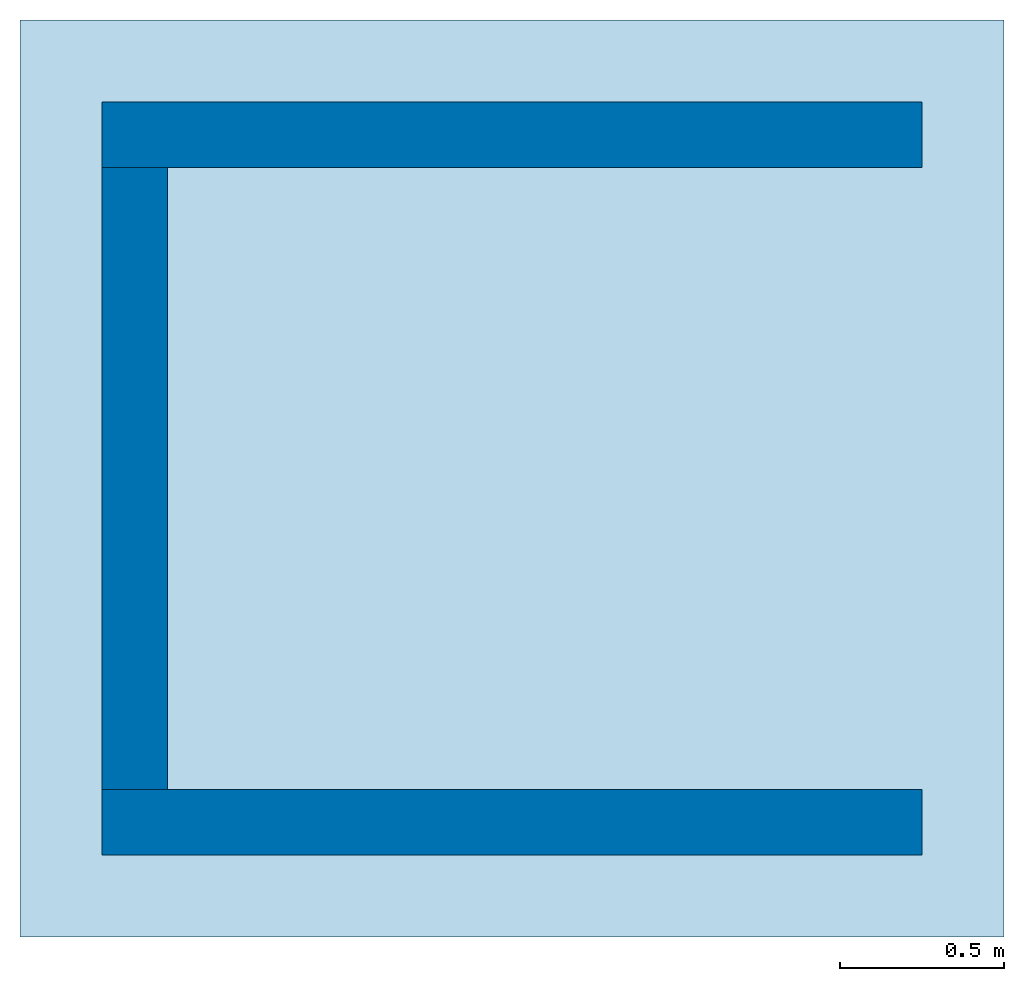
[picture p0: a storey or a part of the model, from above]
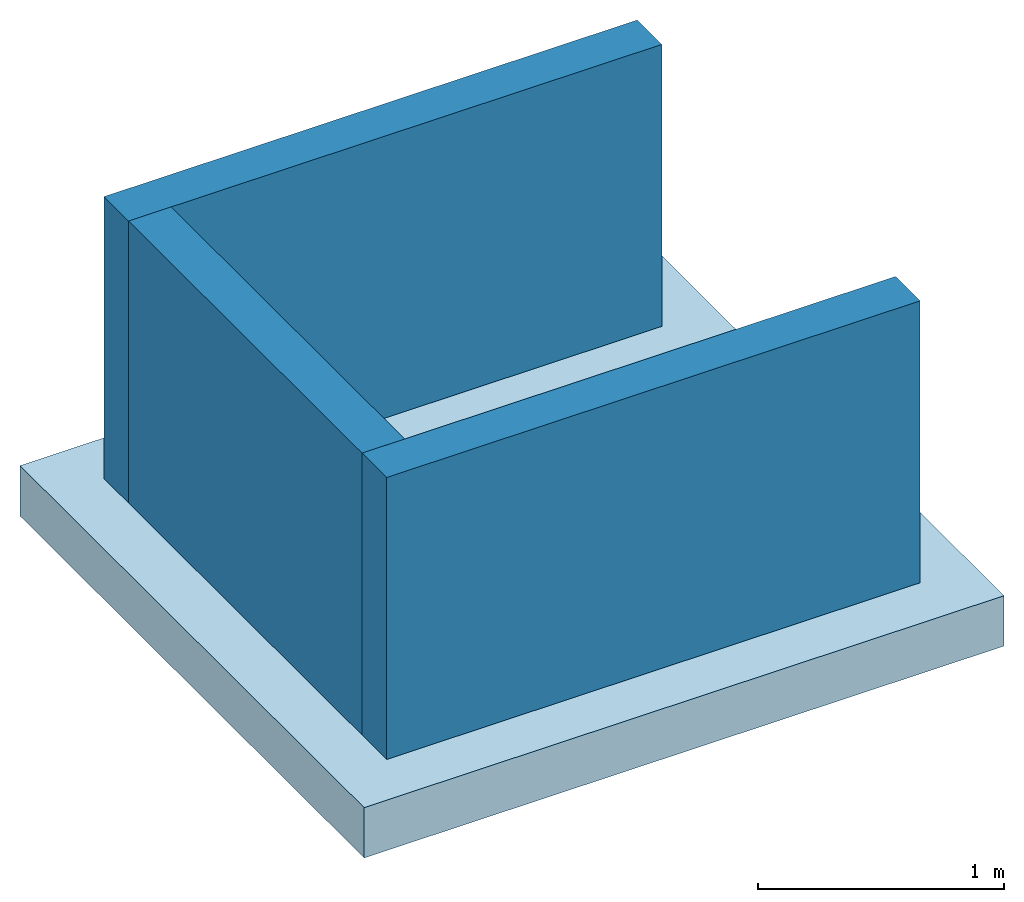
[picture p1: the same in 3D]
Properties of the parts of a building model (IFC4X3_ADD2), part 1 of 28

# File
Description: ViewDefinition [CoordinationView_V2.0], ExchangeRequirement [Architecture], Option [IfcExportBaseQuantities: Off], Option [IfcExportElementOnOffAndFrozenLayers: On], Option [IfcExplodeExternalReferences: Off], Option [IfcTesselateBSplineCurvesAndSurfaces: Off], Option [IfcExportSweptSolidAsBRep: Off], Option [IfcExportProfileCenterOfGravity: Off], Option [IfcExportMultiPlyElementsAsAggregated: Off], Option [IfcExportTesselation: 0.000000], Option [IfcCreateUniqueGuidForBlocks: On], Option [IfcCreateUniqueGuidForXrefs: On], Option [IfcExportSubtractOpenings: Off], Option [IfcExportAllVisibilityStates: Off]
File name: C:\\Users\\info\\Documents\\00 Elearning geodata BIMform\\1.2 Coördinatensystemen en projecties\\1.2.2 Georeferentie in IFC modellen\\AB_AR_BIM_Architectuur_georeferenced-IFC4X3_subset.ifc
Time: 2026-02-23T21:04:36
Author: Undefined
Organization: Undefined
Written by: BricsCAD BIM 26.1.08
Made in: BricsCAD BIM 26.1.08
Authorization: Undefined

# IfcSite, Site
RefLatitude: 42, 24, 53, 508910; RefLongitude: -71, -15, -29, -58837; RefElevation: 0 mm

# IfcBuilding, IFC Building Story
ElevationOfRefHeight: 0 mm; ElevationOfTerrain: 0 mm

# IfcBuildingStorey (10)
In: IFC Building Story
Name | LongName | Elevation (mm)
TAW50 | TAW50 | -10260
K20 | K20 | -5940
K10 | K10 | -3240
000 | 000 | 0
010 | 010 | 3600
020 | 020 | 7200
030 | 030 | 10800
040 | 040 | 14400
050 | 050 | 17050
060 | 060 | 21600

# IfcAirTerminal: BB_07.14.11#01_Buitenrooster_GMO:1000 x 2200 mm, BB_07.14.11#01_Buitenrooster_GMO:1000 x 2200 mm:28366141
In: K10
PredefinedType: GRILLE
Cpset_AirTerminal - LevelOfAccuracy: in te vullen door Buildwise
IfcBuildingStorey - Level: K10; Elevation from Level: 50
IfcClassificationReference - Keynote: 07.14.11#01; GVH_artnr 01: 07.14.11#01; GVH_artnr 02: geen waarde gevonden; GVH_artnr 03: geen waarde gevonden; GVH_artnr 04: geen waarde gevonden; GVH_artnr 05: geen waarde gevonden; GVH_artnr 06: geen waarde gevonden; TDS_link: .\05 As Builtdossier\2. Bouwkunde\2.1 Architectuur\2.1.7 Gevelsluiting\2.1.7.3 Gevelbekleding (MSB)\2.1.7.3.2 technische fiche's\TF A 07.14.11 01 gevelrooster 50 (B).pdf
IfcElement - Tag: R K.-1.P2 / 01; BB_Element_Lokaalnummer01: K.-1.P2 / 01; BB_Element_Code01: R K.-1.P2 / 01
IfcRoot - Name: 1000 x 2200 mm
Pset_AirTerminalTypeCommon - Reference: 1000 x 2200 mm; sets with these values: 2
Pset_Condition - AssessmentDate: Empty; AssessmentCondition: Empty

# IfcAirTerminal: BB_07.14.11#01_Buitenrooster_GMO:1030 x 840 mm, BB_07.14.11#01_Buitenrooster_GMO:1030 x 840 mm:25776233
In: 040
PredefinedType: GRILLE
Cpset_AirTerminal - LevelOfAccuracy: in te vullen door Buildwise
IfcBuildingStorey - Level: 040; Elevation from Level: 1560
IfcClassificationReference - Keynote: 07.14.11#01; GVH_artnr 01: 07.14.11#01; GVH_artnr 02: geen waarde gevonden; GVH_artnr 03: geen waarde gevonden; GVH_artnr 04: geen waarde gevonden; GVH_artnr 05: geen waarde gevonden; GVH_artnr 06: geen waarde gevonden; TDS_link: .\05 As Builtdossier\2. Bouwkunde\2.1 Architectuur\2.1.7 Gevelsluiting\2.1.7.3 Gevelbekleding (MSB)\2.1.7.3.2 technische fiche's\TF A 07.14.11 01 gevelrooster 50 (B).pdf
IfcElement - Tag: R K.40.G11 / 02; BB_Element_Lokaalnummer01: K.40.G11; BB_Element_Code01: R K.40.G11 / 02
IfcRoot - Name: 1030 x 840 mm
Pset_AirTerminalTypeCommon - Reference: 1030 x 840 mm; sets with these values: 2
Pset_Condition - AssessmentDate: Empty; AssessmentCondition: Empty

# IfcAirTerminal: BB_07.14.11#01_Buitenrooster_GMO:1200 x 600 mm, BB_07.14.11#01_Buitenrooster_GMO:1200 x 600 mm:25777901
In: K10
PredefinedType: GRILLE
Cpset_AirTerminal - LevelOfAccuracy: in te vullen door Buildwise
IfcBuildingStorey - Level: K10; Elevation from Level: 1650
IfcClassificationReference - Keynote: 07.14.11#01; GVH_artnr 01: 07.14.11#01; GVH_artnr 02: geen waarde gevonden; GVH_artnr 03: geen waarde gevonden; GVH_artnr 04: geen waarde gevonden; GVH_artnr 05: geen waarde gevonden; GVH_artnr 06: geen waarde gevonden; TDS_link: .\05 As Builtdossier\2. Bouwkunde\2.1 Architectuur\2.1.7 Gevelsluiting\2.1.7.3 Gevelbekleding (MSB)\2.1.7.3.2 technische fiche's\TF A 07.14.11 01 gevelrooster 50 (B).pdf
IfcElement - Tag: R K.-1.310 / 01; BB_Element_Lokaalnummer01: K.-1.310; BB_Element_Code01: R K.-1.310 / 01
IfcRoot - Name: 1200 x 600 mm
Pset_AirTerminalTypeCommon - Reference: 1200 x 600 mm; sets with these values: 2
Pset_Condition - AssessmentDate: Empty; AssessmentCondition: Empty

# IfcAirTerminal: BB_07.14.11#01_Buitenrooster_GMO:1930 x 1000 mm, BB_07.14.11#01_Buitenrooster_GMO:1930 x 1000 mm:25762259
In: 040
PredefinedType: GRILLE
Cpset_AirTerminal - LevelOfAccuracy: in te vullen door Buildwise
IfcBuildingStorey - Level: 040; Elevation from Level: 360
IfcClassificationReference - Keynote: 07.14.11#01; GVH_artnr 01: 07.14.11#01; GVH_artnr 02: geen waarde gevonden; GVH_artnr 03: geen waarde gevonden; GVH_artnr 04: geen waarde gevonden; GVH_artnr 05: geen waarde gevonden; GVH_artnr 06: geen waarde gevonden; TDS_link: .\05 As Builtdossier\2. Bouwkunde\2.1 Architectuur\2.1.7 Gevelsluiting\2.1.7.3 Gevelbekleding (MSB)\2.1.7.3.2 technische fiche's\TF A 07.14.11 01 gevelrooster 50 (B).pdf
IfcElement - Tag: R K.40.G11 / 01; BB_Element_Lokaalnummer01: K.40.G11; BB_Element_Code01: R K.40.G11 / 01
IfcRoot - Name: 1930 x 1000 mm
Pset_AirTerminalTypeCommon - Reference: 1930 x 1000 mm; sets with these values: 2
Pset_Condition - AssessmentDate: Empty; AssessmentCondition: Empty

# IfcAirTerminal: BB_07.14.11#01_Buitenrooster_GMO:2000 x 800 mm, BB_07.14.11#01_Buitenrooster_GMO:2000 x 800 mm:25777132
In: K20
PredefinedType: GRILLE
Cpset_AirTerminal - LevelOfAccuracy: in te vullen door Buildwise
IfcBuildingStorey - Level: K20; Elevation from Level: 1400
IfcClassificationReference - Keynote: 07.14.11#01; GVH_artnr 01: 07.14.11#01; GVH_artnr 02: geen waarde gevonden; GVH_artnr 03: geen waarde gevonden; GVH_artnr 04: geen waarde gevonden; GVH_artnr 05: geen waarde gevonden; GVH_artnr 06: geen waarde gevonden; TDS_link: .\05 As Builtdossier\2. Bouwkunde\2.1 Architectuur\2.1.7 Gevelsluiting\2.1.7.3 Gevelbekleding (MSB)\2.1.7.3.2 technische fiche's\TF A 07.14.11 01 gevelrooster 50 (B).pdf
IfcElement - Tag: R K.-2.305 / 01; BB_Element_Lokaalnummer01: K.-2.305; BB_Element_Code01: R K.-2.305 / 01
IfcRoot - Name: 2000 x 800 mm
Pset_AirTerminalTypeCommon - Reference: 2000 x 800 mm; sets with these values: 2
Pset_Condition - AssessmentDate: Empty; AssessmentCondition: Empty

# IfcAirTerminal: BB_07.14.11#01_Buitenrooster_GMO:2400 x 1800 mm, BB_07.14.11#01_Buitenrooster_GMO:2400 x 1800 mm:25777399
In: K20
PredefinedType: GRILLE
Cpset_AirTerminal - LevelOfAccuracy: in te vullen door Buildwise
IfcBuildingStorey - Level: K20; Elevation from Level: 300
IfcClassificationReference - Keynote: 07.14.11#02; GVH_artnr 01: 07.14.11#02; GVH_artnr 02: geen waarde gevonden; GVH_artnr 03: geen waarde gevonden; GVH_artnr 04: geen waarde gevonden; GVH_artnr 05: geen waarde gevonden; GVH_artnr 06: geen waarde gevonden; TDS_link: .\05 As Builtdossier\2. Bouwkunde\2.1 Architectuur\2.1.7 Gevelsluiting\2.1.7.3 Gevelbekleding (MSB)\2.1.7.3.2 technische fiche's\TF A 07.14.11 01 gevelrooster 50 (B).pdf
IfcElement - Tag: R K.-2.P2 / 01; BB_Element_Lokaalnummer01: K.-2.P2; BB_Element_Code01: R K.-2.P2 / 01
IfcRoot - Name: 2400 x 1800 mm
Pset_AirTerminalTypeCommon - Reference: 2400 x 1800 mm; sets with these values: 2
Pset_Condition - AssessmentDate: Empty; AssessmentCondition: Empty

# IfcAirTerminal: BB_07.14.11#01_Buitenrooster_GMO:2470 x 1800 mm, BB_07.14.11#01_Buitenrooster_GMO:2470 x 1800 mm:25478532
In: 040
PredefinedType: GRILLE
Cpset_AirTerminal - LevelOfAccuracy: in te vullen door Buildwise
IfcBuildingStorey - Level: 040; Elevation from Level: 360
IfcClassificationReference - Keynote: 07.14.11#01; GVH_artnr 01: 07.14.11#01; GVH_artnr 02: geen waarde gevonden; GVH_artnr 03: geen waarde gevonden; GVH_artnr 04: geen waarde gevonden; GVH_artnr 05: geen waarde gevonden; GVH_artnr 06: geen waarde gevonden; TDS_link: .\05 As Builtdossier\2. Bouwkunde\2.1 Architectuur\2.1.7 Gevelsluiting\2.1.7.3 Gevelbekleding (MSB)\2.1.7.3.2 technische fiche's\TF A 07.14.11 01 gevelrooster 50 (B).pdf
IfcElement - Tag: R K.40.K16 / 01; BB_Element_Lokaalnummer01: K.40.K16; BB_Element_Code01: R K.40.K16 / 01
IfcRoot - Name: 2470 x 1800 mm
Pset_AirTerminalTypeCommon - Reference: 2470 x 1800 mm; sets with these values: 2
Pset_Condition - AssessmentDate: Empty; AssessmentCondition: Empty

# IfcAirTerminal: BB_07.14.11#01_Buitenrooster_GMO:490 x 450 mm, BB_07.14.11#01_Buitenrooster_GMO:490 x 450 mm:25776728
In: 040
PredefinedType: GRILLE
Cpset_AirTerminal - LevelOfAccuracy: in te vullen door Buildwise
IfcBuildingStorey - Level: 040; Elevation from Level: 1950
IfcClassificationReference - Keynote: 07.14.11#01; GVH_artnr 01: 07.14.11#01; GVH_artnr 02: geen waarde gevonden; GVH_artnr 03: geen waarde gevonden; GVH_artnr 04: geen waarde gevonden; GVH_artnr 05: geen waarde gevonden; GVH_artnr 06: geen waarde gevonden; TDS_link: .\05 As Builtdossier\2. Bouwkunde\2.1 Architectuur\2.1.7 Gevelsluiting\2.1.7.3 Gevelbekleding (MSB)\2.1.7.3.2 technische fiche's\TF A 07.14.11 01 gevelrooster 50 (B).pdf
IfcElement - Tag: R K.40.K12 / 01; BB_Element_Lokaalnummer01: K.40.K12; BB_Element_Code01: R K.40.K12 / 01
IfcRoot - Name: 490 x 450 mm
Pset_AirTerminalTypeCommon - Reference: 490 x 450 mm; sets with these values: 2
Pset_Condition - AssessmentDate: Empty; AssessmentCondition: Empty

# IfcAirTerminal: BB_07.14.11#01_Buitenrooster_GMO:670 x 250 mm, BB_07.14.11#01_Buitenrooster_GMO:670 x 250 mm:25778106
In: K10
PredefinedType: GRILLE
Cpset_AirTerminal - LevelOfAccuracy: in te vullen door Buildwise
IfcBuildingStorey - Level: K10; Elevation from Level: 2070
IfcClassificationReference - Keynote: 07.14.11#01; GVH_artnr 01: 07.14.11#01; GVH_artnr 02: geen waarde gevonden; GVH_artnr 03: geen waarde gevonden; GVH_artnr 04: geen waarde gevonden; GVH_artnr 05: geen waarde gevonden; GVH_artnr 06: geen waarde gevonden; TDS_link: .\05 As Builtdossier\2. Bouwkunde\2.1 Architectuur\2.1.7 Gevelsluiting\2.1.7.3 Gevelbekleding (MSB)\2.1.7.3.2 technische fiche's\TF A 07.14.11 01 gevelrooster 50 (B).pdf
IfcElement - Tag: R K.-1.306 / 01; BB_Element_Lokaalnummer01: K.-1.306; BB_Element_Code01: R K.-1.306 / 01
IfcRoot - Name: 670 x 250 mm
Pset_AirTerminalTypeCommon - Reference: 670 x 250 mm; sets with these values: 2
Pset_Condition - AssessmentDate: Empty; AssessmentCondition: Empty

# IfcBeam: 28_SF_hout_rechthoekig_40 x 120, 28_SF_hout_rechthoekig:40 x 120:33609457
In: 010
PredefinedType: BEAM; Material: GVH_i2_naaldhout_generiek
Cpset_Beam - LevelOfAccuracy: in te vullen door Buildwise
IfcClassificationReference - TDS_link: .\05 As Builtdossier\2. Bouwkunde\2.2. Stabiliteit\2.2.0 technische fiche's\TF S 4.9.1.1.1 A - houten roostering sheddak.pdf
IfcElement - Tag: G4; Mark: G4
IfcRoot - Name: 40 x 120
Qto_BeamBaseQuantities - Length: 680; CrossSectionArea: 0.0048; OuterSurfaceArea: 0.308721; GrossSurfaceArea: 0.318321; NetSurfaceArea: 0.318321; GrossVolume: 0.00463081; NetVolume: 0.00463081
Pset_BeamCommon - Reference: 40 x 120; Span: 680 mm; Slope: 0.607081 rad; Roll: 0 rad; IsExternal: no; LoadBearing: yes
Pset_ConcreteElementGeneral - ConstructionMethod: prefabricated
Pset_Condition - AssessmentCondition: Empty
Pset_EnvironmentalImpactIndicators - Reference: 40 x 120; sets with these values: 2

# IfcBeam: 28_SF_hout_rechthoekig_40 x 120_1, 28_SF_hout_rechthoekig:40 x 120:33612034
In: 010
PredefinedType: BEAM; Material: GVH_i2_naaldhout_generiek
Cpset_Beam - LevelOfAccuracy: in te vullen door Buildwise
IfcClassificationReference - TDS_link: .\05 As Builtdossier\2. Bouwkunde\2.2. Stabiliteit\2.2.0 technische fiche's\TF S 4.9.1.1.1 A - houten roostering sheddak.pdf
IfcElement - Tag: G4; Mark: G4
IfcRoot - Name: 40 x 120
Qto_BeamBaseQuantities - Length: 680; CrossSectionArea: 0.0048; OuterSurfaceArea: 0.301717; GrossSurfaceArea: 0.311317; NetSurfaceArea: 0.311317; GrossVolume: 0.00452576; NetVolume: 0.00452576
Pset_BeamCommon - Reference: 40 x 120; Span: 680 mm; Slope: 0.607081 rad; Roll: 0 rad; IsExternal: no; LoadBearing: yes
Pset_ConcreteElementGeneral - ConstructionMethod: prefabricated
Pset_Condition - AssessmentCondition: Empty
Pset_EnvironmentalImpactIndicators - Reference: 40 x 120; sets with these values: 2

# IfcBeam: 28_SF_hout_rechthoekig_40 x 120_3, 28_SF_hout_rechthoekig:40 x 120:33641268
In: 010
PredefinedType: BEAM; Material: GVH_i2_naaldhout_generiek
Cpset_Beam - LevelOfAccuracy: in te vullen door Buildwise
IfcClassificationReference - TDS_link: .\05 As Builtdossier\2. Bouwkunde\2.2. Stabiliteit\2.2.0 technische fiche's\TF S 4.9.1.1.1 A - houten roostering sheddak.pdf
IfcElement - Tag: G8; Mark: G8
IfcRoot - Name: 40 x 120
Qto_BeamBaseQuantities - Length: 674.972; CrossSectionArea: 0.0048; OuterSurfaceArea: 0.273942; GrossSurfaceArea: 0.283542; NetSurfaceArea: 0.283542; GrossVolume: 0.00410913; NetVolume: 0.00410913
Pset_BeamCommon - Reference: 40 x 120; Span: 674.972 mm; Slope: 0.607119 rad; Roll: 0 rad; IsExternal: no; LoadBearing: yes
Pset_ConcreteElementGeneral - ConstructionMethod: prefabricated
Pset_Condition - AssessmentCondition: Empty
Pset_EnvironmentalImpactIndicators - Reference: 40 x 120; sets with these values: 2

# IfcBeam: 28_SF_hout_rechthoekig_40 x 120_5, 28_SF_hout_rechthoekig:40 x 120:33641404
In: 010
PredefinedType: BEAM; Material: GVH_i2_naaldhout_generiek
Cpset_Beam - LevelOfAccuracy: in te vullen door Buildwise
IfcClassificationReference - TDS_link: .\05 As Builtdossier\2. Bouwkunde\2.2. Stabiliteit\2.2.0 technische fiche's\TF S 4.9.1.1.1 A - houten roostering sheddak.pdf
IfcElement - Tag: G8; Mark: G8
IfcRoot - Name: 40 x 120
Qto_BeamBaseQuantities - Length: 680; CrossSectionArea: 0.0048; OuterSurfaceArea: 0.271354; GrossSurfaceArea: 0.280954; NetSurfaceArea: 0.280954; GrossVolume: 0.00407031; NetVolume: 0.00407031
Pset_BeamCommon - Reference: 40 x 120; Span: 680 mm; Slope: 0.607119 rad; Roll: 0 rad; IsExternal: no; LoadBearing: yes
Pset_ConcreteElementGeneral - ConstructionMethod: prefabricated
Pset_Condition - AssessmentCondition: Empty
Pset_EnvironmentalImpactIndicators - Reference: 40 x 120; sets with these values: 2

# IfcBeam: 28_SF_hout_rechthoekig_40 x 120_7, 28_SF_hout_rechthoekig:40 x 120:33649928
In: 010
PredefinedType: BEAM; Material: GVH_i2_naaldhout_generiek
Cpset_Beam - LevelOfAccuracy: in te vullen door Buildwise
IfcClassificationReference - TDS_link: .\05 As Builtdossier\2. Bouwkunde\2.2. Stabiliteit\2.2.0 technische fiche's\TF S 4.9.1.1.1 A - houten roostering sheddak.pdf
IfcElement - Tag: G7; Mark: G7
IfcRoot - Name: 40 x 120
Qto_BeamBaseQuantities - Length: 720; CrossSectionArea: 0.0048; OuterSurfaceArea: 0.260097; GrossSurfaceArea: 0.269697; NetSurfaceArea: 0.269697; GrossVolume: 0.00390145; NetVolume: 0.00390145
Pset_BeamCommon - Reference: 40 x 120; Span: 720 mm; Slope: 0.456876 rad; Roll: 0 rad; IsExternal: no; LoadBearing: yes
Pset_ConcreteElementGeneral - ConstructionMethod: prefabricated
Pset_Condition - AssessmentCondition: Empty
Pset_EnvironmentalImpactIndicators - Reference: 40 x 120; sets with these values: 2

# IfcBeam: 28_SF_hout_rechthoekig_40 x 120_9, 28_SF_hout_rechthoekig:40 x 120:33650153
In: 010
PredefinedType: BEAM; Material: GVH_i2_naaldhout_generiek
Cpset_Beam - LevelOfAccuracy: in te vullen door Buildwise
IfcClassificationReference - TDS_link: .\05 As Builtdossier\2. Bouwkunde\2.2. Stabiliteit\2.2.0 technische fiche's\TF S 4.9.1.1.1 A - houten roostering sheddak.pdf
IfcElement - Tag: G7; Mark: G7
IfcRoot - Name: 40 x 120
Qto_BeamBaseQuantities - Length: 720; CrossSectionArea: 0.0048; OuterSurfaceArea: 0.259196; GrossSurfaceArea: 0.268796; NetSurfaceArea: 0.268796; GrossVolume: 0.00388795; NetVolume: 0.00388795
Pset_BeamCommon - Reference: 40 x 120; Span: 720 mm; Slope: 0.456876 rad; Roll: 0 rad; IsExternal: no; LoadBearing: yes
Pset_ConcreteElementGeneral - ConstructionMethod: prefabricated
Pset_Condition - AssessmentCondition: Empty
Pset_EnvironmentalImpactIndicators - Reference: 40 x 120; sets with these values: 2

# IfcBeam: 28_SF_hout_rechthoekig_40 x 150, 28_SF_hout_rechthoekig:40 x 150:33608699
In: 010
PredefinedType: BEAM; Material: GVH_i2_naaldhout_generiek
Cpset_Beam - LevelOfAccuracy: in te vullen door Buildwise
IfcClassificationReference - TDS_link: .\05 As Builtdossier\2. Bouwkunde\2.2. Stabiliteit\2.2.0 technische fiche's\TF S 4.9.1.1.1 A - houten roostering sheddak.pdf
IfcElement - Tag: G1; Mark: G1
IfcRoot - Name: 40 x 150
Qto_BeamBaseQuantities - Length: 3480; CrossSectionArea: 0.006; OuterSurfaceArea: 0.47082; GrossSurfaceArea: 0.48282; NetSurfaceArea: 0.48282; GrossVolume: 0.007434; NetVolume: 0.007434
Pset_BeamCommon - Reference: 40 x 150; Span: 3480 mm; Slope: 0.459349 rad; Roll: 0 rad; IsExternal: no; LoadBearing: yes
Pset_ConcreteElementGeneral - ConstructionMethod: prefabricated
Pset_Condition - AssessmentCondition: Empty
Pset_EnvironmentalImpactIndicators - Reference: 40 x 150; sets with these values: 2

# IfcBeam: 28_SF_hout_rechthoekig_40 x 150_1, 28_SF_hout_rechthoekig:40 x 150:33611057
In: 010
PredefinedType: BEAM; Material: GVH_i2_naaldhout_generiek
Cpset_Beam - LevelOfAccuracy: in te vullen door Buildwise
IfcClassificationReference - TDS_link: .\05 As Builtdossier\2. Bouwkunde\2.2. Stabiliteit\2.2.0 technische fiche's\TF S 4.9.1.1.1 A - houten roostering sheddak.pdf
IfcElement - Tag: G5; Mark: G5
IfcRoot - Name: 40 x 150
Qto_BeamBaseQuantities - Length: 3480; CrossSectionArea: 0.006; OuterSurfaceArea: 0.434937; GrossSurfaceArea: 0.446937; NetSurfaceArea: 0.446937; GrossVolume: 0.00686743; NetVolume: 0.00686743
Pset_BeamCommon - Reference: 40 x 150; Span: 3480 mm; Slope: 0.459349 rad; Roll: 0 rad; IsExternal: no; LoadBearing: yes
Pset_ConcreteElementGeneral - ConstructionMethod: prefabricated
Pset_Condition - AssessmentCondition: Empty
Pset_EnvironmentalImpactIndicators - Reference: 40 x 150; sets with these values: 2

# IfcBeam: 28_SF_hout_rechthoekig_40 x 150_3, 28_SF_hout_rechthoekig:40 x 150:33611471
In: 010
PredefinedType: BEAM; Material: GVH_i2_naaldhout_generiek
Cpset_Beam - LevelOfAccuracy: in te vullen door Buildwise
IfcClassificationReference - TDS_link: .\05 As Builtdossier\2. Bouwkunde\2.2. Stabiliteit\2.2.0 technische fiche's\TF S 4.9.1.1.1 A - houten roostering sheddak.pdf
IfcElement - Tag: G1; Mark: G1
IfcRoot - Name: 40 x 150
Qto_BeamBaseQuantities - Length: 3480; CrossSectionArea: 0.006; OuterSurfaceArea: 0.442043; GrossSurfaceArea: 0.454043; NetSurfaceArea: 0.454043; GrossVolume: 0.00697963; NetVolume: 0.00697963
Pset_BeamCommon - Reference: 40 x 150; Span: 3480 mm; Slope: 0.459349 rad; Roll: 0 rad; IsExternal: no; LoadBearing: yes
Pset_ConcreteElementGeneral - ConstructionMethod: prefabricated
Pset_Condition - AssessmentCondition: Empty
Pset_EnvironmentalImpactIndicators - Reference: 40 x 150; sets with these values: 2

# IfcBeam: 28_SF_hout_rechthoekig_40 x 150_5, 28_SF_hout_rechthoekig:40 x 150:33611473
In: 010
PredefinedType: BEAM; Material: GVH_i2_naaldhout_generiek
Cpset_Beam - LevelOfAccuracy: in te vullen door Buildwise
IfcClassificationReference - TDS_link: .\05 As Builtdossier\2. Bouwkunde\2.2. Stabiliteit\2.2.0 technische fiche's\TF S 4.9.1.1.1 A - houten roostering sheddak.pdf
IfcElement - Tag: G2; Mark: G2
IfcRoot - Name: 40 x 150
Qto_BeamBaseQuantities - Length: 3480; CrossSectionArea: 0.006; OuterSurfaceArea: 0.398603; GrossSurfaceArea: 0.410603; NetSurfaceArea: 0.410603; GrossVolume: 0.00629374; NetVolume: 0.00629374
Pset_BeamCommon - Reference: 40 x 150; Span: 3480 mm; Slope: 0.459349 rad; Roll: 0 rad; IsExternal: no; LoadBearing: yes
Pset_ConcreteElementGeneral - ConstructionMethod: prefabricated
Pset_Condition - AssessmentCondition: Empty
Pset_EnvironmentalImpactIndicators - Reference: 40 x 150; sets with these values: 2

# IfcBeam: 28_SF_hout_rechthoekig_40 x 150_7, 28_SF_hout_rechthoekig:40 x 150:33611784
In: 010
PredefinedType: BEAM; Material: GVH_i2_naaldhout_generiek
Cpset_Beam - LevelOfAccuracy: in te vullen door Buildwise
IfcClassificationReference - TDS_link: .\05 As Builtdossier\2. Bouwkunde\2.2. Stabiliteit\2.2.0 technische fiche's\TF S 4.9.1.1.1 A - houten roostering sheddak.pdf
IfcElement - Tag: G6; Mark: G6
IfcRoot - Name: 40 x 150
Qto_BeamBaseQuantities - Length: 3340; CrossSectionArea: 0.006; OuterSurfaceArea: 0.465686; GrossSurfaceArea: 0.477686; NetSurfaceArea: 0.477686; GrossVolume: 0.00735294; NetVolume: 0.00735294
Pset_BeamCommon - Reference: 40 x 150; Span: 3340 mm; Slope: 0.496206 rad; Roll: 0 rad; IsExternal: no; LoadBearing: yes
Pset_ConcreteElementGeneral - ConstructionMethod: prefabricated
Pset_Condition - AssessmentCondition: Empty
Pset_EnvironmentalImpactIndicators - Reference: 40 x 150; sets with these values: 2

# IfcBeam: 28_SF_hout_rechthoekig_40 x 150_9, 28_SF_hout_rechthoekig:40 x 150:33612094
In: 010
PredefinedType: BEAM; Material: GVH_i2_naaldhout_generiek
Cpset_Beam - LevelOfAccuracy: in te vullen door Buildwise
IfcClassificationReference - TDS_link: .\05 As Builtdossier\2. Bouwkunde\2.2. Stabiliteit\2.2.0 technische fiche's\TF S 4.9.1.1.1 A - houten roostering sheddak.pdf
IfcElement - Tag: G3; Mark: G3
IfcRoot - Name: 40 x 150
Qto_BeamBaseQuantities - Length: 2128.69; CrossSectionArea: 0.006; OuterSurfaceArea: 0.460107; GrossSurfaceArea: 0.472107; NetSurfaceArea: 0.472107; GrossVolume: 0.00726485; NetVolume: 0.00726485
Pset_BeamCommon - Reference: 40 x 150; Span: 2128.69 mm; Slope: 0.497647 rad; Roll: 0 rad; IsExternal: no; LoadBearing: yes
Pset_ConcreteElementGeneral - ConstructionMethod: prefabricated
Pset_Condition - AssessmentCondition: Empty
Pset_EnvironmentalImpactIndicators - Reference: 40 x 150; sets with these values: 2

# IfcBeam: 28_SF_hout_rechthoekig_40 x 230, 28_SF_hout_rechthoekig:40 x 230:33579203
In: 010
PredefinedType: BEAM; Material: GVH_i2_naaldhout_generiek
Cpset_Beam - LevelOfAccuracy: in te vullen door Buildwise
IfcClassificationReference - TDS_link: .\05 As Builtdossier\2. Bouwkunde\2.2. Stabiliteit\2.2.0 technische fiche's\TF S 4.9.1.1.1 A - houten roostering sheddak.pdf
IfcElement - Tag: B1; Mark: B1
IfcRoot - Name: 40 x 230
Qto_BeamBaseQuantities - Length: 3240; CrossSectionArea: 0.0092; OuterSurfaceArea: 1.79133; GrossSurfaceArea: 1.80973; NetSurfaceArea: 1.80973; GrossVolume: 0.030519; NetVolume: 0.030519
Pset_BeamCommon - Reference: 40 x 230; Span: 3240 mm; Slope: 0 rad; Roll: 0 rad; IsExternal: no; LoadBearing: yes
Pset_ConcreteElementGeneral - ConstructionMethod: prefabricated
Pset_Condition - AssessmentCondition: Empty
Pset_EnvironmentalImpactIndicators - Reference: 40 x 230; sets with these values: 2

# IfcBeam: 28_SF_hout_rechthoekig_40 x 230_1, 28_SF_hout_rechthoekig:40 x 230:33579206
In: 010
PredefinedType: BEAM; Material: GVH_i2_naaldhout_generiek
Cpset_Beam - LevelOfAccuracy: in te vullen door Buildwise
IfcClassificationReference - TDS_link: .\05 As Builtdossier\2. Bouwkunde\2.2. Stabiliteit\2.2.0 technische fiche's\TF S 4.9.1.1.1 A - houten roostering sheddak.pdf
IfcElement - Tag: B1; Mark: B1
IfcRoot - Name: 40 x 230
Qto_BeamBaseQuantities - Length: 3440; CrossSectionArea: 0.0092; OuterSurfaceArea: 1.79133; GrossSurfaceArea: 1.80973; NetSurfaceArea: 1.80973; GrossVolume: 0.030519; NetVolume: 0.030519
Pset_BeamCommon - Reference: 40 x 230; Span: 3440 mm; Slope: 0 rad; Roll: 0 rad; IsExternal: no; LoadBearing: yes
Pset_ConcreteElementGeneral - ConstructionMethod: prefabricated
Pset_Condition - AssessmentCondition: Empty
Pset_EnvironmentalImpactIndicators - Reference: 40 x 230; sets with these values: 2

# IfcBeam: 28_SF_hout_rechthoekig_40 x 230_101, 28_SF_hout_rechthoekig:40 x 230:33579978
In: 010
PredefinedType: BEAM; Material: GVH_i2_naaldhout_generiek
Cpset_Beam - LevelOfAccuracy: in te vullen door Buildwise
IfcClassificationReference - TDS_link: .\05 As Builtdossier\2. Bouwkunde\2.2. Stabiliteit\2.2.0 technische fiche's\TF S 4.9.1.1.1 A - houten roostering sheddak.pdf
IfcElement - Tag: B1; Mark: B1
IfcRoot - Name: 40 x 230
Qto_BeamBaseQuantities - Length: 3340; CrossSectionArea: 0.0092; OuterSurfaceArea: 1.79133; GrossSurfaceArea: 1.80973; NetSurfaceArea: 1.80973; GrossVolume: 0.030519; NetVolume: 0.030519
Pset_BeamCommon - Reference: 40 x 230; Span: 3340 mm; Slope: 0 rad; Roll: 0 rad; IsExternal: no; LoadBearing: yes
Pset_ConcreteElementGeneral - ConstructionMethod: prefabricated
Pset_Condition - AssessmentCondition: Empty
Pset_EnvironmentalImpactIndicators - Reference: 40 x 230; sets with these values: 2

# IfcBeam: 28_SF_hout_rechthoekig_40 x 230_103, 28_SF_hout_rechthoekig:40 x 230:33579980
In: 010
PredefinedType: BEAM; Material: GVH_i2_naaldhout_generiek
Cpset_Beam - LevelOfAccuracy: in te vullen door Buildwise
IfcClassificationReference - TDS_link: .\05 As Builtdossier\2. Bouwkunde\2.2. Stabiliteit\2.2.0 technische fiche's\TF S 4.9.1.1.1 A - houten roostering sheddak.pdf
IfcElement - Tag: B1; Mark: B1
IfcRoot - Name: 40 x 230
Qto_BeamBaseQuantities - Length: 3340; CrossSectionArea: 0.0092; OuterSurfaceArea: 1.79133; GrossSurfaceArea: 1.80973; NetSurfaceArea: 1.80973; GrossVolume: 0.030519; NetVolume: 0.030519
Pset_BeamCommon - Reference: 40 x 230; Span: 3340 mm; Slope: 0 rad; Roll: 0 rad; IsExternal: no; LoadBearing: yes
Pset_ConcreteElementGeneral - ConstructionMethod: prefabricated
Pset_Condition - AssessmentCondition: Empty
Pset_EnvironmentalImpactIndicators - Reference: 40 x 230; sets with these values: 2

# IfcBeam: 28_SF_hout_rechthoekig_40 x 230_105, 28_SF_hout_rechthoekig:40 x 230:33579982
In: 010
PredefinedType: BEAM; Material: GVH_i2_naaldhout_generiek
Cpset_Beam - LevelOfAccuracy: in te vullen door Buildwise
IfcClassificationReference - TDS_link: .\05 As Builtdossier\2. Bouwkunde\2.2. Stabiliteit\2.2.0 technische fiche's\TF S 4.9.1.1.1 A - houten roostering sheddak.pdf
IfcElement - Tag: B1; Mark: B1
IfcRoot - Name: 40 x 230
Qto_BeamBaseQuantities - Length: 3340; CrossSectionArea: 0.0092; OuterSurfaceArea: 1.79133; GrossSurfaceArea: 1.80973; NetSurfaceArea: 1.80973; GrossVolume: 0.030519; NetVolume: 0.030519
Pset_BeamCommon - Reference: 40 x 230; Span: 3340 mm; Slope: 0 rad; Roll: 0 rad; IsExternal: no; LoadBearing: yes
Pset_ConcreteElementGeneral - ConstructionMethod: prefabricated
Pset_Condition - AssessmentCondition: Empty
Pset_EnvironmentalImpactIndicators - Reference: 40 x 230; sets with these values: 2

# IfcBeam: 28_SF_hout_rechthoekig_40 x 230_107, 28_SF_hout_rechthoekig:40 x 230:33579984
In: 010
PredefinedType: BEAM; Material: GVH_i2_naaldhout_generiek
Cpset_Beam - LevelOfAccuracy: in te vullen door Buildwise
IfcClassificationReference - TDS_link: .\05 As Builtdossier\2. Bouwkunde\2.2. Stabiliteit\2.2.0 technische fiche's\TF S 4.9.1.1.1 A - houten roostering sheddak.pdf
IfcElement - Tag: B1; Mark: B1
IfcRoot - Name: 40 x 230
Qto_BeamBaseQuantities - Length: 3340; CrossSectionArea: 0.0092; OuterSurfaceArea: 1.79133; GrossSurfaceArea: 1.80973; NetSurfaceArea: 1.80973; GrossVolume: 0.030519; NetVolume: 0.030519
Pset_BeamCommon - Reference: 40 x 230; Span: 3340 mm; Slope: 0 rad; Roll: 0 rad; IsExternal: no; LoadBearing: yes
Pset_ConcreteElementGeneral - ConstructionMethod: prefabricated
Pset_Condition - AssessmentCondition: Empty
Pset_EnvironmentalImpactIndicators - Reference: 40 x 230; sets with these values: 2

# IfcBeam: 28_SF_hout_rechthoekig_40 x 230_109, 28_SF_hout_rechthoekig:40 x 230:33579986
In: 010
PredefinedType: BEAM; Material: GVH_i2_naaldhout_generiek
Cpset_Beam - LevelOfAccuracy: in te vullen door Buildwise
IfcClassificationReference - TDS_link: .\05 As Builtdossier\2. Bouwkunde\2.2. Stabiliteit\2.2.0 technische fiche's\TF S 4.9.1.1.1 A - houten roostering sheddak.pdf
IfcElement - Tag: B1; Mark: B1
IfcRoot - Name: 40 x 230
Qto_BeamBaseQuantities - Length: 3340; CrossSectionArea: 0.0092; OuterSurfaceArea: 1.79133; GrossSurfaceArea: 1.80973; NetSurfaceArea: 1.80973; GrossVolume: 0.030519; NetVolume: 0.030519
Pset_BeamCommon - Reference: 40 x 230; Span: 3340 mm; Slope: 0 rad; Roll: 0 rad; IsExternal: no; LoadBearing: yes
Pset_ConcreteElementGeneral - ConstructionMethod: prefabricated
Pset_Condition - AssessmentCondition: Empty
Pset_EnvironmentalImpactIndicators - Reference: 40 x 230; sets with these values: 2

# IfcBeam: 28_SF_hout_rechthoekig_40 x 230_11, 28_SF_hout_rechthoekig:40 x 230:33579225
In: 010
PredefinedType: BEAM; Material: GVH_i2_naaldhout_generiek
Cpset_Beam - LevelOfAccuracy: in te vullen door Buildwise
IfcClassificationReference - TDS_link: .\05 As Builtdossier\2. Bouwkunde\2.2. Stabiliteit\2.2.0 technische fiche's\TF S 4.9.1.1.1 A - houten roostering sheddak.pdf
IfcElement - Tag: B1; Mark: B1
IfcRoot - Name: 40 x 230
Qto_BeamBaseQuantities - Length: 3440; CrossSectionArea: 0.0092; OuterSurfaceArea: 1.79133; GrossSurfaceArea: 1.80973; NetSurfaceArea: 1.80973; GrossVolume: 0.030519; NetVolume: 0.030519
Pset_BeamCommon - Reference: 40 x 230; Span: 3440 mm; Slope: 0 rad; Roll: 0 rad; IsExternal: no; LoadBearing: yes
Pset_ConcreteElementGeneral - ConstructionMethod: prefabricated
Pset_Condition - AssessmentCondition: Empty
Pset_EnvironmentalImpactIndicators - Reference: 40 x 230; sets with these values: 2

# IfcBeam: 28_SF_hout_rechthoekig_40 x 230_111, 28_SF_hout_rechthoekig:40 x 230:33579988
In: 010
PredefinedType: BEAM; Material: GVH_i2_naaldhout_generiek
Cpset_Beam - LevelOfAccuracy: in te vullen door Buildwise
IfcClassificationReference - TDS_link: .\05 As Builtdossier\2. Bouwkunde\2.2. Stabiliteit\2.2.0 technische fiche's\TF S 4.9.1.1.1 A - houten roostering sheddak.pdf
IfcElement - Tag: B1; Mark: B1
IfcRoot - Name: 40 x 230
Qto_BeamBaseQuantities - Length: 3340; CrossSectionArea: 0.0092; OuterSurfaceArea: 1.79133; GrossSurfaceArea: 1.80973; NetSurfaceArea: 1.80973; GrossVolume: 0.030519; NetVolume: 0.030519
Pset_BeamCommon - Reference: 40 x 230; Span: 3340 mm; Slope: 0 rad; Roll: 0 rad; IsExternal: no; LoadBearing: yes
Pset_ConcreteElementGeneral - ConstructionMethod: prefabricated
Pset_Condition - AssessmentCondition: Empty
Pset_EnvironmentalImpactIndicators - Reference: 40 x 230; sets with these values: 2

# IfcBeam: 28_SF_hout_rechthoekig_40 x 230_113, 28_SF_hout_rechthoekig:40 x 230:33579990
In: 010
PredefinedType: BEAM; Material: GVH_i2_naaldhout_generiek
Cpset_Beam - LevelOfAccuracy: in te vullen door Buildwise
IfcClassificationReference - TDS_link: .\05 As Builtdossier\2. Bouwkunde\2.2. Stabiliteit\2.2.0 technische fiche's\TF S 4.9.1.1.1 A - houten roostering sheddak.pdf
IfcElement - Tag: B1; Mark: B1
IfcRoot - Name: 40 x 230
Qto_BeamBaseQuantities - Length: 3340; CrossSectionArea: 0.0092; OuterSurfaceArea: 1.79133; GrossSurfaceArea: 1.80973; NetSurfaceArea: 1.80973; GrossVolume: 0.030519; NetVolume: 0.030519
Pset_BeamCommon - Reference: 40 x 230; Span: 3340 mm; Slope: 0 rad; Roll: 0 rad; IsExternal: no; LoadBearing: yes
Pset_ConcreteElementGeneral - ConstructionMethod: prefabricated
Pset_Condition - AssessmentCondition: Empty
Pset_EnvironmentalImpactIndicators - Reference: 40 x 230; sets with these values: 2

# IfcBeam: 28_SF_hout_rechthoekig_40 x 230_115, 28_SF_hout_rechthoekig:40 x 230:33579992
In: 010
PredefinedType: BEAM; Material: GVH_i2_naaldhout_generiek
Cpset_Beam - LevelOfAccuracy: in te vullen door Buildwise
IfcClassificationReference - TDS_link: .\05 As Builtdossier\2. Bouwkunde\2.2. Stabiliteit\2.2.0 technische fiche's\TF S 4.9.1.1.1 A - houten roostering sheddak.pdf
IfcElement - Tag: B1; Mark: B1
IfcRoot - Name: 40 x 230
Qto_BeamBaseQuantities - Length: 3340; CrossSectionArea: 0.0092; OuterSurfaceArea: 1.79133; GrossSurfaceArea: 1.80973; NetSurfaceArea: 1.80973; GrossVolume: 0.030519; NetVolume: 0.030519
Pset_BeamCommon - Reference: 40 x 230; Span: 3340 mm; Slope: 0 rad; Roll: 0 rad; IsExternal: no; LoadBearing: yes
Pset_ConcreteElementGeneral - ConstructionMethod: prefabricated
Pset_Condition - AssessmentCondition: Empty
Pset_EnvironmentalImpactIndicators - Reference: 40 x 230; sets with these values: 2

# IfcBeam: 28_SF_hout_rechthoekig_40 x 230_117, 28_SF_hout_rechthoekig:40 x 230:33579994
In: 010
PredefinedType: BEAM; Material: GVH_i2_naaldhout_generiek
Cpset_Beam - LevelOfAccuracy: in te vullen door Buildwise
IfcClassificationReference - TDS_link: .\05 As Builtdossier\2. Bouwkunde\2.2. Stabiliteit\2.2.0 technische fiche's\TF S 4.9.1.1.1 A - houten roostering sheddak.pdf
IfcElement - Tag: B1; Mark: B1
IfcRoot - Name: 40 x 230
Qto_BeamBaseQuantities - Length: 3340; CrossSectionArea: 0.0092; OuterSurfaceArea: 1.79133; GrossSurfaceArea: 1.80973; NetSurfaceArea: 1.80973; GrossVolume: 0.030519; NetVolume: 0.030519
Pset_BeamCommon - Reference: 40 x 230; Span: 3340 mm; Slope: 0 rad; Roll: 0 rad; IsExternal: no; LoadBearing: yes
Pset_ConcreteElementGeneral - ConstructionMethod: prefabricated
Pset_Condition - AssessmentCondition: Empty
Pset_EnvironmentalImpactIndicators - Reference: 40 x 230; sets with these values: 2

# IfcBeam: 28_SF_hout_rechthoekig_40 x 230_119, 28_SF_hout_rechthoekig:40 x 230:33579996
In: 010
PredefinedType: BEAM; Material: GVH_i2_naaldhout_generiek
Cpset_Beam - LevelOfAccuracy: in te vullen door Buildwise
IfcClassificationReference - TDS_link: .\05 As Builtdossier\2. Bouwkunde\2.2. Stabiliteit\2.2.0 technische fiche's\TF S 4.9.1.1.1 A - houten roostering sheddak.pdf
IfcElement - Tag: B1; Mark: B1
IfcRoot - Name: 40 x 230
Qto_BeamBaseQuantities - Length: 3340; CrossSectionArea: 0.0092; OuterSurfaceArea: 1.79133; GrossSurfaceArea: 1.80973; NetSurfaceArea: 1.80973; GrossVolume: 0.030519; NetVolume: 0.030519
Pset_BeamCommon - Reference: 40 x 230; Span: 3340 mm; Slope: 0 rad; Roll: 0 rad; IsExternal: no; LoadBearing: yes
Pset_ConcreteElementGeneral - ConstructionMethod: prefabricated
Pset_Condition - AssessmentCondition: Empty
Pset_EnvironmentalImpactIndicators - Reference: 40 x 230; sets with these values: 2

# IfcBeam: 28_SF_hout_rechthoekig_40 x 230_121, 28_SF_hout_rechthoekig:40 x 230:33579998
In: 010
PredefinedType: BEAM; Material: GVH_i2_naaldhout_generiek
Cpset_Beam - LevelOfAccuracy: in te vullen door Buildwise
IfcClassificationReference - TDS_link: .\05 As Builtdossier\2. Bouwkunde\2.2. Stabiliteit\2.2.0 technische fiche's\TF S 4.9.1.1.1 A - houten roostering sheddak.pdf
IfcElement - Tag: B1; Mark: B1
IfcRoot - Name: 40 x 230
Qto_BeamBaseQuantities - Length: 3340; CrossSectionArea: 0.0092; OuterSurfaceArea: 1.79133; GrossSurfaceArea: 1.80973; NetSurfaceArea: 1.80973; GrossVolume: 0.030519; NetVolume: 0.030519
Pset_BeamCommon - Reference: 40 x 230; Span: 3340 mm; Slope: 0 rad; Roll: 0 rad; IsExternal: no; LoadBearing: yes
Pset_ConcreteElementGeneral - ConstructionMethod: prefabricated
Pset_Condition - AssessmentCondition: Empty
Pset_EnvironmentalImpactIndicators - Reference: 40 x 230; sets with these values: 2

# IfcBeam: 28_SF_hout_rechthoekig_40 x 230_123, 28_SF_hout_rechthoekig:40 x 230:33580000
In: 010
PredefinedType: BEAM; Material: GVH_i2_naaldhout_generiek
Cpset_Beam - LevelOfAccuracy: in te vullen door Buildwise
IfcClassificationReference - TDS_link: .\05 As Builtdossier\2. Bouwkunde\2.2. Stabiliteit\2.2.0 technische fiche's\TF S 4.9.1.1.1 A - houten roostering sheddak.pdf
IfcElement - Tag: B1; Mark: B1
IfcRoot - Name: 40 x 230
Qto_BeamBaseQuantities - Length: 3340; CrossSectionArea: 0.0092; OuterSurfaceArea: 1.79133; GrossSurfaceArea: 1.80973; NetSurfaceArea: 1.80973; GrossVolume: 0.030519; NetVolume: 0.030519
Pset_BeamCommon - Reference: 40 x 230; Span: 3340 mm; Slope: 0 rad; Roll: 0 rad; IsExternal: no; LoadBearing: yes
Pset_ConcreteElementGeneral - ConstructionMethod: prefabricated
Pset_Condition - AssessmentCondition: Empty
Pset_EnvironmentalImpactIndicators - Reference: 40 x 230; sets with these values: 2

# IfcBeam: 28_SF_hout_rechthoekig_40 x 230_125, 28_SF_hout_rechthoekig:40 x 230:33580002
In: 010
PredefinedType: BEAM; Material: GVH_i2_naaldhout_generiek
Cpset_Beam - LevelOfAccuracy: in te vullen door Buildwise
IfcClassificationReference - TDS_link: .\05 As Builtdossier\2. Bouwkunde\2.2. Stabiliteit\2.2.0 technische fiche's\TF S 4.9.1.1.1 A - houten roostering sheddak.pdf
IfcElement - Tag: B1; Mark: B1
IfcRoot - Name: 40 x 230
Qto_BeamBaseQuantities - Length: 3340; CrossSectionArea: 0.0092; OuterSurfaceArea: 1.79133; GrossSurfaceArea: 1.80973; NetSurfaceArea: 1.80973; GrossVolume: 0.030519; NetVolume: 0.030519
Pset_BeamCommon - Reference: 40 x 230; Span: 3340 mm; Slope: 0 rad; Roll: 0 rad; IsExternal: no; LoadBearing: yes
Pset_ConcreteElementGeneral - ConstructionMethod: prefabricated
Pset_Condition - AssessmentCondition: Empty
Pset_EnvironmentalImpactIndicators - Reference: 40 x 230; sets with these values: 2

# IfcBeam: 28_SF_hout_rechthoekig_40 x 230_127, 28_SF_hout_rechthoekig:40 x 230:33580004
In: 010
PredefinedType: BEAM; Material: GVH_i2_naaldhout_generiek
Cpset_Beam - LevelOfAccuracy: in te vullen door Buildwise
IfcClassificationReference - TDS_link: .\05 As Builtdossier\2. Bouwkunde\2.2. Stabiliteit\2.2.0 technische fiche's\TF S 4.9.1.1.1 A - houten roostering sheddak.pdf
IfcElement - Tag: B1; Mark: B1
IfcRoot - Name: 40 x 230
Qto_BeamBaseQuantities - Length: 3340; CrossSectionArea: 0.0092; OuterSurfaceArea: 1.79133; GrossSurfaceArea: 1.80973; NetSurfaceArea: 1.80973; GrossVolume: 0.030519; NetVolume: 0.030519
Pset_BeamCommon - Reference: 40 x 230; Span: 3340 mm; Slope: 0 rad; Roll: 0 rad; IsExternal: no; LoadBearing: yes
Pset_ConcreteElementGeneral - ConstructionMethod: prefabricated
Pset_Condition - AssessmentCondition: Empty
Pset_EnvironmentalImpactIndicators - Reference: 40 x 230; sets with these values: 2

# IfcBeam: 28_SF_hout_rechthoekig_40 x 230_129, 28_SF_hout_rechthoekig:40 x 230:33580006
In: 010
PredefinedType: BEAM; Material: GVH_i2_naaldhout_generiek
Cpset_Beam - LevelOfAccuracy: in te vullen door Buildwise
IfcClassificationReference - TDS_link: .\05 As Builtdossier\2. Bouwkunde\2.2. Stabiliteit\2.2.0 technische fiche's\TF S 4.9.1.1.1 A - houten roostering sheddak.pdf
IfcElement - Tag: B1; Mark: B1
IfcRoot - Name: 40 x 230
Qto_BeamBaseQuantities - Length: 3340; CrossSectionArea: 0.897604; NetSurfaceArea: 1.79521; NetVolume: 0.0302285
Pset_BeamCommon - Reference: 40 x 230; Span: 3340 mm; Slope: 0 rad; Roll: 0 rad; IsExternal: no; LoadBearing: yes
Pset_ConcreteElementGeneral - ConstructionMethod: prefabricated
Pset_Condition - AssessmentCondition: Empty
Pset_EnvironmentalImpactIndicators - Reference: 40 x 230; sets with these values: 2

# IfcBeam: 28_SF_hout_rechthoekig_40 x 230_13, 28_SF_hout_rechthoekig:40 x 230:33579228
In: 010
PredefinedType: BEAM; Material: GVH_i2_naaldhout_generiek
Cpset_Beam - LevelOfAccuracy: in te vullen door Buildwise
IfcClassificationReference - TDS_link: .\05 As Builtdossier\2. Bouwkunde\2.2. Stabiliteit\2.2.0 technische fiche's\TF S 4.9.1.1.1 A - houten roostering sheddak.pdf
IfcElement - Tag: B1; Mark: B1
IfcRoot - Name: 40 x 230
Qto_BeamBaseQuantities - Length: 3410; CrossSectionArea: 0.0092; OuterSurfaceArea: 1.79133; GrossSurfaceArea: 1.80973; NetSurfaceArea: 1.80973; GrossVolume: 0.030519; NetVolume: 0.030519
Pset_BeamCommon - Reference: 40 x 230; Span: 3410 mm; Slope: 0 rad; Roll: 0 rad; IsExternal: no; LoadBearing: yes
Pset_ConcreteElementGeneral - ConstructionMethod: prefabricated
Pset_Condition - AssessmentCondition: Empty
Pset_EnvironmentalImpactIndicators - Reference: 40 x 230; sets with these values: 2

# IfcBeam: 28_SF_hout_rechthoekig_40 x 230_131, 28_SF_hout_rechthoekig:40 x 230:33580008
In: 010
PredefinedType: BEAM; Material: GVH_i2_naaldhout_generiek
Cpset_Beam - LevelOfAccuracy: in te vullen door Buildwise
IfcClassificationReference - TDS_link: .\05 As Builtdossier\2. Bouwkunde\2.2. Stabiliteit\2.2.0 technische fiche's\TF S 4.9.1.1.1 A - houten roostering sheddak.pdf
IfcElement - Tag: B1; Mark: B1
IfcRoot - Name: 40 x 230
Qto_BeamBaseQuantities - Length: 3340; CrossSectionArea: 0.0092; OuterSurfaceArea: 1.79133; GrossSurfaceArea: 1.80973; NetSurfaceArea: 1.80973; GrossVolume: 0.030519; NetVolume: 0.030519
Pset_BeamCommon - Reference: 40 x 230; Span: 3340 mm; Slope: 0 rad; Roll: 0 rad; IsExternal: no; LoadBearing: yes
Pset_ConcreteElementGeneral - ConstructionMethod: prefabricated
Pset_Condition - AssessmentCondition: Empty
Pset_EnvironmentalImpactIndicators - Reference: 40 x 230; sets with these values: 2

# IfcBeam: 28_SF_hout_rechthoekig_40 x 230_133, 28_SF_hout_rechthoekig:40 x 230:33580011
In: 010
PredefinedType: BEAM; Material: GVH_i2_naaldhout_generiek
Cpset_Beam - LevelOfAccuracy: in te vullen door Buildwise
IfcClassificationReference - TDS_link: .\05 As Builtdossier\2. Bouwkunde\2.2. Stabiliteit\2.2.0 technische fiche's\TF S 4.9.1.1.1 A - houten roostering sheddak.pdf
IfcElement - Tag: B1; Mark: B1
IfcRoot - Name: 40 x 230
Qto_BeamBaseQuantities - Length: 3340; CrossSectionArea: 0.0092; OuterSurfaceArea: 1.79133; GrossSurfaceArea: 1.80973; NetSurfaceArea: 1.80973; GrossVolume: 0.0305189; NetVolume: 0.0305189
Pset_BeamCommon - Reference: 40 x 230; Span: 3340 mm; Slope: 0 rad; Roll: 0 rad; IsExternal: no; LoadBearing: yes
Pset_ConcreteElementGeneral - ConstructionMethod: prefabricated
Pset_Condition - AssessmentCondition: Empty
Pset_EnvironmentalImpactIndicators - Reference: 40 x 230; sets with these values: 2

# IfcBeam: 28_SF_hout_rechthoekig_40 x 230_135, 28_SF_hout_rechthoekig:40 x 230:33580013
In: 010
PredefinedType: BEAM; Material: GVH_i2_naaldhout_generiek
Cpset_Beam - LevelOfAccuracy: in te vullen door Buildwise
IfcClassificationReference - TDS_link: .\05 As Builtdossier\2. Bouwkunde\2.2. Stabiliteit\2.2.0 technische fiche's\TF S 4.9.1.1.1 A - houten roostering sheddak.pdf
IfcElement - Tag: B1; Mark: B1
IfcRoot - Name: 40 x 230
Qto_BeamBaseQuantities - Length: 3340; CrossSectionArea: 0.0092; OuterSurfaceArea: 1.79133; GrossSurfaceArea: 1.80973; NetSurfaceArea: 1.80973; GrossVolume: 0.0305189; NetVolume: 0.0305189
Pset_BeamCommon - Reference: 40 x 230; Span: 3340 mm; Slope: 0 rad; Roll: 0 rad; IsExternal: no; LoadBearing: yes
Pset_ConcreteElementGeneral - ConstructionMethod: prefabricated
Pset_Condition - AssessmentCondition: Empty
Pset_EnvironmentalImpactIndicators - Reference: 40 x 230; sets with these values: 2

# IfcBeam: 28_SF_hout_rechthoekig_40 x 230_137, 28_SF_hout_rechthoekig:40 x 230:33580015
In: 010
PredefinedType: BEAM; Material: GVH_i2_naaldhout_generiek
Cpset_Beam - LevelOfAccuracy: in te vullen door Buildwise
IfcClassificationReference - TDS_link: .\05 As Builtdossier\2. Bouwkunde\2.2. Stabiliteit\2.2.0 technische fiche's\TF S 4.9.1.1.1 A - houten roostering sheddak.pdf
IfcElement - Tag: B1; Mark: B1
IfcRoot - Name: 40 x 230
Qto_BeamBaseQuantities - Length: 3340; CrossSectionArea: 0.0092; OuterSurfaceArea: 1.79133; GrossSurfaceArea: 1.80973; NetSurfaceArea: 1.80973; GrossVolume: 0.0305189; NetVolume: 0.0305189
Pset_BeamCommon - Reference: 40 x 230; Span: 3340 mm; Slope: 0 rad; Roll: 0 rad; IsExternal: no; LoadBearing: yes
Pset_ConcreteElementGeneral - ConstructionMethod: prefabricated
Pset_Condition - AssessmentCondition: Empty
Pset_EnvironmentalImpactIndicators - Reference: 40 x 230; sets with these values: 2

# IfcBeam: 28_SF_hout_rechthoekig_40 x 230_139, 28_SF_hout_rechthoekig:40 x 230:33580017
In: 010
PredefinedType: BEAM; Material: GVH_i2_naaldhout_generiek
Cpset_Beam - LevelOfAccuracy: in te vullen door Buildwise
IfcClassificationReference - TDS_link: .\05 As Builtdossier\2. Bouwkunde\2.2. Stabiliteit\2.2.0 technische fiche's\TF S 4.9.1.1.1 A - houten roostering sheddak.pdf
IfcElement - Tag: B1; Mark: B1
IfcRoot - Name: 40 x 230
Qto_BeamBaseQuantities - Length: 3340; CrossSectionArea: 0.0092; OuterSurfaceArea: 1.79133; GrossSurfaceArea: 1.80973; NetSurfaceArea: 1.80973; GrossVolume: 0.0305189; NetVolume: 0.0305189
Pset_BeamCommon - Reference: 40 x 230; Span: 3340 mm; Slope: 0 rad; Roll: 0 rad; IsExternal: no; LoadBearing: yes
Pset_ConcreteElementGeneral - ConstructionMethod: prefabricated
Pset_Condition - AssessmentCondition: Empty
Pset_EnvironmentalImpactIndicators - Reference: 40 x 230; sets with these values: 2

# IfcBeam: 28_SF_hout_rechthoekig_40 x 230_141, 28_SF_hout_rechthoekig:40 x 230:33580019
In: 010
PredefinedType: BEAM; Material: GVH_i2_naaldhout_generiek
Cpset_Beam - LevelOfAccuracy: in te vullen door Buildwise
IfcClassificationReference - TDS_link: .\05 As Builtdossier\2. Bouwkunde\2.2. Stabiliteit\2.2.0 technische fiche's\TF S 4.9.1.1.1 A - houten roostering sheddak.pdf
IfcElement - Tag: B1; Mark: B1
IfcRoot - Name: 40 x 230
Qto_BeamBaseQuantities - Length: 3340; CrossSectionArea: 0.0092; OuterSurfaceArea: 1.79133; GrossSurfaceArea: 1.80973; NetSurfaceArea: 1.80973; GrossVolume: 0.0305189; NetVolume: 0.0305189
Pset_BeamCommon - Reference: 40 x 230; Span: 3340 mm; Slope: 0 rad; Roll: 0 rad; IsExternal: no; LoadBearing: yes
Pset_ConcreteElementGeneral - ConstructionMethod: prefabricated
Pset_Condition - AssessmentCondition: Empty
Pset_EnvironmentalImpactIndicators - Reference: 40 x 230; sets with these values: 2

# IfcBeam: 28_SF_hout_rechthoekig_40 x 230_143, 28_SF_hout_rechthoekig:40 x 230:33580021
In: 010
PredefinedType: BEAM; Material: GVH_i2_naaldhout_generiek
Cpset_Beam - LevelOfAccuracy: in te vullen door Buildwise
IfcClassificationReference - TDS_link: .\05 As Builtdossier\2. Bouwkunde\2.2. Stabiliteit\2.2.0 technische fiche's\TF S 4.9.1.1.1 A - houten roostering sheddak.pdf
IfcElement - Tag: B1; Mark: B1
IfcRoot - Name: 40 x 230
Qto_BeamBaseQuantities - Length: 3340; CrossSectionArea: 0.0092; OuterSurfaceArea: 1.79133; GrossSurfaceArea: 1.80973; NetSurfaceArea: 1.80973; GrossVolume: 0.0305189; NetVolume: 0.0305189
Pset_BeamCommon - Reference: 40 x 230; Span: 3340 mm; Slope: 0 rad; Roll: 0 rad; IsExternal: no; LoadBearing: yes
Pset_ConcreteElementGeneral - ConstructionMethod: prefabricated
Pset_Condition - AssessmentCondition: Empty
Pset_EnvironmentalImpactIndicators - Reference: 40 x 230; sets with these values: 2

# IfcBeam: 28_SF_hout_rechthoekig_40 x 230_145, 28_SF_hout_rechthoekig:40 x 230:33580023
In: 010
PredefinedType: BEAM; Material: GVH_i2_naaldhout_generiek
Cpset_Beam - LevelOfAccuracy: in te vullen door Buildwise
IfcClassificationReference - TDS_link: .\05 As Builtdossier\2. Bouwkunde\2.2. Stabiliteit\2.2.0 technische fiche's\TF S 4.9.1.1.1 A - houten roostering sheddak.pdf
IfcElement - Tag: B1; Mark: B1
IfcRoot - Name: 40 x 230
Qto_BeamBaseQuantities - Length: 3340; CrossSectionArea: 0.0092; OuterSurfaceArea: 1.79133; GrossSurfaceArea: 1.80973; NetSurfaceArea: 1.80973; GrossVolume: 0.0305189; NetVolume: 0.0305189
Pset_BeamCommon - Reference: 40 x 230; Span: 3340 mm; Slope: 0 rad; Roll: 0 rad; IsExternal: no; LoadBearing: yes
Pset_ConcreteElementGeneral - ConstructionMethod: prefabricated
Pset_Condition - AssessmentCondition: Empty
Pset_EnvironmentalImpactIndicators - Reference: 40 x 230; sets with these values: 2

# IfcBeam: 28_SF_hout_rechthoekig_40 x 230_147, 28_SF_hout_rechthoekig:40 x 230:33580025
In: 010
PredefinedType: BEAM; Material: GVH_i2_naaldhout_generiek
Cpset_Beam - LevelOfAccuracy: in te vullen door Buildwise
IfcClassificationReference - TDS_link: .\05 As Builtdossier\2. Bouwkunde\2.2. Stabiliteit\2.2.0 technische fiche's\TF S 4.9.1.1.1 A - houten roostering sheddak.pdf
IfcElement - Tag: B1; Mark: B1
IfcRoot - Name: 40 x 230
Qto_BeamBaseQuantities - Length: 3340; CrossSectionArea: 0.0092; OuterSurfaceArea: 1.79133; GrossSurfaceArea: 1.80973; NetSurfaceArea: 1.80973; GrossVolume: 0.0305189; NetVolume: 0.0305189
Pset_BeamCommon - Reference: 40 x 230; Span: 3340 mm; Slope: 0 rad; Roll: 0 rad; IsExternal: no; LoadBearing: yes
Pset_ConcreteElementGeneral - ConstructionMethod: prefabricated
Pset_Condition - AssessmentCondition: Empty
Pset_EnvironmentalImpactIndicators - Reference: 40 x 230; sets with these values: 2

# IfcBeam: 28_SF_hout_rechthoekig_40 x 230_149, 28_SF_hout_rechthoekig:40 x 230:33580027
In: 010
PredefinedType: BEAM; Material: GVH_i2_naaldhout_generiek
Cpset_Beam - LevelOfAccuracy: in te vullen door Buildwise
IfcClassificationReference - TDS_link: .\05 As Builtdossier\2. Bouwkunde\2.2. Stabiliteit\2.2.0 technische fiche's\TF S 4.9.1.1.1 A - houten roostering sheddak.pdf
IfcElement - Tag: B1; Mark: B1
IfcRoot - Name: 40 x 230
Qto_BeamBaseQuantities - Length: 3340; CrossSectionArea: 0.0092; OuterSurfaceArea: 1.79133; GrossSurfaceArea: 1.80973; NetSurfaceArea: 1.80973; GrossVolume: 0.0305189; NetVolume: 0.0305189
Pset_BeamCommon - Reference: 40 x 230; Span: 3340 mm; Slope: 0 rad; Roll: 0 rad; IsExternal: no; LoadBearing: yes
Pset_ConcreteElementGeneral - ConstructionMethod: prefabricated
Pset_Condition - AssessmentCondition: Empty
Pset_EnvironmentalImpactIndicators - Reference: 40 x 230; sets with these values: 2

# IfcBeam: 28_SF_hout_rechthoekig_40 x 230_15, 28_SF_hout_rechthoekig:40 x 230:33579231
In: 010
PredefinedType: BEAM; Material: GVH_i2_naaldhout_generiek
Cpset_Beam - LevelOfAccuracy: in te vullen door Buildwise
IfcClassificationReference - TDS_link: .\05 As Builtdossier\2. Bouwkunde\2.2. Stabiliteit\2.2.0 technische fiche's\TF S 4.9.1.1.1 A - houten roostering sheddak.pdf
IfcElement - Tag: A17; Mark: A17
IfcRoot - Name: 40 x 230
Qto_BeamBaseQuantities - Length: 3280; CrossSectionArea: 0.859754; NetSurfaceArea: 1.71951; NetVolume: 0.0289321
Pset_BeamCommon - Reference: 40 x 230; Span: 3280 mm; Slope: 0 rad; Roll: 0 rad; IsExternal: no; LoadBearing: yes
Pset_ConcreteElementGeneral - ConstructionMethod: prefabricated
Pset_Condition - AssessmentCondition: Empty
Pset_EnvironmentalImpactIndicators - Reference: 40 x 230; sets with these values: 2

# IfcBeam: 28_SF_hout_rechthoekig_40 x 230_151, 28_SF_hout_rechthoekig:40 x 230:33580029
In: 010
PredefinedType: BEAM; Material: GVH_i2_naaldhout_generiek
Cpset_Beam - LevelOfAccuracy: in te vullen door Buildwise
IfcClassificationReference - TDS_link: .\05 As Builtdossier\2. Bouwkunde\2.2. Stabiliteit\2.2.0 technische fiche's\TF S 4.9.1.1.1 A - houten roostering sheddak.pdf
IfcElement - Tag: B1; Mark: B1
IfcRoot - Name: 40 x 230
Qto_BeamBaseQuantities - Length: 3340; CrossSectionArea: 0.0092; OuterSurfaceArea: 1.79133; GrossSurfaceArea: 1.80973; NetSurfaceArea: 1.80973; GrossVolume: 0.0305189; NetVolume: 0.0305189
Pset_BeamCommon - Reference: 40 x 230; Span: 3340 mm; Slope: 0 rad; Roll: 0 rad; IsExternal: no; LoadBearing: yes
Pset_ConcreteElementGeneral - ConstructionMethod: prefabricated
Pset_Condition - AssessmentCondition: Empty
Pset_EnvironmentalImpactIndicators - Reference: 40 x 230; sets with these values: 2

# IfcBeam: 28_SF_hout_rechthoekig_40 x 230_153, 28_SF_hout_rechthoekig:40 x 230:33580031
In: 010
PredefinedType: BEAM; Material: GVH_i2_naaldhout_generiek
Cpset_Beam - LevelOfAccuracy: in te vullen door Buildwise
IfcClassificationReference - TDS_link: .\05 As Builtdossier\2. Bouwkunde\2.2. Stabiliteit\2.2.0 technische fiche's\TF S 4.9.1.1.1 A - houten roostering sheddak.pdf
IfcElement - Tag: B1; Mark: B1
IfcRoot - Name: 40 x 230
Qto_BeamBaseQuantities - Length: 3340; CrossSectionArea: 0.0092; OuterSurfaceArea: 1.79133; GrossSurfaceArea: 1.80973; NetSurfaceArea: 1.80973; GrossVolume: 0.0305189; NetVolume: 0.0305189
Pset_BeamCommon - Reference: 40 x 230; Span: 3340 mm; Slope: 0 rad; Roll: 0 rad; IsExternal: no; LoadBearing: yes
Pset_ConcreteElementGeneral - ConstructionMethod: prefabricated
Pset_Condition - AssessmentCondition: Empty
Pset_EnvironmentalImpactIndicators - Reference: 40 x 230; sets with these values: 2

# IfcBeam: 28_SF_hout_rechthoekig_40 x 230_155, 28_SF_hout_rechthoekig:40 x 230:33580033
In: 010
PredefinedType: BEAM; Material: GVH_i2_naaldhout_generiek
Cpset_Beam - LevelOfAccuracy: in te vullen door Buildwise
IfcClassificationReference - TDS_link: .\05 As Builtdossier\2. Bouwkunde\2.2. Stabiliteit\2.2.0 technische fiche's\TF S 4.9.1.1.1 A - houten roostering sheddak.pdf
IfcElement - Tag: B1; Mark: B1
IfcRoot - Name: 40 x 230
Qto_BeamBaseQuantities - Length: 3340; CrossSectionArea: 0.0092; OuterSurfaceArea: 1.79133; GrossSurfaceArea: 1.80973; NetSurfaceArea: 1.80973; GrossVolume: 0.0305189; NetVolume: 0.0305189
Pset_BeamCommon - Reference: 40 x 230; Span: 3340 mm; Slope: 0 rad; Roll: 0 rad; IsExternal: no; LoadBearing: yes
Pset_ConcreteElementGeneral - ConstructionMethod: prefabricated
Pset_Condition - AssessmentCondition: Empty
Pset_EnvironmentalImpactIndicators - Reference: 40 x 230; sets with these values: 2

# IfcBeam: 28_SF_hout_rechthoekig_40 x 230_157, 28_SF_hout_rechthoekig:40 x 230:33580035
In: 010
PredefinedType: BEAM; Material: GVH_i2_naaldhout_generiek
Cpset_Beam - LevelOfAccuracy: in te vullen door Buildwise
IfcClassificationReference - TDS_link: .\05 As Builtdossier\2. Bouwkunde\2.2. Stabiliteit\2.2.0 technische fiche's\TF S 4.9.1.1.1 A - houten roostering sheddak.pdf
IfcElement - Tag: B1; Mark: B1
IfcRoot - Name: 40 x 230
Qto_BeamBaseQuantities - Length: 3340; CrossSectionArea: 0.0092; OuterSurfaceArea: 1.79133; GrossSurfaceArea: 1.80973; NetSurfaceArea: 1.80973; GrossVolume: 0.0305189; NetVolume: 0.0305189
Pset_BeamCommon - Reference: 40 x 230; Span: 3340 mm; Slope: 0 rad; Roll: 0 rad; IsExternal: no; LoadBearing: yes
Pset_ConcreteElementGeneral - ConstructionMethod: prefabricated
Pset_Condition - AssessmentCondition: Empty
Pset_EnvironmentalImpactIndicators - Reference: 40 x 230; sets with these values: 2

# IfcBeam: 28_SF_hout_rechthoekig_40 x 230_159, 28_SF_hout_rechthoekig:40 x 230:33580037
In: 010
PredefinedType: BEAM; Material: GVH_i2_naaldhout_generiek
Cpset_Beam - LevelOfAccuracy: in te vullen door Buildwise
IfcClassificationReference - TDS_link: .\05 As Builtdossier\2. Bouwkunde\2.2. Stabiliteit\2.2.0 technische fiche's\TF S 4.9.1.1.1 A - houten roostering sheddak.pdf
IfcElement - Tag: B1; Mark: B1
IfcRoot - Name: 40 x 230
Qto_BeamBaseQuantities - Length: 3340; CrossSectionArea: 0.0092; OuterSurfaceArea: 1.79133; GrossSurfaceArea: 1.80973; NetSurfaceArea: 1.80973; GrossVolume: 0.0305189; NetVolume: 0.0305189
Pset_BeamCommon - Reference: 40 x 230; Span: 3340 mm; Slope: 0 rad; Roll: 0 rad; IsExternal: no; LoadBearing: yes
Pset_ConcreteElementGeneral - ConstructionMethod: prefabricated
Pset_Condition - AssessmentCondition: Empty
Pset_EnvironmentalImpactIndicators - Reference: 40 x 230; sets with these values: 2

# IfcBeam: 28_SF_hout_rechthoekig_40 x 230_161, 28_SF_hout_rechthoekig:40 x 230:33580039
In: 010
PredefinedType: BEAM; Material: GVH_i2_naaldhout_generiek
Cpset_Beam - LevelOfAccuracy: in te vullen door Buildwise
IfcClassificationReference - TDS_link: .\05 As Builtdossier\2. Bouwkunde\2.2. Stabiliteit\2.2.0 technische fiche's\TF S 4.9.1.1.1 A - houten roostering sheddak.pdf
IfcElement - Tag: B1; Mark: B1
IfcRoot - Name: 40 x 230
Qto_BeamBaseQuantities - Length: 3340; CrossSectionArea: 0.0092; OuterSurfaceArea: 1.79133; GrossSurfaceArea: 1.80973; NetSurfaceArea: 1.80973; GrossVolume: 0.0305189; NetVolume: 0.0305189
Pset_BeamCommon - Reference: 40 x 230; Span: 3340 mm; Slope: 0 rad; Roll: 0 rad; IsExternal: no; LoadBearing: yes
Pset_ConcreteElementGeneral - ConstructionMethod: prefabricated
Pset_Condition - AssessmentCondition: Empty
Pset_EnvironmentalImpactIndicators - Reference: 40 x 230; sets with these values: 2

# IfcBeam: 28_SF_hout_rechthoekig_40 x 230_163, 28_SF_hout_rechthoekig:40 x 230:33580041
In: 010
PredefinedType: BEAM; Material: GVH_i2_naaldhout_generiek
Cpset_Beam - LevelOfAccuracy: in te vullen door Buildwise
IfcClassificationReference - TDS_link: .\05 As Builtdossier\2. Bouwkunde\2.2. Stabiliteit\2.2.0 technische fiche's\TF S 4.9.1.1.1 A - houten roostering sheddak.pdf
IfcElement - Tag: B1; Mark: B1
IfcRoot - Name: 40 x 230
Qto_BeamBaseQuantities - Length: 3340; CrossSectionArea: 0.897603; NetSurfaceArea: 1.79521; NetVolume: 0.0302285
Pset_BeamCommon - Reference: 40 x 230; Span: 3340 mm; Slope: 0 rad; Roll: 0 rad; IsExternal: no; LoadBearing: yes
Pset_ConcreteElementGeneral - ConstructionMethod: prefabricated
Pset_Condition - AssessmentCondition: Empty
Pset_EnvironmentalImpactIndicators - Reference: 40 x 230; sets with these values: 2

# IfcBeam: 28_SF_hout_rechthoekig_40 x 230_165, 28_SF_hout_rechthoekig:40 x 230:33580043
In: 010
PredefinedType: BEAM; Material: GVH_i2_naaldhout_generiek
Cpset_Beam - LevelOfAccuracy: in te vullen door Buildwise
IfcClassificationReference - TDS_link: .\05 As Builtdossier\2. Bouwkunde\2.2. Stabiliteit\2.2.0 technische fiche's\TF S 4.9.1.1.1 A - houten roostering sheddak.pdf
IfcElement - Tag: B1; Mark: B1
IfcRoot - Name: 40 x 230
Qto_BeamBaseQuantities - Length: 3340; CrossSectionArea: 0.0092; OuterSurfaceArea: 1.79133; GrossSurfaceArea: 1.80973; NetSurfaceArea: 1.80973; GrossVolume: 0.0305189; NetVolume: 0.0305189
Pset_BeamCommon - Reference: 40 x 230; Span: 3340 mm; Slope: 0 rad; Roll: 0 rad; IsExternal: no; LoadBearing: yes
Pset_ConcreteElementGeneral - ConstructionMethod: prefabricated
Pset_Condition - AssessmentCondition: Empty
Pset_EnvironmentalImpactIndicators - Reference: 40 x 230; sets with these values: 2

# IfcBeam: 28_SF_hout_rechthoekig_40 x 230_167, 28_SF_hout_rechthoekig:40 x 230:33580046
In: 010
PredefinedType: BEAM; Material: GVH_i2_naaldhout_generiek
Cpset_Beam - LevelOfAccuracy: in te vullen door Buildwise
IfcClassificationReference - TDS_link: .\05 As Builtdossier\2. Bouwkunde\2.2. Stabiliteit\2.2.0 technische fiche's\TF S 4.9.1.1.1 A - houten roostering sheddak.pdf
IfcElement - Tag: B1; Mark: B1
IfcRoot - Name: 40 x 230
Qto_BeamBaseQuantities - Length: 3340; CrossSectionArea: 0.0092; OuterSurfaceArea: 1.79133; GrossSurfaceArea: 1.80973; NetSurfaceArea: 1.80973; GrossVolume: 0.030519; NetVolume: 0.030519
Pset_BeamCommon - Reference: 40 x 230; Span: 3340 mm; Slope: 0 rad; Roll: 0 rad; IsExternal: no; LoadBearing: yes
Pset_ConcreteElementGeneral - ConstructionMethod: prefabricated
Pset_Condition - AssessmentCondition: Empty
Pset_EnvironmentalImpactIndicators - Reference: 40 x 230; sets with these values: 2

# IfcBeam: 28_SF_hout_rechthoekig_40 x 230_169, 28_SF_hout_rechthoekig:40 x 230:33580048
In: 010
PredefinedType: BEAM; Material: GVH_i2_naaldhout_generiek
Cpset_Beam - LevelOfAccuracy: in te vullen door Buildwise
IfcClassificationReference - TDS_link: .\05 As Builtdossier\2. Bouwkunde\2.2. Stabiliteit\2.2.0 technische fiche's\TF S 4.9.1.1.1 A - houten roostering sheddak.pdf
IfcElement - Tag: B1; Mark: B1
IfcRoot - Name: 40 x 230
Qto_BeamBaseQuantities - Length: 3340; CrossSectionArea: 0.0092; OuterSurfaceArea: 1.79133; GrossSurfaceArea: 1.80973; NetSurfaceArea: 1.80973; GrossVolume: 0.030519; NetVolume: 0.030519
Pset_BeamCommon - Reference: 40 x 230; Span: 3340 mm; Slope: 0 rad; Roll: 0 rad; IsExternal: no; LoadBearing: yes
Pset_ConcreteElementGeneral - ConstructionMethod: prefabricated
Pset_Condition - AssessmentCondition: Empty
Pset_EnvironmentalImpactIndicators - Reference: 40 x 230; sets with these values: 2

# IfcBeam: 28_SF_hout_rechthoekig_40 x 230_17, 28_SF_hout_rechthoekig:40 x 230:33579234
In: 010
PredefinedType: BEAM; Material: GVH_i2_naaldhout_generiek
Cpset_Beam - LevelOfAccuracy: in te vullen door Buildwise
IfcClassificationReference - TDS_link: .\05 As Builtdossier\2. Bouwkunde\2.2. Stabiliteit\2.2.0 technische fiche's\TF S 4.9.1.1.1 A - houten roostering sheddak.pdf
IfcElement - Tag: A18; Mark: A18
IfcRoot - Name: 40 x 230
Qto_BeamBaseQuantities - Length: 2955; CrossSectionArea: 0.0092; OuterSurfaceArea: 1.52544; GrossSurfaceArea: 1.54384; NetSurfaceArea: 1.54384; GrossVolume: 0.025989; NetVolume: 0.025989
Pset_BeamCommon - Reference: 40 x 230; Span: 2955 mm; Slope: 0 rad; Roll: 0 rad; IsExternal: no; LoadBearing: yes
Pset_ConcreteElementGeneral - ConstructionMethod: prefabricated
Pset_Condition - AssessmentCondition: Empty
Pset_EnvironmentalImpactIndicators - Reference: 40 x 230; sets with these values: 2

# IfcBeam: 28_SF_hout_rechthoekig_40 x 230_171, 28_SF_hout_rechthoekig:40 x 230:33580050
In: 010
PredefinedType: BEAM; Material: GVH_i2_naaldhout_generiek
Cpset_Beam - LevelOfAccuracy: in te vullen door Buildwise
IfcClassificationReference - TDS_link: .\05 As Builtdossier\2. Bouwkunde\2.2. Stabiliteit\2.2.0 technische fiche's\TF S 4.9.1.1.1 A - houten roostering sheddak.pdf
IfcElement - Tag: B1; Mark: B1
IfcRoot - Name: 40 x 230
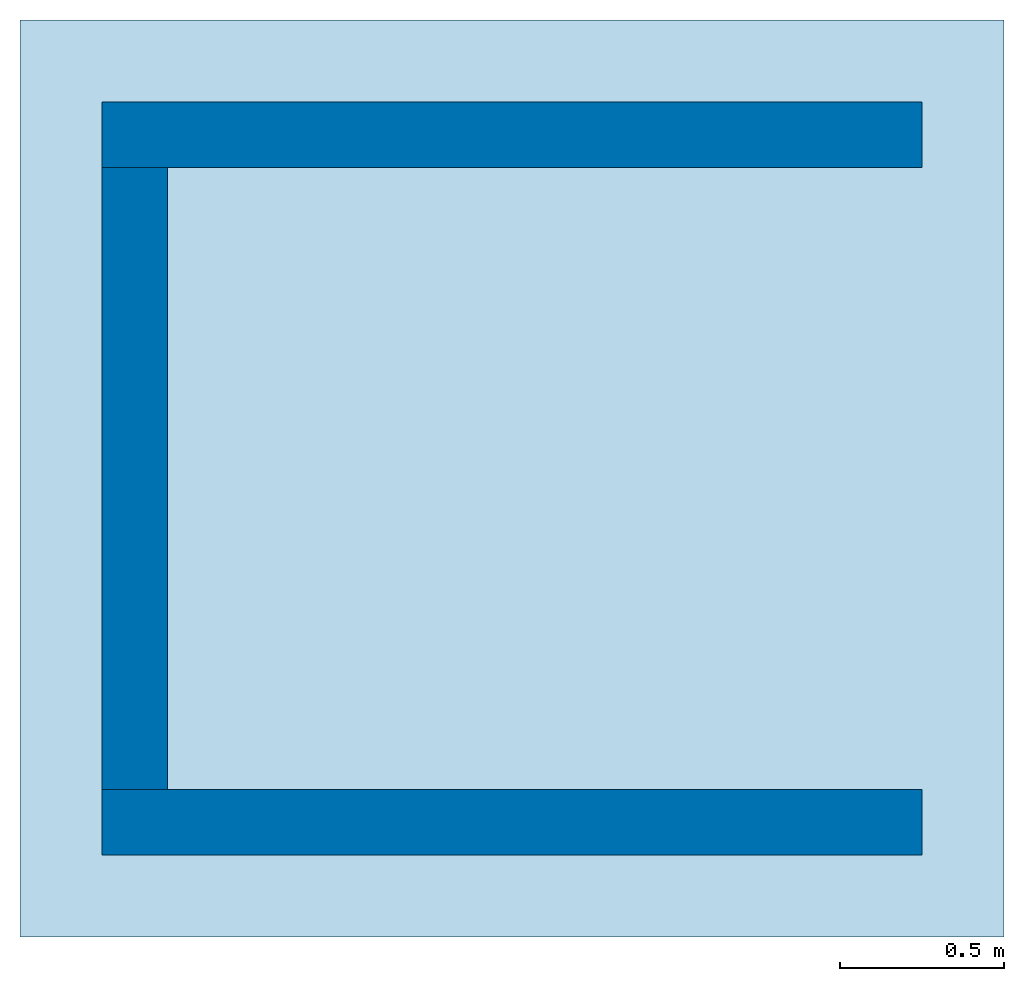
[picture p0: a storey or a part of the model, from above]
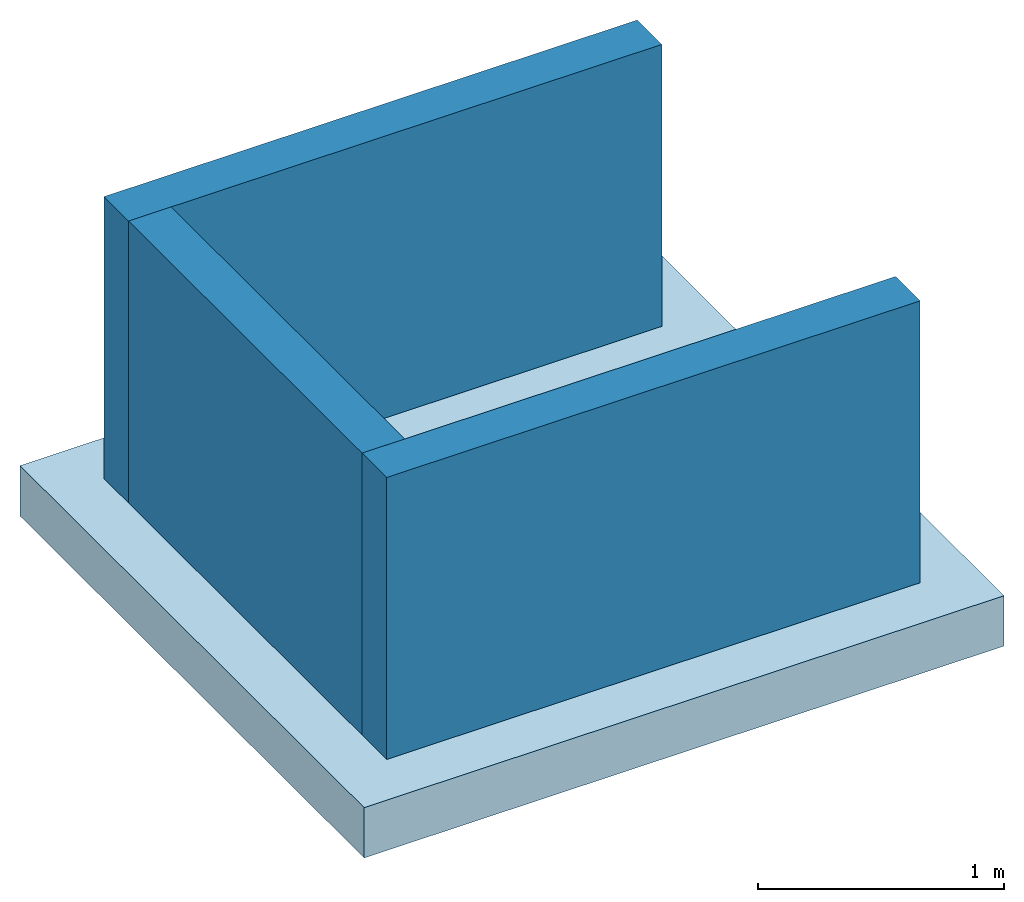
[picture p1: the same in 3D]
Properties of the parts of a building model (IFC4X3_ADD2), part 2 of 28

# IfcBeam: 28_SF_hout_rechthoekig_40 x 230_171, 28_SF_hout_rechthoekig:40 x 230:33580050
Qto_BeamBaseQuantities - Length: 3340; CrossSectionArea: 0.0092; OuterSurfaceArea: 1.79133; GrossSurfaceArea: 1.80973; NetSurfaceArea: 1.80973; GrossVolume: 0.030519; NetVolume: 0.030519
Pset_BeamCommon - Reference: 40 x 230; Span: 3340 mm; Slope: 0 rad; Roll: 0 rad; IsExternal: no; LoadBearing: yes
Pset_ConcreteElementGeneral - ConstructionMethod: prefabricated
Pset_Condition - AssessmentCondition: Empty
Pset_EnvironmentalImpactIndicators - Reference: 40 x 230; sets with these values: 2

# IfcBeam: 28_SF_hout_rechthoekig_40 x 230_173, 28_SF_hout_rechthoekig:40 x 230:33580052
In: 010
PredefinedType: BEAM; Material: GVH_i2_naaldhout_generiek
Cpset_Beam - LevelOfAccuracy: in te vullen door Buildwise
IfcClassificationReference - TDS_link: .\05 As Builtdossier\2. Bouwkunde\2.2. Stabiliteit\2.2.0 technische fiche's\TF S 4.9.1.1.1 A - houten roostering sheddak.pdf
IfcElement - Tag: B1; Mark: B1
IfcRoot - Name: 40 x 230
Qto_BeamBaseQuantities - Length: 3340; CrossSectionArea: 0.0092; OuterSurfaceArea: 1.79133; GrossSurfaceArea: 1.80973; NetSurfaceArea: 1.80973; GrossVolume: 0.030519; NetVolume: 0.030519
Pset_BeamCommon - Reference: 40 x 230; Span: 3340 mm; Slope: 0 rad; Roll: 0 rad; IsExternal: no; LoadBearing: yes
Pset_ConcreteElementGeneral - ConstructionMethod: prefabricated
Pset_Condition - AssessmentCondition: Empty
Pset_EnvironmentalImpactIndicators - Reference: 40 x 230; sets with these values: 2

# IfcBeam: 28_SF_hout_rechthoekig_40 x 230_175, 28_SF_hout_rechthoekig:40 x 230:33580054
In: 010
PredefinedType: BEAM; Material: GVH_i2_naaldhout_generiek
Cpset_Beam - LevelOfAccuracy: in te vullen door Buildwise
IfcClassificationReference - TDS_link: .\05 As Builtdossier\2. Bouwkunde\2.2. Stabiliteit\2.2.0 technische fiche's\TF S 4.9.1.1.1 A - houten roostering sheddak.pdf
IfcElement - Tag: B1; Mark: B1
IfcRoot - Name: 40 x 230
Qto_BeamBaseQuantities - Length: 3340; CrossSectionArea: 0.0092; OuterSurfaceArea: 1.79133; GrossSurfaceArea: 1.80973; NetSurfaceArea: 1.80973; GrossVolume: 0.030519; NetVolume: 0.030519
Pset_BeamCommon - Reference: 40 x 230; Span: 3340 mm; Slope: 0 rad; Roll: 0 rad; IsExternal: no; LoadBearing: yes
Pset_ConcreteElementGeneral - ConstructionMethod: prefabricated
Pset_Condition - AssessmentCondition: Empty
Pset_EnvironmentalImpactIndicators - Reference: 40 x 230; sets with these values: 2

# IfcBeam: 28_SF_hout_rechthoekig_40 x 230_177, 28_SF_hout_rechthoekig:40 x 230:33580056
In: 010
PredefinedType: BEAM; Material: GVH_i2_naaldhout_generiek
Cpset_Beam - LevelOfAccuracy: in te vullen door Buildwise
IfcClassificationReference - TDS_link: .\05 As Builtdossier\2. Bouwkunde\2.2. Stabiliteit\2.2.0 technische fiche's\TF S 4.9.1.1.1 A - houten roostering sheddak.pdf
IfcElement - Tag: B1; Mark: B1
IfcRoot - Name: 40 x 230
Qto_BeamBaseQuantities - Length: 3340; CrossSectionArea: 0.0092; OuterSurfaceArea: 1.79133; GrossSurfaceArea: 1.80973; NetSurfaceArea: 1.80973; GrossVolume: 0.030519; NetVolume: 0.030519
Pset_BeamCommon - Reference: 40 x 230; Span: 3340 mm; Slope: 0 rad; Roll: 0 rad; IsExternal: no; LoadBearing: yes
Pset_ConcreteElementGeneral - ConstructionMethod: prefabricated
Pset_Condition - AssessmentCondition: Empty
Pset_EnvironmentalImpactIndicators - Reference: 40 x 230; sets with these values: 2

# IfcBeam: 28_SF_hout_rechthoekig_40 x 230_179, 28_SF_hout_rechthoekig:40 x 230:33580058
In: 010
PredefinedType: BEAM; Material: GVH_i2_naaldhout_generiek
Cpset_Beam - LevelOfAccuracy: in te vullen door Buildwise
IfcClassificationReference - TDS_link: .\05 As Builtdossier\2. Bouwkunde\2.2. Stabiliteit\2.2.0 technische fiche's\TF S 4.9.1.1.1 A - houten roostering sheddak.pdf
IfcElement - Tag: B1; Mark: B1
IfcRoot - Name: 40 x 230
Qto_BeamBaseQuantities - Length: 3340; CrossSectionArea: 0.0092; OuterSurfaceArea: 1.79133; GrossSurfaceArea: 1.80973; NetSurfaceArea: 1.80973; GrossVolume: 0.030519; NetVolume: 0.030519
Pset_BeamCommon - Reference: 40 x 230; Span: 3340 mm; Slope: 0 rad; Roll: 0 rad; IsExternal: no; LoadBearing: yes
Pset_ConcreteElementGeneral - ConstructionMethod: prefabricated
Pset_Condition - AssessmentCondition: Empty
Pset_EnvironmentalImpactIndicators - Reference: 40 x 230; sets with these values: 2

# IfcBeam: 28_SF_hout_rechthoekig_40 x 230_181, 28_SF_hout_rechthoekig:40 x 230:33580060
In: 010
PredefinedType: BEAM; Material: GVH_i2_naaldhout_generiek
Cpset_Beam - LevelOfAccuracy: in te vullen door Buildwise
IfcClassificationReference - TDS_link: .\05 As Builtdossier\2. Bouwkunde\2.2. Stabiliteit\2.2.0 technische fiche's\TF S 4.9.1.1.1 A - houten roostering sheddak.pdf
IfcElement - Tag: B1; Mark: B1
IfcRoot - Name: 40 x 230
Qto_BeamBaseQuantities - Length: 3340; CrossSectionArea: 0.0092; OuterSurfaceArea: 1.79133; GrossSurfaceArea: 1.80973; NetSurfaceArea: 1.80973; GrossVolume: 0.030519; NetVolume: 0.030519
Pset_BeamCommon - Reference: 40 x 230; Span: 3340 mm; Slope: 0 rad; Roll: 0 rad; IsExternal: no; LoadBearing: yes
Pset_ConcreteElementGeneral - ConstructionMethod: prefabricated
Pset_Condition - AssessmentCondition: Empty
Pset_EnvironmentalImpactIndicators - Reference: 40 x 230; sets with these values: 2

# IfcBeam: 28_SF_hout_rechthoekig_40 x 230_183, 28_SF_hout_rechthoekig:40 x 230:33580062
In: 010
PredefinedType: BEAM; Material: GVH_i2_naaldhout_generiek
Cpset_Beam - LevelOfAccuracy: in te vullen door Buildwise
IfcClassificationReference - TDS_link: .\05 As Builtdossier\2. Bouwkunde\2.2. Stabiliteit\2.2.0 technische fiche's\TF S 4.9.1.1.1 A - houten roostering sheddak.pdf
IfcElement - Tag: B1; Mark: B1
IfcRoot - Name: 40 x 230
Qto_BeamBaseQuantities - Length: 3340; CrossSectionArea: 0.0092; OuterSurfaceArea: 1.79133; GrossSurfaceArea: 1.80973; NetSurfaceArea: 1.80973; GrossVolume: 0.030519; NetVolume: 0.030519
Pset_BeamCommon - Reference: 40 x 230; Span: 3340 mm; Slope: 0 rad; Roll: 0 rad; IsExternal: no; LoadBearing: yes
Pset_ConcreteElementGeneral - ConstructionMethod: prefabricated
Pset_Condition - AssessmentCondition: Empty
Pset_EnvironmentalImpactIndicators - Reference: 40 x 230; sets with these values: 2

# IfcBeam: 28_SF_hout_rechthoekig_40 x 230_185, 28_SF_hout_rechthoekig:40 x 230:33580064
In: 010
PredefinedType: BEAM; Material: GVH_i2_naaldhout_generiek
Cpset_Beam - LevelOfAccuracy: in te vullen door Buildwise
IfcClassificationReference - TDS_link: .\05 As Builtdossier\2. Bouwkunde\2.2. Stabiliteit\2.2.0 technische fiche's\TF S 4.9.1.1.1 A - houten roostering sheddak.pdf
IfcElement - Tag: B1; Mark: B1
IfcRoot - Name: 40 x 230
Qto_BeamBaseQuantities - Length: 3340; CrossSectionArea: 0.0092; OuterSurfaceArea: 1.79133; GrossSurfaceArea: 1.80973; NetSurfaceArea: 1.80973; GrossVolume: 0.030519; NetVolume: 0.030519
Pset_BeamCommon - Reference: 40 x 230; Span: 3340 mm; Slope: 0 rad; Roll: 0 rad; IsExternal: no; LoadBearing: yes
Pset_ConcreteElementGeneral - ConstructionMethod: prefabricated
Pset_Condition - AssessmentCondition: Empty
Pset_EnvironmentalImpactIndicators - Reference: 40 x 230; sets with these values: 2

# IfcBeam: 28_SF_hout_rechthoekig_40 x 230_187, 28_SF_hout_rechthoekig:40 x 230:33580066
In: 010
PredefinedType: BEAM; Material: GVH_i2_naaldhout_generiek
Cpset_Beam - LevelOfAccuracy: in te vullen door Buildwise
IfcClassificationReference - TDS_link: .\05 As Builtdossier\2. Bouwkunde\2.2. Stabiliteit\2.2.0 technische fiche's\TF S 4.9.1.1.1 A - houten roostering sheddak.pdf
IfcElement - Tag: B1; Mark: B1
IfcRoot - Name: 40 x 230
Qto_BeamBaseQuantities - Length: 3340; CrossSectionArea: 0.0092; OuterSurfaceArea: 1.79133; GrossSurfaceArea: 1.80973; NetSurfaceArea: 1.80973; GrossVolume: 0.030519; NetVolume: 0.030519
Pset_BeamCommon - Reference: 40 x 230; Span: 3340 mm; Slope: 0 rad; Roll: 0 rad; IsExternal: no; LoadBearing: yes
Pset_ConcreteElementGeneral - ConstructionMethod: prefabricated
Pset_Condition - AssessmentCondition: Empty
Pset_EnvironmentalImpactIndicators - Reference: 40 x 230; sets with these values: 2

# IfcBeam: 28_SF_hout_rechthoekig_40 x 230_189, 28_SF_hout_rechthoekig:40 x 230:33580068
In: 010
PredefinedType: BEAM; Material: GVH_i2_naaldhout_generiek
Cpset_Beam - LevelOfAccuracy: in te vullen door Buildwise
IfcClassificationReference - TDS_link: .\05 As Builtdossier\2. Bouwkunde\2.2. Stabiliteit\2.2.0 technische fiche's\TF S 4.9.1.1.1 A - houten roostering sheddak.pdf
IfcElement - Tag: B1; Mark: B1
IfcRoot - Name: 40 x 230
Qto_BeamBaseQuantities - Length: 3340; CrossSectionArea: 0.0092; OuterSurfaceArea: 1.79133; GrossSurfaceArea: 1.80973; NetSurfaceArea: 1.80973; GrossVolume: 0.030519; NetVolume: 0.030519
Pset_BeamCommon - Reference: 40 x 230; Span: 3340 mm; Slope: 0 rad; Roll: 0 rad; IsExternal: no; LoadBearing: yes
Pset_ConcreteElementGeneral - ConstructionMethod: prefabricated
Pset_Condition - AssessmentCondition: Empty
Pset_EnvironmentalImpactIndicators - Reference: 40 x 230; sets with these values: 2

# IfcBeam: 28_SF_hout_rechthoekig_40 x 230_19, 28_SF_hout_rechthoekig:40 x 230:33579237
In: 010
PredefinedType: BEAM; Material: GVH_i2_naaldhout_generiek
Cpset_Beam - LevelOfAccuracy: in te vullen door Buildwise
IfcClassificationReference - TDS_link: .\05 As Builtdossier\2. Bouwkunde\2.2. Stabiliteit\2.2.0 technische fiche's\TF S 4.9.1.1.1 A - houten roostering sheddak.pdf
IfcElement - Tag: A19; Mark: A19
IfcRoot - Name: 40 x 230
Qto_BeamBaseQuantities - Length: 2580; CrossSectionArea: 0.0092; OuterSurfaceArea: 1.33297; GrossSurfaceArea: 1.35137; NetSurfaceArea: 1.35137; GrossVolume: 0.0227099; NetVolume: 0.0227099
Pset_BeamCommon - Reference: 40 x 230; Span: 2580 mm; Slope: 0 rad; Roll: 0 rad; IsExternal: no; LoadBearing: yes
Pset_ConcreteElementGeneral - ConstructionMethod: prefabricated
Pset_Condition - AssessmentCondition: Empty
Pset_EnvironmentalImpactIndicators - Reference: 40 x 230; sets with these values: 2

# IfcBeam: 28_SF_hout_rechthoekig_40 x 230_191, 28_SF_hout_rechthoekig:40 x 230:33580070
In: 010
PredefinedType: BEAM; Material: GVH_i2_naaldhout_generiek
Cpset_Beam - LevelOfAccuracy: in te vullen door Buildwise
IfcClassificationReference - TDS_link: .\05 As Builtdossier\2. Bouwkunde\2.2. Stabiliteit\2.2.0 technische fiche's\TF S 4.9.1.1.1 A - houten roostering sheddak.pdf
IfcElement - Tag: B1; Mark: B1
IfcRoot - Name: 40 x 230
Qto_BeamBaseQuantities - Length: 3340; CrossSectionArea: 0.0092; OuterSurfaceArea: 1.79133; GrossSurfaceArea: 1.80973; NetSurfaceArea: 1.80973; GrossVolume: 0.030519; NetVolume: 0.030519
Pset_BeamCommon - Reference: 40 x 230; Span: 3340 mm; Slope: 0 rad; Roll: 0 rad; IsExternal: no; LoadBearing: yes
Pset_ConcreteElementGeneral - ConstructionMethod: prefabricated
Pset_Condition - AssessmentCondition: Empty
Pset_EnvironmentalImpactIndicators - Reference: 40 x 230; sets with these values: 2

# IfcBeam: 28_SF_hout_rechthoekig_40 x 230_193, 28_SF_hout_rechthoekig:40 x 230:33580072
In: 010
PredefinedType: BEAM; Material: GVH_i2_naaldhout_generiek
Cpset_Beam - LevelOfAccuracy: in te vullen door Buildwise
IfcClassificationReference - TDS_link: .\05 As Builtdossier\2. Bouwkunde\2.2. Stabiliteit\2.2.0 technische fiche's\TF S 4.9.1.1.1 A - houten roostering sheddak.pdf
IfcElement - Tag: B1; Mark: B1
IfcRoot - Name: 40 x 230
Qto_BeamBaseQuantities - Length: 3340; CrossSectionArea: 0.0092; OuterSurfaceArea: 1.79133; GrossSurfaceArea: 1.80973; NetSurfaceArea: 1.80973; GrossVolume: 0.030519; NetVolume: 0.030519
Pset_BeamCommon - Reference: 40 x 230; Span: 3340 mm; Slope: 0 rad; Roll: 0 rad; IsExternal: no; LoadBearing: yes
Pset_ConcreteElementGeneral - ConstructionMethod: prefabricated
Pset_Condition - AssessmentCondition: Empty
Pset_EnvironmentalImpactIndicators - Reference: 40 x 230; sets with these values: 2

# IfcBeam: 28_SF_hout_rechthoekig_40 x 230_195, 28_SF_hout_rechthoekig:40 x 230:33580074
In: 010
PredefinedType: BEAM; Material: GVH_i2_naaldhout_generiek
Cpset_Beam - LevelOfAccuracy: in te vullen door Buildwise
IfcClassificationReference - TDS_link: .\05 As Builtdossier\2. Bouwkunde\2.2. Stabiliteit\2.2.0 technische fiche's\TF S 4.9.1.1.1 A - houten roostering sheddak.pdf
IfcElement - Tag: B1; Mark: B1
IfcRoot - Name: 40 x 230
Qto_BeamBaseQuantities - Length: 3340; CrossSectionArea: 0.0092; OuterSurfaceArea: 1.79133; GrossSurfaceArea: 1.80973; NetSurfaceArea: 1.80973; GrossVolume: 0.030519; NetVolume: 0.030519
Pset_BeamCommon - Reference: 40 x 230; Span: 3340 mm; Slope: 0 rad; Roll: 0 rad; IsExternal: no; LoadBearing: yes
Pset_ConcreteElementGeneral - ConstructionMethod: prefabricated
Pset_Condition - AssessmentCondition: Empty
Pset_EnvironmentalImpactIndicators - Reference: 40 x 230; sets with these values: 2

# IfcBeam: 28_SF_hout_rechthoekig_40 x 230_197, 28_SF_hout_rechthoekig:40 x 230:33580076
In: 010
PredefinedType: BEAM; Material: GVH_i2_naaldhout_generiek
Cpset_Beam - LevelOfAccuracy: in te vullen door Buildwise
IfcClassificationReference - TDS_link: .\05 As Builtdossier\2. Bouwkunde\2.2. Stabiliteit\2.2.0 technische fiche's\TF S 4.9.1.1.1 A - houten roostering sheddak.pdf
IfcElement - Tag: B1; Mark: B1
IfcRoot - Name: 40 x 230
Qto_BeamBaseQuantities - Length: 3340; CrossSectionArea: 0.0092; OuterSurfaceArea: 1.79133; GrossSurfaceArea: 1.80973; NetSurfaceArea: 1.80973; GrossVolume: 0.030519; NetVolume: 0.030519
Pset_BeamCommon - Reference: 40 x 230; Span: 3340 mm; Slope: 0 rad; Roll: 0 rad; IsExternal: no; LoadBearing: yes
Pset_ConcreteElementGeneral - ConstructionMethod: prefabricated
Pset_Condition - AssessmentCondition: Empty
Pset_EnvironmentalImpactIndicators - Reference: 40 x 230; sets with these values: 2

# IfcBeam: 28_SF_hout_rechthoekig_40 x 230_199, 28_SF_hout_rechthoekig:40 x 230:33580081
In: 010
PredefinedType: BEAM; Material: GVH_i2_naaldhout_generiek
Cpset_Beam - LevelOfAccuracy: in te vullen door Buildwise
IfcClassificationReference - TDS_link: .\05 As Builtdossier\2. Bouwkunde\2.2. Stabiliteit\2.2.0 technische fiche's\TF S 4.9.1.1.1 A - houten roostering sheddak.pdf
IfcElement - Tag: C1; Mark: C1
IfcRoot - Name: 40 x 230
Qto_BeamBaseQuantities - Length: 3445; CrossSectionArea: 0.0092; OuterSurfaceArea: 1.84533; GrossSurfaceArea: 1.86373; NetSurfaceArea: 1.86373; GrossVolume: 0.0314389; NetVolume: 0.0314389
Pset_BeamCommon - Reference: 40 x 230; Span: 3445 mm; Slope: 0 rad; Roll: 0 rad; IsExternal: no; LoadBearing: yes
Pset_ConcreteElementGeneral - ConstructionMethod: prefabricated
Pset_Condition - AssessmentCondition: Empty
Pset_EnvironmentalImpactIndicators - Reference: 40 x 230; sets with these values: 2

# IfcBeam: 28_SF_hout_rechthoekig_40 x 230_201, 28_SF_hout_rechthoekig:40 x 230:33580083
In: 010
PredefinedType: BEAM; Material: GVH_i2_naaldhout_generiek
Cpset_Beam - LevelOfAccuracy: in te vullen door Buildwise
IfcClassificationReference - TDS_link: .\05 As Builtdossier\2. Bouwkunde\2.2. Stabiliteit\2.2.0 technische fiche's\TF S 4.9.1.1.1 A - houten roostering sheddak.pdf
IfcElement - Tag: C1; Mark: C1
IfcRoot - Name: 40 x 230
Qto_BeamBaseQuantities - Length: 3340; CrossSectionArea: 0.0092; OuterSurfaceArea: 1.84533; GrossSurfaceArea: 1.86373; NetSurfaceArea: 1.86373; GrossVolume: 0.0314389; NetVolume: 0.0314389
Pset_BeamCommon - Reference: 40 x 230; Span: 3340 mm; Slope: 0 rad; Roll: 0 rad; IsExternal: no; LoadBearing: yes
Pset_ConcreteElementGeneral - ConstructionMethod: prefabricated
Pset_Condition - AssessmentCondition: Empty
Pset_EnvironmentalImpactIndicators - Reference: 40 x 230; sets with these values: 2

# IfcBeam: 28_SF_hout_rechthoekig_40 x 230_203, 28_SF_hout_rechthoekig:40 x 230:33580085
In: 010
PredefinedType: BEAM; Material: GVH_i2_naaldhout_generiek
Cpset_Beam - LevelOfAccuracy: in te vullen door Buildwise
IfcClassificationReference - TDS_link: .\05 As Builtdossier\2. Bouwkunde\2.2. Stabiliteit\2.2.0 technische fiche's\TF S 4.9.1.1.1 A - houten roostering sheddak.pdf
IfcElement - Tag: C1; Mark: C1
IfcRoot - Name: 40 x 230
Qto_BeamBaseQuantities - Length: 3440; CrossSectionArea: 0.0092; OuterSurfaceArea: 1.84533; GrossSurfaceArea: 1.86373; NetSurfaceArea: 1.86373; GrossVolume: 0.0314389; NetVolume: 0.0314389
Pset_BeamCommon - Reference: 40 x 230; Span: 3440 mm; Slope: 0 rad; Roll: 0 rad; IsExternal: no; LoadBearing: yes
Pset_ConcreteElementGeneral - ConstructionMethod: prefabricated
Pset_Condition - AssessmentCondition: Empty
Pset_EnvironmentalImpactIndicators - Reference: 40 x 230; sets with these values: 2

# IfcBeam: 28_SF_hout_rechthoekig_40 x 230_205, 28_SF_hout_rechthoekig:40 x 230:33580087
In: 010
PredefinedType: BEAM; Material: GVH_i2_naaldhout_generiek
Cpset_Beam - LevelOfAccuracy: in te vullen door Buildwise
IfcClassificationReference - TDS_link: .\05 As Builtdossier\2. Bouwkunde\2.2. Stabiliteit\2.2.0 technische fiche's\TF S 4.9.1.1.1 A - houten roostering sheddak.pdf
IfcElement - Tag: C1; Mark: C1
IfcRoot - Name: 40 x 230
Qto_BeamBaseQuantities - Length: 3440; CrossSectionArea: 0.0092; OuterSurfaceArea: 1.84533; GrossSurfaceArea: 1.86373; NetSurfaceArea: 1.86373; GrossVolume: 0.0314389; NetVolume: 0.0314389
Pset_BeamCommon - Reference: 40 x 230; Span: 3440 mm; Slope: 0 rad; Roll: 0 rad; IsExternal: no; LoadBearing: yes
Pset_ConcreteElementGeneral - ConstructionMethod: prefabricated
Pset_Condition - AssessmentCondition: Empty
Pset_EnvironmentalImpactIndicators - Reference: 40 x 230; sets with these values: 2

# IfcBeam: 28_SF_hout_rechthoekig_40 x 230_207, 28_SF_hout_rechthoekig:40 x 230:33580089
In: 010
PredefinedType: BEAM; Material: GVH_i2_naaldhout_generiek
Cpset_Beam - LevelOfAccuracy: in te vullen door Buildwise
IfcClassificationReference - TDS_link: .\05 As Builtdossier\2. Bouwkunde\2.2. Stabiliteit\2.2.0 technische fiche's\TF S 4.9.1.1.1 A - houten roostering sheddak.pdf
IfcElement - Tag: C1; Mark: C1
IfcRoot - Name: 40 x 230
Qto_BeamBaseQuantities - Length: 3440; CrossSectionArea: 0.0092; OuterSurfaceArea: 1.84533; GrossSurfaceArea: 1.86373; NetSurfaceArea: 1.86373; GrossVolume: 0.0314389; NetVolume: 0.0314389
Pset_BeamCommon - Reference: 40 x 230; Span: 3440 mm; Slope: 0 rad; Roll: 0 rad; IsExternal: no; LoadBearing: yes
Pset_ConcreteElementGeneral - ConstructionMethod: prefabricated
Pset_Condition - AssessmentCondition: Empty
Pset_EnvironmentalImpactIndicators - Reference: 40 x 230; sets with these values: 2

# IfcBeam: 28_SF_hout_rechthoekig_40 x 230_209, 28_SF_hout_rechthoekig:40 x 230:33580091
In: 010
PredefinedType: BEAM; Material: GVH_i2_naaldhout_generiek
Cpset_Beam - LevelOfAccuracy: in te vullen door Buildwise
IfcClassificationReference - TDS_link: .\05 As Builtdossier\2. Bouwkunde\2.2. Stabiliteit\2.2.0 technische fiche's\TF S 4.9.1.1.1 A - houten roostering sheddak.pdf
IfcElement - Tag: C1; Mark: C1
IfcRoot - Name: 40 x 230
Qto_BeamBaseQuantities - Length: 3417.28; CrossSectionArea: 0.0092; OuterSurfaceArea: 1.84533; GrossSurfaceArea: 1.86373; NetSurfaceArea: 1.86373; GrossVolume: 0.0314389; NetVolume: 0.0314389
Pset_BeamCommon - Reference: 40 x 230; Span: 3417.28 mm; Slope: 0 rad; Roll: 0 rad; IsExternal: no; LoadBearing: yes
Pset_ConcreteElementGeneral - ConstructionMethod: prefabricated
Pset_Condition - AssessmentCondition: Empty
Pset_EnvironmentalImpactIndicators - Reference: 40 x 230; sets with these values: 2

# IfcBeam: 28_SF_hout_rechthoekig_40 x 230_21, 28_SF_hout_rechthoekig:40 x 230:33579240
In: 010
PredefinedType: BEAM; Material: GVH_i2_naaldhout_generiek
Cpset_Beam - LevelOfAccuracy: in te vullen door Buildwise
IfcClassificationReference - TDS_link: .\05 As Builtdossier\2. Bouwkunde\2.2. Stabiliteit\2.2.0 technische fiche's\TF S 4.9.1.1.1 A - houten roostering sheddak.pdf
IfcElement - Tag: A20; Mark: A20
IfcRoot - Name: 40 x 230
Qto_BeamBaseQuantities - Length: 2240; CrossSectionArea: 0.0092; OuterSurfaceArea: 1.1405; GrossSurfaceArea: 1.1589; NetSurfaceArea: 1.1589; GrossVolume: 0.0194308; NetVolume: 0.0194308
Pset_BeamCommon - Reference: 40 x 230; Span: 2240 mm; Slope: 0 rad; Roll: 0 rad; IsExternal: no; LoadBearing: yes
Pset_ConcreteElementGeneral - ConstructionMethod: prefabricated
Pset_Condition - AssessmentCondition: Empty
Pset_EnvironmentalImpactIndicators - Reference: 40 x 230; sets with these values: 2

# IfcBeam: 28_SF_hout_rechthoekig_40 x 230_211, 28_SF_hout_rechthoekig:40 x 230:33580093
In: 010
PredefinedType: BEAM; Material: GVH_i2_naaldhout_generiek
Cpset_Beam - LevelOfAccuracy: in te vullen door Buildwise
IfcClassificationReference - TDS_link: .\05 As Builtdossier\2. Bouwkunde\2.2. Stabiliteit\2.2.0 technische fiche's\TF S 4.9.1.1.1 A - houten roostering sheddak.pdf
IfcElement - Tag: C1; Mark: C1
IfcRoot - Name: 40 x 230
Qto_BeamBaseQuantities - Length: 3440; CrossSectionArea: 0.0092; OuterSurfaceArea: 1.84533; GrossSurfaceArea: 1.86373; NetSurfaceArea: 1.86373; GrossVolume: 0.0314389; NetVolume: 0.0314389
Pset_BeamCommon - Reference: 40 x 230; Span: 3440 mm; Slope: 0 rad; Roll: 0 rad; IsExternal: no; LoadBearing: yes
Pset_ConcreteElementGeneral - ConstructionMethod: prefabricated
Pset_Condition - AssessmentCondition: Empty
Pset_EnvironmentalImpactIndicators - Reference: 40 x 230; sets with these values: 2

# IfcBeam: 28_SF_hout_rechthoekig_40 x 230_213, 28_SF_hout_rechthoekig:40 x 230:33580095
In: 010
PredefinedType: BEAM; Material: GVH_i2_naaldhout_generiek
Cpset_Beam - LevelOfAccuracy: in te vullen door Buildwise
IfcClassificationReference - TDS_link: .\05 As Builtdossier\2. Bouwkunde\2.2. Stabiliteit\2.2.0 technische fiche's\TF S 4.9.1.1.1 A - houten roostering sheddak.pdf
IfcElement - Tag: C1; Mark: C1
IfcRoot - Name: 40 x 230
Qto_BeamBaseQuantities - Length: 3440; CrossSectionArea: 0.0092; OuterSurfaceArea: 1.84533; GrossSurfaceArea: 1.86373; NetSurfaceArea: 1.86373; GrossVolume: 0.0314389; NetVolume: 0.0314389
Pset_BeamCommon - Reference: 40 x 230; Span: 3440 mm; Slope: 0 rad; Roll: 0 rad; IsExternal: no; LoadBearing: yes
Pset_ConcreteElementGeneral - ConstructionMethod: prefabricated
Pset_Condition - AssessmentCondition: Empty
Pset_EnvironmentalImpactIndicators - Reference: 40 x 230; sets with these values: 2

# IfcBeam: 28_SF_hout_rechthoekig_40 x 230_215, 28_SF_hout_rechthoekig:40 x 230:33580097
In: 010
PredefinedType: BEAM; Material: GVH_i2_naaldhout_generiek
Cpset_Beam - LevelOfAccuracy: in te vullen door Buildwise
IfcClassificationReference - TDS_link: .\05 As Builtdossier\2. Bouwkunde\2.2. Stabiliteit\2.2.0 technische fiche's\TF S 4.9.1.1.1 A - houten roostering sheddak.pdf
IfcElement - Tag: C1; Mark: C1
IfcRoot - Name: 40 x 230
Qto_BeamBaseQuantities - Length: 3415; CrossSectionArea: 0.0092; OuterSurfaceArea: 1.84533; GrossSurfaceArea: 1.86373; NetSurfaceArea: 1.86373; GrossVolume: 0.0314389; NetVolume: 0.0314389
Pset_BeamCommon - Reference: 40 x 230; Span: 3415 mm; Slope: 0 rad; Roll: 0 rad; IsExternal: no; LoadBearing: yes
Pset_ConcreteElementGeneral - ConstructionMethod: prefabricated
Pset_Condition - AssessmentCondition: Empty
Pset_EnvironmentalImpactIndicators - Reference: 40 x 230; sets with these values: 2

# IfcBeam: 28_SF_hout_rechthoekig_40 x 230_217, 28_SF_hout_rechthoekig:40 x 230:33580099
In: 010
PredefinedType: BEAM; Material: GVH_i2_naaldhout_generiek
Cpset_Beam - LevelOfAccuracy: in te vullen door Buildwise
IfcClassificationReference - TDS_link: .\05 As Builtdossier\2. Bouwkunde\2.2. Stabiliteit\2.2.0 technische fiche's\TF S 4.9.1.1.1 A - houten roostering sheddak.pdf
IfcElement - Tag: C1; Mark: C1
IfcRoot - Name: 40 x 230
Qto_BeamBaseQuantities - Length: 3417.28; CrossSectionArea: 0.0092; OuterSurfaceArea: 1.84533; GrossSurfaceArea: 1.86373; NetSurfaceArea: 1.86373; GrossVolume: 0.0314389; NetVolume: 0.0314389
Pset_BeamCommon - Reference: 40 x 230; Span: 3417.28 mm; Slope: 0 rad; Roll: 0 rad; IsExternal: no; LoadBearing: yes
Pset_ConcreteElementGeneral - ConstructionMethod: prefabricated
Pset_Condition - AssessmentCondition: Empty
Pset_EnvironmentalImpactIndicators - Reference: 40 x 230; sets with these values: 2

# IfcBeam: 28_SF_hout_rechthoekig_40 x 230_219, 28_SF_hout_rechthoekig:40 x 230:33580101
In: 010
PredefinedType: BEAM; Material: GVH_i2_naaldhout_generiek
Cpset_Beam - LevelOfAccuracy: in te vullen door Buildwise
IfcClassificationReference - TDS_link: .\05 As Builtdossier\2. Bouwkunde\2.2. Stabiliteit\2.2.0 technische fiche's\TF S 4.9.1.1.1 A - houten roostering sheddak.pdf
IfcElement - Tag: C1; Mark: C1
IfcRoot - Name: 40 x 230
Qto_BeamBaseQuantities - Length: 3440; CrossSectionArea: 0.0092; OuterSurfaceArea: 1.84533; GrossSurfaceArea: 1.86373; NetSurfaceArea: 1.86373; GrossVolume: 0.0314389; NetVolume: 0.0314389
Pset_BeamCommon - Reference: 40 x 230; Span: 3440 mm; Slope: 0 rad; Roll: 0 rad; IsExternal: no; LoadBearing: yes
Pset_ConcreteElementGeneral - ConstructionMethod: prefabricated
Pset_Condition - AssessmentCondition: Empty
Pset_EnvironmentalImpactIndicators - Reference: 40 x 230; sets with these values: 2

# IfcBeam: 28_SF_hout_rechthoekig_40 x 230_221, 28_SF_hout_rechthoekig:40 x 230:33580103
In: 010
PredefinedType: BEAM; Material: GVH_i2_naaldhout_generiek
Cpset_Beam - LevelOfAccuracy: in te vullen door Buildwise
IfcClassificationReference - TDS_link: .\05 As Builtdossier\2. Bouwkunde\2.2. Stabiliteit\2.2.0 technische fiche's\TF S 4.9.1.1.1 A - houten roostering sheddak.pdf
IfcElement - Tag: C1; Mark: C1
IfcRoot - Name: 40 x 230
Qto_BeamBaseQuantities - Length: 3440; CrossSectionArea: 0.0092; OuterSurfaceArea: 1.84533; GrossSurfaceArea: 1.86373; NetSurfaceArea: 1.86373; GrossVolume: 0.0314389; NetVolume: 0.0314389
Pset_BeamCommon - Reference: 40 x 230; Span: 3440 mm; Slope: 0 rad; Roll: 0 rad; IsExternal: no; LoadBearing: yes
Pset_ConcreteElementGeneral - ConstructionMethod: prefabricated
Pset_Condition - AssessmentCondition: Empty
Pset_EnvironmentalImpactIndicators - Reference: 40 x 230; sets with these values: 2

# IfcBeam: 28_SF_hout_rechthoekig_40 x 230_223, 28_SF_hout_rechthoekig:40 x 230:33580105
In: 010
PredefinedType: BEAM; Material: GVH_i2_naaldhout_generiek
Cpset_Beam - LevelOfAccuracy: in te vullen door Buildwise
IfcClassificationReference - TDS_link: .\05 As Builtdossier\2. Bouwkunde\2.2. Stabiliteit\2.2.0 technische fiche's\TF S 4.9.1.1.1 A - houten roostering sheddak.pdf
IfcElement - Tag: C1; Mark: C1
IfcRoot - Name: 40 x 230
Qto_BeamBaseQuantities - Length: 3417.28; CrossSectionArea: 0.0092; OuterSurfaceArea: 1.84533; GrossSurfaceArea: 1.86373; NetSurfaceArea: 1.86373; GrossVolume: 0.0314389; NetVolume: 0.0314389
Pset_BeamCommon - Reference: 40 x 230; Span: 3417.28 mm; Slope: 0 rad; Roll: 0 rad; IsExternal: no; LoadBearing: yes
Pset_ConcreteElementGeneral - ConstructionMethod: prefabricated
Pset_Condition - AssessmentCondition: Empty
Pset_EnvironmentalImpactIndicators - Reference: 40 x 230; sets with these values: 2

# IfcBeam: 28_SF_hout_rechthoekig_40 x 230_225, 28_SF_hout_rechthoekig:40 x 230:33580107
In: 010
PredefinedType: BEAM; Material: GVH_i2_naaldhout_generiek
Cpset_Beam - LevelOfAccuracy: in te vullen door Buildwise
IfcClassificationReference - TDS_link: .\05 As Builtdossier\2. Bouwkunde\2.2. Stabiliteit\2.2.0 technische fiche's\TF S 4.9.1.1.1 A - houten roostering sheddak.pdf
IfcElement - Tag: C1; Mark: C1
IfcRoot - Name: 40 x 230
Qto_BeamBaseQuantities - Length: 3417.28; CrossSectionArea: 0.0092; OuterSurfaceArea: 1.84533; GrossSurfaceArea: 1.86373; NetSurfaceArea: 1.86373; GrossVolume: 0.0314389; NetVolume: 0.0314389
Pset_BeamCommon - Reference: 40 x 230; Span: 3417.28 mm; Slope: 0 rad; Roll: 0 rad; IsExternal: no; LoadBearing: yes
Pset_ConcreteElementGeneral - ConstructionMethod: prefabricated
Pset_Condition - AssessmentCondition: Empty
Pset_EnvironmentalImpactIndicators - Reference: 40 x 230; sets with these values: 2

# IfcBeam: 28_SF_hout_rechthoekig_40 x 230_227, 28_SF_hout_rechthoekig:40 x 230:33580109
In: 010
PredefinedType: BEAM; Material: GVH_i2_naaldhout_generiek
Cpset_Beam - LevelOfAccuracy: in te vullen door Buildwise
IfcClassificationReference - TDS_link: .\05 As Builtdossier\2. Bouwkunde\2.2. Stabiliteit\2.2.0 technische fiche's\TF S 4.9.1.1.1 A - houten roostering sheddak.pdf
IfcElement - Tag: C1; Mark: C1
IfcRoot - Name: 40 x 230
Qto_BeamBaseQuantities - Length: 3440; CrossSectionArea: 0.0092; OuterSurfaceArea: 1.84533; GrossSurfaceArea: 1.86373; NetSurfaceArea: 1.86373; GrossVolume: 0.0314389; NetVolume: 0.0314389
Pset_BeamCommon - Reference: 40 x 230; Span: 3440 mm; Slope: 0 rad; Roll: 0 rad; IsExternal: no; LoadBearing: yes
Pset_ConcreteElementGeneral - ConstructionMethod: prefabricated
Pset_Condition - AssessmentCondition: Empty
Pset_EnvironmentalImpactIndicators - Reference: 40 x 230; sets with these values: 2

# IfcBeam: 28_SF_hout_rechthoekig_40 x 230_229, 28_SF_hout_rechthoekig:40 x 230:33580111
In: 010
PredefinedType: BEAM; Material: GVH_i2_naaldhout_generiek
Cpset_Beam - LevelOfAccuracy: in te vullen door Buildwise
IfcClassificationReference - TDS_link: .\05 As Builtdossier\2. Bouwkunde\2.2. Stabiliteit\2.2.0 technische fiche's\TF S 4.9.1.1.1 A - houten roostering sheddak.pdf
IfcElement - Tag: C1; Mark: C1
IfcRoot - Name: 40 x 230
Qto_BeamBaseQuantities - Length: 3439.79; CrossSectionArea: 0.0092; OuterSurfaceArea: 1.84533; GrossSurfaceArea: 1.86373; NetSurfaceArea: 1.86373; GrossVolume: 0.0314389; NetVolume: 0.0314389
Pset_BeamCommon - Reference: 40 x 230; Span: 3439.79 mm; Slope: 0 rad; Roll: 0 rad; IsExternal: no; LoadBearing: yes
Pset_ConcreteElementGeneral - ConstructionMethod: prefabricated
Pset_Condition - AssessmentCondition: Empty
Pset_EnvironmentalImpactIndicators - Reference: 40 x 230; sets with these values: 2

# IfcBeam: 28_SF_hout_rechthoekig_40 x 230_23, 28_SF_hout_rechthoekig:40 x 230:33579243
In: 010
PredefinedType: BEAM; Material: GVH_i2_naaldhout_generiek
Cpset_Beam - LevelOfAccuracy: in te vullen door Buildwise
IfcClassificationReference - TDS_link: .\05 As Builtdossier\2. Bouwkunde\2.2. Stabiliteit\2.2.0 technische fiche's\TF S 4.9.1.1.1 A - houten roostering sheddak.pdf
IfcElement - Tag: A21; Mark: A21
IfcRoot - Name: 40 x 230
Qto_BeamBaseQuantities - Length: 1860; CrossSectionArea: 0.0092; OuterSurfaceArea: 0.948036; GrossSurfaceArea: 0.966436; NetSurfaceArea: 0.966436; GrossVolume: 0.0161517; NetVolume: 0.0161517
Pset_BeamCommon - Reference: 40 x 230; Span: 1860 mm; Slope: 0 rad; Roll: 0 rad; IsExternal: no; LoadBearing: yes
Pset_ConcreteElementGeneral - ConstructionMethod: prefabricated
Pset_Condition - AssessmentCondition: Empty
Pset_EnvironmentalImpactIndicators - Reference: 40 x 230; sets with these values: 2

# IfcBeam: 28_SF_hout_rechthoekig_40 x 230_231, 28_SF_hout_rechthoekig:40 x 230:33580113
In: 010
PredefinedType: BEAM; Material: GVH_i2_naaldhout_generiek
Cpset_Beam - LevelOfAccuracy: in te vullen door Buildwise
IfcClassificationReference - TDS_link: .\05 As Builtdossier\2. Bouwkunde\2.2. Stabiliteit\2.2.0 technische fiche's\TF S 4.9.1.1.1 A - houten roostering sheddak.pdf
IfcElement - Tag: C1; Mark: C1
IfcRoot - Name: 40 x 230
Qto_BeamBaseQuantities - Length: 3340; CrossSectionArea: 0.0092; OuterSurfaceArea: 1.84533; GrossSurfaceArea: 1.86373; NetSurfaceArea: 1.86373; GrossVolume: 0.0314389; NetVolume: 0.0314389
Pset_BeamCommon - Reference: 40 x 230; Span: 3340 mm; Slope: 0 rad; Roll: 0 rad; IsExternal: no; LoadBearing: yes
Pset_ConcreteElementGeneral - ConstructionMethod: prefabricated
Pset_Condition - AssessmentCondition: Empty
Pset_EnvironmentalImpactIndicators - Reference: 40 x 230; sets with these values: 2

# IfcBeam: 28_SF_hout_rechthoekig_40 x 230_233, 28_SF_hout_rechthoekig:40 x 230:33582092
In: 010
PredefinedType: BEAM; Material: GVH_i2_naaldhout_generiek
Cpset_Beam - LevelOfAccuracy: in te vullen door Buildwise
IfcClassificationReference - TDS_link: .\05 As Builtdossier\2. Bouwkunde\2.2. Stabiliteit\2.2.0 technische fiche's\TF S 4.9.1.1.1 A - houten roostering sheddak.pdf
IfcElement - Tag: B1; Mark: B1
IfcRoot - Name: 40 x 230
Qto_BeamBaseQuantities - Length: 3340; CrossSectionArea: 0.0092; OuterSurfaceArea: 1.79133; GrossSurfaceArea: 1.80973; NetSurfaceArea: 1.80973; GrossVolume: 0.030519; NetVolume: 0.030519
Pset_BeamCommon - Reference: 40 x 230; Span: 3340 mm; Slope: 0 rad; Roll: 0 rad; IsExternal: no; LoadBearing: yes
Pset_ConcreteElementGeneral - ConstructionMethod: prefabricated
Pset_Condition - AssessmentCondition: Empty
Pset_EnvironmentalImpactIndicators - Reference: 40 x 230; sets with these values: 2

# IfcBeam: 28_SF_hout_rechthoekig_40 x 230_235, 28_SF_hout_rechthoekig:40 x 230:33582124
In: 010
PredefinedType: BEAM; Material: GVH_i2_naaldhout_generiek
Cpset_Beam - LevelOfAccuracy: in te vullen door Buildwise
IfcClassificationReference - TDS_link: .\05 As Builtdossier\2. Bouwkunde\2.2. Stabiliteit\2.2.0 technische fiche's\TF S 4.9.1.1.1 A - houten roostering sheddak.pdf
IfcElement - Tag: B1; Mark: B1
IfcRoot - Name: 40 x 230
Qto_BeamBaseQuantities - Length: 3340; CrossSectionArea: 0.0092; OuterSurfaceArea: 1.79133; GrossSurfaceArea: 1.80973; NetSurfaceArea: 1.80973; GrossVolume: 0.030519; NetVolume: 0.030519
Pset_BeamCommon - Reference: 40 x 230; Span: 3340 mm; Slope: 0 rad; Roll: 0 rad; IsExternal: no; LoadBearing: yes
Pset_ConcreteElementGeneral - ConstructionMethod: prefabricated
Pset_Condition - AssessmentCondition: Empty
Pset_EnvironmentalImpactIndicators - Reference: 40 x 230; sets with these values: 2

# IfcBeam: 28_SF_hout_rechthoekig_40 x 230_237, 28_SF_hout_rechthoekig:40 x 230:33582127
In: 010
PredefinedType: BEAM; Material: GVH_i2_naaldhout_generiek
Cpset_Beam - LevelOfAccuracy: in te vullen door Buildwise
IfcClassificationReference - TDS_link: .\05 As Builtdossier\2. Bouwkunde\2.2. Stabiliteit\2.2.0 technische fiche's\TF S 4.9.1.1.1 A - houten roostering sheddak.pdf
IfcElement - Tag: B1; Mark: B1
IfcRoot - Name: 40 x 230
Qto_BeamBaseQuantities - Length: 3340; CrossSectionArea: 0.0092; OuterSurfaceArea: 1.79133; GrossSurfaceArea: 1.80973; NetSurfaceArea: 1.80973; GrossVolume: 0.0305189; NetVolume: 0.0305189
Pset_BeamCommon - Reference: 40 x 230; Span: 3340 mm; Slope: 0 rad; Roll: 0 rad; IsExternal: no; LoadBearing: yes
Pset_ConcreteElementGeneral - ConstructionMethod: prefabricated
Pset_Condition - AssessmentCondition: Empty
Pset_EnvironmentalImpactIndicators - Reference: 40 x 230; sets with these values: 2

# IfcBeam: 28_SF_hout_rechthoekig_40 x 230_239, 28_SF_hout_rechthoekig:40 x 230:33582130
In: 010
PredefinedType: BEAM; Material: GVH_i2_naaldhout_generiek
Cpset_Beam - LevelOfAccuracy: in te vullen door Buildwise
IfcClassificationReference - TDS_link: .\05 As Builtdossier\2. Bouwkunde\2.2. Stabiliteit\2.2.0 technische fiche's\TF S 4.9.1.1.1 A - houten roostering sheddak.pdf
IfcElement - Tag: B1; Mark: B1
IfcRoot - Name: 40 x 230
Qto_BeamBaseQuantities - Length: 3340; CrossSectionArea: 0.0092; OuterSurfaceArea: 1.79133; GrossSurfaceArea: 1.80973; NetSurfaceArea: 1.80973; GrossVolume: 0.0305189; NetVolume: 0.0305189
Pset_BeamCommon - Reference: 40 x 230; Span: 3340 mm; Slope: 0 rad; Roll: 0 rad; IsExternal: no; LoadBearing: yes
Pset_ConcreteElementGeneral - ConstructionMethod: prefabricated
Pset_Condition - AssessmentCondition: Empty
Pset_EnvironmentalImpactIndicators - Reference: 40 x 230; sets with these values: 2

# IfcBeam: 28_SF_hout_rechthoekig_40 x 230_241, 28_SF_hout_rechthoekig:40 x 230:33582133
In: 010
PredefinedType: BEAM; Material: GVH_i2_naaldhout_generiek
Cpset_Beam - LevelOfAccuracy: in te vullen door Buildwise
IfcClassificationReference - TDS_link: .\05 As Builtdossier\2. Bouwkunde\2.2. Stabiliteit\2.2.0 technische fiche's\TF S 4.9.1.1.1 A - houten roostering sheddak.pdf
IfcElement - Tag: B1; Mark: B1
IfcRoot - Name: 40 x 230
Qto_BeamBaseQuantities - Length: 3340; CrossSectionArea: 0.0092; OuterSurfaceArea: 1.79133; GrossSurfaceArea: 1.80973; NetSurfaceArea: 1.80973; GrossVolume: 0.030519; NetVolume: 0.030519
Pset_BeamCommon - Reference: 40 x 230; Span: 3340 mm; Slope: 0 rad; Roll: 0 rad; IsExternal: no; LoadBearing: yes
Pset_ConcreteElementGeneral - ConstructionMethod: prefabricated
Pset_Condition - AssessmentCondition: Empty
Pset_EnvironmentalImpactIndicators - Reference: 40 x 230; sets with these values: 2

# IfcBeam: 28_SF_hout_rechthoekig_40 x 230_243, 28_SF_hout_rechthoekig:40 x 230:33582840
In: 010
PredefinedType: BEAM; Material: GVH_i2_naaldhout_generiek
Cpset_Beam - LevelOfAccuracy: in te vullen door Buildwise
IfcClassificationReference - TDS_link: .\05 As Builtdossier\2. Bouwkunde\2.2. Stabiliteit\2.2.0 technische fiche's\TF S 4.9.1.1.1 A - houten roostering sheddak.pdf
IfcElement - Tag: C1; Mark: C1
IfcRoot - Name: 40 x 230
Qto_BeamBaseQuantities - Length: 3400; CrossSectionArea: 0.0092; OuterSurfaceArea: 1.84533; GrossSurfaceArea: 1.86373; NetSurfaceArea: 1.86373; GrossVolume: 0.0314389; NetVolume: 0.0314389
Pset_BeamCommon - Reference: 40 x 230; Span: 3400 mm; Slope: 0 rad; Roll: 0 rad; IsExternal: no; LoadBearing: yes
Pset_ConcreteElementGeneral - ConstructionMethod: prefabricated
Pset_Condition - AssessmentCondition: Empty
Pset_EnvironmentalImpactIndicators - Reference: 40 x 230; sets with these values: 2

# IfcBeam: 28_SF_hout_rechthoekig_40 x 230_245, 28_SF_hout_rechthoekig:40 x 230:33582981
In: 010
PredefinedType: BEAM; Material: GVH_i2_naaldhout_generiek
Cpset_Beam - LevelOfAccuracy: in te vullen door Buildwise
IfcClassificationReference - TDS_link: .\05 As Builtdossier\2. Bouwkunde\2.2. Stabiliteit\2.2.0 technische fiche's\TF S 4.9.1.1.1 A - houten roostering sheddak.pdf
IfcElement - Tag: A10; Mark: A10
IfcRoot - Name: 40 x 230
Qto_BeamBaseQuantities - Length: 2660; CrossSectionArea: 0.0092; OuterSurfaceArea: 1.41232; GrossSurfaceArea: 1.43072; NetSurfaceArea: 1.43072; GrossVolume: 0.0240618; NetVolume: 0.0240618
Pset_BeamCommon - Reference: 40 x 230; Span: 2660 mm; Slope: 0 rad; Roll: 0 rad; IsExternal: no; LoadBearing: yes
Pset_ConcreteElementGeneral - ConstructionMethod: prefabricated
Pset_Condition - AssessmentCondition: Empty
Pset_EnvironmentalImpactIndicators - Reference: 40 x 230; sets with these values: 2

# IfcBeam: 28_SF_hout_rechthoekig_40 x 230_247, 28_SF_hout_rechthoekig:40 x 230:33582983
In: 010
PredefinedType: BEAM; Material: GVH_i2_naaldhout_generiek
Cpset_Beam - LevelOfAccuracy: in te vullen door Buildwise
IfcClassificationReference - TDS_link: .\05 As Builtdossier\2. Bouwkunde\2.2. Stabiliteit\2.2.0 technische fiche's\TF S 4.9.1.1.1 A - houten roostering sheddak.pdf
IfcElement - Tag: A11; Mark: A11
IfcRoot - Name: 40 x 230
Qto_BeamBaseQuantities - Length: 2360; CrossSectionArea: 0.0092; OuterSurfaceArea: 1.21986; GrossSurfaceArea: 1.23826; NetSurfaceArea: 1.23826; GrossVolume: 0.0207827; NetVolume: 0.0207827
Pset_BeamCommon - Reference: 40 x 230; Span: 2360 mm; Slope: 0 rad; Roll: 0 rad; IsExternal: no; LoadBearing: yes
Pset_ConcreteElementGeneral - ConstructionMethod: prefabricated
Pset_Condition - AssessmentCondition: Empty
Pset_EnvironmentalImpactIndicators - Reference: 40 x 230; sets with these values: 2

# IfcBeam: 28_SF_hout_rechthoekig_40 x 230_249, 28_SF_hout_rechthoekig:40 x 230:33582985
In: 010
PredefinedType: BEAM; Material: GVH_i2_naaldhout_generiek
Cpset_Beam - LevelOfAccuracy: in te vullen door Buildwise
IfcClassificationReference - TDS_link: .\05 As Builtdossier\2. Bouwkunde\2.2. Stabiliteit\2.2.0 technische fiche's\TF S 4.9.1.1.1 A - houten roostering sheddak.pdf
IfcElement - Tag: A12; Mark: A12
IfcRoot - Name: 40 x 230
Qto_BeamBaseQuantities - Length: 2020; CrossSectionArea: 0.0092; OuterSurfaceArea: 1.02739; GrossSurfaceArea: 1.04579; NetSurfaceArea: 1.04579; GrossVolume: 0.0175036; NetVolume: 0.0175036
Pset_BeamCommon - Reference: 40 x 230; Span: 2020 mm; Slope: 0 rad; Roll: 0 rad; IsExternal: no; LoadBearing: yes
Pset_ConcreteElementGeneral - ConstructionMethod: prefabricated
Pset_Condition - AssessmentCondition: Empty
Pset_EnvironmentalImpactIndicators - Reference: 40 x 230; sets with these values: 2

# IfcBeam: 28_SF_hout_rechthoekig_40 x 230_25, 28_SF_hout_rechthoekig:40 x 230:33579246
In: 010
PredefinedType: BEAM; Material: GVH_i2_naaldhout_generiek
Cpset_Beam - LevelOfAccuracy: in te vullen door Buildwise
IfcClassificationReference - TDS_link: .\05 As Builtdossier\2. Bouwkunde\2.2. Stabiliteit\2.2.0 technische fiche's\TF S 4.9.1.1.1 A - houten roostering sheddak.pdf
IfcElement - Tag: A22; Mark: A22
IfcRoot - Name: 40 x 230
Qto_BeamBaseQuantities - Length: 1540; CrossSectionArea: 0.0092; OuterSurfaceArea: 0.755568; GrossSurfaceArea: 0.773968; NetSurfaceArea: 0.773968; GrossVolume: 0.0128726; NetVolume: 0.0128726
Pset_BeamCommon - Reference: 40 x 230; Span: 1540 mm; Slope: 0 rad; Roll: 0 rad; IsExternal: no; LoadBearing: yes
Pset_ConcreteElementGeneral - ConstructionMethod: prefabricated
Pset_Condition - AssessmentCondition: Empty
Pset_EnvironmentalImpactIndicators - Reference: 40 x 230; sets with these values: 2

# IfcBeam: 28_SF_hout_rechthoekig_40 x 230_251, 28_SF_hout_rechthoekig:40 x 230:33582987
In: 010
PredefinedType: BEAM; Material: GVH_i2_naaldhout_generiek
Cpset_Beam - LevelOfAccuracy: in te vullen door Buildwise
IfcClassificationReference - TDS_link: .\05 As Builtdossier\2. Bouwkunde\2.2. Stabiliteit\2.2.0 technische fiche's\TF S 4.9.1.1.1 A - houten roostering sheddak.pdf
IfcElement - Tag: A13; Mark: A13
IfcRoot - Name: 40 x 230
Qto_BeamBaseQuantities - Length: 1700; CrossSectionArea: 0.0092; OuterSurfaceArea: 0.834919; GrossSurfaceArea: 0.853319; NetSurfaceArea: 0.853319; GrossVolume: 0.0142245; NetVolume: 0.0142245
Pset_BeamCommon - Reference: 40 x 230; Span: 1700 mm; Slope: 0 rad; Roll: 0 rad; IsExternal: no; LoadBearing: yes
Pset_ConcreteElementGeneral - ConstructionMethod: prefabricated
Pset_Condition - AssessmentCondition: Empty
Pset_EnvironmentalImpactIndicators - Reference: 40 x 230; sets with these values: 2

# IfcBeam: 28_SF_hout_rechthoekig_40 x 230_253, 28_SF_hout_rechthoekig:40 x 230:33582989
In: 010
PredefinedType: BEAM; Material: GVH_i2_naaldhout_generiek
Cpset_Beam - LevelOfAccuracy: in te vullen door Buildwise
IfcClassificationReference - TDS_link: .\05 As Builtdossier\2. Bouwkunde\2.2. Stabiliteit\2.2.0 technische fiche's\TF S 4.9.1.1.1 A - houten roostering sheddak.pdf
IfcElement - Tag: A14; Mark: A14
IfcRoot - Name: 40 x 230
Qto_BeamBaseQuantities - Length: 1320; CrossSectionArea: 0.0092; OuterSurfaceArea: 0.642451; GrossSurfaceArea: 0.660851; NetSurfaceArea: 0.660851; GrossVolume: 0.0109455; NetVolume: 0.0109455
Pset_BeamCommon - Reference: 40 x 230; Span: 1320 mm; Slope: 0 rad; Roll: 0 rad; IsExternal: no; LoadBearing: yes
Pset_ConcreteElementGeneral - ConstructionMethod: prefabricated
Pset_Condition - AssessmentCondition: Empty
Pset_EnvironmentalImpactIndicators - Reference: 40 x 230; sets with these values: 2

# IfcBeam: 28_SF_hout_rechthoekig_40 x 230_255, 28_SF_hout_rechthoekig:40 x 230:33582991
In: 010
PredefinedType: BEAM; Material: GVH_i2_naaldhout_generiek
Cpset_Beam - LevelOfAccuracy: in te vullen door Buildwise
IfcClassificationReference - TDS_link: .\05 As Builtdossier\2. Bouwkunde\2.2. Stabiliteit\2.2.0 technische fiche's\TF S 4.9.1.1.1 A - houten roostering sheddak.pdf
IfcElement - Tag: A15; Mark: A15
IfcRoot - Name: 40 x 230
Qto_BeamBaseQuantities - Length: 980; CrossSectionArea: 0.0092; OuterSurfaceArea: 0.449982; GrossSurfaceArea: 0.468382; NetSurfaceArea: 0.468382; GrossVolume: 0.00766637; NetVolume: 0.00766637
Pset_BeamCommon - Reference: 40 x 230; Span: 980 mm; Slope: 0 rad; Roll: 0 rad; IsExternal: no; LoadBearing: yes
Pset_ConcreteElementGeneral - ConstructionMethod: prefabricated
Pset_Condition - AssessmentCondition: Empty
Pset_EnvironmentalImpactIndicators - Reference: 40 x 230; sets with these values: 2

# IfcBeam: 28_SF_hout_rechthoekig_40 x 230_257, 28_SF_hout_rechthoekig:40 x 230:33582993
In: 010
PredefinedType: BEAM; Material: GVH_i2_naaldhout_generiek
Cpset_Beam - LevelOfAccuracy: in te vullen door Buildwise
IfcClassificationReference - TDS_link: .\05 As Builtdossier\2. Bouwkunde\2.2. Stabiliteit\2.2.0 technische fiche's\TF S 4.9.1.1.1 A - houten roostering sheddak.pdf
IfcElement - Tag: A16; Mark: A16
IfcRoot - Name: 40 x 230
Qto_BeamBaseQuantities - Length: 620; CrossSectionArea: 0.0092; OuterSurfaceArea: 0.257514; GrossSurfaceArea: 0.275914; NetSurfaceArea: 0.275914; GrossVolume: 0.00438728; NetVolume: 0.00438728
Pset_BeamCommon - Reference: 40 x 230; Span: 620 mm; Slope: 0 rad; Roll: 0 rad; IsExternal: no; LoadBearing: yes
Pset_ConcreteElementGeneral - ConstructionMethod: prefabricated
Pset_Condition - AssessmentCondition: Empty
Pset_EnvironmentalImpactIndicators - Reference: 40 x 230; sets with these values: 2

# IfcBeam: 28_SF_hout_rechthoekig_40 x 230_259, 28_SF_hout_rechthoekig:40 x 230:33583429
In: 010
PredefinedType: BEAM; Material: GVH_i2_naaldhout_generiek
Cpset_Beam - LevelOfAccuracy: in te vullen door Buildwise
IfcClassificationReference - TDS_link: .\05 As Builtdossier\2. Bouwkunde\2.2. Stabiliteit\2.2.0 technische fiche's\TF S 4.9.1.1.1 A - houten roostering sheddak.pdf
IfcElement - Tag: B1; Mark: B1
IfcRoot - Name: 40 x 230
Qto_BeamBaseQuantities - Length: 3340; CrossSectionArea: 0.0092; OuterSurfaceArea: 1.79133; GrossSurfaceArea: 1.80973; NetSurfaceArea: 1.80973; GrossVolume: 0.0305189; NetVolume: 0.0305189
Pset_BeamCommon - Reference: 40 x 230; Span: 3340 mm; Slope: 0 rad; Roll: 0 rad; IsExternal: no; LoadBearing: yes
Pset_ConcreteElementGeneral - ConstructionMethod: prefabricated
Pset_Condition - AssessmentCondition: Empty
Pset_EnvironmentalImpactIndicators - Reference: 40 x 230; sets with these values: 2

# IfcBeam: 28_SF_hout_rechthoekig_40 x 230_261, 28_SF_hout_rechthoekig:40 x 230:33583431
In: 010
PredefinedType: BEAM; Material: GVH_i2_naaldhout_generiek
Cpset_Beam - LevelOfAccuracy: in te vullen door Buildwise
IfcClassificationReference - TDS_link: .\05 As Builtdossier\2. Bouwkunde\2.2. Stabiliteit\2.2.0 technische fiche's\TF S 4.9.1.1.1 A - houten roostering sheddak.pdf
IfcElement - Tag: B1; Mark: B1
IfcRoot - Name: 40 x 230
Qto_BeamBaseQuantities - Length: 3340; CrossSectionArea: 0.0092; OuterSurfaceArea: 1.79133; GrossSurfaceArea: 1.80973; NetSurfaceArea: 1.80973; GrossVolume: 0.0305189; NetVolume: 0.0305189
Pset_BeamCommon - Reference: 40 x 230; Span: 3340 mm; Slope: 0 rad; Roll: 0 rad; IsExternal: no; LoadBearing: yes
Pset_ConcreteElementGeneral - ConstructionMethod: prefabricated
Pset_Condition - AssessmentCondition: Empty
Pset_EnvironmentalImpactIndicators - Reference: 40 x 230; sets with these values: 2

# IfcBeam: 28_SF_hout_rechthoekig_40 x 230_263, 28_SF_hout_rechthoekig:40 x 230:33583433
In: 010
PredefinedType: BEAM; Material: GVH_i2_naaldhout_generiek
Cpset_Beam - LevelOfAccuracy: in te vullen door Buildwise
IfcClassificationReference - TDS_link: .\05 As Builtdossier\2. Bouwkunde\2.2. Stabiliteit\2.2.0 technische fiche's\TF S 4.9.1.1.1 A - houten roostering sheddak.pdf
IfcElement - Tag: B1; Mark: B1
IfcRoot - Name: 40 x 230
Qto_BeamBaseQuantities - Length: 3340; CrossSectionArea: 0.0092; OuterSurfaceArea: 1.79133; GrossSurfaceArea: 1.80973; NetSurfaceArea: 1.80973; GrossVolume: 0.0305189; NetVolume: 0.0305189
Pset_BeamCommon - Reference: 40 x 230; Span: 3340 mm; Slope: 0 rad; Roll: 0 rad; IsExternal: no; LoadBearing: yes
Pset_ConcreteElementGeneral - ConstructionMethod: prefabricated
Pset_Condition - AssessmentCondition: Empty
Pset_EnvironmentalImpactIndicators - Reference: 40 x 230; sets with these values: 2

# IfcBeam: 28_SF_hout_rechthoekig_40 x 230_265, 28_SF_hout_rechthoekig:40 x 230:33583435
In: 010
PredefinedType: BEAM; Material: GVH_i2_naaldhout_generiek
Cpset_Beam - LevelOfAccuracy: in te vullen door Buildwise
IfcClassificationReference - TDS_link: .\05 As Builtdossier\2. Bouwkunde\2.2. Stabiliteit\2.2.0 technische fiche's\TF S 4.9.1.1.1 A - houten roostering sheddak.pdf
IfcElement - Tag: B1; Mark: B1
IfcRoot - Name: 40 x 230
Qto_BeamBaseQuantities - Length: 3340; CrossSectionArea: 0.0092; OuterSurfaceArea: 1.79133; GrossSurfaceArea: 1.80973; NetSurfaceArea: 1.80973; GrossVolume: 0.0305189; NetVolume: 0.0305189
Pset_BeamCommon - Reference: 40 x 230; Span: 3340 mm; Slope: 0 rad; Roll: 0 rad; IsExternal: no; LoadBearing: yes
Pset_ConcreteElementGeneral - ConstructionMethod: prefabricated
Pset_Condition - AssessmentCondition: Empty
Pset_EnvironmentalImpactIndicators - Reference: 40 x 230; sets with these values: 2

# IfcBeam: 28_SF_hout_rechthoekig_40 x 230_267, 28_SF_hout_rechthoekig:40 x 230:33583437
In: 010
PredefinedType: BEAM; Material: GVH_i2_naaldhout_generiek
Cpset_Beam - LevelOfAccuracy: in te vullen door Buildwise
IfcClassificationReference - TDS_link: .\05 As Builtdossier\2. Bouwkunde\2.2. Stabiliteit\2.2.0 technische fiche's\TF S 4.9.1.1.1 A - houten roostering sheddak.pdf
IfcElement - Tag: B1; Mark: B1
IfcRoot - Name: 40 x 230
Qto_BeamBaseQuantities - Length: 3340; CrossSectionArea: 0.0092; OuterSurfaceArea: 1.79133; GrossSurfaceArea: 1.80973; NetSurfaceArea: 1.80973; GrossVolume: 0.0305189; NetVolume: 0.0305189
Pset_BeamCommon - Reference: 40 x 230; Span: 3340 mm; Slope: 0 rad; Roll: 0 rad; IsExternal: no; LoadBearing: yes
Pset_ConcreteElementGeneral - ConstructionMethod: prefabricated
Pset_Condition - AssessmentCondition: Empty
Pset_EnvironmentalImpactIndicators - Reference: 40 x 230; sets with these values: 2

# IfcBeam: 28_SF_hout_rechthoekig_40 x 230_269, 28_SF_hout_rechthoekig:40 x 230:33583439
In: 010
PredefinedType: BEAM; Material: GVH_i2_naaldhout_generiek
Cpset_Beam - LevelOfAccuracy: in te vullen door Buildwise
IfcClassificationReference - TDS_link: .\05 As Builtdossier\2. Bouwkunde\2.2. Stabiliteit\2.2.0 technische fiche's\TF S 4.9.1.1.1 A - houten roostering sheddak.pdf
IfcElement - Tag: B1; Mark: B1
IfcRoot - Name: 40 x 230
Qto_BeamBaseQuantities - Length: 3340; CrossSectionArea: 0.0092; OuterSurfaceArea: 1.79133; GrossSurfaceArea: 1.80973; NetSurfaceArea: 1.80973; GrossVolume: 0.0305189; NetVolume: 0.0305189
Pset_BeamCommon - Reference: 40 x 230; Span: 3340 mm; Slope: 0 rad; Roll: 0 rad; IsExternal: no; LoadBearing: yes
Pset_ConcreteElementGeneral - ConstructionMethod: prefabricated
Pset_Condition - AssessmentCondition: Empty
Pset_EnvironmentalImpactIndicators - Reference: 40 x 230; sets with these values: 2

# IfcBeam: 28_SF_hout_rechthoekig_40 x 230_27, 28_SF_hout_rechthoekig:40 x 230:33579249
In: 010
PredefinedType: BEAM; Material: GVH_i2_naaldhout_generiek
Cpset_Beam - LevelOfAccuracy: in te vullen door Buildwise
IfcClassificationReference - TDS_link: .\05 As Builtdossier\2. Bouwkunde\2.2. Stabiliteit\2.2.0 technische fiche's\TF S 4.9.1.1.1 A - houten roostering sheddak.pdf
IfcElement - Tag: A23; Mark: A23
IfcRoot - Name: 40 x 230
Qto_BeamBaseQuantities - Length: 1180; CrossSectionArea: 0.0092; OuterSurfaceArea: 0.5631; GrossSurfaceArea: 0.5815; NetSurfaceArea: 0.5815; GrossVolume: 0.00959356; NetVolume: 0.00959356
Pset_BeamCommon - Reference: 40 x 230; Span: 1180 mm; Slope: 0 rad; Roll: 0 rad; IsExternal: no; LoadBearing: yes
Pset_ConcreteElementGeneral - ConstructionMethod: prefabricated
Pset_Condition - AssessmentCondition: Empty
Pset_EnvironmentalImpactIndicators - Reference: 40 x 230; sets with these values: 2

# IfcBeam: 28_SF_hout_rechthoekig_40 x 230_271, 28_SF_hout_rechthoekig:40 x 230:33583441
In: 010
PredefinedType: BEAM; Material: GVH_i2_naaldhout_generiek
Cpset_Beam - LevelOfAccuracy: in te vullen door Buildwise
IfcClassificationReference - TDS_link: .\05 As Builtdossier\2. Bouwkunde\2.2. Stabiliteit\2.2.0 technische fiche's\TF S 4.9.1.1.1 A - houten roostering sheddak.pdf
IfcElement - Tag: B1; Mark: B1
IfcRoot - Name: 40 x 230
Qto_BeamBaseQuantities - Length: 3340; CrossSectionArea: 0.0092; OuterSurfaceArea: 1.79133; GrossSurfaceArea: 1.80973; NetSurfaceArea: 1.80973; GrossVolume: 0.0305189; NetVolume: 0.0305189
Pset_BeamCommon - Reference: 40 x 230; Span: 3340 mm; Slope: 0 rad; Roll: 0 rad; IsExternal: no; LoadBearing: yes
Pset_ConcreteElementGeneral - ConstructionMethod: prefabricated
Pset_Condition - AssessmentCondition: Empty
Pset_EnvironmentalImpactIndicators - Reference: 40 x 230; sets with these values: 2

# IfcBeam: 28_SF_hout_rechthoekig_40 x 230_273, 28_SF_hout_rechthoekig:40 x 230:33583443
In: 010
PredefinedType: BEAM; Material: GVH_i2_naaldhout_generiek
Cpset_Beam - LevelOfAccuracy: in te vullen door Buildwise
IfcClassificationReference - TDS_link: .\05 As Builtdossier\2. Bouwkunde\2.2. Stabiliteit\2.2.0 technische fiche's\TF S 4.9.1.1.1 A - houten roostering sheddak.pdf
IfcElement - Tag: B1; Mark: B1
IfcRoot - Name: 40 x 230
Qto_BeamBaseQuantities - Length: 3340; CrossSectionArea: 0.0092; OuterSurfaceArea: 1.79133; GrossSurfaceArea: 1.80973; NetSurfaceArea: 1.80973; GrossVolume: 0.0305189; NetVolume: 0.0305189
Pset_BeamCommon - Reference: 40 x 230; Span: 3340 mm; Slope: 0 rad; Roll: 0 rad; IsExternal: no; LoadBearing: yes
Pset_ConcreteElementGeneral - ConstructionMethod: prefabricated
Pset_Condition - AssessmentCondition: Empty
Pset_EnvironmentalImpactIndicators - Reference: 40 x 230; sets with these values: 2

# IfcBeam: 28_SF_hout_rechthoekig_40 x 230_275, 28_SF_hout_rechthoekig:40 x 230:33583445
In: 010
PredefinedType: BEAM; Material: GVH_i2_naaldhout_generiek
Cpset_Beam - LevelOfAccuracy: in te vullen door Buildwise
IfcClassificationReference - TDS_link: .\05 As Builtdossier\2. Bouwkunde\2.2. Stabiliteit\2.2.0 technische fiche's\TF S 4.9.1.1.1 A - houten roostering sheddak.pdf
IfcElement - Tag: A17; Mark: A17
IfcRoot - Name: 40 x 230
Qto_BeamBaseQuantities - Length: 3240; CrossSectionArea: 0.0092; OuterSurfaceArea: 1.71813; GrossSurfaceArea: 1.73653; NetSurfaceArea: 1.73653; GrossVolume: 0.0292719; NetVolume: 0.0292719
Pset_BeamCommon - Reference: 40 x 230; Span: 3240 mm; Slope: 0 rad; Roll: 0 rad; IsExternal: no; LoadBearing: yes
Pset_ConcreteElementGeneral - ConstructionMethod: prefabricated
Pset_Condition - AssessmentCondition: Empty
Pset_EnvironmentalImpactIndicators - Reference: 40 x 230; sets with these values: 2

# IfcBeam: 28_SF_hout_rechthoekig_40 x 230_277, 28_SF_hout_rechthoekig:40 x 230:33583447
In: 010
PredefinedType: BEAM; Material: GVH_i2_naaldhout_generiek
Cpset_Beam - LevelOfAccuracy: in te vullen door Buildwise
IfcClassificationReference - TDS_link: .\05 As Builtdossier\2. Bouwkunde\2.2. Stabiliteit\2.2.0 technische fiche's\TF S 4.9.1.1.1 A - houten roostering sheddak.pdf
IfcElement - Tag: A18; Mark: A18
IfcRoot - Name: 40 x 230
Qto_BeamBaseQuantities - Length: 2820; CrossSectionArea: 0.0092; OuterSurfaceArea: 1.52544; GrossSurfaceArea: 1.54384; NetSurfaceArea: 1.54384; GrossVolume: 0.025989; NetVolume: 0.025989
Pset_BeamCommon - Reference: 40 x 230; Span: 2820 mm; Slope: 0 rad; Roll: 0 rad; IsExternal: no; LoadBearing: yes
Pset_ConcreteElementGeneral - ConstructionMethod: prefabricated
Pset_Condition - AssessmentCondition: Empty
Pset_EnvironmentalImpactIndicators - Reference: 40 x 230; sets with these values: 2

# IfcBeam: 28_SF_hout_rechthoekig_40 x 230_279, 28_SF_hout_rechthoekig:40 x 230:33583449
In: 010
PredefinedType: BEAM; Material: GVH_i2_naaldhout_generiek
Cpset_Beam - LevelOfAccuracy: in te vullen door Buildwise
IfcClassificationReference - TDS_link: .\05 As Builtdossier\2. Bouwkunde\2.2. Stabiliteit\2.2.0 technische fiche's\TF S 4.9.1.1.1 A - houten roostering sheddak.pdf
IfcElement - Tag: A19; Mark: A19
IfcRoot - Name: 40 x 230
Qto_BeamBaseQuantities - Length: 2460; CrossSectionArea: 0.0092; OuterSurfaceArea: 1.33297; GrossSurfaceArea: 1.35137; NetSurfaceArea: 1.35137; GrossVolume: 0.0227099; NetVolume: 0.0227099
Pset_BeamCommon - Reference: 40 x 230; Span: 2460 mm; Slope: 0 rad; Roll: 0 rad; IsExternal: no; LoadBearing: yes
Pset_ConcreteElementGeneral - ConstructionMethod: prefabricated
Pset_Condition - AssessmentCondition: Empty
Pset_EnvironmentalImpactIndicators - Reference: 40 x 230; sets with these values: 2

# IfcBeam: 28_SF_hout_rechthoekig_40 x 230_281, 28_SF_hout_rechthoekig:40 x 230:33583451
In: 010
PredefinedType: BEAM; Material: GVH_i2_naaldhout_generiek
Cpset_Beam - LevelOfAccuracy: in te vullen door Buildwise
IfcClassificationReference - TDS_link: .\05 As Builtdossier\2. Bouwkunde\2.2. Stabiliteit\2.2.0 technische fiche's\TF S 4.9.1.1.1 A - houten roostering sheddak.pdf
IfcElement - Tag: A20; Mark: A20
IfcRoot - Name: 40 x 230
Qto_BeamBaseQuantities - Length: 2100; CrossSectionArea: 0.0092; OuterSurfaceArea: 1.1405; GrossSurfaceArea: 1.1589; NetSurfaceArea: 1.1589; GrossVolume: 0.0194308; NetVolume: 0.0194308
Pset_BeamCommon - Reference: 40 x 230; Span: 2100 mm; Slope: 0 rad; Roll: 0 rad; IsExternal: no; LoadBearing: yes
Pset_ConcreteElementGeneral - ConstructionMethod: prefabricated
Pset_Condition - AssessmentCondition: Empty
Pset_EnvironmentalImpactIndicators - Reference: 40 x 230; sets with these values: 2

# IfcBeam: 28_SF_hout_rechthoekig_40 x 230_283, 28_SF_hout_rechthoekig:40 x 230:33583453
In: 010
PredefinedType: BEAM; Material: GVH_i2_naaldhout_generiek
Cpset_Beam - LevelOfAccuracy: in te vullen door Buildwise
IfcClassificationReference - TDS_link: .\05 As Builtdossier\2. Bouwkunde\2.2. Stabiliteit\2.2.0 technische fiche's\TF S 4.9.1.1.1 A - houten roostering sheddak.pdf
IfcElement - Tag: A21; Mark: A21
IfcRoot - Name: 40 x 230
Qto_BeamBaseQuantities - Length: 1760; CrossSectionArea: 0.0092; OuterSurfaceArea: 0.948035; GrossSurfaceArea: 0.966435; NetSurfaceArea: 0.966435; GrossVolume: 0.0161517; NetVolume: 0.0161517
Pset_BeamCommon - Reference: 40 x 230; Span: 1760 mm; Slope: 0 rad; Roll: 0 rad; IsExternal: no; LoadBearing: yes
Pset_ConcreteElementGeneral - ConstructionMethod: prefabricated
Pset_Condition - AssessmentCondition: Empty
Pset_EnvironmentalImpactIndicators - Reference: 40 x 230; sets with these values: 2

# IfcBeam: 28_SF_hout_rechthoekig_40 x 230_285, 28_SF_hout_rechthoekig:40 x 230:33583455
In: 010
PredefinedType: BEAM; Material: GVH_i2_naaldhout_generiek
Cpset_Beam - LevelOfAccuracy: in te vullen door Buildwise
IfcClassificationReference - TDS_link: .\05 As Builtdossier\2. Bouwkunde\2.2. Stabiliteit\2.2.0 technische fiche's\TF S 4.9.1.1.1 A - houten roostering sheddak.pdf
IfcElement - Tag: A22; Mark: A22
IfcRoot - Name: 40 x 230
Qto_BeamBaseQuantities - Length: 1420; CrossSectionArea: 0.0092; OuterSurfaceArea: 0.755567; GrossSurfaceArea: 0.773967; NetSurfaceArea: 0.773967; GrossVolume: 0.0128726; NetVolume: 0.0128726
Pset_BeamCommon - Reference: 40 x 230; Span: 1420 mm; Slope: 0 rad; Roll: 0 rad; IsExternal: no; LoadBearing: yes
Pset_ConcreteElementGeneral - ConstructionMethod: prefabricated
Pset_Condition - AssessmentCondition: Empty
Pset_EnvironmentalImpactIndicators - Reference: 40 x 230; sets with these values: 2

# IfcBeam: 28_SF_hout_rechthoekig_40 x 230_287, 28_SF_hout_rechthoekig:40 x 230:33583457
In: 010
PredefinedType: BEAM; Material: GVH_i2_naaldhout_generiek
Cpset_Beam - LevelOfAccuracy: in te vullen door Buildwise
IfcClassificationReference - TDS_link: .\05 As Builtdossier\2. Bouwkunde\2.2. Stabiliteit\2.2.0 technische fiche's\TF S 4.9.1.1.1 A - houten roostering sheddak.pdf
IfcElement - Tag: A23; Mark: A23
IfcRoot - Name: 40 x 230
Qto_BeamBaseQuantities - Length: 1060; CrossSectionArea: 0.0092; OuterSurfaceArea: 0.563098; GrossSurfaceArea: 0.581498; NetSurfaceArea: 0.581498; GrossVolume: 0.00959353; NetVolume: 0.00959353
Pset_BeamCommon - Reference: 40 x 230; Span: 1060 mm; Slope: 0 rad; Roll: 0 rad; IsExternal: no; LoadBearing: yes
Pset_ConcreteElementGeneral - ConstructionMethod: prefabricated
Pset_Condition - AssessmentCondition: Empty
Pset_EnvironmentalImpactIndicators - Reference: 40 x 230; sets with these values: 2

# IfcBeam: 28_SF_hout_rechthoekig_40 x 230_289, 28_SF_hout_rechthoekig:40 x 230:33583459
In: 010
PredefinedType: BEAM; Material: GVH_i2_naaldhout_generiek
Cpset_Beam - LevelOfAccuracy: in te vullen door Buildwise
IfcClassificationReference - TDS_link: .\05 As Builtdossier\2. Bouwkunde\2.2. Stabiliteit\2.2.0 technische fiche's\TF S 4.9.1.1.1 A - houten roostering sheddak.pdf
IfcElement - Tag: A24; Mark: A24
IfcRoot - Name: 40 x 230
Qto_BeamBaseQuantities - Length: 720; CrossSectionArea: 0.0092; OuterSurfaceArea: 0.370372; GrossSurfaceArea: 0.388772; NetSurfaceArea: 0.388772; GrossVolume: 0.00631004; NetVolume: 0.00631004
Pset_BeamCommon - Reference: 40 x 230; Span: 720 mm; Slope: 0 rad; Roll: 0 rad; IsExternal: no; LoadBearing: yes
Pset_ConcreteElementGeneral - ConstructionMethod: prefabricated
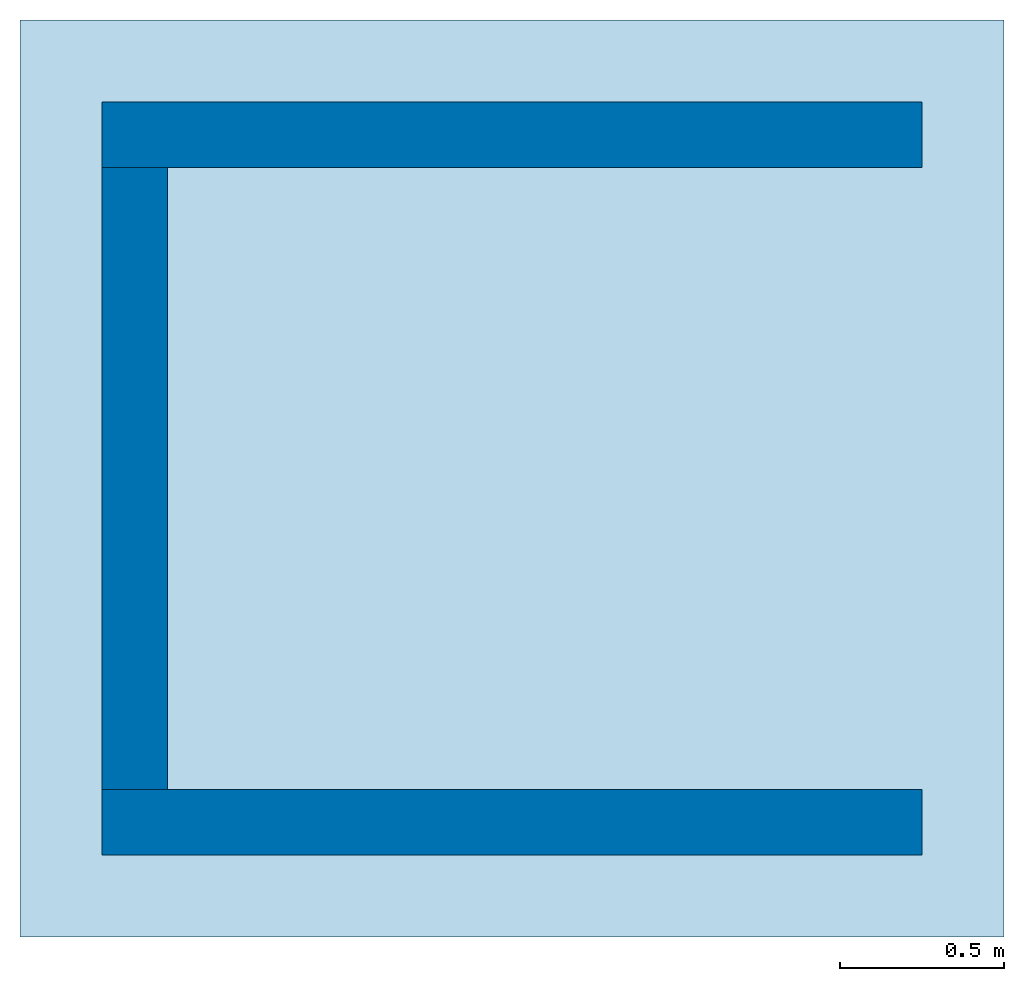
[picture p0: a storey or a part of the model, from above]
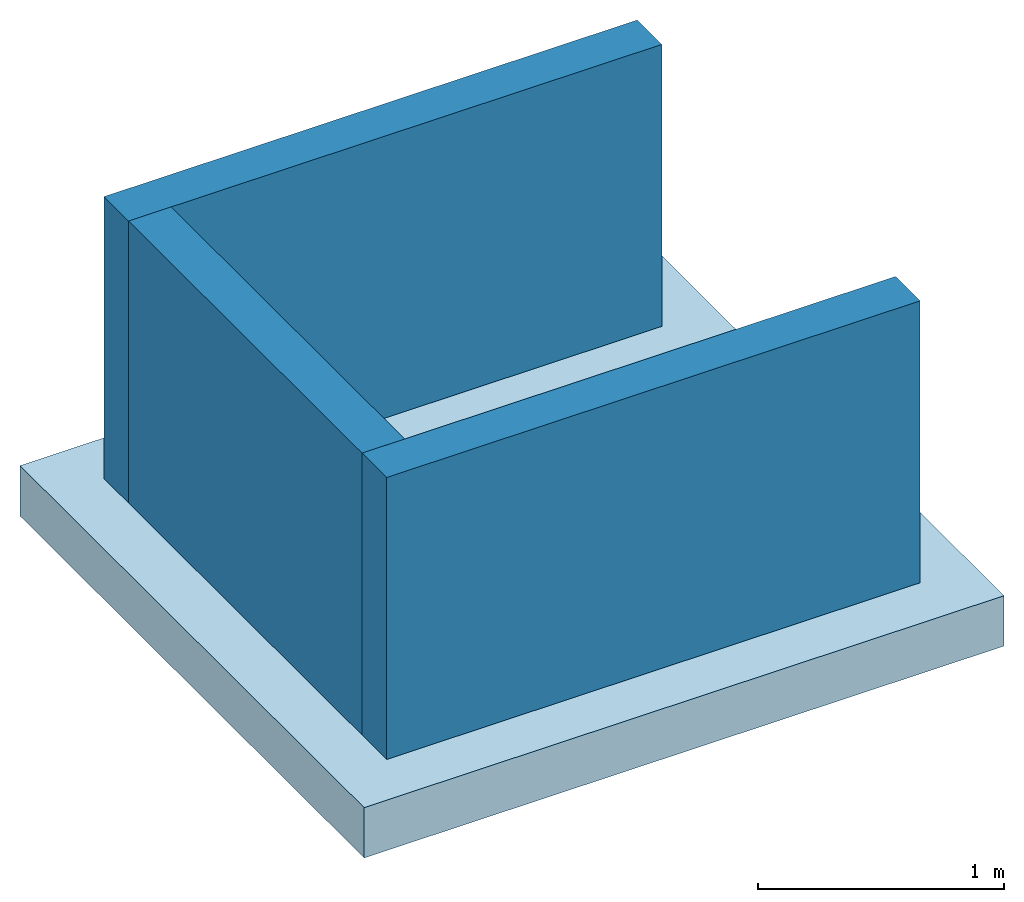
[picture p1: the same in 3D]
Properties of the parts of a building model (IFC4X3_ADD2), part 3 of 28

# IfcBeam: 28_SF_hout_rechthoekig_40 x 230_289, 28_SF_hout_rechthoekig:40 x 230:33583459
Pset_Condition - AssessmentCondition: Empty
Pset_EnvironmentalImpactIndicators - Reference: 40 x 230; sets with these values: 2

# IfcBeam: 28_SF_hout_rechthoekig_40 x 230_29, 28_SF_hout_rechthoekig:40 x 230:33579252
In: 010
PredefinedType: BEAM; Material: GVH_i2_naaldhout_generiek
Cpset_Beam - LevelOfAccuracy: in te vullen door Buildwise
IfcClassificationReference - TDS_link: .\05 As Builtdossier\2. Bouwkunde\2.2. Stabiliteit\2.2.0 technische fiche's\TF S 4.9.1.1.1 A - houten roostering sheddak.pdf
IfcElement - Tag: A24; Mark: A24
IfcRoot - Name: 40 x 230
Qto_BeamBaseQuantities - Length: 837.49; CrossSectionArea: 0.0092; OuterSurfaceArea: 0.370632; GrossSurfaceArea: 0.389032; NetSurfaceArea: 0.389032; GrossVolume: 0.00631447; NetVolume: 0.00631447
Pset_BeamCommon - Reference: 40 x 230; Span: 837.49 mm; Slope: 0 rad; Roll: 0 rad; IsExternal: no; LoadBearing: yes
Pset_ConcreteElementGeneral - ConstructionMethod: prefabricated
Pset_Condition - AssessmentCondition: Empty
Pset_EnvironmentalImpactIndicators - Reference: 40 x 230; sets with these values: 2

# IfcBeam: 28_SF_hout_rechthoekig_40 x 230_291, 28_SF_hout_rechthoekig:40 x 230:33584055
In: 010
PredefinedType: BEAM; Material: GVH_i2_naaldhout_generiek
Cpset_Beam - LevelOfAccuracy: in te vullen door Buildwise
IfcClassificationReference - TDS_link: .\05 As Builtdossier\2. Bouwkunde\2.2. Stabiliteit\2.2.0 technische fiche's\TF S 4.9.1.1.1 A - houten roostering sheddak.pdf
IfcElement - Tag: A10; Mark: A10
IfcRoot - Name: 40 x 230
Qto_BeamBaseQuantities - Length: 2640; CrossSectionArea: 0.0092; OuterSurfaceArea: 1.41233; GrossSurfaceArea: 1.43073; NetSurfaceArea: 1.43073; GrossVolume: 0.024062; NetVolume: 0.024062
Pset_BeamCommon - Reference: 40 x 230; Span: 2640 mm; Slope: 0 rad; Roll: 0 rad; IsExternal: no; LoadBearing: yes
Pset_ConcreteElementGeneral - ConstructionMethod: prefabricated
Pset_Condition - AssessmentCondition: Empty
Pset_EnvironmentalImpactIndicators - Reference: 40 x 230; sets with these values: 2

# IfcBeam: 28_SF_hout_rechthoekig_40 x 230_293, 28_SF_hout_rechthoekig:40 x 230:33584057
In: 010
PredefinedType: BEAM; Material: GVH_i2_naaldhout_generiek
Cpset_Beam - LevelOfAccuracy: in te vullen door Buildwise
IfcClassificationReference - TDS_link: .\05 As Builtdossier\2. Bouwkunde\2.2. Stabiliteit\2.2.0 technische fiche's\TF S 4.9.1.1.1 A - houten roostering sheddak.pdf
IfcElement - Tag: A11; Mark: A11
IfcRoot - Name: 40 x 230
Qto_BeamBaseQuantities - Length: 2260; CrossSectionArea: 0.0092; OuterSurfaceArea: 1.21986; GrossSurfaceArea: 1.23826; NetSurfaceArea: 1.23826; GrossVolume: 0.0207828; NetVolume: 0.0207828
Pset_BeamCommon - Reference: 40 x 230; Span: 2260 mm; Slope: 0 rad; Roll: 0 rad; IsExternal: no; LoadBearing: yes
Pset_ConcreteElementGeneral - ConstructionMethod: prefabricated
Pset_Condition - AssessmentCondition: Empty
Pset_EnvironmentalImpactIndicators - Reference: 40 x 230; sets with these values: 2

# IfcBeam: 28_SF_hout_rechthoekig_40 x 230_295, 28_SF_hout_rechthoekig:40 x 230:33584059
In: 010
PredefinedType: BEAM; Material: GVH_i2_naaldhout_generiek
Cpset_Beam - LevelOfAccuracy: in te vullen door Buildwise
IfcClassificationReference - TDS_link: .\05 As Builtdossier\2. Bouwkunde\2.2. Stabiliteit\2.2.0 technische fiche's\TF S 4.9.1.1.1 A - houten roostering sheddak.pdf
IfcElement - Tag: A12; Mark: A12
IfcRoot - Name: 40 x 230
Qto_BeamBaseQuantities - Length: 1920; CrossSectionArea: 0.0092; OuterSurfaceArea: 1.02739; GrossSurfaceArea: 1.04579; NetSurfaceArea: 1.04579; GrossVolume: 0.0175037; NetVolume: 0.0175037
Pset_BeamCommon - Reference: 40 x 230; Span: 1920 mm; Slope: 0 rad; Roll: 0 rad; IsExternal: no; LoadBearing: yes
Pset_ConcreteElementGeneral - ConstructionMethod: prefabricated
Pset_Condition - AssessmentCondition: Empty
Pset_EnvironmentalImpactIndicators - Reference: 40 x 230; sets with these values: 2

# IfcBeam: 28_SF_hout_rechthoekig_40 x 230_297, 28_SF_hout_rechthoekig:40 x 230:33584061
In: 010
PredefinedType: BEAM; Material: GVH_i2_naaldhout_generiek
Cpset_Beam - LevelOfAccuracy: in te vullen door Buildwise
IfcClassificationReference - TDS_link: .\05 As Builtdossier\2. Bouwkunde\2.2. Stabiliteit\2.2.0 technische fiche's\TF S 4.9.1.1.1 A - houten roostering sheddak.pdf
IfcElement - Tag: A13; Mark: A13
IfcRoot - Name: 40 x 230
Qto_BeamBaseQuantities - Length: 1560; CrossSectionArea: 0.0092; OuterSurfaceArea: 0.834924; GrossSurfaceArea: 0.853324; NetSurfaceArea: 0.853324; GrossVolume: 0.0142246; NetVolume: 0.0142246
Pset_BeamCommon - Reference: 40 x 230; Span: 1560 mm; Slope: 0 rad; Roll: 0 rad; IsExternal: no; LoadBearing: yes
Pset_ConcreteElementGeneral - ConstructionMethod: prefabricated
Pset_Condition - AssessmentCondition: Empty
Pset_EnvironmentalImpactIndicators - Reference: 40 x 230; sets with these values: 2

# IfcBeam: 28_SF_hout_rechthoekig_40 x 230_299, 28_SF_hout_rechthoekig:40 x 230:33584063
In: 010
PredefinedType: BEAM; Material: GVH_i2_naaldhout_generiek
Cpset_Beam - LevelOfAccuracy: in te vullen door Buildwise
IfcClassificationReference - TDS_link: .\05 As Builtdossier\2. Bouwkunde\2.2. Stabiliteit\2.2.0 technische fiche's\TF S 4.9.1.1.1 A - houten roostering sheddak.pdf
IfcElement - Tag: A14; Mark: A14
IfcRoot - Name: 40 x 230
Qto_BeamBaseQuantities - Length: 1220; CrossSectionArea: 0.0092; OuterSurfaceArea: 0.642455; GrossSurfaceArea: 0.660855; NetSurfaceArea: 0.660855; GrossVolume: 0.0109455; NetVolume: 0.0109455
Pset_BeamCommon - Reference: 40 x 230; Span: 1220 mm; Slope: 0 rad; Roll: 0 rad; IsExternal: no; LoadBearing: yes
Pset_ConcreteElementGeneral - ConstructionMethod: prefabricated
Pset_Condition - AssessmentCondition: Empty
Pset_EnvironmentalImpactIndicators - Reference: 40 x 230; sets with these values: 2

# IfcBeam: 28_SF_hout_rechthoekig_40 x 230_3, 28_SF_hout_rechthoekig:40 x 230:33579213
In: 010
PredefinedType: BEAM; Material: GVH_i2_naaldhout_generiek
Cpset_Beam - LevelOfAccuracy: in te vullen door Buildwise
IfcClassificationReference - TDS_link: .\05 As Builtdossier\2. Bouwkunde\2.2. Stabiliteit\2.2.0 technische fiche's\TF S 4.9.1.1.1 A - houten roostering sheddak.pdf
IfcElement - Tag: B1; Mark: B1
IfcRoot - Name: 40 x 230
Qto_BeamBaseQuantities - Length: 3440; CrossSectionArea: 0.0092; OuterSurfaceArea: 1.79133; GrossSurfaceArea: 1.80973; NetSurfaceArea: 1.80973; GrossVolume: 0.030519; NetVolume: 0.030519
Pset_BeamCommon - Reference: 40 x 230; Span: 3440 mm; Slope: 0 rad; Roll: 0 rad; IsExternal: no; LoadBearing: yes
Pset_ConcreteElementGeneral - ConstructionMethod: prefabricated
Pset_Condition - AssessmentCondition: Empty
Pset_EnvironmentalImpactIndicators - Reference: 40 x 230; sets with these values: 2

# IfcBeam: 28_SF_hout_rechthoekig_40 x 230_301, 28_SF_hout_rechthoekig:40 x 230:33584065
In: 010
PredefinedType: BEAM; Material: GVH_i2_naaldhout_generiek
Cpset_Beam - LevelOfAccuracy: in te vullen door Buildwise
IfcClassificationReference - TDS_link: .\05 As Builtdossier\2. Bouwkunde\2.2. Stabiliteit\2.2.0 technische fiche's\TF S 4.9.1.1.1 A - houten roostering sheddak.pdf
IfcElement - Tag: A15; Mark: A15
IfcRoot - Name: 40 x 230
Qto_BeamBaseQuantities - Length: 900; CrossSectionArea: 0.0092; OuterSurfaceArea: 0.449987; GrossSurfaceArea: 0.468387; NetSurfaceArea: 0.468387; GrossVolume: 0.00766645; NetVolume: 0.00766645
Pset_BeamCommon - Reference: 40 x 230; Span: 900 mm; Slope: 0 rad; Roll: 0 rad; IsExternal: no; LoadBearing: yes
Pset_ConcreteElementGeneral - ConstructionMethod: prefabricated
Pset_Condition - AssessmentCondition: Empty
Pset_EnvironmentalImpactIndicators - Reference: 40 x 230; sets with these values: 2

# IfcBeam: 28_SF_hout_rechthoekig_40 x 230_303, 28_SF_hout_rechthoekig:40 x 230:33584067
In: 010
PredefinedType: BEAM; Material: GVH_i2_naaldhout_generiek
Cpset_Beam - LevelOfAccuracy: in te vullen door Buildwise
IfcClassificationReference - TDS_link: .\05 As Builtdossier\2. Bouwkunde\2.2. Stabiliteit\2.2.0 technische fiche's\TF S 4.9.1.1.1 A - houten roostering sheddak.pdf
IfcElement - Tag: A16; Mark: A16
IfcRoot - Name: 40 x 230
Qto_BeamBaseQuantities - Length: 520; CrossSectionArea: 0.0092; OuterSurfaceArea: 0.257519; GrossSurfaceArea: 0.275919; NetSurfaceArea: 0.275919; GrossVolume: 0.00438736; NetVolume: 0.00438736
Pset_BeamCommon - Reference: 40 x 230; Span: 520 mm; Slope: 0 rad; Roll: 0 rad; IsExternal: no; LoadBearing: yes
Pset_ConcreteElementGeneral - ConstructionMethod: prefabricated
Pset_Condition - AssessmentCondition: Empty
Pset_EnvironmentalImpactIndicators - Reference: 40 x 230; sets with these values: 2

# IfcBeam: 28_SF_hout_rechthoekig_40 x 230_305, 28_SF_hout_rechthoekig:40 x 230:33585523
In: 010
PredefinedType: BEAM; Material: GVH_i2_naaldhout_generiek
Cpset_Beam - LevelOfAccuracy: in te vullen door Buildwise
IfcClassificationReference - TDS_link: .\05 As Builtdossier\2. Bouwkunde\2.2. Stabiliteit\2.2.0 technische fiche's\TF S 4.9.1.1.1 A - houten roostering sheddak.pdf
IfcElement - Tag: B1; Mark: B1
IfcRoot - Name: 40 x 230
Qto_BeamBaseQuantities - Length: 3340; CrossSectionArea: 0.0092; OuterSurfaceArea: 1.79034; GrossSurfaceArea: 1.80874; NetSurfaceArea: 1.80874; GrossVolume: 0.030502; NetVolume: 0.030502
Pset_BeamCommon - Reference: 40 x 230; Span: 3340 mm; Slope: 0 rad; Roll: 0 rad; IsExternal: no; LoadBearing: yes
Pset_ConcreteElementGeneral - ConstructionMethod: prefabricated
Pset_Condition - AssessmentCondition: Empty
Pset_EnvironmentalImpactIndicators - Reference: 40 x 230; sets with these values: 2

# IfcBeam: 28_SF_hout_rechthoekig_40 x 230_307, 28_SF_hout_rechthoekig:40 x 230:33587465
In: 010
PredefinedType: BEAM; Material: GVH_i2_naaldhout_generiek
Cpset_Beam - LevelOfAccuracy: in te vullen door Buildwise
IfcClassificationReference - TDS_link: .\05 As Builtdossier\2. Bouwkunde\2.2. Stabiliteit\2.2.0 technische fiche's\TF S 4.9.1.1.1 A - houten roostering sheddak.pdf
IfcElement - Tag: B1; Mark: B1
IfcRoot - Name: 40 x 230
Qto_BeamBaseQuantities - Length: 3340; CrossSectionArea: 0.0092; OuterSurfaceArea: 1.79034; GrossSurfaceArea: 1.80874; NetSurfaceArea: 1.80874; GrossVolume: 0.030502; NetVolume: 0.030502
Pset_BeamCommon - Reference: 40 x 230; Span: 3340 mm; Slope: 0 rad; Roll: 0 rad; IsExternal: no; LoadBearing: yes
Pset_ConcreteElementGeneral - ConstructionMethod: prefabricated
Pset_Condition - AssessmentCondition: Empty
Pset_EnvironmentalImpactIndicators - Reference: 40 x 230; sets with these values: 2

# IfcBeam: 28_SF_hout_rechthoekig_40 x 230_309, 28_SF_hout_rechthoekig:40 x 230:33587485
In: 010
PredefinedType: BEAM; Material: GVH_i2_naaldhout_generiek
Cpset_Beam - LevelOfAccuracy: in te vullen door Buildwise
IfcClassificationReference - TDS_link: .\05 As Builtdossier\2. Bouwkunde\2.2. Stabiliteit\2.2.0 technische fiche's\TF S 4.9.1.1.1 A - houten roostering sheddak.pdf
IfcElement - Tag: B1; Mark: B1
IfcRoot - Name: 40 x 230
Qto_BeamBaseQuantities - Length: 3340; CrossSectionArea: 0.0092; OuterSurfaceArea: 1.79034; GrossSurfaceArea: 1.80874; NetSurfaceArea: 1.80874; GrossVolume: 0.030502; NetVolume: 0.030502
Pset_BeamCommon - Reference: 40 x 230; Span: 3340 mm; Slope: 0 rad; Roll: 0 rad; IsExternal: no; LoadBearing: yes
Pset_ConcreteElementGeneral - ConstructionMethod: prefabricated
Pset_Condition - AssessmentCondition: Empty
Pset_EnvironmentalImpactIndicators - Reference: 40 x 230; sets with these values: 2

# IfcBeam: 28_SF_hout_rechthoekig_40 x 230_31, 28_SF_hout_rechthoekig:40 x 230:33579906
In: 010
PredefinedType: BEAM; Material: GVH_i2_naaldhout_generiek
Cpset_Beam - LevelOfAccuracy: in te vullen door Buildwise
IfcClassificationReference - TDS_link: .\05 As Builtdossier\2. Bouwkunde\2.2. Stabiliteit\2.2.0 technische fiche's\TF S 4.9.1.1.1 A - houten roostering sheddak.pdf
IfcElement - Tag: B1; Mark: B1
IfcRoot - Name: 40 x 230
Qto_BeamBaseQuantities - Length: 3340; CrossSectionArea: 0.0092; OuterSurfaceArea: 1.79133; GrossSurfaceArea: 1.80973; NetSurfaceArea: 1.80973; GrossVolume: 0.030519; NetVolume: 0.030519
Pset_BeamCommon - Reference: 40 x 230; Span: 3340 mm; Slope: 0 rad; Roll: 0 rad; IsExternal: no; LoadBearing: yes
Pset_ConcreteElementGeneral - ConstructionMethod: prefabricated
Pset_Condition - AssessmentCondition: Empty
Pset_EnvironmentalImpactIndicators - Reference: 40 x 230; sets with these values: 2

# IfcBeam: 28_SF_hout_rechthoekig_40 x 230_311, 28_SF_hout_rechthoekig:40 x 230:33587488
In: 010
PredefinedType: BEAM; Material: GVH_i2_naaldhout_generiek
Cpset_Beam - LevelOfAccuracy: in te vullen door Buildwise
IfcClassificationReference - TDS_link: .\05 As Builtdossier\2. Bouwkunde\2.2. Stabiliteit\2.2.0 technische fiche's\TF S 4.9.1.1.1 A - houten roostering sheddak.pdf
IfcElement - Tag: B1; Mark: B1
IfcRoot - Name: 40 x 230
Qto_BeamBaseQuantities - Length: 3340; CrossSectionArea: 0.0092; OuterSurfaceArea: 1.79034; GrossSurfaceArea: 1.80874; NetSurfaceArea: 1.80874; GrossVolume: 0.030502; NetVolume: 0.030502
Pset_BeamCommon - Reference: 40 x 230; Span: 3340 mm; Slope: 0 rad; Roll: 0 rad; IsExternal: no; LoadBearing: yes
Pset_ConcreteElementGeneral - ConstructionMethod: prefabricated
Pset_Condition - AssessmentCondition: Empty
Pset_EnvironmentalImpactIndicators - Reference: 40 x 230; sets with these values: 2

# IfcBeam: 28_SF_hout_rechthoekig_40 x 230_313, 28_SF_hout_rechthoekig:40 x 230:33587491
In: 010
PredefinedType: BEAM; Material: GVH_i2_naaldhout_generiek
Cpset_Beam - LevelOfAccuracy: in te vullen door Buildwise
IfcClassificationReference - TDS_link: .\05 As Builtdossier\2. Bouwkunde\2.2. Stabiliteit\2.2.0 technische fiche's\TF S 4.9.1.1.1 A - houten roostering sheddak.pdf
IfcElement - Tag: B1; Mark: B1
IfcRoot - Name: 40 x 230
Qto_BeamBaseQuantities - Length: 3340; CrossSectionArea: 0.0092; OuterSurfaceArea: 1.79034; GrossSurfaceArea: 1.80874; NetSurfaceArea: 1.80874; GrossVolume: 0.030502; NetVolume: 0.030502
Pset_BeamCommon - Reference: 40 x 230; Span: 3340 mm; Slope: 0 rad; Roll: 0 rad; IsExternal: no; LoadBearing: yes
Pset_ConcreteElementGeneral - ConstructionMethod: prefabricated
Pset_Condition - AssessmentCondition: Empty
Pset_EnvironmentalImpactIndicators - Reference: 40 x 230; sets with these values: 2

# IfcBeam: 28_SF_hout_rechthoekig_40 x 230_315, 28_SF_hout_rechthoekig:40 x 230:33587494
In: 010
PredefinedType: BEAM; Material: GVH_i2_naaldhout_generiek
Cpset_Beam - LevelOfAccuracy: in te vullen door Buildwise
IfcClassificationReference - TDS_link: .\05 As Builtdossier\2. Bouwkunde\2.2. Stabiliteit\2.2.0 technische fiche's\TF S 4.9.1.1.1 A - houten roostering sheddak.pdf
IfcElement - Tag: B1; Mark: B1
IfcRoot - Name: 40 x 230
Qto_BeamBaseQuantities - Length: 3340; CrossSectionArea: 0.0092; OuterSurfaceArea: 1.79034; GrossSurfaceArea: 1.80874; NetSurfaceArea: 1.80874; GrossVolume: 0.030502; NetVolume: 0.030502
Pset_BeamCommon - Reference: 40 x 230; Span: 3340 mm; Slope: 0 rad; Roll: 0 rad; IsExternal: no; LoadBearing: yes
Pset_ConcreteElementGeneral - ConstructionMethod: prefabricated
Pset_Condition - AssessmentCondition: Empty
Pset_EnvironmentalImpactIndicators - Reference: 40 x 230; sets with these values: 2

# IfcBeam: 28_SF_hout_rechthoekig_40 x 230_317, 28_SF_hout_rechthoekig:40 x 230:33587497
In: 010
PredefinedType: BEAM; Material: GVH_i2_naaldhout_generiek
Cpset_Beam - LevelOfAccuracy: in te vullen door Buildwise
IfcClassificationReference - TDS_link: .\05 As Builtdossier\2. Bouwkunde\2.2. Stabiliteit\2.2.0 technische fiche's\TF S 4.9.1.1.1 A - houten roostering sheddak.pdf
IfcElement - Tag: B1; Mark: B1
IfcRoot - Name: 40 x 230
Qto_BeamBaseQuantities - Length: 3340; CrossSectionArea: 0.0092; OuterSurfaceArea: 1.79034; GrossSurfaceArea: 1.80874; NetSurfaceArea: 1.80874; GrossVolume: 0.030502; NetVolume: 0.030502
Pset_BeamCommon - Reference: 40 x 230; Span: 3340 mm; Slope: 0 rad; Roll: 0 rad; IsExternal: no; LoadBearing: yes
Pset_ConcreteElementGeneral - ConstructionMethod: prefabricated
Pset_Condition - AssessmentCondition: Empty
Pset_EnvironmentalImpactIndicators - Reference: 40 x 230; sets with these values: 2

# IfcBeam: 28_SF_hout_rechthoekig_40 x 230_319, 28_SF_hout_rechthoekig:40 x 230:33587500
In: 010
PredefinedType: BEAM; Material: GVH_i2_naaldhout_generiek
Cpset_Beam - LevelOfAccuracy: in te vullen door Buildwise
IfcClassificationReference - TDS_link: .\05 As Builtdossier\2. Bouwkunde\2.2. Stabiliteit\2.2.0 technische fiche's\TF S 4.9.1.1.1 A - houten roostering sheddak.pdf
IfcElement - Tag: B1; Mark: B1
IfcRoot - Name: 40 x 230
Qto_BeamBaseQuantities - Length: 3340; CrossSectionArea: 0.0092; OuterSurfaceArea: 1.79034; GrossSurfaceArea: 1.80874; NetSurfaceArea: 1.80874; GrossVolume: 0.030502; NetVolume: 0.030502
Pset_BeamCommon - Reference: 40 x 230; Span: 3340 mm; Slope: 0 rad; Roll: 0 rad; IsExternal: no; LoadBearing: yes
Pset_ConcreteElementGeneral - ConstructionMethod: prefabricated
Pset_Condition - AssessmentCondition: Empty
Pset_EnvironmentalImpactIndicators - Reference: 40 x 230; sets with these values: 2

# IfcBeam: 28_SF_hout_rechthoekig_40 x 230_321, 28_SF_hout_rechthoekig:40 x 230:33587503
In: 010
PredefinedType: BEAM; Material: GVH_i2_naaldhout_generiek
Cpset_Beam - LevelOfAccuracy: in te vullen door Buildwise
IfcClassificationReference - TDS_link: .\05 As Builtdossier\2. Bouwkunde\2.2. Stabiliteit\2.2.0 technische fiche's\TF S 4.9.1.1.1 A - houten roostering sheddak.pdf
IfcElement - Tag: B1; Mark: B1
IfcRoot - Name: 40 x 230
Qto_BeamBaseQuantities - Length: 3340; CrossSectionArea: 0.0092; OuterSurfaceArea: 1.79034; GrossSurfaceArea: 1.80874; NetSurfaceArea: 1.80874; GrossVolume: 0.030502; NetVolume: 0.030502
Pset_BeamCommon - Reference: 40 x 230; Span: 3340 mm; Slope: 0 rad; Roll: 0 rad; IsExternal: no; LoadBearing: yes
Pset_ConcreteElementGeneral - ConstructionMethod: prefabricated
Pset_Condition - AssessmentCondition: Empty
Pset_EnvironmentalImpactIndicators - Reference: 40 x 230; sets with these values: 2

# IfcBeam: 28_SF_hout_rechthoekig_40 x 230_323, 28_SF_hout_rechthoekig:40 x 230:33587506
In: 010
PredefinedType: BEAM; Material: GVH_i2_naaldhout_generiek
Cpset_Beam - LevelOfAccuracy: in te vullen door Buildwise
IfcClassificationReference - TDS_link: .\05 As Builtdossier\2. Bouwkunde\2.2. Stabiliteit\2.2.0 technische fiche's\TF S 4.9.1.1.1 A - houten roostering sheddak.pdf
IfcElement - Tag: B1; Mark: B1
IfcRoot - Name: 40 x 230
Qto_BeamBaseQuantities - Length: 3340; CrossSectionArea: 0.0092; OuterSurfaceArea: 1.79034; GrossSurfaceArea: 1.80874; NetSurfaceArea: 1.80874; GrossVolume: 0.030502; NetVolume: 0.030502
Pset_BeamCommon - Reference: 40 x 230; Span: 3340 mm; Slope: 0 rad; Roll: 0 rad; IsExternal: no; LoadBearing: yes
Pset_ConcreteElementGeneral - ConstructionMethod: prefabricated
Pset_Condition - AssessmentCondition: Empty
Pset_EnvironmentalImpactIndicators - Reference: 40 x 230; sets with these values: 2

# IfcBeam: 28_SF_hout_rechthoekig_40 x 230_325, 28_SF_hout_rechthoekig:40 x 230:33587509
In: 010
PredefinedType: BEAM; Material: GVH_i2_naaldhout_generiek
Cpset_Beam - LevelOfAccuracy: in te vullen door Buildwise
IfcClassificationReference - TDS_link: .\05 As Builtdossier\2. Bouwkunde\2.2. Stabiliteit\2.2.0 technische fiche's\TF S 4.9.1.1.1 A - houten roostering sheddak.pdf
IfcElement - Tag: B1; Mark: B1
IfcRoot - Name: 40 x 230
Qto_BeamBaseQuantities - Length: 3340; CrossSectionArea: 0.0092; OuterSurfaceArea: 1.79034; GrossSurfaceArea: 1.80874; NetSurfaceArea: 1.80874; GrossVolume: 0.030502; NetVolume: 0.030502
Pset_BeamCommon - Reference: 40 x 230; Span: 3340 mm; Slope: 0 rad; Roll: 0 rad; IsExternal: no; LoadBearing: yes
Pset_ConcreteElementGeneral - ConstructionMethod: prefabricated
Pset_Condition - AssessmentCondition: Empty
Pset_EnvironmentalImpactIndicators - Reference: 40 x 230; sets with these values: 2

# IfcBeam: 28_SF_hout_rechthoekig_40 x 230_327, 28_SF_hout_rechthoekig:40 x 230:33587512
In: 010
PredefinedType: BEAM; Material: GVH_i2_naaldhout_generiek
Cpset_Beam - LevelOfAccuracy: in te vullen door Buildwise
IfcClassificationReference - TDS_link: .\05 As Builtdossier\2. Bouwkunde\2.2. Stabiliteit\2.2.0 technische fiche's\TF S 4.9.1.1.1 A - houten roostering sheddak.pdf
IfcElement - Tag: B1; Mark: B1
IfcRoot - Name: 40 x 230
Qto_BeamBaseQuantities - Length: 3340; CrossSectionArea: 0.0092; OuterSurfaceArea: 1.79034; GrossSurfaceArea: 1.80874; NetSurfaceArea: 1.80874; GrossVolume: 0.030502; NetVolume: 0.030502
Pset_BeamCommon - Reference: 40 x 230; Span: 3340 mm; Slope: 0 rad; Roll: 0 rad; IsExternal: no; LoadBearing: yes
Pset_ConcreteElementGeneral - ConstructionMethod: prefabricated
Pset_Condition - AssessmentCondition: Empty
Pset_EnvironmentalImpactIndicators - Reference: 40 x 230; sets with these values: 2

# IfcBeam: 28_SF_hout_rechthoekig_40 x 230_329, 28_SF_hout_rechthoekig:40 x 230:33587515
In: 010
PredefinedType: BEAM; Material: GVH_i2_naaldhout_generiek
Cpset_Beam - LevelOfAccuracy: in te vullen door Buildwise
IfcClassificationReference - TDS_link: .\05 As Builtdossier\2. Bouwkunde\2.2. Stabiliteit\2.2.0 technische fiche's\TF S 4.9.1.1.1 A - houten roostering sheddak.pdf
IfcElement - Tag: B1; Mark: B1
IfcRoot - Name: 40 x 230
Qto_BeamBaseQuantities - Length: 3340; CrossSectionArea: 0.0092; OuterSurfaceArea: 1.79034; GrossSurfaceArea: 1.80874; NetSurfaceArea: 1.80874; GrossVolume: 0.030502; NetVolume: 0.030502
Pset_BeamCommon - Reference: 40 x 230; Span: 3340 mm; Slope: 0 rad; Roll: 0 rad; IsExternal: no; LoadBearing: yes
Pset_ConcreteElementGeneral - ConstructionMethod: prefabricated
Pset_Condition - AssessmentCondition: Empty
Pset_EnvironmentalImpactIndicators - Reference: 40 x 230; sets with these values: 2

# IfcBeam: 28_SF_hout_rechthoekig_40 x 230_33, 28_SF_hout_rechthoekig:40 x 230:33579908
In: 010
PredefinedType: BEAM; Material: GVH_i2_naaldhout_generiek
Cpset_Beam - LevelOfAccuracy: in te vullen door Buildwise
IfcClassificationReference - TDS_link: .\05 As Builtdossier\2. Bouwkunde\2.2. Stabiliteit\2.2.0 technische fiche's\TF S 4.9.1.1.1 A - houten roostering sheddak.pdf
IfcElement - Tag: B1; Mark: B1
IfcRoot - Name: 40 x 230
Qto_BeamBaseQuantities - Length: 3340; CrossSectionArea: 0.0092; OuterSurfaceArea: 1.79133; GrossSurfaceArea: 1.80973; NetSurfaceArea: 1.80973; GrossVolume: 0.030519; NetVolume: 0.030519
Pset_BeamCommon - Reference: 40 x 230; Span: 3340 mm; Slope: 0 rad; Roll: 0 rad; IsExternal: no; LoadBearing: yes
Pset_ConcreteElementGeneral - ConstructionMethod: prefabricated
Pset_Condition - AssessmentCondition: Empty
Pset_EnvironmentalImpactIndicators - Reference: 40 x 230; sets with these values: 2

# IfcBeam: 28_SF_hout_rechthoekig_40 x 230_331, 28_SF_hout_rechthoekig:40 x 230:33587518
In: 010
PredefinedType: BEAM; Material: GVH_i2_naaldhout_generiek
Cpset_Beam - LevelOfAccuracy: in te vullen door Buildwise
IfcClassificationReference - TDS_link: .\05 As Builtdossier\2. Bouwkunde\2.2. Stabiliteit\2.2.0 technische fiche's\TF S 4.9.1.1.1 A - houten roostering sheddak.pdf
IfcElement - Tag: B1; Mark: B1
IfcRoot - Name: 40 x 230
Qto_BeamBaseQuantities - Length: 3340; CrossSectionArea: 0.0092; OuterSurfaceArea: 1.79034; GrossSurfaceArea: 1.80874; NetSurfaceArea: 1.80874; GrossVolume: 0.030502; NetVolume: 0.030502
Pset_BeamCommon - Reference: 40 x 230; Span: 3340 mm; Slope: 0 rad; Roll: 0 rad; IsExternal: no; LoadBearing: yes
Pset_ConcreteElementGeneral - ConstructionMethod: prefabricated
Pset_Condition - AssessmentCondition: Empty
Pset_EnvironmentalImpactIndicators - Reference: 40 x 230; sets with these values: 2

# IfcBeam: 28_SF_hout_rechthoekig_40 x 230_333, 28_SF_hout_rechthoekig:40 x 230:33587521
In: 010
PredefinedType: BEAM; Material: GVH_i2_naaldhout_generiek
Cpset_Beam - LevelOfAccuracy: in te vullen door Buildwise
IfcClassificationReference - TDS_link: .\05 As Builtdossier\2. Bouwkunde\2.2. Stabiliteit\2.2.0 technische fiche's\TF S 4.9.1.1.1 A - houten roostering sheddak.pdf
IfcElement - Tag: B1; Mark: B1
IfcRoot - Name: 40 x 230
Qto_BeamBaseQuantities - Length: 3340; CrossSectionArea: 0.0092; OuterSurfaceArea: 1.79034; GrossSurfaceArea: 1.80874; NetSurfaceArea: 1.80874; GrossVolume: 0.030502; NetVolume: 0.030502
Pset_BeamCommon - Reference: 40 x 230; Span: 3340 mm; Slope: 0 rad; Roll: 0 rad; IsExternal: no; LoadBearing: yes
Pset_ConcreteElementGeneral - ConstructionMethod: prefabricated
Pset_Condition - AssessmentCondition: Empty
Pset_EnvironmentalImpactIndicators - Reference: 40 x 230; sets with these values: 2

# IfcBeam: 28_SF_hout_rechthoekig_40 x 230_335, 28_SF_hout_rechthoekig:40 x 230:33587524
In: 010
PredefinedType: BEAM; Material: GVH_i2_naaldhout_generiek
Cpset_Beam - LevelOfAccuracy: in te vullen door Buildwise
IfcClassificationReference - TDS_link: .\05 As Builtdossier\2. Bouwkunde\2.2. Stabiliteit\2.2.0 technische fiche's\TF S 4.9.1.1.1 A - houten roostering sheddak.pdf
IfcElement - Tag: B1; Mark: B1
IfcRoot - Name: 40 x 230
Qto_BeamBaseQuantities - Length: 3340; CrossSectionArea: 0.0092; OuterSurfaceArea: 1.79034; GrossSurfaceArea: 1.80874; NetSurfaceArea: 1.80874; GrossVolume: 0.030502; NetVolume: 0.030502
Pset_BeamCommon - Reference: 40 x 230; Span: 3340 mm; Slope: 0 rad; Roll: 0 rad; IsExternal: no; LoadBearing: yes
Pset_ConcreteElementGeneral - ConstructionMethod: prefabricated
Pset_Condition - AssessmentCondition: Empty
Pset_EnvironmentalImpactIndicators - Reference: 40 x 230; sets with these values: 2

# IfcBeam: 28_SF_hout_rechthoekig_40 x 230_337, 28_SF_hout_rechthoekig:40 x 230:33589603
In: 010
PredefinedType: BEAM; Material: GVH_i2_naaldhout_generiek
Cpset_Beam - LevelOfAccuracy: in te vullen door Buildwise
IfcClassificationReference - TDS_link: .\05 As Builtdossier\2. Bouwkunde\2.2. Stabiliteit\2.2.0 technische fiche's\TF S 4.9.1.1.1 A - houten roostering sheddak.pdf
IfcElement - Tag: B1; Mark: B1
IfcRoot - Name: 40 x 230
Qto_BeamBaseQuantities - Length: 3340; CrossSectionArea: 0.0092; OuterSurfaceArea: 1.79133; GrossSurfaceArea: 1.80973; NetSurfaceArea: 1.80973; GrossVolume: 0.030519; NetVolume: 0.030519
Pset_BeamCommon - Reference: 40 x 230; Span: 3340 mm; Slope: 0 rad; Roll: 0 rad; IsExternal: no; LoadBearing: yes
Pset_ConcreteElementGeneral - ConstructionMethod: prefabricated
Pset_Condition - AssessmentCondition: Empty
Pset_EnvironmentalImpactIndicators - Reference: 40 x 230; sets with these values: 2

# IfcBeam: 28_SF_hout_rechthoekig_40 x 230_339, 28_SF_hout_rechthoekig:40 x 230:33589606
In: 010
PredefinedType: BEAM; Material: GVH_i2_naaldhout_generiek
Cpset_Beam - LevelOfAccuracy: in te vullen door Buildwise
IfcClassificationReference - TDS_link: .\05 As Builtdossier\2. Bouwkunde\2.2. Stabiliteit\2.2.0 technische fiche's\TF S 4.9.1.1.1 A - houten roostering sheddak.pdf
IfcElement - Tag: B1; Mark: B1
IfcRoot - Name: 40 x 230
Qto_BeamBaseQuantities - Length: 3340; CrossSectionArea: 0.0092; OuterSurfaceArea: 1.79133; GrossSurfaceArea: 1.80973; NetSurfaceArea: 1.80973; GrossVolume: 0.030519; NetVolume: 0.030519
Pset_BeamCommon - Reference: 40 x 230; Span: 3340 mm; Slope: 0 rad; Roll: 0 rad; IsExternal: no; LoadBearing: yes
Pset_ConcreteElementGeneral - ConstructionMethod: prefabricated
Pset_Condition - AssessmentCondition: Empty
Pset_EnvironmentalImpactIndicators - Reference: 40 x 230; sets with these values: 2

# IfcBeam: 28_SF_hout_rechthoekig_40 x 230_341, 28_SF_hout_rechthoekig:40 x 230:33589613
In: 010
PredefinedType: BEAM; Material: GVH_i2_naaldhout_generiek
Cpset_Beam - LevelOfAccuracy: in te vullen door Buildwise
IfcClassificationReference - TDS_link: .\05 As Builtdossier\2. Bouwkunde\2.2. Stabiliteit\2.2.0 technische fiche's\TF S 4.9.1.1.1 A - houten roostering sheddak.pdf
IfcElement - Tag: B1; Mark: B1
IfcRoot - Name: 40 x 230
Qto_BeamBaseQuantities - Length: 3340; CrossSectionArea: 0.0092; OuterSurfaceArea: 1.79133; GrossSurfaceArea: 1.80973; NetSurfaceArea: 1.80973; GrossVolume: 0.030519; NetVolume: 0.030519
Pset_BeamCommon - Reference: 40 x 230; Span: 3340 mm; Slope: 0 rad; Roll: 0 rad; IsExternal: no; LoadBearing: yes
Pset_ConcreteElementGeneral - ConstructionMethod: prefabricated
Pset_Condition - AssessmentCondition: Empty
Pset_EnvironmentalImpactIndicators - Reference: 40 x 230; sets with these values: 2

# IfcBeam: 28_SF_hout_rechthoekig_40 x 230_343, 28_SF_hout_rechthoekig:40 x 230:33589616
In: 010
PredefinedType: BEAM; Material: GVH_i2_naaldhout_generiek
Cpset_Beam - LevelOfAccuracy: in te vullen door Buildwise
IfcClassificationReference - TDS_link: .\05 As Builtdossier\2. Bouwkunde\2.2. Stabiliteit\2.2.0 technische fiche's\TF S 4.9.1.1.1 A - houten roostering sheddak.pdf
IfcElement - Tag: B1; Mark: B1
IfcRoot - Name: 40 x 230
Qto_BeamBaseQuantities - Length: 3340; CrossSectionArea: 0.0092; OuterSurfaceArea: 1.79133; GrossSurfaceArea: 1.80973; NetSurfaceArea: 1.80973; GrossVolume: 0.030519; NetVolume: 0.030519
Pset_BeamCommon - Reference: 40 x 230; Span: 3340 mm; Slope: 0 rad; Roll: 0 rad; IsExternal: no; LoadBearing: yes
Pset_ConcreteElementGeneral - ConstructionMethod: prefabricated
Pset_Condition - AssessmentCondition: Empty
Pset_EnvironmentalImpactIndicators - Reference: 40 x 230; sets with these values: 2

# IfcBeam: 28_SF_hout_rechthoekig_40 x 230_345, 28_SF_hout_rechthoekig:40 x 230:33589619
In: 010
PredefinedType: BEAM; Material: GVH_i2_naaldhout_generiek
Cpset_Beam - LevelOfAccuracy: in te vullen door Buildwise
IfcClassificationReference - TDS_link: .\05 As Builtdossier\2. Bouwkunde\2.2. Stabiliteit\2.2.0 technische fiche's\TF S 4.9.1.1.1 A - houten roostering sheddak.pdf
IfcElement - Tag: B1; Mark: B1
IfcRoot - Name: 40 x 230
Qto_BeamBaseQuantities - Length: 3340; CrossSectionArea: 0.0092; OuterSurfaceArea: 1.79133; GrossSurfaceArea: 1.80973; NetSurfaceArea: 1.80973; GrossVolume: 0.030519; NetVolume: 0.030519
Pset_BeamCommon - Reference: 40 x 230; Span: 3340 mm; Slope: 0 rad; Roll: 0 rad; IsExternal: no; LoadBearing: yes
Pset_ConcreteElementGeneral - ConstructionMethod: prefabricated
Pset_Condition - AssessmentCondition: Empty
Pset_EnvironmentalImpactIndicators - Reference: 40 x 230; sets with these values: 2

# IfcBeam: 28_SF_hout_rechthoekig_40 x 230_347, 28_SF_hout_rechthoekig:40 x 230:33589622
In: 010
PredefinedType: BEAM; Material: GVH_i2_naaldhout_generiek
Cpset_Beam - LevelOfAccuracy: in te vullen door Buildwise
IfcClassificationReference - TDS_link: .\05 As Builtdossier\2. Bouwkunde\2.2. Stabiliteit\2.2.0 technische fiche's\TF S 4.9.1.1.1 A - houten roostering sheddak.pdf
IfcElement - Tag: B1; Mark: B1
IfcRoot - Name: 40 x 230
Qto_BeamBaseQuantities - Length: 3340; CrossSectionArea: 0.0092; OuterSurfaceArea: 1.79133; GrossSurfaceArea: 1.80973; NetSurfaceArea: 1.80973; GrossVolume: 0.030519; NetVolume: 0.030519
Pset_BeamCommon - Reference: 40 x 230; Span: 3340 mm; Slope: 0 rad; Roll: 0 rad; IsExternal: no; LoadBearing: yes
Pset_ConcreteElementGeneral - ConstructionMethod: prefabricated
Pset_Condition - AssessmentCondition: Empty
Pset_EnvironmentalImpactIndicators - Reference: 40 x 230; sets with these values: 2

# IfcBeam: 28_SF_hout_rechthoekig_40 x 230_349, 28_SF_hout_rechthoekig:40 x 230:33589625
In: 010
PredefinedType: BEAM; Material: GVH_i2_naaldhout_generiek
Cpset_Beam - LevelOfAccuracy: in te vullen door Buildwise
IfcClassificationReference - TDS_link: .\05 As Builtdossier\2. Bouwkunde\2.2. Stabiliteit\2.2.0 technische fiche's\TF S 4.9.1.1.1 A - houten roostering sheddak.pdf
IfcElement - Tag: B1; Mark: B1
IfcRoot - Name: 40 x 230
Qto_BeamBaseQuantities - Length: 3340; CrossSectionArea: 0.0092; OuterSurfaceArea: 1.79133; GrossSurfaceArea: 1.80973; NetSurfaceArea: 1.80973; GrossVolume: 0.030519; NetVolume: 0.030519
Pset_BeamCommon - Reference: 40 x 230; Span: 3340 mm; Slope: 0 rad; Roll: 0 rad; IsExternal: no; LoadBearing: yes
Pset_ConcreteElementGeneral - ConstructionMethod: prefabricated
Pset_Condition - AssessmentCondition: Empty
Pset_EnvironmentalImpactIndicators - Reference: 40 x 230; sets with these values: 2

# IfcBeam: 28_SF_hout_rechthoekig_40 x 230_35, 28_SF_hout_rechthoekig:40 x 230:33579910
In: 010
PredefinedType: BEAM; Material: GVH_i2_naaldhout_generiek
Cpset_Beam - LevelOfAccuracy: in te vullen door Buildwise
IfcClassificationReference - TDS_link: .\05 As Builtdossier\2. Bouwkunde\2.2. Stabiliteit\2.2.0 technische fiche's\TF S 4.9.1.1.1 A - houten roostering sheddak.pdf
IfcElement - Tag: B1; Mark: B1
IfcRoot - Name: 40 x 230
Qto_BeamBaseQuantities - Length: 3340; CrossSectionArea: 0.0092; OuterSurfaceArea: 1.79133; GrossSurfaceArea: 1.80973; NetSurfaceArea: 1.80973; GrossVolume: 0.030519; NetVolume: 0.030519
Pset_BeamCommon - Reference: 40 x 230; Span: 3340 mm; Slope: 0 rad; Roll: 0 rad; IsExternal: no; LoadBearing: yes
Pset_ConcreteElementGeneral - ConstructionMethod: prefabricated
Pset_Condition - AssessmentCondition: Empty
Pset_EnvironmentalImpactIndicators - Reference: 40 x 230; sets with these values: 2

# IfcBeam: 28_SF_hout_rechthoekig_40 x 230_351, 28_SF_hout_rechthoekig:40 x 230:33589628
In: 010
PredefinedType: BEAM; Material: GVH_i2_naaldhout_generiek
Cpset_Beam - LevelOfAccuracy: in te vullen door Buildwise
IfcClassificationReference - TDS_link: .\05 As Builtdossier\2. Bouwkunde\2.2. Stabiliteit\2.2.0 technische fiche's\TF S 4.9.1.1.1 A - houten roostering sheddak.pdf
IfcElement - Tag: B1; Mark: B1
IfcRoot - Name: 40 x 230
Qto_BeamBaseQuantities - Length: 3340; CrossSectionArea: 0.0092; OuterSurfaceArea: 1.79133; GrossSurfaceArea: 1.80973; NetSurfaceArea: 1.80973; GrossVolume: 0.030519; NetVolume: 0.030519
Pset_BeamCommon - Reference: 40 x 230; Span: 3340 mm; Slope: 0 rad; Roll: 0 rad; IsExternal: no; LoadBearing: yes
Pset_ConcreteElementGeneral - ConstructionMethod: prefabricated
Pset_Condition - AssessmentCondition: Empty
Pset_EnvironmentalImpactIndicators - Reference: 40 x 230; sets with these values: 2

# IfcBeam: 28_SF_hout_rechthoekig_40 x 230_353, 28_SF_hout_rechthoekig:40 x 230:33589631
In: 010
PredefinedType: BEAM; Material: GVH_i2_naaldhout_generiek
Cpset_Beam - LevelOfAccuracy: in te vullen door Buildwise
IfcClassificationReference - TDS_link: .\05 As Builtdossier\2. Bouwkunde\2.2. Stabiliteit\2.2.0 technische fiche's\TF S 4.9.1.1.1 A - houten roostering sheddak.pdf
IfcElement - Tag: B1; Mark: B1
IfcRoot - Name: 40 x 230
Qto_BeamBaseQuantities - Length: 3340; CrossSectionArea: 0.0092; OuterSurfaceArea: 1.79133; GrossSurfaceArea: 1.80973; NetSurfaceArea: 1.80973; GrossVolume: 0.030519; NetVolume: 0.030519
Pset_BeamCommon - Reference: 40 x 230; Span: 3340 mm; Slope: 0 rad; Roll: 0 rad; IsExternal: no; LoadBearing: yes
Pset_ConcreteElementGeneral - ConstructionMethod: prefabricated
Pset_Condition - AssessmentCondition: Empty
Pset_EnvironmentalImpactIndicators - Reference: 40 x 230; sets with these values: 2

# IfcBeam: 28_SF_hout_rechthoekig_40 x 230_355, 28_SF_hout_rechthoekig:40 x 230:33589634
In: 010
PredefinedType: BEAM; Material: GVH_i2_naaldhout_generiek
Cpset_Beam - LevelOfAccuracy: in te vullen door Buildwise
IfcClassificationReference - TDS_link: .\05 As Builtdossier\2. Bouwkunde\2.2. Stabiliteit\2.2.0 technische fiche's\TF S 4.9.1.1.1 A - houten roostering sheddak.pdf
IfcElement - Tag: B1; Mark: B1
IfcRoot - Name: 40 x 230
Qto_BeamBaseQuantities - Length: 3340; CrossSectionArea: 0.0092; OuterSurfaceArea: 1.79133; GrossSurfaceArea: 1.80973; NetSurfaceArea: 1.80973; GrossVolume: 0.030519; NetVolume: 0.030519
Pset_BeamCommon - Reference: 40 x 230; Span: 3340 mm; Slope: 0 rad; Roll: 0 rad; IsExternal: no; LoadBearing: yes
Pset_ConcreteElementGeneral - ConstructionMethod: prefabricated
Pset_Condition - AssessmentCondition: Empty
Pset_EnvironmentalImpactIndicators - Reference: 40 x 230; sets with these values: 2

# IfcBeam: 28_SF_hout_rechthoekig_40 x 230_357, 28_SF_hout_rechthoekig:40 x 230:33589637
In: 010
PredefinedType: BEAM; Material: GVH_i2_naaldhout_generiek
Cpset_Beam - LevelOfAccuracy: in te vullen door Buildwise
IfcClassificationReference - TDS_link: .\05 As Builtdossier\2. Bouwkunde\2.2. Stabiliteit\2.2.0 technische fiche's\TF S 4.9.1.1.1 A - houten roostering sheddak.pdf
IfcElement - Tag: B1; Mark: B1
IfcRoot - Name: 40 x 230
Qto_BeamBaseQuantities - Length: 3340; CrossSectionArea: 0.0092; OuterSurfaceArea: 1.79133; GrossSurfaceArea: 1.80973; NetSurfaceArea: 1.80973; GrossVolume: 0.030519; NetVolume: 0.030519
Pset_BeamCommon - Reference: 40 x 230; Span: 3340 mm; Slope: 0 rad; Roll: 0 rad; IsExternal: no; LoadBearing: yes
Pset_ConcreteElementGeneral - ConstructionMethod: prefabricated
Pset_Condition - AssessmentCondition: Empty
Pset_EnvironmentalImpactIndicators - Reference: 40 x 230; sets with these values: 2

# IfcBeam: 28_SF_hout_rechthoekig_40 x 230_359, 28_SF_hout_rechthoekig:40 x 230:33589640
In: 010
PredefinedType: BEAM; Material: GVH_i2_naaldhout_generiek
Cpset_Beam - LevelOfAccuracy: in te vullen door Buildwise
IfcClassificationReference - TDS_link: .\05 As Builtdossier\2. Bouwkunde\2.2. Stabiliteit\2.2.0 technische fiche's\TF S 4.9.1.1.1 A - houten roostering sheddak.pdf
IfcElement - Tag: B1; Mark: B1
IfcRoot - Name: 40 x 230
Qto_BeamBaseQuantities - Length: 3340; CrossSectionArea: 0.0092; OuterSurfaceArea: 1.79133; GrossSurfaceArea: 1.80973; NetSurfaceArea: 1.80973; GrossVolume: 0.030519; NetVolume: 0.030519
Pset_BeamCommon - Reference: 40 x 230; Span: 3340 mm; Slope: 0 rad; Roll: 0 rad; IsExternal: no; LoadBearing: yes
Pset_ConcreteElementGeneral - ConstructionMethod: prefabricated
Pset_Condition - AssessmentCondition: Empty
Pset_EnvironmentalImpactIndicators - Reference: 40 x 230; sets with these values: 2

# IfcBeam: 28_SF_hout_rechthoekig_40 x 230_361, 28_SF_hout_rechthoekig:40 x 230:33589643
In: 010
PredefinedType: BEAM; Material: GVH_i2_naaldhout_generiek
Cpset_Beam - LevelOfAccuracy: in te vullen door Buildwise
IfcClassificationReference - TDS_link: .\05 As Builtdossier\2. Bouwkunde\2.2. Stabiliteit\2.2.0 technische fiche's\TF S 4.9.1.1.1 A - houten roostering sheddak.pdf
IfcElement - Tag: B1; Mark: B1
IfcRoot - Name: 40 x 230
Qto_BeamBaseQuantities - Length: 3340; CrossSectionArea: 0.0092; OuterSurfaceArea: 1.79133; GrossSurfaceArea: 1.80973; NetSurfaceArea: 1.80973; GrossVolume: 0.030519; NetVolume: 0.030519
Pset_BeamCommon - Reference: 40 x 230; Span: 3340 mm; Slope: 0 rad; Roll: 0 rad; IsExternal: no; LoadBearing: yes
Pset_ConcreteElementGeneral - ConstructionMethod: prefabricated
Pset_Condition - AssessmentCondition: Empty
Pset_EnvironmentalImpactIndicators - Reference: 40 x 230; sets with these values: 2

# IfcBeam: 28_SF_hout_rechthoekig_40 x 230_363, 28_SF_hout_rechthoekig:40 x 230:33589646
In: 010
PredefinedType: BEAM; Material: GVH_i2_naaldhout_generiek
Cpset_Beam - LevelOfAccuracy: in te vullen door Buildwise
IfcClassificationReference - TDS_link: .\05 As Builtdossier\2. Bouwkunde\2.2. Stabiliteit\2.2.0 technische fiche's\TF S 4.9.1.1.1 A - houten roostering sheddak.pdf
IfcElement - Tag: B1; Mark: B1
IfcRoot - Name: 40 x 230
Qto_BeamBaseQuantities - Length: 3340; CrossSectionArea: 0.0092; OuterSurfaceArea: 1.79133; GrossSurfaceArea: 1.80973; NetSurfaceArea: 1.80973; GrossVolume: 0.030519; NetVolume: 0.030519
Pset_BeamCommon - Reference: 40 x 230; Span: 3340 mm; Slope: 0 rad; Roll: 0 rad; IsExternal: no; LoadBearing: yes
Pset_ConcreteElementGeneral - ConstructionMethod: prefabricated
Pset_Condition - AssessmentCondition: Empty
Pset_EnvironmentalImpactIndicators - Reference: 40 x 230; sets with these values: 2

# IfcBeam: 28_SF_hout_rechthoekig_40 x 230_365, 28_SF_hout_rechthoekig:40 x 230:33589649
In: 010
PredefinedType: BEAM; Material: GVH_i2_naaldhout_generiek
Cpset_Beam - LevelOfAccuracy: in te vullen door Buildwise
IfcClassificationReference - TDS_link: .\05 As Builtdossier\2. Bouwkunde\2.2. Stabiliteit\2.2.0 technische fiche's\TF S 4.9.1.1.1 A - houten roostering sheddak.pdf
IfcElement - Tag: B1; Mark: B1
IfcRoot - Name: 40 x 230
Qto_BeamBaseQuantities - Length: 3340; CrossSectionArea: 0.0092; OuterSurfaceArea: 1.79133; GrossSurfaceArea: 1.80973; NetSurfaceArea: 1.80973; GrossVolume: 0.030519; NetVolume: 0.030519
Pset_BeamCommon - Reference: 40 x 230; Span: 3340 mm; Slope: 0 rad; Roll: 0 rad; IsExternal: no; LoadBearing: yes
Pset_ConcreteElementGeneral - ConstructionMethod: prefabricated
Pset_Condition - AssessmentCondition: Empty
Pset_EnvironmentalImpactIndicators - Reference: 40 x 230; sets with these values: 2

# IfcBeam: 28_SF_hout_rechthoekig_40 x 230_367, 28_SF_hout_rechthoekig:40 x 230:33589652
In: 010
PredefinedType: BEAM; Material: GVH_i2_naaldhout_generiek
Cpset_Beam - LevelOfAccuracy: in te vullen door Buildwise
IfcClassificationReference - TDS_link: .\05 As Builtdossier\2. Bouwkunde\2.2. Stabiliteit\2.2.0 technische fiche's\TF S 4.9.1.1.1 A - houten roostering sheddak.pdf
IfcElement - Tag: B1; Mark: B1
IfcRoot - Name: 40 x 230
Qto_BeamBaseQuantities - Length: 3340; CrossSectionArea: 0.0092; OuterSurfaceArea: 1.79133; GrossSurfaceArea: 1.80973; NetSurfaceArea: 1.80973; GrossVolume: 0.030519; NetVolume: 0.030519
Pset_BeamCommon - Reference: 40 x 230; Span: 3340 mm; Slope: 0 rad; Roll: 0 rad; IsExternal: no; LoadBearing: yes
Pset_ConcreteElementGeneral - ConstructionMethod: prefabricated
Pset_Condition - AssessmentCondition: Empty
Pset_EnvironmentalImpactIndicators - Reference: 40 x 230; sets with these values: 2

# IfcBeam: 28_SF_hout_rechthoekig_40 x 230_369, 28_SF_hout_rechthoekig:40 x 230:33589678
In: 010
PredefinedType: BEAM; Material: GVH_i2_naaldhout_generiek
Cpset_Beam - LevelOfAccuracy: in te vullen door Buildwise
IfcClassificationReference - TDS_link: .\05 As Builtdossier\2. Bouwkunde\2.2. Stabiliteit\2.2.0 technische fiche's\TF S 4.9.1.1.1 A - houten roostering sheddak.pdf
IfcElement - Tag: B1; Mark: B1
IfcRoot - Name: 40 x 230
Qto_BeamBaseQuantities - Length: 3340; CrossSectionArea: 0.0092; OuterSurfaceArea: 1.79133; GrossSurfaceArea: 1.80973; NetSurfaceArea: 1.80973; GrossVolume: 0.030519; NetVolume: 0.030519
Pset_BeamCommon - Reference: 40 x 230; Span: 3340 mm; Slope: 0 rad; Roll: 0 rad; IsExternal: no; LoadBearing: yes
Pset_ConcreteElementGeneral - ConstructionMethod: prefabricated
Pset_Condition - AssessmentCondition: Empty
Pset_EnvironmentalImpactIndicators - Reference: 40 x 230; sets with these values: 2

# IfcBeam: 28_SF_hout_rechthoekig_40 x 230_37, 28_SF_hout_rechthoekig:40 x 230:33579912
In: 010
PredefinedType: BEAM; Material: GVH_i2_naaldhout_generiek
Cpset_Beam - LevelOfAccuracy: in te vullen door Buildwise
IfcClassificationReference - TDS_link: .\05 As Builtdossier\2. Bouwkunde\2.2. Stabiliteit\2.2.0 technische fiche's\TF S 4.9.1.1.1 A - houten roostering sheddak.pdf
IfcElement - Tag: B1; Mark: B1
IfcRoot - Name: 40 x 230
Qto_BeamBaseQuantities - Length: 3340; CrossSectionArea: 0.0092; OuterSurfaceArea: 1.79133; GrossSurfaceArea: 1.80973; NetSurfaceArea: 1.80973; GrossVolume: 0.030519; NetVolume: 0.030519
Pset_BeamCommon - Reference: 40 x 230; Span: 3340 mm; Slope: 0 rad; Roll: 0 rad; IsExternal: no; LoadBearing: yes
Pset_ConcreteElementGeneral - ConstructionMethod: prefabricated
Pset_Condition - AssessmentCondition: Empty
Pset_EnvironmentalImpactIndicators - Reference: 40 x 230; sets with these values: 2

# IfcBeam: 28_SF_hout_rechthoekig_40 x 230_371, 28_SF_hout_rechthoekig:40 x 230:33589681
In: 010
PredefinedType: BEAM; Material: GVH_i2_naaldhout_generiek
Cpset_Beam - LevelOfAccuracy: in te vullen door Buildwise
IfcClassificationReference - TDS_link: .\05 As Builtdossier\2. Bouwkunde\2.2. Stabiliteit\2.2.0 technische fiche's\TF S 4.9.1.1.1 A - houten roostering sheddak.pdf
IfcElement - Tag: B1; Mark: B1
IfcRoot - Name: 40 x 230
Qto_BeamBaseQuantities - Length: 3340; CrossSectionArea: 0.0092; OuterSurfaceArea: 1.79133; GrossSurfaceArea: 1.80973; NetSurfaceArea: 1.80973; GrossVolume: 0.030519; NetVolume: 0.030519
Pset_BeamCommon - Reference: 40 x 230; Span: 3340 mm; Slope: 0 rad; Roll: 0 rad; IsExternal: no; LoadBearing: yes
Pset_ConcreteElementGeneral - ConstructionMethod: prefabricated
Pset_Condition - AssessmentCondition: Empty
Pset_EnvironmentalImpactIndicators - Reference: 40 x 230; sets with these values: 2

# IfcBeam: 28_SF_hout_rechthoekig_40 x 230_373, 28_SF_hout_rechthoekig:40 x 230:33589688
In: 010
PredefinedType: BEAM; Material: GVH_i2_naaldhout_generiek
Cpset_Beam - LevelOfAccuracy: in te vullen door Buildwise
IfcClassificationReference - TDS_link: .\05 As Builtdossier\2. Bouwkunde\2.2. Stabiliteit\2.2.0 technische fiche's\TF S 4.9.1.1.1 A - houten roostering sheddak.pdf
IfcElement - Tag: B1; Mark: B1
IfcRoot - Name: 40 x 230
Qto_BeamBaseQuantities - Length: 3340; CrossSectionArea: 0.0092; OuterSurfaceArea: 1.79133; GrossSurfaceArea: 1.80973; NetSurfaceArea: 1.80973; GrossVolume: 0.030519; NetVolume: 0.030519
Pset_BeamCommon - Reference: 40 x 230; Span: 3340 mm; Slope: 0 rad; Roll: 0 rad; IsExternal: no; LoadBearing: yes
Pset_ConcreteElementGeneral - ConstructionMethod: prefabricated
Pset_Condition - AssessmentCondition: Empty
Pset_EnvironmentalImpactIndicators - Reference: 40 x 230; sets with these values: 2

# IfcBeam: 28_SF_hout_rechthoekig_40 x 230_375, 28_SF_hout_rechthoekig:40 x 230:33589691
In: 010
PredefinedType: BEAM; Material: GVH_i2_naaldhout_generiek
Cpset_Beam - LevelOfAccuracy: in te vullen door Buildwise
IfcClassificationReference - TDS_link: .\05 As Builtdossier\2. Bouwkunde\2.2. Stabiliteit\2.2.0 technische fiche's\TF S 4.9.1.1.1 A - houten roostering sheddak.pdf
IfcElement - Tag: B1; Mark: B1
IfcRoot - Name: 40 x 230
Qto_BeamBaseQuantities - Length: 3340; CrossSectionArea: 0.0092; OuterSurfaceArea: 1.79133; GrossSurfaceArea: 1.80973; NetSurfaceArea: 1.80973; GrossVolume: 0.030519; NetVolume: 0.030519
Pset_BeamCommon - Reference: 40 x 230; Span: 3340 mm; Slope: 0 rad; Roll: 0 rad; IsExternal: no; LoadBearing: yes
Pset_ConcreteElementGeneral - ConstructionMethod: prefabricated
Pset_Condition - AssessmentCondition: Empty
Pset_EnvironmentalImpactIndicators - Reference: 40 x 230; sets with these values: 2

# IfcBeam: 28_SF_hout_rechthoekig_40 x 230_377, 28_SF_hout_rechthoekig:40 x 230:33589694
In: 010
PredefinedType: BEAM; Material: GVH_i2_naaldhout_generiek
Cpset_Beam - LevelOfAccuracy: in te vullen door Buildwise
IfcClassificationReference - TDS_link: .\05 As Builtdossier\2. Bouwkunde\2.2. Stabiliteit\2.2.0 technische fiche's\TF S 4.9.1.1.1 A - houten roostering sheddak.pdf
IfcElement - Tag: B1; Mark: B1
IfcRoot - Name: 40 x 230
Qto_BeamBaseQuantities - Length: 3340; CrossSectionArea: 0.0092; OuterSurfaceArea: 1.79133; GrossSurfaceArea: 1.80973; NetSurfaceArea: 1.80973; GrossVolume: 0.030519; NetVolume: 0.030519
Pset_BeamCommon - Reference: 40 x 230; Span: 3340 mm; Slope: 0 rad; Roll: 0 rad; IsExternal: no; LoadBearing: yes
Pset_ConcreteElementGeneral - ConstructionMethod: prefabricated
Pset_Condition - AssessmentCondition: Empty
Pset_EnvironmentalImpactIndicators - Reference: 40 x 230; sets with these values: 2

# IfcBeam: 28_SF_hout_rechthoekig_40 x 230_379, 28_SF_hout_rechthoekig:40 x 230:33589697
In: 010
PredefinedType: BEAM; Material: GVH_i2_naaldhout_generiek
Cpset_Beam - LevelOfAccuracy: in te vullen door Buildwise
IfcClassificationReference - TDS_link: .\05 As Builtdossier\2. Bouwkunde\2.2. Stabiliteit\2.2.0 technische fiche's\TF S 4.9.1.1.1 A - houten roostering sheddak.pdf
IfcElement - Tag: B1; Mark: B1
IfcRoot - Name: 40 x 230
Qto_BeamBaseQuantities - Length: 3340; CrossSectionArea: 0.0092; OuterSurfaceArea: 1.79133; GrossSurfaceArea: 1.80973; NetSurfaceArea: 1.80973; GrossVolume: 0.030519; NetVolume: 0.030519
Pset_BeamCommon - Reference: 40 x 230; Span: 3340 mm; Slope: 0 rad; Roll: 0 rad; IsExternal: no; LoadBearing: yes
Pset_ConcreteElementGeneral - ConstructionMethod: prefabricated
Pset_Condition - AssessmentCondition: Empty
Pset_EnvironmentalImpactIndicators - Reference: 40 x 230; sets with these values: 2

# IfcBeam: 28_SF_hout_rechthoekig_40 x 230_381, 28_SF_hout_rechthoekig:40 x 230:33589700
In: 010
PredefinedType: BEAM; Material: GVH_i2_naaldhout_generiek
Cpset_Beam - LevelOfAccuracy: in te vullen door Buildwise
IfcClassificationReference - TDS_link: .\05 As Builtdossier\2. Bouwkunde\2.2. Stabiliteit\2.2.0 technische fiche's\TF S 4.9.1.1.1 A - houten roostering sheddak.pdf
IfcElement - Tag: B1; Mark: B1
IfcRoot - Name: 40 x 230
Qto_BeamBaseQuantities - Length: 3340; CrossSectionArea: 0.0092; OuterSurfaceArea: 1.79133; GrossSurfaceArea: 1.80973; NetSurfaceArea: 1.80973; GrossVolume: 0.030519; NetVolume: 0.030519
Pset_BeamCommon - Reference: 40 x 230; Span: 3340 mm; Slope: 0 rad; Roll: 0 rad; IsExternal: no; LoadBearing: yes
Pset_ConcreteElementGeneral - ConstructionMethod: prefabricated
Pset_Condition - AssessmentCondition: Empty
Pset_EnvironmentalImpactIndicators - Reference: 40 x 230; sets with these values: 2

# IfcBeam: 28_SF_hout_rechthoekig_40 x 230_383, 28_SF_hout_rechthoekig:40 x 230:33589703
In: 010
PredefinedType: BEAM; Material: GVH_i2_naaldhout_generiek
Cpset_Beam - LevelOfAccuracy: in te vullen door Buildwise
IfcClassificationReference - TDS_link: .\05 As Builtdossier\2. Bouwkunde\2.2. Stabiliteit\2.2.0 technische fiche's\TF S 4.9.1.1.1 A - houten roostering sheddak.pdf
IfcElement - Tag: B1; Mark: B1
IfcRoot - Name: 40 x 230
Qto_BeamBaseQuantities - Length: 3340; CrossSectionArea: 0.0092; OuterSurfaceArea: 1.79133; GrossSurfaceArea: 1.80973; NetSurfaceArea: 1.80973; GrossVolume: 0.030519; NetVolume: 0.030519
Pset_BeamCommon - Reference: 40 x 230; Span: 3340 mm; Slope: 0 rad; Roll: 0 rad; IsExternal: no; LoadBearing: yes
Pset_ConcreteElementGeneral - ConstructionMethod: prefabricated
Pset_Condition - AssessmentCondition: Empty
Pset_EnvironmentalImpactIndicators - Reference: 40 x 230; sets with these values: 2

# IfcBeam: 28_SF_hout_rechthoekig_40 x 230_385, 28_SF_hout_rechthoekig:40 x 230:33589706
In: 010
PredefinedType: BEAM; Material: GVH_i2_naaldhout_generiek
Cpset_Beam - LevelOfAccuracy: in te vullen door Buildwise
IfcClassificationReference - TDS_link: .\05 As Builtdossier\2. Bouwkunde\2.2. Stabiliteit\2.2.0 technische fiche's\TF S 4.9.1.1.1 A - houten roostering sheddak.pdf
IfcElement - Tag: B1; Mark: B1
IfcRoot - Name: 40 x 230
Qto_BeamBaseQuantities - Length: 3340; CrossSectionArea: 0.0092; OuterSurfaceArea: 1.79133; GrossSurfaceArea: 1.80973; NetSurfaceArea: 1.80973; GrossVolume: 0.030519; NetVolume: 0.030519
Pset_BeamCommon - Reference: 40 x 230; Span: 3340 mm; Slope: 0 rad; Roll: 0 rad; IsExternal: no; LoadBearing: yes
Pset_ConcreteElementGeneral - ConstructionMethod: prefabricated
Pset_Condition - AssessmentCondition: Empty
Pset_EnvironmentalImpactIndicators - Reference: 40 x 230; sets with these values: 2

# IfcBeam: 28_SF_hout_rechthoekig_40 x 230_387, 28_SF_hout_rechthoekig:40 x 230:33589709
In: 010
PredefinedType: BEAM; Material: GVH_i2_naaldhout_generiek
Cpset_Beam - LevelOfAccuracy: in te vullen door Buildwise
IfcClassificationReference - TDS_link: .\05 As Builtdossier\2. Bouwkunde\2.2. Stabiliteit\2.2.0 technische fiche's\TF S 4.9.1.1.1 A - houten roostering sheddak.pdf
IfcElement - Tag: B1; Mark: B1
IfcRoot - Name: 40 x 230
Qto_BeamBaseQuantities - Length: 3340; CrossSectionArea: 0.0092; OuterSurfaceArea: 1.79133; GrossSurfaceArea: 1.80973; NetSurfaceArea: 1.80973; GrossVolume: 0.030519; NetVolume: 0.030519
Pset_BeamCommon - Reference: 40 x 230; Span: 3340 mm; Slope: 0 rad; Roll: 0 rad; IsExternal: no; LoadBearing: yes
Pset_ConcreteElementGeneral - ConstructionMethod: prefabricated
Pset_Condition - AssessmentCondition: Empty
Pset_EnvironmentalImpactIndicators - Reference: 40 x 230; sets with these values: 2

# IfcBeam: 28_SF_hout_rechthoekig_40 x 230_389, 28_SF_hout_rechthoekig:40 x 230:33589712
In: 010
PredefinedType: BEAM; Material: GVH_i2_naaldhout_generiek
Cpset_Beam - LevelOfAccuracy: in te vullen door Buildwise
IfcClassificationReference - TDS_link: .\05 As Builtdossier\2. Bouwkunde\2.2. Stabiliteit\2.2.0 technische fiche's\TF S 4.9.1.1.1 A - houten roostering sheddak.pdf
IfcElement - Tag: B1; Mark: B1
IfcRoot - Name: 40 x 230
Qto_BeamBaseQuantities - Length: 3340; CrossSectionArea: 0.0092; OuterSurfaceArea: 1.79133; GrossSurfaceArea: 1.80973; NetSurfaceArea: 1.80973; GrossVolume: 0.030519; NetVolume: 0.030519
Pset_BeamCommon - Reference: 40 x 230; Span: 3340 mm; Slope: 0 rad; Roll: 0 rad; IsExternal: no; LoadBearing: yes
Pset_ConcreteElementGeneral - ConstructionMethod: prefabricated
Pset_Condition - AssessmentCondition: Empty
Pset_EnvironmentalImpactIndicators - Reference: 40 x 230; sets with these values: 2

# IfcBeam: 28_SF_hout_rechthoekig_40 x 230_39, 28_SF_hout_rechthoekig:40 x 230:33579914
In: 010
PredefinedType: BEAM; Material: GVH_i2_naaldhout_generiek
Cpset_Beam - LevelOfAccuracy: in te vullen door Buildwise
IfcClassificationReference - TDS_link: .\05 As Builtdossier\2. Bouwkunde\2.2. Stabiliteit\2.2.0 technische fiche's\TF S 4.9.1.1.1 A - houten roostering sheddak.pdf
IfcElement - Tag: B1; Mark: B1
IfcRoot - Name: 40 x 230
Qto_BeamBaseQuantities - Length: 3340; CrossSectionArea: 0.0092; OuterSurfaceArea: 1.79133; GrossSurfaceArea: 1.80973; NetSurfaceArea: 1.80973; GrossVolume: 0.030519; NetVolume: 0.030519
Pset_BeamCommon - Reference: 40 x 230; Span: 3340 mm; Slope: 0 rad; Roll: 0 rad; IsExternal: no; LoadBearing: yes
Pset_ConcreteElementGeneral - ConstructionMethod: prefabricated
Pset_Condition - AssessmentCondition: Empty
Pset_EnvironmentalImpactIndicators - Reference: 40 x 230; sets with these values: 2

# IfcBeam: 28_SF_hout_rechthoekig_40 x 230_391, 28_SF_hout_rechthoekig:40 x 230:33589715
In: 010
PredefinedType: BEAM; Material: GVH_i2_naaldhout_generiek
Cpset_Beam - LevelOfAccuracy: in te vullen door Buildwise
IfcClassificationReference - TDS_link: .\05 As Builtdossier\2. Bouwkunde\2.2. Stabiliteit\2.2.0 technische fiche's\TF S 4.9.1.1.1 A - houten roostering sheddak.pdf
IfcElement - Tag: B1; Mark: B1
IfcRoot - Name: 40 x 230
Qto_BeamBaseQuantities - Length: 3340; CrossSectionArea: 0.0092; OuterSurfaceArea: 1.79133; GrossSurfaceArea: 1.80973; NetSurfaceArea: 1.80973; GrossVolume: 0.030519; NetVolume: 0.030519
Pset_BeamCommon - Reference: 40 x 230; Span: 3340 mm; Slope: 0 rad; Roll: 0 rad; IsExternal: no; LoadBearing: yes
Pset_ConcreteElementGeneral - ConstructionMethod: prefabricated
Pset_Condition - AssessmentCondition: Empty
Pset_EnvironmentalImpactIndicators - Reference: 40 x 230; sets with these values: 2

# IfcBeam: 28_SF_hout_rechthoekig_40 x 230_393, 28_SF_hout_rechthoekig:40 x 230:33589718
In: 010
PredefinedType: BEAM; Material: GVH_i2_naaldhout_generiek
Cpset_Beam - LevelOfAccuracy: in te vullen door Buildwise
IfcClassificationReference - TDS_link: .\05 As Builtdossier\2. Bouwkunde\2.2. Stabiliteit\2.2.0 technische fiche's\TF S 4.9.1.1.1 A - houten roostering sheddak.pdf
IfcElement - Tag: B1; Mark: B1
IfcRoot - Name: 40 x 230
Qto_BeamBaseQuantities - Length: 3340; CrossSectionArea: 0.0092; OuterSurfaceArea: 1.79133; GrossSurfaceArea: 1.80973; NetSurfaceArea: 1.80973; GrossVolume: 0.030519; NetVolume: 0.030519
Pset_BeamCommon - Reference: 40 x 230; Span: 3340 mm; Slope: 0 rad; Roll: 0 rad; IsExternal: no; LoadBearing: yes
Pset_ConcreteElementGeneral - ConstructionMethod: prefabricated
Pset_Condition - AssessmentCondition: Empty
Pset_EnvironmentalImpactIndicators - Reference: 40 x 230; sets with these values: 2

# IfcBeam: 28_SF_hout_rechthoekig_40 x 230_395, 28_SF_hout_rechthoekig:40 x 230:33589721
In: 010
PredefinedType: BEAM; Material: GVH_i2_naaldhout_generiek
Cpset_Beam - LevelOfAccuracy: in te vullen door Buildwise
IfcClassificationReference - TDS_link: .\05 As Builtdossier\2. Bouwkunde\2.2. Stabiliteit\2.2.0 technische fiche's\TF S 4.9.1.1.1 A - houten roostering sheddak.pdf
IfcElement - Tag: B1; Mark: B1
IfcRoot - Name: 40 x 230
Qto_BeamBaseQuantities - Length: 3340; CrossSectionArea: 0.0092; OuterSurfaceArea: 1.79133; GrossSurfaceArea: 1.80973; NetSurfaceArea: 1.80973; GrossVolume: 0.030519; NetVolume: 0.030519
Pset_BeamCommon - Reference: 40 x 230; Span: 3340 mm; Slope: 0 rad; Roll: 0 rad; IsExternal: no; LoadBearing: yes
Pset_ConcreteElementGeneral - ConstructionMethod: prefabricated
Pset_Condition - AssessmentCondition: Empty
Pset_EnvironmentalImpactIndicators - Reference: 40 x 230; sets with these values: 2

# IfcBeam: 28_SF_hout_rechthoekig_40 x 230_397, 28_SF_hout_rechthoekig:40 x 230:33589724
In: 010
PredefinedType: BEAM; Material: GVH_i2_naaldhout_generiek
Cpset_Beam - LevelOfAccuracy: in te vullen door Buildwise
IfcClassificationReference - TDS_link: .\05 As Builtdossier\2. Bouwkunde\2.2. Stabiliteit\2.2.0 technische fiche's\TF S 4.9.1.1.1 A - houten roostering sheddak.pdf
IfcElement - Tag: B1; Mark: B1
IfcRoot - Name: 40 x 230
Qto_BeamBaseQuantities - Length: 3340; CrossSectionArea: 0.0092; OuterSurfaceArea: 1.79133; GrossSurfaceArea: 1.80973; NetSurfaceArea: 1.80973; GrossVolume: 0.030519; NetVolume: 0.030519
Pset_BeamCommon - Reference: 40 x 230; Span: 3340 mm; Slope: 0 rad; Roll: 0 rad; IsExternal: no; LoadBearing: yes
Pset_ConcreteElementGeneral - ConstructionMethod: prefabricated
Pset_Condition - AssessmentCondition: Empty
Pset_EnvironmentalImpactIndicators - Reference: 40 x 230; sets with these values: 2

# IfcBeam: 28_SF_hout_rechthoekig_40 x 230_399, 28_SF_hout_rechthoekig:40 x 230:33589727
In: 010
PredefinedType: BEAM; Material: GVH_i2_naaldhout_generiek
Cpset_Beam - LevelOfAccuracy: in te vullen door Buildwise
IfcClassificationReference - TDS_link: .\05 As Builtdossier\2. Bouwkunde\2.2. Stabiliteit\2.2.0 technische fiche's\TF S 4.9.1.1.1 A - houten roostering sheddak.pdf
IfcElement - Tag: B1; Mark: B1
IfcRoot - Name: 40 x 230
Qto_BeamBaseQuantities - Length: 3340; CrossSectionArea: 0.0092; OuterSurfaceArea: 1.79133; GrossSurfaceArea: 1.80973; NetSurfaceArea: 1.80973; GrossVolume: 0.030519; NetVolume: 0.030519
Pset_BeamCommon - Reference: 40 x 230; Span: 3340 mm; Slope: 0 rad; Roll: 0 rad; IsExternal: no; LoadBearing: yes
Pset_ConcreteElementGeneral - ConstructionMethod: prefabricated
Pset_Condition - AssessmentCondition: Empty
Pset_EnvironmentalImpactIndicators - Reference: 40 x 230; sets with these values: 2

# IfcBeam: 28_SF_hout_rechthoekig_40 x 230_401, 28_SF_hout_rechthoekig:40 x 230:33589731
In: 010
PredefinedType: BEAM; Material: GVH_i2_naaldhout_generiek
Cpset_Beam - LevelOfAccuracy: in te vullen door Buildwise
IfcClassificationReference - TDS_link: .\05 As Builtdossier\2. Bouwkunde\2.2. Stabiliteit\2.2.0 technische fiche's\TF S 4.9.1.1.1 A - houten roostering sheddak.pdf
IfcElement - Tag: B1; Mark: B1
IfcRoot - Name: 40 x 230
Qto_BeamBaseQuantities - Length: 3340; CrossSectionArea: 0.0092; OuterSurfaceArea: 1.79133; GrossSurfaceArea: 1.80973; NetSurfaceArea: 1.80973; GrossVolume: 0.0305189; NetVolume: 0.0305189
Pset_BeamCommon - Reference: 40 x 230; Span: 3340 mm; Slope: 0 rad; Roll: 0 rad; IsExternal: no; LoadBearing: yes
Pset_ConcreteElementGeneral - ConstructionMethod: prefabricated
Pset_Condition - AssessmentCondition: Empty
Pset_EnvironmentalImpactIndicators - Reference: 40 x 230; sets with these values: 2

# IfcBeam: 28_SF_hout_rechthoekig_40 x 230_403, 28_SF_hout_rechthoekig:40 x 230:33589734
In: 010
PredefinedType: BEAM; Material: GVH_i2_naaldhout_generiek
Cpset_Beam - LevelOfAccuracy: in te vullen door Buildwise
IfcClassificationReference - TDS_link: .\05 As Builtdossier\2. Bouwkunde\2.2. Stabiliteit\2.2.0 technische fiche's\TF S 4.9.1.1.1 A - houten roostering sheddak.pdf
IfcElement - Tag: B1; Mark: B1
IfcRoot - Name: 40 x 230
Qto_BeamBaseQuantities - Length: 3340; CrossSectionArea: 0.0092; OuterSurfaceArea: 1.79133; GrossSurfaceArea: 1.80973; NetSurfaceArea: 1.80973; GrossVolume: 0.0305189; NetVolume: 0.0305189
Pset_BeamCommon - Reference: 40 x 230; Span: 3340 mm; Slope: 0 rad; Roll: 0 rad; IsExternal: no; LoadBearing: yes
Pset_ConcreteElementGeneral - ConstructionMethod: prefabricated
Pset_Condition - AssessmentCondition: Empty
Pset_EnvironmentalImpactIndicators - Reference: 40 x 230; sets with these values: 2

# IfcBeam: 28_SF_hout_rechthoekig_40 x 230_405, 28_SF_hout_rechthoekig:40 x 230:33589741
In: 010
PredefinedType: BEAM; Material: GVH_i2_naaldhout_generiek
Cpset_Beam - LevelOfAccuracy: in te vullen door Buildwise
IfcClassificationReference - TDS_link: .\05 As Builtdossier\2. Bouwkunde\2.2. Stabiliteit\2.2.0 technische fiche's\TF S 4.9.1.1.1 A - houten roostering sheddak.pdf
IfcElement - Tag: B1; Mark: B1
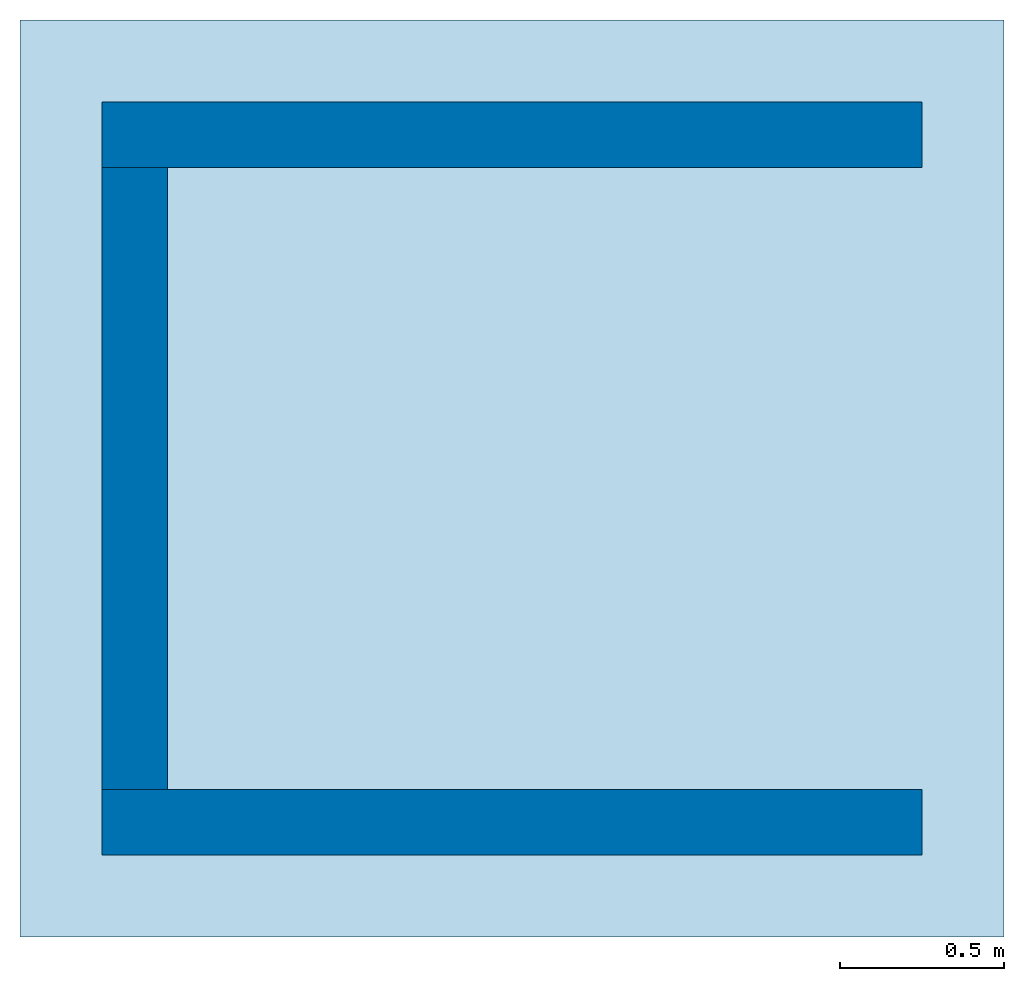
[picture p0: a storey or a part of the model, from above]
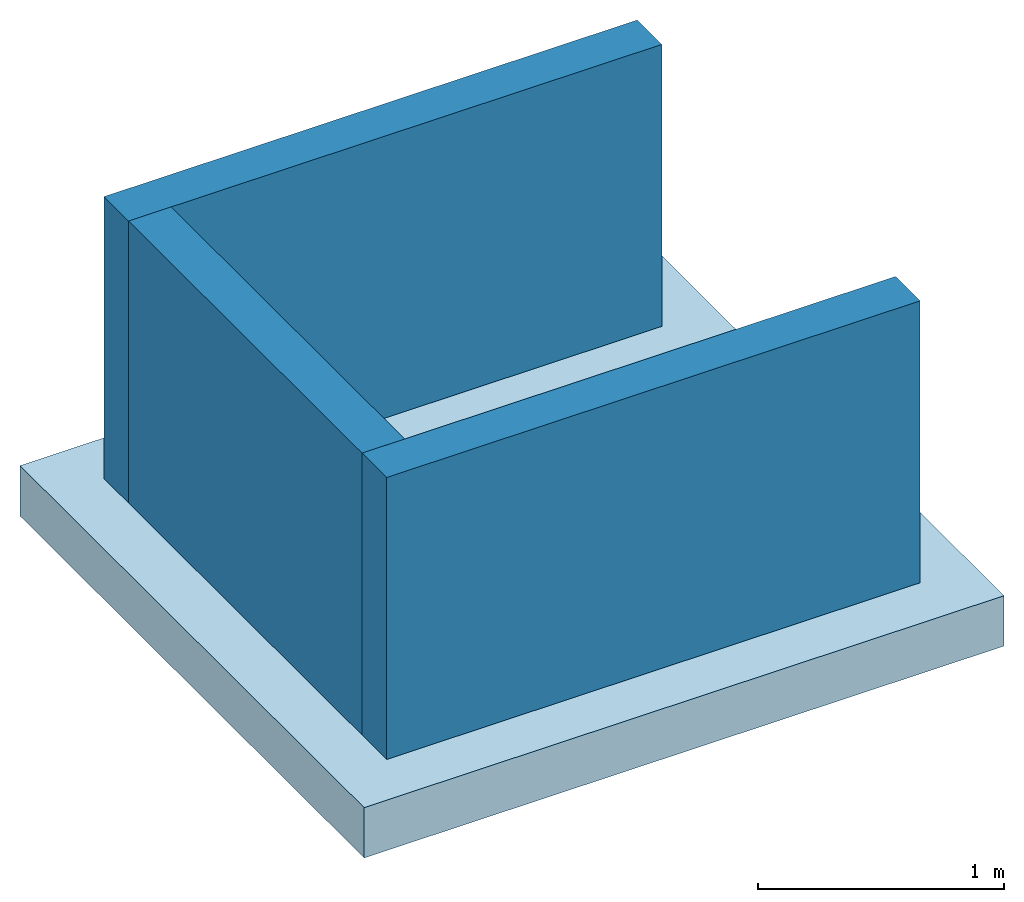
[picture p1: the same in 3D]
Properties of the parts of a building model (IFC4X3_ADD2), part 4 of 28

# IfcBeam: 28_SF_hout_rechthoekig_40 x 230_405, 28_SF_hout_rechthoekig:40 x 230:33589741
IfcRoot - Name: 40 x 230
Qto_BeamBaseQuantities - Length: 3340; CrossSectionArea: 0.0092; OuterSurfaceArea: 1.79133; GrossSurfaceArea: 1.80973; NetSurfaceArea: 1.80973; GrossVolume: 0.0305189; NetVolume: 0.0305189
Pset_BeamCommon - Reference: 40 x 230; Span: 3340 mm; Slope: 0 rad; Roll: 0 rad; IsExternal: no; LoadBearing: yes
Pset_ConcreteElementGeneral - ConstructionMethod: prefabricated
Pset_Condition - AssessmentCondition: Empty
Pset_EnvironmentalImpactIndicators - Reference: 40 x 230; sets with these values: 2

# IfcBeam: 28_SF_hout_rechthoekig_40 x 230_407, 28_SF_hout_rechthoekig:40 x 230:33589744
In: 010
PredefinedType: BEAM; Material: GVH_i2_naaldhout_generiek
Cpset_Beam - LevelOfAccuracy: in te vullen door Buildwise
IfcClassificationReference - TDS_link: .\05 As Builtdossier\2. Bouwkunde\2.2. Stabiliteit\2.2.0 technische fiche's\TF S 4.9.1.1.1 A - houten roostering sheddak.pdf
IfcElement - Tag: B1; Mark: B1
IfcRoot - Name: 40 x 230
Qto_BeamBaseQuantities - Length: 3340; CrossSectionArea: 0.0092; OuterSurfaceArea: 1.79133; GrossSurfaceArea: 1.80973; NetSurfaceArea: 1.80973; GrossVolume: 0.0305189; NetVolume: 0.0305189
Pset_BeamCommon - Reference: 40 x 230; Span: 3340 mm; Slope: 0 rad; Roll: 0 rad; IsExternal: no; LoadBearing: yes
Pset_ConcreteElementGeneral - ConstructionMethod: prefabricated
Pset_Condition - AssessmentCondition: Empty
Pset_EnvironmentalImpactIndicators - Reference: 40 x 230; sets with these values: 2

# IfcBeam: 28_SF_hout_rechthoekig_40 x 230_409, 28_SF_hout_rechthoekig:40 x 230:33589747
In: 010
PredefinedType: BEAM; Material: GVH_i2_naaldhout_generiek
Cpset_Beam - LevelOfAccuracy: in te vullen door Buildwise
IfcClassificationReference - TDS_link: .\05 As Builtdossier\2. Bouwkunde\2.2. Stabiliteit\2.2.0 technische fiche's\TF S 4.9.1.1.1 A - houten roostering sheddak.pdf
IfcElement - Tag: B1; Mark: B1
IfcRoot - Name: 40 x 230
Qto_BeamBaseQuantities - Length: 3340; CrossSectionArea: 0.0092; OuterSurfaceArea: 1.79133; GrossSurfaceArea: 1.80973; NetSurfaceArea: 1.80973; GrossVolume: 0.0305189; NetVolume: 0.0305189
Pset_BeamCommon - Reference: 40 x 230; Span: 3340 mm; Slope: 0 rad; Roll: 0 rad; IsExternal: no; LoadBearing: yes
Pset_ConcreteElementGeneral - ConstructionMethod: prefabricated
Pset_Condition - AssessmentCondition: Empty
Pset_EnvironmentalImpactIndicators - Reference: 40 x 230; sets with these values: 2

# IfcBeam: 28_SF_hout_rechthoekig_40 x 230_41, 28_SF_hout_rechthoekig:40 x 230:33579916
In: 010
PredefinedType: BEAM; Material: GVH_i2_naaldhout_generiek
Cpset_Beam - LevelOfAccuracy: in te vullen door Buildwise
IfcClassificationReference - TDS_link: .\05 As Builtdossier\2. Bouwkunde\2.2. Stabiliteit\2.2.0 technische fiche's\TF S 4.9.1.1.1 A - houten roostering sheddak.pdf
IfcElement - Tag: B1; Mark: B1
IfcRoot - Name: 40 x 230
Qto_BeamBaseQuantities - Length: 3340; CrossSectionArea: 0.0092; OuterSurfaceArea: 1.79133; GrossSurfaceArea: 1.80973; NetSurfaceArea: 1.80973; GrossVolume: 0.030519; NetVolume: 0.030519
Pset_BeamCommon - Reference: 40 x 230; Span: 3340 mm; Slope: 0 rad; Roll: 0 rad; IsExternal: no; LoadBearing: yes
Pset_ConcreteElementGeneral - ConstructionMethod: prefabricated
Pset_Condition - AssessmentCondition: Empty
Pset_EnvironmentalImpactIndicators - Reference: 40 x 230; sets with these values: 2

# IfcBeam: 28_SF_hout_rechthoekig_40 x 230_411, 28_SF_hout_rechthoekig:40 x 230:33589750
In: 010
PredefinedType: BEAM; Material: GVH_i2_naaldhout_generiek
Cpset_Beam - LevelOfAccuracy: in te vullen door Buildwise
IfcClassificationReference - TDS_link: .\05 As Builtdossier\2. Bouwkunde\2.2. Stabiliteit\2.2.0 technische fiche's\TF S 4.9.1.1.1 A - houten roostering sheddak.pdf
IfcElement - Tag: B1; Mark: B1
IfcRoot - Name: 40 x 230
Qto_BeamBaseQuantities - Length: 3340; CrossSectionArea: 0.0092; OuterSurfaceArea: 1.79133; GrossSurfaceArea: 1.80973; NetSurfaceArea: 1.80973; GrossVolume: 0.0305189; NetVolume: 0.0305189
Pset_BeamCommon - Reference: 40 x 230; Span: 3340 mm; Slope: 0 rad; Roll: 0 rad; IsExternal: no; LoadBearing: yes
Pset_ConcreteElementGeneral - ConstructionMethod: prefabricated
Pset_Condition - AssessmentCondition: Empty
Pset_EnvironmentalImpactIndicators - Reference: 40 x 230; sets with these values: 2

# IfcBeam: 28_SF_hout_rechthoekig_40 x 230_413, 28_SF_hout_rechthoekig:40 x 230:33589753
In: 010
PredefinedType: BEAM; Material: GVH_i2_naaldhout_generiek
Cpset_Beam - LevelOfAccuracy: in te vullen door Buildwise
IfcClassificationReference - TDS_link: .\05 As Builtdossier\2. Bouwkunde\2.2. Stabiliteit\2.2.0 technische fiche's\TF S 4.9.1.1.1 A - houten roostering sheddak.pdf
IfcElement - Tag: B1; Mark: B1
IfcRoot - Name: 40 x 230
Qto_BeamBaseQuantities - Length: 3340; CrossSectionArea: 0.0092; OuterSurfaceArea: 1.79133; GrossSurfaceArea: 1.80973; NetSurfaceArea: 1.80973; GrossVolume: 0.0305189; NetVolume: 0.0305189
Pset_BeamCommon - Reference: 40 x 230; Span: 3340 mm; Slope: 0 rad; Roll: 0 rad; IsExternal: no; LoadBearing: yes
Pset_ConcreteElementGeneral - ConstructionMethod: prefabricated
Pset_Condition - AssessmentCondition: Empty
Pset_EnvironmentalImpactIndicators - Reference: 40 x 230; sets with these values: 2

# IfcBeam: 28_SF_hout_rechthoekig_40 x 230_415, 28_SF_hout_rechthoekig:40 x 230:33589756
In: 010
PredefinedType: BEAM; Material: GVH_i2_naaldhout_generiek
Cpset_Beam - LevelOfAccuracy: in te vullen door Buildwise
IfcClassificationReference - TDS_link: .\05 As Builtdossier\2. Bouwkunde\2.2. Stabiliteit\2.2.0 technische fiche's\TF S 4.9.1.1.1 A - houten roostering sheddak.pdf
IfcElement - Tag: B1; Mark: B1
IfcRoot - Name: 40 x 230
Qto_BeamBaseQuantities - Length: 3340; CrossSectionArea: 0.0092; OuterSurfaceArea: 1.79133; GrossSurfaceArea: 1.80973; NetSurfaceArea: 1.80973; GrossVolume: 0.0305189; NetVolume: 0.0305189
Pset_BeamCommon - Reference: 40 x 230; Span: 3340 mm; Slope: 0 rad; Roll: 0 rad; IsExternal: no; LoadBearing: yes
Pset_ConcreteElementGeneral - ConstructionMethod: prefabricated
Pset_Condition - AssessmentCondition: Empty
Pset_EnvironmentalImpactIndicators - Reference: 40 x 230; sets with these values: 2

# IfcBeam: 28_SF_hout_rechthoekig_40 x 230_417, 28_SF_hout_rechthoekig:40 x 230:33589759
In: 010
PredefinedType: BEAM; Material: GVH_i2_naaldhout_generiek
Cpset_Beam - LevelOfAccuracy: in te vullen door Buildwise
IfcClassificationReference - TDS_link: .\05 As Builtdossier\2. Bouwkunde\2.2. Stabiliteit\2.2.0 technische fiche's\TF S 4.9.1.1.1 A - houten roostering sheddak.pdf
IfcElement - Tag: B1; Mark: B1
IfcRoot - Name: 40 x 230
Qto_BeamBaseQuantities - Length: 3340; CrossSectionArea: 0.0092; OuterSurfaceArea: 1.79133; GrossSurfaceArea: 1.80973; NetSurfaceArea: 1.80973; GrossVolume: 0.0305189; NetVolume: 0.0305189
Pset_BeamCommon - Reference: 40 x 230; Span: 3340 mm; Slope: 0 rad; Roll: 0 rad; IsExternal: no; LoadBearing: yes
Pset_ConcreteElementGeneral - ConstructionMethod: prefabricated
Pset_Condition - AssessmentCondition: Empty
Pset_EnvironmentalImpactIndicators - Reference: 40 x 230; sets with these values: 2

# IfcBeam: 28_SF_hout_rechthoekig_40 x 230_419, 28_SF_hout_rechthoekig:40 x 230:33589762
In: 010
PredefinedType: BEAM; Material: GVH_i2_naaldhout_generiek
Cpset_Beam - LevelOfAccuracy: in te vullen door Buildwise
IfcClassificationReference - TDS_link: .\05 As Builtdossier\2. Bouwkunde\2.2. Stabiliteit\2.2.0 technische fiche's\TF S 4.9.1.1.1 A - houten roostering sheddak.pdf
IfcElement - Tag: B1; Mark: B1
IfcRoot - Name: 40 x 230
Qto_BeamBaseQuantities - Length: 3340; CrossSectionArea: 0.0092; OuterSurfaceArea: 1.79133; GrossSurfaceArea: 1.80973; NetSurfaceArea: 1.80973; GrossVolume: 0.0305189; NetVolume: 0.0305189
Pset_BeamCommon - Reference: 40 x 230; Span: 3340 mm; Slope: 0 rad; Roll: 0 rad; IsExternal: no; LoadBearing: yes
Pset_ConcreteElementGeneral - ConstructionMethod: prefabricated
Pset_Condition - AssessmentCondition: Empty
Pset_EnvironmentalImpactIndicators - Reference: 40 x 230; sets with these values: 2

# IfcBeam: 28_SF_hout_rechthoekig_40 x 230_421, 28_SF_hout_rechthoekig:40 x 230:33589765
In: 010
PredefinedType: BEAM; Material: GVH_i2_naaldhout_generiek
Cpset_Beam - LevelOfAccuracy: in te vullen door Buildwise
IfcClassificationReference - TDS_link: .\05 As Builtdossier\2. Bouwkunde\2.2. Stabiliteit\2.2.0 technische fiche's\TF S 4.9.1.1.1 A - houten roostering sheddak.pdf
IfcElement - Tag: B1; Mark: B1
IfcRoot - Name: 40 x 230
Qto_BeamBaseQuantities - Length: 3340; CrossSectionArea: 0.0092; OuterSurfaceArea: 1.79133; GrossSurfaceArea: 1.80973; NetSurfaceArea: 1.80973; GrossVolume: 0.0305189; NetVolume: 0.0305189
Pset_BeamCommon - Reference: 40 x 230; Span: 3340 mm; Slope: 0 rad; Roll: 0 rad; IsExternal: no; LoadBearing: yes
Pset_ConcreteElementGeneral - ConstructionMethod: prefabricated
Pset_Condition - AssessmentCondition: Empty
Pset_EnvironmentalImpactIndicators - Reference: 40 x 230; sets with these values: 2

# IfcBeam: 28_SF_hout_rechthoekig_40 x 230_423, 28_SF_hout_rechthoekig:40 x 230:33589768
In: 010
PredefinedType: BEAM; Material: GVH_i2_naaldhout_generiek
Cpset_Beam - LevelOfAccuracy: in te vullen door Buildwise
IfcClassificationReference - TDS_link: .\05 As Builtdossier\2. Bouwkunde\2.2. Stabiliteit\2.2.0 technische fiche's\TF S 4.9.1.1.1 A - houten roostering sheddak.pdf
IfcElement - Tag: B1; Mark: B1
IfcRoot - Name: 40 x 230
Qto_BeamBaseQuantities - Length: 3340; CrossSectionArea: 0.0092; OuterSurfaceArea: 1.79133; GrossSurfaceArea: 1.80973; NetSurfaceArea: 1.80973; GrossVolume: 0.0305189; NetVolume: 0.0305189
Pset_BeamCommon - Reference: 40 x 230; Span: 3340 mm; Slope: 0 rad; Roll: 0 rad; IsExternal: no; LoadBearing: yes
Pset_ConcreteElementGeneral - ConstructionMethod: prefabricated
Pset_Condition - AssessmentCondition: Empty
Pset_EnvironmentalImpactIndicators - Reference: 40 x 230; sets with these values: 2

# IfcBeam: 28_SF_hout_rechthoekig_40 x 230_425, 28_SF_hout_rechthoekig:40 x 230:33589771
In: 010
PredefinedType: BEAM; Material: GVH_i2_naaldhout_generiek
Cpset_Beam - LevelOfAccuracy: in te vullen door Buildwise
IfcClassificationReference - TDS_link: .\05 As Builtdossier\2. Bouwkunde\2.2. Stabiliteit\2.2.0 technische fiche's\TF S 4.9.1.1.1 A - houten roostering sheddak.pdf
IfcElement - Tag: B1; Mark: B1
IfcRoot - Name: 40 x 230
Qto_BeamBaseQuantities - Length: 3340; CrossSectionArea: 0.0092; OuterSurfaceArea: 1.79133; GrossSurfaceArea: 1.80973; NetSurfaceArea: 1.80973; GrossVolume: 0.0305189; NetVolume: 0.0305189
Pset_BeamCommon - Reference: 40 x 230; Span: 3340 mm; Slope: 0 rad; Roll: 0 rad; IsExternal: no; LoadBearing: yes
Pset_ConcreteElementGeneral - ConstructionMethod: prefabricated
Pset_Condition - AssessmentCondition: Empty
Pset_EnvironmentalImpactIndicators - Reference: 40 x 230; sets with these values: 2

# IfcBeam: 28_SF_hout_rechthoekig_40 x 230_427, 28_SF_hout_rechthoekig:40 x 230:33589774
In: 010
PredefinedType: BEAM; Material: GVH_i2_naaldhout_generiek
Cpset_Beam - LevelOfAccuracy: in te vullen door Buildwise
IfcClassificationReference - TDS_link: .\05 As Builtdossier\2. Bouwkunde\2.2. Stabiliteit\2.2.0 technische fiche's\TF S 4.9.1.1.1 A - houten roostering sheddak.pdf
IfcElement - Tag: B1; Mark: B1
IfcRoot - Name: 40 x 230
Qto_BeamBaseQuantities - Length: 3340; CrossSectionArea: 0.0092; OuterSurfaceArea: 1.79133; GrossSurfaceArea: 1.80973; NetSurfaceArea: 1.80973; GrossVolume: 0.0305189; NetVolume: 0.0305189
Pset_BeamCommon - Reference: 40 x 230; Span: 3340 mm; Slope: 0 rad; Roll: 0 rad; IsExternal: no; LoadBearing: yes
Pset_ConcreteElementGeneral - ConstructionMethod: prefabricated
Pset_Condition - AssessmentCondition: Empty
Pset_EnvironmentalImpactIndicators - Reference: 40 x 230; sets with these values: 2

# IfcBeam: 28_SF_hout_rechthoekig_40 x 230_429, 28_SF_hout_rechthoekig:40 x 230:33589777
In: 010
PredefinedType: BEAM; Material: GVH_i2_naaldhout_generiek
Cpset_Beam - LevelOfAccuracy: in te vullen door Buildwise
IfcClassificationReference - TDS_link: .\05 As Builtdossier\2. Bouwkunde\2.2. Stabiliteit\2.2.0 technische fiche's\TF S 4.9.1.1.1 A - houten roostering sheddak.pdf
IfcElement - Tag: B1; Mark: B1
IfcRoot - Name: 40 x 230
Qto_BeamBaseQuantities - Length: 3340; CrossSectionArea: 0.0092; OuterSurfaceArea: 1.79133; GrossSurfaceArea: 1.80973; NetSurfaceArea: 1.80973; GrossVolume: 0.0305189; NetVolume: 0.0305189
Pset_BeamCommon - Reference: 40 x 230; Span: 3340 mm; Slope: 0 rad; Roll: 0 rad; IsExternal: no; LoadBearing: yes
Pset_ConcreteElementGeneral - ConstructionMethod: prefabricated
Pset_Condition - AssessmentCondition: Empty
Pset_EnvironmentalImpactIndicators - Reference: 40 x 230; sets with these values: 2

# IfcBeam: 28_SF_hout_rechthoekig_40 x 230_43, 28_SF_hout_rechthoekig:40 x 230:33579918
In: 010
PredefinedType: BEAM; Material: GVH_i2_naaldhout_generiek
Cpset_Beam - LevelOfAccuracy: in te vullen door Buildwise
IfcClassificationReference - TDS_link: .\05 As Builtdossier\2. Bouwkunde\2.2. Stabiliteit\2.2.0 technische fiche's\TF S 4.9.1.1.1 A - houten roostering sheddak.pdf
IfcElement - Tag: B1; Mark: B1
IfcRoot - Name: 40 x 230
Qto_BeamBaseQuantities - Length: 3340; CrossSectionArea: 0.0092; OuterSurfaceArea: 1.79133; GrossSurfaceArea: 1.80973; NetSurfaceArea: 1.80973; GrossVolume: 0.030519; NetVolume: 0.030519
Pset_BeamCommon - Reference: 40 x 230; Span: 3340 mm; Slope: 0 rad; Roll: 0 rad; IsExternal: no; LoadBearing: yes
Pset_ConcreteElementGeneral - ConstructionMethod: prefabricated
Pset_Condition - AssessmentCondition: Empty
Pset_EnvironmentalImpactIndicators - Reference: 40 x 230; sets with these values: 2

# IfcBeam: 28_SF_hout_rechthoekig_40 x 230_431, 28_SF_hout_rechthoekig:40 x 230:33589780
In: 010
PredefinedType: BEAM; Material: GVH_i2_naaldhout_generiek
Cpset_Beam - LevelOfAccuracy: in te vullen door Buildwise
IfcClassificationReference - TDS_link: .\05 As Builtdossier\2. Bouwkunde\2.2. Stabiliteit\2.2.0 technische fiche's\TF S 4.9.1.1.1 A - houten roostering sheddak.pdf
IfcElement - Tag: B1; Mark: B1
IfcRoot - Name: 40 x 230
Qto_BeamBaseQuantities - Length: 3340; CrossSectionArea: 0.0092; OuterSurfaceArea: 1.79133; GrossSurfaceArea: 1.80973; NetSurfaceArea: 1.80973; GrossVolume: 0.0305189; NetVolume: 0.0305189
Pset_BeamCommon - Reference: 40 x 230; Span: 3340 mm; Slope: 0 rad; Roll: 0 rad; IsExternal: no; LoadBearing: yes
Pset_ConcreteElementGeneral - ConstructionMethod: prefabricated
Pset_Condition - AssessmentCondition: Empty
Pset_EnvironmentalImpactIndicators - Reference: 40 x 230; sets with these values: 2

# IfcBeam: 28_SF_hout_rechthoekig_40 x 230_433, 28_SF_hout_rechthoekig:40 x 230:33589787
In: 010
PredefinedType: BEAM; Material: GVH_i2_naaldhout_generiek
Cpset_Beam - LevelOfAccuracy: in te vullen door Buildwise
IfcClassificationReference - TDS_link: .\05 As Builtdossier\2. Bouwkunde\2.2. Stabiliteit\2.2.0 technische fiche's\TF S 4.9.1.1.1 A - houten roostering sheddak.pdf
IfcElement - Tag: B1; Mark: B1
IfcRoot - Name: 40 x 230
Qto_BeamBaseQuantities - Length: 3340; CrossSectionArea: 0.0092; OuterSurfaceArea: 1.79133; GrossSurfaceArea: 1.80973; NetSurfaceArea: 1.80973; GrossVolume: 0.030519; NetVolume: 0.030519
Pset_BeamCommon - Reference: 40 x 230; Span: 3340 mm; Slope: 0 rad; Roll: 0 rad; IsExternal: no; LoadBearing: yes
Pset_ConcreteElementGeneral - ConstructionMethod: prefabricated
Pset_Condition - AssessmentCondition: Empty
Pset_EnvironmentalImpactIndicators - Reference: 40 x 230; sets with these values: 2

# IfcBeam: 28_SF_hout_rechthoekig_40 x 230_435, 28_SF_hout_rechthoekig:40 x 230:33589794
In: 010
PredefinedType: BEAM; Material: GVH_i2_naaldhout_generiek
Cpset_Beam - LevelOfAccuracy: in te vullen door Buildwise
IfcClassificationReference - TDS_link: .\05 As Builtdossier\2. Bouwkunde\2.2. Stabiliteit\2.2.0 technische fiche's\TF S 4.9.1.1.1 A - houten roostering sheddak.pdf
IfcElement - Tag: B1; Mark: B1
IfcRoot - Name: 40 x 230
Qto_BeamBaseQuantities - Length: 3340; CrossSectionArea: 0.0092; OuterSurfaceArea: 1.79133; GrossSurfaceArea: 1.80973; NetSurfaceArea: 1.80973; GrossVolume: 0.030519; NetVolume: 0.030519
Pset_BeamCommon - Reference: 40 x 230; Span: 3340 mm; Slope: 0 rad; Roll: 0 rad; IsExternal: no; LoadBearing: yes
Pset_ConcreteElementGeneral - ConstructionMethod: prefabricated
Pset_Condition - AssessmentCondition: Empty
Pset_EnvironmentalImpactIndicators - Reference: 40 x 230; sets with these values: 2

# IfcBeam: 28_SF_hout_rechthoekig_40 x 230_437, 28_SF_hout_rechthoekig:40 x 230:33589797
In: 010
PredefinedType: BEAM; Material: GVH_i2_naaldhout_generiek
Cpset_Beam - LevelOfAccuracy: in te vullen door Buildwise
IfcClassificationReference - TDS_link: .\05 As Builtdossier\2. Bouwkunde\2.2. Stabiliteit\2.2.0 technische fiche's\TF S 4.9.1.1.1 A - houten roostering sheddak.pdf
IfcElement - Tag: B1; Mark: B1
IfcRoot - Name: 40 x 230
Qto_BeamBaseQuantities - Length: 3340; CrossSectionArea: 0.0092; OuterSurfaceArea: 1.79133; GrossSurfaceArea: 1.80973; NetSurfaceArea: 1.80973; GrossVolume: 0.030519; NetVolume: 0.030519
Pset_BeamCommon - Reference: 40 x 230; Span: 3340 mm; Slope: 0 rad; Roll: 0 rad; IsExternal: no; LoadBearing: yes
Pset_ConcreteElementGeneral - ConstructionMethod: prefabricated
Pset_Condition - AssessmentCondition: Empty
Pset_EnvironmentalImpactIndicators - Reference: 40 x 230; sets with these values: 2

# IfcBeam: 28_SF_hout_rechthoekig_40 x 230_439, 28_SF_hout_rechthoekig:40 x 230:33589800
In: 010
PredefinedType: BEAM; Material: GVH_i2_naaldhout_generiek
Cpset_Beam - LevelOfAccuracy: in te vullen door Buildwise
IfcClassificationReference - TDS_link: .\05 As Builtdossier\2. Bouwkunde\2.2. Stabiliteit\2.2.0 technische fiche's\TF S 4.9.1.1.1 A - houten roostering sheddak.pdf
IfcElement - Tag: B1; Mark: B1
IfcRoot - Name: 40 x 230
Qto_BeamBaseQuantities - Length: 3340; CrossSectionArea: 0.0092; OuterSurfaceArea: 1.79133; GrossSurfaceArea: 1.80973; NetSurfaceArea: 1.80973; GrossVolume: 0.030519; NetVolume: 0.030519
Pset_BeamCommon - Reference: 40 x 230; Span: 3340 mm; Slope: 0 rad; Roll: 0 rad; IsExternal: no; LoadBearing: yes
Pset_ConcreteElementGeneral - ConstructionMethod: prefabricated
Pset_Condition - AssessmentCondition: Empty
Pset_EnvironmentalImpactIndicators - Reference: 40 x 230; sets with these values: 2

# IfcBeam: 28_SF_hout_rechthoekig_40 x 230_441, 28_SF_hout_rechthoekig:40 x 230:33589803
In: 010
PredefinedType: BEAM; Material: GVH_i2_naaldhout_generiek
Cpset_Beam - LevelOfAccuracy: in te vullen door Buildwise
IfcClassificationReference - TDS_link: .\05 As Builtdossier\2. Bouwkunde\2.2. Stabiliteit\2.2.0 technische fiche's\TF S 4.9.1.1.1 A - houten roostering sheddak.pdf
IfcElement - Tag: B1; Mark: B1
IfcRoot - Name: 40 x 230
Qto_BeamBaseQuantities - Length: 3340; CrossSectionArea: 0.0092; OuterSurfaceArea: 1.79133; GrossSurfaceArea: 1.80973; NetSurfaceArea: 1.80973; GrossVolume: 0.030519; NetVolume: 0.030519
Pset_BeamCommon - Reference: 40 x 230; Span: 3340 mm; Slope: 0 rad; Roll: 0 rad; IsExternal: no; LoadBearing: yes
Pset_ConcreteElementGeneral - ConstructionMethod: prefabricated
Pset_Condition - AssessmentCondition: Empty
Pset_EnvironmentalImpactIndicators - Reference: 40 x 230; sets with these values: 2

# IfcBeam: 28_SF_hout_rechthoekig_40 x 230_443, 28_SF_hout_rechthoekig:40 x 230:33589806
In: 010
PredefinedType: BEAM; Material: GVH_i2_naaldhout_generiek
Cpset_Beam - LevelOfAccuracy: in te vullen door Buildwise
IfcClassificationReference - TDS_link: .\05 As Builtdossier\2. Bouwkunde\2.2. Stabiliteit\2.2.0 technische fiche's\TF S 4.9.1.1.1 A - houten roostering sheddak.pdf
IfcElement - Tag: B1; Mark: B1
IfcRoot - Name: 40 x 230
Qto_BeamBaseQuantities - Length: 3340; CrossSectionArea: 0.0092; OuterSurfaceArea: 1.79133; GrossSurfaceArea: 1.80973; NetSurfaceArea: 1.80973; GrossVolume: 0.030519; NetVolume: 0.030519
Pset_BeamCommon - Reference: 40 x 230; Span: 3340 mm; Slope: 0 rad; Roll: 0 rad; IsExternal: no; LoadBearing: yes
Pset_ConcreteElementGeneral - ConstructionMethod: prefabricated
Pset_Condition - AssessmentCondition: Empty
Pset_EnvironmentalImpactIndicators - Reference: 40 x 230; sets with these values: 2

# IfcBeam: 28_SF_hout_rechthoekig_40 x 230_445, 28_SF_hout_rechthoekig:40 x 230:33589809
In: 010
PredefinedType: BEAM; Material: GVH_i2_naaldhout_generiek
Cpset_Beam - LevelOfAccuracy: in te vullen door Buildwise
IfcClassificationReference - TDS_link: .\05 As Builtdossier\2. Bouwkunde\2.2. Stabiliteit\2.2.0 technische fiche's\TF S 4.9.1.1.1 A - houten roostering sheddak.pdf
IfcElement - Tag: B1; Mark: B1
IfcRoot - Name: 40 x 230
Qto_BeamBaseQuantities - Length: 3340; CrossSectionArea: 0.0092; OuterSurfaceArea: 1.79133; GrossSurfaceArea: 1.80973; NetSurfaceArea: 1.80973; GrossVolume: 0.030519; NetVolume: 0.030519
Pset_BeamCommon - Reference: 40 x 230; Span: 3340 mm; Slope: 0 rad; Roll: 0 rad; IsExternal: no; LoadBearing: yes
Pset_ConcreteElementGeneral - ConstructionMethod: prefabricated
Pset_Condition - AssessmentCondition: Empty
Pset_EnvironmentalImpactIndicators - Reference: 40 x 230; sets with these values: 2

# IfcBeam: 28_SF_hout_rechthoekig_40 x 230_447, 28_SF_hout_rechthoekig:40 x 230:33589812
In: 010
PredefinedType: BEAM; Material: GVH_i2_naaldhout_generiek
Cpset_Beam - LevelOfAccuracy: in te vullen door Buildwise
IfcClassificationReference - TDS_link: .\05 As Builtdossier\2. Bouwkunde\2.2. Stabiliteit\2.2.0 technische fiche's\TF S 4.9.1.1.1 A - houten roostering sheddak.pdf
IfcElement - Tag: B1; Mark: B1
IfcRoot - Name: 40 x 230
Qto_BeamBaseQuantities - Length: 3340; CrossSectionArea: 0.0092; OuterSurfaceArea: 1.79133; GrossSurfaceArea: 1.80973; NetSurfaceArea: 1.80973; GrossVolume: 0.030519; NetVolume: 0.030519
Pset_BeamCommon - Reference: 40 x 230; Span: 3340 mm; Slope: 0 rad; Roll: 0 rad; IsExternal: no; LoadBearing: yes
Pset_ConcreteElementGeneral - ConstructionMethod: prefabricated
Pset_Condition - AssessmentCondition: Empty
Pset_EnvironmentalImpactIndicators - Reference: 40 x 230; sets with these values: 2

# IfcBeam: 28_SF_hout_rechthoekig_40 x 230_449, 28_SF_hout_rechthoekig:40 x 230:33589815
In: 010
PredefinedType: BEAM; Material: GVH_i2_naaldhout_generiek
Cpset_Beam - LevelOfAccuracy: in te vullen door Buildwise
IfcClassificationReference - TDS_link: .\05 As Builtdossier\2. Bouwkunde\2.2. Stabiliteit\2.2.0 technische fiche's\TF S 4.9.1.1.1 A - houten roostering sheddak.pdf
IfcElement - Tag: B1; Mark: B1
IfcRoot - Name: 40 x 230
Qto_BeamBaseQuantities - Length: 3340; CrossSectionArea: 0.0092; OuterSurfaceArea: 1.79133; GrossSurfaceArea: 1.80973; NetSurfaceArea: 1.80973; GrossVolume: 0.030519; NetVolume: 0.030519
Pset_BeamCommon - Reference: 40 x 230; Span: 3340 mm; Slope: 0 rad; Roll: 0 rad; IsExternal: no; LoadBearing: yes
Pset_ConcreteElementGeneral - ConstructionMethod: prefabricated
Pset_Condition - AssessmentCondition: Empty
Pset_EnvironmentalImpactIndicators - Reference: 40 x 230; sets with these values: 2

# IfcBeam: 28_SF_hout_rechthoekig_40 x 230_45, 28_SF_hout_rechthoekig:40 x 230:33579920
In: 010
PredefinedType: BEAM; Material: GVH_i2_naaldhout_generiek
Cpset_Beam - LevelOfAccuracy: in te vullen door Buildwise
IfcClassificationReference - TDS_link: .\05 As Builtdossier\2. Bouwkunde\2.2. Stabiliteit\2.2.0 technische fiche's\TF S 4.9.1.1.1 A - houten roostering sheddak.pdf
IfcElement - Tag: B1; Mark: B1
IfcRoot - Name: 40 x 230
Qto_BeamBaseQuantities - Length: 3340; CrossSectionArea: 0.0092; OuterSurfaceArea: 1.79133; GrossSurfaceArea: 1.80973; NetSurfaceArea: 1.80973; GrossVolume: 0.030519; NetVolume: 0.030519
Pset_BeamCommon - Reference: 40 x 230; Span: 3340 mm; Slope: 0 rad; Roll: 0 rad; IsExternal: no; LoadBearing: yes
Pset_ConcreteElementGeneral - ConstructionMethod: prefabricated
Pset_Condition - AssessmentCondition: Empty
Pset_EnvironmentalImpactIndicators - Reference: 40 x 230; sets with these values: 2

# IfcBeam: 28_SF_hout_rechthoekig_40 x 230_451, 28_SF_hout_rechthoekig:40 x 230:33589818
In: 010
PredefinedType: BEAM; Material: GVH_i2_naaldhout_generiek
Cpset_Beam - LevelOfAccuracy: in te vullen door Buildwise
IfcClassificationReference - TDS_link: .\05 As Builtdossier\2. Bouwkunde\2.2. Stabiliteit\2.2.0 technische fiche's\TF S 4.9.1.1.1 A - houten roostering sheddak.pdf
IfcElement - Tag: B1; Mark: B1
IfcRoot - Name: 40 x 230
Qto_BeamBaseQuantities - Length: 3340; CrossSectionArea: 0.0092; OuterSurfaceArea: 1.79133; GrossSurfaceArea: 1.80973; NetSurfaceArea: 1.80973; GrossVolume: 0.030519; NetVolume: 0.030519
Pset_BeamCommon - Reference: 40 x 230; Span: 3340 mm; Slope: 0 rad; Roll: 0 rad; IsExternal: no; LoadBearing: yes
Pset_ConcreteElementGeneral - ConstructionMethod: prefabricated
Pset_Condition - AssessmentCondition: Empty
Pset_EnvironmentalImpactIndicators - Reference: 40 x 230; sets with these values: 2

# IfcBeam: 28_SF_hout_rechthoekig_40 x 230_453, 28_SF_hout_rechthoekig:40 x 230:33589821
In: 010
PredefinedType: BEAM; Material: GVH_i2_naaldhout_generiek
Cpset_Beam - LevelOfAccuracy: in te vullen door Buildwise
IfcClassificationReference - TDS_link: .\05 As Builtdossier\2. Bouwkunde\2.2. Stabiliteit\2.2.0 technische fiche's\TF S 4.9.1.1.1 A - houten roostering sheddak.pdf
IfcElement - Tag: B1; Mark: B1
IfcRoot - Name: 40 x 230
Qto_BeamBaseQuantities - Length: 3340; CrossSectionArea: 0.0092; OuterSurfaceArea: 1.79133; GrossSurfaceArea: 1.80973; NetSurfaceArea: 1.80973; GrossVolume: 0.030519; NetVolume: 0.030519
Pset_BeamCommon - Reference: 40 x 230; Span: 3340 mm; Slope: 0 rad; Roll: 0 rad; IsExternal: no; LoadBearing: yes
Pset_ConcreteElementGeneral - ConstructionMethod: prefabricated
Pset_Condition - AssessmentCondition: Empty
Pset_EnvironmentalImpactIndicators - Reference: 40 x 230; sets with these values: 2

# IfcBeam: 28_SF_hout_rechthoekig_40 x 230_455, 28_SF_hout_rechthoekig:40 x 230:33589824
In: 010
PredefinedType: BEAM; Material: GVH_i2_naaldhout_generiek
Cpset_Beam - LevelOfAccuracy: in te vullen door Buildwise
IfcClassificationReference - TDS_link: .\05 As Builtdossier\2. Bouwkunde\2.2. Stabiliteit\2.2.0 technische fiche's\TF S 4.9.1.1.1 A - houten roostering sheddak.pdf
IfcElement - Tag: B1; Mark: B1
IfcRoot - Name: 40 x 230
Qto_BeamBaseQuantities - Length: 3340; CrossSectionArea: 0.0092; OuterSurfaceArea: 1.79133; GrossSurfaceArea: 1.80973; NetSurfaceArea: 1.80973; GrossVolume: 0.030519; NetVolume: 0.030519
Pset_BeamCommon - Reference: 40 x 230; Span: 3340 mm; Slope: 0 rad; Roll: 0 rad; IsExternal: no; LoadBearing: yes
Pset_ConcreteElementGeneral - ConstructionMethod: prefabricated
Pset_Condition - AssessmentCondition: Empty
Pset_EnvironmentalImpactIndicators - Reference: 40 x 230; sets with these values: 2

# IfcBeam: 28_SF_hout_rechthoekig_40 x 230_457, 28_SF_hout_rechthoekig:40 x 230:33589827
In: 010
PredefinedType: BEAM; Material: GVH_i2_naaldhout_generiek
Cpset_Beam - LevelOfAccuracy: in te vullen door Buildwise
IfcClassificationReference - TDS_link: .\05 As Builtdossier\2. Bouwkunde\2.2. Stabiliteit\2.2.0 technische fiche's\TF S 4.9.1.1.1 A - houten roostering sheddak.pdf
IfcElement - Tag: B1; Mark: B1
IfcRoot - Name: 40 x 230
Qto_BeamBaseQuantities - Length: 3340; CrossSectionArea: 0.0092; OuterSurfaceArea: 1.79133; GrossSurfaceArea: 1.80973; NetSurfaceArea: 1.80973; GrossVolume: 0.030519; NetVolume: 0.030519
Pset_BeamCommon - Reference: 40 x 230; Span: 3340 mm; Slope: 0 rad; Roll: 0 rad; IsExternal: no; LoadBearing: yes
Pset_ConcreteElementGeneral - ConstructionMethod: prefabricated
Pset_Condition - AssessmentCondition: Empty
Pset_EnvironmentalImpactIndicators - Reference: 40 x 230; sets with these values: 2

# IfcBeam: 28_SF_hout_rechthoekig_40 x 230_459, 28_SF_hout_rechthoekig:40 x 230:33589830
In: 010
PredefinedType: BEAM; Material: GVH_i2_naaldhout_generiek
Cpset_Beam - LevelOfAccuracy: in te vullen door Buildwise
IfcClassificationReference - TDS_link: .\05 As Builtdossier\2. Bouwkunde\2.2. Stabiliteit\2.2.0 technische fiche's\TF S 4.9.1.1.1 A - houten roostering sheddak.pdf
IfcElement - Tag: B1; Mark: B1
IfcRoot - Name: 40 x 230
Qto_BeamBaseQuantities - Length: 3340; CrossSectionArea: 0.0092; OuterSurfaceArea: 1.79133; GrossSurfaceArea: 1.80973; NetSurfaceArea: 1.80973; GrossVolume: 0.030519; NetVolume: 0.030519
Pset_BeamCommon - Reference: 40 x 230; Span: 3340 mm; Slope: 0 rad; Roll: 0 rad; IsExternal: no; LoadBearing: yes
Pset_ConcreteElementGeneral - ConstructionMethod: prefabricated
Pset_Condition - AssessmentCondition: Empty
Pset_EnvironmentalImpactIndicators - Reference: 40 x 230; sets with these values: 2

# IfcBeam: 28_SF_hout_rechthoekig_40 x 230_461, 28_SF_hout_rechthoekig:40 x 230:33589833
In: 010
PredefinedType: BEAM; Material: GVH_i2_naaldhout_generiek
Cpset_Beam - LevelOfAccuracy: in te vullen door Buildwise
IfcClassificationReference - TDS_link: .\05 As Builtdossier\2. Bouwkunde\2.2. Stabiliteit\2.2.0 technische fiche's\TF S 4.9.1.1.1 A - houten roostering sheddak.pdf
IfcElement - Tag: B1; Mark: B1
IfcRoot - Name: 40 x 230
Qto_BeamBaseQuantities - Length: 3340; CrossSectionArea: 0.0092; OuterSurfaceArea: 1.79133; GrossSurfaceArea: 1.80973; NetSurfaceArea: 1.80973; GrossVolume: 0.030519; NetVolume: 0.030519
Pset_BeamCommon - Reference: 40 x 230; Span: 3340 mm; Slope: 0 rad; Roll: 0 rad; IsExternal: no; LoadBearing: yes
Pset_ConcreteElementGeneral - ConstructionMethod: prefabricated
Pset_Condition - AssessmentCondition: Empty
Pset_EnvironmentalImpactIndicators - Reference: 40 x 230; sets with these values: 2

# IfcBeam: 28_SF_hout_rechthoekig_40 x 230_463, 28_SF_hout_rechthoekig:40 x 230:33589837
In: 010
PredefinedType: BEAM; Material: GVH_i2_naaldhout_generiek
Cpset_Beam - LevelOfAccuracy: in te vullen door Buildwise
IfcClassificationReference - TDS_link: .\05 As Builtdossier\2. Bouwkunde\2.2. Stabiliteit\2.2.0 technische fiche's\TF S 4.9.1.1.1 A - houten roostering sheddak.pdf
IfcElement - Tag: C1; Mark: C1
IfcRoot - Name: 40 x 230
Qto_BeamBaseQuantities - Length: 3480; CrossSectionArea: 0.0092; OuterSurfaceArea: 1.86846; GrossSurfaceArea: 1.88686; NetSurfaceArea: 1.88686; GrossVolume: 0.0318329; NetVolume: 0.0318329
Pset_BeamCommon - Reference: 40 x 230; Span: 3480 mm; Slope: 0 rad; Roll: 0 rad; IsExternal: no; LoadBearing: yes
Pset_ConcreteElementGeneral - ConstructionMethod: prefabricated
Pset_Condition - AssessmentCondition: Empty
Pset_EnvironmentalImpactIndicators - Reference: 40 x 230; sets with these values: 2

# IfcBeam: 28_SF_hout_rechthoekig_40 x 230_465, 28_SF_hout_rechthoekig:40 x 230:33590736
In: 010
PredefinedType: BEAM; Material: GVH_i2_naaldhout_generiek
Cpset_Beam - LevelOfAccuracy: in te vullen door Buildwise
IfcClassificationReference - TDS_link: .\05 As Builtdossier\2. Bouwkunde\2.2. Stabiliteit\2.2.0 technische fiche's\TF S 4.9.1.1.1 A - houten roostering sheddak.pdf
IfcElement - Tag: C1; Mark: C1
IfcRoot - Name: 40 x 230
Qto_BeamBaseQuantities - Length: 3480; CrossSectionArea: 0.0092; OuterSurfaceArea: 1.84434; GrossSurfaceArea: 1.86274; NetSurfaceArea: 1.86274; GrossVolume: 0.0314221; NetVolume: 0.0314221
Pset_BeamCommon - Reference: 40 x 230; Span: 3480 mm; Slope: 0 rad; Roll: 0 rad; IsExternal: no; LoadBearing: yes
Pset_ConcreteElementGeneral - ConstructionMethod: prefabricated
Pset_Condition - AssessmentCondition: Empty
Pset_EnvironmentalImpactIndicators - Reference: 40 x 230; sets with these values: 2

# IfcBeam: 28_SF_hout_rechthoekig_40 x 230_467, 28_SF_hout_rechthoekig:40 x 230:33590769
In: 010
PredefinedType: BEAM; Material: GVH_i2_naaldhout_generiek
Cpset_Beam - LevelOfAccuracy: in te vullen door Buildwise
IfcClassificationReference - TDS_link: .\05 As Builtdossier\2. Bouwkunde\2.2. Stabiliteit\2.2.0 technische fiche's\TF S 4.9.1.1.1 A - houten roostering sheddak.pdf
IfcElement - Tag: C1; Mark: C1
IfcRoot - Name: 40 x 230
Qto_BeamBaseQuantities - Length: 3480; CrossSectionArea: 0.0092; OuterSurfaceArea: 1.84434; GrossSurfaceArea: 1.86274; NetSurfaceArea: 1.86274; GrossVolume: 0.0314221; NetVolume: 0.0314221
Pset_BeamCommon - Reference: 40 x 230; Span: 3480 mm; Slope: 0 rad; Roll: 0 rad; IsExternal: no; LoadBearing: yes
Pset_ConcreteElementGeneral - ConstructionMethod: prefabricated
Pset_Condition - AssessmentCondition: Empty
Pset_EnvironmentalImpactIndicators - Reference: 40 x 230; sets with these values: 2

# IfcBeam: 28_SF_hout_rechthoekig_40 x 230_469, 28_SF_hout_rechthoekig:40 x 230:33590772
In: 010
PredefinedType: BEAM; Material: GVH_i2_naaldhout_generiek
Cpset_Beam - LevelOfAccuracy: in te vullen door Buildwise
IfcClassificationReference - TDS_link: .\05 As Builtdossier\2. Bouwkunde\2.2. Stabiliteit\2.2.0 technische fiche's\TF S 4.9.1.1.1 A - houten roostering sheddak.pdf
IfcElement - Tag: C1; Mark: C1
IfcRoot - Name: 40 x 230
Qto_BeamBaseQuantities - Length: 3480; CrossSectionArea: 0.0092; OuterSurfaceArea: 1.84434; GrossSurfaceArea: 1.86274; NetSurfaceArea: 1.86274; GrossVolume: 0.0314221; NetVolume: 0.0314221
Pset_BeamCommon - Reference: 40 x 230; Span: 3480 mm; Slope: 0 rad; Roll: 0 rad; IsExternal: no; LoadBearing: yes
Pset_ConcreteElementGeneral - ConstructionMethod: prefabricated
Pset_Condition - AssessmentCondition: Empty
Pset_EnvironmentalImpactIndicators - Reference: 40 x 230; sets with these values: 2

# IfcBeam: 28_SF_hout_rechthoekig_40 x 230_47, 28_SF_hout_rechthoekig:40 x 230:33579922
In: 010
PredefinedType: BEAM; Material: GVH_i2_naaldhout_generiek
Cpset_Beam - LevelOfAccuracy: in te vullen door Buildwise
IfcClassificationReference - TDS_link: .\05 As Builtdossier\2. Bouwkunde\2.2. Stabiliteit\2.2.0 technische fiche's\TF S 4.9.1.1.1 A - houten roostering sheddak.pdf
IfcElement - Tag: B1; Mark: B1
IfcRoot - Name: 40 x 230
Qto_BeamBaseQuantities - Length: 3340; CrossSectionArea: 0.0092; OuterSurfaceArea: 1.79133; GrossSurfaceArea: 1.80973; NetSurfaceArea: 1.80973; GrossVolume: 0.030519; NetVolume: 0.030519
Pset_BeamCommon - Reference: 40 x 230; Span: 3340 mm; Slope: 0 rad; Roll: 0 rad; IsExternal: no; LoadBearing: yes
Pset_ConcreteElementGeneral - ConstructionMethod: prefabricated
Pset_Condition - AssessmentCondition: Empty
Pset_EnvironmentalImpactIndicators - Reference: 40 x 230; sets with these values: 2

# IfcBeam: 28_SF_hout_rechthoekig_40 x 230_471, 28_SF_hout_rechthoekig:40 x 230:33590775
In: 010
PredefinedType: BEAM; Material: GVH_i2_naaldhout_generiek
Cpset_Beam - LevelOfAccuracy: in te vullen door Buildwise
IfcClassificationReference - TDS_link: .\05 As Builtdossier\2. Bouwkunde\2.2. Stabiliteit\2.2.0 technische fiche's\TF S 4.9.1.1.1 A - houten roostering sheddak.pdf
IfcElement - Tag: C1; Mark: C1
IfcRoot - Name: 40 x 230
Qto_BeamBaseQuantities - Length: 3480; CrossSectionArea: 0.0092; OuterSurfaceArea: 1.84434; GrossSurfaceArea: 1.86274; NetSurfaceArea: 1.86274; GrossVolume: 0.0314221; NetVolume: 0.0314221
Pset_BeamCommon - Reference: 40 x 230; Span: 3480 mm; Slope: 0 rad; Roll: 0 rad; IsExternal: no; LoadBearing: yes
Pset_ConcreteElementGeneral - ConstructionMethod: prefabricated
Pset_Condition - AssessmentCondition: Empty
Pset_EnvironmentalImpactIndicators - Reference: 40 x 230; sets with these values: 2

# IfcBeam: 28_SF_hout_rechthoekig_40 x 230_473, 28_SF_hout_rechthoekig:40 x 230:33590778
In: 010
PredefinedType: BEAM; Material: GVH_i2_naaldhout_generiek
Cpset_Beam - LevelOfAccuracy: in te vullen door Buildwise
IfcClassificationReference - TDS_link: .\05 As Builtdossier\2. Bouwkunde\2.2. Stabiliteit\2.2.0 technische fiche's\TF S 4.9.1.1.1 A - houten roostering sheddak.pdf
IfcElement - Tag: C1; Mark: C1
IfcRoot - Name: 40 x 230
Qto_BeamBaseQuantities - Length: 3480; CrossSectionArea: 0.0092; OuterSurfaceArea: 1.84434; GrossSurfaceArea: 1.86274; NetSurfaceArea: 1.86274; GrossVolume: 0.0314221; NetVolume: 0.0314221
Pset_BeamCommon - Reference: 40 x 230; Span: 3480 mm; Slope: 0 rad; Roll: 0 rad; IsExternal: no; LoadBearing: yes
Pset_ConcreteElementGeneral - ConstructionMethod: prefabricated
Pset_Condition - AssessmentCondition: Empty
Pset_EnvironmentalImpactIndicators - Reference: 40 x 230; sets with these values: 2

# IfcBeam: 28_SF_hout_rechthoekig_40 x 230_475, 28_SF_hout_rechthoekig:40 x 230:33590781
In: 010
PredefinedType: BEAM; Material: GVH_i2_naaldhout_generiek
Cpset_Beam - LevelOfAccuracy: in te vullen door Buildwise
IfcClassificationReference - TDS_link: .\05 As Builtdossier\2. Bouwkunde\2.2. Stabiliteit\2.2.0 technische fiche's\TF S 4.9.1.1.1 A - houten roostering sheddak.pdf
IfcElement - Tag: C1; Mark: C1
IfcRoot - Name: 40 x 230
Qto_BeamBaseQuantities - Length: 3480; CrossSectionArea: 0.0092; OuterSurfaceArea: 1.84434; GrossSurfaceArea: 1.86274; NetSurfaceArea: 1.86274; GrossVolume: 0.0314221; NetVolume: 0.0314221
Pset_BeamCommon - Reference: 40 x 230; Span: 3480 mm; Slope: 0 rad; Roll: 0 rad; IsExternal: no; LoadBearing: yes
Pset_ConcreteElementGeneral - ConstructionMethod: prefabricated
Pset_Condition - AssessmentCondition: Empty
Pset_EnvironmentalImpactIndicators - Reference: 40 x 230; sets with these values: 2

# IfcBeam: 28_SF_hout_rechthoekig_40 x 230_477, 28_SF_hout_rechthoekig:40 x 230:33590784
In: 010
PredefinedType: BEAM; Material: GVH_i2_naaldhout_generiek
Cpset_Beam - LevelOfAccuracy: in te vullen door Buildwise
IfcClassificationReference - TDS_link: .\05 As Builtdossier\2. Bouwkunde\2.2. Stabiliteit\2.2.0 technische fiche's\TF S 4.9.1.1.1 A - houten roostering sheddak.pdf
IfcElement - Tag: C1; Mark: C1
IfcRoot - Name: 40 x 230
Qto_BeamBaseQuantities - Length: 3480; CrossSectionArea: 0.0092; OuterSurfaceArea: 1.84434; GrossSurfaceArea: 1.86274; NetSurfaceArea: 1.86274; GrossVolume: 0.0314221; NetVolume: 0.0314221
Pset_BeamCommon - Reference: 40 x 230; Span: 3480 mm; Slope: 0 rad; Roll: 0 rad; IsExternal: no; LoadBearing: yes
Pset_ConcreteElementGeneral - ConstructionMethod: prefabricated
Pset_Condition - AssessmentCondition: Empty
Pset_EnvironmentalImpactIndicators - Reference: 40 x 230; sets with these values: 2

# IfcBeam: 28_SF_hout_rechthoekig_40 x 230_479, 28_SF_hout_rechthoekig:40 x 230:33590787
In: 010
PredefinedType: BEAM; Material: GVH_i2_naaldhout_generiek
Cpset_Beam - LevelOfAccuracy: in te vullen door Buildwise
IfcClassificationReference - TDS_link: .\05 As Builtdossier\2. Bouwkunde\2.2. Stabiliteit\2.2.0 technische fiche's\TF S 4.9.1.1.1 A - houten roostering sheddak.pdf
IfcElement - Tag: C1; Mark: C1
IfcRoot - Name: 40 x 230
Qto_BeamBaseQuantities - Length: 3480; CrossSectionArea: 0.0092; OuterSurfaceArea: 1.84434; GrossSurfaceArea: 1.86274; NetSurfaceArea: 1.86274; GrossVolume: 0.0314221; NetVolume: 0.0314221
Pset_BeamCommon - Reference: 40 x 230; Span: 3480 mm; Slope: 0 rad; Roll: 0 rad; IsExternal: no; LoadBearing: yes
Pset_ConcreteElementGeneral - ConstructionMethod: prefabricated
Pset_Condition - AssessmentCondition: Empty
Pset_EnvironmentalImpactIndicators - Reference: 40 x 230; sets with these values: 2

# IfcBeam: 28_SF_hout_rechthoekig_40 x 230_481, 28_SF_hout_rechthoekig:40 x 230:33590790
In: 010
PredefinedType: BEAM; Material: GVH_i2_naaldhout_generiek
Cpset_Beam - LevelOfAccuracy: in te vullen door Buildwise
IfcClassificationReference - TDS_link: .\05 As Builtdossier\2. Bouwkunde\2.2. Stabiliteit\2.2.0 technische fiche's\TF S 4.9.1.1.1 A - houten roostering sheddak.pdf
IfcElement - Tag: C1; Mark: C1
IfcRoot - Name: 40 x 230
Qto_BeamBaseQuantities - Length: 3480; CrossSectionArea: 0.0092; OuterSurfaceArea: 1.84434; GrossSurfaceArea: 1.86274; NetSurfaceArea: 1.86274; GrossVolume: 0.0314221; NetVolume: 0.0314221
Pset_BeamCommon - Reference: 40 x 230; Span: 3480 mm; Slope: 0 rad; Roll: 0 rad; IsExternal: no; LoadBearing: yes
Pset_ConcreteElementGeneral - ConstructionMethod: prefabricated
Pset_Condition - AssessmentCondition: Empty
Pset_EnvironmentalImpactIndicators - Reference: 40 x 230; sets with these values: 2

# IfcBeam: 28_SF_hout_rechthoekig_40 x 230_483, 28_SF_hout_rechthoekig:40 x 230:33590793
In: 010
PredefinedType: BEAM; Material: GVH_i2_naaldhout_generiek
Cpset_Beam - LevelOfAccuracy: in te vullen door Buildwise
IfcClassificationReference - TDS_link: .\05 As Builtdossier\2. Bouwkunde\2.2. Stabiliteit\2.2.0 technische fiche's\TF S 4.9.1.1.1 A - houten roostering sheddak.pdf
IfcElement - Tag: C1; Mark: C1
IfcRoot - Name: 40 x 230
Qto_BeamBaseQuantities - Length: 3480; CrossSectionArea: 0.0092; OuterSurfaceArea: 1.84434; GrossSurfaceArea: 1.86274; NetSurfaceArea: 1.86274; GrossVolume: 0.0314221; NetVolume: 0.0314221
Pset_BeamCommon - Reference: 40 x 230; Span: 3480 mm; Slope: 0 rad; Roll: 0 rad; IsExternal: no; LoadBearing: yes
Pset_ConcreteElementGeneral - ConstructionMethod: prefabricated
Pset_Condition - AssessmentCondition: Empty
Pset_EnvironmentalImpactIndicators - Reference: 40 x 230; sets with these values: 2

# IfcBeam: 28_SF_hout_rechthoekig_40 x 230_485, 28_SF_hout_rechthoekig:40 x 230:33590796
In: 010
PredefinedType: BEAM; Material: GVH_i2_naaldhout_generiek
Cpset_Beam - LevelOfAccuracy: in te vullen door Buildwise
IfcClassificationReference - TDS_link: .\05 As Builtdossier\2. Bouwkunde\2.2. Stabiliteit\2.2.0 technische fiche's\TF S 4.9.1.1.1 A - houten roostering sheddak.pdf
IfcElement - Tag: C1; Mark: C1
IfcRoot - Name: 40 x 230
Qto_BeamBaseQuantities - Length: 3480; CrossSectionArea: 0.0092; OuterSurfaceArea: 1.84434; GrossSurfaceArea: 1.86274; NetSurfaceArea: 1.86274; GrossVolume: 0.0314221; NetVolume: 0.0314221
Pset_BeamCommon - Reference: 40 x 230; Span: 3480 mm; Slope: 0 rad; Roll: 0 rad; IsExternal: no; LoadBearing: yes
Pset_ConcreteElementGeneral - ConstructionMethod: prefabricated
Pset_Condition - AssessmentCondition: Empty
Pset_EnvironmentalImpactIndicators - Reference: 40 x 230; sets with these values: 2

# IfcBeam: 28_SF_hout_rechthoekig_40 x 230_487, 28_SF_hout_rechthoekig:40 x 230:33590799
In: 010
PredefinedType: BEAM; Material: GVH_i2_naaldhout_generiek
Cpset_Beam - LevelOfAccuracy: in te vullen door Buildwise
IfcClassificationReference - TDS_link: .\05 As Builtdossier\2. Bouwkunde\2.2. Stabiliteit\2.2.0 technische fiche's\TF S 4.9.1.1.1 A - houten roostering sheddak.pdf
IfcElement - Tag: C1; Mark: C1
IfcRoot - Name: 40 x 230
Qto_BeamBaseQuantities - Length: 3480; CrossSectionArea: 0.0092; OuterSurfaceArea: 1.84434; GrossSurfaceArea: 1.86274; NetSurfaceArea: 1.86274; GrossVolume: 0.0314221; NetVolume: 0.0314221
Pset_BeamCommon - Reference: 40 x 230; Span: 3480 mm; Slope: 0 rad; Roll: 0 rad; IsExternal: no; LoadBearing: yes
Pset_ConcreteElementGeneral - ConstructionMethod: prefabricated
Pset_Condition - AssessmentCondition: Empty
Pset_EnvironmentalImpactIndicators - Reference: 40 x 230; sets with these values: 2

# IfcBeam: 28_SF_hout_rechthoekig_40 x 230_489, 28_SF_hout_rechthoekig:40 x 230:33590802
In: 010
PredefinedType: BEAM; Material: GVH_i2_naaldhout_generiek
Cpset_Beam - LevelOfAccuracy: in te vullen door Buildwise
IfcClassificationReference - TDS_link: .\05 As Builtdossier\2. Bouwkunde\2.2. Stabiliteit\2.2.0 technische fiche's\TF S 4.9.1.1.1 A - houten roostering sheddak.pdf
IfcElement - Tag: C1; Mark: C1
IfcRoot - Name: 40 x 230
Qto_BeamBaseQuantities - Length: 3480; CrossSectionArea: 0.0092; OuterSurfaceArea: 1.84434; GrossSurfaceArea: 1.86274; NetSurfaceArea: 1.86274; GrossVolume: 0.0314221; NetVolume: 0.0314221
Pset_BeamCommon - Reference: 40 x 230; Span: 3480 mm; Slope: 0 rad; Roll: 0 rad; IsExternal: no; LoadBearing: yes
Pset_ConcreteElementGeneral - ConstructionMethod: prefabricated
Pset_Condition - AssessmentCondition: Empty
Pset_EnvironmentalImpactIndicators - Reference: 40 x 230; sets with these values: 2

# IfcBeam: 28_SF_hout_rechthoekig_40 x 230_49, 28_SF_hout_rechthoekig:40 x 230:33579924
In: 010
PredefinedType: BEAM; Material: GVH_i2_naaldhout_generiek
Cpset_Beam - LevelOfAccuracy: in te vullen door Buildwise
IfcClassificationReference - TDS_link: .\05 As Builtdossier\2. Bouwkunde\2.2. Stabiliteit\2.2.0 technische fiche's\TF S 4.9.1.1.1 A - houten roostering sheddak.pdf
IfcElement - Tag: B1; Mark: B1
IfcRoot - Name: 40 x 230
Qto_BeamBaseQuantities - Length: 3340; CrossSectionArea: 0.0092; OuterSurfaceArea: 1.79133; GrossSurfaceArea: 1.80973; NetSurfaceArea: 1.80973; GrossVolume: 0.030519; NetVolume: 0.030519
Pset_BeamCommon - Reference: 40 x 230; Span: 3340 mm; Slope: 0 rad; Roll: 0 rad; IsExternal: no; LoadBearing: yes
Pset_ConcreteElementGeneral - ConstructionMethod: prefabricated
Pset_Condition - AssessmentCondition: Empty
Pset_EnvironmentalImpactIndicators - Reference: 40 x 230; sets with these values: 2

# IfcBeam: 28_SF_hout_rechthoekig_40 x 230_491, 28_SF_hout_rechthoekig:40 x 230:33590805
In: 010
PredefinedType: BEAM; Material: GVH_i2_naaldhout_generiek
Cpset_Beam - LevelOfAccuracy: in te vullen door Buildwise
IfcClassificationReference - TDS_link: .\05 As Builtdossier\2. Bouwkunde\2.2. Stabiliteit\2.2.0 technische fiche's\TF S 4.9.1.1.1 A - houten roostering sheddak.pdf
IfcElement - Tag: C1; Mark: C1
IfcRoot - Name: 40 x 230
Qto_BeamBaseQuantities - Length: 3480; CrossSectionArea: 0.0092; OuterSurfaceArea: 1.84434; GrossSurfaceArea: 1.86274; NetSurfaceArea: 1.86274; GrossVolume: 0.0314221; NetVolume: 0.0314221
Pset_BeamCommon - Reference: 40 x 230; Span: 3480 mm; Slope: 0 rad; Roll: 0 rad; IsExternal: no; LoadBearing: yes
Pset_ConcreteElementGeneral - ConstructionMethod: prefabricated
Pset_Condition - AssessmentCondition: Empty
Pset_EnvironmentalImpactIndicators - Reference: 40 x 230; sets with these values: 2

# IfcBeam: 28_SF_hout_rechthoekig_40 x 230_493, 28_SF_hout_rechthoekig:40 x 230:33590808
In: 010
PredefinedType: BEAM; Material: GVH_i2_naaldhout_generiek
Cpset_Beam - LevelOfAccuracy: in te vullen door Buildwise
IfcClassificationReference - TDS_link: .\05 As Builtdossier\2. Bouwkunde\2.2. Stabiliteit\2.2.0 technische fiche's\TF S 4.9.1.1.1 A - houten roostering sheddak.pdf
IfcElement - Tag: C1; Mark: C1
IfcRoot - Name: 40 x 230
Qto_BeamBaseQuantities - Length: 3480; CrossSectionArea: 0.0092; OuterSurfaceArea: 1.84434; GrossSurfaceArea: 1.86274; NetSurfaceArea: 1.86274; GrossVolume: 0.0314221; NetVolume: 0.0314221
Pset_BeamCommon - Reference: 40 x 230; Span: 3480 mm; Slope: 0 rad; Roll: 0 rad; IsExternal: no; LoadBearing: yes
Pset_ConcreteElementGeneral - ConstructionMethod: prefabricated
Pset_Condition - AssessmentCondition: Empty
Pset_EnvironmentalImpactIndicators - Reference: 40 x 230; sets with these values: 2

# IfcBeam: 28_SF_hout_rechthoekig_40 x 230_495, 28_SF_hout_rechthoekig:40 x 230:33590908
In: 010
PredefinedType: BEAM; Material: GVH_i2_naaldhout_generiek
Cpset_Beam - LevelOfAccuracy: in te vullen door Buildwise
IfcClassificationReference - TDS_link: .\05 As Builtdossier\2. Bouwkunde\2.2. Stabiliteit\2.2.0 technische fiche's\TF S 4.9.1.1.1 A - houten roostering sheddak.pdf
IfcElement - Tag: B1; Mark: B1
IfcRoot - Name: 40 x 230
Qto_BeamBaseQuantities - Length: 3480; CrossSectionArea: 0.0092; OuterSurfaceArea: 1.79231; GrossSurfaceArea: 1.81071; NetSurfaceArea: 1.81071; GrossVolume: 0.0305357; NetVolume: 0.0305357
Pset_BeamCommon - Reference: 40 x 230; Span: 3480 mm; Slope: 0 rad; Roll: 0 rad; IsExternal: no; LoadBearing: yes
Pset_ConcreteElementGeneral - ConstructionMethod: prefabricated
Pset_Condition - AssessmentCondition: Empty
Pset_EnvironmentalImpactIndicators - Reference: 40 x 230; sets with these values: 2

# IfcBeam: 28_SF_hout_rechthoekig_40 x 230_497, 28_SF_hout_rechthoekig:40 x 230:33591147
In: 010
PredefinedType: BEAM; Material: GVH_i2_naaldhout_generiek
Cpset_Beam - LevelOfAccuracy: in te vullen door Buildwise
IfcClassificationReference - TDS_link: .\05 As Builtdossier\2. Bouwkunde\2.2. Stabiliteit\2.2.0 technische fiche's\TF S 4.9.1.1.1 A - houten roostering sheddak.pdf
IfcElement - Tag: B1; Mark: B1
IfcRoot - Name: 40 x 230
Qto_BeamBaseQuantities - Length: 3480; CrossSectionArea: 0.0092; OuterSurfaceArea: 1.79231; GrossSurfaceArea: 1.81071; NetSurfaceArea: 1.81071; GrossVolume: 0.0305357; NetVolume: 0.0305357
Pset_BeamCommon - Reference: 40 x 230; Span: 3480 mm; Slope: 0 rad; Roll: 0 rad; IsExternal: no; LoadBearing: yes
Pset_ConcreteElementGeneral - ConstructionMethod: prefabricated
Pset_Condition - AssessmentCondition: Empty
Pset_EnvironmentalImpactIndicators - Reference: 40 x 230; sets with these values: 2

# IfcBeam: 28_SF_hout_rechthoekig_40 x 230_499, 28_SF_hout_rechthoekig:40 x 230:33591196
In: 010
PredefinedType: BEAM; Material: GVH_i2_naaldhout_generiek
Cpset_Beam - LevelOfAccuracy: in te vullen door Buildwise
IfcClassificationReference - TDS_link: .\05 As Builtdossier\2. Bouwkunde\2.2. Stabiliteit\2.2.0 technische fiche's\TF S 4.9.1.1.1 A - houten roostering sheddak.pdf
IfcElement - Tag: B1; Mark: B1
IfcRoot - Name: 40 x 230
Qto_BeamBaseQuantities - Length: 3480; CrossSectionArea: 0.0092; OuterSurfaceArea: 1.79231; GrossSurfaceArea: 1.81071; NetSurfaceArea: 1.81071; GrossVolume: 0.0305357; NetVolume: 0.0305357
Pset_BeamCommon - Reference: 40 x 230; Span: 3480 mm; Slope: 0 rad; Roll: 0 rad; IsExternal: no; LoadBearing: yes
Pset_ConcreteElementGeneral - ConstructionMethod: prefabricated
Pset_Condition - AssessmentCondition: Empty
Pset_EnvironmentalImpactIndicators - Reference: 40 x 230; sets with these values: 2

# IfcBeam: 28_SF_hout_rechthoekig_40 x 230_5, 28_SF_hout_rechthoekig:40 x 230:33579216
In: 010
PredefinedType: BEAM; Material: GVH_i2_naaldhout_generiek
Cpset_Beam - LevelOfAccuracy: in te vullen door Buildwise
IfcClassificationReference - TDS_link: .\05 As Builtdossier\2. Bouwkunde\2.2. Stabiliteit\2.2.0 technische fiche's\TF S 4.9.1.1.1 A - houten roostering sheddak.pdf
IfcElement - Tag: B1; Mark: B1
IfcRoot - Name: 40 x 230
Qto_BeamBaseQuantities - Length: 3440; CrossSectionArea: 0.0092; OuterSurfaceArea: 1.79133; GrossSurfaceArea: 1.80973; NetSurfaceArea: 1.80973; GrossVolume: 0.030519; NetVolume: 0.030519
Pset_BeamCommon - Reference: 40 x 230; Span: 3440 mm; Slope: 0 rad; Roll: 0 rad; IsExternal: no; LoadBearing: yes
Pset_ConcreteElementGeneral - ConstructionMethod: prefabricated
Pset_Condition - AssessmentCondition: Empty
Pset_EnvironmentalImpactIndicators - Reference: 40 x 230; sets with these values: 2

# IfcBeam: 28_SF_hout_rechthoekig_40 x 230_501, 28_SF_hout_rechthoekig:40 x 230:33591199
In: 010
PredefinedType: BEAM; Material: GVH_i2_naaldhout_generiek
Cpset_Beam - LevelOfAccuracy: in te vullen door Buildwise
IfcClassificationReference - TDS_link: .\05 As Builtdossier\2. Bouwkunde\2.2. Stabiliteit\2.2.0 technische fiche's\TF S 4.9.1.1.1 A - houten roostering sheddak.pdf
IfcElement - Tag: B1; Mark: B1
IfcRoot - Name: 40 x 230
Qto_BeamBaseQuantities - Length: 3480; CrossSectionArea: 0.0092; OuterSurfaceArea: 1.79231; GrossSurfaceArea: 1.81071; NetSurfaceArea: 1.81071; GrossVolume: 0.0305357; NetVolume: 0.0305357
Pset_BeamCommon - Reference: 40 x 230; Span: 3480 mm; Slope: 0 rad; Roll: 0 rad; IsExternal: no; LoadBearing: yes
Pset_ConcreteElementGeneral - ConstructionMethod: prefabricated
Pset_Condition - AssessmentCondition: Empty
Pset_EnvironmentalImpactIndicators - Reference: 40 x 230; sets with these values: 2

# IfcBeam: 28_SF_hout_rechthoekig_40 x 230_503, 28_SF_hout_rechthoekig:40 x 230:33591202
In: 010
PredefinedType: BEAM; Material: GVH_i2_naaldhout_generiek
Cpset_Beam - LevelOfAccuracy: in te vullen door Buildwise
IfcClassificationReference - TDS_link: .\05 As Builtdossier\2. Bouwkunde\2.2. Stabiliteit\2.2.0 technische fiche's\TF S 4.9.1.1.1 A - houten roostering sheddak.pdf
IfcElement - Tag: B1; Mark: B1
IfcRoot - Name: 40 x 230
Qto_BeamBaseQuantities - Length: 3480; CrossSectionArea: 0.0092; OuterSurfaceArea: 1.79231; GrossSurfaceArea: 1.81071; NetSurfaceArea: 1.81071; GrossVolume: 0.0305357; NetVolume: 0.0305357
Pset_BeamCommon - Reference: 40 x 230; Span: 3480 mm; Slope: 0 rad; Roll: 0 rad; IsExternal: no; LoadBearing: yes
Pset_ConcreteElementGeneral - ConstructionMethod: prefabricated
Pset_Condition - AssessmentCondition: Empty
Pset_EnvironmentalImpactIndicators - Reference: 40 x 230; sets with these values: 2

# IfcBeam: 28_SF_hout_rechthoekig_40 x 230_505, 28_SF_hout_rechthoekig:40 x 230:33591205
In: 010
PredefinedType: BEAM; Material: GVH_i2_naaldhout_generiek
Cpset_Beam - LevelOfAccuracy: in te vullen door Buildwise
IfcClassificationReference - TDS_link: .\05 As Builtdossier\2. Bouwkunde\2.2. Stabiliteit\2.2.0 technische fiche's\TF S 4.9.1.1.1 A - houten roostering sheddak.pdf
IfcElement - Tag: B1; Mark: B1
IfcRoot - Name: 40 x 230
Qto_BeamBaseQuantities - Length: 3480; CrossSectionArea: 0.0092; OuterSurfaceArea: 1.79231; GrossSurfaceArea: 1.81071; NetSurfaceArea: 1.81071; GrossVolume: 0.0305357; NetVolume: 0.0305357
Pset_BeamCommon - Reference: 40 x 230; Span: 3480 mm; Slope: 0 rad; Roll: 0 rad; IsExternal: no; LoadBearing: yes
Pset_ConcreteElementGeneral - ConstructionMethod: prefabricated
Pset_Condition - AssessmentCondition: Empty
Pset_EnvironmentalImpactIndicators - Reference: 40 x 230; sets with these values: 2

# IfcBeam: 28_SF_hout_rechthoekig_40 x 230_507, 28_SF_hout_rechthoekig:40 x 230:33591208
In: 010
PredefinedType: BEAM; Material: GVH_i2_naaldhout_generiek
Cpset_Beam - LevelOfAccuracy: in te vullen door Buildwise
IfcClassificationReference - TDS_link: .\05 As Builtdossier\2. Bouwkunde\2.2. Stabiliteit\2.2.0 technische fiche's\TF S 4.9.1.1.1 A - houten roostering sheddak.pdf
IfcElement - Tag: B1; Mark: B1
IfcRoot - Name: 40 x 230
Qto_BeamBaseQuantities - Length: 3480; CrossSectionArea: 0.0092; OuterSurfaceArea: 1.79231; GrossSurfaceArea: 1.81071; NetSurfaceArea: 1.81071; GrossVolume: 0.0305357; NetVolume: 0.0305357
Pset_BeamCommon - Reference: 40 x 230; Span: 3480 mm; Slope: 0 rad; Roll: 0 rad; IsExternal: no; LoadBearing: yes
Pset_ConcreteElementGeneral - ConstructionMethod: prefabricated
Pset_Condition - AssessmentCondition: Empty
Pset_EnvironmentalImpactIndicators - Reference: 40 x 230; sets with these values: 2

# IfcBeam: 28_SF_hout_rechthoekig_40 x 230_509, 28_SF_hout_rechthoekig:40 x 230:33591211
In: 010
PredefinedType: BEAM; Material: GVH_i2_naaldhout_generiek
Cpset_Beam - LevelOfAccuracy: in te vullen door Buildwise
IfcClassificationReference - TDS_link: .\05 As Builtdossier\2. Bouwkunde\2.2. Stabiliteit\2.2.0 technische fiche's\TF S 4.9.1.1.1 A - houten roostering sheddak.pdf
IfcElement - Tag: B1; Mark: B1
IfcRoot - Name: 40 x 230
Qto_BeamBaseQuantities - Length: 3480; CrossSectionArea: 0.0092; OuterSurfaceArea: 1.79231; GrossSurfaceArea: 1.81071; NetSurfaceArea: 1.81071; GrossVolume: 0.0305357; NetVolume: 0.0305357
Pset_BeamCommon - Reference: 40 x 230; Span: 3480 mm; Slope: 0 rad; Roll: 0 rad; IsExternal: no; LoadBearing: yes
Pset_ConcreteElementGeneral - ConstructionMethod: prefabricated
Pset_Condition - AssessmentCondition: Empty
Pset_EnvironmentalImpactIndicators - Reference: 40 x 230; sets with these values: 2

# IfcBeam: 28_SF_hout_rechthoekig_40 x 230_51, 28_SF_hout_rechthoekig:40 x 230:33579926
In: 010
PredefinedType: BEAM; Material: GVH_i2_naaldhout_generiek
Cpset_Beam - LevelOfAccuracy: in te vullen door Buildwise
IfcClassificationReference - TDS_link: .\05 As Builtdossier\2. Bouwkunde\2.2. Stabiliteit\2.2.0 technische fiche's\TF S 4.9.1.1.1 A - houten roostering sheddak.pdf
IfcElement - Tag: B1; Mark: B1
IfcRoot - Name: 40 x 230
Qto_BeamBaseQuantities - Length: 3340; CrossSectionArea: 0.0092; OuterSurfaceArea: 1.79133; GrossSurfaceArea: 1.80973; NetSurfaceArea: 1.80973; GrossVolume: 0.030519; NetVolume: 0.030519
Pset_BeamCommon - Reference: 40 x 230; Span: 3340 mm; Slope: 0 rad; Roll: 0 rad; IsExternal: no; LoadBearing: yes
Pset_ConcreteElementGeneral - ConstructionMethod: prefabricated
Pset_Condition - AssessmentCondition: Empty
Pset_EnvironmentalImpactIndicators - Reference: 40 x 230; sets with these values: 2

# IfcBeam: 28_SF_hout_rechthoekig_40 x 230_511, 28_SF_hout_rechthoekig:40 x 230:33591214
In: 010
PredefinedType: BEAM; Material: GVH_i2_naaldhout_generiek
Cpset_Beam - LevelOfAccuracy: in te vullen door Buildwise
IfcClassificationReference - TDS_link: .\05 As Builtdossier\2. Bouwkunde\2.2. Stabiliteit\2.2.0 technische fiche's\TF S 4.9.1.1.1 A - houten roostering sheddak.pdf
IfcElement - Tag: B1; Mark: B1
IfcRoot - Name: 40 x 230
Qto_BeamBaseQuantities - Length: 3480; CrossSectionArea: 0.0092; OuterSurfaceArea: 1.79231; GrossSurfaceArea: 1.81071; NetSurfaceArea: 1.81071; GrossVolume: 0.0305357; NetVolume: 0.0305357
Pset_BeamCommon - Reference: 40 x 230; Span: 3480 mm; Slope: 0 rad; Roll: 0 rad; IsExternal: no; LoadBearing: yes
Pset_ConcreteElementGeneral - ConstructionMethod: prefabricated
Pset_Condition - AssessmentCondition: Empty
Pset_EnvironmentalImpactIndicators - Reference: 40 x 230; sets with these values: 2

# IfcBeam: 28_SF_hout_rechthoekig_40 x 230_513, 28_SF_hout_rechthoekig:40 x 230:33591217
In: 010
PredefinedType: BEAM; Material: GVH_i2_naaldhout_generiek
Cpset_Beam - LevelOfAccuracy: in te vullen door Buildwise
IfcClassificationReference - TDS_link: .\05 As Builtdossier\2. Bouwkunde\2.2. Stabiliteit\2.2.0 technische fiche's\TF S 4.9.1.1.1 A - houten roostering sheddak.pdf
IfcElement - Tag: B1; Mark: B1
IfcRoot - Name: 40 x 230
Qto_BeamBaseQuantities - Length: 3480; CrossSectionArea: 0.0092; OuterSurfaceArea: 1.79231; GrossSurfaceArea: 1.81071; NetSurfaceArea: 1.81071; GrossVolume: 0.0305357; NetVolume: 0.0305357
Pset_BeamCommon - Reference: 40 x 230; Span: 3480 mm; Slope: 0 rad; Roll: 0 rad; IsExternal: no; LoadBearing: yes
Pset_ConcreteElementGeneral - ConstructionMethod: prefabricated
Pset_Condition - AssessmentCondition: Empty
Pset_EnvironmentalImpactIndicators - Reference: 40 x 230; sets with these values: 2

# IfcBeam: 28_SF_hout_rechthoekig_40 x 230_515, 28_SF_hout_rechthoekig:40 x 230:33591220
In: 010
PredefinedType: BEAM; Material: GVH_i2_naaldhout_generiek
Cpset_Beam - LevelOfAccuracy: in te vullen door Buildwise
IfcClassificationReference - TDS_link: .\05 As Builtdossier\2. Bouwkunde\2.2. Stabiliteit\2.2.0 technische fiche's\TF S 4.9.1.1.1 A - houten roostering sheddak.pdf
IfcElement - Tag: B1; Mark: B1
IfcRoot - Name: 40 x 230
Qto_BeamBaseQuantities - Length: 3480; CrossSectionArea: 0.0092; OuterSurfaceArea: 1.79231; GrossSurfaceArea: 1.81071; NetSurfaceArea: 1.81071; GrossVolume: 0.0305357; NetVolume: 0.0305357
Pset_BeamCommon - Reference: 40 x 230; Span: 3480 mm; Slope: 0 rad; Roll: 0 rad; IsExternal: no; LoadBearing: yes
Pset_ConcreteElementGeneral - ConstructionMethod: prefabricated
Pset_Condition - AssessmentCondition: Empty
Pset_EnvironmentalImpactIndicators - Reference: 40 x 230; sets with these values: 2

# IfcBeam: 28_SF_hout_rechthoekig_40 x 230_517, 28_SF_hout_rechthoekig:40 x 230:33591223
In: 010
PredefinedType: BEAM; Material: GVH_i2_naaldhout_generiek
Cpset_Beam - LevelOfAccuracy: in te vullen door Buildwise
IfcClassificationReference - TDS_link: .\05 As Builtdossier\2. Bouwkunde\2.2. Stabiliteit\2.2.0 technische fiche's\TF S 4.9.1.1.1 A - houten roostering sheddak.pdf
IfcElement - Tag: A37; Mark: A37
IfcRoot - Name: 40 x 230
Qto_BeamBaseQuantities - Length: 3480; CrossSectionArea: 0.0092; OuterSurfaceArea: 1.79681; GrossSurfaceArea: 1.81521; NetSurfaceArea: 1.81521; GrossVolume: 0.0306122; NetVolume: 0.0306122
Pset_BeamCommon - Reference: 40 x 230; Span: 3480 mm; Slope: 0 rad; Roll: 0 rad; IsExternal: no; LoadBearing: yes
Pset_ConcreteElementGeneral - ConstructionMethod: prefabricated
Pset_Condition - AssessmentCondition: Empty
Pset_EnvironmentalImpactIndicators - Reference: 40 x 230; sets with these values: 2

# IfcBeam: 28_SF_hout_rechthoekig_40 x 230_519, 28_SF_hout_rechthoekig:40 x 230:33591226
In: 010
PredefinedType: BEAM; Material: GVH_i2_naaldhout_generiek
Cpset_Beam - LevelOfAccuracy: in te vullen door Buildwise
IfcClassificationReference - TDS_link: .\05 As Builtdossier\2. Bouwkunde\2.2. Stabiliteit\2.2.0 technische fiche's\TF S 4.9.1.1.1 A - houten roostering sheddak.pdf
IfcElement - Tag: A36; Mark: A36
IfcRoot - Name: 40 x 230
Qto_BeamBaseQuantities - Length: 3480; CrossSectionArea: 0.797831; NetSurfaceArea: 1.59566; NetVolume: 0.0268301
Pset_BeamCommon - Reference: 40 x 230; Span: 3480 mm; Slope: 0 rad; Roll: 0 rad; IsExternal: no; LoadBearing: yes
Pset_ConcreteElementGeneral - ConstructionMethod: prefabricated
Pset_Condition - AssessmentCondition: Empty
Pset_EnvironmentalImpactIndicators - Reference: 40 x 230; sets with these values: 2
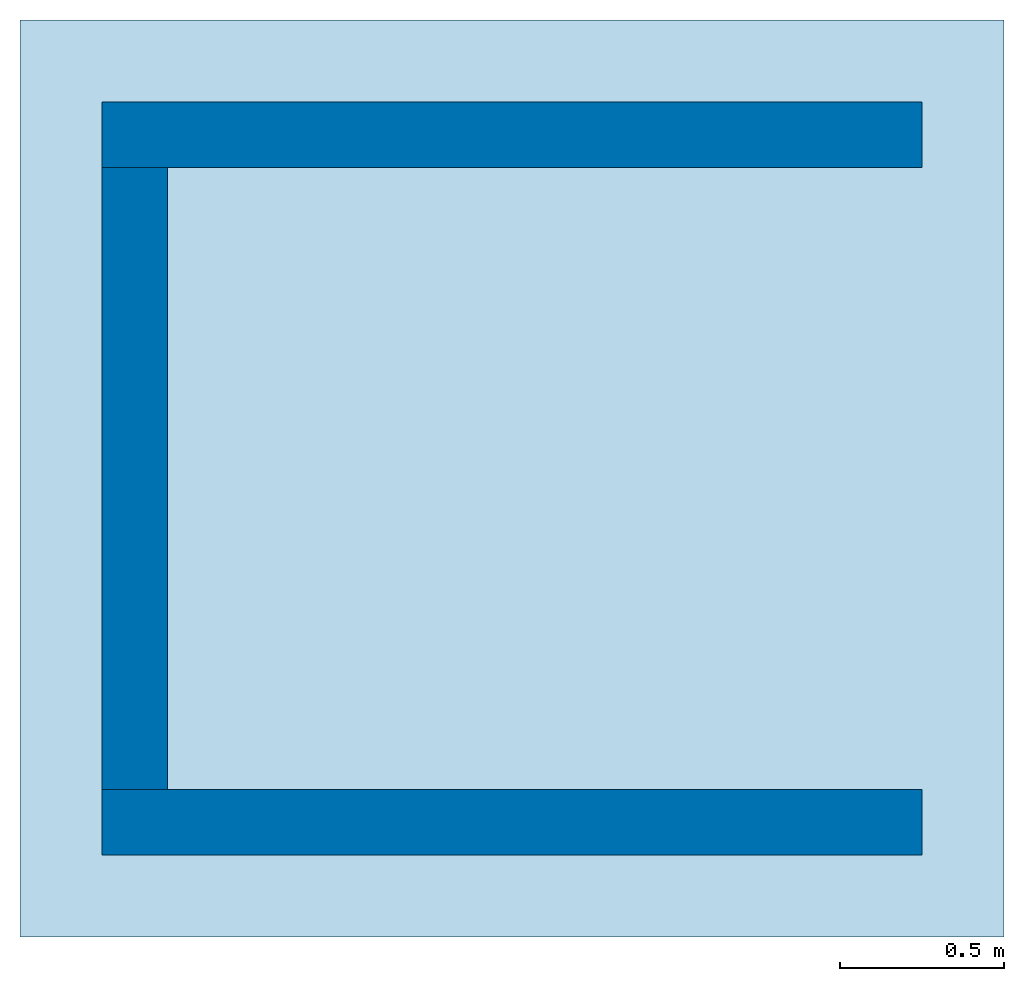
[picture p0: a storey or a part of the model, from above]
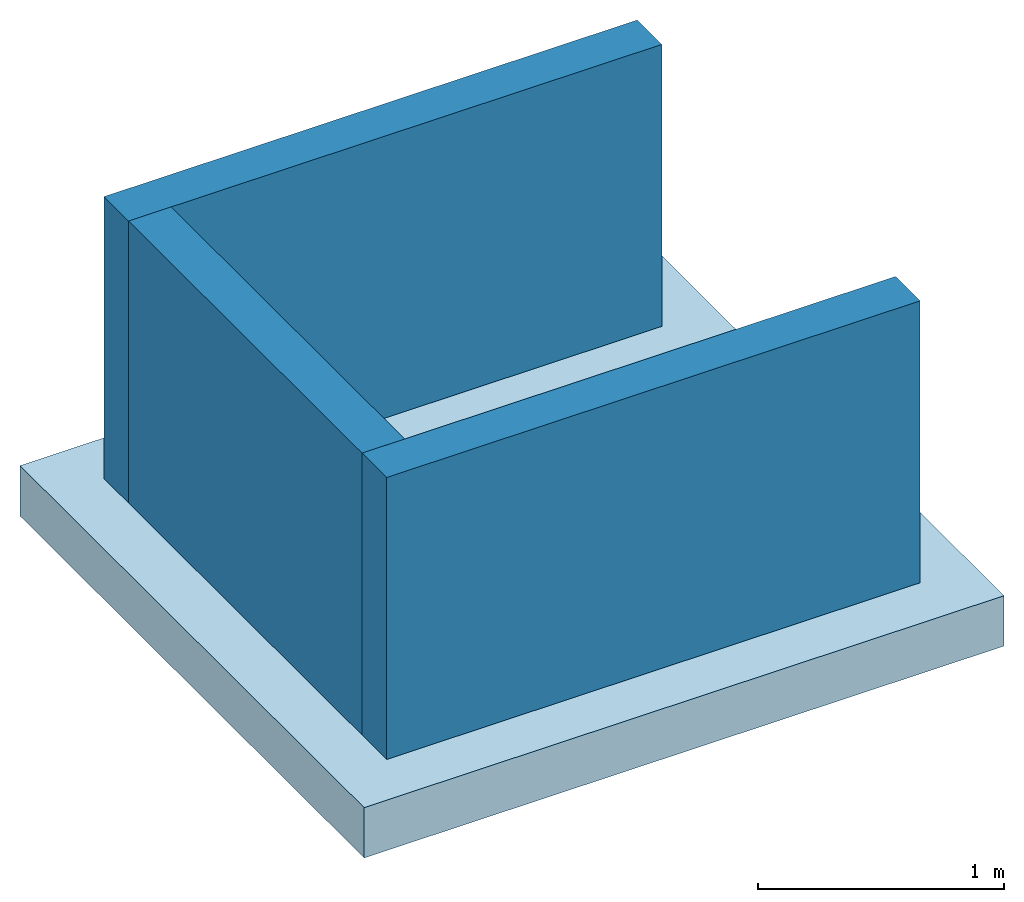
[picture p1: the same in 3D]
Properties of the parts of a building model (IFC4X3_ADD2), part 5 of 28

# IfcBeam: 28_SF_hout_rechthoekig_40 x 230_521, 28_SF_hout_rechthoekig:40 x 230:33591229
In: 010
PredefinedType: BEAM; Material: GVH_i2_naaldhout_generiek
Cpset_Beam - LevelOfAccuracy: in te vullen door Buildwise
IfcClassificationReference - TDS_link: .\05 As Builtdossier\2. Bouwkunde\2.2. Stabiliteit\2.2.0 technische fiche's\TF S 4.9.1.1.1 A - houten roostering sheddak.pdf
IfcElement - Tag: A35; Mark: A35
IfcRoot - Name: 40 x 230
Qto_BeamBaseQuantities - Length: 3480; CrossSectionArea: 0.0092; OuterSurfaceArea: 1.40884; GrossSurfaceArea: 1.42724; NetSurfaceArea: 1.42724; GrossVolume: 0.0240025; NetVolume: 0.0240025
Pset_BeamCommon - Reference: 40 x 230; Span: 3480 mm; Slope: 0 rad; Roll: 0 rad; IsExternal: no; LoadBearing: yes
Pset_ConcreteElementGeneral - ConstructionMethod: prefabricated
Pset_Condition - AssessmentCondition: Empty
Pset_EnvironmentalImpactIndicators - Reference: 40 x 230; sets with these values: 2

# IfcBeam: 28_SF_hout_rechthoekig_40 x 230_523, 28_SF_hout_rechthoekig:40 x 230:33591232
In: 010
PredefinedType: BEAM; Material: GVH_i2_naaldhout_generiek
Cpset_Beam - LevelOfAccuracy: in te vullen door Buildwise
IfcClassificationReference - TDS_link: .\05 As Builtdossier\2. Bouwkunde\2.2. Stabiliteit\2.2.0 technische fiche's\TF S 4.9.1.1.1 A - houten roostering sheddak.pdf
IfcElement - Tag: A34; Mark: A34
IfcRoot - Name: 40 x 230
Qto_BeamBaseQuantities - Length: 3480; CrossSectionArea: 0.0092; OuterSurfaceArea: 1.21486; GrossSurfaceArea: 1.23326; NetSurfaceArea: 1.23326; GrossVolume: 0.0206976; NetVolume: 0.0206976
Pset_BeamCommon - Reference: 40 x 230; Span: 3480 mm; Slope: 0 rad; Roll: 0 rad; IsExternal: no; LoadBearing: yes
Pset_ConcreteElementGeneral - ConstructionMethod: prefabricated
Pset_Condition - AssessmentCondition: Empty
Pset_EnvironmentalImpactIndicators - Reference: 40 x 230; sets with these values: 2

# IfcBeam: 28_SF_hout_rechthoekig_40 x 230_525, 28_SF_hout_rechthoekig:40 x 230:33591235
In: 010
PredefinedType: BEAM; Material: GVH_i2_naaldhout_generiek
Cpset_Beam - LevelOfAccuracy: in te vullen door Buildwise
IfcClassificationReference - TDS_link: .\05 As Builtdossier\2. Bouwkunde\2.2. Stabiliteit\2.2.0 technische fiche's\TF S 4.9.1.1.1 A - houten roostering sheddak.pdf
IfcElement - Tag: A30; Mark: A30
IfcRoot - Name: 40 x 230
Qto_BeamBaseQuantities - Length: 3480; CrossSectionArea: 0.0092; OuterSurfaceArea: 1.00723; GrossSurfaceArea: 1.02563; NetSurfaceArea: 1.02563; GrossVolume: 0.0171601; NetVolume: 0.0171601
Pset_BeamCommon - Reference: 40 x 230; Span: 3480 mm; Slope: 0 rad; Roll: 0 rad; IsExternal: no; LoadBearing: yes
Pset_ConcreteElementGeneral - ConstructionMethod: prefabricated
Pset_Condition - AssessmentCondition: Empty
Pset_EnvironmentalImpactIndicators - Reference: 40 x 230; sets with these values: 2

# IfcBeam: 28_SF_hout_rechthoekig_40 x 230_527, 28_SF_hout_rechthoekig:40 x 230:33591605
In: 010
PredefinedType: BEAM; Material: GVH_i2_naaldhout_generiek
Cpset_Beam - LevelOfAccuracy: in te vullen door Buildwise
IfcClassificationReference - TDS_link: .\05 As Builtdossier\2. Bouwkunde\2.2. Stabiliteit\2.2.0 technische fiche's\TF S 4.9.1.1.1 A - houten roostering sheddak.pdf
IfcElement - Tag: F1; Mark: F1
IfcRoot - Name: 40 x 230
Qto_BeamBaseQuantities - Length: 3480; CrossSectionArea: 0.0092; OuterSurfaceArea: 2.08429; GrossSurfaceArea: 2.10269; NetSurfaceArea: 2.10269; GrossVolume: 0.0355101; NetVolume: 0.0355101
Pset_BeamCommon - Reference: 40 x 230; Span: 3480 mm; Slope: 0 rad; Roll: 0 rad; IsExternal: no; LoadBearing: yes
Pset_ConcreteElementGeneral - ConstructionMethod: prefabricated
Pset_Condition - AssessmentCondition: Empty
Pset_EnvironmentalImpactIndicators - Reference: 40 x 230; sets with these values: 2

# IfcBeam: 28_SF_hout_rechthoekig_40 x 230_529, 28_SF_hout_rechthoekig:40 x 230:33591607
In: 010
PredefinedType: BEAM; Material: GVH_i2_naaldhout_generiek
Cpset_Beam - LevelOfAccuracy: in te vullen door Buildwise
IfcClassificationReference - TDS_link: .\05 As Builtdossier\2. Bouwkunde\2.2. Stabiliteit\2.2.0 technische fiche's\TF S 4.9.1.1.1 A - houten roostering sheddak.pdf
IfcElement - Tag: H3; Mark: H3
IfcRoot - Name: 40 x 230
Qto_BeamBaseQuantities - Length: 3480; CrossSectionArea: 0.0092; OuterSurfaceArea: 1.89031; GrossSurfaceArea: 1.90871; NetSurfaceArea: 1.90871; GrossVolume: 0.0322053; NetVolume: 0.0322053
Pset_BeamCommon - Reference: 40 x 230; Span: 3480 mm; Slope: 0 rad; Roll: 0 rad; IsExternal: no; LoadBearing: yes
Pset_ConcreteElementGeneral - ConstructionMethod: prefabricated
Pset_Condition - AssessmentCondition: Empty
Pset_EnvironmentalImpactIndicators - Reference: 40 x 230; sets with these values: 2

# IfcBeam: 28_SF_hout_rechthoekig_40 x 230_53, 28_SF_hout_rechthoekig:40 x 230:33579928
In: 010
PredefinedType: BEAM; Material: GVH_i2_naaldhout_generiek
Cpset_Beam - LevelOfAccuracy: in te vullen door Buildwise
IfcClassificationReference - TDS_link: .\05 As Builtdossier\2. Bouwkunde\2.2. Stabiliteit\2.2.0 technische fiche's\TF S 4.9.1.1.1 A - houten roostering sheddak.pdf
IfcElement - Tag: B1; Mark: B1
IfcRoot - Name: 40 x 230
Qto_BeamBaseQuantities - Length: 3340; CrossSectionArea: 0.0092; OuterSurfaceArea: 1.79133; GrossSurfaceArea: 1.80973; NetSurfaceArea: 1.80973; GrossVolume: 0.030519; NetVolume: 0.030519
Pset_BeamCommon - Reference: 40 x 230; Span: 3340 mm; Slope: 0 rad; Roll: 0 rad; IsExternal: no; LoadBearing: yes
Pset_ConcreteElementGeneral - ConstructionMethod: prefabricated
Pset_Condition - AssessmentCondition: Empty
Pset_EnvironmentalImpactIndicators - Reference: 40 x 230; sets with these values: 2

# IfcBeam: 28_SF_hout_rechthoekig_40 x 230_531, 28_SF_hout_rechthoekig:40 x 230:33591609
In: 010
PredefinedType: BEAM; Material: GVH_i2_naaldhout_generiek
Cpset_Beam - LevelOfAccuracy: in te vullen door Buildwise
IfcClassificationReference - TDS_link: .\05 As Builtdossier\2. Bouwkunde\2.2. Stabiliteit\2.2.0 technische fiche's\TF S 4.9.1.1.1 A - houten roostering sheddak.pdf
IfcElement - Tag: A9; Mark: A9
IfcRoot - Name: 40 x 230
Qto_BeamBaseQuantities - Length: 3480; CrossSectionArea: 0.0092; OuterSurfaceArea: 1.69633; GrossSurfaceArea: 1.71473; NetSurfaceArea: 1.71473; GrossVolume: 0.0289004; NetVolume: 0.0289004
Pset_BeamCommon - Reference: 40 x 230; Span: 3480 mm; Slope: 0 rad; Roll: 0 rad; IsExternal: no; LoadBearing: yes
Pset_ConcreteElementGeneral - ConstructionMethod: prefabricated
Pset_Condition - AssessmentCondition: Empty
Pset_EnvironmentalImpactIndicators - Reference: 40 x 230; sets with these values: 2

# IfcBeam: 28_SF_hout_rechthoekig_40 x 230_533, 28_SF_hout_rechthoekig:40 x 230:33591611
In: 010
PredefinedType: BEAM; Material: GVH_i2_naaldhout_generiek
Cpset_Beam - LevelOfAccuracy: in te vullen door Buildwise
IfcClassificationReference - TDS_link: .\05 As Builtdossier\2. Bouwkunde\2.2. Stabiliteit\2.2.0 technische fiche's\TF S 4.9.1.1.1 A - houten roostering sheddak.pdf
IfcElement - Tag: A8; Mark: A8
IfcRoot - Name: 40 x 230
Qto_BeamBaseQuantities - Length: 3480; CrossSectionArea: 0.0092; OuterSurfaceArea: 1.50235; GrossSurfaceArea: 1.52075; NetSurfaceArea: 1.52075; GrossVolume: 0.0255956; NetVolume: 0.0255956
Pset_BeamCommon - Reference: 40 x 230; Span: 3480 mm; Slope: 0 rad; Roll: 0 rad; IsExternal: no; LoadBearing: yes
Pset_ConcreteElementGeneral - ConstructionMethod: prefabricated
Pset_Condition - AssessmentCondition: Empty
Pset_EnvironmentalImpactIndicators - Reference: 40 x 230; sets with these values: 2

# IfcBeam: 28_SF_hout_rechthoekig_40 x 230_535, 28_SF_hout_rechthoekig:40 x 230:33591613
In: 010
PredefinedType: BEAM; Material: GVH_i2_naaldhout_generiek
Cpset_Beam - LevelOfAccuracy: in te vullen door Buildwise
IfcClassificationReference - TDS_link: .\05 As Builtdossier\2. Bouwkunde\2.2. Stabiliteit\2.2.0 technische fiche's\TF S 4.9.1.1.1 A - houten roostering sheddak.pdf
IfcElement - Tag: A7; Mark: A7
IfcRoot - Name: 40 x 230
Qto_BeamBaseQuantities - Length: 3480; CrossSectionArea: 0.0092; OuterSurfaceArea: 1.30836; GrossSurfaceArea: 1.32676; NetSurfaceArea: 1.32676; GrossVolume: 0.0222906; NetVolume: 0.0222906
Pset_BeamCommon - Reference: 40 x 230; Span: 3480 mm; Slope: 0 rad; Roll: 0 rad; IsExternal: no; LoadBearing: yes
Pset_ConcreteElementGeneral - ConstructionMethod: prefabricated
Pset_Condition - AssessmentCondition: Empty
Pset_EnvironmentalImpactIndicators - Reference: 40 x 230; sets with these values: 2

# IfcBeam: 28_SF_hout_rechthoekig_40 x 230_537, 28_SF_hout_rechthoekig:40 x 230:33591615
In: 010
PredefinedType: BEAM; Material: GVH_i2_naaldhout_generiek
Cpset_Beam - LevelOfAccuracy: in te vullen door Buildwise
IfcClassificationReference - TDS_link: .\05 As Builtdossier\2. Bouwkunde\2.2. Stabiliteit\2.2.0 technische fiche's\TF S 4.9.1.1.1 A - houten roostering sheddak.pdf
IfcElement - Tag: A6; Mark: A6
IfcRoot - Name: 40 x 230
Qto_BeamBaseQuantities - Length: 3480; CrossSectionArea: 0.0092; OuterSurfaceArea: 1.11438; GrossSurfaceArea: 1.13278; NetSurfaceArea: 1.13278; GrossVolume: 0.0189858; NetVolume: 0.0189858
Pset_BeamCommon - Reference: 40 x 230; Span: 3480 mm; Slope: 0 rad; Roll: 0 rad; IsExternal: no; LoadBearing: yes
Pset_ConcreteElementGeneral - ConstructionMethod: prefabricated
Pset_Condition - AssessmentCondition: Empty
Pset_EnvironmentalImpactIndicators - Reference: 40 x 230; sets with these values: 2

# IfcBeam: 28_SF_hout_rechthoekig_40 x 230_539, 28_SF_hout_rechthoekig:40 x 230:33591617
In: 010
PredefinedType: BEAM; Material: GVH_i2_naaldhout_generiek
Cpset_Beam - LevelOfAccuracy: in te vullen door Buildwise
IfcClassificationReference - TDS_link: .\05 As Builtdossier\2. Bouwkunde\2.2. Stabiliteit\2.2.0 technische fiche's\TF S 4.9.1.1.1 A - houten roostering sheddak.pdf
IfcElement - Tag: A5; Mark: A5
IfcRoot - Name: 40 x 230
Qto_BeamBaseQuantities - Length: 3480; CrossSectionArea: 0.0092; OuterSurfaceArea: 0.920399; GrossSurfaceArea: 0.938799; NetSurfaceArea: 0.938799; GrossVolume: 0.0156809; NetVolume: 0.0156809
Pset_BeamCommon - Reference: 40 x 230; Span: 3480 mm; Slope: 0 rad; Roll: 0 rad; IsExternal: no; LoadBearing: yes
Pset_ConcreteElementGeneral - ConstructionMethod: prefabricated
Pset_Condition - AssessmentCondition: Empty
Pset_EnvironmentalImpactIndicators - Reference: 40 x 230; sets with these values: 2

# IfcBeam: 28_SF_hout_rechthoekig_40 x 230_541, 28_SF_hout_rechthoekig:40 x 230:33591619
In: 010
PredefinedType: BEAM; Material: GVH_i2_naaldhout_generiek
Cpset_Beam - LevelOfAccuracy: in te vullen door Buildwise
IfcClassificationReference - TDS_link: .\05 As Builtdossier\2. Bouwkunde\2.2. Stabiliteit\2.2.0 technische fiche's\TF S 4.9.1.1.1 A - houten roostering sheddak.pdf
IfcElement - Tag: A4; Mark: A4
IfcRoot - Name: 40 x 230
Qto_BeamBaseQuantities - Length: 3480; CrossSectionArea: 0.0092; OuterSurfaceArea: 0.726418; GrossSurfaceArea: 0.744818; NetSurfaceArea: 0.744818; GrossVolume: 0.012376; NetVolume: 0.012376
Pset_BeamCommon - Reference: 40 x 230; Span: 3480 mm; Slope: 0 rad; Roll: 0 rad; IsExternal: no; LoadBearing: yes
Pset_ConcreteElementGeneral - ConstructionMethod: prefabricated
Pset_Condition - AssessmentCondition: Empty
Pset_EnvironmentalImpactIndicators - Reference: 40 x 230; sets with these values: 2

# IfcBeam: 28_SF_hout_rechthoekig_40 x 230_543, 28_SF_hout_rechthoekig:40 x 230:33591621
In: 010
PredefinedType: BEAM; Material: GVH_i2_naaldhout_generiek
Cpset_Beam - LevelOfAccuracy: in te vullen door Buildwise
IfcClassificationReference - TDS_link: .\05 As Builtdossier\2. Bouwkunde\2.2. Stabiliteit\2.2.0 technische fiche's\TF S 4.9.1.1.1 A - houten roostering sheddak.pdf
IfcElement - Tag: A3; Mark: A3
IfcRoot - Name: 40 x 230
Qto_BeamBaseQuantities - Length: 3480; CrossSectionArea: 0.0092; OuterSurfaceArea: 0.532436; GrossSurfaceArea: 0.550836; NetSurfaceArea: 0.550836; GrossVolume: 0.00907113; NetVolume: 0.00907113
Pset_BeamCommon - Reference: 40 x 230; Span: 3480 mm; Slope: 0 rad; Roll: 0 rad; IsExternal: no; LoadBearing: yes
Pset_ConcreteElementGeneral - ConstructionMethod: prefabricated
Pset_Condition - AssessmentCondition: Empty
Pset_EnvironmentalImpactIndicators - Reference: 40 x 230; sets with these values: 2

# IfcBeam: 28_SF_hout_rechthoekig_40 x 230_545, 28_SF_hout_rechthoekig:40 x 230:33591623
In: 010
PredefinedType: BEAM; Material: GVH_i2_naaldhout_generiek
Cpset_Beam - LevelOfAccuracy: in te vullen door Buildwise
IfcClassificationReference - TDS_link: .\05 As Builtdossier\2. Bouwkunde\2.2. Stabiliteit\2.2.0 technische fiche's\TF S 4.9.1.1.1 A - houten roostering sheddak.pdf
IfcElement - Tag: A2; Mark: A2
IfcRoot - Name: 40 x 230
Qto_BeamBaseQuantities - Length: 3480; CrossSectionArea: 0.0092; OuterSurfaceArea: 0.338454; GrossSurfaceArea: 0.356854; NetSurfaceArea: 0.356854; GrossVolume: 0.00576626; NetVolume: 0.00576626
Pset_BeamCommon - Reference: 40 x 230; Span: 3480 mm; Slope: 0 rad; Roll: 0 rad; IsExternal: no; LoadBearing: yes
Pset_ConcreteElementGeneral - ConstructionMethod: prefabricated
Pset_Condition - AssessmentCondition: Empty
Pset_EnvironmentalImpactIndicators - Reference: 40 x 230; sets with these values: 2

# IfcBeam: 28_SF_hout_rechthoekig_40 x 230_547, 28_SF_hout_rechthoekig:40 x 230:33592493
In: 010
PredefinedType: BEAM; Material: GVH_i2_naaldhout_generiek
Cpset_Beam - LevelOfAccuracy: in te vullen door Buildwise
IfcClassificationReference - TDS_link: .\05 As Builtdossier\2. Bouwkunde\2.2. Stabiliteit\2.2.0 technische fiche's\TF S 4.9.1.1.1 A - houten roostering sheddak.pdf
IfcElement - Tag: A30; Mark: A30
IfcRoot - Name: 40 x 230
Qto_BeamBaseQuantities - Length: 3340; CrossSectionArea: 0.0092; OuterSurfaceArea: 1.02042; GrossSurfaceArea: 1.03882; NetSurfaceArea: 1.03882; GrossVolume: 0.0173848; NetVolume: 0.0173848
Pset_BeamCommon - Reference: 40 x 230; Span: 3340 mm; Slope: 0 rad; Roll: 0 rad; IsExternal: no; LoadBearing: yes
Pset_ConcreteElementGeneral - ConstructionMethod: prefabricated
Pset_Condition - AssessmentCondition: Empty
Pset_EnvironmentalImpactIndicators - Reference: 40 x 230; sets with these values: 2

# IfcBeam: 28_SF_hout_rechthoekig_40 x 230_549, 28_SF_hout_rechthoekig:40 x 230:33592496
In: 010
PredefinedType: BEAM; Material: GVH_i2_naaldhout_generiek
Cpset_Beam - LevelOfAccuracy: in te vullen door Buildwise
IfcClassificationReference - TDS_link: .\05 As Builtdossier\2. Bouwkunde\2.2. Stabiliteit\2.2.0 technische fiche's\TF S 4.9.1.1.1 A - houten roostering sheddak.pdf
IfcElement - Tag: A34; Mark: A34
IfcRoot - Name: 40 x 230
Qto_BeamBaseQuantities - Length: 3340; CrossSectionArea: 0.0092; OuterSurfaceArea: 1.21486; GrossSurfaceArea: 1.23326; NetSurfaceArea: 1.23326; GrossVolume: 0.0206977; NetVolume: 0.0206977
Pset_BeamCommon - Reference: 40 x 230; Span: 3340 mm; Slope: 0 rad; Roll: 0 rad; IsExternal: no; LoadBearing: yes
Pset_ConcreteElementGeneral - ConstructionMethod: prefabricated
Pset_Condition - AssessmentCondition: Empty
Pset_EnvironmentalImpactIndicators - Reference: 40 x 230; sets with these values: 2

# IfcBeam: 28_SF_hout_rechthoekig_40 x 230_55, 28_SF_hout_rechthoekig:40 x 230:33579930
In: 010
PredefinedType: BEAM; Material: GVH_i2_naaldhout_generiek
Cpset_Beam - LevelOfAccuracy: in te vullen door Buildwise
IfcClassificationReference - TDS_link: .\05 As Builtdossier\2. Bouwkunde\2.2. Stabiliteit\2.2.0 technische fiche's\TF S 4.9.1.1.1 A - houten roostering sheddak.pdf
IfcElement - Tag: B1; Mark: B1
IfcRoot - Name: 40 x 230
Qto_BeamBaseQuantities - Length: 3340; CrossSectionArea: 0.0092; OuterSurfaceArea: 1.79133; GrossSurfaceArea: 1.80973; NetSurfaceArea: 1.80973; GrossVolume: 0.030519; NetVolume: 0.030519
Pset_BeamCommon - Reference: 40 x 230; Span: 3340 mm; Slope: 0 rad; Roll: 0 rad; IsExternal: no; LoadBearing: yes
Pset_ConcreteElementGeneral - ConstructionMethod: prefabricated
Pset_Condition - AssessmentCondition: Empty
Pset_EnvironmentalImpactIndicators - Reference: 40 x 230; sets with these values: 2

# IfcBeam: 28_SF_hout_rechthoekig_40 x 230_551, 28_SF_hout_rechthoekig:40 x 230:33592503
In: 010
PredefinedType: BEAM; Material: GVH_i2_naaldhout_generiek
Cpset_Beam - LevelOfAccuracy: in te vullen door Buildwise
IfcClassificationReference - TDS_link: .\05 As Builtdossier\2. Bouwkunde\2.2. Stabiliteit\2.2.0 technische fiche's\TF S 4.9.1.1.1 A - houten roostering sheddak.pdf
IfcElement - Tag: A35; Mark: A35
IfcRoot - Name: 40 x 230
Qto_BeamBaseQuantities - Length: 3340; CrossSectionArea: 0.0092; OuterSurfaceArea: 1.40884; GrossSurfaceArea: 1.42724; NetSurfaceArea: 1.42724; GrossVolume: 0.0240025; NetVolume: 0.0240025
Pset_BeamCommon - Reference: 40 x 230; Span: 3340 mm; Slope: 0 rad; Roll: 0 rad; IsExternal: no; LoadBearing: yes
Pset_ConcreteElementGeneral - ConstructionMethod: prefabricated
Pset_Condition - AssessmentCondition: Empty
Pset_EnvironmentalImpactIndicators - Reference: 40 x 230; sets with these values: 2

# IfcBeam: 28_SF_hout_rechthoekig_40 x 230_553, 28_SF_hout_rechthoekig:40 x 230:33592506
In: 010
PredefinedType: BEAM; Material: GVH_i2_naaldhout_generiek
Cpset_Beam - LevelOfAccuracy: in te vullen door Buildwise
IfcClassificationReference - TDS_link: .\05 As Builtdossier\2. Bouwkunde\2.2. Stabiliteit\2.2.0 technische fiche's\TF S 4.9.1.1.1 A - houten roostering sheddak.pdf
IfcElement - Tag: A36; Mark: A36
IfcRoot - Name: 40 x 230
Qto_BeamBaseQuantities - Length: 3340; CrossSectionArea: 0.0092; OuterSurfaceArea: 1.60283; GrossSurfaceArea: 1.62123; NetSurfaceArea: 1.62123; GrossVolume: 0.0273074; NetVolume: 0.0273074
Pset_BeamCommon - Reference: 40 x 230; Span: 3340 mm; Slope: 0 rad; Roll: 0 rad; IsExternal: no; LoadBearing: yes
Pset_ConcreteElementGeneral - ConstructionMethod: prefabricated
Pset_Condition - AssessmentCondition: Empty
Pset_EnvironmentalImpactIndicators - Reference: 40 x 230; sets with these values: 2

# IfcBeam: 28_SF_hout_rechthoekig_40 x 230_555, 28_SF_hout_rechthoekig:40 x 230:33592509
In: 010
PredefinedType: BEAM; Material: GVH_i2_naaldhout_generiek
Cpset_Beam - LevelOfAccuracy: in te vullen door Buildwise
IfcClassificationReference - TDS_link: .\05 As Builtdossier\2. Bouwkunde\2.2. Stabiliteit\2.2.0 technische fiche's\TF S 4.9.1.1.1 A - houten roostering sheddak.pdf
IfcElement - Tag: A37; Mark: A37
IfcRoot - Name: 40 x 230
Qto_BeamBaseQuantities - Length: 3340; CrossSectionArea: 0.0092; OuterSurfaceArea: 1.78695; GrossSurfaceArea: 1.80535; NetSurfaceArea: 1.80535; GrossVolume: 0.0304443; NetVolume: 0.0304443
Pset_BeamCommon - Reference: 40 x 230; Span: 3340 mm; Slope: 0 rad; Roll: 0 rad; IsExternal: no; LoadBearing: yes
Pset_ConcreteElementGeneral - ConstructionMethod: prefabricated
Pset_Condition - AssessmentCondition: Empty
Pset_EnvironmentalImpactIndicators - Reference: 40 x 230; sets with these values: 2

# IfcBeam: 28_SF_hout_rechthoekig_40 x 230_557, 28_SF_hout_rechthoekig:40 x 230:33592512
In: 010
PredefinedType: BEAM; Material: GVH_i2_naaldhout_generiek
Cpset_Beam - LevelOfAccuracy: in te vullen door Buildwise
IfcClassificationReference - TDS_link: .\05 As Builtdossier\2. Bouwkunde\2.2. Stabiliteit\2.2.0 technische fiche's\TF S 4.9.1.1.1 A - houten roostering sheddak.pdf
IfcElement - Tag: B1; Mark: B1
IfcRoot - Name: 40 x 230
Qto_BeamBaseQuantities - Length: 3340; CrossSectionArea: 0.0092; OuterSurfaceArea: 1.79232; GrossSurfaceArea: 1.81072; NetSurfaceArea: 1.81072; GrossVolume: 0.0305358; NetVolume: 0.0305358
Pset_BeamCommon - Reference: 40 x 230; Span: 3340 mm; Slope: 0 rad; Roll: 0 rad; IsExternal: no; LoadBearing: yes
Pset_ConcreteElementGeneral - ConstructionMethod: prefabricated
Pset_Condition - AssessmentCondition: Empty
Pset_EnvironmentalImpactIndicators - Reference: 40 x 230; sets with these values: 2

# IfcBeam: 28_SF_hout_rechthoekig_40 x 230_559, 28_SF_hout_rechthoekig:40 x 230:33592515
In: 010
PredefinedType: BEAM; Material: GVH_i2_naaldhout_generiek
Cpset_Beam - LevelOfAccuracy: in te vullen door Buildwise
IfcClassificationReference - TDS_link: .\05 As Builtdossier\2. Bouwkunde\2.2. Stabiliteit\2.2.0 technische fiche's\TF S 4.9.1.1.1 A - houten roostering sheddak.pdf
IfcElement - Tag: B1; Mark: B1
IfcRoot - Name: 40 x 230
Qto_BeamBaseQuantities - Length: 3340; CrossSectionArea: 0.0092; OuterSurfaceArea: 1.79232; GrossSurfaceArea: 1.81072; NetSurfaceArea: 1.81072; GrossVolume: 0.0305358; NetVolume: 0.0305358
Pset_BeamCommon - Reference: 40 x 230; Span: 3340 mm; Slope: 0 rad; Roll: 0 rad; IsExternal: no; LoadBearing: yes
Pset_ConcreteElementGeneral - ConstructionMethod: prefabricated
Pset_Condition - AssessmentCondition: Empty
Pset_EnvironmentalImpactIndicators - Reference: 40 x 230; sets with these values: 2

# IfcBeam: 28_SF_hout_rechthoekig_40 x 230_561, 28_SF_hout_rechthoekig:40 x 230:33592518
In: 010
PredefinedType: BEAM; Material: GVH_i2_naaldhout_generiek
Cpset_Beam - LevelOfAccuracy: in te vullen door Buildwise
IfcClassificationReference - TDS_link: .\05 As Builtdossier\2. Bouwkunde\2.2. Stabiliteit\2.2.0 technische fiche's\TF S 4.9.1.1.1 A - houten roostering sheddak.pdf
IfcElement - Tag: B1; Mark: B1
IfcRoot - Name: 40 x 230
Qto_BeamBaseQuantities - Length: 3340; CrossSectionArea: 0.0092; OuterSurfaceArea: 1.79232; GrossSurfaceArea: 1.81072; NetSurfaceArea: 1.81072; GrossVolume: 0.0305358; NetVolume: 0.0305358
Pset_BeamCommon - Reference: 40 x 230; Span: 3340 mm; Slope: 0 rad; Roll: 0 rad; IsExternal: no; LoadBearing: yes
Pset_ConcreteElementGeneral - ConstructionMethod: prefabricated
Pset_Condition - AssessmentCondition: Empty
Pset_EnvironmentalImpactIndicators - Reference: 40 x 230; sets with these values: 2

# IfcBeam: 28_SF_hout_rechthoekig_40 x 230_563, 28_SF_hout_rechthoekig:40 x 230:33592521
In: 010
PredefinedType: BEAM; Material: GVH_i2_naaldhout_generiek
Cpset_Beam - LevelOfAccuracy: in te vullen door Buildwise
IfcClassificationReference - TDS_link: .\05 As Builtdossier\2. Bouwkunde\2.2. Stabiliteit\2.2.0 technische fiche's\TF S 4.9.1.1.1 A - houten roostering sheddak.pdf
IfcElement - Tag: B1; Mark: B1
IfcRoot - Name: 40 x 230
Qto_BeamBaseQuantities - Length: 3340; CrossSectionArea: 0.0092; OuterSurfaceArea: 1.79232; GrossSurfaceArea: 1.81072; NetSurfaceArea: 1.81072; GrossVolume: 0.0305358; NetVolume: 0.0305358
Pset_BeamCommon - Reference: 40 x 230; Span: 3340 mm; Slope: 0 rad; Roll: 0 rad; IsExternal: no; LoadBearing: yes
Pset_ConcreteElementGeneral - ConstructionMethod: prefabricated
Pset_Condition - AssessmentCondition: Empty
Pset_EnvironmentalImpactIndicators - Reference: 40 x 230; sets with these values: 2

# IfcBeam: 28_SF_hout_rechthoekig_40 x 230_565, 28_SF_hout_rechthoekig:40 x 230:33592524
In: 010
PredefinedType: BEAM; Material: GVH_i2_naaldhout_generiek
Cpset_Beam - LevelOfAccuracy: in te vullen door Buildwise
IfcClassificationReference - TDS_link: .\05 As Builtdossier\2. Bouwkunde\2.2. Stabiliteit\2.2.0 technische fiche's\TF S 4.9.1.1.1 A - houten roostering sheddak.pdf
IfcElement - Tag: B1; Mark: B1
IfcRoot - Name: 40 x 230
Qto_BeamBaseQuantities - Length: 3340; CrossSectionArea: 0.0092; OuterSurfaceArea: 1.79232; GrossSurfaceArea: 1.81072; NetSurfaceArea: 1.81072; GrossVolume: 0.0305358; NetVolume: 0.0305358
Pset_BeamCommon - Reference: 40 x 230; Span: 3340 mm; Slope: 0 rad; Roll: 0 rad; IsExternal: no; LoadBearing: yes
Pset_ConcreteElementGeneral - ConstructionMethod: prefabricated
Pset_Condition - AssessmentCondition: Empty
Pset_EnvironmentalImpactIndicators - Reference: 40 x 230; sets with these values: 2

# IfcBeam: 28_SF_hout_rechthoekig_40 x 230_567, 28_SF_hout_rechthoekig:40 x 230:33592527
In: 010
PredefinedType: BEAM; Material: GVH_i2_naaldhout_generiek
Cpset_Beam - LevelOfAccuracy: in te vullen door Buildwise
IfcClassificationReference - TDS_link: .\05 As Builtdossier\2. Bouwkunde\2.2. Stabiliteit\2.2.0 technische fiche's\TF S 4.9.1.1.1 A - houten roostering sheddak.pdf
IfcElement - Tag: B1; Mark: B1
IfcRoot - Name: 40 x 230
Qto_BeamBaseQuantities - Length: 3340; CrossSectionArea: 0.0092; OuterSurfaceArea: 1.79232; GrossSurfaceArea: 1.81072; NetSurfaceArea: 1.81072; GrossVolume: 0.0305358; NetVolume: 0.0305358
Pset_BeamCommon - Reference: 40 x 230; Span: 3340 mm; Slope: 0 rad; Roll: 0 rad; IsExternal: no; LoadBearing: yes
Pset_ConcreteElementGeneral - ConstructionMethod: prefabricated
Pset_Condition - AssessmentCondition: Empty
Pset_EnvironmentalImpactIndicators - Reference: 40 x 230; sets with these values: 2

# IfcBeam: 28_SF_hout_rechthoekig_40 x 230_569, 28_SF_hout_rechthoekig:40 x 230:33592530
In: 010
PredefinedType: BEAM; Material: GVH_i2_naaldhout_generiek
Cpset_Beam - LevelOfAccuracy: in te vullen door Buildwise
IfcClassificationReference - TDS_link: .\05 As Builtdossier\2. Bouwkunde\2.2. Stabiliteit\2.2.0 technische fiche's\TF S 4.9.1.1.1 A - houten roostering sheddak.pdf
IfcElement - Tag: B1; Mark: B1
IfcRoot - Name: 40 x 230
Qto_BeamBaseQuantities - Length: 3340; CrossSectionArea: 0.0092; OuterSurfaceArea: 1.79232; GrossSurfaceArea: 1.81072; NetSurfaceArea: 1.81072; GrossVolume: 0.0305358; NetVolume: 0.0305358
Pset_BeamCommon - Reference: 40 x 230; Span: 3340 mm; Slope: 0 rad; Roll: 0 rad; IsExternal: no; LoadBearing: yes
Pset_ConcreteElementGeneral - ConstructionMethod: prefabricated
Pset_Condition - AssessmentCondition: Empty
Pset_EnvironmentalImpactIndicators - Reference: 40 x 230; sets with these values: 2

# IfcBeam: 28_SF_hout_rechthoekig_40 x 230_57, 28_SF_hout_rechthoekig:40 x 230:33579932
In: 010
PredefinedType: BEAM; Material: GVH_i2_naaldhout_generiek
Cpset_Beam - LevelOfAccuracy: in te vullen door Buildwise
IfcClassificationReference - TDS_link: .\05 As Builtdossier\2. Bouwkunde\2.2. Stabiliteit\2.2.0 technische fiche's\TF S 4.9.1.1.1 A - houten roostering sheddak.pdf
IfcElement - Tag: B1; Mark: B1
IfcRoot - Name: 40 x 230
Qto_BeamBaseQuantities - Length: 3340; CrossSectionArea: 0.0092; OuterSurfaceArea: 1.79133; GrossSurfaceArea: 1.80973; NetSurfaceArea: 1.80973; GrossVolume: 0.030519; NetVolume: 0.030519
Pset_BeamCommon - Reference: 40 x 230; Span: 3340 mm; Slope: 0 rad; Roll: 0 rad; IsExternal: no; LoadBearing: yes
Pset_ConcreteElementGeneral - ConstructionMethod: prefabricated
Pset_Condition - AssessmentCondition: Empty
Pset_EnvironmentalImpactIndicators - Reference: 40 x 230; sets with these values: 2

# IfcBeam: 28_SF_hout_rechthoekig_40 x 230_571, 28_SF_hout_rechthoekig:40 x 230:33592533
In: 010
PredefinedType: BEAM; Material: GVH_i2_naaldhout_generiek
Cpset_Beam - LevelOfAccuracy: in te vullen door Buildwise
IfcClassificationReference - TDS_link: .\05 As Builtdossier\2. Bouwkunde\2.2. Stabiliteit\2.2.0 technische fiche's\TF S 4.9.1.1.1 A - houten roostering sheddak.pdf
IfcElement - Tag: B1; Mark: B1
IfcRoot - Name: 40 x 230
Qto_BeamBaseQuantities - Length: 3340; CrossSectionArea: 0.0092; OuterSurfaceArea: 1.79232; GrossSurfaceArea: 1.81072; NetSurfaceArea: 1.81072; GrossVolume: 0.0305358; NetVolume: 0.0305358
Pset_BeamCommon - Reference: 40 x 230; Span: 3340 mm; Slope: 0 rad; Roll: 0 rad; IsExternal: no; LoadBearing: yes
Pset_ConcreteElementGeneral - ConstructionMethod: prefabricated
Pset_Condition - AssessmentCondition: Empty
Pset_EnvironmentalImpactIndicators - Reference: 40 x 230; sets with these values: 2

# IfcBeam: 28_SF_hout_rechthoekig_40 x 230_573, 28_SF_hout_rechthoekig:40 x 230:33592536
In: 010
PredefinedType: BEAM; Material: GVH_i2_naaldhout_generiek
Cpset_Beam - LevelOfAccuracy: in te vullen door Buildwise
IfcClassificationReference - TDS_link: .\05 As Builtdossier\2. Bouwkunde\2.2. Stabiliteit\2.2.0 technische fiche's\TF S 4.9.1.1.1 A - houten roostering sheddak.pdf
IfcElement - Tag: B1; Mark: B1
IfcRoot - Name: 40 x 230
Qto_BeamBaseQuantities - Length: 3340; CrossSectionArea: 0.0092; OuterSurfaceArea: 1.79232; GrossSurfaceArea: 1.81072; NetSurfaceArea: 1.81072; GrossVolume: 0.0305358; NetVolume: 0.0305358
Pset_BeamCommon - Reference: 40 x 230; Span: 3340 mm; Slope: 0 rad; Roll: 0 rad; IsExternal: no; LoadBearing: yes
Pset_ConcreteElementGeneral - ConstructionMethod: prefabricated
Pset_Condition - AssessmentCondition: Empty
Pset_EnvironmentalImpactIndicators - Reference: 40 x 230; sets with these values: 2

# IfcBeam: 28_SF_hout_rechthoekig_40 x 230_575, 28_SF_hout_rechthoekig:40 x 230:33592539
In: 010
PredefinedType: BEAM; Material: GVH_i2_naaldhout_generiek
Cpset_Beam - LevelOfAccuracy: in te vullen door Buildwise
IfcClassificationReference - TDS_link: .\05 As Builtdossier\2. Bouwkunde\2.2. Stabiliteit\2.2.0 technische fiche's\TF S 4.9.1.1.1 A - houten roostering sheddak.pdf
IfcElement - Tag: B1; Mark: B1
IfcRoot - Name: 40 x 230
Qto_BeamBaseQuantities - Length: 3340; CrossSectionArea: 0.0092; OuterSurfaceArea: 1.79232; GrossSurfaceArea: 1.81072; NetSurfaceArea: 1.81072; GrossVolume: 0.0305358; NetVolume: 0.0305358
Pset_BeamCommon - Reference: 40 x 230; Span: 3340 mm; Slope: 0 rad; Roll: 0 rad; IsExternal: no; LoadBearing: yes
Pset_ConcreteElementGeneral - ConstructionMethod: prefabricated
Pset_Condition - AssessmentCondition: Empty
Pset_EnvironmentalImpactIndicators - Reference: 40 x 230; sets with these values: 2

# IfcBeam: 28_SF_hout_rechthoekig_40 x 230_577, 28_SF_hout_rechthoekig:40 x 230:33592542
In: 010
PredefinedType: BEAM; Material: GVH_i2_naaldhout_generiek
Cpset_Beam - LevelOfAccuracy: in te vullen door Buildwise
IfcClassificationReference - TDS_link: .\05 As Builtdossier\2. Bouwkunde\2.2. Stabiliteit\2.2.0 technische fiche's\TF S 4.9.1.1.1 A - houten roostering sheddak.pdf
IfcElement - Tag: B1; Mark: B1
IfcRoot - Name: 40 x 230
Qto_BeamBaseQuantities - Length: 3340; CrossSectionArea: 0.0092; OuterSurfaceArea: 1.79232; GrossSurfaceArea: 1.81072; NetSurfaceArea: 1.81072; GrossVolume: 0.0305358; NetVolume: 0.0305358
Pset_BeamCommon - Reference: 40 x 230; Span: 3340 mm; Slope: 0 rad; Roll: 0 rad; IsExternal: no; LoadBearing: yes
Pset_ConcreteElementGeneral - ConstructionMethod: prefabricated
Pset_Condition - AssessmentCondition: Empty
Pset_EnvironmentalImpactIndicators - Reference: 40 x 230; sets with these values: 2

# IfcBeam: 28_SF_hout_rechthoekig_40 x 230_579, 28_SF_hout_rechthoekig:40 x 230:33592873
In: 010
PredefinedType: BEAM; Material: GVH_i2_naaldhout_generiek
Cpset_Beam - LevelOfAccuracy: in te vullen door Buildwise
IfcClassificationReference - TDS_link: .\05 As Builtdossier\2. Bouwkunde\2.2. Stabiliteit\2.2.0 technische fiche's\TF S 4.9.1.1.1 A - houten roostering sheddak.pdf
IfcElement - Tag: A2; Mark: A2
IfcRoot - Name: 40 x 230
Qto_BeamBaseQuantities - Length: 3340; CrossSectionArea: 0.0092; OuterSurfaceArea: 0.338451; GrossSurfaceArea: 0.356851; NetSurfaceArea: 0.356851; GrossVolume: 0.0057662; NetVolume: 0.0057662
Pset_BeamCommon - Reference: 40 x 230; Span: 3340 mm; Slope: 0 rad; Roll: 0 rad; IsExternal: no; LoadBearing: yes
Pset_ConcreteElementGeneral - ConstructionMethod: prefabricated
Pset_Condition - AssessmentCondition: Empty
Pset_EnvironmentalImpactIndicators - Reference: 40 x 230; sets with these values: 2

# IfcBeam: 28_SF_hout_rechthoekig_40 x 230_581, 28_SF_hout_rechthoekig:40 x 230:33592876
In: 010
PredefinedType: BEAM; Material: GVH_i2_naaldhout_generiek
Cpset_Beam - LevelOfAccuracy: in te vullen door Buildwise
IfcClassificationReference - TDS_link: .\05 As Builtdossier\2. Bouwkunde\2.2. Stabiliteit\2.2.0 technische fiche's\TF S 4.9.1.1.1 A - houten roostering sheddak.pdf
IfcElement - Tag: A3; Mark: A3
IfcRoot - Name: 40 x 230
Qto_BeamBaseQuantities - Length: 3340; CrossSectionArea: 0.0092; OuterSurfaceArea: 0.532433; GrossSurfaceArea: 0.550833; NetSurfaceArea: 0.550833; GrossVolume: 0.00907108; NetVolume: 0.00907108
Pset_BeamCommon - Reference: 40 x 230; Span: 3340 mm; Slope: 0 rad; Roll: 0 rad; IsExternal: no; LoadBearing: yes
Pset_ConcreteElementGeneral - ConstructionMethod: prefabricated
Pset_Condition - AssessmentCondition: Empty
Pset_EnvironmentalImpactIndicators - Reference: 40 x 230; sets with these values: 2

# IfcBeam: 28_SF_hout_rechthoekig_40 x 230_583, 28_SF_hout_rechthoekig:40 x 230:33592879
In: 010
PredefinedType: BEAM; Material: GVH_i2_naaldhout_generiek
Cpset_Beam - LevelOfAccuracy: in te vullen door Buildwise
IfcClassificationReference - TDS_link: .\05 As Builtdossier\2. Bouwkunde\2.2. Stabiliteit\2.2.0 technische fiche's\TF S 4.9.1.1.1 A - houten roostering sheddak.pdf
IfcElement - Tag: A4; Mark: A4
IfcRoot - Name: 40 x 230
Qto_BeamBaseQuantities - Length: 3340; CrossSectionArea: 0.0092; OuterSurfaceArea: 0.726414; GrossSurfaceArea: 0.744814; NetSurfaceArea: 0.744814; GrossVolume: 0.0123759; NetVolume: 0.0123759
Pset_BeamCommon - Reference: 40 x 230; Span: 3340 mm; Slope: 0 rad; Roll: 0 rad; IsExternal: no; LoadBearing: yes
Pset_ConcreteElementGeneral - ConstructionMethod: prefabricated
Pset_Condition - AssessmentCondition: Empty
Pset_EnvironmentalImpactIndicators - Reference: 40 x 230; sets with these values: 2

# IfcBeam: 28_SF_hout_rechthoekig_40 x 230_585, 28_SF_hout_rechthoekig:40 x 230:33592882
In: 010
PredefinedType: BEAM; Material: GVH_i2_naaldhout_generiek
Cpset_Beam - LevelOfAccuracy: in te vullen door Buildwise
IfcClassificationReference - TDS_link: .\05 As Builtdossier\2. Bouwkunde\2.2. Stabiliteit\2.2.0 technische fiche's\TF S 4.9.1.1.1 A - houten roostering sheddak.pdf
IfcElement - Tag: A5; Mark: A5
IfcRoot - Name: 40 x 230
Qto_BeamBaseQuantities - Length: 3340; CrossSectionArea: 0.0092; OuterSurfaceArea: 0.920396; GrossSurfaceArea: 0.938796; NetSurfaceArea: 0.938796; GrossVolume: 0.0156808; NetVolume: 0.0156808
Pset_BeamCommon - Reference: 40 x 230; Span: 3340 mm; Slope: 0 rad; Roll: 0 rad; IsExternal: no; LoadBearing: yes
Pset_ConcreteElementGeneral - ConstructionMethod: prefabricated
Pset_Condition - AssessmentCondition: Empty
Pset_EnvironmentalImpactIndicators - Reference: 40 x 230; sets with these values: 2

# IfcBeam: 28_SF_hout_rechthoekig_40 x 230_587, 28_SF_hout_rechthoekig:40 x 230:33592885
In: 010
PredefinedType: BEAM; Material: GVH_i2_naaldhout_generiek
Cpset_Beam - LevelOfAccuracy: in te vullen door Buildwise
IfcClassificationReference - TDS_link: .\05 As Builtdossier\2. Bouwkunde\2.2. Stabiliteit\2.2.0 technische fiche's\TF S 4.9.1.1.1 A - houten roostering sheddak.pdf
IfcElement - Tag: A6; Mark: A6
IfcRoot - Name: 40 x 230
Qto_BeamBaseQuantities - Length: 3340; CrossSectionArea: 0.0092; OuterSurfaceArea: 1.11438; GrossSurfaceArea: 1.13278; NetSurfaceArea: 1.13278; GrossVolume: 0.0189857; NetVolume: 0.0189857
Pset_BeamCommon - Reference: 40 x 230; Span: 3340 mm; Slope: 0 rad; Roll: 0 rad; IsExternal: no; LoadBearing: yes
Pset_ConcreteElementGeneral - ConstructionMethod: prefabricated
Pset_Condition - AssessmentCondition: Empty
Pset_EnvironmentalImpactIndicators - Reference: 40 x 230; sets with these values: 2

# IfcBeam: 28_SF_hout_rechthoekig_40 x 230_589, 28_SF_hout_rechthoekig:40 x 230:33592888
In: 010
PredefinedType: BEAM; Material: GVH_i2_naaldhout_generiek
Cpset_Beam - LevelOfAccuracy: in te vullen door Buildwise
IfcClassificationReference - TDS_link: .\05 As Builtdossier\2. Bouwkunde\2.2. Stabiliteit\2.2.0 technische fiche's\TF S 4.9.1.1.1 A - houten roostering sheddak.pdf
IfcElement - Tag: A7; Mark: A7
IfcRoot - Name: 40 x 230
Qto_BeamBaseQuantities - Length: 3340; CrossSectionArea: 0.0092; OuterSurfaceArea: 1.30836; GrossSurfaceArea: 1.32676; NetSurfaceArea: 1.32676; GrossVolume: 0.0222906; NetVolume: 0.0222906
Pset_BeamCommon - Reference: 40 x 230; Span: 3340 mm; Slope: 0 rad; Roll: 0 rad; IsExternal: no; LoadBearing: yes
Pset_ConcreteElementGeneral - ConstructionMethod: prefabricated
Pset_Condition - AssessmentCondition: Empty
Pset_EnvironmentalImpactIndicators - Reference: 40 x 230; sets with these values: 2

# IfcBeam: 28_SF_hout_rechthoekig_40 x 230_59, 28_SF_hout_rechthoekig:40 x 230:33579934
In: 010
PredefinedType: BEAM; Material: GVH_i2_naaldhout_generiek
Cpset_Beam - LevelOfAccuracy: in te vullen door Buildwise
IfcClassificationReference - TDS_link: .\05 As Builtdossier\2. Bouwkunde\2.2. Stabiliteit\2.2.0 technische fiche's\TF S 4.9.1.1.1 A - houten roostering sheddak.pdf
IfcElement - Tag: B1; Mark: B1
IfcRoot - Name: 40 x 230
Qto_BeamBaseQuantities - Length: 3341; CrossSectionArea: 0.0092; OuterSurfaceArea: 1.79133; GrossSurfaceArea: 1.80973; NetSurfaceArea: 1.80973; GrossVolume: 0.030519; NetVolume: 0.030519
Pset_BeamCommon - Reference: 40 x 230; Span: 3341 mm; Slope: 0 rad; Roll: 0 rad; IsExternal: no; LoadBearing: yes
Pset_ConcreteElementGeneral - ConstructionMethod: prefabricated
Pset_Condition - AssessmentCondition: Empty
Pset_EnvironmentalImpactIndicators - Reference: 40 x 230; sets with these values: 2

# IfcBeam: 28_SF_hout_rechthoekig_40 x 230_591, 28_SF_hout_rechthoekig:40 x 230:33592891
In: 010
PredefinedType: BEAM; Material: GVH_i2_naaldhout_generiek
Cpset_Beam - LevelOfAccuracy: in te vullen door Buildwise
IfcClassificationReference - TDS_link: .\05 As Builtdossier\2. Bouwkunde\2.2. Stabiliteit\2.2.0 technische fiche's\TF S 4.9.1.1.1 A - houten roostering sheddak.pdf
IfcElement - Tag: A8; Mark: A8
IfcRoot - Name: 40 x 230
Qto_BeamBaseQuantities - Length: 3340; CrossSectionArea: 0.0092; OuterSurfaceArea: 1.50234; GrossSurfaceArea: 1.52074; NetSurfaceArea: 1.52074; GrossVolume: 0.0255954; NetVolume: 0.0255954
Pset_BeamCommon - Reference: 40 x 230; Span: 3340 mm; Slope: 0 rad; Roll: 0 rad; IsExternal: no; LoadBearing: yes
Pset_ConcreteElementGeneral - ConstructionMethod: prefabricated
Pset_Condition - AssessmentCondition: Empty
Pset_EnvironmentalImpactIndicators - Reference: 40 x 230; sets with these values: 2

# IfcBeam: 28_SF_hout_rechthoekig_40 x 230_593, 28_SF_hout_rechthoekig:40 x 230:33592894
In: 010
PredefinedType: BEAM; Material: GVH_i2_naaldhout_generiek
Cpset_Beam - LevelOfAccuracy: in te vullen door Buildwise
IfcClassificationReference - TDS_link: .\05 As Builtdossier\2. Bouwkunde\2.2. Stabiliteit\2.2.0 technische fiche's\TF S 4.9.1.1.1 A - houten roostering sheddak.pdf
IfcElement - Tag: A9; Mark: A9
IfcRoot - Name: 40 x 230
Qto_BeamBaseQuantities - Length: 3340; CrossSectionArea: 0.0092; OuterSurfaceArea: 1.69632; GrossSurfaceArea: 1.71472; NetSurfaceArea: 1.71472; GrossVolume: 0.0289003; NetVolume: 0.0289003
Pset_BeamCommon - Reference: 40 x 230; Span: 3340 mm; Slope: 0 rad; Roll: 0 rad; IsExternal: no; LoadBearing: yes
Pset_ConcreteElementGeneral - ConstructionMethod: prefabricated
Pset_Condition - AssessmentCondition: Empty
Pset_EnvironmentalImpactIndicators - Reference: 40 x 230; sets with these values: 2

# IfcBeam: 28_SF_hout_rechthoekig_40 x 230_595, 28_SF_hout_rechthoekig:40 x 230:33592897
In: 010
PredefinedType: BEAM; Material: GVH_i2_naaldhout_generiek
Cpset_Beam - LevelOfAccuracy: in te vullen door Buildwise
IfcClassificationReference - TDS_link: .\05 As Builtdossier\2. Bouwkunde\2.2. Stabiliteit\2.2.0 technische fiche's\TF S 4.9.1.1.1 A - houten roostering sheddak.pdf
IfcElement - Tag: H3; Mark: H3
IfcRoot - Name: 40 x 230
Qto_BeamBaseQuantities - Length: 3340; CrossSectionArea: 0.0092; OuterSurfaceArea: 1.8903; GrossSurfaceArea: 1.9087; NetSurfaceArea: 1.9087; GrossVolume: 0.0322052; NetVolume: 0.0322052
Pset_BeamCommon - Reference: 40 x 230; Span: 3340 mm; Slope: 0 rad; Roll: 0 rad; IsExternal: no; LoadBearing: yes
Pset_ConcreteElementGeneral - ConstructionMethod: prefabricated
Pset_Condition - AssessmentCondition: Empty
Pset_EnvironmentalImpactIndicators - Reference: 40 x 230; sets with these values: 2

# IfcBeam: 28_SF_hout_rechthoekig_40 x 230_597, 28_SF_hout_rechthoekig:40 x 230:33592900
In: 010
PredefinedType: BEAM; Material: GVH_i2_naaldhout_generiek
Cpset_Beam - LevelOfAccuracy: in te vullen door Buildwise
IfcClassificationReference - TDS_link: .\05 As Builtdossier\2. Bouwkunde\2.2. Stabiliteit\2.2.0 technische fiche's\TF S 4.9.1.1.1 A - houten roostering sheddak.pdf
IfcElement - Tag: F1; Mark: F1
IfcRoot - Name: 40 x 230
Qto_BeamBaseQuantities - Length: 3340; CrossSectionArea: 0.0092; OuterSurfaceArea: 2.08429; GrossSurfaceArea: 2.10269; NetSurfaceArea: 2.10269; GrossVolume: 0.0355101; NetVolume: 0.0355101
Pset_BeamCommon - Reference: 40 x 230; Span: 3340 mm; Slope: 0 rad; Roll: 0 rad; IsExternal: no; LoadBearing: yes
Pset_ConcreteElementGeneral - ConstructionMethod: prefabricated
Pset_Condition - AssessmentCondition: Empty
Pset_EnvironmentalImpactIndicators - Reference: 40 x 230; sets with these values: 2

# IfcBeam: 28_SF_hout_rechthoekig_40 x 230_599, 28_SF_hout_rechthoekig:40 x 230:33593401
In: 010
PredefinedType: BEAM; Material: GVH_i2_naaldhout_generiek
Cpset_Beam - LevelOfAccuracy: in te vullen door Buildwise
IfcClassificationReference - TDS_link: .\05 As Builtdossier\2. Bouwkunde\2.2. Stabiliteit\2.2.0 technische fiche's\TF S 4.9.1.1.1 A - houten roostering sheddak.pdf
IfcElement - Tag: D1; Mark: D1
IfcRoot - Name: 40 x 230
Qto_BeamBaseQuantities - Length: 3534.56; CrossSectionArea: 0.0092; OuterSurfaceArea: 1.99268; GrossSurfaceArea: 2.01108; NetSurfaceArea: 2.01108; GrossVolume: 0.0339493; NetVolume: 0.0339493
Pset_BeamCommon - Reference: 40 x 230; Span: 3534.56 mm; Slope: 0 rad; Roll: 0 rad; IsExternal: no; LoadBearing: yes
Pset_ConcreteElementGeneral - ConstructionMethod: prefabricated
Pset_Condition - AssessmentCondition: Empty
Pset_EnvironmentalImpactIndicators - Reference: 40 x 230; sets with these values: 2

# IfcBeam: 28_SF_hout_rechthoekig_40 x 230_601, 28_SF_hout_rechthoekig:40 x 230:33593697
In: 010
PredefinedType: BEAM; Material: GVH_i2_naaldhout_generiek
Cpset_Beam - LevelOfAccuracy: in te vullen door Buildwise
IfcClassificationReference - TDS_link: .\05 As Builtdossier\2. Bouwkunde\2.2. Stabiliteit\2.2.0 technische fiche's\TF S 4.9.1.1.1 A - houten roostering sheddak.pdf
IfcElement - Tag: D1; Mark: D1
IfcRoot - Name: 40 x 230
Qto_BeamBaseQuantities - Length: 3534.56; CrossSectionArea: 0.0092; OuterSurfaceArea: 1.99268; GrossSurfaceArea: 2.01108; NetSurfaceArea: 2.01108; GrossVolume: 0.0339493; NetVolume: 0.0339493
Pset_BeamCommon - Reference: 40 x 230; Span: 3534.56 mm; Slope: 0 rad; Roll: 0 rad; IsExternal: no; LoadBearing: yes
Pset_ConcreteElementGeneral - ConstructionMethod: prefabricated
Pset_Condition - AssessmentCondition: Empty
Pset_EnvironmentalImpactIndicators - Reference: 40 x 230; sets with these values: 2

# IfcBeam: 28_SF_hout_rechthoekig_40 x 230_603, 28_SF_hout_rechthoekig:40 x 230:33593767
In: 010
PredefinedType: BEAM; Material: GVH_i2_naaldhout_generiek
Cpset_Beam - LevelOfAccuracy: in te vullen door Buildwise
IfcClassificationReference - TDS_link: .\05 As Builtdossier\2. Bouwkunde\2.2. Stabiliteit\2.2.0 technische fiche's\TF S 4.9.1.1.1 A - houten roostering sheddak.pdf
IfcElement - Tag: D1; Mark: D1
IfcRoot - Name: 40 x 230
Qto_BeamBaseQuantities - Length: 3534.56; CrossSectionArea: 0.0092; OuterSurfaceArea: 1.99268; GrossSurfaceArea: 2.01108; NetSurfaceArea: 2.01108; GrossVolume: 0.0339493; NetVolume: 0.0339493
Pset_BeamCommon - Reference: 40 x 230; Span: 3534.56 mm; Slope: 0 rad; Roll: 0 rad; IsExternal: no; LoadBearing: yes
Pset_ConcreteElementGeneral - ConstructionMethod: prefabricated
Pset_Condition - AssessmentCondition: Empty
Pset_EnvironmentalImpactIndicators - Reference: 40 x 230; sets with these values: 2

# IfcBeam: 28_SF_hout_rechthoekig_40 x 230_605, 28_SF_hout_rechthoekig:40 x 230:33593770
In: 010
PredefinedType: BEAM; Material: GVH_i2_naaldhout_generiek
Cpset_Beam - LevelOfAccuracy: in te vullen door Buildwise
IfcClassificationReference - TDS_link: .\05 As Builtdossier\2. Bouwkunde\2.2. Stabiliteit\2.2.0 technische fiche's\TF S 4.9.1.1.1 A - houten roostering sheddak.pdf
IfcElement - Tag: D1; Mark: D1
IfcRoot - Name: 40 x 230
Qto_BeamBaseQuantities - Length: 3534.56; CrossSectionArea: 0.0092; OuterSurfaceArea: 1.99268; GrossSurfaceArea: 2.01108; NetSurfaceArea: 2.01108; GrossVolume: 0.0339493; NetVolume: 0.0339493
Pset_BeamCommon - Reference: 40 x 230; Span: 3534.56 mm; Slope: 0 rad; Roll: 0 rad; IsExternal: no; LoadBearing: yes
Pset_ConcreteElementGeneral - ConstructionMethod: prefabricated
Pset_Condition - AssessmentCondition: Empty
Pset_EnvironmentalImpactIndicators - Reference: 40 x 230; sets with these values: 2

# IfcBeam: 28_SF_hout_rechthoekig_40 x 230_607, 28_SF_hout_rechthoekig:40 x 230:33593773
In: 010
PredefinedType: BEAM; Material: GVH_i2_naaldhout_generiek
Cpset_Beam - LevelOfAccuracy: in te vullen door Buildwise
IfcClassificationReference - TDS_link: .\05 As Builtdossier\2. Bouwkunde\2.2. Stabiliteit\2.2.0 technische fiche's\TF S 4.9.1.1.1 A - houten roostering sheddak.pdf
IfcElement - Tag: D1; Mark: D1
IfcRoot - Name: 40 x 230
Qto_BeamBaseQuantities - Length: 3534.56; CrossSectionArea: 0.0092; OuterSurfaceArea: 1.99268; GrossSurfaceArea: 2.01108; NetSurfaceArea: 2.01108; GrossVolume: 0.0339493; NetVolume: 0.0339493
Pset_BeamCommon - Reference: 40 x 230; Span: 3534.56 mm; Slope: 0 rad; Roll: 0 rad; IsExternal: no; LoadBearing: yes
Pset_ConcreteElementGeneral - ConstructionMethod: prefabricated
Pset_Condition - AssessmentCondition: Empty
Pset_EnvironmentalImpactIndicators - Reference: 40 x 230; sets with these values: 2

# IfcBeam: 28_SF_hout_rechthoekig_40 x 230_609, 28_SF_hout_rechthoekig:40 x 230:33593776
In: 010
PredefinedType: BEAM; Material: GVH_i2_naaldhout_generiek
Cpset_Beam - LevelOfAccuracy: in te vullen door Buildwise
IfcClassificationReference - TDS_link: .\05 As Builtdossier\2. Bouwkunde\2.2. Stabiliteit\2.2.0 technische fiche's\TF S 4.9.1.1.1 A - houten roostering sheddak.pdf
IfcElement - Tag: D1; Mark: D1
IfcRoot - Name: 40 x 230
Qto_BeamBaseQuantities - Length: 3534.56; CrossSectionArea: 0.0092; OuterSurfaceArea: 1.99268; GrossSurfaceArea: 2.01108; NetSurfaceArea: 2.01108; GrossVolume: 0.0339493; NetVolume: 0.0339493
Pset_BeamCommon - Reference: 40 x 230; Span: 3534.56 mm; Slope: 0 rad; Roll: 0 rad; IsExternal: no; LoadBearing: yes
Pset_ConcreteElementGeneral - ConstructionMethod: prefabricated
Pset_Condition - AssessmentCondition: Empty
Pset_EnvironmentalImpactIndicators - Reference: 40 x 230; sets with these values: 2

# IfcBeam: 28_SF_hout_rechthoekig_40 x 230_61, 28_SF_hout_rechthoekig:40 x 230:33579936
In: 010
PredefinedType: BEAM; Material: GVH_i2_naaldhout_generiek
Cpset_Beam - LevelOfAccuracy: in te vullen door Buildwise
IfcClassificationReference - TDS_link: .\05 As Builtdossier\2. Bouwkunde\2.2. Stabiliteit\2.2.0 technische fiche's\TF S 4.9.1.1.1 A - houten roostering sheddak.pdf
IfcElement - Tag: B1; Mark: B1
IfcRoot - Name: 40 x 230
Qto_BeamBaseQuantities - Length: 3340; CrossSectionArea: 0.0092; OuterSurfaceArea: 1.79133; GrossSurfaceArea: 1.80973; NetSurfaceArea: 1.80973; GrossVolume: 0.030519; NetVolume: 0.030519
Pset_BeamCommon - Reference: 40 x 230; Span: 3340 mm; Slope: 0 rad; Roll: 0 rad; IsExternal: no; LoadBearing: yes
Pset_ConcreteElementGeneral - ConstructionMethod: prefabricated
Pset_Condition - AssessmentCondition: Empty
Pset_EnvironmentalImpactIndicators - Reference: 40 x 230; sets with these values: 2

# IfcBeam: 28_SF_hout_rechthoekig_40 x 230_611, 28_SF_hout_rechthoekig:40 x 230:33593779
In: 010
PredefinedType: BEAM; Material: GVH_i2_naaldhout_generiek
Cpset_Beam - LevelOfAccuracy: in te vullen door Buildwise
IfcClassificationReference - TDS_link: .\05 As Builtdossier\2. Bouwkunde\2.2. Stabiliteit\2.2.0 technische fiche's\TF S 4.9.1.1.1 A - houten roostering sheddak.pdf
IfcElement - Tag: D1; Mark: D1
IfcRoot - Name: 40 x 230
Qto_BeamBaseQuantities - Length: 3534.56; CrossSectionArea: 0.0092; OuterSurfaceArea: 1.99268; GrossSurfaceArea: 2.01108; NetSurfaceArea: 2.01108; GrossVolume: 0.0339493; NetVolume: 0.0339493
Pset_BeamCommon - Reference: 40 x 230; Span: 3534.56 mm; Slope: 0 rad; Roll: 0 rad; IsExternal: no; LoadBearing: yes
Pset_ConcreteElementGeneral - ConstructionMethod: prefabricated
Pset_Condition - AssessmentCondition: Empty
Pset_EnvironmentalImpactIndicators - Reference: 40 x 230; sets with these values: 2

# IfcBeam: 28_SF_hout_rechthoekig_40 x 230_613, 28_SF_hout_rechthoekig:40 x 230:33593782
In: 010
PredefinedType: BEAM; Material: GVH_i2_naaldhout_generiek
Cpset_Beam - LevelOfAccuracy: in te vullen door Buildwise
IfcClassificationReference - TDS_link: .\05 As Builtdossier\2. Bouwkunde\2.2. Stabiliteit\2.2.0 technische fiche's\TF S 4.9.1.1.1 A - houten roostering sheddak.pdf
IfcElement - Tag: D1; Mark: D1
IfcRoot - Name: 40 x 230
Qto_BeamBaseQuantities - Length: 3534.56; CrossSectionArea: 0.0092; OuterSurfaceArea: 1.99268; GrossSurfaceArea: 2.01108; NetSurfaceArea: 2.01108; GrossVolume: 0.0339493; NetVolume: 0.0339493
Pset_BeamCommon - Reference: 40 x 230; Span: 3534.56 mm; Slope: 0 rad; Roll: 0 rad; IsExternal: no; LoadBearing: yes
Pset_ConcreteElementGeneral - ConstructionMethod: prefabricated
Pset_Condition - AssessmentCondition: Empty
Pset_EnvironmentalImpactIndicators - Reference: 40 x 230; sets with these values: 2

# IfcBeam: 28_SF_hout_rechthoekig_40 x 230_615, 28_SF_hout_rechthoekig:40 x 230:33593785
In: 010
PredefinedType: BEAM; Material: GVH_i2_naaldhout_generiek
Cpset_Beam - LevelOfAccuracy: in te vullen door Buildwise
IfcClassificationReference - TDS_link: .\05 As Builtdossier\2. Bouwkunde\2.2. Stabiliteit\2.2.0 technische fiche's\TF S 4.9.1.1.1 A - houten roostering sheddak.pdf
IfcElement - Tag: D1; Mark: D1
IfcRoot - Name: 40 x 230
Qto_BeamBaseQuantities - Length: 3534.56; CrossSectionArea: 0.0092; OuterSurfaceArea: 1.99268; GrossSurfaceArea: 2.01108; NetSurfaceArea: 2.01108; GrossVolume: 0.0339493; NetVolume: 0.0339493
Pset_BeamCommon - Reference: 40 x 230; Span: 3534.56 mm; Slope: 0 rad; Roll: 0 rad; IsExternal: no; LoadBearing: yes
Pset_ConcreteElementGeneral - ConstructionMethod: prefabricated
Pset_Condition - AssessmentCondition: Empty
Pset_EnvironmentalImpactIndicators - Reference: 40 x 230; sets with these values: 2

# IfcBeam: 28_SF_hout_rechthoekig_40 x 230_617, 28_SF_hout_rechthoekig:40 x 230:33593788
In: 010
PredefinedType: BEAM; Material: GVH_i2_naaldhout_generiek
Cpset_Beam - LevelOfAccuracy: in te vullen door Buildwise
IfcClassificationReference - TDS_link: .\05 As Builtdossier\2. Bouwkunde\2.2. Stabiliteit\2.2.0 technische fiche's\TF S 4.9.1.1.1 A - houten roostering sheddak.pdf
IfcElement - Tag: D1; Mark: D1
IfcRoot - Name: 40 x 230
Qto_BeamBaseQuantities - Length: 3561.5; CrossSectionArea: 0.0092; OuterSurfaceArea: 1.99267; GrossSurfaceArea: 2.01107; NetSurfaceArea: 2.01107; GrossVolume: 0.0339493; NetVolume: 0.0339493
Pset_BeamCommon - Reference: 40 x 230; Span: 3561.5 mm; Slope: 0 rad; Roll: 0 rad; IsExternal: no; LoadBearing: yes
Pset_ConcreteElementGeneral - ConstructionMethod: prefabricated
Pset_Condition - AssessmentCondition: Empty
Pset_EnvironmentalImpactIndicators - Reference: 40 x 230; sets with these values: 2

# IfcBeam: 28_SF_hout_rechthoekig_40 x 230_619, 28_SF_hout_rechthoekig:40 x 230:33593791
In: 010
PredefinedType: BEAM; Material: GVH_i2_naaldhout_generiek
Cpset_Beam - LevelOfAccuracy: in te vullen door Buildwise
IfcClassificationReference - TDS_link: .\05 As Builtdossier\2. Bouwkunde\2.2. Stabiliteit\2.2.0 technische fiche's\TF S 4.9.1.1.1 A - houten roostering sheddak.pdf
IfcElement - Tag: D1; Mark: D1
IfcRoot - Name: 40 x 230
Qto_BeamBaseQuantities - Length: 3534.56; CrossSectionArea: 0.0092; OuterSurfaceArea: 1.99267; GrossSurfaceArea: 2.01107; NetSurfaceArea: 2.01107; GrossVolume: 0.0339493; NetVolume: 0.0339493
Pset_BeamCommon - Reference: 40 x 230; Span: 3534.56 mm; Slope: 0 rad; Roll: 0 rad; IsExternal: no; LoadBearing: yes
Pset_ConcreteElementGeneral - ConstructionMethod: prefabricated
Pset_Condition - AssessmentCondition: Empty
Pset_EnvironmentalImpactIndicators - Reference: 40 x 230; sets with these values: 2

# IfcBeam: 28_SF_hout_rechthoekig_40 x 230_621 (10)
In: 010
PredefinedType: BEAM; Material: GVH_i2_naaldhout_generiek
Cpset_Beam - LevelOfAccuracy: in te vullen door Buildwise
IfcClassificationReference - TDS_link: .\05 As Builtdossier\2. Bouwkunde\2.2. Stabiliteit\2.2.0 technische fiche's\TF S 4.9.1.1.1 A - houten roostering sheddak.pdf
IfcElement - Tag: D1; Mark: D1
IfcRoot - Name: 40 x 230
Qto_BeamBaseQuantities - Length: 3534.56; CrossSectionArea: 0.0092; OuterSurfaceArea: 1.9926; GrossSurfaceArea: 2.011; NetSurfaceArea: 2.011; GrossVolume: 0.033948; NetVolume: 0.033948
Pset_BeamCommon - Reference: 40 x 230; Span: 3534.56 mm; Slope: 0 rad; Roll: 0 rad; IsExternal: no; LoadBearing: yes
Pset_ConcreteElementGeneral - ConstructionMethod: prefabricated
Pset_Condition - AssessmentCondition: Empty
Pset_EnvironmentalImpactIndicators - Reference: 40 x 230; sets with these values: 2
Name (28_SF_hout_rechthoekig:40 x 230:...)
33593975
33593978
33593985
33593988
33593991
33593994
33593997
33594003
33594006
33594009

# IfcBeam: 28_SF_hout_rechthoekig_40 x 230_623, 28_SF_hout_rechthoekig:40 x 230:33594000
In: 010
PredefinedType: BEAM; Material: GVH_i2_naaldhout_generiek
Cpset_Beam - LevelOfAccuracy: in te vullen door Buildwise
IfcClassificationReference - TDS_link: .\05 As Builtdossier\2. Bouwkunde\2.2. Stabiliteit\2.2.0 technische fiche's\TF S 4.9.1.1.1 A - houten roostering sheddak.pdf
IfcElement - Tag: D1; Mark: D1
IfcRoot - Name: 40 x 230
Qto_BeamBaseQuantities - Length: 3505; CrossSectionArea: 0.997001; NetSurfaceArea: 1.994; NetVolume: 0.033608
Pset_BeamCommon - Reference: 40 x 230; Span: 3505 mm; Slope: 0 rad; Roll: 0 rad; IsExternal: no; LoadBearing: yes
Pset_ConcreteElementGeneral - ConstructionMethod: prefabricated
Pset_Condition - AssessmentCondition: Empty
Pset_EnvironmentalImpactIndicators - Reference: 40 x 230; sets with these values: 2

# IfcBeam: 28_SF_hout_rechthoekig_40 x 230_625, 28_SF_hout_rechthoekig:40 x 230:33594034
In: 010
PredefinedType: BEAM; Material: GVH_i2_naaldhout_generiek
Cpset_Beam - LevelOfAccuracy: in te vullen door Buildwise
IfcClassificationReference - TDS_link: .\05 As Builtdossier\2. Bouwkunde\2.2. Stabiliteit\2.2.0 technische fiche's\TF S 4.9.1.1.1 A - houten roostering sheddak.pdf
IfcElement - Tag: D1; Mark: D1
IfcRoot - Name: 40 x 230
Qto_BeamBaseQuantities - Length: 3534.56; CrossSectionArea: 0.0092; OuterSurfaceArea: 1.9926; GrossSurfaceArea: 2.011; NetSurfaceArea: 2.011; GrossVolume: 0.033948; NetVolume: 0.033948
Pset_BeamCommon - Reference: 40 x 230; Span: 3534.56 mm; Slope: 0 rad; Roll: 0 rad; IsExternal: no; LoadBearing: yes
Pset_ConcreteElementGeneral - ConstructionMethod: prefabricated
Pset_Condition - AssessmentCondition: Empty
Pset_EnvironmentalImpactIndicators - Reference: 40 x 230; sets with these values: 2

# IfcBeam: 28_SF_hout_rechthoekig_40 x 230_627, 28_SF_hout_rechthoekig:40 x 230:33594037
In: 010
PredefinedType: BEAM; Material: GVH_i2_naaldhout_generiek
Cpset_Beam - LevelOfAccuracy: in te vullen door Buildwise
IfcClassificationReference - TDS_link: .\05 As Builtdossier\2. Bouwkunde\2.2. Stabiliteit\2.2.0 technische fiche's\TF S 4.9.1.1.1 A - houten roostering sheddak.pdf
IfcElement - Tag: D1; Mark: D1
IfcRoot - Name: 40 x 230
Qto_BeamBaseQuantities - Length: 3534.56; CrossSectionArea: 0.0092; OuterSurfaceArea: 1.9926; GrossSurfaceArea: 2.011; NetSurfaceArea: 2.011; GrossVolume: 0.033948; NetVolume: 0.033948
Pset_BeamCommon - Reference: 40 x 230; Span: 3534.56 mm; Slope: 0 rad; Roll: 0 rad; IsExternal: no; LoadBearing: yes
Pset_ConcreteElementGeneral - ConstructionMethod: prefabricated
Pset_Condition - AssessmentCondition: Empty
Pset_EnvironmentalImpactIndicators - Reference: 40 x 230; sets with these values: 2

# IfcBeam: 28_SF_hout_rechthoekig_40 x 230_629, 28_SF_hout_rechthoekig:40 x 230:33594044
In: 010
PredefinedType: BEAM; Material: GVH_i2_naaldhout_generiek
Cpset_Beam - LevelOfAccuracy: in te vullen door Buildwise
IfcClassificationReference - TDS_link: .\05 As Builtdossier\2. Bouwkunde\2.2. Stabiliteit\2.2.0 technische fiche's\TF S 4.9.1.1.1 A - houten roostering sheddak.pdf
IfcElement - Tag: D1; Mark: D1
IfcRoot - Name: 40 x 230
Qto_BeamBaseQuantities - Length: 3534.56; CrossSectionArea: 0.0092; OuterSurfaceArea: 1.9926; GrossSurfaceArea: 2.011; NetSurfaceArea: 2.011; GrossVolume: 0.033948; NetVolume: 0.033948
Pset_BeamCommon - Reference: 40 x 230; Span: 3534.56 mm; Slope: 0 rad; Roll: 0 rad; IsExternal: no; LoadBearing: yes
Pset_ConcreteElementGeneral - ConstructionMethod: prefabricated
Pset_Condition - AssessmentCondition: Empty
Pset_EnvironmentalImpactIndicators - Reference: 40 x 230; sets with these values: 2

# IfcBeam: 28_SF_hout_rechthoekig_40 x 230_63, 28_SF_hout_rechthoekig:40 x 230:33579938
In: 010
PredefinedType: BEAM; Material: GVH_i2_naaldhout_generiek
Cpset_Beam - LevelOfAccuracy: in te vullen door Buildwise
IfcClassificationReference - TDS_link: .\05 As Builtdossier\2. Bouwkunde\2.2. Stabiliteit\2.2.0 technische fiche's\TF S 4.9.1.1.1 A - houten roostering sheddak.pdf
IfcElement - Tag: B1; Mark: B1
IfcRoot - Name: 40 x 230
Qto_BeamBaseQuantities - Length: 3334.78; CrossSectionArea: 0.0092; OuterSurfaceArea: 1.79133; GrossSurfaceArea: 1.80973; NetSurfaceArea: 1.80973; GrossVolume: 0.030519; NetVolume: 0.030519
Pset_BeamCommon - Reference: 40 x 230; Span: 3334.78 mm; Slope: 0 rad; Roll: 0 rad; IsExternal: no; LoadBearing: yes
Pset_ConcreteElementGeneral - ConstructionMethod: prefabricated
Pset_Condition - AssessmentCondition: Empty
Pset_EnvironmentalImpactIndicators - Reference: 40 x 230; sets with these values: 2

# IfcBeam: 28_SF_hout_rechthoekig_40 x 230_631, 28_SF_hout_rechthoekig:40 x 230:33594047
In: 010
PredefinedType: BEAM; Material: GVH_i2_naaldhout_generiek
Cpset_Beam - LevelOfAccuracy: in te vullen door Buildwise
IfcClassificationReference - TDS_link: .\05 As Builtdossier\2. Bouwkunde\2.2. Stabiliteit\2.2.0 technische fiche's\TF S 4.9.1.1.1 A - houten roostering sheddak.pdf
IfcElement - Tag: D1; Mark: D1
IfcRoot - Name: 40 x 230
Qto_BeamBaseQuantities - Length: 3534.56; CrossSectionArea: 0.0092; OuterSurfaceArea: 1.9926; GrossSurfaceArea: 2.011; NetSurfaceArea: 2.011; GrossVolume: 0.033948; NetVolume: 0.033948
Pset_BeamCommon - Reference: 40 x 230; Span: 3534.56 mm; Slope: 0 rad; Roll: 0 rad; IsExternal: no; LoadBearing: yes
Pset_ConcreteElementGeneral - ConstructionMethod: prefabricated
Pset_Condition - AssessmentCondition: Empty
Pset_EnvironmentalImpactIndicators - Reference: 40 x 230; sets with these values: 2

# IfcBeam: 28_SF_hout_rechthoekig_40 x 230_633, 28_SF_hout_rechthoekig:40 x 230:33594050
In: 010
PredefinedType: BEAM; Material: GVH_i2_naaldhout_generiek
Cpset_Beam - LevelOfAccuracy: in te vullen door Buildwise
IfcClassificationReference - TDS_link: .\05 As Builtdossier\2. Bouwkunde\2.2. Stabiliteit\2.2.0 technische fiche's\TF S 4.9.1.1.1 A - houten roostering sheddak.pdf
IfcElement - Tag: D1; Mark: D1
IfcRoot - Name: 40 x 230
Qto_BeamBaseQuantities - Length: 3534.56; CrossSectionArea: 0.0092; OuterSurfaceArea: 1.9926; GrossSurfaceArea: 2.011; NetSurfaceArea: 2.011; GrossVolume: 0.033948; NetVolume: 0.033948
Pset_BeamCommon - Reference: 40 x 230; Span: 3534.56 mm; Slope: 0 rad; Roll: 0 rad; IsExternal: no; LoadBearing: yes
Pset_ConcreteElementGeneral - ConstructionMethod: prefabricated
Pset_Condition - AssessmentCondition: Empty
Pset_EnvironmentalImpactIndicators - Reference: 40 x 230; sets with these values: 2

# IfcBeam: 28_SF_hout_rechthoekig_40 x 230_635, 28_SF_hout_rechthoekig:40 x 230:33594053
In: 010
PredefinedType: BEAM; Material: GVH_i2_naaldhout_generiek
Cpset_Beam - LevelOfAccuracy: in te vullen door Buildwise
IfcClassificationReference - TDS_link: .\05 As Builtdossier\2. Bouwkunde\2.2. Stabiliteit\2.2.0 technische fiche's\TF S 4.9.1.1.1 A - houten roostering sheddak.pdf
IfcElement - Tag: D1; Mark: D1
IfcRoot - Name: 40 x 230
Qto_BeamBaseQuantities - Length: 3534.56; CrossSectionArea: 0.0092; OuterSurfaceArea: 1.9926; GrossSurfaceArea: 2.011; NetSurfaceArea: 2.011; GrossVolume: 0.033948; NetVolume: 0.033948
Pset_BeamCommon - Reference: 40 x 230; Span: 3534.56 mm; Slope: 0 rad; Roll: 0 rad; IsExternal: no; LoadBearing: yes
Pset_ConcreteElementGeneral - ConstructionMethod: prefabricated
Pset_Condition - AssessmentCondition: Empty
Pset_EnvironmentalImpactIndicators - Reference: 40 x 230; sets with these values: 2

# IfcBeam: 28_SF_hout_rechthoekig_40 x 230_637, 28_SF_hout_rechthoekig:40 x 230:33594056
In: 010
PredefinedType: BEAM; Material: GVH_i2_naaldhout_generiek
Cpset_Beam - LevelOfAccuracy: in te vullen door Buildwise
IfcClassificationReference - TDS_link: .\05 As Builtdossier\2. Bouwkunde\2.2. Stabiliteit\2.2.0 technische fiche's\TF S 4.9.1.1.1 A - houten roostering sheddak.pdf
IfcElement - Tag: D1; Mark: D1
IfcRoot - Name: 40 x 230
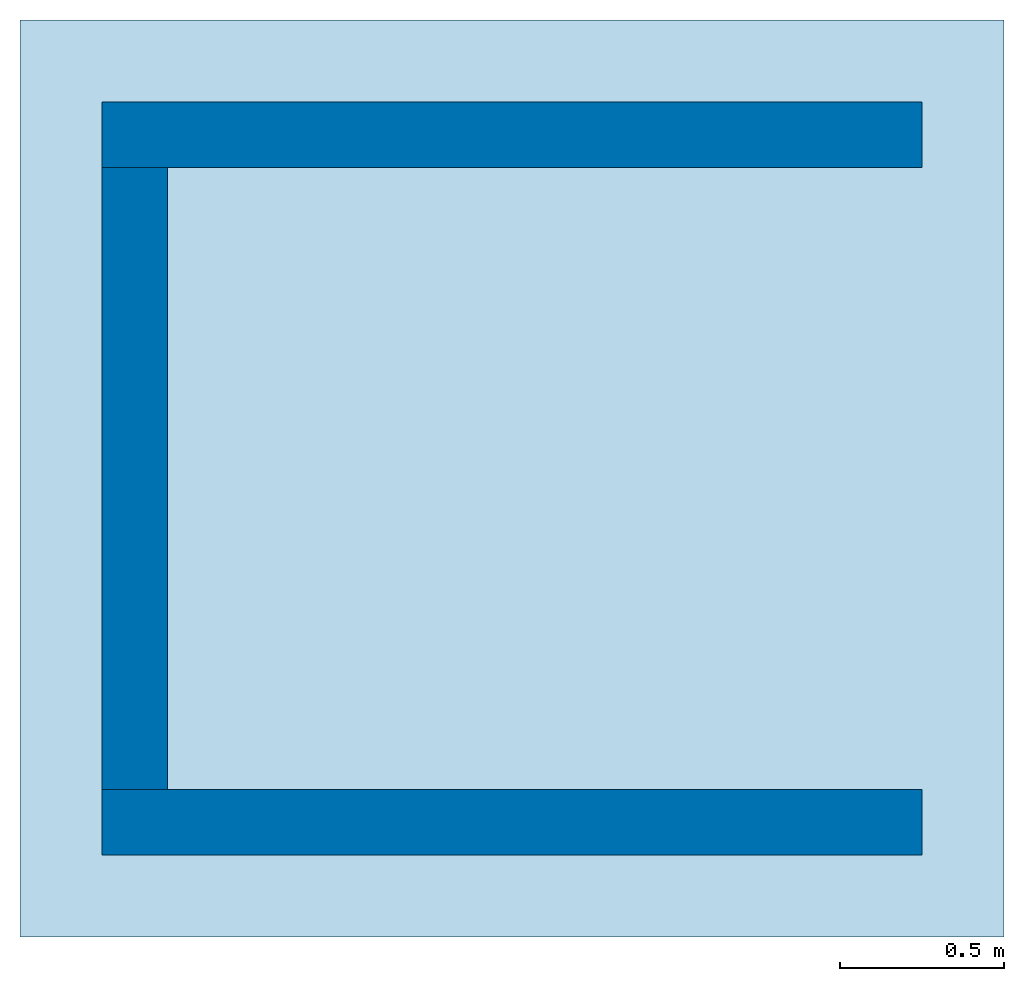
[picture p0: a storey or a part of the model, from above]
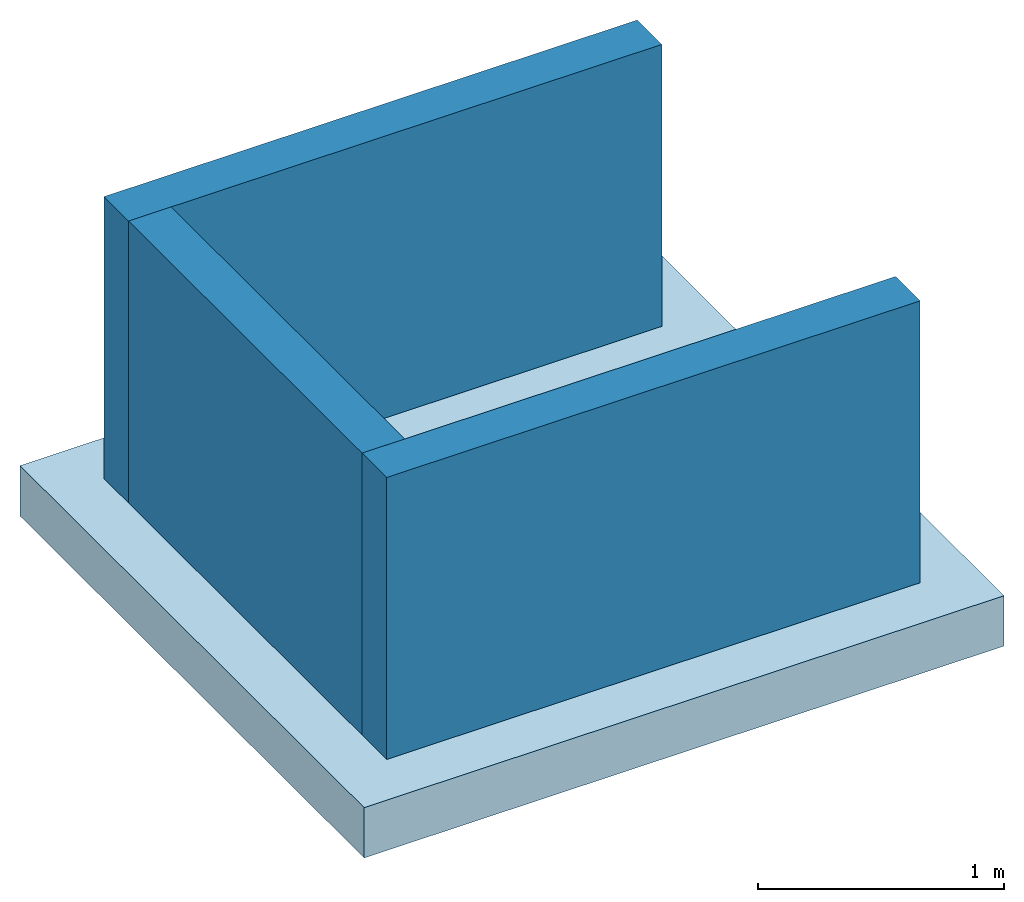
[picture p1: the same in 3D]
Properties of the parts of a building model (IFC4X3_ADD2), part 6 of 28

# IfcBeam: 28_SF_hout_rechthoekig_40 x 230_637, 28_SF_hout_rechthoekig:40 x 230:33594056
Qto_BeamBaseQuantities - Length: 3534.56; CrossSectionArea: 0.0092; OuterSurfaceArea: 1.9926; GrossSurfaceArea: 2.011; NetSurfaceArea: 2.011; GrossVolume: 0.033948; NetVolume: 0.033948
Pset_BeamCommon - Reference: 40 x 230; Span: 3534.56 mm; Slope: 0 rad; Roll: 0 rad; IsExternal: no; LoadBearing: yes
Pset_ConcreteElementGeneral - ConstructionMethod: prefabricated
Pset_Condition - AssessmentCondition: Empty
Pset_EnvironmentalImpactIndicators - Reference: 40 x 230; sets with these values: 2

# IfcBeam: 28_SF_hout_rechthoekig_40 x 230_639, 28_SF_hout_rechthoekig:40 x 230:33594059
In: 010
PredefinedType: BEAM; Material: GVH_i2_naaldhout_generiek
Cpset_Beam - LevelOfAccuracy: in te vullen door Buildwise
IfcClassificationReference - TDS_link: .\05 As Builtdossier\2. Bouwkunde\2.2. Stabiliteit\2.2.0 technische fiche's\TF S 4.9.1.1.1 A - houten roostering sheddak.pdf
IfcElement - Tag: D1; Mark: D1
IfcRoot - Name: 40 x 230
Qto_BeamBaseQuantities - Length: 3520; CrossSectionArea: 0.997001; NetSurfaceArea: 1.994; NetVolume: 0.033608
Pset_BeamCommon - Reference: 40 x 230; Span: 3520 mm; Slope: 0 rad; Roll: 0 rad; IsExternal: no; LoadBearing: yes
Pset_ConcreteElementGeneral - ConstructionMethod: prefabricated
Pset_Condition - AssessmentCondition: Empty
Pset_EnvironmentalImpactIndicators - Reference: 40 x 230; sets with these values: 2

# IfcBeam: 28_SF_hout_rechthoekig_40 x 230_641, 28_SF_hout_rechthoekig:40 x 230:33594062
In: 010
PredefinedType: BEAM; Material: GVH_i2_naaldhout_generiek
Cpset_Beam - LevelOfAccuracy: in te vullen door Buildwise
IfcClassificationReference - TDS_link: .\05 As Builtdossier\2. Bouwkunde\2.2. Stabiliteit\2.2.0 technische fiche's\TF S 4.9.1.1.1 A - houten roostering sheddak.pdf
IfcElement - Tag: D1; Mark: D1
IfcRoot - Name: 40 x 230
Qto_BeamBaseQuantities - Length: 3534.56; CrossSectionArea: 0.0092; OuterSurfaceArea: 1.9926; GrossSurfaceArea: 2.011; NetSurfaceArea: 2.011; GrossVolume: 0.033948; NetVolume: 0.033948
Pset_BeamCommon - Reference: 40 x 230; Span: 3534.56 mm; Slope: 0 rad; Roll: 0 rad; IsExternal: no; LoadBearing: yes
Pset_ConcreteElementGeneral - ConstructionMethod: prefabricated
Pset_Condition - AssessmentCondition: Empty
Pset_EnvironmentalImpactIndicators - Reference: 40 x 230; sets with these values: 2

# IfcBeam: 28_SF_hout_rechthoekig_40 x 230_643, 28_SF_hout_rechthoekig:40 x 230:33594065
In: 010
PredefinedType: BEAM; Material: GVH_i2_naaldhout_generiek
Cpset_Beam - LevelOfAccuracy: in te vullen door Buildwise
IfcClassificationReference - TDS_link: .\05 As Builtdossier\2. Bouwkunde\2.2. Stabiliteit\2.2.0 technische fiche's\TF S 4.9.1.1.1 A - houten roostering sheddak.pdf
IfcElement - Tag: D1; Mark: D1
IfcRoot - Name: 40 x 230
Qto_BeamBaseQuantities - Length: 3534.56; CrossSectionArea: 0.0092; OuterSurfaceArea: 1.9926; GrossSurfaceArea: 2.011; NetSurfaceArea: 2.011; GrossVolume: 0.033948; NetVolume: 0.033948
Pset_BeamCommon - Reference: 40 x 230; Span: 3534.56 mm; Slope: 0 rad; Roll: 0 rad; IsExternal: no; LoadBearing: yes
Pset_ConcreteElementGeneral - ConstructionMethod: prefabricated
Pset_Condition - AssessmentCondition: Empty
Pset_EnvironmentalImpactIndicators - Reference: 40 x 230; sets with these values: 2

# IfcBeam: 28_SF_hout_rechthoekig_40 x 230_645, 28_SF_hout_rechthoekig:40 x 230:33594068
In: 010
PredefinedType: BEAM; Material: GVH_i2_naaldhout_generiek
Cpset_Beam - LevelOfAccuracy: in te vullen door Buildwise
IfcClassificationReference - TDS_link: .\05 As Builtdossier\2. Bouwkunde\2.2. Stabiliteit\2.2.0 technische fiche's\TF S 4.9.1.1.1 A - houten roostering sheddak.pdf
IfcElement - Tag: D1; Mark: D1
IfcRoot - Name: 40 x 230
Qto_BeamBaseQuantities - Length: 3534.56; CrossSectionArea: 0.0092; OuterSurfaceArea: 1.9926; GrossSurfaceArea: 2.011; NetSurfaceArea: 2.011; GrossVolume: 0.033948; NetVolume: 0.033948
Pset_BeamCommon - Reference: 40 x 230; Span: 3534.56 mm; Slope: 0 rad; Roll: 0 rad; IsExternal: no; LoadBearing: yes
Pset_ConcreteElementGeneral - ConstructionMethod: prefabricated
Pset_Condition - AssessmentCondition: Empty
Pset_EnvironmentalImpactIndicators - Reference: 40 x 230; sets with these values: 2

# IfcBeam: 28_SF_hout_rechthoekig_40 x 230_647, 28_SF_hout_rechthoekig:40 x 230:33594072
In: 010
PredefinedType: BEAM; Material: GVH_i2_naaldhout_generiek
Cpset_Beam - LevelOfAccuracy: in te vullen door Buildwise
IfcClassificationReference - TDS_link: .\05 As Builtdossier\2. Bouwkunde\2.2. Stabiliteit\2.2.0 technische fiche's\TF S 4.9.1.1.1 A - houten roostering sheddak.pdf
IfcElement - Tag: E1; Mark: E1
IfcRoot - Name: 40 x 230
Qto_BeamBaseQuantities - Length: 3480; CrossSectionArea: 0.0092; OuterSurfaceArea: 2.04684; GrossSurfaceArea: 2.06524; NetSurfaceArea: 2.06524; GrossVolume: 0.0348721; NetVolume: 0.0348721
Pset_BeamCommon - Reference: 40 x 230; Span: 3480 mm; Slope: 0 rad; Roll: 0 rad; IsExternal: no; LoadBearing: yes
Pset_ConcreteElementGeneral - ConstructionMethod: prefabricated
Pset_Condition - AssessmentCondition: Empty
Pset_EnvironmentalImpactIndicators - Reference: 40 x 230; sets with these values: 2

# IfcBeam: 28_SF_hout_rechthoekig_40 x 230_649, 28_SF_hout_rechthoekig:40 x 230:33594075
In: 010
PredefinedType: BEAM; Material: GVH_i2_naaldhout_generiek
Cpset_Beam - LevelOfAccuracy: in te vullen door Buildwise
IfcClassificationReference - TDS_link: .\05 As Builtdossier\2. Bouwkunde\2.2. Stabiliteit\2.2.0 technische fiche's\TF S 4.9.1.1.1 A - houten roostering sheddak.pdf
IfcElement - Tag: E1; Mark: E1
IfcRoot - Name: 40 x 230
Qto_BeamBaseQuantities - Length: 3480; CrossSectionArea: 0.0092; OuterSurfaceArea: 2.04684; GrossSurfaceArea: 2.06524; NetSurfaceArea: 2.06524; GrossVolume: 0.0348721; NetVolume: 0.0348721
Pset_BeamCommon - Reference: 40 x 230; Span: 3480 mm; Slope: 0 rad; Roll: 0 rad; IsExternal: no; LoadBearing: yes
Pset_ConcreteElementGeneral - ConstructionMethod: prefabricated
Pset_Condition - AssessmentCondition: Empty
Pset_EnvironmentalImpactIndicators - Reference: 40 x 230; sets with these values: 2

# IfcBeam: 28_SF_hout_rechthoekig_40 x 230_65, 28_SF_hout_rechthoekig:40 x 230:33579941
In: 010
PredefinedType: BEAM; Material: GVH_i2_naaldhout_generiek
Cpset_Beam - LevelOfAccuracy: in te vullen door Buildwise
IfcClassificationReference - TDS_link: .\05 As Builtdossier\2. Bouwkunde\2.2. Stabiliteit\2.2.0 technische fiche's\TF S 4.9.1.1.1 A - houten roostering sheddak.pdf
IfcElement - Tag: B1; Mark: B1
IfcRoot - Name: 40 x 230
Qto_BeamBaseQuantities - Length: 3340; CrossSectionArea: 0.0092; OuterSurfaceArea: 1.79133; GrossSurfaceArea: 1.80973; NetSurfaceArea: 1.80973; GrossVolume: 0.0305189; NetVolume: 0.0305189
Pset_BeamCommon - Reference: 40 x 230; Span: 3340 mm; Slope: 0 rad; Roll: 0 rad; IsExternal: no; LoadBearing: yes
Pset_ConcreteElementGeneral - ConstructionMethod: prefabricated
Pset_Condition - AssessmentCondition: Empty
Pset_EnvironmentalImpactIndicators - Reference: 40 x 230; sets with these values: 2

# IfcBeam: 28_SF_hout_rechthoekig_40 x 230_651, 28_SF_hout_rechthoekig:40 x 230:33594082
In: 010
PredefinedType: BEAM; Material: GVH_i2_naaldhout_generiek
Cpset_Beam - LevelOfAccuracy: in te vullen door Buildwise
IfcClassificationReference - TDS_link: .\05 As Builtdossier\2. Bouwkunde\2.2. Stabiliteit\2.2.0 technische fiche's\TF S 4.9.1.1.1 A - houten roostering sheddak.pdf
IfcElement - Tag: E1; Mark: E1
IfcRoot - Name: 40 x 230
Qto_BeamBaseQuantities - Length: 3480; CrossSectionArea: 0.0092; OuterSurfaceArea: 2.04684; GrossSurfaceArea: 2.06524; NetSurfaceArea: 2.06524; GrossVolume: 0.0348721; NetVolume: 0.0348721
Pset_BeamCommon - Reference: 40 x 230; Span: 3480 mm; Slope: 0 rad; Roll: 0 rad; IsExternal: no; LoadBearing: yes
Pset_ConcreteElementGeneral - ConstructionMethod: prefabricated
Pset_Condition - AssessmentCondition: Empty
Pset_EnvironmentalImpactIndicators - Reference: 40 x 230; sets with these values: 2

# IfcBeam: 28_SF_hout_rechthoekig_40 x 230_653, 28_SF_hout_rechthoekig:40 x 230:33594085
In: 010
PredefinedType: BEAM; Material: GVH_i2_naaldhout_generiek
Cpset_Beam - LevelOfAccuracy: in te vullen door Buildwise
IfcClassificationReference - TDS_link: .\05 As Builtdossier\2. Bouwkunde\2.2. Stabiliteit\2.2.0 technische fiche's\TF S 4.9.1.1.1 A - houten roostering sheddak.pdf
IfcElement - Tag: E1; Mark: E1
IfcRoot - Name: 40 x 230
Qto_BeamBaseQuantities - Length: 3480; CrossSectionArea: 0.0092; OuterSurfaceArea: 2.04684; GrossSurfaceArea: 2.06524; NetSurfaceArea: 2.06524; GrossVolume: 0.0348721; NetVolume: 0.0348721
Pset_BeamCommon - Reference: 40 x 230; Span: 3480 mm; Slope: 0 rad; Roll: 0 rad; IsExternal: no; LoadBearing: yes
Pset_ConcreteElementGeneral - ConstructionMethod: prefabricated
Pset_Condition - AssessmentCondition: Empty
Pset_EnvironmentalImpactIndicators - Reference: 40 x 230; sets with these values: 2

# IfcBeam: 28_SF_hout_rechthoekig_40 x 230_655, 28_SF_hout_rechthoekig:40 x 230:33594088
In: 010
PredefinedType: BEAM; Material: GVH_i2_naaldhout_generiek
Cpset_Beam - LevelOfAccuracy: in te vullen door Buildwise
IfcClassificationReference - TDS_link: .\05 As Builtdossier\2. Bouwkunde\2.2. Stabiliteit\2.2.0 technische fiche's\TF S 4.9.1.1.1 A - houten roostering sheddak.pdf
IfcElement - Tag: E1; Mark: E1
IfcRoot - Name: 40 x 230
Qto_BeamBaseQuantities - Length: 3480; CrossSectionArea: 0.0092; OuterSurfaceArea: 2.04684; GrossSurfaceArea: 2.06524; NetSurfaceArea: 2.06524; GrossVolume: 0.0348721; NetVolume: 0.0348721
Pset_BeamCommon - Reference: 40 x 230; Span: 3480 mm; Slope: 0 rad; Roll: 0 rad; IsExternal: no; LoadBearing: yes
Pset_ConcreteElementGeneral - ConstructionMethod: prefabricated
Pset_Condition - AssessmentCondition: Empty
Pset_EnvironmentalImpactIndicators - Reference: 40 x 230; sets with these values: 2

# IfcBeam: 28_SF_hout_rechthoekig_40 x 230_657, 28_SF_hout_rechthoekig:40 x 230:33594091
In: 010
PredefinedType: BEAM; Material: GVH_i2_naaldhout_generiek
Cpset_Beam - LevelOfAccuracy: in te vullen door Buildwise
IfcClassificationReference - TDS_link: .\05 As Builtdossier\2. Bouwkunde\2.2. Stabiliteit\2.2.0 technische fiche's\TF S 4.9.1.1.1 A - houten roostering sheddak.pdf
IfcElement - Tag: E1; Mark: E1
IfcRoot - Name: 40 x 230
Qto_BeamBaseQuantities - Length: 3480; CrossSectionArea: 0.0092; OuterSurfaceArea: 2.04684; GrossSurfaceArea: 2.06524; NetSurfaceArea: 2.06524; GrossVolume: 0.0348721; NetVolume: 0.0348721
Pset_BeamCommon - Reference: 40 x 230; Span: 3480 mm; Slope: 0 rad; Roll: 0 rad; IsExternal: no; LoadBearing: yes
Pset_ConcreteElementGeneral - ConstructionMethod: prefabricated
Pset_Condition - AssessmentCondition: Empty
Pset_EnvironmentalImpactIndicators - Reference: 40 x 230; sets with these values: 2

# IfcBeam: 28_SF_hout_rechthoekig_40 x 230_659, 28_SF_hout_rechthoekig:40 x 230:33594094
In: 010
PredefinedType: BEAM; Material: GVH_i2_naaldhout_generiek
Cpset_Beam - LevelOfAccuracy: in te vullen door Buildwise
IfcClassificationReference - TDS_link: .\05 As Builtdossier\2. Bouwkunde\2.2. Stabiliteit\2.2.0 technische fiche's\TF S 4.9.1.1.1 A - houten roostering sheddak.pdf
IfcElement - Tag: E1; Mark: E1
IfcRoot - Name: 40 x 230
Qto_BeamBaseQuantities - Length: 3480; CrossSectionArea: 0.0092; OuterSurfaceArea: 2.04684; GrossSurfaceArea: 2.06524; NetSurfaceArea: 2.06524; GrossVolume: 0.0348721; NetVolume: 0.0348721
Pset_BeamCommon - Reference: 40 x 230; Span: 3480 mm; Slope: 0 rad; Roll: 0 rad; IsExternal: no; LoadBearing: yes
Pset_ConcreteElementGeneral - ConstructionMethod: prefabricated
Pset_Condition - AssessmentCondition: Empty
Pset_EnvironmentalImpactIndicators - Reference: 40 x 230; sets with these values: 2

# IfcBeam: 28_SF_hout_rechthoekig_40 x 230_661, 28_SF_hout_rechthoekig:40 x 230:33594097
In: 010
PredefinedType: BEAM; Material: GVH_i2_naaldhout_generiek
Cpset_Beam - LevelOfAccuracy: in te vullen door Buildwise
IfcClassificationReference - TDS_link: .\05 As Builtdossier\2. Bouwkunde\2.2. Stabiliteit\2.2.0 technische fiche's\TF S 4.9.1.1.1 A - houten roostering sheddak.pdf
IfcElement - Tag: E1; Mark: E1
IfcRoot - Name: 40 x 230
Qto_BeamBaseQuantities - Length: 3480; CrossSectionArea: 0.0092; OuterSurfaceArea: 2.04684; GrossSurfaceArea: 2.06524; NetSurfaceArea: 2.06524; GrossVolume: 0.0348721; NetVolume: 0.0348721
Pset_BeamCommon - Reference: 40 x 230; Span: 3480 mm; Slope: 0 rad; Roll: 0 rad; IsExternal: no; LoadBearing: yes
Pset_ConcreteElementGeneral - ConstructionMethod: prefabricated
Pset_Condition - AssessmentCondition: Empty
Pset_EnvironmentalImpactIndicators - Reference: 40 x 230; sets with these values: 2

# IfcBeam: 28_SF_hout_rechthoekig_40 x 230_663, 28_SF_hout_rechthoekig:40 x 230:33594100
In: 010
PredefinedType: BEAM; Material: GVH_i2_naaldhout_generiek
Cpset_Beam - LevelOfAccuracy: in te vullen door Buildwise
IfcClassificationReference - TDS_link: .\05 As Builtdossier\2. Bouwkunde\2.2. Stabiliteit\2.2.0 technische fiche's\TF S 4.9.1.1.1 A - houten roostering sheddak.pdf
IfcElement - Tag: E1; Mark: E1
IfcRoot - Name: 40 x 230
Qto_BeamBaseQuantities - Length: 3480; CrossSectionArea: 0.0092; OuterSurfaceArea: 2.04684; GrossSurfaceArea: 2.06524; NetSurfaceArea: 2.06524; GrossVolume: 0.0348722; NetVolume: 0.0348722
Pset_BeamCommon - Reference: 40 x 230; Span: 3480 mm; Slope: 0 rad; Roll: 0 rad; IsExternal: no; LoadBearing: yes
Pset_ConcreteElementGeneral - ConstructionMethod: prefabricated
Pset_Condition - AssessmentCondition: Empty
Pset_EnvironmentalImpactIndicators - Reference: 40 x 230; sets with these values: 2

# IfcBeam: 28_SF_hout_rechthoekig_40 x 230_665, 28_SF_hout_rechthoekig:40 x 230:33594103
In: 010
PredefinedType: BEAM; Material: GVH_i2_naaldhout_generiek
Cpset_Beam - LevelOfAccuracy: in te vullen door Buildwise
IfcClassificationReference - TDS_link: .\05 As Builtdossier\2. Bouwkunde\2.2. Stabiliteit\2.2.0 technische fiche's\TF S 4.9.1.1.1 A - houten roostering sheddak.pdf
IfcElement - Tag: E1; Mark: E1
IfcRoot - Name: 40 x 230
Qto_BeamBaseQuantities - Length: 3480; CrossSectionArea: 0.0092; OuterSurfaceArea: 2.04684; GrossSurfaceArea: 2.06524; NetSurfaceArea: 2.06524; GrossVolume: 0.0348722; NetVolume: 0.0348722
Pset_BeamCommon - Reference: 40 x 230; Span: 3480 mm; Slope: 0 rad; Roll: 0 rad; IsExternal: no; LoadBearing: yes
Pset_ConcreteElementGeneral - ConstructionMethod: prefabricated
Pset_Condition - AssessmentCondition: Empty
Pset_EnvironmentalImpactIndicators - Reference: 40 x 230; sets with these values: 2

# IfcBeam: 28_SF_hout_rechthoekig_40 x 230_667, 28_SF_hout_rechthoekig:40 x 230:33594106
In: 010
PredefinedType: BEAM; Material: GVH_i2_naaldhout_generiek
Cpset_Beam - LevelOfAccuracy: in te vullen door Buildwise
IfcClassificationReference - TDS_link: .\05 As Builtdossier\2. Bouwkunde\2.2. Stabiliteit\2.2.0 technische fiche's\TF S 4.9.1.1.1 A - houten roostering sheddak.pdf
IfcElement - Tag: E1; Mark: E1
IfcRoot - Name: 40 x 230
Qto_BeamBaseQuantities - Length: 3480; CrossSectionArea: 0.0092; OuterSurfaceArea: 2.04685; GrossSurfaceArea: 2.06525; NetSurfaceArea: 2.06525; GrossVolume: 0.0348722; NetVolume: 0.0348722
Pset_BeamCommon - Reference: 40 x 230; Span: 3480 mm; Slope: 0 rad; Roll: 0 rad; IsExternal: no; LoadBearing: yes
Pset_ConcreteElementGeneral - ConstructionMethod: prefabricated
Pset_Condition - AssessmentCondition: Empty
Pset_EnvironmentalImpactIndicators - Reference: 40 x 230; sets with these values: 2

# IfcBeam: 28_SF_hout_rechthoekig_40 x 230_669, 28_SF_hout_rechthoekig:40 x 230:33594617
In: 010
PredefinedType: BEAM; Material: GVH_i2_naaldhout_generiek
Cpset_Beam - LevelOfAccuracy: in te vullen door Buildwise
IfcClassificationReference - TDS_link: .\05 As Builtdossier\2. Bouwkunde\2.2. Stabiliteit\2.2.0 technische fiche's\TF S 4.9.1.1.1 A - houten roostering sheddak.pdf
IfcElement - Tag: H1; Mark: H1
IfcRoot - Name: 40 x 230
Qto_BeamBaseQuantities - Length: 3480; CrossSectionArea: 0.0092; OuterSurfaceArea: 2.03684; GrossSurfaceArea: 2.05524; NetSurfaceArea: 2.05524; GrossVolume: 0.0347018; NetVolume: 0.0347018
Pset_BeamCommon - Reference: 40 x 230; Span: 3480 mm; Slope: 0 rad; Roll: 0 rad; IsExternal: no; LoadBearing: yes
Pset_ConcreteElementGeneral - ConstructionMethod: prefabricated
Pset_Condition - AssessmentCondition: Empty
Pset_EnvironmentalImpactIndicators - Reference: 40 x 230; sets with these values: 2

# IfcBeam: 28_SF_hout_rechthoekig_40 x 230_67, 28_SF_hout_rechthoekig:40 x 230:33579943
In: 010
PredefinedType: BEAM; Material: GVH_i2_naaldhout_generiek
Cpset_Beam - LevelOfAccuracy: in te vullen door Buildwise
IfcClassificationReference - TDS_link: .\05 As Builtdossier\2. Bouwkunde\2.2. Stabiliteit\2.2.0 technische fiche's\TF S 4.9.1.1.1 A - houten roostering sheddak.pdf
IfcElement - Tag: B1; Mark: B1
IfcRoot - Name: 40 x 230
Qto_BeamBaseQuantities - Length: 3340; CrossSectionArea: 0.0092; OuterSurfaceArea: 1.79133; GrossSurfaceArea: 1.80973; NetSurfaceArea: 1.80973; GrossVolume: 0.0305189; NetVolume: 0.0305189
Pset_BeamCommon - Reference: 40 x 230; Span: 3340 mm; Slope: 0 rad; Roll: 0 rad; IsExternal: no; LoadBearing: yes
Pset_ConcreteElementGeneral - ConstructionMethod: prefabricated
Pset_Condition - AssessmentCondition: Empty
Pset_EnvironmentalImpactIndicators - Reference: 40 x 230; sets with these values: 2

# IfcBeam: 28_SF_hout_rechthoekig_40 x 230_671, 28_SF_hout_rechthoekig:40 x 230:33594619
In: 010
PredefinedType: BEAM; Material: GVH_i2_naaldhout_generiek
Cpset_Beam - LevelOfAccuracy: in te vullen door Buildwise
IfcClassificationReference - TDS_link: .\05 As Builtdossier\2. Bouwkunde\2.2. Stabiliteit\2.2.0 technische fiche's\TF S 4.9.1.1.1 A - houten roostering sheddak.pdf
IfcElement - Tag: B1; Mark: B1
IfcRoot - Name: 40 x 230
Qto_BeamBaseQuantities - Length: 3480; CrossSectionArea: 0.0092; OuterSurfaceArea: 1.79057; GrossSurfaceArea: 1.80897; NetSurfaceArea: 1.80897; GrossVolume: 0.0305061; NetVolume: 0.0305061
Pset_BeamCommon - Reference: 40 x 230; Span: 3480 mm; Slope: 0 rad; Roll: 0 rad; IsExternal: no; LoadBearing: yes
Pset_ConcreteElementGeneral - ConstructionMethod: prefabricated
Pset_Condition - AssessmentCondition: Empty
Pset_EnvironmentalImpactIndicators - Reference: 40 x 230; sets with these values: 2

# IfcBeam: 28_SF_hout_rechthoekig_40 x 230_673, 28_SF_hout_rechthoekig:40 x 230:33594621
In: 010
PredefinedType: BEAM; Material: GVH_i2_naaldhout_generiek
Cpset_Beam - LevelOfAccuracy: in te vullen door Buildwise
IfcClassificationReference - TDS_link: .\05 As Builtdossier\2. Bouwkunde\2.2. Stabiliteit\2.2.0 technische fiche's\TF S 4.9.1.1.1 A - houten roostering sheddak.pdf
IfcElement - Tag: A33; Mark: A33
IfcRoot - Name: 40 x 230
Qto_BeamBaseQuantities - Length: 3480; CrossSectionArea: 0.0092; OuterSurfaceArea: 1.61158; GrossSurfaceArea: 1.62998; NetSurfaceArea: 1.62998; GrossVolume: 0.0274566; NetVolume: 0.0274566
Pset_BeamCommon - Reference: 40 x 230; Span: 3480 mm; Slope: 0 rad; Roll: 0 rad; IsExternal: no; LoadBearing: yes
Pset_ConcreteElementGeneral - ConstructionMethod: prefabricated
Pset_Condition - AssessmentCondition: Empty
Pset_EnvironmentalImpactIndicators - Reference: 40 x 230; sets with these values: 2

# IfcBeam: 28_SF_hout_rechthoekig_40 x 230_675, 28_SF_hout_rechthoekig:40 x 230:33594623
In: 010
PredefinedType: BEAM; Material: GVH_i2_naaldhout_generiek
Cpset_Beam - LevelOfAccuracy: in te vullen door Buildwise
IfcClassificationReference - TDS_link: .\05 As Builtdossier\2. Bouwkunde\2.2. Stabiliteit\2.2.0 technische fiche's\TF S 4.9.1.1.1 A - houten roostering sheddak.pdf
IfcElement - Tag: A10; Mark: A10
IfcRoot - Name: 40 x 230
Qto_BeamBaseQuantities - Length: 3480; CrossSectionArea: 0.0092; OuterSurfaceArea: 1.41246; GrossSurfaceArea: 1.43086; NetSurfaceArea: 1.43086; GrossVolume: 0.0240642; NetVolume: 0.0240642
Pset_BeamCommon - Reference: 40 x 230; Span: 3480 mm; Slope: 0 rad; Roll: 0 rad; IsExternal: no; LoadBearing: yes
Pset_ConcreteElementGeneral - ConstructionMethod: prefabricated
Pset_Condition - AssessmentCondition: Empty
Pset_EnvironmentalImpactIndicators - Reference: 40 x 230; sets with these values: 2

# IfcBeam: 28_SF_hout_rechthoekig_40 x 230_677, 28_SF_hout_rechthoekig:40 x 230:33594625
In: 010
PredefinedType: BEAM; Material: GVH_i2_naaldhout_generiek
Cpset_Beam - LevelOfAccuracy: in te vullen door Buildwise
IfcClassificationReference - TDS_link: .\05 As Builtdossier\2. Bouwkunde\2.2. Stabiliteit\2.2.0 technische fiche's\TF S 4.9.1.1.1 A - houten roostering sheddak.pdf
IfcElement - Tag: A31; Mark: A31
IfcRoot - Name: 40 x 230
Qto_BeamBaseQuantities - Length: 3480; CrossSectionArea: 0.0092; OuterSurfaceArea: 1.21332; GrossSurfaceArea: 1.23172; NetSurfaceArea: 1.23172; GrossVolume: 0.0206714; NetVolume: 0.0206714
Pset_BeamCommon - Reference: 40 x 230; Span: 3480 mm; Slope: 0 rad; Roll: 0 rad; IsExternal: no; LoadBearing: yes
Pset_ConcreteElementGeneral - ConstructionMethod: prefabricated
Pset_Condition - AssessmentCondition: Empty
Pset_EnvironmentalImpactIndicators - Reference: 40 x 230; sets with these values: 2

# IfcBeam: 28_SF_hout_rechthoekig_40 x 230_679, 28_SF_hout_rechthoekig:40 x 230:33594627
In: 010
PredefinedType: BEAM; Material: GVH_i2_naaldhout_generiek
Cpset_Beam - LevelOfAccuracy: in te vullen door Buildwise
IfcClassificationReference - TDS_link: .\05 As Builtdossier\2. Bouwkunde\2.2. Stabiliteit\2.2.0 technische fiche's\TF S 4.9.1.1.1 A - houten roostering sheddak.pdf
IfcElement - Tag: A30; Mark: A30
IfcRoot - Name: 40 x 230
Qto_BeamBaseQuantities - Length: 3480; CrossSectionArea: 0.0092; OuterSurfaceArea: 1.01419; GrossSurfaceArea: 1.03259; NetSurfaceArea: 1.03259; GrossVolume: 0.0172788; NetVolume: 0.0172788
Pset_BeamCommon - Reference: 40 x 230; Span: 3480 mm; Slope: 0 rad; Roll: 0 rad; IsExternal: no; LoadBearing: yes
Pset_ConcreteElementGeneral - ConstructionMethod: prefabricated
Pset_Condition - AssessmentCondition: Empty
Pset_EnvironmentalImpactIndicators - Reference: 40 x 230; sets with these values: 2

# IfcBeam: 28_SF_hout_rechthoekig_40 x 230_681, 28_SF_hout_rechthoekig:40 x 230:33594629
In: 010
PredefinedType: BEAM; Material: GVH_i2_naaldhout_generiek
Cpset_Beam - LevelOfAccuracy: in te vullen door Buildwise
IfcClassificationReference - TDS_link: .\05 As Builtdossier\2. Bouwkunde\2.2. Stabiliteit\2.2.0 technische fiche's\TF S 4.9.1.1.1 A - houten roostering sheddak.pdf
IfcElement - Tag: A29; Mark: A29
IfcRoot - Name: 40 x 230
Qto_BeamBaseQuantities - Length: 3480; CrossSectionArea: 0.0092; OuterSurfaceArea: 0.815071; GrossSurfaceArea: 0.833471; NetSurfaceArea: 0.833471; GrossVolume: 0.0138864; NetVolume: 0.0138864
Pset_BeamCommon - Reference: 40 x 230; Span: 3480 mm; Slope: 0 rad; Roll: 0 rad; IsExternal: no; LoadBearing: yes
Pset_ConcreteElementGeneral - ConstructionMethod: prefabricated
Pset_Condition - AssessmentCondition: Empty
Pset_EnvironmentalImpactIndicators - Reference: 40 x 230; sets with these values: 2

# IfcBeam: 28_SF_hout_rechthoekig_40 x 230_683, 28_SF_hout_rechthoekig:40 x 230:33594631
In: 010
PredefinedType: BEAM; Material: GVH_i2_naaldhout_generiek
Cpset_Beam - LevelOfAccuracy: in te vullen door Buildwise
IfcClassificationReference - TDS_link: .\05 As Builtdossier\2. Bouwkunde\2.2. Stabiliteit\2.2.0 technische fiche's\TF S 4.9.1.1.1 A - houten roostering sheddak.pdf
IfcElement - Tag: A28; Mark: A28
IfcRoot - Name: 40 x 230
Qto_BeamBaseQuantities - Length: 3480; CrossSectionArea: 0.0092; OuterSurfaceArea: 0.615941; GrossSurfaceArea: 0.634341; NetSurfaceArea: 0.634341; GrossVolume: 0.0104938; NetVolume: 0.0104938
Pset_BeamCommon - Reference: 40 x 230; Span: 3480 mm; Slope: 0 rad; Roll: 0 rad; IsExternal: no; LoadBearing: yes
Pset_ConcreteElementGeneral - ConstructionMethod: prefabricated
Pset_Condition - AssessmentCondition: Empty
Pset_EnvironmentalImpactIndicators - Reference: 40 x 230; sets with these values: 2

# IfcBeam: 28_SF_hout_rechthoekig_40 x 230_685, 28_SF_hout_rechthoekig:40 x 230:33594633
In: 010
PredefinedType: BEAM; Material: GVH_i2_naaldhout_generiek
Cpset_Beam - LevelOfAccuracy: in te vullen door Buildwise
IfcClassificationReference - TDS_link: .\05 As Builtdossier\2. Bouwkunde\2.2. Stabiliteit\2.2.0 technische fiche's\TF S 4.9.1.1.1 A - houten roostering sheddak.pdf
IfcElement - Tag: A27; Mark: A27
IfcRoot - Name: 40 x 230
Qto_BeamBaseQuantities - Length: 3480; CrossSectionArea: 0.0092; OuterSurfaceArea: 0.416801; GrossSurfaceArea: 0.435201; NetSurfaceArea: 0.435201; GrossVolume: 0.00710105; NetVolume: 0.00710105
Pset_BeamCommon - Reference: 40 x 230; Span: 3480 mm; Slope: 0 rad; Roll: 0 rad; IsExternal: no; LoadBearing: yes
Pset_ConcreteElementGeneral - ConstructionMethod: prefabricated
Pset_Condition - AssessmentCondition: Empty
Pset_EnvironmentalImpactIndicators - Reference: 40 x 230; sets with these values: 2

# IfcBeam: 28_SF_hout_rechthoekig_40 x 230_687, 28_SF_hout_rechthoekig:40 x 230:33594982
In: 010
PredefinedType: BEAM; Material: GVH_i2_naaldhout_generiek
Cpset_Beam - LevelOfAccuracy: in te vullen door Buildwise
IfcClassificationReference - TDS_link: .\05 As Builtdossier\2. Bouwkunde\2.2. Stabiliteit\2.2.0 technische fiche's\TF S 4.9.1.1.1 A - houten roostering sheddak.pdf
IfcElement - Tag: H1; Mark: H1
IfcRoot - Name: 40 x 230
Qto_BeamBaseQuantities - Length: 3504.18; CrossSectionArea: 0.0092; OuterSurfaceArea: 2.03637; GrossSurfaceArea: 2.05477; NetSurfaceArea: 2.05477; GrossVolume: 0.0346937; NetVolume: 0.0346937
Pset_BeamCommon - Reference: 40 x 230; Span: 3504.18 mm; Slope: 0 rad; Roll: 0 rad; IsExternal: no; LoadBearing: yes
Pset_ConcreteElementGeneral - ConstructionMethod: prefabricated
Pset_Condition - AssessmentCondition: Empty
Pset_EnvironmentalImpactIndicators - Reference: 40 x 230; sets with these values: 2

# IfcBeam: 28_SF_hout_rechthoekig_40 x 230_689, 28_SF_hout_rechthoekig:40 x 230:33594986
In: 010
PredefinedType: BEAM; Material: GVH_i2_naaldhout_generiek
Cpset_Beam - LevelOfAccuracy: in te vullen door Buildwise
IfcClassificationReference - TDS_link: .\05 As Builtdossier\2. Bouwkunde\2.2. Stabiliteit\2.2.0 technische fiche's\TF S 4.9.1.1.1 A - houten roostering sheddak.pdf
IfcElement - Tag: H4; Mark: H4
IfcRoot - Name: 40 x 230
Qto_BeamBaseQuantities - Length: 3480; CrossSectionArea: 0.0092; OuterSurfaceArea: 1.81707; GrossSurfaceArea: 1.83547; NetSurfaceArea: 1.83547; GrossVolume: 0.0309574; NetVolume: 0.0309574
Pset_BeamCommon - Reference: 40 x 230; Span: 3480 mm; Slope: 0 rad; Roll: 0 rad; IsExternal: no; LoadBearing: yes
Pset_ConcreteElementGeneral - ConstructionMethod: prefabricated
Pset_Condition - AssessmentCondition: Empty
Pset_EnvironmentalImpactIndicators - Reference: 40 x 230; sets with these values: 2

# IfcBeam: 28_SF_hout_rechthoekig_40 x 230_69, 28_SF_hout_rechthoekig:40 x 230:33579945
In: 010
PredefinedType: BEAM; Material: GVH_i2_naaldhout_generiek
Cpset_Beam - LevelOfAccuracy: in te vullen door Buildwise
IfcClassificationReference - TDS_link: .\05 As Builtdossier\2. Bouwkunde\2.2. Stabiliteit\2.2.0 technische fiche's\TF S 4.9.1.1.1 A - houten roostering sheddak.pdf
IfcElement - Tag: B1; Mark: B1
IfcRoot - Name: 40 x 230
Qto_BeamBaseQuantities - Length: 3340; CrossSectionArea: 0.0092; OuterSurfaceArea: 1.79133; GrossSurfaceArea: 1.80973; NetSurfaceArea: 1.80973; GrossVolume: 0.0305189; NetVolume: 0.0305189
Pset_BeamCommon - Reference: 40 x 230; Span: 3340 mm; Slope: 0 rad; Roll: 0 rad; IsExternal: no; LoadBearing: yes
Pset_ConcreteElementGeneral - ConstructionMethod: prefabricated
Pset_Condition - AssessmentCondition: Empty
Pset_EnvironmentalImpactIndicators - Reference: 40 x 230; sets with these values: 2

# IfcBeam: 28_SF_hout_rechthoekig_40 x 230_691, 28_SF_hout_rechthoekig:40 x 230:33594993
In: 010
PredefinedType: BEAM; Material: GVH_i2_naaldhout_generiek
Cpset_Beam - LevelOfAccuracy: in te vullen door Buildwise
IfcClassificationReference - TDS_link: .\05 As Builtdossier\2. Bouwkunde\2.2. Stabiliteit\2.2.0 technische fiche's\TF S 4.9.1.1.1 A - houten roostering sheddak.pdf
IfcElement - Tag: A33; Mark: A33
IfcRoot - Name: 40 x 230
Qto_BeamBaseQuantities - Length: 3480; CrossSectionArea: 0.0092; OuterSurfaceArea: 1.61158; GrossSurfaceArea: 1.62998; NetSurfaceArea: 1.62998; GrossVolume: 0.0274565; NetVolume: 0.0274565
Pset_BeamCommon - Reference: 40 x 230; Span: 3480 mm; Slope: 0 rad; Roll: 0 rad; IsExternal: no; LoadBearing: yes
Pset_ConcreteElementGeneral - ConstructionMethod: prefabricated
Pset_Condition - AssessmentCondition: Empty
Pset_EnvironmentalImpactIndicators - Reference: 40 x 230; sets with these values: 2

# IfcBeam: 28_SF_hout_rechthoekig_40 x 230_693, 28_SF_hout_rechthoekig:40 x 230:33594996
In: 010
PredefinedType: BEAM; Material: GVH_i2_naaldhout_generiek
Cpset_Beam - LevelOfAccuracy: in te vullen door Buildwise
IfcClassificationReference - TDS_link: .\05 As Builtdossier\2. Bouwkunde\2.2. Stabiliteit\2.2.0 technische fiche's\TF S 4.9.1.1.1 A - houten roostering sheddak.pdf
IfcElement - Tag: A10; Mark: A10
IfcRoot - Name: 40 x 230
Qto_BeamBaseQuantities - Length: 3480; CrossSectionArea: 0.0092; OuterSurfaceArea: 1.41246; GrossSurfaceArea: 1.43086; NetSurfaceArea: 1.43086; GrossVolume: 0.0240641; NetVolume: 0.0240641
Pset_BeamCommon - Reference: 40 x 230; Span: 3480 mm; Slope: 0 rad; Roll: 0 rad; IsExternal: no; LoadBearing: yes
Pset_ConcreteElementGeneral - ConstructionMethod: prefabricated
Pset_Condition - AssessmentCondition: Empty
Pset_EnvironmentalImpactIndicators - Reference: 40 x 230; sets with these values: 2

# IfcBeam: 28_SF_hout_rechthoekig_40 x 230_695, 28_SF_hout_rechthoekig:40 x 230:33594999
In: 010
PredefinedType: BEAM; Material: GVH_i2_naaldhout_generiek
Cpset_Beam - LevelOfAccuracy: in te vullen door Buildwise
IfcClassificationReference - TDS_link: .\05 As Builtdossier\2. Bouwkunde\2.2. Stabiliteit\2.2.0 technische fiche's\TF S 4.9.1.1.1 A - houten roostering sheddak.pdf
IfcElement - Tag: A31; Mark: A31
IfcRoot - Name: 40 x 230
Qto_BeamBaseQuantities - Length: 3480; CrossSectionArea: 0.0092; OuterSurfaceArea: 1.21333; GrossSurfaceArea: 1.23173; NetSurfaceArea: 1.23173; GrossVolume: 0.0206715; NetVolume: 0.0206715
Pset_BeamCommon - Reference: 40 x 230; Span: 3480 mm; Slope: 0 rad; Roll: 0 rad; IsExternal: no; LoadBearing: yes
Pset_ConcreteElementGeneral - ConstructionMethod: prefabricated
Pset_Condition - AssessmentCondition: Empty
Pset_EnvironmentalImpactIndicators - Reference: 40 x 230; sets with these values: 2

# IfcBeam: 28_SF_hout_rechthoekig_40 x 230_697, 28_SF_hout_rechthoekig:40 x 230:33595002
In: 010
PredefinedType: BEAM; Material: GVH_i2_naaldhout_generiek
Cpset_Beam - LevelOfAccuracy: in te vullen door Buildwise
IfcClassificationReference - TDS_link: .\05 As Builtdossier\2. Bouwkunde\2.2. Stabiliteit\2.2.0 technische fiche's\TF S 4.9.1.1.1 A - houten roostering sheddak.pdf
IfcElement - Tag: A30; Mark: A30
IfcRoot - Name: 40 x 230
Qto_BeamBaseQuantities - Length: 3480; CrossSectionArea: 0.0092; OuterSurfaceArea: 1.0142; GrossSurfaceArea: 1.0326; NetSurfaceArea: 1.0326; GrossVolume: 0.0172789; NetVolume: 0.0172789
Pset_BeamCommon - Reference: 40 x 230; Span: 3480 mm; Slope: 0 rad; Roll: 0 rad; IsExternal: no; LoadBearing: yes
Pset_ConcreteElementGeneral - ConstructionMethod: prefabricated
Pset_Condition - AssessmentCondition: Empty
Pset_EnvironmentalImpactIndicators - Reference: 40 x 230; sets with these values: 2

# IfcBeam: 28_SF_hout_rechthoekig_40 x 230_699, 28_SF_hout_rechthoekig:40 x 230:33595005
In: 010
PredefinedType: BEAM; Material: GVH_i2_naaldhout_generiek
Cpset_Beam - LevelOfAccuracy: in te vullen door Buildwise
IfcClassificationReference - TDS_link: .\05 As Builtdossier\2. Bouwkunde\2.2. Stabiliteit\2.2.0 technische fiche's\TF S 4.9.1.1.1 A - houten roostering sheddak.pdf
IfcElement - Tag: A29; Mark: A29
IfcRoot - Name: 40 x 230
Qto_BeamBaseQuantities - Length: 3480; CrossSectionArea: 0.0092; OuterSurfaceArea: 0.815068; GrossSurfaceArea: 0.833468; NetSurfaceArea: 0.833468; GrossVolume: 0.0138863; NetVolume: 0.0138863
Pset_BeamCommon - Reference: 40 x 230; Span: 3480 mm; Slope: 0 rad; Roll: 0 rad; IsExternal: no; LoadBearing: yes
Pset_ConcreteElementGeneral - ConstructionMethod: prefabricated
Pset_Condition - AssessmentCondition: Empty
Pset_EnvironmentalImpactIndicators - Reference: 40 x 230; sets with these values: 2

# IfcBeam: 28_SF_hout_rechthoekig_40 x 230_7, 28_SF_hout_rechthoekig:40 x 230:33579219
In: 010
PredefinedType: BEAM; Material: GVH_i2_naaldhout_generiek
Cpset_Beam - LevelOfAccuracy: in te vullen door Buildwise
IfcClassificationReference - TDS_link: .\05 As Builtdossier\2. Bouwkunde\2.2. Stabiliteit\2.2.0 technische fiche's\TF S 4.9.1.1.1 A - houten roostering sheddak.pdf
IfcElement - Tag: B1; Mark: B1
IfcRoot - Name: 40 x 230
Qto_BeamBaseQuantities - Length: 3440; CrossSectionArea: 0.0092; OuterSurfaceArea: 1.79133; GrossSurfaceArea: 1.80973; NetSurfaceArea: 1.80973; GrossVolume: 0.030519; NetVolume: 0.030519
Pset_BeamCommon - Reference: 40 x 230; Span: 3440 mm; Slope: 0 rad; Roll: 0 rad; IsExternal: no; LoadBearing: yes
Pset_ConcreteElementGeneral - ConstructionMethod: prefabricated
Pset_Condition - AssessmentCondition: Empty
Pset_EnvironmentalImpactIndicators - Reference: 40 x 230; sets with these values: 2

# IfcBeam: 28_SF_hout_rechthoekig_40 x 230_701, 28_SF_hout_rechthoekig:40 x 230:33595008
In: 010
PredefinedType: BEAM; Material: GVH_i2_naaldhout_generiek
Cpset_Beam - LevelOfAccuracy: in te vullen door Buildwise
IfcClassificationReference - TDS_link: .\05 As Builtdossier\2. Bouwkunde\2.2. Stabiliteit\2.2.0 technische fiche's\TF S 4.9.1.1.1 A - houten roostering sheddak.pdf
IfcElement - Tag: A28; Mark: A28
IfcRoot - Name: 40 x 230
Qto_BeamBaseQuantities - Length: 3480; CrossSectionArea: 0.0092; OuterSurfaceArea: 0.615939; GrossSurfaceArea: 0.634339; NetSurfaceArea: 0.634339; GrossVolume: 0.0104938; NetVolume: 0.0104938
Pset_BeamCommon - Reference: 40 x 230; Span: 3480 mm; Slope: 0 rad; Roll: 0 rad; IsExternal: no; LoadBearing: yes
Pset_ConcreteElementGeneral - ConstructionMethod: prefabricated
Pset_Condition - AssessmentCondition: Empty
Pset_EnvironmentalImpactIndicators - Reference: 40 x 230; sets with these values: 2

# IfcBeam: 28_SF_hout_rechthoekig_40 x 230_703, 28_SF_hout_rechthoekig:40 x 230:33595011
In: 010
PredefinedType: BEAM; Material: GVH_i2_naaldhout_generiek
Cpset_Beam - LevelOfAccuracy: in te vullen door Buildwise
IfcClassificationReference - TDS_link: .\05 As Builtdossier\2. Bouwkunde\2.2. Stabiliteit\2.2.0 technische fiche's\TF S 4.9.1.1.1 A - houten roostering sheddak.pdf
IfcElement - Tag: A27; Mark: A27
IfcRoot - Name: 40 x 230
Qto_BeamBaseQuantities - Length: 3480; CrossSectionArea: 0.0092; OuterSurfaceArea: 0.416809; GrossSurfaceArea: 0.435209; NetSurfaceArea: 0.435209; GrossVolume: 0.00710119; NetVolume: 0.00710119
Pset_BeamCommon - Reference: 40 x 230; Span: 3480 mm; Slope: 0 rad; Roll: 0 rad; IsExternal: no; LoadBearing: yes
Pset_ConcreteElementGeneral - ConstructionMethod: prefabricated
Pset_Condition - AssessmentCondition: Empty
Pset_EnvironmentalImpactIndicators - Reference: 40 x 230; sets with these values: 2

# IfcBeam: 28_SF_hout_rechthoekig_40 x 230_705, 28_SF_hout_rechthoekig:40 x 230:33595014
In: 010
PredefinedType: BEAM; Material: GVH_i2_naaldhout_generiek
Cpset_Beam - LevelOfAccuracy: in te vullen door Buildwise
IfcClassificationReference - TDS_link: .\05 As Builtdossier\2. Bouwkunde\2.2. Stabiliteit\2.2.0 technische fiche's\TF S 4.9.1.1.1 A - houten roostering sheddak.pdf
IfcElement - Tag: A26; Mark: A26
IfcRoot - Name: 40 x 230
Qto_BeamBaseQuantities - Length: 403.144; CrossSectionArea: 0.0092; OuterSurfaceArea: 0.199635; GrossSurfaceArea: 0.218035; NetSurfaceArea: 0.218035; GrossVolume: 0.00340119; NetVolume: 0.00340119
Pset_BeamCommon - Reference: 40 x 230; Span: 403.144 mm; Slope: 0 rad; Roll: 0 rad; IsExternal: no; LoadBearing: yes
Pset_ConcreteElementGeneral - ConstructionMethod: prefabricated
Pset_Condition - AssessmentCondition: Empty
Pset_EnvironmentalImpactIndicators - Reference: 40 x 230; sets with these values: 2

# IfcBeam: 28_SF_hout_rechthoekig_40 x 230_707, 28_SF_hout_rechthoekig:40 x 230:33612385
In: 010
PredefinedType: BEAM; Material: GVH_i2_naaldhout_generiek
Cpset_Beam - LevelOfAccuracy: in te vullen door Buildwise
IfcClassificationReference - TDS_link: .\05 As Builtdossier\2. Bouwkunde\2.2. Stabiliteit\2.2.0 technische fiche's\TF S 4.9.1.1.1 A - houten roostering sheddak.pdf
IfcElement - Tag: A1; Mark: A1
IfcRoot - Name: 40 x 230
Qto_BeamBaseQuantities - Length: 3480; CrossSectionArea: 0.0092; OuterSurfaceArea: 0.144473; GrossSurfaceArea: 0.162873; NetSurfaceArea: 0.162873; GrossVolume: 0.00246139; NetVolume: 0.00246139
Pset_BeamCommon - Reference: 40 x 230; Span: 3480 mm; Slope: 0 rad; Roll: 0 rad; IsExternal: no; LoadBearing: yes
Pset_ConcreteElementGeneral - ConstructionMethod: prefabricated
Pset_Condition - AssessmentCondition: Empty
Pset_EnvironmentalImpactIndicators - Reference: 40 x 230; sets with these values: 2

# IfcBeam: 28_SF_hout_rechthoekig_40 x 230_709, 28_SF_hout_rechthoekig:40 x 230:33612508
In: 010
PredefinedType: BEAM; Material: GVH_i2_naaldhout_generiek
Cpset_Beam - LevelOfAccuracy: in te vullen door Buildwise
IfcClassificationReference - TDS_link: .\05 As Builtdossier\2. Bouwkunde\2.2. Stabiliteit\2.2.0 technische fiche's\TF S 4.9.1.1.1 A - houten roostering sheddak.pdf
IfcElement - Tag: A25; Mark: A25
IfcRoot - Name: 40 x 230
Qto_BeamBaseQuantities - Length: 453.899; CrossSectionArea: 0.0092; OuterSurfaceArea: 0.216154; GrossSurfaceArea: 0.234554; NetSurfaceArea: 0.234554; GrossVolume: 0.00368262; NetVolume: 0.00368262
Pset_BeamCommon - Reference: 40 x 230; Span: 453.899 mm; Slope: 0 rad; Roll: 0 rad; IsExternal: no; LoadBearing: yes
Pset_ConcreteElementGeneral - ConstructionMethod: prefabricated
Pset_Condition - AssessmentCondition: Empty
Pset_EnvironmentalImpactIndicators - Reference: 40 x 230; sets with these values: 2

# IfcBeam: 28_SF_hout_rechthoekig_40 x 230_71, 28_SF_hout_rechthoekig:40 x 230:33579947
In: 010
PredefinedType: BEAM; Material: GVH_i2_naaldhout_generiek
Cpset_Beam - LevelOfAccuracy: in te vullen door Buildwise
IfcClassificationReference - TDS_link: .\05 As Builtdossier\2. Bouwkunde\2.2. Stabiliteit\2.2.0 technische fiche's\TF S 4.9.1.1.1 A - houten roostering sheddak.pdf
IfcElement - Tag: B1; Mark: B1
IfcRoot - Name: 40 x 230
Qto_BeamBaseQuantities - Length: 3340; CrossSectionArea: 0.0092; OuterSurfaceArea: 1.79133; GrossSurfaceArea: 1.80973; NetSurfaceArea: 1.80973; GrossVolume: 0.0305189; NetVolume: 0.0305189
Pset_BeamCommon - Reference: 40 x 230; Span: 3340 mm; Slope: 0 rad; Roll: 0 rad; IsExternal: no; LoadBearing: yes
Pset_ConcreteElementGeneral - ConstructionMethod: prefabricated
Pset_Condition - AssessmentCondition: Empty
Pset_EnvironmentalImpactIndicators - Reference: 40 x 230; sets with these values: 2

# IfcBeam: 28_SF_hout_rechthoekig_40 x 230_73, 28_SF_hout_rechthoekig:40 x 230:33579949
In: 010
PredefinedType: BEAM; Material: GVH_i2_naaldhout_generiek
Cpset_Beam - LevelOfAccuracy: in te vullen door Buildwise
IfcClassificationReference - TDS_link: .\05 As Builtdossier\2. Bouwkunde\2.2. Stabiliteit\2.2.0 technische fiche's\TF S 4.9.1.1.1 A - houten roostering sheddak.pdf
IfcElement - Tag: B1; Mark: B1
IfcRoot - Name: 40 x 230
Qto_BeamBaseQuantities - Length: 3340; CrossSectionArea: 0.0092; OuterSurfaceArea: 1.79133; GrossSurfaceArea: 1.80973; NetSurfaceArea: 1.80973; GrossVolume: 0.0305189; NetVolume: 0.0305189
Pset_BeamCommon - Reference: 40 x 230; Span: 3340 mm; Slope: 0 rad; Roll: 0 rad; IsExternal: no; LoadBearing: yes
Pset_ConcreteElementGeneral - ConstructionMethod: prefabricated
Pset_Condition - AssessmentCondition: Empty
Pset_EnvironmentalImpactIndicators - Reference: 40 x 230; sets with these values: 2

# IfcBeam: 28_SF_hout_rechthoekig_40 x 230_75, 28_SF_hout_rechthoekig:40 x 230:33579951
In: 010
PredefinedType: BEAM; Material: GVH_i2_naaldhout_generiek
Cpset_Beam - LevelOfAccuracy: in te vullen door Buildwise
IfcClassificationReference - TDS_link: .\05 As Builtdossier\2. Bouwkunde\2.2. Stabiliteit\2.2.0 technische fiche's\TF S 4.9.1.1.1 A - houten roostering sheddak.pdf
IfcElement - Tag: B1; Mark: B1
IfcRoot - Name: 40 x 230
Qto_BeamBaseQuantities - Length: 3340; CrossSectionArea: 0.0092; OuterSurfaceArea: 1.79133; GrossSurfaceArea: 1.80973; NetSurfaceArea: 1.80973; GrossVolume: 0.0305189; NetVolume: 0.0305189
Pset_BeamCommon - Reference: 40 x 230; Span: 3340 mm; Slope: 0 rad; Roll: 0 rad; IsExternal: no; LoadBearing: yes
Pset_ConcreteElementGeneral - ConstructionMethod: prefabricated
Pset_Condition - AssessmentCondition: Empty
Pset_EnvironmentalImpactIndicators - Reference: 40 x 230; sets with these values: 2

# IfcBeam: 28_SF_hout_rechthoekig_40 x 230_77, 28_SF_hout_rechthoekig:40 x 230:33579953
In: 010
PredefinedType: BEAM; Material: GVH_i2_naaldhout_generiek
Cpset_Beam - LevelOfAccuracy: in te vullen door Buildwise
IfcClassificationReference - TDS_link: .\05 As Builtdossier\2. Bouwkunde\2.2. Stabiliteit\2.2.0 technische fiche's\TF S 4.9.1.1.1 A - houten roostering sheddak.pdf
IfcElement - Tag: B1; Mark: B1
IfcRoot - Name: 40 x 230
Qto_BeamBaseQuantities - Length: 3340; CrossSectionArea: 0.0092; OuterSurfaceArea: 1.79133; GrossSurfaceArea: 1.80973; NetSurfaceArea: 1.80973; GrossVolume: 0.0305189; NetVolume: 0.0305189
Pset_BeamCommon - Reference: 40 x 230; Span: 3340 mm; Slope: 0 rad; Roll: 0 rad; IsExternal: no; LoadBearing: yes
Pset_ConcreteElementGeneral - ConstructionMethod: prefabricated
Pset_Condition - AssessmentCondition: Empty
Pset_EnvironmentalImpactIndicators - Reference: 40 x 230; sets with these values: 2

# IfcBeam: 28_SF_hout_rechthoekig_40 x 230_79, 28_SF_hout_rechthoekig:40 x 230:33579955
In: 010
PredefinedType: BEAM; Material: GVH_i2_naaldhout_generiek
Cpset_Beam - LevelOfAccuracy: in te vullen door Buildwise
IfcClassificationReference - TDS_link: .\05 As Builtdossier\2. Bouwkunde\2.2. Stabiliteit\2.2.0 technische fiche's\TF S 4.9.1.1.1 A - houten roostering sheddak.pdf
IfcElement - Tag: B1; Mark: B1
IfcRoot - Name: 40 x 230
Qto_BeamBaseQuantities - Length: 3340; CrossSectionArea: 0.0092; OuterSurfaceArea: 1.79133; GrossSurfaceArea: 1.80973; NetSurfaceArea: 1.80973; GrossVolume: 0.0305189; NetVolume: 0.0305189
Pset_BeamCommon - Reference: 40 x 230; Span: 3340 mm; Slope: 0 rad; Roll: 0 rad; IsExternal: no; LoadBearing: yes
Pset_ConcreteElementGeneral - ConstructionMethod: prefabricated
Pset_Condition - AssessmentCondition: Empty
Pset_EnvironmentalImpactIndicators - Reference: 40 x 230; sets with these values: 2

# IfcBeam: 28_SF_hout_rechthoekig_40 x 230_81, 28_SF_hout_rechthoekig:40 x 230:33579957
In: 010
PredefinedType: BEAM; Material: GVH_i2_naaldhout_generiek
Cpset_Beam - LevelOfAccuracy: in te vullen door Buildwise
IfcClassificationReference - TDS_link: .\05 As Builtdossier\2. Bouwkunde\2.2. Stabiliteit\2.2.0 technische fiche's\TF S 4.9.1.1.1 A - houten roostering sheddak.pdf
IfcElement - Tag: B1; Mark: B1
IfcRoot - Name: 40 x 230
Qto_BeamBaseQuantities - Length: 3340; CrossSectionArea: 0.0092; OuterSurfaceArea: 1.79133; GrossSurfaceArea: 1.80973; NetSurfaceArea: 1.80973; GrossVolume: 0.0305189; NetVolume: 0.0305189
Pset_BeamCommon - Reference: 40 x 230; Span: 3340 mm; Slope: 0 rad; Roll: 0 rad; IsExternal: no; LoadBearing: yes
Pset_ConcreteElementGeneral - ConstructionMethod: prefabricated
Pset_Condition - AssessmentCondition: Empty
Pset_EnvironmentalImpactIndicators - Reference: 40 x 230; sets with these values: 2

# IfcBeam: 28_SF_hout_rechthoekig_40 x 230_83, 28_SF_hout_rechthoekig:40 x 230:33579959
In: 010
PredefinedType: BEAM; Material: GVH_i2_naaldhout_generiek
Cpset_Beam - LevelOfAccuracy: in te vullen door Buildwise
IfcClassificationReference - TDS_link: .\05 As Builtdossier\2. Bouwkunde\2.2. Stabiliteit\2.2.0 technische fiche's\TF S 4.9.1.1.1 A - houten roostering sheddak.pdf
IfcElement - Tag: B1; Mark: B1
IfcRoot - Name: 40 x 230
Qto_BeamBaseQuantities - Length: 3340; CrossSectionArea: 0.0092; OuterSurfaceArea: 1.79133; GrossSurfaceArea: 1.80973; NetSurfaceArea: 1.80973; GrossVolume: 0.0305189; NetVolume: 0.0305189
Pset_BeamCommon - Reference: 40 x 230; Span: 3340 mm; Slope: 0 rad; Roll: 0 rad; IsExternal: no; LoadBearing: yes
Pset_ConcreteElementGeneral - ConstructionMethod: prefabricated
Pset_Condition - AssessmentCondition: Empty
Pset_EnvironmentalImpactIndicators - Reference: 40 x 230; sets with these values: 2

# IfcBeam: 28_SF_hout_rechthoekig_40 x 230_85, 28_SF_hout_rechthoekig:40 x 230:33579961
In: 010
PredefinedType: BEAM; Material: GVH_i2_naaldhout_generiek
Cpset_Beam - LevelOfAccuracy: in te vullen door Buildwise
IfcClassificationReference - TDS_link: .\05 As Builtdossier\2. Bouwkunde\2.2. Stabiliteit\2.2.0 technische fiche's\TF S 4.9.1.1.1 A - houten roostering sheddak.pdf
IfcElement - Tag: B1; Mark: B1
IfcRoot - Name: 40 x 230
Qto_BeamBaseQuantities - Length: 3340; CrossSectionArea: 0.0092; OuterSurfaceArea: 1.79133; GrossSurfaceArea: 1.80973; NetSurfaceArea: 1.80973; GrossVolume: 0.0305189; NetVolume: 0.0305189
Pset_BeamCommon - Reference: 40 x 230; Span: 3340 mm; Slope: 0 rad; Roll: 0 rad; IsExternal: no; LoadBearing: yes
Pset_ConcreteElementGeneral - ConstructionMethod: prefabricated
Pset_Condition - AssessmentCondition: Empty
Pset_EnvironmentalImpactIndicators - Reference: 40 x 230; sets with these values: 2

# IfcBeam: 28_SF_hout_rechthoekig_40 x 230_87, 28_SF_hout_rechthoekig:40 x 230:33579963
In: 010
PredefinedType: BEAM; Material: GVH_i2_naaldhout_generiek
Cpset_Beam - LevelOfAccuracy: in te vullen door Buildwise
IfcClassificationReference - TDS_link: .\05 As Builtdossier\2. Bouwkunde\2.2. Stabiliteit\2.2.0 technische fiche's\TF S 4.9.1.1.1 A - houten roostering sheddak.pdf
IfcElement - Tag: B1; Mark: B1
IfcRoot - Name: 40 x 230
Qto_BeamBaseQuantities - Length: 3340; CrossSectionArea: 0.0092; OuterSurfaceArea: 1.79133; GrossSurfaceArea: 1.80973; NetSurfaceArea: 1.80973; GrossVolume: 0.0305189; NetVolume: 0.0305189
Pset_BeamCommon - Reference: 40 x 230; Span: 3340 mm; Slope: 0 rad; Roll: 0 rad; IsExternal: no; LoadBearing: yes
Pset_ConcreteElementGeneral - ConstructionMethod: prefabricated
Pset_Condition - AssessmentCondition: Empty
Pset_EnvironmentalImpactIndicators - Reference: 40 x 230; sets with these values: 2

# IfcBeam: 28_SF_hout_rechthoekig_40 x 230_89, 28_SF_hout_rechthoekig:40 x 230:33579965
In: 010
PredefinedType: BEAM; Material: GVH_i2_naaldhout_generiek
Cpset_Beam - LevelOfAccuracy: in te vullen door Buildwise
IfcClassificationReference - TDS_link: .\05 As Builtdossier\2. Bouwkunde\2.2. Stabiliteit\2.2.0 technische fiche's\TF S 4.9.1.1.1 A - houten roostering sheddak.pdf
IfcElement - Tag: B1; Mark: B1
IfcRoot - Name: 40 x 230
Qto_BeamBaseQuantities - Length: 3340; CrossSectionArea: 0.0092; OuterSurfaceArea: 1.79133; GrossSurfaceArea: 1.80973; NetSurfaceArea: 1.80973; GrossVolume: 0.0305189; NetVolume: 0.0305189
Pset_BeamCommon - Reference: 40 x 230; Span: 3340 mm; Slope: 0 rad; Roll: 0 rad; IsExternal: no; LoadBearing: yes
Pset_ConcreteElementGeneral - ConstructionMethod: prefabricated
Pset_Condition - AssessmentCondition: Empty
Pset_EnvironmentalImpactIndicators - Reference: 40 x 230; sets with these values: 2

# IfcBeam: 28_SF_hout_rechthoekig_40 x 230_9, 28_SF_hout_rechthoekig:40 x 230:33579222
In: 010
PredefinedType: BEAM; Material: GVH_i2_naaldhout_generiek
Cpset_Beam - LevelOfAccuracy: in te vullen door Buildwise
IfcClassificationReference - TDS_link: .\05 As Builtdossier\2. Bouwkunde\2.2. Stabiliteit\2.2.0 technische fiche's\TF S 4.9.1.1.1 A - houten roostering sheddak.pdf
IfcElement - Tag: B1; Mark: B1
IfcRoot - Name: 40 x 230
Qto_BeamBaseQuantities - Length: 3440; CrossSectionArea: 0.0092; OuterSurfaceArea: 1.79133; GrossSurfaceArea: 1.80973; NetSurfaceArea: 1.80973; GrossVolume: 0.030519; NetVolume: 0.030519
Pset_BeamCommon - Reference: 40 x 230; Span: 3440 mm; Slope: 0 rad; Roll: 0 rad; IsExternal: no; LoadBearing: yes
Pset_ConcreteElementGeneral - ConstructionMethod: prefabricated
Pset_Condition - AssessmentCondition: Empty
Pset_EnvironmentalImpactIndicators - Reference: 40 x 230; sets with these values: 2

# IfcBeam: 28_SF_hout_rechthoekig_40 x 230_91, 28_SF_hout_rechthoekig:40 x 230:33579967
In: 010
PredefinedType: BEAM; Material: GVH_i2_naaldhout_generiek
Cpset_Beam - LevelOfAccuracy: in te vullen door Buildwise
IfcClassificationReference - TDS_link: .\05 As Builtdossier\2. Bouwkunde\2.2. Stabiliteit\2.2.0 technische fiche's\TF S 4.9.1.1.1 A - houten roostering sheddak.pdf
IfcElement - Tag: B1; Mark: B1
IfcRoot - Name: 40 x 230
Qto_BeamBaseQuantities - Length: 3340; CrossSectionArea: 0.0092; OuterSurfaceArea: 1.79133; GrossSurfaceArea: 1.80973; NetSurfaceArea: 1.80973; GrossVolume: 0.0305189; NetVolume: 0.0305189
Pset_BeamCommon - Reference: 40 x 230; Span: 3340 mm; Slope: 0 rad; Roll: 0 rad; IsExternal: no; LoadBearing: yes
Pset_ConcreteElementGeneral - ConstructionMethod: prefabricated
Pset_Condition - AssessmentCondition: Empty
Pset_EnvironmentalImpactIndicators - Reference: 40 x 230; sets with these values: 2

# IfcBeam: 28_SF_hout_rechthoekig_40 x 230_93, 28_SF_hout_rechthoekig:40 x 230:33579969
In: 010
PredefinedType: BEAM; Material: GVH_i2_naaldhout_generiek
Cpset_Beam - LevelOfAccuracy: in te vullen door Buildwise
IfcClassificationReference - TDS_link: .\05 As Builtdossier\2. Bouwkunde\2.2. Stabiliteit\2.2.0 technische fiche's\TF S 4.9.1.1.1 A - houten roostering sheddak.pdf
IfcElement - Tag: B1; Mark: B1
IfcRoot - Name: 40 x 230
Qto_BeamBaseQuantities - Length: 3340; CrossSectionArea: 0.0092; OuterSurfaceArea: 1.79133; GrossSurfaceArea: 1.80973; NetSurfaceArea: 1.80973; GrossVolume: 0.0305189; NetVolume: 0.0305189
Pset_BeamCommon - Reference: 40 x 230; Span: 3340 mm; Slope: 0 rad; Roll: 0 rad; IsExternal: no; LoadBearing: yes
Pset_ConcreteElementGeneral - ConstructionMethod: prefabricated
Pset_Condition - AssessmentCondition: Empty
Pset_EnvironmentalImpactIndicators - Reference: 40 x 230; sets with these values: 2

# IfcBeam: 28_SF_hout_rechthoekig_40 x 230_95, 28_SF_hout_rechthoekig:40 x 230:33579971
In: 010
PredefinedType: BEAM; Material: GVH_i2_naaldhout_generiek
Cpset_Beam - LevelOfAccuracy: in te vullen door Buildwise
IfcClassificationReference - TDS_link: .\05 As Builtdossier\2. Bouwkunde\2.2. Stabiliteit\2.2.0 technische fiche's\TF S 4.9.1.1.1 A - houten roostering sheddak.pdf
IfcElement - Tag: B1; Mark: B1
IfcRoot - Name: 40 x 230
Qto_BeamBaseQuantities - Length: 3340; CrossSectionArea: 0.0092; OuterSurfaceArea: 1.79133; GrossSurfaceArea: 1.80973; NetSurfaceArea: 1.80973; GrossVolume: 0.0305189; NetVolume: 0.0305189
Pset_BeamCommon - Reference: 40 x 230; Span: 3340 mm; Slope: 0 rad; Roll: 0 rad; IsExternal: no; LoadBearing: yes
Pset_ConcreteElementGeneral - ConstructionMethod: prefabricated
Pset_Condition - AssessmentCondition: Empty
Pset_EnvironmentalImpactIndicators - Reference: 40 x 230; sets with these values: 2

# IfcBeam: 28_SF_hout_rechthoekig_40 x 230_97 (2)
In: 010
PredefinedType: BEAM; Material: GVH_i2_naaldhout_generiek
Cpset_Beam - LevelOfAccuracy: in te vullen door Buildwise
IfcClassificationReference - TDS_link: .\05 As Builtdossier\2. Bouwkunde\2.2. Stabiliteit\2.2.0 technische fiche's\TF S 4.9.1.1.1 A - houten roostering sheddak.pdf
IfcElement - Tag: B1; Mark: B1
IfcRoot - Name: 40 x 230
Qto_BeamBaseQuantities - Length: 3290; CrossSectionArea: 0.0092; OuterSurfaceArea: 1.7916; GrossSurfaceArea: 1.81; NetSurfaceArea: 1.81; GrossVolume: 0.0305235; NetVolume: 0.0305235
Pset_BeamCommon - Reference: 40 x 230; Span: 3290 mm; Slope: 0 rad; Roll: 0 rad; IsExternal: no; LoadBearing: yes
Pset_ConcreteElementGeneral - ConstructionMethod: prefabricated
Pset_Condition - AssessmentCondition: Empty
Pset_EnvironmentalImpactIndicators - Reference: 40 x 230; sets with these values: 2
Name (28_SF_hout_rechthoekig:40 x 230:...)
33579973
33580078

# IfcBeam: 28_SF_hout_rechthoekig_40 x 230_99, 28_SF_hout_rechthoekig:40 x 230:33579976
In: 010
PredefinedType: BEAM; Material: GVH_i2_naaldhout_generiek
Cpset_Beam - LevelOfAccuracy: in te vullen door Buildwise
IfcClassificationReference - TDS_link: .\05 As Builtdossier\2. Bouwkunde\2.2. Stabiliteit\2.2.0 technische fiche's\TF S 4.9.1.1.1 A - houten roostering sheddak.pdf
IfcElement - Tag: B1; Mark: B1
IfcRoot - Name: 40 x 230
Qto_BeamBaseQuantities - Length: 3340; CrossSectionArea: 0.0092; OuterSurfaceArea: 1.79133; GrossSurfaceArea: 1.80973; NetSurfaceArea: 1.80973; GrossVolume: 0.030519; NetVolume: 0.030519
Pset_BeamCommon - Reference: 40 x 230; Span: 3340 mm; Slope: 0 rad; Roll: 0 rad; IsExternal: no; LoadBearing: yes
Pset_ConcreteElementGeneral - ConstructionMethod: prefabricated
Pset_Condition - AssessmentCondition: Empty
Pset_EnvironmentalImpactIndicators - Reference: 40 x 230; sets with these values: 2

# IfcBeam: 28_SF_hout_rechthoekig_WxH, 28_SF_hout_rechthoekig:WxH:33589784
In: 010
PredefinedType: BEAM; Material: GVH_i2_naaldhout_generiek
Cpset_Beam - LevelOfAccuracy: in te vullen door Buildwise
IfcClassificationReference - TDS_link: .\05 As Builtdossier\2. Bouwkunde\2.2. Stabiliteit\2.2.0 technische fiche's\TF S 4.9.1.1.1 A - houten roostering sheddak.pdf
IfcElement - Tag: B1; Mark: B1
IfcRoot - Name: WxH
Qto_BeamBaseQuantities - Length: 3407.67; CrossSectionArea: 0.06; OuterSurfaceArea: 3.72345; GrossSurfaceArea: 3.84345; NetSurfaceArea: 3.84345; GrossVolume: 0.203097; NetVolume: 0.203097
Pset_BeamCommon - Reference: WxH; Span: 3407.67 mm; Slope: 0 rad; Roll: 0 rad; IsExternal: no; LoadBearing: yes
Pset_ConcreteElementGeneral - ConstructionMethod: prefabricated
Pset_Condition - AssessmentCondition: Empty
Pset_EnvironmentalImpactIndicators - Reference: WxH; sets with these values: 2

# IfcBeam: BB_05.07.42#02_Groendak_ L-profiel_GMO_XX_h_100, BB_05.07.42#02_Groendak, L-profiel_GMO:XX_h_100:20182322
In: K10
PredefinedType: BEAM; Material: BB_Beton_Niet-structureel_In zicht
Cpset_Beam - LevelOfAccuracy: in te vullen door Buildwise
IfcClassificationReference - GVH_artnr 01: 05.07.42#02; GVH_artnr 02: geen waarde gevonden; GVH_artnr 03: geen waarde gevonden; GVH_artnr 04: geen waarde gevonden; GVH_artnr 05: geen waarde gevonden; GVH_artnr 06: geen waarde gevonden
IfcRoot - Name: XX_h_100
Qto_BeamBaseQuantities - Length: 36005; CrossSectionArea: 8.99087; NetSurfaceArea: 17.9817; NetVolume: 0.0440487
Pset_BeamCommon - Reference: XX_h_100; Span: 36005 mm; Slope: 0 rad; IsExternal: yes
Pset_ConcreteElementGeneral - ConstructionMethod: prefabricated
Pset_Condition - AssessmentCondition: Empty
Pset_EnvironmentalImpactIndicators - Reference: XX_h_100; sets with these values: 2

# IfcBeam: BB_05.07.42#02_Groendak_ L-profiel_GMO_XX_h_300, BB_05.07.42#02_Groendak, L-profiel_GMO:XX_h_300:20182271
In: K10
PredefinedType: BEAM; Material: BB_Beton_Niet-structureel_In zicht
Cpset_Beam - LevelOfAccuracy: in te vullen door Buildwise
IfcClassificationReference - GVH_artnr 01: 05.07.42#02; GVH_artnr 02: geen waarde gevonden; GVH_artnr 03: geen waarde gevonden; GVH_artnr 04: geen waarde gevonden; GVH_artnr 05: geen waarde gevonden; GVH_artnr 06: geen waarde gevonden
IfcRoot - Name: XX_h_300
Qto_BeamBaseQuantities - Length: 2460; CrossSectionArea: 1.09732; NetSurfaceArea: 2.19465; NetVolume: 0.00541356
Pset_BeamCommon - Reference: XX_h_300; Span: 2460 mm; Slope: 0 rad; IsExternal: yes
Pset_ConcreteElementGeneral - ConstructionMethod: prefabricated
Pset_Condition - AssessmentCondition: Empty
Pset_EnvironmentalImpactIndicators - Reference: XX_h_300; sets with these values: 2

# IfcBeam: BB_XX_Betonbalk_ L-vorm_ center-center_SFB_360 x 720 mm - 170 x 520 mm, BB_XX_Betonbalk, L-vorm, center-center_SFB:360 x 720 mm - 170 x 520 mm:2464170
In: K10
PredefinedType: BEAM; Material: BB_Beton_Bestaand
Cpset_Beam - LevelOfAccuracy: in te vullen door Buildwise
IfcRoot - Name: 360 x 720 mm - 170 x 520 mm
Qto_BeamBaseQuantities - Length: 7345.03; CrossSectionArea: 0.1708; OuterSurfaceArea: 15.4981; GrossSurfaceArea: 15.8397; NetSurfaceArea: 15.8397; GrossVolume: 1.22549; NetVolume: 1.22549
Pset_BeamCommon - Reference: 360 x 720 mm - 170 x 520 mm; Span: 7345.03 mm; Slope: 0 rad; Roll: 0 rad; IsExternal: no; LoadBearing: yes
Pset_Condition - AssessmentCondition: Empty
Pset_EnvironmentalImpactIndicators - Reference: 360 x 720 mm - 170 x 520 mm; sets with these values: 2

# IfcBeam: BB_XX_Betonbalk_ L-vorm_ center-center_SFB_460 x 720 mm - 170 x 250 mm, BB_XX_Betonbalk, L-vorm, center-center_SFB:460 x 720 mm - 170 x 250 mm:2466584
In: K10
PredefinedType: BEAM; Material: BB_Beton_Bestaand
Cpset_Beam - LevelOfAccuracy: in te vullen door Buildwise
IfcRoot - Name: 460 x 720 mm - 170 x 250 mm
Qto_BeamBaseQuantities - Length: 7094.33; CrossSectionArea: 0.2887; OuterSurfaceArea: 16.992; GrossSurfaceArea: 17.5694; NetSurfaceArea: 17.5694; GrossVolume: 2.07864; NetVolume: 2.07864
Pset_BeamCommon - Reference: 460 x 720 mm - 170 x 250 mm; Span: 7094.33 mm; Slope: 0 rad; Roll: 0 rad; IsExternal: no; LoadBearing: yes
Pset_Condition - AssessmentCondition: Empty
Pset_EnvironmentalImpactIndicators - Reference: 460 x 720 mm - 170 x 250 mm; sets with these values: 2

# IfcBeam: BB_XX_Betonbalk_ L-vorm_ center-center_SFB_460 x 720 mm - 170 x 250 mm1, BB_XX_Betonbalk, L-vorm, center-center_SFB:460 x 720 mm - 170 x 250 mm:2466695
In: K10
PredefinedType: BEAM; Material: BB_Beton_Bestaand
Cpset_Beam - LevelOfAccuracy: in te vullen door Buildwise
IfcRoot - Name: 460 x 720 mm - 170 x 250 mm
Qto_BeamBaseQuantities - Length: 5000; CrossSectionArea: 0.2887; OuterSurfaceArea: 11.8; GrossSurfaceArea: 12.3774; NetSurfaceArea: 12.3774; GrossVolume: 1.4435; NetVolume: 1.4435
Pset_BeamCommon - Reference: 460 x 720 mm - 170 x 250 mm; Span: 5000 mm; Slope: 0 rad; Roll: 0 rad; IsExternal: no; LoadBearing: yes
Pset_Condition - AssessmentCondition: Empty
Pset_EnvironmentalImpactIndicators - Reference: 460 x 720 mm - 170 x 250 mm; sets with these values: 2

# IfcBeam: BB_XX_Betonbalk_ L-vorm_ center-center_SFB_460 x 720 mm - 170 x 250 mm3, BB_XX_Betonbalk, L-vorm, center-center_SFB:460 x 720 mm - 170 x 250 mm:2466826
In: K10
PredefinedType: BEAM; Material: BB_Beton_Bestaand
Cpset_Beam - LevelOfAccuracy: in te vullen door Buildwise
IfcRoot - Name: 460 x 720 mm - 170 x 250 mm
Qto_BeamBaseQuantities - Length: 7095.67; CrossSectionArea: 0.2887; OuterSurfaceArea: 16.7458; GrossSurfaceArea: 17.3232; NetSurfaceArea: 17.3232; GrossVolume: 2.04852; NetVolume: 2.04852
Pset_BeamCommon - Reference: 460 x 720 mm - 170 x 250 mm; Span: 7095.67 mm; Slope: 0 rad; Roll: 0 rad; IsExternal: no; LoadBearing: yes
Pset_Condition - AssessmentCondition: Empty
Pset_EnvironmentalImpactIndicators - Reference: 460 x 720 mm - 170 x 250 mm; sets with these values: 2

# IfcBeam: BB_XX_Betonbalk_ L-vorm_ center-center_SFB_460 x 720 mm - 170 x 270 mm, BB_XX_Betonbalk, L-vorm, center-center_SFB:460 x 720 mm - 170 x 270 mm:2466268
In: K10
PredefinedType: BEAM; Material: BB_Beton_Bestaand
Cpset_Beam - LevelOfAccuracy: in te vullen door Buildwise
IfcRoot - Name: 460 x 720 mm - 170 x 270 mm
Qto_BeamBaseQuantities - Length: 5545; CrossSectionArea: 0.2853; OuterSurfaceArea: 12.2538; GrossSurfaceArea: 12.8244; NetSurfaceArea: 12.8244; GrossVolume: 1.48136; NetVolume: 1.48136
Pset_BeamCommon - Reference: 460 x 720 mm - 170 x 270 mm; Span: 5545 mm; Slope: 0 rad; Roll: 0 rad; IsExternal: no; LoadBearing: yes
Pset_Condition - AssessmentCondition: Empty
Pset_EnvironmentalImpactIndicators - Reference: 460 x 720 mm - 170 x 270 mm; sets with these values: 2

# IfcBeam: BB_XX_Betonbalk_ L-vorm_ center-center_SFB_460 x 720 mm - 170 x 510 mm, BB_XX_Betonbalk, L-vorm, center-center_SFB:460 x 720 mm - 170 x 510 mm:2461885
In: K10
PredefinedType: BEAM; Material: BB_Beton_Bestaand
Cpset_Beam - LevelOfAccuracy: in te vullen door Buildwise
IfcRoot - Name: 460 x 720 mm - 170 x 510 mm
Qto_BeamBaseQuantities - Length: 7095; CrossSectionArea: 8.3924; NetSurfaceArea: 16.7848; NetVolume: 1.67402
Pset_BeamCommon - Reference: 460 x 720 mm - 170 x 510 mm; Span: 7095 mm; Slope: 0 rad; Roll: 0 rad; IsExternal: no; LoadBearing: yes
Pset_Condition - AssessmentCondition: Empty
Pset_EnvironmentalImpactIndicators - Reference: 460 x 720 mm - 170 x 510 mm; sets with these values: 2
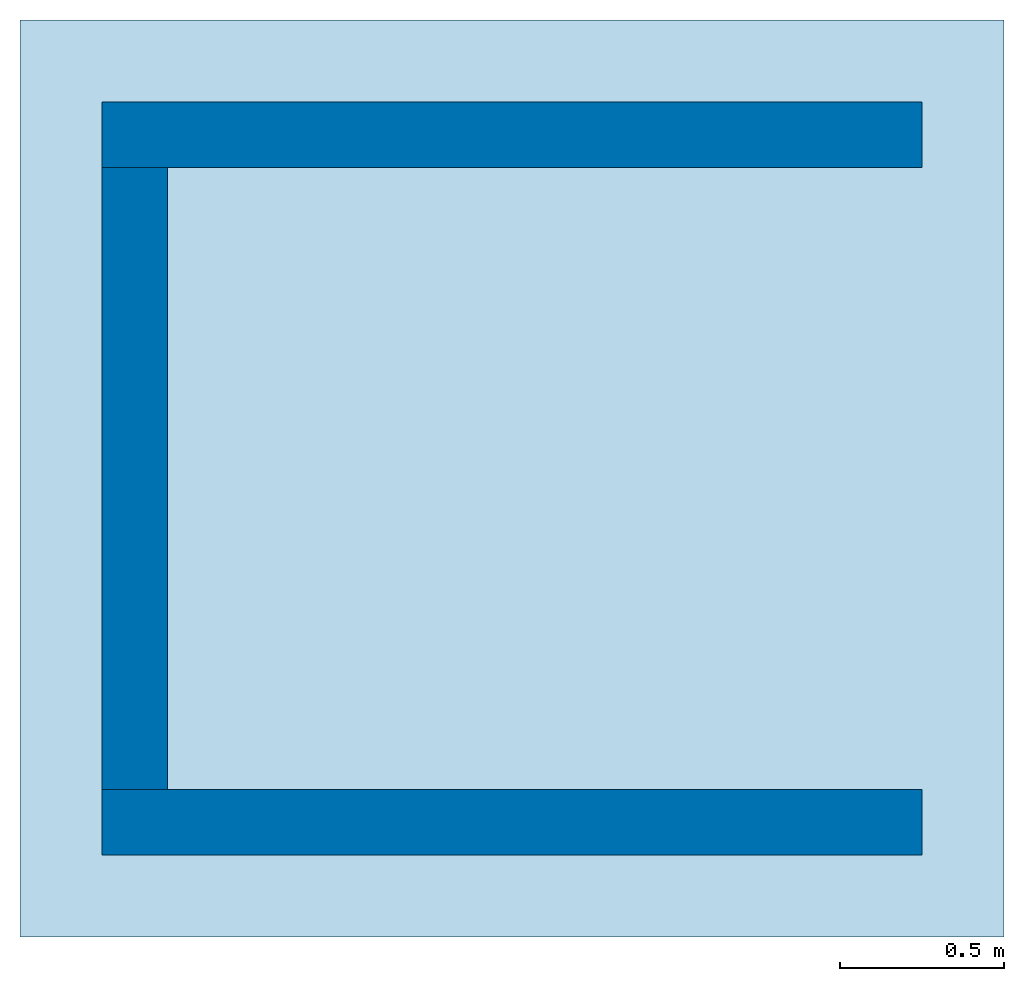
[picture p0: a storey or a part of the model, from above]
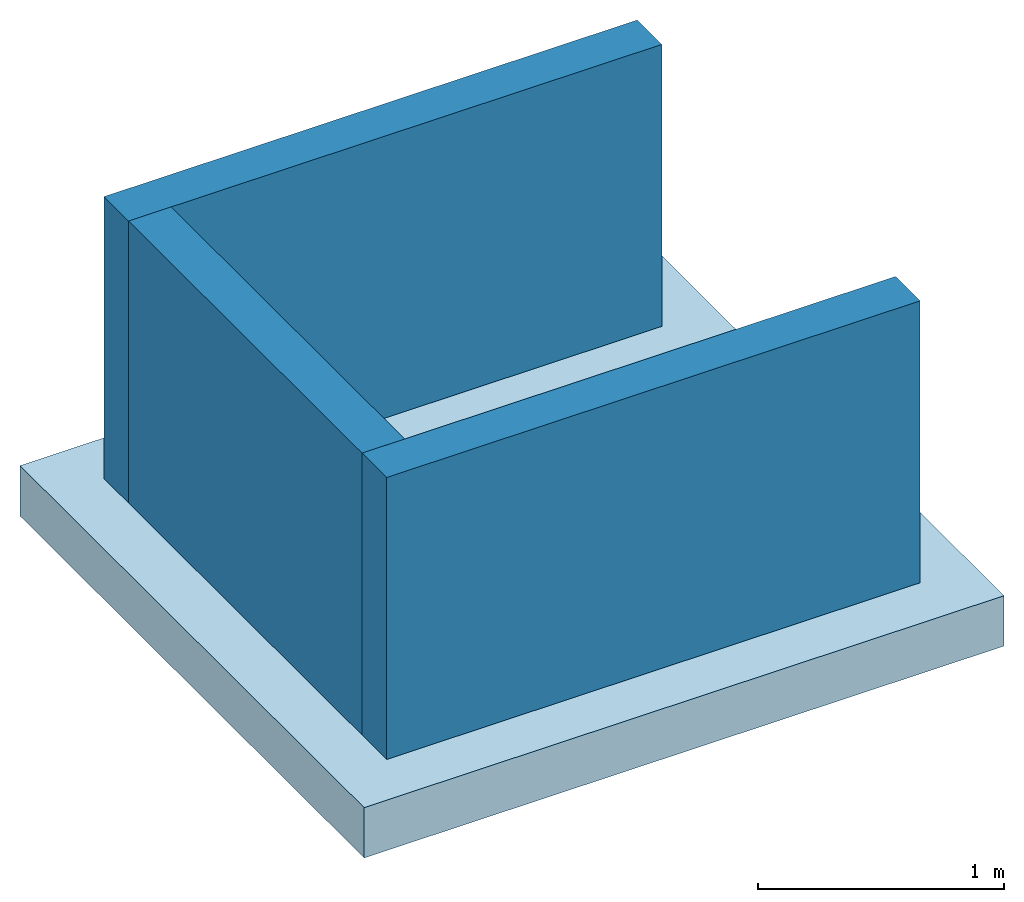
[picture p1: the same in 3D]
Properties of the parts of a building model (IFC4X3_ADD2), part 7 of 28

# IfcBeam: BB_XX_Betonbalk_ L-vorm_ center-center_SFB_460 x 720 mm - 170 x 510 mm1, BB_XX_Betonbalk, L-vorm, center-center_SFB:460 x 720 mm - 170 x 510 mm:2463370
In: K10
PredefinedType: BEAM; Material: BB_Beton_Bestaand
Cpset_Beam - LevelOfAccuracy: in te vullen door Buildwise
IfcRoot - Name: 460 x 720 mm - 170 x 510 mm
Qto_BeamBaseQuantities - Length: 6800; CrossSectionArea: 0.2445; OuterSurfaceArea: 16.048; GrossSurfaceArea: 16.537; NetSurfaceArea: 16.537; GrossVolume: 1.6626; NetVolume: 1.6626
Pset_BeamCommon - Reference: 460 x 720 mm - 170 x 510 mm; Span: 6800 mm; Slope: 0 rad; Roll: 0 rad; IsExternal: no; LoadBearing: yes
Pset_Condition - AssessmentCondition: Empty
Pset_EnvironmentalImpactIndicators - Reference: 460 x 720 mm - 170 x 510 mm; sets with these values: 2

# IfcBeam: BB_XX_Betonbalk_ L-vorm_ center-center_SFB_460 x 720 mm - 170 x 510 mm3, BB_XX_Betonbalk, L-vorm, center-center_SFB:460 x 720 mm - 170 x 510 mm:2463441
In: K10
PredefinedType: BEAM; Material: BB_Beton_Bestaand
Cpset_Beam - LevelOfAccuracy: in te vullen door Buildwise
IfcRoot - Name: 460 x 720 mm - 170 x 510 mm
Qto_BeamBaseQuantities - Length: 6755; CrossSectionArea: 8.4191; NetSurfaceArea: 16.8382; NetVolume: 1.67745
Pset_BeamCommon - Reference: 460 x 720 mm - 170 x 510 mm; Span: 6755 mm; Slope: 0 rad; Roll: 0 rad; IsExternal: no; LoadBearing: yes
Pset_Condition - AssessmentCondition: Empty
Pset_EnvironmentalImpactIndicators - Reference: 460 x 720 mm - 170 x 510 mm; sets with these values: 2

# IfcBeam: BB_XX_Betonbalk_ L-vorm_ center-center_SFB_460 x 720 mm - 170 x 510 mm5, BB_XX_Betonbalk, L-vorm, center-center_SFB:460 x 720 mm - 170 x 510 mm:2465508
In: K10
PredefinedType: BEAM; Material: BB_Beton_Bestaand
Cpset_Beam - LevelOfAccuracy: in te vullen door Buildwise
IfcRoot - Name: 460 x 720 mm - 170 x 510 mm
Qto_BeamBaseQuantities - Length: 7410; CrossSectionArea: 8.68436; NetSurfaceArea: 17.3687; NetVolume: 1.74054
Pset_BeamCommon - Reference: 460 x 720 mm - 170 x 510 mm; Span: 7410 mm; Slope: 0 rad; Roll: 0 rad; IsExternal: no; LoadBearing: yes
Pset_Condition - AssessmentCondition: Empty
Pset_EnvironmentalImpactIndicators - Reference: 460 x 720 mm - 170 x 510 mm; sets with these values: 2

# IfcBeam: BB_XX_Betonbalk_ L-vorm_ center-center_SFB_470 x 750 mm - 100 x 200 mm, BB_XX_Betonbalk, L-vorm, center-center_SFB:470 x 750 mm - 100 x 200 mm:884537
In: K10
PredefinedType: BEAM; Material: BB_Beton_Bestaand
Cpset_Beam - LevelOfAccuracy: in te vullen door Buildwise
IfcRoot - Name: 470 x 750 mm - 100 x 200 mm
Qto_BeamBaseQuantities - Length: 2330; CrossSectionArea: 0.3325; OuterSurfaceArea: 5.92919; GrossSurfaceArea: 6.59419; NetSurfaceArea: 6.59419; GrossVolume: 0.807974; NetVolume: 0.807974
Pset_BeamCommon - Reference: 470 x 750 mm - 100 x 200 mm; Span: 2330 mm; Slope: 0 rad; Roll: 0 rad; IsExternal: no; LoadBearing: yes
Pset_Condition - AssessmentCondition: Empty
Pset_EnvironmentalImpactIndicators - Reference: 470 x 750 mm - 100 x 200 mm; sets with these values: 2

# IfcBeam: BB_XX_Betonbalk_ L-vorm_ center-center_SFB_470 x 750 mm - 100 x 200 mm1, BB_XX_Betonbalk, L-vorm, center-center_SFB:470 x 750 mm - 100 x 200 mm:2469749
In: K10
PredefinedType: BEAM; Material: BB_Beton_Bestaand
Cpset_Beam - LevelOfAccuracy: in te vullen door Buildwise
IfcRoot - Name: 470 x 750 mm - 100 x 200 mm
Qto_BeamBaseQuantities - Length: 2300; CrossSectionArea: 0.3325; OuterSurfaceArea: 5.9292; GrossSurfaceArea: 6.5942; NetSurfaceArea: 6.5942; GrossVolume: 0.807975; NetVolume: 0.807975
Pset_BeamCommon - Reference: 470 x 750 mm - 100 x 200 mm; Span: 2300 mm; Slope: 0 rad; Roll: 0 rad; IsExternal: no; LoadBearing: yes
Pset_Condition - AssessmentCondition: Empty
Pset_EnvironmentalImpactIndicators - Reference: 470 x 750 mm - 100 x 200 mm; sets with these values: 2

# IfcBeam: BB_XX_Betonbalk_ L-vorm_ center-center_SFB_570 x 750 mm - 100 x 200 mm, BB_XX_Betonbalk, L-vorm, center-center_SFB:570 x 750 mm - 100 x 200 mm:821754
In: K10
PredefinedType: BEAM; Material: BB_Beton_Bestaand
Cpset_Beam - LevelOfAccuracy: in te vullen door Buildwise
IfcRoot - Name: 570 x 750 mm - 100 x 200 mm
Qto_BeamBaseQuantities - Length: 16300; CrossSectionArea: 21.8965; NetSurfaceArea: 43.793; NetVolume: 6.6274
Pset_BeamCommon - Reference: 570 x 750 mm - 100 x 200 mm; Span: 16300 mm; Slope: 0 rad; Roll: 0 rad; IsExternal: no; LoadBearing: yes
Pset_Condition - AssessmentCondition: Empty
Pset_EnvironmentalImpactIndicators - Reference: 570 x 750 mm - 100 x 200 mm; sets with these values: 2

# IfcBeam: BB_XX_Betonbalk_ L-vorm_ center-center_SFB_570 x 750 mm - 100 x 200 mm1, BB_XX_Betonbalk, L-vorm, center-center_SFB:570 x 750 mm - 100 x 200 mm:841048
In: K10
PredefinedType: BEAM; Material: BB_Beton_Bestaand
Cpset_Beam - LevelOfAccuracy: in te vullen door Buildwise
IfcRoot - Name: 570 x 750 mm - 100 x 200 mm
Qto_BeamBaseQuantities - Length: 13700; CrossSectionArea: 0.4075; OuterSurfaceArea: 36.168; GrossSurfaceArea: 36.983; NetSurfaceArea: 36.983; GrossVolume: 5.58275; NetVolume: 5.58275
Pset_BeamCommon - Reference: 570 x 750 mm - 100 x 200 mm; Span: 13700 mm; Slope: 0 rad; Roll: 0 rad; IsExternal: no; LoadBearing: yes
Pset_Condition - AssessmentCondition: Empty
Pset_EnvironmentalImpactIndicators - Reference: 570 x 750 mm - 100 x 200 mm; sets with these values: 2

# IfcBeam: BB_XX_Betonbalk_ L-vorm_ center-center_SFB_570 x 750 mm - 100 x 200 mm3, BB_XX_Betonbalk, L-vorm, center-center_SFB:570 x 750 mm - 100 x 200 mm:944427
In: K10
PredefinedType: BEAM; Material: BB_Beton_Bestaand
Cpset_Beam - LevelOfAccuracy: in te vullen door Buildwise
IfcRoot - Name: 570 x 750 mm - 100 x 200 mm
Qto_BeamBaseQuantities - Length: 1485; CrossSectionArea: 2.07528; NetSurfaceArea: 4.15057; NetVolume: 0.452008
Pset_BeamCommon - Reference: 570 x 750 mm - 100 x 200 mm; Span: 1485 mm; Slope: 0 rad; Roll: 0 rad; IsExternal: no; LoadBearing: yes
Pset_Condition - AssessmentCondition: Empty
Pset_EnvironmentalImpactIndicators - Reference: 570 x 750 mm - 100 x 200 mm; sets with these values: 2

# IfcBeam: BB_XX_Betonbalk_ L-vorm_ center-center_SFB_620 x 750 mm - 100 x 200 mm, BB_XX_Betonbalk, L-vorm, center-center_SFB:620 x 750 mm - 100 x 200 mm:843072
In: K10
PredefinedType: BEAM; Material: BB_Beton_Bestaand
Cpset_Beam - LevelOfAccuracy: in te vullen door Buildwise
IfcRoot - Name: 620 x 750 mm - 100 x 200 mm
Qto_BeamBaseQuantities - Length: 15900; CrossSectionArea: 0.445; OuterSurfaceArea: 43.566; GrossSurfaceArea: 44.456; NetSurfaceArea: 44.456; GrossVolume: 7.0755; NetVolume: 7.0755
Pset_BeamCommon - Reference: 620 x 750 mm - 100 x 200 mm; Span: 15900 mm; Slope: 0 rad; Roll: 0 rad; IsExternal: no; LoadBearing: yes
Pset_Condition - AssessmentCondition: Empty
Pset_EnvironmentalImpactIndicators - Reference: 620 x 750 mm - 100 x 200 mm; sets with these values: 2

# IfcBeam: BB_XX_Betonbalk_ L-vorm_ center-center_SFB_620 x 750 mm - 100 x 200 mm1, BB_XX_Betonbalk, L-vorm, center-center_SFB:620 x 750 mm - 100 x 200 mm:2469618
In: K10
PredefinedType: BEAM; Material: BB_Beton_Bestaand
Cpset_Beam - LevelOfAccuracy: in te vullen door Buildwise
IfcRoot - Name: 620 x 750 mm - 100 x 200 mm
Qto_BeamBaseQuantities - Length: 15900; CrossSectionArea: 0.445; OuterSurfaceArea: 43.566; GrossSurfaceArea: 44.456; NetSurfaceArea: 44.456; GrossVolume: 7.0755; NetVolume: 7.0755
Pset_BeamCommon - Reference: 620 x 750 mm - 100 x 200 mm; Span: 15900 mm; Slope: 0 rad; Roll: 0 rad; IsExternal: no; LoadBearing: yes
Pset_Condition - AssessmentCondition: Empty
Pset_EnvironmentalImpactIndicators - Reference: 620 x 750 mm - 100 x 200 mm; sets with these values: 2

# IfcBeam: BB_XX_Betonbalk_ rechthoekig_ center-center_SFB_150 x 720 mm, BB_XX_Betonbalk, rechthoekig, center-center_SFB:150 x 720 mm:544365
In: 000
PredefinedType: BEAM; Material: BB_Beton_Bestaand
Cpset_Beam - LevelOfAccuracy: in te vullen door Buildwise
IfcRoot - Name: 150 x 720 mm
Qto_BeamBaseQuantities - Length: 880; CrossSectionArea: 0.108; OuterSurfaceArea: 1.2354; GrossSurfaceArea: 1.4514; NetSurfaceArea: 1.4514; GrossVolume: 0.07668; NetVolume: 0.07668
Pset_BeamCommon - Reference: 150 x 720 mm; Span: 880 mm; Slope: 0 rad; Roll: 0 rad; IsExternal: no; LoadBearing: yes
Pset_Condition - AssessmentCondition: Empty
Pset_EnvironmentalImpactIndicators - Reference: 150 x 720 mm; sets with these values: 2

# IfcBeam: BB_XX_Betonbalk_ rechthoekig_ center-center_SFB_150 x 720 mm1, BB_XX_Betonbalk, rechthoekig, center-center_SFB:150 x 720 mm:672501
In: 000
PredefinedType: BEAM; Material: BB_Beton_Bestaand
Cpset_Beam - LevelOfAccuracy: in te vullen door Buildwise
IfcRoot - Name: 150 x 720 mm
Qto_BeamBaseQuantities - Length: 745; CrossSectionArea: 0.108; OuterSurfaceArea: 1.2963; GrossSurfaceArea: 1.5123; NetSurfaceArea: 1.5123; GrossVolume: 0.08046; NetVolume: 0.08046
Pset_BeamCommon - Reference: 150 x 720 mm; Span: 745 mm; Slope: 0 rad; Roll: 0 rad; IsExternal: no; LoadBearing: yes
Pset_Condition - AssessmentCondition: Empty
Pset_EnvironmentalImpactIndicators - Reference: 150 x 720 mm; sets with these values: 2

# IfcBeam: BB_XX_Betonbalk_ rechthoekig_ center-center_SFB_150 x 720 mm3, BB_XX_Betonbalk, rechthoekig, center-center_SFB:150 x 720 mm:673280
In: 010
PredefinedType: BEAM; Material: BB_Beton_Bestaand
Cpset_Beam - LevelOfAccuracy: in te vullen door Buildwise
IfcRoot - Name: 150 x 720 mm
Qto_BeamBaseQuantities - Length: 745; CrossSectionArea: 0.108; OuterSurfaceArea: 1.2963; GrossSurfaceArea: 1.5123; NetSurfaceArea: 1.5123; GrossVolume: 0.08046; NetVolume: 0.08046
Pset_BeamCommon - Reference: 150 x 720 mm; Span: 745 mm; Slope: 0 rad; Roll: 0 rad; IsExternal: no; LoadBearing: yes
Pset_Condition - AssessmentCondition: Empty
Pset_EnvironmentalImpactIndicators - Reference: 150 x 720 mm; sets with these values: 2

# IfcBeam: BB_XX_Betonbalk_ rechthoekig_ center-center_SFB_150 x 720 mm5, BB_XX_Betonbalk, rechthoekig, center-center_SFB:150 x 720 mm:673409
In: 010
PredefinedType: BEAM; Material: BB_Beton_Bestaand
Cpset_Beam - LevelOfAccuracy: in te vullen door Buildwise
IfcRoot - Name: 150 x 720 mm
Qto_BeamBaseQuantities - Length: 880; CrossSectionArea: 0.108; OuterSurfaceArea: 1.2354; GrossSurfaceArea: 1.4514; NetSurfaceArea: 1.4514; GrossVolume: 0.07668; NetVolume: 0.07668
Pset_BeamCommon - Reference: 150 x 720 mm; Span: 880 mm; Slope: 0 rad; Roll: 0 rad; IsExternal: no; LoadBearing: yes
Pset_Condition - AssessmentCondition: Empty
Pset_EnvironmentalImpactIndicators - Reference: 150 x 720 mm; sets with these values: 2

# IfcBeam: BB_XX_Betonbalk_ rechthoekig_ center-center_SFB_150 x 720 mm7, BB_XX_Betonbalk, rechthoekig, center-center_SFB:150 x 720 mm:695866
In: 020
PredefinedType: BEAM; Material: BB_Beton_Bestaand
Cpset_Beam - LevelOfAccuracy: in te vullen door Buildwise
IfcRoot - Name: 150 x 720 mm
Qto_BeamBaseQuantities - Length: 710; CrossSectionArea: 0.108; OuterSurfaceArea: 1.2354; GrossSurfaceArea: 1.4514; NetSurfaceArea: 1.4514; GrossVolume: 0.07668; NetVolume: 0.07668
Pset_BeamCommon - Reference: 150 x 720 mm; Span: 710 mm; Slope: 0 rad; Roll: 0 rad; IsExternal: no; LoadBearing: yes
Pset_Condition - AssessmentCondition: Empty
Pset_EnvironmentalImpactIndicators - Reference: 150 x 720 mm; sets with these values: 2

# IfcBeam: BB_XX_Betonbalk_ rechthoekig_ center-center_SFB_150 x 720 mm9, BB_XX_Betonbalk, rechthoekig, center-center_SFB:150 x 720 mm:695874
In: 020
PredefinedType: BEAM; Material: BB_Beton_Bestaand
Cpset_Beam - LevelOfAccuracy: in te vullen door Buildwise
IfcRoot - Name: 150 x 720 mm
Qto_BeamBaseQuantities - Length: 880; CrossSectionArea: 0.108; OuterSurfaceArea: 1.2354; GrossSurfaceArea: 1.4514; NetSurfaceArea: 1.4514; GrossVolume: 0.07668; NetVolume: 0.07668
Pset_BeamCommon - Reference: 150 x 720 mm; Span: 880 mm; Slope: 0 rad; Roll: 0 rad; IsExternal: no; LoadBearing: yes
Pset_Condition - AssessmentCondition: Empty
Pset_EnvironmentalImpactIndicators - Reference: 150 x 720 mm; sets with these values: 2

# IfcBeam: BB_XX_Betonbalk_ rechthoekig_ center-center_SFB_190 x 1000 mm, BB_XX_Betonbalk, rechthoekig, center-center_SFB:190 x 1000 mm:34130690
In: K20
PredefinedType: BEAM; Material: BB_Beton_Bestaand
Cpset_Beam - LevelOfAccuracy: in te vullen door Buildwise
IfcClassificationReference - TDS_link: .\05 As Builtdossier\2. Bouwkunde\2.1 Architectuur\2.1.3 open ruwbouw\TF S 4.3.1.2.5 A - Balken en lateien in gewapend beton.pdf
IfcRoot - Name: 190 x 1000 mm
Qto_BeamBaseQuantities - Length: 3980; CrossSectionArea: 0.19; OuterSurfaceArea: 11.5669; GrossSurfaceArea: 11.9469; NetSurfaceArea: 11.9469; GrossVolume: 0.923409; NetVolume: 0.923409
Pset_BeamCommon - Reference: 190 x 1000 mm; Span: 3980 mm; Slope: 0 rad; Roll: 0 rad; IsExternal: no; LoadBearing: yes; FireRating: EI60
Pset_ConcreteElementGeneral - ConstructionMethod: prefabricated
Pset_Condition - AssessmentCondition: Empty
Pset_EnvironmentalImpactIndicators - Reference: 190 x 1000 mm; sets with these values: 2

# IfcBeam: BB_XX_Betonbalk_ rechthoekig_ center-center_SFB_190 x 1000 mm1, BB_XX_Betonbalk, rechthoekig, center-center_SFB:190 x 1000 mm:34134711
In: 020
PredefinedType: BEAM; Material: BB_Beton_Bestaand
Cpset_Beam - LevelOfAccuracy: in te vullen door Buildwise
IfcClassificationReference - TDS_link: .\05 As Builtdossier\2. Bouwkunde\2.1 Architectuur\2.1.3 open ruwbouw\TF S 4.3.1.2.5 A - Balken en lateien in gewapend beton.pdf
IfcRoot - Name: 190 x 1000 mm
Qto_BeamBaseQuantities - Length: 6302.91; CrossSectionArea: 0.19; OuterSurfaceArea: 15.4527; GrossSurfaceArea: 15.8327; NetSurfaceArea: 15.8327; GrossVolume: 1.23362; NetVolume: 1.23362
Pset_BeamCommon - Reference: 190 x 1000 mm; Span: 6302.91 mm; Slope: 0 rad; Roll: 0 rad; IsExternal: no; LoadBearing: yes; FireRating: EI60
Pset_ConcreteElementGeneral - ConstructionMethod: prefabricated
Pset_Condition - AssessmentCondition: Empty
Pset_EnvironmentalImpactIndicators - Reference: 190 x 1000 mm; sets with these values: 2

# IfcBeam: BB_XX_Betonbalk_ rechthoekig_ center-center_SFB_190 x 1000 mm3, BB_XX_Betonbalk, rechthoekig, center-center_SFB:190 x 1000 mm:34134713
In: 020
PredefinedType: BEAM; Material: BB_Beton_Bestaand
Cpset_Beam - LevelOfAccuracy: in te vullen door Buildwise
IfcClassificationReference - TDS_link: .\05 As Builtdossier\2. Bouwkunde\2.1 Architectuur\2.1.3 open ruwbouw\TF S 4.3.1.2.5 A - Balken en lateien in gewapend beton.pdf
IfcRoot - Name: 190 x 1000 mm
Qto_BeamBaseQuantities - Length: 6304.15; CrossSectionArea: 7.88653; NetSurfaceArea: 15.7731; NetVolume: 1.21671
Pset_BeamCommon - Reference: 190 x 1000 mm; Span: 6304.15 mm; Slope: 0 rad; Roll: 0 rad; IsExternal: no; LoadBearing: yes; FireRating: EI60
Pset_ConcreteElementGeneral - ConstructionMethod: prefabricated
Pset_Condition - AssessmentCondition: Empty
Pset_EnvironmentalImpactIndicators - Reference: 190 x 1000 mm; sets with these values: 2

# IfcBeam: BB_XX_Betonbalk_ rechthoekig_ center-center_SFB_190 x 1100 mm, BB_XX_Betonbalk, rechthoekig, center-center_SFB:190 x 1100 mm:34130107
In: K10
PredefinedType: BEAM; Material: BB_Beton_Bestaand
Cpset_Beam - LevelOfAccuracy: in te vullen door Buildwise
IfcClassificationReference - TDS_link: .\05 As Builtdossier\2. Bouwkunde\2.1 Architectuur\2.1.3 open ruwbouw\TF S 4.3.1.2.5 A - Balken en lateien in gewapend beton.pdf
IfcRoot - Name: 190 x 1100 mm
Qto_BeamBaseQuantities - Length: 5932.08; CrossSectionArea: 6.9058; NetSurfaceArea: 13.8116; NetVolume: 1.01826
Pset_BeamCommon - Reference: 190 x 1100 mm; Span: 5932.08 mm; Slope: 0 rad; Roll: 0 rad; IsExternal: no; LoadBearing: yes; FireRating: EI60
Pset_ConcreteElementGeneral - ConstructionMethod: prefabricated
Pset_Condition - AssessmentCondition: Empty
Pset_EnvironmentalImpactIndicators - Reference: 190 x 1100 mm; sets with these values: 2

# IfcBeam: BB_XX_Betonbalk_ rechthoekig_ center-center_SFB_190 x 1100 mm1, BB_XX_Betonbalk, rechthoekig, center-center_SFB:190 x 1100 mm:34133050
In: 000
PredefinedType: BEAM; Material: BB_Beton_Bestaand
Cpset_Beam - LevelOfAccuracy: in te vullen door Buildwise
IfcClassificationReference - TDS_link: .\05 As Builtdossier\2. Bouwkunde\2.1 Architectuur\2.1.3 open ruwbouw\TF S 4.3.1.2.5 A - Balken en lateien in gewapend beton.pdf
IfcRoot - Name: 190 x 1100 mm
Qto_BeamBaseQuantities - Length: 6299.78; CrossSectionArea: 7.18138; NetSurfaceArea: 14.3628; NetVolume: 1.06411
Pset_BeamCommon - Reference: 190 x 1100 mm; Span: 6299.78 mm; Slope: 0 rad; Roll: 0 rad; IsExternal: no; LoadBearing: yes; FireRating: EI60
Pset_ConcreteElementGeneral - ConstructionMethod: prefabricated
Pset_Condition - AssessmentCondition: Empty
Pset_EnvironmentalImpactIndicators - Reference: 190 x 1100 mm; sets with these values: 2

# IfcBeam: BB_XX_Betonbalk_ rechthoekig_ center-center_SFB_190 x 1180 mm, BB_XX_Betonbalk, rechthoekig, center-center_SFB:190 x 1180 mm:34192602
In: 010
PredefinedType: BEAM; Material: BB_Beton_Bestaand
Cpset_Beam - LevelOfAccuracy: in te vullen door Buildwise
IfcClassificationReference - TDS_link: .\05 As Builtdossier\2. Bouwkunde\2.1 Architectuur\2.1.3 open ruwbouw\TF S 4.3.1.2.5 A - Balken en lateien in gewapend beton.pdf
IfcRoot - Name: 190 x 1180 mm
Qto_BeamBaseQuantities - Length: 5910.08; CrossSectionArea: 6.17394; NetSurfaceArea: 12.3479; NetVolume: 0.887669
Pset_BeamCommon - Reference: 190 x 1180 mm; Span: 5910.08 mm; Slope: 0 rad; Roll: 0 rad; IsExternal: no; LoadBearing: yes; FireRating: EI60
Pset_ConcreteElementGeneral - ConstructionMethod: prefabricated
Pset_Condition - AssessmentCondition: Empty
Pset_EnvironmentalImpactIndicators - Reference: 190 x 1180 mm; sets with these values: 2

# IfcBeam: BB_XX_Betonbalk_ rechthoekig_ center-center_SFB_190 x 1180 mm1, BB_XX_Betonbalk, rechthoekig, center-center_SFB:190 x 1180 mm:34192670
In: 020
PredefinedType: BEAM; Material: BB_Beton_Bestaand
Cpset_Beam - LevelOfAccuracy: in te vullen door Buildwise
IfcClassificationReference - TDS_link: .\05 As Builtdossier\2. Bouwkunde\2.1 Architectuur\2.1.3 open ruwbouw\TF S 4.3.1.2.5 A - Balken en lateien in gewapend beton.pdf
IfcRoot - Name: 190 x 1180 mm
Qto_BeamBaseQuantities - Length: 5910.08; CrossSectionArea: 6.12253; NetSurfaceArea: 12.2451; NetVolume: 0.880017
Pset_BeamCommon - Reference: 190 x 1180 mm; Span: 5910.08 mm; Slope: 0 rad; Roll: 0 rad; IsExternal: no; LoadBearing: yes; FireRating: EI60
Pset_ConcreteElementGeneral - ConstructionMethod: prefabricated
Pset_Condition - AssessmentCondition: Empty
Pset_EnvironmentalImpactIndicators - Reference: 190 x 1180 mm; sets with these values: 2

# IfcBeam: BB_XX_Betonbalk_ rechthoekig_ center-center_SFB_190 x 1200 mm, BB_XX_Betonbalk, rechthoekig, center-center_SFB:190 x 1200 mm:34192735
In: 030
PredefinedType: BEAM; Material: BB_Beton_Bestaand
Cpset_Beam - LevelOfAccuracy: in te vullen door Buildwise
IfcClassificationReference - TDS_link: .\05 As Builtdossier\2. Bouwkunde\2.1 Architectuur\2.1.3 open ruwbouw\TF S 4.3.1.2.5 A - Balken en lateien in gewapend beton.pdf
IfcRoot - Name: 190 x 1200 mm
Qto_BeamBaseQuantities - Length: 5910.08; CrossSectionArea: 6.22346; NetSurfaceArea: 12.4469; NetVolume: 0.896562
Pset_BeamCommon - Reference: 190 x 1200 mm; Span: 5910.08 mm; Slope: 0 rad; Roll: 0 rad; IsExternal: no; LoadBearing: yes; FireRating: EI60
Pset_ConcreteElementGeneral - ConstructionMethod: prefabricated
Pset_Condition - AssessmentCondition: Empty
Pset_EnvironmentalImpactIndicators - Reference: 190 x 1200 mm; sets with these values: 2

# IfcBeam: BB_XX_Betonbalk_ rechthoekig_ center-center_SFB_190 x 1550 mm (4)
PredefinedType: BEAM; Material: BB_Beton_Bestaand
Cpset_Beam - LevelOfAccuracy: in te vullen door Buildwise
IfcRoot - Name: 190 x 1550 mm
Qto_BeamBaseQuantities - Length: 2100; CrossSectionArea: 0.2945; OuterSurfaceArea: 7.308; GrossSurfaceArea: 7.897; NetSurfaceArea: 7.897; GrossVolume: 0.61845; NetVolume: 0.61845
Pset_BeamCommon - Reference: 190 x 1550 mm; Span: 2100 mm; Slope: 0 rad; Roll: 0 rad; IsExternal: no; LoadBearing: yes
Pset_Condition - AssessmentCondition: Empty
Pset_EnvironmentalImpactIndicators - Reference: 190 x 1550 mm; sets with these values: 2
Name (BB_XX_Betonbalk, rechthoekig, center-center_SFB:190 x 1550 mm:...) | In
1369392 | 010
1369343 | 020
1370157 | 030
1032041 | 040

# IfcBeam: BB_XX_Betonbalk_ rechthoekig_ center-center_SFB_190 x 1550 mm1, BB_XX_Betonbalk, rechthoekig, center-center_SFB:190 x 1550 mm:705318
In: 030
PredefinedType: BEAM; Material: BB_Beton_Bestaand
Cpset_Beam - LevelOfAccuracy: in te vullen door Buildwise
IfcRoot - Name: 190 x 1550 mm
Qto_BeamBaseQuantities - Length: 2100; CrossSectionArea: 0.2945; OuterSurfaceArea: 7.308; GrossSurfaceArea: 7.897; NetSurfaceArea: 7.897; GrossVolume: 0.61845; NetVolume: 0.61845
Pset_BeamCommon - Reference: 190 x 1550 mm; Span: 2100 mm; Slope: 0 rad; Roll: 0 rad; IsExternal: no; LoadBearing: yes
Pset_Condition - AssessmentCondition: Empty
Pset_EnvironmentalImpactIndicators - Reference: 190 x 1550 mm; sets with these values: 2

# IfcBeam: BB_XX_Betonbalk_ rechthoekig_ center-center_SFB_190 x 1550 mm3, BB_XX_Betonbalk, rechthoekig, center-center_SFB:190 x 1550 mm:705320
In: 030
PredefinedType: BEAM; Material: BB_Beton_Bestaand
Cpset_Beam - LevelOfAccuracy: in te vullen door Buildwise
IfcRoot - Name: 190 x 1550 mm
Qto_BeamBaseQuantities - Length: 2100; CrossSectionArea: 3.98036; NetSurfaceArea: 7.96072; NetVolume: 0.611496
Pset_BeamCommon - Reference: 190 x 1550 mm; Span: 2100 mm; Slope: 0 rad; Roll: 0 rad; IsExternal: no; LoadBearing: yes
Pset_Condition - AssessmentCondition: Empty
Pset_EnvironmentalImpactIndicators - Reference: 190 x 1550 mm; sets with these values: 2

# IfcBeam: BB_XX_Betonbalk_ rechthoekig_ center-center_SFB_190 x 300 mm, BB_XX_Betonbalk, rechthoekig, center-center_SFB:190 x 300 mm:34063894
In: K10
PredefinedType: BEAM; Material: BB_Beton_Bestaand
Cpset_Beam - LevelOfAccuracy: in te vullen door Buildwise
IfcClassificationReference - TDS_link: .\05 As Builtdossier\2. Bouwkunde\2.1 Architectuur\2.1.3 open ruwbouw\TF S 4.3.1.2.5 A - Balken en lateien in gewapend beton.pdf
IfcRoot - Name: 190 x 300 mm
Qto_BeamBaseQuantities - Length: 5800; CrossSectionArea: 2.21006; NetSurfaceArea: 4.42011; NetVolume: 0.228957
Pset_BeamCommon - Reference: 190 x 300 mm; Span: 5800 mm; Slope: 0 rad; Roll: 0 rad; IsExternal: no; LoadBearing: yes; FireRating: EI60
Pset_ConcreteElementGeneral - ConstructionMethod: prefabricated
Pset_Condition - AssessmentCondition: Empty
Pset_EnvironmentalImpactIndicators - Reference: 190 x 300 mm; sets with these values: 2

# IfcBeam: BB_XX_Betonbalk_ rechthoekig_ center-center_SFB_190 x 400 mm, BB_XX_Betonbalk, rechthoekig, center-center_SFB:190 x 400 mm:34078202
In: 010
PredefinedType: BEAM; Material: BB_Beton_Bestaand
Cpset_Beam - LevelOfAccuracy: in te vullen door Buildwise
IfcClassificationReference - TDS_link: .\05 As Builtdossier\2. Bouwkunde\2.1 Architectuur\2.1.3 open ruwbouw\TF S 4.3.1.2.5 A - Balken en lateien in gewapend beton.pdf
IfcRoot - Name: 190 x 400 mm
Qto_BeamBaseQuantities - Length: 525.066; CrossSectionArea: 0.076; OuterSurfaceArea: 0.664343; GrossSurfaceArea: 0.816343; NetSurfaceArea: 0.816343; GrossVolume: 0.0427882; NetVolume: 0.0427882
Pset_BeamCommon - Reference: 190 x 400 mm; Span: 525.066 mm; Slope: 0 rad; Roll: 0 rad; IsExternal: no; LoadBearing: yes; FireRating: EI60
Pset_ConcreteElementGeneral - ConstructionMethod: prefabricated
Pset_Condition - AssessmentCondition: Empty
Pset_EnvironmentalImpactIndicators - Reference: 190 x 400 mm; sets with these values: 2

# IfcBeam: BB_XX_Betonbalk_ rechthoekig_ center-center_SFB_190 x 400 mm1, BB_XX_Betonbalk, rechthoekig, center-center_SFB:190 x 400 mm:34078204
In: 010
PredefinedType: BEAM; Material: BB_Beton_Bestaand
Cpset_Beam - LevelOfAccuracy: in te vullen door Buildwise
IfcClassificationReference - TDS_link: .\05 As Builtdossier\2. Bouwkunde\2.1 Architectuur\2.1.3 open ruwbouw\TF S 4.3.1.2.5 A - Balken en lateien in gewapend beton.pdf
IfcRoot - Name: 190 x 400 mm
Qto_BeamBaseQuantities - Length: 3720; CrossSectionArea: 0.076; OuterSurfaceArea: 4.2119; GrossSurfaceArea: 4.3639; NetSurfaceArea: 4.3639; GrossVolume: 0.271275; NetVolume: 0.271275
Pset_BeamCommon - Reference: 190 x 400 mm; Span: 3720 mm; Slope: 0 rad; Roll: 0 rad; IsExternal: no; LoadBearing: yes; FireRating: EI60
Pset_ConcreteElementGeneral - ConstructionMethod: prefabricated
Pset_Condition - AssessmentCondition: Empty
Pset_EnvironmentalImpactIndicators - Reference: 190 x 400 mm; sets with these values: 2

# IfcBeam: BB_XX_Betonbalk_ rechthoekig_ center-center_SFB_190 x 400 mm11, BB_XX_Betonbalk, rechthoekig, center-center_SFB:190 x 400 mm:34192662
In: 020
PredefinedType: BEAM; Material: BB_Beton_Bestaand
Cpset_Beam - LevelOfAccuracy: in te vullen door Buildwise
IfcClassificationReference - TDS_link: .\05 As Builtdossier\2. Bouwkunde\2.1 Architectuur\2.1.3 open ruwbouw\TF S 4.3.1.2.5 A - Balken en lateien in gewapend beton.pdf
IfcRoot - Name: 190 x 400 mm
Qto_BeamBaseQuantities - Length: 525.066; CrossSectionArea: 0.393719; NetSurfaceArea: 0.787438; NetVolume: 0.0369862
Pset_BeamCommon - Reference: 190 x 400 mm; Span: 525.066 mm; Slope: 0 rad; Roll: 0 rad; IsExternal: no; LoadBearing: yes; FireRating: EI60
Pset_ConcreteElementGeneral - ConstructionMethod: prefabricated
Pset_Condition - AssessmentCondition: Empty
Pset_EnvironmentalImpactIndicators - Reference: 190 x 400 mm; sets with these values: 2

# IfcBeam: BB_XX_Betonbalk_ rechthoekig_ center-center_SFB_190 x 400 mm13, BB_XX_Betonbalk, rechthoekig, center-center_SFB:190 x 400 mm:34192664
In: 020
PredefinedType: BEAM; Material: BB_Beton_Bestaand
Cpset_Beam - LevelOfAccuracy: in te vullen door Buildwise
IfcClassificationReference - TDS_link: .\05 As Builtdossier\2. Bouwkunde\2.1 Architectuur\2.1.3 open ruwbouw\TF S 4.3.1.2.5 A - Balken en lateien in gewapend beton.pdf
IfcRoot - Name: 190 x 400 mm
Qto_BeamBaseQuantities - Length: 3720; CrossSectionArea: 0.076; OuterSurfaceArea: 4.20013; GrossSurfaceArea: 4.35213; NetSurfaceArea: 4.35213; GrossVolume: 0.270517; NetVolume: 0.270517
Pset_BeamCommon - Reference: 190 x 400 mm; Span: 3720 mm; Slope: 0 rad; Roll: 0 rad; IsExternal: no; LoadBearing: yes; FireRating: EI60
Pset_ConcreteElementGeneral - ConstructionMethod: prefabricated
Pset_Condition - AssessmentCondition: Empty
Pset_EnvironmentalImpactIndicators - Reference: 190 x 400 mm; sets with these values: 2

# IfcBeam: BB_XX_Betonbalk_ rechthoekig_ center-center_SFB_190 x 400 mm15, BB_XX_Betonbalk, rechthoekig, center-center_SFB:190 x 400 mm:34192666
In: 020
PredefinedType: BEAM; Material: BB_Beton_Bestaand
Cpset_Beam - LevelOfAccuracy: in te vullen door Buildwise
IfcClassificationReference - TDS_link: .\05 As Builtdossier\2. Bouwkunde\2.1 Architectuur\2.1.3 open ruwbouw\TF S 4.3.1.2.5 A - Balken en lateien in gewapend beton.pdf
IfcRoot - Name: 190 x 400 mm
Qto_BeamBaseQuantities - Length: 500; CrossSectionArea: 0.387422; NetSurfaceArea: 0.774844; NetVolume: 0.0361114
Pset_BeamCommon - Reference: 190 x 400 mm; Span: 500 mm; Slope: 0 rad; Roll: 0 rad; IsExternal: no; LoadBearing: yes; FireRating: EI60
Pset_ConcreteElementGeneral - ConstructionMethod: prefabricated
Pset_Condition - AssessmentCondition: Empty
Pset_EnvironmentalImpactIndicators - Reference: 190 x 400 mm; sets with these values: 2

# IfcBeam: BB_XX_Betonbalk_ rechthoekig_ center-center_SFB_190 x 400 mm17, BB_XX_Betonbalk, rechthoekig, center-center_SFB:190 x 400 mm:34192668
In: 020
PredefinedType: BEAM; Material: BB_Beton_Bestaand
Cpset_Beam - LevelOfAccuracy: in te vullen door Buildwise
IfcClassificationReference - TDS_link: .\05 As Builtdossier\2. Bouwkunde\2.1 Architectuur\2.1.3 open ruwbouw\TF S 4.3.1.2.5 A - Balken en lateien in gewapend beton.pdf
IfcRoot - Name: 190 x 400 mm
Qto_BeamBaseQuantities - Length: 3720; CrossSectionArea: 0.076; OuterSurfaceArea: 4.1879; GrossSurfaceArea: 4.3399; NetSurfaceArea: 4.3399; GrossVolume: 0.269729; NetVolume: 0.269729
Pset_BeamCommon - Reference: 190 x 400 mm; Span: 3720 mm; Slope: 0 rad; Roll: 0 rad; IsExternal: no; LoadBearing: yes; FireRating: EI60
Pset_ConcreteElementGeneral - ConstructionMethod: prefabricated
Pset_Condition - AssessmentCondition: Empty
Pset_EnvironmentalImpactIndicators - Reference: 190 x 400 mm; sets with these values: 2

# IfcBeam: BB_XX_Betonbalk_ rechthoekig_ center-center_SFB_190 x 400 mm19, BB_XX_Betonbalk, rechthoekig, center-center_SFB:190 x 400 mm:705461
In: 030
PredefinedType: BEAM; Material: BB_Beton_Bestaand
Cpset_Beam - LevelOfAccuracy: in te vullen door Buildwise
IfcRoot - Name: 190 x 400 mm
Qto_BeamBaseQuantities - Length: 4384.06; CrossSectionArea: 0.076; OuterSurfaceArea: 5.17319; GrossSurfaceArea: 5.32519; NetSurfaceArea: 5.32519; GrossVolume: 0.333189; NetVolume: 0.333189
Pset_BeamCommon - Reference: 190 x 400 mm; Span: 4384.06 mm; Slope: 0 rad; Roll: 0 rad; IsExternal: no; LoadBearing: yes
Pset_Condition - AssessmentCondition: Empty
Pset_EnvironmentalImpactIndicators - Reference: 190 x 400 mm; sets with these values: 2

# IfcBeam: BB_XX_Betonbalk_ rechthoekig_ center-center_SFB_190 x 400 mm21, BB_XX_Betonbalk, rechthoekig, center-center_SFB:190 x 400 mm:705463
In: 030
PredefinedType: BEAM; Material: BB_Beton_Bestaand
Cpset_Beam - LevelOfAccuracy: in te vullen door Buildwise
IfcRoot - Name: 190 x 400 mm
Qto_BeamBaseQuantities - Length: 4384.06; CrossSectionArea: 2.62229; NetSurfaceArea: 5.24457; NetVolume: 0.325969
Pset_BeamCommon - Reference: 190 x 400 mm; Span: 4384.06 mm; Slope: 0 rad; Roll: 0 rad; IsExternal: no; LoadBearing: yes
Pset_Condition - AssessmentCondition: Empty
Pset_EnvironmentalImpactIndicators - Reference: 190 x 400 mm; sets with these values: 2

# IfcBeam: BB_XX_Betonbalk_ rechthoekig_ center-center_SFB_190 x 400 mm23, BB_XX_Betonbalk, rechthoekig, center-center_SFB:190 x 400 mm:34083359
In: 030
PredefinedType: BEAM; Material: BB_Beton_Bestaand
Cpset_Beam - LevelOfAccuracy: in te vullen door Buildwise
IfcClassificationReference - TDS_link: .\05 As Builtdossier\2. Bouwkunde\2.1 Architectuur\2.1.3 open ruwbouw\TF S 4.3.1.2.5 A - Balken en lateien in gewapend beton.pdf
IfcRoot - Name: 190 x 400 mm
Qto_BeamBaseQuantities - Length: 525.441; CrossSectionArea: 0.076; OuterSurfaceArea: 0.666468; GrossSurfaceArea: 0.818468; NetSurfaceArea: 0.818468; GrossVolume: 0.042925; NetVolume: 0.042925
Pset_BeamCommon - Reference: 190 x 400 mm; Span: 525.441 mm; Slope: 0 rad; Roll: 0 rad; IsExternal: no; LoadBearing: yes; FireRating: EI60
Pset_ConcreteElementGeneral - ConstructionMethod: prefabricated
Pset_Condition - AssessmentCondition: Empty
Pset_EnvironmentalImpactIndicators - Reference: 190 x 400 mm; sets with these values: 2

# IfcBeam: BB_XX_Betonbalk_ rechthoekig_ center-center_SFB_190 x 400 mm25, BB_XX_Betonbalk, rechthoekig, center-center_SFB:190 x 400 mm:34083363
In: 030
PredefinedType: BEAM; Material: BB_Beton_Bestaand
Cpset_Beam - LevelOfAccuracy: in te vullen door Buildwise
IfcClassificationReference - TDS_link: .\05 As Builtdossier\2. Bouwkunde\2.1 Architectuur\2.1.3 open ruwbouw\TF S 4.3.1.2.5 A - Balken en lateien in gewapend beton.pdf
IfcRoot - Name: 190 x 400 mm
Qto_BeamBaseQuantities - Length: 500.376; CrossSectionArea: 0.076; OuterSurfaceArea: 0.659614; GrossSurfaceArea: 0.811614; NetSurfaceArea: 0.811614; GrossVolume: 0.0424836; NetVolume: 0.0424836
Pset_BeamCommon - Reference: 190 x 400 mm; Span: 500.376 mm; Slope: 0 rad; Roll: 0 rad; IsExternal: no; LoadBearing: yes; FireRating: EI60
Pset_ConcreteElementGeneral - ConstructionMethod: prefabricated
Pset_Condition - AssessmentCondition: Empty
Pset_EnvironmentalImpactIndicators - Reference: 190 x 400 mm; sets with these values: 2

# IfcBeam: BB_XX_Betonbalk_ rechthoekig_ center-center_SFB_190 x 400 mm27, BB_XX_Betonbalk, rechthoekig, center-center_SFB:190 x 400 mm:34141081
In: 030
PredefinedType: BEAM; Material: BB_Beton_Bestaand
Cpset_Beam - LevelOfAccuracy: in te vullen door Buildwise
IfcClassificationReference - TDS_link: .\05 As Builtdossier\2. Bouwkunde\2.1 Architectuur\2.1.3 open ruwbouw\TF S 4.3.1.2.5 A - Balken en lateien in gewapend beton.pdf
IfcRoot - Name: 190 x 400 mm
Qto_BeamBaseQuantities - Length: 6317.06; CrossSectionArea: 0.076; OuterSurfaceArea: 7.69204; GrossSurfaceArea: 7.84404; NetSurfaceArea: 7.84404; GrossVolume: 0.495419; NetVolume: 0.495419
Pset_BeamCommon - Reference: 190 x 400 mm; Span: 6317.06 mm; Slope: 0 rad; Roll: 0 rad; IsExternal: no; LoadBearing: yes; FireRating: EI60
Pset_ConcreteElementGeneral - ConstructionMethod: prefabricated
Pset_Condition - AssessmentCondition: Empty
Pset_EnvironmentalImpactIndicators - Reference: 190 x 400 mm; sets with these values: 2

# IfcBeam: BB_XX_Betonbalk_ rechthoekig_ center-center_SFB_190 x 400 mm29, BB_XX_Betonbalk, rechthoekig, center-center_SFB:190 x 400 mm:34141083
In: 030
PredefinedType: BEAM; Material: BB_Beton_Bestaand
Cpset_Beam - LevelOfAccuracy: in te vullen door Buildwise
IfcClassificationReference - TDS_link: .\05 As Builtdossier\2. Bouwkunde\2.1 Architectuur\2.1.3 open ruwbouw\TF S 4.3.1.2.5 A - Balken en lateien in gewapend beton.pdf
IfcRoot - Name: 190 x 400 mm
Qto_BeamBaseQuantities - Length: 6304.15; CrossSectionArea: 3.88655; NetSurfaceArea: 7.7731; NetVolume: 0.487011
Pset_BeamCommon - Reference: 190 x 400 mm; Span: 6304.15 mm; Slope: 0 rad; Roll: 0 rad; IsExternal: no; LoadBearing: yes; FireRating: EI60
Pset_ConcreteElementGeneral - ConstructionMethod: prefabricated
Pset_Condition - AssessmentCondition: Empty
Pset_EnvironmentalImpactIndicators - Reference: 190 x 400 mm; sets with these values: 2

# IfcBeam: BB_XX_Betonbalk_ rechthoekig_ center-center_SFB_190 x 400 mm3, BB_XX_Betonbalk, rechthoekig, center-center_SFB:190 x 400 mm:34078206
In: 010
PredefinedType: BEAM; Material: BB_Beton_Bestaand
Cpset_Beam - LevelOfAccuracy: in te vullen door Buildwise
IfcClassificationReference - TDS_link: .\05 As Builtdossier\2. Bouwkunde\2.1 Architectuur\2.1.3 open ruwbouw\TF S 4.3.1.2.5 A - Balken en lateien in gewapend beton.pdf
IfcRoot - Name: 190 x 400 mm
Qto_BeamBaseQuantities - Length: 500; CrossSectionArea: 0.387422; NetSurfaceArea: 0.774844; NetVolume: 0.0361114
Pset_BeamCommon - Reference: 190 x 400 mm; Span: 500 mm; Slope: 0 rad; Roll: 0 rad; IsExternal: no; LoadBearing: yes; FireRating: EI60
Pset_ConcreteElementGeneral - ConstructionMethod: prefabricated
Pset_Condition - AssessmentCondition: Empty
Pset_EnvironmentalImpactIndicators - Reference: 190 x 400 mm; sets with these values: 2

# IfcBeam: BB_XX_Betonbalk_ rechthoekig_ center-center_SFB_190 x 400 mm31, BB_XX_Betonbalk, rechthoekig, center-center_SFB:190 x 400 mm:34192727
In: 030
PredefinedType: BEAM; Material: BB_Beton_Bestaand
Cpset_Beam - LevelOfAccuracy: in te vullen door Buildwise
IfcClassificationReference - TDS_link: .\05 As Builtdossier\2. Bouwkunde\2.1 Architectuur\2.1.3 open ruwbouw\TF S 4.3.1.2.5 A - Balken en lateien in gewapend beton.pdf
IfcRoot - Name: 190 x 400 mm
Qto_BeamBaseQuantities - Length: 525.066; CrossSectionArea: 0.393719; NetSurfaceArea: 0.787438; NetVolume: 0.0369862
Pset_BeamCommon - Reference: 190 x 400 mm; Span: 525.066 mm; Slope: 0 rad; Roll: 0 rad; IsExternal: no; LoadBearing: yes; FireRating: EI60
Pset_ConcreteElementGeneral - ConstructionMethod: prefabricated
Pset_Condition - AssessmentCondition: Empty
Pset_EnvironmentalImpactIndicators - Reference: 190 x 400 mm; sets with these values: 2

# IfcBeam: BB_XX_Betonbalk_ rechthoekig_ center-center_SFB_190 x 400 mm33, BB_XX_Betonbalk, rechthoekig, center-center_SFB:190 x 400 mm:34192729
In: 030
PredefinedType: BEAM; Material: BB_Beton_Bestaand
Cpset_Beam - LevelOfAccuracy: in te vullen door Buildwise
IfcClassificationReference - TDS_link: .\05 As Builtdossier\2. Bouwkunde\2.1 Architectuur\2.1.3 open ruwbouw\TF S 4.3.1.2.5 A - Balken en lateien in gewapend beton.pdf
IfcRoot - Name: 190 x 400 mm
Qto_BeamBaseQuantities - Length: 3720; CrossSectionArea: 0.076; OuterSurfaceArea: 4.43652; GrossSurfaceArea: 4.58852; NetSurfaceArea: 4.58852; GrossVolume: 0.285742; NetVolume: 0.285742
Pset_BeamCommon - Reference: 190 x 400 mm; Span: 3720 mm; Slope: 0 rad; Roll: 0 rad; IsExternal: no; LoadBearing: yes; FireRating: EI60
Pset_ConcreteElementGeneral - ConstructionMethod: prefabricated
Pset_Condition - AssessmentCondition: Empty
Pset_EnvironmentalImpactIndicators - Reference: 190 x 400 mm; sets with these values: 2

# IfcBeam: BB_XX_Betonbalk_ rechthoekig_ center-center_SFB_190 x 400 mm35, BB_XX_Betonbalk, rechthoekig, center-center_SFB:190 x 400 mm:34192731
In: 030
PredefinedType: BEAM; Material: BB_Beton_Bestaand
Cpset_Beam - LevelOfAccuracy: in te vullen door Buildwise
IfcClassificationReference - TDS_link: .\05 As Builtdossier\2. Bouwkunde\2.1 Architectuur\2.1.3 open ruwbouw\TF S 4.3.1.2.5 A - Balken en lateien in gewapend beton.pdf
IfcRoot - Name: 190 x 400 mm
Qto_BeamBaseQuantities - Length: 500; CrossSectionArea: 0.387422; NetSurfaceArea: 0.774844; NetVolume: 0.0361114
Pset_BeamCommon - Reference: 190 x 400 mm; Span: 500 mm; Slope: 0 rad; Roll: 0 rad; IsExternal: no; LoadBearing: yes; FireRating: EI60
Pset_ConcreteElementGeneral - ConstructionMethod: prefabricated
Pset_Condition - AssessmentCondition: Empty
Pset_EnvironmentalImpactIndicators - Reference: 190 x 400 mm; sets with these values: 2

# IfcBeam: BB_XX_Betonbalk_ rechthoekig_ center-center_SFB_190 x 400 mm37, BB_XX_Betonbalk, rechthoekig, center-center_SFB:190 x 400 mm:34192733
In: 030
PredefinedType: BEAM; Material: BB_Beton_Bestaand
Cpset_Beam - LevelOfAccuracy: in te vullen door Buildwise
IfcClassificationReference - TDS_link: .\05 As Builtdossier\2. Bouwkunde\2.1 Architectuur\2.1.3 open ruwbouw\TF S 4.3.1.2.5 A - Balken en lateien in gewapend beton.pdf
IfcRoot - Name: 190 x 400 mm
Qto_BeamBaseQuantities - Length: 3720; CrossSectionArea: 0.076; OuterSurfaceArea: 4.32126; GrossSurfaceArea: 4.47326; NetSurfaceArea: 4.47326; GrossVolume: 0.278319; NetVolume: 0.278319
Pset_BeamCommon - Reference: 190 x 400 mm; Span: 3720 mm; Slope: 0 rad; Roll: 0 rad; IsExternal: no; LoadBearing: yes; FireRating: EI60
Pset_ConcreteElementGeneral - ConstructionMethod: prefabricated
Pset_Condition - AssessmentCondition: Empty
Pset_EnvironmentalImpactIndicators - Reference: 190 x 400 mm; sets with these values: 2

# IfcBeam: BB_XX_Betonbalk_ rechthoekig_ center-center_SFB_190 x 400 mm39, BB_XX_Betonbalk, rechthoekig, center-center_SFB:190 x 400 mm:34084461
In: 040
PredefinedType: BEAM; Material: BB_Beton_Bestaand
Cpset_Beam - LevelOfAccuracy: in te vullen door Buildwise
IfcClassificationReference - TDS_link: .\05 As Builtdossier\2. Bouwkunde\2.1 Architectuur\2.1.3 open ruwbouw\TF S 4.3.1.2.5 A - Balken en lateien in gewapend beton.pdf
IfcRoot - Name: 190 x 400 mm
Qto_BeamBaseQuantities - Length: 620.445; CrossSectionArea: 0.076; OuterSurfaceArea: 0.651486; GrossSurfaceArea: 0.803486; NetSurfaceArea: 0.803486; GrossVolume: 0.0419601; NetVolume: 0.0419601
Pset_BeamCommon - Reference: 190 x 400 mm; Span: 620.445 mm; Slope: 0 rad; Roll: 0 rad; IsExternal: no; LoadBearing: yes; FireRating: EI60
Pset_ConcreteElementGeneral - ConstructionMethod: prefabricated
Pset_Condition - AssessmentCondition: Empty
Pset_EnvironmentalImpactIndicators - Reference: 190 x 400 mm; sets with these values: 2

# IfcBeam: BB_XX_Betonbalk_ rechthoekig_ center-center_SFB_190 x 400 mm41, BB_XX_Betonbalk, rechthoekig, center-center_SFB:190 x 400 mm:34084465
In: 040
PredefinedType: BEAM; Material: BB_Beton_Bestaand
Cpset_Beam - LevelOfAccuracy: in te vullen door Buildwise
IfcClassificationReference - TDS_link: .\05 As Builtdossier\2. Bouwkunde\2.1 Architectuur\2.1.3 open ruwbouw\TF S 4.3.1.2.5 A - Balken en lateien in gewapend beton.pdf
IfcRoot - Name: 190 x 400 mm
Qto_BeamBaseQuantities - Length: 500.376; CrossSectionArea: 0.076; OuterSurfaceArea: 0.659614; GrossSurfaceArea: 0.811614; NetSurfaceArea: 0.811614; GrossVolume: 0.0424836; NetVolume: 0.0424836
Pset_BeamCommon - Reference: 190 x 400 mm; Span: 500.376 mm; Slope: 0 rad; Roll: 0 rad; IsExternal: no; LoadBearing: yes; FireRating: EI60
Pset_ConcreteElementGeneral - ConstructionMethod: prefabricated
Pset_Condition - AssessmentCondition: Empty
Pset_EnvironmentalImpactIndicators - Reference: 190 x 400 mm; sets with these values: 2

# IfcBeam: BB_XX_Betonbalk_ rechthoekig_ center-center_SFB_190 x 400 mm43, BB_XX_Betonbalk, rechthoekig, center-center_SFB:190 x 400 mm:34141285
In: 040
PredefinedType: BEAM; Material: BB_Beton_Bestaand
Cpset_Beam - LevelOfAccuracy: in te vullen door Buildwise
IfcClassificationReference - TDS_link: .\05 As Builtdossier\2. Bouwkunde\2.1 Architectuur\2.1.3 open ruwbouw\TF S 4.3.1.2.5 A - Balken en lateien in gewapend beton.pdf
IfcRoot - Name: 190 x 400 mm
Qto_BeamBaseQuantities - Length: 6317.06; CrossSectionArea: 0.076; OuterSurfaceArea: 7.69204; GrossSurfaceArea: 7.84404; NetSurfaceArea: 7.84404; GrossVolume: 0.495419; NetVolume: 0.495419
Pset_BeamCommon - Reference: 190 x 400 mm; Span: 6317.06 mm; Slope: 0 rad; Roll: 0 rad; IsExternal: no; LoadBearing: yes
Pset_ConcreteElementGeneral - ConstructionMethod: prefabricated
Pset_Condition - AssessmentCondition: Empty
Pset_EnvironmentalImpactIndicators - Reference: 190 x 400 mm; sets with these values: 2

# IfcBeam: BB_XX_Betonbalk_ rechthoekig_ center-center_SFB_190 x 400 mm45, BB_XX_Betonbalk, rechthoekig, center-center_SFB:190 x 400 mm:34141287
In: 040
PredefinedType: BEAM; Material: BB_Beton_Bestaand
Cpset_Beam - LevelOfAccuracy: in te vullen door Buildwise
IfcClassificationReference - TDS_link: .\05 As Builtdossier\2. Bouwkunde\2.1 Architectuur\2.1.3 open ruwbouw\TF S 4.3.1.2.5 A - Balken en lateien in gewapend beton.pdf
IfcRoot - Name: 190 x 400 mm
Qto_BeamBaseQuantities - Length: 6318.3; CrossSectionArea: 0.076; OuterSurfaceArea: 7.67487; GrossSurfaceArea: 7.82687; NetSurfaceArea: 7.82687; GrossVolume: 0.494314; NetVolume: 0.494314
Pset_BeamCommon - Reference: 190 x 400 mm; Span: 6318.3 mm; Slope: 0 rad; Roll: 0 rad; IsExternal: no; LoadBearing: yes
Pset_ConcreteElementGeneral - ConstructionMethod: prefabricated
Pset_Condition - AssessmentCondition: Empty
Pset_EnvironmentalImpactIndicators - Reference: 190 x 400 mm; sets with these values: 2

# IfcBeam: BB_XX_Betonbalk_ rechthoekig_ center-center_SFB_190 x 400 mm47, BB_XX_Betonbalk, rechthoekig, center-center_SFB:190 x 400 mm:34193868
In: 040
PredefinedType: BEAM; Material: BB_Beton_Bestaand
Cpset_Beam - LevelOfAccuracy: in te vullen door Buildwise
IfcClassificationReference - TDS_link: .\05 As Builtdossier\2. Bouwkunde\2.1 Architectuur\2.1.3 open ruwbouw\TF S 4.3.1.2.5 A - Balken en lateien in gewapend beton.pdf
IfcRoot - Name: 190 x 400 mm
Qto_BeamBaseQuantities - Length: 3720; CrossSectionArea: 0.076; OuterSurfaceArea: 4.43652; GrossSurfaceArea: 4.58852; NetSurfaceArea: 4.58852; GrossVolume: 0.285742; NetVolume: 0.285742
Pset_BeamCommon - Reference: 190 x 400 mm; Span: 3720 mm; Slope: 0 rad; Roll: 0 rad; IsExternal: no; LoadBearing: yes; FireRating: EI60
Pset_ConcreteElementGeneral - ConstructionMethod: prefabricated
Pset_Condition - AssessmentCondition: Empty
Pset_EnvironmentalImpactIndicators - Reference: 190 x 400 mm; sets with these values: 2

# IfcBeam: BB_XX_Betonbalk_ rechthoekig_ center-center_SFB_190 x 400 mm49, BB_XX_Betonbalk, rechthoekig, center-center_SFB:190 x 400 mm:34193870
In: 040
PredefinedType: BEAM; Material: BB_Beton_Bestaand
Cpset_Beam - LevelOfAccuracy: in te vullen door Buildwise
IfcClassificationReference - TDS_link: .\05 As Builtdossier\2. Bouwkunde\2.1 Architectuur\2.1.3 open ruwbouw\TF S 4.3.1.2.5 A - Balken en lateien in gewapend beton.pdf
IfcRoot - Name: 190 x 400 mm
Qto_BeamBaseQuantities - Length: 3720; CrossSectionArea: 0.076; OuterSurfaceArea: 4.58146; GrossSurfaceArea: 4.73346; NetSurfaceArea: 4.73346; GrossVolume: 0.295077; NetVolume: 0.295077
Pset_BeamCommon - Reference: 190 x 400 mm; Span: 3720 mm; Slope: 0 rad; Roll: 0 rad; IsExternal: no; LoadBearing: yes; FireRating: EI60
Pset_ConcreteElementGeneral - ConstructionMethod: prefabricated
Pset_Condition - AssessmentCondition: Empty
Pset_EnvironmentalImpactIndicators - Reference: 190 x 400 mm; sets with these values: 2

# IfcBeam: BB_XX_Betonbalk_ rechthoekig_ center-center_SFB_190 x 400 mm5, BB_XX_Betonbalk, rechthoekig, center-center_SFB:190 x 400 mm:34192594
In: 010
PredefinedType: BEAM; Material: BB_Beton_Bestaand
Cpset_Beam - LevelOfAccuracy: in te vullen door Buildwise
IfcClassificationReference - TDS_link: .\05 As Builtdossier\2. Bouwkunde\2.1 Architectuur\2.1.3 open ruwbouw\TF S 4.3.1.2.5 A - Balken en lateien in gewapend beton.pdf
IfcRoot - Name: 190 x 400 mm
Qto_BeamBaseQuantities - Length: 525.066; CrossSectionArea: 0.393719; NetSurfaceArea: 0.787438; NetVolume: 0.0369862
Pset_BeamCommon - Reference: 190 x 400 mm; Span: 525.066 mm; Slope: 0 rad; Roll: 0 rad; IsExternal: no; LoadBearing: yes; FireRating: EI60
Pset_ConcreteElementGeneral - ConstructionMethod: prefabricated
Pset_Condition - AssessmentCondition: Empty
Pset_EnvironmentalImpactIndicators - Reference: 190 x 400 mm; sets with these values: 2

# IfcBeam: BB_XX_Betonbalk_ rechthoekig_ center-center_SFB_190 x 400 mm7, BB_XX_Betonbalk, rechthoekig, center-center_SFB:190 x 400 mm:34192598
In: 010
PredefinedType: BEAM; Material: BB_Beton_Bestaand
Cpset_Beam - LevelOfAccuracy: in te vullen door Buildwise
IfcClassificationReference - TDS_link: .\05 As Builtdossier\2. Bouwkunde\2.1 Architectuur\2.1.3 open ruwbouw\TF S 4.3.1.2.5 A - Balken en lateien in gewapend beton.pdf
IfcRoot - Name: 190 x 400 mm
Qto_BeamBaseQuantities - Length: 500; CrossSectionArea: 0.076; OuterSurfaceArea: 0.651479; GrossSurfaceArea: 0.803479; NetSurfaceArea: 0.803479; GrossVolume: 0.0419596; NetVolume: 0.0419596
Pset_BeamCommon - Reference: 190 x 400 mm; Span: 500 mm; Slope: 0 rad; Roll: 0 rad; IsExternal: no; LoadBearing: yes; FireRating: EI60
Pset_ConcreteElementGeneral - ConstructionMethod: prefabricated
Pset_Condition - AssessmentCondition: Empty
Pset_EnvironmentalImpactIndicators - Reference: 190 x 400 mm; sets with these values: 2

# IfcBeam: BB_XX_Betonbalk_ rechthoekig_ center-center_SFB_190 x 400 mm9, BB_XX_Betonbalk, rechthoekig, center-center_SFB:190 x 400 mm:34192600
In: 010
PredefinedType: BEAM; Material: BB_Beton_Bestaand
Cpset_Beam - LevelOfAccuracy: in te vullen door Buildwise
IfcClassificationReference - TDS_link: .\05 As Builtdossier\2. Bouwkunde\2.1 Architectuur\2.1.3 open ruwbouw\TF S 4.3.1.2.5 A - Balken en lateien in gewapend beton.pdf
IfcRoot - Name: 190 x 400 mm
Qto_BeamBaseQuantities - Length: 3720; CrossSectionArea: 0.076; OuterSurfaceArea: 4.30042; GrossSurfaceArea: 4.45242; NetSurfaceArea: 4.45242; GrossVolume: 0.276976; NetVolume: 0.276976
Pset_BeamCommon - Reference: 190 x 400 mm; Span: 3720 mm; Slope: 0 rad; Roll: 0 rad; IsExternal: no; LoadBearing: yes; FireRating: EI60
Pset_ConcreteElementGeneral - ConstructionMethod: prefabricated
Pset_Condition - AssessmentCondition: Empty
Pset_EnvironmentalImpactIndicators - Reference: 190 x 400 mm; sets with these values: 2

# IfcBeam: BB_XX_Betonbalk_ rechthoekig_ center-center_SFB_190 x 450 mm, BB_XX_Betonbalk, rechthoekig, center-center_SFB:190 x 450 mm:981901
In: K20
PredefinedType: BEAM; Material: BB_Beton_Bestaand
Cpset_Beam - LevelOfAccuracy: in te vullen door Buildwise
IfcRoot - Name: 190 x 450 mm
Qto_BeamBaseQuantities - Length: 1900; CrossSectionArea: 0.0855; OuterSurfaceArea: 2.432; GrossSurfaceArea: 2.603; NetSurfaceArea: 2.603; GrossVolume: 0.16245; NetVolume: 0.16245
Pset_BeamCommon - Reference: 190 x 450 mm; Span: 1900 mm; Slope: 0 rad; Roll: 0 rad; IsExternal: no; LoadBearing: yes
Pset_Condition - AssessmentCondition: Empty
Pset_EnvironmentalImpactIndicators - Reference: 190 x 450 mm; sets with these values: 2

# IfcBeam: BB_XX_Betonbalk_ rechthoekig_ center-center_SFB_190 x 450 mm1, BB_XX_Betonbalk, rechthoekig, center-center_SFB:190 x 450 mm:1002426
In: K20
PredefinedType: BEAM; Material: BB_Beton_Bestaand
Cpset_Beam - LevelOfAccuracy: in te vullen door Buildwise
IfcRoot - Name: 190 x 450 mm
Qto_BeamBaseQuantities - Length: 1900; CrossSectionArea: 0.0855; OuterSurfaceArea: 2.432; GrossSurfaceArea: 2.603; NetSurfaceArea: 2.603; GrossVolume: 0.16245; NetVolume: 0.16245
Pset_BeamCommon - Reference: 190 x 450 mm; Span: 1900 mm; Slope: 0 rad; Roll: 0 rad; IsExternal: no; LoadBearing: yes
Pset_Condition - AssessmentCondition: Empty
Pset_EnvironmentalImpactIndicators - Reference: 190 x 450 mm; sets with these values: 2

# IfcBeam: BB_XX_Betonbalk_ rechthoekig_ center-center_SFB_190 x 500 mm, BB_XX_Betonbalk, rechthoekig, center-center_SFB:190 x 500 mm:892895
In: K10
PredefinedType: BEAM; Material: BB_Beton_Bestaand
Cpset_Beam - LevelOfAccuracy: in te vullen door Buildwise
IfcRoot - Name: 190 x 500 mm
Qto_BeamBaseQuantities - Length: 2900; CrossSectionArea: 0.095; OuterSurfaceArea: 4.002; GrossSurfaceArea: 4.192; NetSurfaceArea: 4.192; GrossVolume: 0.2755; NetVolume: 0.2755
Pset_BeamCommon - Reference: 190 x 500 mm; Span: 2900 mm; Slope: 0 rad; Roll: 0 rad; IsExternal: no; LoadBearing: yes
Pset_Condition - AssessmentCondition: Empty
Pset_EnvironmentalImpactIndicators - Reference: 190 x 500 mm; sets with these values: 2

# IfcBeam: BB_XX_Betonbalk_ rechthoekig_ center-center_SFB_190 x 500 mm1, BB_XX_Betonbalk, rechthoekig, center-center_SFB:190 x 500 mm:893435
In: K10
PredefinedType: BEAM; Material: BB_Beton_Bestaand
Cpset_Beam - LevelOfAccuracy: in te vullen door Buildwise
IfcRoot - Name: 190 x 500 mm
Qto_BeamBaseQuantities - Length: 2910; CrossSectionArea: 0.095; OuterSurfaceArea: 4.0158; GrossSurfaceArea: 4.2058; NetSurfaceArea: 4.2058; GrossVolume: 0.27645; NetVolume: 0.27645
Pset_BeamCommon - Reference: 190 x 500 mm; Span: 2910 mm; Slope: 0 rad; Roll: 0 rad; IsExternal: no; LoadBearing: yes
Pset_Condition - AssessmentCondition: Empty
Pset_EnvironmentalImpactIndicators - Reference: 190 x 500 mm; sets with these values: 2

# IfcBeam: BB_XX_Betonbalk_ rechthoekig_ center-center_SFB_190 x 500 mm3, BB_XX_Betonbalk, rechthoekig, center-center_SFB:190 x 500 mm:893806
In: K10
PredefinedType: BEAM; Material: BB_Beton_Bestaand
Cpset_Beam - LevelOfAccuracy: in te vullen door Buildwise
IfcRoot - Name: 190 x 500 mm
Qto_BeamBaseQuantities - Length: 1025; CrossSectionArea: 0.095; OuterSurfaceArea: 1.6767; GrossSurfaceArea: 1.8667; NetSurfaceArea: 1.8667; GrossVolume: 0.115425; NetVolume: 0.115425
Pset_BeamCommon - Reference: 190 x 500 mm; Span: 1025 mm; Slope: 0 rad; Roll: 0 rad; IsExternal: no; LoadBearing: yes
Pset_Condition - AssessmentCondition: Empty
Pset_EnvironmentalImpactIndicators - Reference: 190 x 500 mm; sets with these values: 2

# IfcBeam: BB_XX_Betonbalk_ rechthoekig_ center-center_SFB_190 x 500 mm5, BB_XX_Betonbalk, rechthoekig, center-center_SFB:190 x 500 mm:894391
In: K10
PredefinedType: BEAM; Material: BB_Beton_Bestaand
Cpset_Beam - LevelOfAccuracy: in te vullen door Buildwise
IfcRoot - Name: 190 x 500 mm
Qto_BeamBaseQuantities - Length: 1900; CrossSectionArea: 0.095; OuterSurfaceArea: 2.622; GrossSurfaceArea: 2.812; NetSurfaceArea: 2.812; GrossVolume: 0.1805; NetVolume: 0.1805
Pset_BeamCommon - Reference: 190 x 500 mm; Span: 1900 mm; Slope: 0 rad; Roll: 0 rad; IsExternal: no; LoadBearing: yes
Pset_Condition - AssessmentCondition: Empty
Pset_EnvironmentalImpactIndicators - Reference: 190 x 500 mm; sets with these values: 2

# IfcBeam: BB_XX_Betonbalk_ rechthoekig_ center-center_SFB_190 x 570 mm, BB_XX_Betonbalk, rechthoekig, center-center_SFB:190 x 570 mm:702806
In: 020
PredefinedType: BEAM; Material: BB_Beton_Bestaand
Cpset_Beam - LevelOfAccuracy: in te vullen door Buildwise
IfcRoot - Name: 190 x 570 mm
Qto_BeamBaseQuantities - Length: 8275; CrossSectionArea: 0.1083; OuterSurfaceArea: 12.578; GrossSurfaceArea: 12.7946; NetSurfaceArea: 12.7946; GrossVolume: 0.896182; NetVolume: 0.896182
Pset_BeamCommon - Reference: 190 x 570 mm; Span: 8275 mm; Slope: 0 rad; Roll: 0 rad; IsExternal: no; LoadBearing: yes
Pset_Condition - AssessmentCondition: Empty
Pset_EnvironmentalImpactIndicators - Reference: 190 x 570 mm; sets with these values: 2

# IfcBeam: BB_XX_Betonbalk_ rechthoekig_ center-center_SFB_190 x 600 mm, BB_XX_Betonbalk, rechthoekig, center-center_SFB:190 x 600 mm:34110174
In: K10
PredefinedType: BEAM; Material: BB_Beton_Bestaand
Cpset_Beam - LevelOfAccuracy: in te vullen door Buildwise
IfcClassificationReference - TDS_link: .\05 As Builtdossier\2. Bouwkunde\2.1 Architectuur\2.1.3 open ruwbouw\TF S 4.3.1.2.5 A - Balken en lateien in gewapend beton.pdf
IfcRoot - Name: 190 x 600 mm
Qto_BeamBaseQuantities - Length: 5932.08; CrossSectionArea: 4.52875; NetSurfaceArea: 9.0575; NetVolume: 0.620987
Pset_BeamCommon - Reference: 190 x 600 mm; Span: 5932.08 mm; Slope: 0 rad; Roll: 0 rad; IsExternal: no; LoadBearing: yes; FireRating: EI60
Pset_ConcreteElementGeneral - ConstructionMethod: prefabricated
Pset_Condition - AssessmentCondition: Empty
Pset_EnvironmentalImpactIndicators - Reference: 190 x 600 mm; sets with these values: 2

# IfcBeam: BB_XX_Betonbalk_ rechthoekig_ center-center_SFB_190 x 600 mm1, BB_XX_Betonbalk, rechthoekig, center-center_SFB:190 x 600 mm:34131218
In: 010
PredefinedType: BEAM; Material: BB_Beton_Bestaand
Cpset_Beam - LevelOfAccuracy: in te vullen door Buildwise
IfcClassificationReference - TDS_link: .\05 As Builtdossier\2. Bouwkunde\2.1 Architectuur\2.1.3 open ruwbouw\TF S 4.3.1.2.5 A - Balken en lateien in gewapend beton.pdf
IfcRoot - Name: 190 x 600 mm
Qto_BeamBaseQuantities - Length: 3824.15; CrossSectionArea: 3.15251; NetSurfaceArea: 6.30502; NetVolume: 0.432091
Pset_BeamCommon - Reference: 190 x 600 mm; Span: 3824.15 mm; Slope: 0 rad; Roll: 0 rad; IsExternal: no; LoadBearing: yes; FireRating: EI60
Pset_ConcreteElementGeneral - ConstructionMethod: prefabricated
Pset_Condition - AssessmentCondition: Empty
Pset_EnvironmentalImpactIndicators - Reference: 190 x 600 mm; sets with these values: 2

# IfcBeam: BB_XX_Betonbalk_ rechthoekig_ center-center_SFB_190 x 600 mm3, BB_XX_Betonbalk, rechthoekig, center-center_SFB:190 x 600 mm:34131220
In: 010
PredefinedType: BEAM; Material: BB_Beton_Bestaand
Cpset_Beam - LevelOfAccuracy: in te vullen door Buildwise
IfcClassificationReference - TDS_link: .\05 As Builtdossier\2. Bouwkunde\2.1 Architectuur\2.1.3 open ruwbouw\TF S 4.3.1.2.5 A - Balken en lateien in gewapend beton.pdf
IfcRoot - Name: 190 x 600 mm
Qto_BeamBaseQuantities - Length: 3822.91; CrossSectionArea: 0.114; OuterSurfaceArea: 6.1372; GrossSurfaceArea: 6.3652; NetSurfaceArea: 6.3652; GrossVolume: 0.442811; NetVolume: 0.442811
Pset_BeamCommon - Reference: 190 x 600 mm; Span: 3822.91 mm; Slope: 0 rad; Roll: 0 rad; IsExternal: no; LoadBearing: yes; FireRating: EI60
Pset_ConcreteElementGeneral - ConstructionMethod: prefabricated
Pset_Condition - AssessmentCondition: Empty
Pset_EnvironmentalImpactIndicators - Reference: 190 x 600 mm; sets with these values: 2

# IfcBeam: BB_XX_Betonbalk_ rechthoekig_ center-center_SFB_190 x 650 mm, BB_XX_Betonbalk, rechthoekig, center-center_SFB:190 x 650 mm:34186321
In: 000
PredefinedType: BEAM; Material: BB_Beton_Bestaand
Cpset_Beam - LevelOfAccuracy: in te vullen door Buildwise
IfcClassificationReference - TDS_link: .\05 As Builtdossier\2. Bouwkunde\2.1 Architectuur\2.1.3 open ruwbouw\TF S 4.3.1.2.5 A - Balken en lateien in gewapend beton.pdf
IfcRoot - Name: 190 x 650 mm
Qto_BeamBaseQuantities - Length: 6040; CrossSectionArea: 4.90042; NetSurfaceArea: 9.80085; NetVolume: 0.69257
Pset_BeamCommon - Reference: 190 x 650 mm; Span: 6040 mm; Slope: 0 rad; Roll: 0 rad; IsExternal: no; LoadBearing: yes; FireRating: EI60
Pset_ConcreteElementGeneral - ConstructionMethod: prefabricated
Pset_Condition - AssessmentCondition: Empty
Pset_EnvironmentalImpactIndicators - Reference: 190 x 650 mm; sets with these values: 2

# IfcBeam: BB_XX_Betonbalk_ rechthoekig_ center-center_SFB_190 x 700 mm, BB_XX_Betonbalk, rechthoekig, center-center_SFB:190 x 700 mm:981913
In: K20
PredefinedType: BEAM; Material: BB_Beton_Bestaand
Cpset_Beam - LevelOfAccuracy: in te vullen door Buildwise
IfcRoot - Name: 190 x 700 mm
Qto_BeamBaseQuantities - Length: 885; CrossSectionArea: 0.133; OuterSurfaceArea: 1.5753; GrossSurfaceArea: 1.8413; NetSurfaceArea: 1.8413; GrossVolume: 0.117705; NetVolume: 0.117705
Pset_BeamCommon - Reference: 190 x 700 mm; Span: 885 mm; Slope: 0 rad; Roll: 0 rad; IsExternal: no; LoadBearing: yes
Pset_Condition - AssessmentCondition: Empty
Pset_EnvironmentalImpactIndicators - Reference: 190 x 700 mm; sets with these values: 2

# IfcBeam: BB_XX_Betonbalk_ rechthoekig_ center-center_SFB_190 x 700 mm1, BB_XX_Betonbalk, rechthoekig, center-center_SFB:190 x 700 mm:801653
In: K10
PredefinedType: BEAM; Material: BB_Beton_Bestaand
Cpset_Beam - LevelOfAccuracy: in te vullen door Buildwise
IfcRoot - Name: 190 x 700 mm
Qto_BeamBaseQuantities - Length: 7010; CrossSectionArea: 0.133; OuterSurfaceArea: 12.4778; GrossSurfaceArea: 12.7438; NetSurfaceArea: 12.7438; GrossVolume: 0.93233; NetVolume: 0.93233
Pset_BeamCommon - Reference: 190 x 700 mm; Span: 7010 mm; Slope: 0 rad; Roll: 0 rad; IsExternal: no; LoadBearing: yes
Pset_Condition - AssessmentCondition: Empty
Pset_EnvironmentalImpactIndicators - Reference: 190 x 700 mm; sets with these values: 2

# IfcBeam: BB_XX_Betonbalk_ rechthoekig_ center-center_SFB_190 x 700 mm3, BB_XX_Betonbalk, rechthoekig, center-center_SFB:190 x 700 mm:894779
In: K10
PredefinedType: BEAM; Material: BB_Beton_Bestaand
Cpset_Beam - LevelOfAccuracy: in te vullen door Buildwise
IfcRoot - Name: 190 x 700 mm
Qto_BeamBaseQuantities - Length: 875; CrossSectionArea: 0.133; OuterSurfaceArea: 1.5575; GrossSurfaceArea: 1.8235; NetSurfaceArea: 1.8235; GrossVolume: 0.116375; NetVolume: 0.116375
Pset_BeamCommon - Reference: 190 x 700 mm; Span: 875 mm; Slope: 0 rad; Roll: 0 rad; IsExternal: no; LoadBearing: yes
Pset_Condition - AssessmentCondition: Empty
Pset_EnvironmentalImpactIndicators - Reference: 190 x 700 mm; sets with these values: 2

# IfcBeam: BB_XX_Betonbalk_ rechthoekig_ center-center_SFB_190 x 700 mm5, BB_XX_Betonbalk, rechthoekig, center-center_SFB:190 x 700 mm:942519
In: K10
PredefinedType: BEAM; Material: BB_Beton_Bestaand
Cpset_Beam - LevelOfAccuracy: in te vullen door Buildwise
IfcRoot - Name: 190 x 700 mm
Qto_BeamBaseQuantities - Length: 7064.03; CrossSectionArea: 6.41448; NetSurfaceArea: 12.829; NetVolume: 0.939266
Pset_BeamCommon - Reference: 190 x 700 mm; Span: 7064.03 mm; Slope: 0 rad; Roll: 0 rad; IsExternal: no; LoadBearing: yes
Pset_Condition - AssessmentCondition: Empty
Pset_EnvironmentalImpactIndicators - Reference: 190 x 700 mm; sets with these values: 2

# IfcBeam: BB_XX_Betonbalk_ rechthoekig_ center-center_SFB_190 x 720 mm, BB_XX_Betonbalk, rechthoekig, center-center_SFB:190 x 720 mm:543253
In: 000
PredefinedType: BEAM; Material: BB_Beton_Bestaand
Cpset_Beam - LevelOfAccuracy: in te vullen door Buildwise
IfcRoot - Name: 190 x 720 mm
Qto_BeamBaseQuantities - Length: 7200; CrossSectionArea: 0.1368; OuterSurfaceArea: 13.104; GrossSurfaceArea: 13.3776; NetSurfaceArea: 13.3776; GrossVolume: 0.98496; NetVolume: 0.98496
Pset_BeamCommon - Reference: 190 x 720 mm; Span: 7200 mm; Slope: 0 rad; Roll: 0 rad; IsExternal: no; LoadBearing: yes
Pset_Condition - AssessmentCondition: Empty
Pset_EnvironmentalImpactIndicators - Reference: 190 x 720 mm; sets with these values: 2

# IfcBeam: BB_XX_Betonbalk_ rechthoekig_ center-center_SFB_190 x 720 mm1, BB_XX_Betonbalk, rechthoekig, center-center_SFB:190 x 720 mm:544916
In: 000
PredefinedType: BEAM; Material: BB_Beton_Bestaand
Cpset_Beam - LevelOfAccuracy: in te vullen door Buildwise
IfcRoot - Name: 190 x 720 mm
Qto_BeamBaseQuantities - Length: 7184.55; CrossSectionArea: 0.1368; OuterSurfaceArea: 13.0759; GrossSurfaceArea: 13.3495; NetSurfaceArea: 13.3495; GrossVolume: 0.982846; NetVolume: 0.982846
Pset_BeamCommon - Reference: 190 x 720 mm; Span: 7184.55 mm; Slope: 0 rad; Roll: 0 rad; IsExternal: no; LoadBearing: yes
Pset_Condition - AssessmentCondition: Empty
Pset_EnvironmentalImpactIndicators - Reference: 190 x 720 mm; sets with these values: 2

# IfcBeam: BB_XX_Betonbalk_ rechthoekig_ center-center_SFB_190 x 720 mm11, BB_XX_Betonbalk, rechthoekig, center-center_SFB:190 x 720 mm:622441
In: 010
PredefinedType: BEAM; Material: BB_Beton_Bestaand
Cpset_Beam - LevelOfAccuracy: in te vullen door Buildwise
IfcRoot - Name: 190 x 720 mm
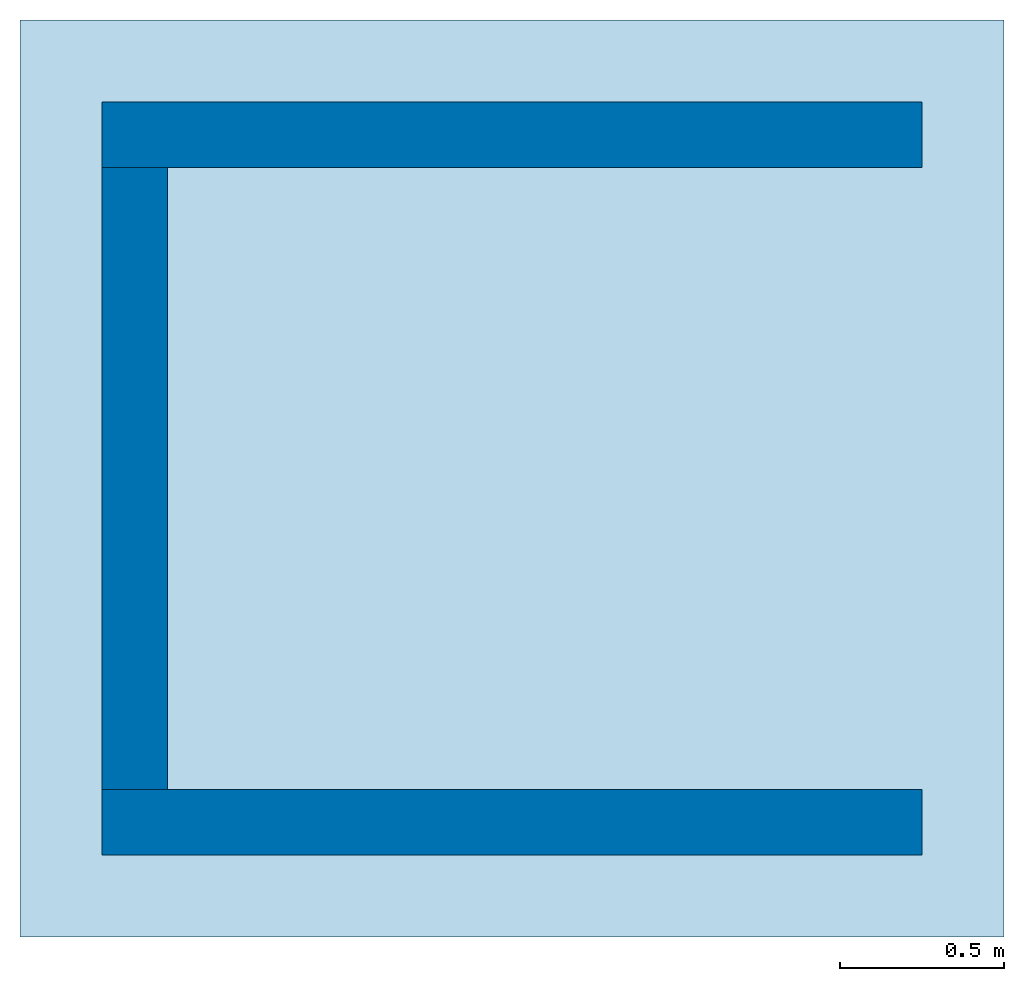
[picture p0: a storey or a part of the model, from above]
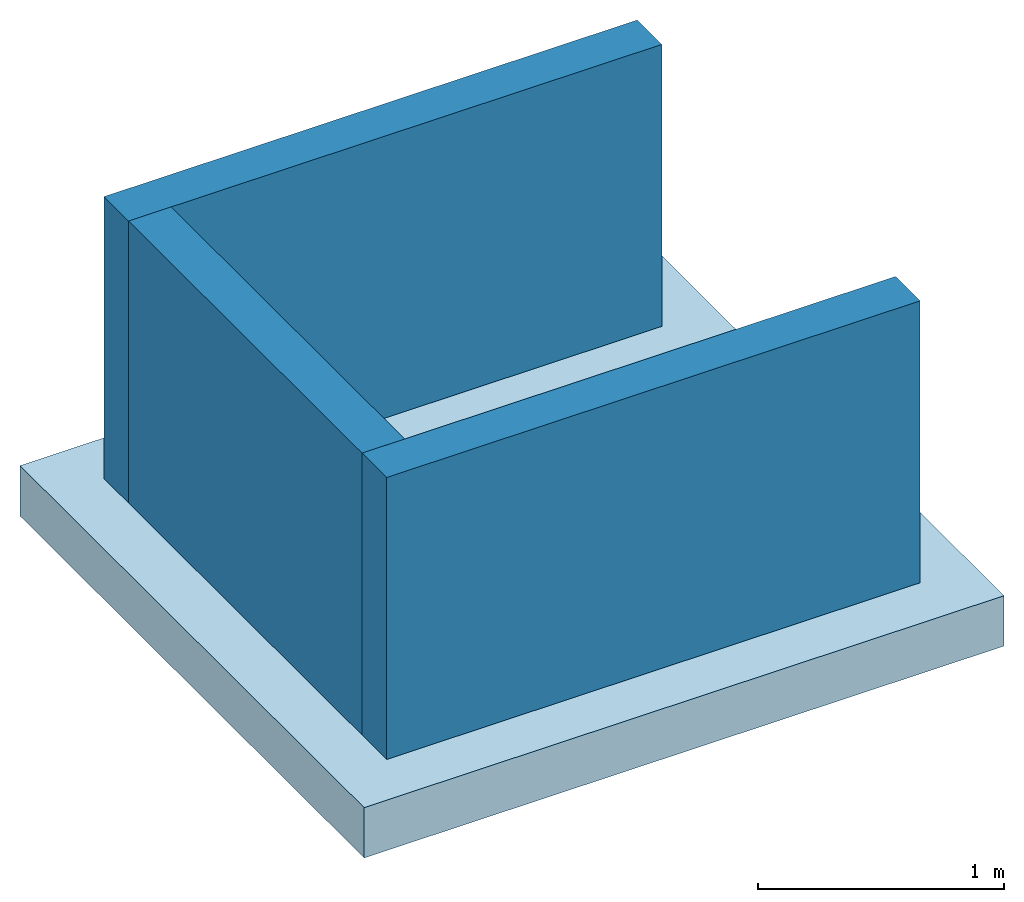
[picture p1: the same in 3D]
Properties of the parts of a building model (IFC4X3_ADD2), part 8 of 28

# IfcBeam: BB_XX_Betonbalk_ rechthoekig_ center-center_SFB_190 x 720 mm11, BB_XX_Betonbalk, rechthoekig, center-center_SFB:190 x 720 mm:622441
Qto_BeamBaseQuantities - Length: 5309.39; CrossSectionArea: 0.1368; OuterSurfaceArea: 9.4549; GrossSurfaceArea: 9.7285; NetSurfaceArea: 9.7285; GrossVolume: 0.710676; NetVolume: 0.710676
Pset_BeamCommon - Reference: 190 x 720 mm; Span: 5309.39 mm; Slope: 0 rad; Roll: 0 rad; IsExternal: no; LoadBearing: yes
Pset_Condition - AssessmentCondition: Empty
Pset_EnvironmentalImpactIndicators - Reference: 190 x 720 mm; sets with these values: 2

# IfcBeam: BB_XX_Betonbalk_ rechthoekig_ center-center_SFB_190 x 720 mm13, BB_XX_Betonbalk, rechthoekig, center-center_SFB:190 x 720 mm:629170
In: 010
PredefinedType: BEAM; Material: BB_Beton_Bestaand
Cpset_Beam - LevelOfAccuracy: in te vullen door Buildwise
IfcRoot - Name: 190 x 720 mm
Qto_BeamBaseQuantities - Length: 5400; CrossSectionArea: 0.1368; OuterSurfaceArea: 9.828; GrossSurfaceArea: 10.1016; NetSurfaceArea: 10.1016; GrossVolume: 0.73872; NetVolume: 0.73872
Pset_BeamCommon - Reference: 190 x 720 mm; Span: 5400 mm; Slope: 0 rad; Roll: 0 rad; IsExternal: no; LoadBearing: yes
Pset_Condition - AssessmentCondition: Empty
Pset_EnvironmentalImpactIndicators - Reference: 190 x 720 mm; sets with these values: 2

# IfcBeam: BB_XX_Betonbalk_ rechthoekig_ center-center_SFB_190 x 720 mm15 (2)
PredefinedType: BEAM; Material: BB_Beton_Bestaand
Cpset_Beam - LevelOfAccuracy: in te vullen door Buildwise
IfcRoot - Name: 190 x 720 mm
Qto_BeamBaseQuantities - Length: 7200; CrossSectionArea: 0.1368; OuterSurfaceArea: 13.104; GrossSurfaceArea: 13.3776; NetSurfaceArea: 13.3776; GrossVolume: 0.98496; NetVolume: 0.98496
Pset_BeamCommon - Reference: 190 x 720 mm; Span: 7200 mm; Slope: 0 rad; Roll: 0 rad; IsExternal: no; LoadBearing: yes
Pset_Condition - AssessmentCondition: Empty
Pset_EnvironmentalImpactIndicators - Reference: 190 x 720 mm; sets with these values: 2
Name (BB_XX_Betonbalk, rechthoekig, center-center_SFB:190 x 720 mm:...) | In
637970 | 010
695630 | 020

# IfcBeam: BB_XX_Betonbalk_ rechthoekig_ center-center_SFB_190 x 720 mm17 (2)
PredefinedType: BEAM; Material: BB_Beton_Bestaand
Cpset_Beam - LevelOfAccuracy: in te vullen door Buildwise
IfcRoot - Name: 190 x 720 mm
Qto_BeamBaseQuantities - Length: 6094.56; CrossSectionArea: 0.1368; OuterSurfaceArea: 11.0921; GrossSurfaceArea: 11.3657; NetSurfaceArea: 11.3657; GrossVolume: 0.833735; NetVolume: 0.833735
Pset_BeamCommon - Reference: 190 x 720 mm; Span: 6094.56 mm; Slope: 0 rad; Roll: 0 rad; IsExternal: no; LoadBearing: yes
Pset_Condition - AssessmentCondition: Empty
Pset_EnvironmentalImpactIndicators - Reference: 190 x 720 mm; sets with these values: 2
Name (BB_XX_Betonbalk, rechthoekig, center-center_SFB:190 x 720 mm:...) | In
645827 | 010
695713 | 020

# IfcBeam: BB_XX_Betonbalk_ rechthoekig_ center-center_SFB_190 x 720 mm19, BB_XX_Betonbalk, rechthoekig, center-center_SFB:190 x 720 mm:647504
In: 010
PredefinedType: BEAM; Material: BB_Beton_Bestaand
Cpset_Beam - LevelOfAccuracy: in te vullen door Buildwise
IfcRoot - Name: 190 x 720 mm
Qto_BeamBaseQuantities - Length: 7121.37; CrossSectionArea: 0.1368; OuterSurfaceArea: 12.9609; GrossSurfaceArea: 13.2345; NetSurfaceArea: 13.2345; GrossVolume: 0.974203; NetVolume: 0.974203
Pset_BeamCommon - Reference: 190 x 720 mm; Span: 7121.37 mm; Slope: 0 rad; Roll: 0 rad; IsExternal: no; LoadBearing: yes
Pset_Condition - AssessmentCondition: Empty
Pset_EnvironmentalImpactIndicators - Reference: 190 x 720 mm; sets with these values: 2

# IfcBeam: BB_XX_Betonbalk_ rechthoekig_ center-center_SFB_190 x 720 mm21, BB_XX_Betonbalk, rechthoekig, center-center_SFB:190 x 720 mm:707143
In: 010
PredefinedType: BEAM; Material: BB_Beton_Bestaand
Cpset_Beam - LevelOfAccuracy: in te vullen door Buildwise
IfcRoot - Name: 190 x 720 mm
Qto_BeamBaseQuantities - Length: 5840; CrossSectionArea: 5.45062; NetSurfaceArea: 10.9012; NetVolume: 0.793923
Pset_BeamCommon - Reference: 190 x 720 mm; Span: 5840 mm; Slope: 0.0685468 rad; Roll: 0 rad; IsExternal: no; LoadBearing: yes
Pset_Condition - AssessmentCondition: Empty
Pset_EnvironmentalImpactIndicators - Reference: 190 x 720 mm; sets with these values: 2

# IfcBeam: BB_XX_Betonbalk_ rechthoekig_ center-center_SFB_190 x 720 mm23, BB_XX_Betonbalk, rechthoekig, center-center_SFB:190 x 720 mm:695467
In: 020
PredefinedType: BEAM; Material: BB_Beton_Bestaand
Cpset_Beam - LevelOfAccuracy: in te vullen door Buildwise
IfcRoot - Name: 190 x 720 mm
Qto_BeamBaseQuantities - Length: 5385; CrossSectionArea: 5.07456; NetSurfaceArea: 10.1491; NetVolume: 0.713364
Pset_BeamCommon - Reference: 190 x 720 mm; Span: 5385 mm; Slope: 0 rad; Roll: 0 rad; IsExternal: no; LoadBearing: yes
Pset_Condition - AssessmentCondition: Empty
Pset_EnvironmentalImpactIndicators - Reference: 190 x 720 mm; sets with these values: 2

# IfcBeam: BB_XX_Betonbalk_ rechthoekig_ center-center_SFB_190 x 720 mm25, BB_XX_Betonbalk, rechthoekig, center-center_SFB:190 x 720 mm:695540
In: 020
PredefinedType: BEAM; Material: BB_Beton_Bestaand
Cpset_Beam - LevelOfAccuracy: in te vullen door Buildwise
IfcRoot - Name: 190 x 720 mm
Qto_BeamBaseQuantities - Length: 5385; CrossSectionArea: 5.06918; NetSurfaceArea: 10.1384; NetVolume: 0.714386
Pset_BeamCommon - Reference: 190 x 720 mm; Span: 5385 mm; Slope: 0 rad; Roll: 0 rad; IsExternal: no; LoadBearing: yes
Pset_Condition - AssessmentCondition: Empty
Pset_EnvironmentalImpactIndicators - Reference: 190 x 720 mm; sets with these values: 2

# IfcBeam: BB_XX_Betonbalk_ rechthoekig_ center-center_SFB_190 x 720 mm27, BB_XX_Betonbalk, rechthoekig, center-center_SFB:190 x 720 mm:695735
In: 020
PredefinedType: BEAM; Material: BB_Beton_Bestaand
Cpset_Beam - LevelOfAccuracy: in te vullen door Buildwise
IfcRoot - Name: 190 x 720 mm
Qto_BeamBaseQuantities - Length: 7121.37; CrossSectionArea: 0.1368; OuterSurfaceArea: 12.9609; GrossSurfaceArea: 13.2345; NetSurfaceArea: 13.2345; GrossVolume: 0.974203; NetVolume: 0.974203
Pset_BeamCommon - Reference: 190 x 720 mm; Span: 7121.37 mm; Slope: 0 rad; Roll: 0 rad; IsExternal: no; LoadBearing: yes
Pset_Condition - AssessmentCondition: Empty
Pset_EnvironmentalImpactIndicators - Reference: 190 x 720 mm; sets with these values: 2

# IfcBeam: BB_XX_Betonbalk_ rechthoekig_ center-center_SFB_190 x 720 mm29, BB_XX_Betonbalk, rechthoekig, center-center_SFB:190 x 720 mm:702412
In: 020
PredefinedType: BEAM; Material: BB_Beton_Bestaand
Cpset_Beam - LevelOfAccuracy: in te vullen door Buildwise
IfcRoot - Name: 190 x 720 mm
Qto_BeamBaseQuantities - Length: 5833.63; CrossSectionArea: 0.1368; OuterSurfaceArea: 10.6172; GrossSurfaceArea: 10.8908; NetSurfaceArea: 10.8908; GrossVolume: 0.798041; NetVolume: 0.798041
Pset_BeamCommon - Reference: 190 x 720 mm; Span: 5833.63 mm; Slope: 0 rad; Roll: 0 rad; IsExternal: no; LoadBearing: yes
Pset_Condition - AssessmentCondition: Empty
Pset_EnvironmentalImpactIndicators - Reference: 190 x 720 mm; sets with these values: 2

# IfcBeam: BB_XX_Betonbalk_ rechthoekig_ center-center_SFB_190 x 720 mm3, BB_XX_Betonbalk, rechthoekig, center-center_SFB:190 x 720 mm:550624
In: 000
PredefinedType: BEAM; Material: BB_Beton_Bestaand
Cpset_Beam - LevelOfAccuracy: in te vullen door Buildwise
IfcRoot - Name: 190 x 720 mm
Qto_BeamBaseQuantities - Length: 7200; CrossSectionArea: 0.1368; OuterSurfaceArea: 13.104; GrossSurfaceArea: 13.3776; NetSurfaceArea: 13.3776; GrossVolume: 0.98496; NetVolume: 0.98496
Pset_BeamCommon - Reference: 190 x 720 mm; Span: 7200 mm; Slope: 0 rad; Roll: 0 rad; IsExternal: no; LoadBearing: yes
Pset_Condition - AssessmentCondition: Empty
Pset_EnvironmentalImpactIndicators - Reference: 190 x 720 mm; sets with these values: 2

# IfcBeam: BB_XX_Betonbalk_ rechthoekig_ center-center_SFB_190 x 720 mm31, BB_XX_Betonbalk, rechthoekig, center-center_SFB:190 x 720 mm:732468
In: 030
PredefinedType: BEAM; Material: BB_Beton_Bestaand
Cpset_Beam - LevelOfAccuracy: in te vullen door Buildwise
IfcRoot - Name: 190 x 720 mm
Qto_BeamBaseQuantities - Length: 3370; CrossSectionArea: 0.1368; OuterSurfaceArea: 6.1334; GrossSurfaceArea: 6.407; NetSurfaceArea: 6.407; GrossVolume: 0.461016; NetVolume: 0.461016
Pset_BeamCommon - Reference: 190 x 720 mm; Span: 3370 mm; Slope: 0 rad; Roll: 0 rad; IsExternal: no; LoadBearing: yes
Pset_Condition - AssessmentCondition: Empty
Pset_EnvironmentalImpactIndicators - Reference: 190 x 720 mm; sets with these values: 2

# IfcBeam: BB_XX_Betonbalk_ rechthoekig_ center-center_SFB_190 x 720 mm33, BB_XX_Betonbalk, rechthoekig, center-center_SFB:190 x 720 mm:766768
In: 030
PredefinedType: BEAM; Material: BB_Beton_Bestaand
Cpset_Beam - LevelOfAccuracy: in te vullen door Buildwise
IfcRoot - Name: 190 x 720 mm
Qto_BeamBaseQuantities - Length: 1555; CrossSectionArea: 0.1368; OuterSurfaceArea: 2.8301; GrossSurfaceArea: 3.1037; NetSurfaceArea: 3.1037; GrossVolume: 0.212724; NetVolume: 0.212724
Pset_BeamCommon - Reference: 190 x 720 mm; Span: 1555 mm; Slope: 0 rad; Roll: 0 rad; IsExternal: no; LoadBearing: yes
Pset_Condition - AssessmentCondition: Empty
Pset_EnvironmentalImpactIndicators - Reference: 190 x 720 mm; sets with these values: 2

# IfcBeam: BB_XX_Betonbalk_ rechthoekig_ center-center_SFB_190 x 720 mm35, BB_XX_Betonbalk, rechthoekig, center-center_SFB:190 x 720 mm:767669
In: 030
PredefinedType: BEAM; Material: BB_Beton_Bestaand
Cpset_Beam - LevelOfAccuracy: in te vullen door Buildwise
IfcRoot - Name: 190 x 720 mm
Qto_BeamBaseQuantities - Length: 3370; CrossSectionArea: 0.1368; OuterSurfaceArea: 6.1334; GrossSurfaceArea: 6.407; NetSurfaceArea: 6.407; GrossVolume: 0.461016; NetVolume: 0.461016
Pset_BeamCommon - Reference: 190 x 720 mm; Span: 3370 mm; Slope: 0 rad; Roll: 0 rad; IsExternal: no; LoadBearing: yes
Pset_Condition - AssessmentCondition: Empty
Pset_EnvironmentalImpactIndicators - Reference: 190 x 720 mm; sets with these values: 2

# IfcBeam: BB_XX_Betonbalk_ rechthoekig_ center-center_SFB_190 x 720 mm37, BB_XX_Betonbalk, rechthoekig, center-center_SFB:190 x 720 mm:767909
In: 030
PredefinedType: BEAM; Material: BB_Beton_Bestaand
Cpset_Beam - LevelOfAccuracy: in te vullen door Buildwise
IfcRoot - Name: 190 x 720 mm
Qto_BeamBaseQuantities - Length: 7973.8; CrossSectionArea: 0.1368; OuterSurfaceArea: 14.5123; GrossSurfaceArea: 14.7859; NetSurfaceArea: 14.7859; GrossVolume: 1.09082; NetVolume: 1.09082
Pset_BeamCommon - Reference: 190 x 720 mm; Span: 7973.8 mm; Slope: 0 rad; Roll: 0 rad; IsExternal: no; LoadBearing: yes
Pset_Condition - AssessmentCondition: Empty
Pset_EnvironmentalImpactIndicators - Reference: 190 x 720 mm; sets with these values: 2

# IfcBeam: BB_XX_Betonbalk_ rechthoekig_ center-center_SFB_190 x 720 mm39, BB_XX_Betonbalk, rechthoekig, center-center_SFB:190 x 720 mm:770820
In: 030
PredefinedType: BEAM; Material: BB_Beton_Bestaand
Cpset_Beam - LevelOfAccuracy: in te vullen door Buildwise
IfcRoot - Name: 190 x 720 mm
Qto_BeamBaseQuantities - Length: 7080; CrossSectionArea: 0.1368; OuterSurfaceArea: 12.8856; GrossSurfaceArea: 13.1592; NetSurfaceArea: 13.1592; GrossVolume: 0.968544; NetVolume: 0.968544
Pset_BeamCommon - Reference: 190 x 720 mm; Span: 7080 mm; Slope: 0 rad; Roll: 0 rad; IsExternal: no; LoadBearing: yes
Pset_Condition - AssessmentCondition: Empty
Pset_EnvironmentalImpactIndicators - Reference: 190 x 720 mm; sets with these values: 2

# IfcBeam: BB_XX_Betonbalk_ rechthoekig_ center-center_SFB_190 x 720 mm5 (2)
In: 000
PredefinedType: BEAM; Material: BB_Beton_Bestaand
Cpset_Beam - LevelOfAccuracy: in te vullen door Buildwise
IfcRoot - Name: 190 x 720 mm
Qto_BeamBaseQuantities - Length: 5335; CrossSectionArea: 0.1368; OuterSurfaceArea: 9.7097; GrossSurfaceArea: 9.9833; NetSurfaceArea: 9.9833; GrossVolume: 0.729828; NetVolume: 0.729828
Pset_BeamCommon - Reference: 190 x 720 mm; Span: 5335 mm; Slope: 0 rad; Roll: 0 rad; IsExternal: no; LoadBearing: yes
Pset_Condition - AssessmentCondition: Empty
Pset_EnvironmentalImpactIndicators - Reference: 190 x 720 mm; sets with these values: 2
Name (BB_XX_Betonbalk, rechthoekig, center-center_SFB:190 x 720 mm:...)
562740
586079

# IfcBeam: BB_XX_Betonbalk_ rechthoekig_ center-center_SFB_190 x 720 mm7, BB_XX_Betonbalk, rechthoekig, center-center_SFB:190 x 720 mm:583454
In: 000
PredefinedType: BEAM; Material: BB_Beton_Bestaand
Cpset_Beam - LevelOfAccuracy: in te vullen door Buildwise
IfcRoot - Name: 190 x 720 mm
Qto_BeamBaseQuantities - Length: 6094.56; CrossSectionArea: 0.1368; OuterSurfaceArea: 11.0921; GrossSurfaceArea: 11.3657; NetSurfaceArea: 11.3657; GrossVolume: 0.833735; NetVolume: 0.833735
Pset_BeamCommon - Reference: 190 x 720 mm; Span: 6094.56 mm; Slope: 0 rad; Roll: 0 rad; IsExternal: no; LoadBearing: yes
Pset_Condition - AssessmentCondition: Empty
Pset_EnvironmentalImpactIndicators - Reference: 190 x 720 mm; sets with these values: 2

# IfcBeam: BB_XX_Betonbalk_ rechthoekig_ center-center_SFB_190 x 720 mm9 (2)
PredefinedType: BEAM; Material: BB_Beton_Bestaand
Cpset_Beam - LevelOfAccuracy: in te vullen door Buildwise
IfcRoot - Name: 190 x 720 mm
Qto_BeamBaseQuantities - Length: 7200; CrossSectionArea: 0.1368; OuterSurfaceArea: 13.104; GrossSurfaceArea: 13.3776; NetSurfaceArea: 13.3776; GrossVolume: 0.98496; NetVolume: 0.98496
Pset_BeamCommon - Reference: 190 x 720 mm; Span: 7200 mm; Slope: 0 rad; Roll: 0 rad; IsExternal: no; LoadBearing: yes
Pset_Condition - AssessmentCondition: Empty
Pset_EnvironmentalImpactIndicators - Reference: 190 x 720 mm; sets with these values: 2
Name (BB_XX_Betonbalk, rechthoekig, center-center_SFB:190 x 720 mm:...) | In
614038 | 010
695395 | 020

# IfcBeam: BB_XX_Betonbalk_ rechthoekig_ center-center_SFB_190 x 730 mm, BB_XX_Betonbalk, rechthoekig, center-center_SFB:190 x 730 mm:34131825
In: 010
PredefinedType: BEAM; Material: BB_Beton_Bestaand
Cpset_Beam - LevelOfAccuracy: in te vullen door Buildwise
IfcClassificationReference - TDS_link: .\05 As Builtdossier\2. Bouwkunde\2.1 Architectuur\2.1.3 open ruwbouw\TF S 4.3.1.2.5 A - Balken en lateien in gewapend beton.pdf
IfcRoot - Name: 190 x 730 mm
Qto_BeamBaseQuantities - Length: 2480; CrossSectionArea: 0.1387; OuterSurfaceArea: 4.8208; GrossSurfaceArea: 5.0982; NetSurfaceArea: 5.0982; GrossVolume: 0.363394; NetVolume: 0.363394
Pset_BeamCommon - Reference: 190 x 730 mm; Span: 2480 mm; Slope: 0 rad; Roll: 0 rad; IsExternal: no; LoadBearing: yes
Pset_ConcreteElementGeneral - ConstructionMethod: prefabricated
Pset_Condition - AssessmentCondition: Empty
Pset_EnvironmentalImpactIndicators - Reference: 190 x 730 mm; sets with these values: 2

# IfcBeam: BB_XX_Betonbalk_ rechthoekig_ center-center_SFB_190 x 730 mm1, BB_XX_Betonbalk, rechthoekig, center-center_SFB:190 x 730 mm:34132371
In: 010
PredefinedType: BEAM; Material: BB_Beton_Bestaand
Cpset_Beam - LevelOfAccuracy: in te vullen door Buildwise
IfcClassificationReference - TDS_link: .\05 As Builtdossier\2. Bouwkunde\2.1 Architectuur\2.1.3 open ruwbouw\TF S 4.3.1.2.5 A - Balken en lateien in gewapend beton.pdf
IfcRoot - Name: 190 x 730 mm
Qto_BeamBaseQuantities - Length: 2480; CrossSectionArea: 0.1387; OuterSurfaceArea: 4.82079; GrossSurfaceArea: 5.09819; NetSurfaceArea: 5.09819; GrossVolume: 0.363393; NetVolume: 0.363393
Pset_BeamCommon - Reference: 190 x 730 mm; Span: 2480 mm; Slope: 0 rad; Roll: 0 rad; IsExternal: no; LoadBearing: yes
Pset_ConcreteElementGeneral - ConstructionMethod: prefabricated
Pset_Condition - AssessmentCondition: Empty
Pset_EnvironmentalImpactIndicators - Reference: 190 x 730 mm; sets with these values: 2

# IfcBeam: BB_XX_Betonbalk_ rechthoekig_ center-center_SFB_190 x 740 mm, BB_XX_Betonbalk, rechthoekig, center-center_SFB:190 x 740 mm:705316
In: 030
PredefinedType: BEAM; Material: BB_Beton_Bestaand
Cpset_Beam - LevelOfAccuracy: in te vullen door Buildwise
IfcRoot - Name: 190 x 740 mm
Qto_BeamBaseQuantities - Length: 2947.88; CrossSectionArea: 2.59168; NetSurfaceArea: 5.18336; NetVolume: 0.361757
Pset_BeamCommon - Reference: 190 x 740 mm; Span: 2947.88 mm; Slope: 0 rad; Roll: 0 rad; IsExternal: no; LoadBearing: yes
Pset_Condition - AssessmentCondition: Empty
Pset_EnvironmentalImpactIndicators - Reference: 190 x 740 mm; sets with these values: 2

# IfcBeam: BB_XX_Betonbalk_ rechthoekig_ center-center_SFB_190 x 750 mm, BB_XX_Betonbalk, rechthoekig, center-center_SFB:190 x 750 mm:34193872
In: 040
PredefinedType: BEAM; Material: BB_Beton_Bestaand
Cpset_Beam - LevelOfAccuracy: in te vullen door Buildwise
IfcClassificationReference - TDS_link: .\05 As Builtdossier\2. Bouwkunde\2.1 Architectuur\2.1.3 open ruwbouw\TF S 4.3.1.2.5 A - Balken en lateien in gewapend beton.pdf
IfcRoot - Name: 190 x 750 mm
Qto_BeamBaseQuantities - Length: 5882.53; CrossSectionArea: 3.3346; OuterSurfaceArea: 2.52167; GrossSurfaceArea: 9.19087; NetSurfaceArea: 9.19087; GrossVolume: 0.633574; NetVolume: 0.633574
Pset_BeamCommon - Reference: 190 x 750 mm; Span: 5882.53 mm; Slope: 0 rad; Roll: 0 rad; IsExternal: no; LoadBearing: yes
Pset_ConcreteElementGeneral - ConstructionMethod: prefabricated
Pset_Condition - AssessmentCondition: Empty
Pset_EnvironmentalImpactIndicators - Reference: 190 x 750 mm; sets with these values: 2

# IfcBeam: BB_XX_Betonbalk_ rechthoekig_ center-center_SFB_200 x 1000 mm, BB_XX_Betonbalk, rechthoekig, center-center_SFB:200 x 1000 mm:34144432
In: 020
PredefinedType: BEAM; Material: BB_Beton_Bestaand
Cpset_Beam - LevelOfAccuracy: in te vullen door Buildwise
IfcClassificationReference - TDS_link: .\05 As Builtdossier\2. Bouwkunde\2.1 Architectuur\2.1.3 open ruwbouw\TF S 4.3.1.2.5 A - Balken en lateien in gewapend beton.pdf
IfcRoot - Name: 200 x 1000 mm
Qto_BeamBaseQuantities - Length: 165.797; CrossSectionArea: 0.2; OuterSurfaceArea: 0.487886; GrossSurfaceArea: 0.887886; NetSurfaceArea: 0.887886; GrossVolume: 0.0406572; NetVolume: 0.0406572
Pset_BeamCommon - Reference: 200 x 1000 mm; Span: 165.797 mm; Slope: 0 rad; Roll: 0 rad; IsExternal: no; LoadBearing: yes; FireRating: EI60
Pset_ConcreteElementGeneral - ConstructionMethod: prefabricated
Pset_Condition - AssessmentCondition: Empty
Pset_EnvironmentalImpactIndicators - Reference: 200 x 1000 mm; sets with these values: 2

# IfcBeam: BB_XX_Betonbalk_ rechthoekig_ center-center_SFB_200 x 1100 mm, BB_XX_Betonbalk, rechthoekig, center-center_SFB:200 x 1100 mm:943284
In: K10
PredefinedType: BEAM; Material: BB_Beton_Bestaand
Cpset_Beam - LevelOfAccuracy: in te vullen door Buildwise
IfcRoot - Name: 200 x 1100 mm
Qto_BeamBaseQuantities - Length: 960; CrossSectionArea: 0.22; OuterSurfaceArea: 2.496; GrossSurfaceArea: 2.936; NetSurfaceArea: 2.936; GrossVolume: 0.2112; NetVolume: 0.2112
Pset_BeamCommon - Reference: 200 x 1100 mm; Span: 960 mm; Slope: 0 rad; Roll: 0 rad; IsExternal: no; LoadBearing: yes
Pset_Condition - AssessmentCondition: Empty
Pset_EnvironmentalImpactIndicators - Reference: 200 x 1100 mm; sets with these values: 2

# IfcBeam: BB_XX_Betonbalk_ rechthoekig_ center-center_SFB_200 x 1270 mm, BB_XX_Betonbalk, rechthoekig, center-center_SFB:200 x 1270 mm:835465
In: K10
PredefinedType: BEAM; Material: BB_Beton_Bestaand
Cpset_Beam - LevelOfAccuracy: in te vullen door Buildwise
IfcRoot - Name: 200 x 1270 mm
Qto_BeamBaseQuantities - Length: 1900; CrossSectionArea: 0.254; OuterSurfaceArea: 5.586; GrossSurfaceArea: 6.094; NetSurfaceArea: 6.094; GrossVolume: 0.4826; NetVolume: 0.4826
Pset_BeamCommon - Reference: 200 x 1270 mm; Span: 1900 mm; Slope: 0 rad; Roll: 0 rad; IsExternal: no; LoadBearing: yes
Pset_Condition - AssessmentCondition: Empty
Pset_EnvironmentalImpactIndicators - Reference: 200 x 1270 mm; sets with these values: 2

# IfcBeam: BB_XX_Betonbalk_ rechthoekig_ center-center_SFB_200 x 1270 mm1, BB_XX_Betonbalk, rechthoekig, center-center_SFB:200 x 1270 mm:835467
In: K10
PredefinedType: BEAM; Material: BB_Beton_Bestaand
Cpset_Beam - LevelOfAccuracy: in te vullen door Buildwise
IfcRoot - Name: 200 x 1270 mm
Qto_BeamBaseQuantities - Length: 1900; CrossSectionArea: 3.07113; NetSurfaceArea: 6.14225; NetVolume: 0.478513
Pset_BeamCommon - Reference: 200 x 1270 mm; Span: 1900 mm; Slope: 0 rad; Roll: 0 rad; IsExternal: no; LoadBearing: yes
Pset_Condition - AssessmentCondition: Empty
Pset_EnvironmentalImpactIndicators - Reference: 200 x 1270 mm; sets with these values: 2

# IfcBeam: BB_XX_Betonbalk_ rechthoekig_ center-center_SFB_200 x 1270 mm3 (3)
PredefinedType: BEAM; Material: BB_Beton_Bestaand
Cpset_Beam - LevelOfAccuracy: in te vullen door Buildwise
IfcRoot - Name: 200 x 1270 mm
Qto_BeamBaseQuantities - Length: 1900; CrossSectionArea: 0.254; OuterSurfaceArea: 5.586; GrossSurfaceArea: 6.094; NetSurfaceArea: 6.094; GrossVolume: 0.4826; NetVolume: 0.4826
Pset_BeamCommon - Reference: 200 x 1270 mm; Span: 1900 mm; Slope: 0 rad; Roll: 0 rad; IsExternal: no; LoadBearing: yes
Pset_Condition - AssessmentCondition: Empty
Pset_EnvironmentalImpactIndicators - Reference: 200 x 1270 mm; sets with these values: 2
Name (BB_XX_Betonbalk, rechthoekig, center-center_SFB:200 x 1270 mm:...) | In
655580 | 000
655923 | 010
695848 | 020

# IfcBeam: BB_XX_Betonbalk_ rechthoekig_ center-center_SFB_200 x 1270 mm5 (3)
PredefinedType: BEAM; Material: BB_Beton_Bestaand
Cpset_Beam - LevelOfAccuracy: in te vullen door Buildwise
IfcRoot - Name: 200 x 1270 mm
Qto_BeamBaseQuantities - Length: 1900; CrossSectionArea: 0.254; OuterSurfaceArea: 5.586; GrossSurfaceArea: 6.094; NetSurfaceArea: 6.094; GrossVolume: 0.4826; NetVolume: 0.4826
Pset_BeamCommon - Reference: 200 x 1270 mm; Span: 1900 mm; Slope: 0 rad; Roll: 0 rad; IsExternal: no; LoadBearing: yes
Pset_Condition - AssessmentCondition: Empty
Pset_EnvironmentalImpactIndicators - Reference: 200 x 1270 mm; sets with these values: 2
Name (BB_XX_Betonbalk, rechthoekig, center-center_SFB:200 x 1270 mm:...) | In
656293 | 000
656416 | 010
695850 | 020

# IfcBeam: BB_XX_Betonbalk_ rechthoekig_ center-center_SFB_200 x 260 mm, BB_XX_Betonbalk, rechthoekig, center-center_SFB:200 x 260 mm:678393
In: 000
PredefinedType: BEAM; Material: BB_Beton_Bestaand
Cpset_Beam - LevelOfAccuracy: in te vullen door Buildwise
IfcRoot - Name: 200 x 260 mm
Qto_BeamBaseQuantities - Length: 3400; CrossSectionArea: 0.052; OuterSurfaceArea: 3.128; GrossSurfaceArea: 3.232; NetSurfaceArea: 3.232; GrossVolume: 0.1768; NetVolume: 0.1768
Pset_BeamCommon - Reference: 200 x 260 mm; Span: 3400 mm; Slope: 0 rad; Roll: 0 rad; IsExternal: no; LoadBearing: yes
Pset_Condition - AssessmentCondition: Empty
Pset_EnvironmentalImpactIndicators - Reference: 200 x 260 mm; sets with these values: 2

# IfcBeam: BB_XX_Betonbalk_ rechthoekig_ center-center_SFB_200 x 260 mm1, BB_XX_Betonbalk, rechthoekig, center-center_SFB:200 x 260 mm:745069
In: 030
PredefinedType: BEAM; Material: BB_Beton_Bestaand
Cpset_Beam - LevelOfAccuracy: in te vullen door Buildwise
IfcRoot - Name: 200 x 260 mm
Qto_BeamBaseQuantities - Length: 1605; CrossSectionArea: 0.64053; NetSurfaceArea: 1.28106; NetVolume: 0.065312
Pset_BeamCommon - Reference: 200 x 260 mm; Span: 1605 mm; Slope: 0 rad; Roll: 0 rad; IsExternal: no; LoadBearing: yes
Pset_Condition - AssessmentCondition: Empty
Pset_EnvironmentalImpactIndicators - Reference: 200 x 260 mm; sets with these values: 2

# IfcBeam: BB_XX_Betonbalk_ rechthoekig_ center-center_SFB_200 x 260 mm3, BB_XX_Betonbalk, rechthoekig, center-center_SFB:200 x 260 mm:745403
In: 030
PredefinedType: BEAM; Material: BB_Beton_Bestaand
Cpset_Beam - LevelOfAccuracy: in te vullen door Buildwise
IfcRoot - Name: 200 x 260 mm
Qto_BeamBaseQuantities - Length: 1585; CrossSectionArea: 0.736845; NetSurfaceArea: 1.47369; NetVolume: 0.0761999
Pset_BeamCommon - Reference: 200 x 260 mm; Span: 1585 mm; Slope: 0 rad; Roll: 0 rad; IsExternal: no; LoadBearing: yes
Pset_Condition - AssessmentCondition: Empty
Pset_EnvironmentalImpactIndicators - Reference: 200 x 260 mm; sets with these values: 2

# IfcBeam: BB_XX_Betonbalk_ rechthoekig_ center-center_SFB_200 x 260 mm5, BB_XX_Betonbalk, rechthoekig, center-center_SFB:200 x 260 mm:745766
In: 030
PredefinedType: BEAM; Material: BB_Beton_Bestaand
Cpset_Beam - LevelOfAccuracy: in te vullen door Buildwise
IfcRoot - Name: 200 x 260 mm
Qto_BeamBaseQuantities - Length: 3260; CrossSectionArea: 0.052; OuterSurfaceArea: 2.9992; GrossSurfaceArea: 3.1032; NetSurfaceArea: 3.1032; GrossVolume: 0.16952; NetVolume: 0.16952
Pset_BeamCommon - Reference: 200 x 260 mm; Span: 3260 mm; Slope: 0 rad; Roll: 0 rad; IsExternal: no; LoadBearing: yes
Pset_Condition - AssessmentCondition: Empty
Pset_EnvironmentalImpactIndicators - Reference: 200 x 260 mm; sets with these values: 2

# IfcBeam: BB_XX_Betonbalk_ rechthoekig_ center-center_SFB_200 x 260 mm7, BB_XX_Betonbalk, rechthoekig, center-center_SFB:200 x 260 mm:746384
In: 030
PredefinedType: BEAM; Material: BB_Beton_Bestaand
Cpset_Beam - LevelOfAccuracy: in te vullen door Buildwise
IfcRoot - Name: 200 x 260 mm
Qto_BeamBaseQuantities - Length: 3385.64; CrossSectionArea: 0.052; OuterSurfaceArea: 3.11479; GrossSurfaceArea: 3.21879; NetSurfaceArea: 3.21879; GrossVolume: 0.176053; NetVolume: 0.176053
Pset_BeamCommon - Reference: 200 x 260 mm; Span: 3385.64 mm; Slope: 0 rad; Roll: 0 rad; IsExternal: no; LoadBearing: yes
Pset_Condition - AssessmentCondition: Empty
Pset_EnvironmentalImpactIndicators - Reference: 200 x 260 mm; sets with these values: 2

# IfcBeam: BB_XX_Betonbalk_ rechthoekig_ center-center_SFB_200 x 263 mm, BB_XX_Betonbalk, rechthoekig, center-center_SFB:200 x 263 mm:1259229
In: 030
PredefinedType: BEAM; Material: BB_Beton_Bestaand
Cpset_Beam - LevelOfAccuracy: in te vullen door Buildwise
IfcRoot - Name: 200 x 263 mm
Qto_BeamBaseQuantities - Length: 1097.99; CrossSectionArea: 0.0526; OuterSurfaceArea: 1.10841; GrossSurfaceArea: 1.21361; NetSurfaceArea: 1.21361; GrossVolume: 0.0629614; NetVolume: 0.0629614
Pset_BeamCommon - Reference: 200 x 263 mm; Span: 1097.99 mm; Slope: 0 rad; Roll: 0 rad; IsExternal: no; LoadBearing: yes
Pset_Condition - AssessmentCondition: Empty
Pset_EnvironmentalImpactIndicators - Reference: 200 x 263 mm; sets with these values: 2

# IfcBeam: BB_XX_Betonbalk_ rechthoekig_ center-center_SFB_200 x 380 mm (3)
PredefinedType: BEAM; Material: BB_Beton_Bestaand
Cpset_Beam - LevelOfAccuracy: in te vullen door Buildwise
IfcRoot - Name: 200 x 380 mm
Qto_BeamBaseQuantities - Length: 2600; CrossSectionArea: 0.076; OuterSurfaceArea: 3.016; GrossSurfaceArea: 3.168; NetSurfaceArea: 3.168; GrossVolume: 0.1976; NetVolume: 0.1976
Pset_BeamCommon - Reference: 200 x 380 mm; Span: 2600 mm; Slope: 0 rad; Roll: 0 rad; IsExternal: no; LoadBearing: yes
Pset_Condition - AssessmentCondition: Empty
Pset_EnvironmentalImpactIndicators - Reference: 200 x 380 mm; sets with these values: 2
Name (BB_XX_Betonbalk, rechthoekig, center-center_SFB:200 x 380 mm:...) | In
682580 | 000
683355 | 010
1973273 | 020

# IfcBeam: BB_XX_Betonbalk_ rechthoekig_ center-center_SFB_200 x 380 mm1, BB_XX_Betonbalk, rechthoekig, center-center_SFB:200 x 380 mm:750072
In: 000
PredefinedType: BEAM; Material: BB_Beton_Bestaand
Cpset_Beam - LevelOfAccuracy: in te vullen door Buildwise
IfcRoot - Name: 200 x 380 mm
Qto_BeamBaseQuantities - Length: 5400; CrossSectionArea: 0.076; OuterSurfaceArea: 6.264; GrossSurfaceArea: 6.416; NetSurfaceArea: 6.416; GrossVolume: 0.4104; NetVolume: 0.4104
Pset_BeamCommon - Reference: 200 x 380 mm; Span: 5400 mm; Slope: 0 rad; Roll: 0 rad; IsExternal: no; LoadBearing: yes
Pset_Condition - AssessmentCondition: Empty
Pset_EnvironmentalImpactIndicators - Reference: 200 x 380 mm; sets with these values: 2

# IfcBeam: BB_XX_Betonbalk_ rechthoekig_ center-center_SFB_200 x 380 mm3, BB_XX_Betonbalk, rechthoekig, center-center_SFB:200 x 380 mm:1216171
In: 010
PredefinedType: BEAM; Material: BB_Beton_Bestaand
Cpset_Beam - LevelOfAccuracy: in te vullen door Buildwise
IfcRoot - Name: 200 x 380 mm
Qto_BeamBaseQuantities - Length: 5400; CrossSectionArea: 0.076; OuterSurfaceArea: 6.264; GrossSurfaceArea: 6.416; NetSurfaceArea: 6.416; GrossVolume: 0.4104; NetVolume: 0.4104
Pset_BeamCommon - Reference: 200 x 380 mm; Span: 5400 mm; Slope: 0 rad; Roll: 0 rad; IsExternal: no; LoadBearing: yes
Pset_Condition - AssessmentCondition: Empty
Pset_EnvironmentalImpactIndicators - Reference: 200 x 380 mm; sets with these values: 2

# IfcBeam: BB_XX_Betonbalk_ rechthoekig_ center-center_SFB_200 x 380 mm5, BB_XX_Betonbalk, rechthoekig, center-center_SFB:200 x 380 mm:1216218
In: 020
PredefinedType: BEAM; Material: BB_Beton_Bestaand
Cpset_Beam - LevelOfAccuracy: in te vullen door Buildwise
IfcRoot - Name: 200 x 380 mm
Qto_BeamBaseQuantities - Length: 5560; CrossSectionArea: 0.076; OuterSurfaceArea: 6.4496; GrossSurfaceArea: 6.6016; NetSurfaceArea: 6.6016; GrossVolume: 0.42256; NetVolume: 0.42256
Pset_BeamCommon - Reference: 200 x 380 mm; Span: 5560 mm; Slope: 0 rad; Roll: 0 rad; IsExternal: no; LoadBearing: yes
Pset_Condition - AssessmentCondition: Empty
Pset_EnvironmentalImpactIndicators - Reference: 200 x 380 mm; sets with these values: 2

# IfcBeam: BB_XX_Betonbalk_ rechthoekig_ center-center_SFB_200 x 400 mm, BB_XX_Betonbalk, rechthoekig, center-center_SFB:200 x 400 mm:1048374
In: 010
PredefinedType: BEAM; Material: BB_Beton_Bestaand
Cpset_Beam - LevelOfAccuracy: in te vullen door Buildwise
IfcRoot - Name: 200 x 400 mm
Qto_BeamBaseQuantities - Length: 4384.06; CrossSectionArea: 0.08; OuterSurfaceArea: 5.26087; GrossSurfaceArea: 5.42087; NetSurfaceArea: 5.42087; GrossVolume: 0.350725; NetVolume: 0.350725
Pset_BeamCommon - Reference: 200 x 400 mm; Span: 4384.06 mm; Slope: 0 rad; Roll: 0 rad; IsExternal: no; LoadBearing: yes
Pset_Condition - AssessmentCondition: Empty
Pset_EnvironmentalImpactIndicators - Reference: 200 x 400 mm; sets with these values: 2

# IfcBeam: BB_XX_Betonbalk_ rechthoekig_ center-center_SFB_200 x 400 mm1, BB_XX_Betonbalk, rechthoekig, center-center_SFB:200 x 400 mm:1260137
In: 010
PredefinedType: BEAM; Material: BB_Beton_Bestaand
Cpset_Beam - LevelOfAccuracy: in te vullen door Buildwise
IfcRoot - Name: 200 x 400 mm
Qto_BeamBaseQuantities - Length: 4384.06; CrossSectionArea: 0.08; OuterSurfaceArea: 5.02087; GrossSurfaceArea: 5.18087; NetSurfaceArea: 5.18087; GrossVolume: 0.334725; NetVolume: 0.334725
Pset_BeamCommon - Reference: 200 x 400 mm; Span: 4384.06 mm; Slope: 0 rad; Roll: 0 rad; IsExternal: no; LoadBearing: yes
Pset_Condition - AssessmentCondition: Empty
Pset_EnvironmentalImpactIndicators - Reference: 200 x 400 mm; sets with these values: 2

# IfcBeam: BB_XX_Betonbalk_ rechthoekig_ center-center_SFB_200 x 400 mm11, BB_XX_Betonbalk, rechthoekig, center-center_SFB:200 x 400 mm:34144440
In: 040
PredefinedType: BEAM; Material: BB_Beton_Bestaand
Cpset_Beam - LevelOfAccuracy: in te vullen door Buildwise
IfcClassificationReference - TDS_link: .\05 As Builtdossier\2. Bouwkunde\2.1 Architectuur\2.1.3 open ruwbouw\TF S 4.3.1.2.5 A - Balken en lateien in gewapend beton.pdf
IfcRoot - Name: 200 x 400 mm
Qto_BeamBaseQuantities - Length: 155.797; CrossSectionArea: 0.08; OuterSurfaceArea: 0.0182518; GrossSurfaceArea: 0.178252; NetSurfaceArea: 0.178252; GrossVolume: 0.00121679; NetVolume: 0.00121679
Pset_BeamCommon - Reference: 200 x 400 mm; Span: 155.797 mm; Slope: 0 rad; Roll: 0 rad; IsExternal: no; LoadBearing: yes; FireRating: EI60
Pset_ConcreteElementGeneral - ConstructionMethod: prefabricated
Pset_Condition - AssessmentCondition: Empty
Pset_EnvironmentalImpactIndicators - Reference: 200 x 400 mm; sets with these values: 2

# IfcBeam: BB_XX_Betonbalk_ rechthoekig_ center-center_SFB_200 x 400 mm3, BB_XX_Betonbalk, rechthoekig, center-center_SFB:200 x 400 mm:701041
In: 020
PredefinedType: BEAM; Material: BB_Beton_Bestaand
Cpset_Beam - LevelOfAccuracy: in te vullen door Buildwise
IfcRoot - Name: 200 x 400 mm
Qto_BeamBaseQuantities - Length: 4384.06; CrossSectionArea: 0.08; OuterSurfaceArea: 5.02087; GrossSurfaceArea: 5.18087; NetSurfaceArea: 5.18087; GrossVolume: 0.334725; NetVolume: 0.334725
Pset_BeamCommon - Reference: 200 x 400 mm; Span: 4384.06 mm; Slope: 0 rad; Roll: 0 rad; IsExternal: no; LoadBearing: yes
Pset_Condition - AssessmentCondition: Empty
Pset_EnvironmentalImpactIndicators - Reference: 200 x 400 mm; sets with these values: 2

# IfcBeam: BB_XX_Betonbalk_ rechthoekig_ center-center_SFB_200 x 400 mm5, BB_XX_Betonbalk, rechthoekig, center-center_SFB:200 x 400 mm:701043
In: 020
PredefinedType: BEAM; Material: BB_Beton_Bestaand
Cpset_Beam - LevelOfAccuracy: in te vullen door Buildwise
IfcRoot - Name: 200 x 400 mm
Qto_BeamBaseQuantities - Length: 4384.06; CrossSectionArea: 0.08; OuterSurfaceArea: 5.26087; GrossSurfaceArea: 5.42087; NetSurfaceArea: 5.42087; GrossVolume: 0.350725; NetVolume: 0.350725
Pset_BeamCommon - Reference: 200 x 400 mm; Span: 4384.06 mm; Slope: 0 rad; Roll: 0 rad; IsExternal: no; LoadBearing: yes
Pset_Condition - AssessmentCondition: Empty
Pset_EnvironmentalImpactIndicators - Reference: 200 x 400 mm; sets with these values: 2

# IfcBeam: BB_XX_Betonbalk_ rechthoekig_ center-center_SFB_200 x 400 mm7, BB_XX_Betonbalk, rechthoekig, center-center_SFB:200 x 400 mm:34144437
In: 030
PredefinedType: BEAM; Material: BB_Beton_Bestaand
Cpset_Beam - LevelOfAccuracy: in te vullen door Buildwise
IfcClassificationReference - TDS_link: .\05 As Builtdossier\2. Bouwkunde\2.1 Architectuur\2.1.3 open ruwbouw\TF S 4.3.1.2.5 A - Balken en lateien in gewapend beton.pdf
IfcRoot - Name: 200 x 400 mm
Qto_BeamBaseQuantities - Length: 165.797; CrossSectionArea: 0.08; OuterSurfaceArea: 0.239018; GrossSurfaceArea: 0.399018; NetSurfaceArea: 0.399018; GrossVolume: 0.0159346; NetVolume: 0.0159346
Pset_BeamCommon - Reference: 200 x 400 mm; Span: 165.797 mm; Slope: 0 rad; Roll: 0 rad; IsExternal: no; LoadBearing: yes; FireRating: EI60
Pset_ConcreteElementGeneral - ConstructionMethod: prefabricated
Pset_Condition - AssessmentCondition: Empty
Pset_EnvironmentalImpactIndicators - Reference: 200 x 400 mm; sets with these values: 2

# IfcBeam: BB_XX_Betonbalk_ rechthoekig_ center-center_SFB_200 x 400 mm9, BB_XX_Betonbalk, rechthoekig, center-center_SFB:200 x 400 mm:34141943
In: 040
PredefinedType: BEAM; Material: BB_Beton_Bestaand
Cpset_Beam - LevelOfAccuracy: in te vullen door Buildwise
IfcClassificationReference - TDS_link: .\05 As Builtdossier\2. Bouwkunde\2.1 Architectuur\2.1.3 open ruwbouw\TF S 4.3.1.2.5 A - Balken en lateien in gewapend beton.pdf
IfcRoot - Name: 200 x 400 mm
Qto_BeamBaseQuantities - Length: 155.797; CrossSectionArea: 0.08; OuterSurfaceArea: 0.0177098; GrossSurfaceArea: 0.17771; NetSurfaceArea: 0.17771; GrossVolume: 0.00118066; NetVolume: 0.00118066
Pset_BeamCommon - Reference: 200 x 400 mm; Span: 155.797 mm; Slope: 0 rad; Roll: 0 rad; IsExternal: no; LoadBearing: yes; FireRating: EI60
Pset_ConcreteElementGeneral - ConstructionMethod: prefabricated
Pset_Condition - AssessmentCondition: Empty
Pset_EnvironmentalImpactIndicators - Reference: 200 x 400 mm; sets with these values: 2

# IfcBeam: BB_XX_Betonbalk_ rechthoekig_ center-center_SFB_200 x 500 mm, BB_XX_Betonbalk, rechthoekig, center-center_SFB:200 x 500 mm:980115
In: K20
PredefinedType: BEAM; Material: BB_Beton_Bestaand
Cpset_Beam - LevelOfAccuracy: in te vullen door Buildwise
IfcRoot - Name: 200 x 500 mm
Qto_BeamBaseQuantities - Length: 5600; CrossSectionArea: 0.1; OuterSurfaceArea: 7.84; GrossSurfaceArea: 8.04; NetSurfaceArea: 8.04; GrossVolume: 0.56; NetVolume: 0.56
Pset_BeamCommon - Reference: 200 x 500 mm; Span: 5600 mm; Slope: 0 rad; Roll: 0 rad; IsExternal: no; LoadBearing: yes
Pset_Condition - AssessmentCondition: Empty
Pset_EnvironmentalImpactIndicators - Reference: 200 x 500 mm; sets with these values: 2

# IfcBeam: BB_XX_Betonbalk_ rechthoekig_ center-center_SFB_200 x 500 mm1, BB_XX_Betonbalk, rechthoekig, center-center_SFB:200 x 500 mm:981905
In: K20
PredefinedType: BEAM; Material: BB_Beton_Bestaand
Cpset_Beam - LevelOfAccuracy: in te vullen door Buildwise
IfcRoot - Name: 200 x 500 mm
Qto_BeamBaseQuantities - Length: 2900; CrossSectionArea: 0.1; OuterSurfaceArea: 4.06; GrossSurfaceArea: 4.26; NetSurfaceArea: 4.26; GrossVolume: 0.29; NetVolume: 0.29
Pset_BeamCommon - Reference: 200 x 500 mm; Span: 2900 mm; Slope: 0 rad; Roll: 0 rad; IsExternal: no; LoadBearing: yes
Pset_Condition - AssessmentCondition: Empty
Pset_EnvironmentalImpactIndicators - Reference: 200 x 500 mm; sets with these values: 2

# IfcBeam: BB_XX_Betonbalk_ rechthoekig_ center-center_SFB_200 x 500 mm11, BB_XX_Betonbalk, rechthoekig, center-center_SFB:200 x 500 mm:898002
In: K10
PredefinedType: BEAM; Material: BB_Beton_Bestaand
Cpset_Beam - LevelOfAccuracy: in te vullen door Buildwise
IfcRoot - Name: 200 x 500 mm
Qto_BeamBaseQuantities - Length: 1920; CrossSectionArea: 0.1; OuterSurfaceArea: 2.688; GrossSurfaceArea: 2.888; NetSurfaceArea: 2.888; GrossVolume: 0.192; NetVolume: 0.192
Pset_BeamCommon - Reference: 200 x 500 mm; Span: 1920 mm; Slope: 0 rad; Roll: 0 rad; IsExternal: no; LoadBearing: yes
Pset_Condition - AssessmentCondition: Empty
Pset_EnvironmentalImpactIndicators - Reference: 200 x 500 mm; sets with these values: 2

# IfcBeam: BB_XX_Betonbalk_ rechthoekig_ center-center_SFB_200 x 500 mm13, BB_XX_Betonbalk, rechthoekig, center-center_SFB:200 x 500 mm:900488
In: K10
PredefinedType: BEAM; Material: BB_Beton_Bestaand
Cpset_Beam - LevelOfAccuracy: in te vullen door Buildwise
IfcRoot - Name: 200 x 500 mm
Qto_BeamBaseQuantities - Length: 800; CrossSectionArea: 0.1; OuterSurfaceArea: 1.12; GrossSurfaceArea: 1.32; NetSurfaceArea: 1.32; GrossVolume: 0.08; NetVolume: 0.08
Pset_BeamCommon - Reference: 200 x 500 mm; Span: 800 mm; Slope: 0 rad; Roll: 0 rad; IsExternal: no; LoadBearing: yes
Pset_Condition - AssessmentCondition: Empty
Pset_EnvironmentalImpactIndicators - Reference: 200 x 500 mm; sets with these values: 2

# IfcBeam: BB_XX_Betonbalk_ rechthoekig_ center-center_SFB_200 x 500 mm15, BB_XX_Betonbalk, rechthoekig, center-center_SFB:200 x 500 mm:905321
In: K10
PredefinedType: BEAM; Material: BB_Beton_Bestaand
Cpset_Beam - LevelOfAccuracy: in te vullen door Buildwise
IfcRoot - Name: 200 x 500 mm
Qto_BeamBaseQuantities - Length: 3000; CrossSectionArea: 0.1; OuterSurfaceArea: 4.2; GrossSurfaceArea: 4.4; NetSurfaceArea: 4.4; GrossVolume: 0.3; NetVolume: 0.3
Pset_BeamCommon - Reference: 200 x 500 mm; Span: 3000 mm; Slope: 0 rad; Roll: 0 rad; IsExternal: no; LoadBearing: yes
Pset_Condition - AssessmentCondition: Empty
Pset_EnvironmentalImpactIndicators - Reference: 200 x 500 mm; sets with these values: 2

# IfcBeam: BB_XX_Betonbalk_ rechthoekig_ center-center_SFB_200 x 500 mm17, BB_XX_Betonbalk, rechthoekig, center-center_SFB:200 x 500 mm:662592
In: 000
PredefinedType: BEAM; Material: BB_Beton_Bestaand
Cpset_Beam - LevelOfAccuracy: in te vullen door Buildwise
IfcRoot - Name: 200 x 500 mm
Qto_BeamBaseQuantities - Length: 4544.33; CrossSectionArea: 0.1; OuterSurfaceArea: 6.36457; GrossSurfaceArea: 6.56457; NetSurfaceArea: 6.56457; GrossVolume: 0.454612; NetVolume: 0.454612
Pset_BeamCommon - Reference: 200 x 500 mm; Span: 4544.33 mm; Slope: 0 rad; Roll: 0 rad; IsExternal: no; LoadBearing: yes
Pset_Condition - AssessmentCondition: Empty
Pset_EnvironmentalImpactIndicators - Reference: 200 x 500 mm; sets with these values: 2

# IfcBeam: BB_XX_Betonbalk_ rechthoekig_ center-center_SFB_200 x 500 mm19, BB_XX_Betonbalk, rechthoekig, center-center_SFB:200 x 500 mm:663314
In: 000
PredefinedType: BEAM; Material: BB_Beton_Bestaand
Cpset_Beam - LevelOfAccuracy: in te vullen door Buildwise
IfcRoot - Name: 200 x 500 mm
Qto_BeamBaseQuantities - Length: 4544.33; CrossSectionArea: 0.1; OuterSurfaceArea: 6.36206; GrossSurfaceArea: 6.56206; NetSurfaceArea: 6.56206; GrossVolume: 0.454433; NetVolume: 0.454433
Pset_BeamCommon - Reference: 200 x 500 mm; Span: 4544.33 mm; Slope: 0 rad; Roll: 0 rad; IsExternal: no; LoadBearing: yes
Pset_Condition - AssessmentCondition: Empty
Pset_EnvironmentalImpactIndicators - Reference: 200 x 500 mm; sets with these values: 2

# IfcBeam: BB_XX_Betonbalk_ rechthoekig_ center-center_SFB_200 x 500 mm3, BB_XX_Betonbalk, rechthoekig, center-center_SFB:200 x 500 mm:981907
In: K20
PredefinedType: BEAM; Material: BB_Beton_Bestaand
Cpset_Beam - LevelOfAccuracy: in te vullen door Buildwise
IfcRoot - Name: 200 x 500 mm
Qto_BeamBaseQuantities - Length: 2900; CrossSectionArea: 0.1; OuterSurfaceArea: 4.06; GrossSurfaceArea: 4.26; NetSurfaceArea: 4.26; GrossVolume: 0.29; NetVolume: 0.29
Pset_BeamCommon - Reference: 200 x 500 mm; Span: 2900 mm; Slope: 0 rad; Roll: 0 rad; IsExternal: no; LoadBearing: yes
Pset_Condition - AssessmentCondition: Empty
Pset_EnvironmentalImpactIndicators - Reference: 200 x 500 mm; sets with these values: 2

# IfcBeam: BB_XX_Betonbalk_ rechthoekig_ center-center_SFB_200 x 500 mm5, BB_XX_Betonbalk, rechthoekig, center-center_SFB:200 x 500 mm:981911
In: K20
PredefinedType: BEAM; Material: BB_Beton_Bestaand
Cpset_Beam - LevelOfAccuracy: in te vullen door Buildwise
IfcRoot - Name: 200 x 500 mm
Qto_BeamBaseQuantities - Length: 1900; CrossSectionArea: 0.1; OuterSurfaceArea: 2.66; GrossSurfaceArea: 2.86; NetSurfaceArea: 2.86; GrossVolume: 0.19; NetVolume: 0.19
Pset_BeamCommon - Reference: 200 x 500 mm; Span: 1900 mm; Slope: 0 rad; Roll: 0 rad; IsExternal: no; LoadBearing: yes
Pset_Condition - AssessmentCondition: Empty
Pset_EnvironmentalImpactIndicators - Reference: 200 x 500 mm; sets with these values: 2

# IfcBeam: BB_XX_Betonbalk_ rechthoekig_ center-center_SFB_200 x 500 mm7, BB_XX_Betonbalk, rechthoekig, center-center_SFB:200 x 500 mm:1001827
In: K20
PredefinedType: BEAM; Material: BB_Beton_Bestaand
Cpset_Beam - LevelOfAccuracy: in te vullen door Buildwise
IfcRoot - Name: 200 x 500 mm
Qto_BeamBaseQuantities - Length: 3000; CrossSectionArea: 0.1; OuterSurfaceArea: 4.2; GrossSurfaceArea: 4.4; NetSurfaceArea: 4.4; GrossVolume: 0.3; NetVolume: 0.3
Pset_BeamCommon - Reference: 200 x 500 mm; Span: 3000 mm; Slope: 0 rad; Roll: 0 rad; IsExternal: no; LoadBearing: yes
Pset_Condition - AssessmentCondition: Empty
Pset_EnvironmentalImpactIndicators - Reference: 200 x 500 mm; sets with these values: 2

# IfcBeam: BB_XX_Betonbalk_ rechthoekig_ center-center_SFB_200 x 500 mm9, BB_XX_Betonbalk, rechthoekig, center-center_SFB:200 x 500 mm:1010976
In: K20
PredefinedType: BEAM; Material: BB_Beton_Bestaand
Cpset_Beam - LevelOfAccuracy: in te vullen door Buildwise
IfcRoot - Name: 200 x 500 mm
Qto_BeamBaseQuantities - Length: 8200; CrossSectionArea: 5.8718; NetSurfaceArea: 11.7436; NetVolume: 0.808961
Pset_BeamCommon - Reference: 200 x 500 mm; Span: 8200 mm; Slope: 0 rad; Roll: 0 rad; IsExternal: no; LoadBearing: yes
Pset_Condition - AssessmentCondition: Empty
Pset_EnvironmentalImpactIndicators - Reference: 200 x 500 mm; sets with these values: 2

# IfcBeam: BB_XX_Betonbalk_ rechthoekig_ center-center_SFB_200 x 600 mm, BB_XX_Betonbalk, rechthoekig, center-center_SFB:200 x 600 mm:34134998
In: 010
PredefinedType: BEAM; Material: BB_Beton_Bestaand
Cpset_Beam - LevelOfAccuracy: in te vullen door Buildwise
IfcClassificationReference - TDS_link: .\05 As Builtdossier\2. Bouwkunde\2.1 Architectuur\2.1.3 open ruwbouw\TF S 4.3.1.2.5 A - Balken en lateien in gewapend beton.pdf
IfcRoot - Name: 200 x 600 mm
Qto_BeamBaseQuantities - Length: 165.797; CrossSectionArea: 0.260274; NetSurfaceArea: 0.520548; NetVolume: 0.0133407
Pset_BeamCommon - Reference: 200 x 600 mm; Span: 165.797 mm; Slope: 0 rad; Roll: 0 rad; IsExternal: no; LoadBearing: yes; FireRating: EI60
Pset_ConcreteElementGeneral - ConstructionMethod: prefabricated
Pset_Condition - AssessmentCondition: Empty
Pset_EnvironmentalImpactIndicators - Reference: 200 x 600 mm; sets with these values: 2

# IfcBeam: BB_XX_Betonbalk_ rechthoekig_ center-center_SFB_200 x 640 mm, BB_XX_Betonbalk, rechthoekig, center-center_SFB:200 x 640 mm:981915
In: K20
PredefinedType: BEAM; Material: BB_Beton_Bestaand
Cpset_Beam - LevelOfAccuracy: in te vullen door Buildwise
IfcRoot - Name: 200 x 640 mm
Qto_BeamBaseQuantities - Length: 960; CrossSectionArea: 0.128; OuterSurfaceArea: 1.6128; GrossSurfaceArea: 1.8688; NetSurfaceArea: 1.8688; GrossVolume: 0.12288; NetVolume: 0.12288
Pset_BeamCommon - Reference: 200 x 640 mm; Span: 960 mm; Slope: 0 rad; Roll: 0 rad; IsExternal: no; LoadBearing: yes
Pset_Condition - AssessmentCondition: Empty
Pset_EnvironmentalImpactIndicators - Reference: 200 x 640 mm; sets with these values: 2

# IfcBeam: BB_XX_Betonbalk_ rechthoekig_ center-center_SFB_200 x 640 mm1, BB_XX_Betonbalk, rechthoekig, center-center_SFB:200 x 640 mm:987791
In: K20
PredefinedType: BEAM; Material: BB_Beton_Bestaand
Cpset_Beam - LevelOfAccuracy: in te vullen door Buildwise
IfcRoot - Name: 200 x 640 mm
Qto_BeamBaseQuantities - Length: 6470; CrossSectionArea: 5.45144; NetSurfaceArea: 10.9029; NetVolume: 0.801525
Pset_BeamCommon - Reference: 200 x 640 mm; Span: 6470 mm; Slope: 0 rad; Roll: 0 rad; IsExternal: no; LoadBearing: yes
Pset_Condition - AssessmentCondition: Empty
Pset_EnvironmentalImpactIndicators - Reference: 200 x 640 mm; sets with these values: 2

# IfcBeam: BB_XX_Betonbalk_ rechthoekig_ center-center_SFB_200 x 700 mm, BB_XX_Betonbalk, rechthoekig, center-center_SFB:200 x 700 mm:981909
In: K20
PredefinedType: BEAM; Material: BB_Beton_Bestaand
Cpset_Beam - LevelOfAccuracy: in te vullen door Buildwise
IfcRoot - Name: 200 x 700 mm
Qto_BeamBaseQuantities - Length: 1215; CrossSectionArea: 0.14; OuterSurfaceArea: 2.187; GrossSurfaceArea: 2.467; NetSurfaceArea: 2.467; GrossVolume: 0.1701; NetVolume: 0.1701
Pset_BeamCommon - Reference: 200 x 700 mm; Span: 1215 mm; Slope: 0 rad; Roll: 0 rad; IsExternal: no; LoadBearing: yes
Pset_Condition - AssessmentCondition: Empty
Pset_EnvironmentalImpactIndicators - Reference: 200 x 700 mm; sets with these values: 2

# IfcBeam: BB_XX_Betonbalk_ rechthoekig_ center-center_SFB_200 x 700 mm1, BB_XX_Betonbalk, rechthoekig, center-center_SFB:200 x 700 mm:811012
In: K10
PredefinedType: BEAM; Material: BB_Beton_Bestaand
Cpset_Beam - LevelOfAccuracy: in te vullen door Buildwise
IfcRoot - Name: 200 x 700 mm
Qto_BeamBaseQuantities - Length: 5628.22; CrossSectionArea: 5.08901; NetSurfaceArea: 10.178; NetVolume: 0.761861
Pset_BeamCommon - Reference: 200 x 700 mm; Span: 5628.22 mm; Slope: 0 rad; Roll: 0 rad; IsExternal: no; LoadBearing: yes
Pset_Condition - AssessmentCondition: Empty
Pset_EnvironmentalImpactIndicators - Reference: 200 x 700 mm; sets with these values: 2

# IfcBeam: BB_XX_Betonbalk_ rechthoekig_ center-center_SFB_200 x 720 mm, BB_XX_Betonbalk, rechthoekig, center-center_SFB:200 x 720 mm:582809
In: 000
PredefinedType: BEAM; Material: BB_Beton_Bestaand
Cpset_Beam - LevelOfAccuracy: in te vullen door Buildwise
IfcRoot - Name: 200 x 720 mm
Qto_BeamBaseQuantities - Length: 3510.33; CrossSectionArea: 3.35906; NetSurfaceArea: 6.71812; NetVolume: 0.503226
Pset_BeamCommon - Reference: 200 x 720 mm; Span: 3510.33 mm; Slope: 0 rad; Roll: 0 rad; IsExternal: no; LoadBearing: yes
Pset_Condition - AssessmentCondition: Empty
Pset_EnvironmentalImpactIndicators - Reference: 200 x 720 mm; sets with these values: 2

# IfcBeam: BB_XX_Betonbalk_ rechthoekig_ center-center_SFB_200 x 720 mm1, BB_XX_Betonbalk, rechthoekig, center-center_SFB:200 x 720 mm:582976
In: 000
PredefinedType: BEAM; Material: BB_Beton_Bestaand
Cpset_Beam - LevelOfAccuracy: in te vullen door Buildwise
IfcRoot - Name: 200 x 720 mm
Qto_BeamBaseQuantities - Length: 3492.33; CrossSectionArea: 3.34257; NetSurfaceArea: 6.68515; NetVolume: 0.500646
Pset_BeamCommon - Reference: 200 x 720 mm; Span: 3492.33 mm; Slope: 0 rad; Roll: 0 rad; IsExternal: no; LoadBearing: yes
Pset_Condition - AssessmentCondition: Empty
Pset_EnvironmentalImpactIndicators - Reference: 200 x 720 mm; sets with these values: 2

# IfcBeam: BB_XX_Betonbalk_ rechthoekig_ center-center_SFB_200 x 720 mm11, BB_XX_Betonbalk, rechthoekig, center-center_SFB:200 x 720 mm:26465278
In: 000
PredefinedType: BEAM; Material: BB_Beton_Bestaand
Cpset_Beam - LevelOfAccuracy: in te vullen door Buildwise
IfcRoot - Name: 200 x 720 mm
Qto_BeamBaseQuantities - Length: 7110; CrossSectionArea: 0.144; OuterSurfaceArea: 13.0824; GrossSurfaceArea: 13.3704; NetSurfaceArea: 13.3704; GrossVolume: 1.02384; NetVolume: 1.02384
Pset_BeamCommon - Reference: 200 x 720 mm; Span: 7110 mm; Slope: 0 rad; Roll: 0 rad; IsExternal: no; LoadBearing: yes
Pset_Condition - AssessmentCondition: Empty
Pset_EnvironmentalImpactIndicators - Reference: 200 x 720 mm; sets with these values: 2

# IfcBeam: BB_XX_Betonbalk_ rechthoekig_ center-center_SFB_200 x 720 mm13, BB_XX_Betonbalk, rechthoekig, center-center_SFB:200 x 720 mm:646076
In: 010
PredefinedType: BEAM; Material: BB_Beton_Bestaand
Cpset_Beam - LevelOfAccuracy: in te vullen door Buildwise
IfcRoot - Name: 200 x 720 mm
Qto_BeamBaseQuantities - Length: 3658.17; CrossSectionArea: 3.47316; NetSurfaceArea: 6.94632; NetVolume: 0.51075
Pset_BeamCommon - Reference: 200 x 720 mm; Span: 3658.17 mm; Slope: 0 rad; Roll: 0 rad; IsExternal: no; LoadBearing: yes
Pset_Condition - AssessmentCondition: Empty
Pset_EnvironmentalImpactIndicators - Reference: 200 x 720 mm; sets with these values: 2

# IfcBeam: BB_XX_Betonbalk_ rechthoekig_ center-center_SFB_200 x 720 mm15, BB_XX_Betonbalk, rechthoekig, center-center_SFB:200 x 720 mm:646078
In: 010
PredefinedType: BEAM; Material: BB_Beton_Bestaand
Cpset_Beam - LevelOfAccuracy: in te vullen door Buildwise
IfcRoot - Name: 200 x 720 mm
Qto_BeamBaseQuantities - Length: 3663.68; CrossSectionArea: 3.46574; NetSurfaceArea: 6.93148; NetVolume: 0.501094
Pset_BeamCommon - Reference: 200 x 720 mm; Span: 3663.68 mm; Slope: 0 rad; Roll: 0 rad; IsExternal: no; LoadBearing: yes
Pset_Condition - AssessmentCondition: Empty
Pset_EnvironmentalImpactIndicators - Reference: 200 x 720 mm; sets with these values: 2

# IfcBeam: BB_XX_Betonbalk_ rechthoekig_ center-center_SFB_200 x 720 mm17, BB_XX_Betonbalk, rechthoekig, center-center_SFB:200 x 720 mm:646080
In: 010
PredefinedType: BEAM; Material: BB_Beton_Bestaand
Cpset_Beam - LevelOfAccuracy: in te vullen door Buildwise
IfcRoot - Name: 200 x 720 mm
Qto_BeamBaseQuantities - Length: 3650.94; CrossSectionArea: 3.46755; NetSurfaceArea: 6.9351; NetVolume: 0.520207
Pset_BeamCommon - Reference: 200 x 720 mm; Span: 3650.94 mm; Slope: 0 rad; Roll: 0 rad; IsExternal: no; LoadBearing: yes
Pset_Condition - AssessmentCondition: Empty
Pset_EnvironmentalImpactIndicators - Reference: 200 x 720 mm; sets with these values: 2

# IfcBeam: BB_XX_Betonbalk_ rechthoekig_ center-center_SFB_200 x 720 mm19, BB_XX_Betonbalk, rechthoekig, center-center_SFB:200 x 720 mm:720000
In: 010
PredefinedType: BEAM; Material: BB_Beton_Bestaand
Cpset_Beam - LevelOfAccuracy: in te vullen door Buildwise
IfcRoot - Name: 200 x 720 mm
Qto_BeamBaseQuantities - Length: 6230; CrossSectionArea: 5.89224; NetSurfaceArea: 11.7845; NetVolume: 0.883534
Pset_BeamCommon - Reference: 200 x 720 mm; Span: 6230 mm; Slope: 0 rad; Roll: 0 rad; IsExternal: no; LoadBearing: yes
Pset_Condition - AssessmentCondition: Empty
Pset_EnvironmentalImpactIndicators - Reference: 200 x 720 mm; sets with these values: 2

# IfcBeam: BB_XX_Betonbalk_ rechthoekig_ center-center_SFB_200 x 720 mm21, BB_XX_Betonbalk, rechthoekig, center-center_SFB:200 x 720 mm:1039124
In: 010
PredefinedType: BEAM; Material: BB_Beton_Bestaand
Cpset_Beam - LevelOfAccuracy: in te vullen door Buildwise
IfcRoot - Name: 200 x 720 mm
Qto_BeamBaseQuantities - Length: 2446.18; CrossSectionArea: 0.144; OuterSurfaceArea: 4.50097; GrossSurfaceArea: 4.78897; NetSurfaceArea: 4.78897; GrossVolume: 0.35225; NetVolume: 0.35225
Pset_BeamCommon - Reference: 200 x 720 mm; Span: 2446.18 mm; Slope: 0 rad; Roll: 0 rad; IsExternal: no; LoadBearing: yes
Pset_Condition - AssessmentCondition: Empty
Pset_EnvironmentalImpactIndicators - Reference: 200 x 720 mm; sets with these values: 2

# IfcBeam: BB_XX_Betonbalk_ rechthoekig_ center-center_SFB_200 x 720 mm23, BB_XX_Betonbalk, rechthoekig, center-center_SFB:200 x 720 mm:1866909
In: 010
PredefinedType: BEAM; Material: BB_Beton_Bestaand
Cpset_Beam - LevelOfAccuracy: in te vullen door Buildwise
IfcRoot - Name: 200 x 720 mm
Qto_BeamBaseQuantities - Length: 3107.53; CrossSectionArea: 2.96976; NetSurfaceArea: 5.93952; NetVolume: 0.431023
Pset_BeamCommon - Reference: 200 x 720 mm; Span: 3107.53 mm; Slope: 0 rad; Roll: 0 rad; IsExternal: no; LoadBearing: yes
Pset_Condition - AssessmentCondition: Empty
Pset_EnvironmentalImpactIndicators - Reference: 200 x 720 mm; sets with these values: 2

# IfcBeam: BB_XX_Betonbalk_ rechthoekig_ center-center_SFB_200 x 720 mm25, BB_XX_Betonbalk, rechthoekig, center-center_SFB:200 x 720 mm:26481062
In: 010
PredefinedType: BEAM; Material: BB_Beton_Bestaand
Cpset_Beam - LevelOfAccuracy: in te vullen door Buildwise
IfcRoot - Name: 200 x 720 mm
Qto_BeamBaseQuantities - Length: 7110; CrossSectionArea: 0.144; OuterSurfaceArea: 13.0824; GrossSurfaceArea: 13.3704; NetSurfaceArea: 13.3704; GrossVolume: 1.02384; NetVolume: 1.02384
Pset_BeamCommon - Reference: 200 x 720 mm; Span: 7110 mm; Slope: 0 rad; Roll: 0 rad; IsExternal: no; LoadBearing: yes
Pset_Condition - AssessmentCondition: Empty
Pset_EnvironmentalImpactIndicators - Reference: 200 x 720 mm; sets with these values: 2

# IfcBeam: BB_XX_Betonbalk_ rechthoekig_ center-center_SFB_200 x 720 mm27 (3)
PredefinedType: BEAM; Material: BB_Beton_Bestaand
Cpset_Beam - LevelOfAccuracy: in te vullen door Buildwise
IfcClassificationReference - TDS_link: .\05 As Builtdossier\2. Bouwkunde\2.1 Architectuur\2.1.3 open ruwbouw\TF S 4.3.1.2.5 A - Balken en lateien in gewapend beton.pdf
IfcRoot - Name: 200 x 720 mm
Qto_BeamBaseQuantities - Length: 2700; CrossSectionArea: 0.144; OuterSurfaceArea: 5.04693; GrossSurfaceArea: 5.33493; NetSurfaceArea: 5.33493; GrossVolume: 0.394977; NetVolume: 0.394977
Pset_BeamCommon - Reference: 200 x 720 mm; Span: 2700 mm; Slope: 0 rad; Roll: 0 rad; IsExternal: no; LoadBearing: yes
Pset_ConcreteElementGeneral - ConstructionMethod: prefabricated
Pset_Condition - AssessmentCondition: Empty
Pset_EnvironmentalImpactIndicators - Reference: 200 x 720 mm; sets with these values: 2
Name (BB_XX_Betonbalk, rechthoekig, center-center_SFB:200 x 720 mm:...) | In
34081264 | 010
34081547 | 020
34081550 | 030

# IfcBeam: BB_XX_Betonbalk_ rechthoekig_ center-center_SFB_200 x 720 mm29, BB_XX_Betonbalk, rechthoekig, center-center_SFB:200 x 720 mm:695722
In: 020
PredefinedType: BEAM; Material: BB_Beton_Bestaand
Cpset_Beam - LevelOfAccuracy: in te vullen door Buildwise
IfcRoot - Name: 200 x 720 mm
Qto_BeamBaseQuantities - Length: 3528.65; CrossSectionArea: 3.37584; NetSurfaceArea: 6.75168; NetVolume: 0.505853
Pset_BeamCommon - Reference: 200 x 720 mm; Span: 3528.65 mm; Slope: 0 rad; Roll: 0 rad; IsExternal: no; LoadBearing: yes
Pset_Condition - AssessmentCondition: Empty
Pset_EnvironmentalImpactIndicators - Reference: 200 x 720 mm; sets with these values: 2

# IfcBeam: BB_XX_Betonbalk_ rechthoekig_ center-center_SFB_200 x 720 mm3, BB_XX_Betonbalk, rechthoekig, center-center_SFB:200 x 720 mm:932675
In: 000
PredefinedType: BEAM; Material: BB_Beton_Bestaand
Cpset_Beam - LevelOfAccuracy: in te vullen door Buildwise
IfcRoot - Name: 200 x 720 mm
Qto_BeamBaseQuantities - Length: 20673.6; CrossSectionArea: 19.0636; NetSurfaceArea: 38.1272; NetVolume: 2.95263
Pset_BeamCommon - Reference: 200 x 720 mm; Span: 20673.6 mm; Slope: 0 rad; Roll: 0 rad; IsExternal: no; LoadBearing: yes
Pset_Condition - AssessmentCondition: Empty
Pset_EnvironmentalImpactIndicators - Reference: 200 x 720 mm; sets with these values: 2

# IfcBeam: BB_XX_Betonbalk_ rechthoekig_ center-center_SFB_200 x 720 mm31, BB_XX_Betonbalk, rechthoekig, center-center_SFB:200 x 720 mm:695724
In: 020
PredefinedType: BEAM; Material: BB_Beton_Bestaand
Cpset_Beam - LevelOfAccuracy: in te vullen door Buildwise
IfcRoot - Name: 200 x 720 mm
Qto_BeamBaseQuantities - Length: 3519.46; CrossSectionArea: 3.36742; NetSurfaceArea: 6.73483; NetVolume: 0.504535
Pset_BeamCommon - Reference: 200 x 720 mm; Span: 3519.46 mm; Slope: 0 rad; Roll: 0 rad; IsExternal: no; LoadBearing: yes
Pset_Condition - AssessmentCondition: Empty
Pset_EnvironmentalImpactIndicators - Reference: 200 x 720 mm; sets with these values: 2

# IfcBeam: BB_XX_Betonbalk_ rechthoekig_ center-center_SFB_200 x 720 mm33, BB_XX_Betonbalk, rechthoekig, center-center_SFB:200 x 720 mm:695726
In: 020
PredefinedType: BEAM; Material: BB_Beton_Bestaand
Cpset_Beam - LevelOfAccuracy: in te vullen door Buildwise
IfcRoot - Name: 200 x 720 mm
Qto_BeamBaseQuantities - Length: 3833.45; CrossSectionArea: 3.655; NetSurfaceArea: 7.31; NetVolume: 0.549549
Pset_BeamCommon - Reference: 200 x 720 mm; Span: 3833.45 mm; Slope: 0 rad; Roll: 0 rad; IsExternal: no; LoadBearing: yes
Pset_Condition - AssessmentCondition: Empty
Pset_EnvironmentalImpactIndicators - Reference: 200 x 720 mm; sets with these values: 2

# IfcBeam: BB_XX_Betonbalk_ rechthoekig_ center-center_SFB_200 x 720 mm35, BB_XX_Betonbalk, rechthoekig, center-center_SFB:200 x 720 mm:695728
In: 020
PredefinedType: BEAM; Material: BB_Beton_Bestaand
Cpset_Beam - LevelOfAccuracy: in te vullen door Buildwise
IfcRoot - Name: 200 x 720 mm
Qto_BeamBaseQuantities - Length: 3763.58; CrossSectionArea: 3.58996; NetSurfaceArea: 7.17992; NetVolume: 0.539369
Pset_BeamCommon - Reference: 200 x 720 mm; Span: 3763.58 mm; Slope: 0 rad; Roll: 0 rad; IsExternal: no; LoadBearing: yes
Pset_Condition - AssessmentCondition: Empty
Pset_EnvironmentalImpactIndicators - Reference: 200 x 720 mm; sets with these values: 2

# IfcBeam: BB_XX_Betonbalk_ rechthoekig_ center-center_SFB_200 x 720 mm37, BB_XX_Betonbalk, rechthoekig, center-center_SFB:200 x 720 mm:1041872
In: 020
PredefinedType: BEAM; Material: BB_Beton_Bestaand
Cpset_Beam - LevelOfAccuracy: in te vullen door Buildwise
IfcRoot - Name: 200 x 720 mm
Qto_BeamBaseQuantities - Length: 2446.18; CrossSectionArea: 2.39382; NetSurfaceArea: 4.78764; NetVolume: 0.33891
Pset_BeamCommon - Reference: 200 x 720 mm; Span: 2446.18 mm; Slope: 0 rad; Roll: 0 rad; IsExternal: no; LoadBearing: yes
Pset_Condition - AssessmentCondition: Empty
Pset_EnvironmentalImpactIndicators - Reference: 200 x 720 mm; sets with these values: 2

# IfcBeam: BB_XX_Betonbalk_ rechthoekig_ center-center_SFB_200 x 720 mm39, BB_XX_Betonbalk, rechthoekig, center-center_SFB:200 x 720 mm:26481070
In: 020
PredefinedType: BEAM; Material: BB_Beton_Bestaand
Cpset_Beam - LevelOfAccuracy: in te vullen door Buildwise
IfcRoot - Name: 200 x 720 mm
Qto_BeamBaseQuantities - Length: 7110; CrossSectionArea: 0.144; OuterSurfaceArea: 13.0824; GrossSurfaceArea: 13.3704; NetSurfaceArea: 13.3704; GrossVolume: 1.02384; NetVolume: 1.02384
Pset_BeamCommon - Reference: 200 x 720 mm; Span: 7110 mm; Slope: 0 rad; Roll: 0 rad; IsExternal: no; LoadBearing: yes
Pset_Condition - AssessmentCondition: Empty
Pset_EnvironmentalImpactIndicators - Reference: 200 x 720 mm; sets with these values: 2

# IfcBeam: BB_XX_Betonbalk_ rechthoekig_ center-center_SFB_200 x 720 mm41, BB_XX_Betonbalk, rechthoekig, center-center_SFB:200 x 720 mm:1042545
In: 030
PredefinedType: BEAM; Material: BB_Beton_Bestaand
Cpset_Beam - LevelOfAccuracy: in te vullen door Buildwise
IfcRoot - Name: 200 x 720 mm
Qto_BeamBaseQuantities - Length: 13360; CrossSectionArea: 12.374; NetSurfaceArea: 24.7481; NetVolume: 1.90979
Pset_BeamCommon - Reference: 200 x 720 mm; Span: 13360 mm; Slope: 0 rad; Roll: 0 rad; IsExternal: no; LoadBearing: yes
Pset_Condition - AssessmentCondition: Empty
Pset_EnvironmentalImpactIndicators - Reference: 200 x 720 mm; sets with these values: 2

# IfcBeam: BB_XX_Betonbalk_ rechthoekig_ center-center_SFB_200 x 720 mm43, BB_XX_Betonbalk, rechthoekig, center-center_SFB:200 x 720 mm:34081563
In: 040
PredefinedType: BEAM; Material: BB_Beton_Bestaand
Cpset_Beam - LevelOfAccuracy: in te vullen door Buildwise
IfcClassificationReference - TDS_link: .\05 As Builtdossier\2. Bouwkunde\2.1 Architectuur\2.1.3 open ruwbouw\TF S 4.3.1.2.5 A - Balken en lateien in gewapend beton.pdf
IfcRoot - Name: 200 x 720 mm
Qto_BeamBaseQuantities - Length: 2756.67; CrossSectionArea: 0.144; OuterSurfaceArea: 4.98859; GrossSurfaceArea: 5.27659; NetSurfaceArea: 5.27659; GrossVolume: 0.390411; NetVolume: 0.390411
Pset_BeamCommon - Reference: 200 x 720 mm; Span: 2756.67 mm; Slope: 0 rad; Roll: 0 rad; IsExternal: no; LoadBearing: yes; FireRating: EI60
Pset_ConcreteElementGeneral - ConstructionMethod: prefabricated
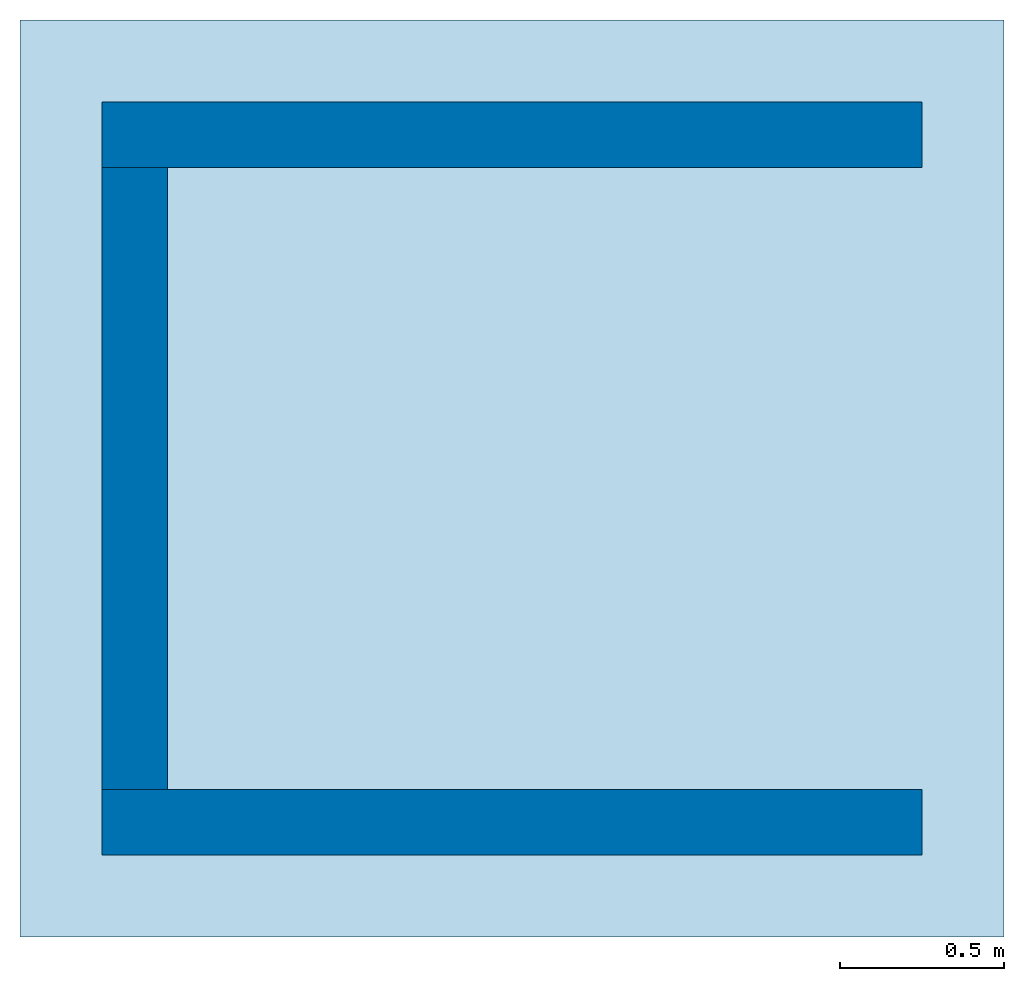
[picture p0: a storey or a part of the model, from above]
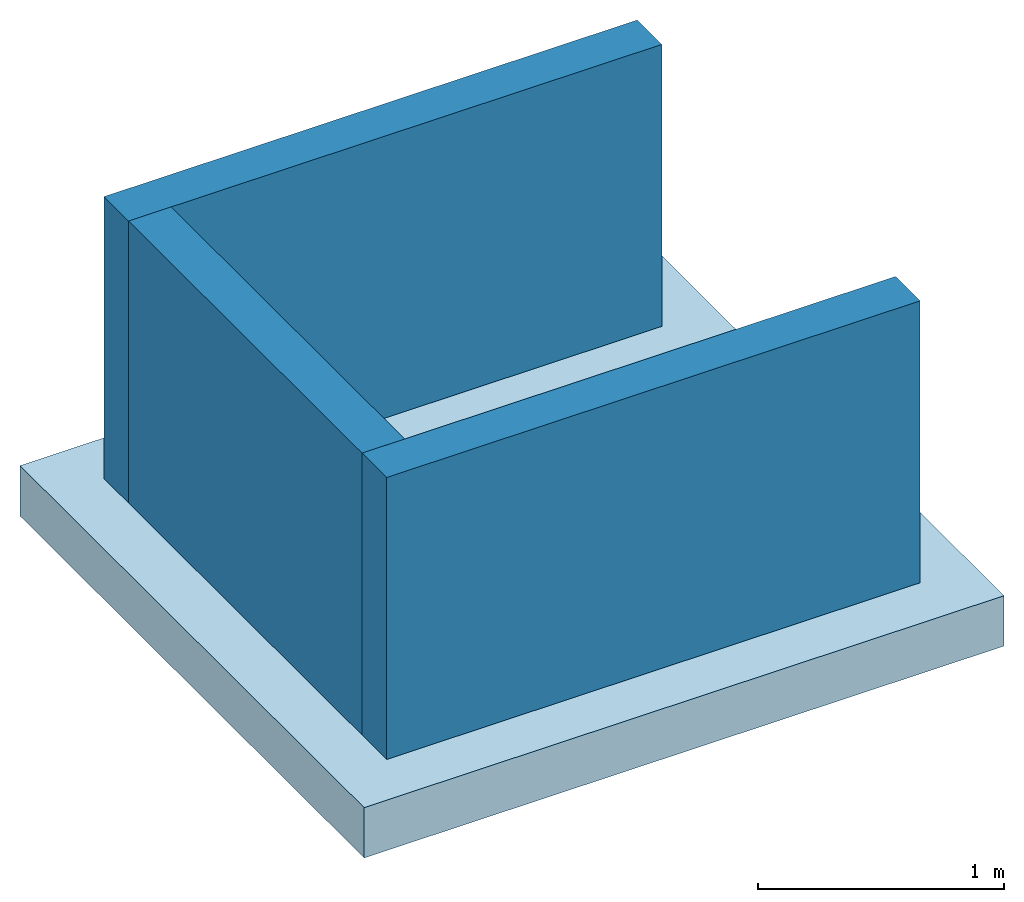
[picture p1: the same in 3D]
Properties of the parts of a building model (IFC4X3_ADD2), part 9 of 28

# IfcBeam: BB_XX_Betonbalk_ rechthoekig_ center-center_SFB_200 x 720 mm43, BB_XX_Betonbalk, rechthoekig, center-center_SFB:200 x 720 mm:34081563
Pset_Condition - AssessmentCondition: Empty
Pset_EnvironmentalImpactIndicators - Reference: 200 x 720 mm; sets with these values: 2

# IfcBeam: BB_XX_Betonbalk_ rechthoekig_ center-center_SFB_200 x 720 mm5, BB_XX_Betonbalk, rechthoekig, center-center_SFB:200 x 720 mm:1041332
In: 000
PredefinedType: BEAM; Material: BB_Beton_Bestaand
Cpset_Beam - LevelOfAccuracy: in te vullen door Buildwise
IfcRoot - Name: 200 x 720 mm
Qto_BeamBaseQuantities - Length: 2446.18; CrossSectionArea: 2.39015; NetSurfaceArea: 4.78031; NetVolume: 0.34404
Pset_BeamCommon - Reference: 200 x 720 mm; Span: 2446.18 mm; Slope: 0 rad; Roll: 0 rad; IsExternal: no; LoadBearing: yes
Pset_Condition - AssessmentCondition: Empty
Pset_EnvironmentalImpactIndicators - Reference: 200 x 720 mm; sets with these values: 2

# IfcBeam: BB_XX_Betonbalk_ rechthoekig_ center-center_SFB_200 x 720 mm7, BB_XX_Betonbalk, rechthoekig, center-center_SFB:200 x 720 mm:1866905
In: 000
PredefinedType: BEAM; Material: BB_Beton_Bestaand
Cpset_Beam - LevelOfAccuracy: in te vullen door Buildwise
IfcRoot - Name: 200 x 720 mm
Qto_BeamBaseQuantities - Length: 3518.54; CrossSectionArea: 3.36648; NetSurfaceArea: 6.73296; NetVolume: 0.504388
Pset_BeamCommon - Reference: 200 x 720 mm; Span: 3518.54 mm; Slope: 0 rad; Roll: 0 rad; IsExternal: no; LoadBearing: yes
Pset_Condition - AssessmentCondition: Empty
Pset_EnvironmentalImpactIndicators - Reference: 200 x 720 mm; sets with these values: 2

# IfcBeam: BB_XX_Betonbalk_ rechthoekig_ center-center_SFB_200 x 720 mm9, BB_XX_Betonbalk, rechthoekig, center-center_SFB:200 x 720 mm:1867289
In: 000
PredefinedType: BEAM; Material: BB_Beton_Bestaand
Cpset_Beam - LevelOfAccuracy: in te vullen door Buildwise
IfcRoot - Name: 200 x 720 mm
Qto_BeamBaseQuantities - Length: 3630.35; CrossSectionArea: 3.46898; NetSurfaceArea: 6.93797; NetVolume: 0.520432
Pset_BeamCommon - Reference: 200 x 720 mm; Span: 3630.35 mm; Slope: 0 rad; Roll: 0 rad; IsExternal: no; LoadBearing: yes
Pset_Condition - AssessmentCondition: Empty
Pset_EnvironmentalImpactIndicators - Reference: 200 x 720 mm; sets with these values: 2

# IfcBeam: BB_XX_Betonbalk_ rechthoekig_ center-center_SFB_200 x 770 mm, BB_XX_Betonbalk, rechthoekig, center-center_SFB:200 x 770 mm:1212990
In: 000
PredefinedType: BEAM; Material: BB_Beton_Bestaand
Cpset_Beam - LevelOfAccuracy: in te vullen door Buildwise
IfcRoot - Name: 200 x 770 mm
Qto_BeamBaseQuantities - Length: 1570; CrossSectionArea: 0.154; OuterSurfaceArea: 3.0458; GrossSurfaceArea: 3.3538; NetSurfaceArea: 3.3538; GrossVolume: 0.24178; NetVolume: 0.24178
Pset_BeamCommon - Reference: 200 x 770 mm; Span: 1570 mm; Slope: 0 rad; Roll: 0 rad; IsExternal: no; LoadBearing: yes
Pset_Condition - AssessmentCondition: Empty
Pset_EnvironmentalImpactIndicators - Reference: 200 x 770 mm; sets with these values: 2

# IfcBeam: BB_XX_Betonbalk_ rechthoekig_ center-center_SFB_200 x 770 mm1 (2)
PredefinedType: BEAM; Material: BB_Beton_Bestaand
Cpset_Beam - LevelOfAccuracy: in te vullen door Buildwise
IfcRoot - Name: 200 x 770 mm
Qto_BeamBaseQuantities - Length: 910; CrossSectionArea: 0.154; OuterSurfaceArea: 1.7654; GrossSurfaceArea: 2.0734; NetSurfaceArea: 2.0734; GrossVolume: 0.14014; NetVolume: 0.14014
Pset_BeamCommon - Reference: 200 x 770 mm; Span: 910 mm; Slope: 0 rad; Roll: 0 rad; IsExternal: no; LoadBearing: yes
Pset_Condition - AssessmentCondition: Empty
Pset_EnvironmentalImpactIndicators - Reference: 200 x 770 mm; sets with these values: 2
Name (BB_XX_Betonbalk, rechthoekig, center-center_SFB:200 x 770 mm:...) | In
683432 | 010
696017 | 020

# IfcBeam: BB_XX_Betonbalk_ rechthoekig_ center-center_SFB_200 x 770 mm3, BB_XX_Betonbalk, rechthoekig, center-center_SFB:200 x 770 mm:684097
In: 010
PredefinedType: BEAM; Material: BB_Beton_Bestaand
Cpset_Beam - LevelOfAccuracy: in te vullen door Buildwise
IfcRoot - Name: 200 x 770 mm
Qto_BeamBaseQuantities - Length: 1605; CrossSectionArea: 0.154; OuterSurfaceArea: 3.1137; GrossSurfaceArea: 3.4217; NetSurfaceArea: 3.4217; GrossVolume: 0.24717; NetVolume: 0.24717
Pset_BeamCommon - Reference: 200 x 770 mm; Span: 1605 mm; Slope: 0 rad; Roll: 0 rad; IsExternal: no; LoadBearing: yes
Pset_Condition - AssessmentCondition: Empty
Pset_EnvironmentalImpactIndicators - Reference: 200 x 770 mm; sets with these values: 2

# IfcBeam: BB_XX_Betonbalk_ rechthoekig_ center-center_SFB_200 x 770 mm5, BB_XX_Betonbalk, rechthoekig, center-center_SFB:200 x 770 mm:696052
In: 020
PredefinedType: BEAM; Material: BB_Beton_Bestaand
Cpset_Beam - LevelOfAccuracy: in te vullen door Buildwise
IfcRoot - Name: 200 x 770 mm
Qto_BeamBaseQuantities - Length: 1560; CrossSectionArea: 0.154; OuterSurfaceArea: 3.0458; GrossSurfaceArea: 3.3538; NetSurfaceArea: 3.3538; GrossVolume: 0.24178; NetVolume: 0.24178
Pset_BeamCommon - Reference: 200 x 770 mm; Span: 1560 mm; Slope: 0 rad; Roll: 0 rad; IsExternal: no; LoadBearing: yes
Pset_Condition - AssessmentCondition: Empty
Pset_EnvironmentalImpactIndicators - Reference: 200 x 770 mm; sets with these values: 2

# IfcBeam: BB_XX_Betonbalk_ rechthoekig_ center-center_SFB_200 x 790 mm, BB_XX_Betonbalk, rechthoekig, center-center_SFB:200 x 790 mm:34208727
In: 050
PredefinedType: BEAM; Material: BB_Beton_Bestaand
Cpset_Beam - LevelOfAccuracy: in te vullen door Buildwise
IfcClassificationReference - TDS_link: .\05 As Builtdossier\2. Bouwkunde\2.1 Architectuur\2.1.3 open ruwbouw\TF S 4.3.1.2.5 A - Balken en lateien in gewapend beton.pdf
IfcRoot - Name: 200 x 790 mm
Qto_BeamBaseQuantities - Length: 15411.8; CrossSectionArea: 15.4141; NetSurfaceArea: 30.8283; NetVolume: 2.43508
Pset_BeamCommon - Reference: 200 x 790 mm; Span: 15411.8 mm; Slope: 0 rad; Roll: 0 rad; IsExternal: no; LoadBearing: yes
Pset_ConcreteElementGeneral - ConstructionMethod: prefabricated
Pset_Condition - AssessmentCondition: Empty
Pset_EnvironmentalImpactIndicators - Reference: 200 x 790 mm; sets with these values: 2

# IfcBeam: BB_XX_Betonbalk_ rechthoekig_ center-center_SFB_200 x 820 mm, BB_XX_Betonbalk, rechthoekig, center-center_SFB:200 x 820 mm:677626
In: 000
PredefinedType: BEAM; Material: BB_Beton_Bestaand
Cpset_Beam - LevelOfAccuracy: in te vullen door Buildwise
IfcRoot - Name: 200 x 820 mm
Qto_BeamBaseQuantities - Length: 1700; CrossSectionArea: 0.164; OuterSurfaceArea: 3.468; GrossSurfaceArea: 3.796; NetSurfaceArea: 3.796; GrossVolume: 0.2788; NetVolume: 0.2788
Pset_BeamCommon - Reference: 200 x 820 mm; Span: 1700 mm; Slope: 0 rad; Roll: 0 rad; IsExternal: no; LoadBearing: yes
Pset_Condition - AssessmentCondition: Empty
Pset_EnvironmentalImpactIndicators - Reference: 200 x 820 mm; sets with these values: 2

# IfcBeam: BB_XX_Betonbalk_ rechthoekig_ center-center_SFB_200 x 820 mm1, BB_XX_Betonbalk, rechthoekig, center-center_SFB:200 x 820 mm:679839
In: 010
PredefinedType: BEAM; Material: BB_Beton_Bestaand
Cpset_Beam - LevelOfAccuracy: in te vullen door Buildwise
IfcRoot - Name: 200 x 820 mm
Qto_BeamBaseQuantities - Length: 1760; CrossSectionArea: 0.164; OuterSurfaceArea: 3.5904; GrossSurfaceArea: 3.9184; NetSurfaceArea: 3.9184; GrossVolume: 0.28864; NetVolume: 0.28864
Pset_BeamCommon - Reference: 200 x 820 mm; Span: 1760 mm; Slope: 0 rad; Roll: 0 rad; IsExternal: no; LoadBearing: yes
Pset_Condition - AssessmentCondition: Empty
Pset_EnvironmentalImpactIndicators - Reference: 200 x 820 mm; sets with these values: 2

# IfcBeam: BB_XX_Betonbalk_ rechthoekig_ center-center_SFB_200 x 830 mm, BB_XX_Betonbalk, rechthoekig, center-center_SFB:200 x 830 mm:34151091
In: 040
PredefinedType: BEAM; Material: BB_Beton_Bestaand
Cpset_Beam - LevelOfAccuracy: in te vullen door Buildwise
IfcClassificationReference - TDS_link: .\05 As Builtdossier\2. Bouwkunde\2.1 Architectuur\2.1.3 open ruwbouw\TF S 4.3.1.2.5 A - Balken en lateien in gewapend beton.pdf
IfcRoot - Name: 200 x 830 mm
Qto_BeamBaseQuantities - Length: 11601.7; CrossSectionArea: 0.166; OuterSurfaceArea: 23.7452; GrossSurfaceArea: 24.0772; NetSurfaceArea: 24.0772; GrossVolume: 1.91345; NetVolume: 1.91345
Pset_BeamCommon - Reference: 200 x 830 mm; Span: 11601.7 mm; Slope: 0 rad; Roll: 0 rad; IsExternal: no; LoadBearing: yes
Pset_ConcreteElementGeneral - ConstructionMethod: prefabricated
Pset_Condition - AssessmentCondition: Empty
Pset_EnvironmentalImpactIndicators - Reference: 200 x 830 mm; sets with these values: 2

# IfcBeam: BB_XX_Betonbalk_ rechthoekig_ center-center_SFB_200 x 830 mm1, BB_XX_Betonbalk, rechthoekig, center-center_SFB:200 x 830 mm:34151625
In: 040
PredefinedType: BEAM; Material: BB_Beton_Bestaand
Cpset_Beam - LevelOfAccuracy: in te vullen door Buildwise
IfcClassificationReference - TDS_link: .\05 As Builtdossier\2. Bouwkunde\2.1 Architectuur\2.1.3 open ruwbouw\TF S 4.3.1.2.5 A - Balken en lateien in gewapend beton.pdf
IfcRoot - Name: 200 x 830 mm
Qto_BeamBaseQuantities - Length: 11531.7; CrossSectionArea: 0.166; OuterSurfaceArea: 38.6662; GrossSurfaceArea: 38.9982; NetSurfaceArea: 38.9982; GrossVolume: 3.11582; NetVolume: 3.11582
Pset_BeamCommon - Reference: 200 x 830 mm; Span: 11531.7 mm; Slope: 0 rad; Roll: 0 rad; IsExternal: no; LoadBearing: yes
Pset_ConcreteElementGeneral - ConstructionMethod: prefabricated
Pset_Condition - AssessmentCondition: Empty
Pset_EnvironmentalImpactIndicators - Reference: 200 x 830 mm; sets with these values: 2

# IfcBeam: BB_XX_Betonbalk_ rechthoekig_ center-center_SFB_200 x 830 mm3, BB_XX_Betonbalk, rechthoekig, center-center_SFB:200 x 830 mm:34151909
In: 040
PredefinedType: BEAM; Material: BB_Beton_Bestaand
Cpset_Beam - LevelOfAccuracy: in te vullen door Buildwise
IfcClassificationReference - TDS_link: .\05 As Builtdossier\2. Bouwkunde\2.1 Architectuur\2.1.3 open ruwbouw\TF S 4.3.1.2.5 A - Balken en lateien in gewapend beton.pdf
IfcRoot - Name: 200 x 830 mm
Qto_BeamBaseQuantities - Length: 11601.7; CrossSectionArea: 0.166; OuterSurfaceArea: 23.6665; GrossSurfaceArea: 23.9985; NetSurfaceArea: 23.9985; GrossVolume: 1.90711; NetVolume: 1.90711
Pset_BeamCommon - Reference: 200 x 830 mm; Span: 11601.7 mm; Slope: 0 rad; Roll: 0 rad; IsExternal: no; LoadBearing: yes
Pset_ConcreteElementGeneral - ConstructionMethod: prefabricated
Pset_Condition - AssessmentCondition: Empty
Pset_EnvironmentalImpactIndicators - Reference: 200 x 830 mm; sets with these values: 2

# IfcBeam: BB_XX_Betonbalk_ rechthoekig_ center-center_SFB_200 x 830 mm5, BB_XX_Betonbalk, rechthoekig, center-center_SFB:200 x 830 mm:34151911
In: 040
PredefinedType: BEAM; Material: BB_Beton_Bestaand
Cpset_Beam - LevelOfAccuracy: in te vullen door Buildwise
IfcClassificationReference - TDS_link: .\05 As Builtdossier\2. Bouwkunde\2.1 Architectuur\2.1.3 open ruwbouw\TF S 4.3.1.2.5 A - Balken en lateien in gewapend beton.pdf
IfcRoot - Name: 200 x 830 mm
Qto_BeamBaseQuantities - Length: 11461.7; CrossSectionArea: 0.166; OuterSurfaceArea: 38.5014; GrossSurfaceArea: 38.8334; NetSurfaceArea: 38.8334; GrossVolume: 3.10254; NetVolume: 3.10254
Pset_BeamCommon - Reference: 200 x 830 mm; Span: 11461.7 mm; Slope: 0 rad; Roll: 0 rad; IsExternal: no; LoadBearing: yes
Pset_ConcreteElementGeneral - ConstructionMethod: prefabricated
Pset_Condition - AssessmentCondition: Empty
Pset_EnvironmentalImpactIndicators - Reference: 200 x 830 mm; sets with these values: 2

# IfcBeam: BB_XX_Betonbalk_ rechthoekig_ center-center_SFB_200 x 930 mm (2)
PredefinedType: BEAM; Material: BB_Beton_Bestaand
Cpset_Beam - LevelOfAccuracy: in te vullen door Buildwise
IfcRoot - Name: 200 x 930 mm
Qto_BeamBaseQuantities - Length: 910; CrossSectionArea: 0.186; OuterSurfaceArea: 2.0566; GrossSurfaceArea: 2.4286; NetSurfaceArea: 2.4286; GrossVolume: 0.16926; NetVolume: 0.16926
Pset_BeamCommon - Reference: 200 x 930 mm; Span: 910 mm; Slope: 0 rad; Roll: 0 rad; IsExternal: no; LoadBearing: yes
Pset_Condition - AssessmentCondition: Empty
Pset_EnvironmentalImpactIndicators - Reference: 200 x 930 mm; sets with these values: 2
Name (BB_XX_Betonbalk, rechthoekig, center-center_SFB:200 x 930 mm:...) | In
793910 | 000
1258862 | 010

# IfcBeam: BB_XX_Betonbalk_ rechthoekig_ center-center_SFB_200 x 930 mm1, BB_XX_Betonbalk, rechthoekig, center-center_SFB:200 x 930 mm:1258655
In: 020
PredefinedType: BEAM; Material: BB_Beton_Bestaand
Cpset_Beam - LevelOfAccuracy: in te vullen door Buildwise
IfcRoot - Name: 200 x 930 mm
Qto_BeamBaseQuantities - Length: 920; CrossSectionArea: 0.186; OuterSurfaceArea: 2.0792; GrossSurfaceArea: 2.4512; NetSurfaceArea: 2.4512; GrossVolume: 0.17112; NetVolume: 0.17112
Pset_BeamCommon - Reference: 200 x 930 mm; Span: 920 mm; Slope: 0 rad; Roll: 0 rad; IsExternal: no; LoadBearing: yes
Pset_Condition - AssessmentCondition: Empty
Pset_EnvironmentalImpactIndicators - Reference: 200 x 930 mm; sets with these values: 2

# IfcBeam: BB_XX_Betonbalk_ rechthoekig_ center-center_SFB_290 x 410 mm, BB_XX_Betonbalk, rechthoekig, center-center_SFB:290 x 410 mm:766099
In: 030
PredefinedType: BEAM; Material: BB_Beton_Bestaand
Cpset_Beam - LevelOfAccuracy: in te vullen door Buildwise
IfcRoot - Name: 290 x 410 mm
Qto_BeamBaseQuantities - Length: 9200; CrossSectionArea: 0.1189; OuterSurfaceArea: 12.88; GrossSurfaceArea: 13.1178; NetSurfaceArea: 13.1178; GrossVolume: 1.09388; NetVolume: 1.09388
Pset_BeamCommon - Reference: 290 x 410 mm; Span: 9200 mm; Slope: 0 rad; Roll: 0 rad; IsExternal: no; LoadBearing: yes
Pset_Condition - AssessmentCondition: Empty
Pset_EnvironmentalImpactIndicators - Reference: 290 x 410 mm; sets with these values: 2

# IfcBeam: BB_XX_Betonbalk_ rechthoekig_ center-center_SFB_290 x 410 mm1, BB_XX_Betonbalk, rechthoekig, center-center_SFB:290 x 410 mm:769528
In: 030
PredefinedType: BEAM; Material: BB_Beton_Bestaand
Cpset_Beam - LevelOfAccuracy: in te vullen door Buildwise
IfcRoot - Name: 290 x 410 mm
Qto_BeamBaseQuantities - Length: 9040; CrossSectionArea: 0.1189; OuterSurfaceArea: 12.656; GrossSurfaceArea: 12.8938; NetSurfaceArea: 12.8938; GrossVolume: 1.07486; NetVolume: 1.07486
Pset_BeamCommon - Reference: 290 x 410 mm; Span: 9040 mm; Slope: 0 rad; Roll: 0 rad; IsExternal: no; LoadBearing: yes
Pset_Condition - AssessmentCondition: Empty
Pset_EnvironmentalImpactIndicators - Reference: 290 x 410 mm; sets with these values: 2

# IfcBeam: BB_XX_Betonbalk_ rechthoekig_ center-center_SFB_290 x 700 mm, BB_XX_Betonbalk, rechthoekig, center-center_SFB:290 x 700 mm:804021
In: K10
PredefinedType: BEAM; Material: BB_Beton_Bestaand
Cpset_Beam - LevelOfAccuracy: in te vullen door Buildwise
IfcRoot - Name: 290 x 700 mm
Qto_BeamBaseQuantities - Length: 21620; CrossSectionArea: 21.5897; NetSurfaceArea: 43.1794; NetVolume: 4.19069
Pset_BeamCommon - Reference: 290 x 700 mm; Span: 21620 mm; Slope: 0 rad; Roll: 0 rad; IsExternal: no; LoadBearing: yes
Pset_Condition - AssessmentCondition: Empty
Pset_EnvironmentalImpactIndicators - Reference: 290 x 700 mm; sets with these values: 2

# IfcBeam: BB_XX_Betonbalk_ rechthoekig_ center-center_SFB_290 x 700 mm1, BB_XX_Betonbalk, rechthoekig, center-center_SFB:290 x 700 mm:940051
In: K10
PredefinedType: BEAM; Material: BB_Beton_Bestaand
Cpset_Beam - LevelOfAccuracy: in te vullen door Buildwise
IfcRoot - Name: 290 x 700 mm
Qto_BeamBaseQuantities - Length: 5210; CrossSectionArea: 0.203; OuterSurfaceArea: 10.3158; GrossSurfaceArea: 10.7218; NetSurfaceArea: 10.7218; GrossVolume: 1.05763; NetVolume: 1.05763
Pset_BeamCommon - Reference: 290 x 700 mm; Span: 5210 mm; Slope: 0 rad; Roll: 0 rad; IsExternal: no; LoadBearing: yes
Pset_Condition - AssessmentCondition: Empty
Pset_EnvironmentalImpactIndicators - Reference: 290 x 700 mm; sets with these values: 2

# IfcBeam: BB_XX_Betonbalk_ rechthoekig_ center-center_SFB_290 x 700 mm11, BB_XX_Betonbalk, rechthoekig, center-center_SFB:290 x 700 mm:941398
In: K10
PredefinedType: BEAM; Material: BB_Beton_Bestaand
Cpset_Beam - LevelOfAccuracy: in te vullen door Buildwise
IfcRoot - Name: 290 x 700 mm
Qto_BeamBaseQuantities - Length: 490; CrossSectionArea: 0.07; OuterSurfaceArea: 0.784; GrossSurfaceArea: 0.924; NetSurfaceArea: 0.924; GrossVolume: 0.0343; NetVolume: 0.0343
Pset_BeamCommon - Reference: 290 x 700 mm; Span: 490 mm; Slope: 0 rad; Roll: 0 rad; IsExternal: no; LoadBearing: yes
Pset_Condition - AssessmentCondition: Empty
Pset_EnvironmentalImpactIndicators - Reference: 290 x 700 mm; sets with these values: 2

# IfcBeam: BB_XX_Betonbalk_ rechthoekig_ center-center_SFB_290 x 700 mm13, BB_XX_Betonbalk, rechthoekig, center-center_SFB:290 x 700 mm:941505
In: K10
PredefinedType: BEAM; Material: BB_Beton_Bestaand
Cpset_Beam - LevelOfAccuracy: in te vullen door Buildwise
IfcRoot - Name: 290 x 700 mm
Qto_BeamBaseQuantities - Length: 340; CrossSectionArea: 0.07; OuterSurfaceArea: 0.544; GrossSurfaceArea: 0.684; NetSurfaceArea: 0.684; GrossVolume: 0.0238; NetVolume: 0.0238
Pset_BeamCommon - Reference: 290 x 700 mm; Span: 340 mm; Slope: 0 rad; Roll: 0 rad; IsExternal: no; LoadBearing: yes
Pset_Condition - AssessmentCondition: Empty
Pset_EnvironmentalImpactIndicators - Reference: 290 x 700 mm; sets with these values: 2

# IfcBeam: BB_XX_Betonbalk_ rechthoekig_ center-center_SFB_290 x 700 mm15, BB_XX_Betonbalk, rechthoekig, center-center_SFB:290 x 700 mm:941630
In: K10
PredefinedType: BEAM; Material: BB_Beton_Bestaand
Cpset_Beam - LevelOfAccuracy: in te vullen door Buildwise
IfcRoot - Name: 290 x 700 mm
Qto_BeamBaseQuantities - Length: 6680; CrossSectionArea: 0.203; OuterSurfaceArea: 13.2264; GrossSurfaceArea: 13.6324; NetSurfaceArea: 13.6324; GrossVolume: 1.35604; NetVolume: 1.35604
Pset_BeamCommon - Reference: 290 x 700 mm; Span: 6680 mm; Slope: 0 rad; Roll: 0 rad; IsExternal: no; LoadBearing: yes
Pset_Condition - AssessmentCondition: Empty
Pset_EnvironmentalImpactIndicators - Reference: 290 x 700 mm; sets with these values: 2

# IfcBeam: BB_XX_Betonbalk_ rechthoekig_ center-center_SFB_290 x 700 mm17, BB_XX_Betonbalk, rechthoekig, center-center_SFB:290 x 700 mm:942308
In: K10
PredefinedType: BEAM; Material: BB_Beton_Bestaand
Cpset_Beam - LevelOfAccuracy: in te vullen door Buildwise
IfcRoot - Name: 290 x 700 mm
Qto_BeamBaseQuantities - Length: 5180; CrossSectionArea: 0.203; OuterSurfaceArea: 10.2564; GrossSurfaceArea: 10.6624; NetSurfaceArea: 10.6624; GrossVolume: 1.05154; NetVolume: 1.05154
Pset_BeamCommon - Reference: 290 x 700 mm; Span: 5180 mm; Slope: 0 rad; Roll: 0 rad; IsExternal: no; LoadBearing: yes
Pset_Condition - AssessmentCondition: Empty
Pset_EnvironmentalImpactIndicators - Reference: 290 x 700 mm; sets with these values: 2

# IfcBeam: BB_XX_Betonbalk_ rechthoekig_ center-center_SFB_290 x 700 mm3, BB_XX_Betonbalk, rechthoekig, center-center_SFB:290 x 700 mm:940274
In: K10
PredefinedType: BEAM; Material: BB_Beton_Bestaand
Cpset_Beam - LevelOfAccuracy: in te vullen door Buildwise
IfcRoot - Name: 290 x 700 mm
Qto_BeamBaseQuantities - Length: 6660; CrossSectionArea: 0.203; OuterSurfaceArea: 13.2759; GrossSurfaceArea: 13.6819; NetSurfaceArea: 13.6819; GrossVolume: 1.36111; NetVolume: 1.36111
Pset_BeamCommon - Reference: 290 x 700 mm; Span: 6660 mm; Slope: 0 rad; Roll: 0 rad; IsExternal: no; LoadBearing: yes
Pset_Condition - AssessmentCondition: Empty
Pset_EnvironmentalImpactIndicators - Reference: 290 x 700 mm; sets with these values: 2

# IfcBeam: BB_XX_Betonbalk_ rechthoekig_ center-center_SFB_290 x 700 mm5, BB_XX_Betonbalk, rechthoekig, center-center_SFB:290 x 700 mm:940723
In: K10
PredefinedType: BEAM; Material: BB_Beton_Bestaand
Cpset_Beam - LevelOfAccuracy: in te vullen door Buildwise
IfcRoot - Name: 290 x 700 mm
Qto_BeamBaseQuantities - Length: 340; CrossSectionArea: 0.07; OuterSurfaceArea: 0.544; GrossSurfaceArea: 0.684; NetSurfaceArea: 0.684; GrossVolume: 0.0238; NetVolume: 0.0238
Pset_BeamCommon - Reference: 290 x 700 mm; Span: 340 mm; Slope: 0 rad; Roll: 0 rad; IsExternal: no; LoadBearing: yes
Pset_Condition - AssessmentCondition: Empty
Pset_EnvironmentalImpactIndicators - Reference: 290 x 700 mm; sets with these values: 2

# IfcBeam: BB_XX_Betonbalk_ rechthoekig_ center-center_SFB_290 x 700 mm7, BB_XX_Betonbalk, rechthoekig, center-center_SFB:290 x 700 mm:941146
In: K10
PredefinedType: BEAM; Material: BB_Beton_Bestaand
Cpset_Beam - LevelOfAccuracy: in te vullen door Buildwise
IfcRoot - Name: 290 x 700 mm
Qto_BeamBaseQuantities - Length: 4910; CrossSectionArea: 0.203; OuterSurfaceArea: 9.7218; GrossSurfaceArea: 10.1278; NetSurfaceArea: 10.1278; GrossVolume: 0.99673; NetVolume: 0.99673
Pset_BeamCommon - Reference: 290 x 700 mm; Span: 4910 mm; Slope: 0 rad; Roll: 0 rad; IsExternal: no; LoadBearing: yes
Pset_Condition - AssessmentCondition: Empty
Pset_EnvironmentalImpactIndicators - Reference: 290 x 700 mm; sets with these values: 2

# IfcBeam: BB_XX_Betonbalk_ rechthoekig_ center-center_SFB_290 x 700 mm9, BB_XX_Betonbalk, rechthoekig, center-center_SFB:290 x 700 mm:941225
In: K10
PredefinedType: BEAM; Material: BB_Beton_Bestaand
Cpset_Beam - LevelOfAccuracy: in te vullen door Buildwise
IfcRoot - Name: 290 x 700 mm
Qto_BeamBaseQuantities - Length: 490; CrossSectionArea: 0.07; OuterSurfaceArea: 0.784; GrossSurfaceArea: 0.924; NetSurfaceArea: 0.924; GrossVolume: 0.0343; NetVolume: 0.0343
Pset_BeamCommon - Reference: 290 x 700 mm; Span: 490 mm; Slope: 0 rad; Roll: 0 rad; IsExternal: no; LoadBearing: yes
Pset_Condition - AssessmentCondition: Empty
Pset_EnvironmentalImpactIndicators - Reference: 290 x 700 mm; sets with these values: 2

# IfcBeam: BB_XX_Betonbalk_ rechthoekig_ center-center_SFB_290 x 720 mm, BB_XX_Betonbalk, rechthoekig, center-center_SFB:290 x 720 mm:929684
In: K10
PredefinedType: BEAM; Material: BB_Beton_Bestaand
Cpset_Beam - LevelOfAccuracy: in te vullen door Buildwise
IfcRoot - Name: 290 x 720 mm
Qto_BeamBaseQuantities - Length: 5200; CrossSectionArea: 0.2088; OuterSurfaceArea: 10.504; GrossSurfaceArea: 10.9216; NetSurfaceArea: 10.9216; GrossVolume: 1.08576; NetVolume: 1.08576
Pset_BeamCommon - Reference: 290 x 720 mm; Span: 5200 mm; Slope: 0 rad; Roll: 0 rad; IsExternal: no; LoadBearing: yes
Pset_Condition - AssessmentCondition: Empty
Pset_EnvironmentalImpactIndicators - Reference: 290 x 720 mm; sets with these values: 2

# IfcBeam: BB_XX_Betonbalk_ rechthoekig_ center-center_SFB_300 x 390 mm, BB_XX_Betonbalk, rechthoekig, center-center_SFB:300 x 390 mm:708044
In: 010
PredefinedType: BEAM; Material: BB_Beton_Bestaand
Cpset_Beam - LevelOfAccuracy: in te vullen door Buildwise
IfcRoot - Name: 300 x 390 mm
Qto_BeamBaseQuantities - Length: 6755; CrossSectionArea: 0.117; OuterSurfaceArea: 9.3219; GrossSurfaceArea: 9.5559; NetSurfaceArea: 9.5559; GrossVolume: 0.790335; NetVolume: 0.790335
Pset_BeamCommon - Reference: 300 x 390 mm; Span: 6755 mm; Slope: 0 rad; Roll: 0 rad; IsExternal: no; LoadBearing: yes
Pset_Condition - AssessmentCondition: Empty
Pset_EnvironmentalImpactIndicators - Reference: 300 x 390 mm; sets with these values: 2

# IfcBeam: BB_XX_Betonbalk_ rechthoekig_ center-center_SFB_300 x 390 mm1, BB_XX_Betonbalk, rechthoekig, center-center_SFB:300 x 390 mm:712027
In: 020
PredefinedType: BEAM; Material: BB_Beton_Bestaand
Cpset_Beam - LevelOfAccuracy: in te vullen door Buildwise
IfcRoot - Name: 300 x 390 mm
Qto_BeamBaseQuantities - Length: 6755; CrossSectionArea: 0.117; OuterSurfaceArea: 9.3219; GrossSurfaceArea: 9.5559; NetSurfaceArea: 9.5559; GrossVolume: 0.790335; NetVolume: 0.790335
Pset_BeamCommon - Reference: 300 x 390 mm; Span: 6755 mm; Slope: 0 rad; Roll: 0 rad; IsExternal: no; LoadBearing: yes
Pset_Condition - AssessmentCondition: Empty
Pset_EnvironmentalImpactIndicators - Reference: 300 x 390 mm; sets with these values: 2

# IfcBeam: BB_XX_Betonbalk_ rechthoekig_ center-center_SFB_300 x 410 mm, BB_XX_Betonbalk, rechthoekig, center-center_SFB:300 x 410 mm:998496
In: K20
PredefinedType: BEAM; Material: BB_Beton_Bestaand
Cpset_Beam - LevelOfAccuracy: in te vullen door Buildwise
IfcRoot - Name: 300 x 410 mm
Qto_BeamBaseQuantities - Length: 7375; CrossSectionArea: 0.123; OuterSurfaceArea: 10.4725; GrossSurfaceArea: 10.7185; NetSurfaceArea: 10.7185; GrossVolume: 0.907125; NetVolume: 0.907125
Pset_BeamCommon - Reference: 300 x 410 mm; Span: 7375 mm; Slope: 0 rad; Roll: 0 rad; IsExternal: no; LoadBearing: yes
Pset_Condition - AssessmentCondition: Empty
Pset_EnvironmentalImpactIndicators - Reference: 300 x 410 mm; sets with these values: 2

# IfcBeam: BB_XX_Betonbalk_ rechthoekig_ center-center_SFB_300 x 410 mm1, BB_XX_Betonbalk, rechthoekig, center-center_SFB:300 x 410 mm:807581
In: K10
PredefinedType: BEAM; Material: BB_Beton_Bestaand
Cpset_Beam - LevelOfAccuracy: in te vullen door Buildwise
IfcRoot - Name: 300 x 410 mm
Qto_BeamBaseQuantities - Length: 7375; CrossSectionArea: 0.123; OuterSurfaceArea: 10.4725; GrossSurfaceArea: 10.7185; NetSurfaceArea: 10.7185; GrossVolume: 0.907125; NetVolume: 0.907125
Pset_BeamCommon - Reference: 300 x 410 mm; Span: 7375 mm; Slope: 0 rad; Roll: 0 rad; IsExternal: no; LoadBearing: yes
Pset_Condition - AssessmentCondition: Empty
Pset_EnvironmentalImpactIndicators - Reference: 300 x 410 mm; sets with these values: 2

# IfcBeam: BB_XX_Betonbalk_ rechthoekig_ center-center_SFB_300 x 500 mm, BB_XX_Betonbalk, rechthoekig, center-center_SFB:300 x 500 mm:946951
In: K20
PredefinedType: BEAM; Material: BB_Beton_Bestaand
Cpset_Beam - LevelOfAccuracy: in te vullen door Buildwise
IfcRoot - Name: 300 x 500 mm
Qto_BeamBaseQuantities - Length: 5440; CrossSectionArea: 0.15; OuterSurfaceArea: 8.704; GrossSurfaceArea: 9.004; NetSurfaceArea: 9.004; GrossVolume: 0.816; NetVolume: 0.816
Pset_BeamCommon - Reference: 300 x 500 mm; Span: 5440 mm; Slope: 0 rad; Roll: 0 rad; IsExternal: no; LoadBearing: yes
Pset_Condition - AssessmentCondition: Empty
Pset_EnvironmentalImpactIndicators - Reference: 300 x 500 mm; sets with these values: 2

# IfcBeam: BB_XX_Betonbalk_ rechthoekig_ center-center_SFB_300 x 500 mm1, BB_XX_Betonbalk, rechthoekig, center-center_SFB:300 x 500 mm:992341
In: K20
PredefinedType: BEAM; Material: BB_Beton_Bestaand
Cpset_Beam - LevelOfAccuracy: in te vullen door Buildwise
IfcRoot - Name: 300 x 500 mm
Qto_BeamBaseQuantities - Length: 4100; CrossSectionArea: 0.15; OuterSurfaceArea: 6.56; GrossSurfaceArea: 6.86; NetSurfaceArea: 6.86; GrossVolume: 0.615; NetVolume: 0.615
Pset_BeamCommon - Reference: 300 x 500 mm; Span: 4100 mm; Slope: 0 rad; Roll: 0 rad; IsExternal: no; LoadBearing: yes
Pset_Condition - AssessmentCondition: Empty
Pset_EnvironmentalImpactIndicators - Reference: 300 x 500 mm; sets with these values: 2

# IfcBeam: BB_XX_Betonbalk_ rechthoekig_ center-center_SFB_300 x 500 mm3, BB_XX_Betonbalk, rechthoekig, center-center_SFB:300 x 500 mm:1007557
In: K20
PredefinedType: BEAM; Material: BB_Beton_Bestaand
Cpset_Beam - LevelOfAccuracy: in te vullen door Buildwise
IfcRoot - Name: 300 x 500 mm
Qto_BeamBaseQuantities - Length: 19990; CrossSectionArea: 16.0166; NetSurfaceArea: 32.0332; NetVolume: 2.8408
Pset_BeamCommon - Reference: 300 x 500 mm; Span: 19990 mm; Slope: 0 rad; Roll: 0 rad; IsExternal: no; LoadBearing: yes
Pset_Condition - AssessmentCondition: Empty
Pset_EnvironmentalImpactIndicators - Reference: 300 x 500 mm; sets with these values: 2

# IfcBeam: BB_XX_Betonbalk_ rechthoekig_ center-center_SFB_300 x 500 mm5, BB_XX_Betonbalk, rechthoekig, center-center_SFB:300 x 500 mm:1010133
In: K20
PredefinedType: BEAM; Material: BB_Beton_Bestaand
Cpset_Beam - LevelOfAccuracy: in te vullen door Buildwise
IfcRoot - Name: 300 x 500 mm
Qto_BeamBaseQuantities - Length: 5480; CrossSectionArea: 0.15; OuterSurfaceArea: 8.768; GrossSurfaceArea: 9.068; NetSurfaceArea: 9.068; GrossVolume: 0.822; NetVolume: 0.822
Pset_BeamCommon - Reference: 300 x 500 mm; Span: 5480 mm; Slope: 0 rad; Roll: 0 rad; IsExternal: no; LoadBearing: yes
Pset_Condition - AssessmentCondition: Empty
Pset_EnvironmentalImpactIndicators - Reference: 300 x 500 mm; sets with these values: 2

# IfcBeam: BB_XX_Betonbalk_ rechthoekig_ center-center_SFB_300 x 500 mm7, BB_XX_Betonbalk, rechthoekig, center-center_SFB:300 x 500 mm:904447
In: K10
PredefinedType: BEAM; Material: BB_Beton_Bestaand
Cpset_Beam - LevelOfAccuracy: in te vullen door Buildwise
IfcRoot - Name: 300 x 500 mm
Qto_BeamBaseQuantities - Length: 5600; CrossSectionArea: 0.15; OuterSurfaceArea: 8.96; GrossSurfaceArea: 9.26; NetSurfaceArea: 9.26; GrossVolume: 0.84; NetVolume: 0.84
Pset_BeamCommon - Reference: 300 x 500 mm; Span: 5600 mm; Slope: 0 rad; Roll: 0 rad; IsExternal: no; LoadBearing: yes
Pset_Condition - AssessmentCondition: Empty
Pset_EnvironmentalImpactIndicators - Reference: 300 x 500 mm; sets with these values: 2

# IfcBeam: BB_XX_Betonbalk_ rechthoekig_ center-center_SFB_300 x 500 mm9, BB_XX_Betonbalk, rechthoekig, center-center_SFB:300 x 500 mm:659455
In: 000
PredefinedType: BEAM; Material: BB_Beton_Bestaand
Cpset_Beam - LevelOfAccuracy: in te vullen door Buildwise
IfcRoot - Name: 300 x 500 mm
Qto_BeamBaseQuantities - Length: 5630; CrossSectionArea: 0.15; OuterSurfaceArea: 9.008; GrossSurfaceArea: 9.308; NetSurfaceArea: 9.308; GrossVolume: 0.8445; NetVolume: 0.8445
Pset_BeamCommon - Reference: 300 x 500 mm; Span: 5630 mm; Slope: 0 rad; Roll: 0 rad; IsExternal: no; LoadBearing: yes
Pset_Condition - AssessmentCondition: Empty
Pset_EnvironmentalImpactIndicators - Reference: 300 x 500 mm; sets with these values: 2

# IfcBeam: BB_XX_Betonbalk_ rechthoekig_ center-center_SFB_300 x 550 mm, BB_XX_Betonbalk, rechthoekig, center-center_SFB:300 x 550 mm:944896
In: K10
PredefinedType: BEAM; Material: BB_Beton_Bestaand
Cpset_Beam - LevelOfAccuracy: in te vullen door Buildwise
IfcRoot - Name: 300 x 550 mm
Qto_BeamBaseQuantities - Length: 1900; CrossSectionArea: 1.58257; NetSurfaceArea: 3.16515; NetVolume: 0.215945
Pset_BeamCommon - Reference: 300 x 550 mm; Span: 1900 mm; Slope: 0 rad; Roll: 0 rad; IsExternal: no; LoadBearing: yes
Pset_Condition - AssessmentCondition: Empty
Pset_EnvironmentalImpactIndicators - Reference: 300 x 550 mm; sets with these values: 2

# IfcBeam: BB_XX_Betonbalk_ rechthoekig_ center-center_SFB_300 x 620 mm, BB_XX_Betonbalk, rechthoekig, center-center_SFB:300 x 620 mm:899936
In: K10
PredefinedType: BEAM; Material: BB_Beton_Bestaand
Cpset_Beam - LevelOfAccuracy: in te vullen door Buildwise
IfcRoot - Name: 300 x 620 mm
Qto_BeamBaseQuantities - Length: 2100; CrossSectionArea: 0.186; OuterSurfaceArea: 3.864; GrossSurfaceArea: 4.236; NetSurfaceArea: 4.236; GrossVolume: 0.3906; NetVolume: 0.3906
Pset_BeamCommon - Reference: 300 x 620 mm; Span: 2100 mm; Slope: 0 rad; Roll: 0 rad; IsExternal: no; LoadBearing: yes
Pset_Condition - AssessmentCondition: Empty
Pset_EnvironmentalImpactIndicators - Reference: 300 x 620 mm; sets with these values: 2

# IfcBeam: BB_XX_Betonbalk_ rechthoekig_ center-center_SFB_300 x 720 mm, BB_XX_Betonbalk, rechthoekig, center-center_SFB:300 x 720 mm:934672
In: K10
PredefinedType: BEAM; Material: BB_Beton_Bestaand
Cpset_Beam - LevelOfAccuracy: in te vullen door Buildwise
IfcRoot - Name: 300 x 720 mm
Qto_BeamBaseQuantities - Length: 6026.84; CrossSectionArea: 0.216; OuterSurfaceArea: 12.2948; GrossSurfaceArea: 12.7268; NetSurfaceArea: 12.7268; GrossVolume: 1.3018; NetVolume: 1.3018
Pset_BeamCommon - Reference: 300 x 720 mm; Span: 6026.84 mm; Slope: 0 rad; Roll: 0 rad; IsExternal: no; LoadBearing: yes
Pset_Condition - AssessmentCondition: Empty
Pset_EnvironmentalImpactIndicators - Reference: 300 x 720 mm; sets with these values: 2

# IfcBeam: BB_XX_Betonbalk_ rechthoekig_ center-center_SFB_300 x 720 mm1, BB_XX_Betonbalk, rechthoekig, center-center_SFB:300 x 720 mm:934999
In: K10
PredefinedType: BEAM; Material: BB_Beton_Bestaand
Cpset_Beam - LevelOfAccuracy: in te vullen door Buildwise
IfcRoot - Name: 300 x 720 mm
Qto_BeamBaseQuantities - Length: 12010; CrossSectionArea: 12.6553; NetSurfaceArea: 25.3106; NetVolume: 2.53068
Pset_BeamCommon - Reference: 300 x 720 mm; Span: 12010 mm; Slope: 0 rad; Roll: 0 rad; IsExternal: no; LoadBearing: yes
Pset_Condition - AssessmentCondition: Empty
Pset_EnvironmentalImpactIndicators - Reference: 300 x 720 mm; sets with these values: 2

# IfcBeam: BB_XX_Betonbalk_ rechthoekig_ center-center_SFB_300 x 720 mm3, BB_XX_Betonbalk, rechthoekig, center-center_SFB:300 x 720 mm:935670
In: K10
PredefinedType: BEAM; Material: BB_Beton_Bestaand
Cpset_Beam - LevelOfAccuracy: in te vullen door Buildwise
IfcRoot - Name: 300 x 720 mm
Qto_BeamBaseQuantities - Length: 6116.82; CrossSectionArea: 6.32921; NetSurfaceArea: 12.6584; NetVolume: 1.27886
Pset_BeamCommon - Reference: 300 x 720 mm; Span: 6116.82 mm; Slope: 0 rad; Roll: 0 rad; IsExternal: no; LoadBearing: yes
Pset_Condition - AssessmentCondition: Empty
Pset_EnvironmentalImpactIndicators - Reference: 300 x 720 mm; sets with these values: 2

# IfcBeam: BB_XX_Betonbalk_ rechthoekig_ center-center_SFB_300 x 720 mm5, BB_XX_Betonbalk, rechthoekig, center-center_SFB:300 x 720 mm:698557
In: 020
PredefinedType: BEAM; Material: BB_Beton_Bestaand
Cpset_Beam - LevelOfAccuracy: in te vullen door Buildwise
IfcRoot - Name: 300 x 720 mm
Qto_BeamBaseQuantities - Length: 490; CrossSectionArea: 0.216; OuterSurfaceArea: 0.9996; GrossSurfaceArea: 1.4316; NetSurfaceArea: 1.4316; GrossVolume: 0.10584; NetVolume: 0.10584
Pset_BeamCommon - Reference: 300 x 720 mm; Span: 490 mm; Slope: 0 rad; Roll: 0 rad; IsExternal: no; LoadBearing: yes
Pset_Condition - AssessmentCondition: Empty
Pset_EnvironmentalImpactIndicators - Reference: 300 x 720 mm; sets with these values: 2

# IfcBeam: BB_XX_Betonbalk_ rechthoekig_ center-center_SFB_300 x 750 mm, BB_XX_Betonbalk, rechthoekig, center-center_SFB:300 x 750 mm:885923
In: K10
PredefinedType: BEAM; Material: BB_Beton_Bestaand
Cpset_Beam - LevelOfAccuracy: in te vullen door Buildwise
IfcRoot - Name: 300 x 750 mm
Qto_BeamBaseQuantities - Length: 1500; CrossSectionArea: 0.225; OuterSurfaceArea: 3.15; GrossSurfaceArea: 3.6; NetSurfaceArea: 3.6; GrossVolume: 0.3375; NetVolume: 0.3375
Pset_BeamCommon - Reference: 300 x 750 mm; Span: 1500 mm; Slope: 0 rad; Roll: 0 rad; IsExternal: no; LoadBearing: yes
Pset_Condition - AssessmentCondition: Empty
Pset_EnvironmentalImpactIndicators - Reference: 300 x 750 mm; sets with these values: 2

# IfcBeam: BB_XX_Betonbalk_ rechthoekig_ center-center_SFB_300 x 830 mm, BB_XX_Betonbalk, rechthoekig, center-center_SFB:300 x 830 mm:835639
In: K10
PredefinedType: BEAM; Material: BB_Beton_Bestaand
Cpset_Beam - LevelOfAccuracy: in te vullen door Buildwise
IfcRoot - Name: 300 x 830 mm
Qto_BeamBaseQuantities - Length: 2947.88; CrossSectionArea: 3.55079; NetSurfaceArea: 7.10158; NetVolume: 0.729871
Pset_BeamCommon - Reference: 300 x 830 mm; Span: 2947.88 mm; Slope: 0 rad; Roll: 0 rad; IsExternal: no; LoadBearing: yes
Pset_Condition - AssessmentCondition: Empty
Pset_EnvironmentalImpactIndicators - Reference: 300 x 830 mm; sets with these values: 2

# IfcBeam: BB_XX_Betonbalk_ rechthoekig_ center-center_SFB_300 x 980 mm, BB_XX_Betonbalk, rechthoekig, center-center_SFB:300 x 980 mm:931673
In: K10
PredefinedType: BEAM; Material: BB_Beton_Bestaand
Cpset_Beam - LevelOfAccuracy: in te vullen door Buildwise
IfcRoot - Name: 300 x 980 mm
Qto_BeamBaseQuantities - Length: 4100; CrossSectionArea: 0.294; OuterSurfaceArea: 10.496; GrossSurfaceArea: 11.084; NetSurfaceArea: 11.084; GrossVolume: 1.2054; NetVolume: 1.2054
Pset_BeamCommon - Reference: 300 x 980 mm; Span: 4100 mm; Slope: 0 rad; Roll: 0 rad; IsExternal: no; LoadBearing: yes
Pset_Condition - AssessmentCondition: Empty
Pset_EnvironmentalImpactIndicators - Reference: 300 x 980 mm; sets with these values: 2

# IfcBeam: BB_XX_Betonbalk_ rechthoekig_ center-center_SFB_320 x 490 mm, BB_XX_Betonbalk, rechthoekig, center-center_SFB:320 x 490 mm:990104
In: K20
PredefinedType: BEAM; Material: BB_Beton_Bestaand
Cpset_Beam - LevelOfAccuracy: in te vullen door Buildwise
IfcRoot - Name: 320 x 490 mm
Qto_BeamBaseQuantities - Length: 5858.9; CrossSectionArea: 4.89665; NetSurfaceArea: 9.79331; NetVolume: 0.913997
Pset_BeamCommon - Reference: 320 x 490 mm; Span: 5858.9 mm; Slope: 0 rad; Roll: 0 rad; IsExternal: no; LoadBearing: yes
Pset_Condition - AssessmentCondition: Empty
Pset_EnvironmentalImpactIndicators - Reference: 320 x 490 mm; sets with these values: 2

# IfcBeam: BB_XX_Betonbalk_ rechthoekig_ center-center_SFB_320 x 490 mm1, BB_XX_Betonbalk, rechthoekig, center-center_SFB:320 x 490 mm:990106
In: K20
PredefinedType: BEAM; Material: BB_Beton_Bestaand
Cpset_Beam - LevelOfAccuracy: in te vullen door Buildwise
IfcRoot - Name: 320 x 490 mm
Qto_BeamBaseQuantities - Length: 11656.1; CrossSectionArea: 0.1568; OuterSurfaceArea: 18.8829; GrossSurfaceArea: 19.1965; NetSurfaceArea: 19.1965; GrossVolume: 1.82768; NetVolume: 1.82768
Pset_BeamCommon - Reference: 320 x 490 mm; Span: 11656.1 mm; Slope: 0 rad; Roll: 0 rad; IsExternal: no; LoadBearing: yes
Pset_Condition - AssessmentCondition: Empty
Pset_EnvironmentalImpactIndicators - Reference: 320 x 490 mm; sets with these values: 2

# IfcBeam: BB_XX_Betonbalk_ rechthoekig_ center-center_SFB_320 x 490 mm3, BB_XX_Betonbalk, rechthoekig, center-center_SFB:320 x 490 mm:990165
In: K20
PredefinedType: BEAM; Material: BB_Beton_Bestaand
Cpset_Beam - LevelOfAccuracy: in te vullen door Buildwise
IfcRoot - Name: 320 x 490 mm
Qto_BeamBaseQuantities - Length: 20676.8; CrossSectionArea: 16.7855; NetSurfaceArea: 33.5711; NetVolume: 3.21895
Pset_BeamCommon - Reference: 320 x 490 mm; Span: 20676.8 mm; Slope: 0 rad; Roll: 0 rad; IsExternal: no; LoadBearing: yes
Pset_Condition - AssessmentCondition: Empty
Pset_EnvironmentalImpactIndicators - Reference: 320 x 490 mm; sets with these values: 2

# IfcBeam: BB_XX_Betonbalk_ rechthoekig_ center-center_SFB_320 x 490 mm5, BB_XX_Betonbalk, rechthoekig, center-center_SFB:320 x 490 mm:992966
In: K20
PredefinedType: BEAM; Material: BB_Beton_Bestaand
Cpset_Beam - LevelOfAccuracy: in te vullen door Buildwise
IfcRoot - Name: 320 x 490 mm
Qto_BeamBaseQuantities - Length: 5100; CrossSectionArea: 2.439; OuterSurfaceArea: 3.5776; GrossSurfaceArea: 8.45561; NetSurfaceArea: 8.45561; GrossVolume: 0.780481; NetVolume: 0.780481
Pset_BeamCommon - Reference: 320 x 490 mm; Span: 5100 mm; Slope: 0 rad; Roll: 0 rad; IsExternal: no; LoadBearing: yes
Pset_Condition - AssessmentCondition: Empty
Pset_EnvironmentalImpactIndicators - Reference: 320 x 490 mm; sets with these values: 2

# IfcBeam: BB_XX_Betonbalk_ rechthoekig_ center-center_SFB_330 x 720 mm, BB_XX_Betonbalk, rechthoekig, center-center_SFB:330 x 720 mm:532064
In: 000
PredefinedType: BEAM; Material: BB_Beton_Bestaand
Cpset_Beam - LevelOfAccuracy: in te vullen door Buildwise
IfcRoot - Name: 330 x 720 mm
Qto_BeamBaseQuantities - Length: 5210; CrossSectionArea: 0.2376; OuterSurfaceArea: 10.941; GrossSurfaceArea: 11.4162; NetSurfaceArea: 11.4162; GrossVolume: 1.2379; NetVolume: 1.2379
Pset_BeamCommon - Reference: 330 x 720 mm; Span: 5210 mm; Slope: 0 rad; Roll: 0 rad; IsExternal: no; LoadBearing: yes
Pset_Condition - AssessmentCondition: Empty
Pset_EnvironmentalImpactIndicators - Reference: 330 x 720 mm; sets with these values: 2

# IfcBeam: BB_XX_Betonbalk_ rechthoekig_ center-center_SFB_330 x 720 mm1, BB_XX_Betonbalk, rechthoekig, center-center_SFB:330 x 720 mm:544619
In: 000
PredefinedType: BEAM; Material: BB_Beton_Bestaand
Cpset_Beam - LevelOfAccuracy: in te vullen door Buildwise
IfcRoot - Name: 330 x 720 mm
Qto_BeamBaseQuantities - Length: 5209.87; CrossSectionArea: 0.2376; OuterSurfaceArea: 10.9407; GrossSurfaceArea: 11.4159; NetSurfaceArea: 11.4159; GrossVolume: 1.23787; NetVolume: 1.23787
Pset_BeamCommon - Reference: 330 x 720 mm; Span: 5209.87 mm; Slope: 0 rad; Roll: 0 rad; IsExternal: no; LoadBearing: yes
Pset_Condition - AssessmentCondition: Empty
Pset_EnvironmentalImpactIndicators - Reference: 330 x 720 mm; sets with these values: 2

# IfcBeam: BB_XX_Betonbalk_ rechthoekig_ center-center_SFB_340 x 720 mm (2)
In: 000
PredefinedType: BEAM; Material: BB_Beton_Bestaand
Cpset_Beam - LevelOfAccuracy: in te vullen door Buildwise
IfcRoot - Name: 340 x 720 mm
Qto_BeamBaseQuantities - Length: 6110; CrossSectionArea: 0.2448; OuterSurfaceArea: 12.9532; GrossSurfaceArea: 13.4428; NetSurfaceArea: 13.4428; GrossVolume: 1.49573; NetVolume: 1.49573
Pset_BeamCommon - Reference: 340 x 720 mm; Span: 6110 mm; Slope: 0 rad; Roll: 0 rad; IsExternal: no; LoadBearing: yes
Pset_Condition - AssessmentCondition: Empty
Pset_EnvironmentalImpactIndicators - Reference: 340 x 720 mm; sets with these values: 2
Name (BB_XX_Betonbalk, rechthoekig, center-center_SFB:340 x 720 mm:...)
525077
526792

# IfcBeam: BB_XX_Betonbalk_ rechthoekig_ center-center_SFB_340 x 720 mm1 (5)
PredefinedType: BEAM; Material: BB_Beton_Bestaand
Cpset_Beam - LevelOfAccuracy: in te vullen door Buildwise
IfcRoot - Name: 340 x 720 mm
Qto_BeamBaseQuantities - Length: 5210; CrossSectionArea: 0.2448; OuterSurfaceArea: 11.0452; GrossSurfaceArea: 11.5348; NetSurfaceArea: 11.5348; GrossVolume: 1.27541; NetVolume: 1.27541
Pset_BeamCommon - Reference: 340 x 720 mm; Span: 5210 mm; Slope: 0 rad; Roll: 0 rad; IsExternal: no; LoadBearing: yes
Pset_Condition - AssessmentCondition: Empty
Pset_EnvironmentalImpactIndicators - Reference: 340 x 720 mm; sets with these values: 2
Name (BB_XX_Betonbalk, rechthoekig, center-center_SFB:340 x 720 mm:...) | In
545795 | 000
627133 | 010
639462 | 010
644614 | 010
695642 | 020

# IfcBeam: BB_XX_Betonbalk_ rechthoekig_ center-center_SFB_340 x 720 mm101 (10)
PredefinedType: BEAM; Material: BB_Beton_Bestaand
Cpset_Beam - LevelOfAccuracy: in te vullen door Buildwise
IfcRoot - Name: 340 x 720 mm
Qto_BeamBaseQuantities - Length: 6110; CrossSectionArea: 0.2448; OuterSurfaceArea: 12.9532; GrossSurfaceArea: 13.4428; NetSurfaceArea: 13.4428; GrossVolume: 1.49573; NetVolume: 1.49573
Pset_BeamCommon - Reference: 340 x 720 mm; Span: 6110 mm; Slope: 0 rad; Roll: 0 rad; IsExternal: no; LoadBearing: yes
Pset_Condition - AssessmentCondition: Empty
Pset_EnvironmentalImpactIndicators - Reference: 340 x 720 mm; sets with these values: 2
Name (BB_XX_Betonbalk, rechthoekig, center-center_SFB:340 x 720 mm:...) | In
623895 | 010
634740 | 010
635639 | 010
635822 | 010
641775 | 010
695469 | 020
695581 | 020
695596 | 020
695598 | 020
695647 | 020

# IfcBeam: BB_XX_Betonbalk_ rechthoekig_ center-center_SFB_340 x 720 mm103, BB_XX_Betonbalk, rechthoekig, center-center_SFB:340 x 720 mm:625480
In: 010
PredefinedType: BEAM; Material: BB_Beton_Bestaand
Cpset_Beam - LevelOfAccuracy: in te vullen door Buildwise
IfcRoot - Name: 340 x 720 mm
Qto_BeamBaseQuantities - Length: 640; CrossSectionArea: 0.8586; NetSurfaceArea: 1.7172; NetVolume: 0.11016
Pset_BeamCommon - Reference: 340 x 720 mm; Span: 640 mm; Slope: 0 rad; Roll: 0 rad; IsExternal: no; LoadBearing: yes
Pset_Condition - AssessmentCondition: Empty
Pset_EnvironmentalImpactIndicators - Reference: 340 x 720 mm; sets with these values: 2

# IfcBeam: BB_XX_Betonbalk_ rechthoekig_ center-center_SFB_340 x 720 mm105 (4)
PredefinedType: BEAM; Material: BB_Beton_Bestaand
Cpset_Beam - LevelOfAccuracy: in te vullen door Buildwise
IfcRoot - Name: 340 x 720 mm
Qto_BeamBaseQuantities - Length: 4310; CrossSectionArea: 0.2448; OuterSurfaceArea: 9.1372; GrossSurfaceArea: 9.6268; NetSurfaceArea: 9.6268; GrossVolume: 1.05509; NetVolume: 1.05509
Pset_BeamCommon - Reference: 340 x 720 mm; Span: 4310 mm; Slope: 0 rad; Roll: 0 rad; IsExternal: no; LoadBearing: yes
Pset_Condition - AssessmentCondition: Empty
Pset_EnvironmentalImpactIndicators - Reference: 340 x 720 mm; sets with these values: 2
Name (BB_XX_Betonbalk, rechthoekig, center-center_SFB:340 x 720 mm:...) | In
626119 | 010
642300 | 010
695484 | 020
695649 | 020

# IfcBeam: BB_XX_Betonbalk_ rechthoekig_ center-center_SFB_340 x 720 mm107, BB_XX_Betonbalk, rechthoekig, center-center_SFB:340 x 720 mm:626455
In: 010
PredefinedType: BEAM; Material: BB_Beton_Bestaand
Cpset_Beam - LevelOfAccuracy: in te vullen door Buildwise
IfcRoot - Name: 340 x 720 mm
Qto_BeamBaseQuantities - Length: 6110; CrossSectionArea: 0.2448; OuterSurfaceArea: 12.9532; GrossSurfaceArea: 13.4428; NetSurfaceArea: 13.4428; GrossVolume: 1.49573; NetVolume: 1.49573
Pset_BeamCommon - Reference: 340 x 720 mm; Span: 6110 mm; Slope: 0 rad; Roll: 0 rad; IsExternal: no; LoadBearing: yes
Pset_Condition - AssessmentCondition: Empty
Pset_EnvironmentalImpactIndicators - Reference: 340 x 720 mm; sets with these values: 2

# IfcBeam: BB_XX_Betonbalk_ rechthoekig_ center-center_SFB_340 x 720 mm109, BB_XX_Betonbalk, rechthoekig, center-center_SFB:340 x 720 mm:626543
In: 010
PredefinedType: BEAM; Material: BB_Beton_Bestaand
Cpset_Beam - LevelOfAccuracy: in te vullen door Buildwise
IfcRoot - Name: 340 x 720 mm
Qto_BeamBaseQuantities - Length: 1090; CrossSectionArea: 1.4439; NetSurfaceArea: 2.8878; NetVolume: 0.1998
Pset_BeamCommon - Reference: 340 x 720 mm; Span: 1090 mm; Slope: 0 rad; Roll: 0 rad; IsExternal: no; LoadBearing: yes
Pset_Condition - AssessmentCondition: Empty
Pset_EnvironmentalImpactIndicators - Reference: 340 x 720 mm; sets with these values: 2

# IfcBeam: BB_XX_Betonbalk_ rechthoekig_ center-center_SFB_340 x 720 mm11, BB_XX_Betonbalk, rechthoekig, center-center_SFB:340 x 720 mm:547927
In: 000
PredefinedType: BEAM; Material: BB_Beton_Bestaand
Cpset_Beam - LevelOfAccuracy: in te vullen door Buildwise
IfcRoot - Name: 340 x 720 mm
Qto_BeamBaseQuantities - Length: 640; CrossSectionArea: 0.8586; NetSurfaceArea: 1.7172; NetVolume: 0.11016
Pset_BeamCommon - Reference: 340 x 720 mm; Span: 640 mm; Slope: 0 rad; Roll: 0 rad; IsExternal: no; LoadBearing: yes
Pset_Condition - AssessmentCondition: Empty
Pset_EnvironmentalImpactIndicators - Reference: 340 x 720 mm; sets with these values: 2

# IfcBeam: BB_XX_Betonbalk_ rechthoekig_ center-center_SFB_340 x 720 mm111, BB_XX_Betonbalk, rechthoekig, center-center_SFB:340 x 720 mm:626793
In: 010
PredefinedType: BEAM; Material: BB_Beton_Bestaand
Cpset_Beam - LevelOfAccuracy: in te vullen door Buildwise
IfcRoot - Name: 340 x 720 mm
Qto_BeamBaseQuantities - Length: 1090; CrossSectionArea: 1.4439; NetSurfaceArea: 2.8878; NetVolume: 0.1998
Pset_BeamCommon - Reference: 340 x 720 mm; Span: 1090 mm; Slope: 0 rad; Roll: 0 rad; IsExternal: no; LoadBearing: yes
Pset_Condition - AssessmentCondition: Empty
Pset_EnvironmentalImpactIndicators - Reference: 340 x 720 mm; sets with these values: 2

# IfcBeam: BB_XX_Betonbalk_ rechthoekig_ center-center_SFB_340 x 720 mm113, BB_XX_Betonbalk, rechthoekig, center-center_SFB:340 x 720 mm:626951
In: 010
PredefinedType: BEAM; Material: BB_Beton_Bestaand
Cpset_Beam - LevelOfAccuracy: in te vullen door Buildwise
IfcRoot - Name: 340 x 720 mm
Qto_BeamBaseQuantities - Length: 640; CrossSectionArea: 0.8586; NetSurfaceArea: 1.7172; NetVolume: 0.11016
Pset_BeamCommon - Reference: 340 x 720 mm; Span: 640 mm; Slope: 0 rad; Roll: 0 rad; IsExternal: no; LoadBearing: yes
Pset_Condition - AssessmentCondition: Empty
Pset_EnvironmentalImpactIndicators - Reference: 340 x 720 mm; sets with these values: 2

# IfcBeam: BB_XX_Betonbalk_ rechthoekig_ center-center_SFB_340 x 720 mm115, BB_XX_Betonbalk, rechthoekig, center-center_SFB:340 x 720 mm:630593
In: 010
PredefinedType: BEAM; Material: BB_Beton_Bestaand
Cpset_Beam - LevelOfAccuracy: in te vullen door Buildwise
IfcRoot - Name: 340 x 720 mm
Qto_BeamBaseQuantities - Length: 4740; CrossSectionArea: 0.2448; OuterSurfaceArea: 10.0488; GrossSurfaceArea: 10.5384; NetSurfaceArea: 10.5384; GrossVolume: 1.16035; NetVolume: 1.16035
Pset_BeamCommon - Reference: 340 x 720 mm; Span: 4740 mm; Slope: 0 rad; Roll: 0 rad; IsExternal: no; LoadBearing: yes
Pset_Condition - AssessmentCondition: Empty
Pset_EnvironmentalImpactIndicators - Reference: 340 x 720 mm; sets with these values: 2

# IfcBeam: BB_XX_Betonbalk_ rechthoekig_ center-center_SFB_340 x 720 mm117 (2)
PredefinedType: BEAM; Material: BB_Beton_Bestaand
Cpset_Beam - LevelOfAccuracy: in te vullen door Buildwise
IfcRoot - Name: 340 x 720 mm
Qto_BeamBaseQuantities - Length: 7010; CrossSectionArea: 0.2448; OuterSurfaceArea: 14.8612; GrossSurfaceArea: 15.3508; NetSurfaceArea: 15.3508; GrossVolume: 1.71605; NetVolume: 1.71605
Pset_BeamCommon - Reference: 340 x 720 mm; Span: 7010 mm; Slope: 0 rad; Roll: 0 rad; IsExternal: no; LoadBearing: yes
Pset_Condition - AssessmentCondition: Empty
Pset_EnvironmentalImpactIndicators - Reference: 340 x 720 mm; sets with these values: 2
Name (BB_XX_Betonbalk, rechthoekig, center-center_SFB:340 x 720 mm:...) | In
633045 | 010
695567 | 020

# IfcBeam: BB_XX_Betonbalk_ rechthoekig_ center-center_SFB_340 x 720 mm119, BB_XX_Betonbalk, rechthoekig, center-center_SFB:340 x 720 mm:634804
In: 010
PredefinedType: BEAM; Material: BB_Beton_Bestaand
Cpset_Beam - LevelOfAccuracy: in te vullen door Buildwise
IfcRoot - Name: 340 x 720 mm
Qto_BeamBaseQuantities - Length: 640; CrossSectionArea: 0.8586; NetSurfaceArea: 1.7172; NetVolume: 0.11016
Pset_BeamCommon - Reference: 340 x 720 mm; Span: 640 mm; Slope: 0 rad; Roll: 0 rad; IsExternal: no; LoadBearing: yes
Pset_Condition - AssessmentCondition: Empty
Pset_EnvironmentalImpactIndicators - Reference: 340 x 720 mm; sets with these values: 2

# IfcBeam: BB_XX_Betonbalk_ rechthoekig_ center-center_SFB_340 x 720 mm121, BB_XX_Betonbalk, rechthoekig, center-center_SFB:340 x 720 mm:636077
In: 010
PredefinedType: BEAM; Material: BB_Beton_Bestaand
Cpset_Beam - LevelOfAccuracy: in te vullen door Buildwise
IfcRoot - Name: 340 x 720 mm
Qto_BeamBaseQuantities - Length: 1090; CrossSectionArea: 1.4439; NetSurfaceArea: 2.8878; NetVolume: 0.1998
Pset_BeamCommon - Reference: 340 x 720 mm; Span: 1090 mm; Slope: 0 rad; Roll: 0 rad; IsExternal: no; LoadBearing: yes
Pset_Condition - AssessmentCondition: Empty
Pset_EnvironmentalImpactIndicators - Reference: 340 x 720 mm; sets with these values: 2

# IfcBeam: BB_XX_Betonbalk_ rechthoekig_ center-center_SFB_340 x 720 mm123, BB_XX_Betonbalk, rechthoekig, center-center_SFB:340 x 720 mm:636115
In: 010
PredefinedType: BEAM; Material: BB_Beton_Bestaand
Cpset_Beam - LevelOfAccuracy: in te vullen door Buildwise
IfcRoot - Name: 340 x 720 mm
Qto_BeamBaseQuantities - Length: 1090; CrossSectionArea: 1.4439; NetSurfaceArea: 2.8878; NetVolume: 0.1998
Pset_BeamCommon - Reference: 340 x 720 mm; Span: 1090 mm; Slope: 0 rad; Roll: 0 rad; IsExternal: no; LoadBearing: yes
Pset_Condition - AssessmentCondition: Empty
Pset_EnvironmentalImpactIndicators - Reference: 340 x 720 mm; sets with these values: 2

# IfcBeam: BB_XX_Betonbalk_ rechthoekig_ center-center_SFB_340 x 720 mm125, BB_XX_Betonbalk, rechthoekig, center-center_SFB:340 x 720 mm:636656
In: 010
PredefinedType: BEAM; Material: BB_Beton_Bestaand
Cpset_Beam - LevelOfAccuracy: in te vullen door Buildwise
IfcRoot - Name: 340 x 720 mm
Qto_BeamBaseQuantities - Length: 935; CrossSectionArea: 0.2448; OuterSurfaceArea: 1.908; GrossSurfaceArea: 2.3976; NetSurfaceArea: 2.3976; GrossVolume: 0.22032; NetVolume: 0.22032
Pset_BeamCommon - Reference: 340 x 720 mm; Span: 935 mm; Slope: 0 rad; Roll: 0 rad; IsExternal: no; LoadBearing: yes
Pset_Condition - AssessmentCondition: Empty
Pset_EnvironmentalImpactIndicators - Reference: 340 x 720 mm; sets with these values: 2

# IfcBeam: BB_XX_Betonbalk_ rechthoekig_ center-center_SFB_340 x 720 mm127, BB_XX_Betonbalk, rechthoekig, center-center_SFB:340 x 720 mm:642380
In: 010
PredefinedType: BEAM; Material: BB_Beton_Bestaand
Cpset_Beam - LevelOfAccuracy: in te vullen door Buildwise
IfcRoot - Name: 340 x 720 mm
Qto_BeamBaseQuantities - Length: 6110; CrossSectionArea: 0.2448; OuterSurfaceArea: 12.9532; GrossSurfaceArea: 13.4428; NetSurfaceArea: 13.4428; GrossVolume: 1.49573; NetVolume: 1.49573
Pset_BeamCommon - Reference: 340 x 720 mm; Span: 6110 mm; Slope: 0 rad; Roll: 0 rad; IsExternal: no; LoadBearing: yes
Pset_Condition - AssessmentCondition: Empty
Pset_EnvironmentalImpactIndicators - Reference: 340 x 720 mm; sets with these values: 2

# IfcBeam: BB_XX_Betonbalk_ rechthoekig_ center-center_SFB_340 x 720 mm129, BB_XX_Betonbalk, rechthoekig, center-center_SFB:340 x 720 mm:642450
In: 010
PredefinedType: BEAM; Material: BB_Beton_Bestaand
Cpset_Beam - LevelOfAccuracy: in te vullen door Buildwise
IfcRoot - Name: 340 x 720 mm
Qto_BeamBaseQuantities - Length: 640; CrossSectionArea: 0.8586; NetSurfaceArea: 1.7172; NetVolume: 0.11016
Pset_BeamCommon - Reference: 340 x 720 mm; Span: 640 mm; Slope: 0 rad; Roll: 0 rad; IsExternal: no; LoadBearing: yes
Pset_Condition - AssessmentCondition: Empty
Pset_EnvironmentalImpactIndicators - Reference: 340 x 720 mm; sets with these values: 2

# IfcBeam: BB_XX_Betonbalk_ rechthoekig_ center-center_SFB_340 x 720 mm13, BB_XX_Betonbalk, rechthoekig, center-center_SFB:340 x 720 mm:548900
In: 000
PredefinedType: BEAM; Material: BB_Beton_Bestaand
Cpset_Beam - LevelOfAccuracy: in te vullen door Buildwise
IfcRoot - Name: 340 x 720 mm
Qto_BeamBaseQuantities - Length: 5210; CrossSectionArea: 0.2448; OuterSurfaceArea: 11.0452; GrossSurfaceArea: 11.5348; NetSurfaceArea: 11.5348; GrossVolume: 1.27541; NetVolume: 1.27541
Pset_BeamCommon - Reference: 340 x 720 mm; Span: 5210 mm; Slope: 0 rad; Roll: 0 rad; IsExternal: no; LoadBearing: yes
Pset_Condition - AssessmentCondition: Empty
Pset_EnvironmentalImpactIndicators - Reference: 340 x 720 mm; sets with these values: 2

# IfcBeam: BB_XX_Betonbalk_ rechthoekig_ center-center_SFB_340 x 720 mm131, BB_XX_Betonbalk, rechthoekig, center-center_SFB:340 x 720 mm:642545
In: 010
PredefinedType: BEAM; Material: BB_Beton_Bestaand
Cpset_Beam - LevelOfAccuracy: in te vullen door Buildwise
IfcRoot - Name: 340 x 720 mm
Qto_BeamBaseQuantities - Length: 1090; CrossSectionArea: 1.4439; NetSurfaceArea: 2.8878; NetVolume: 0.1998
Pset_BeamCommon - Reference: 340 x 720 mm; Span: 1090 mm; Slope: 0 rad; Roll: 0 rad; IsExternal: no; LoadBearing: yes
Pset_Condition - AssessmentCondition: Empty
Pset_EnvironmentalImpactIndicators - Reference: 340 x 720 mm; sets with these values: 2

# IfcBeam: BB_XX_Betonbalk_ rechthoekig_ center-center_SFB_340 x 720 mm133, BB_XX_Betonbalk, rechthoekig, center-center_SFB:340 x 720 mm:642614
In: 010
PredefinedType: BEAM; Material: BB_Beton_Bestaand
Cpset_Beam - LevelOfAccuracy: in te vullen door Buildwise
IfcRoot - Name: 340 x 720 mm
Qto_BeamBaseQuantities - Length: 1090; CrossSectionArea: 1.4439; NetSurfaceArea: 2.8878; NetVolume: 0.1998
Pset_BeamCommon - Reference: 340 x 720 mm; Span: 1090 mm; Slope: 0 rad; Roll: 0 rad; IsExternal: no; LoadBearing: yes
Pset_Condition - AssessmentCondition: Empty
Pset_EnvironmentalImpactIndicators - Reference: 340 x 720 mm; sets with these values: 2

# IfcBeam: BB_XX_Betonbalk_ rechthoekig_ center-center_SFB_340 x 720 mm135, BB_XX_Betonbalk, rechthoekig, center-center_SFB:340 x 720 mm:642683
In: 010
PredefinedType: BEAM; Material: BB_Beton_Bestaand
Cpset_Beam - LevelOfAccuracy: in te vullen door Buildwise
IfcRoot - Name: 340 x 720 mm
Qto_BeamBaseQuantities - Length: 640; CrossSectionArea: 0.8586; NetSurfaceArea: 1.7172; NetVolume: 0.11016
Pset_BeamCommon - Reference: 340 x 720 mm; Span: 640 mm; Slope: 0 rad; Roll: 0 rad; IsExternal: no; LoadBearing: yes
Pset_Condition - AssessmentCondition: Empty
Pset_EnvironmentalImpactIndicators - Reference: 340 x 720 mm; sets with these values: 2

# IfcBeam: BB_XX_Betonbalk_ rechthoekig_ center-center_SFB_340 x 720 mm137, BB_XX_Betonbalk, rechthoekig, center-center_SFB:340 x 720 mm:648811
In: 010
PredefinedType: BEAM; Material: BB_Beton_Bestaand
Cpset_Beam - LevelOfAccuracy: in te vullen door Buildwise
IfcRoot - Name: 340 x 720 mm
Qto_BeamBaseQuantities - Length: 2293.77; CrossSectionArea: 0.2448; OuterSurfaceArea: 4.86278; GrossSurfaceArea: 5.35238; NetSurfaceArea: 5.35238; GrossVolume: 0.561514; NetVolume: 0.561514
Pset_BeamCommon - Reference: 340 x 720 mm; Span: 2293.77 mm; Slope: 0 rad; Roll: 0 rad; IsExternal: no; LoadBearing: yes
Pset_Condition - AssessmentCondition: Empty
Pset_EnvironmentalImpactIndicators - Reference: 340 x 720 mm; sets with these values: 2

# IfcBeam: BB_XX_Betonbalk_ rechthoekig_ center-center_SFB_340 x 720 mm139 (3)
PredefinedType: BEAM; Material: BB_Beton_Bestaand
Cpset_Beam - LevelOfAccuracy: in te vullen door Buildwise
IfcRoot - Name: 340 x 720 mm
Qto_BeamBaseQuantities - Length: 6980; CrossSectionArea: 0.2448; OuterSurfaceArea: 14.7976; GrossSurfaceArea: 15.2872; NetSurfaceArea: 15.2872; GrossVolume: 1.7087; NetVolume: 1.7087
Pset_BeamCommon - Reference: 340 x 720 mm; Span: 6980 mm; Slope: 0 rad; Roll: 0 rad; IsExternal: no; LoadBearing: yes
Pset_Condition - AssessmentCondition: Empty
Pset_EnvironmentalImpactIndicators - Reference: 340 x 720 mm; sets with these values: 2
Name (BB_XX_Betonbalk, rechthoekig, center-center_SFB:340 x 720 mm:...) | In
650677 | 010
695816 | 020
705287 | 030

# IfcBeam: BB_XX_Betonbalk_ rechthoekig_ center-center_SFB_340 x 720 mm141 (3)
PredefinedType: BEAM; Material: BB_Beton_Bestaand
Cpset_Beam - LevelOfAccuracy: in te vullen door Buildwise
IfcRoot - Name: 340 x 720 mm
Qto_BeamBaseQuantities - Length: 2020; CrossSectionArea: 0.2448; OuterSurfaceArea: 4.2824; GrossSurfaceArea: 4.772; NetSurfaceArea: 4.772; GrossVolume: 0.494496; NetVolume: 0.494496
Pset_BeamCommon - Reference: 340 x 720 mm; Span: 2020 mm; Slope: 0 rad; Roll: 0 rad; IsExternal: no; LoadBearing: yes
Pset_Condition - AssessmentCondition: Empty
Pset_EnvironmentalImpactIndicators - Reference: 340 x 720 mm; sets with these values: 2
Name (BB_XX_Betonbalk, rechthoekig, center-center_SFB:340 x 720 mm:...) | In
650680 | 010
695819 | 020
705290 | 030

# IfcBeam: BB_XX_Betonbalk_ rechthoekig_ center-center_SFB_340 x 720 mm143, BB_XX_Betonbalk, rechthoekig, center-center_SFB:340 x 720 mm:650682
In: 010
PredefinedType: BEAM; Material: BB_Beton_Bestaand
Cpset_Beam - LevelOfAccuracy: in te vullen door Buildwise
IfcRoot - Name: 340 x 720 mm
Qto_BeamBaseQuantities - Length: 2020; CrossSectionArea: 0.2448; OuterSurfaceArea: 4.2824; GrossSurfaceArea: 4.772; NetSurfaceArea: 4.772; GrossVolume: 0.494496; NetVolume: 0.494496
Pset_BeamCommon - Reference: 340 x 720 mm; Span: 2020 mm; Slope: 0 rad; Roll: 0 rad; IsExternal: no; LoadBearing: yes
Pset_Condition - AssessmentCondition: Empty
Pset_EnvironmentalImpactIndicators - Reference: 340 x 720 mm; sets with these values: 2

# IfcBeam: BB_XX_Betonbalk_ rechthoekig_ center-center_SFB_340 x 720 mm145, BB_XX_Betonbalk, rechthoekig, center-center_SFB:340 x 720 mm:650684
In: 010
PredefinedType: BEAM; Material: BB_Beton_Bestaand
Cpset_Beam - LevelOfAccuracy: in te vullen door Buildwise
IfcRoot - Name: 340 x 720 mm
Qto_BeamBaseQuantities - Length: 6980; CrossSectionArea: 0.2448; OuterSurfaceArea: 14.7976; GrossSurfaceArea: 15.2872; NetSurfaceArea: 15.2872; GrossVolume: 1.7087; NetVolume: 1.7087
Pset_BeamCommon - Reference: 340 x 720 mm; Span: 6980 mm; Slope: 0 rad; Roll: 0 rad; IsExternal: no; LoadBearing: yes
Pset_Condition - AssessmentCondition: Empty
Pset_EnvironmentalImpactIndicators - Reference: 340 x 720 mm; sets with these values: 2

# IfcBeam: BB_XX_Betonbalk_ rechthoekig_ center-center_SFB_340 x 720 mm147 (2)
PredefinedType: BEAM; Material: BB_Beton_Bestaand
Cpset_Beam - LevelOfAccuracy: in te vullen door Buildwise
IfcRoot - Name: 340 x 720 mm
Qto_BeamBaseQuantities - Length: 1200; CrossSectionArea: 0.2448; OuterSurfaceArea: 2.544; GrossSurfaceArea: 3.0336; NetSurfaceArea: 3.0336; GrossVolume: 0.29376; NetVolume: 0.29376
Pset_BeamCommon - Reference: 340 x 720 mm; Span: 1200 mm; Slope: 0 rad; Roll: 0 rad; IsExternal: no; LoadBearing: yes
Pset_Condition - AssessmentCondition: Empty
Pset_EnvironmentalImpactIndicators - Reference: 340 x 720 mm; sets with these values: 2
Name (BB_XX_Betonbalk, rechthoekig, center-center_SFB:340 x 720 mm:...) | In
650692 | 010
695831 | 020

# IfcBeam: BB_XX_Betonbalk_ rechthoekig_ center-center_SFB_340 x 720 mm149, BB_XX_Betonbalk, rechthoekig, center-center_SFB:340 x 720 mm:673267
In: 010
PredefinedType: BEAM; Material: BB_Beton_Bestaand
Cpset_Beam - LevelOfAccuracy: in te vullen door Buildwise
IfcRoot - Name: 340 x 720 mm
Qto_BeamBaseQuantities - Length: 790; CrossSectionArea: 1.1544; NetSurfaceArea: 2.3088; NetVolume: 0.14688
Pset_BeamCommon - Reference: 340 x 720 mm; Span: 790 mm; Slope: 0 rad; Roll: 0 rad; IsExternal: no; LoadBearing: yes
Pset_Condition - AssessmentCondition: Empty
Pset_EnvironmentalImpactIndicators - Reference: 340 x 720 mm; sets with these values: 2
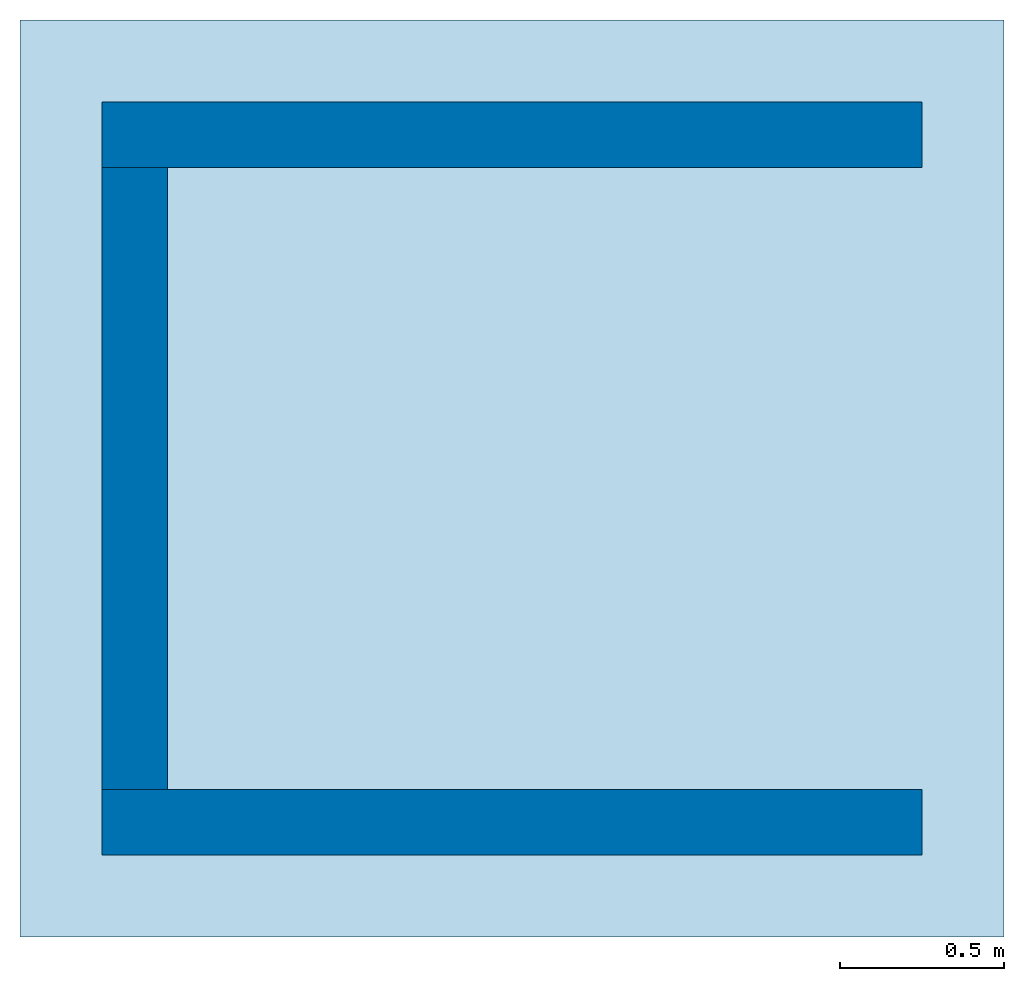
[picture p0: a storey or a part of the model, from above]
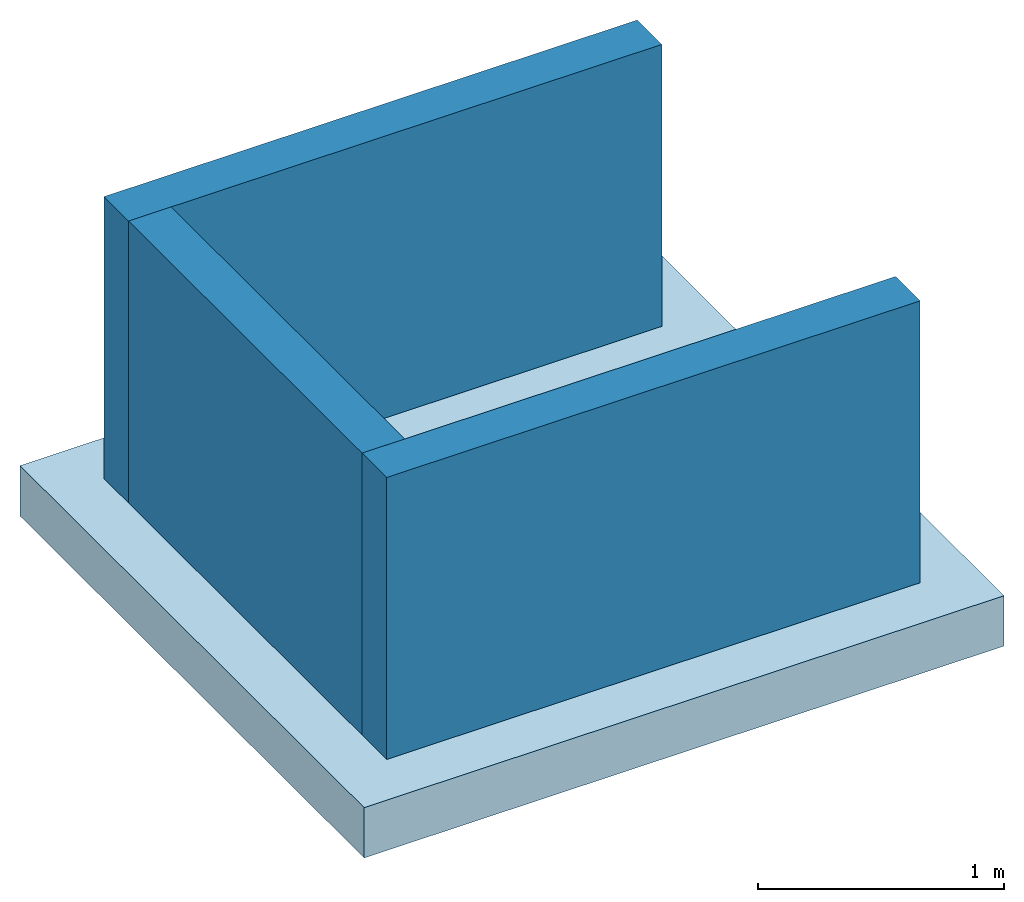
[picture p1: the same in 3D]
Properties of the parts of a building model (IFC4X3_ADD2), part 10 of 28

# IfcBeam: BB_XX_Betonbalk_ rechthoekig_ center-center_SFB_340 x 720 mm15, BB_XX_Betonbalk, rechthoekig, center-center_SFB:340 x 720 mm:551013
In: 000
PredefinedType: BEAM; Material: BB_Beton_Bestaand
Cpset_Beam - LevelOfAccuracy: in te vullen door Buildwise
IfcRoot - Name: 340 x 720 mm
Qto_BeamBaseQuantities - Length: 790; CrossSectionArea: 1.1544; NetSurfaceArea: 2.3088; NetVolume: 0.14688
Pset_BeamCommon - Reference: 340 x 720 mm; Span: 790 mm; Slope: 0 rad; Roll: 0 rad; IsExternal: no; LoadBearing: yes
Pset_Condition - AssessmentCondition: Empty
Pset_EnvironmentalImpactIndicators - Reference: 340 x 720 mm; sets with these values: 2

# IfcBeam: BB_XX_Betonbalk_ rechthoekig_ center-center_SFB_340 x 720 mm151 (3)
PredefinedType: BEAM; Material: BB_Beton_Bestaand
Cpset_Beam - LevelOfAccuracy: in te vullen door Buildwise
IfcRoot - Name: 340 x 720 mm
Qto_BeamBaseQuantities - Length: 900; CrossSectionArea: 0.2448; OuterSurfaceArea: 1.908; GrossSurfaceArea: 2.3976; NetSurfaceArea: 2.3976; GrossVolume: 0.22032; NetVolume: 0.22032
Pset_BeamCommon - Reference: 340 x 720 mm; Span: 900 mm; Slope: 0 rad; Roll: 0 rad; IsExternal: no; LoadBearing: yes
Pset_Condition - AssessmentCondition: Empty
Pset_EnvironmentalImpactIndicators - Reference: 340 x 720 mm; sets with these values: 2
Name (BB_XX_Betonbalk, rechthoekig, center-center_SFB:340 x 720 mm:...) | In
673317 | 010
695626 | 020
717946 | 020

# IfcBeam: BB_XX_Betonbalk_ rechthoekig_ center-center_SFB_340 x 720 mm153, BB_XX_Betonbalk, rechthoekig, center-center_SFB:340 x 720 mm:673411
In: 010
PredefinedType: BEAM; Material: BB_Beton_Bestaand
Cpset_Beam - LevelOfAccuracy: in te vullen door Buildwise
IfcRoot - Name: 340 x 720 mm
Qto_BeamBaseQuantities - Length: 715; CrossSectionArea: 1.1544; NetSurfaceArea: 2.3088; NetVolume: 0.14688
Pset_BeamCommon - Reference: 340 x 720 mm; Span: 715 mm; Slope: 0 rad; Roll: 0 rad; IsExternal: no; LoadBearing: yes
Pset_Condition - AssessmentCondition: Empty
Pset_EnvironmentalImpactIndicators - Reference: 340 x 720 mm; sets with these values: 2

# IfcBeam: BB_XX_Betonbalk_ rechthoekig_ center-center_SFB_340 x 720 mm155, BB_XX_Betonbalk, rechthoekig, center-center_SFB:340 x 720 mm:1964656
In: 010
PredefinedType: BEAM; Material: BB_Beton_Bestaand
Cpset_Beam - LevelOfAccuracy: in te vullen door Buildwise
IfcRoot - Name: 340 x 720 mm
Qto_BeamBaseQuantities - Length: 640; CrossSectionArea: 0.8586; NetSurfaceArea: 1.7172; NetVolume: 0.11016
Pset_BeamCommon - Reference: 340 x 720 mm; Span: 640 mm; Slope: 0 rad; Roll: 0 rad; IsExternal: no; LoadBearing: yes
Pset_Condition - AssessmentCondition: Empty
Pset_EnvironmentalImpactIndicators - Reference: 340 x 720 mm; sets with these values: 2

# IfcBeam: BB_XX_Betonbalk_ rechthoekig_ center-center_SFB_340 x 720 mm157, BB_XX_Betonbalk, rechthoekig, center-center_SFB:340 x 720 mm:695403
In: 020
PredefinedType: BEAM; Material: BB_Beton_Bestaand
Cpset_Beam - LevelOfAccuracy: in te vullen door Buildwise
IfcRoot - Name: 340 x 720 mm
Qto_BeamBaseQuantities - Length: 1090; CrossSectionArea: 1.4439; NetSurfaceArea: 2.8878; NetVolume: 0.1998
Pset_BeamCommon - Reference: 340 x 720 mm; Span: 1090 mm; Slope: 0 rad; Roll: 0 rad; IsExternal: no; LoadBearing: yes
Pset_Condition - AssessmentCondition: Empty
Pset_EnvironmentalImpactIndicators - Reference: 340 x 720 mm; sets with these values: 2

# IfcBeam: BB_XX_Betonbalk_ rechthoekig_ center-center_SFB_340 x 720 mm159, BB_XX_Betonbalk, rechthoekig, center-center_SFB:340 x 720 mm:695416
In: 020
PredefinedType: BEAM; Material: BB_Beton_Bestaand
Cpset_Beam - LevelOfAccuracy: in te vullen door Buildwise
IfcRoot - Name: 340 x 720 mm
Qto_BeamBaseQuantities - Length: 1090; CrossSectionArea: 1.4439; NetSurfaceArea: 2.8878; NetVolume: 0.1998
Pset_BeamCommon - Reference: 340 x 720 mm; Span: 1090 mm; Slope: 0 rad; Roll: 0 rad; IsExternal: no; LoadBearing: yes
Pset_Condition - AssessmentCondition: Empty
Pset_EnvironmentalImpactIndicators - Reference: 340 x 720 mm; sets with these values: 2

# IfcBeam: BB_XX_Betonbalk_ rechthoekig_ center-center_SFB_340 x 720 mm161, BB_XX_Betonbalk, rechthoekig, center-center_SFB:340 x 720 mm:695429
In: 020
PredefinedType: BEAM; Material: BB_Beton_Bestaand
Cpset_Beam - LevelOfAccuracy: in te vullen door Buildwise
IfcRoot - Name: 340 x 720 mm
Qto_BeamBaseQuantities - Length: 640; CrossSectionArea: 0.8586; NetSurfaceArea: 1.7172; NetVolume: 0.11016
Pset_BeamCommon - Reference: 340 x 720 mm; Span: 640 mm; Slope: 0 rad; Roll: 0 rad; IsExternal: no; LoadBearing: yes
Pset_Condition - AssessmentCondition: Empty
Pset_EnvironmentalImpactIndicators - Reference: 340 x 720 mm; sets with these values: 2

# IfcBeam: BB_XX_Betonbalk_ rechthoekig_ center-center_SFB_340 x 720 mm163, BB_XX_Betonbalk, rechthoekig, center-center_SFB:340 x 720 mm:695446
In: 020
PredefinedType: BEAM; Material: BB_Beton_Bestaand
Cpset_Beam - LevelOfAccuracy: in te vullen door Buildwise
IfcRoot - Name: 340 x 720 mm
Qto_BeamBaseQuantities - Length: 640; CrossSectionArea: 0.8586; NetSurfaceArea: 1.7172; NetVolume: 0.11016
Pset_BeamCommon - Reference: 340 x 720 mm; Span: 640 mm; Slope: 0 rad; Roll: 0 rad; IsExternal: no; LoadBearing: yes
Pset_Condition - AssessmentCondition: Empty
Pset_EnvironmentalImpactIndicators - Reference: 340 x 720 mm; sets with these values: 2

# IfcBeam: BB_XX_Betonbalk_ rechthoekig_ center-center_SFB_340 x 720 mm165, BB_XX_Betonbalk, rechthoekig, center-center_SFB:340 x 720 mm:695471
In: 020
PredefinedType: BEAM; Material: BB_Beton_Bestaand
Cpset_Beam - LevelOfAccuracy: in te vullen door Buildwise
IfcRoot - Name: 340 x 720 mm
Qto_BeamBaseQuantities - Length: 640; CrossSectionArea: 0.8586; NetSurfaceArea: 1.7172; NetVolume: 0.11016
Pset_BeamCommon - Reference: 340 x 720 mm; Span: 640 mm; Slope: 0 rad; Roll: 0 rad; IsExternal: no; LoadBearing: yes
Pset_Condition - AssessmentCondition: Empty
Pset_EnvironmentalImpactIndicators - Reference: 340 x 720 mm; sets with these values: 2

# IfcBeam: BB_XX_Betonbalk_ rechthoekig_ center-center_SFB_340 x 720 mm167, BB_XX_Betonbalk, rechthoekig, center-center_SFB:340 x 720 mm:695486
In: 020
PredefinedType: BEAM; Material: BB_Beton_Bestaand
Cpset_Beam - LevelOfAccuracy: in te vullen door Buildwise
IfcRoot - Name: 340 x 720 mm
Qto_BeamBaseQuantities - Length: 6110; CrossSectionArea: 0.2448; OuterSurfaceArea: 12.9532; GrossSurfaceArea: 13.4428; NetSurfaceArea: 13.4428; GrossVolume: 1.49573; NetVolume: 1.49573
Pset_BeamCommon - Reference: 340 x 720 mm; Span: 6110 mm; Slope: 0 rad; Roll: 0 rad; IsExternal: no; LoadBearing: yes
Pset_Condition - AssessmentCondition: Empty
Pset_EnvironmentalImpactIndicators - Reference: 340 x 720 mm; sets with these values: 2

# IfcBeam: BB_XX_Betonbalk_ rechthoekig_ center-center_SFB_340 x 720 mm169, BB_XX_Betonbalk, rechthoekig, center-center_SFB:340 x 720 mm:695488
In: 020
PredefinedType: BEAM; Material: BB_Beton_Bestaand
Cpset_Beam - LevelOfAccuracy: in te vullen door Buildwise
IfcRoot - Name: 340 x 720 mm
Qto_BeamBaseQuantities - Length: 1090; CrossSectionArea: 1.4439; NetSurfaceArea: 2.8878; NetVolume: 0.1998
Pset_BeamCommon - Reference: 340 x 720 mm; Span: 1090 mm; Slope: 0 rad; Roll: 0 rad; IsExternal: no; LoadBearing: yes
Pset_Condition - AssessmentCondition: Empty
Pset_EnvironmentalImpactIndicators - Reference: 340 x 720 mm; sets with these values: 2

# IfcBeam: BB_XX_Betonbalk_ rechthoekig_ center-center_SFB_340 x 720 mm17, BB_XX_Betonbalk, rechthoekig, center-center_SFB:340 x 720 mm:552452
In: 000
PredefinedType: BEAM; Material: BB_Beton_Bestaand
Cpset_Beam - LevelOfAccuracy: in te vullen door Buildwise
IfcRoot - Name: 340 x 720 mm
Qto_BeamBaseQuantities - Length: 660; CrossSectionArea: 0.2448; OuterSurfaceArea: 1.3992; GrossSurfaceArea: 1.8888; NetSurfaceArea: 1.8888; GrossVolume: 0.161568; NetVolume: 0.161568
Pset_BeamCommon - Reference: 340 x 720 mm; Span: 660 mm; Slope: 0 rad; Roll: 0 rad; IsExternal: no; LoadBearing: yes
Pset_Condition - AssessmentCondition: Empty
Pset_EnvironmentalImpactIndicators - Reference: 340 x 720 mm; sets with these values: 2

# IfcBeam: BB_XX_Betonbalk_ rechthoekig_ center-center_SFB_340 x 720 mm171, BB_XX_Betonbalk, rechthoekig, center-center_SFB:340 x 720 mm:695501
In: 020
PredefinedType: BEAM; Material: BB_Beton_Bestaand
Cpset_Beam - LevelOfAccuracy: in te vullen door Buildwise
IfcRoot - Name: 340 x 720 mm
Qto_BeamBaseQuantities - Length: 1090; CrossSectionArea: 1.4439; NetSurfaceArea: 2.8878; NetVolume: 0.1998
Pset_BeamCommon - Reference: 340 x 720 mm; Span: 1090 mm; Slope: 0 rad; Roll: 0 rad; IsExternal: no; LoadBearing: yes
Pset_Condition - AssessmentCondition: Empty
Pset_EnvironmentalImpactIndicators - Reference: 340 x 720 mm; sets with these values: 2

# IfcBeam: BB_XX_Betonbalk_ rechthoekig_ center-center_SFB_340 x 720 mm173, BB_XX_Betonbalk, rechthoekig, center-center_SFB:340 x 720 mm:695514
In: 020
PredefinedType: BEAM; Material: BB_Beton_Bestaand
Cpset_Beam - LevelOfAccuracy: in te vullen door Buildwise
IfcRoot - Name: 340 x 720 mm
Qto_BeamBaseQuantities - Length: 640; CrossSectionArea: 0.8586; NetSurfaceArea: 1.7172; NetVolume: 0.11016
Pset_BeamCommon - Reference: 340 x 720 mm; Span: 640 mm; Slope: 0 rad; Roll: 0 rad; IsExternal: no; LoadBearing: yes
Pset_Condition - AssessmentCondition: Empty
Pset_EnvironmentalImpactIndicators - Reference: 340 x 720 mm; sets with these values: 2

# IfcBeam: BB_XX_Betonbalk_ rechthoekig_ center-center_SFB_340 x 720 mm175, BB_XX_Betonbalk, rechthoekig, center-center_SFB:340 x 720 mm:695527
In: 020
PredefinedType: BEAM; Material: BB_Beton_Bestaand
Cpset_Beam - LevelOfAccuracy: in te vullen door Buildwise
IfcRoot - Name: 340 x 720 mm
Qto_BeamBaseQuantities - Length: 5239.87; CrossSectionArea: 0.2448; OuterSurfaceArea: 11.0452; GrossSurfaceArea: 11.5348; NetSurfaceArea: 11.5348; GrossVolume: 1.27541; NetVolume: 1.27541
Pset_BeamCommon - Reference: 340 x 720 mm; Span: 5239.87 mm; Slope: 0 rad; Roll: 0 rad; IsExternal: no; LoadBearing: yes
Pset_Condition - AssessmentCondition: Empty
Pset_EnvironmentalImpactIndicators - Reference: 340 x 720 mm; sets with these values: 2

# IfcBeam: BB_XX_Betonbalk_ rechthoekig_ center-center_SFB_340 x 720 mm177, BB_XX_Betonbalk, rechthoekig, center-center_SFB:340 x 720 mm:695544
In: 020
PredefinedType: BEAM; Material: BB_Beton_Bestaand
Cpset_Beam - LevelOfAccuracy: in te vullen door Buildwise
IfcRoot - Name: 340 x 720 mm
Qto_BeamBaseQuantities - Length: 4740; CrossSectionArea: 0.2448; OuterSurfaceArea: 10.0064; GrossSurfaceArea: 10.496; NetSurfaceArea: 10.496; GrossVolume: 1.15546; NetVolume: 1.15546
Pset_BeamCommon - Reference: 340 x 720 mm; Span: 4740 mm; Slope: 0 rad; Roll: 0 rad; IsExternal: no; LoadBearing: yes
Pset_Condition - AssessmentCondition: Empty
Pset_EnvironmentalImpactIndicators - Reference: 340 x 720 mm; sets with these values: 2

# IfcBeam: BB_XX_Betonbalk_ rechthoekig_ center-center_SFB_340 x 720 mm179, BB_XX_Betonbalk, rechthoekig, center-center_SFB:340 x 720 mm:695583
In: 020
PredefinedType: BEAM; Material: BB_Beton_Bestaand
Cpset_Beam - LevelOfAccuracy: in te vullen door Buildwise
IfcRoot - Name: 340 x 720 mm
Qto_BeamBaseQuantities - Length: 640; CrossSectionArea: 0.2448; OuterSurfaceArea: 1.3568; GrossSurfaceArea: 1.8464; NetSurfaceArea: 1.8464; GrossVolume: 0.156672; NetVolume: 0.156672
Pset_BeamCommon - Reference: 340 x 720 mm; Span: 640 mm; Slope: 0 rad; Roll: 0 rad; IsExternal: no; LoadBearing: yes
Pset_Condition - AssessmentCondition: Empty
Pset_EnvironmentalImpactIndicators - Reference: 340 x 720 mm; sets with these values: 2

# IfcBeam: BB_XX_Betonbalk_ rechthoekig_ center-center_SFB_340 x 720 mm181, BB_XX_Betonbalk, rechthoekig, center-center_SFB:340 x 720 mm:695651
In: 020
PredefinedType: BEAM; Material: BB_Beton_Bestaand
Cpset_Beam - LevelOfAccuracy: in te vullen door Buildwise
IfcRoot - Name: 340 x 720 mm
Qto_BeamBaseQuantities - Length: 6110; CrossSectionArea: 0.2448; OuterSurfaceArea: 12.9532; GrossSurfaceArea: 13.4428; NetSurfaceArea: 13.4428; GrossVolume: 1.49573; NetVolume: 1.49573
Pset_BeamCommon - Reference: 340 x 720 mm; Span: 6110 mm; Slope: 0 rad; Roll: 0 rad; IsExternal: no; LoadBearing: yes
Pset_Condition - AssessmentCondition: Empty
Pset_EnvironmentalImpactIndicators - Reference: 340 x 720 mm; sets with these values: 2

# IfcBeam: BB_XX_Betonbalk_ rechthoekig_ center-center_SFB_340 x 720 mm183, BB_XX_Betonbalk, rechthoekig, center-center_SFB:340 x 720 mm:695653
In: 020
PredefinedType: BEAM; Material: BB_Beton_Bestaand
Cpset_Beam - LevelOfAccuracy: in te vullen door Buildwise
IfcRoot - Name: 340 x 720 mm
Qto_BeamBaseQuantities - Length: 640; CrossSectionArea: 0.2448; OuterSurfaceArea: 1.3568; GrossSurfaceArea: 1.8464; NetSurfaceArea: 1.8464; GrossVolume: 0.156672; NetVolume: 0.156672
Pset_BeamCommon - Reference: 340 x 720 mm; Span: 640 mm; Slope: 0 rad; Roll: 0 rad; IsExternal: no; LoadBearing: yes
Pset_Condition - AssessmentCondition: Empty
Pset_EnvironmentalImpactIndicators - Reference: 340 x 720 mm; sets with these values: 2

# IfcBeam: BB_XX_Betonbalk_ rechthoekig_ center-center_SFB_340 x 720 mm185, BB_XX_Betonbalk, rechthoekig, center-center_SFB:340 x 720 mm:695659
In: 020
PredefinedType: BEAM; Material: BB_Beton_Bestaand
Cpset_Beam - LevelOfAccuracy: in te vullen door Buildwise
IfcRoot - Name: 340 x 720 mm
Qto_BeamBaseQuantities - Length: 640; CrossSectionArea: 0.8586; NetSurfaceArea: 1.7172; NetVolume: 0.11016
Pset_BeamCommon - Reference: 340 x 720 mm; Span: 640 mm; Slope: 0 rad; Roll: 0 rad; IsExternal: no; LoadBearing: yes
Pset_Condition - AssessmentCondition: Empty
Pset_EnvironmentalImpactIndicators - Reference: 340 x 720 mm; sets with these values: 2

# IfcBeam: BB_XX_Betonbalk_ rechthoekig_ center-center_SFB_340 x 720 mm187, BB_XX_Betonbalk, rechthoekig, center-center_SFB:340 x 720 mm:695709
In: 020
PredefinedType: BEAM; Material: BB_Beton_Bestaand
Cpset_Beam - LevelOfAccuracy: in te vullen door Buildwise
IfcRoot - Name: 340 x 720 mm
Qto_BeamBaseQuantities - Length: 5210; CrossSectionArea: 0.2448; OuterSurfaceArea: 11.1194; GrossSurfaceArea: 11.609; NetSurfaceArea: 11.609; GrossVolume: 1.28398; NetVolume: 1.28398
Pset_BeamCommon - Reference: 340 x 720 mm; Span: 5210 mm; Slope: 0 rad; Roll: 0 rad; IsExternal: no; LoadBearing: yes
Pset_Condition - AssessmentCondition: Empty
Pset_EnvironmentalImpactIndicators - Reference: 340 x 720 mm; sets with these values: 2

# IfcBeam: BB_XX_Betonbalk_ rechthoekig_ center-center_SFB_340 x 720 mm189, BB_XX_Betonbalk, rechthoekig, center-center_SFB:340 x 720 mm:695753
In: 020
PredefinedType: BEAM; Material: BB_Beton_Bestaand
Cpset_Beam - LevelOfAccuracy: in te vullen door Buildwise
IfcRoot - Name: 340 x 720 mm
Qto_BeamBaseQuantities - Length: 2350; CrossSectionArea: 2.74949; NetSurfaceArea: 5.49898; NetVolume: 0.558826
Pset_BeamCommon - Reference: 340 x 720 mm; Span: 2350 mm; Slope: 0 rad; Roll: 0 rad; IsExternal: no; LoadBearing: yes
Pset_Condition - AssessmentCondition: Empty
Pset_EnvironmentalImpactIndicators - Reference: 340 x 720 mm; sets with these values: 2

# IfcBeam: BB_XX_Betonbalk_ rechthoekig_ center-center_SFB_340 x 720 mm19, BB_XX_Betonbalk, rechthoekig, center-center_SFB:340 x 720 mm:552967
In: 000
PredefinedType: BEAM; Material: BB_Beton_Bestaand
Cpset_Beam - LevelOfAccuracy: in te vullen door Buildwise
IfcRoot - Name: 340 x 720 mm
Qto_BeamBaseQuantities - Length: 640; CrossSectionArea: 0.8586; NetSurfaceArea: 1.7172; NetVolume: 0.11016
Pset_BeamCommon - Reference: 340 x 720 mm; Span: 640 mm; Slope: 0 rad; Roll: 0 rad; IsExternal: no; LoadBearing: yes
Pset_Condition - AssessmentCondition: Empty
Pset_EnvironmentalImpactIndicators - Reference: 340 x 720 mm; sets with these values: 2

# IfcBeam: BB_XX_Betonbalk_ rechthoekig_ center-center_SFB_340 x 720 mm191, BB_XX_Betonbalk, rechthoekig, center-center_SFB:340 x 720 mm:695821
In: 020
PredefinedType: BEAM; Material: BB_Beton_Bestaand
Cpset_Beam - LevelOfAccuracy: in te vullen door Buildwise
IfcRoot - Name: 340 x 720 mm
Qto_BeamBaseQuantities - Length: 2020; CrossSectionArea: 0.2448; OuterSurfaceArea: 4.2824; GrossSurfaceArea: 4.772; NetSurfaceArea: 4.772; GrossVolume: 0.494496; NetVolume: 0.494496
Pset_BeamCommon - Reference: 340 x 720 mm; Span: 2020 mm; Slope: 0 rad; Roll: 0 rad; IsExternal: no; LoadBearing: yes
Pset_Condition - AssessmentCondition: Empty
Pset_EnvironmentalImpactIndicators - Reference: 340 x 720 mm; sets with these values: 2

# IfcBeam: BB_XX_Betonbalk_ rechthoekig_ center-center_SFB_340 x 720 mm193, BB_XX_Betonbalk, rechthoekig, center-center_SFB:340 x 720 mm:695823
In: 020
PredefinedType: BEAM; Material: BB_Beton_Bestaand
Cpset_Beam - LevelOfAccuracy: in te vullen door Buildwise
IfcRoot - Name: 340 x 720 mm
Qto_BeamBaseQuantities - Length: 6980; CrossSectionArea: 0.2448; OuterSurfaceArea: 14.7976; GrossSurfaceArea: 15.2872; NetSurfaceArea: 15.2872; GrossVolume: 1.7087; NetVolume: 1.7087
Pset_BeamCommon - Reference: 340 x 720 mm; Span: 6980 mm; Slope: 0 rad; Roll: 0 rad; IsExternal: no; LoadBearing: yes
Pset_Condition - AssessmentCondition: Empty
Pset_EnvironmentalImpactIndicators - Reference: 340 x 720 mm; sets with these values: 2

# IfcBeam: BB_XX_Betonbalk_ rechthoekig_ center-center_SFB_340 x 720 mm195, BB_XX_Betonbalk, rechthoekig, center-center_SFB:340 x 720 mm:695829
In: 020
PredefinedType: BEAM; Material: BB_Beton_Bestaand
Cpset_Beam - LevelOfAccuracy: in te vullen door Buildwise
IfcRoot - Name: 340 x 720 mm
Qto_BeamBaseQuantities - Length: 7200; CrossSectionArea: 0.2448; OuterSurfaceArea: 15.264; GrossSurfaceArea: 15.7536; NetSurfaceArea: 15.7536; GrossVolume: 1.76256; NetVolume: 1.76256
Pset_BeamCommon - Reference: 340 x 720 mm; Span: 7200 mm; Slope: 0 rad; Roll: 0 rad; IsExternal: no; LoadBearing: yes
Pset_Condition - AssessmentCondition: Empty
Pset_EnvironmentalImpactIndicators - Reference: 340 x 720 mm; sets with these values: 2

# IfcBeam: BB_XX_Betonbalk_ rechthoekig_ center-center_SFB_340 x 720 mm197, BB_XX_Betonbalk, rechthoekig, center-center_SFB:340 x 720 mm:695857
In: 020
PredefinedType: BEAM; Material: BB_Beton_Bestaand
Cpset_Beam - LevelOfAccuracy: in te vullen door Buildwise
IfcRoot - Name: 340 x 720 mm
Qto_BeamBaseQuantities - Length: 790; CrossSectionArea: 1.1392; NetSurfaceArea: 2.2784; NetVolume: 0.156672
Pset_BeamCommon - Reference: 340 x 720 mm; Span: 790 mm; Slope: 0 rad; Roll: 0 rad; IsExternal: no; LoadBearing: yes
Pset_Condition - AssessmentCondition: Empty
Pset_EnvironmentalImpactIndicators - Reference: 340 x 720 mm; sets with these values: 2

# IfcBeam: BB_XX_Betonbalk_ rechthoekig_ center-center_SFB_340 x 720 mm199, BB_XX_Betonbalk, rechthoekig, center-center_SFB:340 x 720 mm:695876
In: 020
PredefinedType: BEAM; Material: BB_Beton_Bestaand
Cpset_Beam - LevelOfAccuracy: in te vullen door Buildwise
IfcRoot - Name: 340 x 720 mm
Qto_BeamBaseQuantities - Length: 715; CrossSectionArea: 1.1544; NetSurfaceArea: 2.3088; NetVolume: 0.14688
Pset_BeamCommon - Reference: 340 x 720 mm; Span: 715 mm; Slope: 0 rad; Roll: 0 rad; IsExternal: no; LoadBearing: yes
Pset_Condition - AssessmentCondition: Empty
Pset_EnvironmentalImpactIndicators - Reference: 340 x 720 mm; sets with these values: 2

# IfcBeam: BB_XX_Betonbalk_ rechthoekig_ center-center_SFB_340 x 720 mm201, BB_XX_Betonbalk, rechthoekig, center-center_SFB:340 x 720 mm:1932638
In: 020
PredefinedType: BEAM; Material: BB_Beton_Bestaand
Cpset_Beam - LevelOfAccuracy: in te vullen door Buildwise
IfcRoot - Name: 340 x 720 mm
Qto_BeamBaseQuantities - Length: 1090; CrossSectionArea: 1.4439; NetSurfaceArea: 2.8878; NetVolume: 0.1998
Pset_BeamCommon - Reference: 340 x 720 mm; Span: 1090 mm; Slope: 0 rad; Roll: 0 rad; IsExternal: no; LoadBearing: yes
Pset_Condition - AssessmentCondition: Empty
Pset_EnvironmentalImpactIndicators - Reference: 340 x 720 mm; sets with these values: 2

# IfcBeam: BB_XX_Betonbalk_ rechthoekig_ center-center_SFB_340 x 720 mm203, BB_XX_Betonbalk, rechthoekig, center-center_SFB:340 x 720 mm:1932640
In: 020
PredefinedType: BEAM; Material: BB_Beton_Bestaand
Cpset_Beam - LevelOfAccuracy: in te vullen door Buildwise
IfcRoot - Name: 340 x 720 mm
Qto_BeamBaseQuantities - Length: 1090; CrossSectionArea: 1.4439; NetSurfaceArea: 2.8878; NetVolume: 0.1998
Pset_BeamCommon - Reference: 340 x 720 mm; Span: 1090 mm; Slope: 0 rad; Roll: 0 rad; IsExternal: no; LoadBearing: yes
Pset_Condition - AssessmentCondition: Empty
Pset_EnvironmentalImpactIndicators - Reference: 340 x 720 mm; sets with these values: 2

# IfcBeam: BB_XX_Betonbalk_ rechthoekig_ center-center_SFB_340 x 720 mm205, BB_XX_Betonbalk, rechthoekig, center-center_SFB:340 x 720 mm:1932713
In: 020
PredefinedType: BEAM; Material: BB_Beton_Bestaand
Cpset_Beam - LevelOfAccuracy: in te vullen door Buildwise
IfcRoot - Name: 340 x 720 mm
Qto_BeamBaseQuantities - Length: 1090; CrossSectionArea: 1.4439; NetSurfaceArea: 2.8878; NetVolume: 0.1998
Pset_BeamCommon - Reference: 340 x 720 mm; Span: 1090 mm; Slope: 0 rad; Roll: 0 rad; IsExternal: no; LoadBearing: yes
Pset_Condition - AssessmentCondition: Empty
Pset_EnvironmentalImpactIndicators - Reference: 340 x 720 mm; sets with these values: 2

# IfcBeam: BB_XX_Betonbalk_ rechthoekig_ center-center_SFB_340 x 720 mm207, BB_XX_Betonbalk, rechthoekig, center-center_SFB:340 x 720 mm:1932715
In: 020
PredefinedType: BEAM; Material: BB_Beton_Bestaand
Cpset_Beam - LevelOfAccuracy: in te vullen door Buildwise
IfcRoot - Name: 340 x 720 mm
Qto_BeamBaseQuantities - Length: 1090; CrossSectionArea: 1.4439; NetSurfaceArea: 2.8878; NetVolume: 0.1998
Pset_BeamCommon - Reference: 340 x 720 mm; Span: 1090 mm; Slope: 0 rad; Roll: 0 rad; IsExternal: no; LoadBearing: yes
Pset_Condition - AssessmentCondition: Empty
Pset_EnvironmentalImpactIndicators - Reference: 340 x 720 mm; sets with these values: 2

# IfcBeam: BB_XX_Betonbalk_ rechthoekig_ center-center_SFB_340 x 720 mm209, BB_XX_Betonbalk, rechthoekig, center-center_SFB:340 x 720 mm:1964689
In: 020
PredefinedType: BEAM; Material: BB_Beton_Bestaand
Cpset_Beam - LevelOfAccuracy: in te vullen door Buildwise
IfcRoot - Name: 340 x 720 mm
Qto_BeamBaseQuantities - Length: 640; CrossSectionArea: 0.8586; NetSurfaceArea: 1.7172; NetVolume: 0.11016
Pset_BeamCommon - Reference: 340 x 720 mm; Span: 640 mm; Slope: 0 rad; Roll: 0 rad; IsExternal: no; LoadBearing: yes
Pset_Condition - AssessmentCondition: Empty
Pset_EnvironmentalImpactIndicators - Reference: 340 x 720 mm; sets with these values: 2

# IfcBeam: BB_XX_Betonbalk_ rechthoekig_ center-center_SFB_340 x 720 mm21, BB_XX_Betonbalk, rechthoekig, center-center_SFB:340 x 720 mm:553256
In: 000
PredefinedType: BEAM; Material: BB_Beton_Bestaand
Cpset_Beam - LevelOfAccuracy: in te vullen door Buildwise
IfcRoot - Name: 340 x 720 mm
Qto_BeamBaseQuantities - Length: 6090; CrossSectionArea: 0.2448; OuterSurfaceArea: 12.9108; GrossSurfaceArea: 13.4004; NetSurfaceArea: 13.4004; GrossVolume: 1.49083; NetVolume: 1.49083
Pset_BeamCommon - Reference: 340 x 720 mm; Span: 6090 mm; Slope: 0 rad; Roll: 0 rad; IsExternal: no; LoadBearing: yes
Pset_Condition - AssessmentCondition: Empty
Pset_EnvironmentalImpactIndicators - Reference: 340 x 720 mm; sets with these values: 2

# IfcBeam: BB_XX_Betonbalk_ rechthoekig_ center-center_SFB_340 x 720 mm211, BB_XX_Betonbalk, rechthoekig, center-center_SFB:340 x 720 mm:705224
In: 030
PredefinedType: BEAM; Material: BB_Beton_Bestaand
Cpset_Beam - LevelOfAccuracy: in te vullen door Buildwise
IfcRoot - Name: 340 x 720 mm
Qto_BeamBaseQuantities - Length: 5335; CrossSectionArea: 0.2448; OuterSurfaceArea: 11.3102; GrossSurfaceArea: 11.7998; NetSurfaceArea: 11.7998; GrossVolume: 1.30601; NetVolume: 1.30601
Pset_BeamCommon - Reference: 340 x 720 mm; Span: 5335 mm; Slope: 0 rad; Roll: 0 rad; IsExternal: no; LoadBearing: yes
Pset_Condition - AssessmentCondition: Empty
Pset_EnvironmentalImpactIndicators - Reference: 340 x 720 mm; sets with these values: 2

# IfcBeam: BB_XX_Betonbalk_ rechthoekig_ center-center_SFB_340 x 720 mm213, BB_XX_Betonbalk, rechthoekig, center-center_SFB:340 x 720 mm:705292
In: 030
PredefinedType: BEAM; Material: BB_Beton_Bestaand
Cpset_Beam - LevelOfAccuracy: in te vullen door Buildwise
IfcRoot - Name: 340 x 720 mm
Qto_BeamBaseQuantities - Length: 2020; CrossSectionArea: 0.2448; OuterSurfaceArea: 4.2824; GrossSurfaceArea: 4.772; NetSurfaceArea: 4.772; GrossVolume: 0.494496; NetVolume: 0.494496
Pset_BeamCommon - Reference: 340 x 720 mm; Span: 2020 mm; Slope: 0 rad; Roll: 0 rad; IsExternal: no; LoadBearing: yes
Pset_Condition - AssessmentCondition: Empty
Pset_EnvironmentalImpactIndicators - Reference: 340 x 720 mm; sets with these values: 2

# IfcBeam: BB_XX_Betonbalk_ rechthoekig_ center-center_SFB_340 x 720 mm215, BB_XX_Betonbalk, rechthoekig, center-center_SFB:340 x 720 mm:705294
In: 030
PredefinedType: BEAM; Material: BB_Beton_Bestaand
Cpset_Beam - LevelOfAccuracy: in te vullen door Buildwise
IfcRoot - Name: 340 x 720 mm
Qto_BeamBaseQuantities - Length: 6980; CrossSectionArea: 0.2448; OuterSurfaceArea: 14.7976; GrossSurfaceArea: 15.2872; NetSurfaceArea: 15.2872; GrossVolume: 1.7087; NetVolume: 1.7087
Pset_BeamCommon - Reference: 340 x 720 mm; Span: 6980 mm; Slope: 0 rad; Roll: 0 rad; IsExternal: no; LoadBearing: yes
Pset_Condition - AssessmentCondition: Empty
Pset_EnvironmentalImpactIndicators - Reference: 340 x 720 mm; sets with these values: 2

# IfcBeam: BB_XX_Betonbalk_ rechthoekig_ center-center_SFB_340 x 720 mm217, BB_XX_Betonbalk, rechthoekig, center-center_SFB:340 x 720 mm:705300
In: 030
PredefinedType: BEAM; Material: BB_Beton_Bestaand
Cpset_Beam - LevelOfAccuracy: in te vullen door Buildwise
IfcRoot - Name: 340 x 720 mm
Qto_BeamBaseQuantities - Length: 17805; CrossSectionArea: 0.2448; OuterSurfaceArea: 37.6724; GrossSurfaceArea: 38.162; NetSurfaceArea: 38.162; GrossVolume: 4.3501; NetVolume: 4.3501
Pset_BeamCommon - Reference: 340 x 720 mm; Span: 17805 mm; Slope: 0 rad; Roll: 0 rad; IsExternal: no; LoadBearing: yes
Pset_Condition - AssessmentCondition: Empty
Pset_EnvironmentalImpactIndicators - Reference: 340 x 720 mm; sets with these values: 2

# IfcBeam: BB_XX_Betonbalk_ rechthoekig_ center-center_SFB_340 x 720 mm219, BB_XX_Betonbalk, rechthoekig, center-center_SFB:340 x 720 mm:731752
In: 030
PredefinedType: BEAM; Material: BB_Beton_Bestaand
Cpset_Beam - LevelOfAccuracy: in te vullen door Buildwise
IfcRoot - Name: 340 x 720 mm
Qto_BeamBaseQuantities - Length: 35775; CrossSectionArea: 0.2448; OuterSurfaceArea: 75.843; GrossSurfaceArea: 76.3326; NetSurfaceArea: 76.3326; GrossVolume: 8.75772; NetVolume: 8.75772
Pset_BeamCommon - Reference: 340 x 720 mm; Span: 35775 mm; Slope: 0 rad; Roll: 0 rad; IsExternal: no; LoadBearing: yes
Pset_Condition - AssessmentCondition: Empty
Pset_EnvironmentalImpactIndicators - Reference: 340 x 720 mm; sets with these values: 2

# IfcBeam: BB_XX_Betonbalk_ rechthoekig_ center-center_SFB_340 x 720 mm221, BB_XX_Betonbalk, rechthoekig, center-center_SFB:340 x 720 mm:758738
In: 030
PredefinedType: BEAM; Material: BB_Beton_Bestaand
Cpset_Beam - LevelOfAccuracy: in te vullen door Buildwise
IfcRoot - Name: 340 x 720 mm
Qto_BeamBaseQuantities - Length: 24859.9; CrossSectionArea: 0.2448; OuterSurfaceArea: 52.7029; GrossSurfaceArea: 53.1925; NetSurfaceArea: 53.1925; GrossVolume: 6.0857; NetVolume: 6.0857
Pset_BeamCommon - Reference: 340 x 720 mm; Span: 24859.9 mm; Slope: 0 rad; Roll: 0 rad; IsExternal: no; LoadBearing: yes
Pset_Condition - AssessmentCondition: Empty
Pset_EnvironmentalImpactIndicators - Reference: 340 x 720 mm; sets with these values: 2

# IfcBeam: BB_XX_Betonbalk_ rechthoekig_ center-center_SFB_340 x 720 mm223, BB_XX_Betonbalk, rechthoekig, center-center_SFB:340 x 720 mm:765865
In: 030
PredefinedType: BEAM; Material: BB_Beton_Bestaand
Cpset_Beam - LevelOfAccuracy: in te vullen door Buildwise
IfcRoot - Name: 340 x 720 mm
Qto_BeamBaseQuantities - Length: 35775; CrossSectionArea: 0.2448; OuterSurfaceArea: 75.843; GrossSurfaceArea: 76.3326; NetSurfaceArea: 76.3326; GrossVolume: 8.75772; NetVolume: 8.75772
Pset_BeamCommon - Reference: 340 x 720 mm; Span: 35775 mm; Slope: 0 rad; Roll: 0 rad; IsExternal: no; LoadBearing: yes
Pset_Condition - AssessmentCondition: Empty
Pset_EnvironmentalImpactIndicators - Reference: 340 x 720 mm; sets with these values: 2

# IfcBeam: BB_XX_Betonbalk_ rechthoekig_ center-center_SFB_340 x 720 mm225, BB_XX_Betonbalk, rechthoekig, center-center_SFB:340 x 720 mm:766487
In: 030
PredefinedType: BEAM; Material: BB_Beton_Bestaand
Cpset_Beam - LevelOfAccuracy: in te vullen door Buildwise
IfcRoot - Name: 340 x 720 mm
Qto_BeamBaseQuantities - Length: 23305; CrossSectionArea: 0.2448; OuterSurfaceArea: 49.4066; GrossSurfaceArea: 49.8962; NetSurfaceArea: 49.8962; GrossVolume: 5.70506; NetVolume: 5.70506
Pset_BeamCommon - Reference: 340 x 720 mm; Span: 23305 mm; Slope: 0 rad; Roll: 0 rad; IsExternal: no; LoadBearing: yes
Pset_Condition - AssessmentCondition: Empty
Pset_EnvironmentalImpactIndicators - Reference: 340 x 720 mm; sets with these values: 2

# IfcBeam: BB_XX_Betonbalk_ rechthoekig_ center-center_SFB_340 x 720 mm23 (2)
In: 000
PredefinedType: BEAM; Material: BB_Beton_Bestaand
Cpset_Beam - LevelOfAccuracy: in te vullen door Buildwise
IfcRoot - Name: 340 x 720 mm
Qto_BeamBaseQuantities - Length: 7010; CrossSectionArea: 0.2448; OuterSurfaceArea: 14.8612; GrossSurfaceArea: 15.3508; NetSurfaceArea: 15.3508; GrossVolume: 1.71605; NetVolume: 1.71605
Pset_BeamCommon - Reference: 340 x 720 mm; Span: 7010 mm; Slope: 0 rad; Roll: 0 rad; IsExternal: no; LoadBearing: yes
Pset_Condition - AssessmentCondition: Empty
Pset_EnvironmentalImpactIndicators - Reference: 340 x 720 mm; sets with these values: 2
Name (BB_XX_Betonbalk, rechthoekig, center-center_SFB:340 x 720 mm:...)
553595
594446

# IfcBeam: BB_XX_Betonbalk_ rechthoekig_ center-center_SFB_340 x 720 mm25 (2)
In: 000
PredefinedType: BEAM; Material: BB_Beton_Bestaand
Cpset_Beam - LevelOfAccuracy: in te vullen door Buildwise
IfcRoot - Name: 340 x 720 mm
Qto_BeamBaseQuantities - Length: 4740; CrossSectionArea: 0.2448; OuterSurfaceArea: 10.0488; GrossSurfaceArea: 10.5384; NetSurfaceArea: 10.5384; GrossVolume: 1.16035; NetVolume: 1.16035
Pset_BeamCommon - Reference: 340 x 720 mm; Span: 4740 mm; Slope: 0 rad; Roll: 0 rad; IsExternal: no; LoadBearing: yes
Pset_Condition - AssessmentCondition: Empty
Pset_EnvironmentalImpactIndicators - Reference: 340 x 720 mm; sets with these values: 2
Name (BB_XX_Betonbalk, rechthoekig, center-center_SFB:340 x 720 mm:...)
554003
563631

# IfcBeam: BB_XX_Betonbalk_ rechthoekig_ center-center_SFB_340 x 720 mm27, BB_XX_Betonbalk, rechthoekig, center-center_SFB:340 x 720 mm:564176
In: 000
PredefinedType: BEAM; Material: BB_Beton_Bestaand
Cpset_Beam - LevelOfAccuracy: in te vullen door Buildwise
IfcRoot - Name: 340 x 720 mm
Qto_BeamBaseQuantities - Length: 640; CrossSectionArea: 0.8586; NetSurfaceArea: 1.7172; NetVolume: 0.11016
Pset_BeamCommon - Reference: 340 x 720 mm; Span: 640 mm; Slope: 0 rad; Roll: 0 rad; IsExternal: no; LoadBearing: yes
Pset_Condition - AssessmentCondition: Empty
Pset_EnvironmentalImpactIndicators - Reference: 340 x 720 mm; sets with these values: 2

# IfcBeam: BB_XX_Betonbalk_ rechthoekig_ center-center_SFB_340 x 720 mm29, BB_XX_Betonbalk, rechthoekig, center-center_SFB:340 x 720 mm:564634
In: 000
PredefinedType: BEAM; Material: BB_Beton_Bestaand
Cpset_Beam - LevelOfAccuracy: in te vullen door Buildwise
IfcRoot - Name: 340 x 720 mm
Qto_BeamBaseQuantities - Length: 1090; CrossSectionArea: 1.4439; NetSurfaceArea: 2.8878; NetVolume: 0.1998
Pset_BeamCommon - Reference: 340 x 720 mm; Span: 1090 mm; Slope: 0 rad; Roll: 0 rad; IsExternal: no; LoadBearing: yes
Pset_Condition - AssessmentCondition: Empty
Pset_EnvironmentalImpactIndicators - Reference: 340 x 720 mm; sets with these values: 2

# IfcBeam: BB_XX_Betonbalk_ rechthoekig_ center-center_SFB_340 x 720 mm3, BB_XX_Betonbalk, rechthoekig, center-center_SFB:340 x 720 mm:546104
In: 000
PredefinedType: BEAM; Material: BB_Beton_Bestaand
Cpset_Beam - LevelOfAccuracy: in te vullen door Buildwise
IfcRoot - Name: 340 x 720 mm
Qto_BeamBaseQuantities - Length: 640; CrossSectionArea: 0.8586; NetSurfaceArea: 1.7172; NetVolume: 0.11016
Pset_BeamCommon - Reference: 340 x 720 mm; Span: 640 mm; Slope: 0 rad; Roll: 0 rad; IsExternal: no; LoadBearing: yes
Pset_Condition - AssessmentCondition: Empty
Pset_EnvironmentalImpactIndicators - Reference: 340 x 720 mm; sets with these values: 2

# IfcBeam: BB_XX_Betonbalk_ rechthoekig_ center-center_SFB_340 x 720 mm31, BB_XX_Betonbalk, rechthoekig, center-center_SFB:340 x 720 mm:566567
In: 000
PredefinedType: BEAM; Material: BB_Beton_Bestaand
Cpset_Beam - LevelOfAccuracy: in te vullen door Buildwise
IfcRoot - Name: 340 x 720 mm
Qto_BeamBaseQuantities - Length: 640; CrossSectionArea: 0.8586; NetSurfaceArea: 1.7172; NetVolume: 0.11016
Pset_BeamCommon - Reference: 340 x 720 mm; Span: 640 mm; Slope: 0 rad; Roll: 0 rad; IsExternal: no; LoadBearing: yes
Pset_Condition - AssessmentCondition: Empty
Pset_EnvironmentalImpactIndicators - Reference: 340 x 720 mm; sets with these values: 2

# IfcBeam: BB_XX_Betonbalk_ rechthoekig_ center-center_SFB_340 x 720 mm33 (7)
PredefinedType: BEAM; Material: BB_Beton_Bestaand
Cpset_Beam - LevelOfAccuracy: in te vullen door Buildwise
IfcRoot - Name: 340 x 720 mm
Qto_BeamBaseQuantities - Length: 5300; CrossSectionArea: 0.2448; OuterSurfaceArea: 11.236; GrossSurfaceArea: 11.7256; NetSurfaceArea: 11.7256; GrossVolume: 1.29744; NetVolume: 1.29744
Pset_BeamCommon - Reference: 340 x 720 mm; Span: 5300 mm; Slope: 0 rad; Roll: 0 rad; IsExternal: no; LoadBearing: yes
Pset_Condition - AssessmentCondition: Empty
Pset_EnvironmentalImpactIndicators - Reference: 340 x 720 mm; sets with these values: 2
Name (BB_XX_Betonbalk, rechthoekig, center-center_SFB:340 x 720 mm:...) | In
567750 | 000
593349 | 000
648807 | 010
650688 | 010
695749 | 020
695827 | 020
705220 | 030

# IfcBeam: BB_XX_Betonbalk_ rechthoekig_ center-center_SFB_340 x 720 mm35 (5)
PredefinedType: BEAM; Material: BB_Beton_Bestaand
Cpset_Beam - LevelOfAccuracy: in te vullen door Buildwise
IfcRoot - Name: 340 x 720 mm
Qto_BeamBaseQuantities - Length: 7200; CrossSectionArea: 0.2448; OuterSurfaceArea: 15.264; GrossSurfaceArea: 15.7536; NetSurfaceArea: 15.7536; GrossVolume: 1.76256; NetVolume: 1.76256
Pset_BeamCommon - Reference: 340 x 720 mm; Span: 7200 mm; Slope: 0 rad; Roll: 0 rad; IsExternal: no; LoadBearing: yes
Pset_Condition - AssessmentCondition: Empty
Pset_EnvironmentalImpactIndicators - Reference: 340 x 720 mm; sets with these values: 2
Name (BB_XX_Betonbalk, rechthoekig, center-center_SFB:340 x 720 mm:...) | In
567956 | 000
648809 | 010
650690 | 010
695751 | 020
705222 | 030

# IfcBeam: BB_XX_Betonbalk_ rechthoekig_ center-center_SFB_340 x 720 mm37, BB_XX_Betonbalk, rechthoekig, center-center_SFB:340 x 720 mm:568073
In: 000
PredefinedType: BEAM; Material: BB_Beton_Bestaand
Cpset_Beam - LevelOfAccuracy: in te vullen door Buildwise
IfcRoot - Name: 340 x 720 mm
Qto_BeamBaseQuantities - Length: 2405; CrossSectionArea: 2.78579; NetSurfaceArea: 5.57158; NetVolume: 0.56481
Pset_BeamCommon - Reference: 340 x 720 mm; Span: 2405 mm; Slope: 0 rad; Roll: 0 rad; IsExternal: no; LoadBearing: yes
Pset_Condition - AssessmentCondition: Empty
Pset_EnvironmentalImpactIndicators - Reference: 340 x 720 mm; sets with these values: 2

# IfcBeam: BB_XX_Betonbalk_ rechthoekig_ center-center_SFB_340 x 720 mm39, BB_XX_Betonbalk, rechthoekig, center-center_SFB:340 x 720 mm:577361
In: 000
PredefinedType: BEAM; Material: BB_Beton_Bestaand
Cpset_Beam - LevelOfAccuracy: in te vullen door Buildwise
IfcRoot - Name: 340 x 720 mm
Qto_BeamBaseQuantities - Length: 640; CrossSectionArea: 0.8586; NetSurfaceArea: 1.7172; NetVolume: 0.11016
Pset_BeamCommon - Reference: 340 x 720 mm; Span: 640 mm; Slope: 0 rad; Roll: 0 rad; IsExternal: no; LoadBearing: yes
Pset_Condition - AssessmentCondition: Empty
Pset_EnvironmentalImpactIndicators - Reference: 340 x 720 mm; sets with these values: 2

# IfcBeam: BB_XX_Betonbalk_ rechthoekig_ center-center_SFB_340 x 720 mm41, BB_XX_Betonbalk, rechthoekig, center-center_SFB:340 x 720 mm:578438
In: 000
PredefinedType: BEAM; Material: BB_Beton_Bestaand
Cpset_Beam - LevelOfAccuracy: in te vullen door Buildwise
IfcRoot - Name: 340 x 720 mm
Qto_BeamBaseQuantities - Length: 240; CrossSectionArea: 0.2448; OuterSurfaceArea: 0.291076; GrossSurfaceArea: 0.780676; NetSurfaceArea: 0.780676; GrossVolume: 0.033611; NetVolume: 0.033611
Pset_BeamCommon - Reference: 340 x 720 mm; Span: 240 mm; Slope: 0 rad; Roll: 0 rad; IsExternal: no; LoadBearing: yes
Pset_Condition - AssessmentCondition: Empty
Pset_EnvironmentalImpactIndicators - Reference: 340 x 720 mm; sets with these values: 2

# IfcBeam: BB_XX_Betonbalk_ rechthoekig_ center-center_SFB_340 x 720 mm43, BB_XX_Betonbalk, rechthoekig, center-center_SFB:340 x 720 mm:579635
In: 000
PredefinedType: BEAM; Material: BB_Beton_Bestaand
Cpset_Beam - LevelOfAccuracy: in te vullen door Buildwise
IfcRoot - Name: 340 x 720 mm
Qto_BeamBaseQuantities - Length: 6110; CrossSectionArea: 0.2448; OuterSurfaceArea: 12.9532; GrossSurfaceArea: 13.4428; NetSurfaceArea: 13.4428; GrossVolume: 1.49573; NetVolume: 1.49573
Pset_BeamCommon - Reference: 340 x 720 mm; Span: 6110 mm; Slope: 0 rad; Roll: 0 rad; IsExternal: no; LoadBearing: yes
Pset_Condition - AssessmentCondition: Empty
Pset_EnvironmentalImpactIndicators - Reference: 340 x 720 mm; sets with these values: 2

# IfcBeam: BB_XX_Betonbalk_ rechthoekig_ center-center_SFB_340 x 720 mm45, BB_XX_Betonbalk, rechthoekig, center-center_SFB:340 x 720 mm:579938
In: 000
PredefinedType: BEAM; Material: BB_Beton_Bestaand
Cpset_Beam - LevelOfAccuracy: in te vullen door Buildwise
IfcRoot - Name: 340 x 720 mm
Qto_BeamBaseQuantities - Length: 1090; CrossSectionArea: 1.4439; NetSurfaceArea: 2.8878; NetVolume: 0.1998
Pset_BeamCommon - Reference: 340 x 720 mm; Span: 1090 mm; Slope: 0 rad; Roll: 0 rad; IsExternal: no; LoadBearing: yes
Pset_Condition - AssessmentCondition: Empty
Pset_EnvironmentalImpactIndicators - Reference: 340 x 720 mm; sets with these values: 2

# IfcBeam: BB_XX_Betonbalk_ rechthoekig_ center-center_SFB_340 x 720 mm47, BB_XX_Betonbalk, rechthoekig, center-center_SFB:340 x 720 mm:580678
In: 000
PredefinedType: BEAM; Material: BB_Beton_Bestaand
Cpset_Beam - LevelOfAccuracy: in te vullen door Buildwise
IfcRoot - Name: 340 x 720 mm
Qto_BeamBaseQuantities - Length: 4310; CrossSectionArea: 0.2448; OuterSurfaceArea: 9.1372; GrossSurfaceArea: 9.6268; NetSurfaceArea: 9.6268; GrossVolume: 1.05509; NetVolume: 1.05509
Pset_BeamCommon - Reference: 340 x 720 mm; Span: 4310 mm; Slope: 0 rad; Roll: 0 rad; IsExternal: no; LoadBearing: yes
Pset_Condition - AssessmentCondition: Empty
Pset_EnvironmentalImpactIndicators - Reference: 340 x 720 mm; sets with these values: 2

# IfcBeam: BB_XX_Betonbalk_ rechthoekig_ center-center_SFB_340 x 720 mm49, BB_XX_Betonbalk, rechthoekig, center-center_SFB:340 x 720 mm:581011
In: 000
PredefinedType: BEAM; Material: BB_Beton_Bestaand
Cpset_Beam - LevelOfAccuracy: in te vullen door Buildwise
IfcRoot - Name: 340 x 720 mm
Qto_BeamBaseQuantities - Length: 6110; CrossSectionArea: 0.2448; OuterSurfaceArea: 12.9532; GrossSurfaceArea: 13.4428; NetSurfaceArea: 13.4428; GrossVolume: 1.49573; NetVolume: 1.49573
Pset_BeamCommon - Reference: 340 x 720 mm; Span: 6110 mm; Slope: 0 rad; Roll: 0 rad; IsExternal: no; LoadBearing: yes
Pset_Condition - AssessmentCondition: Empty
Pset_EnvironmentalImpactIndicators - Reference: 340 x 720 mm; sets with these values: 2

# IfcBeam: BB_XX_Betonbalk_ rechthoekig_ center-center_SFB_340 x 720 mm5, BB_XX_Betonbalk, rechthoekig, center-center_SFB:340 x 720 mm:547038
In: 000
PredefinedType: BEAM; Material: BB_Beton_Bestaand
Cpset_Beam - LevelOfAccuracy: in te vullen door Buildwise
IfcRoot - Name: 340 x 720 mm
Qto_BeamBaseQuantities - Length: 6110; CrossSectionArea: 0.2448; OuterSurfaceArea: 12.9532; GrossSurfaceArea: 13.4428; NetSurfaceArea: 13.4428; GrossVolume: 1.49573; NetVolume: 1.49573
Pset_BeamCommon - Reference: 340 x 720 mm; Span: 6110 mm; Slope: 0 rad; Roll: 0 rad; IsExternal: no; LoadBearing: yes
Pset_Condition - AssessmentCondition: Empty
Pset_EnvironmentalImpactIndicators - Reference: 340 x 720 mm; sets with these values: 2

# IfcBeam: BB_XX_Betonbalk_ rechthoekig_ center-center_SFB_340 x 720 mm51, BB_XX_Betonbalk, rechthoekig, center-center_SFB:340 x 720 mm:581214
In: 000
PredefinedType: BEAM; Material: BB_Beton_Bestaand
Cpset_Beam - LevelOfAccuracy: in te vullen door Buildwise
IfcRoot - Name: 340 x 720 mm
Qto_BeamBaseQuantities - Length: 1090; CrossSectionArea: 1.4439; NetSurfaceArea: 2.8878; NetVolume: 0.1998
Pset_BeamCommon - Reference: 340 x 720 mm; Span: 1090 mm; Slope: 0 rad; Roll: 0 rad; IsExternal: no; LoadBearing: yes
Pset_Condition - AssessmentCondition: Empty
Pset_EnvironmentalImpactIndicators - Reference: 340 x 720 mm; sets with these values: 2

# IfcBeam: BB_XX_Betonbalk_ rechthoekig_ center-center_SFB_340 x 720 mm53, BB_XX_Betonbalk, rechthoekig, center-center_SFB:340 x 720 mm:581449
In: 000
PredefinedType: BEAM; Material: BB_Beton_Bestaand
Cpset_Beam - LevelOfAccuracy: in te vullen door Buildwise
IfcRoot - Name: 340 x 720 mm
Qto_BeamBaseQuantities - Length: 640; CrossSectionArea: 0.8586; NetSurfaceArea: 1.7172; NetVolume: 0.11016
Pset_BeamCommon - Reference: 340 x 720 mm; Span: 640 mm; Slope: 0 rad; Roll: 0 rad; IsExternal: no; LoadBearing: yes
Pset_Condition - AssessmentCondition: Empty
Pset_EnvironmentalImpactIndicators - Reference: 340 x 720 mm; sets with these values: 2

# IfcBeam: BB_XX_Betonbalk_ rechthoekig_ center-center_SFB_340 x 720 mm55 (8)
PredefinedType: BEAM; Material: BB_Beton_Bestaand
Cpset_Beam - LevelOfAccuracy: in te vullen door Buildwise
IfcRoot - Name: 340 x 720 mm
Qto_BeamBaseQuantities - Length: 6900; CrossSectionArea: 0.2448; OuterSurfaceArea: 14.628; GrossSurfaceArea: 15.1176; NetSurfaceArea: 15.1176; GrossVolume: 1.68912; NetVolume: 1.68912
Pset_BeamCommon - Reference: 340 x 720 mm; Span: 6900 mm; Slope: 0 rad; Roll: 0 rad; IsExternal: no; LoadBearing: yes
Pset_Condition - AssessmentCondition: Empty
Pset_EnvironmentalImpactIndicators - Reference: 340 x 720 mm; sets with these values: 2
Name (BB_XX_Betonbalk, rechthoekig, center-center_SFB:340 x 720 mm:...) | In
589594 | 000
593136 | 000
650675 | 010
650686 | 010
695814 | 020
695825 | 020
705285 | 030
705296 | 030

# IfcBeam: BB_XX_Betonbalk_ rechthoekig_ center-center_SFB_340 x 720 mm57, BB_XX_Betonbalk, rechthoekig, center-center_SFB:340 x 720 mm:589883
In: 000
PredefinedType: BEAM; Material: BB_Beton_Bestaand
Cpset_Beam - LevelOfAccuracy: in te vullen door Buildwise
IfcRoot - Name: 340 x 720 mm
Qto_BeamBaseQuantities - Length: 6980; CrossSectionArea: 0.2448; OuterSurfaceArea: 14.7976; GrossSurfaceArea: 15.2872; NetSurfaceArea: 15.2872; GrossVolume: 1.7087; NetVolume: 1.7087
Pset_BeamCommon - Reference: 340 x 720 mm; Span: 6980 mm; Slope: 0 rad; Roll: 0 rad; IsExternal: no; LoadBearing: yes
Pset_Condition - AssessmentCondition: Empty
Pset_EnvironmentalImpactIndicators - Reference: 340 x 720 mm; sets with these values: 2

# IfcBeam: BB_XX_Betonbalk_ rechthoekig_ center-center_SFB_340 x 720 mm59, BB_XX_Betonbalk, rechthoekig, center-center_SFB:340 x 720 mm:591598
In: 000
PredefinedType: BEAM; Material: BB_Beton_Bestaand
Cpset_Beam - LevelOfAccuracy: in te vullen door Buildwise
IfcRoot - Name: 340 x 720 mm
Qto_BeamBaseQuantities - Length: 2020; CrossSectionArea: 0.2448; OuterSurfaceArea: 4.2824; GrossSurfaceArea: 4.772; NetSurfaceArea: 4.772; GrossVolume: 0.494496; NetVolume: 0.494496
Pset_BeamCommon - Reference: 340 x 720 mm; Span: 2020 mm; Slope: 0 rad; Roll: 0 rad; IsExternal: no; LoadBearing: yes
Pset_Condition - AssessmentCondition: Empty
Pset_EnvironmentalImpactIndicators - Reference: 340 x 720 mm; sets with these values: 2

# IfcBeam: BB_XX_Betonbalk_ rechthoekig_ center-center_SFB_340 x 720 mm61, BB_XX_Betonbalk, rechthoekig, center-center_SFB:340 x 720 mm:592213
In: 000
PredefinedType: BEAM; Material: BB_Beton_Bestaand
Cpset_Beam - LevelOfAccuracy: in te vullen door Buildwise
IfcRoot - Name: 340 x 720 mm
Qto_BeamBaseQuantities - Length: 2020; CrossSectionArea: 0.2448; OuterSurfaceArea: 4.2824; GrossSurfaceArea: 4.772; NetSurfaceArea: 4.772; GrossVolume: 0.494496; NetVolume: 0.494496
Pset_BeamCommon - Reference: 340 x 720 mm; Span: 2020 mm; Slope: 0 rad; Roll: 0 rad; IsExternal: no; LoadBearing: yes
Pset_Condition - AssessmentCondition: Empty
Pset_EnvironmentalImpactIndicators - Reference: 340 x 720 mm; sets with these values: 2

# IfcBeam: BB_XX_Betonbalk_ rechthoekig_ center-center_SFB_340 x 720 mm63, BB_XX_Betonbalk, rechthoekig, center-center_SFB:340 x 720 mm:592440
In: 000
PredefinedType: BEAM; Material: BB_Beton_Bestaand
Cpset_Beam - LevelOfAccuracy: in te vullen door Buildwise
IfcRoot - Name: 340 x 720 mm
Qto_BeamBaseQuantities - Length: 6980; CrossSectionArea: 0.2448; OuterSurfaceArea: 14.7976; GrossSurfaceArea: 15.2872; NetSurfaceArea: 15.2872; GrossVolume: 1.7087; NetVolume: 1.7087
Pset_BeamCommon - Reference: 340 x 720 mm; Span: 6980 mm; Slope: 0 rad; Roll: 0 rad; IsExternal: no; LoadBearing: yes
Pset_Condition - AssessmentCondition: Empty
Pset_EnvironmentalImpactIndicators - Reference: 340 x 720 mm; sets with these values: 2

# IfcBeam: BB_XX_Betonbalk_ rechthoekig_ center-center_SFB_340 x 720 mm65, BB_XX_Betonbalk, rechthoekig, center-center_SFB:340 x 720 mm:593581
In: 000
PredefinedType: BEAM; Material: BB_Beton_Bestaand
Cpset_Beam - LevelOfAccuracy: in te vullen door Buildwise
IfcRoot - Name: 340 x 720 mm
Qto_BeamBaseQuantities - Length: 7200; CrossSectionArea: 0.2448; OuterSurfaceArea: 15.264; GrossSurfaceArea: 15.7536; NetSurfaceArea: 15.7536; GrossVolume: 1.76256; NetVolume: 1.76256
Pset_BeamCommon - Reference: 340 x 720 mm; Span: 7200 mm; Slope: 0 rad; Roll: 0 rad; IsExternal: no; LoadBearing: yes
Pset_Condition - AssessmentCondition: Empty
Pset_EnvironmentalImpactIndicators - Reference: 340 x 720 mm; sets with these values: 2

# IfcBeam: BB_XX_Betonbalk_ rechthoekig_ center-center_SFB_340 x 720 mm67, BB_XX_Betonbalk, rechthoekig, center-center_SFB:340 x 720 mm:593790
In: 000
PredefinedType: BEAM; Material: BB_Beton_Bestaand
Cpset_Beam - LevelOfAccuracy: in te vullen door Buildwise
IfcRoot - Name: 340 x 720 mm
Qto_BeamBaseQuantities - Length: 1200; CrossSectionArea: 0.2448; OuterSurfaceArea: 2.544; GrossSurfaceArea: 3.0336; NetSurfaceArea: 3.0336; GrossVolume: 0.29376; NetVolume: 0.29376
Pset_BeamCommon - Reference: 340 x 720 mm; Span: 1200 mm; Slope: 0 rad; Roll: 0 rad; IsExternal: no; LoadBearing: yes
Pset_Condition - AssessmentCondition: Empty
Pset_EnvironmentalImpactIndicators - Reference: 340 x 720 mm; sets with these values: 2

# IfcBeam: BB_XX_Betonbalk_ rechthoekig_ center-center_SFB_340 x 720 mm69, BB_XX_Betonbalk, rechthoekig, center-center_SFB:340 x 720 mm:671844
In: 000
PredefinedType: BEAM; Material: BB_Beton_Bestaand
Cpset_Beam - LevelOfAccuracy: in te vullen door Buildwise
IfcRoot - Name: 340 x 720 mm
Qto_BeamBaseQuantities - Length: 1176.14; CrossSectionArea: 0.2448; OuterSurfaceArea: 2.49341; GrossSurfaceArea: 2.98301; NetSurfaceArea: 2.98301; GrossVolume: 0.287919; NetVolume: 0.287919
Pset_BeamCommon - Reference: 340 x 720 mm; Span: 1176.14 mm; Slope: 0.658806 rad; Roll: 0 rad; IsExternal: no; LoadBearing: yes
Pset_Condition - AssessmentCondition: Empty
Pset_EnvironmentalImpactIndicators - Reference: 340 x 720 mm; sets with these values: 2

# IfcBeam: BB_XX_Betonbalk_ rechthoekig_ center-center_SFB_340 x 720 mm7, BB_XX_Betonbalk, rechthoekig, center-center_SFB:340 x 720 mm:547532
In: 000
PredefinedType: BEAM; Material: BB_Beton_Bestaand
Cpset_Beam - LevelOfAccuracy: in te vullen door Buildwise
IfcRoot - Name: 340 x 720 mm
Qto_BeamBaseQuantities - Length: 4310; CrossSectionArea: 0.2448; OuterSurfaceArea: 9.1372; GrossSurfaceArea: 9.6268; NetSurfaceArea: 9.6268; GrossVolume: 1.05509; NetVolume: 1.05509
Pset_BeamCommon - Reference: 340 x 720 mm; Span: 4310 mm; Slope: 0 rad; Roll: 0 rad; IsExternal: no; LoadBearing: yes
Pset_Condition - AssessmentCondition: Empty
Pset_EnvironmentalImpactIndicators - Reference: 340 x 720 mm; sets with these values: 2

# IfcBeam: BB_XX_Betonbalk_ rechthoekig_ center-center_SFB_340 x 720 mm71, BB_XX_Betonbalk, rechthoekig, center-center_SFB:340 x 720 mm:672864
In: 000
PredefinedType: BEAM; Material: BB_Beton_Bestaand
Cpset_Beam - LevelOfAccuracy: in te vullen door Buildwise
IfcRoot - Name: 340 x 720 mm
Qto_BeamBaseQuantities - Length: 995; CrossSectionArea: 0.2448; OuterSurfaceArea: 1.908; GrossSurfaceArea: 2.3976; NetSurfaceArea: 2.3976; GrossVolume: 0.22032; NetVolume: 0.22032
Pset_BeamCommon - Reference: 340 x 720 mm; Span: 995 mm; Slope: 0 rad; Roll: 0 rad; IsExternal: no; LoadBearing: yes
Pset_Condition - AssessmentCondition: Empty
Pset_EnvironmentalImpactIndicators - Reference: 340 x 720 mm; sets with these values: 2

# IfcBeam: BB_XX_Betonbalk_ rechthoekig_ center-center_SFB_340 x 720 mm73 (7)
PredefinedType: BEAM; Material: BB_Beton_Bestaand
Cpset_Beam - LevelOfAccuracy: in te vullen door Buildwise
IfcRoot - Name: 340 x 720 mm
Qto_BeamBaseQuantities - Length: 6110; CrossSectionArea: 0.2448; OuterSurfaceArea: 12.9532; GrossSurfaceArea: 13.4428; NetSurfaceArea: 13.4428; GrossVolume: 1.49573; NetVolume: 1.49573
Pset_BeamCommon - Reference: 340 x 720 mm; Span: 6110 mm; Slope: 0 rad; Roll: 0 rad; IsExternal: no; LoadBearing: yes
Pset_Condition - AssessmentCondition: Empty
Pset_EnvironmentalImpactIndicators - Reference: 340 x 720 mm; sets with these values: 2
Name (BB_XX_Betonbalk, rechthoekig, center-center_SFB:340 x 720 mm:...) | In
1924085 | 000
614688 | 010
614863 | 010
614945 | 010
695397 | 020
695399 | 020
695401 | 020

# IfcBeam: BB_XX_Betonbalk_ rechthoekig_ center-center_SFB_340 x 720 mm75, BB_XX_Betonbalk, rechthoekig, center-center_SFB:340 x 720 mm:1924087
In: 000
PredefinedType: BEAM; Material: BB_Beton_Bestaand
Cpset_Beam - LevelOfAccuracy: in te vullen door Buildwise
IfcRoot - Name: 340 x 720 mm
Qto_BeamBaseQuantities - Length: 1090; CrossSectionArea: 1.4439; NetSurfaceArea: 2.8878; NetVolume: 0.1998
Pset_BeamCommon - Reference: 340 x 720 mm; Span: 1090 mm; Slope: 0 rad; Roll: 0 rad; IsExternal: no; LoadBearing: yes
Pset_Condition - AssessmentCondition: Empty
Pset_EnvironmentalImpactIndicators - Reference: 340 x 720 mm; sets with these values: 2

# IfcBeam: BB_XX_Betonbalk_ rechthoekig_ center-center_SFB_340 x 720 mm77, BB_XX_Betonbalk, rechthoekig, center-center_SFB:340 x 720 mm:1924100
In: 000
PredefinedType: BEAM; Material: BB_Beton_Bestaand
Cpset_Beam - LevelOfAccuracy: in te vullen door Buildwise
IfcRoot - Name: 340 x 720 mm
Qto_BeamBaseQuantities - Length: 715; CrossSectionArea: 0.847551; NetSurfaceArea: 1.6951; NetVolume: 0.108788
Pset_BeamCommon - Reference: 340 x 720 mm; Span: 715 mm; Slope: 0 rad; Roll: 0 rad; IsExternal: no; LoadBearing: yes
Pset_Condition - AssessmentCondition: Empty
Pset_EnvironmentalImpactIndicators - Reference: 340 x 720 mm; sets with these values: 2

# IfcBeam: BB_XX_Betonbalk_ rechthoekig_ center-center_SFB_340 x 720 mm79, BB_XX_Betonbalk, rechthoekig, center-center_SFB:340 x 720 mm:1930867
In: 000
PredefinedType: BEAM; Material: BB_Beton_Bestaand
Cpset_Beam - LevelOfAccuracy: in te vullen door Buildwise
IfcRoot - Name: 340 x 720 mm
Qto_BeamBaseQuantities - Length: 1090; CrossSectionArea: 1.4439; NetSurfaceArea: 2.8878; NetVolume: 0.1998
Pset_BeamCommon - Reference: 340 x 720 mm; Span: 1090 mm; Slope: 0 rad; Roll: 0 rad; IsExternal: no; LoadBearing: yes
Pset_Condition - AssessmentCondition: Empty
Pset_EnvironmentalImpactIndicators - Reference: 340 x 720 mm; sets with these values: 2

# IfcBeam: BB_XX_Betonbalk_ rechthoekig_ center-center_SFB_340 x 720 mm81, BB_XX_Betonbalk, rechthoekig, center-center_SFB:340 x 720 mm:1930869
In: 000
PredefinedType: BEAM; Material: BB_Beton_Bestaand
Cpset_Beam - LevelOfAccuracy: in te vullen door Buildwise
IfcRoot - Name: 340 x 720 mm
Qto_BeamBaseQuantities - Length: 1090; CrossSectionArea: 1.4439; NetSurfaceArea: 2.8878; NetVolume: 0.1998
Pset_BeamCommon - Reference: 340 x 720 mm; Span: 1090 mm; Slope: 0 rad; Roll: 0 rad; IsExternal: no; LoadBearing: yes
Pset_Condition - AssessmentCondition: Empty
Pset_EnvironmentalImpactIndicators - Reference: 340 x 720 mm; sets with these values: 2

# IfcBeam: BB_XX_Betonbalk_ rechthoekig_ center-center_SFB_340 x 720 mm83, BB_XX_Betonbalk, rechthoekig, center-center_SFB:340 x 720 mm:1931089
In: 000
PredefinedType: BEAM; Material: BB_Beton_Bestaand
Cpset_Beam - LevelOfAccuracy: in te vullen door Buildwise
IfcRoot - Name: 340 x 720 mm
Qto_BeamBaseQuantities - Length: 1090; CrossSectionArea: 1.4439; NetSurfaceArea: 2.8878; NetVolume: 0.1998
Pset_BeamCommon - Reference: 340 x 720 mm; Span: 1090 mm; Slope: 0 rad; Roll: 0 rad; IsExternal: no; LoadBearing: yes
Pset_Condition - AssessmentCondition: Empty
Pset_EnvironmentalImpactIndicators - Reference: 340 x 720 mm; sets with these values: 2

# IfcBeam: BB_XX_Betonbalk_ rechthoekig_ center-center_SFB_340 x 720 mm85, BB_XX_Betonbalk, rechthoekig, center-center_SFB:340 x 720 mm:1931091
In: 000
PredefinedType: BEAM; Material: BB_Beton_Bestaand
Cpset_Beam - LevelOfAccuracy: in te vullen door Buildwise
IfcRoot - Name: 340 x 720 mm
Qto_BeamBaseQuantities - Length: 1090; CrossSectionArea: 1.4439; NetSurfaceArea: 2.8878; NetVolume: 0.1998
Pset_BeamCommon - Reference: 340 x 720 mm; Span: 1090 mm; Slope: 0 rad; Roll: 0 rad; IsExternal: no; LoadBearing: yes
Pset_Condition - AssessmentCondition: Empty
Pset_EnvironmentalImpactIndicators - Reference: 340 x 720 mm; sets with these values: 2

# IfcBeam: BB_XX_Betonbalk_ rechthoekig_ center-center_SFB_340 x 720 mm87, BB_XX_Betonbalk, rechthoekig, center-center_SFB:340 x 720 mm:616232
In: 010
PredefinedType: BEAM; Material: BB_Beton_Bestaand
Cpset_Beam - LevelOfAccuracy: in te vullen door Buildwise
IfcRoot - Name: 340 x 720 mm
Qto_BeamBaseQuantities - Length: 1090; CrossSectionArea: 1.4439; NetSurfaceArea: 2.8878; NetVolume: 0.1998
Pset_BeamCommon - Reference: 340 x 720 mm; Span: 1090 mm; Slope: 0 rad; Roll: 0 rad; IsExternal: no; LoadBearing: yes
Pset_Condition - AssessmentCondition: Empty
Pset_EnvironmentalImpactIndicators - Reference: 340 x 720 mm; sets with these values: 2

# IfcBeam: BB_XX_Betonbalk_ rechthoekig_ center-center_SFB_340 x 720 mm89, BB_XX_Betonbalk, rechthoekig, center-center_SFB:340 x 720 mm:616587
In: 010
PredefinedType: BEAM; Material: BB_Beton_Bestaand
Cpset_Beam - LevelOfAccuracy: in te vullen door Buildwise
IfcRoot - Name: 340 x 720 mm
Qto_BeamBaseQuantities - Length: 1090; CrossSectionArea: 1.4439; NetSurfaceArea: 2.8878; NetVolume: 0.1998
Pset_BeamCommon - Reference: 340 x 720 mm; Span: 1090 mm; Slope: 0 rad; Roll: 0 rad; IsExternal: no; LoadBearing: yes
Pset_Condition - AssessmentCondition: Empty
Pset_EnvironmentalImpactIndicators - Reference: 340 x 720 mm; sets with these values: 2

# IfcBeam: BB_XX_Betonbalk_ rechthoekig_ center-center_SFB_340 x 720 mm9 (3)
In: 000
PredefinedType: BEAM; Material: BB_Beton_Bestaand
Cpset_Beam - LevelOfAccuracy: in te vullen door Buildwise
IfcRoot - Name: 340 x 720 mm
Qto_BeamBaseQuantities - Length: 6110; CrossSectionArea: 0.2448; OuterSurfaceArea: 12.9532; GrossSurfaceArea: 13.4428; NetSurfaceArea: 13.4428; GrossVolume: 1.49573; NetVolume: 1.49573
Pset_BeamCommon - Reference: 340 x 720 mm; Span: 6110 mm; Slope: 0 rad; Roll: 0 rad; IsExternal: no; LoadBearing: yes
Pset_Condition - AssessmentCondition: Empty
Pset_EnvironmentalImpactIndicators - Reference: 340 x 720 mm; sets with these values: 2
Name (BB_XX_Betonbalk, rechthoekig, center-center_SFB:340 x 720 mm:...)
547865
553434
553494

# IfcBeam: BB_XX_Betonbalk_ rechthoekig_ center-center_SFB_340 x 720 mm91, BB_XX_Betonbalk, rechthoekig, center-center_SFB:340 x 720 mm:616930
In: 010
PredefinedType: BEAM; Material: BB_Beton_Bestaand
Cpset_Beam - LevelOfAccuracy: in te vullen door Buildwise
IfcRoot - Name: 340 x 720 mm
Qto_BeamBaseQuantities - Length: 640; CrossSectionArea: 0.8586; NetSurfaceArea: 1.7172; NetVolume: 0.11016
Pset_BeamCommon - Reference: 340 x 720 mm; Span: 640 mm; Slope: 0 rad; Roll: 0 rad; IsExternal: no; LoadBearing: yes
Pset_Condition - AssessmentCondition: Empty
Pset_EnvironmentalImpactIndicators - Reference: 340 x 720 mm; sets with these values: 2

# IfcBeam: BB_XX_Betonbalk_ rechthoekig_ center-center_SFB_340 x 720 mm93 (2)
PredefinedType: BEAM; Material: BB_Beton_Bestaand
Cpset_Beam - LevelOfAccuracy: in te vullen door Buildwise
IfcRoot - Name: 340 x 720 mm
Qto_BeamBaseQuantities - Length: 7010; CrossSectionArea: 0.2448; OuterSurfaceArea: 14.8612; GrossSurfaceArea: 15.3508; NetSurfaceArea: 15.3508; GrossVolume: 1.71605; NetVolume: 1.71605
Pset_BeamCommon - Reference: 340 x 720 mm; Span: 7010 mm; Slope: 0 rad; Roll: 0 rad; IsExternal: no; LoadBearing: yes
Pset_Condition - AssessmentCondition: Empty
Pset_EnvironmentalImpactIndicators - Reference: 340 x 720 mm; sets with these values: 2
Name (BB_XX_Betonbalk, rechthoekig, center-center_SFB:340 x 720 mm:...) | In
617131 | 010
695442 | 020

# IfcBeam: BB_XX_Betonbalk_ rechthoekig_ center-center_SFB_340 x 720 mm95 (2)
PredefinedType: BEAM; Material: BB_Beton_Bestaand
Cpset_Beam - LevelOfAccuracy: in te vullen door Buildwise
IfcRoot - Name: 340 x 720 mm
Qto_BeamBaseQuantities - Length: 4740; CrossSectionArea: 0.2448; OuterSurfaceArea: 10.0488; GrossSurfaceArea: 10.5384; NetSurfaceArea: 10.5384; GrossVolume: 1.16035; NetVolume: 1.16035
Pset_BeamCommon - Reference: 340 x 720 mm; Span: 4740 mm; Slope: 0 rad; Roll: 0 rad; IsExternal: no; LoadBearing: yes
Pset_Condition - AssessmentCondition: Empty
Pset_EnvironmentalImpactIndicators - Reference: 340 x 720 mm; sets with these values: 2
Name (BB_XX_Betonbalk, rechthoekig, center-center_SFB:340 x 720 mm:...) | In
617646 | 010
695444 | 020

# IfcBeam: BB_XX_Betonbalk_ rechthoekig_ center-center_SFB_340 x 720 mm97, BB_XX_Betonbalk, rechthoekig, center-center_SFB:340 x 720 mm:617826
In: 010
PredefinedType: BEAM; Material: BB_Beton_Bestaand
Cpset_Beam - LevelOfAccuracy: in te vullen door Buildwise
IfcRoot - Name: 340 x 720 mm
Qto_BeamBaseQuantities - Length: 640; CrossSectionArea: 0.8586; NetSurfaceArea: 1.7172; NetVolume: 0.11016
Pset_BeamCommon - Reference: 340 x 720 mm; Span: 640 mm; Slope: 0 rad; Roll: 0 rad; IsExternal: no; LoadBearing: yes
Pset_Condition - AssessmentCondition: Empty
Pset_EnvironmentalImpactIndicators - Reference: 340 x 720 mm; sets with these values: 2

# IfcBeam: BB_XX_Betonbalk_ rechthoekig_ center-center_SFB_340 x 720 mm99 (2)
PredefinedType: BEAM; Material: BB_Beton_Bestaand
Cpset_Beam - LevelOfAccuracy: in te vullen door Buildwise
IfcRoot - Name: 340 x 720 mm
Qto_BeamBaseQuantities - Length: 5210; CrossSectionArea: 0.2448; OuterSurfaceArea: 11.0452; GrossSurfaceArea: 11.5348; NetSurfaceArea: 11.5348; GrossVolume: 1.27541; NetVolume: 1.27541
Pset_BeamCommon - Reference: 340 x 720 mm; Span: 5210 mm; Slope: 0 rad; Roll: 0 rad; IsExternal: no; LoadBearing: yes
Pset_Condition - AssessmentCondition: Empty
Pset_EnvironmentalImpactIndicators - Reference: 340 x 720 mm; sets with these values: 2
Name (BB_XX_Betonbalk, rechthoekig, center-center_SFB:340 x 720 mm:...) | In
620624 | 010
695461 | 020

# IfcBeam: BB_XX_Betonbalk_ rechthoekig_ center-center_SFB_400 x 260 mm, BB_XX_Betonbalk, rechthoekig, center-center_SFB:400 x 260 mm:969228
In: K20
PredefinedType: BEAM; Material: BB_Beton_Bestaand
Cpset_Beam - LevelOfAccuracy: in te vullen door Buildwise
IfcRoot - Name: 400 x 260 mm
Qto_BeamBaseQuantities - Length: 5100; CrossSectionArea: 0.104; OuterSurfaceArea: 6.732; GrossSurfaceArea: 6.94; NetSurfaceArea: 6.94; GrossVolume: 0.5304; NetVolume: 0.5304
Pset_BeamCommon - Reference: 400 x 260 mm; Span: 5100 mm; Slope: 0 rad; Roll: 0 rad; IsExternal: no; LoadBearing: yes
Pset_Condition - AssessmentCondition: Empty
Pset_EnvironmentalImpactIndicators - Reference: 400 x 260 mm; sets with these values: 2

# IfcBeam: BB_XX_Betonbalk_ rechthoekig_ center-center_SFB_400 x 300 mm (3)
PredefinedType: BEAM; Material: BB_Beton_Bestaand
Cpset_Beam - LevelOfAccuracy: in te vullen door Buildwise
IfcRoot - Name: 400 x 300 mm
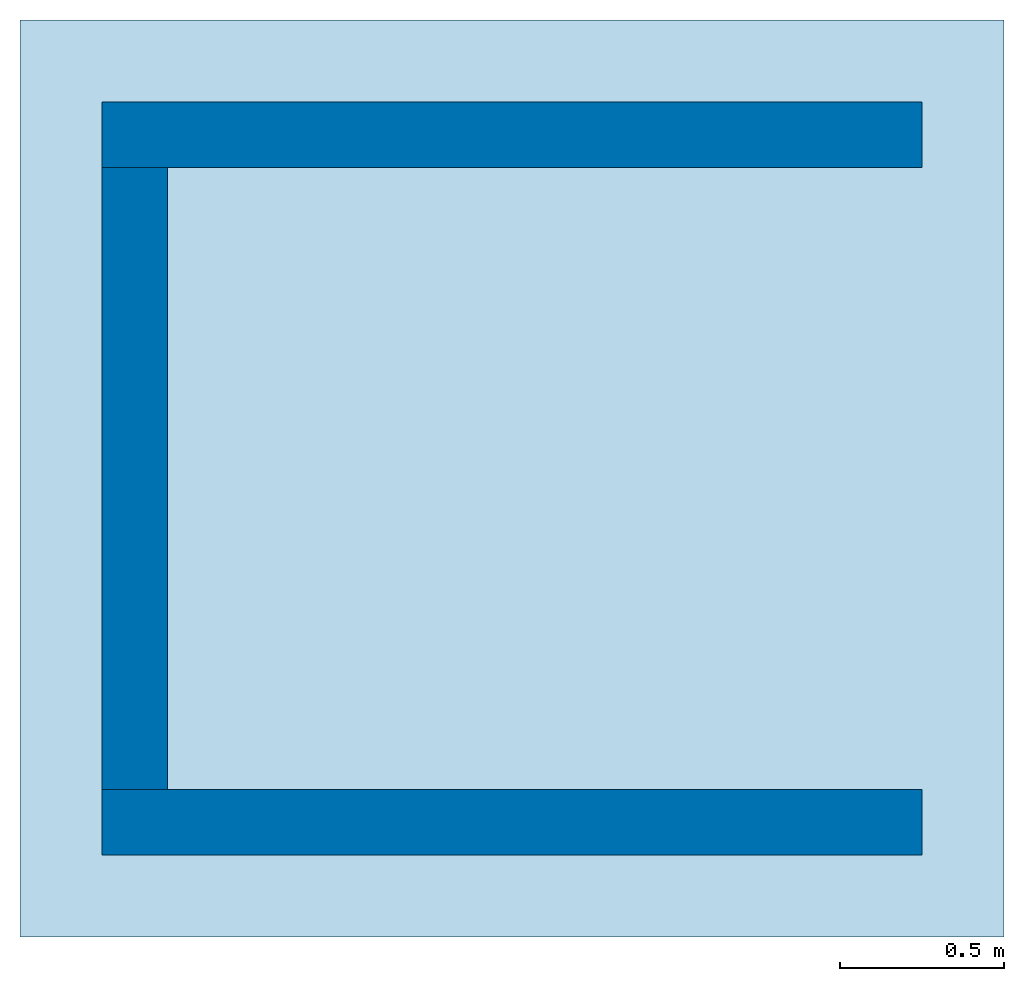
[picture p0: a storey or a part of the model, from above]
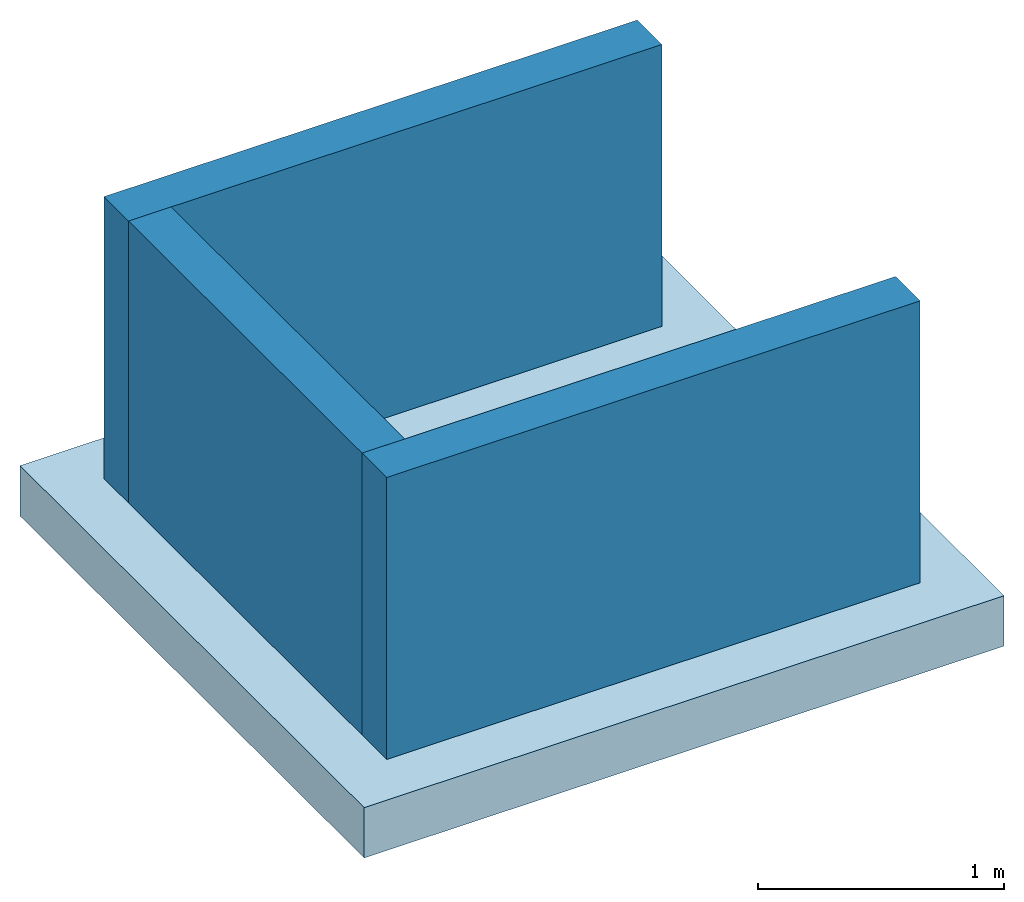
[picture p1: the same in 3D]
Properties of the parts of a building model (IFC4X3_ADD2), part 11 of 28

# IfcBeam: BB_XX_Betonbalk_ rechthoekig_ center-center_SFB_400 x 300 mm (3)
Qto_BeamBaseQuantities - Length: 6755; CrossSectionArea: 0.12; OuterSurfaceArea: 9.457; GrossSurfaceArea: 9.697; NetSurfaceArea: 9.697; GrossVolume: 0.8106; NetVolume: 0.8106
Pset_BeamCommon - Reference: 400 x 300 mm; Span: 6755 mm; Slope: 0 rad; Roll: 0 rad; IsExternal: no; LoadBearing: yes
Pset_Condition - AssessmentCondition: Empty
Pset_EnvironmentalImpactIndicators - Reference: 400 x 300 mm; sets with these values: 2
Name (BB_XX_Betonbalk, rechthoekig, center-center_SFB:400 x 300 mm:...) | In
710249 | 000
710148 | 010
709958 | 020

# IfcBeam: BB_XX_Betonbalk_ rechthoekig_ center-center_SFB_400 x 300 mm1, BB_XX_Betonbalk, rechthoekig, center-center_SFB:400 x 300 mm:696813
In: 020
PredefinedType: BEAM; Material: BB_Beton_Bestaand
Cpset_Beam - LevelOfAccuracy: in te vullen door Buildwise
IfcRoot - Name: 400 x 300 mm
Qto_BeamBaseQuantities - Length: 6710; CrossSectionArea: 0.12; OuterSurfaceArea: 9.394; GrossSurfaceArea: 9.634; NetSurfaceArea: 9.634; GrossVolume: 0.8052; NetVolume: 0.8052
Pset_BeamCommon - Reference: 400 x 300 mm; Span: 6710 mm; Slope: 0 rad; Roll: 0 rad; IsExternal: no; LoadBearing: yes
Pset_Condition - AssessmentCondition: Empty
Pset_EnvironmentalImpactIndicators - Reference: 400 x 300 mm; sets with these values: 2

# IfcBeam: BB_XX_Betonbalk_ rechthoekig_ center-center_SFB_400 x 360 mm, BB_XX_Betonbalk, rechthoekig, center-center_SFB:400 x 360 mm:989023
In: K10
PredefinedType: BEAM; Material: BB_Beton_Bestaand
Cpset_Beam - LevelOfAccuracy: in te vullen door Buildwise
IfcRoot - Name: 400 x 360 mm
Qto_BeamBaseQuantities - Length: 5200; CrossSectionArea: 0.144; OuterSurfaceArea: 7.904; GrossSurfaceArea: 8.192; NetSurfaceArea: 8.192; GrossVolume: 0.7488; NetVolume: 0.7488
Pset_BeamCommon - Reference: 400 x 360 mm; Span: 5200 mm; Slope: 0 rad; Roll: 0 rad; IsExternal: no; LoadBearing: yes
Pset_Condition - AssessmentCondition: Empty
Pset_EnvironmentalImpactIndicators - Reference: 400 x 360 mm; sets with these values: 2

# IfcBeam: BB_XX_Betonbalk_ rechthoekig_ center-center_SFB_400 x 400 mm, BB_XX_Betonbalk, rechthoekig, center-center_SFB:400 x 400 mm:684817
In: 000
PredefinedType: BEAM; Material: BB_Beton_Bestaand
Cpset_Beam - LevelOfAccuracy: in te vullen door Buildwise
IfcRoot - Name: 400 x 400 mm
Qto_BeamBaseQuantities - Length: 7345; CrossSectionArea: 0.16; OuterSurfaceArea: 11.752; GrossSurfaceArea: 12.072; NetSurfaceArea: 12.072; GrossVolume: 1.1752; NetVolume: 1.1752
Pset_BeamCommon - Reference: 400 x 400 mm; Span: 7345 mm; Slope: 0 rad; Roll: 0 rad; IsExternal: no; LoadBearing: yes
Pset_Condition - AssessmentCondition: Empty
Pset_EnvironmentalImpactIndicators - Reference: 400 x 400 mm; sets with these values: 2

# IfcBeam: BB_XX_Betonbalk_ rechthoekig_ center-center_SFB_400 x 400 mm1, BB_XX_Betonbalk, rechthoekig, center-center_SFB:400 x 400 mm:709354
In: 010
PredefinedType: BEAM; Material: BB_Beton_Bestaand
Cpset_Beam - LevelOfAccuracy: in te vullen door Buildwise
IfcRoot - Name: 400 x 400 mm
Qto_BeamBaseQuantities - Length: 7345; CrossSectionArea: 0.16; OuterSurfaceArea: 11.752; GrossSurfaceArea: 12.072; NetSurfaceArea: 12.072; GrossVolume: 1.1752; NetVolume: 1.1752
Pset_BeamCommon - Reference: 400 x 400 mm; Span: 7345 mm; Slope: 0 rad; Roll: 0 rad; IsExternal: no; LoadBearing: yes
Pset_Condition - AssessmentCondition: Empty
Pset_EnvironmentalImpactIndicators - Reference: 400 x 400 mm; sets with these values: 2

# IfcBeam: BB_XX_Betonbalk_ rechthoekig_ center-center_SFB_400 x 400 mm3, BB_XX_Betonbalk, rechthoekig, center-center_SFB:400 x 400 mm:698142
In: 020
PredefinedType: BEAM; Material: BB_Beton_Bestaand
Cpset_Beam - LevelOfAccuracy: in te vullen door Buildwise
IfcRoot - Name: 400 x 400 mm
Qto_BeamBaseQuantities - Length: 7345; CrossSectionArea: 0.16; OuterSurfaceArea: 11.752; GrossSurfaceArea: 12.072; NetSurfaceArea: 12.072; GrossVolume: 1.1752; NetVolume: 1.1752
Pset_BeamCommon - Reference: 400 x 400 mm; Span: 7345 mm; Slope: 0 rad; Roll: 0 rad; IsExternal: no; LoadBearing: yes
Pset_Condition - AssessmentCondition: Empty
Pset_EnvironmentalImpactIndicators - Reference: 400 x 400 mm; sets with these values: 2

# IfcBeam: BB_XX_Betonbalk_ rechthoekig_ center-center_SFB_400 x 400 mm5, BB_XX_Betonbalk, rechthoekig, center-center_SFB:400 x 400 mm:743381
In: 030
PredefinedType: BEAM; Material: BB_Beton_Bestaand
Cpset_Beam - LevelOfAccuracy: in te vullen door Buildwise
IfcRoot - Name: 400 x 400 mm
Qto_BeamBaseQuantities - Length: 7670; CrossSectionArea: 0.16; OuterSurfaceArea: 12.272; GrossSurfaceArea: 12.592; NetSurfaceArea: 12.592; GrossVolume: 1.2272; NetVolume: 1.2272
Pset_BeamCommon - Reference: 400 x 400 mm; Span: 7670 mm; Slope: 0 rad; Roll: 0 rad; IsExternal: no; LoadBearing: yes
Pset_Condition - AssessmentCondition: Empty
Pset_EnvironmentalImpactIndicators - Reference: 400 x 400 mm; sets with these values: 2

# IfcBeam: BB_XX_Betonbalk_ rechthoekig_ center-center_SFB_400 x 400 mm7, BB_XX_Betonbalk, rechthoekig, center-center_SFB:400 x 400 mm:744216
In: 030
PredefinedType: BEAM; Material: BB_Beton_Bestaand
Cpset_Beam - LevelOfAccuracy: in te vullen door Buildwise
IfcRoot - Name: 400 x 400 mm
Qto_BeamBaseQuantities - Length: 7613.15; CrossSectionArea: 0.16; OuterSurfaceArea: 12.181; GrossSurfaceArea: 12.501; NetSurfaceArea: 12.501; GrossVolume: 1.2181; NetVolume: 1.2181
Pset_BeamCommon - Reference: 400 x 400 mm; Span: 7613.15 mm; Slope: 0 rad; Roll: 0 rad; IsExternal: no; LoadBearing: yes
Pset_Condition - AssessmentCondition: Empty
Pset_EnvironmentalImpactIndicators - Reference: 400 x 400 mm; sets with these values: 2

# IfcBeam: BB_XX_Betonbalk_ rechthoekig_ center-center_SFB_400 x 400 mm9, BB_XX_Betonbalk, rechthoekig, center-center_SFB:400 x 400 mm:746985
In: 030
PredefinedType: BEAM; Material: BB_Beton_Bestaand
Cpset_Beam - LevelOfAccuracy: in te vullen door Buildwise
IfcRoot - Name: 400 x 400 mm
Qto_BeamBaseQuantities - Length: 5982.8; CrossSectionArea: 0.16; OuterSurfaceArea: 9.91674; GrossSurfaceArea: 10.2367; NetSurfaceArea: 10.2367; GrossVolume: 0.991674; NetVolume: 0.991674
Pset_BeamCommon - Reference: 400 x 400 mm; Span: 5982.8 mm; Slope: 0 rad; Roll: 0 rad; IsExternal: no; LoadBearing: yes
Pset_Condition - AssessmentCondition: Empty
Pset_EnvironmentalImpactIndicators - Reference: 400 x 400 mm; sets with these values: 2

# IfcBeam: BB_XX_Betonbalk_ rechthoekig_ center-center_SFB_400 x 500 mm, BB_XX_Betonbalk, rechthoekig, center-center_SFB:400 x 500 mm:985562
In: K20
PredefinedType: BEAM; Material: BB_Beton_Bestaand
Cpset_Beam - LevelOfAccuracy: in te vullen door Buildwise
IfcRoot - Name: 400 x 500 mm
Qto_BeamBaseQuantities - Length: 2400; CrossSectionArea: 0.2; OuterSurfaceArea: 4.32; GrossSurfaceArea: 4.72; NetSurfaceArea: 4.72; GrossVolume: 0.48; NetVolume: 0.48
Pset_BeamCommon - Reference: 400 x 500 mm; Span: 2400 mm; Slope: 0 rad; Roll: 0 rad; IsExternal: no; LoadBearing: yes
Pset_Condition - AssessmentCondition: Empty
Pset_EnvironmentalImpactIndicators - Reference: 400 x 500 mm; sets with these values: 2

# IfcBeam: BB_XX_Betonbalk_ rechthoekig_ center-center_SFB_400 x 500 mm1, BB_XX_Betonbalk, rechthoekig, center-center_SFB:400 x 500 mm:991371
In: K20
PredefinedType: BEAM; Material: BB_Beton_Bestaand
Cpset_Beam - LevelOfAccuracy: in te vullen door Buildwise
IfcRoot - Name: 400 x 500 mm
Qto_BeamBaseQuantities - Length: 13700; CrossSectionArea: 12.05; NetSurfaceArea: 24.1; NetVolume: 2.5
Pset_BeamCommon - Reference: 400 x 500 mm; Span: 13700 mm; Slope: 0 rad; Roll: 0 rad; IsExternal: no; LoadBearing: yes
Pset_Condition - AssessmentCondition: Empty
Pset_EnvironmentalImpactIndicators - Reference: 400 x 500 mm; sets with these values: 2

# IfcBeam: BB_XX_Betonbalk_ rechthoekig_ center-center_SFB_400 x 500 mm3, BB_XX_Betonbalk, rechthoekig, center-center_SFB:400 x 500 mm:999069
In: K20
PredefinedType: BEAM; Material: BB_Beton_Bestaand
Cpset_Beam - LevelOfAccuracy: in te vullen door Buildwise
IfcRoot - Name: 400 x 500 mm
Qto_BeamBaseQuantities - Length: 7500; CrossSectionArea: 6.92; NetSurfaceArea: 13.84; NetVolume: 1.485
Pset_BeamCommon - Reference: 400 x 500 mm; Span: 7500 mm; Slope: 0 rad; Roll: 0 rad; IsExternal: no; LoadBearing: yes
Pset_Condition - AssessmentCondition: Empty
Pset_EnvironmentalImpactIndicators - Reference: 400 x 500 mm; sets with these values: 2

# IfcBeam: BB_XX_Betonbalk_ rechthoekig_ center-center_SFB_400 x 700 mm, BB_XX_Betonbalk, rechthoekig, center-center_SFB:400 x 700 mm:809688
In: K10
PredefinedType: BEAM; Material: BB_Beton_Bestaand
Cpset_Beam - LevelOfAccuracy: in te vullen door Buildwise
IfcRoot - Name: 400 x 700 mm
Qto_BeamBaseQuantities - Length: 7305; CrossSectionArea: 4.9135; OuterSurfaceArea: 6.404; GrossSurfaceArea: 16.231; NetSurfaceArea: 16.231; GrossVolume: 1.9654; NetVolume: 1.9654
Pset_BeamCommon - Reference: 400 x 700 mm; Span: 7305 mm; Slope: 0 rad; Roll: 0 rad; IsExternal: no; LoadBearing: yes
Pset_Condition - AssessmentCondition: Empty
Pset_EnvironmentalImpactIndicators - Reference: 400 x 700 mm; sets with these values: 2

# IfcBeam: BB_XX_Betonbalk_ rechthoekig_ center-center_SFB_400 x 700 mm1, BB_XX_Betonbalk, rechthoekig, center-center_SFB:400 x 700 mm:811780
In: K10
PredefinedType: BEAM; Material: BB_Beton_Bestaand
Cpset_Beam - LevelOfAccuracy: in te vullen door Buildwise
IfcRoot - Name: 400 x 700 mm
Qto_BeamBaseQuantities - Length: 7305; CrossSectionArea: 0.28; OuterSurfaceArea: 16.071; GrossSurfaceArea: 16.631; NetSurfaceArea: 16.631; GrossVolume: 2.0454; NetVolume: 2.0454
Pset_BeamCommon - Reference: 400 x 700 mm; Span: 7305 mm; Slope: 0 rad; Roll: 0 rad; IsExternal: no; LoadBearing: yes
Pset_Condition - AssessmentCondition: Empty
Pset_EnvironmentalImpactIndicators - Reference: 400 x 700 mm; sets with these values: 2

# IfcBeam: BB_XX_Betonbalk_ rechthoekig_ center-center_SFB_400 x 700 mm3, BB_XX_Betonbalk, rechthoekig, center-center_SFB:400 x 700 mm:812055
In: K10
PredefinedType: BEAM; Material: BB_Beton_Bestaand
Cpset_Beam - LevelOfAccuracy: in te vullen door Buildwise
IfcRoot - Name: 400 x 700 mm
Qto_BeamBaseQuantities - Length: 1900; CrossSectionArea: 1.85809; NetSurfaceArea: 3.71618; NetVolume: 0.386935
Pset_BeamCommon - Reference: 400 x 700 mm; Span: 1900 mm; Slope: 0 rad; Roll: 0 rad; IsExternal: no; LoadBearing: yes
Pset_Condition - AssessmentCondition: Empty
Pset_EnvironmentalImpactIndicators - Reference: 400 x 700 mm; sets with these values: 2

# IfcBeam: BB_XX_Betonbalk_ rechthoekig_ center-center_SFB_400 x 830 mm, BB_XX_Betonbalk, rechthoekig, center-center_SFB:400 x 830 mm:981903
In: K20
PredefinedType: BEAM; Material: BB_Beton_Bestaand
Cpset_Beam - LevelOfAccuracy: in te vullen door Buildwise
IfcRoot - Name: 400 x 830 mm
Qto_BeamBaseQuantities - Length: 2947.88; CrossSectionArea: 4.28295; NetSurfaceArea: 8.5659; NetVolume: 0.763046
Pset_BeamCommon - Reference: 400 x 830 mm; Span: 2947.88 mm; Slope: 0 rad; Roll: 0 rad; IsExternal: no; LoadBearing: yes
Pset_Condition - AssessmentCondition: Empty
Pset_EnvironmentalImpactIndicators - Reference: 400 x 830 mm; sets with these values: 2

# IfcBeam: BB_XX_Betonbalk_ rechthoekig_ center-center_SFB_440 x 490 mm, BB_XX_Betonbalk, rechthoekig, center-center_SFB:440 x 490 mm:993413
In: K20
PredefinedType: BEAM; Material: BB_Beton_Bestaand
Cpset_Beam - LevelOfAccuracy: in te vullen door Buildwise
IfcRoot - Name: 440 x 490 mm
Qto_BeamBaseQuantities - Length: 1400; CrossSectionArea: 1.46869; NetSurfaceArea: 2.93737; NetVolume: 0.281981
Pset_BeamCommon - Reference: 440 x 490 mm; Span: 1400 mm; Slope: 0 rad; Roll: 0 rad; IsExternal: no; LoadBearing: yes
Pset_Condition - AssessmentCondition: Empty
Pset_EnvironmentalImpactIndicators - Reference: 440 x 490 mm; sets with these values: 2

# IfcBeam: BB_XX_Betonbalk_ rechthoekig_ center-center_SFB_450 x 520 mm, BB_XX_Betonbalk, rechthoekig, center-center_SFB:450 x 520 mm:707139
In: 010
PredefinedType: BEAM; Material: BB_Beton_Bestaand
Cpset_Beam - LevelOfAccuracy: in te vullen door Buildwise
IfcRoot - Name: 450 x 520 mm
Qto_BeamBaseQuantities - Length: 5552.8; CrossSectionArea: 0.234; OuterSurfaceArea: 12.2373; GrossSurfaceArea: 12.7053; NetSurfaceArea: 12.7053; GrossVolume: 1.47604; NetVolume: 1.47604
Pset_BeamCommon - Reference: 450 x 520 mm; Span: 5552.8 mm; Slope: 0 rad; Roll: 0 rad; IsExternal: no; LoadBearing: yes
Pset_Condition - AssessmentCondition: Empty
Pset_EnvironmentalImpactIndicators - Reference: 450 x 520 mm; sets with these values: 2

# IfcBeam: BB_XX_Betonbalk_ rechthoekig_ center-center_SFB_450 x 520 mm1, BB_XX_Betonbalk, rechthoekig, center-center_SFB:450 x 520 mm:701556
In: 020
PredefinedType: BEAM; Material: BB_Beton_Bestaand
Cpset_Beam - LevelOfAccuracy: in te vullen door Buildwise
IfcRoot - Name: 450 x 520 mm
Qto_BeamBaseQuantities - Length: 5552.8; CrossSectionArea: 0.234; OuterSurfaceArea: 12.2373; GrossSurfaceArea: 12.7053; NetSurfaceArea: 12.7053; GrossVolume: 1.47604; NetVolume: 1.47604
Pset_BeamCommon - Reference: 450 x 520 mm; Span: 5552.8 mm; Slope: 0 rad; Roll: 0 rad; IsExternal: no; LoadBearing: yes
Pset_Condition - AssessmentCondition: Empty
Pset_EnvironmentalImpactIndicators - Reference: 450 x 520 mm; sets with these values: 2

# IfcBeam: BB_XX_Betonbalk_ rechthoekig_ center-center_SFB_500 x 280 mm (16)
In: 040
PredefinedType: BEAM; Material: BB_Beton_Bestaand
Cpset_Beam - LevelOfAccuracy: in te vullen door Buildwise
IfcClassificationReference - TDS_link: .\05 As Builtdossier\2. Bouwkunde\2.1 Architectuur\2.1.3 open ruwbouw\TF S 4.3.1.2.5 A - Balken en lateien in gewapend beton.pdf
IfcRoot - Name: 500 x 280 mm
Qto_BeamBaseQuantities - Length: 500; CrossSectionArea: 0.14; OuterSurfaceArea: 0.78; GrossSurfaceArea: 1.06; NetSurfaceArea: 1.06; GrossVolume: 0.07; NetVolume: 0.07
Pset_BeamCommon - Reference: 500 x 280 mm; Span: 500 mm; Slope: 0 rad; Roll: 0 rad; IsExternal: no; LoadBearing: yes
Pset_ConcreteElementGeneral - ConstructionMethod: prefabricated
Pset_Condition - AssessmentCondition: Empty
Pset_EnvironmentalImpactIndicators - Reference: 500 x 280 mm; sets with these values: 2
Name (BB_XX_Betonbalk, rechthoekig, center-center_SFB:500 x 280 mm:...)
34112579
34113080
34113134
34113187
34113251
34113298
34113311
34113326
34113339
34113354
34113367
34113382
34113395
34113484
34113495
34113508

# IfcBeam: BB_XX_Betonbalk_ rechthoekig_ center-center_SFB_500 x 400 mm (2)
PredefinedType: BEAM; Material: BB_Beton_Bestaand
Cpset_Beam - LevelOfAccuracy: in te vullen door Buildwise
IfcRoot - Name: 500 x 400 mm
Qto_BeamBaseQuantities - Length: 6972; CrossSectionArea: 0.2; OuterSurfaceArea: 12.5496; GrossSurfaceArea: 12.9496; NetSurfaceArea: 12.9496; GrossVolume: 1.3944; NetVolume: 1.3944
Pset_BeamCommon - Reference: 500 x 400 mm; Span: 6972 mm; Slope: 0 rad; Roll: 0 rad; IsExternal: no; LoadBearing: yes
Pset_Condition - AssessmentCondition: Empty
Pset_EnvironmentalImpactIndicators - Reference: 500 x 400 mm; sets with these values: 2
Name (BB_XX_Betonbalk, rechthoekig, center-center_SFB:500 x 400 mm:...) | In
707141 | 010
702040 | 020

# IfcBeam: BB_XX_Betonbalk_ rechthoekig_ center-center_SFB_500 x 400 mm1 (2)
In: 020
PredefinedType: BEAM; Material: BB_Beton_Bestaand
Cpset_Beam - LevelOfAccuracy: in te vullen door Buildwise
IfcRoot - Name: 500 x 400 mm
Qto_BeamBaseQuantities - Length: 6755; CrossSectionArea: 0.2; OuterSurfaceArea: 12.159; GrossSurfaceArea: 12.559; NetSurfaceArea: 12.559; GrossVolume: 1.351; NetVolume: 1.351
Pset_BeamCommon - Reference: 500 x 400 mm; Span: 6755 mm; Slope: 0 rad; Roll: 0 rad; IsExternal: no; LoadBearing: yes
Pset_Condition - AssessmentCondition: Empty
Pset_EnvironmentalImpactIndicators - Reference: 500 x 400 mm; sets with these values: 2
Name (BB_XX_Betonbalk, rechthoekig, center-center_SFB:500 x 400 mm:...)
697248
697512

# IfcBeam: BB_XX_Betonbalk_ rechthoekig_ center-center_SFB_500 x 400 mm3, BB_XX_Betonbalk, rechthoekig, center-center_SFB:500 x 400 mm:699177
In: 020
PredefinedType: BEAM; Material: BB_Beton_Bestaand
Cpset_Beam - LevelOfAccuracy: in te vullen door Buildwise
IfcRoot - Name: 500 x 400 mm
Qto_BeamBaseQuantities - Length: 6765; CrossSectionArea: 0.2; OuterSurfaceArea: 12.177; GrossSurfaceArea: 12.577; NetSurfaceArea: 12.577; GrossVolume: 1.353; NetVolume: 1.353
Pset_BeamCommon - Reference: 500 x 400 mm; Span: 6765 mm; Slope: 0 rad; Roll: 0 rad; IsExternal: no; LoadBearing: yes
Pset_Condition - AssessmentCondition: Empty
Pset_EnvironmentalImpactIndicators - Reference: 500 x 400 mm; sets with these values: 2

# IfcBeam: BB_XX_Betonbalk_ rechthoekig_ center-center_SFB_500 x 400 mm5, BB_XX_Betonbalk, rechthoekig, center-center_SFB:500 x 400 mm:699402
In: 020
PredefinedType: BEAM; Material: BB_Beton_Bestaand
Cpset_Beam - LevelOfAccuracy: in te vullen door Buildwise
IfcRoot - Name: 500 x 400 mm
Qto_BeamBaseQuantities - Length: 6755; CrossSectionArea: 0.2; OuterSurfaceArea: 12.177; GrossSurfaceArea: 12.577; NetSurfaceArea: 12.577; GrossVolume: 1.353; NetVolume: 1.353
Pset_BeamCommon - Reference: 500 x 400 mm; Span: 6755 mm; Slope: 0 rad; Roll: 0 rad; IsExternal: no; LoadBearing: yes
Pset_Condition - AssessmentCondition: Empty
Pset_EnvironmentalImpactIndicators - Reference: 500 x 400 mm; sets with these values: 2

# IfcBeam: BB_XX_Betonbalk_ rechthoekig_ center-center_SFB_500 x 500 mm, BB_XX_Betonbalk, rechthoekig, center-center_SFB:500 x 500 mm:969002
In: K20
PredefinedType: BEAM; Material: BB_Beton_Bestaand
Cpset_Beam - LevelOfAccuracy: in te vullen door Buildwise
IfcRoot - Name: 500 x 500 mm
Qto_BeamBaseQuantities - Length: 7205; CrossSectionArea: 7.4355; NetSurfaceArea: 14.871; NetVolume: 1.7915
Pset_BeamCommon - Reference: 500 x 500 mm; Span: 7205 mm; Slope: 0 rad; Roll: 0 rad; IsExternal: no; LoadBearing: yes
Pset_Condition - AssessmentCondition: Empty
Pset_EnvironmentalImpactIndicators - Reference: 500 x 500 mm; sets with these values: 2

# IfcBeam: BB_XX_Betonbalk_ rechthoekig_ center-center_SFB_500 x 500 mm1, BB_XX_Betonbalk, rechthoekig, center-center_SFB:500 x 500 mm:981899
In: K20
PredefinedType: BEAM; Material: BB_Beton_Bestaand
Cpset_Beam - LevelOfAccuracy: in te vullen door Buildwise
IfcRoot - Name: 500 x 500 mm
Qto_BeamBaseQuantities - Length: 7000; CrossSectionArea: 0.25; OuterSurfaceArea: 14; GrossSurfaceArea: 14.5; NetSurfaceArea: 14.5; GrossVolume: 1.75; NetVolume: 1.75
Pset_BeamCommon - Reference: 500 x 500 mm; Span: 7000 mm; Slope: 0 rad; Roll: 0 rad; IsExternal: no; LoadBearing: yes
Pset_Condition - AssessmentCondition: Empty
Pset_EnvironmentalImpactIndicators - Reference: 500 x 500 mm; sets with these values: 2

# IfcBeam: BB_XX_Betonbalk_ rechthoekig_ center-center_SFB_500 x 500 mm11, BB_XX_Betonbalk, rechthoekig, center-center_SFB:500 x 500 mm:803545
In: K10
PredefinedType: BEAM; Material: BB_Beton_Bestaand
Cpset_Beam - LevelOfAccuracy: in te vullen door Buildwise
IfcRoot - Name: 500 x 500 mm
Qto_BeamBaseQuantities - Length: 6705; CrossSectionArea: 0.25; OuterSurfaceArea: 13.41; GrossSurfaceArea: 13.91; NetSurfaceArea: 13.91; GrossVolume: 1.67625; NetVolume: 1.67625
Pset_BeamCommon - Reference: 500 x 500 mm; Span: 6705 mm; Slope: 0 rad; Roll: 0 rad; IsExternal: no; LoadBearing: yes
Pset_Condition - AssessmentCondition: Empty
Pset_EnvironmentalImpactIndicators - Reference: 500 x 500 mm; sets with these values: 2

# IfcBeam: BB_XX_Betonbalk_ rechthoekig_ center-center_SFB_500 x 500 mm13, BB_XX_Betonbalk, rechthoekig, center-center_SFB:500 x 500 mm:813718
In: K10
PredefinedType: BEAM; Material: BB_Beton_Bestaand
Cpset_Beam - LevelOfAccuracy: in te vullen door Buildwise
IfcRoot - Name: 500 x 500 mm
Qto_BeamBaseQuantities - Length: 5285; CrossSectionArea: 2.4825; OuterSurfaceArea: 5.785; GrossSurfaceArea: 10.75; NetSurfaceArea: 10.75; GrossVolume: 1.24125; NetVolume: 1.24125
Pset_BeamCommon - Reference: 500 x 500 mm; Span: 5285 mm; Slope: 0 rad; Roll: 0 rad; IsExternal: no; LoadBearing: yes
Pset_Condition - AssessmentCondition: Empty
Pset_EnvironmentalImpactIndicators - Reference: 500 x 500 mm; sets with these values: 2

# IfcBeam: BB_XX_Betonbalk_ rechthoekig_ center-center_SFB_500 x 500 mm15, BB_XX_Betonbalk, rechthoekig, center-center_SFB:500 x 500 mm:908271
In: K10
PredefinedType: BEAM; Material: BB_Beton_Bestaand
Cpset_Beam - LevelOfAccuracy: in te vullen door Buildwise
IfcRoot - Name: 500 x 500 mm
Qto_BeamBaseQuantities - Length: 7805; CrossSectionArea: 7.5494; NetSurfaceArea: 15.0988; NetVolume: 1.75345
Pset_BeamCommon - Reference: 500 x 500 mm; Span: 7805 mm; Slope: 0 rad; Roll: 0 rad; IsExternal: no; LoadBearing: yes
Pset_Condition - AssessmentCondition: Empty
Pset_EnvironmentalImpactIndicators - Reference: 500 x 500 mm; sets with these values: 2

# IfcBeam: BB_XX_Betonbalk_ rechthoekig_ center-center_SFB_500 x 500 mm3, BB_XX_Betonbalk, rechthoekig, center-center_SFB:500 x 500 mm:985750
In: K20
PredefinedType: BEAM; Material: BB_Beton_Bestaand
Cpset_Beam - LevelOfAccuracy: in te vullen door Buildwise
IfcRoot - Name: 500 x 500 mm
Qto_BeamBaseQuantities - Length: 12800; CrossSectionArea: 0.25; OuterSurfaceArea: 25.6; GrossSurfaceArea: 26.1; NetSurfaceArea: 26.1; GrossVolume: 3.2; NetVolume: 3.2
Pset_BeamCommon - Reference: 500 x 500 mm; Span: 12800 mm; Slope: 0 rad; Roll: 0 rad; IsExternal: no; LoadBearing: yes
Pset_Condition - AssessmentCondition: Empty
Pset_EnvironmentalImpactIndicators - Reference: 500 x 500 mm; sets with these values: 2

# IfcBeam: BB_XX_Betonbalk_ rechthoekig_ center-center_SFB_500 x 500 mm5, BB_XX_Betonbalk, rechthoekig, center-center_SFB:500 x 500 mm:985848
In: K20
PredefinedType: BEAM; Material: BB_Beton_Bestaand
Cpset_Beam - LevelOfAccuracy: in te vullen door Buildwise
IfcRoot - Name: 500 x 500 mm
Qto_BeamBaseQuantities - Length: 13150; CrossSectionArea: 0.25; OuterSurfaceArea: 26.3; GrossSurfaceArea: 26.8; NetSurfaceArea: 26.8; GrossVolume: 3.2875; NetVolume: 3.2875
Pset_BeamCommon - Reference: 500 x 500 mm; Span: 13150 mm; Slope: 0 rad; Roll: 0 rad; IsExternal: no; LoadBearing: yes
Pset_Condition - AssessmentCondition: Empty
Pset_EnvironmentalImpactIndicators - Reference: 500 x 500 mm; sets with these values: 2

# IfcBeam: BB_XX_Betonbalk_ rechthoekig_ center-center_SFB_500 x 500 mm7, BB_XX_Betonbalk, rechthoekig, center-center_SFB:500 x 500 mm:987000
In: K20
PredefinedType: BEAM; Material: BB_Beton_Bestaand
Cpset_Beam - LevelOfAccuracy: in te vullen door Buildwise
IfcRoot - Name: 500 x 500 mm
Qto_BeamBaseQuantities - Length: 21200; CrossSectionArea: 0.25; OuterSurfaceArea: 42.4; GrossSurfaceArea: 42.9; NetSurfaceArea: 42.9; GrossVolume: 5.3; NetVolume: 5.3
Pset_BeamCommon - Reference: 500 x 500 mm; Span: 21200 mm; Slope: 0 rad; Roll: 0 rad; IsExternal: no; LoadBearing: yes
Pset_Condition - AssessmentCondition: Empty
Pset_EnvironmentalImpactIndicators - Reference: 500 x 500 mm; sets with these values: 2

# IfcBeam: BB_XX_Betonbalk_ rechthoekig_ center-center_SFB_500 x 500 mm9, BB_XX_Betonbalk, rechthoekig, center-center_SFB:500 x 500 mm:1000275
In: K20
PredefinedType: BEAM; Material: BB_Beton_Bestaand
Cpset_Beam - LevelOfAccuracy: in te vullen door Buildwise
IfcRoot - Name: 500 x 500 mm
Qto_BeamBaseQuantities - Length: 10600; CrossSectionArea: 0.25; OuterSurfaceArea: 21.2001; GrossSurfaceArea: 21.7001; NetSurfaceArea: 22.2961; GrossVolume: 2.65001; NetVolume: 2.51401
Pset_BeamCommon - Reference: 500 x 500 mm; Span: 10600 mm; Slope: 0 rad; Roll: 0 rad; IsExternal: no; LoadBearing: yes
Pset_Condition - AssessmentCondition: Empty
Pset_EnvironmentalImpactIndicators - Reference: 500 x 500 mm; sets with these values: 2

# IfcBeam: BB_XX_Betonbalk_ rechthoekig_ center-center_SFB_500 x 600 mm, BB_XX_Betonbalk, rechthoekig, center-center_SFB:500 x 600 mm:815624
In: K10
PredefinedType: BEAM; Material: BB_Beton_Bestaand
Cpset_Beam - LevelOfAccuracy: in te vullen door Buildwise
IfcRoot - Name: 500 x 600 mm
Qto_BeamBaseQuantities - Length: 5600; CrossSectionArea: 0.3; OuterSurfaceArea: 12.32; GrossSurfaceArea: 12.92; NetSurfaceArea: 12.92; GrossVolume: 1.68; NetVolume: 1.68
Pset_BeamCommon - Reference: 500 x 600 mm; Span: 5600 mm; Slope: 0 rad; Roll: 0 rad; IsExternal: no; LoadBearing: yes
Pset_Condition - AssessmentCondition: Empty
Pset_EnvironmentalImpactIndicators - Reference: 500 x 600 mm; sets with these values: 2

# IfcBeam: BB_XX_Betonbalk_ rechthoekig_ center-center_SFB_500 x 600 mm1, BB_XX_Betonbalk, rechthoekig, center-center_SFB:500 x 600 mm:844698
In: K10
PredefinedType: BEAM; Material: BB_Beton_Bestaand
Cpset_Beam - LevelOfAccuracy: in te vullen door Buildwise
IfcRoot - Name: 500 x 600 mm
Qto_BeamBaseQuantities - Length: 7500; CrossSectionArea: 0.3; OuterSurfaceArea: 16.5; GrossSurfaceArea: 17.1; NetSurfaceArea: 17.1; GrossVolume: 2.25; NetVolume: 2.25
Pset_BeamCommon - Reference: 500 x 600 mm; Span: 7500 mm; Slope: 0 rad; Roll: 0 rad; IsExternal: no; LoadBearing: yes
Pset_Condition - AssessmentCondition: Empty
Pset_EnvironmentalImpactIndicators - Reference: 500 x 600 mm; sets with these values: 2

# IfcBeam: BB_XX_Betonbalk_ rechthoekig_ center-center_SFB_500 x 700 mm, BB_XX_Betonbalk, rechthoekig, center-center_SFB:500 x 700 mm:941841
In: K10
PredefinedType: BEAM; Material: BB_Beton_Bestaand
Cpset_Beam - LevelOfAccuracy: in te vullen door Buildwise
IfcRoot - Name: 500 x 700 mm
Qto_BeamBaseQuantities - Length: 1000; CrossSectionArea: 0.0735; OuterSurfaceArea: 1.61; GrossSurfaceArea: 1.757; NetSurfaceArea: 1.757; GrossVolume: 0.0735; NetVolume: 0.0735
Pset_BeamCommon - Reference: 500 x 700 mm; Span: 1000 mm; Slope: 0 rad; Roll: 0 rad; IsExternal: no; LoadBearing: yes
Pset_Condition - AssessmentCondition: Empty
Pset_EnvironmentalImpactIndicators - Reference: 500 x 700 mm; sets with these values: 2

# IfcBeam: BB_XX_Betonbalk_ rechthoekig_ center-center_SFB_600 x 500 mm, BB_XX_Betonbalk, rechthoekig, center-center_SFB:600 x 500 mm:968362
In: K20
PredefinedType: BEAM; Material: BB_Beton_Bestaand
Cpset_Beam - LevelOfAccuracy: in te vullen door Buildwise
IfcRoot - Name: 600 x 500 mm
Qto_BeamBaseQuantities - Length: 17805; CrossSectionArea: 0.3; OuterSurfaceArea: 39.171; GrossSurfaceArea: 39.771; NetSurfaceArea: 39.771; GrossVolume: 5.3415; NetVolume: 5.3415
Pset_BeamCommon - Reference: 600 x 500 mm; Span: 17805 mm; Slope: 0 rad; Roll: 0 rad; IsExternal: no; LoadBearing: yes
Pset_Condition - AssessmentCondition: Empty
Pset_EnvironmentalImpactIndicators - Reference: 600 x 500 mm; sets with these values: 2

# IfcBeam: BB_XX_Betonbalk_ rechthoekig_ center-center_SFB_600 x 500 mm1, BB_XX_Betonbalk, rechthoekig, center-center_SFB:600 x 500 mm:978086
In: K20
PredefinedType: BEAM; Material: BB_Beton_Bestaand
Cpset_Beam - LevelOfAccuracy: in te vullen door Buildwise
IfcRoot - Name: 600 x 500 mm
Qto_BeamBaseQuantities - Length: 21420; CrossSectionArea: 23.9014; NetSurfaceArea: 47.8028; NetVolume: 6.39642
Pset_BeamCommon - Reference: 600 x 500 mm; Span: 21420 mm; Slope: 0 rad; Roll: 0 rad; IsExternal: no; LoadBearing: yes
Pset_Condition - AssessmentCondition: Empty
Pset_EnvironmentalImpactIndicators - Reference: 600 x 500 mm; sets with these values: 2

# IfcBeam: BB_XX_Betonbalk_ rechthoekig_ center-center_SFB_600 x 500 mm11, BB_XX_Betonbalk, rechthoekig, center-center_SFB:600 x 500 mm:987352
In: K20
PredefinedType: BEAM; Material: BB_Beton_Bestaand
Cpset_Beam - LevelOfAccuracy: in te vullen door Buildwise
IfcRoot - Name: 600 x 500 mm
Qto_BeamBaseQuantities - Length: 4790; CrossSectionArea: 5.55651; NetSurfaceArea: 11.113; NetVolume: 1.40425
Pset_BeamCommon - Reference: 600 x 500 mm; Span: 4790 mm; Slope: 0 rad; Roll: 0 rad; IsExternal: no; LoadBearing: yes
Pset_Condition - AssessmentCondition: Empty
Pset_EnvironmentalImpactIndicators - Reference: 600 x 500 mm; sets with these values: 2

# IfcBeam: BB_XX_Betonbalk_ rechthoekig_ center-center_SFB_600 x 500 mm13, BB_XX_Betonbalk, rechthoekig, center-center_SFB:600 x 500 mm:987434
In: K20
PredefinedType: BEAM; Material: BB_Beton_Bestaand
Cpset_Beam - LevelOfAccuracy: in te vullen door Buildwise
IfcRoot - Name: 600 x 500 mm
Qto_BeamBaseQuantities - Length: 3340; CrossSectionArea: 3.82116; NetSurfaceArea: 7.64232; NetVolume: 0.916439
Pset_BeamCommon - Reference: 600 x 500 mm; Span: 3340 mm; Slope: 0 rad; Roll: 0 rad; IsExternal: no; LoadBearing: yes
Pset_Condition - AssessmentCondition: Empty
Pset_EnvironmentalImpactIndicators - Reference: 600 x 500 mm; sets with these values: 2

# IfcBeam: BB_XX_Betonbalk_ rechthoekig_ center-center_SFB_600 x 500 mm15, BB_XX_Betonbalk, rechthoekig, center-center_SFB:600 x 500 mm:991308
In: K20
PredefinedType: BEAM; Material: BB_Beton_Bestaand
Cpset_Beam - LevelOfAccuracy: in te vullen door Buildwise
IfcRoot - Name: 600 x 500 mm
Qto_BeamBaseQuantities - Length: 13700; CrossSectionArea: 0.3; OuterSurfaceArea: 30.14; GrossSurfaceArea: 30.74; NetSurfaceArea: 30.74; GrossVolume: 4.11; NetVolume: 4.11
Pset_BeamCommon - Reference: 600 x 500 mm; Span: 13700 mm; Slope: 0 rad; Roll: 0 rad; IsExternal: no; LoadBearing: yes
Pset_Condition - AssessmentCondition: Empty
Pset_EnvironmentalImpactIndicators - Reference: 600 x 500 mm; sets with these values: 2

# IfcBeam: BB_XX_Betonbalk_ rechthoekig_ center-center_SFB_600 x 500 mm17, BB_XX_Betonbalk, rechthoekig, center-center_SFB:600 x 500 mm:994977
In: K20
PredefinedType: BEAM; Material: BB_Beton_Bestaand
Cpset_Beam - LevelOfAccuracy: in te vullen door Buildwise
IfcRoot - Name: 600 x 500 mm
Qto_BeamBaseQuantities - Length: 22126.4; CrossSectionArea: 24.1502; NetSurfaceArea: 48.3005; NetVolume: 6.42581
Pset_BeamCommon - Reference: 600 x 500 mm; Span: 22126.4 mm; Slope: 0 rad; Roll: 0 rad; IsExternal: no; LoadBearing: yes
Pset_Condition - AssessmentCondition: Empty
Pset_EnvironmentalImpactIndicators - Reference: 600 x 500 mm; sets with these values: 2

# IfcBeam: BB_XX_Betonbalk_ rechthoekig_ center-center_SFB_600 x 500 mm19, BB_XX_Betonbalk, rechthoekig, center-center_SFB:600 x 500 mm:995381
In: K20
PredefinedType: BEAM; Material: BB_Beton_Bestaand
Cpset_Beam - LevelOfAccuracy: in te vullen door Buildwise
IfcRoot - Name: 600 x 500 mm
Qto_BeamBaseQuantities - Length: 18400; CrossSectionArea: 20.08; NetSurfaceArea: 40.16; NetVolume: 5.29
Pset_BeamCommon - Reference: 600 x 500 mm; Span: 18400 mm; Slope: 0 rad; Roll: 0 rad; IsExternal: no; LoadBearing: yes
Pset_Condition - AssessmentCondition: Empty
Pset_EnvironmentalImpactIndicators - Reference: 600 x 500 mm; sets with these values: 2

# IfcBeam: BB_XX_Betonbalk_ rechthoekig_ center-center_SFB_600 x 500 mm21, BB_XX_Betonbalk, rechthoekig, center-center_SFB:600 x 500 mm:998198
In: K20
PredefinedType: BEAM; Material: BB_Beton_Bestaand
Cpset_Beam - LevelOfAccuracy: in te vullen door Buildwise
IfcRoot - Name: 600 x 500 mm
Qto_BeamBaseQuantities - Length: 15900; CrossSectionArea: 0.3; OuterSurfaceArea: 34.98; GrossSurfaceArea: 35.58; NetSurfaceArea: 35.58; GrossVolume: 4.77; NetVolume: 4.77
Pset_BeamCommon - Reference: 600 x 500 mm; Span: 15900 mm; Slope: 0 rad; Roll: 0 rad; IsExternal: no; LoadBearing: yes
Pset_Condition - AssessmentCondition: Empty
Pset_EnvironmentalImpactIndicators - Reference: 600 x 500 mm; sets with these values: 2

# IfcBeam: BB_XX_Betonbalk_ rechthoekig_ center-center_SFB_600 x 500 mm23, BB_XX_Betonbalk, rechthoekig, center-center_SFB:600 x 500 mm:1000201
In: K20
PredefinedType: BEAM; Material: BB_Beton_Bestaand
Cpset_Beam - LevelOfAccuracy: in te vullen door Buildwise
IfcRoot - Name: 600 x 500 mm
Qto_BeamBaseQuantities - Length: 6700; CrossSectionArea: 0.3; OuterSurfaceArea: 14.74; GrossSurfaceArea: 15.34; NetSurfaceArea: 15.34; GrossVolume: 2.01; NetVolume: 2.01
Pset_BeamCommon - Reference: 600 x 500 mm; Span: 6700 mm; Slope: 0 rad; Roll: 0 rad; IsExternal: no; LoadBearing: yes
Pset_Condition - AssessmentCondition: Empty
Pset_EnvironmentalImpactIndicators - Reference: 600 x 500 mm; sets with these values: 2

# IfcBeam: BB_XX_Betonbalk_ rechthoekig_ center-center_SFB_600 x 500 mm25, BB_XX_Betonbalk, rechthoekig, center-center_SFB:600 x 500 mm:1000681
In: K20
PredefinedType: BEAM; Material: BB_Beton_Bestaand
Cpset_Beam - LevelOfAccuracy: in te vullen door Buildwise
IfcRoot - Name: 600 x 500 mm
Qto_BeamBaseQuantities - Length: 6800; CrossSectionArea: 0.3; OuterSurfaceArea: 14.96; GrossSurfaceArea: 15.56; NetSurfaceArea: 15.56; GrossVolume: 2.04; NetVolume: 2.04
Pset_BeamCommon - Reference: 600 x 500 mm; Span: 6800 mm; Slope: 0 rad; Roll: 0 rad; IsExternal: no; LoadBearing: yes
Pset_Condition - AssessmentCondition: Empty
Pset_EnvironmentalImpactIndicators - Reference: 600 x 500 mm; sets with these values: 2

# IfcBeam: BB_XX_Betonbalk_ rechthoekig_ center-center_SFB_600 x 500 mm27, BB_XX_Betonbalk, rechthoekig, center-center_SFB:600 x 500 mm:1001318
In: K20
PredefinedType: BEAM; Material: BB_Beton_Bestaand
Cpset_Beam - LevelOfAccuracy: in te vullen door Buildwise
IfcRoot - Name: 600 x 500 mm
Qto_BeamBaseQuantities - Length: 14105; CrossSectionArea: 15.8955; NetSurfaceArea: 31.791; NetVolume: 4.1465
Pset_BeamCommon - Reference: 600 x 500 mm; Span: 14105 mm; Slope: 0 rad; Roll: 0 rad; IsExternal: no; LoadBearing: yes
Pset_Condition - AssessmentCondition: Empty
Pset_EnvironmentalImpactIndicators - Reference: 600 x 500 mm; sets with these values: 2

# IfcBeam: BB_XX_Betonbalk_ rechthoekig_ center-center_SFB_600 x 500 mm29, BB_XX_Betonbalk, rechthoekig, center-center_SFB:600 x 500 mm:1010319
In: K20
PredefinedType: BEAM; Material: BB_Beton_Bestaand
Cpset_Beam - LevelOfAccuracy: in te vullen door Buildwise
IfcRoot - Name: 600 x 500 mm
Qto_BeamBaseQuantities - Length: 7095.67; CrossSectionArea: 7.93524; NetSurfaceArea: 15.8705; NetVolume: 2.0437
Pset_BeamCommon - Reference: 600 x 500 mm; Span: 7095.67 mm; Slope: 0 rad; Roll: 0 rad; IsExternal: no; LoadBearing: yes
Pset_Condition - AssessmentCondition: Empty
Pset_EnvironmentalImpactIndicators - Reference: 600 x 500 mm; sets with these values: 2

# IfcBeam: BB_XX_Betonbalk_ rechthoekig_ center-center_SFB_600 x 500 mm3, BB_XX_Betonbalk, rechthoekig, center-center_SFB:600 x 500 mm:980548
In: K20
PredefinedType: BEAM; Material: BB_Beton_Bestaand
Cpset_Beam - LevelOfAccuracy: in te vullen door Buildwise
IfcRoot - Name: 600 x 500 mm
Qto_BeamBaseQuantities - Length: 10874.8; CrossSectionArea: 11.6796; NetSurfaceArea: 23.3592; NetVolume: 3.08658
Pset_BeamCommon - Reference: 600 x 500 mm; Span: 10874.8 mm; Slope: 0 rad; Roll: 0 rad; IsExternal: no; LoadBearing: yes
Pset_Condition - AssessmentCondition: Empty
Pset_EnvironmentalImpactIndicators - Reference: 600 x 500 mm; sets with these values: 2

# IfcBeam: BB_XX_Betonbalk_ rechthoekig_ center-center_SFB_600 x 500 mm31, BB_XX_Betonbalk, rechthoekig, center-center_SFB:600 x 500 mm:1010517
In: K20
PredefinedType: BEAM; Material: BB_Beton_Bestaand
Cpset_Beam - LevelOfAccuracy: in te vullen door Buildwise
IfcRoot - Name: 600 x 500 mm
Qto_BeamBaseQuantities - Length: 5000; CrossSectionArea: 0.3; OuterSurfaceArea: 11; GrossSurfaceArea: 11.6; NetSurfaceArea: 11.6; GrossVolume: 1.5; NetVolume: 1.5
Pset_BeamCommon - Reference: 600 x 500 mm; Span: 5000 mm; Slope: 0 rad; Roll: 0 rad; IsExternal: no; LoadBearing: yes
Pset_Condition - AssessmentCondition: Empty
Pset_EnvironmentalImpactIndicators - Reference: 600 x 500 mm; sets with these values: 2

# IfcBeam: BB_XX_Betonbalk_ rechthoekig_ center-center_SFB_600 x 500 mm33, BB_XX_Betonbalk, rechthoekig, center-center_SFB:600 x 500 mm:1010624
In: K20
PredefinedType: BEAM; Material: BB_Beton_Bestaand
Cpset_Beam - LevelOfAccuracy: in te vullen door Buildwise
IfcRoot - Name: 600 x 500 mm
Qto_BeamBaseQuantities - Length: 6754.33; CrossSectionArea: 0.3; OuterSurfaceArea: 14.8595; GrossSurfaceArea: 15.4595; NetSurfaceArea: 15.4595; GrossVolume: 2.0263; NetVolume: 2.0263
Pset_BeamCommon - Reference: 600 x 500 mm; Span: 6754.33 mm; Slope: 0 rad; Roll: 0 rad; IsExternal: no; LoadBearing: yes
Pset_Condition - AssessmentCondition: Empty
Pset_EnvironmentalImpactIndicators - Reference: 600 x 500 mm; sets with these values: 2

# IfcBeam: BB_XX_Betonbalk_ rechthoekig_ center-center_SFB_600 x 500 mm35, BB_XX_Betonbalk, rechthoekig, center-center_SFB:600 x 500 mm:1957146
In: K20
PredefinedType: BEAM; Material: BB_Beton_Bestaand
Cpset_Beam - LevelOfAccuracy: in te vullen door Buildwise
IfcRoot - Name: 600 x 500 mm
Qto_BeamBaseQuantities - Length: 5205; CrossSectionArea: 0.3; OuterSurfaceArea: 11.451; GrossSurfaceArea: 12.051; NetSurfaceArea: 12.051; GrossVolume: 1.5615; NetVolume: 1.5615
Pset_BeamCommon - Reference: 600 x 500 mm; Span: 5205 mm; Slope: 0 rad; Roll: 0 rad; IsExternal: no; LoadBearing: yes
Pset_Condition - AssessmentCondition: Empty
Pset_EnvironmentalImpactIndicators - Reference: 600 x 500 mm; sets with these values: 2

# IfcBeam: BB_XX_Betonbalk_ rechthoekig_ center-center_SFB_600 x 500 mm37, BB_XX_Betonbalk, rechthoekig, center-center_SFB:600 x 500 mm:796448
In: K10
PredefinedType: BEAM; Material: BB_Beton_Bestaand
Cpset_Beam - LevelOfAccuracy: in te vullen door Buildwise
IfcRoot - Name: 600 x 500 mm
Qto_BeamBaseQuantities - Length: 7100; CrossSectionArea: 8.13114; NetSurfaceArea: 16.2623; NetVolume: 2.08754
Pset_BeamCommon - Reference: 600 x 500 mm; Span: 7100 mm; Slope: 0 rad; Roll: 0 rad; IsExternal: no; LoadBearing: yes
Pset_Condition - AssessmentCondition: Empty
Pset_EnvironmentalImpactIndicators - Reference: 600 x 500 mm; sets with these values: 2

# IfcBeam: BB_XX_Betonbalk_ rechthoekig_ center-center_SFB_600 x 500 mm39, BB_XX_Betonbalk, rechthoekig, center-center_SFB:600 x 500 mm:838998
In: K10
PredefinedType: BEAM; Material: BB_Beton_Bestaand
Cpset_Beam - LevelOfAccuracy: in te vullen door Buildwise
IfcRoot - Name: 600 x 500 mm
Qto_BeamBaseQuantities - Length: 9193.35; CrossSectionArea: 10.3998; NetSurfaceArea: 20.7995; NetVolume: 2.72489
Pset_BeamCommon - Reference: 600 x 500 mm; Span: 9193.35 mm; Slope: 0 rad; Roll: 0 rad; IsExternal: no; LoadBearing: yes
Pset_Condition - AssessmentCondition: Empty
Pset_EnvironmentalImpactIndicators - Reference: 600 x 500 mm; sets with these values: 2

# IfcBeam: BB_XX_Betonbalk_ rechthoekig_ center-center_SFB_600 x 500 mm41, BB_XX_Betonbalk, rechthoekig, center-center_SFB:600 x 500 mm:839374
In: K10
PredefinedType: BEAM; Material: BB_Beton_Bestaand
Cpset_Beam - LevelOfAccuracy: in te vullen door Buildwise
IfcRoot - Name: 600 x 500 mm
Qto_BeamBaseQuantities - Length: 3340; CrossSectionArea: 3.80685; NetSurfaceArea: 7.6137; NetVolume: 0.951375
Pset_BeamCommon - Reference: 600 x 500 mm; Span: 3340 mm; Slope: 0 rad; Roll: 0 rad; IsExternal: no; LoadBearing: yes
Pset_Condition - AssessmentCondition: Empty
Pset_EnvironmentalImpactIndicators - Reference: 600 x 500 mm; sets with these values: 2

# IfcBeam: BB_XX_Betonbalk_ rechthoekig_ center-center_SFB_600 x 500 mm43, BB_XX_Betonbalk, rechthoekig, center-center_SFB:600 x 500 mm:840379
In: K10
PredefinedType: BEAM; Material: BB_Beton_Bestaand
Cpset_Beam - LevelOfAccuracy: in te vullen door Buildwise
IfcRoot - Name: 600 x 500 mm
Qto_BeamBaseQuantities - Length: 4680; CrossSectionArea: 5.43551; NetSurfaceArea: 10.871; NetVolume: 1.37125
Pset_BeamCommon - Reference: 600 x 500 mm; Span: 4680 mm; Slope: 0 rad; Roll: 0 rad; IsExternal: no; LoadBearing: yes
Pset_Condition - AssessmentCondition: Empty
Pset_EnvironmentalImpactIndicators - Reference: 600 x 500 mm; sets with these values: 2

# IfcBeam: BB_XX_Betonbalk_ rechthoekig_ center-center_SFB_600 x 500 mm45, BB_XX_Betonbalk, rechthoekig, center-center_SFB:600 x 500 mm:843946
In: K10
PredefinedType: BEAM; Material: BB_Beton_Bestaand
Cpset_Beam - LevelOfAccuracy: in te vullen door Buildwise
IfcRoot - Name: 600 x 500 mm
Qto_BeamBaseQuantities - Length: 15900; CrossSectionArea: 0.3; OuterSurfaceArea: 34.98; GrossSurfaceArea: 35.58; NetSurfaceArea: 35.58; GrossVolume: 4.77; NetVolume: 4.77
Pset_BeamCommon - Reference: 600 x 500 mm; Span: 15900 mm; Slope: 0 rad; Roll: 0 rad; IsExternal: no; LoadBearing: yes
Pset_Condition - AssessmentCondition: Empty
Pset_EnvironmentalImpactIndicators - Reference: 600 x 500 mm; sets with these values: 2

# IfcBeam: BB_XX_Betonbalk_ rechthoekig_ center-center_SFB_600 x 500 mm47, BB_XX_Betonbalk, rechthoekig, center-center_SFB:600 x 500 mm:885582
In: K10
PredefinedType: BEAM; Material: BB_Beton_Bestaand
Cpset_Beam - LevelOfAccuracy: in te vullen door Buildwise
IfcRoot - Name: 600 x 500 mm
Qto_BeamBaseQuantities - Length: 17800; CrossSectionArea: 0.3; OuterSurfaceArea: 39.16; GrossSurfaceArea: 39.76; NetSurfaceArea: 39.76; GrossVolume: 5.34; NetVolume: 5.34
Pset_BeamCommon - Reference: 600 x 500 mm; Span: 17800 mm; Slope: 0 rad; Roll: 0 rad; IsExternal: no; LoadBearing: yes
Pset_Condition - AssessmentCondition: Empty
Pset_EnvironmentalImpactIndicators - Reference: 600 x 500 mm; sets with these values: 2

# IfcBeam: BB_XX_Betonbalk_ rechthoekig_ center-center_SFB_600 x 500 mm49, BB_XX_Betonbalk, rechthoekig, center-center_SFB:600 x 500 mm:886701
In: K10
PredefinedType: BEAM; Material: BB_Beton_Bestaand
Cpset_Beam - LevelOfAccuracy: in te vullen door Buildwise
IfcRoot - Name: 600 x 500 mm
Qto_BeamBaseQuantities - Length: 13700; CrossSectionArea: 0.3; OuterSurfaceArea: 30.14; GrossSurfaceArea: 30.74; NetSurfaceArea: 30.74; GrossVolume: 4.11; NetVolume: 4.11
Pset_BeamCommon - Reference: 600 x 500 mm; Span: 13700 mm; Slope: 0 rad; Roll: 0 rad; IsExternal: no; LoadBearing: yes
Pset_Condition - AssessmentCondition: Empty
Pset_EnvironmentalImpactIndicators - Reference: 600 x 500 mm; sets with these values: 2

# IfcBeam: BB_XX_Betonbalk_ rechthoekig_ center-center_SFB_600 x 500 mm5, BB_XX_Betonbalk, rechthoekig, center-center_SFB:600 x 500 mm:985560
In: K20
PredefinedType: BEAM; Material: BB_Beton_Bestaand
Cpset_Beam - LevelOfAccuracy: in te vullen door Buildwise
IfcRoot - Name: 600 x 500 mm
Qto_BeamBaseQuantities - Length: 15900; CrossSectionArea: 0.3; OuterSurfaceArea: 34.98; GrossSurfaceArea: 35.58; NetSurfaceArea: 35.58; GrossVolume: 4.77; NetVolume: 4.77
Pset_BeamCommon - Reference: 600 x 500 mm; Span: 15900 mm; Slope: 0 rad; Roll: 0 rad; IsExternal: no; LoadBearing: yes
Pset_Condition - AssessmentCondition: Empty
Pset_EnvironmentalImpactIndicators - Reference: 600 x 500 mm; sets with these values: 2

# IfcBeam: BB_XX_Betonbalk_ rechthoekig_ center-center_SFB_600 x 500 mm7, BB_XX_Betonbalk, rechthoekig, center-center_SFB:600 x 500 mm:985846
In: K20
PredefinedType: BEAM; Material: BB_Beton_Bestaand
Cpset_Beam - LevelOfAccuracy: in te vullen door Buildwise
IfcRoot - Name: 600 x 500 mm
Qto_BeamBaseQuantities - Length: 22205; CrossSectionArea: 24.5016; NetSurfaceArea: 49.0032; NetVolume: 6.58898
Pset_BeamCommon - Reference: 600 x 500 mm; Span: 22205 mm; Slope: 0 rad; Roll: 0 rad; IsExternal: no; LoadBearing: yes
Pset_Condition - AssessmentCondition: Empty
Pset_EnvironmentalImpactIndicators - Reference: 600 x 500 mm; sets with these values: 2

# IfcBeam: BB_XX_Betonbalk_ rechthoekig_ center-center_SFB_600 x 500 mm9, BB_XX_Betonbalk, rechthoekig, center-center_SFB:600 x 500 mm:987340
In: K20
PredefinedType: BEAM; Material: BB_Beton_Bestaand
Cpset_Beam - LevelOfAccuracy: in te vullen door Buildwise
IfcRoot - Name: 600 x 500 mm
Qto_BeamBaseQuantities - Length: 9303.35; CrossSectionArea: 10.5208; NetSurfaceArea: 21.0415; NetVolume: 2.75789
Pset_BeamCommon - Reference: 600 x 500 mm; Span: 9303.35 mm; Slope: 0 rad; Roll: 0 rad; IsExternal: no; LoadBearing: yes
Pset_Condition - AssessmentCondition: Empty
Pset_EnvironmentalImpactIndicators - Reference: 600 x 500 mm; sets with these values: 2

# IfcBeam: BB_XX_Betonbalk_ rechthoekig_ center-center_SFB_620 x 500 mm, BB_XX_Betonbalk, rechthoekig, center-center_SFB:620 x 500 mm:969776
In: K20
PredefinedType: BEAM; Material: BB_Beton_Bestaand
Cpset_Beam - LevelOfAccuracy: in te vullen door Buildwise
IfcRoot - Name: 620 x 500 mm
Qto_BeamBaseQuantities - Length: 18000; CrossSectionArea: 20.2615; NetSurfaceArea: 40.5231; NetVolume: 5.47577
Pset_BeamCommon - Reference: 620 x 500 mm; Span: 18000 mm; Slope: 0 rad; Roll: 0 rad; IsExternal: no; LoadBearing: yes
Pset_Condition - AssessmentCondition: Empty
Pset_EnvironmentalImpactIndicators - Reference: 620 x 500 mm; sets with these values: 2

# IfcBeam: BB_XX_Betonbalk_ rechthoekig_ center-center_SFB_620 x 500 mm1, BB_XX_Betonbalk, rechthoekig, center-center_SFB:620 x 500 mm:838483
In: K10
PredefinedType: BEAM; Material: BB_Beton_Bestaand
Cpset_Beam - LevelOfAccuracy: in te vullen door Buildwise
IfcRoot - Name: 620 x 500 mm
Qto_BeamBaseQuantities - Length: 12970; CrossSectionArea: 0.31; OuterSurfaceArea: 29.0528; GrossSurfaceArea: 29.6728; NetSurfaceArea: 29.6728; GrossVolume: 4.0207; NetVolume: 4.0207
Pset_BeamCommon - Reference: 620 x 500 mm; Span: 12970 mm; Slope: 0 rad; Roll: 0 rad; IsExternal: no; LoadBearing: yes
Pset_Condition - AssessmentCondition: Empty
Pset_EnvironmentalImpactIndicators - Reference: 620 x 500 mm; sets with these values: 2

# IfcBeam: BB_XX_Betonbalk_ rechthoekig_ center-center_SFB_620 x 500 mm3, BB_XX_Betonbalk, rechthoekig, center-center_SFB:620 x 500 mm:899528
In: K10
PredefinedType: BEAM; Material: BB_Beton_Bestaand
Cpset_Beam - LevelOfAccuracy: in te vullen door Buildwise
IfcRoot - Name: 620 x 500 mm
Qto_BeamBaseQuantities - Length: 15900; CrossSectionArea: 0.31; OuterSurfaceArea: 35.616; GrossSurfaceArea: 36.236; NetSurfaceArea: 36.236; GrossVolume: 4.929; NetVolume: 4.929
Pset_BeamCommon - Reference: 620 x 500 mm; Span: 15900 mm; Slope: 0 rad; Roll: 0 rad; IsExternal: no; LoadBearing: yes
Pset_Condition - AssessmentCondition: Empty
Pset_EnvironmentalImpactIndicators - Reference: 620 x 500 mm; sets with these values: 2

# IfcBeam: BB_XX_Betonbalk_ rechthoekig_ center-center_SFB_720 x 500 mm, BB_XX_Betonbalk, rechthoekig, center-center_SFB:720 x 500 mm:837804
In: K10
PredefinedType: BEAM; Material: BB_Beton_Bestaand
Cpset_Beam - LevelOfAccuracy: in te vullen door Buildwise
IfcRoot - Name: 720 x 500 mm
Qto_BeamBaseQuantities - Length: 22135; CrossSectionArea: 26.7038; NetSurfaceArea: 53.4076; NetVolume: 7.75158
Pset_BeamCommon - Reference: 720 x 500 mm; Span: 22135 mm; Slope: 0 rad; Roll: 0 rad; IsExternal: no; LoadBearing: yes
Pset_Condition - AssessmentCondition: Empty
Pset_EnvironmentalImpactIndicators - Reference: 720 x 500 mm; sets with these values: 2

# IfcBeam: BB_XX_Betonbalk_ rechthoekig_ center-center_SFB_720 x 500 mm1, BB_XX_Betonbalk, rechthoekig, center-center_SFB:720 x 500 mm:840757
In: K10
PredefinedType: BEAM; Material: BB_Beton_Bestaand
Cpset_Beam - LevelOfAccuracy: in te vullen door Buildwise
IfcRoot - Name: 720 x 500 mm
Qto_BeamBaseQuantities - Length: 20970; CrossSectionArea: 0.36; OuterSurfaceArea: 51.1668; GrossSurfaceArea: 51.8868; NetSurfaceArea: 51.8868; GrossVolume: 7.5492; NetVolume: 7.5492
Pset_BeamCommon - Reference: 720 x 500 mm; Span: 20970 mm; Slope: 0 rad; Roll: 0 rad; IsExternal: no; LoadBearing: yes
Pset_Condition - AssessmentCondition: Empty
Pset_EnvironmentalImpactIndicators - Reference: 720 x 500 mm; sets with these values: 2

# IfcBeam: BB_XX_Betonbalk_ rechthoekig_ center-center_SFB_720 x 500 mm3, BB_XX_Betonbalk, rechthoekig, center-center_SFB:720 x 500 mm:842393
In: K10
PredefinedType: BEAM; Material: BB_Beton_Bestaand
Cpset_Beam - LevelOfAccuracy: in te vullen door Buildwise
IfcRoot - Name: 720 x 500 mm
Qto_BeamBaseQuantities - Length: 22001.4; CrossSectionArea: 0.36; OuterSurfaceArea: 51.1668; GrossSurfaceArea: 51.8868; NetSurfaceArea: 52.2728; GrossVolume: 7.5492; NetVolume: 7.55942
Pset_BeamCommon - Reference: 720 x 500 mm; Span: 22001.4 mm; Slope: 0 rad; Roll: 0 rad; IsExternal: no; LoadBearing: yes
Pset_Condition - AssessmentCondition: Empty
Pset_EnvironmentalImpactIndicators - Reference: 720 x 500 mm; sets with these values: 2

# IfcBeam: BB_XX_Betonbalk_ rechthoekig_ center-center_SFB_900 x 480 mm, BB_XX_Betonbalk, rechthoekig, center-center_SFB:900 x 480 mm:697709
In: 020
PredefinedType: BEAM; Material: BB_Beton_Bestaand
Cpset_Beam - LevelOfAccuracy: in te vullen door Buildwise
IfcRoot - Name: 900 x 480 mm
Qto_BeamBaseQuantities - Length: 11515; CrossSectionArea: 0.432; OuterSurfaceArea: 31.7814; GrossSurfaceArea: 32.6454; NetSurfaceArea: 32.6454; GrossVolume: 4.97448; NetVolume: 4.97448
Pset_BeamCommon - Reference: 900 x 480 mm; Span: 11515 mm; Slope: 0 rad; Roll: 0 rad; IsExternal: no; LoadBearing: yes
Pset_Condition - AssessmentCondition: Empty
Pset_EnvironmentalImpactIndicators - Reference: 900 x 480 mm; sets with these values: 2

# IfcBeam: BB_XX_Betonbalk_ rechthoekig_ center-center_SFB_900 x 480 mm1 (3)
In: 020
PredefinedType: BEAM; Material: BB_Beton_Bestaand
Cpset_Beam - LevelOfAccuracy: in te vullen door Buildwise
IfcRoot - Name: 900 x 480 mm
Qto_BeamBaseQuantities - Length: 11510; CrossSectionArea: 0.432; OuterSurfaceArea: 31.7676; GrossSurfaceArea: 32.6316; NetSurfaceArea: 32.6316; GrossVolume: 4.97232; NetVolume: 4.97232
Pset_BeamCommon - Reference: 900 x 480 mm; Span: 11510 mm; Slope: 0 rad; Roll: 0 rad; IsExternal: no; LoadBearing: yes
Pset_Condition - AssessmentCondition: Empty
Pset_EnvironmentalImpactIndicators - Reference: 900 x 480 mm; sets with these values: 2
Name (BB_XX_Betonbalk, rechthoekig, center-center_SFB:900 x 480 mm:...)
698079
698322
699042

# IfcBeam: IPE-Beams_IPE360 (6)
PredefinedType: BEAM; Material: Metal - Steel - 345 MPa
Cpset_Beam - LevelOfAccuracy: in te vullen door Buildwise
IfcRoot - Name: IPE360
Qto_BeamBaseQuantities - Length: 2660; CrossSectionArea: 0.0069948; OuterSurfaceArea: 3.34928; GrossSurfaceArea: 3.36327; NetSurfaceArea: 3.36327; GrossVolume: 0.0169274; NetVolume: 0.0169274
Pset_BeamCommon - Reference: IPE360; Span: 2660 mm; Slope: 0 rad; Roll: 0 rad; IsExternal: no; LoadBearing: yes
Pset_ConcreteElementGeneral - ConstructionMethod: prefabricated
Pset_Condition - AssessmentCondition: Empty
Pset_EnvironmentalImpactIndicators - Reference: IPE360; sets with these values: 2
Name (IPE-Beams:IPE360:...) | In
34123576 | 000 | Pset_BeamCommon - FireRating: EI60
34126093 | 000 | Pset_BeamCommon - FireRating: EI60
34125954 | 010
34126152 | 010
34125984 | 020
34126183 | 020

# IfcBeam: L64X64X7.9 (2)
In: K10
Description: AGB AB{ABBFAE55-215D-4FDB-9914-EB6F7FB76829}; Material: Metal - Steel - 345 MPa
Cpset_Beam - LevelOfAccuracy: in te vullen door Buildwise
IfcRoot - Name: L64X64X7.9
ProfileProperties - SectionFamily: {ABBFAE55-215D-4FDB-9914-EB6F7FB76829}AGB AB; Section: AGB AB{ABBFAE55-215D-4FDB-9914-EB6F7FB76829}
Qto_BeamBaseQuantities - Length: 1680
Pset_BeamCommon - Reference: L64X64X7.9; Span: 1680 mm; Slope: 0 rad; LoadBearing: yes
Pset_ConcreteElementGeneral - ConstructionMethod: prefabricated
Pset_Condition - AssessmentCondition: Empty
Pset_EnvironmentalImpactIndicators - Reference: L64X64X7.9; sets with these values: 2
Name (M_L-Angle:L64X64X7.9:...) | NetSurfaceArea | NetVolume | Roll (rad) | IsExternal
35456659 | 0.42469 | 0.00156621 | -3.14159 | yes
36149146 | 0.38405 | 0.00141566 | 3.14159 | no

# IfcBeam: VHG_28_HEA Beams_HE140M (4)
In: 040
PredefinedType: BEAM; Material: Metal - Steel - 345 MPa
Cpset_Beam - LevelOfAccuracy: in te vullen door Buildwise
IfcRoot - Name: HE140M
Qto_BeamBaseQuantities - Length: 700; CrossSectionArea: 0.007932; OuterSurfaceArea: 0.6146; GrossSurfaceArea: 0.630464; NetSurfaceArea: 0.630464; GrossVolume: 0.0055524; NetVolume: 0.0055524
Pset_BeamCommon - Reference: HE140M; Span: 700 mm; Slope: 0 rad; Roll: 0 rad; IsExternal: no; LoadBearing: yes
Pset_ConcreteElementGeneral - ConstructionMethod: prefabricated
Pset_Condition - AssessmentCondition: Empty
Pset_EnvironmentalImpactIndicators - Reference: HE140M; sets with these values: 2
Name (VHG_28_HEA Beams:HE140M:...)
33691962
33692445
33692460
33692477

# IfcBeam: VHG_28_HEA Beams_HE200A, VHG_28_HEA Beams:HE200A:33816555
In: 030
PredefinedType: BEAM; Material: Metal - Steel - 345 MPa
Cpset_Beam - LevelOfAccuracy: in te vullen door Buildwise
IfcRoot - Name: HE200A
Qto_BeamBaseQuantities - Length: 2900; NetSurfaceArea: 3.2755; NetVolume: 0.0142873
Pset_BeamCommon - Reference: HE200A; Span: 2900 mm; Slope: 0 rad; Roll: 0 rad; IsExternal: no; LoadBearing: yes; FireRating: EI60
Pset_ConcreteElementGeneral - ConstructionMethod: prefabricated
Pset_Condition - AssessmentCondition: Empty
Pset_EnvironmentalImpactIndicators - Reference: HE200A; sets with these values: 2

# IfcBeam: VHG_28_HEA Beams_HE280M, VHG_28_HEA Beams:HE280M:34051696
In: K20
PredefinedType: BEAM; Material: Metal - Steel - 345 MPa
Cpset_Beam - LevelOfAccuracy: in te vullen door Buildwise
IfcRoot - Name: HE280M
Qto_BeamBaseQuantities - Length: 3301.3; CrossSectionArea: 0.023522; OuterSurfaceArea: 5.72776; GrossSurfaceArea: 5.77481; NetSurfaceArea: 5.77481; GrossVolume: 0.0776533; NetVolume: 0.0776533
Pset_BeamCommon - Reference: HE280M; Span: 3301.3 mm; Slope: 0 rad; Roll: 0 rad; IsExternal: no; LoadBearing: yes
Pset_ConcreteElementGeneral - ConstructionMethod: prefabricated
Pset_Condition - AssessmentCondition: Empty
Pset_EnvironmentalImpactIndicators - Reference: HE280M; sets with these values: 2

# IfcBeam: VHG_28_HEA Beams_HE280M1, VHG_28_HEA Beams:HE280M:34052450
In: K20
PredefinedType: BEAM; Material: Metal - Steel - 345 MPa
Cpset_Beam - LevelOfAccuracy: in te vullen door Buildwise
IfcRoot - Name: HE280M
Qto_BeamBaseQuantities - Length: 3350; CrossSectionArea: 0.023522; OuterSurfaceArea: 5.81225; GrossSurfaceArea: 5.85929; NetSurfaceArea: 5.85929; GrossVolume: 0.0787987; NetVolume: 0.0787987
Pset_BeamCommon - Reference: HE280M; Span: 3350 mm; Slope: 0 rad; Roll: 0 rad; IsExternal: no; LoadBearing: yes
Pset_ConcreteElementGeneral - ConstructionMethod: prefabricated
Pset_Condition - AssessmentCondition: Empty
Pset_EnvironmentalImpactIndicators - Reference: HE280M; sets with these values: 2

# IfcBeam: randbalk01_randbalk01, randbalk01:randbalk01:34102128
In: K10
PredefinedType: BEAM
Cpset_Beam - LevelOfAccuracy: in te vullen door Buildwise
IfcClassificationReference - TDS_link: .\05 As Builtdossier\2. Bouwkunde\2.2. Stabiliteit\2.2.0 technische fiche's\TF S 4.3 A-beton.pdf; TDS_link_extra_1: .\05 As Builtdossier\2. Bouwkunde\2.2. Stabiliteit\2.2.0 technische fiche's\TF S 4.3.2.1 A-wapeningsstaal.pdf
IfcRoot - Name: randbalk01
Qto_BeamBaseQuantities - Length: 448.762; CrossSectionArea: 0.14; OuterSurfaceArea: 0.700069; GrossSurfaceArea: 0.980069; NetSurfaceArea: 93.3349; GrossVolume: 0.0628267; NetVolume: 10.8378
Pset_BeamCommon - Reference: randbalk01; IsExternal: no
Pset_ConcreteElementGeneral - ConstructionMethod: on-site
Pset_Condition - AssessmentCondition: Empty
Pset_EnvironmentalImpactIndicators - Reference: randbalk01; sets with these values: 2

# IfcBeam: randbalk1_randbalk01, randbalk1:randbalk01:34106482
In: K10
PredefinedType: BEAM; Material: BB_Beton_Structureel_In zicht
Cpset_Beam - LevelOfAccuracy: in te vullen door Buildwise
IfcClassificationReference - TDS_link: .\05 As Builtdossier\2. Bouwkunde\2.2. Stabiliteit\2.2.0 technische fiche's\TF S 4.3 A-beton.pdf; TDS_link_extra_1: .\05 As Builtdossier\2. Bouwkunde\2.2. Stabiliteit\2.2.0 technische fiche's\TF S 4.3.2.1 A-wapeningsstaal.pdf
IfcRoot - Name: randbalk01
Qto_BeamBaseQuantities - CrossSectionArea: 13.05; NetSurfaceArea: 49.475; NetVolume: 5.80002
Pset_BeamCommon - Reference: randbalk01; IsExternal: no
Pset_ConcreteElementGeneral - ConstructionMethod: on-site
Pset_Condition - AssessmentCondition: Empty
Pset_EnvironmentalImpactIndicators - Reference: randbalk01; sets with these values: 2

# IfcBeam: randbalk2_randbalk01, randbalk2:randbalk01:34107438
In: K10
PredefinedType: BEAM; Material: BB_Beton_Structureel_In zicht
Cpset_Beam - LevelOfAccuracy: in te vullen door Buildwise
IfcClassificationReference - TDS_link: .\05 As Builtdossier\2. Bouwkunde\2.2. Stabiliteit\2.2.0 technische fiche's\TF S 4.3 A-beton.pdf; TDS_link_extra_1: .\05 As Builtdossier\2. Bouwkunde\2.2. Stabiliteit\2.2.0 technische fiche's\TF S 4.3.2.1 A-wapeningsstaal.pdf
IfcRoot - Name: randbalk01
Qto_BeamBaseQuantities - CrossSectionArea: 6.89507; NetSurfaceArea: 28.9055; NetVolume: 3.56264
Pset_BeamCommon - Reference: randbalk01; IsExternal: no
Pset_ConcreteElementGeneral - ConstructionMethod: on-site
Pset_Condition - AssessmentCondition: Empty
Pset_EnvironmentalImpactIndicators - Reference: randbalk01; sets with these values: 2

# IfcColumn: BB_XX_Kolom_ rechthoekig_ center-center_GTL_170 mm x 905 mm, BB_XX_Kolom, rechthoekig, center-center_GTL:170 mm x 905 mm:34102998
In: K10
PredefinedType: COLUMN; Material: Concrete, C30/37
Cpset_Column - LevelOfAccuracy: in te vullen door Buildwise
IfcBuildingStorey - Level: K10; Base Offset: -100; Top Offset: -1020; Base Level: K10; Top Level: 000
IfcClassificationReference - TDS_link: .\05 As Builtdossier\2. Bouwkunde\2.2. Stabiliteit\2.2.0 technische fiche's\TF S 4.3 A-beton.pdf; TDS_link_extra_1: .\05 As Builtdossier\2. Bouwkunde\2.2. Stabiliteit\2.2.0 technische fiche's\TF S 4.3.2.1 A-wapeningsstaal.pdf
IfcRoot - Name: 170 mm x 905 mm
Qto_ColumnBaseQuantities - Length: 2320; CrossSectionArea: 0.15385; OuterSurfaceArea: 4.988; GrossVolume: 0.356932; NetVolume: 0.356932
Pset_ColumnCommon - Reference: 170 mm x 905 mm; IsExternal: no; LoadBearing: yes
Pset_ConcreteElementGeneral - ConstructionMethod: on-site
Pset_Condition - AssessmentCondition: Empty
Pset_EnvironmentalImpactIndicators - Reference: 170 mm x 905 mm; sets with these values: 2

# IfcColumn: BB_XX_Kolom_ rechthoekig_ center-center_GTL_190 mm x 200 mm, BB_XX_Kolom, rechthoekig, center-center_GTL:190 mm x 200 mm:34130005
In: K20
PredefinedType: COLUMN; Material: Concrete, C30/37
Cpset_Column - LevelOfAccuracy: in te vullen door Buildwise
IfcBuildingStorey - Level: K20; Base Offset: 1000; Top Offset: -1100; Base Level: K20; Top Level: K10
IfcClassificationReference - TDS_link: .\05 As Builtdossier\2. Bouwkunde\2.2. Stabiliteit\2.2.0 technische fiche's\TF S 4.3 A-beton.pdf; TDS_link_extra_1: .\05 As Builtdossier\2. Bouwkunde\2.2. Stabiliteit\2.2.0 technische fiche's\TF S 4.3.2.1 A-wapeningsstaal.pdf
IfcRoot - Name: 190 mm x 200 mm
Qto_ColumnBaseQuantities - Length: 600; CrossSectionArea: 0.038; OuterSurfaceArea: 0.468; GrossVolume: 0.0228; NetVolume: 0.0228
Pset_ColumnCommon - Reference: 190 mm x 200 mm; Slope: 0 rad; IsExternal: no; LoadBearing: yes; FireRating: EI60
Pset_ConcreteElementGeneral - ConstructionMethod: on-site
Pset_Condition - AssessmentCondition: Empty
Pset_EnvironmentalImpactIndicators - Reference: 190 mm x 200 mm; sets with these values: 2

# IfcColumn: BB_XX_Kolom_ rechthoekig_ center-center_GTL_190 mm x 200 mm1, BB_XX_Kolom, rechthoekig, center-center_GTL:190 mm x 200 mm:34129724
In: K10
PredefinedType: COLUMN; Material: Concrete, C30/37
Cpset_Column - LevelOfAccuracy: in te vullen door Buildwise
IfcBuildingStorey - Level: K10; Base Offset: -210; Top Offset: -1500; Base Level: K10; Top Level: 000
IfcClassificationReference - TDS_link: .\05 As Builtdossier\2. Bouwkunde\2.2. Stabiliteit\2.2.0 technische fiche's\TF S 4.3 A-beton.pdf; TDS_link_extra_1: .\05 As Builtdossier\2. Bouwkunde\2.2. Stabiliteit\2.2.0 technische fiche's\TF S 4.3.2.1 A-wapeningsstaal.pdf
IfcRoot - Name: 190 mm x 200 mm
Qto_ColumnBaseQuantities - Length: 1950; CrossSectionArea: 0.038; OuterSurfaceArea: 1.521; GrossVolume: 0.0741; NetVolume: 0.0741
Pset_ColumnCommon - Reference: 190 mm x 200 mm; Slope: 0 rad; IsExternal: no; LoadBearing: yes; FireRating: EI60
Pset_ConcreteElementGeneral - ConstructionMethod: on-site
Pset_Condition - AssessmentCondition: Empty
Pset_EnvironmentalImpactIndicators - Reference: 190 mm x 200 mm; sets with these values: 2

# IfcColumn: BB_XX_Kolom_ rechthoekig_ center-center_GTL_190 mm x 200 mm3, BB_XX_Kolom, rechthoekig, center-center_GTL:190 mm x 200 mm:34131670
In: 000
PredefinedType: COLUMN; Material: Concrete, C30/37
Cpset_Column - LevelOfAccuracy: in te vullen door Buildwise
IfcBuildingStorey - Level: 000; Base Offset: -400; Top Offset: -800; Base Level: 000; Top Level: 010
IfcClassificationReference - TDS_link: .\05 As Builtdossier\2. Bouwkunde\2.2. Stabiliteit\2.2.0 technische fiche's\TF S 4.3 A-beton.pdf; TDS_link_extra_1: .\05 As Builtdossier\2. Bouwkunde\2.2. Stabiliteit\2.2.0 technische fiche's\TF S 4.3.2.1 A-wapeningsstaal.pdf
IfcRoot - Name: 190 mm x 200 mm
Qto_ColumnBaseQuantities - Length: 3200; CrossSectionArea: 0.038; OuterSurfaceArea: 2.496; GrossVolume: 0.1216; NetVolume: 0.1216
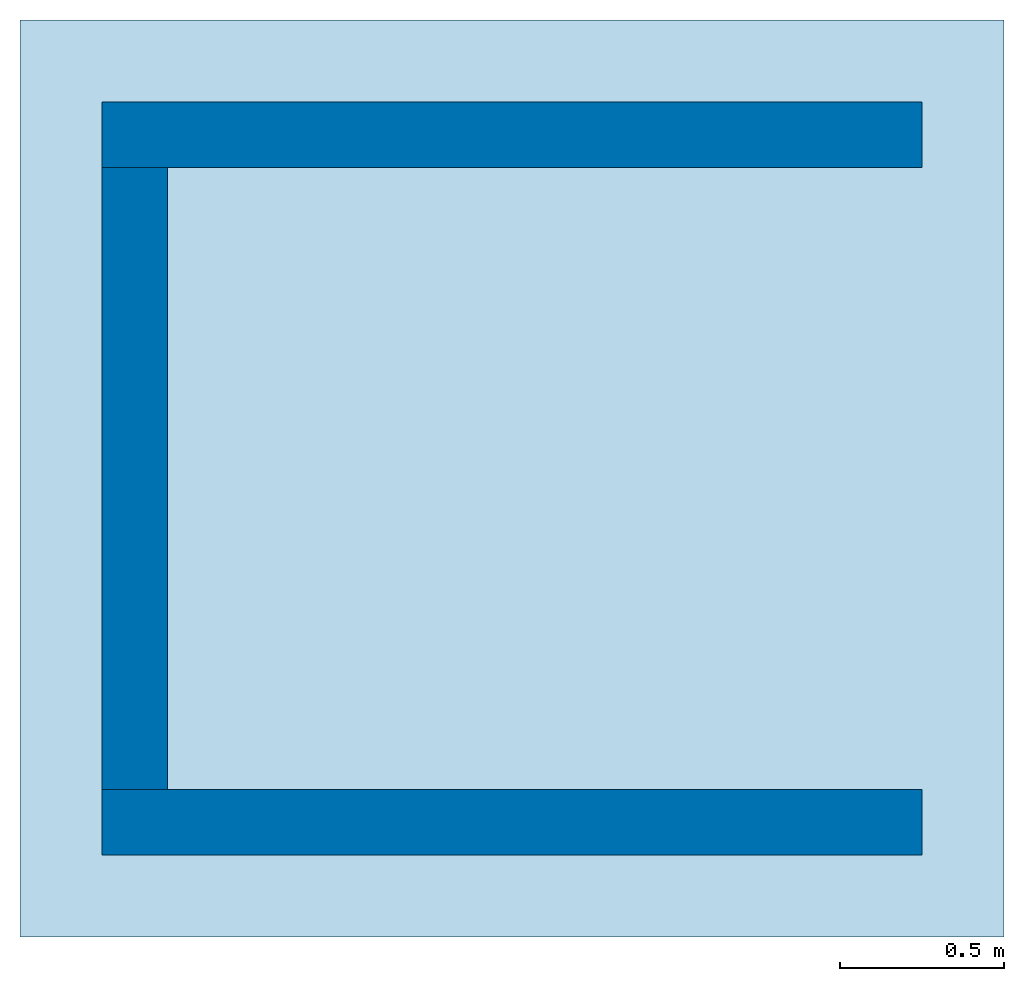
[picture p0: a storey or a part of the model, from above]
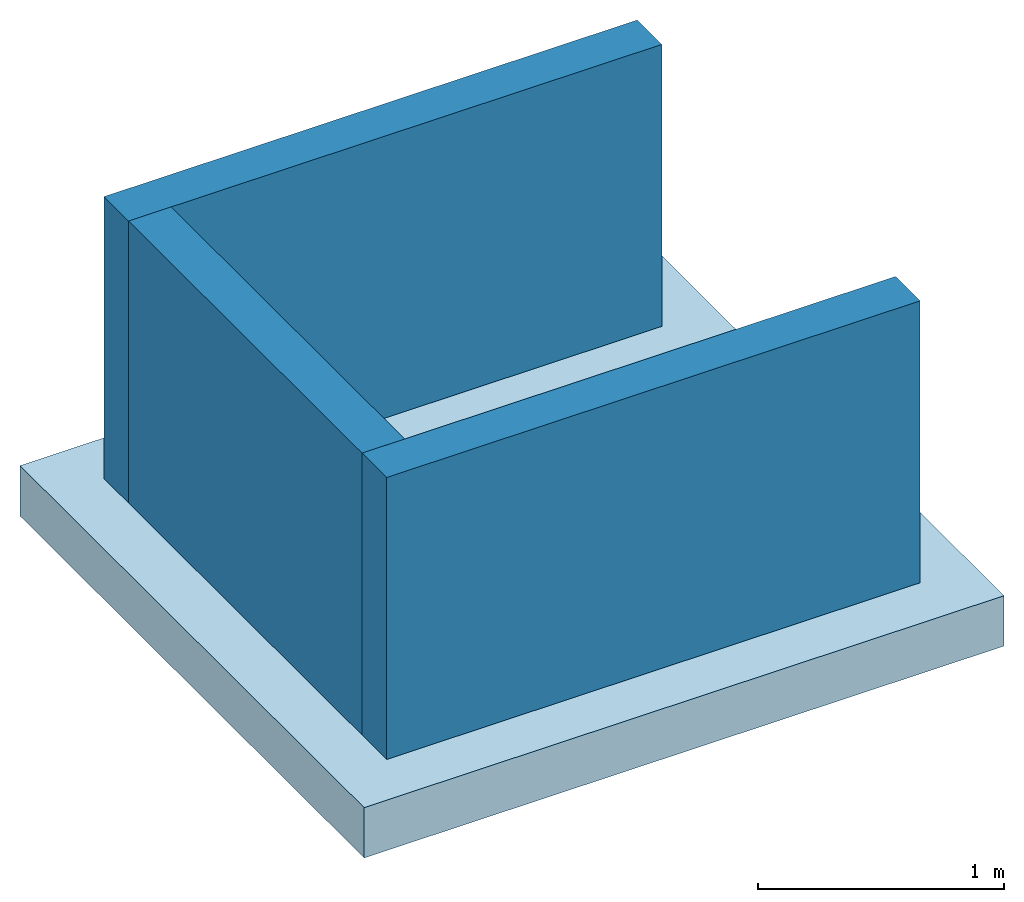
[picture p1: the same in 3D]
Properties of the parts of a building model (IFC4X3_ADD2), part 12 of 28

# IfcColumn: BB_XX_Kolom_ rechthoekig_ center-center_GTL_190 mm x 200 mm3, BB_XX_Kolom, rechthoekig, center-center_GTL:190 mm x 200 mm:34131670
Pset_ColumnCommon - Reference: 190 mm x 200 mm; Slope: 0 rad; IsExternal: no; LoadBearing: yes; FireRating: EI60
Pset_ConcreteElementGeneral - ConstructionMethod: on-site
Pset_Condition - AssessmentCondition: Empty
Pset_EnvironmentalImpactIndicators - Reference: 190 mm x 200 mm; sets with these values: 2

# IfcColumn: BB_XX_Kolom_ rechthoekig_ center-center_GTL_190 mm x 200 mm5, BB_XX_Kolom, rechthoekig, center-center_GTL:190 mm x 200 mm:34132445
In: 010
PredefinedType: COLUMN; Material: Concrete, C30/37
Cpset_Column - LevelOfAccuracy: in te vullen door Buildwise
IfcBuildingStorey - Level: 010; Base Offset: -200; Top Offset: -1200; Base Level: 010; Top Level: 020
IfcClassificationReference - TDS_link: .\05 As Builtdossier\2. Bouwkunde\2.2. Stabiliteit\2.2.0 technische fiche's\TF S 4.3 A-beton.pdf; TDS_link_extra_1: .\05 As Builtdossier\2. Bouwkunde\2.2. Stabiliteit\2.2.0 technische fiche's\TF S 4.3.2.1 A-wapeningsstaal.pdf
IfcRoot - Name: 190 mm x 200 mm
Qto_ColumnBaseQuantities - Length: 2600; CrossSectionArea: 0.038; OuterSurfaceArea: 2.028; GrossVolume: 0.0988; NetVolume: 0.0988
Pset_ColumnCommon - Reference: 190 mm x 200 mm; Slope: 0 rad; IsExternal: no; LoadBearing: yes; FireRating: EI60
Pset_ConcreteElementGeneral - ConstructionMethod: on-site
Pset_Condition - AssessmentCondition: Empty
Pset_EnvironmentalImpactIndicators - Reference: 190 mm x 200 mm; sets with these values: 2

# IfcColumn: BB_XX_Kolom_ rechthoekig_ center-center_GTL_190 mm x 355 mm, BB_XX_Kolom, rechthoekig, center-center_GTL:190 mm x 355 mm:34194904
In: K20
PredefinedType: COLUMN; Material: Concrete, C30/37
Cpset_Column - LevelOfAccuracy: in te vullen door Buildwise
IfcBuildingStorey - Level: K20; Base Offset: -450; Top Offset: -1020; Base Level: K20; Top Level: 000
IfcClassificationReference - TDS_link: .\05 As Builtdossier\2. Bouwkunde\2.2. Stabiliteit\2.2.0 technische fiche's\TF S 4.3 A-beton.pdf; TDS_link_extra_1: .\05 As Builtdossier\2. Bouwkunde\2.2. Stabiliteit\2.2.0 technische fiche's\TF S 4.3.2.1 A-wapeningsstaal.pdf
IfcRoot - Name: 190 mm x 355 mm
Qto_ColumnBaseQuantities - Length: 5370; CrossSectionArea: 0.06745; OuterSurfaceArea: 5.8533; GrossVolume: 0.362206; NetVolume: 0.362206
Pset_ColumnCommon - Reference: 190 mm x 355 mm; IsExternal: no; LoadBearing: yes
Pset_ConcreteElementGeneral - ConstructionMethod: on-site
Pset_Condition - AssessmentCondition: Empty
Pset_EnvironmentalImpactIndicators - Reference: 190 mm x 355 mm; sets with these values: 2

# IfcColumn: BB_XX_Kolom_ rechthoekig_ center-center_GTL_190 mm x 500 mm, BB_XX_Kolom, rechthoekig, center-center_GTL:190 mm x 500 mm:34109902
In: K20
PredefinedType: COLUMN; Material: Concrete, C30/37
Cpset_Column - LevelOfAccuracy: in te vullen door Buildwise
IfcBuildingStorey - Level: K20; Base Offset: 0; Top Offset: -600; Base Level: K20; Top Level: K10
IfcClassificationReference - TDS_link: .\05 As Builtdossier\2. Bouwkunde\2.2. Stabiliteit\2.2.0 technische fiche's\TF S 4.3 A-beton.pdf; TDS_link_extra_1: .\05 As Builtdossier\2. Bouwkunde\2.2. Stabiliteit\2.2.0 technische fiche's\TF S 4.3.2.1 A-wapeningsstaal.pdf
IfcRoot - Name: 190 mm x 500 mm
Qto_ColumnBaseQuantities - Length: 2100; CrossSectionArea: 0.095; OuterSurfaceArea: 2.898; GrossVolume: 0.1995; NetVolume: 0.1995
Pset_ColumnCommon - Reference: 190 mm x 500 mm; Slope: 0 rad; IsExternal: no; LoadBearing: yes; FireRating: EI60
Pset_ConcreteElementGeneral - ConstructionMethod: on-site
Pset_Condition - AssessmentCondition: Empty
Pset_EnvironmentalImpactIndicators - Reference: 190 mm x 500 mm; sets with these values: 2

# IfcColumn: BB_XX_Kolom_ rechthoekig_ center-center_GTL_190 mm x 500 mm1, BB_XX_Kolom, rechthoekig, center-center_GTL:190 mm x 500 mm:34122965
In: K10
PredefinedType: COLUMN; Material: Concrete, C30/37
Cpset_Column - LevelOfAccuracy: in te vullen door Buildwise
IfcBuildingStorey - Level: K10; Base Offset: 0; Top Offset: -1050; Base Level: K10; Top Level: 000
IfcClassificationReference - TDS_link: .\05 As Builtdossier\2. Bouwkunde\2.2. Stabiliteit\2.2.0 technische fiche's\TF S 4.3 A-beton.pdf; TDS_link_extra_1: .\05 As Builtdossier\2. Bouwkunde\2.2. Stabiliteit\2.2.0 technische fiche's\TF S 4.3.2.1 A-wapeningsstaal.pdf
IfcRoot - Name: 190 mm x 500 mm
Qto_ColumnBaseQuantities - Length: 2190; CrossSectionArea: 0.095; OuterSurfaceArea: 3.0222; GrossVolume: 0.20805; NetVolume: 0.20805
Pset_ColumnCommon - Reference: 190 mm x 500 mm; Slope: 0 rad; IsExternal: no; LoadBearing: yes; FireRating: EI60
Pset_ConcreteElementGeneral - ConstructionMethod: on-site
Pset_Condition - AssessmentCondition: Empty
Pset_EnvironmentalImpactIndicators - Reference: 190 mm x 500 mm; sets with these values: 2

# IfcColumn: BB_XX_Kolom_ rechthoekig_ center-center_GTL_190 mm x 500 mm11, BB_XX_Kolom, rechthoekig, center-center_GTL:190 mm x 500 mm:34132443
In: 010
PredefinedType: COLUMN; Material: Concrete, C30/37
Cpset_Column - LevelOfAccuracy: in te vullen door Buildwise
IfcBuildingStorey - Level: 010; Base Offset: -200; Top Offset: -1200; Base Level: 010; Top Level: 020
IfcClassificationReference - TDS_link: .\05 As Builtdossier\2. Bouwkunde\2.2. Stabiliteit\2.2.0 technische fiche's\TF S 4.3 A-beton.pdf; TDS_link_extra_1: .\05 As Builtdossier\2. Bouwkunde\2.2. Stabiliteit\2.2.0 technische fiche's\TF S 4.3.2.1 A-wapeningsstaal.pdf
IfcRoot - Name: 190 mm x 500 mm
Qto_ColumnBaseQuantities - Length: 2600; CrossSectionArea: 0.095; OuterSurfaceArea: 3.588; GrossVolume: 0.247; NetVolume: 0.247
Pset_ColumnCommon - Reference: 190 mm x 500 mm; Slope: 0 rad; IsExternal: no; LoadBearing: yes; FireRating: EI60
Pset_ConcreteElementGeneral - ConstructionMethod: on-site
Pset_Condition - AssessmentCondition: Empty
Pset_EnvironmentalImpactIndicators - Reference: 190 mm x 500 mm; sets with these values: 2

# IfcColumn: BB_XX_Kolom_ rechthoekig_ center-center_GTL_190 mm x 500 mm3, BB_XX_Kolom, rechthoekig, center-center_GTL:190 mm x 500 mm:34129051
In: K10
PredefinedType: COLUMN; Material: Concrete, C30/37
Cpset_Column - LevelOfAccuracy: in te vullen door Buildwise
IfcBuildingStorey - Level: K10; Base Offset: 0; Top Offset: -1500; Base Level: K10; Top Level: 000
IfcClassificationReference - TDS_link: .\05 As Builtdossier\2. Bouwkunde\2.2. Stabiliteit\2.2.0 technische fiche's\TF S 4.3 A-beton.pdf; TDS_link_extra_1: .\05 As Builtdossier\2. Bouwkunde\2.2. Stabiliteit\2.2.0 technische fiche's\TF S 4.3.2.1 A-wapeningsstaal.pdf
IfcRoot - Name: 190 mm x 500 mm
Qto_ColumnBaseQuantities - Length: 1740; CrossSectionArea: 0.095; OuterSurfaceArea: 2.4012; GrossVolume: 0.1653; NetVolume: 0.1653
Pset_ColumnCommon - Reference: 190 mm x 500 mm; Slope: 0 rad; IsExternal: no; LoadBearing: yes; FireRating: EI60
Pset_ConcreteElementGeneral - ConstructionMethod: on-site
Pset_Condition - AssessmentCondition: Empty
Pset_EnvironmentalImpactIndicators - Reference: 190 mm x 500 mm; sets with these values: 2

# IfcColumn: BB_XX_Kolom_ rechthoekig_ center-center_GTL_190 mm x 500 mm5, BB_XX_Kolom, rechthoekig, center-center_GTL:190 mm x 500 mm:34131666
In: 000
PredefinedType: COLUMN; Material: Concrete, C30/37
Cpset_Column - LevelOfAccuracy: in te vullen door Buildwise
IfcBuildingStorey - Level: 000; Base Offset: -400; Top Offset: -930; Base Level: 000; Top Level: 010
IfcClassificationReference - TDS_link: .\05 As Builtdossier\2. Bouwkunde\2.2. Stabiliteit\2.2.0 technische fiche's\TF S 4.3 A-beton.pdf; TDS_link_extra_1: .\05 As Builtdossier\2. Bouwkunde\2.2. Stabiliteit\2.2.0 technische fiche's\TF S 4.3.2.1 A-wapeningsstaal.pdf
IfcRoot - Name: 190 mm x 500 mm
Qto_ColumnBaseQuantities - Length: 3070; CrossSectionArea: 0.095; OuterSurfaceArea: 4.2366; GrossVolume: 0.29165; NetVolume: 0.29165
Pset_ColumnCommon - Reference: 190 mm x 500 mm; Slope: 0 rad; IsExternal: no; LoadBearing: yes; FireRating: EI60
Pset_ConcreteElementGeneral - ConstructionMethod: on-site
Pset_Condition - AssessmentCondition: Empty
Pset_EnvironmentalImpactIndicators - Reference: 190 mm x 500 mm; sets with these values: 2

# IfcColumn: BB_XX_Kolom_ rechthoekig_ center-center_GTL_190 mm x 500 mm7, BB_XX_Kolom, rechthoekig, center-center_GTL:190 mm x 500 mm:34131668
In: 000
PredefinedType: COLUMN; Material: Concrete, C30/37
Cpset_Column - LevelOfAccuracy: in te vullen door Buildwise
IfcBuildingStorey - Level: 000; Base Offset: -400; Top Offset: -930; Base Level: 000; Top Level: 010
IfcClassificationReference - TDS_link: .\05 As Builtdossier\2. Bouwkunde\2.2. Stabiliteit\2.2.0 technische fiche's\TF S 4.3 A-beton.pdf; TDS_link_extra_1: .\05 As Builtdossier\2. Bouwkunde\2.2. Stabiliteit\2.2.0 technische fiche's\TF S 4.3.2.1 A-wapeningsstaal.pdf
IfcRoot - Name: 190 mm x 500 mm
Qto_ColumnBaseQuantities - Length: 3070; CrossSectionArea: 0.095; OuterSurfaceArea: 4.2366; GrossVolume: 0.29165; NetVolume: 0.29165
Pset_ColumnCommon - Reference: 190 mm x 500 mm; Slope: 0 rad; IsExternal: no; LoadBearing: yes; FireRating: EI60
Pset_ConcreteElementGeneral - ConstructionMethod: on-site
Pset_Condition - AssessmentCondition: Empty
Pset_EnvironmentalImpactIndicators - Reference: 190 mm x 500 mm; sets with these values: 2

# IfcColumn: BB_XX_Kolom_ rechthoekig_ center-center_GTL_190 mm x 500 mm9, BB_XX_Kolom, rechthoekig, center-center_GTL:190 mm x 500 mm:34132441
In: 010
PredefinedType: COLUMN; Material: Concrete, C30/37
Cpset_Column - LevelOfAccuracy: in te vullen door Buildwise
IfcBuildingStorey - Level: 010; Base Offset: -200; Top Offset: -1200; Base Level: 010; Top Level: 020
IfcClassificationReference - TDS_link: .\05 As Builtdossier\2. Bouwkunde\2.2. Stabiliteit\2.2.0 technische fiche's\TF S 4.3 A-beton.pdf; TDS_link_extra_1: .\05 As Builtdossier\2. Bouwkunde\2.2. Stabiliteit\2.2.0 technische fiche's\TF S 4.3.2.1 A-wapeningsstaal.pdf
IfcRoot - Name: 190 mm x 500 mm
Qto_ColumnBaseQuantities - Length: 2600; CrossSectionArea: 0.095; OuterSurfaceArea: 3.588; GrossVolume: 0.247; NetVolume: 0.247
Pset_ColumnCommon - Reference: 190 mm x 500 mm; Slope: 0 rad; IsExternal: no; LoadBearing: yes; FireRating: EI60
Pset_ConcreteElementGeneral - ConstructionMethod: on-site
Pset_Condition - AssessmentCondition: Empty
Pset_EnvironmentalImpactIndicators - Reference: 190 mm x 500 mm; sets with these values: 2

# IfcColumn: BB_XX_Kolom_ rechthoekig_ center-center_GTL_190 mm x 750 mm, BB_XX_Kolom, rechthoekig, center-center_GTL:190 mm x 750 mm:34055228
In: K20
PredefinedType: COLUMN; Material: Concrete, C30/37
Cpset_Column - LevelOfAccuracy: in te vullen door Buildwise
IfcBuildingStorey - Level: K20; Base Offset: 0; Top Offset: -500; Base Level: K20; Top Level: K10
IfcClassificationReference - TDS_link: .\05 As Builtdossier\2. Bouwkunde\2.2. Stabiliteit\2.2.0 technische fiche's\TF S 4.3 A-beton.pdf; TDS_link_extra_1: .\05 As Builtdossier\2. Bouwkunde\2.2. Stabiliteit\2.2.0 technische fiche's\TF S 4.3.2.1 A-wapeningsstaal.pdf
IfcRoot - Name: 190 mm x 750 mm
Qto_ColumnBaseQuantities - Length: 2200; CrossSectionArea: 0.1425; OuterSurfaceArea: 4.136; GrossVolume: 0.3135; NetVolume: 0.3135
Pset_ColumnCommon - Reference: 190 mm x 750 mm; Slope: 0 rad; IsExternal: no; LoadBearing: yes; FireRating: EI60
Pset_ConcreteElementGeneral - ConstructionMethod: on-site
Pset_Condition - AssessmentCondition: Empty
Pset_EnvironmentalImpactIndicators - Reference: 190 mm x 750 mm; sets with these values: 2

# IfcColumn: BB_XX_Kolom_ rechthoekig_ center-center_GTL_190 mm x 750 mm1, BB_XX_Kolom, rechthoekig, center-center_GTL:190 mm x 750 mm:34055631
In: K20
PredefinedType: COLUMN; Material: Concrete, C30/37
Cpset_Column - LevelOfAccuracy: in te vullen door Buildwise
IfcBuildingStorey - Level: K20; Base Offset: 0; Top Offset: -500; Base Level: K20; Top Level: K10
IfcClassificationReference - TDS_link: .\05 As Builtdossier\2. Bouwkunde\2.2. Stabiliteit\2.2.0 technische fiche's\TF S 4.3 A-beton.pdf; TDS_link_extra_1: .\05 As Builtdossier\2. Bouwkunde\2.2. Stabiliteit\2.2.0 technische fiche's\TF S 4.3.2.1 A-wapeningsstaal.pdf
IfcRoot - Name: 190 mm x 750 mm
Qto_ColumnBaseQuantities - Length: 2200; CrossSectionArea: 0.1425; OuterSurfaceArea: 4.136; GrossVolume: 0.3135; NetVolume: 0.3135
Pset_ColumnCommon - Reference: 190 mm x 750 mm; Slope: 0 rad; IsExternal: no; LoadBearing: yes; FireRating: EI60
Pset_ConcreteElementGeneral - ConstructionMethod: on-site
Pset_Condition - AssessmentCondition: Empty
Pset_EnvironmentalImpactIndicators - Reference: 190 mm x 750 mm; sets with these values: 2

# IfcColumn: BB_XX_Kolom_ rechthoekig_ center-center_GTL_200 mm x 200 mm, BB_XX_Kolom, rechthoekig, center-center_GTL:200 mm x 200 mm:929818
In: K10
PredefinedType: COLUMN; Material: BB_Beton_Bestaand
Cpset_Column - LevelOfAccuracy: in te vullen door Buildwise
IfcBuildingStorey - Level: K10; Base Offset: -200; Top Offset: -920; Base Level: K10; Top Level: 000
IfcRoot - Name: 200 mm x 200 mm
Qto_ColumnBaseQuantities - CrossSectionArea: 1.04258; NetVolume: 0.0997212
Pset_ColumnCommon - Reference: 200 mm x 200 mm; Slope: 0 rad; IsExternal: no; LoadBearing: yes
Pset_Condition - AssessmentCondition: Empty
Pset_EnvironmentalImpactIndicators - Reference: 200 mm x 200 mm; sets with these values: 2

# IfcColumn: BB_XX_Kolom_ rechthoekig_ center-center_GTL_200 mm x 200 mm1, BB_XX_Kolom, rechthoekig, center-center_GTL:200 mm x 200 mm:1862822
In: K10
PredefinedType: COLUMN; Material: BB_Beton_Bestaand
Cpset_Column - LevelOfAccuracy: in te vullen door Buildwise
IfcBuildingStorey - Level: K10; Base Offset: -200; Top Offset: -920; Base Level: K10; Top Level: 000
IfcRoot - Name: 200 mm x 200 mm
Qto_ColumnBaseQuantities - CrossSectionArea: 1.04785; NetVolume: 0.100776
Pset_ColumnCommon - Reference: 200 mm x 200 mm; Slope: 0 rad; IsExternal: no; LoadBearing: yes
Pset_Condition - AssessmentCondition: Empty
Pset_EnvironmentalImpactIndicators - Reference: 200 mm x 200 mm; sets with these values: 2

# IfcColumn: BB_XX_Kolom_ rechthoekig_ center-center_GTL_200 mm x 200 mm11, BB_XX_Kolom, rechthoekig, center-center_GTL:200 mm x 200 mm:1863973
In: 010
PredefinedType: COLUMN; Material: BB_Beton_Bestaand
Cpset_Column - LevelOfAccuracy: in te vullen door Buildwise
IfcBuildingStorey - Level: 010; Base Offset: -200; Top Offset: -200; Base Level: 010; Top Level: 020
IfcRoot - Name: 200 mm x 200 mm
Qto_ColumnBaseQuantities - Length: 3600; CrossSectionArea: 0.04; OuterSurfaceArea: 2.88; GrossVolume: 0.144; NetVolume: 0.144
Pset_ColumnCommon - Reference: 200 mm x 200 mm; Slope: 0 rad; IsExternal: no; LoadBearing: yes
Pset_Condition - AssessmentCondition: Empty
Pset_EnvironmentalImpactIndicators - Reference: 200 mm x 200 mm; sets with these values: 2

# IfcColumn: BB_XX_Kolom_ rechthoekig_ center-center_GTL_200 mm x 200 mm13, BB_XX_Kolom, rechthoekig, center-center_GTL:200 mm x 200 mm:1863975
In: 010
PredefinedType: COLUMN; Material: BB_Beton_Bestaand
Cpset_Column - LevelOfAccuracy: in te vullen door Buildwise
IfcBuildingStorey - Level: 010; Base Offset: -200; Top Offset: -200; Base Level: 010; Top Level: 020
IfcRoot - Name: 200 mm x 200 mm
Qto_ColumnBaseQuantities - Length: 3600; CrossSectionArea: 0.04; OuterSurfaceArea: 2.88; GrossVolume: 0.144; NetVolume: 0.144
Pset_ColumnCommon - Reference: 200 mm x 200 mm; Slope: 0 rad; IsExternal: no; LoadBearing: yes
Pset_Condition - AssessmentCondition: Empty
Pset_EnvironmentalImpactIndicators - Reference: 200 mm x 200 mm; sets with these values: 2

# IfcColumn: BB_XX_Kolom_ rechthoekig_ center-center_GTL_200 mm x 200 mm15 (3)
In: 020
PredefinedType: COLUMN; Material: BB_Beton_Bestaand
Cpset_Column - LevelOfAccuracy: in te vullen door Buildwise
IfcBuildingStorey - Level: 020; Base Offset: -200; Top Offset: -200; Base Level: 020; Top Level: 030
IfcRoot - Name: 200 mm x 200 mm
Qto_ColumnBaseQuantities - Length: 3600; CrossSectionArea: 0.04; OuterSurfaceArea: 2.88; GrossVolume: 0.144; NetVolume: 0.144
Pset_ColumnCommon - Reference: 200 mm x 200 mm; IsExternal: no; LoadBearing: yes
Pset_Condition - AssessmentCondition: Empty
Pset_EnvironmentalImpactIndicators - Reference: 200 mm x 200 mm; sets with these values: 2
Name (BB_XX_Kolom, rechthoekig, center-center_GTL:200 mm x 200 mm:...)
695717
1863980
1863982

# IfcColumn: BB_XX_Kolom_ rechthoekig_ center-center_GTL_200 mm x 200 mm3, BB_XX_Kolom, rechthoekig, center-center_GTL:200 mm x 200 mm:1862826
In: K10
PredefinedType: COLUMN; Material: BB_Beton_Bestaand
Cpset_Column - LevelOfAccuracy: in te vullen door Buildwise
IfcBuildingStorey - Level: K10; Base Offset: -200; Top Offset: -920; Base Level: K10; Top Level: 000
IfcRoot - Name: 200 mm x 200 mm
Qto_ColumnBaseQuantities - CrossSectionArea: 1.03956; NetVolume: 0.0991176
Pset_ColumnCommon - Reference: 200 mm x 200 mm; Slope: 0 rad; IsExternal: no; LoadBearing: yes
Pset_Condition - AssessmentCondition: Empty
Pset_EnvironmentalImpactIndicators - Reference: 200 mm x 200 mm; sets with these values: 2

# IfcColumn: BB_XX_Kolom_ rechthoekig_ center-center_GTL_200 mm x 200 mm5, BB_XX_Kolom, rechthoekig, center-center_GTL:200 mm x 200 mm:473017
In: 000
PredefinedType: COLUMN; Material: BB_Beton_Bestaand
Cpset_Column - LevelOfAccuracy: in te vullen door Buildwise
IfcBuildingStorey - Level: 000; Base Offset: -200; Top Offset: -200; Base Level: 000; Top Level: 010
IfcRoot - Name: 200 mm x 200 mm
Qto_ColumnBaseQuantities - Length: 3600; CrossSectionArea: 0.04; OuterSurfaceArea: 2.88; GrossVolume: 0.144; NetVolume: 0.144
Pset_ColumnCommon - Reference: 200 mm x 200 mm; Slope: 0 rad; IsExternal: no; LoadBearing: yes
Pset_Condition - AssessmentCondition: Empty
Pset_EnvironmentalImpactIndicators - Reference: 200 mm x 200 mm; sets with these values: 2

# IfcColumn: BB_XX_Kolom_ rechthoekig_ center-center_GTL_200 mm x 200 mm7 (2)
In: 000
PredefinedType: COLUMN; Material: BB_Beton_Bestaand
Cpset_Column - LevelOfAccuracy: in te vullen door Buildwise
IfcBuildingStorey - Level: 000; Base Offset: -200; Top Offset: -200; Base Level: 000; Top Level: 010
IfcRoot - Name: 200 mm x 200 mm
Qto_ColumnBaseQuantities - Length: 3600; CrossSectionArea: 0.04; OuterSurfaceArea: 2.88; GrossVolume: 0.144; NetVolume: 0.144
Pset_ColumnCommon - Reference: 200 mm x 200 mm; IsExternal: no; LoadBearing: yes
Pset_Condition - AssessmentCondition: Empty
Pset_EnvironmentalImpactIndicators - Reference: 200 mm x 200 mm; sets with these values: 2
Name (BB_XX_Kolom, rechthoekig, center-center_GTL:200 mm x 200 mm:...)
473071
1857744

# IfcColumn: BB_XX_Kolom_ rechthoekig_ center-center_GTL_200 mm x 200 mm9, BB_XX_Kolom, rechthoekig, center-center_GTL:200 mm x 200 mm:646069
In: 010
PredefinedType: COLUMN; Material: BB_Beton_Bestaand
Cpset_Column - LevelOfAccuracy: in te vullen door Buildwise
IfcBuildingStorey - Level: 010; Base Offset: -200; Top Offset: -200; Base Level: 010; Top Level: 020
IfcRoot - Name: 200 mm x 200 mm
Qto_ColumnBaseQuantities - Length: 3600; CrossSectionArea: 0.04; OuterSurfaceArea: 2.88; GrossVolume: 0.144; NetVolume: 0.144
Pset_ColumnCommon - Reference: 200 mm x 200 mm; Slope: 0 rad; IsExternal: no; LoadBearing: yes
Pset_Condition - AssessmentCondition: Empty
Pset_EnvironmentalImpactIndicators - Reference: 200 mm x 200 mm; sets with these values: 2

# IfcColumn: BB_XX_Kolom_ rechthoekig_ center-center_GTL_200 mm x 400 mm, BB_XX_Kolom, rechthoekig, center-center_GTL:200 mm x 400 mm:827320
In: K10
PredefinedType: COLUMN; Material: <Unnamed>
Cpset_Column - LevelOfAccuracy: in te vullen door Buildwise
IfcBuildingStorey - Level: K10; Base Offset: 0; Top Offset: -900; Base Level: K10; Top Level: 000
IfcRoot - Name: 200 mm x 400 mm
Qto_ColumnBaseQuantities - Length: 2340; CrossSectionArea: 0.08; OuterSurfaceArea: 2.808; GrossVolume: 0.1872; NetVolume: 0.1872
Pset_ColumnCommon - Reference: 200 mm x 400 mm; IsExternal: no; LoadBearing: yes
Pset_Condition - AssessmentCondition: Empty
Pset_EnvironmentalImpactIndicators - Reference: 200 mm x 400 mm; sets with these values: 2

# IfcColumn: BB_XX_Kolom_ rechthoekig_ center-center_GTL_200 mm x 400 mm1, BB_XX_Kolom, rechthoekig, center-center_GTL:200 mm x 400 mm:834891
In: K10
PredefinedType: COLUMN; Material: <Unnamed>
Cpset_Column - LevelOfAccuracy: in te vullen door Buildwise
IfcBuildingStorey - Level: K10; Base Offset: 0; Top Offset: -900; Base Level: K10; Top Level: 000
IfcRoot - Name: 200 mm x 400 mm
Qto_ColumnBaseQuantities - Length: 2340; CrossSectionArea: 0.08; OuterSurfaceArea: 2.808; GrossVolume: 0.1872; NetVolume: 0.1872
Pset_ColumnCommon - Reference: 200 mm x 400 mm; Slope: 0 rad; IsExternal: no; LoadBearing: yes
Pset_Condition - AssessmentCondition: Empty
Pset_EnvironmentalImpactIndicators - Reference: 200 mm x 400 mm; sets with these values: 2

# IfcColumn: BB_XX_Kolom_ rechthoekig_ center-center_GTL_200 mm x 500 mm, BB_XX_Kolom, rechthoekig, center-center_GTL:200 mm x 500 mm:34129382
In: K20
PredefinedType: COLUMN; Material: <Unnamed>
Cpset_Column - LevelOfAccuracy: in te vullen door Buildwise
IfcBuildingStorey - Level: K20; Base Offset: 1000; Top Offset: -1100; Base Level: K20; Top Level: K10
IfcClassificationReference - TDS_link: .\05 As Builtdossier\2. Bouwkunde\2.2. Stabiliteit\2.2.0 technische fiche's\TF S 4.3 A-beton.pdf; TDS_link_extra_1: .\05 As Builtdossier\2. Bouwkunde\2.2. Stabiliteit\2.2.0 technische fiche's\TF S 4.3.2.1 A-wapeningsstaal.pdf
IfcRoot - Name: 200 mm x 500 mm
Qto_ColumnBaseQuantities - Length: 600; CrossSectionArea: 0.1; OuterSurfaceArea: 0.84; GrossVolume: 0.06; NetVolume: 0.06
Pset_ColumnCommon - Reference: 200 mm x 500 mm; IsExternal: no; LoadBearing: yes; FireRating: EI60
Pset_ConcreteElementGeneral - ConstructionMethod: on-site
Pset_Condition - AssessmentCondition: Empty
Pset_EnvironmentalImpactIndicators - Reference: 200 mm x 500 mm; sets with these values: 2

# IfcColumn: BB_XX_Kolom_ rechthoekig_ center-center_GTL_200 mm x 600 mm, BB_XX_Kolom, rechthoekig, center-center_GTL:200 mm x 600 mm:34217105
In: 040
PredefinedType: COLUMN; Material: <Unnamed>
Cpset_Column - LevelOfAccuracy: in te vullen door Buildwise
IfcBuildingStorey - Level: 040; Base Offset: -200; Top Offset: -250; Base Level: 040; Top Level: 050
IfcClassificationReference - TDS_link: .\05 As Builtdossier\2. Bouwkunde\2.2. Stabiliteit\2.2.0 technische fiche's\TF S 4.3 A-beton.pdf; TDS_link_extra_1: .\05 As Builtdossier\2. Bouwkunde\2.2. Stabiliteit\2.2.0 technische fiche's\TF S 4.3.2.1 A-wapeningsstaal.pdf
IfcElement - Tag: C 402; Mark: C 402
IfcRoot - Name: 200 mm x 600 mm
Qto_ColumnBaseQuantities - Length: 2600; CrossSectionArea: 0.12; OuterSurfaceArea: 4.16; GrossVolume: 0.312; NetVolume: 0.312
Pset_ColumnCommon - Reference: 200 mm x 600 mm; Slope: 0 rad; IsExternal: no; LoadBearing: yes
Pset_ConcreteElementGeneral - ConstructionMethod: on-site
Pset_Condition - AssessmentCondition: Empty
Pset_EnvironmentalImpactIndicators - Reference: 200 mm x 600 mm; sets with these values: 2

# IfcColumn: BB_XX_Kolom_ rechthoekig_ center-center_GTL_200 mm x 600 mm1, BB_XX_Kolom, rechthoekig, center-center_GTL:200 mm x 600 mm:34218208
In: 040
PredefinedType: COLUMN; Material: <Unnamed>
Cpset_Column - LevelOfAccuracy: in te vullen door Buildwise
IfcBuildingStorey - Level: 040; Base Offset: -200; Top Offset: -250; Base Level: 040; Top Level: 050
IfcClassificationReference - TDS_link: .\05 As Builtdossier\2. Bouwkunde\2.2. Stabiliteit\2.2.0 technische fiche's\TF S 4.3 A-beton.pdf; TDS_link_extra_1: .\05 As Builtdossier\2. Bouwkunde\2.2. Stabiliteit\2.2.0 technische fiche's\TF S 4.3.2.1 A-wapeningsstaal.pdf
IfcElement - Tag: C 401; Mark: C 401
IfcRoot - Name: 200 mm x 600 mm
Qto_ColumnBaseQuantities - Length: 2600; CrossSectionArea: 0.12; OuterSurfaceArea: 4.16; GrossVolume: 0.312; NetVolume: 0.312
Pset_ColumnCommon - Reference: 200 mm x 600 mm; Slope: 0 rad; IsExternal: no; LoadBearing: yes
Pset_ConcreteElementGeneral - ConstructionMethod: on-site
Pset_Condition - AssessmentCondition: Empty
Pset_EnvironmentalImpactIndicators - Reference: 200 mm x 600 mm; sets with these values: 2

# IfcColumn: BB_XX_Kolom_ rechthoekig_ center-center_GTL_250 mm x 250 mm (2)
In: K20
PredefinedType: COLUMN; Material: BB_Beton_Bestaand
Cpset_Column - LevelOfAccuracy: in te vullen door Buildwise
IfcBuildingStorey - Level: K20; Base Offset: 590; Top Offset: 380; Base Level: K20; Top Level: K10
IfcClassificationReference - TDS_link: .\05 As Builtdossier\2. Bouwkunde\2.2. Stabiliteit\2.2.0 technische fiche's\TF S 4.3 A-beton.pdf; TDS_link_extra_1: .\05 As Builtdossier\2. Bouwkunde\2.2. Stabiliteit\2.2.0 technische fiche's\TF S 4.3.2.1 A-wapeningsstaal.pdf
IfcRoot - Name: 250 mm x 250 mm
Qto_ColumnBaseQuantities - Length: 2490; CrossSectionArea: 0.0625; OuterSurfaceArea: 2.49; GrossVolume: 0.155625; NetVolume: 0.155625
Pset_ColumnCommon - Reference: 250 mm x 250 mm; IsExternal: no; LoadBearing: yes
Pset_ConcreteElementGeneral - ConstructionMethod: on-site
Pset_Condition - AssessmentCondition: Empty
Pset_EnvironmentalImpactIndicators - Reference: 250 mm x 250 mm; sets with these values: 2
Name (BB_XX_Kolom, rechthoekig, center-center_GTL:250 mm x 250 mm:...)
34108593
34108834

# IfcColumn: BB_XX_Kolom_ rechthoekig_ center-center_GTL_300 mm x 400 mm, BB_XX_Kolom, rechthoekig, center-center_GTL:300 mm x 400 mm:799511
In: K10
PredefinedType: COLUMN; Material: BB_Beton_Bestaand
Cpset_Column - LevelOfAccuracy: in te vullen door Buildwise
IfcBuildingStorey - Level: K10; Base Offset: -100; Top Offset: -700; Base Level: K10; Top Level: 000
IfcRoot - Name: 300 mm x 400 mm
Qto_ColumnBaseQuantities - Length: 2640; CrossSectionArea: 0.12; OuterSurfaceArea: 3.696; GrossVolume: 0.3168; NetVolume: 0.3168
Pset_ColumnCommon - Reference: 300 mm x 400 mm; Slope: 0 rad; IsExternal: no; LoadBearing: yes
Pset_Condition - AssessmentCondition: Empty
Pset_EnvironmentalImpactIndicators - Reference: 300 mm x 400 mm; sets with these values: 2

# IfcColumn: BB_XX_Kolom_ rechthoekig_ center-center_GTL_300 mm x 400 mm1, BB_XX_Kolom, rechthoekig, center-center_GTL:300 mm x 400 mm:799910
In: K10
PredefinedType: COLUMN; Material: BB_Beton_Bestaand
Cpset_Column - LevelOfAccuracy: in te vullen door Buildwise
IfcBuildingStorey - Level: K10; Base Offset: -100; Top Offset: -700; Base Level: K10; Top Level: 000
IfcRoot - Name: 300 mm x 400 mm
Qto_ColumnBaseQuantities - Length: 2640; CrossSectionArea: 0.12; OuterSurfaceArea: 3.696; GrossVolume: 0.3168; NetVolume: 0.3168
Pset_ColumnCommon - Reference: 300 mm x 400 mm; IsExternal: no; LoadBearing: yes
Pset_Condition - AssessmentCondition: Empty
Pset_EnvironmentalImpactIndicators - Reference: 300 mm x 400 mm; sets with these values: 2

# IfcColumn: BB_XX_Kolom_ rechthoekig_ center-center_GTL_300 mm x 400 mm3 (9)
In: K10
PredefinedType: COLUMN; Material: BB_Beton_Bestaand
Cpset_Column - LevelOfAccuracy: in te vullen door Buildwise
IfcBuildingStorey - Level: K10; Base Offset: 0; Top Offset: -900; Base Level: K10; Top Level: 000
IfcRoot - Name: 300 mm x 400 mm
Qto_ColumnBaseQuantities - Length: 2340; CrossSectionArea: 0.12; OuterSurfaceArea: 3.276; GrossVolume: 0.2808; NetVolume: 0.2808
Pset_ColumnCommon - Reference: 300 mm x 400 mm; IsExternal: no; LoadBearing: yes
Pset_Condition - AssessmentCondition: Empty
Pset_EnvironmentalImpactIndicators - Reference: 300 mm x 400 mm; sets with these values: 2
Name (BB_XX_Kolom, rechthoekig, center-center_GTL:300 mm x 400 mm:...)
799938
799995
800014
800069
800086
800186
800246
800353
800601

# IfcColumn: BB_XX_Kolom_ rechthoekig_ center-center_GTL_300 mm x 400 mm5 (4)
In: K10
PredefinedType: COLUMN; Material: BB_Beton_Bestaand
Cpset_Column - LevelOfAccuracy: in te vullen door Buildwise
IfcBuildingStorey - Level: K10; Base Offset: 0; Top Offset: -700; Base Level: K10; Top Level: 000
IfcRoot - Name: 300 mm x 400 mm
Qto_ColumnBaseQuantities - Length: 2540; CrossSectionArea: 0.12; OuterSurfaceArea: 3.556; GrossVolume: 0.3048; NetVolume: 0.3048
Pset_ColumnCommon - Reference: 300 mm x 400 mm; IsExternal: no; LoadBearing: yes
Pset_Condition - AssessmentCondition: Empty
Pset_EnvironmentalImpactIndicators - Reference: 300 mm x 400 mm; sets with these values: 2
Name (BB_XX_Kolom, rechthoekig, center-center_GTL:300 mm x 400 mm:...)
800370
800447
800580
834853

# IfcColumn: BB_XX_Kolom_ rechthoekig_ center-center_GTL_340 mm x 1090 mm, BB_XX_Kolom, rechthoekig, center-center_GTL:340 mm x 1090 mm:34105699
In: K10
PredefinedType: COLUMN; Material: <Unnamed>
Cpset_Column - LevelOfAccuracy: in te vullen door Buildwise
IfcBuildingStorey - Level: K10; Base Offset: 0; Top Offset: -728.568; Base Level: K10; Top Level: 000
IfcClassificationReference - TDS_link: .\05 As Builtdossier\2. Bouwkunde\2.2. Stabiliteit\2.2.0 technische fiche's\TF S 4.3 A-beton.pdf; TDS_link_extra_1: .\05 As Builtdossier\2. Bouwkunde\2.2. Stabiliteit\2.2.0 technische fiche's\TF S 4.3.2.1 A-wapeningsstaal.pdf
IfcRoot - Name: 340 mm x 1090 mm
Qto_ColumnBaseQuantities - CrossSectionArea: 3.99066; NetVolume: 0.920399
Pset_ColumnCommon - Reference: 340 mm x 1090 mm; IsExternal: no; LoadBearing: yes
Pset_ConcreteElementGeneral - ConstructionMethod: on-site
Pset_Condition - AssessmentCondition: Empty
Pset_EnvironmentalImpactIndicators - Reference: 340 mm x 1090 mm; sets with these values: 2

# IfcColumn: BB_XX_Kolom_ rechthoekig_ center-center_GTL_340 mm x 1090 mm1, BB_XX_Kolom, rechthoekig, center-center_GTL:340 mm x 1090 mm:34106080
In: K10
PredefinedType: COLUMN; Material: <Unnamed>
Cpset_Column - LevelOfAccuracy: in te vullen door Buildwise
IfcBuildingStorey - Level: K10; Base Offset: 0; Top Offset: -400; Base Level: K10; Top Level: 000
IfcClassificationReference - TDS_link: .\05 As Builtdossier\2. Bouwkunde\2.2. Stabiliteit\2.2.0 technische fiche's\TF S 4.3 A-beton.pdf; TDS_link_extra_1: .\05 As Builtdossier\2. Bouwkunde\2.2. Stabiliteit\2.2.0 technische fiche's\TF S 4.3.2.1 A-wapeningsstaal.pdf
IfcRoot - Name: 340 mm x 1090 mm
Qto_ColumnBaseQuantities - CrossSectionArea: 4.3309; NetVolume: 1.02604
Pset_ColumnCommon - Reference: 340 mm x 1090 mm; IsExternal: no; LoadBearing: yes
Pset_ConcreteElementGeneral - ConstructionMethod: on-site
Pset_Condition - AssessmentCondition: Empty
Pset_EnvironmentalImpactIndicators - Reference: 340 mm x 1090 mm; sets with these values: 2

# IfcColumn: BB_XX_Kolom_ rechthoekig_ center-center_GTL_340 mm x 340 mm, BB_XX_Kolom, rechthoekig, center-center_GTL:340 mm x 340 mm:948989
In: K20
PredefinedType: COLUMN; Material: BB_Beton_Bestaand
Cpset_Column - LevelOfAccuracy: in te vullen door Buildwise
IfcBuildingStorey - Level: K20; Base Offset: -400; Top Offset: -100; Base Level: K20; Top Level: K10
IfcRoot - Name: 340 mm x 340 mm
Qto_ColumnBaseQuantities - Length: 3000; CrossSectionArea: 0.1156; OuterSurfaceArea: 4.08; GrossVolume: 0.3468; NetVolume: 0.3468
Pset_ColumnCommon - Reference: 340 mm x 340 mm; Slope: 0 rad; IsExternal: no; LoadBearing: yes
Pset_Condition - AssessmentCondition: Empty
Pset_EnvironmentalImpactIndicators - Reference: 340 mm x 340 mm; sets with these values: 2

# IfcColumn: BB_XX_Kolom_ rechthoekig_ center-center_GTL_340 mm x 340 mm1, BB_XX_Kolom, rechthoekig, center-center_GTL:340 mm x 340 mm:949768
In: K20
PredefinedType: COLUMN; Material: BB_Beton_Bestaand
Cpset_Column - LevelOfAccuracy: in te vullen door Buildwise
IfcBuildingStorey - Level: K20; Base Offset: -200; Top Offset: -100; Base Level: K20; Top Level: K10
IfcRoot - Name: 340 mm x 340 mm
Qto_ColumnBaseQuantities - Length: 2800; CrossSectionArea: 0.1156; OuterSurfaceArea: 3.808; GrossVolume: 0.32368; NetVolume: 0.32368
Pset_ColumnCommon - Reference: 340 mm x 340 mm; Slope: 0 rad; IsExternal: no; LoadBearing: yes
Pset_Condition - AssessmentCondition: Empty
Pset_EnvironmentalImpactIndicators - Reference: 340 mm x 340 mm; sets with these values: 2

# IfcColumn: BB_XX_Kolom_ rechthoekig_ center-center_GTL_340 mm x 340 mm11, BB_XX_Kolom, rechthoekig, center-center_GTL:340 mm x 340 mm:930826
In: K10
PredefinedType: COLUMN; Material: BB_Beton_Bestaand
Cpset_Column - LevelOfAccuracy: in te vullen door Buildwise
IfcBuildingStorey - Level: K10; Base Offset: -100; Top Offset: -200; Base Level: K10; Top Level: 000
IfcRoot - Name: 340 mm x 340 mm
Qto_ColumnBaseQuantities - Length: 3140; CrossSectionArea: 0.1156; OuterSurfaceArea: 4.2704; GrossVolume: 0.362984; NetVolume: 0.362984
Pset_ColumnCommon - Reference: 340 mm x 340 mm; Slope: 0 rad; IsExternal: no; LoadBearing: yes
Pset_Condition - AssessmentCondition: Empty
Pset_EnvironmentalImpactIndicators - Reference: 340 mm x 340 mm; sets with these values: 2

# IfcColumn: BB_XX_Kolom_ rechthoekig_ center-center_GTL_340 mm x 340 mm13, BB_XX_Kolom, rechthoekig, center-center_GTL:340 mm x 340 mm:931077
In: K10
PredefinedType: COLUMN; Material: BB_Beton_Bestaand
Cpset_Column - LevelOfAccuracy: in te vullen door Buildwise
IfcBuildingStorey - Level: K10; Base Offset: -100; Top Offset: -200; Base Level: K10; Top Level: 000
IfcRoot - Name: 340 mm x 340 mm
Qto_ColumnBaseQuantities - Length: 3140; CrossSectionArea: 0.1156; OuterSurfaceArea: 4.2704; GrossVolume: 0.362984; NetVolume: 0.362984
Pset_ColumnCommon - Reference: 340 mm x 340 mm; Slope: 0 rad; IsExternal: no; LoadBearing: yes
Pset_Condition - AssessmentCondition: Empty
Pset_EnvironmentalImpactIndicators - Reference: 340 mm x 340 mm; sets with these values: 2

# IfcColumn: BB_XX_Kolom_ rechthoekig_ center-center_GTL_340 mm x 340 mm15 (6)
In: 000
PredefinedType: COLUMN; Material: BB_Beton_Bestaand
Cpset_Column - LevelOfAccuracy: in te vullen door Buildwise
IfcBuildingStorey - Level: 000; Base Offset: -200; Top Offset: -200; Base Level: 000; Top Level: 010
IfcRoot - Name: 340 mm x 340 mm
Qto_ColumnBaseQuantities - Length: 3600; CrossSectionArea: 0.1156; OuterSurfaceArea: 4.896; GrossVolume: 0.41616; NetVolume: 0.41616
Pset_ColumnCommon - Reference: 340 mm x 340 mm; IsExternal: no; LoadBearing: yes
Pset_Condition - AssessmentCondition: Empty
Pset_EnvironmentalImpactIndicators - Reference: 340 mm x 340 mm; sets with these values: 2
Name (BB_XX_Kolom, rechthoekig, center-center_GTL:340 mm x 340 mm:...)
452647
456919
457752
466785
487507
1924262

# IfcColumn: BB_XX_Kolom_ rechthoekig_ center-center_GTL_340 mm x 340 mm17, BB_XX_Kolom, rechthoekig, center-center_GTL:340 mm x 340 mm:479927
In: 000
PredefinedType: COLUMN; Material: BB_Beton_Bestaand
Cpset_Column - LevelOfAccuracy: in te vullen door Buildwise
IfcBuildingStorey - Level: 000; Base Offset: -460; Top Offset: -200; Base Level: 000; Top Level: 010
IfcRoot - Name: 340 mm x 340 mm
Qto_ColumnBaseQuantities - Length: 3860; CrossSectionArea: 0.1156; OuterSurfaceArea: 5.2496; GrossVolume: 0.446216; NetVolume: 0.446216
Pset_ColumnCommon - Reference: 340 mm x 340 mm; Slope: 0 rad; IsExternal: no; LoadBearing: yes
Pset_Condition - AssessmentCondition: Empty
Pset_EnvironmentalImpactIndicators - Reference: 340 mm x 340 mm; sets with these values: 2

# IfcColumn: BB_XX_Kolom_ rechthoekig_ center-center_GTL_340 mm x 340 mm19, BB_XX_Kolom, rechthoekig, center-center_GTL:340 mm x 340 mm:482126
In: 000
PredefinedType: COLUMN; Material: BB_Beton_Bestaand
Cpset_Column - LevelOfAccuracy: in te vullen door Buildwise
IfcBuildingStorey - Level: 000; Base Offset: -460; Top Offset: -200; Base Level: 000; Top Level: 010
IfcRoot - Name: 340 mm x 340 mm
Qto_ColumnBaseQuantities - Length: 3860; CrossSectionArea: 0.1156; OuterSurfaceArea: 5.2496; GrossVolume: 0.446216; NetVolume: 0.446216
Pset_ColumnCommon - Reference: 340 mm x 340 mm; IsExternal: no; LoadBearing: yes
Pset_Condition - AssessmentCondition: Empty
Pset_EnvironmentalImpactIndicators - Reference: 340 mm x 340 mm; sets with these values: 2

# IfcColumn: BB_XX_Kolom_ rechthoekig_ center-center_GTL_340 mm x 340 mm21, BB_XX_Kolom, rechthoekig, center-center_GTL:340 mm x 340 mm:486577
In: 000
PredefinedType: COLUMN; Material: BB_Beton_Bestaand
Cpset_Column - LevelOfAccuracy: in te vullen door Buildwise
IfcBuildingStorey - Level: 000; Base Offset: -700; Top Offset: -200; Base Level: 000; Top Level: 010
IfcRoot - Name: 340 mm x 340 mm
Qto_ColumnBaseQuantities - Length: 4100; CrossSectionArea: 0.1156; OuterSurfaceArea: 5.576; GrossVolume: 0.47396; NetVolume: 0.47396
Pset_ColumnCommon - Reference: 340 mm x 340 mm; Slope: 0 rad; IsExternal: no; LoadBearing: yes
Pset_Condition - AssessmentCondition: Empty
Pset_EnvironmentalImpactIndicators - Reference: 340 mm x 340 mm; sets with these values: 2

# IfcColumn: BB_XX_Kolom_ rechthoekig_ center-center_GTL_340 mm x 340 mm23, BB_XX_Kolom, rechthoekig, center-center_GTL:340 mm x 340 mm:487450
In: 000
PredefinedType: COLUMN; Material: BB_Beton_Bestaand
Cpset_Column - LevelOfAccuracy: in te vullen door Buildwise
IfcBuildingStorey - Level: 000; Base Offset: -700; Top Offset: -200; Base Level: 000; Top Level: 010
IfcRoot - Name: 340 mm x 340 mm
Qto_ColumnBaseQuantities - Length: 4100; CrossSectionArea: 0.1156; OuterSurfaceArea: 5.576; GrossVolume: 0.47396; NetVolume: 0.47396
Pset_ColumnCommon - Reference: 340 mm x 340 mm; Slope: 0 rad; IsExternal: no; LoadBearing: yes
Pset_Condition - AssessmentCondition: Empty
Pset_EnvironmentalImpactIndicators - Reference: 340 mm x 340 mm; sets with these values: 2

# IfcColumn: BB_XX_Kolom_ rechthoekig_ center-center_GTL_340 mm x 340 mm25 (7)
In: 010
PredefinedType: COLUMN; Material: BB_Beton_Bestaand
Cpset_Column - LevelOfAccuracy: in te vullen door Buildwise
IfcBuildingStorey - Level: 010; Base Offset: -200; Top Offset: -200; Base Level: 010; Top Level: 020
IfcRoot - Name: 340 mm x 340 mm
Qto_ColumnBaseQuantities - Length: 3600; CrossSectionArea: 0.1156; OuterSurfaceArea: 4.896; GrossVolume: 0.41616; NetVolume: 0.41616
Pset_ColumnCommon - Reference: 340 mm x 340 mm; IsExternal: no; LoadBearing: yes
Pset_Condition - AssessmentCondition: Empty
Pset_EnvironmentalImpactIndicators - Reference: 340 mm x 340 mm; sets with these values: 2
Name (BB_XX_Kolom, rechthoekig, center-center_GTL:340 mm x 340 mm:...)
608725
609952
611158
611351
613010
634217
638334

# IfcColumn: BB_XX_Kolom_ rechthoekig_ center-center_GTL_340 mm x 340 mm27, BB_XX_Kolom, rechthoekig, center-center_GTL:340 mm x 340 mm:631132
In: 010
PredefinedType: COLUMN; Material: BB_Beton_Bestaand
Cpset_Column - LevelOfAccuracy: in te vullen door Buildwise
IfcBuildingStorey - Level: 010; Base Offset: -200; Top Offset: -200; Base Level: 010; Top Level: 020
IfcRoot - Name: 340 mm x 340 mm
Qto_ColumnBaseQuantities - Length: 3600; CrossSectionArea: 0.1156; OuterSurfaceArea: 4.896; GrossVolume: 0.41616; NetVolume: 0.41616
Pset_ColumnCommon - Reference: 340 mm x 340 mm; Slope: 0 rad; IsExternal: no; LoadBearing: yes
Pset_Condition - AssessmentCondition: Empty
Pset_EnvironmentalImpactIndicators - Reference: 340 mm x 340 mm; sets with these values: 2

# IfcColumn: BB_XX_Kolom_ rechthoekig_ center-center_GTL_340 mm x 340 mm29, BB_XX_Kolom, rechthoekig, center-center_GTL:340 mm x 340 mm:632522
In: 010
PredefinedType: COLUMN; Material: BB_Beton_Bestaand
Cpset_Column - LevelOfAccuracy: in te vullen door Buildwise
IfcBuildingStorey - Level: 010; Base Offset: -200; Top Offset: -200; Base Level: 010; Top Level: 020
IfcRoot - Name: 340 mm x 340 mm
Qto_ColumnBaseQuantities - Length: 3600; CrossSectionArea: 0.1156; OuterSurfaceArea: 4.896; GrossVolume: 0.41616; NetVolume: 0.41616
Pset_ColumnCommon - Reference: 340 mm x 340 mm; Slope: 0 rad; IsExternal: no; LoadBearing: yes
Pset_Condition - AssessmentCondition: Empty
Pset_EnvironmentalImpactIndicators - Reference: 340 mm x 340 mm; sets with these values: 2

# IfcColumn: BB_XX_Kolom_ rechthoekig_ center-center_GTL_340 mm x 340 mm3, BB_XX_Kolom, rechthoekig, center-center_GTL:340 mm x 340 mm:971829
In: K20
PredefinedType: COLUMN; Material: BB_Beton_Bestaand
Cpset_Column - LevelOfAccuracy: in te vullen door Buildwise
IfcBuildingStorey - Level: K20; Base Offset: 0; Top Offset: -200; Base Level: K20; Top Level: K10
IfcRoot - Name: 340 mm x 340 mm
Qto_ColumnBaseQuantities - Length: 2500; CrossSectionArea: 0.1156; OuterSurfaceArea: 3.4; GrossVolume: 0.289; NetVolume: 0.289
Pset_ColumnCommon - Reference: 340 mm x 340 mm; IsExternal: no; LoadBearing: yes
Pset_Condition - AssessmentCondition: Empty
Pset_EnvironmentalImpactIndicators - Reference: 340 mm x 340 mm; sets with these values: 2

# IfcColumn: BB_XX_Kolom_ rechthoekig_ center-center_GTL_340 mm x 340 mm31, BB_XX_Kolom, rechthoekig, center-center_GTL:340 mm x 340 mm:638663
In: 010
PredefinedType: COLUMN; Material: BB_Beton_Bestaand
Cpset_Column - LevelOfAccuracy: in te vullen door Buildwise
IfcBuildingStorey - Level: 010; Base Offset: -200; Top Offset: -200; Base Level: 010; Top Level: 020
IfcRoot - Name: 340 mm x 340 mm
Qto_ColumnBaseQuantities - Length: 3600; CrossSectionArea: 0.1156; OuterSurfaceArea: 4.896; GrossVolume: 0.41616; NetVolume: 0.41616
Pset_ColumnCommon - Reference: 340 mm x 340 mm; Slope: 0 rad; IsExternal: no; LoadBearing: yes
Pset_Condition - AssessmentCondition: Empty
Pset_EnvironmentalImpactIndicators - Reference: 340 mm x 340 mm; sets with these values: 2

# IfcColumn: BB_XX_Kolom_ rechthoekig_ center-center_GTL_340 mm x 340 mm33, BB_XX_Kolom, rechthoekig, center-center_GTL:340 mm x 340 mm:695359
In: 020
PredefinedType: COLUMN; Material: BB_Beton_Bestaand
Cpset_Column - LevelOfAccuracy: in te vullen door Buildwise
IfcBuildingStorey - Level: 020; Base Offset: -200; Top Offset: -200; Base Level: 020; Top Level: 030
IfcRoot - Name: 340 mm x 340 mm
Qto_ColumnBaseQuantities - Length: 3600; CrossSectionArea: 0.1156; OuterSurfaceArea: 4.896; GrossVolume: 0.41616; NetVolume: 0.41616
Pset_ColumnCommon - Reference: 340 mm x 340 mm; Slope: 0 rad; IsExternal: no; LoadBearing: yes
Pset_Condition - AssessmentCondition: Empty
Pset_EnvironmentalImpactIndicators - Reference: 340 mm x 340 mm; sets with these values: 2

# IfcColumn: BB_XX_Kolom_ rechthoekig_ center-center_GTL_340 mm x 340 mm35, BB_XX_Kolom, rechthoekig, center-center_GTL:340 mm x 340 mm:695369
In: 020
PredefinedType: COLUMN; Material: BB_Beton_Bestaand
Cpset_Column - LevelOfAccuracy: in te vullen door Buildwise
IfcBuildingStorey - Level: 020; Base Offset: -200; Top Offset: -200; Base Level: 020; Top Level: 030
IfcRoot - Name: 340 mm x 340 mm
Qto_ColumnBaseQuantities - Length: 3600; CrossSectionArea: 0.1156; OuterSurfaceArea: 4.896; GrossVolume: 0.41616; NetVolume: 0.41616
Pset_ColumnCommon - Reference: 340 mm x 340 mm; Slope: 0 rad; IsExternal: no; LoadBearing: yes
Pset_Condition - AssessmentCondition: Empty
Pset_EnvironmentalImpactIndicators - Reference: 340 mm x 340 mm; sets with these values: 2

# IfcColumn: BB_XX_Kolom_ rechthoekig_ center-center_GTL_340 mm x 340 mm37 (6)
In: 020
PredefinedType: COLUMN; Material: BB_Beton_Bestaand
Cpset_Column - LevelOfAccuracy: in te vullen door Buildwise
IfcBuildingStorey - Level: 020; Base Offset: -200; Top Offset: -200; Base Level: 020; Top Level: 030
IfcRoot - Name: 340 mm x 340 mm
Qto_ColumnBaseQuantities - Length: 3600; CrossSectionArea: 0.1156; OuterSurfaceArea: 4.896; GrossVolume: 0.41616; NetVolume: 0.41616
Pset_ColumnCommon - Reference: 340 mm x 340 mm; IsExternal: no; LoadBearing: yes
Pset_Condition - AssessmentCondition: Empty
Pset_EnvironmentalImpactIndicators - Reference: 340 mm x 340 mm; sets with these values: 2
Name (BB_XX_Kolom, rechthoekig, center-center_GTL:340 mm x 340 mm:...)
695375
695381
695391
695546
695564
695576

# IfcColumn: BB_XX_Kolom_ rechthoekig_ center-center_GTL_340 mm x 340 mm39, BB_XX_Kolom, rechthoekig, center-center_GTL:340 mm x 340 mm:695632
In: 020
PredefinedType: COLUMN; Material: BB_Beton_Bestaand
Cpset_Column - LevelOfAccuracy: in te vullen door Buildwise
IfcBuildingStorey - Level: 020; Base Offset: -200; Top Offset: -200; Base Level: 020; Top Level: 030
IfcRoot - Name: 340 mm x 340 mm
Qto_ColumnBaseQuantities - Length: 3600; CrossSectionArea: 0.1156; OuterSurfaceArea: 4.896; GrossVolume: 0.41616; NetVolume: 0.41616
Pset_ColumnCommon - Reference: 340 mm x 340 mm; Slope: 0 rad; IsExternal: no; LoadBearing: yes
Pset_Condition - AssessmentCondition: Empty
Pset_EnvironmentalImpactIndicators - Reference: 340 mm x 340 mm; sets with these values: 2

# IfcColumn: BB_XX_Kolom_ rechthoekig_ center-center_GTL_340 mm x 340 mm41, BB_XX_Kolom, rechthoekig, center-center_GTL:340 mm x 340 mm:695638
In: 020
PredefinedType: COLUMN; Material: BB_Beton_Bestaand
Cpset_Column - LevelOfAccuracy: in te vullen door Buildwise
IfcBuildingStorey - Level: 020; Base Offset: -200; Top Offset: -200; Base Level: 020; Top Level: 030
IfcRoot - Name: 340 mm x 340 mm
Qto_ColumnBaseQuantities - Length: 3600; CrossSectionArea: 0.1156; OuterSurfaceArea: 4.896; GrossVolume: 0.41616; NetVolume: 0.41616
Pset_ColumnCommon - Reference: 340 mm x 340 mm; Slope: 0 rad; IsExternal: no; LoadBearing: yes
Pset_Condition - AssessmentCondition: Empty
Pset_EnvironmentalImpactIndicators - Reference: 340 mm x 340 mm; sets with these values: 2

# IfcColumn: BB_XX_Kolom_ rechthoekig_ center-center_GTL_340 mm x 340 mm5, BB_XX_Kolom, rechthoekig, center-center_GTL:340 mm x 340 mm:2162036
In: K20
PredefinedType: COLUMN; Material: BB_Beton_Bestaand
Cpset_Column - LevelOfAccuracy: in te vullen door Buildwise
IfcBuildingStorey - Level: K20; Base Offset: -400; Top Offset: -100; Base Level: K20; Top Level: K10
IfcRoot - Name: 340 mm x 340 mm
Qto_ColumnBaseQuantities - Length: 3000; CrossSectionArea: 0.1156; OuterSurfaceArea: 4.08; GrossVolume: 0.3468; NetVolume: 0.3468
Pset_ColumnCommon - Reference: 340 mm x 340 mm; Slope: 0 rad; IsExternal: no; LoadBearing: yes
Pset_Condition - AssessmentCondition: Empty
Pset_EnvironmentalImpactIndicators - Reference: 340 mm x 340 mm; sets with these values: 2

# IfcColumn: BB_XX_Kolom_ rechthoekig_ center-center_GTL_340 mm x 340 mm7, BB_XX_Kolom, rechthoekig, center-center_GTL:340 mm x 340 mm:801291
In: K10
PredefinedType: COLUMN; Material: BB_Beton_Bestaand
Cpset_Column - LevelOfAccuracy: in te vullen door Buildwise
IfcBuildingStorey - Level: K10; Base Offset: -100; Top Offset: -200; Base Level: K10; Top Level: 000
IfcRoot - Name: 340 mm x 340 mm
Qto_ColumnBaseQuantities - Length: 3140; CrossSectionArea: 0.1156; OuterSurfaceArea: 4.2704; GrossVolume: 0.362984; NetVolume: 0.362984
Pset_ColumnCommon - Reference: 340 mm x 340 mm; Slope: 0 rad; IsExternal: no; LoadBearing: yes
Pset_Condition - AssessmentCondition: Empty
Pset_EnvironmentalImpactIndicators - Reference: 340 mm x 340 mm; sets with these values: 2

# IfcColumn: BB_XX_Kolom_ rechthoekig_ center-center_GTL_340 mm x 340 mm9, BB_XX_Kolom, rechthoekig, center-center_GTL:340 mm x 340 mm:805768
In: K10
PredefinedType: COLUMN; Material: BB_Beton_Bestaand
Cpset_Column - LevelOfAccuracy: in te vullen door Buildwise
IfcBuildingStorey - Level: K10; Base Offset: -200; Top Offset: -200; Base Level: K10; Top Level: 000
IfcRoot - Name: 340 mm x 340 mm
Qto_ColumnBaseQuantities - Length: 3240; CrossSectionArea: 0.1156; OuterSurfaceArea: 4.4064; GrossVolume: 0.374544; NetVolume: 0.374544
Pset_ColumnCommon - Reference: 340 mm x 340 mm; Slope: 0 rad; IsExternal: no; LoadBearing: yes
Pset_Condition - AssessmentCondition: Empty
Pset_EnvironmentalImpactIndicators - Reference: 340 mm x 340 mm; sets with these values: 2

# IfcColumn: BB_XX_Kolom_ rechthoekig_ center-center_GTL_340 mm x 800 mm, BB_XX_Kolom, rechthoekig, center-center_GTL:340 mm x 800 mm:834630
In: K10
PredefinedType: COLUMN; Material: <Unnamed>
Cpset_Column - LevelOfAccuracy: in te vullen door Buildwise
IfcBuildingStorey - Level: K10; Base Offset: 0; Top Offset: -700; Base Level: K10; Top Level: 000
IfcRoot - Name: 340 mm x 800 mm
Qto_ColumnBaseQuantities - Length: 2540; CrossSectionArea: 0.272; OuterSurfaceArea: 5.7912; GrossVolume: 0.69088; NetVolume: 0.69088
Pset_ColumnCommon - Reference: 340 mm x 800 mm; IsExternal: no; LoadBearing: yes
Pset_Condition - AssessmentCondition: Empty
Pset_EnvironmentalImpactIndicators - Reference: 340 mm x 800 mm; sets with these values: 2

# IfcColumn: BB_XX_Kolom_ rechthoekig_ center-center_GTL_400 mm x 1090 mm, BB_XX_Kolom, rechthoekig, center-center_GTL:400 mm x 1090 mm:34103361
In: K10
PredefinedType: COLUMN; Material: <Unnamed>
Cpset_Column - LevelOfAccuracy: in te vullen door Buildwise
IfcBuildingStorey - Level: K10; Base Offset: 0; Top Offset: -728.568; Base Level: K10; Top Level: 000
IfcClassificationReference - TDS_link: .\05 As Builtdossier\2. Bouwkunde\2.2. Stabiliteit\2.2.0 technische fiche's\TF S 4.3 A-beton.pdf; TDS_link_extra_1: .\05 As Builtdossier\2. Bouwkunde\2.2. Stabiliteit\2.2.0 technische fiche's\TF S 4.3.2.1 A-wapeningsstaal.pdf
IfcRoot - Name: 400 mm x 1090 mm
Qto_ColumnBaseQuantities - Length: 2511.43; CrossSectionArea: 0.436; OuterSurfaceArea: 7.48407; GrossVolume: 1.09498; NetVolume: 1.09498
Pset_ColumnCommon - Reference: 400 mm x 1090 mm; Slope: 0 rad; IsExternal: no; LoadBearing: yes; FireRating: EI60
Pset_ConcreteElementGeneral - ConstructionMethod: on-site
Pset_Condition - AssessmentCondition: Empty
Pset_EnvironmentalImpactIndicators - Reference: 400 mm x 1090 mm; sets with these values: 2

# IfcColumn: BB_XX_Kolom_ rechthoekig_ center-center_GTL_400 mm x 415 mm, BB_XX_Kolom, rechthoekig, center-center_GTL:400 mm x 415 mm:34107691
In: K10
PredefinedType: COLUMN; Material: <Unnamed>
Cpset_Column - LevelOfAccuracy: in te vullen door Buildwise
IfcBuildingStorey - Level: K10; Base Offset: 0; Top Offset: -465.151; Base Level: K10; Top Level: 000
IfcClassificationReference - TDS_link: .\05 As Builtdossier\2. Bouwkunde\2.2. Stabiliteit\2.2.0 technische fiche's\TF S 4.3 A-beton.pdf; TDS_link_extra_1: .\05 As Builtdossier\2. Bouwkunde\2.2. Stabiliteit\2.2.0 technische fiche's\TF S 4.3.2.1 A-wapeningsstaal.pdf
IfcRoot - Name: 400 mm x 415 mm
Qto_ColumnBaseQuantities - Length: 2774.85; CrossSectionArea: 0.166; OuterSurfaceArea: 4.523; GrossVolume: 0.460625; NetVolume: 0.460625
Pset_ColumnCommon - Reference: 400 mm x 415 mm; IsExternal: no; LoadBearing: yes
Pset_ConcreteElementGeneral - ConstructionMethod: on-site
Pset_Condition - AssessmentCondition: Empty
Pset_EnvironmentalImpactIndicators - Reference: 400 mm x 415 mm; sets with these values: 2

# IfcColumn: BB_XX_Kolom_ rechthoekig_ center-center_GTL_400 mm x 415 mm1, BB_XX_Kolom, rechthoekig, center-center_GTL:400 mm x 415 mm:34108001
In: K10
PredefinedType: COLUMN; Material: <Unnamed>
Cpset_Column - LevelOfAccuracy: in te vullen door Buildwise
IfcBuildingStorey - Level: K10; Base Offset: 0; Top Offset: -465.151; Base Level: K10; Top Level: 000
IfcClassificationReference - TDS_link: .\05 As Builtdossier\2. Bouwkunde\2.2. Stabiliteit\2.2.0 technische fiche's\TF S 4.3 A-beton.pdf; TDS_link_extra_1: .\05 As Builtdossier\2. Bouwkunde\2.2. Stabiliteit\2.2.0 technische fiche's\TF S 4.3.2.1 A-wapeningsstaal.pdf
IfcRoot - Name: 400 mm x 415 mm
Qto_ColumnBaseQuantities - Length: 2774.85; CrossSectionArea: 0.166; OuterSurfaceArea: 4.523; GrossVolume: 0.460625; NetVolume: 0.460625
Pset_ColumnCommon - Reference: 400 mm x 415 mm; IsExternal: no; LoadBearing: yes
Pset_ConcreteElementGeneral - ConstructionMethod: on-site
Pset_Condition - AssessmentCondition: Empty
Pset_EnvironmentalImpactIndicators - Reference: 400 mm x 415 mm; sets with these values: 2

# IfcColumn: BB_XX_Kolom_ rechthoekig_ center-center_GTL_400 mm x 800 mm, BB_XX_Kolom, rechthoekig, center-center_GTL:400 mm x 800 mm:834468
In: K10
PredefinedType: COLUMN; Material: <Unnamed>
Cpset_Column - LevelOfAccuracy: in te vullen door Buildwise
IfcBuildingStorey - Level: K10; Base Offset: 0; Top Offset: -700; Base Level: K10; Top Level: 000
IfcRoot - Name: 400 mm x 800 mm
Qto_ColumnBaseQuantities - CrossSectionArea: 3.39181; NetVolume: 0.793233
Pset_ColumnCommon - Reference: 400 mm x 800 mm; IsExternal: no; LoadBearing: yes; FireRating: EI60
Pset_Condition - AssessmentCondition: Empty
Pset_EnvironmentalImpactIndicators - Reference: 400 mm x 800 mm; sets with these values: 2

# IfcColumn: BB_XX_Kolom_ rechthoekig_ center-center_GTL_490 mm x 340 mm, BB_XX_Kolom, rechthoekig, center-center_GTL:490 mm x 340 mm:1008456
In: K20
PredefinedType: COLUMN; Material: BB_Beton_Bestaand
Cpset_Column - LevelOfAccuracy: in te vullen door Buildwise
IfcBuildingStorey - Level: K20; Base Offset: -400; Top Offset: -100; Base Level: K20; Top Level: K10
IfcRoot - Name: 490 mm x 340 mm
Qto_ColumnBaseQuantities - Length: 3000; CrossSectionArea: 0.1666; OuterSurfaceArea: 4.98; GrossVolume: 0.4998; NetVolume: 0.4998
Pset_ColumnCommon - Reference: 490 mm x 340 mm; Slope: 0 rad; IsExternal: no; LoadBearing: yes
Pset_Condition - AssessmentCondition: Empty
Pset_EnvironmentalImpactIndicators - Reference: 490 mm x 340 mm; sets with these values: 2

# IfcColumn: BB_XX_Kolom_ rechthoekig_ center-center_GTL_490 mm x 340 mm1, BB_XX_Kolom, rechthoekig, center-center_GTL:490 mm x 340 mm:1008564
In: K20
PredefinedType: COLUMN; Material: BB_Beton_Bestaand
Cpset_Column - LevelOfAccuracy: in te vullen door Buildwise
IfcBuildingStorey - Level: K20; Base Offset: -400; Top Offset: -100; Base Level: K20; Top Level: K10
IfcRoot - Name: 490 mm x 340 mm
Qto_ColumnBaseQuantities - Length: 3000; CrossSectionArea: 0.1666; OuterSurfaceArea: 4.98; GrossVolume: 0.4998; NetVolume: 0.4998
Pset_ColumnCommon - Reference: 490 mm x 340 mm; Slope: 0 rad; IsExternal: no; LoadBearing: yes
Pset_Condition - AssessmentCondition: Empty
Pset_EnvironmentalImpactIndicators - Reference: 490 mm x 340 mm; sets with these values: 2

# IfcColumn: BB_XX_Kolom_ rechthoekig_ center-center_GTL_490 mm x 340 mm11 (4)
In: 000
PredefinedType: COLUMN; Material: BB_Beton_Bestaand
Cpset_Column - LevelOfAccuracy: in te vullen door Buildwise
IfcBuildingStorey - Level: 000; Base Offset: -200; Top Offset: -200; Base Level: 000; Top Level: 010
IfcRoot - Name: 490 mm x 340 mm
Qto_ColumnBaseQuantities - Length: 3600; CrossSectionArea: 0.1666; OuterSurfaceArea: 5.976; GrossVolume: 0.59976; NetVolume: 0.59976
Pset_ColumnCommon - Reference: 490 mm x 340 mm; IsExternal: no; LoadBearing: yes
Pset_Condition - AssessmentCondition: Empty
Pset_EnvironmentalImpactIndicators - Reference: 490 mm x 340 mm; sets with these values: 2
Name (BB_XX_Kolom, rechthoekig, center-center_GTL:490 mm x 340 mm:...)
454319
455863
464878
466518

# IfcColumn: BB_XX_Kolom_ rechthoekig_ center-center_GTL_490 mm x 340 mm13 (2)
In: 000
PredefinedType: COLUMN; Material: BB_Beton_Bestaand
Cpset_Column - LevelOfAccuracy: in te vullen door Buildwise
IfcBuildingStorey - Level: 000; Base Offset: -460; Top Offset: -200; Base Level: 000; Top Level: 010
IfcRoot - Name: 490 mm x 340 mm
Qto_ColumnBaseQuantities - Length: 3860; CrossSectionArea: 0.1666; OuterSurfaceArea: 6.4076; GrossVolume: 0.643076; NetVolume: 0.643076
Pset_ColumnCommon - Reference: 490 mm x 340 mm; IsExternal: no; LoadBearing: yes
Pset_Condition - AssessmentCondition: Empty
Pset_EnvironmentalImpactIndicators - Reference: 490 mm x 340 mm; sets with these values: 2
Name (BB_XX_Kolom, rechthoekig, center-center_GTL:490 mm x 340 mm:...)
481808
481866

# IfcColumn: BB_XX_Kolom_ rechthoekig_ center-center_GTL_490 mm x 340 mm15 (2)
In: 000
PredefinedType: COLUMN; Material: BB_Beton_Bestaand
Cpset_Column - LevelOfAccuracy: in te vullen door Buildwise
IfcBuildingStorey - Level: 000; Base Offset: -710; Top Offset: -200; Base Level: 000; Top Level: 010
IfcRoot - Name: 490 mm x 340 mm
Qto_ColumnBaseQuantities - Length: 4110; CrossSectionArea: 0.1666; OuterSurfaceArea: 6.8226; GrossVolume: 0.684726; NetVolume: 0.684726
Pset_ColumnCommon - Reference: 490 mm x 340 mm; IsExternal: no; LoadBearing: yes
Pset_Condition - AssessmentCondition: Empty
Pset_EnvironmentalImpactIndicators - Reference: 490 mm x 340 mm; sets with these values: 2
Name (BB_XX_Kolom, rechthoekig, center-center_GTL:490 mm x 340 mm:...)
487324
487397

# IfcColumn: BB_XX_Kolom_ rechthoekig_ center-center_GTL_490 mm x 340 mm17 (8)
In: 010
PredefinedType: COLUMN; Material: BB_Beton_Bestaand
Cpset_Column - LevelOfAccuracy: in te vullen door Buildwise
IfcBuildingStorey - Level: 010; Base Offset: -200; Top Offset: -200; Base Level: 010; Top Level: 020
IfcRoot - Name: 490 mm x 340 mm
Qto_ColumnBaseQuantities - Length: 3600; CrossSectionArea: 0.1666; OuterSurfaceArea: 5.976; GrossVolume: 0.59976; NetVolume: 0.59976
Pset_ColumnCommon - Reference: 490 mm x 340 mm; IsExternal: no; LoadBearing: yes
Pset_Condition - AssessmentCondition: Empty
Pset_EnvironmentalImpactIndicators - Reference: 490 mm x 340 mm; sets with these values: 2
Name (BB_XX_Kolom, rechthoekig, center-center_GTL:490 mm x 340 mm:...)
609712
609908
611239
611323
633383
634102
638441
638608

# IfcColumn: BB_XX_Kolom_ rechthoekig_ center-center_GTL_490 mm x 340 mm19 (8)
In: 020
PredefinedType: COLUMN; Material: BB_Beton_Bestaand
Cpset_Column - LevelOfAccuracy: in te vullen door Buildwise
IfcBuildingStorey - Level: 020; Base Offset: -200; Top Offset: -200; Base Level: 020; Top Level: 030
IfcRoot - Name: 490 mm x 340 mm
Qto_ColumnBaseQuantities - Length: 3600; CrossSectionArea: 0.1666; OuterSurfaceArea: 5.976; GrossVolume: 0.59976; NetVolume: 0.59976
Pset_ColumnCommon - Reference: 490 mm x 340 mm; IsExternal: no; LoadBearing: yes
Pset_Condition - AssessmentCondition: Empty
Pset_EnvironmentalImpactIndicators - Reference: 490 mm x 340 mm; sets with these values: 2
Name (BB_XX_Kolom, rechthoekig, center-center_GTL:490 mm x 340 mm:...)
695365
695367
695377
695379
695569
695573
695634
695636

# IfcColumn: BB_XX_Kolom_ rechthoekig_ center-center_GTL_490 mm x 340 mm3, BB_XX_Kolom, rechthoekig, center-center_GTL:490 mm x 340 mm:801449
In: K10
PredefinedType: COLUMN; Material: BB_Beton_Bestaand
Cpset_Column - LevelOfAccuracy: in te vullen door Buildwise
IfcBuildingStorey - Level: K10; Base Offset: -100; Top Offset: -200; Base Level: K10; Top Level: 000
IfcRoot - Name: 490 mm x 340 mm
Qto_ColumnBaseQuantities - Length: 3140; CrossSectionArea: 0.1666; OuterSurfaceArea: 5.2124; GrossVolume: 0.523124; NetVolume: 0.523124
Pset_ColumnCommon - Reference: 490 mm x 340 mm; Slope: 0 rad; IsExternal: no; LoadBearing: yes
Pset_Condition - AssessmentCondition: Empty
Pset_EnvironmentalImpactIndicators - Reference: 490 mm x 340 mm; sets with these values: 2

# IfcColumn: BB_XX_Kolom_ rechthoekig_ center-center_GTL_490 mm x 340 mm5, BB_XX_Kolom, rechthoekig, center-center_GTL:490 mm x 340 mm:801538
In: K10
PredefinedType: COLUMN; Material: BB_Beton_Bestaand
Cpset_Column - LevelOfAccuracy: in te vullen door Buildwise
IfcBuildingStorey - Level: K10; Base Offset: -100; Top Offset: -200; Base Level: K10; Top Level: 000
IfcRoot - Name: 490 mm x 340 mm
Qto_ColumnBaseQuantities - Length: 3140; CrossSectionArea: 0.1666; OuterSurfaceArea: 5.2124; GrossVolume: 0.523124; NetVolume: 0.523124
Pset_ColumnCommon - Reference: 490 mm x 340 mm; Slope: 0 rad; IsExternal: no; LoadBearing: yes
Pset_Condition - AssessmentCondition: Empty
Pset_EnvironmentalImpactIndicators - Reference: 490 mm x 340 mm; sets with these values: 2

# IfcColumn: BB_XX_Kolom_ rechthoekig_ center-center_GTL_490 mm x 340 mm7, BB_XX_Kolom, rechthoekig, center-center_GTL:490 mm x 340 mm:931019
In: K10
PredefinedType: COLUMN; Material: BB_Beton_Bestaand
Cpset_Column - LevelOfAccuracy: in te vullen door Buildwise
IfcBuildingStorey - Level: K10; Base Offset: -100; Top Offset: -200; Base Level: K10; Top Level: 000
IfcRoot - Name: 490 mm x 340 mm
Qto_ColumnBaseQuantities - Length: 3140; CrossSectionArea: 0.1666; OuterSurfaceArea: 5.2124; GrossVolume: 0.523124; NetVolume: 0.523124
Pset_ColumnCommon - Reference: 490 mm x 340 mm; Slope: 0 rad; IsExternal: no; LoadBearing: yes
Pset_Condition - AssessmentCondition: Empty
Pset_EnvironmentalImpactIndicators - Reference: 490 mm x 340 mm; sets with these values: 2

# IfcColumn: BB_XX_Kolom_ rechthoekig_ center-center_GTL_490 mm x 340 mm9, BB_XX_Kolom, rechthoekig, center-center_GTL:490 mm x 340 mm:948532
In: K10
PredefinedType: COLUMN; Material: BB_Beton_Bestaand
Cpset_Column - LevelOfAccuracy: in te vullen door Buildwise
IfcBuildingStorey - Level: K10; Base Offset: -100; Top Offset: -200; Base Level: K10; Top Level: 000
IfcRoot - Name: 490 mm x 340 mm
Qto_ColumnBaseQuantities - Length: 3140; CrossSectionArea: 0.1666; OuterSurfaceArea: 5.2124; GrossVolume: 0.523124; NetVolume: 0.523124
Pset_ColumnCommon - Reference: 490 mm x 340 mm; Slope: 0 rad; IsExternal: no; LoadBearing: yes
Pset_Condition - AssessmentCondition: Empty
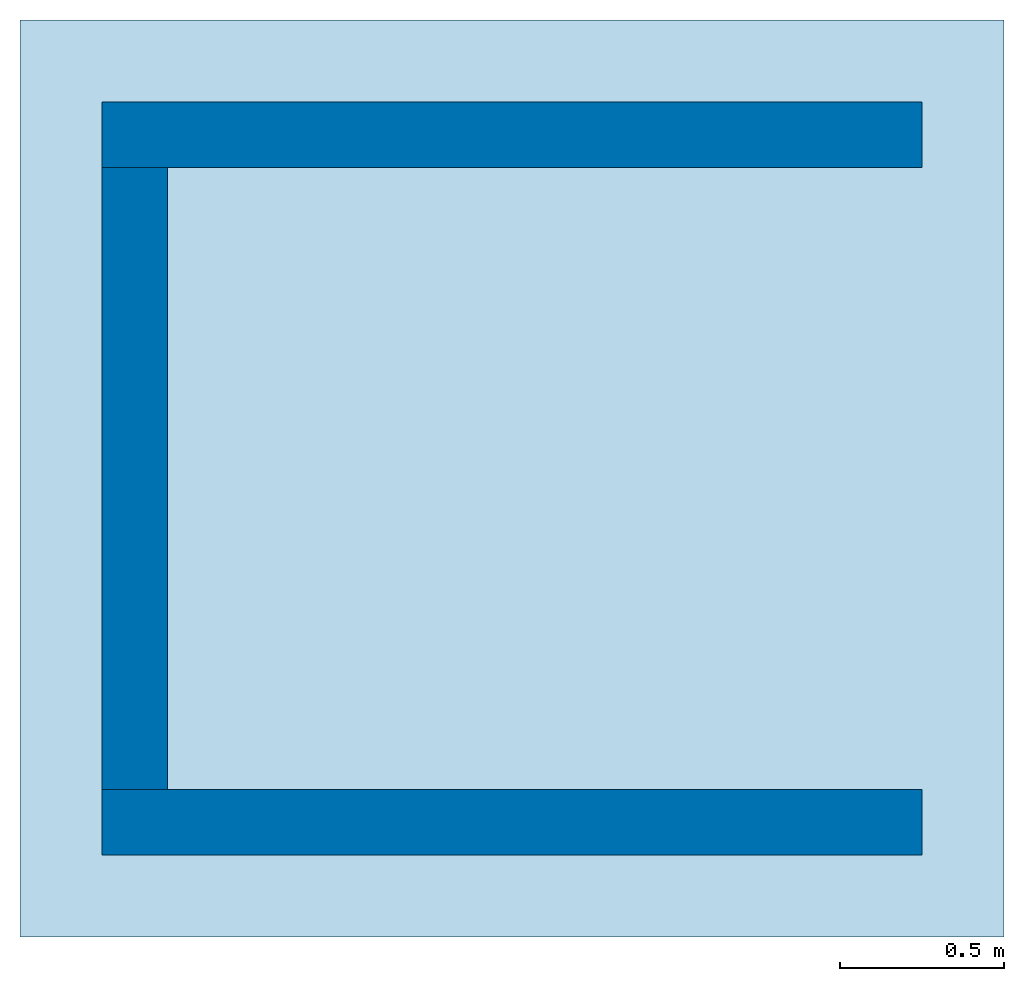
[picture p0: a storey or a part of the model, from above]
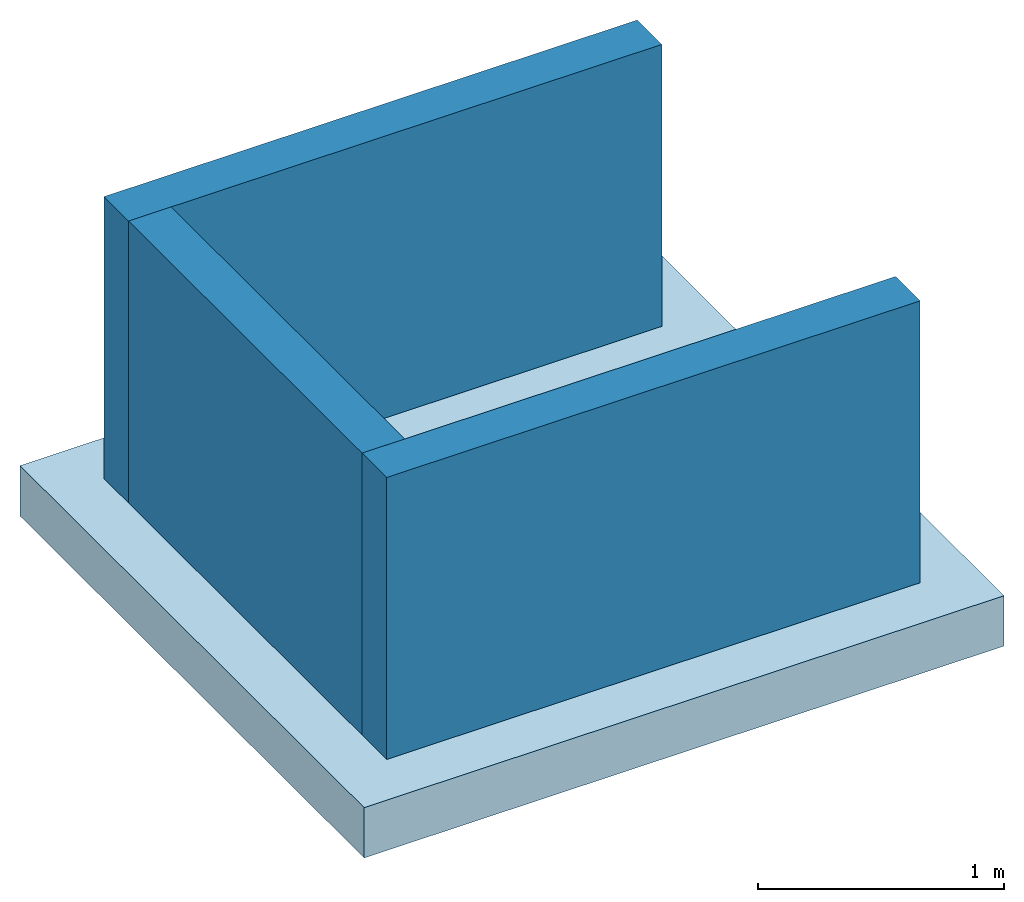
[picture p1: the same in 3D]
Properties of the parts of a building model (IFC4X3_ADD2), part 13 of 28

# IfcColumn: BB_XX_Kolom_ rechthoekig_ center-center_GTL_490 mm x 340 mm9, BB_XX_Kolom, rechthoekig, center-center_GTL:490 mm x 340 mm:948532
Pset_EnvironmentalImpactIndicators - Reference: 490 mm x 340 mm; sets with these values: 2

# IfcColumn: BB_XX_Kolom_ rechthoekig_ center-center_GTL_490 mm x 550 mm, BB_XX_Kolom, rechthoekig, center-center_GTL:490 mm x 550 mm:33693861
In: K20
PredefinedType: COLUMN; Material: BB_Beton_Bestaand
Cpset_Column - LevelOfAccuracy: in te vullen door Buildwise
IfcBuildingStorey - Level: K20; Base Offset: -400; Top Offset: -1020; Base Level: K20; Top Level: 000
IfcClassificationReference - TDS_link: .\05 As Builtdossier\2. Bouwkunde\2.2. Stabiliteit\2.2.0 technische fiche's\TF S 4.3 A-beton.pdf; TDS_link_extra_1: .\05 As Builtdossier\2. Bouwkunde\2.2. Stabiliteit\2.2.0 technische fiche's\TF S 4.3.2.1 A-wapeningsstaal.pdf
IfcRoot - Name: 490 mm x 550 mm
Qto_ColumnBaseQuantities - Length: 5320; CrossSectionArea: 0.2515; OuterSurfaceArea: 12.6616; GrossVolume: 1.33798; NetVolume: 1.33798
Pset_ColumnCommon - Reference: 490 mm x 550 mm; IsExternal: no; LoadBearing: yes
Pset_ConcreteElementGeneral - ConstructionMethod: on-site
Pset_Condition - AssessmentCondition: Empty
Pset_EnvironmentalImpactIndicators - Reference: 490 mm x 550 mm; sets with these values: 2

# IfcColumn: BB_XX_Kolom_ rechthoekig_ center-center_GTL_490 mm x 550 mm1, BB_XX_Kolom, rechthoekig, center-center_GTL:490 mm x 550 mm:33696942
In: K20
PredefinedType: COLUMN; Material: BB_Beton_Bestaand
Cpset_Column - LevelOfAccuracy: in te vullen door Buildwise
IfcBuildingStorey - Level: K20; Base Offset: -400; Top Offset: -1020; Base Level: K20; Top Level: 000
IfcClassificationReference - TDS_link: .\05 As Builtdossier\2. Bouwkunde\2.2. Stabiliteit\2.2.0 technische fiche's\TF S 4.3 A-beton.pdf; TDS_link_extra_1: .\05 As Builtdossier\2. Bouwkunde\2.2. Stabiliteit\2.2.0 technische fiche's\TF S 4.3.2.1 A-wapeningsstaal.pdf
IfcRoot - Name: 490 mm x 550 mm
Qto_ColumnBaseQuantities - Length: 5320; CrossSectionArea: 0.2515; OuterSurfaceArea: 12.6616; GrossVolume: 1.33798; NetVolume: 1.33798
Pset_ColumnCommon - Reference: 490 mm x 550 mm; IsExternal: no; LoadBearing: yes
Pset_ConcreteElementGeneral - ConstructionMethod: on-site
Pset_Condition - AssessmentCondition: Empty
Pset_EnvironmentalImpactIndicators - Reference: 490 mm x 550 mm; sets with these values: 2

# IfcColumn: BB_XX_Kolom_ rechthoekig_ center-center_GTL_490 mm x 550 mm3, BB_XX_Kolom, rechthoekig, center-center_GTL:490 mm x 550 mm:34102428
In: K10
PredefinedType: COLUMN; Material: BB_Beton_Bestaand
Cpset_Column - LevelOfAccuracy: in te vullen door Buildwise
IfcBuildingStorey - Level: K10; Base Offset: -100; Top Offset: -1020; Base Level: K10; Top Level: 000
IfcClassificationReference - TDS_link: .\05 As Builtdossier\2. Bouwkunde\2.2. Stabiliteit\2.2.0 technische fiche's\TF S 4.3 A-beton.pdf; TDS_link_extra_1: .\05 As Builtdossier\2. Bouwkunde\2.2. Stabiliteit\2.2.0 technische fiche's\TF S 4.3.2.1 A-wapeningsstaal.pdf
IfcRoot - Name: 490 mm x 550 mm
Qto_ColumnBaseQuantities - Length: 2320; CrossSectionArea: 0.2695; OuterSurfaceArea: 4.8256; GrossVolume: 0.62524; NetVolume: 0.62524
Pset_ColumnCommon - Reference: 490 mm x 550 mm; IsExternal: no; LoadBearing: yes
Pset_ConcreteElementGeneral - ConstructionMethod: on-site
Pset_Condition - AssessmentCondition: Empty
Pset_EnvironmentalImpactIndicators - Reference: 490 mm x 550 mm; sets with these values: 2

# IfcColumn: BB_XX_Kolom_ rechthoekig_ center-center_GTL_490 mm x 550 mm5, BB_XX_Kolom, rechthoekig, center-center_GTL:490 mm x 550 mm:34102512
In: K10
PredefinedType: COLUMN; Material: BB_Beton_Bestaand
Cpset_Column - LevelOfAccuracy: in te vullen door Buildwise
IfcBuildingStorey - Level: K10; Base Offset: -100; Top Offset: -1020; Base Level: K10; Top Level: 000
IfcClassificationReference - TDS_link: .\05 As Builtdossier\2. Bouwkunde\2.2. Stabiliteit\2.2.0 technische fiche's\TF S 4.3 A-beton.pdf; TDS_link_extra_1: .\05 As Builtdossier\2. Bouwkunde\2.2. Stabiliteit\2.2.0 technische fiche's\TF S 4.3.2.1 A-wapeningsstaal.pdf
IfcRoot - Name: 490 mm x 550 mm
Qto_ColumnBaseQuantities - Length: 2320; CrossSectionArea: 0.2695; OuterSurfaceArea: 4.8256; GrossVolume: 0.62524; NetVolume: 0.62524
Pset_ColumnCommon - Reference: 490 mm x 550 mm; IsExternal: no; LoadBearing: yes
Pset_ConcreteElementGeneral - ConstructionMethod: on-site
Pset_Condition - AssessmentCondition: Empty
Pset_EnvironmentalImpactIndicators - Reference: 490 mm x 550 mm; sets with these values: 2

# IfcColumn: BB_XX_Kolom_ rond_GMO_300 x 2100 mm (2)
In: K20
PredefinedType: COLUMN; Material: <Unnamed>
Cpset_Column - LevelOfAccuracy: in te vullen door Buildwise
IfcBuildingStorey - Level: K20; Elevation from Level: 0
IfcClassificationReference - GVH_artnr 01: geen waarde gevonden; GVH_artnr 02: geen waarde gevonden; GVH_artnr 03: geen waarde gevonden; GVH_artnr 04: geen waarde gevonden; GVH_artnr 05: geen waarde gevonden; GVH_artnr 06: geen waarde gevonden
IfcRoot - Name: 300 x 2100 mm
Qto_ColumnBaseQuantities - Length: 2100; CrossSectionArea: 0.0706764; OuterSurfaceArea: 1.9792; GrossVolume: 0.14842; NetVolume: 0.148433
Pset_ColumnCommon - Reference: 300 x 2100 mm; IsExternal: no
Pset_Condition - AssessmentCondition: Empty
Pset_EnvironmentalImpactIndicators - Reference: 300 x 2100 mm; sets with these values: 2
Name (BB_XX_Kolom, rond_GMO:300 x 2100 mm:...)
968894
968934

# IfcColumn: BB_XX_Kolom_ rond_GMO_300 x 2340 mm, BB_XX_Kolom, rond_GMO:300 x 2340 mm:797721
In: K10
PredefinedType: COLUMN; Material: <Unnamed>
Cpset_Column - LevelOfAccuracy: in te vullen door Buildwise
IfcBuildingStorey - Level: K10; Elevation from Level: 0
IfcClassificationReference - GVH_artnr 01: geen waarde gevonden; GVH_artnr 02: geen waarde gevonden; GVH_artnr 03: geen waarde gevonden; GVH_artnr 04: geen waarde gevonden; GVH_artnr 05: geen waarde gevonden; GVH_artnr 06: geen waarde gevonden
IfcRoot - Name: 300 x 2340 mm
Qto_ColumnBaseQuantities - Length: 2340; CrossSectionArea: 0.0706764; OuterSurfaceArea: 2.2054; GrossVolume: 0.165383; NetVolume: 0.165398
Pset_ColumnCommon - Reference: 300 x 2340 mm; Slope: 0 rad; IsExternal: no
Pset_Condition - AssessmentCondition: Empty
Pset_EnvironmentalImpactIndicators - Reference: 300 x 2340 mm; sets with these values: 2

# IfcColumn: BB_XX_Kolom_ rond_GMO_300 x 2340 mm1, BB_XX_Kolom, rond_GMO:300 x 2340 mm:798340
In: K10
PredefinedType: COLUMN; Material: <Unnamed>
Cpset_Column - LevelOfAccuracy: in te vullen door Buildwise
IfcBuildingStorey - Level: K10; Elevation from Level: 0
IfcClassificationReference - GVH_artnr 01: geen waarde gevonden; GVH_artnr 02: geen waarde gevonden; GVH_artnr 03: geen waarde gevonden; GVH_artnr 04: geen waarde gevonden; GVH_artnr 05: geen waarde gevonden; GVH_artnr 06: geen waarde gevonden
IfcRoot - Name: 300 x 2340 mm
Qto_ColumnBaseQuantities - Length: 2340; CrossSectionArea: 0.0706764; OuterSurfaceArea: 2.2054; GrossVolume: 0.165383; NetVolume: 0.165397
Pset_ColumnCommon - Reference: 300 x 2340 mm; Slope: 0 rad; IsExternal: no
Pset_Condition - AssessmentCondition: Empty
Pset_EnvironmentalImpactIndicators - Reference: 300 x 2340 mm; sets with these values: 2

# IfcColumn: BB_XX_Kolom_ rond_GMO_300 x 2440 mm, BB_XX_Kolom, rond_GMO:300 x 2440 mm:885325
In: K10
PredefinedType: COLUMN; Material: <Unnamed>
Cpset_Column - LevelOfAccuracy: in te vullen door Buildwise
IfcBuildingStorey - Level: K10; Elevation from Level: 0
IfcClassificationReference - GVH_artnr 01: geen waarde gevonden; GVH_artnr 02: geen waarde gevonden; GVH_artnr 03: geen waarde gevonden; GVH_artnr 04: geen waarde gevonden; GVH_artnr 05: geen waarde gevonden; GVH_artnr 06: geen waarde gevonden
IfcRoot - Name: 300 x 2440 mm
Qto_ColumnBaseQuantities - Length: 2440; CrossSectionArea: 0.0706764; OuterSurfaceArea: 2.29965; GrossVolume: 0.17245; NetVolume: 0.172465
Pset_ColumnCommon - Reference: 300 x 2440 mm; IsExternal: no
Pset_Condition - AssessmentCondition: Empty
Pset_EnvironmentalImpactIndicators - Reference: 300 x 2440 mm; sets with these values: 2

# IfcColumn: BB_XX_Kolom_ rond_GMO_300 x 2640 mm, BB_XX_Kolom, rond_GMO:300 x 2640 mm:885544
In: K10
PredefinedType: COLUMN; Material: <Unnamed>
Cpset_Column - LevelOfAccuracy: in te vullen door Buildwise
IfcBuildingStorey - Level: K10; Elevation from Level: -100
IfcClassificationReference - GVH_artnr 01: geen waarde gevonden; GVH_artnr 02: geen waarde gevonden; GVH_artnr 03: geen waarde gevonden; GVH_artnr 04: geen waarde gevonden; GVH_artnr 05: geen waarde gevonden; GVH_artnr 06: geen waarde gevonden
IfcRoot - Name: 300 x 2640 mm
Qto_ColumnBaseQuantities - Length: 2640; CrossSectionArea: 0.0706764; OuterSurfaceArea: 2.48814; GrossVolume: 0.186586; NetVolume: 0.186602
Pset_ColumnCommon - Reference: 300 x 2640 mm; IsExternal: no
Pset_Condition - AssessmentCondition: Empty
Pset_EnvironmentalImpactIndicators - Reference: 300 x 2640 mm; sets with these values: 2

# IfcColumn: BB_XX_Kolom_ rond_GMO_350 x 2200 mm (2)
In: K20
PredefinedType: COLUMN; Material: <Unnamed>
Cpset_Column - LevelOfAccuracy: in te vullen door Buildwise
IfcBuildingStorey - Level: K20; Elevation from Level: 0
IfcClassificationReference - GVH_artnr 01: geen waarde gevonden; GVH_artnr 02: geen waarde gevonden; GVH_artnr 03: geen waarde gevonden; GVH_artnr 04: geen waarde gevonden; GVH_artnr 05: geen waarde gevonden; GVH_artnr 06: geen waarde gevonden
IfcRoot - Name: 350 x 2200 mm
Qto_ColumnBaseQuantities - Length: 2200; CrossSectionArea: 0.0961984; OuterSurfaceArea: 2.41903; GrossVolume: 0.211637; NetVolume: 0.211655
Pset_ColumnCommon - Reference: 350 x 2200 mm; Slope: 0 rad; IsExternal: no
Pset_Condition - AssessmentCondition: Empty
Pset_EnvironmentalImpactIndicators - Reference: 350 x 2200 mm; sets with these values: 2
Name (BB_XX_Kolom, rond_GMO:350 x 2200 mm:...)
980781
983298

# IfcDiscreteAccessory: BB_03.07.12_Kleine gevelelementen uit natuursteen, recuperatie_GMO:4850 x 300 mm, BB_03.07.12_Kleine gevelelementen uit natuursteen, recuperatie_GMO:4850 x 300 mm:27808189
In: K10
PredefinedType: USERDEFINED; Material: BB_Natuursteen
Pset_Condition - AssessmentCondition: Empty
Pset_EnvironmentalImpactIndicators - Reference: 4850 x 300 mm

# IfcDiscreteAccessory: BB_03.07.12_Kleine gevelelementen uit natuursteen, recuperatie_GMO:6650 x 300 mm (2)
In: K10
PredefinedType: USERDEFINED; Material: BB_Natuursteen
Pset_Condition - AssessmentCondition: Empty
Pset_EnvironmentalImpactIndicators - Reference: 6650 x 300 mm
Name (BB_03.07.12_Kleine gevelelementen uit natuursteen, recuperatie_GMO:6650 x 300 mm:...)
27798321
27808190

# IfcDiscreteAccessory: BB_05.10.23#01_AluminiumMuurafdek U-vorm_GMO:XX_Geen (4)
In: 030
PredefinedType: USERDEFINED; Material: BB_Metaal_Aluminium_Buitenschrijnwerk
Pset_Condition - AssessmentCondition: Empty
Pset_EnvironmentalImpactIndicators - Reference: XX_Geen
Name (BB_05.10.23#01_AluminiumMuurafdek U-vorm_GMO:XX_Geen:...)
19726483
19727616
19727716
33179110

# IfcDiscreteAccessory: BB_05.10.23#02_AluminiumMuurafdek eindstuk, 850 mm_GMO:XX_Geen (4)
In: 030
PredefinedType: USERDEFINED; Material: BB_Metaal_Aluminium_Buitenschrijnwerk
Pset_Condition - AssessmentCondition: Empty
Pset_EnvironmentalImpactIndicators - Reference: XX_Geen
Name (BB_05.10.23#02_AluminiumMuurafdek eindstuk, 850 mm_GMO:XX_Geen:...)
19722575
19723664
19723824
19723825

# IfcDiscreteAccessory: BB_05.10.23#02_AluminiumMuurafdek, 850 mm_GLI:XX_Geen (14)
In: 030
PredefinedType: USERDEFINED; Material: BB_Metaal_Aluminium_Buitenschrijnwerk
Pset_Condition - AssessmentCondition: Empty
Pset_EnvironmentalImpactIndicators - Reference: XX_Geen
Name (BB_05.10.23#02_AluminiumMuurafdek, 850 mm_GLI:XX_Geen:...)
8310608
8313130
8313133
8313138
8313141
8313143
8313146
8684199
8684200
8684201
8684202
8684203
8684204
8684205

# IfcDiscreteAccessory: BB_05.10.23#04_AluminiumMuurafdek eindstuk, 830 mm_GMO:XX_Geen (2)
In: 030
PredefinedType: USERDEFINED; Material: BB_Metaal_Aluminium_Buitenschrijnwerk
Pset_Condition - AssessmentCondition: Empty
Pset_EnvironmentalImpactIndicators - Reference: XX_Geen
Name (BB_05.10.23#04_AluminiumMuurafdek eindstuk, 830 mm_GMO:XX_Geen:...)
19721126
19721303

# IfcDiscreteAccessory: BB_05.10.23#04_AluminiumMuurafdek, 830 mm_GLI:XX_Geen (14)
In: 030
PredefinedType: USERDEFINED; Material: BB_Metaal_Aluminium_Buitenschrijnwerk
Pset_Condition - AssessmentCondition: Empty
Pset_EnvironmentalImpactIndicators - Reference: XX_Geen
Name (BB_05.10.23#04_AluminiumMuurafdek, 830 mm_GLI:XX_Geen:...)
8687715
8687716
8687717
8687718
8687719
8687720
8687721
8687722
8687724
8687725
8687727
8687728
8687729
8687730

# IfcDiscreteAccessory: BB_05.10_Dakrandprofiel, 60 mm_GLI:XX_Geen (20)
PredefinedType: USERDEFINED; Material: BB_Metaal_Aluminium_Buitenschrijnwerk
Pset_Condition - AssessmentCondition: Empty
Pset_EnvironmentalImpactIndicators - Reference: XX_Geen
Name (BB_05.10_Dakrandprofiel, 60 mm_GLI:XX_Geen:...) | In
19738416 | 040
19738490 | 040
19738556 | 040
19738609 | 040
19738741 | 040
19738814 | 040
19738858 | 040
19738877 | 040
19738947 | 040
19738986 | 040
10454454 | 050
10455918 | 050
10455997 | 050
10463806 | 050
10463893 | 050
10464004 | 050
10464139 | 050
10464191 | 050
10464240 | 050
10464305 | 050

# IfcDiscreteAccessory: BB_Shed_Dakranden:BB_Shed_Dakranden, BB_Shed_Dakranden:BB_Shed_Dakranden:10421027
In: 050
PredefinedType: USERDEFINED; Material: BB_05.02.34_Aluminium_Dakrand_Sheds
Pset_Condition - AssessmentCondition: Empty
Pset_EnvironmentalImpactIndicators - Reference: BB_Shed_Dakranden

# IfcElementAssembly: Structural Connections Assembly:IPE360 + plaat (6)
PredefinedType: USERDEFINED
Pset_ElementAssemblyCommon - Reference: IPE360 + plaat; sets with these values: 2
Pset_Condition - AssessmentCondition: Empty
Name (Structural Connections Assembly:IPE360 + plaat:...) | In
34125942 | 000
34126109 | 000
34125970 | 010
34126168 | 010
34126000 | 020
34126199 | 020

# IfcFooting: M_Pile Cap-1 Pile_500 x 500 x 500mm (7)
In: K20
PredefinedType: PILE_CAP; Classification: A1010130 Uniformat (CSI (Construction Specifications Institute)); Material: Concrete, Cast-in-Place gray
Qto_FootingBaseQuantities - Length: 500; Width: 500; Height: 500; CrossSectionArea: 0.25; OuterSurfaceArea: 1; GrossSurfaceArea: 1.5; GrossVolume: 0.125; NetVolume: 0.125
Pset_Condition - AssessmentCondition: Empty
Pset_EnvironmentalImpactIndicators - Reference: 500 x 500 x 500mm; sets with these values: 4
Name (M_Pile Cap-1 Pile:500 x 500 x 500mm:...)
34038620
34047442
34047452
34047462
34047474
34047484
34047985

# IfcFooting: M_Pile Cap-2 Pile_500 x 1100 x 500 (2)
In: K20
PredefinedType: PILE_CAP; Classification: A1010130 Uniformat (CSI (Construction Specifications Institute)); Material: Concrete, Cast-in-Place gray
Qto_FootingBaseQuantities - Length: 500; Width: 1100; Height: 500; CrossSectionArea: 0.55; OuterSurfaceArea: 1.6; GrossSurfaceArea: 2.7; GrossVolume: 0.275; NetVolume: 0.275
Pset_Condition - AssessmentCondition: Empty
Pset_EnvironmentalImpactIndicators - Reference: 500 x 1100 x 500; sets with these values: 4
Name (M_Pile Cap-2 Pile:500 x 1100 x 500:...)
34047995
34051528

# IfcMember: BB_07.10_Gevelstructuur staal_ +4_GMO_XX_Geen, BB_07.10_Gevelstructuur staal, +4_GMO:XX_Geen:19914402
In: 040
PredefinedType: USERDEFINED; Material: <Unnamed>
Cpset_Member - LevelOfAccuracy: in te vullen door Buildwise
IfcBuildingStorey - Level: 040; Elevation from Level: 240
IfcClassificationReference - Keynote: 07.10.91; GVH_artnr 01: 07.10.91; GVH_artnr 02: geen waarde gevonden; GVH_artnr 03: geen waarde gevonden; GVH_artnr 04: geen waarde gevonden; GVH_artnr 05: geen waarde gevonden; GVH_artnr 06: geen waarde gevonden; TDS_link: .\05 As Builtdossier\2. Bouwkunde\2.1 Architectuur\2.1.7 Gevelsluiting\2.1.7.4 Stalen borstweringen (Peter Bax)\TF 07.10.91 - secundiare staalconstructie.pdf
IfcRoot - Name: XX_Geen
Qto_MemberBaseQuantities - NetSurfaceArea: 21.3027; NetVolume: 0.0623542; CrossSectionArea: 10.6513
Pset_Condition - AssessmentCondition: Empty
Pset_EnvironmentalImpactIndicators - Reference: XX_Geen
Pset_MemberCommon - Reference: XX_Geen; IsExternal: no

# IfcMember: BB_07.10_Gevelstructuur staal_ +4_GMO_XX_Geen1, BB_07.10_Gevelstructuur staal, +4_GMO:XX_Geen:19914574
In: 040
PredefinedType: USERDEFINED; Material: <Unnamed>
Cpset_Member - LevelOfAccuracy: in te vullen door Buildwise
IfcBuildingStorey - Level: 040; Elevation from Level: 210
IfcClassificationReference - Keynote: 07.10.91; GVH_artnr 01: 07.10.91; GVH_artnr 02: geen waarde gevonden; GVH_artnr 03: geen waarde gevonden; GVH_artnr 04: geen waarde gevonden; GVH_artnr 05: geen waarde gevonden; GVH_artnr 06: geen waarde gevonden; TDS_link: .\05 As Builtdossier\2. Bouwkunde\2.1 Architectuur\2.1.7 Gevelsluiting\2.1.7.4 Stalen borstweringen (Peter Bax)\TF 07.10.91 - secundiare staalconstructie.pdf
IfcRoot - Name: XX_Geen
Qto_MemberBaseQuantities - NetSurfaceArea: 21.3027; NetVolume: 0.0623542; CrossSectionArea: 10.6513
Pset_Condition - AssessmentCondition: Empty
Pset_EnvironmentalImpactIndicators - Reference: XX_Geen
Pset_MemberCommon - Reference: XX_Geen; IsExternal: no

# IfcMember: BB_10.12.90_Verankeringsrail_GLI_XX_H 50mm x B 30mm, BB_10.12.90_Verankeringsrail_GLI:XX_H 50mm x B 30mm:24241090
In: 010
PredefinedType: USERDEFINED; Material: BB_Metaal_Aluminium_Buitenschrijnwerk
Cpset_Member - LevelOfAccuracy: in te vullen door Buildwise
IfcClassificationReference - Keynote: 10.12.90; GVH_artnr 01: 10.12.90; GVH_artnr 02: geen waarde gevonden; GVH_artnr 03: geen waarde gevonden; GVH_artnr 04: geen waarde gevonden; GVH_artnr 05: geen waarde gevonden; GVH_artnr 06: geen waarde gevonden; TDS_link: .\05 As Builtdossier\2. Bouwkunde\2.1 Architectuur\2.1.10 wanden\TF A 10.12.90 A - Verankeringsrail voor wanden.pdf
IfcElement - BB_Element_Lokaalnummer01: K.10.A1
IfcRoot - Name: XX_H 50mm x B 30mm
Qto_MemberBaseQuantities - NetSurfaceArea: 2.53162; NetVolume: 0.0237; Length: 15815; CrossSectionArea: 1.26581
Pset_Condition - AssessmentCondition: Empty
Pset_EnvironmentalImpactIndicators - Reference: XX_H 50mm x B 30mm
Pset_MemberCommon - Reference: XX_H 50mm x B 30mm; Span: 15815 mm; Slope: 0 rad; IsExternal: no

# IfcMember: BB_10.12.90_Verankeringsrail_GLI_XX_H 50mm x B 30mm1 (2)
PredefinedType: USERDEFINED; Material: BB_Metaal_Aluminium_Buitenschrijnwerk
Cpset_Member - LevelOfAccuracy: in te vullen door Buildwise
IfcClassificationReference - Keynote: 10.12.90; GVH_artnr 01: 10.12.90; GVH_artnr 02: geen waarde gevonden; GVH_artnr 03: geen waarde gevonden; GVH_artnr 04: geen waarde gevonden; GVH_artnr 05: geen waarde gevonden; GVH_artnr 06: geen waarde gevonden; TDS_link: .\05 As Builtdossier\2. Bouwkunde\2.1 Architectuur\2.1.10 wanden\TF A 10.12.90 A - Verankeringsrail voor wanden.pdf
IfcElement - BB_Element_Lokaalnummer01: K.10.A1
IfcRoot - Name: XX_H 50mm x B 30mm
Qto_MemberBaseQuantities - NetSurfaceArea: 2.53402; NetVolume: 0.0237225; Length: 15830; CrossSectionArea: 1.26701
Pset_Condition - AssessmentCondition: Empty
Pset_EnvironmentalImpactIndicators - Reference: XX_H 50mm x B 30mm
Pset_MemberCommon - Reference: XX_H 50mm x B 30mm; Span: 15830 mm; Slope: 0 rad; IsExternal: no
Name (BB_10.12.90_Verankeringsrail_GLI:XX_H 50mm x B 30mm:...) | In
24241336 | 010
28419277 | 030

# IfcMember: BB_10.12.90_Verankeringsrail_GLI_XX_H 50mm x B 30mm3 (2)
PredefinedType: USERDEFINED; Material: BB_Metaal_Aluminium_Buitenschrijnwerk
Cpset_Member - LevelOfAccuracy: in te vullen door Buildwise
IfcClassificationReference - Keynote: 10.12.90; GVH_artnr 01: 10.12.90; GVH_artnr 02: geen waarde gevonden; GVH_artnr 03: geen waarde gevonden; GVH_artnr 04: geen waarde gevonden; GVH_artnr 05: geen waarde gevonden; GVH_artnr 06: geen waarde gevonden; TDS_link: .\05 As Builtdossier\2. Bouwkunde\2.1 Architectuur\2.1.10 wanden\TF A 10.12.90 A - Verankeringsrail voor wanden.pdf
IfcElement - BB_Element_Lokaalnummer01: K.10.A1
IfcRoot - Name: XX_H 50mm x B 30mm
Qto_MemberBaseQuantities - NetSurfaceArea: 1.86202; NetVolume: 0.0174225; Length: 11630; CrossSectionArea: 0.93101
Pset_Condition - AssessmentCondition: Empty
Pset_EnvironmentalImpactIndicators - Reference: XX_H 50mm x B 30mm
Pset_MemberCommon - Reference: XX_H 50mm x B 30mm; Span: 11630 mm; Slope: 0 rad; IsExternal: no
Name (BB_10.12.90_Verankeringsrail_GLI:XX_H 50mm x B 30mm:...) | In
24241337 | 010
28027655 | 030

# IfcMember: BB_10.12.90_Verankeringsrail_GLI_XX_H 50mm x B 30mm5 (2)
PredefinedType: USERDEFINED; Material: BB_Metaal_Aluminium_Buitenschrijnwerk
Cpset_Member - LevelOfAccuracy: in te vullen door Buildwise
IfcClassificationReference - Keynote: 10.12.90; GVH_artnr 01: 10.12.90; GVH_artnr 02: geen waarde gevonden; GVH_artnr 03: geen waarde gevonden; GVH_artnr 04: geen waarde gevonden; GVH_artnr 05: geen waarde gevonden; GVH_artnr 06: geen waarde gevonden; TDS_link: .\05 As Builtdossier\2. Bouwkunde\2.1 Architectuur\2.1.10 wanden\TF A 10.12.90 A - Verankeringsrail voor wanden.pdf
IfcElement - BB_Element_Lokaalnummer01: K.10.A1
IfcRoot - Name: XX_H 50mm x B 30mm
Qto_MemberBaseQuantities - NetSurfaceArea: 1.86202; NetVolume: 0.0174225; Length: 11630; CrossSectionArea: 0.93101
Pset_Condition - AssessmentCondition: Empty
Pset_EnvironmentalImpactIndicators - Reference: XX_H 50mm x B 30mm
Pset_MemberCommon - Reference: XX_H 50mm x B 30mm; Span: 11630 mm; Slope: 0 rad; IsExternal: no
Name (BB_10.12.90_Verankeringsrail_GLI:XX_H 50mm x B 30mm:...) | In
35859774 | 010
28027654 | 030

# IfcMember: BB_10.12.90_Verankeringsrail_GLI_XX_H 50mm x B 30mm7, BB_10.12.90_Verankeringsrail_GLI:XX_H 50mm x B 30mm:28419276
In: 030
PredefinedType: USERDEFINED; Material: BB_Metaal_Aluminium_Buitenschrijnwerk
Cpset_Member - LevelOfAccuracy: in te vullen door Buildwise
IfcClassificationReference - Keynote: 10.12.90; GVH_artnr 01: 10.12.90; GVH_artnr 02: geen waarde gevonden; GVH_artnr 03: geen waarde gevonden; GVH_artnr 04: geen waarde gevonden; GVH_artnr 05: geen waarde gevonden; GVH_artnr 06: geen waarde gevonden; TDS_link: .\05 As Builtdossier\2. Bouwkunde\2.1 Architectuur\2.1.10 wanden\TF A 10.12.90 A - Verankeringsrail voor wanden.pdf
IfcElement - BB_Element_Lokaalnummer01: K.10.A1
IfcRoot - Name: XX_H 50mm x B 30mm
Qto_MemberBaseQuantities - NetSurfaceArea: 2.53402; NetVolume: 0.0237225; Length: 15830; CrossSectionArea: 1.26701
Pset_Condition - AssessmentCondition: Empty
Pset_EnvironmentalImpactIndicators - Reference: XX_H 50mm x B 30mm
Pset_MemberCommon - Reference: XX_H 50mm x B 30mm; Span: 15830 mm; Slope: 0 rad; IsExternal: no

# IfcMember: BB_Shed_Hoek02_BB_Shed_Hoek02, BB_Shed_Hoek02:BB_Shed_Hoek02:10414762
In: 050
PredefinedType: MULLION; Material: BB_Schrijnwerk_Aluminium
Cpset_Member - LevelOfAccuracy: in te vullen door Buildwise
IfcClassificationReference - GVH_artnr 01: geen waarde gevonden; GVH_artnr 02: geen waarde gevonden; GVH_artnr 03: geen waarde gevonden; GVH_artnr 04: geen waarde gevonden; GVH_artnr 05: geen waarde gevonden; GVH_artnr 06: geen waarde gevonden; TDS_link: .\05 As Builtdossier\2. Bouwkunde\2.1 Architectuur\2.1.5 dakwerken en dakwaterafvoer\2.1.5.3 dakwerken (MSB)\Technische fiches\TF A 05.02.34 A – Dakbedekking uit aluminiumbladen – zet- en plooiwerk.pdf
IfcRoot - Name: BB_Shed_Hoek02
Qto_MemberBaseQuantities - NetSurfaceArea: 2.94076; NetVolume: 0.0719311; Length: 62; CrossSectionArea: 0.580744; OuterSurfaceArea: 0.310156; GrossSurfaceArea: 1.47164; GrossVolume: 0.0360062
Pset_Condition - AssessmentCondition: Empty
Pset_EnvironmentalImpactIndicators - Reference: BB_Shed_Hoek02
Pset_MemberCommon - Reference: BB_Shed_Hoek02; IsExternal: no

# IfcMember: BB_Shed_Hoek1_BB_Shed_Hoek02, BB_Shed_Hoek1:BB_Shed_Hoek02:10491035
In: 050
PredefinedType: MULLION; Material: BB_Schrijnwerk_Aluminium
Cpset_Member - LevelOfAccuracy: in te vullen door Buildwise
IfcClassificationReference - GVH_artnr 01: geen waarde gevonden; GVH_artnr 02: geen waarde gevonden; GVH_artnr 03: geen waarde gevonden; GVH_artnr 04: geen waarde gevonden; GVH_artnr 05: geen waarde gevonden; GVH_artnr 06: geen waarde gevonden; TDS_link: .\05 As Builtdossier\2. Bouwkunde\2.1 Architectuur\2.1.5 dakwerken en dakwaterafvoer\2.1.5.3 dakwerken (MSB)\Technische fiches\TF A 05.02.34 A – Dakbedekking uit aluminiumbladen – zet- en plooiwerk.pdf
IfcRoot - Name: BB_Shed_Hoek02
Qto_MemberBaseQuantities - NetSurfaceArea: 3.24892; NetVolume: 0.079639; Length: 62; CrossSectionArea: 0.580744; OuterSurfaceArea: 0.310156; GrossSurfaceArea: 1.47164; GrossVolume: 0.0360062
Pset_Condition - AssessmentCondition: Empty
Pset_EnvironmentalImpactIndicators - Reference: BB_Shed_Hoek02
Pset_MemberCommon - Reference: BB_Shed_Hoek02; IsExternal: no

# IfcPile: M_Pile-Concrete Pipe:200 mm Diameter (15)
In: K20
PredefinedType: USERDEFINED; Classification: A1020130 Uniformat (CSI (Construction Specifications Institute))
Qto_PileBaseQuantities - CrossSectionArea: 0.0314055
Pset_Condition - AssessmentCondition: Empty
Pset_EnvironmentalImpactIndicators - Reference: 200 mm Diameter; sets with these values: 2
Name (M_Pile-Concrete Pipe:200 mm Diameter:...) | Material | Length | OuterSurfaceArea | GrossSurfaceArea | GrossVolume | NetVolume
34038622 | Concrete, C30/37 | 2750 | 1.72788 | 1.79069 | 0.0863651 | 0.086386
34047444 | Concrete, C30/37 | 2750 | 1.72788 | 1.79069 | 0.0863651 | 0.086386
34047454 | Concrete, C30/37 | 2750 | 1.72788 | 1.79069 | 0.0863651 | 0.086386
34047464 | Concrete, C30/37 | 2750 | 1.72788 | 1.79069 | 0.0863651 | 0.086386
34047476 | Concrete, C30/37 | 2750 | 1.72788 | 1.79069 | 0.0863651 | 0.086386
34047486 | Concrete, C30/37 | 2750 | 1.72788 | 1.79069 | 0.0863651 | 0.086386
34047987 | Concrete, C30/37 | 2750 | 1.72788 | 1.79069 | 0.0863651 | 0.086386
34048874 | Concrete, C30/37 | 2600 | 1.63363 | 1.69644 | 0.0816543 | 0.081674
34048875 | Concrete, C30/37 | 2600 | 1.63363 | 1.69644 | 0.0816543 | 0.081674
34051530 | Concrete, C30/37 | 2600 | 1.63363 | 1.69644 | 0.0816543 | 0.081674
34051531 | Concrete, C30/37 | 2600 | 1.63363 | 1.69644 | 0.0816543 | 0.081674
34052543 | Concrete, Cast-in-Place gray | 2800 | 1.75929 | 1.8221 | 0.0879354 | 0.0879539
34052626 | Concrete, Cast-in-Place gray | 2800 | 1.75929 | 1.8221 | 0.0879354 | 0.0879539
34052987 | Concrete, Cast-in-Place gray | 2800 | 1.75929 | 1.8221 | 0.0879354 | 0.0879539
34052989 | Concrete, Cast-in-Place gray | 2800 | 1.75929 | 1.8221 | 0.0879354 | 0.0879539

# IfcPipeFitting: Afwerkstuk spuwer 70 x 70 RVS:Type 1 (20)
PredefinedType: EXIT
Cpset_PipeFitting - LevelOfAccuracy: in te vullen door Buildwise
IfcClassificationReference - TDS_link: .\05 As Builtdossier\2. Bouwkunde\2.1 Architectuur\2.1.5 dakwerken en dakwaterafvoer\2.1.5.1 dakwerken (Tectum)\TF A 05.08.42 A – RVS spuwer met soepele plakplaat - vierkant - modulair.pdf
IfcRoot - Name: Type 1
Pset_PipeFittingCommon - Reference: Type 1; sets with these values: 3
Pset_Condition - AssessmentCondition: Empty
Name (Afwerkstuk spuwer 70 x 70 RVS:Type 1:...) | In | Level | Elevation from Level
33715879 | 020 | 020 | 3610
33791459 | 020 | 020 | 3670
33700755 | 030 | 030 | 2780 | Qto_PipeFittingBaseQuantities - Length: 120.104; GrossCrossSectionArea: 0.000443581; NetCrossSectionArea: 0.000443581; OuterSurfaceArea: 0.0537722
33715056 | 030 | 030 | 10
33715707 | 030 | 030 | 10
33715847 | 030 | 030 | 10
33716265 | 030 | 030 | 485
33717285 | 030 | 030 | 485
33718496 | 030 | 030 | 485
33718886 | 030 | 030 | 485
33719069 | 030 | 030 | 10
33719443 | 030 | 030 | 10
33724962 | 030 | 030 | 3000
33725274 | 030 | 030 | 3000 | Qto_PipeFittingBaseQuantities - Length: 2; GrossCrossSectionArea: 0.00474433; NetCrossSectionArea: 0.00474433; OuterSurfaceArea: 0.0011263
33819890 | 030 | 030 | 70 | Qto_PipeFittingBaseQuantities - Length: 120.104; GrossCrossSectionArea: 0.000443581; NetCrossSectionArea: 0.000443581; OuterSurfaceArea: 0.0537722
33823808 | 030 | 030 | 2780 | Qto_PipeFittingBaseQuantities - Length: 120.104; GrossCrossSectionArea: 0.000443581; NetCrossSectionArea: 0.000443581; OuterSurfaceArea: 0.0537722
34178351 | 030 | 030 | 3000
33698668 | 040 | 040 | 2480
33714051 | 050 | 050 | 105 | Qto_PipeFittingBaseQuantities - Length: 120.104; GrossCrossSectionArea: 0.000443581; NetCrossSectionArea: 0.000443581; OuterSurfaceArea: 0.0537722
33714055 | 050 | 050 | 105 | Qto_PipeFittingBaseQuantities - Length: 120.104; GrossCrossSectionArea: 0.000443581; NetCrossSectionArea: 0.000443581; OuterSurfaceArea: 0.0537722

# IfcPipeFitting: BB_05.08_Regenafvoerbuis, rechthoekig, horizontaal_GLI:80 x 80 mm, RVS spuwer (4)
In: 050
PredefinedType: EXIT; Material: BB_Metaal_RVS
Cpset_PipeFitting - LevelOfAccuracy: in te vullen door Buildwise
IfcClassificationReference - Keynote: 05.02.34#02; GVH_artnr 01: 05.02.34#02; GVH_artnr 02: geen waarde gevonden; GVH_artnr 03: geen waarde gevonden; GVH_artnr 04: geen waarde gevonden; GVH_artnr 05: geen waarde gevonden; GVH_artnr 06: geen waarde gevonden; TDS_link: .\05 As Builtdossier\2. Bouwkunde\2.1 Architectuur\2.1.5 dakwerken en dakwaterafvoer\2.1.5.1 dakwerken (Tectum)\TF A 05.08.42 A – RVS spuwer met soepele plakplaat - vierkant - modulair.pdf
IfcRoot - Name: 80 x 80 mm, RVS spuwer
Pset_PipeFittingCommon - Reference: 80 x 80 mm, RVS spuwer; sets with these values: 3
Qto_PipeFittingBaseQuantities - Length: 904; GrossCrossSectionArea: 0.07232; NetCrossSectionArea: 0.07232; OuterSurfaceArea: 0.15744
Pset_Condition - AssessmentCondition: Empty
Name (BB_05.08_Regenafvoerbuis, rechthoekig, horizontaal_GLI:80 x 80 mm, RVS spuwer:...)
32403925
32403936
32403938
32403939

# IfcPipeFitting: BB_05.16_Verluchtingsbuis dak:type diameter 200 (2)
In: 040
PredefinedType: EXIT; Material: <Unnamed>
Cpset_PipeFitting - LevelOfAccuracy: in te vullen door Buildwise
IfcBuildingStorey - Level: 040; Elevation from Level: 150
IfcClassificationReference - Keynote: 05.16.13#01; GVH_artnr 01: 05.16.13#01; GVH_artnr 02: geen waarde gevonden; GVH_artnr 03: geen waarde gevonden; GVH_artnr 04: geen waarde gevonden; GVH_artnr 05: geen waarde gevonden; GVH_artnr 06: geen waarde gevonden; TDS_link: .\05 As Builtdossier\2. Bouwkunde\2.1 Architectuur\2.1.5 dakwerken en dakwaterafvoer\TF 05.16.13 A Schachtverluchting verticale dakdoorbreking.pdf
IfcRoot - Name: type diameter 200
Pset_PipeFittingCommon - Reference: type diameter 200; sets with these values: 3
Pset_Condition - AssessmentCondition: Empty
Name (BB_05.16_Verluchtingsbuis dak:type diameter 200:...)
32799921
32799937

# IfcPipeFitting: BB_05.16_Verluchtingsbuis dak:type diameter 360 (6)
PredefinedType: EXIT; Material: <Unnamed>
Cpset_PipeFitting - LevelOfAccuracy: in te vullen door Buildwise
IfcClassificationReference - Keynote: 05.16.13#02; GVH_artnr 01: 05.16.13#02; GVH_artnr 02: geen waarde gevonden; GVH_artnr 03: geen waarde gevonden; GVH_artnr 04: geen waarde gevonden; GVH_artnr 05: geen waarde gevonden; GVH_artnr 06: geen waarde gevonden; TDS_link: .\05 As Builtdossier\2. Bouwkunde\2.1 Architectuur\2.1.5 dakwerken en dakwaterafvoer\TF 05.16.13 A Schachtverluchting verticale dakdoorbreking.pdf
IfcRoot - Name: type diameter 360
Pset_PipeFittingCommon - Reference: type diameter 360; sets with these values: 3
Pset_Condition - AssessmentCondition: Empty
Name (BB_05.16_Verluchtingsbuis dak:type diameter 360:...) | In | Level | Elevation from Level
32526656 | 040 | 040 | 200
32799903 | 040 | 040 | 200
32799935 | 040 | 040 | 220
32799936 | 040 | 040 | 200
32799966 | 050 | 050 | 250
32799967 | 050 | 050 | 250

# IfcPipeFitting: Spuwer 70 x 70 RVS:Type 1 (12)
In: 030
PredefinedType: EXIT; Material: <Unnamed>
Cpset_PipeFitting - LevelOfAccuracy: in te vullen door Buildwise
IfcBuildingStorey - Level: 030
IfcClassificationReference - TDS_link: .\05 As Builtdossier\2. Bouwkunde\2.1 Architectuur\2.1.5 dakwerken en dakwaterafvoer\2.1.5.1 dakwerken (Tectum)\TF A 05.08.42 A – RVS spuwer met soepele plakplaat - vierkant - modulair.pdf
IfcRoot - Name: Type 1
Pset_PipeFittingCommon - Reference: Type 1; sets with these values: 3
Pset_Condition - AssessmentCondition: Empty
Name (Spuwer 70 x 70 RVS:Type 1:...) | Elevation from Level
33716559 | 698
33717373 | 698
33718274 | 698
33718827 | 698
33812378 | 707.6
33923860 | 698 | Qto_PipeFittingBaseQuantities - Length: 760; GrossCrossSectionArea: 0.000424; NetCrossSectionArea: 0.000424; OuterSurfaceArea: 0.32528
33926760 | 698
33928610 | 698 | Qto_PipeFittingBaseQuantities - Length: 750; GrossCrossSectionArea: 0.000424; NetCrossSectionArea: 0.000424; OuterSurfaceArea: 0.321
33985791 | 698
33986320 | 698
33990401 | 698
33991748 | 698 | Qto_PipeFittingBaseQuantities - Length: 800; GrossCrossSectionArea: 0.000424; NetCrossSectionArea: 0.000424; OuterSurfaceArea: 0.3424

# IfcPipeSegment: BB_05.02.34#07_Bakgoot aan zijkanten sheddak:XX_Geen (2)
In: 050
PredefinedType: GUTTER; Material: BB_05.02.34_Aluminium_Dakrand_Sheds
Cpset_PipeSegment - LevelOfAccuracy: in te vullen door Buildwise
IfcClassificationReference - Keynote: 05.02.34#07; GVH_artnr 01: 05.02.34#07; GVH_artnr 02: geen waarde gevonden; GVH_artnr 03: geen waarde gevonden; GVH_artnr 04: geen waarde gevonden; GVH_artnr 05: geen waarde gevonden; GVH_artnr 06: geen waarde gevonden; TDS_link: .\05 As Builtdossier\2. Bouwkunde\2.1 Architectuur\2.1.5 dakwerken en dakwaterafvoer\2.1.5.3 dakwerken (MSB)\Technische fiches\TF A 05.02.34 A – Dakbedekking uit aluminiumbladen – zet- en plooiwerk.pdf
IfcRoot - Name: XX_Geen
Pset_PipeSegmentCommon - Reference: XX_Geen; sets with these values: 3
Qto_PipeSegmentBaseQuantities - Length: 10300; GrossCrossSectionArea: 0.001132; NetCrossSectionArea: 0.001132; OuterSurfaceArea: 11.7008
Pset_Condition - AssessmentCondition: Empty
Name (BB_05.02.34#07_Bakgoot aan zijkanten sheddak:XX_Geen:...)
32123281
32123293

# IfcPlate: BB_07.06_Buitenbeglazing, rechthoekig_GMO:07.04.63#01_Vulpaneel, 44 mm (11)
PredefinedType: USERDEFINED; Material: BB_Metaal_Aluminium_Buitenschrijnwerk
Cpset_Plate - LevelOfAccuracy: in te vullen door Buildwise
IfcClassificationReference - GVH_artnr 01: 07.04.63#01; GVH_artnr 02: geen waarde gevonden; GVH_artnr 03: geen waarde gevonden; GVH_artnr 04: geen waarde gevonden; GVH_artnr 05: geen waarde gevonden; GVH_artnr 06: geen waarde gevonden
IfcRoot - Name: 07.04.63#01_Vulpaneel, 44 mm
Pset_Condition - AssessmentCondition: Empty
Pset_EnvironmentalImpactIndicators - Reference: 07.04.63#01_Vulpaneel, 44 mm
Pset_PlateCommon - Reference: 07.04.63#01_Vulpaneel, 44 mm; IsExternal: no
Name (BB_07.06_Buitenbeglazing, rechthoekig_GMO:07.04.63#01_Vulpaneel, 44 mm:...) | In | Elevation from Level | Width | Perimeter | GrossArea | GrossVolume = NetVolume
24342302 | K20 | -57967.7 | 888 | 5468 | 1.63925 | 0.0721269
24342457 | K20 | -57967.7 | 1846 | 5468 | 1.63925 | 0.0721269
8572673 | 000 | 1354.5 | 2458 | 6904 | 2.44325 | 0.107503
8574225 | 000 | 1354.5 | 994 | 6904 | 2.44325 | 0.107503
12086869 | 000 | 11834 | 2473 | 7274 | 2.87857 | 0.126657
12086879 | 000 | 11834 | 1164 | 7274 | 2.87857 | 0.126657
4901519 | 010 | 11834 | 1164 | 7274 | 2.87857 | 0.126657
4901625 | 010 | 11834 | 2473 | 7274 | 2.87857 | 0.126657
3683747 | 020 | 11834 | 1164 | 7274 | 2.87857 | 0.126657
4032890 | 020 | 11834 | 2473 | 7274 | 2.87857 | 0.126657
24065877 | 040 | 15307.5 | 1585 | 4726 | 1.23313 | 0.0542577

# IfcPlate: BB_07.06_Buitenbeglazing, rechthoekig_GMO:07.06.41#01_Dubbele beglazing sheds, 28 mm (24)
In: 050
PredefinedType: USERDEFINED; Material: BB_Glas
Cpset_Plate - LevelOfAccuracy: in te vullen door Buildwise
IfcBuildingStorey - Level: 050; Elevation from Level: 56864.5
IfcClassificationReference - Keynote: 07.06.41#01; GVH_artnr 01: 07.06.41#01; GVH_artnr 02: geen waarde gevonden; GVH_artnr 03: geen waarde gevonden; GVH_artnr 04: geen waarde gevonden; GVH_artnr 05: geen waarde gevonden; GVH_artnr 06: geen waarde gevonden; TDS_link: .\05 As Builtdossier\2. Bouwkunde\2.1 Architectuur\2.1.7 Gevelsluiting\2.1.7.2 buitenschrijnwerk alu (Vorsselmans)\Technische fiches\TF A 07.06.41 A Dubbele beglazing U=1.0.pdf
IfcRoot - Name: 07.06.41#01_Dubbele beglazing sheds, 28 mm
Qto_PlateBaseQuantities - Width: 889.1; Perimeter: 4696.2; GrossArea: 1.2972; GrossVolume: 0.0363215; NetVolume: 0.0363215
Pset_Condition - AssessmentCondition: Empty
Pset_EnvironmentalImpactIndicators - Reference: 07.06.41#01_Dubbele beglazing sheds, 28 mm
Pset_PlateCommon - Reference: 07.06.41#01_Dubbele beglazing sheds, 28 mm; AcousticRating: 41; IsExternal: no; ThermalTransmittance: 1
Name (BB_07.06_Buitenbeglazing, rechthoekig_GMO:07.06.41#01_Dubbele beglazing sheds, 28 mm:...)
10542483
10544956
10544957
10544958
10544959
10544960
10544961
10544962
10545047
10545048
10545049
10545050
10545051
10545052
10545053
10545187
10545188
10545189
10545190
10545191
10545192
10545193
10545194
10545195

# IfcPlate: BB_07.06_Buitenbeglazing, rechthoekig_GMO:07.06.41#03_Dubbele beglazing RWA +0, 28 mm (14)
In: 000
PredefinedType: USERDEFINED; Material: BB_Glas
Cpset_Plate - LevelOfAccuracy: in te vullen door Buildwise
IfcClassificationReference - Keynote: 07.06.41#03; GVH_artnr 01: 07.06.41#03; GVH_artnr 02: geen waarde gevonden; GVH_artnr 03: geen waarde gevonden; GVH_artnr 04: geen waarde gevonden; GVH_artnr 05: geen waarde gevonden; GVH_artnr 06: geen waarde gevonden; TDS_link: .\05 As Builtdossier\2. Bouwkunde\2.1 Architectuur\2.1.7 Gevelsluiting\2.1.7.2 buitenschrijnwerk alu (Vorsselmans)\Technische fiches\TF A 07.06.41 A Dubbele beglazing U=1.0.pdf
IfcRoot - Name: 07.06.41#03_Dubbele beglazing RWA +0, 28 mm
Pset_Condition - AssessmentCondition: Empty
Pset_EnvironmentalImpactIndicators - Reference: 07.06.41#03_Dubbele beglazing RWA +0, 28 mm
Pset_PlateCommon - Reference: 07.06.41#03_Dubbele beglazing RWA +0, 28 mm; AcousticRating: 39; IsExternal: no; ThermalTransmittance: 1
Name (BB_07.06_Buitenbeglazing, rechthoekig_GMO:07.06.41#03_Dubbele beglazing RWA +0, 28 mm:...) | Elevation from Level | Width | Perimeter | GrossArea | GrossVolume = NetVolume
5685945 | 8163 | 1242 | 5688 | 1.98968 | 0.0557112
5685946 | 8163 | 1522 | 6248 | 2.43824 | 0.0682708
5685947 | 8163 | 1242 | 5688 | 1.98968 | 0.0557112
5685953 | 8163 | 1602 | 5688 | 1.98968 | 0.0557112
5685954 | 8163 | 1602 | 6248 | 2.43824 | 0.0682708
5685955 | 8163 | 1602 | 5688 | 1.98968 | 0.0557112
5876042 | -18661.4 | 1244 | 5692 | 1.99289 | 0.0558009
5876043 | -18661.4 | 1552 | 6308 | 2.4863 | 0.0696165
5876044 | -18661.4 | 1552 | 6308 | 2.4863 | 0.0696165
5876045 | -18661.4 | 1244 | 5692 | 1.99289 | 0.0558009
5876208 | -18661.4 | 1602 | 5692 | 1.99289 | 0.0558009
5876209 | -18661.4 | 1602 | 6308 | 2.4863 | 0.0696165
5876210 | -18661.4 | 1602 | 6308 | 2.4863 | 0.0696165
5876211 | -18661.4 | 1602 | 5692 | 1.99289 | 0.0558009

# IfcPlate: BB_07.06_Buitenbeglazing, rechthoekig_GMO:07.06.72#01_Drievoudige beglazing, 44 mm, A/A*/A (238)
PredefinedType: USERDEFINED; Material: BB_Glas
Cpset_Plate - LevelOfAccuracy: in te vullen door Buildwise
IfcClassificationReference - Keynote: 07.06.72#01; GVH_artnr 01: 07.06.72#01; GVH_artnr 02: geen waarde gevonden; GVH_artnr 03: geen waarde gevonden; GVH_artnr 04: geen waarde gevonden; GVH_artnr 05: geen waarde gevonden; GVH_artnr 06: geen waarde gevonden; TDS_link: .\05 As Builtdossier\2. Bouwkunde\2.1 Architectuur\2.1.7 Gevelsluiting\2.1.7.2 buitenschrijnwerk alu (Vorsselmans)\Technische fiches\TF A 07.06.72 A Drievoudige beglazing.pdf
IfcRoot - Name: 07.06.72#01_Drievoudige beglazing, 44 mm, A/A*/A
Pset_Condition - AssessmentCondition: Empty
Pset_EnvironmentalImpactIndicators - Reference: 07.06.72#01_Drievoudige beglazing, 44 mm, A/A*/A
Pset_PlateCommon - Reference: 07.06.72#01_Drievoudige beglazing, 44 mm, A/A*/A; AcousticRating: 40; IsExternal: no; ThermalTransmittance: 0.6
Name (BB_07.06_Buitenbeglazing, rechthoekig_GMO:07.06.72#01_Drievoudige beglazing, 44 mm, A/A*/A:...) | In | Elevation from Level | Width | Perimeter | GrossArea | GrossVolume = NetVolume
27090612 | K10 | -1859 | 2720 | 9516 | 5.54336 | 0.243908
4901417 | 010 | -10371.7 | 652 | 4508 | 1.0445 | 0.0459582
4901418 | 010 | -10371.7 | 2222 | 7804 | 3.73296 | 0.16425
4901419 | 010 | -10371.7 | 2222 | 7804 | 3.73296 | 0.16425
4901420 | 010 | -10371.7 | 652 | 4508 | 1.0445 | 0.0459582
4901427 | 010 | -13963.3 | 652 | 4508 | 1.0445 | 0.0459582
4901428 | 010 | -13963.3 | 2432 | 8224 | 4.08576 | 0.179773
4901429 | 010 | -13963.3 | 2432 | 8224 | 4.08576 | 0.179773
4901430 | 010 | -13963.3 | 652 | 4508 | 1.0445 | 0.0459582
4901437 | 010 | 8144 | 1332.6 | 6025.2 | 2.23877 | 0.0985058
4901438 | 010 | 8144 | 3306.4 | 9972.8 | 5.55475 | 0.244409
4901445 | 010 | -10371.7 | 652 | 4508 | 1.0445 | 0.0459582
4901446 | 010 | -10371.7 | 2222 | 7804 | 3.73296 | 0.16425
4901447 | 010 | -10371.7 | 2222 | 7804 | 3.73296 | 0.16425
4901448 | 010 | -10371.7 | 652 | 4508 | 1.0445 | 0.0459582
4901455 | 010 | -10371.7 | 652 | 4508 | 1.0445 | 0.0459582
4901456 | 010 | -10371.7 | 2222 | 7804 | 3.73296 | 0.16425
4901457 | 010 | -10371.7 | 2222 | 7804 | 3.73296 | 0.16425
4901458 | 010 | -10371.7 | 652 | 4508 | 1.0445 | 0.0459582
4901465 | 010 | -13963.3 | 1602 | 4508 | 1.0445 | 0.0459582
4901466 | 010 | -13963.3 | 1680 | 8224 | 4.08576 | 0.179773
4901467 | 010 | -13963.3 | 1680 | 9960 | 5.544 | 0.243936
4901475 | 010 | 8144 | 652 | 4508 | 1.0445 | 0.0459582
4901476 | 010 | 8144 | 1532 | 6424 | 2.57376 | 0.113245
4901477 | 010 | 8144 | 2400 | 8160 | 4.032 | 0.177408
4901483 | 010 | 8144 | 1602 | 4508 | 1.0445 | 0.0459582
4901484 | 010 | 8144 | 1680 | 6424 | 2.57376 | 0.113245
4901485 | 010 | 8144 | 1680 | 8160 | 4.032 | 0.177408
4901491 | 010 | -10371.7 | 652 | 4508 | 1.0445 | 0.0459582
4901492 | 010 | -10371.7 | 2222 | 7804 | 3.73296 | 0.16425
4901493 | 010 | -10371.7 | 2222 | 7804 | 3.73296 | 0.16425
4901494 | 010 | -10371.7 | 652 | 4508 | 1.0445 | 0.0459582
4901501 | 010 | 8163 | 1680 | 7860 | 3.78 | 0.16632
4901502 | 010 | 8163 | 1680 | 6004 | 2.22096 | 0.0977222
4901503 | 010 | 8163 | 1680 | 4664 | 1.09536 | 0.0481958
4901509 | 010 | -10371.7 | 652 | 4508 | 1.0445 | 0.0459582
4901510 | 010 | -10371.7 | 2222 | 7804 | 3.73296 | 0.16425
4901511 | 010 | -10371.7 | 2222 | 7804 | 3.73296 | 0.16425
4901512 | 010 | -10371.7 | 652 | 4508 | 1.0445 | 0.0459582
4901523 | 010 | -10371.7 | 1602 | 4508 | 1.0445 | 0.0459582
4901524 | 010 | -10371.7 | 1680 | 7804 | 3.73296 | 0.16425
4901525 | 010 | -10371.7 | 1680 | 7804 | 3.73296 | 0.16425
4901526 | 010 | -10371.7 | 1602 | 4508 | 1.0445 | 0.0459582
4901533 | 010 | -13963.3 | 1602 | 4508 | 1.0445 | 0.0459582
4901534 | 010 | -13963.3 | 1680 | 8224 | 4.08576 | 0.179773
4901535 | 010 | -13963.3 | 1680 | 8224 | 4.08576 | 0.179773
4901536 | 010 | -13963.3 | 1602 | 4508 | 1.0445 | 0.0459582
4901543 | 010 | 8144 | 1680 | 6025.2 | 2.23877 | 0.0985058
4901544 | 010 | 8144 | 1680 | 9932.8 | 5.52115 | 0.242931
4901551 | 010 | -10371.7 | 1602 | 4508 | 1.0445 | 0.0459582
4901552 | 010 | -10371.7 | 1680 | 7804 | 3.73296 | 0.16425
4901553 | 010 | -10371.7 | 1680 | 7804 | 3.73296 | 0.16425
4901554 | 010 | -10371.7 | 1602 | 4508 | 1.0445 | 0.0459582
4901561 | 010 | -10371.7 | 1602 | 4508 | 1.0445 | 0.0459582
4901562 | 010 | -10371.7 | 1680 | 7804 | 3.73296 | 0.16425
4901563 | 010 | -10371.7 | 1680 | 7804 | 3.73296 | 0.16425
4901564 | 010 | -10371.7 | 1602 | 4508 | 1.0445 | 0.0459582
4901571 | 010 | -13963.3 | 652 | 4508 | 1.0445 | 0.0459582
4901572 | 010 | -13963.3 | 2432 | 8224 | 4.08576 | 0.179773
4901573 | 010 | -13963.3 | 3300 | 9960 | 5.544 | 0.243936
4901581 | 010 | 8144 | 1602 | 4508 | 1.0445 | 0.0459582
4901582 | 010 | 8144 | 1680 | 6424 | 2.57376 | 0.113245
4901583 | 010 | 8144 | 1680 | 8160 | 4.032 | 0.177408
4901589 | 010 | 8144 | 652 | 4508 | 1.0445 | 0.0459582
4901590 | 010 | 8144 | 1532 | 6424 | 2.57376 | 0.113245
4901591 | 010 | 8144 | 2400 | 8160 | 4.032 | 0.177408
4901597 | 010 | -10371.7 | 1602 | 4508 | 1.0445 | 0.0459582
4901598 | 010 | -10371.7 | 1680 | 7804 | 3.73296 | 0.16425
4901599 | 010 | -10371.7 | 1680 | 7804 | 3.73296 | 0.16425
4901600 | 010 | -10371.7 | 1602 | 4508 | 1.0445 | 0.0459582
4901607 | 010 | 8163 | 2250 | 7860 | 3.78 | 0.16632
4901608 | 010 | 8163 | 1322 | 6004 | 2.22096 | 0.0977222
4901615 | 010 | -10371.7 | 1602 | 4508 | 1.0445 | 0.0459582
4901616 | 010 | -10371.7 | 1680 | 7804 | 3.73296 | 0.16425
4901617 | 010 | -10371.7 | 1680 | 7804 | 3.73296 | 0.16425
4901618 | 010 | -10371.7 | 1602 | 4508 | 1.0445 | 0.0459582
9846376 | 010 | 8125 | 1108 | 5576 | 1.86144 | 0.0819034
9846379 | 010 | 8125 | 1030 | 5264 | 1.65006 | 0.0726026
9846382 | 010 | 8125 | 1108 | 5576 | 1.86144 | 0.0819034
9846385 | 010 | 8125 | 1108 | 5576 | 1.86144 | 0.0819034
9846388 | 010 | 8125 | 1680 | 5576 | 1.86144 | 0.0819034
9846391 | 010 | 8125 | 1602 | 5264 | 1.65006 | 0.0726026
9846394 | 010 | 8125 | 1680 | 5576 | 1.86144 | 0.0819034
9846397 | 010 | 8125 | 1680 | 5576 | 1.86144 | 0.0819034
9846400 | 010 | 8125 | 1602 | 5396 | 1.75579 | 0.0772548 | IfcElement - Tag: R K.10.301 / 10; BB_Element_Code01: R K.10.301 / 10
9846403 | 010 | 8125 | 1096 | 5396 | 1.75579 | 0.0772548 | IfcElement - Tag: R K.10.301 / 01; BB_Element_Code01: R K.10.301 / 01
32280637 | 010 | 5365 | 652 | 4664 | 1.09536 | 0.0481958
3389475 | 020 | -10371.7 | 652 | 4508 | 1.0445 | 0.0459582
3389476 | 020 | -10371.7 | 2222 | 7804 | 3.73296 | 0.16425
3389477 | 020 | -10371.7 | 2222 | 7804 | 3.73296 | 0.16425
3389478 | 020 | -10371.7 | 652 | 4508 | 1.0445 | 0.0459582
3389619 | 020 | -13963.3 | 652 | 4508 | 1.0445 | 0.0459582
3389620 | 020 | -13963.3 | 2432 | 8224 | 4.08576 | 0.179773
3389621 | 020 | -13963.3 | 2432 | 8224 | 4.08576 | 0.179773
3389622 | 020 | -13963.3 | 652 | 4508 | 1.0445 | 0.0459582
3389885 | 020 | 8144 | 1602 | 4508 | 1.0445 | 0.0459582
3389886 | 020 | 8144 | 1680 | 8164 | 4.03536 | 0.177556
3389887 | 020 | 8144 | 1680 | 6060 | 2.268 | 0.099792
3404283 | 020 | -10371.7 | 652 | 4508 | 1.0445 | 0.0459582
3404284 | 020 | -10371.7 | 2222 | 7804 | 3.73296 | 0.16425
3404285 | 020 | -10371.7 | 2222 | 7804 | 3.73296 | 0.16425
3404286 | 020 | -10371.7 | 652 | 4508 | 1.0445 | 0.0459582
3404703 | 020 | -10371.7 | 652 | 4508 | 1.0445 | 0.0459582
3404704 | 020 | -10371.7 | 2222 | 7804 | 3.73296 | 0.16425
3404705 | 020 | -10371.7 | 2222 | 7804 | 3.73296 | 0.16425
3404706 | 020 | -10371.7 | 652 | 4508 | 1.0445 | 0.0459582
3404825 | 020 | -13963.3 | 1602 | 4508 | 1.0445 | 0.0459582
3404826 | 020 | -13963.3 | 1680 | 8224 | 4.08576 | 0.179773
3404827 | 020 | -13963.3 | 1680 | 9960 | 5.544 | 0.243936
3405218 | 020 | 8144 | 652 | 4508 | 1.0445 | 0.0459582
3405219 | 020 | 8144 | 1532 | 6424 | 2.57376 | 0.113245
3405220 | 020 | 8144 | 2400 | 8160 | 4.032 | 0.177408
3425453 | 020 | 8144 | 1602 | 4508 | 1.0445 | 0.0459582
3425454 | 020 | 8144 | 1680 | 6424 | 2.57376 | 0.113245
3425455 | 020 | 8144 | 1680 | 8160 | 4.032 | 0.177408
3425526 | 020 | -10371.7 | 652 | 4508 | 1.0445 | 0.0459582
3425527 | 020 | -10371.7 | 2222 | 7804 | 3.73296 | 0.16425
3425528 | 020 | -10371.7 | 2222 | 7804 | 3.73296 | 0.16425
3425529 | 020 | -10371.7 | 652 | 4508 | 1.0445 | 0.0459582
3501892 | 020 | 8163 | 1680 | 7860 | 3.78 | 0.16632
3501893 | 020 | 8163 | 1680 | 6004 | 2.22096 | 0.0977222
3501894 | 020 | 8163 | 1680 | 4664 | 1.09536 | 0.0481958
3593254 | 020 | -10371.7 | 652 | 4508 | 1.0445 | 0.0459582
3593255 | 020 | -10371.7 | 2222 | 7804 | 3.73296 | 0.16425
3593256 | 020 | -10371.7 | 2222 | 7804 | 3.73296 | 0.16425
3593257 | 020 | -10371.7 | 652 | 4508 | 1.0445 | 0.0459582
4032788 | 020 | -10371.7 | 1602 | 4508 | 1.0445 | 0.0459582
4032789 | 020 | -10371.7 | 1680 | 7804 | 3.73296 | 0.16425
4032790 | 020 | -10371.7 | 1680 | 7804 | 3.73296 | 0.16425
4032791 | 020 | -10371.7 | 1602 | 4508 | 1.0445 | 0.0459582
4032798 | 020 | -13963.3 | 1602 | 4508 | 1.0445 | 0.0459582
4032799 | 020 | -13963.3 | 1680 | 8224 | 4.08576 | 0.179773
4032800 | 020 | -13963.3 | 1680 | 8224 | 4.08576 | 0.179773
4032801 | 020 | -13963.3 | 1602 | 4508 | 1.0445 | 0.0459582
4032808 | 020 | 8144 | 642 | 4488 | 1.02848 | 0.0452533
4032809 | 020 | 8144 | 2402 | 8164 | 4.03536 | 0.177556
4032810 | 020 | 8144 | 1340 | 6040 | 2.2512 | 0.0990528
4032816 | 020 | -10371.7 | 1602 | 4508 | 1.0445 | 0.0459582
4032817 | 020 | -10371.7 | 1680 | 7804 | 3.73296 | 0.16425
4032818 | 020 | -10371.7 | 1680 | 7804 | 3.73296 | 0.16425
4032819 | 020 | -10371.7 | 1602 | 4508 | 1.0445 | 0.0459582
4032826 | 020 | -10371.7 | 1602 | 4508 | 1.0445 | 0.0459582
4032827 | 020 | -10371.7 | 1680 | 7804 | 3.73296 | 0.16425
4032828 | 020 | -10371.7 | 1680 | 7804 | 3.73296 | 0.16425
4032829 | 020 | -10371.7 | 1602 | 4508 | 1.0445 | 0.0459582
4032836 | 020 | -13963.3 | 652 | 4508 | 1.0445 | 0.0459582
4032837 | 020 | -13963.3 | 2432 | 8224 | 4.08576 | 0.179773
4032838 | 020 | -13963.3 | 3300 | 9960 | 5.544 | 0.243936
4032846 | 020 | 8144 | 1602 | 4508 | 1.0445 | 0.0459582
4032847 | 020 | 8144 | 1680 | 6424 | 2.57376 | 0.113245
4032848 | 020 | 8144 | 1680 | 8160 | 4.032 | 0.177408
4032854 | 020 | 8144 | 652 | 4508 | 1.0445 | 0.0459582
4032855 | 020 | 8144 | 1532 | 6424 | 2.57376 | 0.113245
4032856 | 020 | 8144 | 2400 | 8160 | 4.032 | 0.177408
4032862 | 020 | -10371.7 | 1602 | 4508 | 1.0445 | 0.0459582
4032863 | 020 | -10371.7 | 1680 | 7804 | 3.73296 | 0.16425
4032864 | 020 | -10371.7 | 1680 | 7804 | 3.73296 | 0.16425
4032865 | 020 | -10371.7 | 1602 | 4508 | 1.0445 | 0.0459582
4032872 | 020 | 8163 | 2250 | 7860 | 3.78 | 0.16632
4032873 | 020 | 8163 | 1322 | 6004 | 2.22096 | 0.0977222
4032874 | 020 | 8163 | 652 | 4664 | 1.09536 | 0.0481958
4032880 | 020 | -10371.7 | 1602 | 4508 | 1.0445 | 0.0459582
4032881 | 020 | -10371.7 | 1680 | 7804 | 3.73296 | 0.16425
4032882 | 020 | -10371.7 | 1680 | 7804 | 3.73296 | 0.16425
4032883 | 020 | -10371.7 | 1602 | 4508 | 1.0445 | 0.0459582
4432921 | 020 | 8125 | 1108 | 5576 | 1.86144 | 0.0819034
4580646 | 020 | 8125 | 1030 | 5264 | 1.65006 | 0.0726026
4580659 | 020 | 8125 | 1108 | 5576 | 1.86144 | 0.0819034
4580663 | 020 | 8125 | 1108 | 5576 | 1.86144 | 0.0819034
4580672 | 020 | 8125 | 1680 | 5576 | 1.86144 | 0.0819034
4580675 | 020 | 8125 | 1602 | 5264 | 1.65006 | 0.0726026
4580678 | 020 | 8125 | 1680 | 5576 | 1.86144 | 0.0819034
4580681 | 020 | 8125 | 1680 | 5576 | 1.86144 | 0.0819034
4822745 | 020 | 8125 | 1602 | 5396 | 1.75579 | 0.0772548 | IfcElement - Tag: R K.20.303 / 10; BB_Element_Code01: R K.20.303 / 10
4870374 | 020 | 8125 | 1096 | 5396 | 1.75579 | 0.0772548 | IfcElement - Tag: R K.20.303 / 01; BB_Element_Code01: R K.20.303 / 01
4901631 | 030 | -10371.7 | 652 | 4508 | 1.0445 | 0.0459582
4901632 | 030 | -10371.7 | 2222 | 7804 | 3.73296 | 0.16425
4901633 | 030 | -10371.7 | 2222 | 7804 | 3.73296 | 0.16425
4901634 | 030 | -10371.7 | 652 | 4508 | 1.0445 | 0.0459582
4901651 | 030 | 8144 | 1602 | 4508 | 1.0445 | 0.0459582
4901652 | 030 | 8144 | 1680 | 8164 | 4.03536 | 0.177556
4901653 | 030 | 8144 | 1680 | 6060 | 2.268 | 0.099792
4901659 | 030 | -10371.7 | 652 | 4508 | 1.0445 | 0.0459582
4901660 | 030 | -10371.7 | 2222 | 7804 | 3.73296 | 0.16425
4901661 | 030 | -10371.7 | 2222 | 7804 | 3.73296 | 0.16425
4901662 | 030 | -10371.7 | 652 | 4508 | 1.0445 | 0.0459582
4901669 | 030 | -10371.7 | 652 | 4508 | 1.0445 | 0.0459582
4901670 | 030 | -10371.7 | 2222 | 7804 | 3.73296 | 0.16425
4901671 | 030 | -10371.7 | 2222 | 7804 | 3.73296 | 0.16425
4901672 | 030 | -10371.7 | 652 | 4508 | 1.0445 | 0.0459582
4901737 | 030 | -10371.7 | 1602 | 4508 | 1.0445 | 0.0459582
4901738 | 030 | -10371.7 | 1680 | 7804 | 3.73296 | 0.16425
4901739 | 030 | -10371.7 | 1680 | 7804 | 3.73296 | 0.16425
4901740 | 030 | -10371.7 | 1602 | 4508 | 1.0445 | 0.0459582
4901757 | 030 | 8144 | 642 | 4488 | 1.02848 | 0.0452533
4901758 | 030 | 8144 | 2402 | 8164 | 4.03536 | 0.177556
4901759 | 030 | 8144 | 1340 | 6040 | 2.2512 | 0.0990528
4901765 | 030 | -10371.7 | 1602 | 4508 | 1.0445 | 0.0459582
4901766 | 030 | -10371.7 | 1680 | 7804 | 3.73296 | 0.16425
4901767 | 030 | -10371.7 | 1680 | 7804 | 3.73296 | 0.16425
4901768 | 030 | -10371.7 | 1602 | 4508 | 1.0445 | 0.0459582
4901775 | 030 | -10371.7 | 1602 | 4508 | 1.0445 | 0.0459582
4901776 | 030 | -10371.7 | 1680 | 7804 | 3.73296 | 0.16425
4901777 | 030 | -10371.7 | 1680 | 7804 | 3.73296 | 0.16425
4901778 | 030 | -10371.7 | 1602 | 4508 | 1.0445 | 0.0459582
4974109 | 030 | -10371.7 | 652 | 4508 | 1.0445 | 0.0459582
4974110 | 030 | -10371.7 | 2252 | 7864 | 3.78336 | 0.166468
4974111 | 030 | -10371.7 | 2252 | 7864 | 3.78336 | 0.166468
4974112 | 030 | -10371.7 | 652 | 4508 | 1.0445 | 0.0459582
4974148 | 030 | -10371.7 | 1602 | 4508 | 1.0445 | 0.0459582
4974149 | 030 | -10371.7 | 1680 | 7864 | 3.78336 | 0.166468
4974150 | 030 | -10371.7 | 1680 | 7864 | 3.78336 | 0.166468
4974151 | 030 | -10371.7 | 1602 | 4508 | 1.0445 | 0.0459582
5065108 | 030 | 11782 | 1680 | 6720 | 2.8224 | 0.124186
5065109 | 030 | 11782 | 1680 | 6720 | 2.8224 | 0.124186
5255560 | 030 | 11725 | 1320 | 6000 | 2.2176 | 0.0975744
5255561 | 030 | 11725 | 1630 | 6620 | 2.7384 | 0.12049
5255562 | 030 | 11725 | 1630 | 6620 | 2.7384 | 0.12049
5255563 | 030 | 11725 | 1320 | 6000 | 2.2176 | 0.0975744
5255696 | 030 | 11725 | 1320 | 6000 | 2.2176 | 0.0975744
5255697 | 030 | 11725 | 1630 | 6620 | 2.7384 | 0.12049
5255698 | 030 | 11725 | 1630 | 6620 | 2.7384 | 0.12049
5255699 | 030 | 11725 | 1320 | 6000 | 2.2176 | 0.0975744
5379414 | 030 | 11782 | 1680 | 6720 | 2.8224 | 0.124186
5379415 | 030 | 11782 | 1680 | 6720 | 2.8224 | 0.124186
5379420 | 030 | 11725 | 1680 | 6000 | 2.2176 | 0.0975744
5379421 | 030 | 11725 | 1680 | 6620 | 2.7384 | 0.12049
5379422 | 030 | 11725 | 1680 | 6620 | 2.7384 | 0.12049
5379423 | 030 | 11725 | 1680 | 6000 | 2.2176 | 0.0975744
5379430 | 030 | 11725 | 1680 | 6000 | 2.2176 | 0.0975744
5379431 | 030 | 11725 | 1680 | 6620 | 2.7384 | 0.12049
5379432 | 030 | 11725 | 1680 | 6620 | 2.7384 | 0.12049
5379433 | 030 | 11725 | 1680 | 6000 | 2.2176 | 0.0975744
8053243 | 030 | 11725 | 1304 | 6044 | 2.24027 | 0.098572
8053244 | 030 | 11725 | 1748 | 6932 | 3.00306 | 0.132135
8053245 | 030 | 11725 | 1670 | 6620 | 2.7388 | 0.120507
8053246 | 030 | 11725 | 1304 | 6044 | 2.24027 | 0.098572
23726952 | 030 | 11725 | 2660 | 8680 | 4.4688 | 0.196627 | IfcElement - Tag: R K.30.202 / 01; BB_Element_Code01: R K.30.202 / 01

# IfcPlate: BB_07.06_Buitenbeglazing, rechthoekig_GMO:07.06.72#02_Drievoudige beglazing, 44 mm, A/A*/P4A RC2, -1 en +0 (82)
PredefinedType: USERDEFINED; Material: BB_Glas
Cpset_Plate - LevelOfAccuracy: in te vullen door Buildwise
IfcClassificationReference - Keynote: 07.06.72#02; GVH_artnr 01: 07.06.72#02; GVH_artnr 02: geen waarde gevonden; GVH_artnr 03: geen waarde gevonden; GVH_artnr 04: geen waarde gevonden; GVH_artnr 05: geen waarde gevonden; GVH_artnr 06: geen waarde gevonden; TDS_link: .\05 As Builtdossier\2. Bouwkunde\2.1 Architectuur\2.1.7 Gevelsluiting\2.1.7.2 buitenschrijnwerk alu (Vorsselmans)\Technische fiches\TF A 07.06.72 A Drievoudige beglazing.pdf
IfcRoot - Name: 07.06.72#02_Drievoudige beglazing, 44 mm, A/A*/P4A RC2, -1 en +0
Pset_Condition - AssessmentCondition: Empty
Pset_EnvironmentalImpactIndicators - Reference: 07.06.72#02_Drievoudige beglazing, 44 mm, A/A*/P4A RC2, -1 en +0
Pset_PlateCommon - Reference: 07.06.72#02_Drievoudige beglazing, 44 mm, A/A*/P4A RC2, -1 en +0; AcousticRating: 42; IsExternal: no; ThermalTransmittance: 0.6
Name (BB_07.06_Buitenbeglazing, rechthoekig_GMO:07.06.72#02_Drievoudige beglazing, 44 mm, A/A*/P4A RC2, -1 en +0:...) | In | Elevation from Level | Width | Perimeter | GrossArea | GrossVolume = NetVolume
4901912 | K10 | 8125 | 1108 | 4856 | 1.46256 | 0.0643526
4901915 | K10 | 8125 | 1030 | 4544 | 1.27926 | 0.0562874
4901918 | K10 | 8125 | 1108 | 4856 | 1.46256 | 0.0643526
4901921 | K10 | 8125 | 1108 | 4856 | 1.46256 | 0.0643526
4901924 | K10 | 8125 | 1320 | 4856 | 1.46256 | 0.0643526
4901927 | K10 | 8125 | 1242 | 4544 | 1.27926 | 0.0562874
4901930 | K10 | 8125 | 1320 | 4856 | 1.46256 | 0.0643526
4901933 | K10 | 8125 | 1320 | 4856 | 1.46256 | 0.0643526
4901936 | K10 | 8125 | 1242 | 4676 | 1.36123 | 0.0598942 | IfcElement - Tag: R K.-1.303 / 08; BB_Element_Code01: R K.-1.303 / 08
4901939 | K10 | 8125 | 1096 | 4676 | 1.36123 | 0.0598942 | IfcElement - Tag: R K.-1.302 / 01; BB_Element_Code01: R K.-1.302 / 01
4901203 | 000 | -10371.7 | 652 | 4508 | 1.0445 | 0.0459582
4901204 | 000 | -10371.7 | 2222 | 7804 | 3.73296 | 0.16425
4901205 | 000 | -10371.7 | 2222 | 7804 | 3.73296 | 0.16425
4901206 | 000 | -10371.7 | 652 | 4508 | 1.0445 | 0.0459582
4901213 | 000 | -13963.3 | 652 | 4508 | 1.0445 | 0.0459582
4901214 | 000 | -13963.3 | 2432 | 8224 | 4.08576 | 0.179773
4901215 | 000 | -13963.3 | 2432 | 8224 | 4.08576 | 0.179773
4901216 | 000 | -13963.3 | 652 | 4508 | 1.0445 | 0.0459582
4901231 | 000 | -10371.7 | 652 | 4508 | 1.0445 | 0.0459582
4901232 | 000 | -10371.7 | 2222 | 7804 | 3.73296 | 0.16425
4901233 | 000 | -10371.7 | 2222 | 7804 | 3.73296 | 0.16425
4901234 | 000 | -10371.7 | 652 | 4508 | 1.0445 | 0.0459582
4901241 | 000 | -10371.7 | 652 | 4508 | 1.0445 | 0.0459582
4901242 | 000 | -10371.7 | 2222 | 7804 | 3.73296 | 0.16425
4901243 | 000 | -10371.7 | 2222 | 7804 | 3.73296 | 0.16425
4901244 | 000 | -10371.7 | 652 | 4508 | 1.0445 | 0.0459582
4901251 | 000 | -13963.3 | 1602 | 4508 | 1.0445 | 0.0459582
4901252 | 000 | -13963.3 | 1680 | 8224 | 4.08576 | 0.179773
4901253 | 000 | -13963.3 | 1680 | 9960 | 5.544 | 0.243936
4901262 | 000 | 8144 | 1532 | 6424 | 2.57376 | 0.113245
4901263 | 000 | 8144 | 2400 | 8160 | 4.032 | 0.177408
4901269 | 000 | 8144 | 1602 | 4508 | 1.0445 | 0.0459582
4901270 | 000 | 8144 | 1680 | 6424 | 2.57376 | 0.113245
4901271 | 000 | 8144 | 1680 | 8160 | 4.032 | 0.177408
4901277 | 000 | -10371.7 | 652 | 4508 | 1.0445 | 0.0459582
4901278 | 000 | -10371.7 | 2222 | 7804 | 3.73296 | 0.16425
4901279 | 000 | -10371.7 | 2222 | 7804 | 3.73296 | 0.16425
4901280 | 000 | -10371.7 | 652 | 4508 | 1.0445 | 0.0459582
4901309 | 000 | -10371.7 | 1602 | 4508 | 1.0445 | 0.0459582
4901310 | 000 | -10371.7 | 1680 | 7804 | 3.73296 | 0.16425
4901311 | 000 | -10371.7 | 1680 | 7804 | 3.73296 | 0.16425
4901312 | 000 | -10371.7 | 1602 | 4508 | 1.0445 | 0.0459582
4901337 | 000 | -10371.7 | 1602 | 4508 | 1.0445 | 0.0459582
4901338 | 000 | -10371.7 | 1680 | 7804 | 3.73296 | 0.16425
4901339 | 000 | -10371.7 | 1680 | 7804 | 3.73296 | 0.16425
4901340 | 000 | -10371.7 | 1602 | 4508 | 1.0445 | 0.0459582
4901347 | 000 | -10371.7 | 1602 | 4508 | 1.0445 | 0.0459582
4901348 | 000 | -10371.7 | 1680 | 7804 | 3.73296 | 0.16425
4901349 | 000 | -10371.7 | 1680 | 7804 | 3.73296 | 0.16425
4901350 | 000 | -10371.7 | 1602 | 4508 | 1.0445 | 0.0459582
4901357 | 000 | -13963.3 | 652 | 4508 | 1.0445 | 0.0459582
4901358 | 000 | -13963.3 | 2432 | 8224 | 4.08576 | 0.179773
4901359 | 000 | -13963.3 | 3300 | 9960 | 5.544 | 0.243936
4901368 | 000 | 8144 | 1680 | 6424 | 2.57376 | 0.113245
4901369 | 000 | 8144 | 1680 | 8160 | 4.032 | 0.177408
4901375 | 000 | 8144 | 652 | 4508 | 1.0445 | 0.0459582
4901376 | 000 | 8144 | 1532 | 6424 | 2.57376 | 0.113245
4901377 | 000 | 8144 | 2400 | 8160 | 4.032 | 0.177408
4901383 | 000 | -10371.7 | 1602 | 4508 | 1.0445 | 0.0459582
4901384 | 000 | -10371.7 | 1680 | 7804 | 3.73296 | 0.16425
4901385 | 000 | -10371.7 | 1680 | 7804 | 3.73296 | 0.16425
4901386 | 000 | -10371.7 | 1602 | 4508 | 1.0445 | 0.0459582
5491286 | 000 | 8144 | 1332.6 | 6025.2 | 2.23877 | 0.0985058
5491287 | 000 | 8144 | 3306.4 | 9972.8 | 5.55475 | 0.244409
5524696 | 000 | 8144 | 1680 | 6025.2 | 2.23877 | 0.0985058
5524697 | 000 | 8144 | 1680 | 9932.8 | 5.52115 | 0.242931
9846344 | 000 | 8125 | 1108 | 5652 | 1.90354 | 0.0837559
9846347 | 000 | 8125 | 1030 | 5264 | 1.65006 | 0.0726026
9846350 | 000 | 8125 | 1108 | 5652 | 1.90354 | 0.0837559
9846353 | 000 | 8125 | 1108 | 5652 | 1.90354 | 0.0837559
9846356 | 000 | 8125 | 1718 | 5652 | 1.90354 | 0.0837559
9846359 | 000 | 8125 | 1602 | 5264 | 1.65006 | 0.0726026
9846362 | 000 | 8125 | 1718 | 5652 | 1.90354 | 0.0837559
9846365 | 000 | 8125 | 1718 | 5652 | 1.90354 | 0.0837559
9846368 | 000 | 8125 | 1640 | 5472 | 1.79744 | 0.0790874 | IfcElement - Tag: R K.00.304 / 05; BB_Element_Code01: R K.00.304 / 05
9846371 | 000 | 8125 | 1096 | 5472 | 1.79744 | 0.0790874 | IfcElement - Tag: R K.00.302 / 01; BB_Element_Code01: R K.00.302 / 01
10775494 | 000 | -13963.3 | 652 | 4508 | 1.0445 | 0.0459582
10775495 | 000 | -13963.3 | 2432 | 8224 | 4.08576 | 0.179773
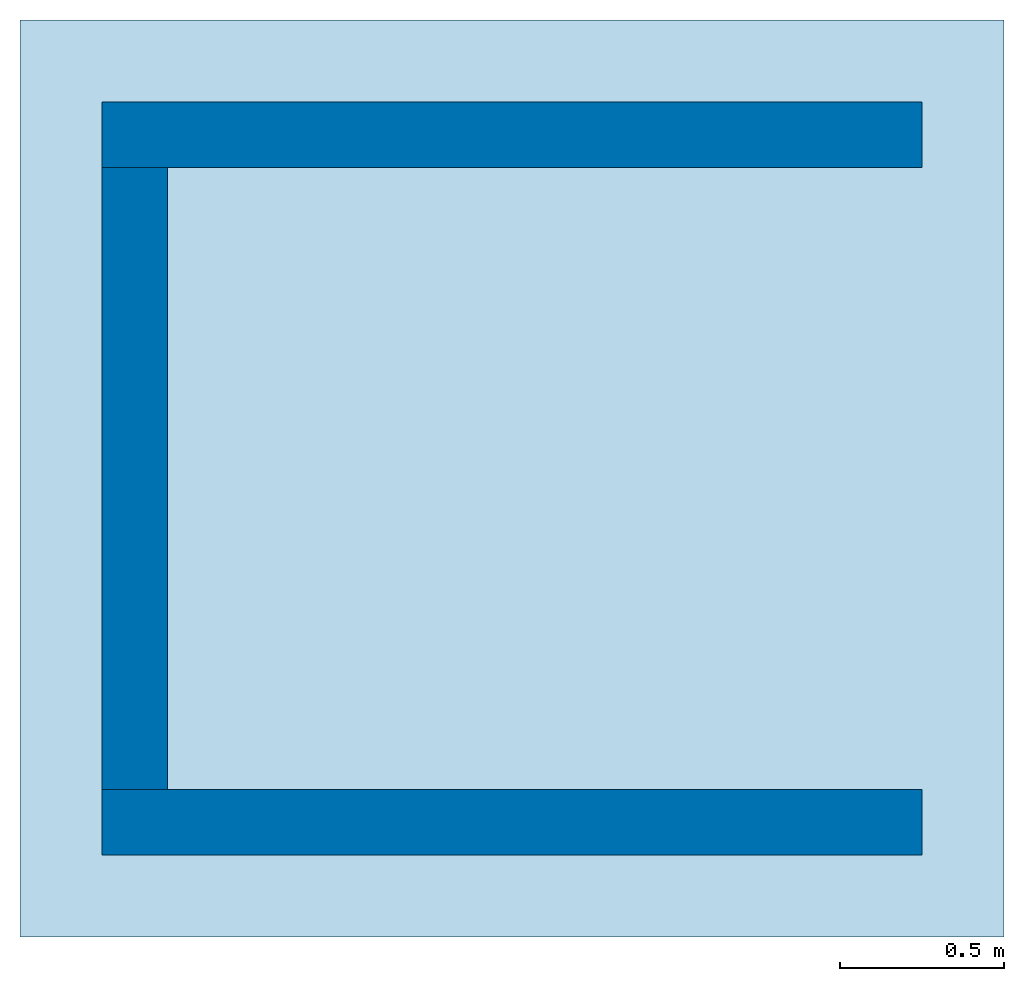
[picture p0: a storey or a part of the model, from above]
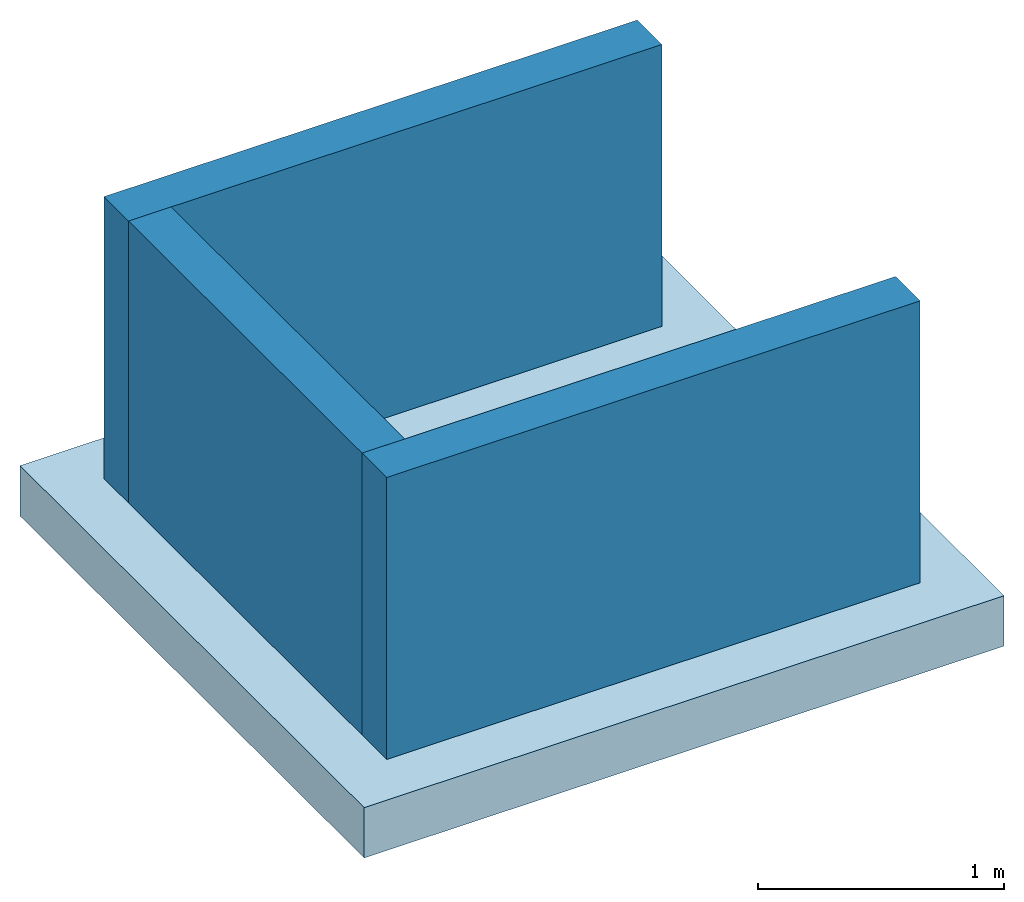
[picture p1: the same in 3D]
Properties of the parts of a building model (IFC4X3_ADD2), part 14 of 28

# IfcPlate: BB_07.06_Buitenbeglazing, rechthoekig_GMO:07.06.72#02_Drievoudige beglazing, 44 mm, A/A*/P4A RC2, -1 en +0 (82)
Name (BB_07.06_Buitenbeglazing, rechthoekig_GMO:07.06.72#02_Drievoudige beglazing, 44 mm, A/A*/P4A RC2, -1 en +0:...) | In | Elevation from Level | Width | Perimeter | GrossArea | GrossVolume = NetVolume
10775496 | 000 | -13963.3 | 2432 | 8224 | 4.08576 | 0.179773
10775497 | 000 | -13963.3 | 652 | 4508 | 1.0445 | 0.0459582
31253864 | 000 | 1765 | 652 | 4508 | 1.0445 | 0.0459582
31343765 | 000 | 1765 | 1602 | 4508 | 1.0445 | 0.0459582

# IfcPlate: BB_07.06_Buitenbeglazing, rechthoekig_GMO:07.06.72#03_Drievoudige beglazing, 44 mm, A/A*/2B2, deuren terrassen (8)
In: 030
PredefinedType: USERDEFINED; Material: BB_Glas
Cpset_Plate - LevelOfAccuracy: in te vullen door Buildwise
IfcClassificationReference - Keynote: 07.06.72#03; GVH_artnr 01: 07.06.72#03; GVH_artnr 02: geen waarde gevonden; GVH_artnr 03: geen waarde gevonden; GVH_artnr 04: geen waarde gevonden; GVH_artnr 05: geen waarde gevonden; GVH_artnr 06: geen waarde gevonden; TDS_link: .\05 As Builtdossier\2. Bouwkunde\2.1 Architectuur\2.1.7 Gevelsluiting\2.1.7.2 buitenschrijnwerk alu (Vorsselmans)\Technische fiches\TF A 07.06.72 A Drievoudige beglazing.pdf
IfcRoot - Name: 07.06.72#03_Drievoudige beglazing, 44 mm, A/A*/2B2, deuren terrassen
Pset_Condition - AssessmentCondition: Empty
Pset_EnvironmentalImpactIndicators - Reference: 07.06.72#03_Drievoudige beglazing, 44 mm, A/A*/2B2, deuren terrassen
Pset_PlateCommon - Reference: 07.06.72#03_Drievoudige beglazing, 44 mm, A/A*/2B2, deuren terrassen; AcousticRating: 44; IsExternal: no; ThermalTransmittance: 0.6
Name (BB_07.06_Buitenbeglazing, rechthoekig_GMO:07.06.72#03_Drievoudige beglazing, 44 mm, A/A*/2B2, deuren terrassen:...) | Elevation from Level | Width | Perimeter | GrossArea | GrossVolume = NetVolume
5289193 | 11801 | 1320 | 7160 | 2.9832 | 0.131261
5289194 | 11801 | 635 | 5519 | 1.34906 | 0.0593585
5289195 | 11801 | 1320 | 7160 | 2.9832 | 0.131261
5345103 | 11840.2 | 635 | 5519 | 1.34906 | 0.0593585
5379440 | 11801 | 2260 | 7160 | 2.9832 | 0.131261
5379441 | 11801 | 2124.5 | 5519 | 1.34906 | 0.0593585
5379442 | 11801 | 2260 | 7160 | 2.9832 | 0.131261
5379447 | 11840.2 | 2124.5 | 5519 | 1.34906 | 0.0593585

# IfcPlate: BB_07.06_Buitenbeglazing, rechthoekig_GMO:07.06.72#04_Drievoudige beglazing, 44 mm, 2B2/A*/2B2 (2)
In: K10
PredefinedType: USERDEFINED; Material: BB_Glas
Cpset_Plate - LevelOfAccuracy: in te vullen door Buildwise
IfcBuildingStorey - Elevation from Level: 23029.3
IfcClassificationReference - Keynote: 07.06.72#04; GVH_artnr 01: 07.06.72#04; GVH_artnr 02: geen waarde gevonden; GVH_artnr 03: geen waarde gevonden; GVH_artnr 04: geen waarde gevonden; GVH_artnr 05: geen waarde gevonden; GVH_artnr 06: geen waarde gevonden; TDS_link: .\05 As Builtdossier\2. Bouwkunde\2.1 Architectuur\2.1.7 Gevelsluiting\2.1.7.2 buitenschrijnwerk alu (Vorsselmans)\Technische fiches\TF A 07.06.72 A Drievoudige beglazing.pdf
IfcElement - Tag: D K.-1.301 / 01; BB_Element_Lokaalnummer01: K.-1.301; BB_Element_Code01: D K.-1.301 / 01
IfcRoot - Name: 07.06.72#04_Drievoudige beglazing, 44 mm, 2B2/A*/2B2
Pset_Condition - AssessmentCondition: Empty
Pset_EnvironmentalImpactIndicators - Reference: 07.06.72#04_Drievoudige beglazing, 44 mm, 2B2/A*/2B2
Pset_PlateCommon - Reference: 07.06.72#04_Drievoudige beglazing, 44 mm, 2B2/A*/2B2; AcousticRating: 45; IsExternal: no; ThermalTransmittance: 0.6
Name (BB_07.06_Buitenbeglazing, rechthoekig_GMO:07.06.72#04_Drievoudige beglazing, 44 mm, 2B2/A*/2B2:...) | Width | Perimeter | GrossArea | GrossVolume | NetVolume
21414598 | 755 | 5395 | 1.46659 | 0.0645299 | 0.0645298
21414601 | 1942.5 | 5445 | 1.51515 | 0.0666666 | 0.0666666

# IfcPlate: BB_07.06_Buitenbeglazing, rechthoekig_GMO:07.06.72#04_Drievoudige beglazing, 44 mm, 2B2/A*/2B2, inkom gordijngevel, BB_07.06_Buitenbeglazing, rechthoekig_GMO:07.06.72#04_Drievoudige beglazing, 44 mm, 2B2/A*/2B2, inkom gordijngevel:15951940
In: 000
PredefinedType: USERDEFINED; Material: BB_Glas
Cpset_Plate - LevelOfAccuracy: in te vullen door Buildwise
IfcBuildingStorey - Level: 000; Elevation from Level: -7360.05
IfcClassificationReference - Keynote: 07.06.72#01; GVH_artnr 01: 07.06.72#01; GVH_artnr 02: geen waarde gevonden; GVH_artnr 03: geen waarde gevonden; GVH_artnr 04: geen waarde gevonden; GVH_artnr 05: geen waarde gevonden; GVH_artnr 06: geen waarde gevonden; TDS_link: .\05 As Builtdossier\2. Bouwkunde\2.1 Architectuur\2.1.7 Gevelsluiting\2.1.7.2 buitenschrijnwerk alu (Vorsselmans)\Technische fiches\TF A 07.06.72 A Drievoudige beglazing.pdf
IfcRoot - Name: 07.06.72#04_Drievoudige beglazing, 44 mm, 2B2/A*/2B2, inkom gordijngevel
Qto_PlateBaseQuantities - Width: 1477; Perimeter: 7882; GrossArea: 3.63933; GrossVolume: 0.16013; NetVolume: 0.16013
Pset_Condition - AssessmentCondition: Empty
Pset_EnvironmentalImpactIndicators - Reference: 07.06.72#04_Drievoudige beglazing, 44 mm, 2B2/A*/2B2, inkom gordijngevel
Pset_PlateCommon - Reference: 07.06.72#04_Drievoudige beglazing, 44 mm, 2B2/A*/2B2, inkom gordijngevel; AcousticRating: 45; IsExternal: no; ThermalTransmittance: 0.6

# IfcPlate: BB_07.06_Buitenbeglazing, rechthoekig_GMO:Enkel gelaagd, 20 mm (16)
PredefinedType: USERDEFINED; Material: BB_Glas
Cpset_Plate - LevelOfAccuracy: in te vullen door Buildwise
IfcClassificationReference - GVH_artnr 01: geen waarde gevonden; GVH_artnr 02: geen waarde gevonden; GVH_artnr 03: geen waarde gevonden; GVH_artnr 04: geen waarde gevonden; GVH_artnr 05: geen waarde gevonden; GVH_artnr 06: geen waarde gevonden
IfcRoot - Name: Enkel gelaagd, 20 mm
Pset_Condition - AssessmentCondition: Empty
Pset_EnvironmentalImpactIndicators - Reference: Enkel gelaagd, 20 mm
Pset_PlateCommon - Reference: Enkel gelaagd, 20 mm; IsExternal: no
Name (BB_07.06_Buitenbeglazing, rechthoekig_GMO:Enkel gelaagd, 20 mm:...) | In | Elevation from Level | TDS_link | Width | Perimeter | GrossArea | GrossVolume | NetVolume | FireRating
15986259 | 000 | 1052.5 | .\05 As Builtdossier\2. Bouwkunde\2.1 Architectuur\2.1.10 wanden\2.1.10.3 Binnendeuren + brandwerend schrijnwerk (Beddeleem)\2.1.10.3.2 technische fiches\TF A 10-06-42-11 A - JB Fireglass dubbele deur EI30.pdf | 600.5 | 6051 | 1.45621 | 0.0291243 | 0.0291242 | EI30
15986260 | 000 | 1052.5 | .\05 As Builtdossier\2. Bouwkunde\2.1 Architectuur\2.1.10 wanden\2.1.10.3 Binnendeuren + brandwerend schrijnwerk (Beddeleem)\2.1.10.3.2 technische fiches\TF A 10-06-42-11 A - JB Fireglass dubbele deur EI30.pdf | 600.5 | 6051 | 1.45621 | 0.0291243 | 0.0291242 | EI30
16275737 | 000 | 1292.5 | .\05 As Builtdossier\2. Bouwkunde\2.1 Architectuur\2.1.10 wanden\2.1.10.3 Binnendeuren + brandwerend schrijnwerk (Beddeleem)\2.1.10.3.2 technische fiches\TF A 10-06-42-11 A - JB Fireglass dubbele deur EI30.pdf | 2455 | 6111 | 1.47423 | 0.0294846 | 0.0294845
16275738 | 000 | 1292.5 | .\05 As Builtdossier\2. Bouwkunde\2.1 Architectuur\2.1.10 wanden\2.1.10.3 Binnendeuren + brandwerend schrijnwerk (Beddeleem)\2.1.10.3.2 technische fiches\TF A 10-06-42-11 A - JB Fireglass dubbele deur EI30.pdf | 2455 | 6111 | 1.47423 | 0.0294846 | 0.0294845
16275763 | 000 | 1292.5 | .\05 As Builtdossier\2. Bouwkunde\2.1 Architectuur\2.1.10 wanden\2.1.10.3 Binnendeuren + brandwerend schrijnwerk (Beddeleem)\2.1.10.3.2 technische fiches\TF A 10-06-42-11 A - JB Fireglass dubbele deur EI30.pdf | 600.5 | 6111 | 1.47423 | 0.0294846 | 0.0294845
16275764 | 000 | 1292.5 | .\05 As Builtdossier\2. Bouwkunde\2.1 Architectuur\2.1.10 wanden\2.1.10.3 Binnendeuren + brandwerend schrijnwerk (Beddeleem)\2.1.10.3.2 technische fiches\TF A 10-06-42-11 A - JB Fireglass dubbele deur EI30.pdf | 600.5 | 6111 | 1.47423 | 0.0294846 | 0.0294845
16282552 | 000 | 1307.5 | .\05 As Builtdossier\2. Bouwkunde\2.1 Architectuur\2.1.10 wanden\2.1.10.3 Binnendeuren + brandwerend schrijnwerk (Beddeleem)\2.1.10.3.2 technische fiches\TF A 10-06-42-11 A - JB Fireglass dubbele deur EI30.pdf | 2455 | 6881 | 2.4194 | 0.0483881 | 0.0483881 | EI30
16282553 | 000 | 1307.5 | .\05 As Builtdossier\2. Bouwkunde\2.1 Architectuur\2.1.10 wanden\2.1.10.3 Binnendeuren + brandwerend schrijnwerk (Beddeleem)\2.1.10.3.2 technische fiches\TF A 10-06-42-11 A - JB Fireglass dubbele deur EI30.pdf | 2455 | 6881 | 2.4194 | 0.0483881 | 0.0483881 | EI30
16282586 | 000 | 1307.5 | .\05 As Builtdossier\2. Bouwkunde\2.1 Architectuur\2.1.10 wanden\2.1.10.3 Binnendeuren + brandwerend schrijnwerk (Beddeleem)\2.1.10.3.2 technische fiches\TF A 10-06-42-11 A - JB Fireglass dubbele deur EI30.pdf | 2455 | 6881 | 2.4194 | 0.0483881 | 0.0483881 | EI30
16282587 | 000 | 1307.5 | .\05 As Builtdossier\2. Bouwkunde\2.1 Architectuur\2.1.10 wanden\2.1.10.3 Binnendeuren + brandwerend schrijnwerk (Beddeleem)\2.1.10.3.2 technische fiches\TF A 10-06-42-11 A - JB Fireglass dubbele deur EI30.pdf | 2455 | 6881 | 2.4194 | 0.0483881 | 0.0483881 | EI30
23250997 | 000 | 1292.5 | .\05 As Builtdossier\2. Bouwkunde\2.1 Architectuur\2.1.10 wanden\2.1.10.3 Binnendeuren + brandwerend schrijnwerk (Beddeleem)\2.1.10.3.2 technische fiches\TF A 10-05-41-01 A - JB Door Fix 00 730x2115.pdf | 2465 | 6371 | 1.77603 | 0.0355207 | 0.0355207
23250998 | 000 | 1292.5 | .\05 As Builtdossier\2. Bouwkunde\2.1 Architectuur\2.1.10 wanden\2.1.10.3 Binnendeuren + brandwerend schrijnwerk (Beddeleem)\2.1.10.3.2 technische fiches\TF A 10-05-41-01 A - JB Door Fix 00 730x2115.pdf | 2465 | 6371 | 1.77603 | 0.0355207 | 0.0355207 | EI00 | Pset_PlateCommon - AcousticRating: 40
28140755 | 010 | 31849 | .\05 As Builtdossier\2. Bouwkunde\2.1 Architectuur\2.1.10 wanden\2.1.10.3 Binnendeuren + brandwerend schrijnwerk (Beddeleem)\2.1.10.3.2 technische fiches\TF A 10-06-42-12 A - JB Fireglass enkele deur EI30.pdf | 1000 | 4000 | 1 | 0.02 | 0.02 | EI30 | IfcElement - Tag: d K.10.307 / 01; BB_Element_Code01: d K.10.307 / 01
28140758 | 010 | 31849 | .\05 As Builtdossier\2. Bouwkunde\2.1 Architectuur\2.1.10 wanden\2.1.10.3 Binnendeuren + brandwerend schrijnwerk (Beddeleem)\2.1.10.3.2 technische fiches\TF A 10-06-42-12 A - JB Fireglass enkele deur EI30.pdf | 1000 | 4000 | 1 | 0.02 | 0.02 | EI30 | Pset_PlateCommon - AcousticRating: 35; IfcElement - Tag: d K.10.306 / 01; BB_Element_Code01: d K.10.306 / 01
16240967 | 030 | 1292.5 | .\05 As Builtdossier\2. Bouwkunde\2.1 Architectuur\2.1.10 wanden\2.1.10.3 Binnendeuren + brandwerend schrijnwerk (Beddeleem)\2.1.10.3.2 technische fiches\TF A 10-05-41-02 A - JB Door Fix 00 830x211.pdf | 530.5 | 5991 | 1.30768 | 0.0261537 | 0.0261537 | EI00 | Pset_PlateCommon - AcousticRating: 40
16240968 | 030 | 1292.5 | .\05 As Builtdossier\2. Bouwkunde\2.1 Architectuur\2.1.10 wanden\2.1.10.3 Binnendeuren + brandwerend schrijnwerk (Beddeleem)\2.1.10.3.2 technische fiches\TF A 10-05-41-02 A - JB Door Fix 00 830x211.pdf | 530.5 | 5991 | 1.30768 | 0.0261537 | 0.0261537 | EI00 | Pset_PlateCommon - AcousticRating: 40

# IfcPlate: BB_07.06_Buitenbeglazing, rechthoekig_GMO:XX_Geen (2)
In: K10
PredefinedType: USERDEFINED; Material: BB_Glas
Cpset_Plate - LevelOfAccuracy: in te vullen door Buildwise
IfcBuildingStorey - Elevation from Level: -1454
IfcClassificationReference - GVH_artnr 01: geen waarde gevonden; GVH_artnr 02: geen waarde gevonden; GVH_artnr 03: geen waarde gevonden; GVH_artnr 04: geen waarde gevonden; GVH_artnr 05: geen waarde gevonden; GVH_artnr 06: geen waarde gevonden; TDS_link: .\05 As Builtdossier\2. Bouwkunde\2.1 Architectuur\2.1.7 Gevelsluiting\2.1.7.1 buitenschrijnwerk RVS\TF A 07.01.32_01 Buitenschrijnwerk RVS.pdf
IfcRoot - Name: XX_Geen
Qto_PlateBaseQuantities - Perimeter: 5908; GrossArea: 2.00597; GrossVolume: 0.0802387; NetVolume: 0.0802387
Pset_Condition - AssessmentCondition: Empty
Pset_EnvironmentalImpactIndicators - Reference: XX_Geen
Pset_PlateCommon - Reference: XX_Geen; IsExternal: no
Name (BB_07.06_Buitenbeglazing, rechthoekig_GMO:XX_Geen:...) | Width
28479903 | 1896
28479934 | 1058

# IfcPlate: BB_10.10_Binnenbeglazing, rechthoekig_GMO:10.10.32#01_Enkelvoudige beglazing, 2B2, BB_10.10_Binnenbeglazing, rechthoekig_GMO:10.10.32#01_Enkelvoudige beglazing, 2B2:15952066
In: 000
PredefinedType: USERDEFINED; Material: BB_Glas
Cpset_Plate - LevelOfAccuracy: in te vullen door Buildwise
IfcBuildingStorey - Level: 000; Elevation from Level: 12083.7
IfcClassificationReference - Keynote: 10.10.32#01; GVH_artnr 01: 10.10.32#01; GVH_artnr 02: geen waarde gevonden; GVH_artnr 03: geen waarde gevonden; GVH_artnr 04: geen waarde gevonden; GVH_artnr 05: geen waarde gevonden; GVH_artnr 06: geen waarde gevonden; TDS_link: .\05 As Builtdossier\2. Bouwkunde\2.1 Architectuur\2.1.7 Gevelsluiting\2.1.7.2 buitenschrijnwerk alu (Vorsselmans)\Technische fiches\TF A -07.03.31-A-Automatische schuifdeuren.pdf
IfcRoot - Name: 10.10.32#01_Enkelvoudige beglazing, 2B2
Qto_PlateBaseQuantities - Width: 2464; Perimeter: 7882; GrossArea: 3.63933; GrossVolume: 0.0618686; NetVolume: 0.0618686
Pset_Condition - AssessmentCondition: Empty
Pset_EnvironmentalImpactIndicators - Reference: 10.10.32#01_Enkelvoudige beglazing, 2B2
Pset_PlateCommon - Reference: 10.10.32#01_Enkelvoudige beglazing, 2B2; IsExternal: no

# IfcPlate: BB_10.10_Binnenbeglazing, rechthoekig_GMO:10.10.32#02_Enkelvoudige beglazing, 2B2, 40dB (50)
In: 000
PredefinedType: USERDEFINED; Material: BB_Glas
Cpset_Plate - LevelOfAccuracy: in te vullen door Buildwise
IfcClassificationReference - Keynote: 10.10.32#02; GVH_artnr 01: 10.10.32#02; GVH_artnr 02: geen waarde gevonden; GVH_artnr 03: geen waarde gevonden; GVH_artnr 04: geen waarde gevonden; GVH_artnr 05: geen waarde gevonden; GVH_artnr 06: geen waarde gevonden; TDS_link: .\05 As Builtdossier\2. Bouwkunde\2.1 Architectuur\2.1.10 wanden\2.1.10.3 Binnendeuren + brandwerend schrijnwerk (Beddeleem)\2.1.10.3.1 plannen\P200404-JB-Atrium-B-GVU.pdf
IfcRoot - Name: 10.10.32#02_Enkelvoudige beglazing, 2B2, 40dB
Pset_Condition - AssessmentCondition: Empty
Pset_EnvironmentalImpactIndicators - Reference: 10.10.32#02_Enkelvoudige beglazing, 2B2, 40dB
Pset_PlateCommon - Reference: 10.10.32#02_Enkelvoudige beglazing, 2B2, 40dB; AcousticRating: 40; IsExternal: no
Name (BB_10.10_Binnenbeglazing, rechthoekig_GMO:10.10.32#02_Enkelvoudige beglazing, 2B2, 40dB:...) | Elevation from Level | Width | Perimeter | GrossArea | GrossVolume = NetVolume
12778481 | 4100 | 713.5 | 6293 | 1.73595 | 0.0295111
12778482 | 4100 | 713.5 | 6293 | 1.73595 | 0.0295111
12778485 | 511.5 | 713.5 | 6293 | 1.73595 | 0.0295111
12778487 | 511.5 | 713.5 | 6293 | 1.73595 | 0.0295111
12778489 | 511.5 | 713.5 | 6293 | 1.73595 | 0.0295111
12778491 | 511.5 | 713.5 | 6293 | 1.73595 | 0.0295111
12811269 | 4611.5 | 718.5 | 6297 | 1.74596 | 0.0296812
12811270 | 4611.5 | 718.5 | 6297 | 1.74596 | 0.0296812
12811273 | 4611.5 | 718.5 | 6297 | 1.74596 | 0.0296812
12811275 | 4611.5 | 718.5 | 6297 | 1.74596 | 0.0296812
12811412 | 4100 | 713.5 | 6293 | 1.73595 | 0.0295111
12811413 | 4100 | 713.5 | 6293 | 1.73595 | 0.0295111
12811416 | 511.5 | 713.5 | 6293 | 1.73595 | 0.0295111
12811418 | 511.5 | 713.5 | 6293 | 1.73595 | 0.0295111
12811420 | 511.5 | 713.5 | 6293 | 1.73595 | 0.0295111
12811422 | 511.5 | 713.5 | 6293 | 1.73595 | 0.0295111
12811584 | 4100 | 2433 | 6293 | 1.73595 | 0.0295111
12811585 | 4100 | 2433 | 6293 | 1.73595 | 0.0295111
12811588 | 511.5 | 2433 | 6293 | 1.73595 | 0.0295111
12811590 | 511.5 | 2433 | 6293 | 1.73595 | 0.0295111
12811592 | 511.5 | 2433 | 6293 | 1.73595 | 0.0295111
12811594 | 511.5 | 2433 | 6293 | 1.73595 | 0.0295111
12811597 | 4100 | 2433 | 6293 | 1.73595 | 0.0295111
12811598 | 4100 | 2433 | 6293 | 1.73595 | 0.0295111
12811601 | 511.5 | 2433 | 6293 | 1.73595 | 0.0295111
12811603 | 511.5 | 2433 | 6293 | 1.73595 | 0.0295111
12811605 | 511.5 | 2433 | 6293 | 1.73595 | 0.0295111
12811607 | 511.5 | 2433 | 6293 | 1.73595 | 0.0295111
12811610 | 4611.5 | 2430 | 6297 | 1.74596 | 0.0296812
12811611 | 4611.5 | 2430 | 6297 | 1.74596 | 0.0296812
12811614 | 4611.5 | 2430 | 6297 | 1.74596 | 0.0296812
12811616 | 4611.5 | 2430 | 6297 | 1.74596 | 0.0296812
12811619 | 4100 | 2433 | 6293 | 1.73595 | 0.0295111
12811620 | 4100 | 2433 | 6293 | 1.73595 | 0.0295111
12811623 | 511.5 | 2433 | 6293 | 1.73595 | 0.0295111
12811625 | 511.5 | 2433 | 6293 | 1.73595 | 0.0295111
12811627 | 511.5 | 2433 | 6293 | 1.73595 | 0.0295111
12811629 | 511.5 | 2433 | 6293 | 1.73595 | 0.0295111
13763782 | 1290 | 592.5 | 6109 | 1.45874 | 0.0247985 | IfcElement - Tag: d K.00.108 / 01; BB_Element_Code01: d K.00.108 / 01
13763783 | 1290 | 592.5 | 6109 | 1.45874 | 0.0247985 | IfcElement - Tag: d K.00.108 / 01; BB_Element_Code01: d K.00.108 / 01
13763784 | 1315 | 266 | 5660 | 0.682024 | 0.0115944 | IfcElement - Tag: d K.00.108 / 01; BB_Element_Code01: d K.00.108 / 01
13763785 | 1315 | 266 | 5660 | 0.682024 | 0.0115944 | IfcElement - Tag: d K.00.108 / 01; BB_Element_Code01: d K.00.108 / 01
13866463 | -10565.6 | 2884 | 8616 | 4.10682 | 0.0698159
13887306 | -10565.6 | 2884 | 8616 | 4.10682 | 0.0698159
16230410 | 4100 | 713.5 | 6293 | 1.73595 | 0.0295111
16230411 | 4100 | 713.5 | 6293 | 1.73595 | 0.0295111
16230414 | 511.5 | 713.5 | 6293 | 1.73595 | 0.0295111
16230416 | 511.5 | 713.5 | 6293 | 1.73595 | 0.0295111
16230418 | 511.5 | 713.5 | 6293 | 1.73595 | 0.0295111
16230420 | 511.5 | 713.5 | 6293 | 1.73595 | 0.0295111

# IfcPlate: BB_10.10_Binnenbeglazing, rechthoekig_GMO:10.10.41#01_Enkelvoudige beglazing, 2B2, EI30 (18)
PredefinedType: USERDEFINED; Material: BB_Glas
Cpset_Plate - LevelOfAccuracy: in te vullen door Buildwise
IfcClassificationReference - Keynote: 10.10.41#01; GVH_artnr 01: 10.10.41#01; GVH_artnr 02: geen waarde gevonden; GVH_artnr 03: geen waarde gevonden; GVH_artnr 04: geen waarde gevonden; GVH_artnr 05: geen waarde gevonden; GVH_artnr 06: geen waarde gevonden
IfcRoot - Name: 10.10.41#01_Enkelvoudige beglazing, 2B2, EI30
Pset_Condition - AssessmentCondition: Empty
Pset_EnvironmentalImpactIndicators - Reference: 10.10.41#01_Enkelvoudige beglazing, 2B2, EI30
Pset_PlateCommon - Reference: 10.10.41#01_Enkelvoudige beglazing, 2B2, EI30; IsExternal: no; FireRating: EI30
Name (BB_10.10_Binnenbeglazing, rechthoekig_GMO:10.10.41#01_Enkelvoudige beglazing, 2B2, EI30:...) | In | Elevation from Level | TDS_link | Tag = BB_Element_Code01 | Width | Perimeter | GrossArea | GrossVolume = NetVolume
13991263 | 010 | -1563.55 | .\05 As Builtdossier\2. Bouwkunde\2.1 Architectuur\2.1.10 wanden\2.1.10.3 Binnendeuren + brandwerend schrijnwerk (Beddeleem)\2.1.10.3.2 technische fiches\TF A 10-06-42-16 A - JB Fireglass dubbele deur EI30 met zijlicht.pdf | d K.10.G13 / 01 | 592.5 | 6089 | 1.45281 | 0.0246978
13991264 | 010 | -1563.55 | .\05 As Builtdossier\2. Bouwkunde\2.1 Architectuur\2.1.10 wanden\2.1.10.3 Binnendeuren + brandwerend schrijnwerk (Beddeleem)\2.1.10.3.2 technische fiches\TF A 10-06-42-16 A - JB Fireglass dubbele deur EI30 met zijlicht.pdf | d K.10.G13 / 01 | 592.5 | 6089 | 1.45281 | 0.0246978
13991265 | 010 | -1538.55 | .\05 As Builtdossier\2. Bouwkunde\2.1 Architectuur\2.1.10 wanden\2.1.10.3 Binnendeuren + brandwerend schrijnwerk (Beddeleem)\2.1.10.3.2 technische fiches\TF A 10-06-42-16 A - JB Fireglass dubbele deur EI30 met zijlicht.pdf | d K.10.G13 / 01 | 481 | 6070 | 1.22847 | 0.0208841
13991266 | 010 | -1538.55 | .\05 As Builtdossier\2. Bouwkunde\2.1 Architectuur\2.1.10 wanden\2.1.10.3 Binnendeuren + brandwerend schrijnwerk (Beddeleem)\2.1.10.3.2 technische fiches\TF A 10-06-42-16 A - JB Fireglass dubbele deur EI30 met zijlicht.pdf | d K.10.G13 / 01 | 481 | 6070 | 1.22847 | 0.0208841
20841121 | 010 | 1315 | .\05 As Builtdossier\2. Bouwkunde\2.1 Architectuur\2.1.10 wanden\2.1.10.3 Binnendeuren + brandwerend schrijnwerk (Beddeleem)\2.1.10.3.2 technische fiches\TF A 10.06.42-25 A – JB Fireglass Frame EI30.pdf |  | 2554 | 6616 | 1.92572 | 0.0327372
20841150 | 010 | 1315 | .\05 As Builtdossier\2. Bouwkunde\2.1 Architectuur\2.1.10 wanden\2.1.10.3 Binnendeuren + brandwerend schrijnwerk (Beddeleem)\2.1.10.3.2 technische fiches\TF A 10.06.42-25 A – JB Fireglass Frame EI30.pdf |  | 754 | 6616 | 1.92572 | 0.0327372
16239868 | 020 | -1563.55 | .\05 As Builtdossier\2. Bouwkunde\2.1 Architectuur\2.1.10 wanden\2.1.10.3 Binnendeuren + brandwerend schrijnwerk (Beddeleem)\2.1.10.3.2 technische fiches\TF A 10-06-42-16 A - JB Fireglass dubbele deur EI30 met zijlicht.pdf | d K.20.G13 / 01 | 592.5 | 6089 | 1.45281 | 0.0246978
16239869 | 020 | -1563.55 | .\05 As Builtdossier\2. Bouwkunde\2.1 Architectuur\2.1.10 wanden\2.1.10.3 Binnendeuren + brandwerend schrijnwerk (Beddeleem)\2.1.10.3.2 technische fiches\TF A 10-06-42-16 A - JB Fireglass dubbele deur EI30 met zijlicht.pdf | d K.20.G13 / 01 | 592.5 | 6089 | 1.45281 | 0.0246978
16239870 | 020 | -1538.55 | .\05 As Builtdossier\2. Bouwkunde\2.1 Architectuur\2.1.10 wanden\2.1.10.3 Binnendeuren + brandwerend schrijnwerk (Beddeleem)\2.1.10.3.2 technische fiches\TF A 10-06-42-16 A - JB Fireglass dubbele deur EI30 met zijlicht.pdf | d K.20.G13 / 01 | 481 | 6070 | 1.22847 | 0.0208841
16239871 | 020 | -1538.55 | .\05 As Builtdossier\2. Bouwkunde\2.1 Architectuur\2.1.10 wanden\2.1.10.3 Binnendeuren + brandwerend schrijnwerk (Beddeleem)\2.1.10.3.2 technische fiches\TF A 10-06-42-16 A - JB Fireglass dubbele deur EI30 met zijlicht.pdf | d K.20.G13 / 01 | 481 | 6070 | 1.22847 | 0.0208841
16239878 | 030 | -1563.55 | .\05 As Builtdossier\2. Bouwkunde\2.1 Architectuur\2.1.10 wanden\2.1.10.3 Binnendeuren + brandwerend schrijnwerk (Beddeleem)\2.1.10.3.2 technische fiches\TF A 10-06-42-16 A - JB Fireglass dubbele deur EI30 met zijlicht.pdf | d K.30.G13 / 01 | 592.5 | 6089 | 1.45281 | 0.0246978
16239879 | 030 | -1563.55 | .\05 As Builtdossier\2. Bouwkunde\2.1 Architectuur\2.1.10 wanden\2.1.10.3 Binnendeuren + brandwerend schrijnwerk (Beddeleem)\2.1.10.3.2 technische fiches\TF A 10-06-42-16 A - JB Fireglass dubbele deur EI30 met zijlicht.pdf | d K.30.G13 / 01 | 592.5 | 6089 | 1.45281 | 0.0246978
16239880 | 030 | -1538.55 | .\05 As Builtdossier\2. Bouwkunde\2.1 Architectuur\2.1.10 wanden\2.1.10.3 Binnendeuren + brandwerend schrijnwerk (Beddeleem)\2.1.10.3.2 technische fiches\TF A 10-06-42-16 A - JB Fireglass dubbele deur EI30 met zijlicht.pdf | d K.30.G13 / 01 | 481 | 6070 | 1.22847 | 0.0208841
16239881 | 030 | -1538.55 | .\05 As Builtdossier\2. Bouwkunde\2.1 Architectuur\2.1.10 wanden\2.1.10.3 Binnendeuren + brandwerend schrijnwerk (Beddeleem)\2.1.10.3.2 technische fiches\TF A 10-06-42-16 A - JB Fireglass dubbele deur EI30 met zijlicht.pdf | d K.30.G13 / 01 | 481 | 6070 | 1.22847 | 0.0208841
25675973 | 030 | 12115 |  |  | 732 | 6388 | 1.80218 | 0.0306371
25695713 | 030 | 12115 |  |  | 732 | 6388 | 1.80218 | 0.0306371
26435319 | 030 | 12115 |  |  | 2462 | 6388 | 1.80218 | 0.0306371
26435323 | 030 | 12115 |  |  | 2462 | 6388 | 1.80218 | 0.0306371

# IfcPlate: BB_10.10_Binnenbeglazing, rechthoekig_GMO:10.10.41#02_Enkelvoudige beglazing, 2B2, EI30, 40dB (66)
PredefinedType: USERDEFINED; Material: BB_Glas
Cpset_Plate - LevelOfAccuracy: in te vullen door Buildwise
IfcClassificationReference - Keynote: 10.10.41#02; GVH_artnr 01: 10.10.41#02; GVH_artnr 02: geen waarde gevonden; GVH_artnr 03: geen waarde gevonden; GVH_artnr 04: geen waarde gevonden; GVH_artnr 05: geen waarde gevonden; GVH_artnr 06: geen waarde gevonden; TDS_link: .\05 As Builtdossier\2. Bouwkunde\2.1 Architectuur\2.1.10 wanden\2.1.10.3 Binnendeuren + brandwerend schrijnwerk (Beddeleem)\2.1.10.3.1 plannen\P200404-D001-C-GVU.pdf
IfcRoot - Name: 10.10.41#02_Enkelvoudige beglazing, 2B2, EI30, 40dB
Qto_PlateBaseQuantities - GrossVolume: 0.0665791; NetVolume: 0.0665791
Pset_Condition - AssessmentCondition: Empty
Pset_EnvironmentalImpactIndicators - Reference: 10.10.41#02_Enkelvoudige beglazing, 2B2, EI30, 40dB
Pset_PlateCommon - Reference: 10.10.41#02_Enkelvoudige beglazing, 2B2, EI30, 40dB; AcousticRating: 40; IsExternal: no; FireRating: EI30
Name (BB_10.10_Binnenbeglazing, rechthoekig_GMO:10.10.41#02_Enkelvoudige beglazing, 2B2, EI30, 40dB:...) | In | Level | Elevation from Level | Width | Perimeter | GrossArea
8779237 | 010 | 010 | 4100 | 1736 | 7984 | 3.91642
8779238 | 010 | 010 | 4100 | 1736 | 7984 | 3.91642
12577706 | 010 | 010 | 4100 | 1736 | 7984 | 3.91642
12577707 | 010 | 010 | 4100 | 1736 | 7984 | 3.91642
12577965 | 010 | 010 | 4100 | 2256 | 7984 | 3.91642
12577966 | 010 | 010 | 4100 | 2256 | 7984 | 3.91642
12577970 | 010 | 010 | 4100 | 2256 | 7984 | 3.91642
12577971 | 010 | 010 | 4100 | 2256 | 7984 | 3.91642
12577975 | 010 | 010 | 4100 | 2256 | 7984 | 3.91642
12577976 | 010 | 010 | 4100 | 2256 | 7984 | 3.91642
32128371 | 010 | 010 | 5075 | 2256 | 7984 | 3.91642
32128374 | 010 | 010 | 5075 | 2256 | 7984 | 3.91642
32128377 | 010 | 010 | 5075 | 2256 | 7984 | 3.91642
32128383 | 010 | 010 | 5075 | 1736 | 7984 | 3.91642
32128386 | 010 | 010 | 5075 | 1736 | 7984 | 3.91642
35753736 | 010 | 010 | 5075 | 17 | 3506 | 0.029512
35753737 | 010 | 010 | 5075 | 1736 | 7984 | 3.91642
36060460 | 010 | 010 | 5075 | 2256 | 7984 | 3.91642
36060461 | 010 | 010 | 5075 | 2256 | 7984 | 3.91642
36093166 | 010 | 010 | 4100 | 1736 | 7984 | 3.91642
36093167 | 010 | 010 | 4100 | 1736 | 7984 | 3.91642
36093172 | 010 | 010 | 5075 | 1736 | 7984 | 3.91642
12578048 | 020 | 020 | 4100 | 1736 | 7984 | 3.91642
12578049 | 020 | 020 | 4100 | 1736 | 7984 | 3.91642
12578053 | 020 | 020 | 4100 | 1736 | 7984 | 3.91642
12578054 | 020 | 020 | 4100 | 1736 | 7984 | 3.91642
12578058 | 020 | 020 | 4100 | 1736 | 7984 | 3.91642
12578059 | 020 | 020 | 4100 | 1736 | 7984 | 3.91642
12578068 | 020 | 020 | 4100 | 2256 | 7984 | 3.91642
12578069 | 020 | 020 | 4100 | 2256 | 7984 | 3.91642
12578073 | 020 | 020 | 4100 | 2256 | 7984 | 3.91642
12578074 | 020 | 020 | 4100 | 2256 | 7984 | 3.91642
12578078 | 020 | 020 | 4100 | 2256 | 7984 | 3.91642
12578079 | 020 | 020 | 4100 | 2256 | 7984 | 3.91642
13968247 | 020 | 020 | 8675 | 1736 | 7984 | 3.91642
13968248 | 020 | 020 | 8675 | 1736 | 7984 | 3.91642
28934248 | 020 | 020 | 8675 | 2256 | 7984 | 3.91642
28934253 | 020 | 020 | 8675 | 2256 | 7984 | 3.91642
28934256 | 020 | 020 | 8675 | 1736 | 7984 | 3.91642
28934259 | 020 | 020 | 8675 | 1736 | 7984 | 3.91642
28934262 | 020 | 020 | 8675 | 1736 | 7984 | 3.91642
28934265 | 020 | 020 | 8675 | 2256 | 7984 | 3.91642
36060462 | 020 | 020 | 8675 | 2256 | 7984 | 3.91642
36060463 | 020 | 020 | 8675 | 2256 | 7984 | 3.91642
12578089 | 030 | 030 | 4100 | 1736 | 7984 | 3.91642
12578090 | 030 | 030 | 4100 | 1736 | 7984 | 3.91642
12578094 | 030 | 030 | 4100 | 1736 | 7984 | 3.91642
12578095 | 030 | 030 | 4100 | 1736 | 7984 | 3.91642
12578099 | 030 | 030 | 4100 | 1736 | 7984 | 3.91642
12578100 | 030 | 030 | 4100 | 1736 | 7984 | 3.91642
12578109 | 030 | 030 | 4100 | 2256 | 7984 | 3.91642
12578110 | 030 | 030 | 4100 | 2256 | 7984 | 3.91642
12578114 | 030 | 030 | 4100 | 2256 | 7984 | 3.91642
12578115 | 030 | 030 | 4100 | 2256 | 7984 | 3.91642
12578119 | 030 | 030 | 4100 | 2256 | 7984 | 3.91642
12578120 | 030 | 030 | 4100 | 2256 | 7984 | 3.91642
28934268 | 030 | 030 | 12275 | 1736 | 7984 | 3.91642
28934271 | 030 | 030 | 12275 | 1736 | 7984 | 3.91642
28934274 | 030 | 030 | 12275 | 1736 | 7984 | 3.91642
28934277 | 030 | 030 | 12275 | 2256 | 7984 | 3.91642
28934280 | 030 | 030 | 12275 | 2256 | 7984 | 3.91642
28934283 | 030 | 030 | 12275 | 2256 | 7984 | 3.91642
36060301 | 030 | 030 | 12275 | 1736 | 7984 | 3.91642
36060302 | 030 | 030 | 12275 | 1736 | 7984 | 3.91642
36060502 | 030 | 030 | 12275 | 2256 | 7984 | 3.91642
36060503 | 030 | 030 | 12275 | 2256 | 7984 | 3.91642

# IfcPlate: BB_10.10_Binnenbeglazing, rechthoekig_GMO:10.10.42#01_Enkelvoudige beglazing, 2B2, EI60 (6)
PredefinedType: USERDEFINED; Material: BB_Glas
Cpset_Plate - LevelOfAccuracy: in te vullen door Buildwise
IfcClassificationReference - Keynote: 10.10.42#01; GVH_artnr 01: 10.10.42#01; GVH_artnr 02: geen waarde gevonden; GVH_artnr 03: geen waarde gevonden; GVH_artnr 04: geen waarde gevonden; GVH_artnr 05: geen waarde gevonden; GVH_artnr 06: geen waarde gevonden; TDS_link: .\05 As Builtdossier\2. Bouwkunde\2.1 Architectuur\2.1.10 wanden\2.1.10.3 Binnendeuren + brandwerend schrijnwerk (Beddeleem)\2.1.10.3.1 plannen\P200404-D003-A-GVU.pdf
IfcRoot - Name: 10.10.42#01_Enkelvoudige beglazing, 2B2, EI60
Pset_Condition - AssessmentCondition: Empty
Pset_EnvironmentalImpactIndicators - Reference: 10.10.42#01_Enkelvoudige beglazing, 2B2, EI60
Pset_PlateCommon - Reference: 10.10.42#01_Enkelvoudige beglazing, 2B2, EI60; IsExternal: no; FireRating: EI60
Name (BB_10.10_Binnenbeglazing, rechthoekig_GMO:10.10.42#01_Enkelvoudige beglazing, 2B2, EI60:...) | In | Elevation from Level | Width | Perimeter | GrossArea | GrossVolume = NetVolume
14006775 | 010 | -10565.6 | 2254 | 9136 | 5.21576 | 0.0886679
14006907 | 020 | -10565.6 | 2254 | 9136 | 5.21576 | 0.0886679
15952946 | 020 | 236.908 | 1836 | 7010 | 3.06428 | 0.0520928
15952949 | 020 | 236.908 | 1608 | 6554 | 2.68375 | 0.0456238
15952950 | 020 | 236.908 | 1836 | 7010 | 3.06428 | 0.0520928
14006911 | 030 | -10565.6 | 2254 | 9136 | 5.21576 | 0.0886679

# IfcPlate: BB_10.10_Binnenbeglazing, rechthoekig_GMO:XX_Geen (32)
PredefinedType: USERDEFINED; Material: BB_Glas
Cpset_Plate - LevelOfAccuracy: in te vullen door Buildwise
IfcClassificationReference - Keynote: 10.10.42#01; GVH_artnr 01: 10.10.42#01; GVH_artnr 02: geen waarde gevonden; GVH_artnr 03: geen waarde gevonden; GVH_artnr 04: geen waarde gevonden; GVH_artnr 05: geen waarde gevonden; GVH_artnr 06: geen waarde gevonden
IfcRoot - Name: XX_Geen
Pset_Condition - AssessmentCondition: Empty
Pset_EnvironmentalImpactIndicators - Reference: XX_Geen
Pset_PlateCommon - Reference: XX_Geen; IsExternal: no
Name (BB_10.10_Binnenbeglazing, rechthoekig_GMO:XX_Geen:...) | In | Level | Elevation from Level | Width | Perimeter | GrossArea | GrossVolume = NetVolume
16251601 | 000 | 000 | 9640 | 878 | 2664 | 0.398612 | 0.0067764
16251677 | 000 | 000 | 2320 | 454 | 2364 | 0.330512 | 0.0056187
16251894 | 000 | 000 | 2320 | 828 | 2564 | 0.375912 | 0.0063905 | IfcElement - BB_Element_Lokaalnummer01: K.00.S12
16252079 | 000 | 000 | 2284 | 828 | 2564 | 0.375912 | 0.0063905 | IfcElement - BB_Element_Lokaalnummer01: K.00.S11
16252236 | 000 | 000 | 2320 | 878 | 2664 | 0.398612 | 0.0067764
16252540 | 000 | 000 | 2320 | 454 | 2664 | 0.398612 | 0.0067764
16266523 | 000 | 000 | -41260 | 878 | 2664 | 0.398612 | 0.0067764
16273639 | 000 | 000 | 9504 | 454 | 2564 | 0.375912 | 0.0063905
16251048 | 010 | 010 | 13240 | 878 | 2664 | 0.398612 | 0.0067764
16251255 | 010 | 010 | 5920 | 454 | 2364 | 0.330512 | 0.0056187
16266519 | 010 | 010 | -37660 | 878 | 2664 | 0.398612 | 0.0067764
16273723 | 010 | 010 | 23804 | 454 | 2664 | 0.398612 | 0.0067764
16273799 | 010 | 010 | 5920 | 454 | 2364 | 0.330512 | 0.0056187
16273988 | 010 | 010 | 2240 | 828 | 2564 | 0.375912 | 0.0063905 | IfcElement - BB_Element_Lokaalnummer01: K.10.S12
16273994 | 010 | 010 | 2204 | 828 | 2564 | 0.375912 | 0.0063905 | IfcElement - BB_Element_Lokaalnummer01: K.10.S11
16274114 | 010 | 010 | 5920 | 454 | 2764 | 0.421312 | 0.0071623
16274275 | 020 | 020 | 13240 | 878 | 2664 | 0.398612 | 0.0067764
16274281 | 020 | 020 | 5720 | 454 | 2364 | 0.330512 | 0.0056187
16274282 | 020 | 020 | 23804 | 454 | 2664 | 0.398612 | 0.0067764
16274288 | 020 | 020 | 5720 | 454 | 2364 | 0.330512 | 0.0056187
16274333 | 020 | 020 | 2240 | 828 | 2564 | 0.375912 | 0.0063905 | IfcElement - BB_Element_Lokaalnummer01: K.20.S12
16274339 | 020 | 020 | 2204 | 828 | 2564 | 0.375912 | 0.0063905 | IfcElement - BB_Element_Lokaalnummer01: K.20.S11
16274397 | 020 | 020 | -37660 | 878 | 2664 | 0.398612 | 0.0067764
16274403 | 020 | 020 | 5720 | 454 | 2764 | 0.421312 | 0.0071623
16274561 | 030 | 030 | 13240 | 878 | 2664 | 0.398612 | 0.0067764
16274567 | 030 | 030 | 5720 | 454 | 2364 | 0.330512 | 0.0056187
16274568 | 030 | 030 | 23804 | 454 | 2664 | 0.398612 | 0.0067764
16274574 | 030 | 030 | 5720 | 454 | 2364 | 0.330512 | 0.0056187
16274698 | 030 | 030 | 2240 | 828 | 2564 | 0.375912 | 0.0063905 | IfcElement - BB_Element_Lokaalnummer01: K.30.S12
16274704 | 030 | 030 | 2204 | 828 | 2564 | 0.375912 | 0.0063905
16274981 | 030 | 030 | 2204 | 828 | 2564 | 0.375912 | 0.0063905
26481124 | 030 | 030 | 9304 | 454 | 2564 | 0.375912 | 0.0063905

# IfcPlate: Basic Wall:BB_07.04.63#01_Aluminium sandwichpanelen, 28 mm (7)
In: 050
PredefinedType: USERDEFINED
Cpset_Plate - LevelOfAccuracy: in te vullen door Buildwise
IfcBuildingStorey - Top Offset: 0; Base Constraint: 050
IfcClassificationReference - Keynote: 07.04.63#01; GVH_artnr 01: 07.04.63#01; GVH_artnr 02: geen waarde gevonden; GVH_artnr 03: geen waarde gevonden; GVH_artnr 04: geen waarde gevonden; GVH_artnr 05: geen waarde gevonden; GVH_artnr 06: geen waarde gevonden; TDS_link: .\05 As Builtdossier\7. Brandpreventie\7.1. Attesten\7.1.3. brandweerstand\7.1.3.3 brandklasse gevel- en dakbekleding\TF A 05.02.33 Kalzip + clips + info.pdf
IfcRoot - Name: BB_07.04.63#01_Aluminium sandwichpanelen, 28 mm
Qto_PlateBaseQuantities - Width: 28
Pset_Condition - AssessmentCondition: Empty
Pset_EnvironmentalImpactIndicators - Reference: BB_07.04.63#01_Aluminium sandwichpanelen, 28 mm
Pset_PlateCommon - Reference: BB_07.04.63#01_Aluminium sandwichpanelen, 28 mm; IsExternal: yes; ThermalTransmittance: 0; LoadBearing: no
Name (Basic Wall:BB_07.04.63#01_Aluminium sandwichpanelen, 28 mm:...) | Base Offset | NetVolume
32128532 | 3703 | 0.408737
32128879 | 258 | 0.330877
32128985 | 2953 | 0.362933
32129052 | 258 | 0.331262
32129162 | 4543 | 1.3291
32129325 | 73 | 0.211469
32141344 | 73 | 0.211469

# IfcPlate: plate1:plate, plate1:plate:34125969
In: 010
PredefinedType: USERDEFINED; Material: BB_Schrijnwerk_Aluminium
Cpset_Plate - LevelOfAccuracy: in te vullen door Buildwise
IfcBuildingStorey - Elevation from Level: 0
IfcRoot - Name: plate
Qto_PlateBaseQuantities - Width: 2420; Perimeter: 4970; GrossArea: 0.1573; GrossVolume: 0.001573; NetVolume: 0.001573
Pset_Condition - AssessmentCondition: Empty
Pset_EnvironmentalImpactIndicators - Reference: plate
Pset_PlateCommon - Reference: plate; IsExternal: no

# IfcPlate: plate2:plate, plate2:plate:34125999
In: 020
PredefinedType: USERDEFINED; Material: BB_Schrijnwerk_Aluminium
Cpset_Plate - LevelOfAccuracy: in te vullen door Buildwise
IfcBuildingStorey - Elevation from Level: 0
IfcRoot - Name: plate
Qto_PlateBaseQuantities - Width: 2420; Perimeter: 4970; GrossArea: 0.1573; GrossVolume: 0.001573; NetVolume: 0.001573
Pset_Condition - AssessmentCondition: Empty
Pset_EnvironmentalImpactIndicators - Reference: plate
Pset_PlateCommon - Reference: plate; IsExternal: no

# IfcPlate: plate3:plate, plate3:plate:34126108
In: 000
PredefinedType: USERDEFINED; Material: BB_Schrijnwerk_Aluminium
Cpset_Plate - LevelOfAccuracy: in te vullen door Buildwise
IfcBuildingStorey - Elevation from Level: 0
IfcRoot - Name: plate
Qto_PlateBaseQuantities - Width: 2420; Perimeter: 4970; GrossArea: 0.1573; GrossVolume: 0.001573; NetVolume: 0.001573
Pset_Condition - AssessmentCondition: Empty
Pset_EnvironmentalImpactIndicators - Reference: plate
Pset_PlateCommon - Reference: plate; IsExternal: no; FireRating: EI60

# IfcPlate: plate4:plate, plate4:plate:34126167
In: 010
PredefinedType: USERDEFINED; Material: BB_Schrijnwerk_Aluminium
Cpset_Plate - LevelOfAccuracy: in te vullen door Buildwise
IfcBuildingStorey - Elevation from Level: 0
IfcRoot - Name: plate
Qto_PlateBaseQuantities - Width: 2420; Perimeter: 4970; GrossArea: 0.1573; GrossVolume: 0.001573; NetVolume: 0.001573
Pset_Condition - AssessmentCondition: Empty
Pset_EnvironmentalImpactIndicators - Reference: plate
Pset_PlateCommon - Reference: plate; IsExternal: no

# IfcPlate: plate5:plate, plate5:plate:34126198
In: 020
PredefinedType: USERDEFINED; Material: BB_Schrijnwerk_Aluminium
Cpset_Plate - LevelOfAccuracy: in te vullen door Buildwise
IfcBuildingStorey - Elevation from Level: 0
IfcRoot - Name: plate
Qto_PlateBaseQuantities - Width: 2420; Perimeter: 4970; GrossArea: 0.1573; GrossVolume: 0.001573; NetVolume: 0.001573
Pset_Condition - AssessmentCondition: Empty
Pset_EnvironmentalImpactIndicators - Reference: plate
Pset_PlateCommon - Reference: plate; IsExternal: no

# IfcPlate: plate:plate, plate:plate:34125858
In: 000
PredefinedType: USERDEFINED; Material: BB_Schrijnwerk_Aluminium
Cpset_Plate - LevelOfAccuracy: in te vullen door Buildwise
IfcBuildingStorey - Elevation from Level: 0
IfcRoot - Name: plate
Qto_PlateBaseQuantities - Width: 2420; Perimeter: 4970; GrossArea: 0.1573; GrossVolume: 0.001573; NetVolume: 0.001573
Pset_Condition - AssessmentCondition: Empty
Pset_EnvironmentalImpactIndicators - Reference: plate
Pset_PlateCommon - Reference: plate; IsExternal: no; FireRating: EI60

# IfcRoof: vezelcementplaat 1250 x 10:vezelcementplaat 1250 x 625, vezelcementplaat 1250 x 10:vezelcementplaat 1250 x 625:33947532
In: 050
PredefinedType: SHED_ROOF
Qto_RoofBaseQuantities - GrossArea: 0.0298123
Pset_Condition - AssessmentCondition: Empty
Pset_EnvironmentalImpactIndicators - Reference: vezelcementplaat 1250 x 625
Pset_RoofCommon - Reference: vezelcementplaat 1250 x 625; IsExternal: yes; FireRating: EI 60

# IfcRoof: vezelcementplaat 1250 x 11:vezelcementplaat 1250 x 625, vezelcementplaat 1250 x 11:vezelcementplaat 1250 x 625:33947545
In: 050
PredefinedType: SHED_ROOF
Qto_RoofBaseQuantities - GrossArea: 0.0298123
Pset_Condition - AssessmentCondition: Empty
Pset_EnvironmentalImpactIndicators - Reference: vezelcementplaat 1250 x 625
Pset_RoofCommon - Reference: vezelcementplaat 1250 x 625; IsExternal: yes; FireRating: EI 60

# IfcRoof: vezelcementplaat 1250 x 12:vezelcementplaat 1250 x 625, vezelcementplaat 1250 x 12:vezelcementplaat 1250 x 625:33947692
In: 050
PredefinedType: SHED_ROOF
Qto_RoofBaseQuantities - GrossArea: 0.0298185
Pset_Condition - AssessmentCondition: Empty
Pset_EnvironmentalImpactIndicators - Reference: vezelcementplaat 1250 x 625
Pset_RoofCommon - Reference: vezelcementplaat 1250 x 625; IsExternal: yes; FireRating: EI 60

# IfcRoof: vezelcementplaat 1250 x 13:vezelcementplaat 1250 x 625, vezelcementplaat 1250 x 13:vezelcementplaat 1250 x 625:33947793
In: 050
PredefinedType: SHED_ROOF
Qto_RoofBaseQuantities - GrossArea: 0.0298185
Pset_Condition - AssessmentCondition: Empty
Pset_EnvironmentalImpactIndicators - Reference: vezelcementplaat 1250 x 625
Pset_RoofCommon - Reference: vezelcementplaat 1250 x 625; IsExternal: yes; FireRating: EI 60

# IfcRoof: vezelcementplaat 1250 x 14:vezelcementplaat 1250 x 625, vezelcementplaat 1250 x 14:vezelcementplaat 1250 x 625:33947806
In: 050
PredefinedType: SHED_ROOF
Qto_RoofBaseQuantities - GrossArea: 0.029806
Pset_Condition - AssessmentCondition: Empty
Pset_EnvironmentalImpactIndicators - Reference: vezelcementplaat 1250 x 625
Pset_RoofCommon - Reference: vezelcementplaat 1250 x 625; IsExternal: yes; FireRating: EI 60

# IfcRoof: vezelcementplaat 1250 x 15:vezelcementplaat 1250 x 625, vezelcementplaat 1250 x 15:vezelcementplaat 1250 x 625:33947819
In: 050
PredefinedType: SHED_ROOF
Qto_RoofBaseQuantities - GrossArea: 0.0298123
Pset_Condition - AssessmentCondition: Empty
Pset_EnvironmentalImpactIndicators - Reference: vezelcementplaat 1250 x 625
Pset_RoofCommon - Reference: vezelcementplaat 1250 x 625; IsExternal: yes; FireRating: EI 60

# IfcRoof: vezelcementplaat 1250 x 16:vezelcementplaat 1250 x 625, vezelcementplaat 1250 x 16:vezelcementplaat 1250 x 625:33947832
In: 050
PredefinedType: SHED_ROOF
Qto_RoofBaseQuantities - GrossArea: 0.0298123
Pset_Condition - AssessmentCondition: Empty
Pset_EnvironmentalImpactIndicators - Reference: vezelcementplaat 1250 x 625
Pset_RoofCommon - Reference: vezelcementplaat 1250 x 625; IsExternal: yes; FireRating: EI 60

# IfcRoof: vezelcementplaat 1250 x 17:vezelcementplaat 1250 x 625, vezelcementplaat 1250 x 17:vezelcementplaat 1250 x 625:33947845
In: 050
PredefinedType: SHED_ROOF
Qto_RoofBaseQuantities - GrossArea: 0.0298123
Pset_Condition - AssessmentCondition: Empty
Pset_EnvironmentalImpactIndicators - Reference: vezelcementplaat 1250 x 625
Pset_RoofCommon - Reference: vezelcementplaat 1250 x 625; IsExternal: yes; FireRating: EI 60

# IfcRoof: vezelcementplaat 1250 x 18:vezelcementplaat 1250 x 625, vezelcementplaat 1250 x 18:vezelcementplaat 1250 x 625:33947858
In: 050
PredefinedType: SHED_ROOF
Qto_RoofBaseQuantities - GrossArea: 0.0149061
Pset_Condition - AssessmentCondition: Empty
Pset_EnvironmentalImpactIndicators - Reference: vezelcementplaat 1250 x 625
Pset_RoofCommon - Reference: vezelcementplaat 1250 x 625; IsExternal: yes; FireRating: EI 60

# IfcRoof: vezelcementplaat 1250 x 19:vezelcementplaat 1250 x 625, vezelcementplaat 1250 x 19:vezelcementplaat 1250 x 625:33947871
In: 050
PredefinedType: SHED_ROOF
Qto_RoofBaseQuantities - GrossArea: 0.0149124
Pset_Condition - AssessmentCondition: Empty
Pset_EnvironmentalImpactIndicators - Reference: vezelcementplaat 1250 x 625
Pset_RoofCommon - Reference: vezelcementplaat 1250 x 625; IsExternal: yes; FireRating: EI 60

# IfcRoof: vezelcementplaat 1250 x 1:vezelcementplaat 1250 x 625, vezelcementplaat 1250 x 1:vezelcementplaat 1250 x 625:33946629
In: 050
PredefinedType: SHED_ROOF
Qto_RoofBaseQuantities - GrossArea: 0.029806
Pset_Condition - AssessmentCondition: Empty
Pset_EnvironmentalImpactIndicators - Reference: vezelcementplaat 1250 x 625
Pset_RoofCommon - Reference: vezelcementplaat 1250 x 625; IsExternal: yes; FireRating: EI 60

# IfcRoof: vezelcementplaat 1250 x 20:vezelcementplaat 1250 x 625, vezelcementplaat 1250 x 20:vezelcementplaat 1250 x 625:33947884
In: 050
PredefinedType: SHED_ROOF
Qto_RoofBaseQuantities - GrossArea: 0.0298185
Pset_Condition - AssessmentCondition: Empty
Pset_EnvironmentalImpactIndicators - Reference: vezelcementplaat 1250 x 625
Pset_RoofCommon - Reference: vezelcementplaat 1250 x 625; IsExternal: yes; FireRating: EI 60

# IfcRoof: vezelcementplaat 1250 x 21:vezelcementplaat 1250 x 625, vezelcementplaat 1250 x 21:vezelcementplaat 1250 x 625:33947897
In: 050
PredefinedType: SHED_ROOF
Qto_RoofBaseQuantities - GrossArea: 0.029806
Pset_Condition - AssessmentCondition: Empty
Pset_EnvironmentalImpactIndicators - Reference: vezelcementplaat 1250 x 625
Pset_RoofCommon - Reference: vezelcementplaat 1250 x 625; IsExternal: yes; FireRating: EI 60

# IfcRoof: vezelcementplaat 1250 x 22:vezelcementplaat 1250 x 625, vezelcementplaat 1250 x 22:vezelcementplaat 1250 x 625:33947910
In: 050
PredefinedType: SHED_ROOF
Qto_RoofBaseQuantities - GrossArea: 0.0298123
Pset_Condition - AssessmentCondition: Empty
Pset_EnvironmentalImpactIndicators - Reference: vezelcementplaat 1250 x 625
Pset_RoofCommon - Reference: vezelcementplaat 1250 x 625; IsExternal: yes; FireRating: EI 60

# IfcRoof: vezelcementplaat 1250 x 23:vezelcementplaat 1250 x 625, vezelcementplaat 1250 x 23:vezelcementplaat 1250 x 625:33947923
In: 050
PredefinedType: SHED_ROOF
Qto_RoofBaseQuantities - GrossArea: 0.0298123
Pset_Condition - AssessmentCondition: Empty
Pset_EnvironmentalImpactIndicators - Reference: vezelcementplaat 1250 x 625
Pset_RoofCommon - Reference: vezelcementplaat 1250 x 625; IsExternal: yes; FireRating: EI 60

# IfcRoof: vezelcementplaat 1250 x 24:vezelcementplaat 1250 x 625, vezelcementplaat 1250 x 24:vezelcementplaat 1250 x 625:33947936
In: 050
PredefinedType: SHED_ROOF
Qto_RoofBaseQuantities - GrossArea: 0.0298123
Pset_Condition - AssessmentCondition: Empty
Pset_EnvironmentalImpactIndicators - Reference: vezelcementplaat 1250 x 625
Pset_RoofCommon - Reference: vezelcementplaat 1250 x 625; IsExternal: yes; FireRating: EI 60

# IfcRoof: vezelcementplaat 1250 x 25:vezelcementplaat 1250 x 625, vezelcementplaat 1250 x 25:vezelcementplaat 1250 x 625:33947949
In: 050
PredefinedType: SHED_ROOF
Qto_RoofBaseQuantities - GrossArea: 0.0298185
Pset_Condition - AssessmentCondition: Empty
Pset_EnvironmentalImpactIndicators - Reference: vezelcementplaat 1250 x 625
Pset_RoofCommon - Reference: vezelcementplaat 1250 x 625; IsExternal: yes; FireRating: EI 60

# IfcRoof: vezelcementplaat 1250 x 26:vezelcementplaat 1250 x 625, vezelcementplaat 1250 x 26:vezelcementplaat 1250 x 625:33947970
In: 050
PredefinedType: SHED_ROOF
Qto_RoofBaseQuantities - GrossArea: 0.0298185
Pset_Condition - AssessmentCondition: Empty
Pset_EnvironmentalImpactIndicators - Reference: vezelcementplaat 1250 x 625
Pset_RoofCommon - Reference: vezelcementplaat 1250 x 625; IsExternal: yes; FireRating: EI 60

# IfcRoof: vezelcementplaat 1250 x 27:vezelcementplaat 1250 x 625, vezelcementplaat 1250 x 27:vezelcementplaat 1250 x 625:33947983
In: 050
PredefinedType: SHED_ROOF
Qto_RoofBaseQuantities - GrossArea: 0.029806
Pset_Condition - AssessmentCondition: Empty
Pset_EnvironmentalImpactIndicators - Reference: vezelcementplaat 1250 x 625
Pset_RoofCommon - Reference: vezelcementplaat 1250 x 625; IsExternal: yes; FireRating: EI 60

# IfcRoof: vezelcementplaat 1250 x 28:vezelcementplaat 1250 x 625, vezelcementplaat 1250 x 28:vezelcementplaat 1250 x 625:33947996
In: 050
PredefinedType: SHED_ROOF
Qto_RoofBaseQuantities - GrossArea: 0.0298123
Pset_Condition - AssessmentCondition: Empty
Pset_EnvironmentalImpactIndicators - Reference: vezelcementplaat 1250 x 625
Pset_RoofCommon - Reference: vezelcementplaat 1250 x 625; IsExternal: yes; FireRating: EI 60

# IfcRoof: vezelcementplaat 1250 x 29:vezelcementplaat 1250 x 625, vezelcementplaat 1250 x 29:vezelcementplaat 1250 x 625:33948009
In: 050
PredefinedType: SHED_ROOF
Qto_RoofBaseQuantities - GrossArea: 0.0298123
Pset_Condition - AssessmentCondition: Empty
Pset_EnvironmentalImpactIndicators - Reference: vezelcementplaat 1250 x 625
Pset_RoofCommon - Reference: vezelcementplaat 1250 x 625; IsExternal: yes; FireRating: EI 60

# IfcRoof: vezelcementplaat 1250 x 2:vezelcementplaat 1250 x 625, vezelcementplaat 1250 x 2:vezelcementplaat 1250 x 625:33946837
In: 050
PredefinedType: SHED_ROOF
Qto_RoofBaseQuantities - GrossArea: 0.0298123
Pset_Condition - AssessmentCondition: Empty
Pset_EnvironmentalImpactIndicators - Reference: vezelcementplaat 1250 x 625
Pset_RoofCommon - Reference: vezelcementplaat 1250 x 625; IsExternal: yes; FireRating: EI 60

# IfcRoof: vezelcementplaat 1250 x 30:vezelcementplaat 1250 x 625, vezelcementplaat 1250 x 30:vezelcementplaat 1250 x 625:33948022
In: 050
PredefinedType: SHED_ROOF
Qto_RoofBaseQuantities - GrossArea: 0.0298123
Pset_Condition - AssessmentCondition: Empty
Pset_EnvironmentalImpactIndicators - Reference: vezelcementplaat 1250 x 625
Pset_RoofCommon - Reference: vezelcementplaat 1250 x 625; IsExternal: yes; FireRating: EI 60

# IfcRoof: vezelcementplaat 1250 x 31:vezelcementplaat 1250 x 625, vezelcementplaat 1250 x 31:vezelcementplaat 1250 x 625:33948035
In: 050
PredefinedType: SHED_ROOF
Qto_RoofBaseQuantities - GrossArea: 0.0149061
Pset_Condition - AssessmentCondition: Empty
Pset_EnvironmentalImpactIndicators - Reference: vezelcementplaat 1250 x 625
Pset_RoofCommon - Reference: vezelcementplaat 1250 x 625; IsExternal: yes; FireRating: EI 60

# IfcRoof: vezelcementplaat 1250 x 32:vezelcementplaat 1250 x 625, vezelcementplaat 1250 x 32:vezelcementplaat 1250 x 625:33948048
In: 050
PredefinedType: SHED_ROOF
Qto_RoofBaseQuantities - GrossArea: 0.0149124
Pset_Condition - AssessmentCondition: Empty
Pset_EnvironmentalImpactIndicators - Reference: vezelcementplaat 1250 x 625
Pset_RoofCommon - Reference: vezelcementplaat 1250 x 625; IsExternal: yes; FireRating: EI 60

# IfcRoof: vezelcementplaat 1250 x 33:vezelcementplaat 1250 x 625, vezelcementplaat 1250 x 33:vezelcementplaat 1250 x 625:33948061
In: 050
PredefinedType: SHED_ROOF
Qto_RoofBaseQuantities - GrossArea: 0.0298185
Pset_Condition - AssessmentCondition: Empty
Pset_EnvironmentalImpactIndicators - Reference: vezelcementplaat 1250 x 625
Pset_RoofCommon - Reference: vezelcementplaat 1250 x 625; IsExternal: yes; FireRating: EI 60

# IfcRoof: vezelcementplaat 1250 x 34:vezelcementplaat 1250 x 625, vezelcementplaat 1250 x 34:vezelcementplaat 1250 x 625:33948074
In: 050
PredefinedType: SHED_ROOF
Qto_RoofBaseQuantities - GrossArea: 0.029806
Pset_Condition - AssessmentCondition: Empty
Pset_EnvironmentalImpactIndicators - Reference: vezelcementplaat 1250 x 625
Pset_RoofCommon - Reference: vezelcementplaat 1250 x 625; IsExternal: yes; FireRating: EI 60

# IfcRoof: vezelcementplaat 1250 x 35:vezelcementplaat 1250 x 625, vezelcementplaat 1250 x 35:vezelcementplaat 1250 x 625:33948087
In: 050
PredefinedType: SHED_ROOF
Qto_RoofBaseQuantities - GrossArea: 0.0298123
Pset_Condition - AssessmentCondition: Empty
Pset_EnvironmentalImpactIndicators - Reference: vezelcementplaat 1250 x 625
Pset_RoofCommon - Reference: vezelcementplaat 1250 x 625; IsExternal: yes; FireRating: EI 60

# IfcRoof: vezelcementplaat 1250 x 36:vezelcementplaat 1250 x 625, vezelcementplaat 1250 x 36:vezelcementplaat 1250 x 625:33948100
In: 050
PredefinedType: SHED_ROOF
Qto_RoofBaseQuantities - GrossArea: 0.0298123
Pset_Condition - AssessmentCondition: Empty
Pset_EnvironmentalImpactIndicators - Reference: vezelcementplaat 1250 x 625
Pset_RoofCommon - Reference: vezelcementplaat 1250 x 625; IsExternal: yes; FireRating: EI 60

# IfcRoof: vezelcementplaat 1250 x 37:vezelcementplaat 1250 x 625, vezelcementplaat 1250 x 37:vezelcementplaat 1250 x 625:33948113
In: 050
PredefinedType: SHED_ROOF
Qto_RoofBaseQuantities - GrossArea: 0.0298123
Pset_Condition - AssessmentCondition: Empty
Pset_EnvironmentalImpactIndicators - Reference: vezelcementplaat 1250 x 625
Pset_RoofCommon - Reference: vezelcementplaat 1250 x 625; IsExternal: yes; FireRating: EI 60

# IfcRoof: vezelcementplaat 1250 x 38:vezelcementplaat 1250 x 625, vezelcementplaat 1250 x 38:vezelcementplaat 1250 x 625:33948126
In: 050
PredefinedType: SHED_ROOF
Qto_RoofBaseQuantities - GrossArea: 0.0298185
Pset_Condition - AssessmentCondition: Empty
Pset_EnvironmentalImpactIndicators - Reference: vezelcementplaat 1250 x 625
Pset_RoofCommon - Reference: vezelcementplaat 1250 x 625; IsExternal: yes; FireRating: EI 60

# IfcRoof: vezelcementplaat 1250 x 39:vezelcementplaat 1250 x 625, vezelcementplaat 1250 x 39:vezelcementplaat 1250 x 625:33948149
In: 050
PredefinedType: SHED_ROOF
Qto_RoofBaseQuantities - GrossArea: 0.0298185
Pset_Condition - AssessmentCondition: Empty
Pset_EnvironmentalImpactIndicators - Reference: vezelcementplaat 1250 x 625
Pset_RoofCommon - Reference: vezelcementplaat 1250 x 625; IsExternal: yes; FireRating: EI 60

# IfcRoof: vezelcementplaat 1250 x 3:vezelcementplaat 1250 x 625, vezelcementplaat 1250 x 3:vezelcementplaat 1250 x 625:33946858
In: 050
PredefinedType: SHED_ROOF
Qto_RoofBaseQuantities - GrossArea: 0.0298123
Pset_Condition - AssessmentCondition: Empty
Pset_EnvironmentalImpactIndicators - Reference: vezelcementplaat 1250 x 625
Pset_RoofCommon - Reference: vezelcementplaat 1250 x 625; IsExternal: yes; FireRating: EI 60

# IfcRoof: vezelcementplaat 1250 x 40:vezelcementplaat 1250 x 625, vezelcementplaat 1250 x 40:vezelcementplaat 1250 x 625:33948162
In: 050
PredefinedType: SHED_ROOF
Qto_RoofBaseQuantities - GrossArea: 0.029806
Pset_Condition - AssessmentCondition: Empty
Pset_EnvironmentalImpactIndicators - Reference: vezelcementplaat 1250 x 625
Pset_RoofCommon - Reference: vezelcementplaat 1250 x 625; IsExternal: yes; FireRating: EI 60

# IfcRoof: vezelcementplaat 1250 x 41:vezelcementplaat 1250 x 625, vezelcementplaat 1250 x 41:vezelcementplaat 1250 x 625:33948175
In: 050
PredefinedType: SHED_ROOF
Qto_RoofBaseQuantities - GrossArea: 0.0298123
Pset_Condition - AssessmentCondition: Empty
Pset_EnvironmentalImpactIndicators - Reference: vezelcementplaat 1250 x 625
Pset_RoofCommon - Reference: vezelcementplaat 1250 x 625; IsExternal: yes; FireRating: EI 60

# IfcRoof: vezelcementplaat 1250 x 42:vezelcementplaat 1250 x 625, vezelcementplaat 1250 x 42:vezelcementplaat 1250 x 625:33948188
In: 050
PredefinedType: SHED_ROOF
Qto_RoofBaseQuantities - GrossArea: 0.0298123
Pset_Condition - AssessmentCondition: Empty
Pset_EnvironmentalImpactIndicators - Reference: vezelcementplaat 1250 x 625
Pset_RoofCommon - Reference: vezelcementplaat 1250 x 625; IsExternal: yes; FireRating: EI 60

# IfcRoof: vezelcementplaat 1250 x 45:vezelcementplaat 1250 x 625, vezelcementplaat 1250 x 45:vezelcementplaat 1250 x 625:33948227
In: 050
PredefinedType: SHED_ROOF
Qto_RoofBaseQuantities - GrossArea: 0.0149124
Pset_Condition - AssessmentCondition: Empty
Pset_EnvironmentalImpactIndicators - Reference: vezelcementplaat 1250 x 625
Pset_RoofCommon - Reference: vezelcementplaat 1250 x 625; IsExternal: yes; FireRating: EI 60

# IfcRoof: vezelcementplaat 1250 x 46:vezelcementplaat 1250 x 625, vezelcementplaat 1250 x 46:vezelcementplaat 1250 x 625:33948240
In: 050
PredefinedType: SHED_ROOF
Qto_RoofBaseQuantities - GrossArea: 0.0298185
Pset_Condition - AssessmentCondition: Empty
Pset_EnvironmentalImpactIndicators - Reference: vezelcementplaat 1250 x 625
Pset_RoofCommon - Reference: vezelcementplaat 1250 x 625; IsExternal: yes; FireRating: EI 60

# IfcRoof: vezelcementplaat 1250 x 47:vezelcementplaat 1250 x 625, vezelcementplaat 1250 x 47:vezelcementplaat 1250 x 625:33948253
In: 050
PredefinedType: SHED_ROOF
Qto_RoofBaseQuantities - GrossArea: 0.029806
Pset_Condition - AssessmentCondition: Empty
Pset_EnvironmentalImpactIndicators - Reference: vezelcementplaat 1250 x 625
Pset_RoofCommon - Reference: vezelcementplaat 1250 x 625; IsExternal: yes; FireRating: EI 60

# IfcRoof: vezelcementplaat 1250 x 48:vezelcementplaat 1250 x 625, vezelcementplaat 1250 x 48:vezelcementplaat 1250 x 625:33948266
In: 050
PredefinedType: SHED_ROOF
Qto_RoofBaseQuantities - GrossArea: 0.0298123
Pset_Condition - AssessmentCondition: Empty
Pset_EnvironmentalImpactIndicators - Reference: vezelcementplaat 1250 x 625
Pset_RoofCommon - Reference: vezelcementplaat 1250 x 625; IsExternal: yes; FireRating: EI 60

# IfcRoof: vezelcementplaat 1250 x 4:vezelcementplaat 1250 x 625, vezelcementplaat 1250 x 4:vezelcementplaat 1250 x 625:33946879
In: 050
PredefinedType: SHED_ROOF
Qto_RoofBaseQuantities - GrossArea: 0.0298123
Pset_Condition - AssessmentCondition: Empty
Pset_EnvironmentalImpactIndicators - Reference: vezelcementplaat 1250 x 625
Pset_RoofCommon - Reference: vezelcementplaat 1250 x 625; IsExternal: yes; FireRating: EI 60

# IfcRoof: vezelcementplaat 1250 x 51:vezelcementplaat 1250 x 625, vezelcementplaat 1250 x 51:vezelcementplaat 1250 x 625:33948305
In: 050
PredefinedType: SHED_ROOF
Qto_RoofBaseQuantities - GrossArea: 0.0298185
Pset_Condition - AssessmentCondition: Empty
Pset_EnvironmentalImpactIndicators - Reference: vezelcementplaat 1250 x 625
Pset_RoofCommon - Reference: vezelcementplaat 1250 x 625; IsExternal: yes; FireRating: EI 60

# IfcRoof: vezelcementplaat 1250 x 5:vezelcementplaat 1250 x 625, vezelcementplaat 1250 x 5:vezelcementplaat 1250 x 625:33946900
In: 050
PredefinedType: SHED_ROOF
Qto_RoofBaseQuantities - GrossArea: 0.0149061
Pset_Condition - AssessmentCondition: Empty
Pset_EnvironmentalImpactIndicators - Reference: vezelcementplaat 1250 x 625
Pset_RoofCommon - Reference: vezelcementplaat 1250 x 625; IsExternal: yes; FireRating: EI 60

# IfcRoof: vezelcementplaat 1250 x 625:vezelcementplaat 1250 x 625, vezelcementplaat 1250 x 625:vezelcementplaat 1250 x 625:33946399
In: 050
PredefinedType: SHED_ROOF
Qto_RoofBaseQuantities - GrossArea: 0.0298185
Pset_Condition - AssessmentCondition: Empty
Pset_EnvironmentalImpactIndicators - Reference: vezelcementplaat 1250 x 625
Pset_RoofCommon - Reference: vezelcementplaat 1250 x 625; IsExternal: yes; FireRating: EI 60

# IfcRoof: vezelcementplaat 1250 x 6:vezelcementplaat 1250 x 625, vezelcementplaat 1250 x 6:vezelcementplaat 1250 x 625:33947144
In: 050
PredefinedType: SHED_ROOF
Qto_RoofBaseQuantities - GrossArea: 0.0149124
Pset_Condition - AssessmentCondition: Empty
Pset_EnvironmentalImpactIndicators - Reference: vezelcementplaat 1250 x 625
Pset_RoofCommon - Reference: vezelcementplaat 1250 x 625; IsExternal: yes; FireRating: EI 60

# IfcRoof: vezelcementplaat 1250 x 7:vezelcementplaat 1250 x 625, vezelcementplaat 1250 x 7:vezelcementplaat 1250 x 625:33947493
In: 050
PredefinedType: SHED_ROOF
Qto_RoofBaseQuantities - GrossArea: 0.0298185
Pset_Condition - AssessmentCondition: Empty
Pset_EnvironmentalImpactIndicators - Reference: vezelcementplaat 1250 x 625
Pset_RoofCommon - Reference: vezelcementplaat 1250 x 625; IsExternal: yes; FireRating: EI 60

# IfcRoof: vezelcementplaat 1250 x 8:vezelcementplaat 1250 x 625, vezelcementplaat 1250 x 8:vezelcementplaat 1250 x 625:33947506
In: 050
PredefinedType: SHED_ROOF
Qto_RoofBaseQuantities - GrossArea: 0.029806
Pset_Condition - AssessmentCondition: Empty
Pset_EnvironmentalImpactIndicators - Reference: vezelcementplaat 1250 x 625
Pset_RoofCommon - Reference: vezelcementplaat 1250 x 625; IsExternal: yes; FireRating: EI 60

# IfcRoof: vezelcementplaat 1250 x 9:vezelcementplaat 1250 x 625, vezelcementplaat 1250 x 9:vezelcementplaat 1250 x 625:33947519
In: 050
PredefinedType: SHED_ROOF
Qto_RoofBaseQuantities - GrossArea: 0.0298123
Pset_Condition - AssessmentCondition: Empty
Pset_EnvironmentalImpactIndicators - Reference: vezelcementplaat 1250 x 625
Pset_RoofCommon - Reference: vezelcementplaat 1250 x 625; IsExternal: yes; FireRating: EI 60

# IfcSlab: <Unnamed> 250 (10)
Type - PredefinedType: FLOOR; Material: <Unnamed>
Cpset_Slab - LevelOfAccuracy: in te vullen door Buildwise
IfcClassificationReference - TDS_link: .\05 As Builtdossier\2. Bouwkunde\2.2. Stabiliteit\2.2.0 technische fiche's\TF S 4.3 A-beton.pdf; TDS_link_extra_1: .\05 As Builtdossier\2. Bouwkunde\2.2. Stabiliteit\2.2.0 technische fiche's\TF S 4.3.2.1 A-wapeningsstaal.pdf
Pset_ConcreteElementGeneral - ConstructionMethod: on-site
Pset_Condition - AssessmentCondition: Empty
Pset_EnvironmentalImpactIndicators - sets with these values: 2
Pset_SlabCommon - PitchAngle: 0 rad; IsExternal: no; LoadBearing: yes
Name (Foundation Slab:...) | In | Level | Height Offset From Level | Name = Pset_EnvironmentalImpactIndicators, Reference = Pset_SlabCommon, Reference | Width | Length | Perimeter | GrossArea | GrossVolume = NetVolume | Depth
Foundation Slab 250 mm dik:34108511 | K20 | K20 | 590 | Foundation Slab 250 mm dik | 2225.19 | 700 | 19.1942 | 1.55764 | 0.389409 | 250
Foundation Slab 250 mm dik:34108089 | K10 | K10 | -60 | Foundation Slab 250 mm dik | 2260.19 | 700 | 19.4238 | 1.58214 | 0.395534 | 250
Foundation Slab 250 mm dik:34108176 | K10 | K10 | -60 | Foundation Slab 250 mm dik | 2225.19 | 700 | 19.1942 | 1.55764 | 0.389409 | 250
Foundation Slab 440 mm dik:34108206 | K10 | K10 | 380 | Foundation Slab 440 mm dik | 250 | 250 | 3.28084 | 0.0625 | 0.0275 | 440
Foundation Slab 440 mm dik:34108312 | K10 | K10 | 380 | Foundation Slab 440 mm dik | 250 | 250 | 3.28084 | 0.0625 | 0.0275 | 440
Foundation Slab 440 mm dik:34108339 | K10 | K10 | 380 | Foundation Slab 440 mm dik | 250 | 250 | 3.28084 | 0.0625 | 0.0275 | 440
Foundation Slab 440 mm dik:34108370 | K10 | K10 | 380 | Foundation Slab 440 mm dik | 250 | 250 | 3.28084 | 0.0625 | 0.0275 | 440
Foundation Slab 250 mm dik:34108399 | K10 | K10 | -60 | Foundation Slab 250 mm dik | 2225.19 | 700 | 19.1942 | 1.55764 | 0.389409 | 250
Foundation Slab 440 mm dik:34108408 | K10 | K10 | 380 | Foundation Slab 440 mm dik | 250 | 250 | 3.28084 | 0.0625 | 0.0275 | 440
Foundation Slab 440 mm dik:34108417 | K10 | K10 | 380 | Foundation Slab 440 mm dik | 250 | 250 | 3.28084 | 0.0625 | 0.0275 | 440

# IfcSlab: BB_09.08.21#03_Vloer_Verhoogd_Bestaande te verhogen 20 (8)
In: 000
Type - PredefinedType: FLOOR; Material: BB_09.08.21#03_Vloer_Verhoogd_Bestaande te verhogen
Cpset_Slab - LevelOfAccuracy: in te vullen door Buildwise
IfcBuildingStorey - Base Constraint: 000; Top Constraint: Up to level: 000
IfcClassificationReference - Keynote: 09.08.93#01; GVH_artnr 01: 09.08.21#03; GVH_artnr 02: 09.08.93#01; GVH_artnr 03: geen waarde gevonden; GVH_artnr 04: geen waarde gevonden; GVH_artnr 05: geen waarde gevonden; GVH_artnr 06: geen waarde gevonden; TDS_link: .\05 As Builtdossier\2. Bouwkunde\2.1 Architectuur\2.1.9 vloeren\TF A 09.08.21_01 A droge holtevloer uit calciumsulfaatplaten.pdf
IfcRoot - Name: BB_09.08.XX_Rand verhoogde vloer, 20 mm
Qto_SlabBaseQuantities - Width: 20
Pset_Condition - AssessmentCondition: Empty
Pset_EnvironmentalImpactIndicators - Reference: BB_09.08.XX_Rand verhoogde vloer, 20 mm; sets with these values: 2
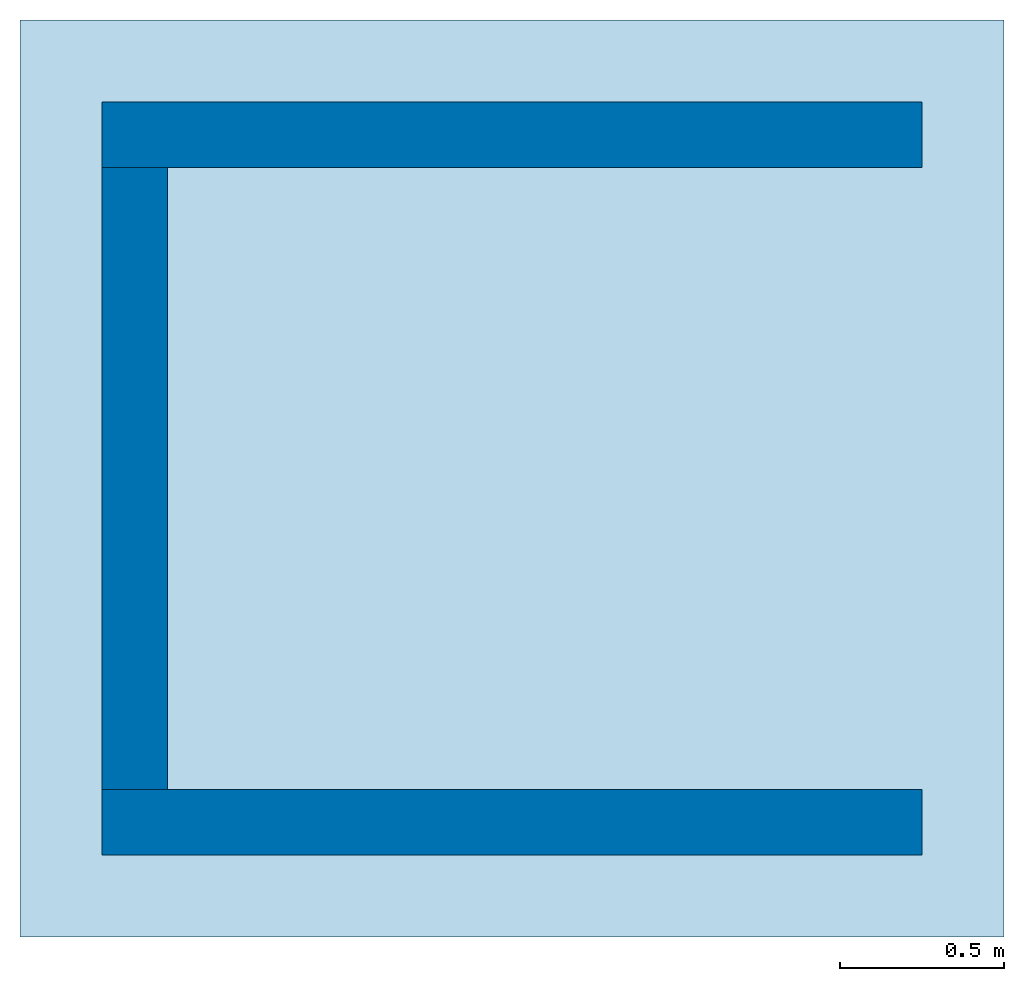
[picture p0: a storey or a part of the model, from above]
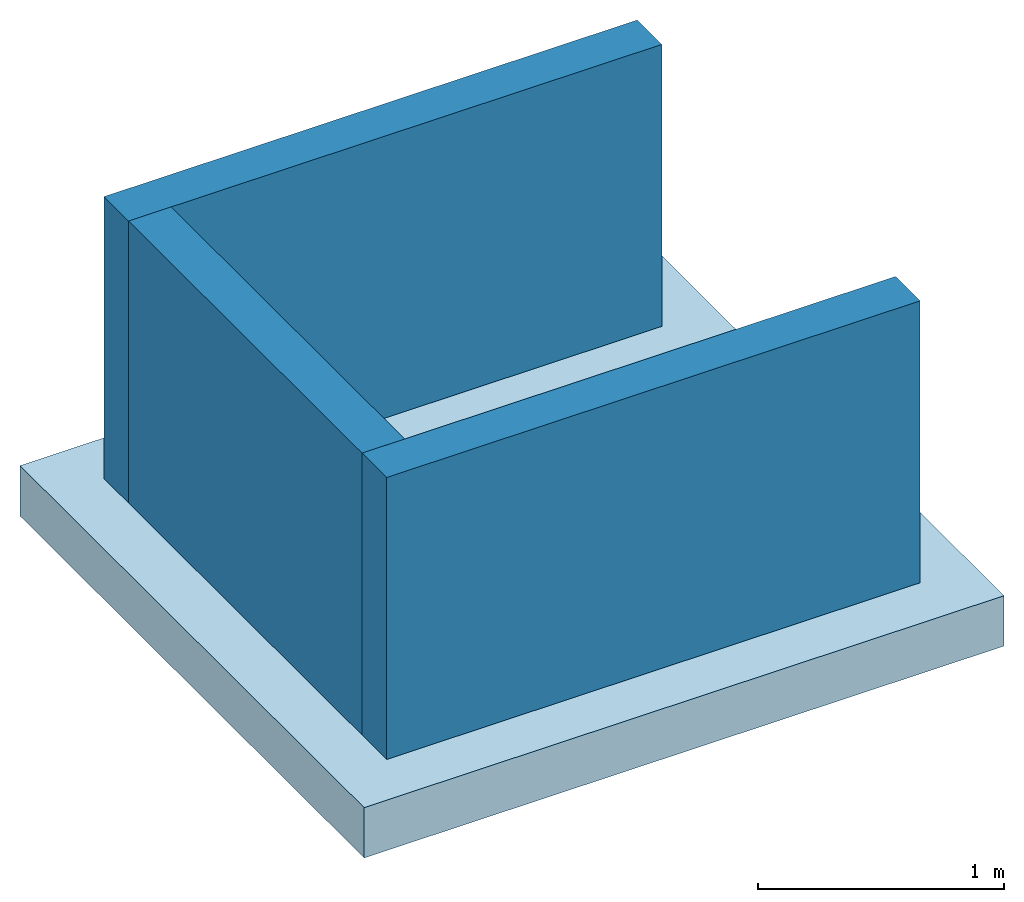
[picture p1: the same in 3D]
Properties of the parts of a building model (IFC4X3_ADD2), part 15 of 28

# IfcSlab: BB_09.08.21#03_Vloer_Verhoogd_Bestaande te verhogen 20 (8)
Pset_SlabCommon - Reference: BB_09.08.XX_Rand verhoogde vloer, 20 mm; FireRating: REI30; PitchAngle: 0 rad; IsExternal: yes; LoadBearing: no
Name (Basic Wall:BB_09.08.XX_Rand verhoogde vloer, 20 mm:...) | Base Offset | Top Offset | Length | NetVolume
19896910 | -200 | 145 | 1010 | 0.0069
19896984 | -200 | 295 | 860 | 0.008613
19897653 | -200 | 295 | 300 | 0.00297
19897708 | -200 | 295 | 1010 | 0.0099
19898146 | -80 | 295 | 910 | 0.0069
19898168 | -80 | 295 | 300 | 0.00225
19898203 | -80 | 295 | 990 | 0.00735
19898375 | -80 | 145 | 980 | 0.00441

# IfcSlab: BB_Belijning parkeervakken_Nieuw 10 (168)
Type - PredefinedType: FLOOR; Material: BB_Belijning parkeervakken_Nieuw
Cpset_Slab - LevelOfAccuracy: in te vullen door Buildwise
IfcBuildingStorey - Height Offset From Level: 10
IfcClassificationReference - GVH_artnr 01: geen waarde gevonden; GVH_artnr 02: geen waarde gevonden; GVH_artnr 03: geen waarde gevonden; GVH_artnr 04: geen waarde gevonden; GVH_artnr 05: geen waarde gevonden; GVH_artnr 06: geen waarde gevonden; TDS_link: .\05 As Builtdossier\2. Bouwkunde\2.1 Architectuur\2.1.15 afwerkings- en beschermingslagen\TF A 15.01.34 A - epoxy schilderwerk op vloer- en wandtegels.pdf
Pset_ConcreteElementGeneral - ConstructionMethod: on-site
Pset_Condition - AssessmentCondition: Empty
Pset_EnvironmentalImpactIndicators - sets with these values: 2
Pset_SlabCommon - PitchAngle: 0 rad; IsExternal: no; LoadBearing: no
Name (Floor:...) | In | Level | BB_Element_Lokaalnummer01 | Name = Pset_EnvironmentalImpactIndicators, Reference = Pset_SlabCommon, Reference | Width | Length | Perimeter | GrossArea | GrossVolume | NetVolume | Depth
BB_13.XX_Epoxyverf, belijning zebrapaden:25354380 | K20 | K20 | K.-2.P1 | BB_13.XX_Epoxyverf, belijning zebrapaden | 1500 | 300 | 11.811 | 0.45 | 0.0045 | 0.0045 | 10
BB_13.XX_Epoxyverf, belijning zebrapaden:25354467 | K20 | K20 | K.-2.P1 | BB_13.XX_Epoxyverf, belijning zebrapaden | 1500 | 300 | 11.811 | 0.45 | 0.0045 | 0.0045 | 10
BB_13.XX_Epoxyverf, belijning zebrapaden:25354495 | K20 | K20 | K.-2.P1 | BB_13.XX_Epoxyverf, belijning zebrapaden | 1500 | 300 | 11.811 | 0.45 | 0.0045 | 0.0045 | 10
BB_13.XX_Epoxyverf, belijning zebrapaden:25354504 | K20 | K20 | K.-2.P1 | BB_13.XX_Epoxyverf, belijning zebrapaden | 1500 | 300 | 11.811 | 0.45 | 0.0045 | 0.0045 | 10
BB_13.XX_Epoxyverf, belijning zebrapaden:25354513 | K20 | K20 | K.-2.P1 | BB_13.XX_Epoxyverf, belijning zebrapaden | 1155 | 300 | 9.54724 | 0.3465 | 0.003465 | 0.003465 | 10
BB_13.XX_Epoxyverf, belijning zebrapaden:25354522 | K20 | K20 | K.-2.P1 | BB_13.XX_Epoxyverf, belijning zebrapaden | 1155 | 300 | 9.54724 | 0.3465 | 0.003465 | 0.003465 | 10
BB_13.XX_Epoxyverf, belijning zebrapaden:25354531 | K20 | K20 | K.-2.P1 | BB_13.XX_Epoxyverf, belijning zebrapaden | 1155 | 300 | 9.54724 | 0.3465 | 0.003465 | 0.003465 | 10
BB_13.XX_Epoxyverf, belijning zebrapaden:25354540 | K20 | K20 | K.-2.P1 | BB_13.XX_Epoxyverf, belijning zebrapaden | 1155 | 300 | 9.54724 | 0.3465 | 0.003465 | 0.003465 | 10
BB_13.XX_Epoxyverf, belijning zebrapaden:25354549 | K20 | K20 | K.-2.P1 | BB_13.XX_Epoxyverf, belijning zebrapaden | 1155 | 300 | 9.54724 | 0.3465 | 0.003465 | 0.003465 | 10
BB_13.XX_Epoxyverf, belijning zebrapaden:25354558 | K20 | K20 | K.-2.P1 | BB_13.XX_Epoxyverf, belijning zebrapaden | 1155 | 300 | 9.54724 | 0.3465 | 0.003465 | 0.003465 | 10
BB_13.XX_Epoxyverf, belijning zebrapaden:25355033 | K20 | K20 | K.-2.P2 | BB_13.XX_Epoxyverf, belijning zebrapaden | 1500 | 300 | 11.811 | 0.45 | 0.0045 | 0.0045 | 10
BB_13.XX_Epoxyverf, belijning zebrapaden:25355043 | K20 | K20 | K.-2.P2 | BB_13.XX_Epoxyverf, belijning zebrapaden | 1500 | 300 | 11.811 | 0.45 | 0.0045 | 0.0045 | 10
BB_13.XX_Epoxyverf, belijning zebrapaden:25355079 | K20 | K20 | K.-2.P2 | BB_13.XX_Epoxyverf, belijning zebrapaden | 1500 | 300 | 11.811 | 0.45 | 0.0045 | 0.0045 | 10
BB_13.XX_Epoxyverf, belijning zebrapaden:25355088 | K20 | K20 | K.-2.P2 | BB_13.XX_Epoxyverf, belijning zebrapaden | 1500 | 300 | 11.811 | 0.45 | 0.0045 | 0.0045 | 10
BB_13.XX_Epoxyverf, belijning zebrapaden:25355097 | K20 | K20 | K.-2.P2 | BB_13.XX_Epoxyverf, belijning zebrapaden | 1500 | 300 | 11.811 | 0.45 | 0.0045 | 0.0045 | 10
BB_13.XX_Epoxyverf, belijning zebrapaden:25355106 | K20 | K20 | K.-2.P2 | BB_13.XX_Epoxyverf, belijning zebrapaden | 1500 | 300 | 11.811 | 0.45 | 0.0045 | 0.0045 | 10
BB_13.XX_Epoxyverf, belijning zebrapaden:25355115 | K20 | K20 | K.-2.P2 | BB_13.XX_Epoxyverf, belijning zebrapaden | 1500 | 300 | 11.811 | 0.45 | 0.0045 | 0.0045 | 10
BB_13.XX_Epoxyverf, belijning zebrapaden:25355124 | K20 | K20 | K.-2.P2 | BB_13.XX_Epoxyverf, belijning zebrapaden | 1500 | 300 | 11.811 | 0.45 | 0.0045 | 0.0045 | 10
BB_13.XX_Epoxyverf, belijning zebrapaden:25355133 | K20 | K20 | K.-2.P2 | BB_13.XX_Epoxyverf, belijning zebrapaden | 1500 | 300 | 11.811 | 0.45 | 0.0045 | 0.0045 | 10
BB_13.XX_Epoxyverf, belijning zebrapaden:25355142 | K20 | K20 | K.-2.P2 | BB_13.XX_Epoxyverf, belijning zebrapaden | 1500 | 300 | 11.811 | 0.45 | 0.0045 | 0.0045 | 10
BB_13.XX_Epoxyverf, belijning zebrapaden:25355151 | K20 | K20 | K.-2.P2 | BB_13.XX_Epoxyverf, belijning zebrapaden | 1500 | 300 | 11.811 | 0.45 | 0.0045 | 0.0045 | 10
BB_13.XX_Epoxyverf, belijning zebrapaden:25355160 | K20 | K20 | K.-2.P2 | BB_13.XX_Epoxyverf, belijning zebrapaden | 1500 | 300 | 11.811 | 0.45 | 0.0045 | 0.0045 | 10
BB_13.XX_Epoxyverf, belijning zebrapaden:25355169 | K20 | K20 | K.-2.P2 | BB_13.XX_Epoxyverf, belijning zebrapaden | 1500 | 300 | 11.811 | 0.45 | 0.0045 | 0.0045 | 10
BB_13.XX_Epoxyverf, belijning zebrapaden:25355178 | K20 | K20 | K.-2.P2 | BB_13.XX_Epoxyverf, belijning zebrapaden | 1500 | 300 | 11.811 | 0.45 | 0.0045 | 0.0045 | 10
BB_13.XX_Epoxyverf, belijning zebrapaden:25355187 | K20 | K20 | K.-2.P2 | BB_13.XX_Epoxyverf, belijning zebrapaden | 1500 | 300 | 11.811 | 0.45 | 0.0045 | 0.0045 | 10
BB_13.XX_Epoxyverf, belijning zebrapaden:25355196 | K20 | K20 | K.-2.P2 | BB_13.XX_Epoxyverf, belijning zebrapaden | 1500 | 300 | 11.811 | 0.45 | 0.0045 | 0.0045 | 10
BB_13.XX_Epoxyverf, belijning zebrapaden:25355205 | K20 | K20 | K.-2.P2 | BB_13.XX_Epoxyverf, belijning zebrapaden | 1500 | 300 | 11.811 | 0.45 | 0.0045 | 0.0045 | 10
BB_13.XX_Epoxyverf, belijning zebrapaden:25355214 | K20 | K20 | K.-2.P2 | BB_13.XX_Epoxyverf, belijning zebrapaden | 1500 | 300 | 11.811 | 0.45 | 0.0045 | 0.0045 | 10
BB_13.XX_Epoxyverf, belijning zebrapaden:25355223 | K20 | K20 | K.-2.P2 | BB_13.XX_Epoxyverf, belijning zebrapaden | 1500 | 300 | 11.811 | 0.45 | 0.0045 | 0.0045 | 10
BB_13.XX_Epoxyverf, belijning zebrapaden:25355232 | K20 | K20 | K.-2.P2 | BB_13.XX_Epoxyverf, belijning zebrapaden | 1500 | 300 | 11.811 | 0.45 | 0.0045 | 0.0045 | 10
BB_13.XX_Epoxyverf, belijning zebrapaden:25355241 | K20 | K20 | K.-2.P2 | BB_13.XX_Epoxyverf, belijning zebrapaden | 1500 | 300 | 11.811 | 0.45 | 0.0045 | 0.0045 | 10
BB_13.XX_Epoxyverf, belijning zebrapaden:25355250 | K20 | K20 | K.-2.P2 | BB_13.XX_Epoxyverf, belijning zebrapaden | 1500 | 300 | 11.811 | 0.45 | 0.0045 | 0.0045 | 10
BB_13.XX_Epoxyverf, belijning zebrapaden:25355259 | K20 | K20 | K.-2.P2 | BB_13.XX_Epoxyverf, belijning zebrapaden | 1500 | 300 | 11.811 | 0.45 | 0.0045 | 0.0045 | 10
BB_13.XX_Epoxyverf, belijning zebrapaden:25357657 | K20 | K20 | K.-2.P2 | BB_13.XX_Epoxyverf, belijning zebrapaden | 300 | 1500 | 11.811 | 0.45 | 0.0045 | 0.0045 | 10
BB_13.XX_Epoxyverf, belijning zebrapaden:25357719 | K20 | K20 | K.-2.P2 | BB_13.XX_Epoxyverf, belijning zebrapaden | 300 | 1500 | 11.811 | 0.45 | 0.0045 | 0.0045 | 10
BB_13.XX_Epoxyverf, belijning zebrapaden:25357738 | K20 | K20 | K.-2.P2 | BB_13.XX_Epoxyverf, belijning zebrapaden | 300 | 1500 | 11.811 | 0.45 | 0.0045 | 0.0045 | 10
BB_13.XX_Epoxyverf, belijning zebrapaden:25357747 | K20 | K20 | K.-2.P2 | BB_13.XX_Epoxyverf, belijning zebrapaden | 300 | 1500 | 11.811 | 0.45 | 0.0045 | 0.0045 | 10
BB_13.XX_Epoxyverf, belijning zebrapaden:25357756 | K20 | K20 | K.-2.P2 | BB_13.XX_Epoxyverf, belijning zebrapaden | 300 | 1500 | 11.811 | 0.45 | 0.0045 | 0.0045 | 10
BB_13.XX_Epoxyverf, belijning zebrapaden:25357765 | K20 | K20 | K.-2.P2 | BB_13.XX_Epoxyverf, belijning zebrapaden | 300 | 1500 | 11.811 | 0.45 | 0.0045 | 0.0045 | 10
BB_13.XX_Epoxyverf, belijning zebrapaden:25357774 | K20 | K20 | K.-2.P2 | BB_13.XX_Epoxyverf, belijning zebrapaden | 300 | 1500 | 11.811 | 0.45 | 0.0045 | 0.0045 | 10
BB_13.XX_Epoxyverf, belijning zebrapaden:25357783 | K20 | K20 | K.-2.P2 | BB_13.XX_Epoxyverf, belijning zebrapaden | 300 | 1500 | 11.811 | 0.45 | 0.0045 | 0.0045 | 10
BB_13.XX_Epoxyverf, belijning zebrapaden:25357792 | K20 | K20 | K.-2.P2 | BB_13.XX_Epoxyverf, belijning zebrapaden | 300 | 1500 | 11.811 | 0.45 | 0.0045 | 0.0045 | 10
BB_13.XX_Epoxyverf, belijning zebrapaden:25357801 | K20 | K20 | K.-2.P2 | BB_13.XX_Epoxyverf, belijning zebrapaden | 300 | 1500 | 11.811 | 0.45 | 0.0045 | 0.0045 | 10
BB_13.XX_Epoxyverf, belijning zebrapaden:25357810 | K20 | K20 | K.-2.P2 | BB_13.XX_Epoxyverf, belijning zebrapaden | 300 | 1500 | 11.811 | 0.45 | 0.0045 | 0.0045 | 10
BB_13.XX_Epoxyverf, belijning zebrapaden:25357819 | K20 | K20 | K.-2.P2 | BB_13.XX_Epoxyverf, belijning zebrapaden | 300 | 1500 | 11.811 | 0.45 | 0.0045 | 0.0045 | 10
BB_13.XX_Epoxyverf, belijning zebrapaden:25357828 | K20 | K20 | K.-2.P2 | BB_13.XX_Epoxyverf, belijning zebrapaden | 300 | 1500 | 11.811 | 0.45 | 0.0045 | 0.0045 | 10
BB_13.XX_Epoxyverf, belijning zebrapaden:25357837 | K20 | K20 | K.-2.P2 | BB_13.XX_Epoxyverf, belijning zebrapaden | 300 | 1500 | 11.811 | 0.45 | 0.0045 | 0.0045 | 10
BB_13.XX_Epoxyverf, belijning zebrapaden:25357846 | K20 | K20 | K.-2.P2 | BB_13.XX_Epoxyverf, belijning zebrapaden | 300 | 1500 | 11.811 | 0.45 | 0.0045 | 0.0045 | 10
BB_13.XX_Epoxyverf, belijning zebrapaden:25357855 | K20 | K20 | K.-2.P2 | BB_13.XX_Epoxyverf, belijning zebrapaden | 300 | 1500 | 11.811 | 0.45 | 0.0045 | 0.0045 | 10
BB_13.XX_Epoxyverf, belijning zebrapaden:25357900 | K20 | K20 | K.-2.P2 | BB_13.XX_Epoxyverf, belijning zebrapaden | 300 | 1500 | 11.811 | 0.45 | 0.0045 | 0.0045 | 10
BB_13.XX_Epoxyverf, belijning arcering:25358713 | K20 | K20 | K.-2.P3 | BB_13.XX_Epoxyverf, belijning arcering |  |  | 62.6897 | 0.07 |  | 0.00870538
BB_13.XX_Epoxyverf, belijning arcering:25358713:2 | K20 | K20 | K.-2.P3 | BB_13.XX_Epoxyverf, belijning arcering |  |  | 62.6897 | 0.15 |  | 0.00870538
BB_13.XX_Epoxyverf, belijning arcering:25358713:3 | K20 | K20 | K.-2.P3 | BB_13.XX_Epoxyverf, belijning arcering |  |  | 62.6897 | 0.162635 |  | 0.00870538
BB_13.XX_Epoxyverf, belijning arcering:25358713:4 | K20 | K20 | K.-2.P3 | BB_13.XX_Epoxyverf, belijning arcering |  |  | 62.6897 | 0.162635 |  | 0.00870538
BB_13.XX_Epoxyverf, belijning arcering:25358713:5 | K20 | K20 | K.-2.P3 | BB_13.XX_Epoxyverf, belijning arcering |  |  | 62.6897 | 0.162635 |  | 0.00870538
BB_13.XX_Epoxyverf, belijning arcering:25358713:6 | K20 | K20 | K.-2.P3 | BB_13.XX_Epoxyverf, belijning arcering |  |  | 62.6897 | 0.162635 |  | 0.00870538
BB_13.XX_Epoxyverf, belijning zebrapaden:25359027 | K20 | K20 | K.-2.P3 | BB_13.XX_Epoxyverf, belijning zebrapaden | 300 | 1500 | 11.811 | 0.45 | 0.0045 | 0.0045 | 10
BB_13.XX_Epoxyverf, belijning zebrapaden:25359037 | K20 | K20 | K.-2.P3 | BB_13.XX_Epoxyverf, belijning zebrapaden | 300 | 1500 | 11.811 | 0.45 | 0.0045 | 0.0045 | 10
BB_13.XX_Epoxyverf, belijning zebrapaden:25359057 | K20 | K20 | K.-2.P3 | BB_13.XX_Epoxyverf, belijning zebrapaden | 300 | 1500 | 11.811 | 0.45 | 0.0045 | 0.0045 | 10
BB_13.XX_Epoxyverf, belijning zebrapaden:25359066 | K20 | K20 | K.-2.P3 | BB_13.XX_Epoxyverf, belijning zebrapaden | 300 | 1500 | 11.811 | 0.45 | 0.0045 | 0.0045 | 10
BB_13.XX_Epoxyverf, belijning zebrapaden:25359075 | K20 | K20 | K.-2.P3 | BB_13.XX_Epoxyverf, belijning zebrapaden | 300 | 1500 | 11.811 | 0.45 | 0.0045 | 0.0045 | 10
BB_13.XX_Epoxyverf, belijning zebrapaden:25359084 | K20 | K20 | K.-2.P3 | BB_13.XX_Epoxyverf, belijning zebrapaden | 300 | 1500 | 11.811 | 0.45 | 0.0045 | 0.0045 | 10
BB_13.XX_Epoxyverf, belijning zebrapaden:25359093 | K20 | K20 | K.-2.P3 | BB_13.XX_Epoxyverf, belijning zebrapaden | 300 | 1500 | 11.811 | 0.45 | 0.0045 | 0.0045 | 10
BB_13.XX_Epoxyverf, belijning zebrapaden:25359102 | K20 | K20 | K.-2.P3 | BB_13.XX_Epoxyverf, belijning zebrapaden | 300 | 1500 | 11.811 | 0.45 | 0.0045 | 0.0045 | 10
BB_13.XX_Epoxyverf, belijning zebrapaden:25359111 | K20 | K20 | K.-2.P3 | BB_13.XX_Epoxyverf, belijning zebrapaden | 300 | 1500 | 11.811 | 0.45 | 0.0045 | 0.0045 | 10
BB_13.XX_Epoxyverf, belijning zebrapaden:25359120 | K20 | K20 | K.-2.P3 | BB_13.XX_Epoxyverf, belijning zebrapaden | 300 | 1500 | 11.811 | 0.45 | 0.0045 | 0.0045 | 10
BB_13.XX_Epoxyverf, belijning zebrapaden:25359129 | K20 | K20 | K.-2.P3 | BB_13.XX_Epoxyverf, belijning zebrapaden | 300 | 1500 | 11.811 | 0.45 | 0.0045 | 0.0045 | 10
BB_13.XX_Epoxyverf, belijning zebrapaden:25359138 | K20 | K20 | K.-2.P3 | BB_13.XX_Epoxyverf, belijning zebrapaden | 300 | 1500 | 11.811 | 0.45 | 0.0045 | 0.0045 | 10
BB_13.XX_Epoxyverf, belijning zebrapaden:25359147 | K20 | K20 | K.-2.P3 | BB_13.XX_Epoxyverf, belijning zebrapaden | 300 | 1500 | 11.811 | 0.45 | 0.0045 | 0.0045 | 10
BB_13.XX_Epoxyverf, belijning zebrapaden:25359156 | K20 | K20 | K.-2.P3 | BB_13.XX_Epoxyverf, belijning zebrapaden | 300 | 1500 | 11.811 | 0.45 | 0.0045 | 0.0045 | 10
BB_13.XX_Epoxyverf, belijning zebrapaden:25359165 | K20 | K20 | K.-2.P3 | BB_13.XX_Epoxyverf, belijning zebrapaden | 300 | 1500 | 11.811 | 0.45 | 0.0045 | 0.0045 | 10
BB_13.XX_Epoxyverf, belijning zebrapaden:25359174 | K20 | K20 | K.-2.P3 | BB_13.XX_Epoxyverf, belijning zebrapaden | 300 | 1500 | 11.811 | 0.45 | 0.0045 | 0.0045 | 10
BB_13.XX_Epoxyverf, belijning zebrapaden:25359183 | K20 | K20 | K.-2.P3 | BB_13.XX_Epoxyverf, belijning zebrapaden | 300 | 1500 | 11.811 | 0.45 | 0.0045 | 0.0045 | 10
BB_13.XX_Epoxyverf, belijning zebrapaden:25359192 | K20 | K20 | K.-2.P3 | BB_13.XX_Epoxyverf, belijning zebrapaden | 300 | 1500 | 11.811 | 0.45 | 0.0045 | 0.0045 | 10
BB_13.XX_Epoxyverf, belijning zebrapaden:25359201 | K20 | K20 | K.-2.P3 | BB_13.XX_Epoxyverf, belijning zebrapaden | 300 | 1500 | 11.811 | 0.45 | 0.0045 | 0.0045 | 10
BB_13.XX_Epoxyverf, belijning zebrapaden:25359210 | K20 | K20 | K.-2.P3 | BB_13.XX_Epoxyverf, belijning zebrapaden | 300 | 1500 | 11.811 | 0.45 | 0.0045 | 0.0045 | 10
BB_13.XX_Epoxyverf, belijning zebrapaden:25359219 | K20 | K20 | K.-2.P3 | BB_13.XX_Epoxyverf, belijning zebrapaden | 300 | 1500 | 11.811 | 0.45 | 0.0045 | 0.0045 | 10
BB_13.XX_Epoxyverf, belijning zebrapaden:25359228 | K20 | K20 | K.-2.P3 | BB_13.XX_Epoxyverf, belijning zebrapaden | 300 | 1500 | 11.811 | 0.45 | 0.0045 | 0.0045 | 10
BB_13.XX_Epoxyverf, belijning zebrapaden:25359237 | K20 | K20 | K.-2.P3 | BB_13.XX_Epoxyverf, belijning zebrapaden | 300 | 1500 | 11.811 | 0.45 | 0.0045 | 0.0045 | 10
BB_13.XX_Epoxyverf, belijning zebrapaden:25359246 | K20 | K20 | K.-2.P3 | BB_13.XX_Epoxyverf, belijning zebrapaden | 300 | 1500 | 11.811 | 0.45 | 0.0045 | 0.0045 | 10
BB_13.XX_Epoxyverf, belijning zebrapaden:25359280 | K20 | K20 | K.-2.P3 | BB_13.XX_Epoxyverf, belijning zebrapaden | 300 | 1500 | 11.811 | 0.45 | 0.0045 | 0.0045 | 10
BB_13.XX_Epoxyverf, belijning zebrapaden:25359298 | K20 | K20 | K.-2.P3 | BB_13.XX_Epoxyverf, belijning zebrapaden | 1500 | 300 | 11.811 | 0.45 | 0.0045 | 0.0045 | 10
BB_13.XX_Epoxyverf, belijning zebrapaden:25359391 | K20 | K20 | K.-2.P3 | BB_13.XX_Epoxyverf, belijning zebrapaden | 1500 | 300 | 11.811 | 0.45 | 0.0045 | 0.0045 | 10
BB_13.XX_Epoxyverf, belijning zebrapaden:25359423 | K20 | K20 | K.-2.P3 | BB_13.XX_Epoxyverf, belijning zebrapaden | 1500 | 300 | 11.811 | 0.45 | 0.0045 | 0.0045 | 10
BB_13.XX_Epoxyverf, belijning zebrapaden:25359432 | K20 | K20 | K.-2.P3 | BB_13.XX_Epoxyverf, belijning zebrapaden | 1500 | 300 | 11.811 | 0.45 | 0.0045 | 0.0045 | 10
BB_13.XX_Epoxyverf, belijning zebrapaden:25359441 | K20 | K20 | K.-2.P3 | BB_13.XX_Epoxyverf, belijning zebrapaden | 1500 | 300 | 11.811 | 0.45 | 0.0045 | 0.0045 | 10
BB_13.XX_Epoxyverf, belijning zebrapaden:25359450 | K20 | K20 | K.-2.P3 | BB_13.XX_Epoxyverf, belijning zebrapaden | 1500 | 300 | 11.811 | 0.45 | 0.0045 | 0.0045 | 10
BB_13.XX_Epoxyverf, belijning zebrapaden:25359459 | K20 | K20 | K.-2.P3 | BB_13.XX_Epoxyverf, belijning zebrapaden | 1500 | 300 | 11.811 | 0.45 | 0.0045 | 0.0045 | 10
BB_13.XX_Epoxyverf, belijning zebrapaden:25359468 | K20 | K20 | K.-2.P3 | BB_13.XX_Epoxyverf, belijning zebrapaden | 1500 | 300 | 11.811 | 0.45 | 0.0045 | 0.0045 | 10
BB_13.XX_Epoxyverf, belijning zebrapaden:25359477 | K20 | K20 | K.-2.P3 | BB_13.XX_Epoxyverf, belijning zebrapaden | 1500 | 300 | 11.811 | 0.45 | 0.0045 | 0.0045 | 10
BB_13.XX_Epoxyverf, belijning zebrapaden:25359486 | K20 | K20 | K.-2.P3 | BB_13.XX_Epoxyverf, belijning zebrapaden | 1500 | 300 | 11.811 | 0.45 | 0.0045 | 0.0045 | 10
BB_13.XX_Epoxyverf, belijning zebrapaden:25359495 | K20 | K20 | K.-2.P3 | BB_13.XX_Epoxyverf, belijning zebrapaden | 1500 | 300 | 11.811 | 0.45 | 0.0045 | 0.0045 | 10
BB_13.XX_Epoxyverf, belijning zebrapaden:25359504 | K20 | K20 | K.-2.P3 | BB_13.XX_Epoxyverf, belijning zebrapaden | 1500 | 300 | 11.811 | 0.45 | 0.0045 | 0.0045 | 10
BB_13.XX_Epoxyverf, belijning zebrapaden:25359585 | K20 | K20 | K.-2.P3 | BB_13.XX_Epoxyverf, belijning zebrapaden | 1500 | 300 | 11.811 | 0.45 | 0.0045 | 0.0045 | 10
BB_13.XX_Epoxyverf, belijning zebrapaden:25359618 | K20 | K20 | K.-2.P3 | BB_13.XX_Epoxyverf, belijning zebrapaden | 300 | 1500 | 11.811 | 0.45 | 0.0045 | 0.0045 | 10
BB_13.XX_Epoxyverf, belijning zebrapaden:25359638 | K20 | K20 | K.-2.P3 | BB_13.XX_Epoxyverf, belijning zebrapaden | 300 | 1500 | 11.811 | 0.45 | 0.0045 | 0.0045 | 10
BB_13.XX_Epoxyverf, belijning zebrapaden:25359661 | K20 | K20 | K.-2.P3 | BB_13.XX_Epoxyverf, belijning zebrapaden | 300 | 1500 | 11.811 | 0.45 | 0.0045 | 0.0045 | 10
BB_13.XX_Epoxyverf, belijning zebrapaden:25359670 | K20 | K20 | K.-2.P3 | BB_13.XX_Epoxyverf, belijning zebrapaden | 300 | 1500 | 11.811 | 0.45 | 0.0045 | 0.0045 | 10
BB_13.XX_Epoxyverf, belijning zebrapaden:25359679 | K20 | K20 | K.-2.P3 | BB_13.XX_Epoxyverf, belijning zebrapaden | 300 | 1500 | 11.811 | 0.45 | 0.0045 | 0.0045 | 10
BB_13.XX_Epoxyverf, belijning zebrapaden:25359688 | K20 | K20 | K.-2.P3 | BB_13.XX_Epoxyverf, belijning zebrapaden | 300 | 1500 | 11.811 | 0.45 | 0.0045 | 0.0045 | 10
BB_13.XX_Epoxyverf, belijning zebrapaden:25359697 | K20 | K20 | K.-2.P3 | BB_13.XX_Epoxyverf, belijning zebrapaden | 300 | 1500 | 11.811 | 0.45 | 0.0045 | 0.0045 | 10
BB_13.XX_Epoxyverf, belijning zebrapaden:25359706 | K20 | K20 | K.-2.P3 | BB_13.XX_Epoxyverf, belijning zebrapaden | 300 | 1500 | 11.811 | 0.45 | 0.0045 | 0.0045 | 10
BB_13.XX_Epoxyverf, belijning zebrapaden:25359773 | K20 | K20 | K.-2.P3 | BB_13.XX_Epoxyverf, belijning zebrapaden | 300 | 1500 | 11.811 | 0.45 | 0.0045 | 0.0045 | 10
BB_13.XX_Epoxyverf, belijning zebrapaden:25359799 | K20 | K20 | K.-2.P3 | BB_13.XX_Epoxyverf, belijning zebrapaden | 300 | 1500 | 11.811 | 0.45 | 0.0045 | 0.0045 | 10
BB_13.XX_Epoxyverf, belijning zebrapaden:25359808 | K20 | K20 | K.-2.P3 | BB_13.XX_Epoxyverf, belijning zebrapaden | 300 | 1500 | 11.811 | 0.45 | 0.0045 | 0.0045 | 10
BB_13.XX_Epoxyverf, belijning zebrapaden:25359817 | K20 | K20 | K.-2.P3 | BB_13.XX_Epoxyverf, belijning zebrapaden | 300 | 1500 | 11.811 | 0.45 | 0.0045 | 0.0045 | 10
BB_13.XX_Epoxyverf, belijning zebrapaden:25359826 | K20 | K20 | K.-2.P3 | BB_13.XX_Epoxyverf, belijning zebrapaden | 300 | 1500 | 11.811 | 0.45 | 0.0045 | 0.0045 | 10
BB_13.XX_Epoxyverf, belijning zebrapaden:25359835 | K20 | K20 | K.-2.P3 | BB_13.XX_Epoxyverf, belijning zebrapaden | 300 | 1500 | 11.811 | 0.45 | 0.0045 | 0.0045 | 10
BB_13.XX_Epoxyverf, belijning zebrapaden:25359844 | K20 | K20 | K.-2.P3 | BB_13.XX_Epoxyverf, belijning zebrapaden | 300 | 1500 | 11.811 | 0.45 | 0.0045 | 0.0045 | 10
BB_13.XX_Epoxyverf, belijning zebrapaden:25359853 | K20 | K20 | K.-2.P3 | BB_13.XX_Epoxyverf, belijning zebrapaden | 300 | 1500 | 11.811 | 0.45 | 0.0045 | 0.0045 | 10
BB_13.XX_Epoxyverf, belijning zebrapaden:25359862 | K20 | K20 | K.-2.P3 | BB_13.XX_Epoxyverf, belijning zebrapaden | 300 | 1500 | 11.811 | 0.45 | 0.0045 | 0.0045 | 10
BB_13.XX_Epoxyverf, belijning zebrapaden:25359871 | K20 | K20 | K.-2.P3 | BB_13.XX_Epoxyverf, belijning zebrapaden | 300 | 1500 | 11.811 | 0.45 | 0.0045 | 0.0045 | 10
BB_13.XX_Epoxyverf, belijning zebrapaden:25359880 | K20 | K20 | K.-2.P3 | BB_13.XX_Epoxyverf, belijning zebrapaden | 300 | 1500 | 11.811 | 0.45 | 0.0045 | 0.0045 | 10
BB_13.XX_Epoxyverf, belijning arcering:25359928 | K20 | K20 | K.-2.P3 | BB_13.XX_Epoxyverf, belijning arcering |  |  | 60.4562 | 0.07 |  | 0.00838943
BB_13.XX_Epoxyverf, belijning arcering:25359928:2 | K20 | K20 | K.-2.P3 | BB_13.XX_Epoxyverf, belijning arcering |  |  | 60.4562 | 0.146689 |  | 0.00838943
BB_13.XX_Epoxyverf, belijning arcering:25359928:3 | K20 | K20 | K.-2.P3 | BB_13.XX_Epoxyverf, belijning arcering |  |  | 60.4562 | 0.155563 |  | 0.00838943
BB_13.XX_Epoxyverf, belijning arcering:25359928:4 | K20 | K20 | K.-2.P3 | BB_13.XX_Epoxyverf, belijning arcering |  |  | 60.4562 | 0.155563 |  | 0.00838943
BB_13.XX_Epoxyverf, belijning arcering:25359928:5 | K20 | K20 | K.-2.P3 | BB_13.XX_Epoxyverf, belijning arcering |  |  | 60.4562 | 0.155563 |  | 0.00838943
BB_13.XX_Epoxyverf, belijning arcering:25359928:6 | K20 | K20 | K.-2.P3 | BB_13.XX_Epoxyverf, belijning arcering |  |  | 60.4562 | 0.155563 |  | 0.00838943
BB_13.XX_Epoxyverf, belijning zebrapaden:25370149 | K10 | K10 | K.-1.P3 | BB_13.XX_Epoxyverf, belijning zebrapaden |  |  | 11.811 | 0.33 | 0.0033 | 0.0033 | 10
BB_13.XX_Epoxyverf, belijning zebrapaden:25370157 | K10 | K10 | K.-1.P3 | BB_13.XX_Epoxyverf, belijning zebrapaden | 300 | 1500 | 11.811 | 0.45 | 0.0045 | 0.0045 | 10
BB_13.XX_Epoxyverf, belijning zebrapaden:25396680 | K10 | K10 | K.-1.P3 | BB_13.XX_Epoxyverf, belijning zebrapaden | 1500 | 300 | 11.811 | 0.45 | 0.0045 | 0.0045 | 10
BB_13.XX_Epoxyverf, belijning zebrapaden:25396700 | K10 | K10 | K.-1.P3 | BB_13.XX_Epoxyverf, belijning zebrapaden | 1500 | 300 | 11.811 | 0.45 | 0.0045 | 0.0045 | 10
BB_13.XX_Epoxyverf, belijning zebrapaden:25396710 | K10 | K10 | K.-1.P3 | BB_13.XX_Epoxyverf, belijning zebrapaden | 1500 | 300 | 11.811 | 0.45 | 0.0045 | 0.0045 | 10
BB_13.XX_Epoxyverf, belijning zebrapaden:25396720 | K10 | K10 | K.-1.P3 | BB_13.XX_Epoxyverf, belijning zebrapaden | 1500 | 300 | 11.811 | 0.45 | 0.0045 | 0.0045 | 10
BB_13.XX_Epoxyverf, belijning zebrapaden:25396730 | K10 | K10 | K.-1.P3 | BB_13.XX_Epoxyverf, belijning zebrapaden | 1500 | 300 | 11.811 | 0.45 | 0.0045 | 0.0045 | 10
BB_13.XX_Epoxyverf, belijning zebrapaden:25396740 | K10 | K10 | K.-1.P3 | BB_13.XX_Epoxyverf, belijning zebrapaden | 1500 | 300 | 11.811 | 0.45 | 0.0045 | 0.0045 | 10
BB_13.XX_Epoxyverf, belijning zebrapaden:25396750 | K10 | K10 | K.-1.P3 | BB_13.XX_Epoxyverf, belijning zebrapaden | 1500 | 300 | 11.811 | 0.45 | 0.0045 | 0.0045 | 10
BB_13.XX_Epoxyverf, belijning zebrapaden:25396760 | K10 | K10 | K.-1.P3 | BB_13.XX_Epoxyverf, belijning zebrapaden | 1500 | 300 | 11.811 | 0.45 | 0.0045 | 0.0045 | 10
BB_13.XX_Epoxyverf, belijning zebrapaden:25396770 | K10 | K10 | K.-1.P3 | BB_13.XX_Epoxyverf, belijning zebrapaden | 1500 | 300 | 11.811 | 0.45 | 0.0045 | 0.0045 | 10
BB_13.XX_Epoxyverf, belijning zebrapaden:25396780 | K10 | K10 | K.-1.P3 | BB_13.XX_Epoxyverf, belijning zebrapaden | 1500 | 300 | 11.811 | 0.45 | 0.0045 | 0.0045 | 10
BB_13.XX_Epoxyverf, belijning zebrapaden:25396790 | K10 | K10 | K.-1.P3 | BB_13.XX_Epoxyverf, belijning zebrapaden | 1500 | 300 | 11.811 | 0.45 | 0.0045 | 0.0045 | 10
BB_13.XX_Epoxyverf, belijning zebrapaden:25396800 | K10 | K10 | K.-1.P3 | BB_13.XX_Epoxyverf, belijning zebrapaden | 1500 | 300 | 11.811 | 0.45 | 0.0045 | 0.0045 | 10
BB_13.XX_Epoxyverf, belijning zebrapaden:25396833 | K10 | K10 | K.-1.P3 | BB_13.XX_Epoxyverf, belijning zebrapaden | 300 | 1500 | 11.811 | 0.45 | 0.0045 | 0.0045 | 10
BB_13.XX_Epoxyverf, belijning zebrapaden:25396850 | K10 | K10 | K.-1.P3 | BB_13.XX_Epoxyverf, belijning zebrapaden | 300 | 1500 | 11.811 | 0.45 | 0.0045 | 0.0045 | 10
BB_13.XX_Epoxyverf, belijning zebrapaden:25396859 | K10 | K10 | K.-1.P3 | BB_13.XX_Epoxyverf, belijning zebrapaden | 300 | 1500 | 11.811 | 0.45 | 0.0045 | 0.0045 | 10
BB_13.XX_Epoxyverf, belijning zebrapaden:25396868 | K10 | K10 | K.-1.P3 | BB_13.XX_Epoxyverf, belijning zebrapaden | 300 | 1500 | 11.811 | 0.45 | 0.0045 | 0.0045 | 10
BB_13.XX_Epoxyverf, belijning zebrapaden:25396877 | K10 | K10 | K.-1.P3 | BB_13.XX_Epoxyverf, belijning zebrapaden | 300 | 1500 | 11.811 | 0.45 | 0.0045 | 0.0045 | 10
BB_13.XX_Epoxyverf, belijning zebrapaden:25396886 | K10 | K10 | K.-1.P3 | BB_13.XX_Epoxyverf, belijning zebrapaden | 300 | 1500 | 11.811 | 0.45 | 0.0045 | 0.0045 | 10
BB_13.XX_Epoxyverf, belijning zebrapaden:25396895 | K10 | K10 | K.-1.P3 | BB_13.XX_Epoxyverf, belijning zebrapaden | 300 | 1500 | 11.811 | 0.45 | 0.0045 | 0.0045 | 10
BB_13.XX_Epoxyverf, belijning zebrapaden:25396928 | K10 | K10 | K.-1.P3 | BB_13.XX_Epoxyverf, belijning zebrapaden | 300 | 1500 | 11.811 | 0.45 | 0.0045 | 0.0045 | 10
BB_13.XX_Epoxyverf, belijning zebrapaden:25396939 | K10 | K10 | K.-1.P3 | BB_13.XX_Epoxyverf, belijning zebrapaden | 300 | 1500 | 11.811 | 0.45 | 0.0045 | 0.0045 | 10
BB_13.XX_Epoxyverf, belijning zebrapaden:25396965 | K10 | K10 | K.-1.P3 | BB_13.XX_Epoxyverf, belijning zebrapaden | 300 | 1500 | 11.811 | 0.45 | 0.0045 | 0.0045 | 10
BB_13.XX_Epoxyverf, belijning zebrapaden:25396974 | K10 | K10 | K.-1.P3 | BB_13.XX_Epoxyverf, belijning zebrapaden |  |  | 11.811 | 0.442306 | 0.00442306 | 0.00442306 | 10
BB_13.XX_Epoxyverf, belijning zebrapaden:25396983 | K10 | K10 | K.-1.P3 | BB_13.XX_Epoxyverf, belijning zebrapaden | 300 | 1500 | 11.811 | 0.45 | 0.0045 | 0.0045 | 10
BB_13.XX_Epoxyverf, belijning zebrapaden:25396992 | K10 | K10 | K.-1.P3 | BB_13.XX_Epoxyverf, belijning zebrapaden | 300 | 1500 | 11.811 | 0.45 | 0.0045 | 0.0045 | 10
BB_13.XX_Epoxyverf, belijning zebrapaden:25397001 | K10 | K10 | K.-1.P3 | BB_13.XX_Epoxyverf, belijning zebrapaden | 300 | 1500 | 11.811 | 0.45 | 0.0045 | 0.0045 | 10
BB_13.XX_Epoxyverf, belijning zebrapaden:25397010 | K10 | K10 | K.-1.P3 | BB_13.XX_Epoxyverf, belijning zebrapaden | 300 | 1500 | 11.811 | 0.45 | 0.0045 | 0.0045 | 10
BB_13.XX_Epoxyverf, belijning zebrapaden:25397019 | K10 | K10 | K.-1.P3 | BB_13.XX_Epoxyverf, belijning zebrapaden | 300 | 1500 | 11.811 | 0.45 | 0.0045 | 0.0045 | 10
BB_13.XX_Epoxyverf, belijning zebrapaden:25397028 | K10 | K10 | K.-1.P3 | BB_13.XX_Epoxyverf, belijning zebrapaden | 300 | 1500 | 11.811 | 0.45 | 0.0045 | 0.0045 | 10
BB_13.XX_Epoxyverf, belijning zebrapaden:25397037 | K10 | K10 | K.-1.P3 | BB_13.XX_Epoxyverf, belijning zebrapaden | 300 | 1500 | 11.811 | 0.45 | 0.0045 | 0.0045 | 10
BB_13.XX_Epoxyverf, belijning zebrapaden:25397046 | K10 | K10 | K.-1.P3 | BB_13.XX_Epoxyverf, belijning zebrapaden | 300 | 1500 | 11.811 | 0.45 | 0.0045 | 0.0045 | 10
BB_13.XX_Epoxyverf, belijning arcering:25397290 | K10 | K10 | K.-1.P3 | BB_13.XX_Epoxyverf, belijning arcering |  |  | 158.856 | 0.07 |  | 0.0229368
BB_13.XX_Epoxyverf, belijning arcering:25397290:2 | K10 | K10 | K.-1.P3 | BB_13.XX_Epoxyverf, belijning arcering |  |  | 158.856 | 0.15 |  | 0.0229368
BB_13.XX_Epoxyverf, belijning arcering:25397290:3 | K10 | K10 | K.-1.P3 | BB_13.XX_Epoxyverf, belijning arcering |  |  | 158.856 | 0.23 |  | 0.0229368
BB_13.XX_Epoxyverf, belijning arcering:25397290:4 | K10 | K10 | K.-1.P3 | BB_13.XX_Epoxyverf, belijning arcering |  |  | 158.856 | 0.31 |  | 0.0229368
BB_13.XX_Epoxyverf, belijning arcering:25397290:5 | K10 | K10 | K.-1.P3 | BB_13.XX_Epoxyverf, belijning arcering |  |  | 158.856 | 0.33234 |  | 0.0229368
BB_13.XX_Epoxyverf, belijning arcering:25397290:6 | K10 | K10 | K.-1.P3 | BB_13.XX_Epoxyverf, belijning arcering |  |  | 158.856 | 0.33234 |  | 0.0229368
BB_13.XX_Epoxyverf, belijning arcering:25397290:7 | K10 | K10 | K.-1.P3 | BB_13.XX_Epoxyverf, belijning arcering |  |  | 158.856 | 0.33234 |  | 0.0229368
BB_13.XX_Epoxyverf, belijning arcering:25397290:8 | K10 | K10 | K.-1.P3 | BB_13.XX_Epoxyverf, belijning arcering |  |  | 158.856 | 0.308331 |  | 0.0229368
BB_13.XX_Epoxyverf, belijning arcering:25397290:9 | K10 | K10 | K.-1.P3 | BB_13.XX_Epoxyverf, belijning arcering |  |  | 158.856 | 0.228331 |  | 0.0229368
BB_13.XX_Epoxyverf, belijning arcering:25397885 | K10 | K10 | K.-1.P3 | BB_13.XX_Epoxyverf, belijning arcering |  |  | 148.117 | 0.548331 |  | 0.0215831
BB_13.XX_Epoxyverf, belijning arcering:25397885:2 | K10 | K10 | K.-1.P3 | BB_13.XX_Epoxyverf, belijning arcering |  |  | 148.117 | 0.468331 |  | 0.0215831
BB_13.XX_Epoxyverf, belijning arcering:25397885:3 | K10 | K10 | K.-1.P3 | BB_13.XX_Epoxyverf, belijning arcering |  |  | 148.117 | 0.388331 |  | 0.0215831
BB_13.XX_Epoxyverf, belijning arcering:25397885:4 | K10 | K10 | K.-1.P3 | BB_13.XX_Epoxyverf, belijning arcering |  |  | 148.117 | 0.308331 |  | 0.0215831
BB_13.XX_Epoxyverf, belijning arcering:25397885:5 | K10 | K10 | K.-1.P3 | BB_13.XX_Epoxyverf, belijning arcering |  |  | 148.117 | 0.228331 |  | 0.0215831
BB_13.XX_Epoxyverf, belijning arcering:25397885:6 | K10 | K10 | K.-1.P3 | BB_13.XX_Epoxyverf, belijning arcering |  |  | 148.117 | 0.148331 |  | 0.0215831
BB_13.XX_Epoxyverf, belijning arcering:25397885:7 | K10 | K10 | K.-1.P3 | BB_13.XX_Epoxyverf, belijning arcering |  |  | 148.117 | 0.0683307 |  | 0.0215831

# IfcSlab: BB_Beton_Bestaand 150 (25)
Type - PredefinedType: FLOOR; Material: BB_Beton_Bestaand
Cpset_Slab - LevelOfAccuracy: in te vullen door Buildwise
IfcRoot - Name: BB_XX_Vloer uit beton, 150 mm
Pset_Condition - AssessmentCondition: Empty
Pset_EnvironmentalImpactIndicators - Reference: BB_XX_Vloer uit beton, 150 mm; sets with these values: 2
Pset_SlabCommon - Reference: BB_XX_Vloer uit beton, 150 mm; PitchAngle: 0 rad; IsExternal: no
Name (Floor:BB_XX_Vloer uit beton, 150 mm:...) | In | Level | Height Offset From Level | GVH_artnr 01 = GVH_artnr 02 = GVH_artnr 03 = GVH_artnr 04 = GVH_artnr 05 = GVH_artnr 06 | Perimeter | GrossArea | GrossVolume | NetVolume | Depth | LoadBearing | Width | Length
1004045 | K10 | K10 | 0 | geen waarde gevonden | 53.1496 | 13.82 | 2.073 | 2.073 | 150 | no
1004871 | K10 | K10 | 0 | geen waarde gevonden | 27.5591 | 3.6 | 0.54 | 0.54 | 150 | no | 1200 | 3000
1012788 | K10 | K10 | 0 | geen waarde gevonden | 46.588 | 9.88001 | 1.482 | 1.482 | 150 | no | 5200 | 1900
1589873 | K10 | K10 | -100 | geen waarde gevonden | 39.3701 | 7.79001 | 1.1685 | 1.1685 | 150 | no | 1900 | 4100
8729358 | K10 | K10 | 0 | geen waarde gevonden | 19.4465 | 1.50697 | 0.226045 | 0.226045 | 150 | no
34151977 | K10 | K10 | -200 |  | 20.4703 | 1.81872 | 0.272807 | 0.272807 | 150 | yes | IfcClassificationReference - TDS_link: .\05 As Builtdossier\2. Bouwkunde\2.2. Stabiliteit\2.2.0 technische fiche's\TF S 4.3 A-beton.pdf; TDS_link_extra_1: .\05 As Builtdossier\2. Bouwkunde\2.2. Stabiliteit\2.2.0 technische fiche's\TF S 4.3.2.1 A-wapeningsstaal.pdf; Pset_ConcreteElementGeneral - ConstructionMethod: on-site; Pset_SlabCommon - FireRating: REI 60
808249 | 000 | 000 | -660 | geen waarde gevonden | 53.9042 | 8.47605 | 1.27141 | 1.27141 | 150 | no | 7005 | 1210
892078 | 000 | 000 | -200 | geen waarde gevonden | 15.4794 | 0.954836 | 0.143225 | 0.143225 | 150 | no
905248 | 000 | 000 | -200 | geen waarde gevonden | 16.5996 | 1.09803 | 0.164704 | 0.164704 | 150 | no
34152560 | 000 | 000 | -200 |  | 16.6063 | 0.873085 | 0.130963 | 0.130963 | 150 | yes | IfcClassificationReference - TDS_link: .\05 As Builtdossier\2. Bouwkunde\2.2. Stabiliteit\2.2.0 technische fiche's\TF S 4.3 A-beton.pdf; TDS_link_extra_1: .\05 As Builtdossier\2. Bouwkunde\2.2. Stabiliteit\2.2.0 technische fiche's\TF S 4.3.2.1 A-wapeningsstaal.pdf; Pset_ConcreteElementGeneral - ConstructionMethod: on-site; Pset_SlabCommon - FireRating: REI 60
34123439 | 010 | 010 | -200 |  | 28.1399 | 4.59766 | 0.689649 | 0.689649 | 150 | yes | 2130 | 2158.53 | IfcClassificationReference - TDS_link: .\05 As Builtdossier\2. Bouwkunde\2.2. Stabiliteit\2.2.0 technische fiche's\TF S 4.3 A-beton.pdf; TDS_link_extra_1: .\05 As Builtdossier\2. Bouwkunde\2.2. Stabiliteit\2.2.0 technische fiche's\TF S 4.3.2.1 A-wapeningsstaal.pdf; Pset_ConcreteElementGeneral - ConstructionMethod: on-site; Pset_SlabCommon - FireRating: REI 60
34126129 | 010 | 010 | -200 |  | 28.1399 | 4.59766 | 0.689649 | 0.689649 | 150 | yes | 2130 | 2158.53 | IfcClassificationReference - TDS_link: .\05 As Builtdossier\2. Bouwkunde\2.2. Stabiliteit\2.2.0 technische fiche's\TF S 4.3 A-beton.pdf; TDS_link_extra_1: .\05 As Builtdossier\2. Bouwkunde\2.2. Stabiliteit\2.2.0 technische fiche's\TF S 4.3.2.1 A-wapeningsstaal.pdf; Pset_ConcreteElementGeneral - ConstructionMethod: on-site; Pset_SlabCommon - FireRating: REI 60
34152459 | 010 | 010 | -200 |  | 21.6057 | 2.02706 | 0.304059 | 0.304059 | 150 | yes | IfcClassificationReference - TDS_link: .\05 As Builtdossier\2. Bouwkunde\2.2. Stabiliteit\2.2.0 technische fiche's\TF S 4.3 A-beton.pdf; TDS_link_extra_1: .\05 As Builtdossier\2. Bouwkunde\2.2. Stabiliteit\2.2.0 technische fiche's\TF S 4.3.2.1 A-wapeningsstaal.pdf; Pset_ConcreteElementGeneral - ConstructionMethod: on-site; Pset_SlabCommon - FireRating: REI 60
34125947 | 020 | 020 | -200 |  | 28.1399 | 4.59766 | 0.689649 | 0.689649 | 150 | yes | 2130 | 2158.53 | IfcClassificationReference - TDS_link: .\05 As Builtdossier\2. Bouwkunde\2.2. Stabiliteit\2.2.0 technische fiche's\TF S 4.3 A-beton.pdf; TDS_link_extra_1: .\05 As Builtdossier\2. Bouwkunde\2.2. Stabiliteit\2.2.0 technische fiche's\TF S 4.3.2.1 A-wapeningsstaal.pdf; Pset_ConcreteElementGeneral - ConstructionMethod: on-site; Pset_SlabCommon - FireRating: REI 60
34126171 | 020 | 020 | -200 |  | 28.1399 | 4.59766 | 0.689649 | 0.689649 | 150 | yes | 2130 | 2158.53 | IfcClassificationReference - TDS_link: .\05 As Builtdossier\2. Bouwkunde\2.2. Stabiliteit\2.2.0 technische fiche's\TF S 4.3 A-beton.pdf; TDS_link_extra_1: .\05 As Builtdossier\2. Bouwkunde\2.2. Stabiliteit\2.2.0 technische fiche's\TF S 4.3.2.1 A-wapeningsstaal.pdf; Pset_ConcreteElementGeneral - ConstructionMethod: on-site; Pset_SlabCommon - FireRating: REI 60
34152474 | 020 | 020 | -200 |  | 21.6013 | 2.02623 | 0.303935 | 0.303935 | 150 | yes | IfcClassificationReference - TDS_link: .\05 As Builtdossier\2. Bouwkunde\2.2. Stabiliteit\2.2.0 technische fiche's\TF S 4.3 A-beton.pdf; TDS_link_extra_1: .\05 As Builtdossier\2. Bouwkunde\2.2. Stabiliteit\2.2.0 technische fiche's\TF S 4.3.2.1 A-wapeningsstaal.pdf; Pset_ConcreteElementGeneral - ConstructionMethod: on-site; Pset_SlabCommon - FireRating: REI 60
710497 | 030 | 030 | -200 | geen waarde gevonden | 47.3097 | 3.355 | 0.50325 | 0.50325 | 150 | no | 6710 | 500
714246 | 030 | 030 | -200 | geen waarde gevonden | 47.2441 | 10.07 | 1.5105 | 1.5105 | 150 | no | 5300 | 1900
34125977 | 030 | 030 | -200 |  | 28.1399 | 4.59766 | 0.689649 | 0.689649 | 150 | yes | 2130 | 2158.53 | IfcClassificationReference - TDS_link: .\05 As Builtdossier\2. Bouwkunde\2.2. Stabiliteit\2.2.0 technische fiche's\TF S 4.3 A-beton.pdf; TDS_link_extra_1: .\05 As Builtdossier\2. Bouwkunde\2.2. Stabiliteit\2.2.0 technische fiche's\TF S 4.3.2.1 A-wapeningsstaal.pdf; Pset_ConcreteElementGeneral - ConstructionMethod: on-site; Pset_SlabCommon - FireRating: REI 60
34126202 | 030 | 030 | -200 |  | 28.1399 | 4.59766 | 0.689649 | 0.689649 | 150 | yes | 2130 | 2158.53 | IfcClassificationReference - TDS_link: .\05 As Builtdossier\2. Bouwkunde\2.2. Stabiliteit\2.2.0 technische fiche's\TF S 4.3 A-beton.pdf; TDS_link_extra_1: .\05 As Builtdossier\2. Bouwkunde\2.2. Stabiliteit\2.2.0 technische fiche's\TF S 4.3.2.1 A-wapeningsstaal.pdf; Pset_ConcreteElementGeneral - ConstructionMethod: on-site; Pset_SlabCommon - FireRating: REI 60
34152489 | 030 | 030 | -200 |  | 21.6083 | 2.02742 | 0.304113 | 0.304113 | 150 | yes | IfcClassificationReference - TDS_link: .\05 As Builtdossier\2. Bouwkunde\2.2. Stabiliteit\2.2.0 technische fiche's\TF S 4.3 A-beton.pdf; TDS_link_extra_1: .\05 As Builtdossier\2. Bouwkunde\2.2. Stabiliteit\2.2.0 technische fiche's\TF S 4.3.2.1 A-wapeningsstaal.pdf; Pset_ConcreteElementGeneral - ConstructionMethod: on-site; Pset_SlabCommon - FireRating: REI 60
770426 | 040 | 040 | -200 | geen waarde gevonden | 60.3347 |  |  | 1.35908 |  | no
770536 | 040 | 040 | -200 | geen waarde gevonden | 107.735 | 22.4965 | 3.37447 | 3.37447 | 150 | no
772728 | 040 | 040 | -200 | geen waarde gevonden | 55.0978 | 12.9393 | 1.94089 | 1.94089 | 150 | no
772883 | 040 | 040 | -200 | geen waarde gevonden | 47.2441 | 10.07 | 1.5105 | 1.5105 | 150 | no | 5300 | 1900

# IfcSlab: BB_Beton_Bestaand 200 (62)
Type - PredefinedType: FLOOR; Material: BB_Beton_Bestaand
Cpset_Slab - LevelOfAccuracy: in te vullen door Buildwise
Pset_Condition - AssessmentCondition: Empty
Pset_EnvironmentalImpactIndicators - sets with these values: 2
Pset_SlabCommon - IsExternal: no
Name (Floor:...) | In | Level | Height Offset From Level | GVH_artnr 01 = GVH_artnr 02 = GVH_artnr 03 = GVH_artnr 04 = GVH_artnr 05 = GVH_artnr 06 | Name = Pset_EnvironmentalImpactIndicators, Reference = Pset_SlabCommon, Reference | Perimeter | NetVolume | PitchAngle (rad) | LoadBearing | GrossArea | GrossVolume | Depth
BB_XX_Vloer uit beton, 200 mm:1028211 | K20 | K20 | 0 | geen waarde gevonden | BB_XX_Vloer uit beton, 200 mm | 773.12 | 508.118 | 0 | no
BB_XX_Vloer welfsels, 200 mm:1488219 | K20 | K20 | 0 | geen waarde gevonden | BB_XX_Vloer welfsels, 200 mm | 48.0876 | 0.630883 | 0 | no | 3.15442 | 0.630883 | 200 | Qto_SlabBaseQuantities - Width: 459.202; Length: 6869.34
BB_XX_Vloer uit beton, 200 mm:969614 | K10 | K10 | -100 | geen waarde gevonden | BB_XX_Vloer uit beton, 200 mm | 238.156 | 41.2891 | 0 | no | 206.446 | 41.2891 | 200
BB_XX_Vloer uit beton, 200 mm:984384 | K10 | K10 | 0 | geen waarde gevonden | BB_XX_Vloer uit beton, 200 mm | 76.2139 | 6.6716 | 0 | no | 33.358 | 6.6716 | 200 | Qto_SlabBaseQuantities - Width: 5200; Length: 6415
BB_XX_Vloer welfsels, 200 mm:990061 | K10 | K10 | 0 | geen waarde gevonden | BB_XX_Vloer welfsels, 200 mm | 15.2557 | 0.185487 | 0 | no | 0.927434 | 0.185487 | 200
BB_XX_Vloer uit beton, 200 mm:997879 | K10 | K10 | 0 | geen waarde gevonden | BB_XX_Vloer uit beton, 200 mm | 22.1317 | 0.387144 | 0 | no | 1.93572 | 0.387144 | 200
BB_XX_Vloer uit beton, 200 mm:997946 | K10 | K10 | 0 | geen waarde gevonden | BB_XX_Vloer uit beton, 200 mm | 15.1531 | 0.22017 | 0 | no | 1.10085 | 0.22017 | 200
BB_XX_Vloer uit beton, 200 mm:1002922 | K10 | K10 | 0 | geen waarde gevonden | BB_XX_Vloer uit beton, 200 mm | 54.1342 | 3.45142 | 0 | no | 17.2571 | 3.45142 | 200
BB_XX_Vloer uit beton, 200 mm:1005090 | K10 | K10 | -100 | geen waarde gevonden | BB_XX_Vloer uit beton, 200 mm | 70.9318 | 5.3301 | 0 | no | 26.6505 | 5.3301 | 200
BB_XX_Vloer uit beton, 200 mm:1012654 | K10 | K10 | 0 | geen waarde gevonden | BB_XX_Vloer uit beton, 200 mm | 68.2415 | 5.408 | 0 | no | 27.04 | 5.408 | 200 | Qto_SlabBaseQuantities - Width: 5200; Length: 5200
BB_XX_Vloer welfsels, 200 mm:1018930 | K10 | K10 | 0 | geen waarde gevonden | BB_XX_Vloer welfsels, 200 mm | 207.348 | 18.1498 | 0 | yes | 90.749 | 18.1498 | 200 | Qto_SlabBaseQuantities - Width: 3194.83; Length: 28405
BB_XX_Vloer uit beton, 200 mm:1369997 | K10 | K10 | -200 | geen waarde gevonden | BB_XX_Vloer uit beton, 200 mm | 34.3832 | 1.3188 | 0 | no | 6.594 | 1.3188 | 200 | Qto_SlabBaseQuantities - Width: 2100; Length: 3140
BB_XX_Vloer welfsels, 200 mm:1588937 | K10 | K10 | 0 | geen waarde gevonden | BB_XX_Vloer welfsels, 200 mm | 16.4041 | 0.297918 | 0 | no | 1.48959 | 0.297918 | 200 | Qto_SlabBaseQuantities - Width: 980; Length: 1519.99
BB_XX_Vloer uit beton, 200 mm:33727084 | K10 | K10 | 1490 |  | BB_XX_Vloer uit beton, 200 mm | 26.5723 | 0.804827 | 0 | yes | 4.02414 | 0.804827 | 200 | Qto_SlabBaseQuantities - Width: 2300; Length: 1749.62; IfcClassificationReference - TDS_link: .\05 As Builtdossier\2. Bouwkunde\2.2. Stabiliteit\2.2.0 technische fiche's\TF S 4.3 A-beton.pdf; TDS_link_extra_1: .\05 As Builtdossier\2. Bouwkunde\2.2. Stabiliteit\2.2.0 technische fiche's\TF S 4.3.2.1 A-wapeningsstaal.pdf; Pset_ConcreteElementGeneral - ConstructionMethod: on-site; Pset_SlabCommon - FireRating: REI 60
BB_XX_Vloer uit beton, 200 mm:33733301 | K10 | K10 | 2790 |  | BB_XX_Vloer uit beton, 200 mm | 18.0447 | 0.350006 | 0 | yes | 1.75003 | 0.350006 | 200 | Qto_SlabBaseQuantities - Width: 1750; Length: 1000.02; IfcClassificationReference - TDS_link: .\05 As Builtdossier\2. Bouwkunde\2.2. Stabiliteit\2.2.0 technische fiche's\TF S 4.3 A-beton.pdf; TDS_link_extra_1: .\05 As Builtdossier\2. Bouwkunde\2.2. Stabiliteit\2.2.0 technische fiche's\TF S 4.3.2.1 A-wapeningsstaal.pdf; Pset_ConcreteElementGeneral - ConstructionMethod: on-site; Pset_SlabCommon - FireRating: REI 60
BB_XX_Vloer uit beton, 200 mm:675338 | 000 | 000 | -80 | geen waarde gevonden | BB_XX_Vloer uit beton, 200 mm | 73.8189 | 4.9061 | 0 | no | 24.5305 | 4.9061 | 200
BB_XX_Vloer uit beton, 200 mm:844817 | 000 | 000 | -80 | geen waarde gevonden | BB_XX_Vloer uit beton, 200 mm | 73.8189 | 4.8261 | 0 | no | 24.1305 | 4.8261 | 200
BB_XX_Vloer uit beton, 200 mm:898014 | 000 | 000 | -80 | geen waarde gevonden | BB_XX_Vloer uit beton, 200 mm | 76.3451 | 5.96643 | 0 | no | 29.8321 | 5.96643 | 200
BB_XX_Vloer welfsels, 200 mm:938664 | 000 | 000 | 0 | geen waarde gevonden | BB_XX_Vloer welfsels, 200 mm | 191.633 | 17.6374 | 0.0188915 | no | 88.1713
BB_XX_Vloer uit beton, 200 mm:943234 | 000 | 000 | -80 | geen waarde gevonden | BB_XX_Vloer uit beton, 200 mm | 53.2152 | 2.7698 | 0 | no | 13.849 | 2.7698 | 200
BB_XX_Vloer uit beton, 200 mm:944112 | 000 | 000 | -100 | geen waarde gevonden | BB_XX_Vloer uit beton, 200 mm | 54.1342 | 3.45142 | 0 | no | 17.2571 | 3.45142 | 200
BB_XX_Vloer uit beton, 200 mm:1203152 | 000 | 000 | -50 | geen waarde gevonden | BB_XX_Vloer uit beton, 200 mm | 28.3793 | 0.8724 | 0 | no | 4.362 | 0.8724 | 200
BB_XX_Vloer uit beton, 200 mm:1369965 | 000 | 000 | -200 | geen waarde gevonden | BB_XX_Vloer uit beton, 200 mm | 34.3832 | 1.3188 | 0 | no | 6.594 | 1.3188 | 200 | Qto_SlabBaseQuantities - Width: 2100; Length: 3140
BB_XX_Vloer uit beton, 200 mm:682226 | 010 | 010 | -80 | geen waarde gevonden | BB_XX_Vloer uit beton, 200 mm | 75.1313 | 5.0341 | 0 | no | 25.1705 | 5.0341 | 200
BB_XX_Vloer uit beton, 200 mm:687117 | 010 | 010 | -80 | geen waarde gevonden | BB_XX_Vloer uit beton, 200 mm | 67.0092 | 5.69251 | 0 | no | 28.4625 | 5.69251 | 200
BB_XX_Vloer uit beton, 200 mm:687675 | 010 | 010 | -80 | geen waarde gevonden | BB_XX_Vloer uit beton, 200 mm | 70.4813 | 5.05344 | 0 | no | 25.2672 | 5.05344 | 200
BB_XX_Vloer uit beton, 200 mm:688364 | 010 | 010 | -80 | geen waarde gevonden | BB_XX_Vloer uit beton, 200 mm | 55.005 | 2.57965 | 0 | no | 12.8983 | 2.57965 | 200
BB_XX_Vloer uit beton, 200 mm:1212190 | 010 | 010 | -200 | geen waarde gevonden | BB_XX_Vloer uit beton, 200 mm | 47.2441 | 2.014 | 0 | no | 10.07 | 2.014 | 200 | Qto_SlabBaseQuantities - Width: 5300; Length: 1900
BB_XX_Vloer uit beton, 200 mm:1369948 | 010 | 010 | -200 | geen waarde gevonden | BB_XX_Vloer uit beton, 200 mm | 34.3832 | 1.3188 | 0 | no | 6.594 | 1.3188 | 200 | Qto_SlabBaseQuantities - Width: 2100; Length: 3140
BB_XX_Vloer uit beton, 200 mm:13217342 | 010 | 010 | -80 | geen waarde gevonden | BB_XX_Vloer uit beton, 200 mm | 94.9908 | 4.92339 | 0 | no | 24.617 | 4.92339 | 200
BB_XX_Vloer uit beton, 200 mm:34080992 | 010 | 010 | -80 | geen waarde gevonden | BB_XX_Vloer uit beton, 200 mm | 24.7012 | 0.65509 | 0 | yes | 3.27545 | 0.65509 | 200 | IfcClassificationReference - TDS_link: .\05 As Builtdossier\2. Bouwkunde\2.2. Stabiliteit\2.2.0 technische fiche's\TF S 4.3 A-beton.pdf; TDS_link_extra_1: .\05 As Builtdossier\2. Bouwkunde\2.2. Stabiliteit\2.2.0 technische fiche's\TF S 4.3.2.1 A-wapeningsstaal.pdf; Pset_ConcreteElementGeneral - ConstructionMethod: on-site; Pset_SlabCommon - FireRating: REI 60
BB_XX_Vloer uit beton, 200 mm:706992 | 020 | 020 | -80 | geen waarde gevonden | BB_XX_Vloer uit beton, 200 mm | 75.1313 | 5.0341 | 0 | no | 25.1705 | 5.0341 | 200
BB_XX_Vloer uit beton, 200 mm:708465 | 020 | 020 | -80 | geen waarde gevonden | BB_XX_Vloer uit beton, 200 mm | 75.1313 | 5.0341 | 0 | no | 25.1705 | 5.0341 | 200
BB_XX_Vloer uit beton, 200 mm:708717 | 020 | 020 | -80 | geen waarde gevonden | BB_XX_Vloer uit beton, 200 mm | 70.4813 | 5.05344 | 0 | no | 25.2672 | 5.05344 | 200
BB_XX_Vloer uit beton, 200 mm:708818 | 020 | 020 | -80 | geen waarde gevonden | BB_XX_Vloer uit beton, 200 mm | 55.005 | 2.57965 | 0 | no | 12.8983 | 2.57965 | 200
BB_XX_Vloer uit beton, 200 mm:1212348 | 020 | 020 | -200 | geen waarde gevonden | BB_XX_Vloer uit beton, 200 mm | 47.2441 | 2.014 | 0 | no | 10.07 | 2.014 | 200 | Qto_SlabBaseQuantities - Width: 5300; Length: 1900
BB_XX_Vloer uit beton, 200 mm:1369932 | 020 | 020 | -200 | geen waarde gevonden | BB_XX_Vloer uit beton, 200 mm | 34.3832 | 1.3188 | 0 | no | 6.594 | 1.3188 | 200 | Qto_SlabBaseQuantities - Width: 2100; Length: 3140
BB_XX_Vloer uit beton, 200 mm:1370102 | 020 | 020 | -200 | geen waarde gevonden | BB_XX_Vloer uit beton, 200 mm | 34.3832 | 1.3188 | 0 | no | 6.594 | 1.3188 | 200 | Qto_SlabBaseQuantities - Width: 2100; Length: 3140
BB_XX_Vloer uit beton, 200 mm:34072195 | 020 | 020 | -200 |  | BB_XX_Vloer uit beton, 200 mm | 61.4173 | 1.68318 | 0 | yes | 4.21039 | IfcClassificationReference - TDS_link: .\05 As Builtdossier\2. Bouwkunde\2.2. Stabiliteit\2.2.0 technische fiche's\TF S 4.3 A-beton.pdf; TDS_link_extra_1: .\05 As Builtdossier\2. Bouwkunde\2.2. Stabiliteit\2.2.0 technische fiche's\TF S 4.3.2.1 A-wapeningsstaal.pdf; Pset_ConcreteElementGeneral - ConstructionMethod: on-site; Pset_SlabCommon - FireRating: REI 60
BB_XX_Vloer uit beton, 200 mm:34072195:2 | 020 | 020 | -200 |  | BB_XX_Vloer uit beton, 200 mm | 61.4173 | 1.68318 | 0 | yes | 4.20551 | IfcClassificationReference - TDS_link: .\05 As Builtdossier\2. Bouwkunde\2.2. Stabiliteit\2.2.0 technische fiche's\TF S 4.3 A-beton.pdf; TDS_link_extra_1: .\05 As Builtdossier\2. Bouwkunde\2.2. Stabiliteit\2.2.0 technische fiche's\TF S 4.3.2.1 A-wapeningsstaal.pdf; Pset_ConcreteElementGeneral - ConstructionMethod: on-site; Pset_SlabCommon - FireRating: REI 60
BB_XX_Vloer uit beton, 200 mm:713985 | 030 | 030 | -80 | geen waarde gevonden | BB_XX_Vloer uit beton, 200 mm | 55.005 | 2.57965 | 0 | no | 12.8983 | 2.57965 | 200
BB_XX_Vloer uit beton, 200 mm:714033 | 030 | 030 | -80 | geen waarde gevonden | BB_XX_Vloer uit beton, 200 mm | 70.4813 | 5.05344 | 0 | no | 25.2672 | 5.05344 | 200
BB_XX_Vloer uit beton, 200 mm:714178 | 030 | 030 | -80 | geen waarde gevonden | BB_XX_Vloer uit beton, 200 mm | 71.7192 | 5.05524 | 0 | no | 25.2762 | 5.05524 | 200
BB_XX_Vloer uit beton, 200 mm:714210 | 030 | 030 | -80 | geen waarde gevonden | BB_XX_Vloer uit beton, 200 mm | 71.7192 | 5.0776 | 0 | no | 25.388 | 5.0776 | 200
BB_XX_Vloer uit beton, 200 mm:714491 | 030 | 030 | -200 | geen waarde gevonden | BB_XX_Vloer uit beton, 200 mm | 54.5066 | 1.48281 | 0 | no | 7.41404 | 1.48281 | 200
BB_XX_Vloer uit beton, 200 mm:714941 | 030 | 030 | -200 | geen waarde gevonden | BB_XX_Vloer uit beton, 200 mm | 29.7638 | 0.706033 | 0 | no | 3.53016 | 0.706033 | 200
BB_XX_Vloer uit beton, 200 mm:714961 | 030 | 030 | -200 | geen waarde gevonden | BB_XX_Vloer uit beton, 200 mm | 29.7638 | 0.706033 | 0 | no | 3.53016 | 0.706033 | 200
BB_XX_Vloer uit beton, 200 mm:1369916 | 030 | 030 | -200 | geen waarde gevonden | BB_XX_Vloer uit beton, 200 mm | 34.3832 | 1.3188 | 0 | no | 6.594 | 1.3188 | 200 | Qto_SlabBaseQuantities - Width: 2100; Length: 3140
BB_XX_Vloer uit beton, 200 mm:770653 | 040 | 040 | 200 | geen waarde gevonden | BB_XX_Vloer uit beton, 200 mm | 34.3832 | 1.3188 | 0 | no | 6.594 | 1.3188 | 200 | Qto_SlabBaseQuantities - Width: 3140; Length: 2100
BB_XX_Vloer uit beton, 200 mm:772744 | 040 | 040 | -200 | geen waarde gevonden | BB_XX_Vloer uit beton, 200 mm | 15.3202 | 0.187059 | 0 | no | 0.935296 | 0.187059 | 200
BB_XX_Vloer welfsels, 200 mm:772781 | 040 | 040 | -200 | geen waarde gevonden | BB_XX_Vloer welfsels, 200 mm | 67.9261 | 5.8421 | 0 | no | 29.2105 | 5.8421 | 200
BB_XX_Vloer uit beton, 200 mm:772825 | 040 | 040 | -200 | geen waarde gevonden | BB_XX_Vloer uit beton, 200 mm | 78.4481 | 5.46724 | 0 | no | 27.3362 | 5.46724 | 200
BB_XX_Vloer uit beton, 200 mm:787710 | 040 | 040 | 200 | geen waarde gevonden | BB_XX_Vloer uit beton, 200 mm | 26.378 | 0.80602 | 0 | no | 4.0301 | 0.80602 | 200 | Qto_SlabBaseQuantities - Width: 1910; Length: 2110
BB_XX_Vloer uit beton, 200 mm:788004 | 040 | 040 | 200 | geen waarde gevonden | BB_XX_Vloer uit beton, 200 mm | 26.3123 | 0.8018 | 0 | no | 4.009 | 0.8018 | 200 | Qto_SlabBaseQuantities - Width: 2110; Length: 1900
BB_XX_Vloer uit beton, 200 mm:1032711 | 040 | 040 | -200 | geen waarde gevonden | BB_XX_Vloer uit beton, 200 mm | 34.3832 | 1.3188 | 0 | no | 6.594 | 1.3188 | 200 | Qto_SlabBaseQuantities - Width: 2100; Length: 3140
BB_XX_Vloer uit beton, 200 mm:1349588 | 040 | 040 | -200 | geen waarde gevonden | BB_XX_Vloer uit beton, 200 mm | 15.2943 | 0.186427 | 0 | no | 0.932134 | 0.186427 | 200
BB_XX_Vloer uit beton, 200 mm:34100773 | 040 | 040 | -200 | geen waarde gevonden | BB_XX_Vloer uit beton, 200 mm | 67.5472 | 2.13513 | 0 | yes | IfcClassificationReference - TDS_link: .\05 As Builtdossier\2. Bouwkunde\2.2. Stabiliteit\2.2.0 technische fiche's\TF S 4.3 A-beton.pdf; TDS_link_extra_1: .\05 As Builtdossier\2. Bouwkunde\2.2. Stabiliteit\2.2.0 technische fiche's\TF S 4.3.2.1 A-wapeningsstaal.pdf; Pset_ConcreteElementGeneral - ConstructionMethod: on-site; Pset_SlabCommon - FireRating: REI 60
BB_XX_Vloer uit beton, 200 mm:34101090 | 040 | 040 | -200 | geen waarde gevonden | BB_XX_Vloer uit beton, 200 mm | 69.194 | 2.08441 | 0 | yes | IfcClassificationReference - TDS_link: .\05 As Builtdossier\2. Bouwkunde\2.2. Stabiliteit\2.2.0 technische fiche's\TF S 4.3 A-beton.pdf; TDS_link_extra_1: .\05 As Builtdossier\2. Bouwkunde\2.2. Stabiliteit\2.2.0 technische fiche's\TF S 4.3.2.1 A-wapeningsstaal.pdf; Pset_ConcreteElementGeneral - ConstructionMethod: on-site; Pset_SlabCommon - FireRating: REI 60
BB_XX_Vloer uit beton, 200 mm:1037397 | 050 | 050 | -300 | geen waarde gevonden | BB_XX_Vloer uit beton, 200 mm | 56.2336 | 2.7174 | 0 | no | 13.587 | 2.7174 | 200 | Qto_SlabBaseQuantities - Width: 2100; Length: 6470
BB_XX_Vloer uit beton, 200 mm:10350670 | 050 | 050 | -150 | geen waarde gevonden | BB_XX_Vloer uit beton, 200 mm | 30.1837 | 1.058 | 0 | no | 5.29 | 1.058 | 200 | Qto_SlabBaseQuantities - Width: 2300; Length: 2300
BB_XX_Vloer uit beton, 200 mm:10350739 | 050 | 050 | -150 | geen waarde gevonden | BB_XX_Vloer uit beton, 200 mm | 74.9672 | 2.8109 | 0 | no
BB_XX_Vloer welfsels, 200 mm:34201158 | 050 | 050 | -50 | geen waarde gevonden | BB_XX_Vloer welfsels, 200 mm | 284.885 | 24.1121 | 0 | yes | IfcClassificationReference - TDS_link: .\05 As Builtdossier\2. Bouwkunde\2.2. Stabiliteit\2.2.2. Welfsels\Rekennota - WTCB (Vanhout)-versie A.pdf; Pset_ConcreteElementGeneral - ConstructionMethod: prefabricated; Pset_SlabCommon - FireRating: REI 60; IfcElement - Tag: S 501; Mark: S 501

# IfcSlab: BB_Beton_Bestaand 210 (12)
Type - PredefinedType: FLOOR; Material: BB_Beton_Bestaand
Cpset_Slab - LevelOfAccuracy: in te vullen door Buildwise
IfcClassificationReference - GVH_artnr 01: geen waarde gevonden; GVH_artnr 02: geen waarde gevonden; GVH_artnr 03: geen waarde gevonden; GVH_artnr 04: geen waarde gevonden; GVH_artnr 05: geen waarde gevonden; GVH_artnr 06: geen waarde gevonden
IfcRoot - Name: BB_XX_Vloer welfsels, 210 mm
Pset_Condition - AssessmentCondition: Empty
Pset_EnvironmentalImpactIndicators - Reference: BB_XX_Vloer welfsels, 210 mm; sets with these values: 2
Pset_SlabCommon - Reference: BB_XX_Vloer welfsels, 210 mm; PitchAngle: 0 rad; IsExternal: no; LoadBearing: no
Name (Floor:BB_XX_Vloer welfsels, 210 mm:...) | In | Level | Height Offset From Level | Width | Length | Perimeter | GrossArea | GrossVolume | NetVolume | Depth
978868 | K10 | K10 | -100 | 21395 | 3195 | 161.352 | 68.357 | 14.355 | 14.355 | 210
985493 | K10 | K10 | -100 | 15900 | 3790 | 129.199 | 60.261 | 12.6548 | 12.6548 | 210
985879 | K10 | K10 | 0 | 15650.3 | 3800 | 127.627 | 59.4711 | 12.4889 | 12.4889 | 210
987125 | K10 | K10 | 0 | 13150 | 6900 | 131.562 | 90.735 | 19.0544 | 19.0544 | 210
988412 | K10 | K10 | 0 |  |  | 70.3223 | 26.8358 | 5.63553 | 5.63553 | 210
989238 | K10 | K10 | -100 | 4300 | 17830 | 145.21 | 76.669 | 16.1005 | 16.1005 | 210
995261 | K10 | K10 | 0 | 7450 | 21200 | 187.992 | 157.94 | 33.1674 | 33.1674 | 210
25435830 | K10 | K10 | 0 | 3500 | 9290 | 83.9239 | 32.515 | 6.82815 | 6.82815 | 210
708741 | 020 | 020 | -80 |  |  | 67.9261 | 29.2105 | 6.13421 | 6.13421 | 210
714006 | 030 | 030 | -80 |  |  | 67.9261 | 29.2105 | 6.13421 | 6.13421 | 210
770386 | 040 | 040 | -200 |  |  | 206.987 |  |  | 30.5109
773146 | 040 | 040 | -200 |  |  | 223.13 |  |  | 30.237

# IfcSlab: BB_Beton_Bestaand 250 (4)
Type - PredefinedType: FLOOR; Material: BB_Beton_Bestaand
Cpset_Slab - LevelOfAccuracy: in te vullen door Buildwise
IfcBuildingStorey - Height Offset From Level: 0
IfcClassificationReference - GVH_artnr 01: geen waarde gevonden; GVH_artnr 02: geen waarde gevonden; GVH_artnr 03: geen waarde gevonden; GVH_artnr 04: geen waarde gevonden; GVH_artnr 05: geen waarde gevonden; GVH_artnr 06: geen waarde gevonden
Qto_SlabBaseQuantities - Depth: 250
Pset_Condition - AssessmentCondition: Empty
Pset_EnvironmentalImpactIndicators - sets with these values: 2
Pset_SlabCommon - PitchAngle: 0 rad; IsExternal: no; LoadBearing: no
Name (Floor:...) | In | Level | Name = Pset_EnvironmentalImpactIndicators, Reference = Pset_SlabCommon, Reference | Width | Length | Perimeter | GrossArea | GrossVolume = NetVolume
BB_XX_Vloer uit beton, 250 mm:1362232 | TAW50 | K30 | BB_XX_Vloer uit beton, 250 mm | 3005 | 2800 | 38.0906 | 8.414 | 2.1035
BB_XX_Vloer welfsels, 250 mm:997638 | K10 | K10 | BB_XX_Vloer welfsels, 250 mm | 3800 | 18400 | 145.669 | 69.92 | 17.48
BB_XX_Vloer welfsels, 250 mm:998311 | K10 | K10 | BB_XX_Vloer welfsels, 250 mm | 3800 | 15900 | 129.265 | 60.42 | 15.105
BB_XX_Vloer welfsels, 250 mm:998681 | K10 | K10 | BB_XX_Vloer welfsels, 250 mm |  |  | 101.986 | 47.2176 | 11.8044

# IfcSlab: BB_Beton_Bestaand 260 (50)
Type - PredefinedType: FLOOR; Material: BB_Beton_Bestaand
Cpset_Slab - LevelOfAccuracy: in te vullen door Buildwise
Pset_Condition - AssessmentCondition: Empty
Pset_EnvironmentalImpactIndicators - sets with these values: 2
Pset_SlabCommon - IsExternal: no
Name (Floor:...) | In | Level | Height Offset From Level | GVH_artnr 01 = GVH_artnr 02 = GVH_artnr 03 = GVH_artnr 04 = GVH_artnr 05 = GVH_artnr 06 | Name = Pset_EnvironmentalImpactIndicators, Reference = Pset_SlabCommon, Reference | Perimeter | GrossArea | GrossVolume | NetVolume | Depth | PitchAngle (rad) | LoadBearing
BB_XX_Vloer welfsels, 260 mm:984245 | K10 | K10 | 0 | geen waarde gevonden | BB_XX_Vloer welfsels, 260 mm | 92.5197 | 47.8504 | 12.4411 | 12.4411 | 260 | 0 | no
BB_XX_Vloer welfsels, 260 mm:1001912 | K10 | K10 | 0 | geen waarde gevonden | BB_XX_Vloer welfsels, 260 mm | 281.785 | 251.059 | 65.2754 | 65.2754 | 260 | 0 | no
BB_XX_Vloer uit beton, 260 mm:1006089 | K10 | K10 | -100 | geen waarde gevonden | BB_XX_Vloer uit beton, 260 mm | 256.659 | 214.802 | 55.8485 | 55.8485 | 260 | 0 | no
BB_XX_Vloer welfsels, 260 mm:1011363 | K10 | K10 | 0 | geen waarde gevonden | BB_XX_Vloer welfsels, 260 mm | 277.658 | 235.488 | 61.227 | 61.227 | 260 | 0 | no
BB_XX_Vloer welfsels, 260 mm:684026 | 000 | 000 | -200 | geen waarde gevonden | BB_XX_Vloer welfsels, 260 mm | 277.657 | 248.422 | 64.5898 | 64.5898 | 260 | 0 | no
BB_XX_Vloer uit beton, 260 mm:795215 | 000 | 000 | -200 | geen waarde gevonden | BB_XX_Vloer uit beton, 260 mm | 274.738 | 237.671 | 61.7946 | 61.7946 | 260 | 0 | no
BB_XX_Vloer welfsels, 260 mm:851608 | 000 | 000 | -200 | geen waarde gevonden | BB_XX_Vloer welfsels, 260 mm | 118.11 | 58.91 | 15.3166 | 15.3166 | 260 | 0 | no | Qto_SlabBaseQuantities - Width: 13700; Length: 4300
BB_XX_Vloer uit beton, 260 mm:880510 | 000 | 000 | -400 | geen waarde gevonden | BB_XX_Vloer uit beton, 260 mm | 141.461 | 57.1797 |  | 15.1585 |  | 0 | no
BB_XX_Vloer uit beton, 260 mm:880510:2 | 000 | 000 | -400 | geen waarde gevonden | BB_XX_Vloer uit beton, 260 mm | 141.461 | 1.12228 |  | 15.1585 |  | 0 | no
BB_XX_Vloer uit beton, 260 mm:884523 | 000 | 000 | -200 | geen waarde gevonden | BB_XX_Vloer uit beton, 260 mm | 129.593 | 61.215 | 15.9159 | 15.9159 | 260 | 0 | no | Qto_SlabBaseQuantities - Width: 3850; Length: 15900
BB_XX_Vloer uit beton, 260 mm:884592 | 000 | 000 | -200 | geen waarde gevonden | BB_XX_Vloer uit beton, 260 mm | 145.013 | 76.54 | 19.9004 | 19.9004 | 260 | 0 | no | Qto_SlabBaseQuantities - Width: 4300; Length: 17800
BB_XX_Vloer welfsels, 260 mm:886547 | 000 | 000 | -400 | geen waarde gevonden | BB_XX_Vloer welfsels, 260 mm | 75.9196 | 27.3013 | 7.09833 | 7.09833 | 260 | 0 | no
BB_XX_Vloer welfsels, 260 mm:886575 | 000 | 000 | -400 | geen waarde gevonden | BB_XX_Vloer welfsels, 260 mm | 82.6134 | 31.189 | 8.10913 | 8.10913 | 260 | 0 | no | Qto_SlabBaseQuantities - Width: 3390; Length: 9200.28
BB_XX_Vloer uit beton, 260 mm:886903 | 000 | 000 | -80 | geen waarde gevonden | BB_XX_Vloer uit beton, 260 mm | 45.9318 | 9.69001 | 2.5194 | 2.5194 | 260 | 0 | no | Qto_SlabBaseQuantities - Width: 5100; Length: 1900
BB_XX_Vloer uit beton, 260 mm:886979 | 000 | 000 | -200 | geen waarde gevonden | BB_XX_Vloer uit beton, 260 mm | 73.9992 | 18.6456 |  | 4.84897 |  | 0.0213643 | no
BB_XX_Vloer uit beton, 260 mm:892125 | 000 | 000 | -100 | geen waarde gevonden | BB_XX_Vloer uit beton, 260 mm | 92.5197 | 47.8712 | 12.4465 | 12.4465 | 260 | 0 | no
BB_XX_Vloer uit beton, 260 mm:902243 | 000 | 000 | -200 | geen waarde gevonden | BB_XX_Vloer uit beton, 260 mm | 129.528 | 61.056 | 15.8746 | 15.8746 | 260 | 0 | no | Qto_SlabBaseQuantities - Width: 15900; Length: 3840
BB_XX_Vloer welfsels, 260 mm:937956 | 000 | 000 | -200 | geen waarde gevonden | BB_XX_Vloer welfsels, 260 mm | 264.337 | 220.721 | 57.3874 | 57.3874 | 260 | 0 | no
BB_XX_Vloer uit beton, 260 mm:940491 | 000 | 000 | -200 | geen waarde gevonden | BB_XX_Vloer uit beton, 260 mm | 262.139 | 220.994 | 57.4585 | 57.4585 | 260 | 0 | no
BB_XX_Vloer uit beton, 260 mm:1183306 | 000 | 000 | -200 | geen waarde gevonden | BB_XX_Vloer uit beton, 260 mm | 9.71021 | 0.457528 | 0.118957 | 0.118957 | 260 | 0 | no | Qto_SlabBaseQuantities - Width: 1039.84; Length: 440
BB_XX_Vloer welfsels, 260 mm:2469154 | 000 | 000 | -400 | geen waarde gevonden | BB_XX_Vloer welfsels, 260 mm | 19.4465 | 1.50697 | 0.391811 | 0.391811 | 260 | 0 | no
BB_XX_Vloer uit beton, 260 mm:25437835 | 000 | 000 | -200 | geen waarde gevonden | BB_XX_Vloer uit beton, 260 mm | 9.3832 | 0.4056 | 0.105456 | 0.105456 | 260 | 0 | no | Qto_SlabBaseQuantities - Width: 390; Length: 1040
BB_XX_Vloer uit beton, 260 mm:25438394 | 000 | 000 | -400 | geen waarde gevonden | BB_XX_Vloer uit beton, 260 mm | 141.419 | 57.1602 |  | 15.1532 |  | 0 | no
BB_XX_Vloer uit beton, 260 mm:25438394:2 | 000 | 000 | -400 | geen waarde gevonden | BB_XX_Vloer uit beton, 260 mm | 141.419 | 1.12148 |  | 15.1532 |  | 0 | no
BB_XX_Vloer uit beton, 260 mm:34061143 | 000 | 000 | -400 | geen waarde gevonden | BB_XX_Vloer uit beton, 260 mm | 42.4 | 6.95468 | 1.80822 | 1.80822 | 260 | 0 | yes | IfcClassificationReference - TDS_link: .\05 As Builtdossier\2. Bouwkunde\2.2. Stabiliteit\2.2.0 technische fiche's\TF S 4.3 A-beton.pdf; TDS_link_extra_1: .\05 As Builtdossier\2. Bouwkunde\2.2. Stabiliteit\2.2.0 technische fiche's\TF S 4.3.2.1 A-wapeningsstaal.pdf; Pset_ConcreteElementGeneral - ConstructionMethod: on-site; Pset_SlabCommon - FireRating: REI 60
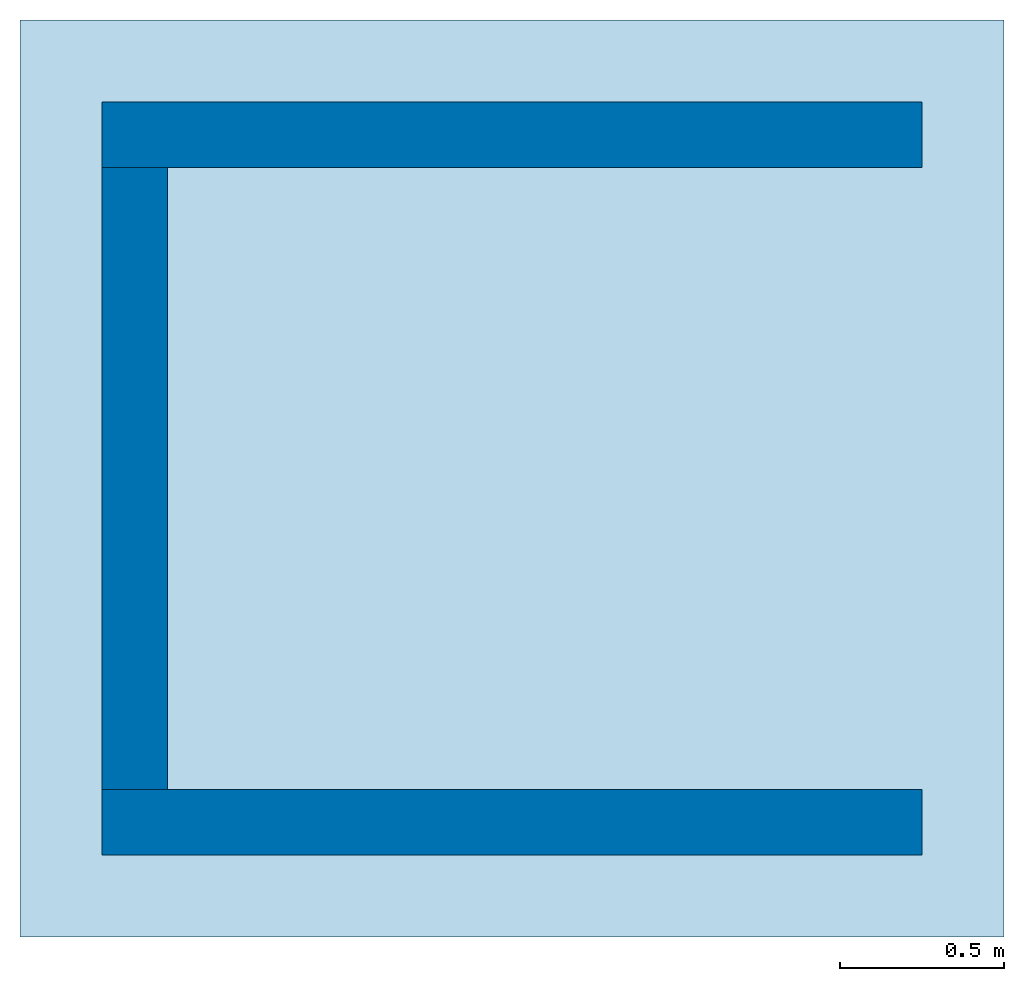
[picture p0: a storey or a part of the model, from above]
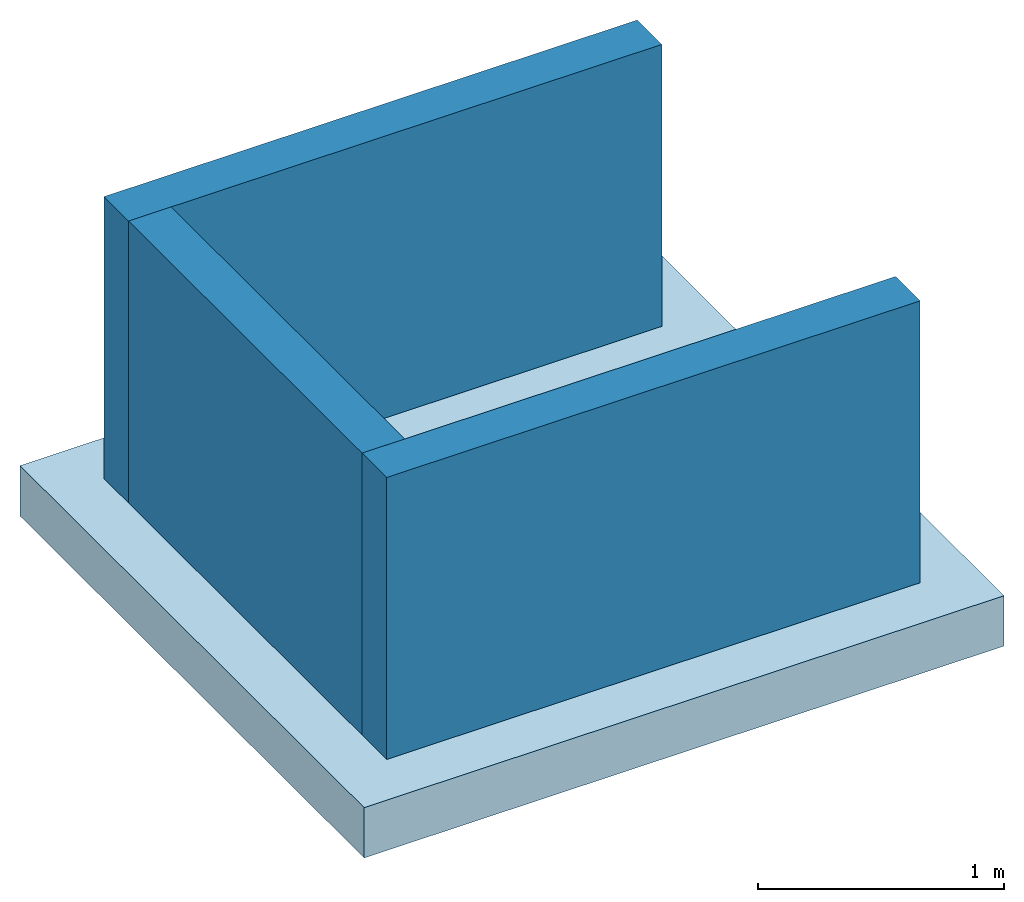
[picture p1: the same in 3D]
Properties of the parts of a building model (IFC4X3_ADD2), part 16 of 28

# IfcSlab: BB_Beton_Bestaand 260 (50)
Name (Floor:...) | In | Level | Height Offset From Level | GVH_artnr 01 = GVH_artnr 02 = GVH_artnr 03 = GVH_artnr 04 = GVH_artnr 05 = GVH_artnr 06 | Name = Pset_EnvironmentalImpactIndicators, Reference = Pset_SlabCommon, Reference | Perimeter | GrossArea | GrossVolume | NetVolume | Depth | PitchAngle (rad) | LoadBearing
BB_XX_Vloer uit beton, 260 mm:34113572 | 000 | 000 | -400 |  | BB_XX_Vloer uit beton, 260 mm | 62.0116 | 13.4444 | 3.49556 | 3.49556 | 260 | 0 | yes | IfcClassificationReference - TDS_link: .\05 As Builtdossier\2. Bouwkunde\2.2. Stabiliteit\2.2.0 technische fiche's\TF S 4.3 A-beton.pdf; TDS_link_extra_1: .\05 As Builtdossier\2. Bouwkunde\2.2. Stabiliteit\2.2.0 technische fiche's\TF S 4.3.2.1 A-wapeningsstaal.pdf; Pset_ConcreteElementGeneral - ConstructionMethod: on-site; Pset_SlabCommon - FireRating: REI 60
BB_XX_Vloer welfsels, 260 mm:674801 | 010 | 010 | -200 | geen waarde gevonden | BB_XX_Vloer welfsels, 260 mm | 138.911 | 95.9202 | 24.9392 | 24.9392 | 260 | 0 | no
BB_XX_Vloer welfsels, 260 mm:675162 | 010 | 010 | -200 | geen waarde gevonden | BB_XX_Vloer welfsels, 260 mm | 92.2244 | 49.3115 | 12.821 | 12.821 | 260 | 0 | no | Qto_SlabBaseQuantities - Width: 7300; Length: 6755
BB_XX_Vloer welfsels, 260 mm:680150 | 010 | 010 | -200 | geen waarde gevonden | BB_XX_Vloer welfsels, 260 mm | 120.341 | 66.6299 | 17.3238 | 17.3238 | 260 | 0 | no
BB_XX_Vloer welfsels, 260 mm:681204 | 010 | 010 | -200 | geen waarde gevonden | BB_XX_Vloer welfsels, 260 mm | 94.8491 | 52.0135 | 13.5235 | 13.5235 | 260 | 0 | no | Qto_SlabBaseQuantities - Width: 6755; Length: 7700
BB_XX_Vloer welfsels, 260 mm:683823 | 010 | 010 | -200 | geen waarde gevonden | BB_XX_Vloer welfsels, 260 mm | 139.075 | 96.1029 | 24.9868 | 24.9868 | 260 | 0 | no
BB_XX_Vloer welfsels, 260 mm:687858 | 010 | 010 | -200 | geen waarde gevonden | BB_XX_Vloer welfsels, 260 mm | 89.9278 | 42.6717 | 11.0946 | 11.0946 | 260 | 0 | no
BB_XX_Vloer welfsels, 260 mm:706998 | 020 | 020 | -200 | geen waarde gevonden | BB_XX_Vloer welfsels, 260 mm | 138.845 | 95.8681 | 24.9257 | 24.9257 | 260 | 0 | no
BB_XX_Vloer welfsels, 260 mm:707013 | 020 | 020 | -200 | geen waarde gevonden | BB_XX_Vloer welfsels, 260 mm | 92.2244 | 49.3115 | 12.821 | 12.821 | 260 | 0 | no | Qto_SlabBaseQuantities - Width: 7300; Length: 6755
BB_XX_Vloer welfsels, 260 mm:707174 | 020 | 020 | -200 | geen waarde gevonden | BB_XX_Vloer welfsels, 260 mm | 89.9278 | 42.8607 | 11.1438 | 11.1438 | 260 | 0 | no
BB_XX_Vloer welfsels, 260 mm:707615 | 020 | 020 | -200 | geen waarde gevonden | BB_XX_Vloer welfsels, 260 mm | 86.9751 | 42.6205 | 11.0813 | 11.0813 | 260 | 0 | no
BB_XX_Vloer welfsels, 260 mm:708416 | 020 | 020 | -200 | geen waarde gevonden | BB_XX_Vloer welfsels, 260 mm | 92.1916 | 49.2777 | 12.8122 | 12.8122 | 260 | 0 | no | Qto_SlabBaseQuantities - Width: 6755; Length: 7295
BB_XX_Vloer welfsels, 260 mm:708542 | 020 | 020 | -200 | geen waarde gevonden | BB_XX_Vloer welfsels, 260 mm | 139.764 | 96.8692 | 25.186 | 25.186 | 260 | 0 | no
BB_XX_Vloer welfsels, 260 mm:710565 | 030 | 030 | -200 | geen waarde gevonden | BB_XX_Vloer welfsels, 260 mm | 95.5381 | 51.3255 | 13.3446 | 13.3446 | 260 | 0 | no
BB_XX_Vloer welfsels, 260 mm:710618 | 030 | 030 | -200 | geen waarde gevonden | BB_XX_Vloer welfsels, 260 mm | 76.1483 | 32.7617 | 8.51805 | 8.51805 | 260 | 0 | no | Qto_SlabBaseQuantities - Width: 6755; Length: 4850
BB_XX_Vloer welfsels, 260 mm:711546 | 030 | 030 | -200 | geen waarde gevonden | BB_XX_Vloer welfsels, 260 mm | 115.617 | 41.5368 | 10.7996 | 10.7996 | 260 | 0 | no
BB_XX_Vloer welfsels, 260 mm:711906 | 030 | 030 | -200 | geen waarde gevonden | BB_XX_Vloer welfsels, 260 mm | 76.542 | 33.1485 | 8.61861 | 8.61861 | 260 | 0 | no | Qto_SlabBaseQuantities - Width: 4900; Length: 6765
BB_XX_Vloer welfsels, 260 mm:713557 | 030 | 030 | -200 | geen waarde gevonden | BB_XX_Vloer welfsels, 260 mm | 101.411 | 57.3287 | 14.9055 | 14.9055 | 260 | 0 | no
BB_XX_Vloer welfsels, 260 mm:713708 | 030 | 030 | -200 | geen waarde gevonden | BB_XX_Vloer welfsels, 260 mm | 92.815 | 49.9195 | 12.9791 | 12.9791 | 260 | 0 | no | Qto_SlabBaseQuantities - Width: 6755; Length: 7390
BB_XX_Vloer welfsels, 260 mm:714147 | 030 | 030 | -200 | geen waarde gevonden | BB_XX_Vloer welfsels, 260 mm | 92.2244 | 49.3115 | 12.821 | 12.821 | 260 | 0 | no | Qto_SlabBaseQuantities - Width: 7300; Length: 6755
BB_XX_Vloer welfsels, 260 mm:768584 | 040 | 040 | -200 | geen waarde gevonden | BB_XX_Vloer welfsels, 260 mm | 101.572 | 62.5628 | 16.2663 | 16.2663 | 260 | 0 | no
BB_XX_Vloer welfsels, 260 mm:769323 | 040 | 040 | -200 | geen waarde gevonden | BB_XX_Vloer welfsels, 260 mm | 107.671 | 65.9833 | 17.1557 | 17.1557 | 260 | 0 | no
BB_XX_Vloer welfsels, 260 mm:769416 | 040 | 040 | -200 | geen waarde gevonden | BB_XX_Vloer welfsels, 260 mm | 104.035 | 61.0743 | 15.8793 | 15.8793 | 260 | 0 | no
BB_XX_Vloer welfsels, 260 mm:772654 | 040 | 040 | -200 | geen waarde gevonden | BB_XX_Vloer welfsels, 260 mm | 107.676 | 65.9915 | 17.1578 | 17.1578 | 260 | 0 | no
BB_XX_Vloer welfsels, 260 mm:772843 | 040 | 040 | -200 | geen waarde gevonden | BB_XX_Vloer welfsels, 260 mm | 104.035 | 61.2514 | 15.9254 | 15.9254 | 260 | 0 | no | Qto_SlabBaseQuantities - Width: 6665; Length: 9190

# IfcSlab: BB_Beton_Bestaand 330 (5)
Type - PredefinedType: FLOOR; Material: BB_Beton_Bestaand
Cpset_Slab - LevelOfAccuracy: in te vullen door Buildwise
IfcClassificationReference - GVH_artnr 01: geen waarde gevonden; GVH_artnr 02: geen waarde gevonden; GVH_artnr 03: geen waarde gevonden; GVH_artnr 04: geen waarde gevonden; GVH_artnr 05: geen waarde gevonden; GVH_artnr 06: geen waarde gevonden
IfcRoot - Name: BB_XX_Vloer welfsels, 330 mm
Qto_SlabBaseQuantities - Depth: 330
Pset_Condition - AssessmentCondition: Empty
Pset_EnvironmentalImpactIndicators - Reference: BB_XX_Vloer welfsels, 330 mm; sets with these values: 2
Pset_SlabCommon - Reference: BB_XX_Vloer welfsels, 330 mm; PitchAngle: 0 rad; IsExternal: no; LoadBearing: no
Name (Floor:BB_XX_Vloer welfsels, 330 mm:...) | In | Level | Height Offset From Level | Perimeter | GrossArea | GrossVolume | NetVolume
851580 | 000 | 000 | -400 | 185.367 | 152.662 | 50.3783 | 50.3783 | Qto_SlabBaseQuantities - Width: 7280; Length: 20970
880531 | 000 | 000 | -400 | 129.921 | 88.5851 | 29.2331 | 29.2331 | Qto_SlabBaseQuantities - Width: 12970; Length: 6830
937097 | 000 | 000 | -200 | 159.29 | 126.771 | 41.8346 | 41.8344
33839058 | 010 | 010 | -200 | 159.164 | 132.028 | 43.5694 | 43.5698
708667 | 020 | 020 | -200 | 159.164 | 132.028 | 43.5694 | 43.5698

# IfcSlab: BB_Beton_Bestaand 340 (2)
In: K10
Type - PredefinedType: FLOOR; Material: BB_Beton_Bestaand
Cpset_Slab - LevelOfAccuracy: in te vullen door Buildwise
IfcBuildingStorey - Level: K10; Height Offset From Level: 0
IfcClassificationReference - GVH_artnr 01: geen waarde gevonden; GVH_artnr 02: geen waarde gevonden; GVH_artnr 03: geen waarde gevonden; GVH_artnr 04: geen waarde gevonden; GVH_artnr 05: geen waarde gevonden; GVH_artnr 06: geen waarde gevonden
IfcRoot - Name: BB_XX_Vloer welfsels, 340 mm
Qto_SlabBaseQuantities - Depth: 340
Pset_Condition - AssessmentCondition: Empty
Pset_EnvironmentalImpactIndicators - Reference: BB_XX_Vloer welfsels, 340 mm; sets with these values: 2
Pset_SlabCommon - Reference: BB_XX_Vloer welfsels, 340 mm; PitchAngle: 0 rad; IsExternal: no; LoadBearing: no
Name (Floor:BB_XX_Vloer welfsels, 340 mm:...) | Perimeter | GrossArea | GrossVolume = NetVolume
992752 | 118.11 | 58.91 | 20.0294 | Qto_SlabBaseQuantities - Width: 13700; Length: 4300
1012850 | 188.221 | 79.7801 | 27.1252

# IfcSlab: BB_Beton_Bestaand 400 (23)
Type - PredefinedType: FLOOR; Material: BB_Beton_Bestaand
Cpset_Slab - LevelOfAccuracy: in te vullen door Buildwise
IfcBuildingStorey - Height Offset From Level: -200
IfcClassificationReference - GVH_artnr 01: geen waarde gevonden; GVH_artnr 02: geen waarde gevonden; GVH_artnr 03: geen waarde gevonden; GVH_artnr 04: geen waarde gevonden; GVH_artnr 05: geen waarde gevonden; GVH_artnr 06: geen waarde gevonden
IfcRoot - Name: BB_XX_Vloer welfsels, 400 mm
Qto_SlabBaseQuantities - Depth: 400
Pset_Condition - AssessmentCondition: Empty
Pset_EnvironmentalImpactIndicators - Reference: BB_XX_Vloer welfsels, 400 mm; sets with these values: 2
Pset_SlabCommon - Reference: BB_XX_Vloer welfsels, 400 mm; PitchAngle: 0 rad; IsExternal: no; LoadBearing: no
Name (Floor:BB_XX_Vloer welfsels, 400 mm:...) | In | Level | Perimeter | GrossArea | GrossVolume = NetVolume
628661 | 010 | 010 | 171.982 | 170.751 | 68.3004 | Qto_SlabBaseQuantities - Width: 14100; Length: 12110
675360 | 010 | 010 | 192.594 | 205.201 | 82.0802
676826 | 010 | 010 | 97.1785 | 23.3325 | 9.333
681053 | 010 | 010 | 189.698 | 194.066 | 77.6262
683933 | 010 | 010 | 198.031 | 189.869 | 75.9475
706983 | 020 | 020 | 171.982 | 170.751 | 68.3004 | Qto_SlabBaseQuantities - Width: 14100; Length: 12110
707023 | 020 | 020 | 192.668 | 205.431 | 82.1725
707073 | 020 | 020 | 97.2113 | 23.3558 | 9.3423
707560 | 020 | 020 | 106.573 | 57.1541 | 22.8616
707655 | 020 | 020 | 97.1785 | 23.3145 | 9.3258
707720 | 020 | 020 | 171.982 | 170.751 | 68.3004 | Qto_SlabBaseQuantities - Width: 12110; Length: 14100
708639 | 020 | 020 | 198.031 | 189.869 | 75.9475
710912 | 030 | 030 | 107.349 | 54.8102 | 21.9241
710952 | 030 | 030 | 116.24 | 71.4195 | 28.5678 | Qto_SlabBaseQuantities - Width: 11510; Length: 6205
711200 | 030 | 030 | 110.052 | 57.5425 | 23.017
711765 | 030 | 030 | 116.503 | 71.88 | 28.752 | Qto_SlabBaseQuantities - Width: 6245; Length: 11510
711814 | 030 | 030 | 107.349 | 54.8087 | 21.9235
713736 | 030 | 030 | 189.698 | 194.084 | 77.6334
713831 | 030 | 030 | 144.115 | 96.2259 | 38.4904
714058 | 030 | 030 | 147.067 | 96.6315 | 38.6526
714109 | 030 | 030 | 189.698 | 194.084 | 77.6334
769358 | 040 | 040 | 183.793 | 192.549 | 77.0196 | Qto_SlabBaseQuantities - Width: 15900; Length: 12110
772618 | 040 | 040 | 183.793 | 192.549 | 77.0196 | Qto_SlabBaseQuantities - Width: 12110; Length: 15900

# IfcSlab: BB_Beton_Bestaand 60 (3)
Type - PredefinedType: FLOOR; Material: BB_Beton_Bestaand
Cpset_Slab - LevelOfAccuracy: in te vullen door Buildwise
IfcClassificationReference - GVH_artnr 01: geen waarde gevonden; GVH_artnr 02: geen waarde gevonden; GVH_artnr 03: geen waarde gevonden; GVH_artnr 04: geen waarde gevonden; GVH_artnr 05: geen waarde gevonden; GVH_artnr 06: geen waarde gevonden; TDS_link: .\05 As Builtdossier\2. Bouwkunde\2.2. Stabiliteit\2.2.0 technische fiche's\TF S 4.3 A-beton.pdf; TDS_link_extra_1: .\05 As Builtdossier\2. Bouwkunde\2.2. Stabiliteit\2.2.0 technische fiche's\TF S 4.3.2.1 A-wapeningsstaal.pdf
IfcRoot - Name: BB_XX_Vloer uit beton, 60 mm
Qto_SlabBaseQuantities - Perimeter: 24.7012; GrossArea: 3.27545; GrossVolume: 0.196527; NetVolume: 0.196527; Depth: 60
Pset_ConcreteElementGeneral - ConstructionMethod: on-site
Pset_Condition - AssessmentCondition: Empty
Pset_EnvironmentalImpactIndicators - Reference: BB_XX_Vloer uit beton, 60 mm; sets with these values: 2
Pset_SlabCommon - Reference: BB_XX_Vloer uit beton, 60 mm; PitchAngle: 0 rad; IsExternal: no; LoadBearing: no
Name (Floor:BB_XX_Vloer uit beton, 60 mm:...) | In | Level | Height Offset From Level
34081141 | 020 | 020 | -220
34081233 | 030 | 030 | -220
34081637 | 040 | 040 | -340

# IfcSlab: BB_Schrijnwerk_Aluminium 30, roostervloer:roostervloer:35470134
In: 000
Type - PredefinedType: FLOOR; Material: BB_Schrijnwerk_Aluminium
Cpset_Slab - LevelOfAccuracy: in te vullen door Buildwise
IfcBuildingStorey - Level: 000; Elevation from Level: 0
IfcClassificationReference - TDS_link: .\05 As Builtdossier\5. Technieken - HVAC\5.2 Technische fiches\TFH 16.12.22 Vloerroosters met horiz. staven.pdf
IfcRoot - Name: roostervloer
Qto_SlabBaseQuantities - Perimeter: 4425.93; GrossArea: 0.154321; GrossVolume: 0.00462963; NetVolume: 0.00462963; Depth: 30
Pset_ConcreteElementGeneral - ConstructionMethod: prefabricated
Pset_Condition - AssessmentCondition: Empty
Pset_EnvironmentalImpactIndicators - Reference: roostervloer; sets with these values: 2
Pset_SlabCommon - Reference: roostervloer; IsExternal: no

# IfcSlab: Concrete, C30/37 190 (2)
In: K20
Type - PredefinedType: FLOOR; Material: Concrete, C30/37
Cpset_Slab - LevelOfAccuracy: in te vullen door Buildwise
IfcBuildingStorey - Level: K20; Height Offset From Level: 600
IfcClassificationReference - TDS_link: .\05 As Builtdossier\2. Bouwkunde\2.2. Stabiliteit\2.2.0 technische fiche's\TF S 4.3 A-beton.pdf; TDS_link_extra_1: .\05 As Builtdossier\2. Bouwkunde\2.2. Stabiliteit\2.2.0 technische fiche's\TF S 4.3.2.1 A-wapeningsstaal.pdf
IfcRoot - Name: Foundation Slab 600 mm dik
Qto_SlabBaseQuantities - Depth: 600
Pset_ConcreteElementGeneral - ConstructionMethod: on-site
Pset_Condition - AssessmentCondition: Empty
Pset_EnvironmentalImpactIndicators - Reference: Foundation Slab 600 mm dik; sets with these values: 2
Pset_SlabCommon - Reference: Foundation Slab 600 mm dik; PitchAngle: 0 rad; IsExternal: no; ThermalTransmittance: 1.74333; LoadBearing: yes
Name (Foundation Slab:Foundation Slab 600 mm dik:...) | Width | Length | Perimeter | GrossArea | GrossVolume = NetVolume
34053194 | 4104.88 | 499.807 | 28.2937 | 0.779364 | 0.467619
34053293 | 2655 | 3153.71 | 28.292 | 0.779322 | 0.467593

# IfcSlab: Floor:BB_XX_Vloer uit beton, 200 mm, Floor:BB_XX_Vloer uit beton, 200 mm:906343
In: 000
PredefinedType: FLOOR
Cpset_Slab - LevelOfAccuracy: in te vullen door Buildwise
IfcBuildingStorey - Level: 000; Height Offset From Level: 0
IfcClassificationReference - GVH_artnr 01: geen waarde gevonden; GVH_artnr 02: geen waarde gevonden; GVH_artnr 03: geen waarde gevonden; GVH_artnr 04: geen waarde gevonden; GVH_artnr 05: geen waarde gevonden; GVH_artnr 06: geen waarde gevonden
IfcRoot - Name: BB_XX_Vloer uit beton, 200 mm
Qto_SlabBaseQuantities - Perimeter: 279.594; NetVolume: 23.5475
Pset_Condition - AssessmentCondition: Empty
Pset_EnvironmentalImpactIndicators - Reference: BB_XX_Vloer uit beton, 200 mm; sets with these values: 2
Pset_SlabCommon - Reference: BB_XX_Vloer uit beton, 200 mm; PitchAngle: 0.0106946 rad; IsExternal: no; LoadBearing: no

# IfcSlab: Floor:BB_XX_Vloer welfsels, 340 mm, Floor:BB_XX_Vloer welfsels, 340 mm:991012
In: K10
PredefinedType: FLOOR
Cpset_Slab - LevelOfAccuracy: in te vullen door Buildwise
IfcBuildingStorey - Level: K10; Height Offset From Level: -200
IfcClassificationReference - GVH_artnr 01: geen waarde gevonden; GVH_artnr 02: geen waarde gevonden; GVH_artnr 03: geen waarde gevonden; GVH_artnr 04: geen waarde gevonden; GVH_artnr 05: geen waarde gevonden; GVH_artnr 06: geen waarde gevonden
IfcRoot - Name: BB_XX_Vloer welfsels, 340 mm
Qto_SlabBaseQuantities - Perimeter: 156.441; NetVolume: 41.7738
Pset_Condition - AssessmentCondition: Empty
Pset_EnvironmentalImpactIndicators - Reference: BB_XX_Vloer welfsels, 340 mm; sets with these values: 2
Pset_SlabCommon - Reference: BB_XX_Vloer welfsels, 340 mm; PitchAngle: 0 rad; IsExternal: no; LoadBearing: no

# IfcSlab: Floor_BB_13.XX_Epoxyverf_ belijning arcering, Floor:BB_13.XX_Epoxyverf, belijning arcering:28365735
In: K10
PredefinedType: FLOOR; Material: BB_Belijning parkeervakken_Nieuw
Cpset_Slab - LevelOfAccuracy: in te vullen door Buildwise
IfcBuildingStorey - Level: K10; Height Offset From Level: 10
IfcClassificationReference - GVH_artnr 01: geen waarde gevonden; GVH_artnr 02: geen waarde gevonden; GVH_artnr 03: geen waarde gevonden; GVH_artnr 04: geen waarde gevonden; GVH_artnr 05: geen waarde gevonden; GVH_artnr 06: geen waarde gevonden; TDS_link: .\05 As Builtdossier\2. Bouwkunde\2.1 Architectuur\2.1.15 afwerkings- en beschermingslagen\TF A 15.01.34 A - epoxy schilderwerk op vloer- en wandtegels.pdf
IfcElement - BB_Element_Lokaalnummer01: K.-1.P3
IfcRoot - Name: BB_13.XX_Epoxyverf, belijning arcering
Qto_SlabBaseQuantities - Perimeter: 164.119; NetVolume: 0.0234561
Pset_ConcreteElementGeneral - ConstructionMethod: on-site
Pset_Condition - AssessmentCondition: Empty
Pset_EnvironmentalImpactIndicators - Reference: BB_13.XX_Epoxyverf, belijning arcering; sets with these values: 2
Pset_SlabCommon - Reference: BB_13.XX_Epoxyverf, belijning arcering; PitchAngle: 0 rad; IsExternal: no; LoadBearing: no

# IfcSlab: Floor_BB_XX_Epoxyverf_ belijning arcering_ bestaand, Floor:BB_XX_Epoxyverf, belijning arcering, bestaand:25370165
In: K10
PredefinedType: FLOOR; Material: BB_Belijning parkeervakken_Bestaand
Cpset_Slab - LevelOfAccuracy: in te vullen door Buildwise
IfcBuildingStorey - Level: K10; Height Offset From Level: 10
IfcClassificationReference - Keynote: Bestaand; GVH_artnr 01: Bestaand; GVH_artnr 02: geen waarde gevonden; GVH_artnr 03: geen waarde gevonden; GVH_artnr 04: geen waarde gevonden; GVH_artnr 05: geen waarde gevonden; GVH_artnr 06: geen waarde gevonden; TDS_link: .\05 As Builtdossier\2. Bouwkunde\2.1 Architectuur\2.1.15 afwerkings- en beschermingslagen\TF A 15.01.34 A - epoxy schilderwerk op vloer- en wandtegels.pdf
IfcRoot - Name: BB_XX_Epoxyverf, belijning arcering, bestaand
Qto_SlabBaseQuantities - Perimeter: 90.1644; NetVolume: 0.012927
Pset_Condition - AssessmentCondition: Empty
Pset_EnvironmentalImpactIndicators - Reference: BB_XX_Epoxyverf, belijning arcering, bestaand; sets with these values: 2
Pset_SlabCommon - Reference: BB_XX_Epoxyverf, belijning arcering, bestaand; PitchAngle: 0 rad; IsExternal: no; LoadBearing: no

# IfcSlab: Floor_BB_XX_Epoxyverf_ belijning arcering_ bestaand1, Floor:BB_XX_Epoxyverf, belijning arcering, bestaand:25393567
In: K10
PredefinedType: FLOOR; Material: BB_Belijning parkeervakken_Bestaand
Cpset_Slab - LevelOfAccuracy: in te vullen door Buildwise
IfcBuildingStorey - Level: K10; Height Offset From Level: 10
IfcClassificationReference - Keynote: Bestaand; GVH_artnr 01: Bestaand; GVH_artnr 02: geen waarde gevonden; GVH_artnr 03: geen waarde gevonden; GVH_artnr 04: geen waarde gevonden; GVH_artnr 05: geen waarde gevonden; GVH_artnr 06: geen waarde gevonden; TDS_link: .\05 As Builtdossier\2. Bouwkunde\2.1 Architectuur\2.1.15 afwerkings- en beschermingslagen\TF A 15.01.34 A - epoxy schilderwerk op vloer- en wandtegels.pdf
IfcRoot - Name: BB_XX_Epoxyverf, belijning arcering, bestaand
Qto_SlabBaseQuantities - Perimeter: 284.143; NetVolume: 0.0398331
Pset_Condition - AssessmentCondition: Empty
Pset_EnvironmentalImpactIndicators - Reference: BB_XX_Epoxyverf, belijning arcering, bestaand; sets with these values: 2
Pset_SlabCommon - Reference: BB_XX_Epoxyverf, belijning arcering, bestaand; PitchAngle: 0 rad; IsExternal: no; LoadBearing: no

# IfcSlab: Floor_BB_XX_Vloer uit beton_ 210 mm, Floor:BB_XX_Vloer uit beton, 210 mm:34110091
In: K10
PredefinedType: FLOOR; Material: BB_Beton_Bestaand
Cpset_Slab - LevelOfAccuracy: in te vullen door Buildwise
IfcBuildingStorey - Level: K10; Height Offset From Level: 0
IfcClassificationReference - TDS_link: .\05 As Builtdossier\2. Bouwkunde\2.2. Stabiliteit\2.2.0 technische fiche's\TF S 4.3 A-beton.pdf; TDS_link_extra_1: .\05 As Builtdossier\2. Bouwkunde\2.2. Stabiliteit\2.2.0 technische fiche's\TF S 4.3.2.1 A-wapeningsstaal.pdf
IfcRoot - Name: BB_XX_Vloer uit beton, 210 mm
Qto_SlabBaseQuantities - Perimeter: 62.0116; NetVolume: 2.59511
Pset_ConcreteElementGeneral - ConstructionMethod: on-site
Pset_Condition - AssessmentCondition: Empty
Pset_EnvironmentalImpactIndicators - Reference: BB_XX_Vloer uit beton, 210 mm; sets with these values: 2
Pset_SlabCommon - Reference: BB_XX_Vloer uit beton, 210 mm; FireRating: REI 60; PitchAngle: 0 rad; IsExternal: no; LoadBearing: yes

# IfcSlab: Floor_BB_XX_Vloer uit beton_ 210 mm1, Floor:BB_XX_Vloer uit beton, 210 mm:34113663
In: K10
PredefinedType: FLOOR; Material: BB_Beton_Bestaand
Cpset_Slab - LevelOfAccuracy: in te vullen door Buildwise
IfcBuildingStorey - Level: K10; Height Offset From Level: 0
IfcClassificationReference - TDS_link: .\05 As Builtdossier\2. Bouwkunde\2.2. Stabiliteit\2.2.0 technische fiche's\TF S 4.3 A-beton.pdf; TDS_link_extra_1: .\05 As Builtdossier\2. Bouwkunde\2.2. Stabiliteit\2.2.0 technische fiche's\TF S 4.3.2.1 A-wapeningsstaal.pdf
IfcRoot - Name: BB_XX_Vloer uit beton, 210 mm
Qto_SlabBaseQuantities - Perimeter: 50.2892; NetVolume: 1.85318
Pset_ConcreteElementGeneral - ConstructionMethod: on-site
Pset_Condition - AssessmentCondition: Empty
Pset_EnvironmentalImpactIndicators - Reference: BB_XX_Vloer uit beton, 210 mm; sets with these values: 2
Pset_SlabCommon - Reference: BB_XX_Vloer uit beton, 210 mm; FireRating: REI 60; PitchAngle: 0 rad; IsExternal: no; LoadBearing: yes

# IfcSlab: Floor_BB_XX_Vloer uit beton_ 260 mm, Floor:BB_XX_Vloer uit beton, 260 mm:34113707
In: 000
PredefinedType: FLOOR; Material: BB_Beton_Bestaand
Cpset_Slab - LevelOfAccuracy: in te vullen door Buildwise
IfcBuildingStorey - Level: 000; Height Offset From Level: -400
IfcClassificationReference - TDS_link: .\05 As Builtdossier\2. Bouwkunde\2.2. Stabiliteit\2.2.0 technische fiche's\TF S 4.3 A-beton.pdf; TDS_link_extra_1: .\05 As Builtdossier\2. Bouwkunde\2.2. Stabiliteit\2.2.0 technische fiche's\TF S 4.3.2.1 A-wapeningsstaal.pdf
IfcRoot - Name: BB_XX_Vloer uit beton, 260 mm
Qto_SlabBaseQuantities - Perimeter: 49.057; NetVolume: 2.19589
Pset_ConcreteElementGeneral - ConstructionMethod: on-site
Pset_Condition - AssessmentCondition: Empty
Pset_EnvironmentalImpactIndicators - Reference: BB_XX_Vloer uit beton, 260 mm; sets with these values: 2
Pset_SlabCommon - Reference: BB_XX_Vloer uit beton, 260 mm; FireRating: REI 60; PitchAngle: 0 rad; IsExternal: no; LoadBearing: yes

# IfcSlab: Floor_BB_XX_Vloer welfsels_ 330 mm, Floor:BB_XX_Vloer welfsels, 330 mm:711497
In: 030
PredefinedType: FLOOR; Material: BB_Beton_Bestaand
Cpset_Slab - LevelOfAccuracy: in te vullen door Buildwise
IfcBuildingStorey - Level: 030; Height Offset From Level: -200
IfcClassificationReference - GVH_artnr 01: geen waarde gevonden; GVH_artnr 02: geen waarde gevonden; GVH_artnr 03: geen waarde gevonden; GVH_artnr 04: geen waarde gevonden; GVH_artnr 05: geen waarde gevonden; GVH_artnr 06: geen waarde gevonden
IfcRoot - Name: BB_XX_Vloer welfsels, 330 mm
Qto_SlabBaseQuantities - Perimeter: 177.622; NetVolume: 44.0646
Pset_Condition - AssessmentCondition: Empty
Pset_EnvironmentalImpactIndicators - Reference: BB_XX_Vloer welfsels, 330 mm; sets with these values: 2
Pset_SlabCommon - Reference: BB_XX_Vloer welfsels, 330 mm; PitchAngle: 0 rad; IsExternal: no; LoadBearing: no

# IfcSlab: Floor_BB_XX_Vloer welfsels_ 400 mm, Floor:BB_XX_Vloer welfsels, 400 mm:707503
In: 020
PredefinedType: FLOOR; Material: BB_Beton_Bestaand
Cpset_Slab - LevelOfAccuracy: in te vullen door Buildwise
IfcBuildingStorey - Level: 020; Height Offset From Level: -200
IfcClassificationReference - GVH_artnr 01: geen waarde gevonden; GVH_artnr 02: geen waarde gevonden; GVH_artnr 03: geen waarde gevonden; GVH_artnr 04: geen waarde gevonden; GVH_artnr 05: geen waarde gevonden; GVH_artnr 06: geen waarde gevonden
IfcRoot - Name: BB_XX_Vloer welfsels, 400 mm
Qto_SlabBaseQuantities - Perimeter: 106.571; NetVolume: 22.4546
Pset_Condition - AssessmentCondition: Empty
Pset_EnvironmentalImpactIndicators - Reference: BB_XX_Vloer welfsels, 400 mm; sets with these values: 2
Pset_SlabCommon - Reference: BB_XX_Vloer welfsels, 400 mm; PitchAngle: 0 rad; IsExternal: no; LoadBearing: no

# IfcSlab: Steel, Galvanized - looprooster 30 (560)
Type - PredefinedType: FLOOR; Material: Steel, Galvanized - looprooster
Cpset_Slab - LevelOfAccuracy: in te vullen door Buildwise
IfcRoot - Name: GVH - Looprooster 30 mm
Qto_SlabBaseQuantities - Depth: 30
Pset_ConcreteElementGeneral - ConstructionMethod: prefabricated
Pset_Condition - AssessmentCondition: Empty
Pset_EnvironmentalImpactIndicators - Reference: GVH - Looprooster 30 mm
Pset_ReinforcementBarPitchOfSlab - Description: Looproosters; Reference: GVH - Looprooster 30 mm
Pset_SlabCommon - Reference: GVH - Looprooster 30 mm; PitchAngle: 0 rad; IsExternal: no; ThermalTransmittance: 1766.67; LoadBearing: no
Name (Floor:GVH - Looprooster 30 mm:...) | In | Level | Height Offset From Level | Tag = Mark | Perimeter | GrossArea | GrossVolume = NetVolume
35116104 | 000 | 000 | -320 | 4 | 8.26771 | 0.3969 | 0.011907 | Qto_SlabBaseQuantities - Width: 630; Length: 630
35116338 | 000 | 000 | -320 | 3 | 7.49014 | 0.320329 | 0.00960987
35116411 | 000 | 000 | -160 | 1 | 17.9134 | 1.85512 | 0.0556537
35116524 | 000 | 000 | -160 | 2 | 17.9134 | 1.85213 | 0.0555638
35116615 | 000 | 000 | -320 | 5 | 7.65421 | 0.329676 | 0.00989028
35116644 | 000 | 000 | -320 | 6 | 12.8937 | 0.832205 | 0.0249661
35116694 | 000 | 000 | -320 | 11 | 8.26771 | 0.3969 | 0.011907 | Qto_SlabBaseQuantities - Width: 630; Length: 630
35116718 | 000 | 000 | -320 | 13 | 8.26771 | 0.3969 | 0.011907 | Qto_SlabBaseQuantities - Width: 630; Length: 630
35116744 | 000 | 000 | -320 | 14 | 12.0604 | 0.752719 | 0.0225816
35116770 | 000 | 000 | -320 | 16 | 16.437 | 1.10903 | 0.0332709
35116794 | 000 | 000 | -320 | 18 | 12.8937 | 0.832204 | 0.0249661
35116870 | 000 | 000 | -320 | 28 | 8.26771 | 0.3969 | 0.011907 | Qto_SlabBaseQuantities - Width: 630; Length: 630
35116894 | 000 | 000 | -320 | 26 | 8.26771 | 0.3969 | 0.011907 | Qto_SlabBaseQuantities - Width: 630; Length: 630
35116918 | 000 | 000 | -320 | 30 | 12.8937 | 0.832206 | 0.0249662
35116942 | 000 | 000 | -320 | 44 | 8.26771 | 0.3969 | 0.011907 | Qto_SlabBaseQuantities - Width: 630; Length: 630
35116966 | 000 | 000 | -320 | 42 | 8.26771 | 0.3969 | 0.011907 | Qto_SlabBaseQuantities - Width: 630; Length: 630
35116994 | 000 | 000 | -320 | 46 | 12.0604 | 0.752718 | 0.0225815
35117020 | 000 | 000 | -320 | 48 | 15.8464 | 1.11623 | 0.0334868
35117245 | 000 | 000 | -320 | 7 | 12.8937 | 0.832731 | 0.0249819
35117310 | 000 | 000 | -320 | 9 | 12.9003 | 0.832835 | 0.024985
35117378 | 000 | 000 | -320 | 12 | 5.44619 | 0.126 | 0.00378 | Qto_SlabBaseQuantities - Width: 200; Length: 630
35117440 | 000 | 000 | -320 | 8 | 12.9003 | 0.833351 | 0.0250005
35117571 | 000 | 000 | -320 | 10 | 7.04678 | 0.271346 | 0.00814039
35117671 | 000 | 000 | -320 | 17 | 15.8465 | 1.11623 | 0.0334869
35117865 | 000 | 000 | -320 | 19 | 12.8937 | 0.832729 | 0.0249819
35117904 | 000 | 000 | -320 | 20 | 12.8937 | 0.832729 | 0.0249819
35117917 | 000 | 000 | -320 | 21 | 12.8937 | 0.832204 | 0.0249661
35117989 | 000 | 000 | -320 | 23 | 16.437 | 1.10903 | 0.0332709
35117998 | 000 | 000 | -320 | 22 | 15.8465 | 1.11623 | 0.0334869
35118125 | 000 | 000 | -320 | 25 | 12.0637 | 0.753035 | 0.0225911
35118138 | 000 | 000 | -320 | 24 | 12.0604 | 0.761039 | 0.0228312 | Qto_SlabBaseQuantities - Width: 630; Length: 1208
35118290 | 000 | 000 | -320 | 15 | 12.0604 | 0.761039 | 0.0228312 | Qto_SlabBaseQuantities - Width: 630; Length: 1208
35118329 | 000 | 000 | -320 | 27 | 5.44619 | 0.126 | 0.00378 | Qto_SlabBaseQuantities - Width: 200; Length: 630
35118355 | 000 | 000 | -320 | 43 | 5.44619 | 0.126 | 0.00378 | Qto_SlabBaseQuantities - Width: 630; Length: 200
35118458 | 000 | 000 | -320 | 49 | 15.8464 | 1.11623 | 0.0334868
35118506 | 000 | 000 | -320 | 51 | 15.8464 | 1.1157 | 0.0334711
35118544 | 000 | 000 | -320 | 53 | 15.8464 | 1.11623 | 0.0334868
35118578 | 000 | 000 | -320 | 55 | 14.2388 | 0.961878 | 0.0288563
35118658 | 000 | 000 | -320 | 33 | 12.8937 | 0.832206 | 0.0249662
35118709 | 000 | 000 | -320 | 32 | 12.8937 | 0.832731 | 0.0249819
35118763 | 000 | 000 | -320 | 34 | 13.7566 | 0.915574 | 0.0274672
35118840 | 000 | 000 | -320 | 35 | 8.26771 | 0.3969 | 0.011907 | Qto_SlabBaseQuantities - Width: 630; Length: 630
35118885 | 000 | 000 | -320 | 47 | 15.8464 | 1.11623 | 0.0334868
35118917 | 000 | 000 | -320 | 50 | 15.8464 | 1.1157 | 0.0334711
35118970 | 000 | 000 | -320 | 52 | 15.8464 | 1.11623 | 0.0334868
35119012 | 000 | 000 | -320 | 54 | 15.8464 | 1.11623 | 0.0334868
35119066 | 000 | 000 | -320 | 45 | 12.0604 | 0.761038 | 0.0228311 | Qto_SlabBaseQuantities - Width: 1208; Length: 630
35119104 | 000 | 000 | -320 | 56 | 14.2389 | 0.970201 | 0.029106 | Qto_SlabBaseQuantities - Width: 1540; Length: 630
35119144 | 000 | 000 | -320 | 31 | 12.8937 | 0.832731 | 0.0249819
35119201 | 000 | 000 | -320 | 36 | 13.5597 | 0.896673 | 0.0269002
35119214 | 000 | 000 | -320 | 37 | 15.8464 | 1.11623 | 0.0334868
35119288 | 000 | 000 | -320 | 29 | 7.06367 | 0.272978 | 0.00818933
35119365 | 000 | 000 | -320 | 38 | 15.8464 | 1.1157 | 0.0334711
35119403 | 000 | 000 | -320 | 39 | 15.8464 | 1.1157 | 0.0334711
35119416 | 000 | 000 | -320 | 40 | 15.8464 | 1.11623 | 0.0334868
35119484 | 000 | 000 | -320 | 41 | 7.06365 | 0.272975 | 0.00818924
35119544 | 010 | 010 | -320 | 203 | 16.7815 | 1.62258 | 0.0486775
35119566 | 010 | 010 | -320 | 201 | 17.6575 | 1.80578 | 0.0541735
35119577 | 010 | 010 | -320 | 202 | 17.8347 | 1.81607 | 0.0544821
35119590 | 010 | 010 | -320 | 204 | 7.65421 | 0.329151 | 0.00987453
35119599 | 010 | 010 | -320 | 205 | 12.8937 | 0.832205 | 0.0249661
35119608 | 010 | 010 | -320 | 210 | 8.26771 | 0.3969 | 0.011907 | Qto_SlabBaseQuantities - Width: 630; Length: 630
35119617 | 010 | 010 | -320 | 211 | 8.26771 | 0.3969 | 0.011907 | Qto_SlabBaseQuantities - Width: 630; Length: 630
35119626 | 010 | 010 | -320 | 212 | 12.0571 | 0.751879 | 0.0225564
35119635 | 010 | 010 | -320 | 214 | 16.4337 | 1.10819 | 0.0332457
35119644 | 010 | 010 | -320 | 216 | 12.8937 | 0.832204 | 0.0249661
35119653 | 010 | 010 | -320 | 225 | 8.26771 | 0.3969 | 0.011907 | Qto_SlabBaseQuantities - Width: 630; Length: 630
35119662 | 010 | 010 | -320 | 224 | 8.26771 | 0.3969 | 0.011907 | Qto_SlabBaseQuantities - Width: 630; Length: 630
35119671 | 010 | 010 | -320 | 227 | 12.8937 | 0.832206 | 0.0249662
35119680 | 010 | 010 | -320 | 241 | 8.26771 | 0.3969 | 0.011907 | Qto_SlabBaseQuantities - Width: 630; Length: 630
35119689 | 010 | 010 | -320 | 239 | 8.26771 | 0.3969 | 0.011907 | Qto_SlabBaseQuantities - Width: 630; Length: 630
35119698 | 010 | 010 | -320 | 243 | 12.0571 | 0.751878 | 0.0225563
35119707 | 010 | 010 | -320 | 245 | 15.8464 | 1.1157 | 0.0334711
35119724 | 010 | 010 | -320 | 206 | 12.8904 | 0.831889 | 0.0249567
35119738 | 010 | 010 | -320 | 208 | 12.8937 | 0.832205 | 0.0249661
35119752 | 010 | 010 | -320 | 210a | 5.44619 | 0.126 | 0.00378 | Qto_SlabBaseQuantities - Width: 200; Length: 630
35119761 | 010 | 010 | -320 | 207 | 12.8904 | 0.83189 | 0.0249567
35119775 | 010 | 010 | -320 | 209 | 7.06364 | 0.27245 | 0.00817349
35119793 | 010 | 010 | -320 | 215 | 15.8432 | 1.11539 | 0.0334617
35119819 | 010 | 010 | -320 | 217 | 12.8937 | 0.832204 | 0.0249661
35119833 | 010 | 010 | -320 | 218 | 12.8904 | 0.831889 | 0.0249567
35119846 | 010 | 010 | -320 | 219 | 12.8937 | 0.832201 | 0.024966
35119860 | 010 | 010 | -320 | 221 | 16.4337 | 1.10819 | 0.0332456
35119869 | 010 | 010 | -320 | 220 | 15.8432 | 1.11539 | 0.0334617
35119892 | 010 | 010 | -320 | 223 | 12.0571 | 0.751879 | 0.0225564
35119905 | 010 | 010 | -320 | 222 | 12.0604 | 0.761039 | 0.0228312 | Qto_SlabBaseQuantities - Width: 630; Length: 1208
35119916 | 010 | 010 | -320 | 213 | 12.0604 | 0.761039 | 0.0228312 | Qto_SlabBaseQuantities - Width: 630; Length: 1208
35119925 | 010 | 010 | -320 | 224a | 5.44619 | 0.126 | 0.00378 | Qto_SlabBaseQuantities - Width: 200; Length: 630
35119934 | 010 | 010 | -320 | 240 | 5.44619 | 0.126 | 0.00378 | Qto_SlabBaseQuantities - Width: 630; Length: 200
35119951 | 010 | 010 | -320 | 246 | 15.8464 | 1.1157 | 0.0334711
35119964 | 010 | 010 | -320 | 248 | 15.8464 | 1.1157 | 0.0334711
35119977 | 010 | 010 | -320 | 250 | 15.8497 | 1.11595 | 0.0334784
35119990 | 010 | 010 | -320 | 252 | 12.0571 | 0.751878 | 0.0225563
35120007 | 010 | 010 | -320 | 230 | 12.8937 | 0.832206 | 0.0249662
35120021 | 010 | 010 | -320 | 229 | 12.8904 | 0.831891 | 0.0249567
35120035 | 010 | 010 | -320 | 231 | 13.7566 | 0.915049 | 0.0274515
35120049 | 010 | 010 | -320 | 232 | 8.26771 | 0.3969 | 0.011907 | Qto_SlabBaseQuantities - Width: 630; Length: 630
35120058 | 010 | 010 | -320 | 244 | 15.8464 | 1.11563 | 0.0334689
35120071 | 010 | 010 | -320 | 247 | 15.8464 | 1.1157 | 0.0334711
35120084 | 010 | 010 | -320 | 249 | 15.8464 | 1.1157 | 0.0334711
35120097 | 010 | 010 | -320 | 251 | 15.8497 | 1.11602 | 0.0334806
35120110 | 010 | 010 | -320 | 242 | 12.0604 | 0.761038 | 0.0228311 | Qto_SlabBaseQuantities - Width: 1208; Length: 630
35120119 | 010 | 010 | -320 | 253 | 12.0604 | 0.761038 | 0.0228311 | Qto_SlabBaseQuantities - Width: 1208; Length: 630
35120128 | 010 | 010 | -320 | 228 | 12.8904 | 0.831891 | 0.0249567
35120142 | 010 | 010 | -320 | 233 | 13.5597 | 0.896148 | 0.0268845
35120155 | 010 | 010 | -320 | 234 | 15.8464 | 1.1157 | 0.0334711
35120168 | 010 | 010 | -320 | 226 | 7.06367 | 0.272453 | 0.00817358
35120181 | 010 | 010 | -320 | 235 | 15.8431 | 1.11539 | 0.0334616
35120194 | 010 | 010 | -320 | 236 | 15.8464 | 1.1157 | 0.0334711
35120207 | 010 | 010 | -320 | 237 | 15.8464 | 1.1157 | 0.0334711
35120220 | 010 | 010 | -320 | 238 | 7.06365 | 0.27245 | 0.00817349
35121513 | 010 | 010 | -320 | 254 | 8.26771 | 0.3969 | 0.011907 | Qto_SlabBaseQuantities - Width: 630; Length: 630
35121553 | 010 | 010 | -320 | 255 | 8.26771 | 0.3969 | 0.011907 | Qto_SlabBaseQuantities - Width: 630; Length: 630
35121600 | 010 | 010 | -320 | 257 | 15.8464 | 1.1157 | 0.0334711
35121613 | 010 | 010 | -320 | 259 | 15.853 | 1.11633 | 0.03349
35121626 | 010 | 010 | -320 | 258 | 15.8464 | 1.1157 | 0.0334711
35121639 | 010 | 010 | -320 | 260 | 15.8432 | 1.11538 | 0.0334614
35121741 | 010 | 010 | -320 | 254a | 5.44619 | 0.126 | 0.00378 | Qto_SlabBaseQuantities - Width: 630; Length: 200
35121767 | 010 | 010 | -320 | 262a | 5.44619 | 0.126 | 0.00378 | Qto_SlabBaseQuantities - Width: 630; Length: 200
35121808 | 010 | 010 | -320 | 265 | 15.9613 | 1.12673 | 0.0338018
35121821 | 010 | 010 | -320 | 264 | 8.17913 | 0.37955 | 0.0113865
35121900 | 010 | 010 | -320 | 263 | 8.26771 | 0.3969 | 0.011907 | Qto_SlabBaseQuantities - Width: 630; Length: 630
35121924 | 010 | 010 | -320 | 262 | 8.26771 | 0.3969 | 0.011907 | Qto_SlabBaseQuantities - Width: 630; Length: 630
35121958 | 010 | 010 | -320 | 266 | 15.958 | 1.12383 | 0.033715
35122012 | 010 | 010 | -320 | 261 | 7.06364 | 0.272449 | 0.00817347
35122083 | 010 | 010 | -320 | 256 | 7.06364 | 0.272449 | 0.00817347
35122144 | 010 | 010 | -320 | 334 | 16.7716 | 1.62083 | 0.0486249
35122153 | 010 | 010 | -320 | 336 | 17.6575 | 1.80578 | 0.0541735
35122164 | 010 | 010 | -320 | 335 | 17.8347 | 1.81607 | 0.0544821
35122177 | 010 | 010 | -320 | 333 | 7.65421 | 0.329151 | 0.00987453
35122186 | 010 | 010 | -320 | 332 | 12.8937 | 0.832205 | 0.0249661
35122195 | 010 | 010 | -320 | 327 | 8.26771 | 0.3969 | 0.011907 | Qto_SlabBaseQuantities - Width: 630; Length: 630
35122204 | 010 | 010 | -320 | 325 | 8.26771 | 0.3969 | 0.011907 | Qto_SlabBaseQuantities - Width: 630; Length: 630
35122213 | 010 | 010 | -320 | 324 | 12.0571 | 0.751879 | 0.0225564
35122222 | 010 | 010 | -320 | 322 | 16.4337 | 1.10819 | 0.0332457
35122231 | 010 | 010 | -320 | 320 | 12.8937 | 0.832204 | 0.0249661
35122240 | 010 | 010 | -320 | 310 | 8.26771 | 0.3969 | 0.011907 | Qto_SlabBaseQuantities - Width: 630; Length: 630
35122249 | 010 | 010 | -320 | 312 | 8.26771 | 0.3969 | 0.011907 | Qto_SlabBaseQuantities - Width: 630; Length: 630
35122258 | 010 | 010 | -320 | 308 | 12.8937 | 0.832206 | 0.0249662
35122267 | 010 | 010 | -320 | 294 | 8.26771 | 0.3969 | 0.011907 | Qto_SlabBaseQuantities - Width: 630; Length: 630
35122276 | 010 | 010 | -320 | 296 | 8.26771 | 0.3969 | 0.011907 | Qto_SlabBaseQuantities - Width: 630; Length: 630
35122285 | 010 | 010 | -320 | 292 | 12.0571 | 0.751878 | 0.0225563
35122294 | 010 | 010 | -320 | 290 | 15.8464 | 1.1157 | 0.0334711
35122311 | 010 | 010 | -320 | 331 | 12.8937 | 0.832206 | 0.0249662
35122325 | 010 | 010 | -320 | 329 | 12.8937 | 0.832205 | 0.0249661
35122339 | 010 | 010 | -320 | 326 | 5.44619 | 0.126 | 0.00378 | Qto_SlabBaseQuantities - Width: 630; Length: 200
35122348 | 010 | 010 | -320 | 330 | 12.8904 | 0.83189 | 0.0249567
35122362 | 010 | 010 | -320 | 328 | 7.06364 | 0.27245 | 0.00817349
35122380 | 010 | 010 | -320 | 321 | 15.8432 | 1.11539 | 0.0334617
35122406 | 010 | 010 | -320 | 319 | 12.8937 | 0.832204 | 0.0249661
35122420 | 010 | 010 | -320 | 318 | 12.8904 | 0.831889 | 0.0249567
35122433 | 010 | 010 | -320 | 317 | 12.8937 | 0.832201 | 0.024966
35122447 | 010 | 010 | -320 | 315 | 16.4337 | 1.10819 | 0.0332456
35122456 | 010 | 010 | -320 | 316 | 15.8432 | 1.11539 | 0.0334617
35122479 | 010 | 010 | -320 | 313 | 12.0571 | 0.751879 | 0.0225564
35122492 | 010 | 010 | -320 | 314 | 12.0604 | 0.761039 | 0.0228312 | Qto_SlabBaseQuantities - Width: 1208; Length: 630
35122503 | 010 | 010 | -320 | 323 | 12.0604 | 0.761039 | 0.0228312 | Qto_SlabBaseQuantities - Width: 1208; Length: 630
35122512 | 010 | 010 | -320 | 311 | 5.44619 | 0.126 | 0.00378 | Qto_SlabBaseQuantities - Width: 630; Length: 200
35122521 | 010 | 010 | -320 | 295 | 5.67585 | 0.14805 | 0.0044415 | Qto_SlabBaseQuantities - Width: 235; Length: 630
35122538 | 010 | 010 | -320 | 289 | 15.8464 | 1.1157 | 0.0334711
35122551 | 010 | 010 | -320 | 287 | 15.8497 | 1.11602 | 0.0334805
35122564 | 010 | 010 | -320 | 285 | 15.8464 | 1.11563 | 0.0334689
35122577 | 010 | 010 | -320 | 283 | 12.0571 | 0.751878 | 0.0225563
35122594 | 010 | 010 | -320 | 305 | 12.8937 | 0.832206 | 0.0249662
35122608 | 010 | 010 | -320 | 306 | 12.8904 | 0.831891 | 0.0249567
35122622 | 010 | 010 | -320 | 304 | 13.5598 | 0.896156 | 0.0268847
35122636 | 010 | 010 | -320 | 303 | 8.26771 | 0.3969 | 0.011907 | Qto_SlabBaseQuantities - Width: 630; Length: 630
35122645 | 010 | 010 | -320 | 291 | 15.8464 | 1.11563 | 0.0334689
35122658 | 010 | 010 | -320 | 288 | 15.8464 | 1.1157 | 0.0334711
35122671 | 010 | 010 | -320 | 286 | 15.8431 | 1.11539 | 0.0334616
35122684 | 010 | 010 | -320 | 284 | 15.8464 | 1.1157 | 0.0334711
35122697 | 010 | 010 | -320 | 293 | 12.0604 | 0.761038 | 0.0228311 | Qto_SlabBaseQuantities - Width: 630; Length: 1208
35122706 | 010 | 010 | -320 | 282 | 12.0604 | 0.761038 | 0.0228311 | Qto_SlabBaseQuantities - Width: 630; Length: 1208
35122715 | 010 | 010 | -320 | 307 | 12.8904 | 0.831891 | 0.0249567
35122729 | 010 | 010 | -320 | 302 | 13.6909 | 0.908749 | 0.0272625
35122742 | 010 | 010 | -320 | 301 | 15.8464 | 1.1157 | 0.0334711
35122755 | 010 | 010 | -320 | 309 | 7.06367 | 0.272453 | 0.00817358
35122768 | 010 | 010 | -320 | 300 | 15.8431 | 1.11539 | 0.0334616
35122781 | 010 | 010 | -320 | 299 | 15.8464 | 1.1157 | 0.0334711
35122794 | 010 | 010 | -320 | 298 | 15.8431 | 1.11539 | 0.0334616
35122807 | 010 | 010 | -320 | 297 | 7.06365 | 0.27245 | 0.00817349
35122826 | 010 | 010 | -320 | 281 | 8.26771 | 0.3969 | 0.011907 | Qto_SlabBaseQuantities - Width: 630; Length: 630
35122835 | 010 | 010 | -320 | 279 | 8.26771 | 0.3969 | 0.011907 | Qto_SlabBaseQuantities - Width: 630; Length: 630
35122844 | 010 | 010 | -320 | 277 | 15.8464 | 1.1157 | 0.0334711
35122857 | 010 | 010 | -320 | 275 | 15.8399 | 1.11509 | 0.0334527
35122870 | 010 | 010 | -320 | 276 | 15.8464 | 1.1157 | 0.0334711
35122883 | 010 | 010 | -320 | 274 | 15.8497 | 1.11601 | 0.0334804
35122896 | 010 | 010 | -320 | 280 | 5.44619 | 0.126 | 0.00378 | Qto_SlabBaseQuantities - Width: 200; Length: 630
35122905 | 010 | 010 | -320 | 271 | 5.44619 | 0.126 | 0.00378 | Qto_SlabBaseQuantities - Width: 200; Length: 630
35122914 | 010 | 010 | -320 | 268 | 15.9613 | 1.12673 | 0.0338018
35122927 | 010 | 010 | -320 | 269 | 8.17913 | 0.37955 | 0.0113865
35122940 | 010 | 010 | -320 | 270 | 8.26771 | 0.3969 | 0.011907 | Qto_SlabBaseQuantities - Width: 630; Length: 630
35122949 | 010 | 010 | -320 | 272 | 8.26771 | 0.3969 | 0.011907 | Qto_SlabBaseQuantities - Width: 630; Length: 630
35122958 | 010 | 010 | -320 | 267 | 15.958 | 1.12383 | 0.033715
35122971 | 010 | 010 | -320 | 273 | 7.06364 | 0.272449 | 0.00817347
35122984 | 010 | 010 | -320 | 278 | 7.06364 | 0.272449 | 0.00817347
35124213 | 020 | 020 | -320 | 403 | 16.7815 | 1.62258 | 0.0486775
35124222 | 020 | 020 | -320 | 401 | 17.6575 | 1.80578 | 0.0541735
35124233 | 020 | 020 | -320 | 402 | 17.8347 | 1.81607 | 0.0544821
35124246 | 020 | 020 | -320 | 404 | 7.65421 | 0.329676 | 0.00989028
35124255 | 020 | 020 | -320 | 405 | 12.8937 | 0.832205 | 0.0249661
35124264 | 020 | 020 | -320 | 410 | 8.26771 | 0.3969 | 0.011907 | Qto_SlabBaseQuantities - Width: 630; Length: 630
35124273 | 020 | 020 | -320 | 412 | 8.26771 | 0.3969 | 0.011907 | Qto_SlabBaseQuantities - Width: 630; Length: 630
35124282 | 020 | 020 | -320 | 413 | 12.0571 | 0.752404 | 0.0225721
35124291 | 020 | 020 | -320 | 415 | 16.4337 | 1.11118 | 0.0333354
35124300 | 020 | 020 | -320 | 417 | 12.8937 | 0.832204 | 0.0249661
35124309 | 020 | 020 | -320 | 427 | 8.26771 | 0.3969 | 0.011907 | Qto_SlabBaseQuantities - Width: 630; Length: 630
35124318 | 020 | 020 | -320 | 425 | 8.26771 | 0.3969 | 0.011907 | Qto_SlabBaseQuantities - Width: 630; Length: 630
35124327 | 020 | 020 | -320 | 429 | 12.8937 | 0.832206 | 0.0249662
35124336 | 020 | 020 | -320 | 443 | 8.26771 | 0.3969 | 0.011907 | Qto_SlabBaseQuantities - Width: 630; Length: 630
35124345 | 020 | 020 | -320 | 441 | 8.26771 | 0.3969 | 0.011907 | Qto_SlabBaseQuantities - Width: 630; Length: 630
35124354 | 020 | 020 | -320 | 445 | 12.0571 | 0.752403 | 0.0225721
35124363 | 020 | 020 | -320 | 447 | 15.8497 | 1.11654 | 0.0334961
35124380 | 020 | 020 | -320 | 406 | 12.8904 | 0.832414 | 0.0249724
35124394 | 020 | 020 | -320 | 408 | 12.8937 | 0.832205 | 0.0249661
35124408 | 020 | 020 | -320 | 411 | 5.44619 | 0.126 | 0.00378 | Qto_SlabBaseQuantities - Width: 200; Length: 630
35124417 | 020 | 020 | -320 | 407 | 12.8904 | 0.832415 | 0.0249724
35124431 | 020 | 020 | -320 | 409 | 7.06364 | 0.272974 | 0.00818923
35124449 | 020 | 020 | -320 | 416 | 15.8465 | 1.11623 | 0.0334869
35124475 | 020 | 020 | -320 | 418 | 12.8937 | 0.835194 | 0.0250558
35124489 | 020 | 020 | -320 | 419 | 12.8904 | 0.832414 | 0.0249724
35124502 | 020 | 020 | -320 | 420 | 12.8937 | 0.832201 | 0.024966
35124516 | 020 | 020 | -320 | 422 | 16.4337 | 1.10871 | 0.0332613
35124525 | 020 | 020 | -320 | 421 | 15.8432 | 1.11592 | 0.0334775
35124548 | 020 | 020 | -320 | 424 | 12.0571 | 0.752404 | 0.0225721
35124561 | 020 | 020 | -320 | 423 | 12.0604 | 0.761039 | 0.0228312 | Qto_SlabBaseQuantities - Width: 630; Length: 1208
35124572 | 020 | 020 | -320 | 414 | 12.0604 | 0.761039 | 0.0228312 | Qto_SlabBaseQuantities - Width: 630; Length: 1208
35124581 | 020 | 020 | -320 | 426 | 5.44619 | 0.126 | 0.00378 | Qto_SlabBaseQuantities - Width: 200; Length: 630
35124590 | 020 | 020 | -320 | 442 | 5.44619 | 0.126 | 0.00378 | Qto_SlabBaseQuantities - Width: 630; Length: 200
35124607 | 020 | 020 | -320 | 448 | 15.8464 | 1.11623 | 0.0334868
35124620 | 020 | 020 | -320 | 450 | 15.8432 | 1.1154 | 0.0334619
35124633 | 020 | 020 | -320 | 452 | 15.8497 | 1.11646 | 0.0334939
35124646 | 020 | 020 | -320 | 454 | 12.0571 | 0.752403 | 0.0225721
35124663 | 020 | 020 | -320 | 432 | 12.8937 | 0.832206 | 0.0249662
35124677 | 020 | 020 | -320 | 431 | 12.8904 | 0.832416 | 0.0249725
35124691 | 020 | 020 | -320 | 433 | 13.7566 | 0.915574 | 0.0274672
35124705 | 020 | 020 | -320 | 434 | 8.26771 | 0.3969 | 0.011907 | Qto_SlabBaseQuantities - Width: 630; Length: 630
35124714 | 020 | 020 | -320 | 446 | 15.8432 | 1.11591 | 0.0334774
35124727 | 020 | 020 | -320 | 449 | 15.8432 | 1.1154 | 0.0334619
35124740 | 020 | 020 | -320 | 451 | 15.8464 | 1.11623 | 0.0334868
35124753 | 020 | 020 | -320 | 453 | 15.8465 | 1.11623 | 0.0334869
35124766 | 020 | 020 | -320 | 444 | 12.0604 | 0.761038 | 0.0228311 | Qto_SlabBaseQuantities - Width: 1208; Length: 630
35124775 | 020 | 020 | -320 | 455 | 12.0604 | 0.761038 | 0.0228311 | Qto_SlabBaseQuantities - Width: 1208; Length: 630
35124784 | 020 | 020 | -320 | 430 | 12.8904 | 0.832416 | 0.0249725
35124798 | 020 | 020 | -320 | 435 | 13.5597 | 0.896673 | 0.0269002
35124811 | 020 | 020 | -320 | 436 | 15.8464 | 1.11623 | 0.0334868
35124824 | 020 | 020 | -320 | 428 | 7.06367 | 0.272978 | 0.00818933
35124837 | 020 | 020 | -320 | 437 | 15.8431 | 1.11539 | 0.0334616
35124850 | 020 | 020 | -320 | 438 | 15.8464 | 1.1157 | 0.0334711
35124863 | 020 | 020 | -320 | 439 | 15.8464 | 1.11623 | 0.0334868
35124876 | 020 | 020 | -320 | 440 | 7.06365 | 0.272975 | 0.00818924
35124895 | 020 | 020 | -320 | 456 | 8.26771 | 0.3969 | 0.011907 | Qto_SlabBaseQuantities - Width: 630; Length: 630
35124904 | 020 | 020 | -320 | 458 | 8.26771 | 0.3969 | 0.011907 | Qto_SlabBaseQuantities - Width: 630; Length: 630
35124913 | 020 | 020 | -320 | 460 | 15.8432 | 1.11599 | 0.0334796
35124926 | 020 | 020 | -320 | 462 | 15.853 | 1.11633 | 0.03349
35124939 | 020 | 020 | -320 | 461 | 15.8464 | 1.1157 | 0.0334711
35124952 | 020 | 020 | -320 | 463 | 15.8432 | 1.11591 | 0.0334774
35124965 | 020 | 020 | -320 | 457 | 5.44619 | 0.126 | 0.00378 | Qto_SlabBaseQuantities - Width: 630; Length: 200
35124974 | 020 | 020 | -320 | 466 | 5.44619 | 0.126 | 0.00378 | Qto_SlabBaseQuantities - Width: 630; Length: 200
35124983 | 020 | 020 | -320 | 469 | 15.9613 | 1.12673 | 0.0338018
35124996 | 020 | 020 | -320 | 468 | 8.17913 | 0.37955 | 0.0113865
35125009 | 020 | 020 | -320 | 467 | 8.26771 | 0.3969 | 0.011907 | Qto_SlabBaseQuantities - Width: 630; Length: 630
35125018 | 020 | 020 | -320 | 465 | 8.26771 | 0.3969 | 0.011907 | Qto_SlabBaseQuantities - Width: 630; Length: 630
35125027 | 020 | 020 | -320 | 470 | 15.958 | 1.12383 | 0.033715
35125040 | 020 | 020 | -320 | 464 | 7.06364 | 0.272974 | 0.00818922
35125053 | 020 | 020 | -320 | 459 | 7.06364 | 0.272974 | 0.00818922
35125066 | 020 | 020 | -320 | 537 | 16.7716 | 1.62083 | 0.0486249
35125075 | 020 | 020 | -320 | 539 | 17.6575 | 1.80578 | 0.0541735
35125086 | 020 | 020 | -320 | 538 | 17.8347 | 1.81607 | 0.0544821
35125099 | 020 | 020 | -320 | 536 | 7.65421 | 0.329676 | 0.00989028
35125108 | 020 | 020 | -320 | 535 | 12.8937 | 0.832205 | 0.0249661
35125117 | 020 | 020 | -320 | 530 | 8.26771 | 0.3969 | 0.011907 | Qto_SlabBaseQuantities - Width: 630; Length: 630
35125126 | 020 | 020 | -320 | 528 | 8.26771 | 0.3969 | 0.011907 | Qto_SlabBaseQuantities - Width: 630; Length: 630
35125135 | 020 | 020 | -320 | 527 | 12.0531 | 0.752005 | 0.0225602
35125144 | 020 | 020 | -320 | 525 | 16.4337 | 1.10871 | 0.0332614
35125153 | 020 | 020 | -320 | 523 | 12.8937 | 0.832204 | 0.0249661
35125162 | 020 | 020 | -320 | 513 | 8.26771 | 0.3969 | 0.011907 | Qto_SlabBaseQuantities - Width: 630; Length: 630
35125171 | 020 | 020 | -320 | 515 | 8.26771 | 0.3969 | 0.011907 | Qto_SlabBaseQuantities - Width: 630; Length: 630
35125180 | 020 | 020 | -320 | 511 | 12.8937 | 0.835001 | 0.02505
35125189 | 020 | 020 | -320 | 498 | 8.26771 | 0.3969 | 0.011907 | Qto_SlabBaseQuantities - Width: 630; Length: 630
35125198 | 020 | 020 | -320 | 500 | 8.27174 | 0.397286 | 0.0119186 | Qto_SlabBaseQuantities - Width: 630; Length: 630.613
35125207 | 020 | 020 | -320 | 496 | 12.0571 | 0.752403 | 0.0225721
35125216 | 020 | 020 | -320 | 494 | 15.8432 | 1.11591 | 0.0334774
35125233 | 020 | 020 | -320 | 534 | 12.8937 | 0.832731 | 0.0249819
35125247 | 020 | 020 | -320 | 532 | 12.8937 | 0.832205 | 0.0249661
35125261 | 020 | 020 | -320 | 529 | 5.4462 | 0.126 | 0.00378001 | Qto_SlabBaseQuantities - Width: 630.001; Length: 200
35125270 | 020 | 020 | -320 | 533 | 12.8904 | 0.832415 | 0.0249724
35125284 | 020 | 020 | -320 | 531 | 7.06364 | 0.272974 | 0.00818923
35125302 | 020 | 020 | -320 | 524 | 15.8472 | 1.11631 | 0.0334894
35125328 | 020 | 020 | -320 | 522 | 12.8937 | 0.832729 | 0.0249819
35125342 | 020 | 020 | -320 | 521 | 12.8904 | 0.832414 | 0.0249724
35125355 | 020 | 020 | -320 | 520 | 12.8937 | 0.832201 | 0.024966
35125369 | 020 | 020 | -320 | 518 | 16.4337 | 1.10871 | 0.0332613
35125378 | 020 | 020 | -320 | 519 | 15.8432 | 1.11592 | 0.0334775
35125401 | 020 | 020 | -320 | 516 | 12.0571 | 0.752404 | 0.0225721
35125414 | 020 | 020 | -320 | 517 | 12.0604 | 0.761039 | 0.0228312 | Qto_SlabBaseQuantities - Width: 1208; Length: 630
35125425 | 020 | 020 | -320 | 526 | 12.0604 | 0.761039 | 0.0228312 | Qto_SlabBaseQuantities - Width: 1208; Length: 630
35125434 | 020 | 020 | -320 | 514 | 5.44619 | 0.126 | 0.00378 | Qto_SlabBaseQuantities - Width: 630; Length: 200
35125443 | 020 | 020 | -320 | 499 | 5.67585 | 0.14805 | 0.0044415 | Qto_SlabBaseQuantities - Width: 235; Length: 630
35125460 | 020 | 020 | -320 | 493 | 15.8464 | 1.11623 | 0.0334868
35125473 | 020 | 020 | -320 | 491 | 15.8464 | 1.11571 | 0.0334713
35125486 | 020 | 020 | -320 | 489 | 15.8432 | 1.11591 | 0.0334774
35125499 | 020 | 020 | -320 | 487 | 12.0571 | 0.752403 | 0.0225721
35125516 | 020 | 020 | -320 | 508 | 12.8937 | 0.835001 | 0.02505
35125530 | 020 | 020 | -320 | 509 | 12.8904 | 0.832416 | 0.0249725
35125544 | 020 | 020 | -320 | 507 | 13.5598 | 0.896681 | 0.0269004
35125558 | 020 | 020 | -320 | 506 | 8.26771 | 0.3969 | 0.011907 | Qto_SlabBaseQuantities - Width: 630; Length: 630
35125567 | 020 | 020 | -320 | 495 | 15.8432 | 1.11591 | 0.0334774
35125580 | 020 | 020 | -320 | 492 | 15.8432 | 1.11539 | 0.0334616
35125593 | 020 | 020 | -320 | 490 | 15.8431 | 1.11591 | 0.0334773
35125606 | 020 | 020 | -320 | 488 | 15.8432 | 1.11599 | 0.0334796
35125619 | 020 | 020 | -320 | 497 | 12.0604 | 0.761038 | 0.0228311 | Qto_SlabBaseQuantities - Width: 630; Length: 1208
35125628 | 020 | 020 | -320 | 486 | 12.0604 | 0.761038 | 0.0228311 | Qto_SlabBaseQuantities - Width: 630; Length: 1208
35125637 | 020 | 020 | -320 | 510 | 12.8904 | 0.832416 | 0.0249725
35125651 | 020 | 020 | -320 | 505 | 13.6909 | 0.909274 | 0.0272782
35125664 | 020 | 020 | -320 | 504 | 15.8464 | 1.11623 | 0.0334868
35125677 | 020 | 020 | -320 | 512 | 7.06367 | 0.272978 | 0.00818933
35125690 | 020 | 020 | -320 | 503 | 15.8431 | 1.11539 | 0.0334616
35125703 | 020 | 020 | -320 | 502 | 15.8464 | 1.1157 | 0.0334711
35125716 | 020 | 020 | -320 | 501 | 15.8431 | 1.11591 | 0.0334773
35125729 | 020 | 020 | -320 |  | 7.06365 | 0.272975 | 0.00818924
35125748 | 020 | 020 | -320 | 485 | 8.26771 | 0.3969 | 0.011907 | Qto_SlabBaseQuantities - Width: 630; Length: 630
35125757 | 020 | 020 | -320 | 483 | 8.26771 | 0.3969 | 0.011907 | Qto_SlabBaseQuantities - Width: 630; Length: 630
35125766 | 020 | 020 | -320 | 481 | 15.8432 | 1.11599 | 0.0334796
35125779 | 020 | 020 | -320 | 479 | 15.8399 | 1.11507 | 0.0334522
35125792 | 020 | 020 | -320 | 480 | 15.8464 | 1.1157 | 0.0334711
35125805 | 020 | 020 | -320 | 478 | 15.8497 | 1.11655 | 0.0334964
35125818 | 020 | 020 | -320 | 484 | 5.44619 | 0.126 | 0.00378 | Qto_SlabBaseQuantities - Width: 200; Length: 630
35125827 | 020 | 020 | -320 | 475 | 5.44619 | 0.126 | 0.00378 | Qto_SlabBaseQuantities - Width: 200; Length: 630
35125836 | 020 | 020 | -320 | 472 | 15.9613 | 1.12673 | 0.0338018
35125849 | 020 | 020 | -320 | 473 | 8.17913 | 0.37955 | 0.0113865
35125862 | 020 | 020 | -320 | 474 | 8.26771 | 0.3969 | 0.011907 | Qto_SlabBaseQuantities - Width: 630; Length: 630
35125871 | 020 | 020 | -320 | 476 | 8.26771 | 0.3969 | 0.011907 | Qto_SlabBaseQuantities - Width: 630; Length: 630
35125880 | 020 | 020 | -320 | 471 | 15.958 | 1.12383 | 0.033715
35125893 | 020 | 020 | -320 | 477 | 7.06364 | 0.272974 | 0.00818922
35125906 | 020 | 020 | -320 | 482 | 7.06364 | 0.272974 | 0.00818922
35128406 | 030 | 030 | -320 | 603 | 16.7815 | 1.6215 | 0.048645
35128415 | 030 | 030 | -320 | 601 | 17.6575 | 1.78553 | 0.0535659
35128426 | 030 | 030 | -320 | 602 | 17.7362 | 1.81022 | 0.0543066
35128439 | 030 | 030 | -320 | 604 | 7.65421 | 0.337216 | 0.0101165
35128448 | 030 | 030 | -320 | 605 | 12.8937 | 0.839745 | 0.0251923
35128457 | 030 | 030 | -320 | 610 | 8.26771 | 0.3969 | 0.011907 | Qto_SlabBaseQuantities - Width: 630; Length: 630
35128466 | 030 | 030 | -320 | 612 | 8.26771 | 0.3969 | 0.011907 | Qto_SlabBaseQuantities - Width: 630; Length: 630
35128475 | 030 | 030 | -320 | 613 | 12.0571 | 0.759944 | 0.0227983
35128484 | 030 | 030 | -320 | 615 | 16.4337 | 1.11625 | 0.0334876
35128493 | 030 | 030 | -320 | 617 | 12.8937 | 0.839744 | 0.0251923
35128502 | 030 | 030 | -320 | 627 | 8.26771 | 0.3969 | 0.011907 | Qto_SlabBaseQuantities - Width: 630; Length: 630
35128511 | 030 | 030 | -320 | 625 | 8.26771 | 0.3969 | 0.011907 | Qto_SlabBaseQuantities - Width: 630; Length: 630
35128520 | 030 | 030 | -320 | 629 | 12.8937 | 0.839746 | 0.0251924
35128529 | 030 | 030 | -320 | 643 | 8.26771 | 0.3969 | 0.011907 | Qto_SlabBaseQuantities - Width: 630; Length: 630
35128538 | 030 | 030 | -320 | 641 | 8.26771 | 0.3969 | 0.011907 | Qto_SlabBaseQuantities - Width: 630; Length: 630
35128547 | 030 | 030 | -320 | 645 | 12.0571 | 0.752403 | 0.0225721
35128556 | 030 | 030 | -320 | 647 | 15.8497 | 1.11654 | 0.0334961
35128573 | 030 | 030 | -320 | 606 | 12.8904 | 0.839954 | 0.0251986
35128587 | 030 | 030 | -320 | 608 | 12.8937 | 0.839745 | 0.0251923
35128601 | 030 | 030 | -320 | 611 | 5.44619 | 0.126 | 0.00378 | Qto_SlabBaseQuantities - Width: 200; Length: 630
35128610 | 030 | 030 | -320 | 607 | 12.8904 | 0.839955 | 0.0251986
35128624 | 030 | 030 | -320 | 609 | 7.06364 | 0.280514 | 0.00841543
35128642 | 030 | 030 | -320 | 616 | 15.8465 | 1.12377 | 0.0337131
35128668 | 030 | 030 | -320 | 618 | 12.8937 | 0.840269 | 0.0252081
35128682 | 030 | 030 | -320 | 619 | 12.8904 | 0.839954 | 0.0251986
35128695 | 030 | 030 | -320 | 620 | 12.8937 | 0.839741 | 0.0251922
35128709 | 030 | 030 | -320 | 622 | 16.4337 | 1.11625 | 0.0334875
35128718 | 030 | 030 | -320 | 621 | 15.8432 | 1.12346 | 0.0337037
35128741 | 030 | 030 | -320 | 624 | 12.0604 | 0.760259 | 0.0228078
35128754 | 030 | 030 | -320 | 623 | 12.0604 | 0.761039 | 0.0228312 | Qto_SlabBaseQuantities - Width: 630; Length: 1208
35128765 | 030 | 030 | -320 | 614 | 12.0604 | 0.761039 | 0.0228312 | Qto_SlabBaseQuantities - Width: 630; Length: 1208
35128774 | 030 | 030 | -320 | 626 | 5.44619 | 0.126 | 0.00378 | Qto_SlabBaseQuantities - Width: 200; Length: 630
35128783 | 030 | 030 | -320 | 642 | 5.44619 | 0.126 | 0.00378 | Qto_SlabBaseQuantities - Width: 630; Length: 200
35128800 | 030 | 030 | -320 | 648 | 15.8464 | 1.11623 | 0.0334868
35128813 | 030 | 030 | -320 | 650 | 15.8432 | 1.1154 | 0.0334619
35128826 | 030 | 030 | -320 | 652 | 15.8497 | 1.11646 | 0.0334939
35128839 | 030 | 030 | -320 | 654 | 12.0571 | 0.752403 | 0.0225721
35128856 | 030 | 030 | -320 | 632 | 12.8937 | 0.839746 | 0.0251924
35128870 | 030 | 030 | -320 | 631 | 12.8904 | 0.839956 | 0.0251987
35128884 | 030 | 030 | -320 | 633 | 13.7566 | 0.923114 | 0.0276934
35128898 | 030 | 030 | -320 | 634 | 8.26771 | 0.3969 | 0.011907 | Qto_SlabBaseQuantities - Width: 630; Length: 630
35128907 | 030 | 030 | -320 | 646 | 15.8432 | 1.11591 | 0.0334774
35128920 | 030 | 030 | -320 | 649 | 15.8432 | 1.1154 | 0.0334619
35128933 | 030 | 030 | -320 | 651 | 15.8464 | 1.11623 | 0.0334868
35128946 | 030 | 030 | -320 | 653 | 15.8465 | 1.11623 | 0.0334869
35128959 | 030 | 030 | -320 | 644 | 12.0604 | 0.761038 | 0.0228311 | Qto_SlabBaseQuantities - Width: 1208; Length: 630
35128968 | 030 | 030 | -320 | 655 | 12.0604 | 0.761038 | 0.0228311 | Qto_SlabBaseQuantities - Width: 1208; Length: 630
35128977 | 030 | 030 | -320 | 630 | 12.8904 | 0.839956 | 0.0251987
35128991 | 030 | 030 | -320 | 635 | 13.5597 | 0.904214 | 0.0271264
35129004 | 030 | 030 | -320 | 636 | 15.8464 | 1.12377 | 0.033713
35129017 | 030 | 030 | -320 | 628 | 7.06367 | 0.280518 | 0.00841553
35129030 | 030 | 030 | -320 | 637 | 15.8431 | 1.12423 | 0.033727 | Qto_SlabBaseQuantities - Width: 1784.5; Length: 630
35129043 | 030 | 030 | -320 | 638 | 15.8464 | 1.12455 | 0.0337364 | Qto_SlabBaseQuantities - Width: 1785; Length: 630
35129056 | 030 | 030 | -320 | 639 | 15.8464 | 1.11623 | 0.0334868
35129069 | 030 | 030 | -320 | 640 | 7.06365 | 0.272975 | 0.00818924
35129088 | 030 | 030 | -320 | 656 | 8.26771 | 0.3969 | 0.011907 | Qto_SlabBaseQuantities - Width: 630; Length: 630
35129097 | 030 | 030 | -320 | 658 | 8.26771 | 0.3969 | 0.011907 | Qto_SlabBaseQuantities - Width: 630; Length: 630
35129106 | 030 | 030 | -320 | 660 | 15.8432 | 1.11599 | 0.0334796
35129119 | 030 | 030 | -320 | 662 | 15.853 | 1.11633 | 0.03349
35129132 | 030 | 030 | -320 | 661 | 15.8464 | 1.1157 | 0.0334711
35129145 | 030 | 030 | -320 | 663 | 15.8432 | 1.11591 | 0.0334774
35129158 | 030 | 030 | -320 | 657 | 5.44619 | 0.126 | 0.00378 | Qto_SlabBaseQuantities - Width: 630; Length: 200
35129167 | 030 | 030 | -320 | 666 | 5.44619 | 0.126 | 0.00378 | Qto_SlabBaseQuantities - Width: 630; Length: 200
35129176 | 030 | 030 | -320 | 669 | 15.9613 | 1.12673 | 0.0338018
35129189 | 030 | 030 | -320 | 668 | 8.17913 | 0.37955 | 0.0113865
35129202 | 030 | 030 | -320 | 667 | 8.26771 | 0.3969 | 0.011907 | Qto_SlabBaseQuantities - Width: 630; Length: 630
35129211 | 030 | 030 | -320 | 665 | 8.26771 | 0.3969 | 0.011907 | Qto_SlabBaseQuantities - Width: 630; Length: 630
35129220 | 030 | 030 | -320 | 670 | 15.958 | 1.12383 | 0.033715
35129233 | 030 | 030 | -320 | 664 | 7.06364 | 0.272974 | 0.00818922
35129246 | 030 | 030 | -320 | 659 | 7.06364 | 0.272974 | 0.00818922
35129259 | 030 | 030 | -320 | 738 | 16.7716 | 1.62533 | 0.0487598
35129268 | 030 | 030 | -320 | 740 | 17.6575 | 1.78778 | 0.0536334
35129279 | 030 | 030 | -320 | 739 | 17.7362 | 1.81022 | 0.0543066
35129292 | 030 | 030 | -320 | 737 | 7.65421 | 0.337216 | 0.0101165
35129301 | 030 | 030 | -320 | 736 | 12.8937 | 0.839745 | 0.0251923
35129310 | 030 | 030 | -320 | 731 | 8.26771 | 0.3969 | 0.011907 | Qto_SlabBaseQuantities - Width: 630; Length: 630
35129319 | 030 | 030 | -320 | 729 | 8.26771 | 0.3969 | 0.011907 | Qto_SlabBaseQuantities - Width: 630; Length: 630
35129328 | 030 | 030 | -320 | 728 | 12.0531 | 0.759559 | 0.0227868
35129337 | 030 | 030 | -320 | 726 | 16.4337 | 1.11625 | 0.0334876
35129346 | 030 | 030 | -320 | 724 | 12.8937 | 0.839744 | 0.0251923
35129355 | 030 | 030 | -320 | 714 | 8.26771 | 0.3969 | 0.011907 | Qto_SlabBaseQuantities - Width: 630; Length: 630
35129364 | 030 | 030 | -320 | 716 | 8.26771 | 0.3969 | 0.011907 | Qto_SlabBaseQuantities - Width: 630; Length: 630
35129373 | 030 | 030 | -320 | 712 | 12.8937 | 0.839746 | 0.0251924
35129382 | 030 | 030 | -320 | 698 | 8.26771 | 0.3969 | 0.011907 | Qto_SlabBaseQuantities - Width: 630; Length: 630
35129391 | 030 | 030 | -320 | 700 | 8.27174 | 0.397286 | 0.0119186 | Qto_SlabBaseQuantities - Width: 630; Length: 630.613
35129400 | 030 | 030 | -320 | 696 | 12.0571 | 0.752403 | 0.0225721
35129409 | 030 | 030 | -320 | 694 | 15.8432 | 1.11591 | 0.0334774
35129426 | 030 | 030 | -320 | 735 | 12.8937 | 0.840271 | 0.0252081
35129440 | 030 | 030 | -320 | 733 | 12.8937 | 0.839745 | 0.0251923
35129454 | 030 | 030 | -320 | 730 | 5.4462 | 0.126 | 0.00378001 | Qto_SlabBaseQuantities - Width: 630.001; Length: 200
35129463 | 030 | 030 | -320 | 734 | 12.8904 | 0.839955 | 0.0251986
35129477 | 030 | 030 | -320 | 732 | 7.06364 | 0.280514 | 0.00841543
35129495 | 030 | 030 | -320 | 725 | 15.8472 | 1.12384 | 0.0337152
35129521 | 030 | 030 | -320 | 723 | 12.8937 | 0.840269 | 0.0252081
35129535 | 030 | 030 | -320 | 722 | 12.8904 | 0.839954 | 0.0251986
35129548 | 030 | 030 | -320 | 721 | 12.8937 | 0.839741 | 0.0251922
35129562 | 030 | 030 | -320 | 719 | 16.4337 | 1.11625 | 0.0334875
35129571 | 030 | 030 | -320 | 720 | 15.8432 | 1.12346 | 0.0337037
35129594 | 030 | 030 | -320 | 717 | 12.0604 | 0.760265 | 0.0228079
35129607 | 030 | 030 | -320 | 718 | 12.0571 | 0.760722 | 0.0228217 | Qto_SlabBaseQuantities - Width: 1207.5; Length: 630
35129618 | 030 | 030 | -320 | 727 | 12.0604 | 0.761039 | 0.0228312 | Qto_SlabBaseQuantities - Width: 1208; Length: 630
35129627 | 030 | 030 | -320 | 715 | 5.44619 | 0.126 | 0.00378 | Qto_SlabBaseQuantities - Width: 630; Length: 200
35129636 | 030 | 030 | -320 | 699 | 5.67585 | 0.14805 | 0.0044415 | Qto_SlabBaseQuantities - Width: 235; Length: 630
35129653 | 030 | 030 | -320 | 693 | 15.8464 | 1.11623 | 0.0334868
35129666 | 030 | 030 | -320 | 691 | 15.8464 | 1.11571 | 0.0334713
35129679 | 030 | 030 | -320 | 689 | 15.8432 | 1.11591 | 0.0334774
35129692 | 030 | 030 | -320 | 687 | 12.0571 | 0.752403 | 0.0225721
35129709 | 030 | 030 | -320 | 709 | 12.8937 | 0.839746 | 0.0251924
35129723 | 030 | 030 | -320 | 710 | 12.8904 | 0.832416 | 0.0249725
35129737 | 030 | 030 | -320 | 708 | 13.5598 | 0.896681 | 0.0269004
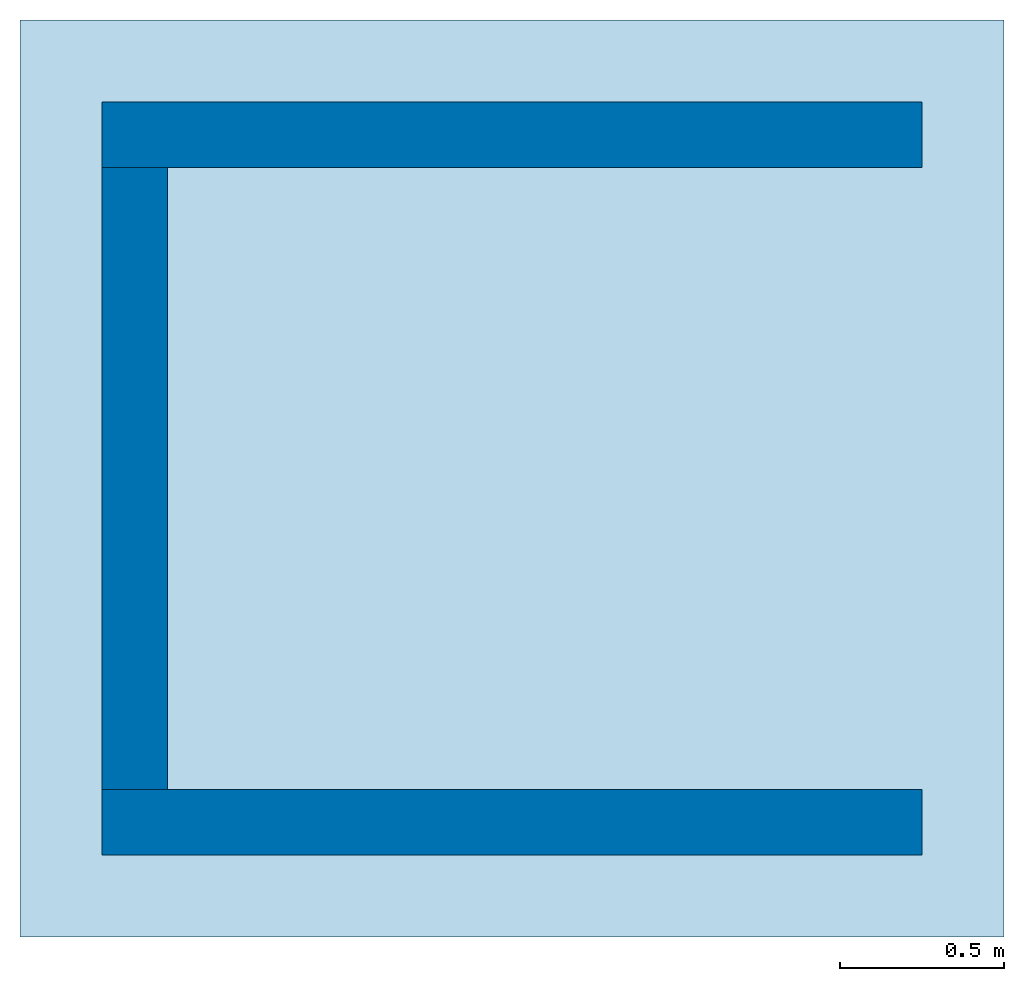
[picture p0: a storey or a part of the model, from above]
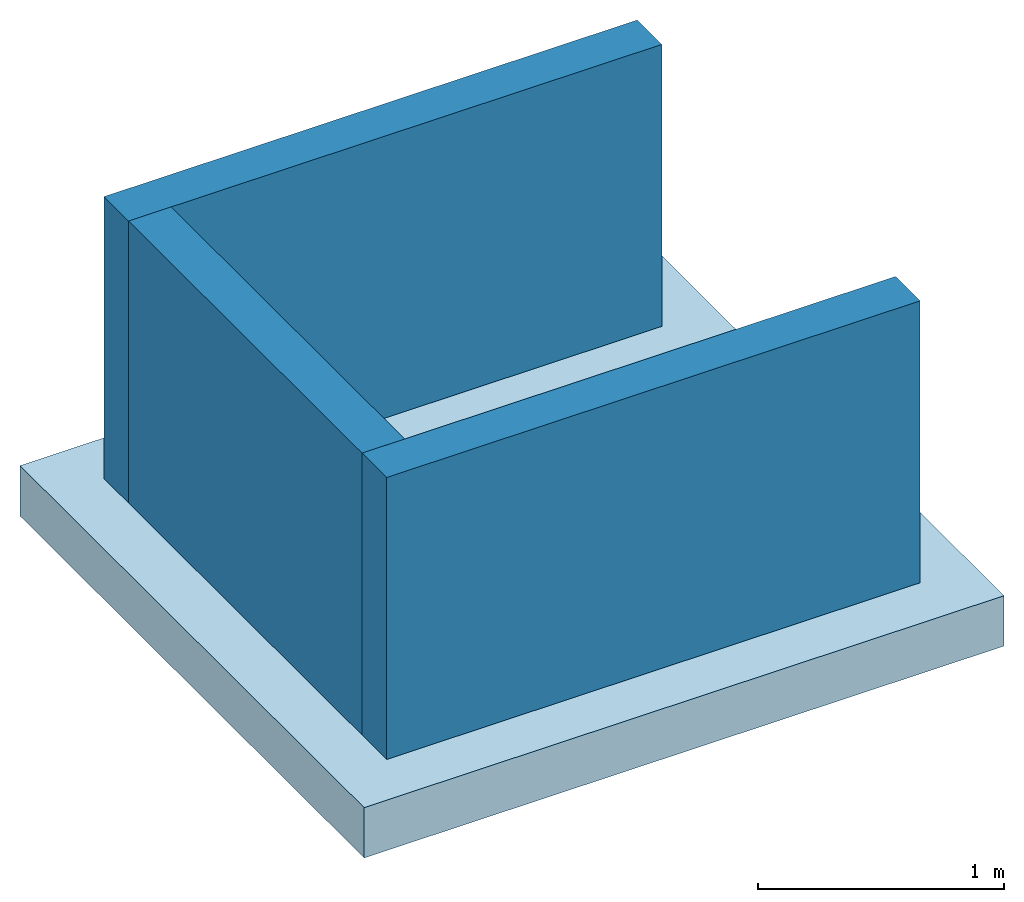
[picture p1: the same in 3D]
Properties of the parts of a building model (IFC4X3_ADD2), part 17 of 28

# IfcSlab: Steel, Galvanized - looprooster 30 (560)
Name (Floor:GVH - Looprooster 30 mm:...) | In | Level | Height Offset From Level | Tag = Mark | Perimeter | GrossArea | GrossVolume = NetVolume
35129751 | 030 | 030 | -320 | 707 | 8.26771 | 0.3969 | 0.011907 | Qto_SlabBaseQuantities - Width: 630; Length: 630
35129760 | 030 | 030 | -320 | 695 | 15.8432 | 1.11591 | 0.0334774
35129773 | 030 | 030 | -320 | 692 | 15.8432 | 1.11539 | 0.0334616
35129786 | 030 | 030 | -320 | 690 | 15.8431 | 1.11591 | 0.0334773
35129799 | 030 | 030 | -320 | 688 | 15.8432 | 1.11599 | 0.0334796
35129812 | 030 | 030 | -320 | 697 | 12.0604 | 0.761038 | 0.0228311 | Qto_SlabBaseQuantities - Width: 630; Length: 1208
35129821 | 030 | 030 | -320 | 686 | 12.0604 | 0.761038 | 0.0228311 | Qto_SlabBaseQuantities - Width: 630; Length: 1208
35129830 | 030 | 030 | -320 | 711 | 12.8904 | 0.839956 | 0.0251987
35129844 | 030 | 030 | -320 | 706 | 13.6909 | 0.909274 | 0.0272782
35129857 | 030 | 030 | -320 | 705 | 15.8464 | 1.11623 | 0.0334868
35129870 | 030 | 030 | -320 | 713 | 7.06367 | 0.280518 | 0.00841553
35129883 | 030 | 030 | -320 | 704 | 15.8431 | 1.12293 | 0.0336878
35129896 | 030 | 030 | -320 | 703 | 15.8464 | 1.12324 | 0.0336973
35129909 | 030 | 030 | -320 | 702 | 15.8431 | 1.11591 | 0.0334773
35129922 | 030 | 030 | -320 | 701 | 7.06365 | 0.272975 | 0.00818924
35129941 | 030 | 030 | -320 | 685 | 8.26771 | 0.3969 | 0.011907 | Qto_SlabBaseQuantities - Width: 630; Length: 630
35129950 | 030 | 030 | -320 | 683 | 8.26771 | 0.3969 | 0.011907 | Qto_SlabBaseQuantities - Width: 630; Length: 630
35129959 | 030 | 030 | -320 | 681 | 15.8432 | 1.11599 | 0.0334796
35129972 | 030 | 030 | -320 | 679 | 15.8399 | 1.11507 | 0.0334522
35129985 | 030 | 030 | -320 | 680 | 15.8464 | 1.1157 | 0.0334711
35129998 | 030 | 030 | -320 | 678 | 15.8497 | 1.11655 | 0.0334964
35130011 | 030 | 030 | -320 | 684 | 5.44619 | 0.126 | 0.00378 | Qto_SlabBaseQuantities - Width: 200; Length: 630
35130020 | 030 | 030 | -320 | 675 | 5.44619 | 0.126 | 0.00378 | Qto_SlabBaseQuantities - Width: 200; Length: 630
35130029 | 030 | 030 | -320 | 672 | 15.9613 | 1.12673 | 0.0338018
35130042 | 030 | 030 | -320 | 673 | 8.17913 | 0.37955 | 0.0113865
35130055 | 030 | 030 | -320 | 674 | 8.26771 | 0.3969 | 0.011907 | Qto_SlabBaseQuantities - Width: 630; Length: 630
35130064 | 030 | 030 | -320 | 676 | 8.26771 | 0.3969 | 0.011907 | Qto_SlabBaseQuantities - Width: 630; Length: 630
35130073 | 030 | 030 | -320 | 671 | 15.958 | 1.12383 | 0.033715
35130086 | 030 | 030 | -320 | 677 | 7.06364 | 0.272974 | 0.00818922
35130099 | 030 | 030 | -320 | 682 | 7.06364 | 0.272974 | 0.00818922
35133187 | 040 | 040 | -320 | 802 | 13.0052 | 0.850484 | 0.0255145
35133239 | 040 | 040 | -320 | 801 | 13.4974 | 0.834808 | 0.0250442
35133270 | 040 | 040 | -320 | 804 | 12.8937 | 0.840271 | 0.0252081
35133553 | 040 | 040 | -320 | 803 | 12.8937 | 0.840271 | 0.0252081
35133590 | 040 | 040 | -320 | 806 | 15.8465 | 1.12377 | 0.0337131
35133602 | 040 | 040 | -320 | 805 | 15.8464 | 1.12377 | 0.0337131
35133734 | 040 | 040 | -320 | 808 | 15.8465 | 1.12377 | 0.0337131
35133746 | 040 | 040 | -320 | 807 | 15.8464 | 1.12377 | 0.0337131
35133785 | 040 | 040 | -320 | 811 | 15.8727 | 1.12629 | 0.0337887
35133797 | 040 | 040 | -320 | 810 | 15.8727 | 1.12707 | 0.0338121 | Qto_SlabBaseQuantities - Width: 630; Length: 1789
35133894 | 040 | 040 | -320 | 809 | 15.8727 | 1.12576 | 0.0337729
35133942 | 040 | 040 | -320 | 813 | 15.8465 | 1.12325 | 0.0336974
35133999 | 040 | 040 | -320 | 812 | 15.8464 | 1.12377 | 0.0337131
35134050 | 040 | 040 | -320 | 815 | 15.8465 | 1.12377 | 0.0337131
35134062 | 040 | 040 | -320 | 814 | 15.8464 | 1.12377 | 0.0337131
35134135 | 040 | 040 | -320 | 817 | 12.8937 | 0.840271 | 0.0252081
35134194 | 040 | 040 | -320 | 816 | 12.8937 | 0.840269 | 0.0252081
35134237 | 040 | 040 | -320 | 819 | 12.8937 | 0.840271 | 0.0252081
35134249 | 040 | 040 | -320 | 818 | 12.8937 | 0.840269 | 0.0252081
35134300 | 040 | 040 | -320 | 820 | 7.85104 | 0.356114 | 0.0106834
35134353 | 040 | 040 | -320 | 821 | 8.26771 | 0.3969 | 0.011907 | Qto_SlabBaseQuantities - Width: 630; Length: 630
35134414 | 040 | 040 | -320 | 822 | 11.7979 | 0.735838 | 0.0220752 | Qto_SlabBaseQuantities - Width: 1168; Length: 630
35134453 | 040 | 040 | -320 | 823 | 11.8012 | 0.735376 | 0.0220613
35134511 | 040 | 040 | -320 | 824 | 15.8464 | 1.12377 | 0.0337131
35134523 | 040 | 040 | -320 | 825 | 15.8465 | 1.12377 | 0.0337131
35134624 | 040 | 040 | -320 | 826 | 15.8464 | 1.12377 | 0.0337131
35134636 | 040 | 040 | -320 | 827 | 15.8465 | 1.12377 | 0.0337131
35134677 | 040 | 040 | -320 | 828 | 15.8464 | 1.12377 | 0.0337131
35134689 | 040 | 040 | -320 | 829 | 15.8465 | 1.12325 | 0.0336974
35134728 | 040 | 040 | -320 | 830 | 15.8464 | 1.12324 | 0.0336973
35134740 | 040 | 040 | -320 | 831 | 15.8465 | 1.12377 | 0.0337131
35134781 | 040 | 040 | -320 | 832 | 15.8464 | 1.12377 | 0.0337131
35134793 | 040 | 040 | -320 | 833 | 15.8465 | 1.12377 | 0.0337131
35134836 | 040 | 040 | -320 | 834 | 15.8464 | 1.12377 | 0.0337131
35134848 | 040 | 040 | -320 | 835 | 15.8465 | 1.12377 | 0.0337131
35134887 | 040 | 040 | -320 | 836 | 15.8464 | 1.12377 | 0.0337131
35134899 | 040 | 040 | -320 | 837 | 15.8465 | 1.12377 | 0.0337131
35134940 | 040 | 040 | -320 | 838 | 15.8464 | 1.12377 | 0.0337131
35134952 | 040 | 040 | -320 | 839 | 15.8465 | 1.12377 | 0.0337131
35134993 | 040 | 040 | -320 | 841 | 15.958 | 1.13448 | 0.0340344
35135005 | 040 | 040 | -320 | 842 | 15.958 | 1.13395 | 0.0340186
35135098 | 040 | 040 | -320 | 840 | 15.748 | 1.11354 | 0.0334062
35135156 | 040 | 040 | -320 | 883 | 13.0052 | 0.850484 | 0.0255145
35135168 | 040 | 040 | -320 | 884 | 13.4974 | 0.834808 | 0.0250442
35135178 | 040 | 040 | -320 | 881 | 12.8937 | 0.840271 | 0.0252081
35135198 | 040 | 040 | -320 | 882 | 12.8937 | 0.840271 | 0.0252081
35135210 | 040 | 040 | -320 | 879 | 15.8465 | 1.12377 | 0.0337131
35135222 | 040 | 040 | -320 | 880 | 15.8464 | 1.12377 | 0.0337131
35135234 | 040 | 040 | -320 | 877 | 15.8465 | 1.12377 | 0.0337131
35135246 | 040 | 040 | -320 | 878 | 15.8464 | 1.12377 | 0.0337131
35135258 | 040 | 040 | -320 | 874 | 15.8727 | 1.12629 | 0.0337887
35135270 | 040 | 040 | -320 | 875 | 15.8727 | 1.12707 | 0.0338121 | Qto_SlabBaseQuantities - Width: 1789; Length: 630
35135280 | 040 | 040 | -320 | 876 | 15.8727 | 1.12576 | 0.0337729
35135292 | 040 | 040 | -320 | 872 | 15.8465 | 1.12325 | 0.0336974
35135304 | 040 | 040 | -320 | 873 | 15.8464 | 1.12377 | 0.0337131
35135316 | 040 | 040 | -320 | 870 | 15.8465 | 1.12377 | 0.0337131
35135328 | 040 | 040 | -320 | 871 | 15.8464 | 1.12377 | 0.0337131
35135340 | 040 | 040 | -320 | 868 | 12.8937 | 0.840271 | 0.0252081
35135352 | 040 | 040 | -320 | 869 | 12.8937 | 0.840269 | 0.0252081
35135364 | 040 | 040 | -320 | 866 | 12.8937 | 0.840271 | 0.0252081
35135376 | 040 | 040 | -320 | 867 | 12.8937 | 0.840269 | 0.0252081
35135388 | 040 | 040 | -320 | 865 | 7.42456 | 0.315167 | 0.00945502
35135400 | 040 | 040 | -320 | 864 | 8.26772 | 0.3969 | 0.011907 | Qto_SlabBaseQuantities - Width: 630; Length: 630
35135410 | 040 | 040 | -320 | 863 | 11.8669 | 0.742748 | 0.0222824 | Qto_SlabBaseQuantities - Width: 630.517; Length: 1178
35135420 | 040 | 040 | -320 | 862 | 11.8669 | 0.741941 | 0.0222582
35135432 | 040 | 040 | -320 | 861 | 15.8498 | 1.12466 | 0.0337399
35135444 | 040 | 040 | -320 | 860 | 15.8499 | 1.12467 | 0.0337402
35135456 | 040 | 040 | -320 | 859 | 15.8498 | 1.12467 | 0.0337401
35135468 | 040 | 040 | -320 | 858 | 15.8499 | 1.12468 | 0.0337404
35135480 | 040 | 040 | -320 | 857 | 15.8498 | 1.12467 | 0.0337402
35135492 | 040 | 040 | -320 | 856 | 15.8499 | 1.12417 | 0.0337251
35135504 | 040 | 040 | -320 | 855 | 15.8498 | 1.12416 | 0.0337249
35135516 | 040 | 040 | -320 | 854 | 15.8499 | 1.12468 | 0.0337405
35135528 | 040 | 040 | -320 | 853 | 15.8498 | 1.12468 | 0.0337403
35135540 | 040 | 040 | -320 | 852 | 15.8499 | 1.12469 | 0.0337407
35135552 | 040 | 040 | -320 | 851 | 15.8498 | 1.12468 | 0.0337405
35135564 | 040 | 040 | -320 | 850 | 15.8499 | 1.12469 | 0.0337407
35135576 | 040 | 040 | -320 | 849 | 15.8498 | 1.12468 | 0.0337405
35135588 | 040 | 040 | -320 | 848 | 15.8499 | 1.12469 | 0.0337408
35135600 | 040 | 040 | -320 | 847 | 15.8498 | 1.12469 | 0.0337406
35135612 | 040 | 040 | -320 | 846 | 15.8499 | 1.12469 | 0.0337408
35135624 | 040 | 040 | -320 | 844 | 15.9614 | 1.13541 | 0.0340622
35135636 | 040 | 040 | -320 | 843 | 15.9614 | 1.13491 | 0.0340472
35135648 | 040 | 040 | -320 | 845 | 15.7514 | 1.11445 | 0.0334336

# IfcSlab: vezelcementplaat 1250 x 10:vezelcementplaat 1250 x 625, vezelcementplaat 1250 x 10:vezelcementplaat 1250 x 625:33947532:1
In: 050
PredefinedType: ROOF
Cpset_Slab - LevelOfAccuracy: in te vullen door Buildwise
IfcBuildingStorey - Elevation from Level: 1342.37
IfcClassificationReference - TDS_link: .\05 As Builtdossier\2. Bouwkunde\2.1 Architectuur\2.1.5 dakwerken en dakwaterafvoer\2.1.5.1 dakwerken (Tectum)\TF A 05.01.91.01 A - onderdak van hellend dak.pdf
IfcRoot - Name: vezelcementplaat 1250 x 625
Qto_SlabBaseQuantities - Width: 23.8498; Length: 625; Perimeter: 2547.7; GrossArea: 0.0298123; GrossVolume: 0.0186327; NetVolume: 0.0186327; Depth: 1250
Pset_ConcreteElementGeneral - ConstructionMethod: prefabricated
Pset_Condition - AssessmentCondition: Empty
Pset_EnvironmentalImpactIndicators - Reference: vezelcementplaat 1250 x 625; sets with these values: 2
Pset_SlabCommon - Reference: vezelcementplaat 1250 x 625; FireRating: EI 60; IsExternal: yes

# IfcSlab: vezelcementplaat 1250 x 11:vezelcementplaat 1250 x 625, vezelcementplaat 1250 x 11:vezelcementplaat 1250 x 625:33947545:1
In: 050
PredefinedType: ROOF
Cpset_Slab - LevelOfAccuracy: in te vullen door Buildwise
IfcBuildingStorey - Elevation from Level: 1896.38
IfcClassificationReference - TDS_link: .\05 As Builtdossier\2. Bouwkunde\2.1 Architectuur\2.1.5 dakwerken en dakwaterafvoer\2.1.5.1 dakwerken (Tectum)\TF A 05.01.91.01 A - onderdak van hellend dak.pdf
IfcRoot - Name: vezelcementplaat 1250 x 625
Qto_SlabBaseQuantities - Width: 23.8498; Length: 625; Perimeter: 2547.7; GrossArea: 0.0298123; GrossVolume: 0.0186327; NetVolume: 0.0186327; Depth: 1250
Pset_ConcreteElementGeneral - ConstructionMethod: prefabricated
Pset_Condition - AssessmentCondition: Empty
Pset_EnvironmentalImpactIndicators - Reference: vezelcementplaat 1250 x 625; sets with these values: 2
Pset_SlabCommon - Reference: vezelcementplaat 1250 x 625; FireRating: EI 60; IsExternal: yes

# IfcSlab: vezelcementplaat 1250 x 12:vezelcementplaat 1250 x 625, vezelcementplaat 1250 x 12:vezelcementplaat 1250 x 625:33947692:1
In: 050
PredefinedType: ROOF
Cpset_Slab - LevelOfAccuracy: in te vullen door Buildwise
IfcBuildingStorey - Elevation from Level: -317.144
IfcClassificationReference - TDS_link: .\05 As Builtdossier\2. Bouwkunde\2.1 Architectuur\2.1.5 dakwerken en dakwaterafvoer\2.1.5.1 dakwerken (Tectum)\TF A 05.01.91.01 A - onderdak van hellend dak.pdf
IfcRoot - Name: vezelcementplaat 1250 x 625
Qto_SlabBaseQuantities - Width: 23.8498; Length: 625; Perimeter: 2548.22; GrossArea: 0.0298185; GrossVolume: 0.0186366; NetVolume: 0.0186366; Depth: 1250.26
Pset_ConcreteElementGeneral - ConstructionMethod: prefabricated
Pset_Condition - AssessmentCondition: Empty
Pset_EnvironmentalImpactIndicators - Reference: vezelcementplaat 1250 x 625; sets with these values: 2
Pset_SlabCommon - Reference: vezelcementplaat 1250 x 625; FireRating: EI 60; IsExternal: yes

# IfcSlab: vezelcementplaat 1250 x 13:vezelcementplaat 1250 x 625, vezelcementplaat 1250 x 13:vezelcementplaat 1250 x 625:33947793:1
In: 050
PredefinedType: ROOF
Cpset_Slab - LevelOfAccuracy: in te vullen door Buildwise
IfcBuildingStorey - Elevation from Level: -41.5138
IfcClassificationReference - TDS_link: .\05 As Builtdossier\2. Bouwkunde\2.1 Architectuur\2.1.5 dakwerken en dakwaterafvoer\2.1.5.1 dakwerken (Tectum)\TF A 05.01.91.01 A - onderdak van hellend dak.pdf
IfcRoot - Name: vezelcementplaat 1250 x 625
Qto_SlabBaseQuantities - Width: 23.8498; Length: 625; Perimeter: 2548.22; GrossArea: 0.0298185; GrossVolume: 0.0186366; NetVolume: 0.0186366; Depth: 1250.26
Pset_ConcreteElementGeneral - ConstructionMethod: prefabricated
Pset_Condition - AssessmentCondition: Empty
Pset_EnvironmentalImpactIndicators - Reference: vezelcementplaat 1250 x 625; sets with these values: 2
Pset_SlabCommon - Reference: vezelcementplaat 1250 x 625; FireRating: EI 60; IsExternal: yes

# IfcSlab: vezelcementplaat 1250 x 14:vezelcementplaat 1250 x 625, vezelcementplaat 1250 x 14:vezelcementplaat 1250 x 625:33947806:1
In: 050
PredefinedType: ROOF
Cpset_Slab - LevelOfAccuracy: in te vullen door Buildwise
IfcBuildingStorey - Elevation from Level: -41.5138
IfcClassificationReference - TDS_link: .\05 As Builtdossier\2. Bouwkunde\2.1 Architectuur\2.1.5 dakwerken en dakwaterafvoer\2.1.5.1 dakwerken (Tectum)\TF A 05.01.91.01 A - onderdak van hellend dak.pdf
IfcRoot - Name: vezelcementplaat 1250 x 625
Qto_SlabBaseQuantities - Width: 23.8498; Length: 625; Perimeter: 2547.18; GrossArea: 0.029806; GrossVolume: 0.0186288; NetVolume: 0.0186288; Depth: 1249.74
Pset_ConcreteElementGeneral - ConstructionMethod: prefabricated
Pset_Condition - AssessmentCondition: Empty
Pset_EnvironmentalImpactIndicators - Reference: vezelcementplaat 1250 x 625; sets with these values: 2
Pset_SlabCommon - Reference: vezelcementplaat 1250 x 625; FireRating: EI 60; IsExternal: yes

# IfcSlab: vezelcementplaat 1250 x 15:vezelcementplaat 1250 x 625, vezelcementplaat 1250 x 15:vezelcementplaat 1250 x 625:33947819:1
In: 050
PredefinedType: ROOF
Cpset_Slab - LevelOfAccuracy: in te vullen door Buildwise
IfcBuildingStorey - Elevation from Level: 512.497
IfcClassificationReference - TDS_link: .\05 As Builtdossier\2. Bouwkunde\2.1 Architectuur\2.1.5 dakwerken en dakwaterafvoer\2.1.5.1 dakwerken (Tectum)\TF A 05.01.91.01 A - onderdak van hellend dak.pdf
IfcRoot - Name: vezelcementplaat 1250 x 625
Qto_SlabBaseQuantities - Width: 23.8498; Length: 625; Perimeter: 2547.7; GrossArea: 0.0298123; GrossVolume: 0.0186327; NetVolume: 0.0186327; Depth: 1250
Pset_ConcreteElementGeneral - ConstructionMethod: prefabricated
Pset_Condition - AssessmentCondition: Empty
Pset_EnvironmentalImpactIndicators - Reference: vezelcementplaat 1250 x 625; sets with these values: 2
Pset_SlabCommon - Reference: vezelcementplaat 1250 x 625; FireRating: EI 60; IsExternal: yes

# IfcSlab: vezelcementplaat 1250 x 16:vezelcementplaat 1250 x 625, vezelcementplaat 1250 x 16:vezelcementplaat 1250 x 625:33947832:1
In: 050
PredefinedType: ROOF
Cpset_Slab - LevelOfAccuracy: in te vullen door Buildwise
IfcBuildingStorey - Elevation from Level: 1066.51
IfcClassificationReference - TDS_link: .\05 As Builtdossier\2. Bouwkunde\2.1 Architectuur\2.1.5 dakwerken en dakwaterafvoer\2.1.5.1 dakwerken (Tectum)\TF A 05.01.91.01 A - onderdak van hellend dak.pdf
IfcRoot - Name: vezelcementplaat 1250 x 625
Qto_SlabBaseQuantities - Width: 23.8498; Length: 625; Perimeter: 2547.7; GrossArea: 0.0298123; GrossVolume: 0.0186327; NetVolume: 0.0186327; Depth: 1250
Pset_ConcreteElementGeneral - ConstructionMethod: prefabricated
Pset_Condition - AssessmentCondition: Empty
Pset_EnvironmentalImpactIndicators - Reference: vezelcementplaat 1250 x 625; sets with these values: 2
Pset_SlabCommon - Reference: vezelcementplaat 1250 x 625; FireRating: EI 60; IsExternal: yes

# IfcSlab: vezelcementplaat 1250 x 17:vezelcementplaat 1250 x 625, vezelcementplaat 1250 x 17:vezelcementplaat 1250 x 625:33947845:1
In: 050
PredefinedType: ROOF
Cpset_Slab - LevelOfAccuracy: in te vullen door Buildwise
IfcBuildingStorey - Elevation from Level: 1620.52
IfcClassificationReference - TDS_link: .\05 As Builtdossier\2. Bouwkunde\2.1 Architectuur\2.1.5 dakwerken en dakwaterafvoer\2.1.5.1 dakwerken (Tectum)\TF A 05.01.91.01 A - onderdak van hellend dak.pdf
IfcRoot - Name: vezelcementplaat 1250 x 625
Qto_SlabBaseQuantities - Width: 23.8498; Length: 625; Perimeter: 2547.7; GrossArea: 0.0298123; GrossVolume: 0.0186327; NetVolume: 0.0186327; Depth: 1250
Pset_ConcreteElementGeneral - ConstructionMethod: prefabricated
Pset_Condition - AssessmentCondition: Empty
Pset_EnvironmentalImpactIndicators - Reference: vezelcementplaat 1250 x 625; sets with these values: 2
Pset_SlabCommon - Reference: vezelcementplaat 1250 x 625; FireRating: EI 60; IsExternal: yes

# IfcSlab: vezelcementplaat 1250 x 18:vezelcementplaat 1250 x 625, vezelcementplaat 1250 x 18:vezelcementplaat 1250 x 625:33947858:1
In: 050
PredefinedType: ROOF
Cpset_Slab - LevelOfAccuracy: in te vullen door Buildwise
IfcBuildingStorey - Elevation from Level: 0
IfcClassificationReference - TDS_link: .\05 As Builtdossier\2. Bouwkunde\2.1 Architectuur\2.1.5 dakwerken en dakwaterafvoer\2.1.5.1 dakwerken (Tectum)\TF A 05.01.91.01 A - onderdak van hellend dak.pdf
IfcRoot - Name: vezelcementplaat 1250 x 625
Qto_SlabBaseQuantities - Width: 23.8498; Length: 625; Perimeter: 1297.7; GrossArea: 0.0149061; GrossVolume: 0.00931633; NetVolume: 0.00931633; Depth: 625
Pset_ConcreteElementGeneral - ConstructionMethod: prefabricated
Pset_Condition - AssessmentCondition: Empty
Pset_EnvironmentalImpactIndicators - Reference: vezelcementplaat 1250 x 625; sets with these values: 2
Pset_SlabCommon - Reference: vezelcementplaat 1250 x 625; FireRating: EI 60; IsExternal: yes

# IfcSlab: vezelcementplaat 1250 x 19:vezelcementplaat 1250 x 625, vezelcementplaat 1250 x 19:vezelcementplaat 1250 x 625:33947871:1
In: 050
PredefinedType: ROOF
Cpset_Slab - LevelOfAccuracy: in te vullen door Buildwise
IfcBuildingStorey - Elevation from Level: 0
IfcClassificationReference - TDS_link: .\05 As Builtdossier\2. Bouwkunde\2.1 Architectuur\2.1.5 dakwerken en dakwaterafvoer\2.1.5.1 dakwerken (Tectum)\TF A 05.01.91.01 A - onderdak van hellend dak.pdf
IfcRoot - Name: vezelcementplaat 1250 x 625
Qto_SlabBaseQuantities - Width: 23.8498; Length: 625; Perimeter: 1298.22; GrossArea: 0.0149124; GrossVolume: 0.00932022; NetVolume: 0.00932022; Depth: 625.261
Pset_ConcreteElementGeneral - ConstructionMethod: prefabricated
Pset_Condition - AssessmentCondition: Empty
Pset_EnvironmentalImpactIndicators - Reference: vezelcementplaat 1250 x 625; sets with these values: 2
Pset_SlabCommon - Reference: vezelcementplaat 1250 x 625; FireRating: EI 60; IsExternal: yes

# IfcSlab: vezelcementplaat 1250 x 1:vezelcementplaat 1250 x 625, vezelcementplaat 1250 x 1:vezelcementplaat 1250 x 625:33946629:1
In: 050
PredefinedType: ROOF
Cpset_Slab - LevelOfAccuracy: in te vullen door Buildwise
IfcBuildingStorey - Elevation from Level: -41.5138
IfcClassificationReference - TDS_link: .\05 As Builtdossier\2. Bouwkunde\2.1 Architectuur\2.1.5 dakwerken en dakwaterafvoer\2.1.5.1 dakwerken (Tectum)\TF A 05.01.91.01 A - onderdak van hellend dak.pdf
IfcRoot - Name: vezelcementplaat 1250 x 625
Qto_SlabBaseQuantities - Width: 23.8498; Length: 625; Perimeter: 2547.18; GrossArea: 0.029806; GrossVolume: 0.0186288; NetVolume: 0.0186288; Depth: 1249.74
Pset_ConcreteElementGeneral - ConstructionMethod: prefabricated
Pset_Condition - AssessmentCondition: Empty
Pset_EnvironmentalImpactIndicators - Reference: vezelcementplaat 1250 x 625; sets with these values: 2
Pset_SlabCommon - Reference: vezelcementplaat 1250 x 625; FireRating: EI 60; IsExternal: yes

# IfcSlab: vezelcementplaat 1250 x 20:vezelcementplaat 1250 x 625, vezelcementplaat 1250 x 20:vezelcementplaat 1250 x 625:33947884:1
In: 050
PredefinedType: ROOF
Cpset_Slab - LevelOfAccuracy: in te vullen door Buildwise
IfcBuildingStorey - Elevation from Level: 234.347
IfcClassificationReference - TDS_link: .\05 As Builtdossier\2. Bouwkunde\2.1 Architectuur\2.1.5 dakwerken en dakwaterafvoer\2.1.5.1 dakwerken (Tectum)\TF A 05.01.91.01 A - onderdak van hellend dak.pdf
IfcRoot - Name: vezelcementplaat 1250 x 625
Qto_SlabBaseQuantities - Width: 23.8498; Length: 625; Perimeter: 2548.22; GrossArea: 0.0298185; GrossVolume: 0.0186366; NetVolume: 0.0186366; Depth: 1250.26
Pset_ConcreteElementGeneral - ConstructionMethod: prefabricated
Pset_Condition - AssessmentCondition: Empty
Pset_EnvironmentalImpactIndicators - Reference: vezelcementplaat 1250 x 625; sets with these values: 2
Pset_SlabCommon - Reference: vezelcementplaat 1250 x 625; FireRating: EI 60; IsExternal: yes

# IfcSlab: vezelcementplaat 1250 x 21:vezelcementplaat 1250 x 625, vezelcementplaat 1250 x 21:vezelcementplaat 1250 x 625:33947897:1
In: 050
PredefinedType: ROOF
Cpset_Slab - LevelOfAccuracy: in te vullen door Buildwise
IfcBuildingStorey - Elevation from Level: 234.347
IfcClassificationReference - TDS_link: .\05 As Builtdossier\2. Bouwkunde\2.1 Architectuur\2.1.5 dakwerken en dakwaterafvoer\2.1.5.1 dakwerken (Tectum)\TF A 05.01.91.01 A - onderdak van hellend dak.pdf
IfcRoot - Name: vezelcementplaat 1250 x 625
Qto_SlabBaseQuantities - Width: 23.8498; Length: 625; Perimeter: 2547.18; GrossArea: 0.029806; GrossVolume: 0.0186288; NetVolume: 0.0186288; Depth: 1249.74
Pset_ConcreteElementGeneral - ConstructionMethod: prefabricated
Pset_Condition - AssessmentCondition: Empty
Pset_EnvironmentalImpactIndicators - Reference: vezelcementplaat 1250 x 625; sets with these values: 2
Pset_SlabCommon - Reference: vezelcementplaat 1250 x 625; FireRating: EI 60; IsExternal: yes

# IfcSlab: vezelcementplaat 1250 x 22:vezelcementplaat 1250 x 625, vezelcementplaat 1250 x 22:vezelcementplaat 1250 x 625:33947910:1
In: 050
PredefinedType: ROOF
Cpset_Slab - LevelOfAccuracy: in te vullen door Buildwise
IfcBuildingStorey - Elevation from Level: 788.358
IfcClassificationReference - TDS_link: .\05 As Builtdossier\2. Bouwkunde\2.1 Architectuur\2.1.5 dakwerken en dakwaterafvoer\2.1.5.1 dakwerken (Tectum)\TF A 05.01.91.01 A - onderdak van hellend dak.pdf
IfcRoot - Name: vezelcementplaat 1250 x 625
Qto_SlabBaseQuantities - Width: 23.8498; Length: 625; Perimeter: 2547.7; GrossArea: 0.0298123; GrossVolume: 0.0186327; NetVolume: 0.0186327; Depth: 1250
Pset_ConcreteElementGeneral - ConstructionMethod: prefabricated
Pset_Condition - AssessmentCondition: Empty
Pset_EnvironmentalImpactIndicators - Reference: vezelcementplaat 1250 x 625; sets with these values: 2
Pset_SlabCommon - Reference: vezelcementplaat 1250 x 625; FireRating: EI 60; IsExternal: yes

# IfcSlab: vezelcementplaat 1250 x 23:vezelcementplaat 1250 x 625, vezelcementplaat 1250 x 23:vezelcementplaat 1250 x 625:33947923:1
In: 050
PredefinedType: ROOF
Cpset_Slab - LevelOfAccuracy: in te vullen door Buildwise
IfcBuildingStorey - Elevation from Level: 1342.37
IfcClassificationReference - TDS_link: .\05 As Builtdossier\2. Bouwkunde\2.1 Architectuur\2.1.5 dakwerken en dakwaterafvoer\2.1.5.1 dakwerken (Tectum)\TF A 05.01.91.01 A - onderdak van hellend dak.pdf
IfcRoot - Name: vezelcementplaat 1250 x 625
Qto_SlabBaseQuantities - Width: 23.8498; Length: 625; Perimeter: 2547.7; GrossArea: 0.0298123; GrossVolume: 0.0186327; NetVolume: 0.0186327; Depth: 1250
Pset_ConcreteElementGeneral - ConstructionMethod: prefabricated
Pset_Condition - AssessmentCondition: Empty
Pset_EnvironmentalImpactIndicators - Reference: vezelcementplaat 1250 x 625; sets with these values: 2
Pset_SlabCommon - Reference: vezelcementplaat 1250 x 625; FireRating: EI 60; IsExternal: yes

# IfcSlab: vezelcementplaat 1250 x 24:vezelcementplaat 1250 x 625, vezelcementplaat 1250 x 24:vezelcementplaat 1250 x 625:33947936:1
In: 050
PredefinedType: ROOF
Cpset_Slab - LevelOfAccuracy: in te vullen door Buildwise
IfcBuildingStorey - Elevation from Level: 1896.38
IfcClassificationReference - TDS_link: .\05 As Builtdossier\2. Bouwkunde\2.1 Architectuur\2.1.5 dakwerken en dakwaterafvoer\2.1.5.1 dakwerken (Tectum)\TF A 05.01.91.01 A - onderdak van hellend dak.pdf
IfcRoot - Name: vezelcementplaat 1250 x 625
Qto_SlabBaseQuantities - Width: 23.8498; Length: 625; Perimeter: 2547.7; GrossArea: 0.0298123; GrossVolume: 0.0186327; NetVolume: 0.0186327; Depth: 1250
Pset_ConcreteElementGeneral - ConstructionMethod: prefabricated
Pset_Condition - AssessmentCondition: Empty
Pset_EnvironmentalImpactIndicators - Reference: vezelcementplaat 1250 x 625; sets with these values: 2
Pset_SlabCommon - Reference: vezelcementplaat 1250 x 625; FireRating: EI 60; IsExternal: yes

# IfcSlab: vezelcementplaat 1250 x 25:vezelcementplaat 1250 x 625, vezelcementplaat 1250 x 25:vezelcementplaat 1250 x 625:33947949:1
In: 050
PredefinedType: ROOF
Cpset_Slab - LevelOfAccuracy: in te vullen door Buildwise
IfcBuildingStorey - Elevation from Level: -317.144
IfcClassificationReference - TDS_link: .\05 As Builtdossier\2. Bouwkunde\2.1 Architectuur\2.1.5 dakwerken en dakwaterafvoer\2.1.5.1 dakwerken (Tectum)\TF A 05.01.91.01 A - onderdak van hellend dak.pdf
IfcRoot - Name: vezelcementplaat 1250 x 625
Qto_SlabBaseQuantities - Width: 23.8498; Length: 625; Perimeter: 2548.22; GrossArea: 0.0298185; GrossVolume: 0.0186366; NetVolume: 0.0186366; Depth: 1250.26
Pset_ConcreteElementGeneral - ConstructionMethod: prefabricated
Pset_Condition - AssessmentCondition: Empty
Pset_EnvironmentalImpactIndicators - Reference: vezelcementplaat 1250 x 625; sets with these values: 2
Pset_SlabCommon - Reference: vezelcementplaat 1250 x 625; FireRating: EI 60; IsExternal: yes

# IfcSlab: vezelcementplaat 1250 x 26:vezelcementplaat 1250 x 625, vezelcementplaat 1250 x 26:vezelcementplaat 1250 x 625:33947970:1
In: 050
PredefinedType: ROOF
Cpset_Slab - LevelOfAccuracy: in te vullen door Buildwise
IfcBuildingStorey - Elevation from Level: -41.5138
IfcClassificationReference - TDS_link: .\05 As Builtdossier\2. Bouwkunde\2.1 Architectuur\2.1.5 dakwerken en dakwaterafvoer\2.1.5.1 dakwerken (Tectum)\TF A 05.01.91.01 A - onderdak van hellend dak.pdf
IfcRoot - Name: vezelcementplaat 1250 x 625
Qto_SlabBaseQuantities - Width: 23.8498; Length: 625; Perimeter: 2548.22; GrossArea: 0.0298185; GrossVolume: 0.0186366; NetVolume: 0.0186366; Depth: 1250.26
Pset_ConcreteElementGeneral - ConstructionMethod: prefabricated
Pset_Condition - AssessmentCondition: Empty
Pset_EnvironmentalImpactIndicators - Reference: vezelcementplaat 1250 x 625; sets with these values: 2
Pset_SlabCommon - Reference: vezelcementplaat 1250 x 625; FireRating: EI 60; IsExternal: yes

# IfcSlab: vezelcementplaat 1250 x 27:vezelcementplaat 1250 x 625, vezelcementplaat 1250 x 27:vezelcementplaat 1250 x 625:33947983:1
In: 050
PredefinedType: ROOF
Cpset_Slab - LevelOfAccuracy: in te vullen door Buildwise
IfcBuildingStorey - Elevation from Level: -41.5138
IfcClassificationReference - TDS_link: .\05 As Builtdossier\2. Bouwkunde\2.1 Architectuur\2.1.5 dakwerken en dakwaterafvoer\2.1.5.1 dakwerken (Tectum)\TF A 05.01.91.01 A - onderdak van hellend dak.pdf
IfcRoot - Name: vezelcementplaat 1250 x 625
Qto_SlabBaseQuantities - Width: 23.8498; Length: 625; Perimeter: 2547.18; GrossArea: 0.029806; GrossVolume: 0.0186288; NetVolume: 0.0186288; Depth: 1249.74
Pset_ConcreteElementGeneral - ConstructionMethod: prefabricated
Pset_Condition - AssessmentCondition: Empty
Pset_EnvironmentalImpactIndicators - Reference: vezelcementplaat 1250 x 625; sets with these values: 2
Pset_SlabCommon - Reference: vezelcementplaat 1250 x 625; FireRating: EI 60; IsExternal: yes

# IfcSlab: vezelcementplaat 1250 x 28:vezelcementplaat 1250 x 625, vezelcementplaat 1250 x 28:vezelcementplaat 1250 x 625:33947996:1
In: 050
PredefinedType: ROOF
Cpset_Slab - LevelOfAccuracy: in te vullen door Buildwise
IfcBuildingStorey - Elevation from Level: 512.497
IfcClassificationReference - TDS_link: .\05 As Builtdossier\2. Bouwkunde\2.1 Architectuur\2.1.5 dakwerken en dakwaterafvoer\2.1.5.1 dakwerken (Tectum)\TF A 05.01.91.01 A - onderdak van hellend dak.pdf
IfcRoot - Name: vezelcementplaat 1250 x 625
Qto_SlabBaseQuantities - Width: 23.8498; Length: 625; Perimeter: 2547.7; GrossArea: 0.0298123; GrossVolume: 0.0186327; NetVolume: 0.0186327; Depth: 1250
Pset_ConcreteElementGeneral - ConstructionMethod: prefabricated
Pset_Condition - AssessmentCondition: Empty
Pset_EnvironmentalImpactIndicators - Reference: vezelcementplaat 1250 x 625; sets with these values: 2
Pset_SlabCommon - Reference: vezelcementplaat 1250 x 625; FireRating: EI 60; IsExternal: yes

# IfcSlab: vezelcementplaat 1250 x 29:vezelcementplaat 1250 x 625, vezelcementplaat 1250 x 29:vezelcementplaat 1250 x 625:33948009:1
In: 050
PredefinedType: ROOF
Cpset_Slab - LevelOfAccuracy: in te vullen door Buildwise
IfcBuildingStorey - Elevation from Level: 1066.51
IfcClassificationReference - TDS_link: .\05 As Builtdossier\2. Bouwkunde\2.1 Architectuur\2.1.5 dakwerken en dakwaterafvoer\2.1.5.1 dakwerken (Tectum)\TF A 05.01.91.01 A - onderdak van hellend dak.pdf
IfcRoot - Name: vezelcementplaat 1250 x 625
Qto_SlabBaseQuantities - Width: 23.8498; Length: 625; Perimeter: 2547.7; GrossArea: 0.0298123; GrossVolume: 0.0186327; NetVolume: 0.0186327; Depth: 1250
Pset_ConcreteElementGeneral - ConstructionMethod: prefabricated
Pset_Condition - AssessmentCondition: Empty
Pset_EnvironmentalImpactIndicators - Reference: vezelcementplaat 1250 x 625; sets with these values: 2
Pset_SlabCommon - Reference: vezelcementplaat 1250 x 625; FireRating: EI 60; IsExternal: yes

# IfcSlab: vezelcementplaat 1250 x 2:vezelcementplaat 1250 x 625, vezelcementplaat 1250 x 2:vezelcementplaat 1250 x 625:33946837:1
In: 050
PredefinedType: ROOF
Cpset_Slab - LevelOfAccuracy: in te vullen door Buildwise
IfcBuildingStorey - Elevation from Level: 512.497
IfcClassificationReference - TDS_link: .\05 As Builtdossier\2. Bouwkunde\2.1 Architectuur\2.1.5 dakwerken en dakwaterafvoer\2.1.5.1 dakwerken (Tectum)\TF A 05.01.91.01 A - onderdak van hellend dak.pdf
IfcRoot - Name: vezelcementplaat 1250 x 625
Qto_SlabBaseQuantities - Width: 23.8498; Length: 625; Perimeter: 2547.7; GrossArea: 0.0298123; GrossVolume: 0.0186327; NetVolume: 0.0186327; Depth: 1250
Pset_ConcreteElementGeneral - ConstructionMethod: prefabricated
Pset_Condition - AssessmentCondition: Empty
Pset_EnvironmentalImpactIndicators - Reference: vezelcementplaat 1250 x 625; sets with these values: 2
Pset_SlabCommon - Reference: vezelcementplaat 1250 x 625; FireRating: EI 60; IsExternal: yes

# IfcSlab: vezelcementplaat 1250 x 30:vezelcementplaat 1250 x 625, vezelcementplaat 1250 x 30:vezelcementplaat 1250 x 625:33948022:1
In: 050
PredefinedType: ROOF
Cpset_Slab - LevelOfAccuracy: in te vullen door Buildwise
IfcBuildingStorey - Elevation from Level: 1620.52
IfcClassificationReference - TDS_link: .\05 As Builtdossier\2. Bouwkunde\2.1 Architectuur\2.1.5 dakwerken en dakwaterafvoer\2.1.5.1 dakwerken (Tectum)\TF A 05.01.91.01 A - onderdak van hellend dak.pdf
IfcRoot - Name: vezelcementplaat 1250 x 625
Qto_SlabBaseQuantities - Width: 23.8498; Length: 625; Perimeter: 2547.7; GrossArea: 0.0298123; GrossVolume: 0.0186327; NetVolume: 0.0186327; Depth: 1250
Pset_ConcreteElementGeneral - ConstructionMethod: prefabricated
Pset_Condition - AssessmentCondition: Empty
Pset_EnvironmentalImpactIndicators - Reference: vezelcementplaat 1250 x 625; sets with these values: 2
Pset_SlabCommon - Reference: vezelcementplaat 1250 x 625; FireRating: EI 60; IsExternal: yes

# IfcSlab: vezelcementplaat 1250 x 31:vezelcementplaat 1250 x 625, vezelcementplaat 1250 x 31:vezelcementplaat 1250 x 625:33948035:1
In: 050
PredefinedType: ROOF
Cpset_Slab - LevelOfAccuracy: in te vullen door Buildwise
IfcBuildingStorey - Elevation from Level: 0
IfcClassificationReference - TDS_link: .\05 As Builtdossier\2. Bouwkunde\2.1 Architectuur\2.1.5 dakwerken en dakwaterafvoer\2.1.5.1 dakwerken (Tectum)\TF A 05.01.91.01 A - onderdak van hellend dak.pdf
IfcRoot - Name: vezelcementplaat 1250 x 625
Qto_SlabBaseQuantities - Width: 23.8498; Length: 625; Perimeter: 1297.7; GrossArea: 0.0149061; GrossVolume: 0.00931633; NetVolume: 0.00931633; Depth: 625
Pset_ConcreteElementGeneral - ConstructionMethod: prefabricated
Pset_Condition - AssessmentCondition: Empty
Pset_EnvironmentalImpactIndicators - Reference: vezelcementplaat 1250 x 625; sets with these values: 2
Pset_SlabCommon - Reference: vezelcementplaat 1250 x 625; FireRating: EI 60; IsExternal: yes

# IfcSlab: vezelcementplaat 1250 x 32:vezelcementplaat 1250 x 625, vezelcementplaat 1250 x 32:vezelcementplaat 1250 x 625:33948048:1
In: 050
PredefinedType: ROOF
Cpset_Slab - LevelOfAccuracy: in te vullen door Buildwise
IfcBuildingStorey - Elevation from Level: 0
IfcClassificationReference - TDS_link: .\05 As Builtdossier\2. Bouwkunde\2.1 Architectuur\2.1.5 dakwerken en dakwaterafvoer\2.1.5.1 dakwerken (Tectum)\TF A 05.01.91.01 A - onderdak van hellend dak.pdf
IfcRoot - Name: vezelcementplaat 1250 x 625
Qto_SlabBaseQuantities - Width: 23.8498; Length: 625; Perimeter: 1298.22; GrossArea: 0.0149124; GrossVolume: 0.00932022; NetVolume: 0.00932022; Depth: 625.261
Pset_ConcreteElementGeneral - ConstructionMethod: prefabricated
Pset_Condition - AssessmentCondition: Empty
Pset_EnvironmentalImpactIndicators - Reference: vezelcementplaat 1250 x 625; sets with these values: 2
Pset_SlabCommon - Reference: vezelcementplaat 1250 x 625; FireRating: EI 60; IsExternal: yes

# IfcSlab: vezelcementplaat 1250 x 33:vezelcementplaat 1250 x 625, vezelcementplaat 1250 x 33:vezelcementplaat 1250 x 625:33948061:1
In: 050
PredefinedType: ROOF
Cpset_Slab - LevelOfAccuracy: in te vullen door Buildwise
IfcBuildingStorey - Elevation from Level: 234.347
IfcClassificationReference - TDS_link: .\05 As Builtdossier\2. Bouwkunde\2.1 Architectuur\2.1.5 dakwerken en dakwaterafvoer\2.1.5.1 dakwerken (Tectum)\TF A 05.01.91.01 A - onderdak van hellend dak.pdf
IfcRoot - Name: vezelcementplaat 1250 x 625
Qto_SlabBaseQuantities - Width: 23.8498; Length: 625; Perimeter: 2548.22; GrossArea: 0.0298185; GrossVolume: 0.0186366; NetVolume: 0.0186366; Depth: 1250.26
Pset_ConcreteElementGeneral - ConstructionMethod: prefabricated
Pset_Condition - AssessmentCondition: Empty
Pset_EnvironmentalImpactIndicators - Reference: vezelcementplaat 1250 x 625; sets with these values: 2
Pset_SlabCommon - Reference: vezelcementplaat 1250 x 625; FireRating: EI 60; IsExternal: yes

# IfcSlab: vezelcementplaat 1250 x 34:vezelcementplaat 1250 x 625, vezelcementplaat 1250 x 34:vezelcementplaat 1250 x 625:33948074:1
In: 050
PredefinedType: ROOF
Cpset_Slab - LevelOfAccuracy: in te vullen door Buildwise
IfcBuildingStorey - Elevation from Level: 234.347
IfcClassificationReference - TDS_link: .\05 As Builtdossier\2. Bouwkunde\2.1 Architectuur\2.1.5 dakwerken en dakwaterafvoer\2.1.5.1 dakwerken (Tectum)\TF A 05.01.91.01 A - onderdak van hellend dak.pdf
IfcRoot - Name: vezelcementplaat 1250 x 625
Qto_SlabBaseQuantities - Width: 23.8498; Length: 625; Perimeter: 2547.18; GrossArea: 0.029806; GrossVolume: 0.0186288; NetVolume: 0.0186288; Depth: 1249.74
Pset_ConcreteElementGeneral - ConstructionMethod: prefabricated
Pset_Condition - AssessmentCondition: Empty
Pset_EnvironmentalImpactIndicators - Reference: vezelcementplaat 1250 x 625; sets with these values: 2
Pset_SlabCommon - Reference: vezelcementplaat 1250 x 625; FireRating: EI 60; IsExternal: yes

# IfcSlab: vezelcementplaat 1250 x 35:vezelcementplaat 1250 x 625, vezelcementplaat 1250 x 35:vezelcementplaat 1250 x 625:33948087:1
In: 050
PredefinedType: ROOF
Cpset_Slab - LevelOfAccuracy: in te vullen door Buildwise
IfcBuildingStorey - Elevation from Level: 788.358
IfcClassificationReference - TDS_link: .\05 As Builtdossier\2. Bouwkunde\2.1 Architectuur\2.1.5 dakwerken en dakwaterafvoer\2.1.5.1 dakwerken (Tectum)\TF A 05.01.91.01 A - onderdak van hellend dak.pdf
IfcRoot - Name: vezelcementplaat 1250 x 625
Qto_SlabBaseQuantities - Width: 23.8498; Length: 625; Perimeter: 2547.7; GrossArea: 0.0298123; GrossVolume: 0.0186327; NetVolume: 0.0186327; Depth: 1250
Pset_ConcreteElementGeneral - ConstructionMethod: prefabricated
Pset_Condition - AssessmentCondition: Empty
Pset_EnvironmentalImpactIndicators - Reference: vezelcementplaat 1250 x 625; sets with these values: 2
Pset_SlabCommon - Reference: vezelcementplaat 1250 x 625; FireRating: EI 60; IsExternal: yes

# IfcSlab: vezelcementplaat 1250 x 36:vezelcementplaat 1250 x 625, vezelcementplaat 1250 x 36:vezelcementplaat 1250 x 625:33948100:1
In: 050
PredefinedType: ROOF
Cpset_Slab - LevelOfAccuracy: in te vullen door Buildwise
IfcBuildingStorey - Elevation from Level: 1342.37
IfcClassificationReference - TDS_link: .\05 As Builtdossier\2. Bouwkunde\2.1 Architectuur\2.1.5 dakwerken en dakwaterafvoer\2.1.5.1 dakwerken (Tectum)\TF A 05.01.91.01 A - onderdak van hellend dak.pdf
IfcRoot - Name: vezelcementplaat 1250 x 625
Qto_SlabBaseQuantities - Width: 23.8498; Length: 625; Perimeter: 2547.7; GrossArea: 0.0298123; GrossVolume: 0.0186327; NetVolume: 0.0186327; Depth: 1250
Pset_ConcreteElementGeneral - ConstructionMethod: prefabricated
Pset_Condition - AssessmentCondition: Empty
Pset_EnvironmentalImpactIndicators - Reference: vezelcementplaat 1250 x 625; sets with these values: 2
Pset_SlabCommon - Reference: vezelcementplaat 1250 x 625; FireRating: EI 60; IsExternal: yes

# IfcSlab: vezelcementplaat 1250 x 37:vezelcementplaat 1250 x 625, vezelcementplaat 1250 x 37:vezelcementplaat 1250 x 625:33948113:1
In: 050
PredefinedType: ROOF
Cpset_Slab - LevelOfAccuracy: in te vullen door Buildwise
IfcBuildingStorey - Elevation from Level: 1896.38
IfcClassificationReference - TDS_link: .\05 As Builtdossier\2. Bouwkunde\2.1 Architectuur\2.1.5 dakwerken en dakwaterafvoer\2.1.5.1 dakwerken (Tectum)\TF A 05.01.91.01 A - onderdak van hellend dak.pdf
IfcRoot - Name: vezelcementplaat 1250 x 625
Qto_SlabBaseQuantities - Width: 23.8498; Length: 625; Perimeter: 2547.7; GrossArea: 0.0298123; GrossVolume: 0.0186327; NetVolume: 0.0186327; Depth: 1250
Pset_ConcreteElementGeneral - ConstructionMethod: prefabricated
Pset_Condition - AssessmentCondition: Empty
Pset_EnvironmentalImpactIndicators - Reference: vezelcementplaat 1250 x 625; sets with these values: 2
Pset_SlabCommon - Reference: vezelcementplaat 1250 x 625; FireRating: EI 60; IsExternal: yes

# IfcSlab: vezelcementplaat 1250 x 38:vezelcementplaat 1250 x 625, vezelcementplaat 1250 x 38:vezelcementplaat 1250 x 625:33948126:1
In: 050
PredefinedType: ROOF
Cpset_Slab - LevelOfAccuracy: in te vullen door Buildwise
IfcBuildingStorey - Elevation from Level: -317.144
IfcClassificationReference - TDS_link: .\05 As Builtdossier\2. Bouwkunde\2.1 Architectuur\2.1.5 dakwerken en dakwaterafvoer\2.1.5.1 dakwerken (Tectum)\TF A 05.01.91.01 A - onderdak van hellend dak.pdf
IfcRoot - Name: vezelcementplaat 1250 x 625
Qto_SlabBaseQuantities - Width: 23.8498; Length: 625; Perimeter: 2548.22; GrossArea: 0.0298185; GrossVolume: 0.0186366; NetVolume: 0.0186366; Depth: 1250.26
Pset_ConcreteElementGeneral - ConstructionMethod: prefabricated
Pset_Condition - AssessmentCondition: Empty
Pset_EnvironmentalImpactIndicators - Reference: vezelcementplaat 1250 x 625; sets with these values: 2
Pset_SlabCommon - Reference: vezelcementplaat 1250 x 625; FireRating: EI 60; IsExternal: yes

# IfcSlab: vezelcementplaat 1250 x 39:vezelcementplaat 1250 x 625, vezelcementplaat 1250 x 39:vezelcementplaat 1250 x 625:33948149:1
In: 050
PredefinedType: ROOF
Cpset_Slab - LevelOfAccuracy: in te vullen door Buildwise
IfcBuildingStorey - Elevation from Level: -41.5138
IfcClassificationReference - TDS_link: .\05 As Builtdossier\2. Bouwkunde\2.1 Architectuur\2.1.5 dakwerken en dakwaterafvoer\2.1.5.1 dakwerken (Tectum)\TF A 05.01.91.01 A - onderdak van hellend dak.pdf
IfcRoot - Name: vezelcementplaat 1250 x 625
Qto_SlabBaseQuantities - Width: 23.8498; Length: 625; Perimeter: 2548.22; GrossArea: 0.0298185; GrossVolume: 0.0186366; NetVolume: 0.0186366; Depth: 1250.26
Pset_ConcreteElementGeneral - ConstructionMethod: prefabricated
Pset_Condition - AssessmentCondition: Empty
Pset_EnvironmentalImpactIndicators - Reference: vezelcementplaat 1250 x 625; sets with these values: 2
Pset_SlabCommon - Reference: vezelcementplaat 1250 x 625; FireRating: EI 60; IsExternal: yes

# IfcSlab: vezelcementplaat 1250 x 3:vezelcementplaat 1250 x 625, vezelcementplaat 1250 x 3:vezelcementplaat 1250 x 625:33946858:1
In: 050
PredefinedType: ROOF
Cpset_Slab - LevelOfAccuracy: in te vullen door Buildwise
IfcBuildingStorey - Elevation from Level: 1066.51
IfcClassificationReference - TDS_link: .\05 As Builtdossier\2. Bouwkunde\2.1 Architectuur\2.1.5 dakwerken en dakwaterafvoer\2.1.5.1 dakwerken (Tectum)\TF A 05.01.91.01 A - onderdak van hellend dak.pdf
IfcRoot - Name: vezelcementplaat 1250 x 625
Qto_SlabBaseQuantities - Width: 23.8498; Length: 625; Perimeter: 2547.7; GrossArea: 0.0298123; GrossVolume: 0.0186327; NetVolume: 0.0186327; Depth: 1250
Pset_ConcreteElementGeneral - ConstructionMethod: prefabricated
Pset_Condition - AssessmentCondition: Empty
Pset_EnvironmentalImpactIndicators - Reference: vezelcementplaat 1250 x 625; sets with these values: 2
Pset_SlabCommon - Reference: vezelcementplaat 1250 x 625; FireRating: EI 60; IsExternal: yes

# IfcSlab: vezelcementplaat 1250 x 40:vezelcementplaat 1250 x 625, vezelcementplaat 1250 x 40:vezelcementplaat 1250 x 625:33948162:1
In: 050
PredefinedType: ROOF
Cpset_Slab - LevelOfAccuracy: in te vullen door Buildwise
IfcBuildingStorey - Elevation from Level: -41.5138
IfcClassificationReference - TDS_link: .\05 As Builtdossier\2. Bouwkunde\2.1 Architectuur\2.1.5 dakwerken en dakwaterafvoer\2.1.5.1 dakwerken (Tectum)\TF A 05.01.91.01 A - onderdak van hellend dak.pdf
IfcRoot - Name: vezelcementplaat 1250 x 625
Qto_SlabBaseQuantities - Width: 23.8498; Length: 625; Perimeter: 2547.18; GrossArea: 0.029806; GrossVolume: 0.0186288; NetVolume: 0.0186288; Depth: 1249.74
Pset_ConcreteElementGeneral - ConstructionMethod: prefabricated
Pset_Condition - AssessmentCondition: Empty
Pset_EnvironmentalImpactIndicators - Reference: vezelcementplaat 1250 x 625; sets with these values: 2
Pset_SlabCommon - Reference: vezelcementplaat 1250 x 625; FireRating: EI 60; IsExternal: yes

# IfcSlab: vezelcementplaat 1250 x 41:vezelcementplaat 1250 x 625, vezelcementplaat 1250 x 41:vezelcementplaat 1250 x 625:33948175:1
In: 050
PredefinedType: ROOF
Cpset_Slab - LevelOfAccuracy: in te vullen door Buildwise
IfcBuildingStorey - Elevation from Level: 512.497
IfcClassificationReference - TDS_link: .\05 As Builtdossier\2. Bouwkunde\2.1 Architectuur\2.1.5 dakwerken en dakwaterafvoer\2.1.5.1 dakwerken (Tectum)\TF A 05.01.91.01 A - onderdak van hellend dak.pdf
IfcRoot - Name: vezelcementplaat 1250 x 625
Qto_SlabBaseQuantities - Width: 23.8498; Length: 625; Perimeter: 2547.7; GrossArea: 0.0298123; GrossVolume: 0.0186327; NetVolume: 0.0186327; Depth: 1250
Pset_ConcreteElementGeneral - ConstructionMethod: prefabricated
Pset_Condition - AssessmentCondition: Empty
Pset_EnvironmentalImpactIndicators - Reference: vezelcementplaat 1250 x 625; sets with these values: 2
Pset_SlabCommon - Reference: vezelcementplaat 1250 x 625; FireRating: EI 60; IsExternal: yes

# IfcSlab: vezelcementplaat 1250 x 42:vezelcementplaat 1250 x 625, vezelcementplaat 1250 x 42:vezelcementplaat 1250 x 625:33948188:1
In: 050
PredefinedType: ROOF
Cpset_Slab - LevelOfAccuracy: in te vullen door Buildwise
IfcBuildingStorey - Elevation from Level: 1066.51
IfcClassificationReference - TDS_link: .\05 As Builtdossier\2. Bouwkunde\2.1 Architectuur\2.1.5 dakwerken en dakwaterafvoer\2.1.5.1 dakwerken (Tectum)\TF A 05.01.91.01 A - onderdak van hellend dak.pdf
IfcRoot - Name: vezelcementplaat 1250 x 625
Qto_SlabBaseQuantities - Width: 23.8498; Length: 625; Perimeter: 2547.7; GrossArea: 0.0298123; GrossVolume: 0.0186327; NetVolume: 0.0186327; Depth: 1250
Pset_ConcreteElementGeneral - ConstructionMethod: prefabricated
Pset_Condition - AssessmentCondition: Empty
Pset_EnvironmentalImpactIndicators - Reference: vezelcementplaat 1250 x 625; sets with these values: 2
Pset_SlabCommon - Reference: vezelcementplaat 1250 x 625; FireRating: EI 60; IsExternal: yes

# IfcSlab: vezelcementplaat 1250 x 45:vezelcementplaat 1250 x 625, vezelcementplaat 1250 x 45:vezelcementplaat 1250 x 625:33948227:1
In: 050
PredefinedType: ROOF
Cpset_Slab - LevelOfAccuracy: in te vullen door Buildwise
IfcBuildingStorey - Elevation from Level: 0
IfcClassificationReference - TDS_link: .\05 As Builtdossier\2. Bouwkunde\2.1 Architectuur\2.1.5 dakwerken en dakwaterafvoer\2.1.5.1 dakwerken (Tectum)\TF A 05.01.91.01 A - onderdak van hellend dak.pdf
IfcRoot - Name: vezelcementplaat 1250 x 625
Qto_SlabBaseQuantities - Width: 23.8498; Length: 625; Perimeter: 1298.22; GrossArea: 0.0149124; GrossVolume: 0.00932022; NetVolume: 0.00932022; Depth: 625.261
Pset_ConcreteElementGeneral - ConstructionMethod: prefabricated
Pset_Condition - AssessmentCondition: Empty
Pset_EnvironmentalImpactIndicators - Reference: vezelcementplaat 1250 x 625; sets with these values: 2
Pset_SlabCommon - Reference: vezelcementplaat 1250 x 625; FireRating: EI 60; IsExternal: yes

# IfcSlab: vezelcementplaat 1250 x 46:vezelcementplaat 1250 x 625, vezelcementplaat 1250 x 46:vezelcementplaat 1250 x 625:33948240:1
In: 050
PredefinedType: ROOF
Cpset_Slab - LevelOfAccuracy: in te vullen door Buildwise
IfcBuildingStorey - Elevation from Level: 234.347
IfcClassificationReference - TDS_link: .\05 As Builtdossier\2. Bouwkunde\2.1 Architectuur\2.1.5 dakwerken en dakwaterafvoer\2.1.5.1 dakwerken (Tectum)\TF A 05.01.91.01 A - onderdak van hellend dak.pdf
IfcRoot - Name: vezelcementplaat 1250 x 625
Qto_SlabBaseQuantities - Width: 23.8498; Length: 625; Perimeter: 2548.22; GrossArea: 0.0298185; GrossVolume: 0.0186366; NetVolume: 0.0186366; Depth: 1250.26
Pset_ConcreteElementGeneral - ConstructionMethod: prefabricated
Pset_Condition - AssessmentCondition: Empty
Pset_EnvironmentalImpactIndicators - Reference: vezelcementplaat 1250 x 625; sets with these values: 2
Pset_SlabCommon - Reference: vezelcementplaat 1250 x 625; FireRating: EI 60; IsExternal: yes

# IfcSlab: vezelcementplaat 1250 x 47:vezelcementplaat 1250 x 625, vezelcementplaat 1250 x 47:vezelcementplaat 1250 x 625:33948253:1
In: 050
PredefinedType: ROOF
Cpset_Slab - LevelOfAccuracy: in te vullen door Buildwise
IfcBuildingStorey - Elevation from Level: 234.347
IfcClassificationReference - TDS_link: .\05 As Builtdossier\2. Bouwkunde\2.1 Architectuur\2.1.5 dakwerken en dakwaterafvoer\2.1.5.1 dakwerken (Tectum)\TF A 05.01.91.01 A - onderdak van hellend dak.pdf
IfcRoot - Name: vezelcementplaat 1250 x 625
Qto_SlabBaseQuantities - Width: 23.8498; Length: 625; Perimeter: 2547.18; GrossArea: 0.029806; GrossVolume: 0.0186288; NetVolume: 0.0186288; Depth: 1249.74
Pset_ConcreteElementGeneral - ConstructionMethod: prefabricated
Pset_Condition - AssessmentCondition: Empty
Pset_EnvironmentalImpactIndicators - Reference: vezelcementplaat 1250 x 625; sets with these values: 2
Pset_SlabCommon - Reference: vezelcementplaat 1250 x 625; FireRating: EI 60; IsExternal: yes

# IfcSlab: vezelcementplaat 1250 x 48:vezelcementplaat 1250 x 625, vezelcementplaat 1250 x 48:vezelcementplaat 1250 x 625:33948266:1
In: 050
PredefinedType: ROOF
Cpset_Slab - LevelOfAccuracy: in te vullen door Buildwise
IfcBuildingStorey - Elevation from Level: 788.358
IfcClassificationReference - TDS_link: .\05 As Builtdossier\2. Bouwkunde\2.1 Architectuur\2.1.5 dakwerken en dakwaterafvoer\2.1.5.1 dakwerken (Tectum)\TF A 05.01.91.01 A - onderdak van hellend dak.pdf
IfcRoot - Name: vezelcementplaat 1250 x 625
Qto_SlabBaseQuantities - Width: 23.8498; Length: 625; Perimeter: 2547.7; GrossArea: 0.0298123; GrossVolume: 0.0186327; NetVolume: 0.0186327; Depth: 1250
Pset_ConcreteElementGeneral - ConstructionMethod: prefabricated
Pset_Condition - AssessmentCondition: Empty
Pset_EnvironmentalImpactIndicators - Reference: vezelcementplaat 1250 x 625; sets with these values: 2
Pset_SlabCommon - Reference: vezelcementplaat 1250 x 625; FireRating: EI 60; IsExternal: yes

# IfcSlab: vezelcementplaat 1250 x 4:vezelcementplaat 1250 x 625, vezelcementplaat 1250 x 4:vezelcementplaat 1250 x 625:33946879:1
In: 050
PredefinedType: ROOF
Cpset_Slab - LevelOfAccuracy: in te vullen door Buildwise
IfcBuildingStorey - Elevation from Level: 1620.52
IfcClassificationReference - TDS_link: .\05 As Builtdossier\2. Bouwkunde\2.1 Architectuur\2.1.5 dakwerken en dakwaterafvoer\2.1.5.1 dakwerken (Tectum)\TF A 05.01.91.01 A - onderdak van hellend dak.pdf
IfcRoot - Name: vezelcementplaat 1250 x 625
Qto_SlabBaseQuantities - Width: 23.8498; Length: 625; Perimeter: 2547.7; GrossArea: 0.0298123; GrossVolume: 0.0186327; NetVolume: 0.0186327; Depth: 1250
Pset_ConcreteElementGeneral - ConstructionMethod: prefabricated
Pset_Condition - AssessmentCondition: Empty
Pset_EnvironmentalImpactIndicators - Reference: vezelcementplaat 1250 x 625; sets with these values: 2
Pset_SlabCommon - Reference: vezelcementplaat 1250 x 625; FireRating: EI 60; IsExternal: yes

# IfcSlab: vezelcementplaat 1250 x 51:vezelcementplaat 1250 x 625, vezelcementplaat 1250 x 51:vezelcementplaat 1250 x 625:33948305:1
In: 050
PredefinedType: ROOF
Cpset_Slab - LevelOfAccuracy: in te vullen door Buildwise
IfcBuildingStorey - Elevation from Level: -317.144
IfcClassificationReference - TDS_link: .\05 As Builtdossier\2. Bouwkunde\2.1 Architectuur\2.1.5 dakwerken en dakwaterafvoer\2.1.5.1 dakwerken (Tectum)\TF A 05.01.91.01 A - onderdak van hellend dak.pdf
IfcRoot - Name: vezelcementplaat 1250 x 625
Qto_SlabBaseQuantities - Width: 23.8498; Length: 625; Perimeter: 2548.22; GrossArea: 0.0298185; GrossVolume: 0.0186366; NetVolume: 0.0186366; Depth: 1250.26
Pset_ConcreteElementGeneral - ConstructionMethod: prefabricated
Pset_Condition - AssessmentCondition: Empty
Pset_EnvironmentalImpactIndicators - Reference: vezelcementplaat 1250 x 625; sets with these values: 2
Pset_SlabCommon - Reference: vezelcementplaat 1250 x 625; FireRating: EI 60; IsExternal: yes

# IfcSlab: vezelcementplaat 1250 x 5:vezelcementplaat 1250 x 625, vezelcementplaat 1250 x 5:vezelcementplaat 1250 x 625:33946900:1
In: 050
PredefinedType: ROOF
Cpset_Slab - LevelOfAccuracy: in te vullen door Buildwise
IfcBuildingStorey - Elevation from Level: 0
IfcClassificationReference - TDS_link: .\05 As Builtdossier\2. Bouwkunde\2.1 Architectuur\2.1.5 dakwerken en dakwaterafvoer\2.1.5.1 dakwerken (Tectum)\TF A 05.01.91.01 A - onderdak van hellend dak.pdf
IfcRoot - Name: vezelcementplaat 1250 x 625
Qto_SlabBaseQuantities - Width: 23.8498; Length: 625; Perimeter: 1297.7; GrossArea: 0.0149061; GrossVolume: 0.00931633; NetVolume: 0.00931633; Depth: 625
Pset_ConcreteElementGeneral - ConstructionMethod: prefabricated
Pset_Condition - AssessmentCondition: Empty
Pset_EnvironmentalImpactIndicators - Reference: vezelcementplaat 1250 x 625; sets with these values: 2
Pset_SlabCommon - Reference: vezelcementplaat 1250 x 625; FireRating: EI 60; IsExternal: yes

# IfcSlab: vezelcementplaat 1250 x 625:vezelcementplaat 1250 x 625, vezelcementplaat 1250 x 625:vezelcementplaat 1250 x 625:33946399:1
In: 050
PredefinedType: ROOF
Cpset_Slab - LevelOfAccuracy: in te vullen door Buildwise
IfcBuildingStorey - Elevation from Level: -41.5138
IfcClassificationReference - TDS_link: .\05 As Builtdossier\2. Bouwkunde\2.1 Architectuur\2.1.5 dakwerken en dakwaterafvoer\2.1.5.1 dakwerken (Tectum)\TF A 05.01.91.01 A - onderdak van hellend dak.pdf
IfcRoot - Name: vezelcementplaat 1250 x 625
Qto_SlabBaseQuantities - Width: 23.8498; Length: 625; Perimeter: 2548.22; GrossArea: 0.0298185; GrossVolume: 0.0186366; NetVolume: 0.0186366; Depth: 1250.26
Pset_ConcreteElementGeneral - ConstructionMethod: prefabricated
Pset_Condition - AssessmentCondition: Empty
Pset_EnvironmentalImpactIndicators - Reference: vezelcementplaat 1250 x 625; sets with these values: 2
Pset_SlabCommon - Reference: vezelcementplaat 1250 x 625; FireRating: EI 60; IsExternal: yes

# IfcSlab: vezelcementplaat 1250 x 6:vezelcementplaat 1250 x 625, vezelcementplaat 1250 x 6:vezelcementplaat 1250 x 625:33947144:1
In: 050
PredefinedType: ROOF
Cpset_Slab - LevelOfAccuracy: in te vullen door Buildwise
IfcBuildingStorey - Elevation from Level: 0
IfcClassificationReference - TDS_link: .\05 As Builtdossier\2. Bouwkunde\2.1 Architectuur\2.1.5 dakwerken en dakwaterafvoer\2.1.5.1 dakwerken (Tectum)\TF A 05.01.91.01 A - onderdak van hellend dak.pdf
IfcRoot - Name: vezelcementplaat 1250 x 625
Qto_SlabBaseQuantities - Width: 23.8498; Length: 625; Perimeter: 1298.22; GrossArea: 0.0149124; GrossVolume: 0.00932022; NetVolume: 0.00932022; Depth: 625.261
Pset_ConcreteElementGeneral - ConstructionMethod: prefabricated
Pset_Condition - AssessmentCondition: Empty
Pset_EnvironmentalImpactIndicators - Reference: vezelcementplaat 1250 x 625; sets with these values: 2
Pset_SlabCommon - Reference: vezelcementplaat 1250 x 625; FireRating: EI 60; IsExternal: yes

# IfcSlab: vezelcementplaat 1250 x 7:vezelcementplaat 1250 x 625, vezelcementplaat 1250 x 7:vezelcementplaat 1250 x 625:33947493:1
In: 050
PredefinedType: ROOF
Cpset_Slab - LevelOfAccuracy: in te vullen door Buildwise
IfcBuildingStorey - Elevation from Level: 234.347
IfcClassificationReference - TDS_link: .\05 As Builtdossier\2. Bouwkunde\2.1 Architectuur\2.1.5 dakwerken en dakwaterafvoer\2.1.5.1 dakwerken (Tectum)\TF A 05.01.91.01 A - onderdak van hellend dak.pdf
IfcRoot - Name: vezelcementplaat 1250 x 625
Qto_SlabBaseQuantities - Width: 23.8498; Length: 625; Perimeter: 2548.22; GrossArea: 0.0298185; GrossVolume: 0.0186366; NetVolume: 0.0186366; Depth: 1250.26
Pset_ConcreteElementGeneral - ConstructionMethod: prefabricated
Pset_Condition - AssessmentCondition: Empty
Pset_EnvironmentalImpactIndicators - Reference: vezelcementplaat 1250 x 625; sets with these values: 2
Pset_SlabCommon - Reference: vezelcementplaat 1250 x 625; FireRating: EI 60; IsExternal: yes

# IfcSlab: vezelcementplaat 1250 x 8:vezelcementplaat 1250 x 625, vezelcementplaat 1250 x 8:vezelcementplaat 1250 x 625:33947506:1
In: 050
PredefinedType: ROOF
Cpset_Slab - LevelOfAccuracy: in te vullen door Buildwise
IfcBuildingStorey - Elevation from Level: 234.347
IfcClassificationReference - TDS_link: .\05 As Builtdossier\2. Bouwkunde\2.1 Architectuur\2.1.5 dakwerken en dakwaterafvoer\2.1.5.1 dakwerken (Tectum)\TF A 05.01.91.01 A - onderdak van hellend dak.pdf
IfcRoot - Name: vezelcementplaat 1250 x 625
Qto_SlabBaseQuantities - Width: 23.8498; Length: 625; Perimeter: 2547.18; GrossArea: 0.029806; GrossVolume: 0.0186288; NetVolume: 0.0186288; Depth: 1249.74
Pset_ConcreteElementGeneral - ConstructionMethod: prefabricated
Pset_Condition - AssessmentCondition: Empty
Pset_EnvironmentalImpactIndicators - Reference: vezelcementplaat 1250 x 625; sets with these values: 2
Pset_SlabCommon - Reference: vezelcementplaat 1250 x 625; FireRating: EI 60; IsExternal: yes

# IfcSlab: vezelcementplaat 1250 x 9:vezelcementplaat 1250 x 625, vezelcementplaat 1250 x 9:vezelcementplaat 1250 x 625:33947519:1
In: 050
PredefinedType: ROOF
Cpset_Slab - LevelOfAccuracy: in te vullen door Buildwise
IfcBuildingStorey - Elevation from Level: 788.358
IfcClassificationReference - TDS_link: .\05 As Builtdossier\2. Bouwkunde\2.1 Architectuur\2.1.5 dakwerken en dakwaterafvoer\2.1.5.1 dakwerken (Tectum)\TF A 05.01.91.01 A - onderdak van hellend dak.pdf
IfcRoot - Name: vezelcementplaat 1250 x 625
Qto_SlabBaseQuantities - Width: 23.8498; Length: 625; Perimeter: 2547.7; GrossArea: 0.0298123; GrossVolume: 0.0186327; NetVolume: 0.0186327; Depth: 1250
Pset_ConcreteElementGeneral - ConstructionMethod: prefabricated
Pset_Condition - AssessmentCondition: Empty
Pset_EnvironmentalImpactIndicators - Reference: vezelcementplaat 1250 x 625; sets with these values: 2
Pset_SlabCommon - Reference: vezelcementplaat 1250 x 625; FireRating: EI 60; IsExternal: yes

# IfcWall: BB_07.10_Gevelbekleding_PuntProfiel, 900 mm, console rechts_GMO:900 x 1600 mm (39)
In: 040
Cpset_Wall - LevelOfAccuracy: in te vullen door Buildwise
IfcBuildingStorey - Level: 040; Elevation from Level: -960
IfcClassificationReference - Keynote: 07.10.43; GVH_artnr 01: 07.10.43; GVH_artnr 02: geen waarde gevonden; GVH_artnr 03: geen waarde gevonden; GVH_artnr 04: geen waarde gevonden; GVH_artnr 05: geen waarde gevonden; GVH_artnr 06: geen waarde gevonden; TDS_link: .\05 As Builtdossier\2. Bouwkunde\2.1 Architectuur\2.1.7 Gevelsluiting\2.1.7.3 Gevelbekleding (MSB)\2.1.7.3.2 technische fiche's\TF A 07.10.43 Puntprofiel (B).pdf
IfcRoot - Name: 900 x 1600 mm
Qto_WallBaseQuantities - NetVolume: 0.0019055
Pset_ConcreteElementGeneral - ConstructionMethod: prefabricated
Pset_Condition - AssessmentCondition: Empty
Pset_EnvironmentalImpactIndicators - Reference: 900 x 1600 mm; sets with these values: 2
Pset_WallCommon - Reference: 900 x 1600 mm; IsExternal: no
Name (BB_07.10_Gevelbekleding_PuntProfiel, 900 mm, console rechts_GMO:900 x 1600 mm:...)
5926937
5927054
5927074
5927090
5927295
5927710
5927910
5927921
5927934
5927945
5927956
5927967
5927978
5927989
5928065
5928128
5928136
5928145
5928152
5928172
5928190
5928197
5928211
5928382
5928479
5928489
5928504
5928515
5928537
5928555
5928566
5928576
10382613
10382625
10382637
10382649
10382661
10382667
10382679

# IfcWall: BB_07.10_Gevelbekleding_PuntProfiel, 900 mm, vol_GMO:900 x 1600 mm (2)
In: 040
Cpset_Wall - LevelOfAccuracy: in te vullen door Buildwise
IfcBuildingStorey - Level: 040; Elevation from Level: -960
IfcClassificationReference - Keynote: 07.10.43; GVH_artnr 01: 07.10.43; GVH_artnr 02: geen waarde gevonden; GVH_artnr 03: geen waarde gevonden; GVH_artnr 04: geen waarde gevonden; GVH_artnr 05: geen waarde gevonden; GVH_artnr 06: geen waarde gevonden; TDS_link: .\05 As Builtdossier\2. Bouwkunde\2.1 Architectuur\2.1.7 Gevelsluiting\2.1.7.3 Gevelbekleding (MSB)\2.1.7.3.2 technische fiche's\TF A 07.10.43 Puntprofiel (B).pdf
IfcRoot - Name: 900 x 1600 mm
Qto_WallBaseQuantities - NetVolume: 0.00191418
Pset_ConcreteElementGeneral - ConstructionMethod: prefabricated
Pset_Condition - AssessmentCondition: Empty
Pset_EnvironmentalImpactIndicators - Reference: 900 x 1600 mm; sets with these values: 2
Pset_WallCommon - Reference: 900 x 1600 mm; IsExternal: no
Name (BB_07.10_Gevelbekleding_PuntProfiel, 900 mm, vol_GMO:900 x 1600 mm:...)
5928182
5928513

# IfcWall: BB_07.10_Gevelbekleding_PuntProfiel_ 900 mm_ vol_GMO_900 x 1600 mm, BB_07.10_Gevelbekleding_PuntProfiel, 900 mm, vol_GMO:900 x 1600 mm:5928181
In: 040
Material: BB_Metaal_Aluminium_Puntprofiel
Cpset_Wall - LevelOfAccuracy: in te vullen door Buildwise
IfcBuildingStorey - Level: 040; Elevation from Level: -960
IfcClassificationReference - Keynote: 07.10.43; GVH_artnr 01: 07.10.43; GVH_artnr 02: geen waarde gevonden; GVH_artnr 03: geen waarde gevonden; GVH_artnr 04: geen waarde gevonden; GVH_artnr 05: geen waarde gevonden; GVH_artnr 06: geen waarde gevonden; TDS_link: .\05 As Builtdossier\2. Bouwkunde\2.1 Architectuur\2.1.7 Gevelsluiting\2.1.7.3 Gevelbekleding (MSB)\2.1.7.3.2 technische fiche's\TF A 07.10.43 Puntprofiel (B).pdf
IfcRoot - Name: 900 x 1600 mm
Qto_WallBaseQuantities - NetVolume: 0.00188866
Pset_ConcreteElementGeneral - ConstructionMethod: prefabricated
Pset_Condition - AssessmentCondition: Empty
Pset_EnvironmentalImpactIndicators - Reference: 900 x 1600 mm; sets with these values: 2
Pset_WallCommon - Reference: 900 x 1600 mm; IsExternal: no

# IfcWall: BB_10.02.31_Verrolbare binnenwand_ lokaal K.00.201_GMO_XX_Geen, BB_10.02.31_Verrolbare binnenwand, lokaal K.00.201_GMO:XX_Geen:24166531
In: 000
PredefinedType: MOVABLE; Material: BB_MDF
Cpset_Wall - LevelOfAccuracy: in te vullen door Buildwise
IfcBuildingStorey - Level: 000; Elevation from Level: 0
IfcClassificationReference - Keynote: 10.02.31#01; GVH_artnr 01: 10.02.31#01; GVH_artnr 02: geen waarde gevonden; GVH_artnr 03: geen waarde gevonden; GVH_artnr 04: geen waarde gevonden; GVH_artnr 05: geen waarde gevonden; GVH_artnr 06: geen waarde gevonden; TDS_link: .\05 As Builtdossier\2. Bouwkunde\2.1 Architectuur\2.1.10 wanden\TF A 10.02.30 A - Verrolbare binnenwand.pdf
IfcElement - BB_Element_Lokaalnummer01: K.00.201
IfcRoot - Name: XX_Geen
Qto_WallBaseQuantities - NetVolume: 2.72288
Pset_ConcreteElementGeneral - ConstructionMethod: prefabricated
Pset_Condition - AssessmentCondition: Empty
Pset_EnvironmentalImpactIndicators - Reference: XX_Geen; sets with these values: 2
Pset_WallCommon - Reference: XX_Geen; AcousticRating: 52; FireRating: EI30; IsExternal: no
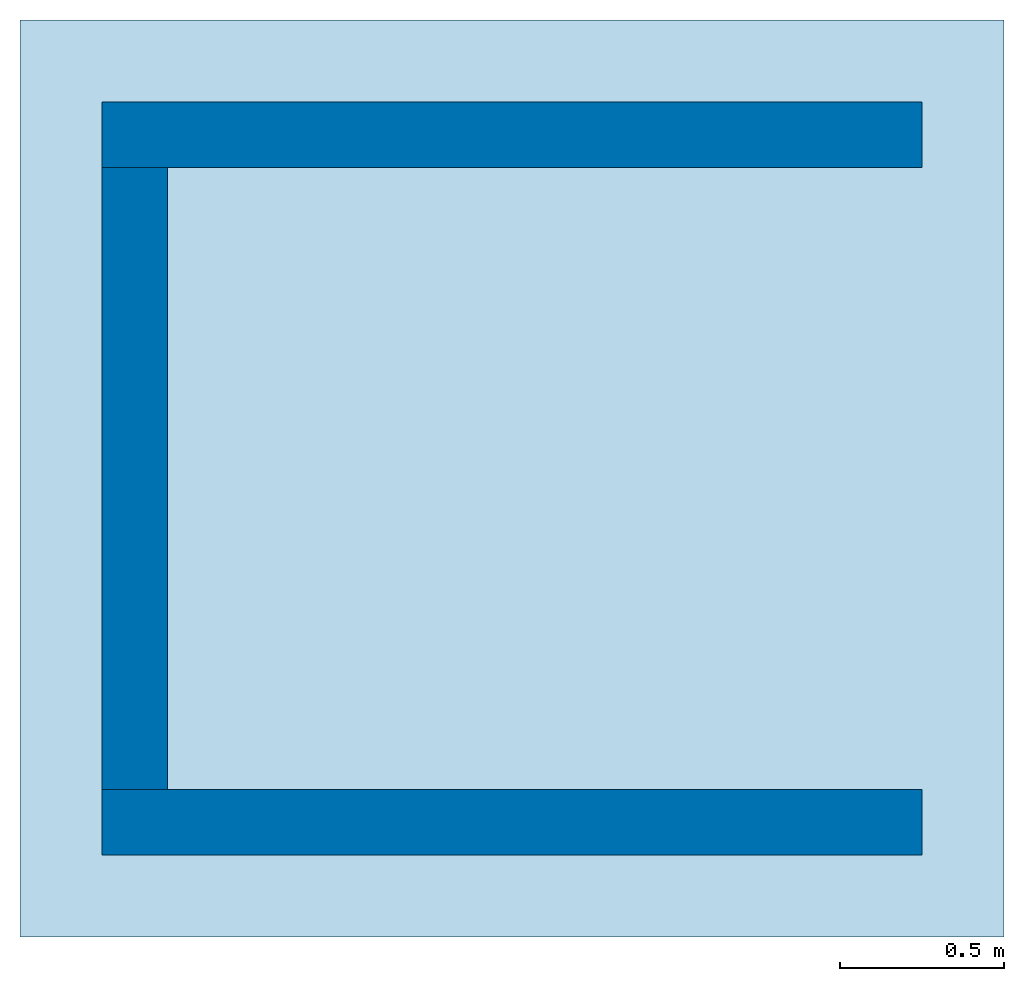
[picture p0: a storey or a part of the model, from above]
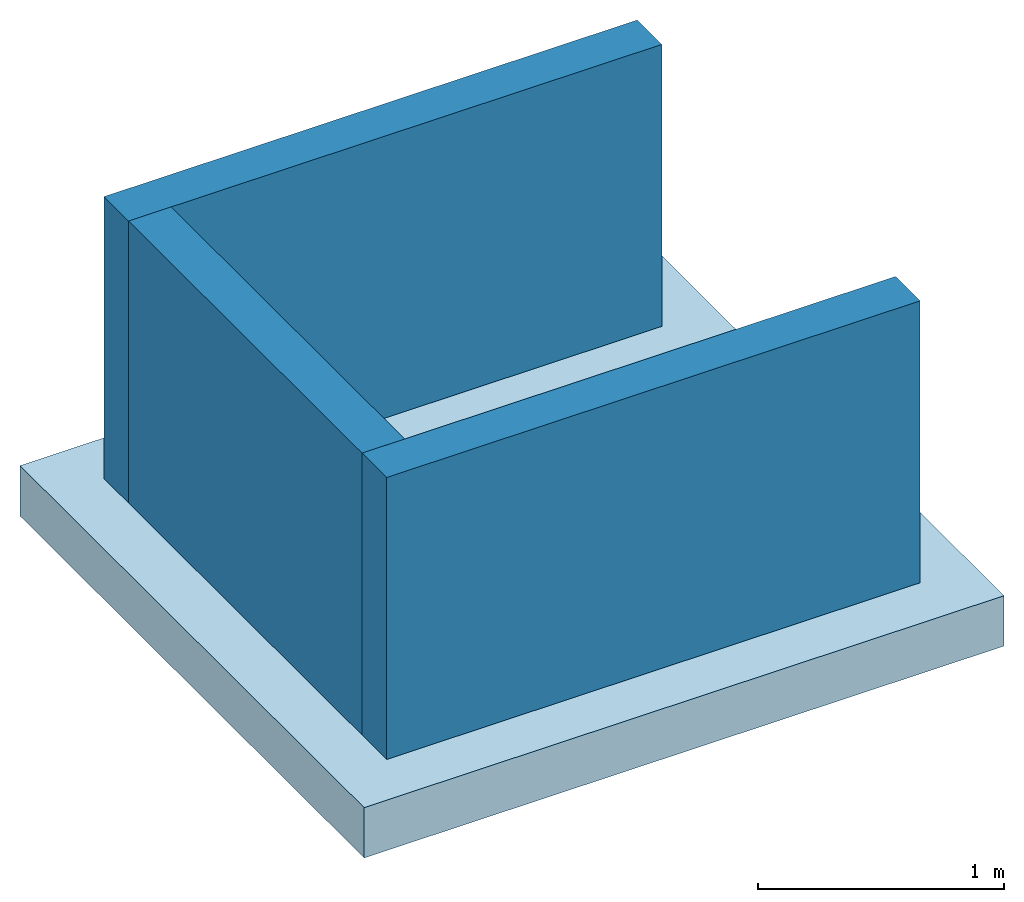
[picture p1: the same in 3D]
Properties of the parts of a building model (IFC4X3_ADD2), part 18 of 28

# IfcWall: BB_10.02.31_Verrolbare binnenwand_ lokaal K.00.503_ 20200211_GMO_XX_Geen, BB_10.02.31_Verrolbare binnenwand, lokaal K.00.503, 20200211_GMO:XX_Geen:25727278
In: 000
PredefinedType: MOVABLE; Material: BB_MDF
Cpset_Wall - LevelOfAccuracy: in te vullen door Buildwise
IfcBuildingStorey - Level: 000; Elevation from Level: 0
IfcClassificationReference - Keynote: 10.02.31#01; GVH_artnr 01: 10.02.31#01; GVH_artnr 02: geen waarde gevonden; GVH_artnr 03: geen waarde gevonden; GVH_artnr 04: geen waarde gevonden; GVH_artnr 05: geen waarde gevonden; GVH_artnr 06: geen waarde gevonden; TDS_link: .\05 As Builtdossier\2. Bouwkunde\2.1 Architectuur\2.1.10 wanden\TF A 10.02.30 A - Verrolbare binnenwand.pdf
IfcElement - BB_Element_Lokaalnummer01: K.00.503
IfcRoot - Name: XX_Geen
Qto_WallBaseQuantities - NetVolume: 2.29214
Pset_ConcreteElementGeneral - ConstructionMethod: prefabricated
Pset_Condition - AssessmentCondition: Empty
Pset_EnvironmentalImpactIndicators - Reference: XX_Geen; sets with these values: 2
Pset_WallCommon - Reference: XX_Geen; AcousticRating: 52; FireRating: EI30; IsExternal: no

# IfcWall: BB_10.02.31_Verrolbare binnenwand_ lokaal K.10.105_GMO_XX_Geen, BB_10.02.31_Verrolbare binnenwand, lokaal K.10.105_GMO:XX_Geen:24171988
In: 010
PredefinedType: MOVABLE; Material: BB_MDF
Cpset_Wall - LevelOfAccuracy: in te vullen door Buildwise
IfcBuildingStorey - Level: 010; Elevation from Level: 0
IfcClassificationReference - Keynote: 10.02.31#01; GVH_artnr 01: 10.02.31#01; GVH_artnr 02: geen waarde gevonden; GVH_artnr 03: geen waarde gevonden; GVH_artnr 04: geen waarde gevonden; GVH_artnr 05: geen waarde gevonden; GVH_artnr 06: geen waarde gevonden; TDS_link: .\05 As Builtdossier\2. Bouwkunde\2.1 Architectuur\2.1.10 wanden\TF A 10.02.30 A - Verrolbare binnenwand.pdf
IfcElement - BB_Element_Lokaalnummer01: K.10.105
IfcRoot - Name: XX_Geen
Qto_WallBaseQuantities - NetVolume: 1.21016
Pset_ConcreteElementGeneral - ConstructionMethod: prefabricated
Pset_Condition - AssessmentCondition: Empty
Pset_EnvironmentalImpactIndicators - Reference: XX_Geen; sets with these values: 2
Pset_WallCommon - Reference: XX_Geen; AcousticRating: 52; FireRating: EI30; IsExternal: no

# IfcWall: BB_Beton_Bestaand 0 (3)
Type - Material: BB_Beton_Bestaand
PredefinedType: SOLIDWALL
IfcRoot - Name: BB_XX_Wand uit beton, 200 mm
Qto_WallBaseQuantities - Width: 200
Pset_EnvironmentalImpactIndicators - Reference: BB_XX_Wand uit beton, 200 mm; sets with these values: 2
Pset_WallCommon - Reference: BB_XX_Wand uit beton, 200 mm; IsExternal: yes; LoadBearing: yes; ExtendToStructure: no
Name (Basic Wall:BB_XX_Wand uit beton, 200 mm:...) | In | Length | NetVolume | Height | GrossFootprintArea | GrossVolume | GrossSideArea = NetSideArea
34053417 | K20 | 431.095 | 0.125154 | 1890 | 0.066219 | 0.162954 | 0.81477 | Cpset_Wall - LevelOfAccuracy: in te vullen door Buildwise; IfcBuildingStorey - Base Offset: 600; Top Offset: -3450; Base Constraint: K20; Top Constraint: Up to level: 000; IfcClassificationReference - TDS_link: .\05 As Builtdossier\2. Bouwkunde\2.2. Stabiliteit\2.2.0 technische fiche's\TF S 4.3 A-beton.pdf; Pset_Condition - AssessmentCondition: Empty; Pset_WallCommon - FireRating: EI60; ThermalTransmittance: 8
34150345 | 030 | 146.018 | 0.0385148 | 3620 | 0.0292035 | 0.1448 | 0.724
34150661 | 030 | 63.175 | 0.00722385 | 3620 | 0.012635 | 0.0646843 | 0.323421

# IfcWall: BB_Beton_Bestaand 100 (3)
Type - Material: BB_Beton_Bestaand
PredefinedType: SOLIDWALL
Cpset_Wall - LevelOfAccuracy: in te vullen door Buildwise
IfcBuildingStorey - Base Offset: -200
IfcClassificationReference - GVH_artnr 01: geen waarde gevonden; GVH_artnr 02: geen waarde gevonden; GVH_artnr 03: geen waarde gevonden; GVH_artnr 04: geen waarde gevonden; GVH_artnr 05: geen waarde gevonden; GVH_artnr 06: geen waarde gevonden
IfcRoot - Name: BB_XX_Wand uit beton, 200 mm
Qto_WallBaseQuantities - Length: 100; NetVolume: 0.072; Height: 3600; Width: 200; GrossFootprintArea: 0.02; GrossVolume: 0.144; GrossSideArea: 0.72; NetSideArea: 0.72
Pset_Condition - AssessmentCondition: Empty
Pset_EnvironmentalImpactIndicators - Reference: BB_XX_Wand uit beton, 200 mm; sets with these values: 2
Pset_WallCommon - Reference: BB_XX_Wand uit beton, 200 mm; IsExternal: yes; LoadBearing: no; ExtendToStructure: no
Name (Basic Wall:BB_XX_Wand uit beton, 200 mm:...) | In | Top Offset | Base Constraint | Top Constraint
650663 | 010 | -200 | 010 | Up to level: 020
695802 | 020 | -200 | 020 | Up to level: 030
705273 | 030 | 3400 | 030 | Up to level: 030

# IfcWall: BB_Beton_Bestaand 120 (4)
Type - Material: BB_Beton_Bestaand
PredefinedType: SOLIDWALL
Cpset_Wall - LevelOfAccuracy: in te vullen door Buildwise
IfcBuildingStorey - Base Offset: -200; Top Offset: 0
IfcClassificationReference - GVH_artnr 01: geen waarde gevonden; GVH_artnr 02: geen waarde gevonden; GVH_artnr 03: geen waarde gevonden; GVH_artnr 04: geen waarde gevonden; GVH_artnr 05: geen waarde gevonden; GVH_artnr 06: geen waarde gevonden
IfcRoot - Name: BB_XX_Wand uit beton, 200 mm
Qto_WallBaseQuantities - Length: 120; NetVolume: 0.06912; Height: 2880; Width: 200; GrossFootprintArea: 0.024; GrossVolume: 0.1152; GrossSideArea: 0.576; NetSideArea: 0.576
Pset_Condition - AssessmentCondition: Empty
Pset_EnvironmentalImpactIndicators - Reference: BB_XX_Wand uit beton, 200 mm; sets with these values: 2
Pset_WallCommon - Reference: BB_XX_Wand uit beton, 200 mm; IsExternal: yes; LoadBearing: no; ExtendToStructure: no
Name (Basic Wall:BB_XX_Wand uit beton, 200 mm:...) | In | Base Constraint
864371 | 000 | 000
866427 | 010 | 010 | Pset_WallCommon - FireRating: EI60
867070 | 020 | 020
867763 | 030 | 030

# IfcWall: BB_Beton_Bestaand 170 (28)
Type - Material: BB_Beton_Bestaand
PredefinedType: SOLIDWALL
Cpset_Wall - LevelOfAccuracy: in te vullen door Buildwise
IfcClassificationReference - GVH_artnr 01: geen waarde gevonden; GVH_artnr 02: geen waarde gevonden; GVH_artnr 03: geen waarde gevonden; GVH_artnr 04: geen waarde gevonden; GVH_artnr 05: geen waarde gevonden; GVH_artnr 06: geen waarde gevonden
IfcRoot - Name: BB_XX_Wand uit beton, 170 mm
Qto_WallBaseQuantities - Width: 170
Pset_Condition - AssessmentCondition: Empty
Pset_EnvironmentalImpactIndicators - Reference: BB_XX_Wand uit beton, 170 mm; sets with these values: 2
Pset_WallCommon - Reference: BB_XX_Wand uit beton, 170 mm; IsExternal: yes; LoadBearing: no; ExtendToStructure: no
Name (Basic Wall:BB_XX_Wand uit beton, 170 mm:...) | In | Base Offset | Top Offset | Base Constraint | Length | NetVolume = GrossVolume | Height | GrossFootprintArea | GrossSideArea = NetSideArea | Top Constraint
947525 | K20 | -400 | 0 | K20 | 738.26 | 0.376513 | 3000 | 0.125504 | 2.21478
802965 | K10 | -200 | 0 | K10 | 750 | 0.4131 | 3240 | 0.1275 | 2.43
931243 | K10 | -100 | -200 | K10 | 750 | 0.40035 | 3140 | 0.1275 | 2.355 | Up to level: 000
447762 | 000 | -200 | -200 | 000 | 750 | 0.459 | 3600 | 0.1275 | 2.7 | Up to level: 010
448611 | 000 | -200 | -200 | 000 | 750 | 0.459 | 3600 | 0.1275 | 2.7 | Up to level: 010
457372 | 000 | -200 | -200 | 000 | 750 | 0.459 | 3600 | 0.1275 | 2.7 | Up to level: 010
457856 | 000 | -200 | -200 | 000 | 750 | 0.459 | 3600 | 0.1275 | 2.7 | Up to level: 010
467338 | 000 | -200 | -200 | 000 | 750 | 0.459 | 3600 | 0.1275 | 2.7 | Up to level: 010
480120 | 000 | -460 | -200 | 000 | 750 | 0.49215 | 3860 | 0.1275 | 2.895 | Up to level: 010
482794 | 000 | -460 | -200 | 000 | 750 | 0.49215 | 3860 | 0.1275 | 2.895 | Up to level: 010
488155 | 000 | -200 | -200 | 000 | 750 | 0.459 | 3600 | 0.1275 | 2.7 | Up to level: 010
608563 | 010 | -200 | 0 | 010 | 750 | 0.459 | 3600 | 0.1275 | 2.7
610271 | 010 | -200 | 0 | 010 | 750 | 0.459 | 3600 | 0.1275 | 2.7
610940 | 010 | -200 | 0 | 010 | 750 | 0.459 | 3600 | 0.1275 | 2.7
612382 | 010 | -200 | -200 | 010 | 750 | 0.459 | 3600 | 0.1275 | 2.7 | Up to level: 020
612532 | 010 | -200 | -200 | 010 | 750 | 0.459 | 3600 | 0.1275 | 2.7 | Up to level: 020
631716 | 010 | -200 | -200 | 010 | 750 | 0.459 | 3600 | 0.1275 | 2.7 | Up to level: 020
632386 | 010 | -200 | -200 | 010 | 750 | 0.459 | 3600 | 0.1275 | 2.7 | Up to level: 020
634288 | 010 | -200 | -200 | 010 | 785 | 0.48042 | 3600 | 0.13345 | 2.826 | Up to level: 020
671261 | 010 | -200 | -200 | 010 | 750 | 0.459 | 3600 | 0.1275 | 2.7 | Up to level: 020
695353 | 010 | -200 | -200 | 010 | 750 | 0.918 | 7200 | 0.1275 | 5.4 | Up to level: 030
695374 | 020 | -200 | 0 | 020 | 750 | 0.459 | 3600 | 0.1275 | 2.7
695388 | 020 | -200 | -200 | 020 | 750 | 0.459 | 3600 | 0.1275 | 2.7 | Up to level: 030
695389 | 020 | -200 | -200 | 020 | 750 | 0.459 | 3600 | 0.1275 | 2.7 | Up to level: 030
695561 | 020 | -200 | -200 | 020 | 750 | 0.459 | 3600 | 0.1275 | 2.7 | Up to level: 030
695563 | 020 | -200 | -200 | 020 | 750 | 0.459 | 3600 | 0.1275 | 2.7 | Up to level: 030
695578 | 020 | -200 | -200 | 020 | 785 | 0.48042 | 3600 | 0.13345 | 2.826 | Up to level: 030
732515 | 030 | -200 | 740 | 030 | 900 | 0.14382 | 940 | 0.153 | 0.846 | Up to level: 030

# IfcWall: BB_Beton_Bestaand 190 (283)
Type - Material: BB_Beton_Bestaand
PredefinedType: SOLIDWALL
Cpset_Wall - LevelOfAccuracy: in te vullen door Buildwise
IfcRoot - Name: BB_XX_Wand uit beton, 190 mm
Qto_WallBaseQuantities - Width: 190
Pset_Condition - AssessmentCondition: Empty
Pset_EnvironmentalImpactIndicators - Reference: BB_XX_Wand uit beton, 190 mm; sets with these values: 2
Pset_WallCommon - Reference: BB_XX_Wand uit beton, 190 mm; IsExternal: yes
Name (Basic Wall:BB_XX_Wand uit beton, 190 mm:...) | In | Base Offset | Top Offset | Base Constraint | GVH_artnr 01 = GVH_artnr 02 = GVH_artnr 03 = GVH_artnr 04 = GVH_artnr 05 = GVH_artnr 06 | Length | NetVolume | Height | GrossFootprintArea | GrossVolume | GrossSideArea | NetSideArea | LoadBearing | ExtendToStructure | Top Constraint
946732 | K20 | -400 | 0 | K20 | geen waarde gevonden | 935 | 0.504526 | 2840 | 0.17765 | 0.504526 | 2.6554 | 2.6554 | no | no
954449 | K20 | -400 | 0 | K20 | geen waarde gevonden | 5165 | 3.04218 | 3100 | 0.98135 | 3.04218 | 16.0115 | 16.0115 | no | no
1008973 | K20 | -400 | 0 | K20 | geen waarde gevonden | 4910 | 2.33225 | 2500 | 0.9329 | 2.33225 | 12.275 | 12.275 | no | no
1009370 | K20 | -400 | 0 | K20 | geen waarde gevonden | 830 | 0.39425 | 2500 | 0.1577 | 0.39425 | 2.075 | 2.075 | no | no
1009518 | K20 | -400 | 0 | K20 | geen waarde gevonden | 820 | 0.3895 | 2500 | 0.1558 | 0.3895 | 2.05 | 2.05 | no | no
1505733 | K20 | -400 | -1500 | K20 | geen waarde gevonden | 3815 | 1.15976 | 1600 | 0.72485 | 1.15976 | 6.104 | 6.104 | no | no | Up to level: K10
1507029 | K20 | -400 | -50 | K20 | geen waarde gevonden | 1350.72 | 0.782744 | 3050 | 0.256637 | 0.782744 | 4.1197 | 4.1197 | no | no | Up to level: K10
34053556 | K20 | 600 | -3450 | K20 |  | 3701.04 | 1.29493 | 1890 | 0.685147 | 1.32904 | 6.99496 | 6.99496 | yes | no | Up to level: 000 | IfcClassificationReference - TDS_link: .\05 As Builtdossier\2. Bouwkunde\2.2. Stabiliteit\2.2.0 technische fiche's\TF S 4.3 A-beton.pdf; Pset_WallCommon - FireRating: EI60; ThermalTransmittance: 8.42105
34055744 | K20 | 600 | -3450 | K20 |  | 3668.97 | 1.2493 | 1890 | 0.661003 | 1.2493 | 6.57524 | 6.57524 | yes | no | Up to level: 000 | IfcClassificationReference - TDS_link: .\05 As Builtdossier\2. Bouwkunde\2.2. Stabiliteit\2.2.0 technische fiche's\TF S 4.3 A-beton.pdf; Pset_WallCommon - FireRating: EI60; ThermalTransmittance: 8.42105
800965 | K10 | -260 | -200 | K10 | geen waarde gevonden | 1125 | 0.705375 | 3300 | 0.21375 | 0.705375 | 3.7125 | 3.7125 | no | no | Up to level: 000
801017 | K10 | -100 | -200 | K10 | geen waarde gevonden | 900 | 0.53694 | 3140 | 0.171 | 0.53694 | 2.826 | 2.826 | no | no | Up to level: 000
929693 | K10 | 0 | 0 | K10 | geen waarde gevonden | 8005 | 4.62369 | 3040 | 1.52095 | 4.62369 | 24.3352 | 24.3352 | no | no | Pset_WallCommon - FireRating: EI60
930507 | K10 | -100 | 0 | K10 | geen waarde gevonden | 5569.87 | 2.58219 | 2440 | 1.05828 | 2.58219 | 13.5905 | 13.5905 | no | no
948022 | K10 | -100 | 0 | K10 | geen waarde gevonden | 5210 | 2.41536 | 2440 | 0.9899 | 2.41536 | 12.7124 | 12.7124 | no | no
1499547 | K10 | -1500 | 1150 | K10 | geen waarde gevonden | 2650 | 1.33428 | 2650 | 0.5035 | 1.33428 | 7.0225 | 7.0225 | no | no | Up to level: K10
447511 | 000 | -200 | 840 | 000 | geen waarde gevonden | 5210 | 1.0295 | 1040 | 0.9899 | 1.0295 | 5.4184 | 5.4184 | no | no | Up to level: 000
448132 | 000 | -200 | -920 | 000 | geen waarde gevonden | 1120 | 0.612864 | 2880 | 0.2128 | 0.612864 | 3.2256 | 3.2256 | no | no | Up to level: 010
448179 | 000 | -200 | -200 | 000 | geen waarde gevonden | 900 | 0.6156 | 3600 | 0.171 | 0.6156 | 3.24 | 3.24 | no | no | Up to level: 010
448484 | 000 | -200 | 840 | 000 | geen waarde gevonden | 7010 | 1.38518 | 1040 | 1.3319 | 1.38518 | 7.2904 | 7.2904 | no | no | Up to level: 000
455631 | 000 | -200 | 840 | 000 | geen waarde gevonden | 6710 | 1.3259 | 1040 | 1.2749 | 1.3259 | 6.9784 | 6.9784 | no | no | Up to level: 000
456098 | 000 | -200 | 840 | 000 | geen waarde gevonden | 6710 | 1.3259 | 1040 | 1.2749 | 1.3259 | 6.9784 | 6.9784 | no | no | Up to level: 000
456600 | 000 | -200 | 840 | 000 | geen waarde gevonden | 6710 | 1.3259 | 1040 | 1.2749 | 1.3259 | 6.9784 | 6.9784 | no | no | Up to level: 000
457578 | 000 | -200 | 840 | 000 | geen waarde gevonden | 7010 | 1.38518 | 1040 | 1.3319 | 1.38518 | 7.2904 | 7.2904 | no | no | Up to level: 000
459200 | 000 | -200 | 840 | 000 | geen waarde gevonden | 5040 | 0.995904 | 1040 | 0.9576 | 0.995904 | 5.2416 | 5.2416 | no | no | Up to level: 000
460681 | 000 | -200 | -920 | 000 | geen waarde gevonden | 1965 | 1.07525 | 2880 | 0.37335 | 1.07525 | 5.6592 | 5.6592 | no | no | Up to level: 010
466354 | 000 | -200 | -2760 | 000 | geen waarde gevonden | 6710 | 1.3259 | 1040 | 1.2749 | 1.3259 | 6.9784 | 6.9784 | no | no | Up to level: 010
466605 | 000 | -200 | -2770 | 000 | geen waarde gevonden | 4910 | 0.960887 | 1030 | 0.9329 | 0.960887 | 5.0573 | 5.0573 | no | no | Up to level: 010
466865 | 000 | -200 | -2760 | 000 | geen waarde gevonden | 6772.5 | 1.33825 | 1040 | 1.28678 | 1.33825 | 7.0434 | 7.0434 | no | no | Up to level: 010
468068 | 000 | -200 | -2760 | 000 | geen waarde gevonden | 1090 | 0.215384 | 1040 | 0.2071 | 0.215384 | 1.1336 | 1.1336 | no | no | Up to level: 010
469278 | 000 | -200 | -2760 | 000 | geen waarde gevonden | 5210 | 1.0295 | 1040 | 0.9899 | 1.0295 | 5.4184 | 5.4184 | no | no | Up to level: 010
474434 | 000 | -200 | 840 | 000 | geen waarde gevonden | 5585 | 1.1036 | 1040 | 1.06115 | 1.1036 | 5.8084 | 5.8084 | no | no | Up to level: 000 | Pset_WallCommon - FireRating: EI60
475318 | 000 | -200 | 840 | 000 | geen waarde gevonden | 1785 | 0.352716 | 1040 | 0.33915 | 0.352716 | 1.8564 | 1.8564 | no | no | Up to level: 000
482367 | 000 | -200 | 840 | 000 | geen waarde gevonden | 5210 | 1.0295 | 1040 | 0.9899 | 1.0295 | 5.4184 | 5.4184 | no | no | Up to level: 000
483354 | 000 | -200 | -920 | 000 | geen waarde gevonden | 1055 | 0.577296 | 2880 | 0.20045 | 0.577296 | 3.0384 | 3.0384 | no | no | Up to level: 010
485879 | 000 | -200 | 840 | 000 | geen waarde gevonden | 6710 | 1.3259 | 1040 | 1.2749 | 1.3259 | 6.9784 | 6.9784 | no | no | Up to level: 000
486109 | 000 | -200 | 840 | 000 | geen waarde gevonden | 4910 | 0.970216 | 1040 | 0.9329 | 0.970216 | 5.1064 | 5.1064 | no | no | Up to level: 000
486202 | 000 | -200 | 840 | 000 | geen waarde gevonden | 6710 | 1.3259 | 1040 | 1.2749 | 1.3259 | 6.9784 | 6.9784 | no | no | Up to level: 000
486352 | 000 | -200 | 840 | 000 | geen waarde gevonden | 7030 | 1.38913 | 1040 | 1.3357 | 1.38913 | 7.3112 | 7.3112 | no | no | Up to level: 000
486873 | 000 | -200 | 840 | 000 | geen waarde gevonden | 6690 | 1.32194 | 1040 | 1.2711 | 1.32194 | 6.9576 | 6.9576 | no | no | Up to level: 000
487011 | 000 | -200 | 840 | 000 | geen waarde gevonden | 6710 | 1.3259 | 1040 | 1.2749 | 1.3259 | 6.9784 | 6.9784 | no | no | Up to level: 000
487204 | 000 | -200 | 840 | 000 | geen waarde gevonden | 6710 | 1.3259 | 1040 | 1.2749 | 1.3259 | 6.9784 | 6.9784 | no | no | Up to level: 000
488072 | 000 | -200 | 840 | 000 | geen waarde gevonden | 6990 | 1.38122 | 1040 | 1.3281 | 1.38122 | 7.2696 | 7.2696 | no | no | Up to level: 000
488381 | 000 | -200 | 840 | 000 | geen waarde gevonden | 5040 | 0.995904 | 1040 | 0.9576 | 0.995904 | 5.2416 | 5.2416 | no | no | Up to level: 000
488499 | 000 | -200 | -920 | 000 | geen waarde gevonden | 1480 | 0.809856 | 2880 | 0.2812 | 0.809856 | 4.2624 | 4.2624 | no | no | Up to level: 010
488660 | 000 | -200 | -920 | 000 | geen waarde gevonden | 1965 | 1.07525 | 2880 | 0.37335 | 1.07525 | 5.6592 | 5.6592 | no | no | Up to level: 010
502365 | 000 | -200 | 0 | 000 | geen waarde gevonden | 2055 | 1.1245 | 2880 | 0.39045 | 1.1245 | 5.9184 | 5.9184 | no | no | Pset_WallCommon - FireRating: EI60
502553 | 000 | -200 | 0 | 000 | geen waarde gevonden | 1710 | 0.935712 | 2880 | 0.3249 | 0.935712 | 4.9248 | 4.9248 | no | no
502707 | 000 | -200 | -920 | 000 | geen waarde gevonden | 754.996 | 0.413134 | 2880 | 0.143449 | 0.413134 | 2.17439 | 2.17439 | no | no | Up to level: 010
504611 | 000 | -200 | -920 | 000 | geen waarde gevonden | 555 | 0.303696 | 2880 | 0.10545 | 0.303696 | 1.5984 | 1.5984 | no | no | Up to level: 010
504683 | 000 | -200 | -920 | 000 | geen waarde gevonden | 1710 | 0.935712 | 2880 | 0.3249 | 0.935712 | 4.9248 | 4.9248 | no | no | Up to level: 010
507856 | 000 | -200 | -920 | 000 | geen waarde gevonden | 1710 | 0.935712 | 2880 | 0.3249 | 0.935712 | 4.9248 | 4.9248 | no | no | Up to level: 010
507907 | 000 | -200 | -920 | 000 | geen waarde gevonden | 555 | 0.303696 | 2880 | 0.10545 | 0.303696 | 1.5984 | 1.5984 | no | no | Up to level: 010
619767 | 000 | -200 | -920 | 000 | geen waarde gevonden | 1480 | 0.809856 | 2880 | 0.2812 | 0.809856 | 4.2624 | 4.2624 | no | no | Up to level: 010
648277 | 000 | 840 | -920 | 000 | geen waarde gevonden | 1090 | 0.381064 | 1840 | 0.2071 | 0.381064 | 2.0056 | 2.0056 | no | no | Up to level: 010
861782 | 000 | -200 | 0 | 000 | geen waarde gevonden | 754.996 | 0.413134 | 2880 | 0.143449 | 0.413134 | 2.17439 | 2.17439 | no | no
862392 | 000 | -200 | 0 | 000 | geen waarde gevonden | 1710 | 0.935712 | 2880 | 0.3249 | 0.935712 | 4.9248 | 4.9248 | no | no
862933 | 000 | -200 | 0 | 000 | geen waarde gevonden | 1710 | 0.935712 | 2880 | 0.3249 | 0.935712 | 4.9248 | 4.9248 | no | no | Pset_WallCommon - FireRating: EI60
863223 | 000 | -200 | 840 | 000 | geen waarde gevonden | 990 | 0.195624 | 1040 | 0.1881 | 0.195624 | 1.0296 | 1.0296 | no | no | Up to level: 000 | Pset_WallCommon - FireRating: EI60
863786 | 000 | -200 | 0 | 000 | geen waarde gevonden | 645.837 | 0.301418 | 2880 | 0.104659 | 0.353402 | 1.86001 | 1.86001 | no | no | Pset_WallCommon - FireRating: EI60
1619029 | 000 | -200 | 840 | 000 | geen waarde gevonden | 2105 | 0.415948 | 1040 | 0.39995 | 0.415948 | 2.1892 | 2.1892 | no | no | Up to level: 000
1619101 | 000 | -200 | 840 | 000 | geen waarde gevonden | 1320 | 0.260832 | 1040 | 0.2508 | 0.260832 | 1.3728 | 1.3728 | no | no | Up to level: 000
1727261 | 000 | -200 | -200 | 000 | geen waarde gevonden | 1090 | 0.74556 | 3600 | 0.2071 | 0.74556 | 3.924 | 3.924 | no | no | Up to level: 010
1728721 | 000 | -200 | -2760 | 000 | geen waarde gevonden | 4583.2 | 0.899373 | 1040 | 0.864782 | 0.905641 | 4.76653 | 4.76653 | no | no | Up to level: 010
34114387 | 000 | -320 | 820 | 000 |  | 2574.93 | 0.55773 | 1140 | 0.489237 | 0.55773 | 2.93542 | 2.93542 | yes | no | Up to level: 000 | IfcClassificationReference - TDS_link: .\05 As Builtdossier\2. Bouwkunde\2.2. Stabiliteit\2.2.0 technische fiche's\TF S 4.3 A-beton.pdf; Pset_WallCommon - ThermalTransmittance: 8.42105
34114506 | 000 | -320 | 820 | 000 |  | 25055 | 5.42691 | 1140 | 4.76045 | 5.42691 | 28.5627 | 28.5627 | yes | no | Up to level: 000 | IfcClassificationReference - TDS_link: .\05 As Builtdossier\2. Bouwkunde\2.2. Stabiliteit\2.2.0 technische fiche's\TF S 4.3 A-beton.pdf; Pset_WallCommon - ThermalTransmittance: 8.42105
34114577 | 000 | -320 | 820 | 000 |  | 2569.93 | 0.556647 | 1140 | 0.488287 | 0.556647 | 2.92972 | 2.92972 | yes | no | Up to level: 000 | IfcClassificationReference - TDS_link: .\05 As Builtdossier\2. Bouwkunde\2.2. Stabiliteit\2.2.0 technische fiche's\TF S 4.3 A-beton.pdf; Pset_WallCommon - ThermalTransmittance: 8.42105
606733 | 010 | -200 | 840 | 010 | geen waarde gevonden | 7010 | 1.38518 | 1040 | 1.3319 | 1.38518 | 7.2904 | 7.2904 | no | no | Up to level: 010
607491 | 010 | -200 | 0 | 010 | geen waarde gevonden | 1125 | 0.6156 | 2880 | 0.21375 | 0.6156 | 3.24 | 3.24 | no | no
607577 | 010 | -200 | 0 | 010 | geen waarde gevonden | 900 | 0.6156 | 3600 | 0.171 | 0.6156 | 3.24 | 3.24 | no | no
608267 | 010 | -200 | -2760 | 010 | geen waarde gevonden | 5210 | 1.0295 | 1040 | 0.9899 | 1.0295 | 5.4184 | 5.4184 | no | no | Up to level: 020
609078 | 010 | -200 | -2760 | 010 | geen waarde gevonden | 6710 | 1.3259 | 1040 | 1.2749 | 1.3259 | 6.9784 | 6.9784 | no | no | Up to level: 020
609304 | 010 | -200 | -2760 | 010 | geen waarde gevonden | 4910 | 0.970216 | 1040 | 0.9329 | 0.970216 | 5.1064 | 5.1064 | no | no | Up to level: 020
609464 | 010 | -200 | -2760 | 010 | geen waarde gevonden | 6710 | 1.3259 | 1040 | 1.2749 | 1.3259 | 6.9784 | 6.9784 | no | no | Up to level: 020
609645 | 010 | -200 | -2760 | 010 | geen waarde gevonden | 5210 | 1.0295 | 1040 | 0.9899 | 1.0295 | 5.4184 | 5.4184 | no | no | Up to level: 020
611773 | 010 | -200 | 840 | 010 | geen waarde gevonden | 6710 | 1.3259 | 1040 | 1.2749 | 1.3259 | 6.9784 | 6.9784 | no | no | Up to level: 010
611895 | 010 | -200 | 840 | 010 | geen waarde gevonden | 6710 | 1.3259 | 1040 | 1.2749 | 1.3259 | 6.9784 | 6.9784 | no | no | Up to level: 010
612010 | 010 | -200 | 840 | 010 | geen waarde gevonden | 6710 | 1.3259 | 1040 | 1.2749 | 1.3259 | 6.9784 | 6.9784 | no | no | Up to level: 010
612904 | 010 | -200 | 840 | 010 | geen waarde gevonden | 7010 | 1.38518 | 1040 | 1.3319 | 1.38518 | 7.2904 | 7.2904 | no | no | Up to level: 010
613241 | 010 | -200 | 840 | 010 | geen waarde gevonden | 5040 | 0.995904 | 1040 | 0.9576 | 0.995904 | 5.2416 | 5.2416 | no | no | Up to level: 010
621810 | 010 | -200 | -920 | 010 | geen waarde gevonden | 1480 | 0.809856 | 2880 | 0.2812 | 0.809856 | 4.2624 | 4.2624 | no | no | Up to level: 020
622108 | 010 | -200 | -920 | 010 | geen waarde gevonden | 2015 | 1.10261 | 2880 | 0.38285 | 1.10261 | 5.8032 | 5.8032 | no | no | Up to level: 020
627347 | 010 | -200 | -2760 | 010 | geen waarde gevonden | 1090 | 0.215384 | 1040 | 0.2071 | 0.215384 | 1.1336 | 1.1336 | no | no | Up to level: 020
628989 | 010 | -200 | -920 | 010 | geen waarde gevonden | 1480 | 0.809856 | 2880 | 0.2812 | 0.809856 | 4.2624 | 4.2624 | no | no | Up to level: 020
629070 | 010 | -200 | -920 | 010 | geen waarde gevonden | 2015 | 1.10261 | 2880 | 0.38285 | 1.10261 | 5.8032 | 5.8032 | no | no | Up to level: 020
629846 | 010 | -200 | 840 | 010 | geen waarde gevonden | 5040 | 0.995904 | 1040 | 0.9576 | 0.995904 | 5.2416 | 5.2416 | no | no | Up to level: 010
632115 | 010 | -200 | 840 | 010 | geen waarde gevonden | 7010 | 1.38518 | 1040 | 1.3319 | 1.38518 | 7.2904 | 7.2904 | no | no | Up to level: 010
633823 | 010 | -200 | 840 | 010 | geen waarde gevonden | 6710 | 1.3259 | 1040 | 1.2749 | 1.3259 | 6.9784 | 6.9784 | no | no | Up to level: 010
634020 | 010 | -200 | 840 | 010 | geen waarde gevonden | 6710 | 1.3259 | 1040 | 1.2749 | 1.3259 | 6.9784 | 6.9784 | no | no | Up to level: 010
634170 | 010 | -200 | 840 | 010 | geen waarde gevonden | 6690 | 1.32194 | 1040 | 1.2711 | 1.32194 | 6.9576 | 6.9576 | no | no | Up to level: 010
634375 | 010 | -200 | 840 | 010 | geen waarde gevonden | 7010 | 1.38518 | 1040 | 1.3319 | 1.38518 | 7.2904 | 7.2904 | no | no | Up to level: 010
636921 | 010 | -200 | -920 | 010 | geen waarde gevonden | 1090 | 0.596448 | 2880 | 0.2071 | 0.596448 | 3.1392 | 3.1392 | no | no | Up to level: 020
637396 | 010 | -200 | -200 | 010 | geen waarde gevonden | 900 | 0.6156 | 3600 | 0.171 | 0.6156 | 3.24 | 3.24 | no | no | Up to level: 020
639097 | 010 | -200 | 840 | 010 | geen waarde gevonden | 5210 | 1.0295 | 1040 | 0.9899 | 1.0295 | 5.4184 | 5.4184 | no | no | Up to level: 010
641060 | 010 | -200 | 840 | 010 | geen waarde gevonden | 6710 | 1.3259 | 1040 | 1.2749 | 1.3259 | 6.9784 | 6.9784 | no | no | Up to level: 010
641477 | 010 | -200 | 840 | 010 | geen waarde gevonden | 4910 | 0.970216 | 1040 | 0.9329 | 0.970216 | 5.1064 | 5.1064 | no | no | Up to level: 010
641688 | 010 | -200 | 840 | 010 | geen waarde gevonden | 6710 | 1.3259 | 1040 | 1.2749 | 1.3259 | 6.9784 | 6.9784 | no | no | Up to level: 010
643461 | 010 | -200 | 840 | 010 | geen waarde gevonden | 5585 | 1.1036 | 1040 | 1.06115 | 1.1036 | 5.8084 | 5.8084 | no | no | Up to level: 010 | Pset_WallCommon - FireRating: EI60
643543 | 010 | -200 | 840 | 010 | geen waarde gevonden | 5210 | 1.0295 | 1040 | 0.9899 | 1.0295 | 5.4184 | 5.4184 | no | no | Up to level: 010
644095 | 010 | 840 | -200 | 010 | geen waarde gevonden | 1090 | 0.530176 | 2560 | 0.2071 | 0.530176 | 2.7904 | 2.7904 | no | no | Up to level: 020
648056 | 010 | 840 | -920 | 010 | geen waarde gevonden | 1090 | 0.381064 | 1840 | 0.2071 | 0.381064 | 2.0056 | 2.0056 | no | no | Up to level: 020
650648 | 010 | -200 | 0 | 010 | geen waarde gevonden | 2055 | 1.1245 | 2880 | 0.39045 | 1.1245 | 5.9184 | 5.9184 | no | no | Pset_WallCommon - FireRating: EI60
650649 | 010 | -200 | -920 | 010 | geen waarde gevonden | 1710 | 0.935712 | 2880 | 0.3249 | 0.935712 | 4.9248 | 4.9248 | no | no | Up to level: 020
650650 | 010 | -200 | 0 | 010 | geen waarde gevonden | 754.996 | 0.413134 | 2880 | 0.143449 | 0.413134 | 2.17439 | 2.17439 | no | no
855519 | 010 | -200 | 0 | 010 | geen waarde gevonden | 555 | 0.303696 | 2880 | 0.10545 | 0.303696 | 1.5984 | 1.5984 | no | no
856027 | 010 | -200 | 0 | 010 | geen waarde gevonden | 1710 | 0.935712 | 2880 | 0.3249 | 0.935712 | 4.9248 | 4.9248 | no | no
856919 | 010 | -200 | 0 | 010 | geen waarde gevonden | 555 | 0.303696 | 2880 | 0.10545 | 0.303696 | 1.5984 | 1.5984 | no | no
857362 | 010 | -200 | -920 | 010 | geen waarde gevonden | 1710 | 0.935712 | 2880 | 0.3249 | 0.935712 | 4.9248 | 4.9248 | no | no
866419 | 010 | -200 | 0 | 010 | geen waarde gevonden | 754.996 | 0.413134 | 2880 | 0.143449 | 0.413134 | 2.17439 | 2.17439 | no | no
866421 | 010 | -200 | 0 | 010 | geen waarde gevonden | 1710 | 0.935712 | 2880 | 0.3249 | 0.935712 | 4.9248 | 4.9248 | no | no
866423 | 010 | -200 | 0 | 010 | geen waarde gevonden | 1710 | 0.935712 | 2880 | 0.3249 | 0.935712 | 4.9248 | 4.9248 | no | no | Pset_WallCommon - FireRating: EI60
866424 | 010 | -200 | 840 | 010 | geen waarde gevonden | 990 | 0.195624 | 1040 | 0.1881 | 0.195624 | 1.0296 | 1.0296 | no | no | Up to level: 010 | Pset_WallCommon - FireRating: EI60
866426 | 010 | -200 | 0 | 010 | geen waarde gevonden | 645.837 | 0.301418 | 2880 | 0.104659 | 0.353402 | 1.86001 | 1.86001 | no | no | Pset_WallCommon - FireRating: EI60
1729918 | 010 | -200 | 840 | 010 | geen waarde gevonden | 1090 | 0.215384 | 1040 | 0.2071 | 0.215384 | 1.1336 | 1.1336 | no | no | Up to level: 010
1730511 | 010 | -200 | -2760 | 010 | geen waarde gevonden | 4581.94 | 0.899118 | 1040 | 0.864536 | 0.905392 | 4.76522 | 4.76522 | no | no | Up to level: 020
2101640 | 010 | -200 | 80 | 010 | geen waarde gevonden | 1890 | 0.100548 | 280 | 0.3591 | 0.100548 | 0.5292 | 0.5292 | no | no | Up to level: 010
2102132 | 010 | -200 | 80 | 010 | geen waarde gevonden | 1890 | 0.100548 | 280 | 0.3591 | 0.100548 | 0.5292 | 0.5292 | no | no | Up to level: 010
2251730 | 010 | -200 | 250 | 010 | geen waarde gevonden | 3690 | 0.315495 | 450 | 0.7011 | 0.315495 | 1.6605 | 1.6605 | no | no | Up to level: 010
2251817 | 010 | -200 | 250 | 010 | geen waarde gevonden | 5490 | 0.469395 | 450 | 1.0431 | 0.469395 | 2.4705 | 2.4705 | no | no | Up to level: 010
2252020 | 010 | -200 | 250 | 010 | geen waarde gevonden | 5490 | 0.469395 | 450 | 1.0431 | 0.469395 | 2.4705 | 2.4705 | no | no | Up to level: 010
2252171 | 010 | -200 | 250 | 010 | geen waarde gevonden | 5490 | 0.469395 | 450 | 1.0431 | 0.469395 | 2.4705 | 2.4705 | no | no | Up to level: 010
2252630 | 010 | -200 | 250 | 010 | geen waarde gevonden | 3690 | 0.315495 | 450 | 0.7011 | 0.315495 | 1.6605 | 1.6605 | no | no | Up to level: 010
2252841 | 010 | -200 | 250 | 010 | geen waarde gevonden | 5490 | 0.469395 | 450 | 1.0431 | 0.469395 | 2.4705 | 2.4705 | no | no | Up to level: 010
2253248 | 010 | -200 | 250 | 010 | geen waarde gevonden | 5490 | 0.469395 | 450 | 1.0431 | 0.469395 | 2.4705 | 2.4705 | no | no | Up to level: 010
2253460 | 010 | -200 | 250 | 010 | geen waarde gevonden | 5490 | 0.469395 | 450 | 1.0431 | 0.469395 | 2.4705 | 2.4705 | no | no | Up to level: 010
5879425 | 010 | -200 | 80 | 010 | geen waarde gevonden | 1890 | 0.100548 | 280 | 0.3591 | 0.100548 | 0.5292 | 0.5292 | no | no | Up to level: 010
695354 | 020 | -200 | 840 | 020 | geen waarde gevonden | 7010 | 1.38518 | 1040 | 1.3319 | 1.38518 | 7.2904 | 7.2904 | no | no | Up to level: 020
695355 | 020 | -200 | 0 | 020 | geen waarde gevonden | 1090 | 0.596448 | 2880 | 0.2071 | 0.596448 | 3.1392 | 3.1392 | no | no
695356 | 020 | -200 | 0 | 020 | geen waarde gevonden | 900 | 0.6156 | 3600 | 0.171 | 0.6156 | 3.24 | 3.24 | no | no
695357 | 020 | -200 | 0 | 020 | geen waarde gevonden | 5210 | 1.0295 | 1040 | 0.9899 | 1.0295 | 5.4184 | 5.4184 | no | no
695361 | 020 | -200 | 0 | 020 | geen waarde gevonden | 6710 | 1.3259 | 1040 | 1.2749 | 1.3259 | 6.9784 | 6.9784 | no | no
695362 | 020 | -200 | 0 | 020 | geen waarde gevonden | 4910 | 0.960887 | 1030 | 0.9329 | 0.960887 | 5.0573 | 5.0573 | no | no
695363 | 020 | -200 | 0 | 020 | geen waarde gevonden | 6710 | 1.3259 | 1040 | 1.2749 | 1.3259 | 6.9784 | 6.9784 | no | no
695364 | 020 | -200 | 0 | 020 | geen waarde gevonden | 5210 | 1.0295 | 1040 | 0.9899 | 1.0295 | 5.4184 | 5.4184 | no | no
695385 | 020 | -200 | 840 | 020 | geen waarde gevonden | 6710 | 1.3259 | 1040 | 1.2749 | 1.3259 | 6.9784 | 6.9784 | no | no | Up to level: 020
695386 | 020 | -200 | 840 | 020 | geen waarde gevonden | 6710 | 1.3259 | 1040 | 1.2749 | 1.3259 | 6.9784 | 6.9784 | no | no | Up to level: 020
695387 | 020 | -200 | 840 | 020 | geen waarde gevonden | 6710 | 1.3259 | 1040 | 1.2749 | 1.3259 | 6.9784 | 6.9784 | no | no | Up to level: 020
695390 | 020 | -200 | 840 | 020 | geen waarde gevonden | 7010 | 1.38518 | 1040 | 1.3319 | 1.38518 | 7.2904 | 7.2904 | no | no | Up to level: 020
695393 | 020 | -200 | 840 | 020 | geen waarde gevonden | 5040 | 0.995904 | 1040 | 0.9576 | 0.995904 | 5.2416 | 5.2416 | no | no | Up to level: 020
695394 | 020 | -200 | 80 | 020 | geen waarde gevonden | 1890 | 0.100548 | 280 | 0.3591 | 0.100548 | 0.5292 | 0.5292 | no | no | Up to level: 020
695465 | 020 | -200 | -920 | 020 | geen waarde gevonden | 1480 | 0.809856 | 2880 | 0.2812 | 0.809856 | 4.2624 | 4.2624 | no | no | Up to level: 030
695466 | 020 | -200 | -920 | 020 | geen waarde gevonden | 2015 | 1.10261 | 2880 | 0.38285 | 1.10261 | 5.8032 | 5.8032 | no | no | Up to level: 030
695529 | 020 | -200 | 0 | 020 | geen waarde gevonden | 1090 | 0.215384 | 1040 | 0.2071 | 0.215384 | 1.1336 | 1.1336 | no | no
695530 | 020 | -200 | 80 | 020 | geen waarde gevonden | 1890 | 0.0700245 | 195 | 0.3591 | 0.0700245 | 0.36855 | 0.36855 | no | yes | Up to level: 020
695538 | 020 | -200 | -920 | 020 | geen waarde gevonden | 1480 | 0.809856 | 2880 | 0.2812 | 0.809856 | 4.2624 | 4.2624 | no | no | Up to level: 030
695539 | 020 | -200 | -920 | 020 | geen waarde gevonden | 2015 | 1.10261 | 2880 | 0.38285 | 1.10261 | 5.8032 | 5.8032 | no | no | Up to level: 030
695542 | 020 | -200 | 840 | 020 | geen waarde gevonden | 5040 | 0.186732 | 195 | 0.9576 | 0.186732 | 0.9828 | 0.9828 | no | yes | Up to level: 020
695562 | 020 | -200 | 840 | 020 | geen waarde gevonden | 7010 | 0.259721 | 195 | 1.3319 | 0.259721 | 1.36695 | 1.36695 | no | yes | Up to level: 020
695571 | 020 | -200 | 840 | 020 | geen waarde gevonden | 6710 | 1.3259 | 1040 | 1.2749 | 1.3259 | 6.9784 | 6.9784 | no | no | Up to level: 020
695572 | 020 | -200 | 840 | 020 | geen waarde gevonden | 6710 | 1.3259 | 1040 | 1.2749 | 1.3259 | 6.9784 | 6.9784 | no | no | Up to level: 020
695575 | 020 | -200 | 840 | 020 | geen waarde gevonden | 6690 | 1.32194 | 1040 | 1.2711 | 1.32194 | 6.9576 | 6.9576 | no | no | Up to level: 020
695579 | 020 | -200 | 840 | 020 | geen waarde gevonden | 7010 | 1.38518 | 1040 | 1.3319 | 1.38518 | 7.2904 | 7.2904 | no | no | Up to level: 020
695628 | 020 | -200 | -920 | 020 | geen waarde gevonden | 1090 | 0.596448 | 2880 | 0.2071 | 0.596448 | 3.1392 | 3.1392 | no | no | Up to level: 030
695629 | 020 | -200 | -200 | 020 | geen waarde gevonden | 900 | 0.6156 | 3600 | 0.171 | 0.6156 | 3.24 | 3.24 | no | no | Up to level: 030
695640 | 020 | -200 | 840 | 020 | geen waarde gevonden | 5210 | 1.0295 | 1040 | 0.9899 | 1.0295 | 5.4184 | 5.4184 | no | no | Up to level: 020
695644 | 020 | -200 | 840 | 020 | geen waarde gevonden | 6710 | 1.3259 | 1040 | 1.2749 | 1.3259 | 6.9784 | 6.9784 | no | no | Up to level: 020
695645 | 020 | -200 | 840 | 020 | geen waarde gevonden | 4910 | 0.970216 | 1040 | 0.9329 | 0.970216 | 5.1064 | 5.1064 | no | no | Up to level: 020
695646 | 020 | -200 | 840 | 020 | geen waarde gevonden | 6710 | 1.3259 | 1040 | 1.2749 | 1.3259 | 6.9784 | 6.9784 | no | no | Up to level: 020
695705 | 020 | -200 | 840 | 020 | geen waarde gevonden | 5585 | 1.1036 | 1040 | 1.06115 | 1.1036 | 5.8084 | 5.8084 | no | yes | Up to level: 020 | Pset_WallCommon - FireRating: EI60
695706 | 020 | -200 | 840 | 020 | geen waarde gevonden | 5210 | 1.0295 | 1040 | 0.9899 | 1.0295 | 5.4184 | 5.4184 | no | no | Up to level: 020
695738 | 020 | 840 | -920 | 020 | geen waarde gevonden | 1090 | 0.381064 | 1840 | 0.2071 | 0.381064 | 2.0056 | 2.0056 | no | no | Up to level: 030
695774 | 020 | -80 | -80 | 020 | geen waarde gevonden | 5300 | 3.6252 | 3600 | 1.007 | 3.6252 | 19.08 | 19.08 | no | no | Up to level: 030 | Pset_WallCommon - FireRating: EI60
695787 | 020 | -200 | 0 | 020 | geen waarde gevonden | 2055 | 1.1245 | 2880 | 0.39045 | 1.1245 | 5.9184 | 5.9184 | no | no | Pset_WallCommon - FireRating: EI60
695788 | 020 | -200 | 0 | 020 | geen waarde gevonden | 1710 | 0.935712 | 2880 | 0.3249 | 0.935712 | 4.9248 | 4.9248 | no | no
695789 | 020 | -200 | 0 | 020 | geen waarde gevonden | 754.996 | 0.413134 | 2880 | 0.143449 | 0.413134 | 2.17439 | 2.17439 | no | no
858852 | 020 | -200 | 0 | 020 | geen waarde gevonden | 554.996 | 0.303694 | 2880 | 0.105449 | 0.303694 | 1.59839 | 1.59839 | no | no
859411 | 020 | -200 | 0 | 020 | geen waarde gevonden | 1710 | 0.935712 | 2880 | 0.3249 | 0.935712 | 4.9248 | 4.9248 | no | no
860392 | 020 | -200 | 0 | 020 | geen waarde gevonden | 555 | 0.303696 | 2880 | 0.10545 | 0.303696 | 1.5984 | 1.5984 | no | no
860850 | 020 | -200 | 0 | 020 | geen waarde gevonden | 1710 | 0.935712 | 2880 | 0.3249 | 0.935712 | 4.9248 | 4.9248 | no | no
867062 | 020 | -200 | 0 | 020 | geen waarde gevonden | 754.996 | 0.413134 | 2880 | 0.143449 | 0.413134 | 2.17439 | 2.17439 | no | no
867064 | 020 | -200 | 0 | 020 | geen waarde gevonden | 1710 | 0.935712 | 2880 | 0.3249 | 0.935712 | 4.9248 | 4.9248 | no | no
867066 | 020 | -200 | 0 | 020 | geen waarde gevonden | 1710 | 0.935712 | 2880 | 0.3249 | 0.935712 | 4.9248 | 4.9248 | no | no | Pset_WallCommon - FireRating: EI60
867067 | 020 | -200 | 840 | 020 | geen waarde gevonden | 990 | 0.195624 | 1040 | 0.1881 | 0.195624 | 1.0296 | 1.0296 | no | no | Up to level: 020 | Pset_WallCommon - FireRating: EI60
867069 | 020 | -200 | 0 | 020 | geen waarde gevonden | 645.837 | 0.301418 | 2880 | 0.104659 | 0.353402 | 1.86001 | 1.86001 | no | no
1737513 | 020 | -200 | 840 | 020 | geen waarde gevonden | 1090 | 0.215384 | 1040 | 0.2071 | 0.215384 | 1.1336 | 1.1336 | no | no | Up to level: 020
1739918 | 020 | -200 | 0 | 020 | geen waarde gevonden | 4369.51 | 0.857185 | 1040 | 0.824216 | 0.863416 | 4.54429 | 4.54429 | no | no
2251731 | 020 | -200 | 250 | 020 | geen waarde gevonden | 3690 | 0.315495 | 450 | 0.7011 | 0.315495 | 1.6605 | 1.6605 | no | no | Up to level: 020
2251818 | 020 | -200 | 250 | 020 | geen waarde gevonden | 5490 | 0.469395 | 450 | 1.0431 | 0.469395 | 2.4705 | 2.4705 | no | no | Up to level: 020
2252021 | 020 | -200 | 250 | 020 | geen waarde gevonden | 5490 | 0.469395 | 450 | 1.0431 | 0.469395 | 2.4705 | 2.4705 | no | no | Up to level: 020 | Pset_WallCommon - FireRating: EI60
2252172 | 020 | -200 | 250 | 020 | geen waarde gevonden | 5490 | 0.469395 | 450 | 1.0431 | 0.469395 | 2.4705 | 2.4705 | no | no | Up to level: 020
2252631 | 020 | -200 | 250 | 020 | geen waarde gevonden | 3690 | 0.315495 | 450 | 0.7011 | 0.315495 | 1.6605 | 1.6605 | no | no | Up to level: 020
2252842 | 020 | -200 | 250 | 020 | geen waarde gevonden | 5490 | 0.469395 | 450 | 1.0431 | 0.469395 | 2.4705 | 2.4705 | no | no | Up to level: 020
2253249 | 020 | -200 | 250 | 020 | geen waarde gevonden | 5490 | 0.469395 | 450 | 1.0431 | 0.469395 | 2.4705 | 2.4705 | no | no | Up to level: 020
2253461 | 020 | -200 | 250 | 020 | geen waarde gevonden | 5490 | 0.469395 | 450 | 1.0431 | 0.469395 | 2.4705 | 2.4705 | no | no | Up to level: 020
26400197 | 020 | -200 | 840 | 020 | geen waarde gevonden | 7010 | 1.38518 | 1040 | 1.3319 | 1.38518 | 7.2904 | 7.2904 | no | no | Up to level: 020
713019 | 030 | -80 | 2990 | 030 | geen waarde gevonden | 300 | 0.17499 | 3070 | 0.057 | 0.17499 | 0.921 | 0.921 | no | no | Up to level: 030 | Pset_WallCommon - FireRating: EI60
728221 | 030 | -200 | 0 | 030 | geen waarde gevonden | 7889.74 | 1.40911 | 940 | 1.49905 | 0.033934 | 0.1786 | 7.448 | no | no
728853 | 030 | -200 | 0 | 030 | geen waarde gevonden | 900 | 0.16074 | 940 | 0.171 | 0.16074 | 0.846 | 0.846 | no | no
728885 | 030 | -200 | 0 | 030 | geen waarde gevonden | 935 | 0.166991 | 940 | 0.17765 | 0.166991 | 0.8789 | 0.8789 | no | no
728998 | 030 | -200 | 0 | 030 | geen waarde gevonden | 7095.26 | 1.26721 | 940 | 1.3481 | 1.26721 | 6.66954 | 6.66954 | no | no
729535 | 030 | -200 | 0 | 030 | geen waarde gevonden | 490 | 0.268128 | 2880 | 0.0931 | 0.268128 | 1.4112 | 1.4112 | no | no
729536 | 030 | -200 | 840 | 030 | geen waarde gevonden | 6710 | 1.3259 | 1040 | 1.2749 | 1.3259 | 6.9784 | 6.9784 | no | no | Up to level: 030
729663 | 030 | -200 | 740 | 030 | geen waarde gevonden | 7180 | 1.28235 | 940 | 1.3642 | 1.28235 | 6.7492 | 6.7492 | no | no | Up to level: 030
732434 | 030 | -200 | 840 | 030 | geen waarde gevonden | 5040 | 0.995904 | 1040 | 0.9576 | 0.995904 | 5.2416 | 5.2416 | no | no | Up to level: 030
732437 | 030 | -200 | 2680 | 030 | geen waarde gevonden | 1480 | 0.809856 | 2880 | 0.2812 | 0.809856 | 4.2624 | 4.2624 | no | no | Up to level: 030
732593 | 030 | -200 | 0 | 030 | geen waarde gevonden | 1090 | 0.194674 | 940 | 0.2071 | 0.194674 | 1.0246 | 1.0246 | no | no
732594 | 030 | -200 | 0 | 030 | geen waarde gevonden | 900 | 0.16074 | 940 | 0.171 | 0.16074 | 0.846 | 0.846 | no | no
732863 | 030 | -200 | 3400 | 030 | geen waarde gevonden | 910 | 0.62244 | 3600 | 0.1729 | 0.62244 | 3.276 | 3.276 | no | no | Up to level: 030
734484 | 030 | -200 | 0 | 030 | geen waarde gevonden | 490 | 0.268128 | 2880 | 0.0931 | 0.268128 | 1.4112 | 1.4112 | no | no
734525 | 030 | -200 | 0 | 030 | geen waarde gevonden | 490 | 0.268128 | 2880 | 0.0931 | 0.268128 | 1.4112 | 1.4112 | no | no
734604 | 030 | -200 | 840 | 030 | geen waarde gevonden | 6710 | 1.3259 | 1040 | 1.2749 | 1.3259 | 6.9784 | 6.9784 | no | no | Up to level: 030
734767 | 030 | -200 | 0 | 030 | geen waarde gevonden | 490 | 0.268128 | 2880 | 0.0931 | 0.268128 | 1.4112 | 1.4112 | no | no
734872 | 030 | 840 | -920 | 030 | geen waarde gevonden | 1935 | 0.676476 | 1840 | 0.36765 | 0.676476 | 3.5604 | 3.5604 | no | no | Up to level: 040
735122 | 030 | -200 | 2680 | 030 | geen waarde gevonden | 490 | 0.268128 | 2880 | 0.0931 | 0.268128 | 1.4112 | 1.4112 | no | no | Up to level: 030
735228 | 030 | -200 | 2680 | 030 | geen waarde gevonden | 490 | 0.268128 | 2880 | 0.0931 | 0.268128 | 1.4112 | 1.4112 | no | no | Up to level: 030
735253 | 030 | -200 | 2680 | 030 | geen waarde gevonden | 5550 | 3.03696 | 2880 | 1.0545 | 3.03696 | 15.984 | 15.984 | no | no | Up to level: 030
735327 | 030 | -200 | 840 | 030 | geen waarde gevonden | 6710 | 1.3259 | 1040 | 1.2749 | 1.3259 | 6.9784 | 6.9784 | no | no | Up to level: 030
735482 | 030 | -200 | 170 | 030 | geen waarde gevonden | 4910 | 0.345173 | 370 | 0.9329 | 0.345173 | 1.8167 | 1.8167 | no | no | Up to level: 030
735602 | 030 | -200 | 840 | 030 | geen waarde gevonden | 6710 | 1.3259 | 1040 | 1.2749 | 1.3259 | 6.9784 | 6.9784 | no | no | Up to level: 030
735994 | 030 | -200 | 3400 | 030 | geen waarde gevonden | 1681.52 | 1.08518 | 3600 | 0.30144 | 1.15016 | 6.05349 | 6.05349 | no | no | Up to level: 030
736211 | 030 | -200 | 840 | 030 | geen waarde gevonden | 3040.79 | 0.600861 | 1040 | 0.577751 | 0.600861 | 3.16242 | 3.16242 | no | no | Up to level: 030 | Pset_WallCommon - FireRating: EI60
736796 | 030 | -200 | 3400 | 030 | geen waarde gevonden | 2042.15 | 1.33185 | 3600 | 0.369958 | 1.39683 | 7.35174 | 7.35174 | no | no | Up to level: 030
736801 | 030 | -200 | 3400 | 030 | geen waarde gevonden | 7205.65 | 4.86368 | 3600 | 1.35102 | 4.92866 | 25.9403 | 25.9403 | no | no | Up to level: 030 | Pset_WallCommon - FireRating: EI60
736806 | 030 | -200 | 2680 | 030 | geen waarde gevonden | 225 | 0.12312 | 2880 | 0.04275 | 0.12312 | 0.648 | 0.648 | no | no | Up to level: 030
737045 | 030 | -200 | 840 | 030 | geen waarde gevonden | 6710 | 1.3259 | 1040 | 1.2749 | 1.3259 | 6.9784 | 6.9784 | no | no | Up to level: 030
737129 | 030 | -200 | 170 | 030 | geen waarde gevonden | 4910 | 0.345173 | 370 | 0.9329 | 0.345173 | 1.8167 | 1.8167 | no | no | Up to level: 030
737205 | 030 | -200 | 3400 | 030 | geen waarde gevonden | 1030 | 0.70452 | 3600 | 0.1957 | 0.70452 | 3.708 | 3.708 | no | no | Up to level: 030
737465 | 030 | -200 | 840 | 030 | geen waarde gevonden | 6710 | 1.3259 | 1040 | 1.2749 | 1.3259 | 6.9784 | 6.9784 | no | no | Up to level: 030
737519 | 030 | -200 | 2680 | 030 | geen waarde gevonden | 490 | 0.268128 | 2880 | 0.0931 | 0.268128 | 1.4112 | 1.4112 | no | no | Up to level: 030
737616 | 030 | -200 | 2680 | 030 | geen waarde gevonden | 490 | 0.268128 | 2880 | 0.0931 | 0.268128 | 1.4112 | 1.4112 | no | no | Up to level: 030
737650 | 030 | -200 | 2680 | 030 | geen waarde gevonden | 1935 | 1.05883 | 2880 | 0.36765 | 1.05883 | 5.5728 | 5.5728 | no | no | Up to level: 030
737659 | 030 | -200 | 2680 | 030 | geen waarde gevonden | 490 | 0.268128 | 2880 | 0.0931 | 0.268128 | 1.4112 | 1.4112 | no | no | Up to level: 030
737663 | 030 | -200 | 2680 | 030 | geen waarde gevonden | 490 | 0.268128 | 2880 | 0.0931 | 0.268128 | 1.4112 | 1.4112 | no | no | Up to level: 030
737667 | 030 | -200 | 2680 | 030 | geen waarde gevonden | 490 | 0.268128 | 2880 | 0.0931 | 0.268128 | 1.4112 | 1.4112 | no | no | Up to level: 030
737671 | 030 | -200 | 2680 | 030 | geen waarde gevonden | 490 | 0.268128 | 2880 | 0.0931 | 0.268128 | 1.4112 | 1.4112 | no | no | Up to level: 030
737679 | 030 | -200 | 2680 | 030 | geen waarde gevonden | 1480 | 0.809856 | 2880 | 0.2812 | 0.809856 | 4.2624 | 4.2624 | no | no | Up to level: 030
738095 | 030 | -200 | 2680 | 030 | geen waarde gevonden | 5311.44 | 2.90642 | 2880 | 1.00917 | 2.90642 | 15.2969 | 15.2969 | no | no | Up to level: 030
738386 | 030 | -200 | 0 | 030 | geen waarde gevonden | 1460.35 | 0.269794 | 1040 | 0.259417 | 0.288566 | 1.51877 | 1.51877 | no | no
739492 | 030 | -200 | 840 | 030 | geen waarde gevonden | 1331.36 | 0.263076 | 1040 | 0.252958 | 0.263076 | 1.38461 | 1.38461 | no | no | Up to level: 030
740697 | 030 | -200 | 840 | 030 | geen waarde gevonden | 6710 | 1.3259 | 1040 | 1.2749 | 1.3259 | 6.9784 | 6.9784 | no | no | Up to level: 030
740799 | 030 | -200 | 840 | 030 | geen waarde gevonden | 6710 | 1.3259 | 1040 | 1.2749 | 1.3259 | 6.9784 | 6.9784 | no | no | Up to level: 030
740841 | 030 | -200 | 840 | 030 | geen waarde gevonden | 6710 | 1.3259 | 1040 | 1.2749 | 1.3259 | 6.9784 | 6.9784 | no | no | Up to level: 030
740878 | 030 | -200 | 840 | 030 | geen waarde gevonden | 6710 | 1.3259 | 1040 | 1.2749 | 1.3259 | 6.9784 | 6.9784 | no | no | Up to level: 030
740947 | 030 | -200 | 840 | 030 | geen waarde gevonden | 5040 | 0.995904 | 1040 | 0.9576 | 0.995904 | 5.2416 | 5.2416 | no | no | Up to level: 030
742498 | 030 | -200 | 3400 | 030 | geen waarde gevonden | 207.696 | 0.142064 | 3600 | 0.0394621 | 0.142064 | 0.747704 | 0.747704 | no | no | Up to level: 030
743129 | 030 | -200 | 3400 | 030 | geen waarde gevonden | 207.696 | 0.142064 | 3600 | 0.0394621 | 0.142064 | 0.747704 | 0.747704 | no | no | Up to level: 030
752313 | 030 | -200 | 840 | 030 | geen waarde gevonden | 6710 | 1.3259 | 1040 | 1.2749 | 1.3259 | 6.9784 | 6.9784 | no | no | Up to level: 030
867755 | 030 | -200 | 0 | 030 | geen waarde gevonden | 754.996 | 0.413134 | 2880 | 0.143449 | 0.413134 | 2.17439 | 2.17439 | no | no
867757 | 030 | -200 | 0 | 030 | geen waarde gevonden | 1710 | 0.935712 | 2880 | 0.3249 | 0.935712 | 4.9248 | 4.9248 | no | no
867759 | 030 | -200 | 0 | 030 | geen waarde gevonden | 1710 | 0.935712 | 2880 | 0.3249 | 0.935712 | 4.9248 | 4.9248 | no | no | Pset_WallCommon - FireRating: EI60
867760 | 030 | -200 | 840 | 030 | geen waarde gevonden | 990 | 0.195624 | 1040 | 0.1881 | 0.195624 | 1.0296 | 1.0296 | no | no | Up to level: 030 | Pset_WallCommon - FireRating: EI60
867762 | 030 | -200 | 0 | 030 | geen waarde gevonden | 645.837 | 0.301418 | 2880 | 0.104659 | 0.353402 | 1.86001 | 1.86001 | no | no | Pset_WallCommon - FireRating: EI60
867832 | 030 | -200 | 0 | 030 | geen waarde gevonden | 2055 | 1.1245 | 2880 | 0.39045 | 1.1245 | 5.9184 | 5.9184 | no | no | Pset_WallCommon - FireRating: EI60
867833 | 030 | -200 | 0 | 030 | geen waarde gevonden | 1710 | 0.935712 | 2880 | 0.3249 | 0.935712 | 4.9248 | 4.9248 | no | no
867834 | 030 | -200 | 0 | 030 | geen waarde gevonden | 754.996 | 0.413134 | 2880 | 0.143449 | 0.413134 | 2.17439 | 2.17439 | no | no
867837 | 030 | -200 | 0 | 030 | geen waarde gevonden | 555 | 0.303696 | 2880 | 0.10545 | 0.303696 | 1.5984 | 1.5984 | no | no
867839 | 030 | -200 | 0 | 030 | geen waarde gevonden | 1710 | 0.935712 | 2880 | 0.3249 | 0.935712 | 4.9248 | 4.9248 | no | no
867842 | 030 | -200 | 0 | 030 | geen waarde gevonden | 555 | 0.303696 | 2880 | 0.10545 | 0.303696 | 1.5984 | 1.5984 | no | no
867844 | 030 | -200 | 0 | 030 | geen waarde gevonden | 1710 | 0.935712 | 2880 | 0.3249 | 0.935712 | 4.9248 | 4.9248 | no | no
1541648 | 030 | -200 | 740 | 030 | geen waarde gevonden | 7095 | 1.26717 | 940 | 1.34805 | 1.26717 | 6.6693 | 6.6693 | no | no | Up to level: 030
1554871 | 030 | -200 | 740 | 030 | geen waarde gevonden | 7010 | 1.25199 | 940 | 1.3319 | 1.25199 | 6.5894 | 6.5894 | no | no | Up to level: 030
1555934 | 030 | -200 | 3400 | 030 | geen waarde gevonden | 1030 | 0.70452 | 3600 | 0.1957 | 0.70452 | 3.708 | 3.708 | no | no | Up to level: 030
1555957 | 030 | 2680 | 3400 | 030 | geen waarde gevonden | 3830 | 0.523944 | 720 | 0.7277 | 0.523944 | 2.7576 | 2.7576 | no | no | Up to level: 030
1557372 | 030 | -200 | 840 | 030 | geen waarde gevonden | 3830 | 0.756808 | 1040 | 0.7277 | 0.756808 | 3.9832 | 3.9832 | no | no | Up to level: 030
1712449 | 030 | -200 | 840 | 030 | geen waarde gevonden | 3830 | 0.756808 | 1040 | 0.7277 | 0.756808 | 3.9832 | 3.9832 | no | no | Up to level: 030
1712450 | 030 | -200 | 3400 | 030 | geen waarde gevonden | 845 | 0.57798 | 3600 | 0.16055 | 0.57798 | 3.042 | 3.042 | no | no | Up to level: 030
1715264 | 030 | 2680 | 3400 | 030 | geen waarde gevonden | 3830 | 0.523944 | 720 | 0.7277 | 0.523944 | 2.7576 | 2.7576 | no | no | Up to level: 030
1717878 | 030 | -200 | 840 | 030 | geen waarde gevonden | 1000 | 0.1976 | 1040 | 0.19 | 0.1976 | 1.04 | 1.04 | no | no | Up to level: 030 | Pset_WallCommon - FireRating: EI60
1717934 | 030 | -200 | 840 | 030 | geen waarde gevonden | 3039.21 | 0.600547 | 1040 | 0.577449 | 0.600547 | 3.16078 | 3.16078 | no | no | Up to level: 030
2100713 | 030 | -200 | 80 | 030 | geen waarde gevonden | 2018.99 | 0.107411 | 280 | 0.383609 | 0.107411 | 0.565319 | 0.565319 | no | no | Up to level: 030
2100965 | 030 | -200 | 80 | 030 | geen waarde gevonden | 1890 | 0.100548 | 280 | 0.3591 | 0.100548 | 0.5292 | 0.5292 | no | no | Up to level: 030
2251732 | 030 | -200 | 250 | 030 | geen waarde gevonden | 3690 | 0.315495 | 450 | 0.7011 | 0.315495 | 1.6605 | 1.6605 | no | no | Up to level: 030
2251819 | 030 | -200 | 250 | 030 | geen waarde gevonden | 5490 | 0.469395 | 450 | 1.0431 | 0.469395 | 2.4705 | 2.4705 | no | no | Up to level: 030
2252022 | 030 | -200 | 250 | 030 | geen waarde gevonden | 5490 | 0.469395 | 450 | 1.0431 | 0.469395 | 2.4705 | 2.4705 | no | no | Up to level: 030
2252173 | 030 | -200 | 250 | 030 | geen waarde gevonden | 5490 | 0.469395 | 450 | 1.0431 | 0.469395 | 2.4705 | 2.4705 | no | no | Up to level: 030
2252632 | 030 | -200 | 250 | 030 | geen waarde gevonden | 3690 | 0.315495 | 450 | 0.7011 | 0.315495 | 1.6605 | 1.6605 | no | no | Up to level: 030
2252843 | 030 | -200 | 250 | 030 | geen waarde gevonden | 5490 | 0.469395 | 450 | 1.0431 | 0.469395 | 2.4705 | 2.4705 | no | no | Up to level: 030 | Pset_WallCommon - FireRating: EI60
2253250 | 030 | -200 | 250 | 030 | geen waarde gevonden | 5490 | 0.469395 | 450 | 1.0431 | 0.469395 | 2.4705 | 2.4705 | no | no | Up to level: 030
2253462 | 030 | -200 | 250 | 030 | geen waarde gevonden | 5490 | 0.469395 | 450 | 1.0431 | 0.469395 | 2.4705 | 2.4705 | no | no | Up to level: 030
5879427 | 030 | -200 | 80 | 030 | geen waarde gevonden | 2018.99 | 0.102357 | 280 | 0.365559 | 0.107411 | 0.565319 | 0.565319 | no | no | Up to level: 030
12937638 | 030 | -200 | 2680 | 030 | geen waarde gevonden | 5325 | 2.91384 | 2880 | 1.01175 | 2.91384 | 15.336 | 15.336 | no | no | Up to level: 030 | Pset_WallCommon - FireRating: EI60
773715 | 040 | -200 | 420 | 040 | geen waarde gevonden | 30409.9 | 3.58228 | 620 | 5.77788 | 3.58228 | 18.8541 | 18.8541 | no | no | Up to level: 040
781402 | 040 | -200 | 420 | 040 | geen waarde gevonden | 36155 | 4.25906 | 620 | 6.86945 | 4.25906 | 22.4161 | 22.4161 | no | no | Up to level: 040
781588 | 040 | -200 | 420 | 040 | geen waarde gevonden | 3767.7 | 0.432644 | 620 | 0.697812 | 0.443835 | 2.33597 | 2.33597 | no | no | Up to level: 040
781711 | 040 | -200 | 420 | 040 | geen waarde gevonden | 8500.84 | 0.979018 | 620 | 1.57906 | 1.0014 | 5.27052 | 5.27052 | no | no | Up to level: 040
781778 | 040 | -200 | 420 | 040 | geen waarde gevonden | 3308.99 | 0.378609 | 620 | 0.610659 | 0.3898 | 2.05158 | 2.05158 | no | no | Up to level: 040
782121 | 040 | -200 | 420 | 040 | geen waarde gevonden | 35965 | 4.23668 | 620 | 6.83335 | 4.23668 | 22.2983 | 22.2983 | no | no | Up to level: 040
782324 | 040 | -200 | 420 | 040 | geen waarde gevonden | 7240.65 | 0.841758 | 620 | 1.35767 | 0.852949 | 4.4892 | 4.4892 | no | no | Up to level: 040
782422 | 040 | -200 | 420 | 040 | geen waarde gevonden | 30410 | 3.5823 | 620 | 5.7779 | 3.5823 | 18.8542 | 18.8542 | no | no | Up to level: 040
783458 | 040 | -200 | 420 | 040 | geen waarde gevonden | 7539.22 | 0.876929 | 620 | 1.4144 | 0.88812 | 4.67432 | 4.67432 | no | no | Up to level: 040
783614 | 040 | -200 | 420 | 040 | geen waarde gevonden | 10754.4 | 1.24448 | 620 | 2.00723 | 1.26686 | 6.6677 | 6.6677 | no | no | Up to level: 040
786185 | 040 | -200 | 0 | 040 | geen waarde gevonden | 1031.47 | 0.106758 | 600 | 0.17793 | 0.117588 | 0.618885 | 0.618885 | no | no
786454 | 040 | -200 | 0 | 040 | geen waarde gevonden | 18705 | 2.20345 | 620 | 3.55395 | 2.20345 | 11.5971 | 11.5971 | no | no
8740732 | 040 | -200 | 0 | 040 | geen waarde gevonden | 781.475 | 0.0782581 | 600 | 0.13043 | 0.0890881 | 0.468885 | 0.468885 | no | no | Pset_WallCommon - FireRating: EI60

# IfcWall: BB_Beton_Bestaand 200 (188)
Type - Material: BB_Beton_Bestaand
PredefinedType: SOLIDWALL
Cpset_Wall - LevelOfAccuracy: in te vullen door Buildwise
IfcRoot - Name: BB_XX_Wand uit beton, 200 mm
Qto_WallBaseQuantities - Width: 200
Pset_Condition - AssessmentCondition: Empty
Pset_EnvironmentalImpactIndicators - Reference: BB_XX_Wand uit beton, 200 mm; sets with these values: 2
Pset_WallCommon - Reference: BB_XX_Wand uit beton, 200 mm; IsExternal: yes; ExtendToStructure: no
Name (Basic Wall:BB_XX_Wand uit beton, 200 mm:...) | In | Base Offset | Top Offset | Base Constraint | GVH_artnr 01 = GVH_artnr 02 = GVH_artnr 03 = GVH_artnr 04 = GVH_artnr 05 = GVH_artnr 06 | Length | NetVolume | Height | GrossFootprintArea | GrossVolume | GrossSideArea | NetSideArea | LoadBearing | FireRating | Top Constraint
1361991 | TAW50 | 0 | 0 | K30 | geen waarde gevonden | 1900 | 0.532 | 1400 | 0.38 | 0.532 | 2.66 | 2.66 | no
1361992 | TAW50 | 0 | 0 | K30 | geen waarde gevonden | 2505 | 0.7014 | 1400 | 0.501 | 0.7014 | 3.507 | 3.507 | no
1361993 | TAW50 | 0 | 0 | K30 | geen waarde gevonden | 2505 | 0.7014 | 1400 | 0.501 | 0.7014 | 3.507 | 3.507 | no
947474 | K20 | -400 | 0 | K20 | geen waarde gevonden | 490 | 0.245 | 2500 | 0.098 | 0.245 | 1.225 | 1.225 | no
950420 | K20 | -400 | 0 | K20 | geen waarde gevonden | 3555 | 2.16855 | 3050 | 0.711 | 2.16855 | 10.8428 | 10.8428 | no
950705 | K20 | -400 | 0 | K20 | geen waarde gevonden | 21595 | 13.173 | 3050 | 4.319 | 13.173 | 65.8648 | 65.8648 | no
950870 | K20 | -400 | 0 | K20 | geen waarde gevonden | 7400 | 4.292 | 2900 | 1.48 | 4.292 | 21.46 | 21.46 | no
950923 | K20 | -400 | 0 | K20 | geen waarde gevonden | 1195 | 0.72895 | 3050 | 0.239 | 0.72895 | 3.64475 | 3.64475 | no
951637 | K20 | -400 | 0 | K20 | geen waarde gevonden | 5365 | 3.3263 | 3100 | 1.073 | 3.3263 | 16.6315 | 16.6315 | no
951720 | K20 | -400 | 0 | K20 | geen waarde gevonden | 2300 | 1.334 | 2900 | 0.46 | 1.334 | 6.67 | 6.67 | no
951854 | K20 | 0 | 0 | K20 | geen waarde gevonden | 300 | 0.1314 | 2190 | 0.06 | 0.1314 | 0.657 | 0.657 | no
952724 | K20 | -400 | 0 | K20 | geen waarde gevonden | 2030.99 | 1.19721 | 3100 | 0.386198 | 1.25921 | 6.29606 | 6.29606 | no
953040 | K20 | -400 | 0 | K20 | geen waarde gevonden | 2093.83 | 1.23618 | 3100 | 0.398766 | 1.29818 | 6.49088 | 6.49088 | no
953251 | K20 | -400 | 0 | K20 | geen waarde gevonden | 10619.3 | 6.45999 | 3100 | 2.08387 | 6.58399 | 32.92 | 32.92 | no
953460 | K20 | -400 | 0 | K20 | geen waarde gevonden | 3894.83 | 2.41479 | 3100 | 0.778965 | 2.41479 | 12.074 | 12.074 | no
953535 | K20 | -400 | 0 | K20 | geen waarde gevonden | 5180 | 3.2116 | 3100 | 1.036 | 3.2116 | 16.058 | 16.058 | no
953751 | K20 | -400 | 0 | K20 | geen waarde gevonden | 36005 | 22.3231 | 3100 | 7.20101 | 22.3231 | 111.616 | 111.616 | no
953907 | K20 | -400 | 0 | K20 | geen waarde gevonden | 3699.83 | 2.29389 | 3100 | 0.739965 | 2.29389 | 11.4695 | 11.4695 | no
954037 | K20 | -400 | 0 | K20 | geen waarde gevonden | 3699.9 | 2.29394 | 3100 | 0.739981 | 2.29394 | 11.4697 | 11.4697 | no
954168 | K20 | -400 | 0 | K20 | geen waarde gevonden | 25200 | 15.624 | 3100 | 5.04 | 15.624 | 78.12 | 78.12 | no
954275 | K20 | -400 | 0 | K20 | geen waarde gevonden | 2794.93 | 1.73286 | 3100 | 0.558986 | 1.73286 | 8.66429 | 8.66429 | no
954396 | K20 | 0 | 0 | K20 | geen waarde gevonden | 1090 | 0.4796 | 2200 | 0.218 | 0.4796 | 2.398 | 2.398 | no
955494 | K20 | 0 | 0 | K20 | geen waarde gevonden | 3300 | 1.3266 | 2010 | 0.660001 | 1.3266 | 6.63301 | 6.63301 | no | EI60
955913 | K20 | 0 | 0 | K20 | geen waarde gevonden | 1487 | 0.557575 | 2010 | 0.2774 | 0.597775 | 2.98887 | 2.98887 | no | EI60
956015 | K20 | 0 | 0 | K20 | geen waarde gevonden | 2772.46 | 1.07433 | 2010 | 0.534493 | 1.11453 | 5.57265 | 5.57265 | no | EI60
956325 | K20 | 0 | 0 | K20 | geen waarde gevonden | 3020 | 1.21404 | 2010 | 0.604 | 1.21404 | 6.0702 | 6.0702 | no | EI60
957048 | K20 | 0 | 0 | K20 | geen waarde gevonden | 5395 | 2.52486 | 2340 | 1.079 | 2.52486 | 12.6243 | 12.6243 | no | EI60
960132 | K20 | 0 | 0 | K20 | geen waarde gevonden | 400 | 0.176 | 2200 | 0.08 | 0.176 | 0.88 | 0.88 | no
963153 | K20 | 0 | 0 | K20 | geen waarde gevonden | 8715 | 4.7061 | 2700 | 1.743 | 4.7061 | 23.5305 | 23.5305 | no | EI60 | Up to level: K10
963507 | K20 | 0 | 0 | K20 | geen waarde gevonden | 2300 | 1.242 | 2700 | 0.46 | 1.242 | 6.21 | 6.21 | no | EI60 | Up to level: K10
964149 | K20 | 0 | 0 | K20 | geen waarde gevonden | 3000 | 1.32 | 2200 | 0.6 | 1.32 | 6.6 | 6.6 | no
964785 | K20 | 0 | -100 | K20 | geen waarde gevonden | 3300 | 1.716 | 2600 | 0.66 | 1.716 | 8.58 | 8.58 | no |  | Up to level: K10
965051 | K20 | 0 | 0 | K20 | geen waarde gevonden | 3200 | 1.6 | 2500 | 0.64 | 1.6 | 8 | 8 | no | EI60
965196 | K20 | 0 | 0 | K20 | geen waarde gevonden | 2200 | 0.88 | 2000 | 0.44 | 0.88 | 4.4 | 4.4 | no | EI60
965566 | K20 | 0 | 0 | K20 | geen waarde gevonden | 8715 | 4.7061 | 2700 | 1.743 | 4.7061 | 23.5305 | 23.5305 | no | EI60 | Up to level: K10
965786 | K20 | 0 | 0 | K20 | geen waarde gevonden | 3200 | 1.728 | 2700 | 0.64 | 1.728 | 8.64 | 8.64 | no | EI60 | Up to level: K10
965861 | K20 | 0 | 0 | K20 | geen waarde gevonden | 1400 | 0.756 | 2700 | 0.28 | 0.756 | 3.78 | 3.78 | no | EI60 | Up to level: K10
965970 | K20 | 0 | 0 | K20 | geen waarde gevonden | 2117.16 | 1.08926 | 2700 | 0.403431 | 1.14326 | 5.71632 | 5.71632 | no | EI60 | Up to level: K10
967192 | K20 | 0 | 0 | K20 | geen waarde gevonden | 5505 | 2.9727 | 2700 | 1.101 | 2.9727 | 14.8635 | 14.8635 | no | EI60 | Up to level: K10
971592 | K20 | 0 | 0 | K20 | geen waarde gevonden | 5935 | 2.59953 | 2190 | 1.187 | 2.59953 | 12.9976 | 12.9976 | no
1005868 | K20 | -400 | 0 | K20 | geen waarde gevonden | 635 | 0.3175 | 2500 | 0.127 | 0.3175 | 1.5875 | 1.5875 | no
1077884 | K20 | 0 | 0 | K20 | geen waarde gevonden | 300 | 0.147 | 2450 | 0.06 | 0.147 | 0.735 | 0.735 | no
1558902 | K20 | 0 | 0 | K20 | geen waarde gevonden | 3750 | 1.5075 | 2010 | 0.75 | 1.5075 | 7.5375 | 7.5375 | no | EI60
34054780 | K20 | 600 | -3450 | K20 |  | 694.648 | 0.224777 | 1890 | 0.11893 | 0.262577 | 1.31289 | 1.31289 | yes | EI60 | Up to level: 000 | IfcClassificationReference - TDS_link: .\05 As Builtdossier\2. Bouwkunde\2.2. Stabiliteit\2.2.0 technische fiche's\TF S 4.3 A-beton.pdf; Pset_WallCommon - ThermalTransmittance: 8
806229 | K10 | -200 | 0 | K10 | geen waarde gevonden | 7205 | 4.00598 | 2780 | 1.441 | 4.00598 | 20.0299 | 20.0299 | no
809157 | K10 | 0 | 0 | K10 | geen waarde gevonden | 1872.41 | 0.876288 | 2340 | 0.374482 | 0.876288 | 4.38144 | 4.38144 | no
809316 | K10 | 0 | 0 | K10 | geen waarde gevonden | 5580 | 3.39264 | 3040 | 1.116 | 3.39264 | 16.9632 | 16.9632 | no
809375 | K10 | 0 | 0 | K10 | geen waarde gevonden | 2113.83 | 0.942473 | 2340 | 0.402766 | 0.989273 | 4.94636 | 4.94636 | no
814936 | K10 | 0 | 0 | K10 | geen waarde gevonden | 1900 | 0.8702 | 2290 | 0.38 | 0.8702 | 4.351 | 4.351 | no | EI60
817256 | K10 | 0 | -80 | K10 | geen waarde gevonden | 2400 | 1.5168 | 3160 | 0.48 | 1.5168 | 7.584 | 7.584 | no | EI60 | Up to level: 000
817341 | K10 | 0 | -80 | K10 | geen waarde gevonden | 1400 | 0.8848 | 3160 | 0.28 | 0.8848 | 4.424 | 4.424 | no | EI60 | Up to level: 000
817399 | K10 | 0 | -80 | K10 | geen waarde gevonden | 900 | 0.5688 | 3160 | 0.18 | 0.5688 | 2.844 | 2.844 | no | EI60 | Up to level: 000
817671 | K10 | 0 | 0 | K10 | geen waarde gevonden | 5400 | 3.4128 | 3160 | 1.08 | 3.4128 | 17.064 | 17.064 | no | EI60
820010 | K10 | 0 | 0 | K10 | geen waarde gevonden | 6170.45 | 2.84783 | 2320 | 1.22751 | 2.86309 | 14.3154 | 14.3154 | no | EI60
820242 | K10 | -200 | 0 | K10 | geen waarde gevonden | 2889.28 | 1.43932 | 2520 | 0.571137 | 0.106389 | 0.531944 | 7.31396 | no
823015 | K10 | -200 | 0 | K10 | geen waarde gevonden | 6878.2 | 3.41621 | 2520 | 1.35564 | 3.46661 | 17.3331 | 17.3331 | no | EI60
823354 | K10 | -200 | 0 | K10 | geen waarde gevonden | 2100 | 1.35035 | 3240 | 0.42 | 1.3608 | 6.804 | 6.804 | no | EI60
823487 | K10 | -200 | 0 | K10 | geen waarde gevonden | 2100 | 1.32439 | 3240 | 0.42 | 1.33258 | 6.66292 | 6.66292 | no | EI60
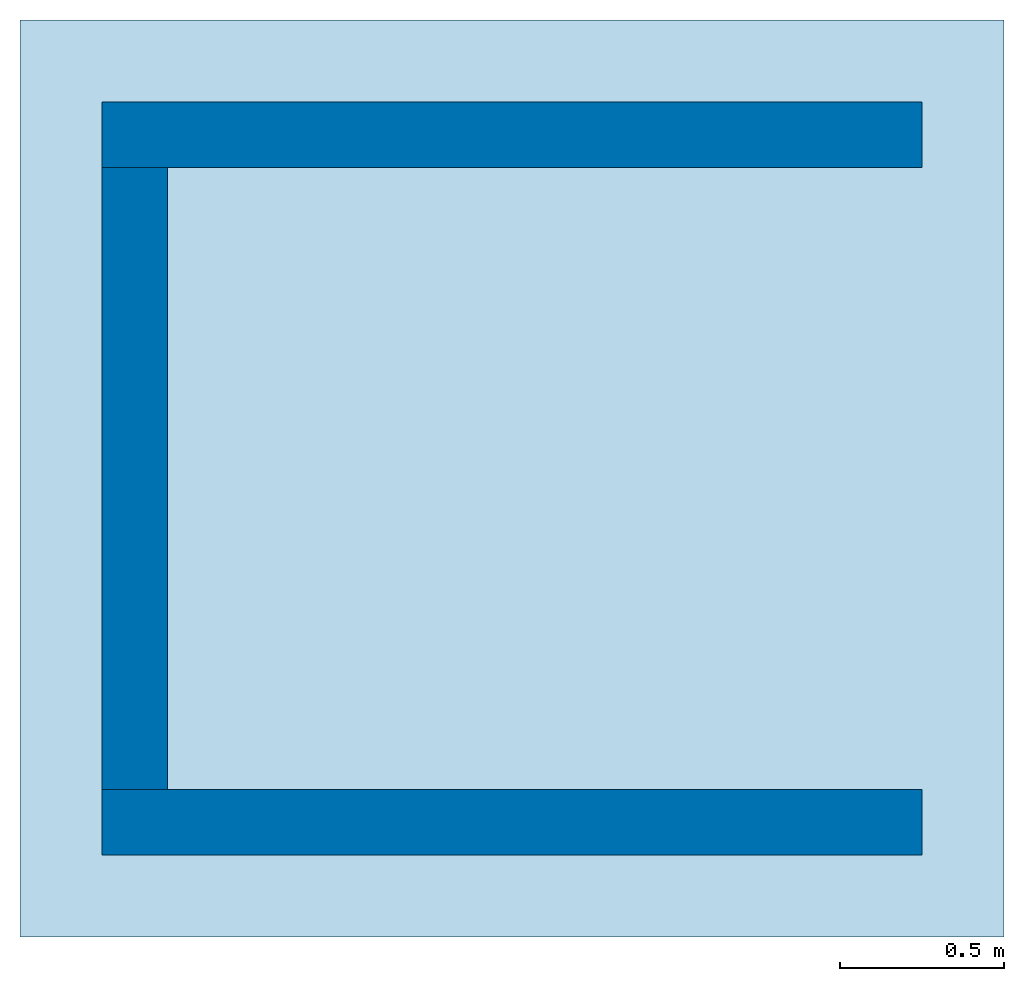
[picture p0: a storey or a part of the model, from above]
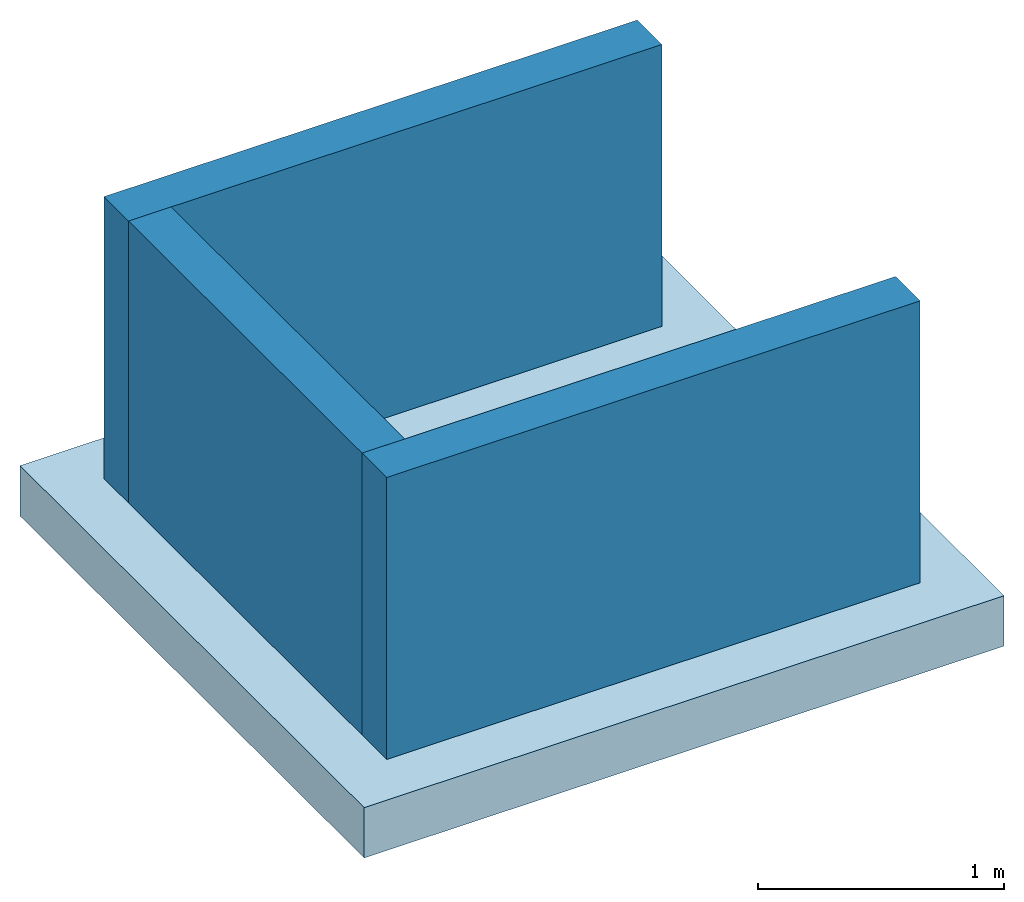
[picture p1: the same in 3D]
Properties of the parts of a building model (IFC4X3_ADD2), part 19 of 28

# IfcWall: BB_Beton_Bestaand 200 (188)
Name (Basic Wall:BB_XX_Wand uit beton, 200 mm:...) | In | Base Offset | Top Offset | Base Constraint | GVH_artnr 01 = GVH_artnr 02 = GVH_artnr 03 = GVH_artnr 04 = GVH_artnr 05 = GVH_artnr 06 | Length | NetVolume | Height | GrossFootprintArea | GrossVolume | GrossSideArea | NetSideArea | LoadBearing | FireRating | Top Constraint
825862 | K10 | -200 | 0 | K10 | geen waarde gevonden | 5100 | 2.5704 | 2520 | 1.02 | 2.5704 | 12.852 | 12.852 | no | EI60
826029 | K10 | 0 | 0 | K10 | geen waarde gevonden | 200 | 0.0824 | 2060 | 0.04 | 0.0824 | 0.412 | 0.412 | no | EI60
827611 | K10 | 0 | -80 | K10 | geen waarde gevonden | 2500 | 1.5346 | 3160 | 0.5 | 1.53305 | 7.66524 | 7.78351 | no | EI60 | Up to level: 000
828034 | K10 | 0 | -80 | K10 | geen waarde gevonden | 2300 | 1.4536 | 3160 | 0.46 | 1.4536 | 7.268 | 7.268 | no | EI60 | Up to level: 000
828505 | K10 | -200 | 0 | K10 | geen waarde gevonden | 5400 | 3.0672 | 2840 | 1.08 | 3.0672 | 15.336 | 15.336 | no | EI60
831941 | K10 | 0 | -80 | K10 | geen waarde gevonden | 2100 | 1.3272 | 3160 | 0.42 | 1.3272 | 6.636 | 6.636 | no | EI60 | Up to level: 000
835120 | K10 | 0 | -80 | K10 | geen waarde gevonden | 2300 | 1.4536 | 3160 | 0.46 | 1.4536 | 7.268 | 7.268 | no | EI60 | Up to level: 000
841810 | K10 | 0 | 0 | K10 | geen waarde gevonden | 2330 | 1.06714 | 2290 | 0.465999 | 1.06714 | 5.33569 | 5.33569 | no | EI60
841880 | K10 | 0 | -80 | K10 | geen waarde gevonden | 5700 | 3.6024 | 3160 | 1.14 | 3.6024 | 18.012 | 18.012 | no | EI60 | Up to level: 000
842009 | K10 | 0 | -80 | K10 | geen waarde gevonden | 5500 | 3.476 | 3160 | 1.1 | 3.476 | 17.38 | 17.38 | no |  | Up to level: 000
884550 | K10 | 0 | -80 | K10 | geen waarde gevonden | 5170 | 3.26744 | 3160 | 1.034 | 3.26744 | 16.3372 | 16.3372 | no | EI60 | Up to level: 000
929568 | K10 | 0 | 0 | K10 | geen waarde gevonden | 910 | 0.55328 | 3040 | 0.182 | 0.55328 | 2.7664 | 2.7664 | no
929787 | K10 | -200 | 0 | K10 | geen waarde gevonden | 2890.67 | 1.43992 | 2520 | 0.571395 | 0.10642 | 0.532102 | 7.31722 | no
1024660 | K10 | 0 | 0 | K10 | geen waarde gevonden | 10322.4 | 5.52669 | 2729.94 | 2.02447 | 5.63589 | 28.1794 | 28.1794 | no
1495559 | K10 | 0 | 0 | K10 | geen waarde gevonden | 1965 | 1.13577 | 2890 | 0.393 | 1.13577 | 5.67885 | 5.67885 | no
1495604 | K10 | 0 | 0 | K10 | geen waarde gevonden | 1181.11 | 0.682682 | 2890 | 0.236222 | 0.682682 | 3.41341 | 3.41341 | no
1497034 | K10 | -500 | 1200 | K10 | geen waarde gevonden | 21595 | 7.3423 | 1700 | 4.319 | 7.3423 | 36.7115 | 36.7115 | no |  | Up to level: K10
1497401 | K10 | -50 | 0 | K10 | geen waarde gevonden | 1395 | 1.13274 | 4060 | 0.279 | 1.13274 | 5.6637 | 5.6637 | no
1501845 | K10 | -50 | 0 | K10 | geen waarde gevonden | 2469.58 | 1.27924 | 2590 | 0.493916 | 1.27924 | 6.39622 | 6.39622 | no
1797628 | K10 | 0 | -550 | K10 | geen waarde gevonden | 2555.04 | 1.37461 | 2690 | 0.511008 | 1.37461 | 6.87306 | 6.87306 | no |  | Up to level: 000
2149813 | K10 | -200 | 840 | K10 | geen waarde gevonden | 3620.1 | 0.75298 | 1040 | 0.724019 | 0.0416 | 0.208 | 3.78186 | no |  | Up to level: K10
2149814 | K10 | -200 | 840 | K10 | geen waarde gevonden | 3501.83 | 0.72838 | 1040 | 0.700365 | 0.0416 | 0.208 | 3.65838 | no |  | Up to level: K10
2149815 | K10 | -200 | 840 | K10 | geen waarde gevonden | 3510.55 | 0.730193 | 1040 | 0.702109 | 0.0416 | 0.208 | 3.66737 | no |  | Up to level: K10
2149816 | K10 | -200 | 840 | K10 | geen waarde gevonden | 3497.79 | 0.727539 | 1040 | 0.699557 | 0.0416 | 0.208 | 3.65404 | no |  | Up to level: K10
33728146 | K10 | 1490 | 0 | K10 |  | 1900 | 0.665 | 1750 | 0.38 | 0.665 | 3.325 | 3.325 | yes |  | Up to level: 000 | IfcClassificationReference - TDS_link: .\05 As Builtdossier\2. Bouwkunde\2.2. Stabiliteit\2.2.0 technische fiche's\TF S 4.3 A-beton.pdf; Pset_WallCommon - ThermalTransmittance: 8
33733237 | K10 | 2790 | 0 | K10 |  | 1700 | 0.153 | 450.001 | 0.34 | 0.153 | 0.765001 | 0.765001 | yes |  | Up to level: 000 | IfcClassificationReference - TDS_link: .\05 As Builtdossier\2. Bouwkunde\2.2. Stabiliteit\2.2.0 technische fiche's\TF S 4.3 A-beton.pdf; Pset_WallCommon - ThermalTransmittance: 8
473372 | 000 | -200 | -200 | 000 | geen waarde gevonden | 2884.93 | 2.05287 | 3600 | 0.570241 | 0.152042 | 0.760212 | 10.4324 | no |  | Up to level: 010
495554 | 000 | -80 | -460 | 000 | geen waarde gevonden | 2800 | 1.8032 | 3220 | 0.56 | 1.8032 | 9.016 | 9.016 | no | EI60 | Up to level: 010
496305 | 000 | -80 | -80 | 000 | geen waarde gevonden | 5300 | 3.816 | 3600 | 1.06 | 3.816 | 19.08 | 19.08 | no | EI60 | Up to level: 010
496744 | 000 | -80 | -80 | 000 | geen waarde gevonden | 5300 | 3.816 | 3600 | 1.06 | 3.816 | 19.08 | 19.08 | no | EI60 | Up to level: 010
500542 | 000 | -200 | 0 | 000 | geen waarde gevonden | 2300 | 1.656 | 3600 | 0.46 | 1.656 | 8.28 | 8.28 | no | EI60
500866 | 000 | -200 | 0 | 000 | geen waarde gevonden | 6670 | 4.8024 | 3600 | 1.334 | 4.8024 | 24.012 | 24.012 | no | EI60
501504 | 000 | -200 | -80 | 000 | geen waarde gevonden | 4900 | 3.6456 | 3720 | 0.980001 | 3.6456 | 18.228 | 18.228 | no | EI60 | Up to level: 010
501787 | 000 | -200 | -80 | 000 | geen waarde gevonden | 2300 | 1.7112 | 3720 | 0.46 | 1.7112 | 8.556 | 8.556 | no | EI60 | Up to level: 010
503827 | 000 | -80 | -80 | 000 | geen waarde gevonden | 5500 | 3.96 | 3600 | 1.1 | 3.96 | 19.8 | 19.8 | no |  | Up to level: 010
504346 | 000 | -80 | -80 | 000 | geen waarde gevonden | 5300 | 3.816 | 3600 | 1.06 | 3.816 | 19.08 | 19.08 | no |  | Up to level: 010
505312 | 000 | -80 | -80 | 000 | geen waarde gevonden | 2500.25 | 1.65618 | 3600 | 0.500051 | 1.8 | 9 | 9 | no | EI60 | Up to level: 010
505661 | 000 | -80 | -80 | 000 | geen waarde gevonden | 3200 | 2.304 | 3600 | 0.64 | 2.304 | 11.52 | 11.52 | no | EI60 | Up to level: 010
506419 | 000 | -80 | -80 | 000 | geen waarde gevonden | 2300 | 1.656 | 3600 | 0.46 | 1.656 | 8.28 | 8.28 | no | EI60 | Up to level: 010
506937 | 000 | -80 | -80 | 000 | geen waarde gevonden | 2500 | 1.8 | 3600 | 0.5 | 1.8 | 9 | 9 | no | EI60 | Up to level: 010
507510 | 000 | -100 | -80 | 000 | geen waarde gevonden | 2190 | 1.58556 | 3620 | 0.438 | 1.58556 | 7.9278 | 7.9278 | no | EI60 | Up to level: 010
2149808 | 000 | -200 | 840 | 000 | geen waarde gevonden | 3501.5 | 0.728312 | 1040 | 0.7003 | 0.0416 | 0.208 | 3.65804 | no |  | Up to level: 000
2149809 | 000 | -200 | 840 | 000 | geen waarde gevonden | 3506.05 | 0.729257 | 1040 | 0.701209 | 0.0416 | 0.208 | 3.66279 | no |  | Up to level: 000
2149810 | 000 | -200 | 840 | 000 | geen waarde gevonden | 3643.59 | 0.757866 | 1040 | 0.728718 | 0.0416 | 0.208 | 3.80636 | no |  | Up to level: 000
2149811 | 000 | -310 | 840 | 000 | geen waarde gevonden | 3526.89 | 0.811184 | 1150 | 0.705377 | 0.046 | 0.23 | 4.07414 | no |  | Up to level: 000
648663 | 010 | -80 | -460 | 010 | geen waarde gevonden | 2800 | 1.8032 | 3220 | 0.56 | 1.8032 | 9.016 | 9.016 | no | EI60 | Up to level: 020
648665 | 010 | -80 | -80 | 010 | geen waarde gevonden | 7700 | 5.544 | 3600 | 1.54 | 5.544 | 27.72 | 27.72 | no | EI60 | Up to level: 020
648666 | 010 | -80 | -80 | 010 | geen waarde gevonden | 5300 | 3.816 | 3600 | 1.06 | 3.816 | 19.08 | 19.08 | no | EI60 | Up to level: 020
648668 | 010 | -80 | -80 | 010 | geen waarde gevonden | 5300 | 3.816 | 3600 | 1.06 | 3.816 | 19.08 | 19.08 | no | EI60 | Up to level: 020
649323 | 010 | -200 | -200 | 010 | geen waarde gevonden | 5500 | 3.96 | 3600 | 1.1 | 3.96 | 19.8 | 19.8 | no | EI60 | Up to level: 020
649324 | 010 | -80 | -80 | 010 | geen waarde gevonden | 7500 | 5.4 | 3600 | 1.5 | 5.4 | 27 | 27 | no | EI60 | Up to level: 020
649325 | 010 | -80 | -80 | 010 | geen waarde gevonden | 5500 | 3.96 | 3600 | 1.1 | 3.96 | 19.8 | 19.8 | no | EI60 | Up to level: 020
649326 | 010 | -80 | -80 | 010 | geen waarde gevonden | 2600 | 1.872 | 3600 | 0.52 | 1.872 | 9.36 | 9.36 | no | EI60 | Up to level: 020
649327 | 010 | -200 | -200 | 010 | geen waarde gevonden | 1090 | 0.7848 | 3600 | 0.218 | 0.7848 | 3.924 | 3.924 | no | EI60 | Up to level: 020
649328 | 010 | -80 | -80 | 010 | geen waarde gevonden | 5300 | 3.816 | 3600 | 1.06 | 3.816 | 19.08 | 19.08 | no | EI60 | Up to level: 020
649329 | 010 | -200 | -200 | 010 | geen waarde gevonden | 300 | 0.216 | 3600 | 0.06 | 0.216 | 1.08 | 1.08 | no |  | Up to level: 020
649378 | 010 | -80 | -80 | 010 | geen waarde gevonden | 4900 | 3.528 | 3600 | 0.980001 | 3.528 | 17.64 | 17.64 | no | EI60 | Up to level: 020
649381 | 010 | -80 | -80 | 010 | geen waarde gevonden | 2300 | 1.656 | 3600 | 0.46 | 1.656 | 8.28 | 8.28 | no | EI60 | Up to level: 020
650659 | 010 | -80 | -80 | 010 | geen waarde gevonden | 8915 | 6.4188 | 3600 | 1.783 | 6.4188 | 32.094 | 32.094 | no | EI60 | Up to level: 020
650660 | 010 | -80 | -80 | 010 | geen waarde gevonden | 3200 | 2.304 | 3600 | 0.64 | 2.304 | 11.52 | 11.52 | no | EI60 | Up to level: 020
650661 | 010 | -80 | -80 | 010 | geen waarde gevonden | 1400 | 1.008 | 3600 | 0.28 | 1.008 | 5.04 | 5.04 | no | EI60 | Up to level: 020
650662 | 010 | -80 | -80 | 010 | geen waarde gevonden | 2200 | 1.584 | 3600 | 0.44 | 1.584 | 7.92 | 7.92 | no | EI60 | Up to level: 020
650666 | 010 | -80 | -80 | 010 | geen waarde gevonden | 2100 | 1.512 | 3600 | 0.42 | 1.512 | 7.56 | 7.56 | no | EI60 | Up to level: 020
650667 | 010 | -80 | -80 | 010 | geen waarde gevonden | 2496.01 | 1.79712 | 3600 | 0.499201 | 1.79712 | 8.98562 | 8.98562 | no |  | Up to level: 020
650668 | 010 | -80 | -80 | 010 | geen waarde gevonden | 2500 | 1.8 | 3600 | 0.5 | 1.8 | 9 | 9 | no |  | Up to level: 020
650669 | 010 | -80 | -80 | 010 | geen waarde gevonden | 2100 | 1.512 | 3600 | 0.42 | 1.512 | 7.56 | 7.56 | no | EI60 | Up to level: 020
650671 | 010 | -80 | -80 | 010 | geen waarde gevonden | 6615 | 4.7628 | 3600 | 1.323 | 4.7628 | 23.814 | 23.814 | no | EI60 | Up to level: 020
651377 | 010 | -80 | -80 | 010 | geen waarde gevonden | 2190 | 1.5768 | 3600 | 0.438 | 1.5768 | 7.884 | 7.884 | no |  | Up to level: 020
866425 | 010 | -200 | 0 | 010 | geen waarde gevonden | 2472.48 | 1.36655 | 2880 | 0.474496 | 1.42415 | 7.12074 | 7.12074 | no | EI60
1040554 | 010 | -200 | 0 | 010 | geen waarde gevonden | 2300 | 1.656 | 3600 | 0.46 | 1.656 | 8.28 | 8.28 | no | EI60
33836967 | 010 | -200 | 840 | 010 | geen waarde gevonden | 3471.72 | 0.722117 | 1040 | 0.694344 | 0.0416 | 0.208 | 3.62681 | no |  | Up to level: 010
33837397 | 010 | -200 | 840 | 010 | geen waarde gevonden | 3509.56 | 0.729988 | 1040 | 0.701912 | 0.0416 | 0.208 | 3.66634 | no |  | Up to level: 010
33838202 | 010 | -200 | 840 | 010 | geen waarde gevonden | 3443.74 | 0.716297 | 1040 | 0.688747 | 0.0416 | 0.208 | 3.59758 | no |  | Up to level: 010
695739 | 020 | -80 | -460 | 020 | geen waarde gevonden | 2800 | 1.8032 | 3220 | 0.56 | 1.8032 | 9.016 | 9.016 | no | EI60 | Up to level: 030
695741 | 020 | -80 | -80 | 020 | geen waarde gevonden | 7700 | 5.544 | 3600 | 1.54 | 5.544 | 27.72 | 27.72 | no | EI60 | Up to level: 030
695742 | 020 | -80 | -80 | 020 | geen waarde gevonden | 5300 | 3.816 | 3600 | 1.06 | 3.816 | 19.08 | 19.08 | no | EI60 | Up to level: 030
695744 | 020 | -80 | -80 | 020 | geen waarde gevonden | 5300 | 3.816 | 3600 | 1.06 | 3.816 | 19.08 | 19.08 | no | EI60 | Up to level: 030
695766 | 020 | -200 | -200 | 020 | geen waarde gevonden | 2300 | 1.656 | 3600 | 0.46 | 1.656 | 8.28 | 8.28 | no | EI60 | Up to level: 030
695769 | 020 | -200 | -200 | 020 | geen waarde gevonden | 6670 | 4.8024 | 3600 | 1.334 | 4.8024 | 24.012 | 24.012 | no |  | Up to level: 030
695773 | 020 | -80 | -80 | 020 | geen waarde gevonden | 7490 | 5.3928 | 3600 | 1.498 | 5.3928 | 26.964 | 26.964 | no | EI60 | Up to level: 030
695775 | 020 | -80 | -80 | 020 | geen waarde gevonden | 2790 | 2.0088 | 3600 | 0.558 | 2.0088 | 10.044 | 10.044 | no | EI60 | Up to level: 030
695777 | 020 | -80 | -80 | 020 | geen waarde gevonden | 5300 | 3.816 | 3600 | 1.06 | 3.816 | 19.08 | 19.08 | no | EI60 | Up to level: 030
695778 | 020 | -200 | -200 | 020 | geen waarde gevonden | 300 | 0.216 | 3600 | 0.06 | 0.216 | 1.08 | 1.08 | no |  | Up to level: 030
695779 | 020 | -80 | -80 | 020 | geen waarde gevonden | 4900 | 3.528 | 3600 | 0.980001 | 3.528 | 17.64 | 17.64 | no | EI60 | Up to level: 030
695782 | 020 | -80 | -80 | 020 | geen waarde gevonden | 2300 | 1.656 | 3600 | 0.46 | 1.656 | 8.28 | 8.28 | no | EI60 | Up to level: 030
695798 | 020 | -80 | -80 | 020 | geen waarde gevonden | 8915 | 6.4188 | 3600 | 1.783 | 6.4188 | 32.094 | 32.094 | no | EI60 | Up to level: 030
695799 | 020 | -80 | -80 | 020 | geen waarde gevonden | 3200 | 2.304 | 3600 | 0.64 | 2.304 | 11.52 | 11.52 | no | EI60 | Up to level: 030
695800 | 020 | -80 | -80 | 020 | geen waarde gevonden | 1400 | 1.008 | 3600 | 0.28 | 1.008 | 5.04 | 5.04 | no | EI60 | Up to level: 030
695805 | 020 | -80 | -80 | 020 | geen waarde gevonden | 2300 | 1.656 | 3600 | 0.46 | 1.656 | 8.28 | 8.28 | no | EI60 | Up to level: 030
695807 | 020 | -80 | -80 | 020 | geen waarde gevonden | 2500 | 1.8 | 3600 | 0.5 | 1.8 | 9 | 9 | no | EI60 | Up to level: 030
695809 | 020 | -80 | -80 | 020 | geen waarde gevonden | 2500 | 1.8 | 3600 | 0.5 | 1.8 | 9 | 9 | no | EI60 | Up to level: 030
695810 | 020 | -80 | -80 | 020 | geen waarde gevonden | 6615 | 4.7628 | 3600 | 1.323 | 4.7628 | 23.814 | 23.814 | no | EI60 | Up to level: 030
695842 | 020 | -80 | -80 | 020 | geen waarde gevonden | 2190 | 1.5768 | 3600 | 0.438 | 1.5768 | 7.884 | 7.884 | no | EI60 | Up to level: 030
867068 | 020 | -200 | 0 | 020 | geen waarde gevonden | 2472.48 | 1.36655 | 2880 | 0.474496 | 1.42415 | 7.12074 | 7.12074 | no | EI60
867071 | 020 | -200 | 0 | 020 | geen waarde gevonden | 320 | 0.18432 | 2880 | 0.064 | 0.18432 | 0.9216 | 0.9216 | no | EI60
867072 | 020 | -200 | 0 | 020 | geen waarde gevonden | 2465.4 | 1.70309 | 3600 | 0.47308 | 1.77509 | 8.87545 | 8.87545 | no | EI60
1181261 | 020 | -200 | 840 | 020 | geen waarde gevonden | 3664.83 | 0.762285 | 1040 | 0.732966 | 0.0416 | 0.208 | 3.82855 | no |  | Up to level: 020
1181262 | 020 | -200 | 840 | 020 | geen waarde gevonden | 3502.13 | 0.728441 | 1040 | 0.700425 | 0.0416 | 0.208 | 3.65869 | no |  | Up to level: 020
1181263 | 020 | -200 | 840 | 020 | geen waarde gevonden | 3545.18 | 0.737397 | 1040 | 0.709036 | 0.0416 | 0.208 | 3.70355 | no |  | Up to level: 020
1181264 | 020 | -200 | 840 | 020 | geen waarde gevonden | 3432.05 | 0.713865 | 1040 | 0.686409 | 0.0416 | 0.208 | 3.58536 | no |  | Up to level: 020
705214 | 030 | -80 | 3400 | 030 | geen waarde gevonden | 2100 | 1.4616 | 3480 | 0.42 | 1.4616 | 7.308 | 7.308 | no | EI60 | Up to level: 030
705215 | 030 | -80 | 3400 | 030 | geen waarde gevonden | 5300 | 3.6888 | 3480 | 1.06 | 3.6888 | 18.444 | 18.444 | no | EI60 | Up to level: 030
705217 | 030 | -80 | 3400 | 030 | geen waarde gevonden | 5500 | 3.828 | 3480 | 1.1 | 3.828 | 19.14 | 19.14 | no | EI60 | Up to level: 030
705237 | 030 | -200 | 3400 | 030 | geen waarde gevonden | 2300 | 1.656 | 3600 | 0.46 | 1.656 | 8.28 | 8.28 | no | EI60 | Up to level: 030
705240 | 030 | -200 | 3400 | 030 | geen waarde gevonden | 6670 | 4.8024 | 3600 | 1.334 | 4.8024 | 24.012 | 24.012 | no | EI60 | Up to level: 030
705243 | 030 | -200 | 3400 | 030 | geen waarde gevonden | 5500 | 3.96 | 3600 | 1.1 | 3.96 | 19.8 | 19.8 | no |  | Up to level: 030
705248 | 030 | -80 | 3400 | 030 | geen waarde gevonden | 5300 | 3.6888 | 3480 | 1.06 | 3.6888 | 18.444 | 18.444 | no |  | Up to level: 030
705270 | 030 | -80 | 3400 | 030 | geen waarde gevonden | 3200 | 2.2272 | 3480 | 0.64 | 2.2272 | 11.136 | 11.136 | no | EI60 | Up to level: 030
705272 | 030 | -80 | 3400 | 030 | geen waarde gevonden | 2200 | 1.5312 | 3480 | 0.44 | 1.5312 | 7.656 | 7.656 | no | EI60 | Up to level: 030
705276 | 030 | -80 | 3400 | 030 | geen waarde gevonden | 2300 | 1.6008 | 3480 | 0.46 | 1.6008 | 8.004 | 8.004 | no | EI60 | Up to level: 030
705279 | 030 | -80 | 0 | 030 | geen waarde gevonden | 3215 | 2.23764 | 3480 | 0.642999 | 2.23764 | 11.1882 | 11.1882 | no | EI60
750543 | 030 | -80 | 2990 | 030 | geen waarde gevonden | 300 | 0.1842 | 3070 | 0.06 | 0.1842 | 0.921 | 0.921 | no | EI60 | Up to level: 030
867761 | 030 | -200 | 0 | 030 | geen waarde gevonden | 2472.48 | 1.36655 | 2880 | 0.474496 | 1.42415 | 7.12074 | 7.12074 | no | EI60
867877 | 030 | -80 | 2680 | 030 | geen waarde gevonden | 2300 | 1.2696 | 2760 | 0.46 | 1.2696 | 6.348 | 6.348 | no | EI60 | Up to level: 030
1603823 | 030 | -200 | 2990 | 030 | geen waarde gevonden | 1065 | 0.67947 | 3190 | 0.213 | 0.67947 | 3.39735 | 3.39735 | no |  | Up to level: 030
785901 | 040 | -200 | 0 | 040 | geen waarde gevonden | 18700 | 2.3188 | 620 | 3.74 | 2.3188 | 11.594 | 11.594 | no
786374 | 040 | -200 | -250 | 040 | geen waarde gevonden | 2110 | 1.08689 | 2600 | 0.418035 | 1.0972 | 5.486 | 5.486 | no | EI60 | Up to level: 050
786739 | 040 | -200 | -250 | 040 | geen waarde gevonden | 2500 | 1.3 | 2600 | 0.5 | 1.3 | 6.5 | 6.5 | no |  | Up to level: 050
786891 | 040 | -200 | -250 | 040 | geen waarde gevonden | 3140 | 1.6328 | 2600 | 0.628 | 1.6328 | 8.164 | 8.164 | no | EI60 | Up to level: 050
786979 | 040 | -200 | -250 | 040 | geen waarde gevonden | 2300 | 1.196 | 2600 | 0.46 | 1.196 | 5.98 | 5.98 | no |  | Up to level: 050
1036145 | 040 | 0 | -1040 | 040 | geen waarde gevonden | 1080 | 0.34776 | 1610 | 0.216 | 0.34776 | 1.7388 | 1.7388 | no |  | Up to level: 050
1037930 | 040 | -200 | -250 | 040 | geen waarde gevonden | 3330 | 1.7316 | 2600 | 0.666 | 1.7316 | 8.658 | 8.658 | no |  | Up to level: 050
1038459 | 040 | -200 | -107.824 | 040 | geen waarde gevonden | 3530 | 1.93598 | 2742.18 | 0.706 | 1.93598 | 9.67988 | 9.67988 | no | EI60 | Up to level: 050
1044084 | 040 | -200 | -250 | 040 | geen waarde gevonden | 2220.95 | 1.10289 | 2600 | 0.42419 | 1.15489 | 5.77446 | 5.77446 | no | EI60 | Up to level: 050
1044424 | 040 | -200 | -150 | 040 | geen waarde gevonden | 5215 | 2.8161 | 2700 | 1.043 | 2.8161 | 14.0805 | 14.0805 | no | EI60 | Up to level: 050
1044635 | 040 | -200 | -350 | 040 | geen waarde gevonden | 2300 | 1.15 | 2500 | 0.46 | 1.15 | 5.75 | 5.75 | no | EI60 | Up to level: 050
1047217 | 040 | -200 | -250 | 040 | geen waarde gevonden | 1400 | 0.624 | 2600 | 0.28 | 0.721755 | 3.60877 | 3.60877 | no | EI60 | Up to level: 050
34196644 | 040 | -200 | 0 | 040 |  | 2435.15 | 1.26628 | 2600 | 0.48703 | 1.26628 | 6.33139 | 6.33139 | yes | IfcClassificationReference - TDS_link: .\05 As Builtdossier\2. Bouwkunde\2.2. Stabiliteit\2.2.0 technische fiche's\TF S 4.3 A-beton.pdf; Pset_WallCommon - ThermalTransmittance: 8; IfcElement - Tag: W 405; Mark: W 405
34196924 | 040 | -200 | 0 | 040 |  | 2350 | 1.222 | 2600 | 0.47 | 1.222 | 6.11 | 6.11 | yes | EI60 | IfcClassificationReference - TDS_link: .\05 As Builtdossier\2. Bouwkunde\2.2. Stabiliteit\2.2.0 technische fiche's\TF S 4.3 A-beton.pdf; Pset_WallCommon - ThermalTransmittance: 8; IfcElement - Tag: W 405; Mark: W 405
10349971 | 050 | -250 | 290 | 050 | geen waarde gevonden | 6870 | 0.74196 | 540 | 1.374 | 0.74196 | 3.7098 | 3.7098 | no |  | Up to level: 050

# IfcWall: BB_Beton_Bestaand 300 (41)
Type - Material: BB_Beton_Bestaand
PredefinedType: SOLIDWALL
Cpset_Wall - LevelOfAccuracy: in te vullen door Buildwise
IfcBuildingStorey - Top Offset: 0
IfcClassificationReference - GVH_artnr 01: geen waarde gevonden; GVH_artnr 02: geen waarde gevonden; GVH_artnr 03: geen waarde gevonden; GVH_artnr 04: geen waarde gevonden; GVH_artnr 05: geen waarde gevonden; GVH_artnr 06: geen waarde gevonden
IfcRoot - Name: BB_XX_Wand uit beton, 300 mm
Qto_WallBaseQuantities - Width: 300
Pset_Condition - AssessmentCondition: Empty
Pset_EnvironmentalImpactIndicators - Reference: BB_XX_Wand uit beton, 300 mm; sets with these values: 2
Pset_WallCommon - Reference: BB_XX_Wand uit beton, 300 mm; IsExternal: yes; LoadBearing: no; ExtendToStructure: no
Name (Basic Wall:BB_XX_Wand uit beton, 300 mm:...) | In | Base Offset | Base Constraint | Length | NetVolume = GrossVolume | Height | GrossFootprintArea | GrossSideArea = NetSideArea
959873 | K20 | 0 | K20 | 400 | 0.252 | 2100 | 0.12 | 0.84
960019 | K20 | 0 | K20 | 400 | 0.252 | 2100 | 0.12 | 0.84
960067 | K20 | 0 | K20 | 400 | 0.264 | 2200 | 0.12 | 0.88
960242 | K20 | 0 | K20 | 400 | 0.264 | 2200 | 0.12 | 0.88
960322 | K20 | 0 | K20 | 1000 | 0.66 | 2200 | 0.3 | 2.2
960413 | K20 | 0 | K20 | 1000 | 0.66 | 2200 | 0.3 | 2.2 | Pset_WallCommon - FireRating: EI60
960486 | K20 | 0 | K20 | 400 | 0.264 | 2200 | 0.12 | 0.88
960558 | K20 | 0 | K20 | 400 | 0.264 | 2200 | 0.12 | 0.88
960626 | K20 | 0 | K20 | 400 | 0.264 | 2200 | 0.12 | 0.88
960696 | K20 | 0 | K20 | 400 | 0.264 | 2200 | 0.12 | 0.88
960751 | K20 | 0 | K20 | 400 | 0.264 | 2200 | 0.12 | 0.88
960811 | K20 | 0 | K20 | 400 | 0.264 | 2200 | 0.12 | 0.88
960888 | K20 | 0 | K20 | 400 | 0.264 | 2200 | 0.12 | 0.88
960970 | K20 | 0 | K20 | 1000 | 0.66 | 2200 | 0.3 | 2.2
961081 | K20 | 0 | K20 | 700 | 0.462 | 2200 | 0.21 | 1.54
961197 | K20 | 0 | K20 | 1800 | 1.188 | 2200 | 0.54 | 3.96
961263 | K20 | 0 | K20 | 400 | 0.264 | 2200 | 0.12 | 0.88
962218 | K20 | 0 | K20 | 400 | 0.264 | 2200 | 0.12 | 0.88 | Pset_WallCommon - FireRating: EI60
962294 | K20 | 0 | K20 | 400 | 0.264 | 2200 | 0.12 | 0.88
962429 | K20 | 0 | K20 | 1200 | 0.792 | 2200 | 0.36 | 2.64 | Pset_WallCommon - FireRating: EI60
962500 | K20 | 0 | K20 | 590 | 0.3894 | 2200 | 0.177 | 1.298 | Pset_WallCommon - FireRating: EI60
962556 | K20 | 0 | K20 | 400 | 0.264 | 2200 | 0.12 | 0.88
962621 | K20 | 0 | K20 | 400 | 0.264 | 2200 | 0.12 | 0.88
963611 | K20 | 0 | K20 | 585 | 0.3861 | 2200 | 0.1755 | 1.287 | Pset_WallCommon - FireRating: EI60
963705 | K20 | 0 | K20 | 1200 | 0.792 | 2200 | 0.36 | 2.64 | Pset_WallCommon - FireRating: EI60
963805 | K20 | 0 | K20 | 1800 | 1.188 | 2200 | 0.54 | 3.96
963944 | K20 | 0 | K20 | 600 | 0.396 | 2200 | 0.18 | 1.32
964038 | K20 | 0 | K20 | 599.999 | 0.40077 | 2226.5 | 0.18 | 1.3359
818446 | K10 | 0 | K10 | 800 | 0.5496 | 2290 | 0.24 | 1.832 | Pset_WallCommon - FireRating: EI60
818530 | K10 | 0 | K10 | 1800 | 1.2366 | 2290 | 0.54 | 4.122 | Pset_WallCommon - FireRating: EI60
818589 | K10 | 0 | K10 | 1200 | 0.8244 | 2290 | 0.36 | 2.748 | Pset_WallCommon - FireRating: EI60
818646 | K10 | 0 | K10 | 590 | 0.40533 | 2290 | 0.177 | 1.3511 | Pset_WallCommon - FireRating: EI60
818756 | K10 | 0 | K10 | 599.996 | 0.412197 | 2290 | 0.179999 | 1.37399
818864 | K10 | 0 | K10 | 1000 | 0.687 | 2290 | 0.3 | 2.29
818968 | K10 | 0 | K10 | 1175 | 0.807225 | 2290 | 0.3525 | 2.69075 | Pset_WallCommon - FireRating: EI60
826534 | K10 | -200 | K10 | 1000 | 0.747 | 2490 | 0.3 | 2.49 | Pset_WallCommon - FireRating: EI60
826636 | K10 | 0 | K10 | 1000 | 0.687 | 2290 | 0.3 | 2.29
826826 | K10 | 0 | K10 | 500 | 0.3435 | 2290 | 0.15 | 1.145
826979 | K10 | 0 | K10 | 1800 | 1.2366 | 2290 | 0.54 | 4.122
827093 | K10 | 0 | K10 | 1200 | 0.8244 | 2290 | 0.36 | 2.748 | Pset_WallCommon - FireRating: EI60
827150 | K10 | 0 | K10 | 590 | 0.40533 | 2290 | 0.177 | 1.3511 | Pset_WallCommon - FireRating: EI60

# IfcWall: BB_Beton_Bestaand 340 (6)
Type - Material: BB_Beton_Bestaand
PredefinedType: SOLIDWALL
Cpset_Wall - LevelOfAccuracy: in te vullen door Buildwise
IfcClassificationReference - GVH_artnr 01: geen waarde gevonden; GVH_artnr 02: geen waarde gevonden; GVH_artnr 03: geen waarde gevonden; GVH_artnr 04: geen waarde gevonden; GVH_artnr 05: geen waarde gevonden; GVH_artnr 06: geen waarde gevonden
IfcRoot - Name: BB_XX_Wand uit beton, 340 mm
Qto_WallBaseQuantities - Width: 340
Pset_Condition - AssessmentCondition: Empty
Pset_EnvironmentalImpactIndicators - Reference: BB_XX_Wand uit beton, 340 mm; sets with these values: 2
Pset_WallCommon - Reference: BB_XX_Wand uit beton, 340 mm; IsExternal: yes; LoadBearing: no; ExtendToStructure: no
Name (Basic Wall:BB_XX_Wand uit beton, 340 mm:...) | In | Base Offset | Top Offset | Base Constraint | Top Constraint | Length | NetVolume = GrossVolume | Height | GrossFootprintArea | GrossSideArea = NetSideArea
961533 | K20 | 0 | 0 | K20 | Up to level: K10 | 800 | 0.7344 | 2700 | 0.272 | 2.16
961705 | K20 | 0 | 0 | K20 | Up to level: K10 | 800 | 0.7344 | 2700 | 0.272 | 2.16
961993 | K20 | 0 | 0 | K20 |  | 905 | 0.750788 | 2440 | 0.3077 | 2.2082 | Pset_WallCommon - FireRating: EI60
962787 | K20 | 0 | 0 | K20 |  | 800 | 0.7344 | 2700 | 0.272 | 2.16
884559 | K10 | -260 | -460 | K10 | Up to level: 000 | 800 | 0.82688 | 3040 | 0.272 | 2.432 | Pset_WallCommon - FireRating: EI60
884566 | K10 | 0 | -460 | K10 | Up to level: 000 | 800 | 0.75616 | 2780 | 0.272 | 2.224

# IfcWall: BB_Beton_Bestaand 400 (8)
Type - Material: BB_Beton_Bestaand
PredefinedType: SOLIDWALL
Cpset_Wall - LevelOfAccuracy: in te vullen door Buildwise
IfcBuildingStorey - Base Offset: 0
IfcClassificationReference - GVH_artnr 01: geen waarde gevonden; GVH_artnr 02: geen waarde gevonden; GVH_artnr 03: geen waarde gevonden; GVH_artnr 04: geen waarde gevonden; GVH_artnr 05: geen waarde gevonden; GVH_artnr 06: geen waarde gevonden
IfcRoot - Name: BB_XX_Wand uit beton, 400 mm
Qto_WallBaseQuantities - Width: 400
Pset_Condition - AssessmentCondition: Empty
Pset_EnvironmentalImpactIndicators - Reference: BB_XX_Wand uit beton, 400 mm; sets with these values: 2
Pset_WallCommon - Reference: BB_XX_Wand uit beton, 400 mm; IsExternal: yes; LoadBearing: no; ExtendToStructure: no
Name (Basic Wall:BB_XX_Wand uit beton, 400 mm:...) | In | Top Offset | Base Constraint | Length | NetVolume = GrossVolume | Height | GrossFootprintArea | GrossSideArea = NetSideArea | Top Constraint
959686 | K20 | 0 | K20 | 800 | 0.672 | 2100 | 0.32 | 1.68
959762 | K20 | 0 | K20 | 817.5 | 0.6867 | 2100 | 0.327 | 1.71675
961350 | K20 | 0 | K20 | 800 | 0.864 | 2700 | 0.32 | 2.16 | Up to level: K10
961462 | K20 | 0 | K20 | 800 | 0.864 | 2700 | 0.32 | 2.16 | Up to level: K10
961792 | K20 | 0 | K20 | 800 | 0.864 | 2700 | 0.32 | 2.16 | Up to level: K10
961912 | K20 | 0 | K20 | 800 | 0.864 | 2700 | 0.32 | 2.16 | Up to level: K10
884562 | K10 | -460 | K10 | 800 | 0.8896 | 2780 | 0.32 | 2.224 | Up to level: 000
884565 | K10 | -460 | K10 | 800 | 0.8896 | 2780 | 0.32 | 2.224 | Up to level: 000

# IfcWall: BB_Beton_Bestaand 99.9695, Basic Wall:BB_XX_Wand uit beton, 200 mm:505987
In: 000
Type - Material: BB_Beton_Bestaand
PredefinedType: SOLIDWALL
Cpset_Wall - LevelOfAccuracy: in te vullen door Buildwise
IfcBuildingStorey - Base Offset: -80; Top Offset: -200; Base Constraint: 000; Top Constraint: Up to level: 010
IfcClassificationReference - GVH_artnr 01: geen waarde gevonden; GVH_artnr 02: geen waarde gevonden; GVH_artnr 03: geen waarde gevonden; GVH_artnr 04: geen waarde gevonden; GVH_artnr 05: geen waarde gevonden; GVH_artnr 06: geen waarde gevonden
IfcRoot - Name: BB_XX_Wand uit beton, 200 mm
Qto_WallBaseQuantities - Length: 99.9695; NetVolume: 0.0695788; Height: 3480; Width: 200; GrossFootprintArea: 0.0199939; GrossVolume: 0.1392; GrossSideArea: 0.696; NetSideArea: 0.696
Pset_Condition - AssessmentCondition: Empty
Pset_EnvironmentalImpactIndicators - Reference: BB_XX_Wand uit beton, 200 mm; sets with these values: 2
Pset_WallCommon - Reference: BB_XX_Wand uit beton, 200 mm; IsExternal: yes; LoadBearing: no; ExtendToStructure: no

# IfcWall: BB_Metaal_Aluminium_Puntprofiel 0 (2)
In: 040
Type - Material: BB_Metaal_Aluminium_Puntprofiel
Cpset_Wall - LevelOfAccuracy: in te vullen door Buildwise
IfcBuildingStorey - Level: 040; Elevation from Level: -960
IfcClassificationReference - Keynote: 07.10.43; GVH_artnr 01: 07.10.43; GVH_artnr 02: geen waarde gevonden; GVH_artnr 03: geen waarde gevonden; GVH_artnr 04: geen waarde gevonden; GVH_artnr 05: geen waarde gevonden; GVH_artnr 06: geen waarde gevonden; TDS_link: .\05 As Builtdossier\2. Bouwkunde\2.1 Architectuur\2.1.7 Gevelsluiting\2.1.7.3 Gevelbekleding (MSB)\2.1.7.3.2 technische fiche's\TF A 07.10.43 Puntprofiel (B).pdf
IfcRoot - Name: 900 x 1600 mm
Qto_WallBaseQuantities - NetVolume: 0.00192378
Pset_ConcreteElementGeneral - ConstructionMethod: prefabricated
Pset_Condition - AssessmentCondition: Empty
Pset_EnvironmentalImpactIndicators - Reference: 900 x 1600 mm; sets with these values: 2
Pset_WallCommon - Reference: 900 x 1600 mm; IsExternal: no
Name (BB_07.10_Gevelbekleding_PuntProfiel, 900 mm, vol_GMO:900 x 1600 mm:...)
5929059
5929061

# IfcWall: BB_Metaal_Aluminium_Puntprofiel 1 (69)
Type - Material: BB_Metaal_Aluminium_Puntprofiel
Cpset_Wall - LevelOfAccuracy: in te vullen door Buildwise
IfcClassificationReference - Keynote: 07.10.43; GVH_artnr 01: 07.10.43; GVH_artnr 02: geen waarde gevonden; GVH_artnr 03: geen waarde gevonden; GVH_artnr 04: geen waarde gevonden; GVH_artnr 05: geen waarde gevonden; GVH_artnr 06: geen waarde gevonden; TDS_link: .\05 As Builtdossier\2. Bouwkunde\2.1 Architectuur\2.1.7 Gevelsluiting\2.1.7.3 Gevelbekleding (MSB)\2.1.7.3.2 technische fiche's\TF A 07.10.43 Puntprofiel (B).pdf
Pset_ConcreteElementGeneral - ConstructionMethod: prefabricated
Pset_Condition - AssessmentCondition: Empty
Pset_EnvironmentalImpactIndicators - sets with these values: 2
Pset_WallCommon - IsExternal: no
Name | In | Level | Elevation from Level | Name = Pset_EnvironmentalImpactIndicators, Reference = Pset_WallCommon, Reference | NetVolume
BB_07.10_Gevelbekleding_PuntProfiel, 810 mm, vol_GMO:810 x 1780 mm:25113554 | 020 | 020 | 840 | 810 x 1780 mm | 0.00193018
BB_07.10_Gevelbekleding_PuntProfiel, 900 mm, vol_GMO:900 x 1780 mm:5911932 | 030 | 030 | 840 | 900 x 1780 mm | 0.00214021
BB_07.10_Gevelbekleding_PuntProfiel, 900 mm, vol_GMO:900 x 1600 mm:5926936 | 040 | 040 | -960 | 900 x 1600 mm | 0.00192378
BB_07.10_Gevelbekleding_PuntProfiel, 900 mm, vol_GMO:900 x 1600 mm:5927045 | 040 | 040 | -960 | 900 x 1600 mm | 0.00192378
BB_07.10_Gevelbekleding_PuntProfiel, 900 mm, vol_GMO:900 x 1600 mm:5927053 | 040 | 040 | -960 | 900 x 1600 mm | 0.00192378
BB_07.10_Gevelbekleding_PuntProfiel, 900 mm, vol_GMO:900 x 1600 mm:5927063 | 040 | 040 | -960 | 900 x 1600 mm | 0.00192378
BB_07.10_Gevelbekleding_PuntProfiel, 900 mm, vol_GMO:900 x 1600 mm:5927073 | 040 | 040 | -960 | 900 x 1600 mm | 0.00192378
BB_07.10_Gevelbekleding_PuntProfiel, 900 mm, vol_GMO:900 x 1600 mm:5927081 | 040 | 040 | -960 | 900 x 1600 mm | 0.00192378
BB_07.10_Gevelbekleding_PuntProfiel, 900 mm, vol_GMO:900 x 1600 mm:5927089 | 040 | 040 | -960 | 900 x 1600 mm | 0.00192378
BB_07.10_Gevelbekleding_PuntProfiel, 900 mm, vol_GMO:900 x 1600 mm:5927101 | 040 | 040 | -960 | 900 x 1600 mm | 0.00192378
BB_07.10_Gevelbekleding_PuntProfiel, 900 mm, vol_GMO:900 x 1600 mm:5927711 | 040 | 040 | -960 | 900 x 1600 mm | 0.00192378
BB_07.10_Gevelbekleding_PuntProfiel, 900 mm, vol_GMO:900 x 1600 mm:5927719 | 040 | 040 | -960 | 900 x 1600 mm | 0.00192378
BB_07.10_Gevelbekleding_PuntProfiel, 900 mm, vol_GMO:900 x 1600 mm:5927875 | 040 | 040 | -960 | 900 x 1600 mm | 0.00192378
BB_07.10_Gevelbekleding_PuntProfiel, 900 mm, vol_GMO:900 x 1600 mm:5927911 | 040 | 040 | -960 | 900 x 1600 mm | 0.00192378
BB_07.10_Gevelbekleding_PuntProfiel, 900 mm, vol_GMO:900 x 1600 mm:5927912 | 040 | 040 | -960 | 900 x 1600 mm | 0.00192378
BB_07.10_Gevelbekleding_PuntProfiel, 900 mm, vol_GMO:900 x 1600 mm:5927922 | 040 | 040 | -960 | 900 x 1600 mm | 0.00192378
BB_07.10_Gevelbekleding_PuntProfiel, 900 mm, vol_GMO:900 x 1600 mm:5927923 | 040 | 040 | -960 | 900 x 1600 mm | 0.00192378
BB_07.10_Gevelbekleding_PuntProfiel, 900 mm, vol_GMO:900 x 1600 mm:5927935 | 040 | 040 | -960 | 900 x 1600 mm | 0.00192378
BB_07.10_Gevelbekleding_PuntProfiel, 900 mm, vol_GMO:900 x 1600 mm:5927936 | 040 | 040 | -960 | 900 x 1600 mm | 0.00192378
BB_07.10_Gevelbekleding_PuntProfiel, 900 mm, vol_GMO:900 x 1600 mm:5927946 | 040 | 040 | -960 | 900 x 1600 mm | 0.00192378
BB_07.10_Gevelbekleding_PuntProfiel, 900 mm, vol_GMO:900 x 1600 mm:5927947 | 040 | 040 | -960 | 900 x 1600 mm | 0.00192378
BB_07.10_Gevelbekleding_PuntProfiel, 900 mm, vol_GMO:900 x 1600 mm:5927957 | 040 | 040 | -960 | 900 x 1600 mm | 0.00192378
BB_07.10_Gevelbekleding_PuntProfiel, 900 mm, vol_GMO:900 x 1600 mm:5927958 | 040 | 040 | -960 | 900 x 1600 mm | 0.00192378
BB_07.10_Gevelbekleding_PuntProfiel, 900 mm, vol_GMO:900 x 1600 mm:5927968 | 040 | 040 | -960 | 900 x 1600 mm | 0.00192378
BB_07.10_Gevelbekleding_PuntProfiel, 900 mm, vol_GMO:900 x 1600 mm:5927969 | 040 | 040 | -960 | 900 x 1600 mm | 0.00192378
BB_07.10_Gevelbekleding_PuntProfiel, 900 mm, vol_GMO:900 x 1600 mm:5927979 | 040 | 040 | -960 | 900 x 1600 mm | 0.00192378
BB_07.10_Gevelbekleding_PuntProfiel, 900 mm, vol_GMO:900 x 1600 mm:5927980 | 040 | 040 | -960 | 900 x 1600 mm | 0.00192378
BB_07.10_Gevelbekleding_PuntProfiel, 900 mm, vol_GMO:900 x 1600 mm:5927990 | 040 | 040 | -960 | 900 x 1600 mm | 0.00192378
BB_07.10_Gevelbekleding_PuntProfiel, 900 mm, vol_GMO:900 x 1600 mm:5927991 | 040 | 040 | -960 | 900 x 1600 mm | 0.00192378
BB_07.10_Gevelbekleding_PuntProfiel, 900 mm, vol_GMO:900 x 1600 mm:5928064 | 040 | 040 | -960 | 900 x 1600 mm | 0.00192378
BB_07.10_Gevelbekleding_PuntProfiel, 900 mm, vol_GMO:900 x 1600 mm:5928127 | 040 | 040 | -960 | 900 x 1600 mm | 0.00192378
BB_07.10_Gevelbekleding_PuntProfiel, 900 mm, vol_GMO:900 x 1600 mm:5928134 | 040 | 040 | -960 | 900 x 1600 mm | 0.00192378
BB_07.10_Gevelbekleding_PuntProfiel, 900 mm, vol_GMO:900 x 1600 mm:5928135 | 040 | 040 | -960 | 900 x 1600 mm | 0.00192378
BB_07.10_Gevelbekleding_PuntProfiel, 900 mm, vol_GMO:900 x 1600 mm:5928144 | 040 | 040 | -960 | 900 x 1600 mm | 0.00192378
BB_07.10_Gevelbekleding_PuntProfiel, 900 mm, vol_GMO:900 x 1600 mm:5928154 | 040 | 040 | -960 | 900 x 1600 mm | 0.00192378
BB_07.10_Gevelbekleding_PuntProfiel, 900 mm, vol_GMO:900 x 1600 mm:5928160 | 040 | 040 | -960 | 900 x 1600 mm | 0.00192378
BB_07.10_Gevelbekleding_PuntProfiel, 900 mm, vol_GMO:900 x 1600 mm:5928161 | 040 | 040 | -960 | 900 x 1600 mm | 0.00192378
BB_07.10_Gevelbekleding_PuntProfiel, 900 mm, vol_GMO:900 x 1600 mm:5928162 | 040 | 040 | -960 | 900 x 1600 mm | 0.00192378
BB_07.10_Gevelbekleding_PuntProfiel, 900 mm, vol_GMO:900 x 1600 mm:5928174 | 040 | 040 | -960 | 900 x 1600 mm | 0.00192378
BB_07.10_Gevelbekleding_PuntProfiel, 900 mm, vol_GMO:900 x 1600 mm:5928188 | 040 | 040 | -960 | 900 x 1600 mm | 0.00192378
BB_07.10_Gevelbekleding_PuntProfiel, 900 mm, vol_GMO:900 x 1600 mm:5928189 | 040 | 040 | -960 | 900 x 1600 mm | 0.00192378
BB_07.10_Gevelbekleding_PuntProfiel, 900 mm, vol_GMO:900 x 1600 mm:5928196 | 040 | 040 | -960 | 900 x 1600 mm | 0.00192378
BB_07.10_Gevelbekleding_PuntProfiel, 900 mm, vol_GMO:900 x 1600 mm:5928210 | 040 | 040 | -960 | 900 x 1600 mm | 0.00192378
BB_07.10_Gevelbekleding_PuntProfiel, 900 mm, vol_GMO:900 x 1600 mm:5928432 | 040 | 040 | -960 | 900 x 1600 mm | 0.00192378
BB_07.10_Gevelbekleding_PuntProfiel, 900 mm, vol_GMO:900 x 1600 mm:5928480 | 040 | 040 | -960 | 900 x 1600 mm | 0.00192378
BB_07.10_Gevelbekleding_PuntProfiel, 900 mm, vol_GMO:900 x 1600 mm:5928490 | 040 | 040 | -960 | 900 x 1600 mm | 0.00192378
BB_07.10_Gevelbekleding_PuntProfiel, 900 mm, vol_GMO:900 x 1600 mm:5928491 | 040 | 040 | -960 | 900 x 1600 mm | 0.00192378
BB_07.10_Gevelbekleding_PuntProfiel, 900 mm, vol_GMO:900 x 1600 mm:5928505 | 040 | 040 | -960 | 900 x 1600 mm | 0.00192378
BB_07.10_Gevelbekleding_PuntProfiel, 900 mm, vol_GMO:900 x 1600 mm:5928525 | 040 | 040 | -960 | 900 x 1600 mm | 0.00192378
BB_07.10_Gevelbekleding_PuntProfiel, 900 mm, vol_GMO:900 x 1600 mm:5928526 | 040 | 040 | -960 | 900 x 1600 mm | 0.00192378
BB_07.10_Gevelbekleding_PuntProfiel, 900 mm, vol_GMO:900 x 1600 mm:5928527 | 040 | 040 | -960 | 900 x 1600 mm | 0.00192378
BB_07.10_Gevelbekleding_PuntProfiel, 900 mm, vol_GMO:900 x 1600 mm:5928535 | 040 | 040 | -960 | 900 x 1600 mm | 0.00192378
BB_07.10_Gevelbekleding_PuntProfiel, 900 mm, vol_GMO:900 x 1600 mm:5928545 | 040 | 040 | -960 | 900 x 1600 mm | 0.00192378
BB_07.10_Gevelbekleding_PuntProfiel, 900 mm, vol_GMO:900 x 1600 mm:5928546 | 040 | 040 | -960 | 900 x 1600 mm | 0.00192378
BB_07.10_Gevelbekleding_PuntProfiel, 900 mm, vol_GMO:900 x 1600 mm:5928556 | 040 | 040 | -960 | 900 x 1600 mm | 0.00192378
BB_07.10_Gevelbekleding_PuntProfiel, 900 mm, vol_GMO:900 x 1600 mm:5928557 | 040 | 040 | -960 | 900 x 1600 mm | 0.00192378
BB_07.10_Gevelbekleding_PuntProfiel, 900 mm, vol_GMO:900 x 1600 mm:5928567 | 040 | 040 | -960 | 900 x 1600 mm | 0.00192378
BB_07.10_Gevelbekleding_PuntProfiel, 900 mm, vol_GMO:900 x 1600 mm:5928577 | 040 | 040 | -960 | 900 x 1600 mm | 0.00192378
BB_07.10_Gevelbekleding_PuntProfiel, 900 mm, vol_GMO:900 x 1600 mm:10382590 | 040 | 040 | -960 | 900 x 1600 mm | 0.00192378
BB_07.10_Gevelbekleding_PuntProfiel, 900 mm, vol_GMO:900 x 1600 mm:10382619 | 040 | 040 | -960 | 900 x 1600 mm | 0.00192378
BB_07.10_Gevelbekleding_PuntProfiel, 900 mm, vol_GMO:900 x 1600 mm:10382622 | 040 | 040 | -960 | 900 x 1600 mm | 0.00192378
BB_07.10_Gevelbekleding_PuntProfiel, 900 mm, vol_GMO:900 x 1600 mm:10382631 | 040 | 040 | -960 | 900 x 1600 mm | 0.00192378
BB_07.10_Gevelbekleding_PuntProfiel, 900 mm, vol_GMO:900 x 1600 mm:10382634 | 040 | 040 | -960 | 900 x 1600 mm | 0.00192378
BB_07.10_Gevelbekleding_PuntProfiel, 900 mm, vol_GMO:900 x 1600 mm:10382643 | 040 | 040 | -960 | 900 x 1600 mm | 0.00192378
BB_07.10_Gevelbekleding_PuntProfiel, 900 mm, vol_GMO:900 x 1600 mm:10382646 | 040 | 040 | -960 | 900 x 1600 mm | 0.00192378
BB_07.10_Gevelbekleding_PuntProfiel, 900 mm, vol_GMO:900 x 1600 mm:10382655 | 040 | 040 | -960 | 900 x 1600 mm | 0.00192378
BB_07.10_Gevelbekleding_PuntProfiel, 900 mm, vol_GMO:900 x 1600 mm:10382658 | 040 | 040 | -960 | 900 x 1600 mm | 0.00192378
BB_07.10_Gevelbekleding_PuntProfiel, 900 mm, vol_GMO:900 x 1600 mm:10382673 | 040 | 040 | -960 | 900 x 1600 mm | 0.00192378
BB_07.10_Gevelbekleding_PuntProfiel, 900 mm, vol_GMO:900 x 1600 mm:10382676 | 040 | 040 | -960 | 900 x 1600 mm | 0.00192378

# IfcWall: BB_Metaal_Aluminium_Puntprofiel 127.279, BB_07.10_Gevelbekleding_PuntProfiel, 900 mm, vol_GMO:900 x 1600 mm:5929530
In: 040
Type - Material: BB_Metaal_Aluminium_Puntprofiel
Cpset_Wall - LevelOfAccuracy: in te vullen door Buildwise
IfcBuildingStorey - Level: 040; Elevation from Level: -960
IfcClassificationReference - Keynote: 07.10.43; GVH_artnr 01: 07.10.43; GVH_artnr 02: geen waarde gevonden; GVH_artnr 03: geen waarde gevonden; GVH_artnr 04: geen waarde gevonden; GVH_artnr 05: geen waarde gevonden; GVH_artnr 06: geen waarde gevonden; TDS_link: .\05 As Builtdossier\2. Bouwkunde\2.1 Architectuur\2.1.7 Gevelsluiting\2.1.7.3 Gevelbekleding (MSB)\2.1.7.3.2 technische fiche's\TF A 07.10.43 Puntprofiel (B).pdf
IfcRoot - Name: 900 x 1600 mm
Qto_WallBaseQuantities - NetVolume: 0.00192378
Pset_ConcreteElementGeneral - ConstructionMethod: prefabricated
Pset_Condition - AssessmentCondition: Empty
Pset_EnvironmentalImpactIndicators - Reference: 900 x 1600 mm; sets with these values: 2
Pset_WallCommon - Reference: 900 x 1600 mm; IsExternal: no

# IfcWall: BB_Metaal_Aluminium_Puntprofiel 190.919, BB_07.10_Gevelbekleding_PuntProfiel, 900 mm, vol_GMO:900 x 1600 mm:5929060
In: 040
Type - Material: BB_Metaal_Aluminium_Puntprofiel
Cpset_Wall - LevelOfAccuracy: in te vullen door Buildwise
IfcBuildingStorey - Level: 040; Elevation from Level: -960
IfcClassificationReference - Keynote: 07.10.43; GVH_artnr 01: 07.10.43; GVH_artnr 02: geen waarde gevonden; GVH_artnr 03: geen waarde gevonden; GVH_artnr 04: geen waarde gevonden; GVH_artnr 05: geen waarde gevonden; GVH_artnr 06: geen waarde gevonden; TDS_link: .\05 As Builtdossier\2. Bouwkunde\2.1 Architectuur\2.1.7 Gevelsluiting\2.1.7.3 Gevelbekleding (MSB)\2.1.7.3.2 technische fiche's\TF A 07.10.43 Puntprofiel (B).pdf
IfcRoot - Name: 900 x 1600 mm
Qto_WallBaseQuantities - NetVolume: 0.00192378
Pset_ConcreteElementGeneral - ConstructionMethod: prefabricated
Pset_Condition - AssessmentCondition: Empty
Pset_EnvironmentalImpactIndicators - Reference: 900 x 1600 mm; sets with these values: 2
Pset_WallCommon - Reference: 900 x 1600 mm; IsExternal: no

# IfcWall: BB_Metaal_Aluminium_Puntprofiel 63.6396 (6)
In: 040
Type - Material: BB_Metaal_Aluminium_Puntprofiel
Cpset_Wall - LevelOfAccuracy: in te vullen door Buildwise
IfcBuildingStorey - Level: 040; Elevation from Level: -960
IfcClassificationReference - Keynote: 07.10.43; GVH_artnr 01: 07.10.43; GVH_artnr 02: geen waarde gevonden; GVH_artnr 03: geen waarde gevonden; GVH_artnr 04: geen waarde gevonden; GVH_artnr 05: geen waarde gevonden; GVH_artnr 06: geen waarde gevonden; TDS_link: .\05 As Builtdossier\2. Bouwkunde\2.1 Architectuur\2.1.7 Gevelsluiting\2.1.7.3 Gevelbekleding (MSB)\2.1.7.3.2 technische fiche's\TF A 07.10.43 Puntprofiel (B).pdf
IfcRoot - Name: 900 x 1600 mm
Qto_WallBaseQuantities - NetVolume: 0.00192378
Pset_ConcreteElementGeneral - ConstructionMethod: prefabricated
Pset_Condition - AssessmentCondition: Empty
Pset_EnvironmentalImpactIndicators - Reference: 900 x 1600 mm; sets with these values: 2
Pset_WallCommon - Reference: 900 x 1600 mm; IsExternal: no
Name (BB_07.10_Gevelbekleding_PuntProfiel, 900 mm, vol_GMO:900 x 1600 mm:...)
5929524
5929525
5929526
5935127
5935128
5935129

# IfcWall: BB_Metselwerk_Bestaand 100 (7)
Type - Material: BB_Metselwerk_Bestaand
PredefinedType: SOLIDWALL
Cpset_Wall - LevelOfAccuracy: in te vullen door Buildwise
IfcClassificationReference - GVH_artnr 01: geen waarde gevonden; GVH_artnr 02: geen waarde gevonden; GVH_artnr 03: geen waarde gevonden; GVH_artnr 04: geen waarde gevonden; GVH_artnr 05: geen waarde gevonden; GVH_artnr 06: geen waarde gevonden
Pset_Condition - AssessmentCondition: Empty
Pset_EnvironmentalImpactIndicators - sets with these values: 2
Pset_WallCommon - IsExternal: yes; LoadBearing: no; ExtendToStructure: no
Name (Basic Wall:...) | In | Base Offset | Top Offset | Base Constraint | Name = Pset_EnvironmentalImpactIndicators, Reference = Pset_WallCommon, Reference | Length | NetVolume | Height | Width | GrossFootprintArea | GrossVolume | GrossSideArea = NetSideArea | Top Constraint
BB_XX_Wand uit metselwerk, 190 mm:2234466 | K10 | 0 | 0 | K10 | BB_XX_Wand uit metselwerk, 190 mm | 100 | 0.05282 | 2780 | 190 | 0.019 | 0.100358 | 0.5282 | Pset_WallCommon - FireRating: EI60
BB_XX_Wand uit metselwerk, 100 mm:1185777 | 000 | -80 | -280 | 000 | BB_XX_Wand uit metselwerk, 100 mm | 1000 | 0.34 | 3400 | 100 | 0.1 | 0.34 | 3.4 | Up to level: 010
BB_XX_Wand uit metselwerk, 100 mm:1270140 | 000 | -80 | -280 | 000 | BB_XX_Wand uit metselwerk, 100 mm | 1000 | 0.34 | 3400 | 100 | 0.1 | 0.34 | 3.4 | Up to level: 010
BB_XX_Wand uit metselwerk, 100 mm:1209694 | 010 | -80 | -280 | 010 | BB_XX_Wand uit metselwerk, 100 mm | 1000 | 0.34 | 3400 | 100 | 0.1 | 0.34 | 3.4 | Up to level: 020
BB_XX_Wand uit metselwerk, 100 mm:1214670 | 010 | -80 | -280 | 010 | BB_XX_Wand uit metselwerk, 100 mm | 1000 | 0.34 | 3400 | 100 | 0.1 | 0.34 | 3.4 | Up to level: 020
BB_XX_Wand uit metselwerk, 100 mm:1254521 | 020 | -80 | -280 | 020 | BB_XX_Wand uit metselwerk, 100 mm | 1000 | 0.34 | 3400 | 100 | 0.1 | 0.34 | 3.4 | Up to level: 030
BB_XX_Wand uit metselwerk, 100 mm:1261810 | 020 | -80 | -280 | 020 | BB_XX_Wand uit metselwerk, 100 mm | 1000 | 0.34 | 3400 | 100 | 0.1 | 0.34 | 3.4 | Up to level: 030

# IfcWall: BB_Metselwerk_Bestaand 140 (69)
Type - Material: BB_Metselwerk_Bestaand
PredefinedType: SOLIDWALL
Cpset_Wall - LevelOfAccuracy: in te vullen door Buildwise
IfcClassificationReference - GVH_artnr 01: geen waarde gevonden; GVH_artnr 02: geen waarde gevonden; GVH_artnr 03: geen waarde gevonden; GVH_artnr 04: geen waarde gevonden; GVH_artnr 05: geen waarde gevonden; GVH_artnr 06: geen waarde gevonden
Pset_Condition - AssessmentCondition: Empty
Pset_EnvironmentalImpactIndicators - sets with these values: 2
Pset_WallCommon - IsExternal: yes; LoadBearing: no; ExtendToStructure: no
Name (Basic Wall:...) | In | Base Offset | Top Offset | Base Constraint | Name = Pset_EnvironmentalImpactIndicators, Reference = Pset_WallCommon, Reference | Length | NetVolume | Height | Width | GrossFootprintArea | GrossVolume | GrossSideArea | NetSideArea | FireRating | Top Constraint
BB_XX_Wand uit metselwerk, 140 mm:1596148 | K20 | 0 | 0 | K20 | BB_XX_Wand uit metselwerk, 140 mm | 980 | 0.28812 | 2100 | 140 | 0.1372 | 0.28812 | 2.058 | 2.058 | EI60
BB_XX_Wand uit metselwerk, 190 mm:1414869 | K10 | 2150 | 2290 | K10 | BB_XX_Wand uit metselwerk, 190 mm | 1010 | 0.026866 | 140 | 190 | 0.1919 | 0.026866 | 0.1414 | 0.1414 |  | Up to level: K10
BB_XX_Wand uit metselwerk, 140 mm:1999798 | K10 | 0 | -280 | K10 | BB_XX_Wand uit metselwerk, 140 mm | 3800 | 1.57472 | 2960 | 140 | 0.532001 | 1.57472 | 11.248 | 11.248 |  | Up to level: 000
BB_XX_Wand uit metselwerk, 140 mm:512524 | 000 | -200 | -200 | 000 | BB_XX_Wand uit metselwerk, 140 mm | 900 | 0.4536 | 3600 | 140 | 0.126 | 0.4536 | 3.24 | 3.24 | EI60 | Up to level: 010
BB_XX_Wand uit metselwerk, 140 mm:513344 | 000 | -80 | -460 | 000 | BB_XX_Wand uit metselwerk, 140 mm | 1470 | 0.662676 | 3220 | 140 | 0.2058 | 0.662676 | 4.7334 | 4.7334 |  | Up to level: 010
BB_XX_Wand uit metselwerk, 140 mm:587372 | 000 | -80 | -580 | 000 | BB_XX_Wand uit metselwerk, 140 mm | 1107.31 | 0.419198 | 3100 | 140 | 0.135225 | 0.419815 | 2.99868 | 2.99868 |  | Up to level: 010
BB_XX_Wand uit metselwerk, 140 mm:587572 | 000 | -80 | -280 | 000 | BB_XX_Wand uit metselwerk, 140 mm | 2358.02 | 1.0891 | 3400 | 140 | 0.320322 | 1.12242 | 8.01725 | 8.01725 |  | Up to level: 010
BB_XX_Wand uit metselwerk, 140 mm:588384 | 000 | -80 | -580 | 000 | BB_XX_Wand uit metselwerk, 140 mm | 1462.29 | 0.573257 | 3100 | 140 | 0.184922 | 0.573874 | 4.0991 | 4.0991 |  | Up to level: 010
BB_XX_Wand uit metselwerk, 140 mm:682937 | 000 | -80 | -460 | 000 | BB_XX_Wand uit metselwerk, 140 mm | 1610 | 0.725788 | 3220 | 140 | 0.2254 | 0.725788 | 5.1842 | 5.1842 |  | Up to level: 010
BB_XX_Wand uit metselwerk, 140 mm:687098 | 000 | -200 | -200 | 000 | BB_XX_Wand uit metselwerk, 140 mm | 928.159 | 0.432512 | 3600 | 140 | 0.120142 | 0.467792 | 3.34137 | 3.34137 | EI60 | Up to level: 010
BB_XX_Wand uit metselwerk, 140 mm:1184878 | 000 | -80 | -280 | 000 | BB_XX_Wand uit metselwerk, 140 mm | 1870 | 0.890122 | 3400 | 140 | 0.261801 | 0.890122 | 6.35801 | 6.35801 |  | Up to level: 010
BB_XX_Wand uit metselwerk, 140 mm:1185339 | 000 | -80 | -280 | 000 | BB_XX_Wand uit metselwerk, 140 mm | 1090 | 0.51884 | 3400 | 140 | 0.1526 | 0.51884 | 3.706 | 3.706 | EI60 | Up to level: 010
BB_XX_Wand uit metselwerk, 140 mm:1185410 | 000 | -80 | -280 | 000 | BB_XX_Wand uit metselwerk, 140 mm | 410 | 0.19516 | 3400 | 140 | 0.0574 | 0.19516 | 1.394 | 1.394 | EI60 | Up to level: 010
BB_XX_Wand uit metselwerk, 140 mm:1185465 | 000 | -80 | -280 | 000 | BB_XX_Wand uit metselwerk, 140 mm | 1090 | 0.51884 | 3400 | 140 | 0.1526 | 0.51884 | 3.706 | 3.706 | EI60 | Up to level: 010
BB_XX_Wand uit metselwerk, 140 mm:1195958 | 000 | -80 | -280 | 000 | BB_XX_Wand uit metselwerk, 140 mm | 500 | 0.238 | 3400 | 140 | 0.07 | 0.238 | 1.7 | 1.7 |  | Up to level: 010
BB_XX_Wand uit metselwerk, 140 mm:1196373 | 000 | -80 | -280 | 000 | BB_XX_Wand uit metselwerk, 140 mm | 910 | 0.43316 | 3400 | 140 | 0.1274 | 0.43316 | 3.094 | 3.094 |  | Up to level: 010
BB_XX_Wand uit metselwerk, 140 mm:1196495 | 000 | -80 | -280 | 000 | BB_XX_Wand uit metselwerk, 140 mm | 2000 | 0.952 | 3400 | 140 | 0.28 | 0.952 | 6.8 | 6.8 |  | Up to level: 010
BB_XX_Wand uit metselwerk, 140 mm:1265536 | 000 | -200 | 0 | 000 | BB_XX_Wand uit metselwerk, 140 mm | 2070 | 0.967932 | 3340 | 140 | 0.2898 | 0.967932 | 6.9138 | 6.9138 | EI60
BB_XX_Wand uit metselwerk, 140 mm:1270142 | 000 | -80 | -280 | 000 | BB_XX_Wand uit metselwerk, 140 mm | 1790 | 0.852042 | 3400 | 140 | 0.250601 | 0.852042 | 6.08601 | 6.08601 |  | Up to level: 010
BB_XX_Wand uit metselwerk, 140 mm:1270148 | 000 | -80 | -280 | 000 | BB_XX_Wand uit metselwerk, 140 mm | 1090 | 0.51884 | 3400 | 140 | 0.1526 | 0.51884 | 3.706 | 3.706 |  | Up to level: 010
BB_XX_Wand uit metselwerk, 140 mm:1270149 | 000 | -80 | -280 | 000 | BB_XX_Wand uit metselwerk, 140 mm | 410 | 0.19516 | 3400 | 140 | 0.0574 | 0.19516 | 1.394 | 1.394 |  | Up to level: 010
BB_XX_Wand uit metselwerk, 140 mm:1270150 | 000 | -80 | -280 | 000 | BB_XX_Wand uit metselwerk, 140 mm | 1090 | 0.51884 | 3400 | 140 | 0.1526 | 0.51884 | 3.706 | 3.706 |  | Up to level: 010
BB_XX_Wand uit metselwerk, 140 mm:25514814 | 000 | -200 | 0 | 000 | BB_XX_Wand uit metselwerk, 140 mm | 2605 | 1.2181 | 3340 | 140 | 0.3647 | 1.2181 | 8.7007 | 8.7007 | EI60
BB_XX_Wand uit metselwerk, 140 mm:648709 | 010 | -80 | -460 | 010 | BB_XX_Wand uit metselwerk, 140 mm | 1610 | 0.725788 | 3220 | 140 | 0.2254 | 0.725788 | 5.1842 | 5.1842 | EI60 | Up to level: 020
BB_XX_Wand uit metselwerk, 140 mm:650921 | 010 | -200 | -200 | 010 | BB_XX_Wand uit metselwerk, 140 mm | 640 | 0.32256 | 3600 | 140 | 0.0896 | 0.32256 | 2.304 | 2.304 | EI60 | Up to level: 020
BB_XX_Wand uit metselwerk, 140 mm:680726 | 010 | -200 | -200 | 010 | BB_XX_Wand uit metselwerk, 140 mm | 590 | 0.29736 | 3600 | 140 | 0.0826 | 0.29736 | 2.124 | 2.124 | EI60 | Up to level: 020
BB_XX_Wand uit metselwerk, 140 mm:680826 | 010 | -200 | -200 | 010 | BB_XX_Wand uit metselwerk, 140 mm | 900 | 0.4536 | 3600 | 140 | 0.126 | 0.4536 | 3.24 | 3.24 | EI60 | Up to level: 020
BB_XX_Wand uit metselwerk, 140 mm:683178 | 010 | -80 | -460 | 010 | BB_XX_Wand uit metselwerk, 140 mm | 1610 | 0.725788 | 3220 | 140 | 0.2254 | 0.725788 | 5.1842 | 5.1842 |  | Up to level: 020
BB_XX_Wand uit metselwerk, 140 mm:1205116 | 010 | -80 | -280 | 010 | BB_XX_Wand uit metselwerk, 140 mm | 1000 | 0.476 | 3400 | 140 | 0.14 | 0.476 | 3.4 | 3.4 |  | Up to level: 020
BB_XX_Wand uit metselwerk, 140 mm:1205393 | 010 | -80 | -280 | 010 | BB_XX_Wand uit metselwerk, 140 mm | 1910 | 0.90916 | 3400 | 140 | 0.2674 | 0.90916 | 6.494 | 6.494 |  | Up to level: 020
BB_XX_Wand uit metselwerk, 140 mm:1210126 | 010 | -80 | -280 | 010 | BB_XX_Wand uit metselwerk, 140 mm | 1870 | 0.890122 | 3400 | 140 | 0.261801 | 0.890122 | 6.35801 | 6.35801 |  | Up to level: 020
BB_XX_Wand uit metselwerk, 140 mm:1211849 | 010 | -80 | -280 | 010 | BB_XX_Wand uit metselwerk, 140 mm | 1090 | 0.51884 | 3400 | 140 | 0.1526 | 0.51884 | 3.706 | 3.706 | EI60 | Up to level: 020
BB_XX_Wand uit metselwerk, 140 mm:1211874 | 010 | -80 | -280 | 010 | BB_XX_Wand uit metselwerk, 140 mm | 410 | 0.19516 | 3400 | 140 | 0.0574 | 0.19516 | 1.394 | 1.394 | EI60 | Up to level: 020
BB_XX_Wand uit metselwerk, 140 mm:1211929 | 010 | -80 | -280 | 010 | BB_XX_Wand uit metselwerk, 140 mm | 1090 | 0.51884 | 3400 | 140 | 0.1526 | 0.51884 | 3.706 | 3.706 | EI60 | Up to level: 020
BB_XX_Wand uit metselwerk, 140 mm:1214268 | 010 | -80 | -280 | 010 | BB_XX_Wand uit metselwerk, 140 mm | 1870 | 0.890122 | 3400 | 140 | 0.261801 | 0.890122 | 6.35801 | 6.35801 |  | Up to level: 020
BB_XX_Wand uit metselwerk, 140 mm:1214785 | 010 | -80 | -280 | 010 | BB_XX_Wand uit metselwerk, 140 mm | 1090 | 0.51884 | 3400 | 140 | 0.1526 | 0.51884 | 3.706 | 3.706 | EI60 | Up to level: 020
BB_XX_Wand uit metselwerk, 140 mm:1214810 | 010 | -80 | -280 | 010 | BB_XX_Wand uit metselwerk, 140 mm | 410 | 0.19516 | 3400 | 140 | 0.0574 | 0.19516 | 1.394 | 1.394 | EI60 | Up to level: 020
BB_XX_Wand uit metselwerk, 140 mm:1214854 | 010 | -80 | -280 | 010 | BB_XX_Wand uit metselwerk, 140 mm | 1090 | 0.51884 | 3400 | 140 | 0.1526 | 0.51884 | 3.706 | 3.706 | EI60 | Up to level: 020
BB_XX_Wand uit metselwerk, 140 mm:695746 | 020 | -80 | -460 | 020 | BB_XX_Wand uit metselwerk, 140 mm | 1610 | 0.725788 | 3220 | 140 | 0.2254 | 0.725788 | 5.1842 | 5.1842 |  | Up to level: 030
BB_XX_Wand uit metselwerk, 140 mm:695764 | 020 | -200 | -200 | 020 | BB_XX_Wand uit metselwerk, 140 mm | 983.163 | 0.460234 | 3600 | 140 | 0.127843 | 0.495514 | 3.53939 | 3.53939 | EI60 | Up to level: 030
BB_XX_Wand uit metselwerk, 140 mm:695837 | 020 | -200 | -200 | 020 | BB_XX_Wand uit metselwerk, 140 mm | 640 | 0.32256 | 3600 | 140 | 0.0896 | 0.32256 | 2.304 | 2.304 | EI60 | Up to level: 030
BB_XX_Wand uit metselwerk, 140 mm:695964 | 020 | -200 | -200 | 020 | BB_XX_Wand uit metselwerk, 140 mm | 590 | 0.29736 | 3600 | 140 | 0.0826 | 0.29736 | 2.124 | 2.124 | EI60 | Up to level: 030
BB_XX_Wand uit metselwerk, 140 mm:695965 | 020 | -200 | -200 | 020 | BB_XX_Wand uit metselwerk, 140 mm | 900 | 0.4536 | 3600 | 140 | 0.126 | 0.4536 | 3.24 | 3.24 | EI60 | Up to level: 030
BB_XX_Wand uit metselwerk, 140 mm:696016 | 020 | -80 | -460 | 020 | BB_XX_Wand uit metselwerk, 140 mm | 1610 | 0.725788 | 3220 | 140 | 0.2254 | 0.725788 | 5.1842 | 5.1842 |  | Up to level: 030
BB_XX_Wand uit metselwerk, 140 mm:696090 | 020 | -200 | -200 | 020 | BB_XX_Wand uit metselwerk, 140 mm | 928.159 | 0.432512 | 3600 | 140 | 0.120142 | 0.467792 | 3.34137 | 3.34137 | EI60 | Up to level: 030
BB_XX_Wand uit metselwerk, 140 mm:1254518 | 020 | -80 | -280 | 020 | BB_XX_Wand uit metselwerk, 140 mm | 1870 | 0.890122 | 3400 | 140 | 0.261801 | 0.890122 | 6.35801 | 6.35801 |  | Up to level: 030
BB_XX_Wand uit metselwerk, 140 mm:1254522 | 020 | -80 | -280 | 020 | BB_XX_Wand uit metselwerk, 140 mm | 1090 | 0.51884 | 3400 | 140 | 0.1526 | 0.51884 | 3.706 | 3.706 | EI60 | Up to level: 030
BB_XX_Wand uit metselwerk, 140 mm:1254523 | 020 | -80 | -280 | 020 | BB_XX_Wand uit metselwerk, 140 mm | 410 | 0.19516 | 3400 | 140 | 0.0574 | 0.19516 | 1.394 | 1.394 | EI60 | Up to level: 030
BB_XX_Wand uit metselwerk, 140 mm:1254524 | 020 | -80 | -280 | 020 | BB_XX_Wand uit metselwerk, 140 mm | 1090 | 0.51884 | 3400 | 140 | 0.1526 | 0.51884 | 3.706 | 3.706 | EI60 | Up to level: 030
BB_XX_Wand uit metselwerk, 140 mm:1255003 | 020 | -80 | -280 | 020 | BB_XX_Wand uit metselwerk, 140 mm | 1000 | 0.476 | 3400 | 140 | 0.14 | 0.476 | 3.4 | 3.4 | EI60 | Up to level: 030
BB_XX_Wand uit metselwerk, 140 mm:1255005 | 020 | -80 | -280 | 020 | BB_XX_Wand uit metselwerk, 140 mm | 1910 | 0.90916 | 3400 | 140 | 0.2674 | 0.90916 | 6.494 | 6.494 |  | Up to level: 030
BB_XX_Wand uit metselwerk, 140 mm:1261812 | 020 | -80 | -280 | 020 | BB_XX_Wand uit metselwerk, 140 mm | 1870 | 0.890122 | 3400 | 140 | 0.261801 | 0.890122 | 6.35801 | 6.35801 |  | Up to level: 030
BB_XX_Wand uit metselwerk, 140 mm:1261817 | 020 | -80 | -280 | 020 | BB_XX_Wand uit metselwerk, 140 mm | 1090 | 0.51884 | 3400 | 140 | 0.1526 | 0.51884 | 3.706 | 3.706 | EI60 | Up to level: 030
BB_XX_Wand uit metselwerk, 140 mm:1261818 | 020 | -80 | -280 | 020 | BB_XX_Wand uit metselwerk, 140 mm | 410 | 0.19516 | 3400 | 140 | 0.0574 | 0.19516 | 1.394 | 1.394 | EI60 | Up to level: 030
BB_XX_Wand uit metselwerk, 140 mm:1261819 | 020 | -80 | -280 | 020 | BB_XX_Wand uit metselwerk, 140 mm | 1090 | 0.51884 | 3400 | 140 | 0.1526 | 0.51884 | 3.706 | 3.706 | EI60 | Up to level: 030
BB_XX_Wand uit metselwerk, 140 mm:8706462 | 020 | -80 | -280 | 020 | BB_XX_Wand uit metselwerk, 140 mm | 2556.01 | 0.866854 | 3400 | 140 | 0.348041 | 1.15002 | 8.21442 | 6.42982 | EI60 | Up to level: 030
BB_XX_Wand uit metselwerk, 140 mm:705311 | 030 | -80 | 3000 | 030 | BB_XX_Wand uit metselwerk, 140 mm | 1462.29 | 0.569558 | 3080 | 140 | 0.184922 | 0.570171 | 4.07265 | 4.07265 |  | Up to level: 030
BB_XX_Wand uit metselwerk, 140 mm:705356 | 030 | -200 | 3140 | 030 | BB_XX_Wand uit metselwerk, 140 mm | 590 | 0.275884 | 3340 | 140 | 0.0826 | 0.275884 | 1.9706 | 1.9706 | EI60 | Up to level: 030
BB_XX_Wand uit metselwerk, 140 mm:705357 | 030 | -200 | 3140 | 030 | BB_XX_Wand uit metselwerk, 140 mm | 900 | 0.42084 | 3340 | 140 | 0.126 | 0.42084 | 3.006 | 3.006 | EI60 | Up to level: 030
BB_XX_Wand uit metselwerk, 140 mm:705358 | 030 | -80 | 2990 | 030 | BB_XX_Wand uit metselwerk, 140 mm | 1710 | 0.734958 | 3070 | 140 | 0.2394 | 0.734958 | 5.2497 | 5.2497 |  | Up to level: 030
BB_XX_Wand uit metselwerk, 140 mm:705364 | 030 | -200 | 3250 | 030 | BB_XX_Wand uit metselwerk, 140 mm | 928.159 | 0.414491 | 3450 | 140 | 0.120142 | 0.448301 | 3.20215 | 3.20215 | EI60 | Up to level: 030
BB_XX_Wand uit metselwerk, 140 mm:753807 | 030 | -80 | 3190 | 030 | BB_XX_Wand uit metselwerk, 140 mm | 790 | 0.361662 | 3270 | 140 | 0.1106 | 0.361662 | 2.5833 | 2.5833 | EI60 | Up to level: 030
BB_XX_Wand uit metselwerk, 140 mm:753846 | 030 | -80 | 3190 | 030 | BB_XX_Wand uit metselwerk, 140 mm | 490 | 0.224322 | 3270 | 140 | 0.0686 | 0.224322 | 1.6023 | 1.6023 | EI60 | Up to level: 030
BB_XX_Wand uit metselwerk, 140 mm:753909 | 030 | -80 | 3190 | 030 | BB_XX_Wand uit metselwerk, 140 mm | 790 | 0.361662 | 3270 | 140 | 0.1106 | 0.361662 | 2.5833 | 2.5833 | EI60 | Up to level: 030
BB_XX_Wand uit metselwerk, 140 mm:762447 | 030 | -80 | 3190 | 030 | BB_XX_Wand uit metselwerk, 140 mm | 570 | 0.260946 | 3270 | 140 | 0.0798 | 0.260946 | 1.8639 | 1.8639 | EI60 | Up to level: 030
BB_XX_Wand uit metselwerk, 140 mm:762516 | 030 | -80 | 3190 | 030 | BB_XX_Wand uit metselwerk, 140 mm | 650 | 0.29757 | 3270 | 140 | 0.091 | 0.29757 | 2.1255 | 2.1255 | EI60 | Up to level: 030
BB_XX_Wand uit metselwerk, 140 mm:1275869 | 030 | -80 | 2990 | 030 | BB_XX_Wand uit metselwerk, 140 mm | 1570 | 0.674786 | 3070 | 140 | 0.2198 | 0.674786 | 4.8199 | 4.8199 |  | Up to level: 030
BB_XX_Wand uit metselwerk, 140 mm:1277567 | 030 | -80 | 3200 | 030 | BB_XX_Wand uit metselwerk, 140 mm | 1000 | 0.4592 | 3280 | 140 | 0.14 | 0.4592 | 3.28 | 3.28 |  | Up to level: 030
BB_XX_Wand uit metselwerk, 140 mm:1277843 | 030 | -80 | 3200 | 030 | BB_XX_Wand uit metselwerk, 140 mm | 1910 | 0.877072 | 3280 | 140 | 0.2674 | 0.877072 | 6.2648 | 6.2648 |  | Up to level: 030

# IfcWall: BB_Metselwerk_Bestaand 190 (58)
Type - Material: BB_Metselwerk_Bestaand
PredefinedType: SOLIDWALL
Cpset_Wall - LevelOfAccuracy: in te vullen door Buildwise
IfcClassificationReference - GVH_artnr 01: geen waarde gevonden; GVH_artnr 02: geen waarde gevonden; GVH_artnr 03: geen waarde gevonden; GVH_artnr 04: geen waarde gevonden; GVH_artnr 05: geen waarde gevonden; GVH_artnr 06: geen waarde gevonden
Pset_Condition - AssessmentCondition: Empty
Pset_EnvironmentalImpactIndicators - sets with these values: 2
Pset_WallCommon - IsExternal: yes; LoadBearing: no
Name (Basic Wall:...) | In | Base Offset | Top Offset | Base Constraint | Name = Pset_EnvironmentalImpactIndicators, Reference = Pset_WallCommon, Reference | Length | NetVolume | Height | Width | GrossFootprintArea | GrossVolume | GrossSideArea | NetSideArea | FireRating | ExtendToStructure | Top Constraint
BB_XX_Wand uit metselwerk, 190 mm:1597042 | K20 | 0 | 0 | K20 | BB_XX_Wand uit metselwerk, 190 mm | 875 | 0.3325 | 2000 | 190 | 0.16625 | 0.3325 | 1.75 | 1.75 | EI60 | no
BB_XX_Wand uit metselwerk, 190 mm:1993229 | K20 | 0 | 0 | K20 | BB_XX_Wand uit metselwerk, 190 mm | 2210 | 1.13373 | 2700 | 190 | 0.4199 | 1.13373 | 5.967 | 5.967 |  | no | Up to level: K10
BB_XX_Wand uit metselwerk, 190 mm:819305 | K10 | 0 | 0 | K10 | BB_XX_Wand uit metselwerk, 190 mm | 1790 | 0.778829 | 2290 | 190 | 0.3401 | 0.778829 | 4.0991 | 4.0991 | EI60 | no
BB_XX_Wand uit metselwerk, 190 mm:819567 | K10 | 0 | 0 | K10 | BB_XX_Wand uit metselwerk, 190 mm | 2900 | 0.84379 | 2290 | 190 | 0.551 | 1.26179 | 6.641 | 4.441 |  | no
BB_XX_Wand uit metselwerk, 190 mm:819723 | K10 | 0 | 0 | K10 | BB_XX_Wand uit metselwerk, 190 mm | 502.033 | 0.218435 | 2290 | 190 | 0.0953863 | 0.218435 | 1.14966 | 1.14966 | EI60 | no
BB_XX_Wand uit metselwerk, 190 mm:830747 | K10 | 0 | 0 | K10 | BB_XX_Wand uit metselwerk, 190 mm | 885 | 0.410286 | 2440 | 190 | 0.16815 | 0.410286 | 2.1594 | 2.1594 | EI60 | no
BB_XX_Wand uit metselwerk, 190 mm:948531 | K10 | -100 | 0 | K10 | BB_XX_Wand uit metselwerk, 190 mm | 6685 | 1.32096 | 1040 | 190 | 1.27015 | 1.32096 | 6.9524 | 6.9524 |  | no
BB_XX_Wand uit metselwerk, 190 mm:948534 | K10 | -100 | 0 | K10 | BB_XX_Wand uit metselwerk, 190 mm | 4847.5 | 0.957866 | 1040 | 190 | 0.921025 | 0.957866 | 5.0414 | 5.0414 |  | no
BB_XX_Wand uit metselwerk, 190 mm:948537 | K10 | -100 | 0 | K10 | BB_XX_Wand uit metselwerk, 190 mm | 6710 | 1.3259 | 1040 | 190 | 1.2749 | 1.3259 | 6.9784 | 6.9784 |  | no
BB_XX_Wand uit metselwerk, 190 mm:1416991 | K10 | 0 | 0 | K10 | BB_XX_Wand uit metselwerk, 190 mm | 2010 | 0.114322 | 299.35 | 190 | 0.3819 | 0.114322 | 0.601694 | 0.601694 | EI60 | no
BB_XX_Wand uit metselwerk, 190 mm:1417121 | K10 | 1997.67 | 0 | K10 | BB_XX_Wand uit metselwerk, 190 mm | 2010 | 0.11164 | 292.329 | 190 | 0.3819 | 0.11164 | 0.587581 | 0.587581 |  | no
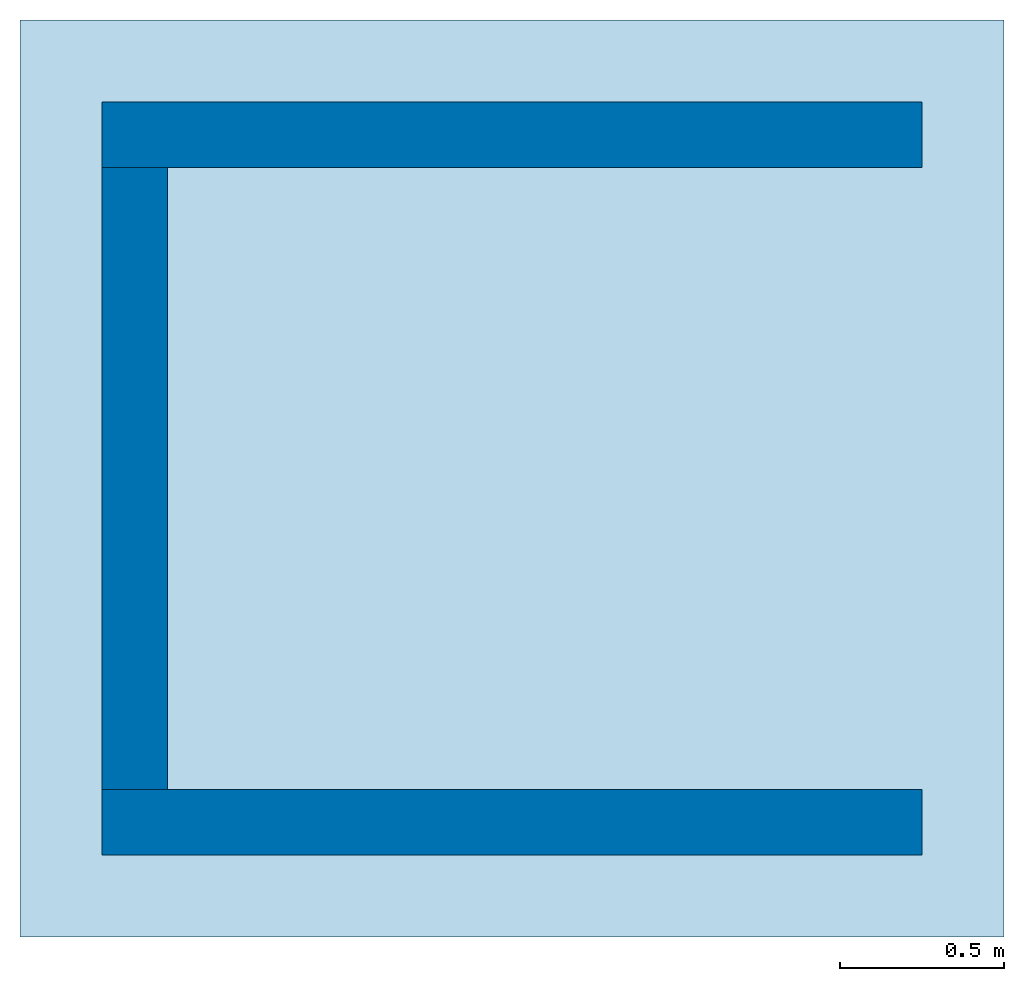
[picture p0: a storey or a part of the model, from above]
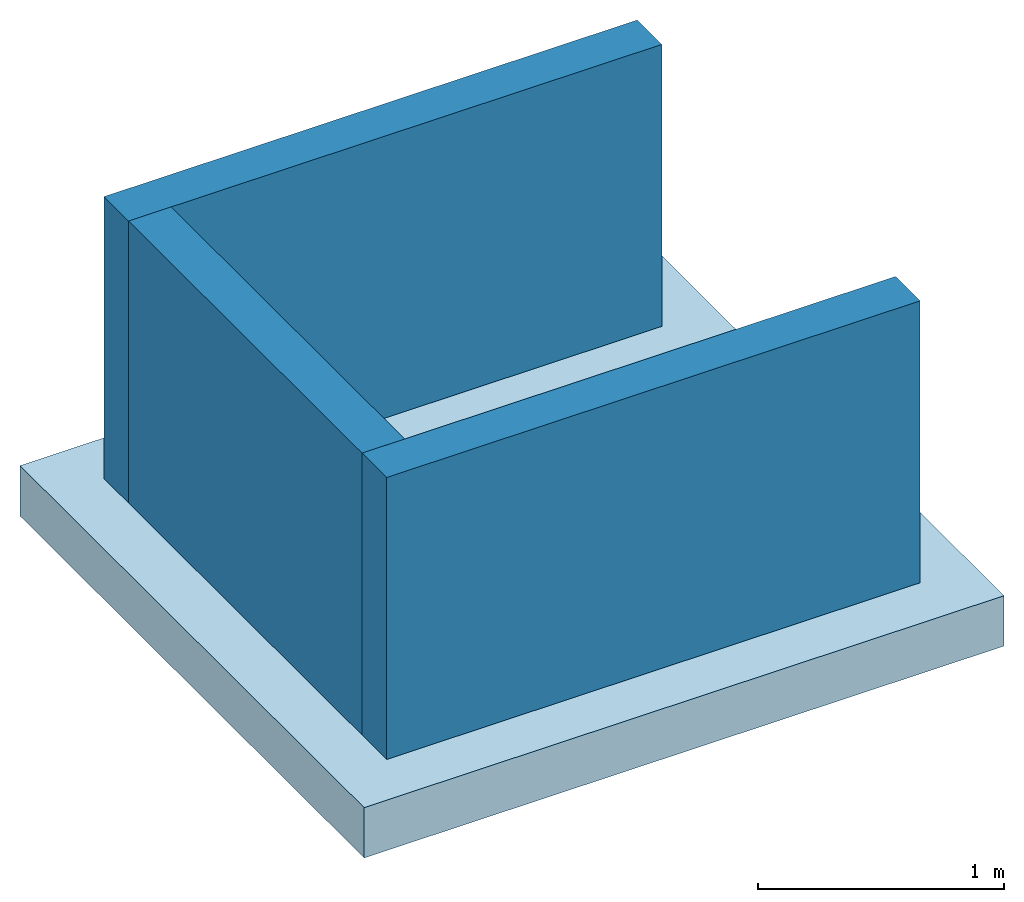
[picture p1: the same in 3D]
Properties of the parts of a building model (IFC4X3_ADD2), part 20 of 28

# IfcWall: BB_Metselwerk_Bestaand 190 (58)
Name (Basic Wall:...) | In | Base Offset | Top Offset | Base Constraint | Name = Pset_EnvironmentalImpactIndicators, Reference = Pset_WallCommon, Reference | Length | NetVolume | Height | Width | GrossFootprintArea | GrossVolume | GrossSideArea | NetSideArea | FireRating | ExtendToStructure | Top Constraint
BB_XX_Wand uit metselwerk, 190 mm:1993135 | K10 | 0 | -50 | K10 | BB_XX_Wand uit metselwerk, 190 mm | 2210 | 1.33948 | 3190 | 190 | 0.4199 | 1.33948 | 7.0499 | 7.0499 | EI60 | no | Up to level: 000
BB_XX_Wand uit metselwerk, 190 mm:2147227 | K10 | 0 | 0 | K10 | BB_XX_Wand uit metselwerk, 190 mm | 490 | 0.213199 | 2290 | 190 | 0.0931 | 0.213199 | 1.1221 | 1.1221 |  | no
BB_XX_Wand uit metselwerk, 190 mm:8712296 | K10 | -200 | 0 | K10 | BB_XX_Wand uit metselwerk, 190 mm | 4700 | 2.59863 | 2910 | 190 | 0.893001 | 2.59863 | 13.677 | 13.677 | EI60 | no
BB_XX_Wand uit metselwerk, 190 mm:490387 | 000 | 840 | -920 | 000 | BB_XX_Wand uit metselwerk, 190 mm | 1661.37 | 0.580815 | 1840 | 190 | 0.31566 | 0.580815 | 3.05692 | 3.05692 |  | no | Up to level: 010
BB_XX_Wand uit metselwerk, 190 mm:492753 | 000 | 840 | -920 | 000 | BB_XX_Wand uit metselwerk, 190 mm | 1515 | 0.529644 | 1840 | 190 | 0.28785 | 0.529644 | 2.7876 | 2.7876 |  | no | Up to level: 010
BB_XX_Wand uit metselwerk, 190 mm:509852 | 000 | -200 | -200 | 000 | BB_XX_Wand uit metselwerk, 190 mm | 899.836 | 0.615488 | 3600 | 190 | 0.170969 | 0.615488 | 3.23941 | 3.23941 | EI60 | no | Up to level: 010
BB_XX_Wand uit metselwerk, 190 mm:647305 | 000 | 2680 | -200 | 000 | BB_XX_Wand uit metselwerk, 190 mm | 1575 | 0.21546 | 720 | 190 | 0.29925 | 0.21546 | 1.134 | 1.134 |  | no | Up to level: 010
BB_XX_Wand uit metselwerk, 190 mm:687765 | 000 | -80 | -280 | 000 | BB_XX_Wand uit metselwerk, 190 mm | 3199.88 | 2.06713 | 3400 | 190 | 0.607978 | 2.06713 | 10.8796 | 10.8796 | EI60 | no | Up to level: 010
BB_XX_Wand uit metselwerk, 190 mm:687766 | 000 | -80 | -280 | 000 | BB_XX_Wand uit metselwerk, 190 mm | 1210 | 0.78166 | 3400 | 190 | 0.2299 | 0.78166 | 4.114 | 4.114 | EI60 | no | Up to level: 010
BB_XX_Wand uit metselwerk, 190 mm:1183957 | 000 | -80 | -280 | 000 | BB_XX_Wand uit metselwerk, 190 mm | 1000 | 0.646 | 3400 | 190 | 0.19 | 0.646 | 3.4 | 3.4 | EI60 | no | Up to level: 010
BB_XX_Wand uit metselwerk, 190 mm:1270147 | 000 | -80 | -280 | 000 | BB_XX_Wand uit metselwerk, 190 mm | 1200 | 0.7752 | 3400 | 190 | 0.228 | 0.7752 | 4.08 | 4.08 | EI60 | no | Up to level: 010
BB_XX_Wand uit metselwerk, 200 mm:1599156 | 000 | -80 | -1050 | 000 | BB_XX_Wand uit metselwerk, 200 mm | 190 | 0.09994 | 2630 | 200 | 0.038 | 0.1052 | 0.526 | 0.526 | EI60 | no | Up to level: 010
BB_XX_Wand uit metselwerk, 190 mm:1599609 | 000 | -50 | -280 | 000 | BB_XX_Wand uit metselwerk, 190 mm | 1145 | 0.733144 | 3370 | 190 | 0.21755 | 0.733144 | 3.85865 | 3.85865 |  | no | Up to level: 010
BB_XX_Wand uit metselwerk, _EI60_43dB, 190 mm:33186695 | 000 | 840 | -920 | 000 | BB_XX_Wand uit metselwerk, _EI60_43dB, 190 mm | 1220 | 0.426512 | 1840 | 190 | 0.2318 | 0.426512 | 2.2448 | 2.2448 | EI60 | no | Up to level: 010
BB_XX_Wand uit metselwerk, 190 mm:645079 | 010 | 840 | -920 | 010 | BB_XX_Wand uit metselwerk, 190 mm | 2725 | 0.95266 | 1840 | 190 | 0.51775 | 0.95266 | 5.014 | 5.014 | EI60 | no | Up to level: 020
BB_XX_Wand uit metselwerk, 190 mm:647214 | 010 | 2680 | -200 | 010 | BB_XX_Wand uit metselwerk, 190 mm | 1575 | 0.21546 | 720 | 190 | 0.29925 | 0.21546 | 1.134 | 1.134 |  | yes | Up to level: 020
BB_XX_Wand uit metselwerk, 190 mm:647443 | 010 | 840 | -920 | 010 | BB_XX_Wand uit metselwerk, 190 mm | 1728.18 | 0.604173 | 1840 | 190 | 0.328355 | 0.604173 | 3.17986 | 3.17986 |  | no | Up to level: 020
BB_XX_Wand uit metselwerk, 190 mm:650920 | 010 | -200 | -200 | 010 | BB_XX_Wand uit metselwerk, 190 mm | 1970.16 | 0.933601 | 3600 | 190 | 0.374331 | 1.34759 | 7.09259 | 4.91369 | EI60 | no | Up to level: 020
BB_XX_Wand uit metselwerk, 190 mm:650922 | 010 | -200 | -200 | 010 | BB_XX_Wand uit metselwerk, 190 mm | 899.836 | 0.615488 | 3600 | 190 | 0.170969 | 0.615488 | 3.23941 | 3.23941 | EI60 | no | Up to level: 020
BB_XX_Wand uit metselwerk, 190 mm:680591 | 010 | -200 | -200 | 010 | BB_XX_Wand uit metselwerk, 190 mm | 1960 | 0.926649 | 3600 | 190 | 0.3724 | 1.34064 | 7.056 | 4.8771 | EI60 | no | Up to level: 020
BB_XX_Wand uit metselwerk, 190 mm:684552 | 010 | -200 | -970 | 010 | BB_XX_Wand uit metselwerk, 190 mm | 1570 | 0.327978 | 2830 | 190 | 0.2983 | 0.844189 | 4.4431 | 1.7262 | EI60 | no | Up to level: 020
BB_XX_Wand uit metselwerk, 190 mm:687447 | 010 | -80 | -280 | 010 | BB_XX_Wand uit metselwerk, 190 mm | 3199.88 | 2.06713 | 3400 | 190 | 0.607978 | 2.06713 | 10.8796 | 10.8796 | EI60 | no | Up to level: 020
BB_XX_Wand uit metselwerk, 190 mm:687526 | 010 | -80 | -280 | 010 | BB_XX_Wand uit metselwerk, 190 mm | 1210 | 0.78166 | 3400 | 190 | 0.2299 | 0.78166 | 4.114 | 4.114 | EI60 | no | Up to level: 020
BB_XX_Wand uit metselwerk, 190 mm:1211740 | 010 | -80 | -280 | 010 | BB_XX_Wand uit metselwerk, 190 mm | 1000 | 0.646 | 3400 | 190 | 0.19 | 0.646 | 3.4 | 3.4 | EI60 | no | Up to level: 020
BB_XX_Wand uit metselwerk, 190 mm:1214424 | 010 | -80 | -280 | 010 | BB_XX_Wand uit metselwerk, 190 mm | 1000 | 0.646 | 3400 | 190 | 0.19 | 0.646 | 3.4 | 3.4 | EI60 | no | Up to level: 020
BB_XX_Wand uit metselwerk, 190 mm:695712 | 020 | 840 | -920 | 020 | BB_XX_Wand uit metselwerk, 190 mm | 2725 | 0.95266 | 1840 | 190 | 0.51775 | 0.95266 | 5.014 | 5.014 | EI60 | no | Up to level: 030
BB_XX_Wand uit metselwerk, 190 mm:695731 | 020 | 2680 | -200 | 020 | BB_XX_Wand uit metselwerk, 190 mm | 1575 | 0.21546 | 720 | 190 | 0.29925 | 0.21546 | 1.134 | 1.134 |  | no | Up to level: 030
BB_XX_Wand uit metselwerk, 190 mm:695836 | 020 | -200 | -200 | 020 | BB_XX_Wand uit metselwerk, 190 mm | 1970.16 | 0.933601 | 3600 | 190 | 0.374331 | 1.34759 | 7.09259 | 4.91369 | EI60 | no | Up to level: 030
BB_XX_Wand uit metselwerk, 190 mm:695838 | 020 | -200 | -200 | 020 | BB_XX_Wand uit metselwerk, 190 mm | 899.836 | 0.615488 | 3600 | 190 | 0.170969 | 0.615488 | 3.23941 | 3.23941 | EI60 | no | Up to level: 030
BB_XX_Wand uit metselwerk, 190 mm:695963 | 020 | -200 | -200 | 020 | BB_XX_Wand uit metselwerk, 190 mm | 1960 | 0.926649 | 3600 | 190 | 0.3724 | 1.34064 | 7.056 | 4.8771 | EI60 | no | Up to level: 030
BB_XX_Wand uit metselwerk, 190 mm:696054 | 020 | -200 | -970 | 020 | BB_XX_Wand uit metselwerk, 190 mm | 1570 | 0.327978 | 2830 | 190 | 0.2983 | 0.844189 | 4.4431 | 1.7262 | EI60 | no | Up to level: 030
BB_XX_Wand uit metselwerk, 190 mm:696106 | 020 | -80 | -280 | 020 | BB_XX_Wand uit metselwerk, 190 mm | 3199.88 | 2.06713 | 3400 | 190 | 0.607978 | 2.06713 | 10.8796 | 10.8796 | EI60 | no | Up to level: 030
BB_XX_Wand uit metselwerk, 190 mm:696107 | 020 | -80 | -280 | 020 | BB_XX_Wand uit metselwerk, 190 mm | 1210 | 0.78166 | 3400 | 190 | 0.2299 | 0.78166 | 4.114 | 4.114 | EI60 | no | Up to level: 030
BB_XX_Wand uit metselwerk, 190 mm:1254633 | 020 | -80 | -280 | 020 | BB_XX_Wand uit metselwerk, 190 mm | 1000 | 0.646 | 3400 | 190 | 0.19 | 0.646 | 3.4 | 3.4 | EI60 | no | Up to level: 030
BB_XX_Wand uit metselwerk, 190 mm:1262023 | 020 | -80 | -280 | 020 | BB_XX_Wand uit metselwerk, 190 mm | 1000 | 0.646 | 3400 | 190 | 0.19 | 0.646 | 3.4 | 3.4 | EI60 | no | Up to level: 030
BB_XX_Wand uit metselwerk, 190 mm:1703857 | 020 | 840 | -920 | 020 | BB_XX_Wand uit metselwerk, 190 mm | 1519.51 | 0.520198 | 1840 | 190 | 0.282716 | 0.531222 | 2.7959 | 2.7959 |  | no | Up to level: 030
BB_XX_Wand uit metselwerk, 190 mm:705307 | 030 | -200 | 3140 | 030 | BB_XX_Wand uit metselwerk, 190 mm | 1970.16 | 0.836275 | 3340 | 190 | 0.374331 | 1.25027 | 6.58035 | 4.40145 | EI60 | no | Up to level: 030
BB_XX_Wand uit metselwerk, 190 mm:705309 | 030 | -200 | 3200 | 030 | BB_XX_Wand uit metselwerk, 190 mm | 899.836 | 0.581294 | 3400 | 190 | 0.170969 | 0.581294 | 3.05944 | 3.05944 | EI60 | no | Up to level: 030
BB_XX_Wand uit metselwerk, 190 mm:705355 | 030 | -200 | 3140 | 030 | BB_XX_Wand uit metselwerk, 190 mm | 1960 | 0.829825 | 3340 | 190 | 0.3724 | 1.24382 | 6.5464 | 4.3675 | EI60 | no | Up to level: 030
BB_XX_Wand uit metselwerk, 190 mm:705365 | 030 | -80 | 3200 | 030 | BB_XX_Wand uit metselwerk, 190 mm | 3199.88 | 1.99417 | 3280 | 190 | 0.607978 | 1.99417 | 10.4956 | 10.4956 | EI60 | no | Up to level: 030
BB_XX_Wand uit metselwerk, 190 mm:705366 | 030 | -80 | 3200 | 030 | BB_XX_Wand uit metselwerk, 190 mm | 1210 | 0.754072 | 3280 | 190 | 0.2299 | 0.754072 | 3.9688 | 3.9688 |  | no | Up to level: 030
BB_XX_Wand uit metselwerk, 190 mm:753172 | 030 | -80 | 3190 | 030 | BB_XX_Wand uit metselwerk, 190 mm | 1190 | 0.739347 | 3270 | 190 | 0.2261 | 0.739347 | 3.8913 | 3.8913 | EI60 | no | Up to level: 030
BB_XX_Wand uit metselwerk, 190 mm:753654 | 030 | -80 | 3190 | 030 | BB_XX_Wand uit metselwerk, 190 mm | 1000 | 0.6213 | 3270 | 190 | 0.19 | 0.6213 | 3.27 | 3.27 | EI60 | no | Up to level: 030
BB_XX_Wand uit metselwerk, 190 mm:761779 | 030 | -80 | 2990 | 030 | BB_XX_Wand uit metselwerk, 190 mm | 2200 | 1.28326 | 3070 | 190 | 0.418 | 1.28326 | 6.754 | 6.754 | EI60 | no | Up to level: 030
BB_XX_Wand uit metselwerk, 190 mm:761997 | 030 | -80 | 3190 | 030 | BB_XX_Wand uit metselwerk, 190 mm | 1010 | 0.627513 | 3270 | 190 | 0.1919 | 0.627513 | 3.3027 | 3.3027 | EI60 | no | Up to level: 030
BB_XX_Wand uit metselwerk, 190 mm:762316 | 030 | -80 | 0 | 030 | BB_XX_Wand uit metselwerk, 190 mm | 4110 | 2.55355 | 3270 | 190 | 0.780901 | 2.55355 | 13.4397 | 13.4397 | EI60 | no
BB_XX_Wand uit metselwerk, 190 mm:2125099 | 030 | -80 | 3190 | 030 | BB_XX_Wand uit metselwerk, 190 mm | 2908.96 | 1.80734 | 3270 | 190 | 0.552702 | 1.80734 | 9.5123 | 9.5123 | EI60 | no | Up to level: 030

# IfcWall: BB_Metselwerk_Bestaand 200 (9)
Type - Material: BB_Metselwerk_Bestaand
PredefinedType: SOLIDWALL
Cpset_Wall - LevelOfAccuracy: in te vullen door Buildwise
IfcClassificationReference - GVH_artnr 01: geen waarde gevonden; GVH_artnr 02: geen waarde gevonden; GVH_artnr 03: geen waarde gevonden; GVH_artnr 04: geen waarde gevonden; GVH_artnr 05: geen waarde gevonden; GVH_artnr 06: geen waarde gevonden
IfcRoot - Name: BB_XX_Wand uit metselwerk, 200 mm
Qto_WallBaseQuantities - Width: 200
Pset_Condition - AssessmentCondition: Empty
Pset_EnvironmentalImpactIndicators - Reference: BB_XX_Wand uit metselwerk, 200 mm; sets with these values: 2
Pset_WallCommon - Reference: BB_XX_Wand uit metselwerk, 200 mm; IsExternal: yes; LoadBearing: no; ExtendToStructure: no
Name (Basic Wall:BB_XX_Wand uit metselwerk, 200 mm:...) | In | Base Offset | Top Offset | Base Constraint | Length | NetVolume = GrossVolume | Height | GrossFootprintArea | GrossSideArea = NetSideArea
830372 | K10 | 0 | 0 | K10 | 1015 | 0.53592 | 2640 | 0.203 | 2.6796
1408981 | K10 | 2150 | 2540 | K10 | 1920 | 0.14976 | 390 | 0.384 | 0.7488 | IfcBuildingStorey - Top Constraint: Up to level: K10
1268313 | 000 | 2160 | 0 | 000 | 910 | 0.07826 | 430 | 0.182 | 0.3913
1268929 | 010 | -80 | 0 | 010 | 910 | 0.48594 | 2670 | 0.182 | 2.4297
26481513 | 010 | 2160 | -1050 | 010 | 910 | 0.07098 | 390 | 0.182 | 0.3549 | IfcBuildingStorey - Top Constraint: Up to level: 020
1260540 | 020 | 2070 | 0 | 020 | 920 | 0.09568 | 520 | 0.184 | 0.4784
26481515 | 020 | 2160 | -1050 | 020 | 910 | 0.07098 | 390 | 0.182 | 0.3549 | IfcBuildingStorey - Top Constraint: Up to level: 030
752950 | 030 | -80 | 2990 | 030 | 2390 | 1.46746 | 3070 | 0.478 | 7.3373 | IfcBuildingStorey - Top Constraint: Up to level: 030; Pset_WallCommon - FireRating: EI60
1280184 | 030 | 2070 | 0 | 030 | 910 | 0.194194 | 1067 | 0.182 | 0.97097

# IfcWall: BB_Metselwerk_Bestaand 90 (18)
Type - Material: BB_Metselwerk_Bestaand
PredefinedType: SOLIDWALL
Cpset_Wall - LevelOfAccuracy: in te vullen door Buildwise
IfcBuildingStorey - Base Offset: -80
IfcClassificationReference - GVH_artnr 01: geen waarde gevonden; GVH_artnr 02: geen waarde gevonden; GVH_artnr 03: geen waarde gevonden; GVH_artnr 04: geen waarde gevonden; GVH_artnr 05: geen waarde gevonden; GVH_artnr 06: geen waarde gevonden
IfcRoot - Name: BB_XX_Wand uit metselwerk, 90 mm
Qto_WallBaseQuantities - Width: 90
Pset_Condition - AssessmentCondition: Empty
Pset_EnvironmentalImpactIndicators - Reference: BB_XX_Wand uit metselwerk, 90 mm; sets with these values: 2
Pset_WallCommon - Reference: BB_XX_Wand uit metselwerk, 90 mm; IsExternal: yes; LoadBearing: no; ExtendToStructure: no
Name (Basic Wall:BB_XX_Wand uit metselwerk, 90 mm:...) | In | Top Offset | Base Constraint | Top Constraint | Length | NetVolume = GrossVolume | Height | GrossFootprintArea | GrossSideArea = NetSideArea
1196435 | 000 | -280 | 000 | Up to level: 010 | 1400 | 0.4284 | 3400 | 0.126 | 4.76
1196998 | 000 | -280 | 000 | Up to level: 010 | 1310 | 0.40086 | 3400 | 0.1179 | 4.454
1197307 | 000 | -280 | 000 | Up to level: 010 | 610 | 0.18666 | 3400 | 0.0549 | 2.074
23681805 | 000 | -280 | 000 | Up to level: 010 | 220 | 0.06732 | 3400 | 0.0198 | 0.748
1205195 | 010 | -280 | 010 | Up to level: 020 | 1400 | 0.4284 | 3400 | 0.126 | 4.76
1206035 | 010 | -280 | 010 | Up to level: 020 | 1310 | 0.40086 | 3400 | 0.1179 | 4.454
1206228 | 010 | -280 | 010 | Up to level: 020 | 610 | 0.18666 | 3400 | 0.0549 | 2.074
1214949 | 010 | -280 | 010 | Up to level: 020 | 220 | 0.06732 | 3400 | 0.0198 | 0.748
1254525 | 020 | -280 | 020 | Up to level: 030 | 220 | 0.06732 | 3400 | 0.0198 | 0.748
1255004 | 020 | -280 | 020 | Up to level: 030 | 1400 | 0.4284 | 3400 | 0.126 | 4.76
1255008 | 020 | -280 | 020 | Up to level: 030 | 1310 | 0.40086 | 3400 | 0.1179 | 4.454
1255009 | 020 | -280 | 020 | Up to level: 030 | 610 | 0.18666 | 3400 | 0.0549 | 2.074 | Pset_WallCommon - FireRating: EI60
25793566 | 020 | -280 | 020 | Up to level: 030 | 220 | 0.06732 | 3400 | 0.0198 | 0.748
1273419 | 030 | 0 | 030 |  | 1000 | 0.2943 | 3270 | 0.09 | 3.27
1275142 | 030 | 3190 | 030 | Up to level: 030 | 1010 | 0.297243 | 3270 | 0.0909 | 3.3027
1276971 | 030 | 0 | 030 |  | 610 | 0.180072 | 3280 | 0.0549 | 2.0008
1277303 | 030 | 3200 | 030 | Up to level: 030 | 1400 | 0.41328 | 3280 | 0.126 | 4.592
1277724 | 030 | 3200 | 030 | Up to level: 030 | 1310 | 0.386712 | 3280 | 0.1179 | 4.2968

# IfcWall: BB_Metselwerk_Betonsteen 0 (9)
Type - Material: BB_Metselwerk_Betonsteen
PredefinedType: SOLIDWALL
Qto_WallBaseQuantities - Width: 190
Pset_EnvironmentalImpactIndicators - sets with these values: 2
Pset_WallCommon - IsExternal: yes; ExtendToStructure: no
Name (Basic Wall:...) | In | LevelOfAccuracy | Base Offset | Top Offset | Base Constraint | Top Constraint | Keynote | TDS_link | BB_Element_Lokaalnummer01 | Name = Pset_EnvironmentalImpactIndicators, Reference = Pset_WallCommon, Reference | Length | NetVolume | Height | GrossFootprintArea | GrossVolume | GrossSideArea = NetSideArea | AssessmentCondition | ThermalTransmittance | LoadBearing
BB_03.09.24#05_Wand uit metselwerk_EI60, 190 mm:19983974 | K20 | in te vullen door Buildwise | 1000 | 1600 | K20 | Up to level: K20 | 03.09.24#05 | .\05 As Builtdossier\2. Bouwkunde\2.1 Architectuur\2.1.3 open ruwbouw\TF S 4.2.1.1.1 A-volle betonstenen.pdf | K.-2.305 | BB_03.09.24#05_Wand uit metselwerk_EI60, 190 mm | 356.231 | 0.0297803 | 600 | 0.0496339 | 0.0406103 | 0.213739 | Empty | 6.26316 | no | IfcClassificationReference - GVH_artnr 01: 03.09.24#05; GVH_artnr 02: geen waarde gevonden; GVH_artnr 03: geen waarde gevonden; GVH_artnr 04: geen waarde gevonden; GVH_artnr 05: geen waarde gevonden; GVH_artnr 06: geen waarde gevonden; Pset_WallCommon - FireRating: EI60
BB_03.09.24#05_Wand uit metselwerk_EI60, 190 mm:19986978 | K10 | in te vullen door Buildwise | 0 | 2290 | K10 | Up to level: K10 | 03.09.24#05 | .\05 As Builtdossier\2. Bouwkunde\2.1 Architectuur\2.1.3 open ruwbouw\TF S 4.2.1.1.1 A-volle betonstenen.pdf | K.-1.310 | BB_03.09.24#05_Wand uit metselwerk_EI60, 190 mm | 356.231 | 0.113662 | 2290 | 0.0496339 | 0.154996 | 0.815769 | Empty | 6.26316 | no | IfcClassificationReference - GVH_artnr 01: 03.09.24#05; GVH_artnr 02: geen waarde gevonden; GVH_artnr 03: geen waarde gevonden; GVH_artnr 04: geen waarde gevonden; GVH_artnr 05: geen waarde gevonden; GVH_artnr 06: geen waarde gevonden; Pset_WallCommon - FireRating: EI60
BB_03.09.24#05_Wand uit metselwerk_EI60, 190 mm:34143036 | 000 | in te vullen door Buildwise | -200 | 2800 | 000 | Up to level: 000 | 03.09.24#05 | .\05 As Builtdossier\2. Bouwkunde\2.1 Architectuur\2.1.3 open ruwbouw\TF S 4.2.1.1.1 A-volle betonstenen.pdf | K.00.A1 | BB_03.09.24#05_Wand uit metselwerk_EI60, 190 mm | 389.697 | 0.167977 | 3000 | 0.0559924 | 0.222127 | 1.16909 | Empty | 6.26316 | no
BB_03.09.24#05_Wand uit metselwerk_EI60, 190 mm:34143711 | 010 | in te vullen door Buildwise | -200 | 2400 | 010 | Up to level: 010 | 03.09.24#05 | .\05 As Builtdossier\2. Bouwkunde\2.1 Architectuur\2.1.3 open ruwbouw\TF S 4.2.1.1.1 A-volle betonstenen.pdf | K.00.A1 | BB_03.09.24#05_Wand uit metselwerk_EI60, 190 mm | 389.697 | 0.14558 | 2600 | 0.0559924 | 0.19251 | 1.01321 | Empty | 6.26316 | no
BB_03.09.24#05_Wand uit metselwerk_EI60, 190 mm:34143813 | 020 | in te vullen door Buildwise | -200 | 3000 | 020 | Up to level: 020 | 03.09.24#05 | .\05 As Builtdossier\2. Bouwkunde\2.1 Architectuur\2.1.3 open ruwbouw\TF S 4.2.1.1.1 A-volle betonstenen.pdf | K.00.A1 | BB_03.09.24#05_Wand uit metselwerk_EI60, 190 mm | 389.697 | 0.179176 | 3200 | 0.0559924 | 0.236936 | 1.24703 | Empty | 6.26316 | no
BB_03.09.24#05_Wand uit metselwerk_EI60, 190 mm:34146273 | 020 | in te vullen door Buildwise | -200 | 3000 | 020 | Up to level: 020 | 03.09.24#05 | .\05 As Builtdossier\2. Bouwkunde\2.1 Architectuur\2.1.3 open ruwbouw\TF S 4.2.1.1.1 A-volle betonstenen.pdf | K.00.A1 | BB_03.09.24#05_Wand uit metselwerk_EI60, 190 mm | 379.693 | 0.173093 | 3200 | 0.0540917 | 0.230853 | 1.21502 | Empty | 6.26316 | no
BB_03.09.24#05_Wand uit metselwerk_EI60, 190 mm:34145508 | 030 | in te vullen door Buildwise | -200 | 3000 | 030 | Up to level: 030 | 03.09.24#05 | .\05 As Builtdossier\2. Bouwkunde\2.1 Architectuur\2.1.3 open ruwbouw\TF S 4.2.1.1.1 A-volle betonstenen.pdf | K.00.A1 | BB_03.09.24#05_Wand uit metselwerk_EI60, 190 mm | 389.697 | 0.179176 | 3200 | 0.0559924 | 0.236936 | 1.24703 | Empty | 6.26316 | no
BB_03.09.24#05_Wand uit metselwerk_EI60, 190 mm:34147622 | 030 | in te vullen door Buildwise | -200 | 3000 | 030 | Up to level: 030 | 03.09.24#05 | .\05 As Builtdossier\2. Bouwkunde\2.1 Architectuur\2.1.3 open ruwbouw\TF S 4.2.1.1.1 A-volle betonstenen.pdf | K.00.A1 | BB_03.09.24#05_Wand uit metselwerk_EI60, 190 mm | 379.693 | 0.173093 | 3200 | 0.0540917 | 0.230853 | 1.21502 | Empty | 6.26316 | no | Pset_WallCommon - FireRating: EI60
BB_03.09.24#03_Wand uit metselwerk, 190 mm:34215181 | 040 |  |  |  |  |  | 03.09.24#03 |  |  | BB_03.09.24#03_Wand uit metselwerk, 190 mm | 95 | 0.00518937 | 1150 | 0.01805 | 0.0293555 | 0.154503 |  |  | yes

# IfcWall: BB_Metselwerk_Betonsteen 140 (58)
Type - Material: BB_Metselwerk_Betonsteen
PredefinedType: SOLIDWALL
Cpset_Wall - LevelOfAccuracy: in te vullen door Buildwise
IfcClassificationReference - TDS_link: .\05 As Builtdossier\2. Bouwkunde\2.1 Architectuur\2.1.3 open ruwbouw\TF S 4.2.1.1.1 A-volle betonstenen.pdf
Qto_WallBaseQuantities - Width: 140
Pset_Condition - AssessmentCondition: Empty
Pset_EnvironmentalImpactIndicators - sets with these values: 2
Pset_WallCommon - ThermalTransmittance: 8.5; IsExternal: yes; ExtendToStructure: no
Name (Basic Wall:...) | In | Base Offset | Top Offset | Base Constraint | Top Constraint | Keynote | GVH_artnr 01 | GVH_artnr 02 = GVH_artnr 03 = GVH_artnr 04 = GVH_artnr 05 = GVH_artnr 06 | BB_Element_Lokaalnummer01 | Name = Pset_EnvironmentalImpactIndicators, Reference = Pset_WallCommon, Reference | Length | NetVolume | Height | GrossFootprintArea | GrossVolume | GrossSideArea | NetSideArea | LoadBearing
BB_03.09.24#01_Wand uit metselwerk, 140 mm:29706405 | K10 | 100 | 2780 | K10 | Up to level: K10 | 03.09.24#01 | 03.09.24#01 | geen waarde gevonden | K.-1.103 | BB_03.09.24#01_Wand uit metselwerk, 140 mm | 3010 | 1.05806 | 2680 | 0.4214 | 1.05806 | 7.5576 | 7.5576 | no
BB_03.09.24#02_Wand uit metselwerk_EI60_43dB, 140 mm:32819575 | K10 | 0 | -280 | K10 | Up to level: 000 | 03.09.24#02 | 03.09.24#02 | geen waarde gevonden |  | BB_03.09.24#02_Wand uit metselwerk_EI60_43dB, 140 mm | 2000 | 0.8288 | 2960 | 0.28 | 0.8288 | 5.92 | 5.92 | no
BB_03.09.24#02_Wand uit metselwerk_EI60_43dB, 140 mm:32819945 | K10 | 0 | -280 | K10 | Up to level: 000 | 03.09.24#02 | 03.09.24#02 | geen waarde gevonden |  | BB_03.09.24#02_Wand uit metselwerk_EI60_43dB, 140 mm | 1090 | 0.451696 | 2960 | 0.1526 | 0.451696 | 3.2264 | 3.2264 | no
BB_03.09.24#02_Wand uit metselwerk_EI60_43dB, 140 mm:32819967 | K10 | 0 | -280 | K10 | Up to level: 000 | 03.09.24#02 | 03.09.24#02 | geen waarde gevonden |  | BB_03.09.24#02_Wand uit metselwerk_EI60_43dB, 140 mm | 550 | 0.22792 | 2960 | 0.077 | 0.22792 | 1.628 | 1.628 | no
BB_03.09.24#02_Wand uit metselwerk_EI60_43dB, 140 mm:32819989 | K10 | 0 | -280 | K10 | Up to level: 000 | 03.09.24#02 | 03.09.24#02 | geen waarde gevonden |  | BB_03.09.24#02_Wand uit metselwerk_EI60_43dB, 140 mm | 950 | 0.39368 | 2960 | 0.133 | 0.39368 | 2.812 | 2.812 | no
BB_03.09.24#02_Wand uit metselwerk_EI60_43dB, 140 mm:32820617 | K10 | 0 | -280 | K10 | Up to level: 000 | 03.09.24#02 | 03.09.24#02 | geen waarde gevonden |  | BB_03.09.24#02_Wand uit metselwerk_EI60_43dB, 140 mm | 1090 | 0.451696 | 2960 | 0.1526 | 0.451696 | 3.2264 | 3.2264 | no
BB_03.09.24#02_Wand uit metselwerk_EI60_43dB, 140 mm:32820618 | K10 | 0 | -280 | K10 | Up to level: 000 | 03.09.24#02 | 03.09.24#02 | geen waarde gevonden |  | BB_03.09.24#02_Wand uit metselwerk_EI60_43dB, 140 mm | 550 | 0.22792 | 2960 | 0.077 | 0.22792 | 1.628 | 1.628 | no
BB_03.09.24#02_Wand uit metselwerk_EI60_43dB, 140 mm:32820619 | K10 | 0 | -280 | K10 | Up to level: 000 | 03.09.24#02 | 03.09.24#02 | geen waarde gevonden |  | BB_03.09.24#02_Wand uit metselwerk_EI60_43dB, 140 mm | 950 | 0.39368 | 2960 | 0.133 | 0.39368 | 2.812 | 2.812 | no
BB_03.09.24#02_Wand uit metselwerk_EI60_43dB, 140 mm:32820620 | K10 | 0 | -280 | K10 | Up to level: 000 | 03.09.24#02 | 03.09.24#02 | geen waarde gevonden |  | BB_03.09.24#02_Wand uit metselwerk_EI60_43dB, 140 mm | 2140 | 0.886816 | 2960 | 0.2996 | 0.886816 | 6.3344 | 6.3344 | no
BB_03.09.24#02_Wand uit metselwerk_EI60_43dB, 140 mm:32820622 | K10 | 0 | -680 | K10 | Up to level: 000 | 03.09.24#02 | 03.09.24#02 | geen waarde gevonden |  | BB_03.09.24#02_Wand uit metselwerk_EI60_43dB, 140 mm | 2000 | 0.7168 | 2560 | 0.28 | 0.7168 | 5.12 | 5.12 | no
BB_03.09.24#02_Wand uit metselwerk_EI60_43dB, 140 mm:32821204 | K10 | 0 | -700 | K10 | Up to level: 000 | 03.09.24#02 | 03.09.24#02 | geen waarde gevonden |  | BB_03.09.24#02_Wand uit metselwerk_EI60_43dB, 140 mm | 3000 | 1.0668 | 2540 | 0.42 | 1.0668 | 7.62 | 7.62 | no | Pset_WallCommon - FireRating: EI60
BB_03.09.24#02_Wand uit metselwerk_EI60_43dB, 140 mm:13040487 | 000 | -400 | -350 | 000 | Up to level: 010 | 03.09.24#02 | 03.09.24#02 | geen waarde gevonden | K.00.K41 | BB_03.09.24#02_Wand uit metselwerk_EI60_43dB, 140 mm | 2110.03 | 0.839328 | 3650 | 0.295404 | 1.07822 | 7.7016 | 5.9952 | no | Pset_WallCommon - FireRating: EI60
BB_03.09.24#02_Wand uit metselwerk_EI60_43dB, 140 mm:13040488 | 000 | -400 | 0 | 000 | Up to level: 010 | 03.09.24#02 | 03.09.24#02 | geen waarde gevonden | K.00.K44 | BB_03.09.24#02_Wand uit metselwerk_EI60_43dB, 140 mm | 2110.03 | 0.942719 | 4000 | 0.295404 | 1.18161 | 8.44011 | 6.73371 | no | Pset_WallCommon - FireRating: EI60
BB_03.09.24#02_Wand uit metselwerk_EI60_43dB, 140 mm:13044240 | 000 | 840 | -920 | 000 | Up to level: 010 | 03.09.24#02 | 03.09.24#02 | geen waarde gevonden | K.00.K41 | BB_03.09.24#02_Wand uit metselwerk_EI60_43dB, 140 mm | 990 | 0.255024 | 1840 | 0.1386 | 0.255024 | 1.8216 | 1.8216 | no | Pset_WallCommon - FireRating: EI60
BB_03.09.24#01_Wand uit metselwerk, 140 mm:13046954 | 000 | -200 | -460 | 000 | Up to level: 010 | 03.09.24#01 | 03.09.24#01 | geen waarde gevonden | K.00.507 | BB_03.09.24#01_Wand uit metselwerk, 140 mm | 3630 | 1.42763 | 3340 | 0.5082 | 1.69739 | 12.1242 | 10.1973 | no
BB_03.09.24#01_Wand uit metselwerk, 140 mm:13047017 | 000 | -200 | -460 | 000 | Up to level: 010 | 03.09.24#01 | 03.09.24#01 | geen waarde gevonden | K.00.510 | BB_03.09.24#01_Wand uit metselwerk, 140 mm | 4505 | 2.10654 | 3340 | 0.6307 | 2.10654 | 15.0467 | 15.0467 | no
BB_03.09.24#01_Wand uit metselwerk, 140 mm:13047072 | 000 | -200 | -460 | 000 | Up to level: 010 | 03.09.24#01 | 03.09.24#01 | geen waarde gevonden | K.00.510 | BB_03.09.24#01_Wand uit metselwerk, 140 mm | 2660 | 0.722484 | 3340 | 0.3724 | 1.24382 | 8.8844 | 5.1606 | no
BB_03.09.24#02_Wand uit metselwerk_EI60_43dB, 140 mm:13047105 | 000 | -200 | -460 | 000 | Up to level: 010 | 03.09.24#02 | 03.09.24#02 | geen waarde gevonden | K.00.507 | BB_03.09.24#02_Wand uit metselwerk_EI60_43dB, 140 mm | 2905 | 1.35838 | 3340 | 0.4067 | 1.35838 | 9.7027 | 9.7027 | no
BB_03.09.24#01_Wand uit metselwerk, 140 mm:13047835 | 000 | -200 | -460 | 000 | Up to level: 010 | 03.09.24#01 | 03.09.24#01 | geen waarde gevonden | K.00.109 | BB_03.09.24#01_Wand uit metselwerk, 140 mm | 4365 | 2.04107 | 3340 | 0.6111 | 2.04107 | 14.5791 | 14.5791 | no
BB_03.09.24#01_Wand uit metselwerk, 140 mm:13047891 | 000 | -200 | -460 | 000 | Up to level: 010 | 03.09.24#01 | 03.09.24#01 | geen waarde gevonden | K.00.109 | BB_03.09.24#01_Wand uit metselwerk, 140 mm | 5510 | 1.78539 | 3340 | 0.771401 | 2.57648 | 18.4034 | 12.7528 | no
BB_03.09.24#01_Wand uit metselwerk, 140 mm:13048289 | 000 | -200 | -460 | 000 | Up to level: 010 | 03.09.24#01 | 03.09.24#01 | geen waarde gevonden | K.00.109 | BB_03.09.24#01_Wand uit metselwerk, 140 mm | 4365 | 2.04107 | 3340 | 0.6111 | 2.04107 | 14.5791 | 14.5791 | no
BB_03.09.24#01_Wand uit metselwerk, 140 mm:13049408 | 000 | -200 | -460 | 000 | Up to level: 010 | 03.09.24#01 | 03.09.24#01 | geen waarde gevonden | K.00.S13 | BB_03.09.24#01_Wand uit metselwerk, 140 mm | 4505.03 | 2.10655 | 3340 | 0.630704 | 2.10655 | 15.0468 | 15.0468 | no | Pset_WallCommon - FireRating: EI60
BB_03.09.24#01_Wand uit metselwerk, 140 mm:13050515 | 000 | -200 | -460 | 000 | Up to level: 010 | 03.09.24#01 | 03.09.24#01 | geen waarde gevonden | K.00.S13 | BB_03.09.24#01_Wand uit metselwerk, 140 mm | 2250.03 | 1.05211 | 3340 | 0.315004 | 1.05211 | 7.5151 | 7.5151 | no
BB_03.09.24#01_Wand uit metselwerk, 140 mm:13056984 | 000 | -200 | -460 | 000 | Up to level: 010 | 03.09.24#01 | 03.09.24#01 | geen waarde gevonden | K.00.506 | BB_03.09.24#01_Wand uit metselwerk, 140 mm | 1600 | 0.478401 | 3340 | 0.224 | 0.74816 | 5.344 | 3.41715 | no
BB_03.09.24#01_Wand uit metselwerk, 140 mm:13057070 | 000 | -200 | -460 | 000 | Up to level: 010 | 03.09.24#01 | 03.09.24#01 | geen waarde gevonden | K.00.506 | BB_03.09.24#01_Wand uit metselwerk, 140 mm | 1600 | 0.478401 | 3340 | 0.224 | 0.74816 | 5.344 | 3.41715 | no
BB_03.09.24#01_Wand uit metselwerk, 140 mm:16202047 | 000 | -200 | -460 | 000 | Up to level: 010 | 03.09.24#01 | 03.09.24#01 | geen waarde gevonden | K.00.510 | BB_03.09.24#01_Wand uit metselwerk, 140 mm | 4365 | 2.04107 | 3340 | 0.6111 | 2.04107 | 14.5791 | 14.5791 | no
BB_03.09.24#01_Wand uit metselwerk, 140 mm:16202172 | 000 | -200 | -460 | 000 | Up to level: 010 | 03.09.24#01 | 03.09.24#01 | geen waarde gevonden | K.00.508 | BB_03.09.24#01_Wand uit metselwerk, 140 mm | 2905 | 1.08862 | 3340 | 0.4067 | 1.35838 | 9.7027 | 7.77585 | no
BB_03.09.24#01_Wand uit metselwerk, 140 mm:16202297 | 000 | -200 | -460 | 000 | Up to level: 010 | 03.09.24#01 | 03.09.24#01 | geen waarde gevonden | K.00.507 | BB_03.09.24#01_Wand uit metselwerk, 140 mm | 3630 | 1.69739 | 3340 | 0.5082 | 1.69739 | 12.1242 | 12.1242 | no
BB_03.09.24#02_Wand uit metselwerk_EI60_43dB, 140 mm:16290529 | 000 | -200 | -3605 | 000 | Up to level: 010 | 03.09.24#02 | 03.09.24#02 | geen waarde gevonden | K.00.502 | BB_03.09.24#02_Wand uit metselwerk_EI60_43dB, 140 mm | 2400 | 0.06552 | 195 | 0.336 | 0.06552 | 0.468 | 0.468 | no
BB_03.09.24#02_Wand uit metselwerk_EI60_43dB, 140 mm:25514762 | 000 | -200 | -460 | 000 | Up to level: 010 | 03.09.24#02 | 03.09.24#02 | geen waarde gevonden | K.00.G16 | BB_03.09.24#02_Wand uit metselwerk_EI60_43dB, 140 mm | 1760.03 | 0.584094 | 3340 | 0.246404 | 0.82299 | 5.8785 | 4.1721 | no | Pset_WallCommon - FireRating: EI60
BB_03.09.24#02_Wand uit metselwerk_EI60_43dB, 140 mm:12998183 | 010 | -80 | 3310 | 010 | Up to level: 010 | 03.09.24#02 | 03.09.24#02 | geen waarde gevonden | K.10.G15 | BB_03.09.24#02_Wand uit metselwerk_EI60_43dB, 140 mm | 2089.95 | 0.95867 | 3390 | 0.282794 | 0.991892 | 7.08494 | 7.08494 | no | Pset_WallCommon - FireRating: EI60
BB_03.09.24#02_Wand uit metselwerk_EI60_43dB, 140 mm:12998184 | 010 | -80 | 3310 | 010 | Up to level: 010 | 03.09.24#02 | 03.09.24#02 | geen waarde gevonden | K.10.G15 | BB_03.09.24#02_Wand uit metselwerk_EI60_43dB, 140 mm | 2904.39 | 1.3452 | 3390 | 0.396814 | 1.37842 | 9.84588 | 9.84588 | no | Pset_WallCommon - FireRating: EI60
BB_03.09.24#02_Wand uit metselwerk_EI60_43dB, 140 mm:12998185 | 010 | -80 | 3310 | 010 | Up to level: 010 | 03.09.24#02 | 03.09.24#02 | geen waarde gevonden | K.10.G16 | BB_03.09.24#02_Wand uit metselwerk_EI60_43dB, 140 mm | 2089.95 | 0.95867 | 3390 | 0.282794 | 0.991892 | 7.08494 | 7.08494 | no | Pset_WallCommon - FireRating: EI60
BB_03.09.24#02_Wand uit metselwerk_EI60_43dB, 140 mm:13000283 | 010 | -200 | -350 | 010 | Up to level: 020 | 03.09.24#02 | 03.09.24#02 | geen waarde gevonden | K.10.K41 | BB_03.09.24#02_Wand uit metselwerk_EI60_43dB, 140 mm | 2110.03 | 0.780247 | 3450 | 0.295404 | 1.01914 | 7.27959 | 5.57319 | no | Pset_WallCommon - FireRating: EI60
BB_03.09.24#02_Wand uit metselwerk_EI60_43dB, 140 mm:16236072 | 010 | -200 | -10 | 010 | Up to level: 010 | 03.09.24#02 | 03.09.24#02 | geen waarde gevonden | K.10.101 | BB_03.09.24#02_Wand uit metselwerk_EI60_43dB, 140 mm | 1585.13 | 0.0421645 | 190 | 0.221918 | 0.0421645 | 0.301175 | 0.301175 | no
BB_03.09.24#02_Wand uit metselwerk_EI60_43dB, 140 mm:16291956 | 010 | -200 | -10 | 010 | Up to level: 010 | 03.09.24#02 | 03.09.24#02 | geen waarde gevonden | K.10.502 | BB_03.09.24#02_Wand uit metselwerk_EI60_43dB, 140 mm | 1600 | 0.04256 | 190 | 0.224 | 0.04256 | 0.304 | 0.304 | no
BB_03.09.24#02_Wand uit metselwerk_EI60_43dB, 140 mm:16292051 | 010 | -200 | -10 | 010 | Up to level: 010 | 03.09.24#02 | 03.09.24#02 | geen waarde gevonden | K.10.502 | BB_03.09.24#02_Wand uit metselwerk_EI60_43dB, 140 mm | 1600 | 0.04256 | 190 | 0.224 | 0.04256 | 0.304 | 0.304 | no
BB_03.09.24#02_Wand uit metselwerk_EI60_43dB, 140 mm:25576158 | 010 | -200 | -10 | 010 | Up to level: 010 | 03.09.24#02 | 03.09.24#02 | geen waarde gevonden | K.10.101 | BB_03.09.24#02_Wand uit metselwerk_EI60_43dB, 140 mm | 1585.13 | 0.0421645 | 190 | 0.221918 | 0.0421645 | 0.301175 | 0.301175 | no
BB_03.09.24#02_Wand uit metselwerk_EI60_43dB, 140 mm:26403247 | 010 | 840 | -920 | 010 | Up to level: 020 | 03.09.24#02 | 03.09.24#02 | geen waarde gevonden | K.20.K41 | BB_03.09.24#02_Wand uit metselwerk_EI60_43dB, 140 mm | 990 | 0.255024 | 1840 | 0.1386 | 0.255024 | 1.8216 | 1.8216 | no | Pset_WallCommon - FireRating: EI60
BB_03.09.24#02_Wand uit metselwerk_EI60_43dB, 140 mm:12560510 | 020 | -80 | 3310 | 020 | Up to level: 020 | 03.09.24#02 | 03.09.24#02 | geen waarde gevonden | K.20.G14 | BB_03.09.24#02_Wand uit metselwerk_EI60_43dB, 140 mm | 2904.39 | 1.3452 | 3390 | 0.396814 | 1.37842 | 9.84588 | 9.84588 | no | Pset_WallCommon - FireRating: EI60
BB_03.09.24#02_Wand uit metselwerk_EI60_43dB, 140 mm:12560511 | 020 | -80 | 3310 | 020 | Up to level: 020 | 03.09.24#02 | 03.09.24#02 | geen waarde gevonden | K.20.G14 | BB_03.09.24#02_Wand uit metselwerk_EI60_43dB, 140 mm | 2089.95 | 0.95867 | 3390 | 0.282794 | 0.991892 | 7.08494 | 7.08494 | no | Pset_WallCommon - FireRating: EI60
BB_03.09.24#02_Wand uit metselwerk_EI60_43dB, 140 mm:12560512 | 020 | -80 | 3310 | 020 | Up to level: 020 | 03.09.24#02 | 03.09.24#02 | geen waarde gevonden | K.20.G14 | BB_03.09.24#02_Wand uit metselwerk_EI60_43dB, 140 mm | 2904.39 | 1.3452 | 3390 | 0.396814 | 1.37842 | 9.84588 | 9.84588 | no | Pset_WallCommon - FireRating: EI60
BB_03.09.24#02_Wand uit metselwerk_EI60_43dB, 140 mm:12564069 | 020 | 840 | -920 | 020 | Up to level: 030 | 03.09.24#02 | 03.09.24#02 | geen waarde gevonden | K.20.K41 | BB_03.09.24#02_Wand uit metselwerk_EI60_43dB, 140 mm | 990 | 0.255024 | 1840 | 0.1386 | 0.255024 | 1.8216 | 1.8216 | no | Pset_WallCommon - FireRating: EI60
BB_03.09.24#02_Wand uit metselwerk_EI60_43dB, 140 mm:12564253 | 020 | -200 | -350 | 020 | Up to level: 030 | 03.09.24#02 | 03.09.24#02 | geen waarde gevonden | K.20.K41 | BB_03.09.24#02_Wand uit metselwerk_EI60_43dB, 140 mm | 2110.03 | 0.780247 | 3450 | 0.295404 | 1.01914 | 7.27959 | 5.57319 | no | Pset_WallCommon - FireRating: EI60
BB_03.09.24#02_Wand uit metselwerk_EI60_43dB, 140 mm:13276173 | 020 | -80 | 3310 | 020 | Up to level: 020 | 03.09.24#02 | 03.09.24#02 | geen waarde gevonden | K.20.G14 | BB_03.09.24#02_Wand uit metselwerk_EI60_43dB, 140 mm | 1195 | 0.267078 | 3390 | 0.1673 | 0.567147 | 4.05105 | 1.9077 | no | Pset_WallCommon - FireRating: EI60
BB_03.09.24#02_Wand uit metselwerk_EI60_43dB, 140 mm:16196888 | 020 | -200 | -5 | 020 | Up to level: 020 | 03.09.24#02 | 03.09.24#02 | geen waarde gevonden | K.20.101 | BB_03.09.24#02_Wand uit metselwerk_EI60_43dB, 140 mm | 1585 | 0.0432705 | 195 | 0.2219 | 0.0432705 | 0.309075 | 0.309075 | no
BB_03.09.24#02_Wand uit metselwerk_EI60_43dB, 140 mm:16196890 | 020 | -200 | -5 | 020 | Up to level: 020 | 03.09.24#02 | 03.09.24#02 | geen waarde gevonden | K.20.101 | BB_03.09.24#02_Wand uit metselwerk_EI60_43dB, 140 mm | 1685 | 0.0460005 | 195 | 0.2359 | 0.0460005 | 0.328575 | 0.328575 | no
BB_03.09.24#02_Wand uit metselwerk_EI60_43dB, 140 mm:25652044 | 020 | -80 | 3310 | 020 | Up to level: 020 | 03.09.24#02 | 03.09.24#02 | geen waarde gevonden |  | BB_03.09.24#02_Wand uit metselwerk_EI60_43dB, 140 mm | 1195 | 0.267078 | 3390 | 0.1673 | 0.567147 | 4.05105 | 1.9077 | no
BB_03.09.24#02_Wand uit metselwerk_EI60_43dB, 140 mm:12552787 | 030 | -80 | 3200 | 030 | Up to level: 030 | 03.09.24#02 | 03.09.24#02 | geen waarde gevonden | K.30.G14 | BB_03.09.24#02_Wand uit metselwerk_EI60_43dB, 140 mm | 2089.95 | 0.927563 | 3280 | 0.282794 | 0.959707 | 6.85505 | 6.85505 | no | Pset_WallCommon - FireRating: EI60
BB_03.09.24#02_Wand uit metselwerk_EI60_43dB, 140 mm:12552788 | 030 | -80 | 3200 | 030 | Up to level: 030 | 03.09.24#02 | 03.09.24#02 | geen waarde gevonden | K.30.G14 | BB_03.09.24#02_Wand uit metselwerk_EI60_43dB, 140 mm | 2904.39 | 1.30155 | 3280 | 0.396814 | 1.3337 | 9.52639 | 9.52639 | no | Pset_WallCommon - FireRating: EI60
BB_03.09.24#02_Wand uit metselwerk_EI60_43dB, 140 mm:12555719 | 030 | 840 | 2680 | 030 | Up to level: 030 | 03.09.24#02 | 03.09.24#02 | geen waarde gevonden | K.30.K41 | BB_03.09.24#02_Wand uit metselwerk_EI60_43dB, 140 mm | 990 | 0.255024 | 1840 | 0.1386 | 0.255024 | 1.8216 | 1.8216 | no | Pset_WallCommon - FireRating: EI60
BB_03.09.24#02_Wand uit metselwerk_EI60_43dB, 140 mm:12556263 | 030 | -200 | 3250 | 030 | Up to level: 030 | 03.09.24#02 | 03.09.24#02 | geen waarde gevonden | K.30.307 | BB_03.09.24#02_Wand uit metselwerk_EI60_43dB, 140 mm | 2110.03 | 0.780247 | 3450 | 0.295404 | 1.01914 | 7.27959 | 5.57319 | no | Pset_WallCommon - FireRating: EI60
BB_03.09.24#02_Wand uit metselwerk_EI60_43dB, 140 mm:13276314 | 030 | -80 | 3200 | 030 | Up to level: 030 | 03.09.24#02 | 03.09.24#02 | geen waarde gevonden | K.30.G14 | BB_03.09.24#02_Wand uit metselwerk_EI60_43dB, 140 mm | 1195 | 0.248675 | 3280 | 0.1673 | 0.548744 | 3.9196 | 1.77625 | no | Pset_WallCommon - FireRating: EI60
BB_03.09.24#02_Wand uit metselwerk_EI60_43dB, 140 mm:16187605 | 030 | -200 | -10 | 030 | Up to level: 030 | 03.09.24#02 | 03.09.24#02 | geen waarde gevonden | K.30.101 | BB_03.09.24#02_Wand uit metselwerk_EI60_43dB, 140 mm | 1585 | 0.042161 | 190 | 0.2219 | 0.042161 | 0.30115 | 0.30115 | no
BB_03.09.24#02_Wand uit metselwerk_EI60_43dB, 140 mm:16187852 | 030 | -200 | -10 | 030 | Up to level: 030 | 03.09.24#02 | 03.09.24#02 | geen waarde gevonden | K.30.101 | BB_03.09.24#02_Wand uit metselwerk_EI60_43dB, 140 mm | 1585 | 0.042161 | 190 | 0.2219 | 0.042161 | 0.30115 | 0.30115 | no
BB_03.09.24#02_Wand uit metselwerk_EI60_43dB, 140 mm:25652726 | 030 | -80 | 3200 | 030 | Up to level: 030 | 03.09.24#02 | 03.09.24#02 | geen waarde gevonden |  | BB_03.09.24#02_Wand uit metselwerk_EI60_43dB, 140 mm | 1195 | 0.248675 | 3280 | 0.1673 | 0.548744 | 3.9196 | 1.77625 | no
BB_03.09.24#01_Wand uit metselwerk, 140 mm:32051748 | 030 | -200 | -35 | 030 | Up to level: 030 | 03.09.24#01 | 03.09.24#01 | geen waarde gevonden |  | BB_03.09.24#01_Wand uit metselwerk, 140 mm | 12535 | 0.289558 | 165 | 1.7549 | 0.289558 | 2.06827 | 2.06827 | no
BB_03.09.24#01_Wand uit metselwerk, 140 mm:34198391 | 040 | -200 | 0 | 040 |  | 03.09.24#01 |  |  |  | BB_03.09.24#01_Wand uit metselwerk, 140 mm | 10603.9 | 3.51588 | 2400 | 1.46495 | 3.56292 | 25.4494 | 25.4494 | yes

# IfcWall: BB_Metselwerk_Betonsteen 160.347, Basic Wall:BB_03.09.24#05_Wand uit metselwerk_EI60, 190 mm:34143815
In: 030
Type - Material: BB_Metselwerk_Betonsteen
PredefinedType: SOLIDWALL
Cpset_Wall - LevelOfAccuracy: in te vullen door Buildwise
IfcBuildingStorey - Base Offset: -200; Top Offset: 2800; Base Constraint: 030; Top Constraint: Up to level: 030
IfcClassificationReference - Keynote: 03.09.24#05; TDS_link: .\05 As Builtdossier\2. Bouwkunde\2.1 Architectuur\2.1.3 open ruwbouw\TF S 4.2.1.1.1 A-volle betonstenen.pdf
IfcElement - BB_Element_Lokaalnummer01: K.00.A1
IfcRoot - Name: BB_03.09.24#05_Wand uit metselwerk_EI60, 190 mm
Qto_WallBaseQuantities - Length: 160.347; NetVolume: 0.0913976; Height: 3000; Width: 190; GrossFootprintArea: 0.0304659; GrossVolume: 0.1083; GrossSideArea: 0.57; NetSideArea: 0.57
Pset_Condition - AssessmentCondition: Empty
Pset_EnvironmentalImpactIndicators - Reference: BB_03.09.24#05_Wand uit metselwerk_EI60, 190 mm; sets with these values: 2
Pset_WallCommon - Reference: BB_03.09.24#05_Wand uit metselwerk_EI60, 190 mm; ThermalTransmittance: 6.26316; IsExternal: yes; LoadBearing: no; ExtendToStructure: no

# IfcWall: BB_Metselwerk_Betonsteen 190 (122)
Type - Material: BB_Metselwerk_Betonsteen
PredefinedType: SOLIDWALL
Cpset_Wall - LevelOfAccuracy: in te vullen door Buildwise
Qto_WallBaseQuantities - Width: 190
Pset_Condition - AssessmentCondition: Empty
Pset_EnvironmentalImpactIndicators - sets with these values: 2
Pset_WallCommon - IsExternal: yes; ExtendToStructure: no
Name (Basic Wall:...) | In | Base Offset | Top Offset | Base Constraint | Top Constraint | Keynote | GVH_artnr 01 | GVH_artnr 02 = GVH_artnr 03 = GVH_artnr 04 = GVH_artnr 05 = GVH_artnr 06 | TDS_link | BB_Element_Lokaalnummer01 | Name = Pset_EnvironmentalImpactIndicators, Reference = Pset_WallCommon, Reference | Length | NetVolume | Height | GrossFootprintArea | GrossVolume | GrossSideArea | NetSideArea | ThermalTransmittance | LoadBearing
BB_03.09.24#05_Wand uit metselwerk_EI60, 190 mm:19975469 | K20 | 0 | 2200 | K20 | Up to level: K20 | 03.09.24#05 | 03.09.24#05 | geen waarde gevonden | .\05 As Builtdossier\2. Bouwkunde\2.1 Architectuur\2.1.3 open ruwbouw\TF S 4.2.1.1.1 A-volle betonstenen.pdf | K.-2.404 | BB_03.09.24#05_Wand uit metselwerk_EI60, 190 mm | 1115 | 0.46607 | 2200 | 0.21185 | 0.46607 | 2.453 | 2.453 | 6.26316 | no | Pset_WallCommon - FireRating: EI60
BB_03.09.24#05_Wand uit metselwerk_EI60, 190 mm:19977114 | K20 | 0 | 2200 | K20 | Up to level: K20 | 03.09.24#05 | 03.09.24#05 | geen waarde gevonden | .\05 As Builtdossier\2. Bouwkunde\2.1 Architectuur\2.1.3 open ruwbouw\TF S 4.2.1.1.1 A-volle betonstenen.pdf | K.-2.405 | BB_03.09.24#05_Wand uit metselwerk_EI60, 190 mm | 865 | 0.36157 | 2200 | 0.16435 | 0.36157 | 1.903 | 1.903 | 6.26316 | no | Pset_WallCommon - FireRating: EI60
BB_03.09.24#05_Wand uit metselwerk_EI60, 190 mm:19977204 | K20 | 1000 | 1600 | K20 | Up to level: K20 | 03.09.24#05 | 03.09.24#05 | geen waarde gevonden | .\05 As Builtdossier\2. Bouwkunde\2.1 Architectuur\2.1.3 open ruwbouw\TF S 4.2.1.1.1 A-volle betonstenen.pdf | K.-2.305 | BB_03.09.24#05_Wand uit metselwerk_EI60, 190 mm | 3578.01 | 0.407893 | 600 | 0.679821 | 0.407893 | 2.1468 | 2.1468 | 6.26316 | no | Pset_WallCommon - FireRating: EI60
BB_03.09.24#05_Wand uit metselwerk_EI60, 190 mm:19977660 | K20 | 0 | 0 | K20 |  | 03.09.24#05 | 03.09.24#05 | geen waarde gevonden | .\05 As Builtdossier\2. Bouwkunde\2.1 Architectuur\2.1.3 open ruwbouw\TF S 4.2.1.1.1 A-volle betonstenen.pdf | K.-2.403 | BB_03.09.24#05_Wand uit metselwerk_EI60, 190 mm | 3585 | 1.49853 | 2200 | 0.68115 | 1.49853 | 7.887 | 7.887 | 6.26316 | no
BB_03.09.24#05_Wand uit metselwerk_EI60, 190 mm:19977791 | K20 | 0 | 2200 | K20 | Up to level: K20 | 03.09.24#05 | 03.09.24#05 | geen waarde gevonden | .\05 As Builtdossier\2. Bouwkunde\2.1 Architectuur\2.1.3 open ruwbouw\TF S 4.2.1.1.1 A-volle betonstenen.pdf | K.-2.403 | BB_03.09.24#05_Wand uit metselwerk_EI60, 190 mm | 1715 | 0.71687 | 2200 | 0.32585 | 0.71687 | 3.773 | 3.773 | 6.26316 | no
BB_03.09.24#05_Wand uit metselwerk_EI60, 190 mm:19977929 | K20 | 0 | 2010 | K20 | Up to level: K20 | 03.09.24#05 | 03.09.24#05 | geen waarde gevonden | .\05 As Builtdossier\2. Bouwkunde\2.1 Architectuur\2.1.3 open ruwbouw\TF S 4.2.1.1.1 A-volle betonstenen.pdf | K.-2.405 | BB_03.09.24#05_Wand uit metselwerk_EI60, 190 mm | 1600 | 0.61104 | 2010 | 0.304 | 0.61104 | 3.216 | 3.216 | 6.26316 | no | Pset_WallCommon - FireRating: EI60
BB_03.09.24#05_Wand uit metselwerk_EI60, 190 mm:19977978 | K20 | 0 | 907.181 | K20 | Up to level: K20 | 03.09.24#05 | 03.09.24#05 | geen waarde gevonden | .\05 As Builtdossier\2. Bouwkunde\2.1 Architectuur\2.1.3 open ruwbouw\TF S 4.2.1.1.1 A-volle betonstenen.pdf | K.-2.T3 | BB_03.09.24#05_Wand uit metselwerk_EI60, 190 mm | 980 | 0.168917 | 907.181 | 0.1862 | 0.168917 | 0.889037 | 0.889037 | 6.26316 | no | Pset_WallCommon - FireRating: EI60
BB_03.09.24#05_Wand uit metselwerk_EI60, 190 mm:19978364 | K20 | 0 | 2060 | K20 | Up to level: K20 | 03.09.24#05 | 03.09.24#05 | geen waarde gevonden | .\05 As Builtdossier\2. Bouwkunde\2.1 Architectuur\2.1.3 open ruwbouw\TF S 4.2.1.1.1 A-volle betonstenen.pdf | K.-2.L3 | BB_03.09.24#05_Wand uit metselwerk_EI60, 190 mm | 946 | 0.370264 | 2060 | 0.17974 | 0.370264 | 1.94876 | 1.94876 | 6.26316 | no | Pset_WallCommon - FireRating: EI60
BB_03.09.24#05_Wand uit metselwerk_EI60, 190 mm:19978433 | K20 | 0 | 2010 | K20 | Up to level: K20 | 03.09.24#05 | 03.09.24#05 | geen waarde gevonden | .\05 As Builtdossier\2. Bouwkunde\2.1 Architectuur\2.1.3 open ruwbouw\TF S 4.2.1.1.1 A-volle betonstenen.pdf | K.-2.306 | BB_03.09.24#05_Wand uit metselwerk_EI60, 190 mm | 1170 | 0.446823 | 2010 | 0.2223 | 0.446823 | 2.3517 | 2.3517 | 6.26316 | no | Pset_WallCommon - FireRating: EI60
BB_03.09.24#05_Wand uit metselwerk_EI60, 190 mm:19978522 | K20 | 0 | 2340 | K20 | Up to level: K20 | 03.09.24#05 | 03.09.24#05 | geen waarde gevonden | .\05 As Builtdossier\2. Bouwkunde\2.1 Architectuur\2.1.3 open ruwbouw\TF S 4.2.1.1.1 A-volle betonstenen.pdf | K.-2.301 | BB_03.09.24#05_Wand uit metselwerk_EI60, 190 mm | 6015 | 2.67427 | 2340 | 1.14285 | 2.67427 | 14.0751 | 14.0751 | 6.26316 | no | Pset_WallCommon - FireRating: EI60
BB_03.09.24#05_Wand uit metselwerk_EI60, 190 mm:19978815 | K20 | 1010 | 2010 | K20 | Up to level: K20 | 03.09.24#05 | 03.09.24#05 | geen waarde gevonden | .\05 As Builtdossier\2. Bouwkunde\2.1 Architectuur\2.1.3 open ruwbouw\TF S 4.2.1.1.1 A-volle betonstenen.pdf | K.-2.303 | BB_03.09.24#05_Wand uit metselwerk_EI60, 190 mm | 1262.02 | 0.239784 | 1000 | 0.239783 | 0.0361 | 0.19 | 1.26744 | 6.26316 | no | Pset_WallCommon - FireRating: EI60
BB_03.09.24#05_Wand uit metselwerk_EI60, 190 mm:19979288 | K20 | 0 | 2000 | K20 | Up to level: K20 | 03.09.24#05 | 03.09.24#05 | geen waarde gevonden | .\05 As Builtdossier\2. Bouwkunde\2.1 Architectuur\2.1.3 open ruwbouw\TF S 4.2.1.1.1 A-volle betonstenen.pdf | K.-2.G11 | BB_03.09.24#05_Wand uit metselwerk_EI60, 190 mm | 1025 | 0.3895 | 2000 | 0.19475 | 0.3895 | 2.05 | 2.05 | 6.26316 | no | Pset_WallCommon - FireRating: EI60
BB_03.09.24#05_Wand uit metselwerk_EI60, 190 mm:19979372 | K20 | 0 | 2200 | K20 | Up to level: K20 | 03.09.24#05 | 03.09.24#05 | geen waarde gevonden | .\05 As Builtdossier\2. Bouwkunde\2.1 Architectuur\2.1.3 open ruwbouw\TF S 4.2.1.1.1 A-volle betonstenen.pdf | K.-2.K12 | BB_03.09.24#05_Wand uit metselwerk_EI60, 190 mm | 1010 | 0.42218 | 2200 | 0.1919 | 0.42218 | 2.222 | 2.222 | 6.26316 | no | Pset_WallCommon - FireRating: EI60
BB_03.09.24#05_Wand uit metselwerk_EI60, 190 mm:19979481 | K20 | 0 | 2200 | K20 | Up to level: K20 | 03.09.24#05 | 03.09.24#05 | geen waarde gevonden | .\05 As Builtdossier\2. Bouwkunde\2.1 Architectuur\2.1.3 open ruwbouw\TF S 4.2.1.1.1 A-volle betonstenen.pdf | K.-2.K15 | BB_03.09.24#05_Wand uit metselwerk_EI60, 190 mm | 1010 | 0.42218 | 2200 | 0.1919 | 0.42218 | 2.222 | 2.222 | 6.26316 | no | Pset_WallCommon - FireRating: EI60
BB_03.09.24#05_Wand uit metselwerk_EI60, 190 mm:19980592 | K20 | 0 | 2400 | K20 | Up to level: K20 | 03.09.24#05 | 03.09.24#05 | geen waarde gevonden | .\05 As Builtdossier\2. Bouwkunde\2.1 Architectuur\2.1.3 open ruwbouw\TF S 4.2.1.1.1 A-volle betonstenen.pdf | K.-2.G21 | BB_03.09.24#05_Wand uit metselwerk_EI60, 190 mm | 1200 | 0.5472 | 2400 | 0.228 | 0.5472 | 2.88 | 2.88 | 6.26316 | no
BB_03.09.24#05_Wand uit metselwerk_EI60, 190 mm:19982114 | K20 | 1035 | 2235 | K20 | Up to level: K20 | 03.09.24#05 | 03.09.24#05 | geen waarde gevonden | .\05 As Builtdossier\2. Bouwkunde\2.1 Architectuur\2.1.3 open ruwbouw\TF S 4.2.1.1.1 A-volle betonstenen.pdf | K.-2.G32 | BB_03.09.24#05_Wand uit metselwerk_EI60, 190 mm | 1200 | 0.2736 | 1200 | 0.228 | 0.2736 | 1.44 | 1.44 | 6.26316 | no | Pset_WallCommon - FireRating: EI60
BB_03.09.24#05_Wand uit metselwerk_EI60, 190 mm:20388591 | K20 | 0 | 2100 | K20 | Up to level: K20 | 03.09.24#05 | 03.09.24#05 | geen waarde gevonden | .\05 As Builtdossier\2. Bouwkunde\2.1 Architectuur\2.1.3 open ruwbouw\TF S 4.2.1.1.1 A-volle betonstenen.pdf | K.-2.306 | BB_03.09.24#05_Wand uit metselwerk_EI60, 190 mm | 3946.91 | 1.57482 | 2100 | 0.749912 | 1.57482 | 8.2885 | 8.2885 | 6.26316 | no | Pset_WallCommon - FireRating: EI60
BB_03.09.24#03_Wand uit metselwerk, 190 mm:4902476 | K10 | 840 | -920 | K10 | Up to level: 000 | 03.09.24#03 | 03.09.24#03 | geen waarde gevonden | .\05 As Builtdossier\2. Bouwkunde\2.1 Architectuur\2.1.3 open ruwbouw\TF S 4.2.1.1.1 A-volle betonstenen.pdf | K.-1.302 | BB_03.09.24#03_Wand uit metselwerk, 190 mm | 1007.24 | 0.283236 | 1480 | 0.191376 | 0.053428 | 0.2812 | 1.49713 | 6.26316 | no
BB_03.09.24#03_Wand uit metselwerk, 190 mm:4903000 | K10 | 840 | -920 | K10 | Up to level: 000 | 03.09.24#03 | 03.09.24#03 | geen waarde gevonden | .\05 As Builtdossier\2. Bouwkunde\2.1 Architectuur\2.1.3 open ruwbouw\TF S 4.2.1.1.1 A-volle betonstenen.pdf | K.-1.303 | BB_03.09.24#03_Wand uit metselwerk, 190 mm | 1144.83 | 0.321927 | 1480 | 0.217518 | 0.053428 | 0.2812 | 1.70159 | 6.26316 | no
BB_03.09.24#05_Wand uit metselwerk_EI60, 190 mm:19986715 | K10 | 0 | 2320 | K10 | Up to level: K10 | 03.09.24#05 | 03.09.24#05 | geen waarde gevonden | .\05 As Builtdossier\2. Bouwkunde\2.1 Architectuur\2.1.3 open ruwbouw\TF S 4.2.1.1.1 A-volle betonstenen.pdf | K.-1.306 | BB_03.09.24#05_Wand uit metselwerk_EI60, 190 mm | 1115 | 0.491492 | 2320 | 0.21185 | 0.491492 | 2.5868 | 2.5868 | 6.26316 | no | Pset_WallCommon - FireRating: EI60
BB_03.09.24#05_Wand uit metselwerk_EI60, 190 mm:19986721 | K10 | 0 | 2290 | K10 | Up to level: K10 | 03.09.24#05 | 03.09.24#05 | geen waarde gevonden | .\05 As Builtdossier\2. Bouwkunde\2.1 Architectuur\2.1.3 open ruwbouw\TF S 4.2.1.1.1 A-volle betonstenen.pdf | K.-1.307 | BB_03.09.24#05_Wand uit metselwerk_EI60, 190 mm | 960 | 0.417696 | 2290 | 0.1824 | 0.417696 | 2.1984 | 2.1984 | 6.26316 | no | Pset_WallCommon - FireRating: EI60
BB_03.09.24#05_Wand uit metselwerk_EI60, 190 mm:19986722 | K10 | 0 | 1740 | K10 | Up to level: K10 | 03.09.24#05 | 03.09.24#05 | geen waarde gevonden | .\05 As Builtdossier\2. Bouwkunde\2.1 Architectuur\2.1.3 open ruwbouw\TF S 4.2.1.1.1 A-volle betonstenen.pdf | K.-1.310 | BB_03.09.24#05_Wand uit metselwerk_EI60, 190 mm | 3603.31 | 1.19126 | 1740 | 0.684629 | 1.19126 | 6.26976 | 6.26976 | 6.26316 | no | Pset_WallCommon - FireRating: EI60
BB_03.09.24#05_Wand uit metselwerk_EI60, 190 mm:19986806 | K10 | 0 | 2290 | K10 | Up to level: K10 | 03.09.24#05 | 03.09.24#05 | geen waarde gevonden | .\05 As Builtdossier\2. Bouwkunde\2.1 Architectuur\2.1.3 open ruwbouw\TF S 4.2.1.1.1 A-volle betonstenen.pdf | K.-1.307 | BB_03.09.24#05_Wand uit metselwerk_EI60, 190 mm | 600 | 0.26106 | 2290 | 0.114 | 0.26106 | 1.374 | 1.374 | 6.26316 | no | Pset_WallCommon - FireRating: EI60
BB_03.09.24#05_Wand uit metselwerk_EI60, 190 mm:19987041 | K10 | 0 | 2120 | K10 | Up to level: K10 | 03.09.24#05 | 03.09.24#05 | geen waarde gevonden | .\05 As Builtdossier\2. Bouwkunde\2.1 Architectuur\2.1.3 open ruwbouw\TF S 4.2.1.1.1 A-volle betonstenen.pdf | K.-1.307 | BB_03.09.24#05_Wand uit metselwerk_EI60, 190 mm | 1000 | 0.4028 | 2120 | 0.19 | 0.4028 | 2.12 | 2.12 | 6.26316 | no | Pset_WallCommon - FireRating: EI60
BB_03.09.24#05_Wand uit metselwerk_EI60, 190 mm:19987249 | K10 | 0 | 2780 | K10 | Up to level: K10 | 03.09.24#05 | 03.09.24#05 | geen waarde gevonden | .\05 As Builtdossier\2. Bouwkunde\2.1 Architectuur\2.1.3 open ruwbouw\TF S 4.2.1.1.1 A-volle betonstenen.pdf | K.-1.307 | BB_03.09.24#05_Wand uit metselwerk_EI60, 190 mm | 790 | 0.417278 | 2780 | 0.1501 | 0.417278 | 2.1962 | 2.1962 | 6.26316 | no | Pset_WallCommon - FireRating: EI60
BB_03.09.24#05_Wand uit metselwerk_EI60, 190 mm:19987279 | K10 | 0 | 2780 | K10 | Up to level: K10 | 03.09.24#05 | 03.09.24#05 | geen waarde gevonden | .\05 As Builtdossier\2. Bouwkunde\2.1 Architectuur\2.1.3 open ruwbouw\TF S 4.2.1.1.1 A-volle betonstenen.pdf | K.-1.307 | BB_03.09.24#05_Wand uit metselwerk_EI60, 190 mm | 1280 | 0.676096 | 2780 | 0.2432 | 0.676096 | 3.5584 | 3.5584 | 6.26316 | no | Pset_WallCommon - FireRating: EI60
BB_03.09.24#05_Wand uit metselwerk_EI60, 190 mm:19987734 | K10 | 0 | 2780 | K10 | Up to level: K10 | 03.09.24#05 | 03.09.24#05 | geen waarde gevonden | .\05 As Builtdossier\2. Bouwkunde\2.1 Architectuur\2.1.3 open ruwbouw\TF S 4.2.1.1.1 A-volle betonstenen.pdf | K.-1.306 | BB_03.09.24#05_Wand uit metselwerk_EI60, 190 mm | 2560 | 1.35219 | 2780 | 0.4864 | 1.35219 | 7.1168 | 7.1168 | 6.26316 | no | Pset_WallCommon - FireRating: EI60
BB_03.09.24#05_Wand uit metselwerk_EI60, 190 mm:19988435 | K10 | 1330 | 2030 | K10 | Up to level: K10 | 03.09.24#05 | 03.09.24#05 | geen waarde gevonden | .\05 As Builtdossier\2. Bouwkunde\2.1 Architectuur\2.1.3 open ruwbouw\TF S 4.2.1.1.1 A-volle betonstenen.pdf | K.-1.G32 | BB_03.09.24#05_Wand uit metselwerk_EI60, 190 mm | 1200 | 0.1596 | 700 | 0.228 | 0.1596 | 0.84 | 0.84 | 6.26316 | no
BB_03.09.24#03_Wand uit metselwerk, 190 mm:19989461 | K10 | 0 | 2780 | K10 | Up to level: K10 | 03.09.24#03 | 03.09.24#03 | geen waarde gevonden | .\05 As Builtdossier\2. Bouwkunde\2.1 Architectuur\2.1.3 open ruwbouw\TF S 4.2.1.1.1 A-volle betonstenen.pdf | K.-1.301 | BB_03.09.24#03_Wand uit metselwerk, 190 mm | 650 | 0.34333 | 2780 | 0.1235 | 0.34333 | 1.807 | 1.807 | 6.26316 | no
BB_03.09.24#05_Wand uit metselwerk_EI60, 190 mm:19992258 | K10 | 2230 | 2730 | K10 | Up to level: K10 | 03.09.24#05 | 03.09.24#05 | geen waarde gevonden | .\05 As Builtdossier\2. Bouwkunde\2.1 Architectuur\2.1.3 open ruwbouw\TF S 4.2.1.1.1 A-volle betonstenen.pdf | K.-1.G32 | BB_03.09.24#05_Wand uit metselwerk_EI60, 190 mm | 1600 | 0.152 | 500 | 0.304 | 0.152 | 0.8 | 0.8 | 6.26316 | no
BB_03.09.24#05_Wand uit metselwerk_EI60, 190 mm:19993558 | K10 | 0 | 2780 | K10 | Up to level: K10 | 03.09.24#05 | 03.09.24#05 | geen waarde gevonden | .\05 As Builtdossier\2. Bouwkunde\2.1 Architectuur\2.1.3 open ruwbouw\TF S 4.2.1.1.1 A-volle betonstenen.pdf | K.-1.G15 | BB_03.09.24#05_Wand uit metselwerk_EI60, 190 mm | 925 | 0.488585 | 2780 | 0.17575 | 0.488585 | 2.5715 | 2.5715 | 6.26316 | no | Pset_WallCommon - FireRating: EI60
BB_03.09.24#05_Wand uit metselwerk_EI60, 190 mm:19994606 | K10 | 217.778 | -400 | K10 | Up to level: 000 | 03.09.24#05 | 03.09.24#05 | geen waarde gevonden | .\05 As Builtdossier\2. Bouwkunde\2.1 Architectuur\2.1.3 open ruwbouw\TF S 4.2.1.1.1 A-volle betonstenen.pdf | K.-1.T4 | BB_03.09.24#05_Wand uit metselwerk_EI60, 190 mm | 1200 | 0.597867 | 2622.22 | 0.228 | 0.597867 | 3.14667 | 3.14667 | 6.26316 | no | Pset_WallCommon - FireRating: EI60
BB_03.09.24#05_Wand uit metselwerk_EI60, 190 mm:19995289 | K10 | 0 | 2780 | K10 | Up to level: K10 | 03.09.24#05 | 03.09.24#05 | geen waarde gevonden | .\05 As Builtdossier\2. Bouwkunde\2.1 Architectuur\2.1.3 open ruwbouw\TF S 4.2.1.1.1 A-volle betonstenen.pdf | K.-1.G11 | BB_03.09.24#05_Wand uit metselwerk_EI60, 190 mm | 3860 | 2.03885 | 2780 | 0.7334 | 2.03885 | 10.7308 | 10.7308 | 6.26316 | no | Pset_WallCommon - FireRating: EI60
BB_03.09.24#05_Wand uit metselwerk_EI60, 190 mm:19995754 | K10 | 0 | 2540 | K10 | Up to level: K10 | 03.09.24#05 | 03.09.24#05 | geen waarde gevonden | .\05 As Builtdossier\2. Bouwkunde\2.1 Architectuur\2.1.3 open ruwbouw\TF S 4.2.1.1.1 A-volle betonstenen.pdf | K.-1.P5 | BB_03.09.24#05_Wand uit metselwerk_EI60, 190 mm | 6405 | 3.09105 | 2540 | 1.21695 | 3.09105 | 16.2687 | 16.2687 | 6.26316 | no
BB_03.09.24#05_Wand uit metselwerk_EI60, 190 mm:19995825 | K10 | 0 | 2780 | K10 | Up to level: K10 | 03.09.24#05 | 03.09.24#05 | geen waarde gevonden | .\05 As Builtdossier\2. Bouwkunde\2.1 Architectuur\2.1.3 open ruwbouw\TF S 4.2.1.1.1 A-volle betonstenen.pdf | K.-1.P5 | BB_03.09.24#05_Wand uit metselwerk_EI60, 190 mm | 6305 | 3.3303 | 2780 | 1.19795 | 3.3303 | 17.5279 | 17.5279 | 6.26316 | no | Pset_WallCommon - FireRating: EI60
BB_03.09.24#05_Wand uit metselwerk_EI60, 190 mm:19999475 | K10 | 299.35 | 1997.67 | K10 | Up to level: K10 | 03.09.24#05 | 03.09.24#05 | geen waarde gevonden | .\05 As Builtdossier\2. Bouwkunde\2.1 Architectuur\2.1.3 open ruwbouw\TF S 4.2.1.1.1 A-volle betonstenen.pdf | K.-1.103 | BB_03.09.24#05_Wand uit metselwerk_EI60, 190 mm | 2010 | 0.648589 | 1698.32 | 0.3819 | 0.648589 | 3.41362 | 3.41362 | 6.26316 | no | Pset_WallCommon - FireRating: EI60
BB_03.09.24#03_Wand uit metselwerk, 190 mm:32128118 | K10 | 0 | -1151 | K10 | Up to level: 000 | 03.09.24#03 | 03.09.24#03 | geen waarde gevonden | .\05 As Builtdossier\2. Bouwkunde\2.1 Architectuur\2.1.3 open ruwbouw\TF S 4.2.1.1.1 A-volle betonstenen.pdf |  | BB_03.09.24#03_Wand uit metselwerk, 190 mm | 1498 | 0.594571 | 2089 | 0.28462 | 0.594571 | 3.12932 | 3.12932 | 6.26316 | no
BB_03.09.24#03_Wand uit metselwerk, 190 mm:4894770 | 000 | -200 | -920 | 000 | Up to level: 010 | 03.09.24#03 | 03.09.24#03 | geen waarde gevonden | .\05 As Builtdossier\2. Bouwkunde\2.1 Architectuur\2.1.3 open ruwbouw\TF S 4.2.1.1.1 A-volle betonstenen.pdf | K.00.G12 | BB_03.09.24#03_Wand uit metselwerk, 190 mm | 525 | 0.28728 | 2880 | 0.09975 | 0.28728 | 1.512 | 1.512 | 6.26316 | no
BB_03.09.24#03_Wand uit metselwerk, 190 mm:4895036 | 000 | -200 | -920 | 000 | Up to level: 010 | 03.09.24#03 | 03.09.24#03 | geen waarde gevonden | .\05 As Builtdossier\2. Bouwkunde\2.1 Architectuur\2.1.3 open ruwbouw\TF S 4.2.1.1.1 A-volle betonstenen.pdf | K.00.G18 | BB_03.09.24#03_Wand uit metselwerk, 190 mm | 525 | 0.28728 | 2880 | 0.09975 | 0.28728 | 1.512 | 1.512 | 6.26316 | no
BB_03.09.24#03_Wand uit metselwerk, 190 mm:4902470 | 000 | 840 | -920 | 000 | Up to level: 010 | 03.09.24#03 | 03.09.24#03 | geen waarde gevonden | .\05 As Builtdossier\2. Bouwkunde\2.1 Architectuur\2.1.3 open ruwbouw\TF S 4.2.1.1.1 A-volle betonstenen.pdf | K.00.302 | BB_03.09.24#03_Wand uit metselwerk, 190 mm | 992.965 | 0.347141 | 1840 | 0.188663 | 0.066424 | 0.3496 | 1.83491 | 6.26316 | no
BB_03.09.24#03_Wand uit metselwerk, 190 mm:4902994 | 000 | 840 | -920 | 000 | Up to level: 010 | 03.09.24#03 | 03.09.24#03 | geen waarde gevonden | .\05 As Builtdossier\2. Bouwkunde\2.1 Architectuur\2.1.3 open ruwbouw\TF S 4.2.1.1.1 A-volle betonstenen.pdf | K.00.304 | BB_03.09.24#03_Wand uit metselwerk, 190 mm | 1146.92 | 0.400963 | 1840 | 0.217915 | 0.066424 | 0.3496 | 2.11934 | 6.26316 | no
BB_03.09.24#03_Wand uit metselwerk, 190 mm:13040422 | 000 | 840 | -920 | 000 | Up to level: 010 | 03.09.24#03 | 03.09.24#03 | geen waarde gevonden | .\05 As Builtdossier\2. Bouwkunde\2.1 Architectuur\2.1.3 open ruwbouw\TF S 4.2.1.1.1 A-volle betonstenen.pdf | K.00.203 | BB_03.09.24#03_Wand uit metselwerk, 190 mm | 2850 | 0.99636 | 1840 | 0.5415 | 0.99636 | 5.244 | 5.244 | 6.26316 | no
BB_03.09.24#03_Wand uit metselwerk, 190 mm:13040423 | 000 | 840 | -920 | 000 | Up to level: 010 | 03.09.24#03 | 03.09.24#03 | geen waarde gevonden | .\05 As Builtdossier\2. Bouwkunde\2.1 Architectuur\2.1.3 open ruwbouw\TF S 4.2.1.1.1 A-volle betonstenen.pdf | K.00.402 | BB_03.09.24#03_Wand uit metselwerk, 190 mm | 2850 | 0.99636 | 1840 | 0.5415 | 0.99636 | 5.244 | 5.244 | 6.26316 | no
BB_03.09.24#03_Wand uit metselwerk, 190 mm:13042696 | 000 | -200 | -530 | 000 | Up to level: 010 | 03.09.24#03 | 03.09.24#03 | geen waarde gevonden | .\05 As Builtdossier\2. Bouwkunde\2.1 Architectuur\2.1.3 open ruwbouw\TF S 4.2.1.1.1 A-volle betonstenen.pdf | K.00.304 | BB_03.09.24#03_Wand uit metselwerk, 190 mm | 4222.37 | 2.62336 | 3270 | 0.80225 | 2.62336 | 13.8071 | 13.8071 | 6.26316 | no
BB_03.09.24#04_Wand uit metselwerk_vol, 190 mm:13048735 | 000 | -200 | -600 | 000 | Up to level: 010 | 03.09.24#04 | 03.09.24#04 | geen waarde gevonden | .\05 As Builtdossier\2. Bouwkunde\2.1 Architectuur\2.1.3 open ruwbouw\TF S 4.2.1.1.1 A-volle betonstenen.pdf | K.00.S13 | BB_03.09.24#04_Wand uit metselwerk_vol, 190 mm | 4505.03 | 2.73906 | 3200 | 0.855956 | 2.73906 | 14.4161 | 14.4161 | 6.26316 | no
BB_03.09.24#05_Wand uit metselwerk_EI60, 190 mm:25439296 | 000 | -200 | -2040 | 000 | Up to level: 010 | 03.09.24#05 | 03.09.24#05 | geen waarde gevonden | .\05 As Builtdossier\2. Bouwkunde\2.1 Architectuur\2.1.3 open ruwbouw\TF S 4.2.1.1.1 A-volle betonstenen.pdf | K.00.K17 | BB_03.09.24#05_Wand uit metselwerk_EI60, 190 mm | 820 | 0.274208 | 1760 | 0.1558 | 0.274208 | 1.4432 | 1.4432 | 6.26316 | no | Pset_WallCommon - FireRating: EI60
BB_03.09.24#04_Wand uit metselwerk_vol, 190 mm:25506075 | 000 | -200 | -600 | 000 | Up to level: 010 | 03.09.24#04 | 03.09.24#04 | geen waarde gevonden | .\05 As Builtdossier\2. Bouwkunde\2.1 Architectuur\2.1.3 open ruwbouw\TF S 4.2.1.1.1 A-volle betonstenen.pdf | K.00.S13 | BB_03.09.24#04_Wand uit metselwerk_vol, 190 mm | 1755 | 1.06704 | 3200 | 0.33345 | 1.06704 | 5.616 | 5.616 | 6.26316 | no
BB_03.09.24#03_Wand uit metselwerk, 190 mm:25506751 | 000 | -200 | -460 | 000 | Up to level: 010 | 03.09.24#03 | 03.09.24#03 | geen waarde gevonden | .\05 As Builtdossier\2. Bouwkunde\2.1 Architectuur\2.1.3 open ruwbouw\TF S 4.2.1.1.1 A-volle betonstenen.pdf | K.00.S13 | BB_03.09.24#03_Wand uit metselwerk, 190 mm | 899.721 | 0.570963 | 3340 | 0.170947 | 0.570963 | 3.00507 | 3.00507 | 6.26316 | no
BB_03.09.24#05_Wand uit metselwerk_EI60, 190 mm:25513948 | 000 | -200 | -460 | 000 | Up to level: 010 | 03.09.24#05 | 03.09.24#05 | geen waarde gevonden | .\05 As Builtdossier\2. Bouwkunde\2.1 Architectuur\2.1.3 open ruwbouw\TF S 4.2.1.1.1 A-volle betonstenen.pdf | K.00.S13 | BB_03.09.24#05_Wand uit metselwerk_EI60, 190 mm | 950 | 0.60287 | 3340 | 0.1805 | 0.60287 | 3.173 | 3.173 | 6.26316 | no | Pset_WallCommon - FireRating: EI60
BB_03.09.24#05_Wand uit metselwerk_EI60, 190 mm:25513972 | 000 | -200 | -460 | 000 | Up to level: 010 | 03.09.24#05 | 03.09.24#05 | geen waarde gevonden | .\05 As Builtdossier\2. Bouwkunde\2.1 Architectuur\2.1.3 open ruwbouw\TF S 4.2.1.1.1 A-volle betonstenen.pdf | K.00.S13 | BB_03.09.24#05_Wand uit metselwerk_EI60, 190 mm | 490 | 0.310954 | 3340 | 0.0931 | 0.310954 | 1.6366 | 1.6366 | 6.26316 | no | Pset_WallCommon - FireRating: EI60
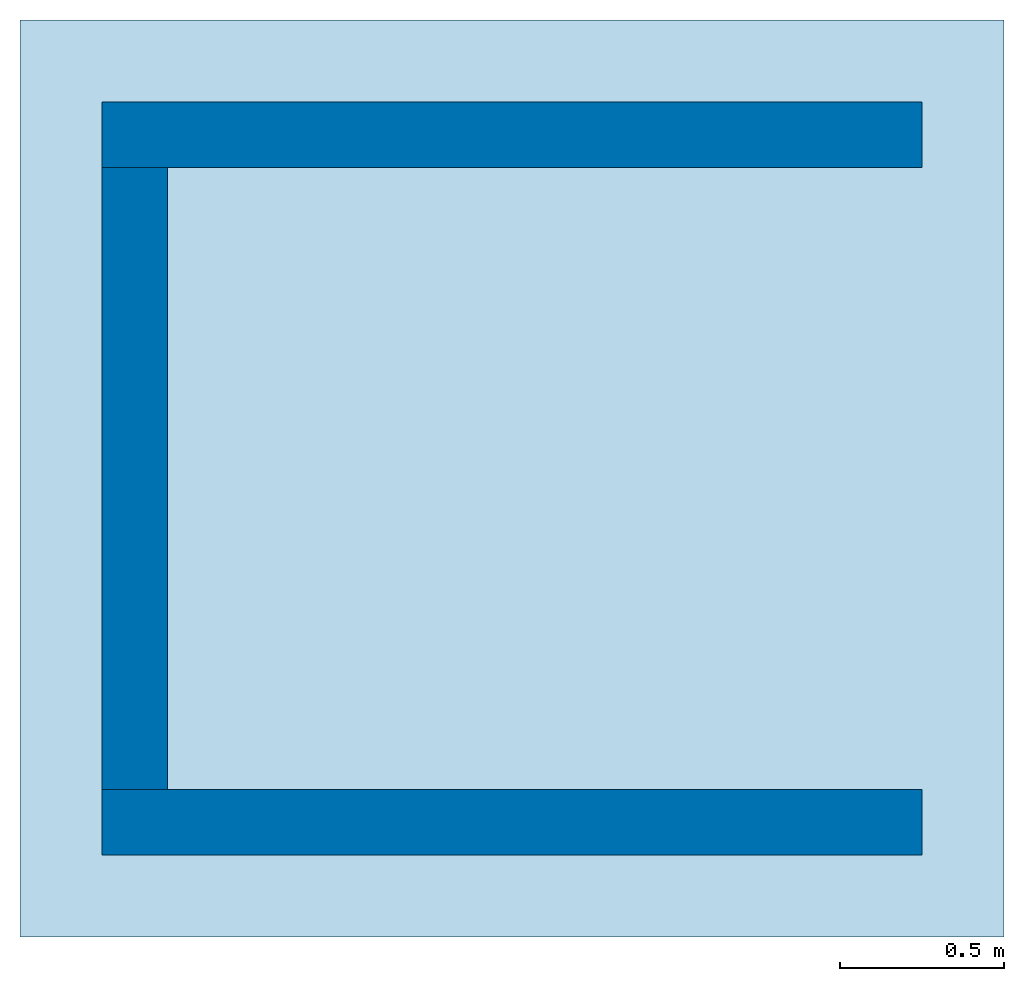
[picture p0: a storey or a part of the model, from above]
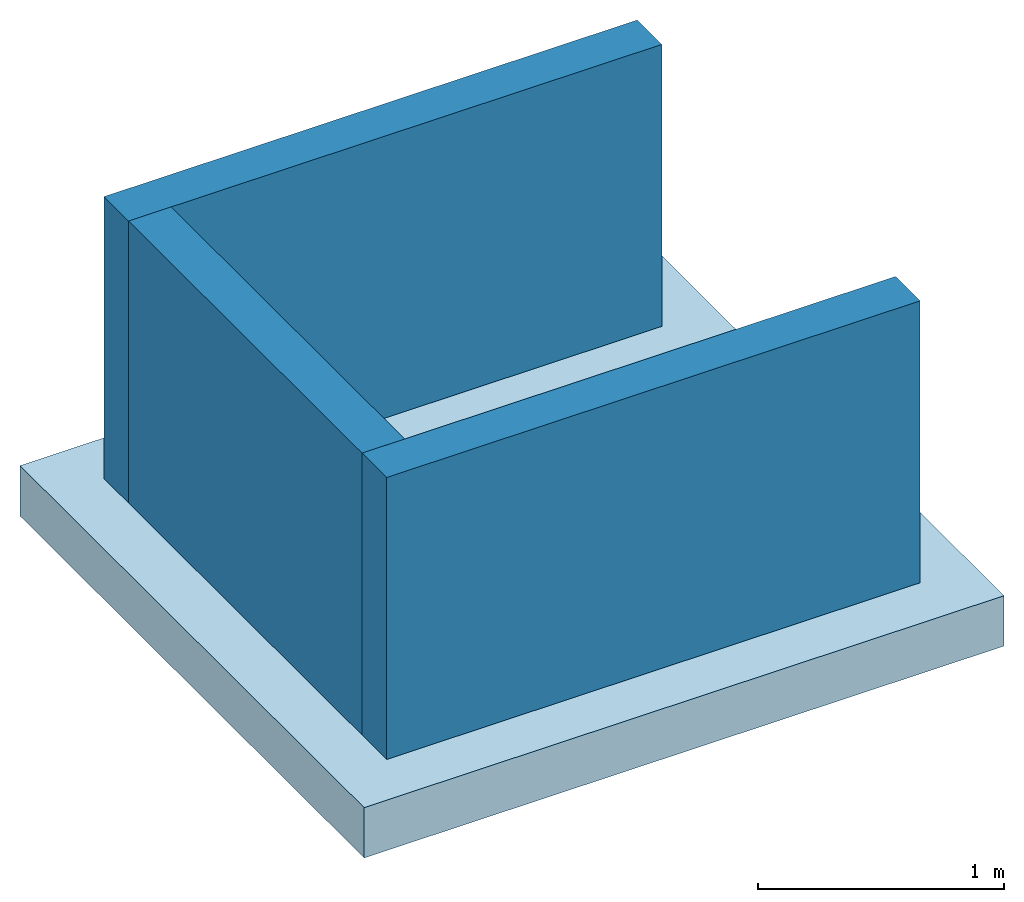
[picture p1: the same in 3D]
Properties of the parts of a building model (IFC4X3_ADD2), part 21 of 28

# IfcWall: BB_Metselwerk_Betonsteen 190 (122)
Name (Basic Wall:...) | In | Base Offset | Top Offset | Base Constraint | Top Constraint | Keynote | GVH_artnr 01 | GVH_artnr 02 = GVH_artnr 03 = GVH_artnr 04 = GVH_artnr 05 = GVH_artnr 06 | TDS_link | BB_Element_Lokaalnummer01 | Name = Pset_EnvironmentalImpactIndicators, Reference = Pset_WallCommon, Reference | Length | NetVolume | Height | GrossFootprintArea | GrossVolume | GrossSideArea | NetSideArea | ThermalTransmittance | LoadBearing
BB_03.09.24#05_Wand uit metselwerk_EI60, 190 mm:25514036 | 000 | -200 | -460 | 000 | Up to level: 010 | 03.09.24#05 | 03.09.24#05 | geen waarde gevonden | .\05 As Builtdossier\2. Bouwkunde\2.1 Architectuur\2.1.3 open ruwbouw\TF S 4.2.1.1.1 A-volle betonstenen.pdf | K.00.G17 | BB_03.09.24#05_Wand uit metselwerk_EI60, 190 mm | 3505 | 2.22427 | 3340 | 0.66595 | 2.22427 | 11.7067 | 11.7067 | 6.26316 | no | Pset_WallCommon - FireRating: EI60
BB_03.09.24#05_Wand uit metselwerk_EI60, 190 mm:25517511 | 000 | -80 | -1440 | 000 | Up to level: 010 | 03.09.24#05 | 03.09.24#05 | geen waarde gevonden | .\05 As Builtdossier\2. Bouwkunde\2.1 Architectuur\2.1.3 open ruwbouw\TF S 4.2.1.1.1 A-volle betonstenen.pdf | K.00.G15 | BB_03.09.24#05_Wand uit metselwerk_EI60, 190 mm | 910 | 0.387296 | 2240 | 0.1729 | 0.387296 | 2.0384 | 2.0384 | 6.26316 | no
BB_03.09.24#03_Wand uit metselwerk, 190 mm:34055758 | 000 | -400 | -600 | 000 | Up to level: 010 | 03.09.24#03 |  |  | .\05 As Builtdossier\2. Bouwkunde\2.1 Architectuur\2.1.3 open ruwbouw\TF S 4.2.1.1.1 A-volle betonstenen.pdf |  | BB_03.09.24#03_Wand uit metselwerk, 190 mm | 486.091 | 0.252645 | 3400 | 0.0743073 | 0.314015 | 1.65271 | 1.65271 | 6.26316 | yes | Pset_WallCommon - FireRating: EI60
BB_03.09.24#03_Wand uit metselwerk, 190 mm:34055762 | 000 | -400 | -600 | 000 | Up to level: 010 | 03.09.24#03 |  |  | .\05 As Builtdossier\2. Bouwkunde\2.1 Architectuur\2.1.3 open ruwbouw\TF S 4.2.1.1.1 A-volle betonstenen.pdf |  | BB_03.09.24#03_Wand uit metselwerk, 190 mm | 735.472 | 0.413745 | 3400 | 0.12169 | 0.475115 | 2.50061 | 2.50061 | 6.26316 | yes | Pset_WallCommon - FireRating: EI60
BB_03.09.24#05_Wand uit metselwerk_EI60, 190 mm:34140393 | 000 | -400 | 2800 | 000 | Up to level: 000 | 03.09.24#05 | 03.09.24#05 | geen waarde gevonden |  | K.-1.310 | BB_03.09.24#05_Wand uit metselwerk_EI60, 190 mm | 3886.43 | 2.24135 | 3200 | 0.738421 | 2.30633 | 12.1386 | 12.1386 |  | no | Pset_WallCommon - FireRating: EI60
BB_03.09.24#05_Wand uit metselwerk_EI60, 190 mm:34141487 | 000 | -400 | 2670 | 000 | Up to level: 000 | 03.09.24#05 | 03.09.24#05 | geen waarde gevonden | .\05 As Builtdossier\2. Bouwkunde\2.1 Architectuur\2.1.3 open ruwbouw\TF S 4.2.1.1.1 A-volle betonstenen.pdf | K.-1.310 | BB_03.09.24#05_Wand uit metselwerk_EI60, 190 mm | 250 | 0.145825 | 3070 | 0.0475 | 0.145825 | 0.7675 | 0.7675 | 6.26316 | no
BB_03.09.24#05_Wand uit metselwerk_EI60, 190 mm:34141603 | 000 | -400 | 2670 | 000 | Up to level: 000 | 03.09.24#05 |  |  | .\05 As Builtdossier\2. Bouwkunde\2.1 Architectuur\2.1.3 open ruwbouw\TF S 4.2.1.1.1 A-volle betonstenen.pdf |  | BB_03.09.24#05_Wand uit metselwerk_EI60, 190 mm | 270.001 | 0.157492 | 3070 | 0.0513002 | 0.157492 | 0.828903 | 0.828903 | 6.26316 | no
BB_03.09.24#05_Wand uit metselwerk_EI60, 190 mm:34142166 | 000 | -400 | 2800 | 000 | Up to level: 000 | 03.09.24#05 | 03.09.24#05 | geen waarde gevonden | .\05 As Builtdossier\2. Bouwkunde\2.1 Architectuur\2.1.3 open ruwbouw\TF S 4.2.1.1.1 A-volle betonstenen.pdf | K.00.A1 | BB_03.09.24#05_Wand uit metselwerk_EI60, 190 mm | 3791.37 | 2.24739 | 3200 | 0.70231 | 2.30515 | 12.1324 | 12.1324 | 6.26316 | no | Pset_WallCommon - FireRating: EI60
BB_03.09.24#05_Wand uit metselwerk_EI60, 190 mm:34142207 | 000 | -400 | 2670 | 000 | Up to level: 000 | 03.09.24#05 | 03.09.24#05 | geen waarde gevonden | .\05 As Builtdossier\2. Bouwkunde\2.1 Architectuur\2.1.3 open ruwbouw\TF S 4.2.1.1.1 A-volle betonstenen.pdf | K.-1.310 | BB_03.09.24#05_Wand uit metselwerk_EI60, 190 mm | 254.992 | 0.148737 | 3070 | 0.0484485 | 0.148737 | 0.782826 | 0.782826 | 6.26316 | no
BB_03.09.24#05_Wand uit metselwerk_EI60, 190 mm:34142208 | 000 | -400 | 2670 | 000 | Up to level: 000 | 03.09.24#05 |  |  | .\05 As Builtdossier\2. Bouwkunde\2.1 Architectuur\2.1.3 open ruwbouw\TF S 4.2.1.1.1 A-volle betonstenen.pdf |  | BB_03.09.24#05_Wand uit metselwerk_EI60, 190 mm | 280 | 0.163319 | 3070 | 0.0531983 | 0.163324 | 0.8596 | 0.8596 | 6.26316 | no
BB_03.09.24#03_Wand uit metselwerk, 190 mm:4894773 | 010 | 80 | -920 | 010 | Up to level: 020 | 03.09.24#03 | 03.09.24#03 | geen waarde gevonden | .\05 As Builtdossier\2. Bouwkunde\2.1 Architectuur\2.1.3 open ruwbouw\TF S 4.2.1.1.1 A-volle betonstenen.pdf | K.10.T5 | BB_03.09.24#03_Wand uit metselwerk, 190 mm | 1890 | 0.93366 | 2600 | 0.3591 | 0.93366 | 4.914 | 4.914 | 6.26316 | no
BB_03.09.24#03_Wand uit metselwerk, 190 mm:4895037 | 010 | 80 | -920 | 010 | Up to level: 020 | 03.09.24#03 | 03.09.24#03 | geen waarde gevonden | .\05 As Builtdossier\2. Bouwkunde\2.1 Architectuur\2.1.3 open ruwbouw\TF S 4.2.1.1.1 A-volle betonstenen.pdf | K.10.G19 | BB_03.09.24#03_Wand uit metselwerk, 190 mm | 1890 | 0.93366 | 2600 | 0.3591 | 0.93366 | 4.914 | 4.914 | 6.26316 | no
BB_03.09.24#03_Wand uit metselwerk, 190 mm:4902473 | 010 | 840 | -920 | 010 | Up to level: 020 | 03.09.24#03 | 03.09.24#03 | geen waarde gevonden | .\05 As Builtdossier\2. Bouwkunde\2.1 Architectuur\2.1.3 open ruwbouw\TF S 4.2.1.1.1 A-volle betonstenen.pdf | K.10.301 | BB_03.09.24#03_Wand uit metselwerk, 190 mm | 1058.44 | 0.370032 | 1840 | 0.201104 | 0.066424 | 0.3496 | 1.95591 | 6.26316 | no
BB_03.09.24#03_Wand uit metselwerk, 190 mm:4902997 | 010 | 840 | -920 | 010 | Up to level: 020 | 03.09.24#03 | 03.09.24#03 | geen waarde gevonden | .\05 As Builtdossier\2. Bouwkunde\2.1 Architectuur\2.1.3 open ruwbouw\TF S 4.2.1.1.1 A-volle betonstenen.pdf | K.10.301 | BB_03.09.24#03_Wand uit metselwerk, 190 mm | 972.502 | 0.339987 | 1840 | 0.184775 | 0.066424 | 0.3496 | 1.79704 | 6.26316 | no
BB_03.09.24#05_Wand uit metselwerk_EI60, 190 mm:12998827 | 010 | -80 | 2590 | 010 | Up to level: 010 | 03.09.24#05 | 03.09.24#05 | geen waarde gevonden | .\05 As Builtdossier\2. Bouwkunde\2.1 Architectuur\2.1.3 open ruwbouw\TF S 4.2.1.1.1 A-volle betonstenen.pdf | K.10.G18 | BB_03.09.24#05_Wand uit metselwerk_EI60, 190 mm | 910 | 0.461643 | 2670 | 0.1729 | 0.461643 | 2.4297 | 2.4297 | 6.26316 | no
BB_03.09.24#03_Wand uit metselwerk, 190 mm:13000053 | 010 | 840 | -920 | 010 | Up to level: 020 | 03.09.24#03 | 03.09.24#03 | geen waarde gevonden | .\05 As Builtdossier\2. Bouwkunde\2.1 Architectuur\2.1.3 open ruwbouw\TF S 4.2.1.1.1 A-volle betonstenen.pdf | K.10.205 | BB_03.09.24#03_Wand uit metselwerk, 190 mm | 2850 | 0.99636 | 1840 | 0.5415 | 0.99636 | 5.244 | 5.244 | 6.26316 | no
BB_03.09.24#03_Wand uit metselwerk, 190 mm:13000054 | 010 | 840 | -920 | 010 | Up to level: 020 | 03.09.24#03 | 03.09.24#03 | geen waarde gevonden | .\05 As Builtdossier\2. Bouwkunde\2.1 Architectuur\2.1.3 open ruwbouw\TF S 4.2.1.1.1 A-volle betonstenen.pdf | K.10.403 | BB_03.09.24#03_Wand uit metselwerk, 190 mm | 2850 | 0.99636 | 1840 | 0.5415 | 0.99636 | 5.244 | 5.244 | 6.26316 | no
BB_03.09.24#05_Wand uit metselwerk_EI60, 190 mm:13000690 | 010 | -200 | -600 | 010 | Up to level: 020 | 03.09.24#05 | 03.09.24#05 | geen waarde gevonden | .\05 As Builtdossier\2. Bouwkunde\2.1 Architectuur\2.1.3 open ruwbouw\TF S 4.2.1.1.1 A-volle betonstenen.pdf | K.10.403 | BB_03.09.24#05_Wand uit metselwerk_EI60, 190 mm | 3035 | 1.83086 | 3200 | 0.57665 | 1.83086 | 9.63613 | 9.63613 | 6.26316 | no | Pset_WallCommon - FireRating: EI60
BB_03.09.24#03_Wand uit metselwerk, 190 mm:20744338 | 010 | -200 | 215 | 010 | Up to level: 010 | 03.09.24#03 | 03.09.24#03 | geen waarde gevonden | .\05 As Builtdossier\2. Bouwkunde\2.1 Architectuur\2.1.3 open ruwbouw\TF S 4.2.1.1.1 A-volle betonstenen.pdf | K.10.306 | BB_03.09.24#03_Wand uit metselwerk, 190 mm | 2130 | 0.16795 | 415 | 0.4047 | 0.16795 | 0.88395 | 0.88395 | 6.26316 | no | Pset_WallCommon - FireRating: EI60
BB_03.09.24#03_Wand uit metselwerk, 190 mm:20744468 | 010 | -200 | 215 | 010 | Up to level: 010 | 03.09.24#03 | 03.09.24#03 | geen waarde gevonden | .\05 As Builtdossier\2. Bouwkunde\2.1 Architectuur\2.1.3 open ruwbouw\TF S 4.2.1.1.1 A-volle betonstenen.pdf | K.10.307 | BB_03.09.24#03_Wand uit metselwerk, 190 mm | 2130 | 0.167951 | 415 | 0.4047 | 0.167951 | 0.88395 | 0.88395 | 6.26316 | no | Pset_WallCommon - FireRating: EI60
BB_03.09.24#03_Wand uit metselwerk, 190 mm:32852942 | 010 | -200 | -200 | 010 | Up to level: 020 | 03.09.24#03 | 03.09.24#03 | geen waarde gevonden | .\05 As Builtdossier\2. Bouwkunde\2.1 Architectuur\2.1.3 open ruwbouw\TF S 4.2.1.1.1 A-volle betonstenen.pdf |  | BB_03.09.24#03_Wand uit metselwerk, 190 mm | 1056.82 | 0.722861 | 3600 | 0.200795 | 0.722861 | 3.80453 | 3.80453 | 6.26316 | no | Pset_WallCommon - FireRating: EI60
BB_03.09.24#03_Wand uit metselwerk, 190 mm:34055768 | 010 | -200 | -600 | 010 | Up to level: 020 | 03.09.24#03 |  |  | .\05 As Builtdossier\2. Bouwkunde\2.1 Architectuur\2.1.3 open ruwbouw\TF S 4.2.1.1.1 A-volle betonstenen.pdf |  | BB_03.09.24#03_Wand uit metselwerk, 190 mm | 754.792 | 0.401153 | 3200 | 0.12536 | 0.458913 | 2.41533 | 2.41533 | 6.26316 | yes | Pset_WallCommon - FireRating: EI60
BB_03.09.24#03_Wand uit metselwerk, 190 mm:34055772 | 010 | -200 | -600 | 010 | Up to level: 020 | 03.09.24#03 |  |  | .\05 As Builtdossier\2. Bouwkunde\2.1 Architectuur\2.1.3 open ruwbouw\TF S 4.2.1.1.1 A-volle betonstenen.pdf |  | BB_03.09.24#03_Wand uit metselwerk, 190 mm | 744.644 | 0.394984 | 3200 | 0.123432 | 0.452744 | 2.38286 | 2.38286 | 6.26316 | yes | Pset_WallCommon - FireRating: EI60
BB_03.09.24#05_Wand uit metselwerk_EI60, 190 mm:34142167 | 010 | -200 | 2400 | 010 | Up to level: 010 | 03.09.24#05 | 03.09.24#05 | geen waarde gevonden | .\05 As Builtdossier\2. Bouwkunde\2.1 Architectuur\2.1.3 open ruwbouw\TF S 4.2.1.1.1 A-volle betonstenen.pdf | K.-1.310 | BB_03.09.24#05_Wand uit metselwerk_EI60, 190 mm | 3791.37 | 1.82601 | 2600 | 0.70231 | 1.87294 | 9.85756 | 9.85756 | 6.26316 | no | Pset_WallCommon - FireRating: EI60
BB_03.09.24#03_Wand uit metselwerk, 190 mm:4033302 | 020 | 840 | -920 | 020 | Up to level: 030 | 03.09.24#03 | 03.09.24#03 | geen waarde gevonden | .\05 As Builtdossier\2. Bouwkunde\2.1 Architectuur\2.1.3 open ruwbouw\TF S 4.2.1.1.1 A-volle betonstenen.pdf | K.20.303 | BB_03.09.24#03_Wand uit metselwerk, 190 mm | 1033.06 | 0.361159 | 1840 | 0.196282 | 0.066424 | 0.3496 | 1.90895 | 6.26316 | no
BB_03.09.24#03_Wand uit metselwerk, 190 mm:4894656 | 020 | 80 | -920 | 020 | Up to level: 030 | 03.09.24#03 | 03.09.24#03 | geen waarde gevonden | .\05 As Builtdossier\2. Bouwkunde\2.1 Architectuur\2.1.3 open ruwbouw\TF S 4.2.1.1.1 A-volle betonstenen.pdf | K.20.102 | BB_03.09.24#03_Wand uit metselwerk, 190 mm | 1890 | 0.93366 | 2600 | 0.3591 | 0.93366 | 4.914 | 4.914 | 6.26316 | no
BB_03.09.24#03_Wand uit metselwerk, 190 mm:4895035 | 020 | 80 | -920 | 020 | Up to level: 030 | 03.09.24#03 | 03.09.24#03 | geen waarde gevonden | .\05 As Builtdossier\2. Bouwkunde\2.1 Architectuur\2.1.3 open ruwbouw\TF S 4.2.1.1.1 A-volle betonstenen.pdf | K.20.511 | BB_03.09.24#03_Wand uit metselwerk, 190 mm | 1890 | 0.93366 | 2600 | 0.3591 | 0.93366 | 4.914 | 4.914 | 6.26316 | no
BB_03.09.24#05_Wand uit metselwerk_EI60, 190 mm:12562084 | 020 | -80 | 2070 | 020 | Up to level: 020 | 03.09.24#05 | 03.09.24#05 | geen waarde gevonden | .\05 As Builtdossier\2. Bouwkunde\2.1 Architectuur\2.1.3 open ruwbouw\TF S 4.2.1.1.1 A-volle betonstenen.pdf | K.20.G18 | BB_03.09.24#05_Wand uit metselwerk_EI60, 190 mm | 920 | 0.37582 | 2150 | 0.1748 | 0.37582 | 1.978 | 1.978 | 6.26316 | no
BB_03.09.24#03_Wand uit metselwerk, 190 mm:12563554 | 020 | 840 | -920 | 020 | Up to level: 030 | 03.09.24#03 | 03.09.24#03 | geen waarde gevonden | .\05 As Builtdossier\2. Bouwkunde\2.1 Architectuur\2.1.3 open ruwbouw\TF S 4.2.1.1.1 A-volle betonstenen.pdf | K.20.204 | BB_03.09.24#03_Wand uit metselwerk, 190 mm | 2850 | 0.99636 | 1840 | 0.5415 | 0.99636 | 5.244 | 5.244 | 6.26316 | no
BB_03.09.24#03_Wand uit metselwerk, 190 mm:12563709 | 020 | 840 | -920 | 020 | Up to level: 030 | 03.09.24#03 | 03.09.24#03 | geen waarde gevonden | .\05 As Builtdossier\2. Bouwkunde\2.1 Architectuur\2.1.3 open ruwbouw\TF S 4.2.1.1.1 A-volle betonstenen.pdf | K.20.403 | BB_03.09.24#03_Wand uit metselwerk, 190 mm | 2850 | 0.99636 | 1840 | 0.5415 | 0.99636 | 5.244 | 5.244 | 6.26316 | no
BB_03.09.24#05_Wand uit metselwerk_EI60, 190 mm:12566186 | 020 | -200 | -460 | 020 | Up to level: 030 | 03.09.24#05 | 03.09.24#05 | geen waarde gevonden | .\05 As Builtdossier\2. Bouwkunde\2.1 Architectuur\2.1.3 open ruwbouw\TF S 4.2.1.1.1 A-volle betonstenen.pdf | K.20.403 | BB_03.09.24#05_Wand uit metselwerk_EI60, 190 mm | 3035 | 1.91159 | 3340 | 0.57665 | 1.91159 | 10.061 | 10.061 | 6.26316 | no | Pset_WallCommon - FireRating: EI60
BB_03.09.24#03_Wand uit metselwerk, 190 mm:15430763 | 020 | 840 | -920 | 020 | Up to level: 030 | 03.09.24#03 | 03.09.24#03 | geen waarde gevonden | .\05 As Builtdossier\2. Bouwkunde\2.1 Architectuur\2.1.3 open ruwbouw\TF S 4.2.1.1.1 A-volle betonstenen.pdf | K.20.303 | BB_03.09.24#03_Wand uit metselwerk, 190 mm | 1085.82 | 0.379602 | 1840 | 0.206305 | 0.066424 | 0.3496 | 2.00643 | 6.26316 | no
BB_03.09.24#05_Wand uit metselwerk_EI60, 190 mm:15952174 | 020 | -200 | 840 | 020 | Up to level: 020 | 03.09.24#05 | 03.09.24#05 | geen waarde gevonden | .\05 As Builtdossier\2. Bouwkunde\2.1 Architectuur\2.1.3 open ruwbouw\TF S 4.2.1.1.1 A-volle betonstenen.pdf | K.20.G19 | BB_03.09.24#05_Wand uit metselwerk_EI60, 190 mm | 5815 | 1.14904 | 1040 | 1.10485 | 1.14904 | 6.0476 | 6.0476 | 6.26316 | no
BB_03.09.24#03_Wand uit metselwerk, 190 mm:32852945 | 020 | -200 | -350 | 020 | Up to level: 030 | 03.09.24#03 | 03.09.24#03 | geen waarde gevonden | .\05 As Builtdossier\2. Bouwkunde\2.1 Architectuur\2.1.3 open ruwbouw\TF S 4.2.1.1.1 A-volle betonstenen.pdf |  | BB_03.09.24#03_Wand uit metselwerk, 190 mm | 892.821 | 0.564575 | 3450 | 0.163645 | 0.585244 | 3.08023 | 3.08023 | 6.26316 | no | Pset_WallCommon - FireRating: EI60
BB_03.09.24#03_Wand uit metselwerk, 190 mm:34055778 | 020 | -200 | -600 | 020 | Up to level: 030 | 03.09.24#03 |  |  | .\05 As Builtdossier\2. Bouwkunde\2.1 Architectuur\2.1.3 open ruwbouw\TF S 4.2.1.1.1 A-volle betonstenen.pdf |  | BB_03.09.24#03_Wand uit metselwerk, 190 mm | 754.792 | 0.401153 | 3200 | 0.12536 | 0.458913 | 2.41533 | 2.41533 | 6.26316 | yes | Pset_WallCommon - FireRating: EI60
BB_03.09.24#03_Wand uit metselwerk, 190 mm:34055782 | 020 | -200 | -600 | 020 | Up to level: 030 | 03.09.24#03 |  |  | .\05 As Builtdossier\2. Bouwkunde\2.1 Architectuur\2.1.3 open ruwbouw\TF S 4.2.1.1.1 A-volle betonstenen.pdf |  | BB_03.09.24#03_Wand uit metselwerk, 190 mm | 744.644 | 0.394984 | 3200 | 0.123432 | 0.452744 | 2.38286 | 2.38286 | 6.26316 | yes | Pset_WallCommon - FireRating: EI60
BB_03.09.24#05_Wand uit metselwerk_EI60, 190 mm:34140642 | 020 | -200 | 3000 | 020 | Up to level: 020 | 03.09.24#05 | 03.09.24#05 | geen waarde gevonden | .\05 As Builtdossier\2. Bouwkunde\2.1 Architectuur\2.1.3 open ruwbouw\TF S 4.2.1.1.1 A-volle betonstenen.pdf | K.-1.310 | BB_03.09.24#05_Wand uit metselwerk_EI60, 190 mm | 6420.51 | 3.84591 | 3200 | 1.20185 | 3.90367 | 20.5456 | 20.5456 | 6.26316 | no
BB_03.09.24#05_Wand uit metselwerk_EI60, 190 mm:34141327 | 020 | -200 | 3000 | 020 | Up to level: 020 | 03.09.24#05 | 03.09.24#05 | geen waarde gevonden | .\05 As Builtdossier\2. Bouwkunde\2.1 Architectuur\2.1.3 open ruwbouw\TF S 4.2.1.1.1 A-volle betonstenen.pdf | K.-1.310 | BB_03.09.24#05_Wand uit metselwerk_EI60, 190 mm | 6421.36 | 3.84643 | 3200 | 1.20201 | 3.90419 | 20.5484 | 20.5484 | 6.26316 | no | Pset_WallCommon - FireRating: EI60
BB_03.09.24#03_Wand uit metselwerk, 190 mm:4894776 | 030 | 80 | -920 | 030 | Up to level: 040 | 03.09.24#03 | 03.09.24#03 | geen waarde gevonden | .\05 As Builtdossier\2. Bouwkunde\2.1 Architectuur\2.1.3 open ruwbouw\TF S 4.2.1.1.1 A-volle betonstenen.pdf | Z gevel | BB_03.09.24#03_Wand uit metselwerk, 190 mm | 1890 | 0.93366 | 2600 | 0.3591 | 0.93366 | 4.914 | 4.914 | 6.26316 | no
BB_03.09.24#03_Wand uit metselwerk, 190 mm:4895038 | 030 | 80 | -920 | 030 | Up to level: 040 | 03.09.24#03 | 03.09.24#03 | geen waarde gevonden | .\05 As Builtdossier\2. Bouwkunde\2.1 Architectuur\2.1.3 open ruwbouw\TF S 4.2.1.1.1 A-volle betonstenen.pdf | Z gevel | BB_03.09.24#03_Wand uit metselwerk, 190 mm | 1890 | 0.93366 | 2600 | 0.3591 | 0.93366 | 4.914 | 4.914 | 6.26316 | no
BB_03.09.24#03_Wand uit metselwerk, 190 mm:7214976 | 030 | -200 | 0 | 030 |  | 03.09.24#03 | 03.09.24#03 | geen waarde gevonden | .\05 As Builtdossier\2. Bouwkunde\2.1 Architectuur\2.1.3 open ruwbouw\TF S 4.2.1.1.1 A-volle betonstenen.pdf | NO gevel | BB_03.09.24#03_Wand uit metselwerk, 190 mm | 900 | 0.16074 | 940 | 0.171 | 0.16074 | 0.846 | 0.846 | 6.26316 | no
BB_03.09.24#03_Wand uit metselwerk, 190 mm:7215093 | 030 | -200 | 0 | 030 |  | 03.09.24#03 | 03.09.24#03 | geen waarde gevonden | .\05 As Builtdossier\2. Bouwkunde\2.1 Architectuur\2.1.3 open ruwbouw\TF S 4.2.1.1.1 A-volle betonstenen.pdf | NO gevel | BB_03.09.24#03_Wand uit metselwerk, 190 mm | 710 | 0.126806 | 940 | 0.1349 | 0.126806 | 0.6674 | 0.6674 | 6.26316 | no
BB_03.09.24#03_Wand uit metselwerk, 190 mm:8024645 | 030 | 840 | -920 | 030 | Up to level: 040 | 03.09.24#03 | 03.09.24#03 | geen waarde gevonden | .\05 As Builtdossier\2. Bouwkunde\2.1 Architectuur\2.1.3 open ruwbouw\TF S 4.2.1.1.1 A-volle betonstenen.pdf | N gevel | BB_03.09.24#03_Wand uit metselwerk, 190 mm | 305 | 0.106628 | 1840 | 0.05795 | 0.106628 | 0.5612 | 0.5612 | 6.26316 | no
BB_03.09.24#03_Wand uit metselwerk, 190 mm:8024647 | 030 | 840 | -920 | 030 | Up to level: 040 | 03.09.24#03 | 03.09.24#03 | geen waarde gevonden | .\05 As Builtdossier\2. Bouwkunde\2.1 Architectuur\2.1.3 open ruwbouw\TF S 4.2.1.1.1 A-volle betonstenen.pdf | N gevel | BB_03.09.24#03_Wand uit metselwerk, 190 mm | 305 | 0.106628 | 1840 | 0.05795 | 0.106628 | 0.5612 | 0.5612 | 6.26316 | no
BB_03.09.24#03_Wand uit metselwerk, 190 mm:8684830 | 030 | -200 | 0 | 030 |  | 03.09.24#03 | 03.09.24#03 | geen waarde gevonden | .\05 As Builtdossier\2. Bouwkunde\2.1 Architectuur\2.1.3 open ruwbouw\TF S 4.2.1.1.1 A-volle betonstenen.pdf | NW gevel | BB_03.09.24#03_Wand uit metselwerk, 190 mm | 900 | 0.16074 | 940 | 0.171 | 0.16074 | 0.846 | 0.846 | 6.26316 | no
BB_03.09.24#03_Wand uit metselwerk, 190 mm:8684832 | 030 | -200 | 0 | 030 |  | 03.09.24#03 | 03.09.24#03 | geen waarde gevonden | .\05 As Builtdossier\2. Bouwkunde\2.1 Architectuur\2.1.3 open ruwbouw\TF S 4.2.1.1.1 A-volle betonstenen.pdf | NW gevel | BB_03.09.24#03_Wand uit metselwerk, 190 mm | 710 | 0.126806 | 940 | 0.1349 | 0.126806 | 0.6674 | 0.6674 | 6.26316 | no
BB_03.09.24#03_Wand uit metselwerk, 190 mm:12546161 | 030 | 840 | -920 | 030 | Up to level: 040 | 03.09.24#03 | 03.09.24#03 | geen waarde gevonden | .\05 As Builtdossier\2. Bouwkunde\2.1 Architectuur\2.1.3 open ruwbouw\TF S 4.2.1.1.1 A-volle betonstenen.pdf | Z gevel | BB_03.09.24#03_Wand uit metselwerk, 190 mm | 1331.36 | 0.465443 | 1840 | 0.252958 | 0.465443 | 2.4497 | 2.4497 | 6.26316 | no
BB_03.09.24#03_Wand uit metselwerk, 190 mm:12546270 | 030 | 840 | -920 | 030 | Up to level: 040 | 03.09.24#03 | 03.09.24#03 | geen waarde gevonden | .\05 As Builtdossier\2. Bouwkunde\2.1 Architectuur\2.1.3 open ruwbouw\TF S 4.2.1.1.1 A-volle betonstenen.pdf | Z gevel | BB_03.09.24#03_Wand uit metselwerk, 190 mm | 1331 | 0.465318 | 1840 | 0.25289 | 0.465318 | 2.44904 | 2.44904 | 6.26316 | no
BB_03.09.24#05_Wand uit metselwerk_EI60, 190 mm:12549238 | 030 | -80 | 2070 | 030 | Up to level: 030 | 03.09.24#05 | 03.09.24#05 | geen waarde gevonden | .\05 As Builtdossier\2. Bouwkunde\2.1 Architectuur\2.1.3 open ruwbouw\TF S 4.2.1.1.1 A-volle betonstenen.pdf | K.30.G18 | BB_03.09.24#05_Wand uit metselwerk_EI60, 190 mm | 920 | 0.37582 | 2150 | 0.1748 | 0.37582 | 1.978 | 1.978 | 6.26316 | no
BB_03.09.24#03_Wand uit metselwerk, 190 mm:12549646 | 030 | -80 | 3190 | 030 | Up to level: 030 | 03.09.24#03 | 03.09.24#03 | geen waarde gevonden | .\05 As Builtdossier\2. Bouwkunde\2.1 Architectuur\2.1.3 open ruwbouw\TF S 4.2.1.1.1 A-volle betonstenen.pdf | K.30.108 | BB_03.09.24#03_Wand uit metselwerk, 190 mm | 990 | 0.615087 | 3270 | 0.1881 | 0.615087 | 3.2373 | 3.2373 | 6.26316 | no
BB_03.09.24#04_Wand uit metselwerk_vol, 190 mm:12549899 | 030 | -80 | 3190 | 030 | Up to level: 030 | 03.09.24#04 | 03.09.24#04 | geen waarde gevonden | .\05 As Builtdossier\2. Bouwkunde\2.1 Architectuur\2.1.3 open ruwbouw\TF S 4.2.1.1.1 A-volle betonstenen.pdf | K.30.S22 | BB_03.09.24#04_Wand uit metselwerk_vol, 190 mm | 1710 | 1.06242 | 3270 | 0.3249 | 1.06242 | 5.5917 | 5.5917 | 6.26316 | no
BB_03.09.24#05_Wand uit metselwerk_EI60, 190 mm:12555098 | 030 | -200 | 3190 | 030 | Up to level: 030 | 03.09.24#05 | 03.09.24#05 | geen waarde gevonden | .\05 As Builtdossier\2. Bouwkunde\2.1 Architectuur\2.1.3 open ruwbouw\TF S 4.2.1.1.1 A-volle betonstenen.pdf | K.30.401 | BB_03.09.24#05_Wand uit metselwerk_EI60, 190 mm | 1570 | 0.604 | 3390 | 0.2983 | 1.01124 | 5.3223 | 3.17895 | 6.26316 | no | Pset_WallCommon - FireRating: EI60
BB_03.09.24#03_Wand uit metselwerk, 190 mm:12555581 | 030 | -200 | 2680 | 030 | Up to level: 030 | 03.09.24#03 | 03.09.24#03 | geen waarde gevonden | .\05 As Builtdossier\2. Bouwkunde\2.1 Architectuur\2.1.3 open ruwbouw\TF S 4.2.1.1.1 A-volle betonstenen.pdf | N gevel | BB_03.09.24#03_Wand uit metselwerk, 190 mm | 1890 | 0.668107 | 2880 | 0.3591 | 1.03421 | 5.4432 | 3.51635 | 6.26316 | no
BB_03.09.24#03_Wand uit metselwerk, 190 mm:34061437 | 030 | -200 | -600 | 030 | Up to level: 040 | 03.09.24#03 |  |  | .\05 As Builtdossier\2. Bouwkunde\2.1 Architectuur\2.1.3 open ruwbouw\TF S 4.2.1.1.1 A-volle betonstenen.pdf |  | BB_03.09.24#03_Wand uit metselwerk, 190 mm | 754.792 | 0.401153 | 3200 | 0.12536 | 0.458913 | 2.41533 | 2.41533 | 6.26316 | yes | Pset_WallCommon - FireRating: EI60
BB_03.09.24#03_Wand uit metselwerk, 190 mm:34061441 | 030 | -200 | -600 | 030 | Up to level: 040 | 03.09.24#03 |  |  | .\05 As Builtdossier\2. Bouwkunde\2.1 Architectuur\2.1.3 open ruwbouw\TF S 4.2.1.1.1 A-volle betonstenen.pdf |  | BB_03.09.24#03_Wand uit metselwerk, 190 mm | 744.644 | 0.394984 | 3200 | 0.123432 | 0.452744 | 2.38286 | 2.38286 | 6.26316 | yes | Pset_WallCommon - FireRating: EI60
BB_03.09.24#05_Wand uit metselwerk_EI60, 190 mm:34141335 | 030 | -200 | 3000 | 030 | Up to level: 030 | 03.09.24#05 | 03.09.24#05 | geen waarde gevonden | .\05 As Builtdossier\2. Bouwkunde\2.1 Architectuur\2.1.3 open ruwbouw\TF S 4.2.1.1.1 A-volle betonstenen.pdf | K.-1.310 | BB_03.09.24#05_Wand uit metselwerk_EI60, 190 mm | 6420.51 | 3.84591 | 3200 | 1.20185 | 3.90367 | 20.5456 | 20.5456 | 6.26316 | no | Pset_WallCommon - FireRating: EI60
BB_03.09.24#05_Wand uit metselwerk_EI60, 190 mm:34141336 | 030 | -200 | 3000 | 030 | Up to level: 030 | 03.09.24#05 | 03.09.24#05 | geen waarde gevonden | .\05 As Builtdossier\2. Bouwkunde\2.1 Architectuur\2.1.3 open ruwbouw\TF S 4.2.1.1.1 A-volle betonstenen.pdf | K.-1.310 | BB_03.09.24#05_Wand uit metselwerk_EI60, 190 mm | 6421.36 | 3.84643 | 3200 | 1.20201 | 3.90419 | 20.5484 | 20.5484 | 6.26316 | no | Pset_WallCommon - FireRating: EI60
BB_03.09.24#03_Wand uit metselwerk, 190 mm:27880774 | 040 | -200 | 300 | 040 | Up to level: 040 | 03.09.24#03 | 03.09.24#03 | geen waarde gevonden | .\05 As Builtdossier\2. Bouwkunde\2.1 Architectuur\2.1.3 open ruwbouw\TF S 4.2.1.1.1 A-volle betonstenen.pdf | K.40.G11 | BB_03.09.24#03_Wand uit metselwerk, 190 mm | 1830 | 0.17385 | 500 | 0.3477 | 0.17385 | 0.915 | 0.915 | 6.26316 | no
BB_03.09.24#05_Wand uit metselwerk_EI60, 190 mm:33183839 | 040 | -200 | -250 | 040 | Up to level: 050 | 03.09.24#05 | 03.09.24#05 | geen waarde gevonden | .\05 As Builtdossier\2. Bouwkunde\2.1 Architectuur\2.1.3 open ruwbouw\TF S 4.2.1.1.1 A-volle betonstenen.pdf |  | BB_03.09.24#05_Wand uit metselwerk_EI60, 190 mm | 1400 | 0.6916 | 2600 | 0.266 | 0.6916 | 3.64 | 3.64 | 6.26316 | no
BB_03.09.24#05_Wand uit metselwerk_EI60, 190 mm:33183874 | 040 | -200 | -250 | 040 | Up to level: 050 | 03.09.24#05 | 03.09.24#05 | geen waarde gevonden | .\05 As Builtdossier\2. Bouwkunde\2.1 Architectuur\2.1.3 open ruwbouw\TF S 4.2.1.1.1 A-volle betonstenen.pdf |  | BB_03.09.24#05_Wand uit metselwerk_EI60, 190 mm | 1524.99 | 0.753344 | 2600 | 0.289748 | 0.753344 | 3.96497 | 3.96497 | 6.26316 | no
BB_03.09.24#05_Wand uit metselwerk_EI60, 190 mm:33183915 | 040 | -200 | -250 | 040 | Up to level: 050 | 03.09.24#05 | 03.09.24#05 | geen waarde gevonden | .\05 As Builtdossier\2. Bouwkunde\2.1 Architectuur\2.1.3 open ruwbouw\TF S 4.2.1.1.1 A-volle betonstenen.pdf |  | BB_03.09.24#05_Wand uit metselwerk_EI60, 190 mm | 1210 | 0.59774 | 2600 | 0.2299 | 0.59774 | 3.146 | 3.146 | 6.26316 | no
BB_03.09.24#03_Wand uit metselwerk, 190 mm:34084348 | 040 | -200 | -1400 | 040 | Up to level: 050 | 03.09.24#03 |  |  | .\05 As Builtdossier\2. Bouwkunde\2.1 Architectuur\2.1.3 open ruwbouw\TF S 4.2.1.1.1 A-volle betonstenen.pdf |  | BB_03.09.24#03_Wand uit metselwerk, 190 mm | 754.792 | 0.181773 | 1450 | 0.12536 | 0.207945 | 1.09445 | 1.09445 | 6.26316 | yes | Pset_WallCommon - FireRating: EI60
BB_03.09.24#03_Wand uit metselwerk, 190 mm:34084352 | 040 | -200 | -1400 | 040 | Up to level: 050 | 03.09.24#03 |  |  | .\05 As Builtdossier\2. Bouwkunde\2.1 Architectuur\2.1.3 open ruwbouw\TF S 4.2.1.1.1 A-volle betonstenen.pdf |  | BB_03.09.24#03_Wand uit metselwerk, 190 mm | 744.644 | 0.178977 | 1450 | 0.123432 | 0.205149 | 1.07973 | 1.07973 | 6.26316 | yes | Pset_WallCommon - FireRating: EI60
BB_03.09.24#03_Wand uit metselwerk, 190 mm:10440258 | 050 | -250 | 0 | 050 |  | 03.09.24#03 | 03.09.24#03 | geen waarde gevonden | .\05 As Builtdossier\2. Bouwkunde\2.1 Architectuur\2.1.3 open ruwbouw\TF S 4.2.1.1.1 A-volle betonstenen.pdf | N gevel | BB_03.09.24#03_Wand uit metselwerk, 190 mm | 6870 | 0.665703 | 510 | 1.3053 | 0.665703 | 3.5037 | 3.5037 | 6.26316 | no
BB_03.09.24#03_Wand uit metselwerk, 190 mm:10443776 | 050 | -50 | 0 | 050 |  | 03.09.24#03 | 03.09.24#03 | geen waarde gevonden | .\05 As Builtdossier\2. Bouwkunde\2.1 Architectuur\2.1.3 open ruwbouw\TF S 4.2.1.1.1 A-volle betonstenen.pdf | Z gevel | BB_03.09.24#03_Wand uit metselwerk, 190 mm | 5500 | 0.32395 | 310 | 1.045 | 0.32395 | 1.705 | 1.705 | 6.26316 | no
BB_03.09.24#03_Wand uit metselwerk, 190 mm:10443835 | 050 | -50 | 0 | 050 |  | 03.09.24#03 | 03.09.24#03 | geen waarde gevonden | .\05 As Builtdossier\2. Bouwkunde\2.1 Architectuur\2.1.3 open ruwbouw\TF S 4.2.1.1.1 A-volle betonstenen.pdf | Z gevel | BB_03.09.24#03_Wand uit metselwerk, 190 mm | 5590 | 0.323655 | 310 | 1.04405 | 0.329251 | 1.7329 | 1.7329 | 6.26316 | no
BB_03.09.24#03_Wand uit metselwerk, 190 mm:10443912 | 050 | -50 | 0 | 050 |  | 03.09.24#03 | 03.09.24#03 | geen waarde gevonden | .\05 As Builtdossier\2. Bouwkunde\2.1 Architectuur\2.1.3 open ruwbouw\TF S 4.2.1.1.1 A-volle betonstenen.pdf | Z gevel | BB_03.09.24#03_Wand uit metselwerk, 190 mm | 10732 | 0.620926 | 310 | 2.00299 | 0.632117 | 3.32693 | 3.32693 | 6.26316 | no
BB_03.09.24#03_Wand uit metselwerk, 190 mm:10444068 | 050 | -50 | 0 | 050 |  | 03.09.24#03 | 03.09.24#03 | geen waarde gevonden | .\05 As Builtdossier\2. Bouwkunde\2.1 Architectuur\2.1.3 open ruwbouw\TF S 4.2.1.1.1 A-volle betonstenen.pdf | Z gevel | BB_03.09.24#03_Wand uit metselwerk, 190 mm | 5521.3 | 0.319609 | 310 | 1.031 | 0.325205 | 1.7116 | 1.7116 | 6.26316 | no
BB_03.09.24#03_Wand uit metselwerk, 190 mm:10444165 | 050 | -50 | 0 | 050 |  | 03.09.24#03 | 03.09.24#03 | geen waarde gevonden | .\05 As Builtdossier\2. Bouwkunde\2.1 Architectuur\2.1.3 open ruwbouw\TF S 4.2.1.1.1 A-volle betonstenen.pdf | Z gevel | BB_03.09.24#03_Wand uit metselwerk, 190 mm | 5500 | 0.32395 | 310 | 1.045 | 0.32395 | 1.705 | 1.705 | 6.26316 | no
BB_03.09.24#03_Wand uit metselwerk, 190 mm:10444228 | 050 | -50 | 0 | 050 |  | 03.09.24#03 | 03.09.24#03 | geen waarde gevonden | .\05 As Builtdossier\2. Bouwkunde\2.1 Architectuur\2.1.3 open ruwbouw\TF S 4.2.1.1.1 A-volle betonstenen.pdf | Z gevel | BB_03.09.24#03_Wand uit metselwerk, 190 mm | 2655 | 0.15638 | 310 | 0.50445 | 0.15638 | 0.82305 | 0.82305 | 6.26316 | no
BB_03.09.24#03_Wand uit metselwerk, 190 mm:19905593 | 050 | -250 | 0 | 050 |  | 03.09.24#03 | 03.09.24#03 | geen waarde gevonden | .\05 As Builtdossier\2. Bouwkunde\2.1 Architectuur\2.1.3 open ruwbouw\TF S 4.2.1.1.1 A-volle betonstenen.pdf | N gevel | BB_03.09.24#03_Wand uit metselwerk, 190 mm | 2075.03 | 0.20107 | 510 | 0.394255 | 0.20107 | 1.05826 | 1.05826 | 6.26316 | no
BB_03.09.24#03_Wand uit metselwerk, 190 mm:19905716 | 050 | -250 | 0 | 050 |  | 03.09.24#03 | 03.09.24#03 | geen waarde gevonden | .\05 As Builtdossier\2. Bouwkunde\2.1 Architectuur\2.1.3 open ruwbouw\TF S 4.2.1.1.1 A-volle betonstenen.pdf | N gevel | BB_03.09.24#03_Wand uit metselwerk, 190 mm | 2075.03 | 0.20107 | 510 | 0.394255 | 0.20107 | 1.05826 | 1.05826 | 6.26316 | no

# IfcWall: BB_Metselwerk_Betonsteen 60 (2)
In: K10
Type - Material: BB_Metselwerk_Betonsteen
PredefinedType: SOLIDWALL
Cpset_Wall - LevelOfAccuracy: in te vullen door Buildwise
IfcBuildingStorey - Base Offset: 0; Top Offset: 2150; Base Constraint: K10; Top Constraint: Up to level: K10
IfcClassificationReference - Keynote: 03.09.24#05; GVH_artnr 01: 03.09.24#05; GVH_artnr 02: geen waarde gevonden; GVH_artnr 03: geen waarde gevonden; GVH_artnr 04: geen waarde gevonden; GVH_artnr 05: geen waarde gevonden; GVH_artnr 06: geen waarde gevonden; TDS_link: .\05 As Builtdossier\2. Bouwkunde\2.1 Architectuur\2.1.3 open ruwbouw\TF S 4.2.1.1.1 A-volle betonstenen.pdf
IfcElement - BB_Element_Lokaalnummer01: K.-1.K12
IfcRoot - Name: BB_03.09.24#05_Wand uit metselwerk_EI60, 190 mm
Qto_WallBaseQuantities - Length: 60; NetVolume: 0.02451; Height: 2150; Width: 190; GrossFootprintArea: 0.0114; GrossVolume: 0.077615; GrossSideArea: 0.4085; NetSideArea: 0.4085
Pset_Condition - AssessmentCondition: Empty
Pset_EnvironmentalImpactIndicators - Reference: BB_03.09.24#05_Wand uit metselwerk_EI60, 190 mm; sets with these values: 2
Pset_WallCommon - Reference: BB_03.09.24#05_Wand uit metselwerk_EI60, 190 mm; FireRating: EI60; ThermalTransmittance: 6.26316; IsExternal: yes; LoadBearing: no; ExtendToStructure: no
Name (Basic Wall:BB_03.09.24#05_Wand uit metselwerk_EI60, 190 mm:...)
20053292
20053350

# IfcWall: BB_Metselwerk_Betonsteen 70 (2)
Type - Material: BB_Metselwerk_Betonsteen
PredefinedType: SOLIDWALL
Cpset_Wall - LevelOfAccuracy: in te vullen door Buildwise
IfcBuildingStorey - Base Offset: 0; Top Offset: 2440
IfcClassificationReference - Keynote: 03.09.24#01; GVH_artnr 01: 03.09.24#01; GVH_artnr 02: geen waarde gevonden; GVH_artnr 03: geen waarde gevonden; GVH_artnr 04: geen waarde gevonden; GVH_artnr 05: geen waarde gevonden; GVH_artnr 06: geen waarde gevonden; TDS_link: .\05 As Builtdossier\2. Bouwkunde\2.1 Architectuur\2.1.3 open ruwbouw\TF S 4.2.1.1.1 A-volle betonstenen.pdf
IfcRoot - Name: BB_03.09.24#01_Wand uit metselwerk, 70 mm
Qto_WallBaseQuantities - Length: 340; NetVolume: 0.058072; Height: 2440; Width: 70; GrossFootprintArea: 0.0238; GrossVolume: 0.058072; GrossSideArea: 0.8296; NetSideArea: 0.8296
Pset_Condition - AssessmentCondition: Empty
Pset_EnvironmentalImpactIndicators - Reference: BB_03.09.24#01_Wand uit metselwerk, 70 mm; sets with these values: 2
Pset_WallCommon - Reference: BB_03.09.24#01_Wand uit metselwerk, 70 mm; FireRating: EI60; IsExternal: yes; LoadBearing: no; ExtendToStructure: no
Name (Basic Wall:BB_03.09.24#01_Wand uit metselwerk, 70 mm:...) | In | Base Constraint | Top Constraint | BB_Element_Lokaalnummer01
19976194 | K20 | K20 | Up to level: K20 | K.-2.404
19986716 | K10 | K10 | Up to level: K10 | K.-1.306

# IfcWall: BB_Metselwerk_Cellenbeton 140 (7)
In: K10
Type - Material: BB_Metselwerk_Cellenbeton
PredefinedType: SOLIDWALL
Cpset_Wall - LevelOfAccuracy: in te vullen door Buildwise
IfcBuildingStorey - Base Offset: -100; Top Offset: 0; Base Constraint: K10
IfcClassificationReference - Keynote: 03.12.81#03; GVH_artnr 01: 03.12.81#03; GVH_artnr 02: geen waarde gevonden; GVH_artnr 03: geen waarde gevonden; GVH_artnr 04: geen waarde gevonden; GVH_artnr 05: geen waarde gevonden; GVH_artnr 06: geen waarde gevonden; TDS_link: .\05 As Builtdossier\2. Bouwkunde\2.1 Architectuur\2.1.3 open ruwbouw\TF A 03.12.81 A - Drukvast isolatie in cellenbeton.pdf
IfcRoot - Name: BB_03.12.81#03_Wand uit cellenbeton, 140 mm
Qto_WallBaseQuantities - Height: 200; Width: 140
Pset_Condition - AssessmentCondition: Empty
Pset_EnvironmentalImpactIndicators - Reference: BB_03.12.81#03_Wand uit cellenbeton, 140 mm; sets with these values: 2
Pset_WallCommon - Reference: BB_03.12.81#03_Wand uit cellenbeton, 140 mm; ThermalTransmittance: 0.892857; IsExternal: yes; LoadBearing: no; ExtendToStructure: no
Name (Basic Wall:BB_03.12.81#03_Wand uit cellenbeton, 140 mm:...) | BB_Element_Lokaalnummer01 | Length | NetVolume = GrossVolume | GrossFootprintArea | GrossSideArea = NetSideArea
19998710 | K.-1.103 | 4460 | 0.10136 | 0.6244 | 0.724
19998810 | K.-1.103 | 4460 | 0.07784 | 0.6244 | 0.556
19998871 | K.-1.102 | 4460 | 0.07784 | 0.6244 | 0.556
19998892 | K.-1.102 | 4460 | 0.10136 | 0.6244 | 0.724
19999155 | K.-1.102 | 1510 | 0.01876 | 0.2114 | 0.134
19999230 | K.-1.103 | 1510 | 0.01876 | 0.2114 | 0.134
19999282 | K.-1.103 | 3010 | 0.07896 | 0.4214 | 0.564

# IfcWall: BB_Metselwerk_Cellenbeton 190 (4)
In: K10
Type - Material: BB_Metselwerk_Cellenbeton
PredefinedType: SOLIDWALL
Cpset_Wall - LevelOfAccuracy: in te vullen door Buildwise
IfcBuildingStorey - Base Offset: -100; Base Constraint: K10
IfcClassificationReference - Keynote: 03.12.81#04; GVH_artnr 01: 03.12.81#04; GVH_artnr 02: geen waarde gevonden; GVH_artnr 03: geen waarde gevonden; GVH_artnr 04: geen waarde gevonden; GVH_artnr 05: geen waarde gevonden; GVH_artnr 06: geen waarde gevonden; TDS_link: .\05 As Builtdossier\2. Bouwkunde\2.1 Architectuur\2.1.3 open ruwbouw\TF A 03.12.81 A - Drukvast isolatie in cellenbeton.pdf
IfcRoot - Name: BB_03.12.81#04_Wand uit cellenbeton, 190 mm
Qto_WallBaseQuantities - Height: 200; Width: 190
Pset_Condition - AssessmentCondition: Empty
Pset_EnvironmentalImpactIndicators - Reference: BB_03.12.81#04_Wand uit cellenbeton, 190 mm; sets with these values: 2
Pset_WallCommon - Reference: BB_03.12.81#04_Wand uit cellenbeton, 190 mm; ThermalTransmittance: 0.657895; IsExternal: yes; LoadBearing: no; ExtendToStructure: no
Name (Basic Wall:BB_03.12.81#04_Wand uit cellenbeton, 190 mm:...) | Top Offset | BB_Element_Lokaalnummer01 | Length | NetVolume = GrossVolume | GrossFootprintArea | GrossSideArea = NetSideArea
19995149 | 100 | K.-1.P1 | 13855 | 0.44973 | 2.63245 | 2.367 | IfcBuildingStorey - Top Constraint: Up to level: K10
19995402 | 0 | K.-1.102 | 4460 | 0.13756 | 0.8474 | 0.724 | Pset_WallCommon - FireRating: EI60
19995528 | 0 | K.-1.103 | 4050 | 0.1539 | 0.7695 | 0.81
19995627 | 0 | K.-1.104 | 4460 | 0.13756 | 0.8474 | 0.724 | Pset_WallCommon - FireRating: EI60

# IfcWall: BB_Metselwerk_Snelbouw 140, Basic Wall:BB_03.02.31_Ondergronds metselwerk, 140 mm:16151324
In: K10
Type - Material: BB_Metselwerk_Snelbouw
PredefinedType: SOLIDWALL
Cpset_Wall - LevelOfAccuracy: in te vullen door Buildwise
IfcBuildingStorey - Base Offset: 660; Top Offset: 800; Base Constraint: K10; Top Constraint: Up to level: K10
IfcClassificationReference - Keynote: 03.02.31; GVH_artnr 01: 03.02.31; GVH_artnr 02: geen waarde gevonden; GVH_artnr 03: geen waarde gevonden; GVH_artnr 04: geen waarde gevonden; GVH_artnr 05: geen waarde gevonden; GVH_artnr 06: geen waarde gevonden; TDS_link: .\05 As Builtdossier\2. Bouwkunde\2.1 Architectuur\2.1.3 open ruwbouw\TF S 4.2.1.1.1 A-volle betonstenen.pdf
IfcRoot - Name: BB_03.02.31_Ondergronds metselwerk, 140 mm
Qto_WallBaseQuantities - Length: 6785.94; NetVolume: 0.133004; Height: 140; Width: 140; GrossFootprintArea: 0.950031; GrossVolume: 0.133004; GrossSideArea: 0.950031; NetSideArea: 0.950031
Pset_Condition - AssessmentCondition: Empty
Pset_EnvironmentalImpactIndicators - Reference: BB_03.02.31_Ondergronds metselwerk, 140 mm; sets with these values: 2
Pset_WallCommon - Reference: BB_03.02.31_Ondergronds metselwerk, 140 mm; ThermalTransmittance: 8.5; IsExternal: yes; LoadBearing: no; ExtendToStructure: no

# IfcWall: BB_Windscherm 160, Basic Wall:BB_ST_Windscherm, 160mm:33215242
In: 060
Type - Material: BB_Windscherm
PredefinedType: PARAPET
Cpset_Wall - LevelOfAccuracy: in te vullen door Buildwise
IfcBuildingStorey - Base Offset: -355; Top Offset: -460; Base Constraint: 060
IfcClassificationReference - GVH_artnr 01: geen waarde gevonden; GVH_artnr 02: geen waarde gevonden; GVH_artnr 03: geen waarde gevonden; GVH_artnr 04: geen waarde gevonden; GVH_artnr 05: geen waarde gevonden; GVH_artnr 06: geen waarde gevonden; TDS_link: .\05 As Builtdossier\2. Bouwkunde\2.1 Architectuur\2.1.5 dakwerken en dakwaterafvoer\2.1.5.3 dakwerken (MSB)\sheddak overzichtsplannen\MSB-UV-AR-XXX-060-102.pdf
IfcRoot - Name: BB_ST_Windscherm, 160mm
Qto_WallBaseQuantities - Length: 27418.2; NetVolume: 7.45775; Height: 1700; Width: 160; GrossFootprintArea: 4.38691; GrossVolume: 7.45775; GrossSideArea: 46.6109; NetSideArea: 46.6109
Pset_Condition - AssessmentCondition: Empty
Pset_EnvironmentalImpactIndicators - Reference: BB_ST_Windscherm, 160mm; sets with these values: 2
Pset_WallCommon - Reference: BB_ST_Windscherm, 160mm; IsExternal: yes; LoadBearing: no; ExtendToStructure: no

# IfcWall: Basic Wall:BB_03.02.31_Ondergronds metselwerk, 140 mm, Basic Wall:BB_03.02.31_Ondergronds metselwerk, 140 mm:20171805
In: K10
PredefinedType: SOLIDWALL
Cpset_Wall - LevelOfAccuracy: in te vullen door Buildwise
IfcBuildingStorey - Base Offset: 660; Top Offset: 800; Base Constraint: K10; Top Constraint: Up to level: K10
IfcClassificationReference - Keynote: 03.02.31; GVH_artnr 01: 03.02.31; GVH_artnr 02: geen waarde gevonden; GVH_artnr 03: geen waarde gevonden; GVH_artnr 04: geen waarde gevonden; GVH_artnr 05: geen waarde gevonden; GVH_artnr 06: geen waarde gevonden; TDS_link: .\05 As Builtdossier\2. Bouwkunde\2.1 Architectuur\2.1.3 open ruwbouw\TF S 4.2.1.1.1 A-volle betonstenen.pdf
IfcRoot - Name: BB_03.02.31_Ondergronds metselwerk, 140 mm
Qto_WallBaseQuantities - Length: 20804.8; NetVolume: 0.405957; Height: 140; Width: 140; GrossFootprintArea: 2.89972; GrossVolume: 0.00288907; GrossSideArea: 0.0206362; NetSideArea: 2.91362
Pset_Condition - AssessmentCondition: Empty
Pset_EnvironmentalImpactIndicators - Reference: BB_03.02.31_Ondergronds metselwerk, 140 mm; sets with these values: 2
Pset_WallCommon - Reference: BB_03.02.31_Ondergronds metselwerk, 140 mm; ThermalTransmittance: 8.5; IsExternal: yes; LoadBearing: no; ExtendToStructure: no

# IfcWall: Basic Wall:BB_03.09.24#01_Wand uit metselwerk, 140 mm (10)
PredefinedType: SOLIDWALL
Cpset_Wall - LevelOfAccuracy: in te vullen door Buildwise
IfcClassificationReference - Keynote: 03.09.24#01; GVH_artnr 01: 03.09.24#01; GVH_artnr 02: geen waarde gevonden; GVH_artnr 03: geen waarde gevonden; GVH_artnr 04: geen waarde gevonden; GVH_artnr 05: geen waarde gevonden; GVH_artnr 06: geen waarde gevonden; TDS_link: .\05 As Builtdossier\2. Bouwkunde\2.1 Architectuur\2.1.3 open ruwbouw\TF S 4.2.1.1.1 A-volle betonstenen.pdf
IfcRoot - Name: BB_03.09.24#01_Wand uit metselwerk, 140 mm
Qto_WallBaseQuantities - Width: 140
Pset_Condition - AssessmentCondition: Empty
Pset_EnvironmentalImpactIndicators - Reference: BB_03.09.24#01_Wand uit metselwerk, 140 mm; sets with these values: 2
Pset_WallCommon - Reference: BB_03.09.24#01_Wand uit metselwerk, 140 mm; ThermalTransmittance: 8.5; IsExternal: yes; LoadBearing: no; ExtendToStructure: no
Name (Basic Wall:BB_03.09.24#01_Wand uit metselwerk, 140 mm:...) | In | Base Offset | Top Offset | Base Constraint | Top Constraint | BB_Element_Lokaalnummer01 | Length | NetVolume | Height | GrossFootprintArea | GrossVolume | GrossSideArea | NetSideArea
29706326 | K10 | 100 | 2780 | K10 | Up to level: K10 | K.-1.103 | 4460 | 1.3974 | 2680 | 0.6244 | 1.3974 | 9.9814 | 9.9814
29706345 | K10 | 100 | 2780 | K10 | Up to level: K10 | K.-1.103 | 4460 | 1.14573 | 2680 | 0.6244 | 1.14573 | 8.1838 | 8.1838
29706364 | K10 | 100 | 2780 | K10 | Up to level: K10 | K.-1.102 | 4460 | 1.14573 | 2680 | 0.6244 | 1.14573 | 8.1838 | 8.1838
29706383 | K10 | 100 | 2780 | K10 | Up to level: K10 | K.-1.102 | 4460 | 1.3974 | 2680 | 0.6244 | 1.3974 | 9.9814 | 9.9814
29706402 | K10 | 100 | 2780 | K10 | Up to level: K10 | K.-1.102 | 1510 | 0.314888 | 2680 | 0.2114 | 0.314888 | 2.2492 | 2.2492
29706403 | K10 | 100 | 2780 | K10 | Up to level: K10 | K.-1.102 | 1510 | 0.314888 | 2680 | 0.2114 | 0.314888 | 2.2492 | 2.2492
29706404 | K10 | 100 | 2780 | K10 | Up to level: K10 | K.-1.103 | 1510 | 0.314888 | 2680 | 0.2114 | 0.314888 | 2.2492 | 2.2492
13047471 | 000 | -200 | -460 | 000 | Up to level: 010 | K.00.507 | 2625 | 1.22745 | 3340 | 0.3675 | 1.22745 | 8.7675 | 8.7675
13050377 | 000 | -200 | -460 | 000 | Up to level: 010 | K.00.S13 | 3380 | 0.94829 | 3340 | 0.4732 | 1.54981 | 11.0701 | 6.7735
26739067 | 030 | -80 | 3190 | 030 | Up to level: 030 |  | 840 | 0.14455 | 3270 | 0.1176 | 0.14455 | 1.0325 | 1.0325

# IfcWall: Basic Wall:BB_03.09.24#02_Wand uit metselwerk_EI60_43dB, 140 mm (20)
PredefinedType: SOLIDWALL
Cpset_Wall - LevelOfAccuracy: in te vullen door Buildwise
IfcClassificationReference - Keynote: 03.09.24#02; GVH_artnr 01: 03.09.24#02; GVH_artnr 02: geen waarde gevonden; GVH_artnr 03: geen waarde gevonden; GVH_artnr 04: geen waarde gevonden; GVH_artnr 05: geen waarde gevonden; GVH_artnr 06: geen waarde gevonden; TDS_link: .\05 As Builtdossier\2. Bouwkunde\2.1 Architectuur\2.1.3 open ruwbouw\TF S 4.2.1.1.1 A-volle betonstenen.pdf
IfcRoot - Name: BB_03.09.24#02_Wand uit metselwerk_EI60_43dB, 140 mm
Qto_WallBaseQuantities - Width: 140
Pset_Condition - AssessmentCondition: Empty
Pset_EnvironmentalImpactIndicators - Reference: BB_03.09.24#02_Wand uit metselwerk_EI60_43dB, 140 mm; sets with these values: 2
Pset_WallCommon - Reference: BB_03.09.24#02_Wand uit metselwerk_EI60_43dB, 140 mm; ThermalTransmittance: 8.5; IsExternal: yes; LoadBearing: no; ExtendToStructure: no
Name (Basic Wall:BB_03.09.24#02_Wand uit metselwerk_EI60_43dB, 140 mm:...) | In | Base Offset | Top Offset | Base Constraint | Top Constraint | Length | NetVolume | Height | GrossFootprintArea | GrossVolume | GrossSideArea = NetSideArea | BB_Element_Lokaalnummer01 | FireRating
32819545 | K10 | 0 | -280 | K10 | Up to level: 000 | 1355 | 0.549472 | 2960 | 0.1897 | 0.549472 | 3.9248
32820621 | K10 | 0 | -280 | K10 | Up to level: 000 | 940 | 0.381696 | 2960 | 0.1316 | 0.381696 | 2.7264
13058304 | 000 | -400 | -80 | 000 | Up to level: 010 | 1561.94 | 0.81386 | 3920 | 0.218672 | 0.84914 | 6.06529 | K.00.G13
13058305 | 000 | -400 | -80 | 000 | Up to level: 010 | 1562.41 | 0.814116 | 3920 | 0.218737 | 0.849396 | 6.06712 | K.00.G13
25517007 | 000 | -200 | -900 | 000 | Up to level: 010 | 1760.03 | 0.453556 | 2900 | 0.246404 | 0.453556 | 3.23969 | K.00.G16 | EI60
12998181 | 010 | -80 | 0 | 010 | Up to level: 020 | 1561.94 | 0.769433 | 3680 | 0.218672 | 0.804713 | 5.74795 | K.10.G14 | EI60
12998182 | 010 | -80 | 0 | 010 | Up to level: 020 | 1562.41 | 0.769673 | 3680 | 0.218737 | 0.804953 | 5.74967 | K.10.G14 | EI60
12998186 | 010 | -80 | 3310 | 010 | Up to level: 010 | 2863.38 | 1.31879 |  |  |  |  | K.10.G16 | EI60
13000284 | 010 | 0 | 0 | 010 | Up to level: 020 | 2099.33 | 0.819165 | 3600 | 0.293906 | 0.819165 | 5.85118 | K.10.K44 | EI60
13266433 | 010 | -80 | 3310 | 010 | Up to level: 010 | 1195 | 0.256683 | 3390 | 0.1673 | 0.256683 | 1.83345 | K.10.G15 | EI60
25635835 | 010 | -80 | 3310 | 010 | Up to level: 010 | 1195 | 0.256683 | 3390 | 0.1673 | 0.256683 | 1.83345
12560507 | 020 | -80 | 0 | 020 | Up to level: 030 | 1561.94 | 0.769433 | 3680 | 0.218672 | 0.804713 | 5.74795 | K.20.G14 | EI60
12560508 | 020 | -80 | 0 | 020 | Up to level: 030 | 1562.41 | 0.769673 | 3680 | 0.218737 | 0.804953 | 5.74967 | K.20.G14 | EI60
12560509 | 020 | -80 | 3310 | 020 | Up to level: 020 | 2089.95 | 0.936047 | 3310 | 0.282794 | 0.968485 | 6.91775 | K.20.G14 | EI60
12565914 | 020 | 0 | 0 | 020 | Up to level: 030 | 2110 | 0.824544 | 3600 | 0.2954 | 0.824544 | 5.8896 | K.20.K44 | EI60
12551738 | 030 | 0 | 3400 | 030 | Up to level: 030 | 1561.94 | 0.724654 | 3400 | 0.218672 | 0.724654 | 5.1761 | K.30.G14 | EI60
12551802 | 030 | 0 | 3400 | 030 | Up to level: 030 | 1562.46 | 0.698839 | 3400 | 0.218745 | 0.724907 | 5.1779 | K.30.G14 | EI60
12552518 | 030 | -80 | 3200 | 030 | Up to level: 030 | 2089.95 | 0.907767 | 3210 | 0.282794 | 0.939225 | 6.70875 | K.30.G14 | EI60
12552565 | 030 | -80 | 3200 | 030 | Up to level: 030 | 2863.38 | 1.27514 |  |  |  |  | K.30.G14 | EI60
12556601 | 030 | 0 | 3250 | 030 | Up to level: 030 | 2110.03 | 0.706396 | 3200 | 0.295404 | 0.706396 | 5.04569 | K.30.306 | EI60

# IfcWall: Basic Wall:BB_03.09.24#03_Wand uit metselwerk, 190 mm (25)
PredefinedType: SOLIDWALL
Cpset_Wall - LevelOfAccuracy: in te vullen door Buildwise
IfcClassificationReference - Keynote: 03.09.24#03; TDS_link: .\05 As Builtdossier\2. Bouwkunde\2.1 Architectuur\2.1.3 open ruwbouw\TF S 4.2.1.1.1 A-volle betonstenen.pdf
IfcRoot - Name: BB_03.09.24#03_Wand uit metselwerk, 190 mm
Qto_WallBaseQuantities - Width: 190
Pset_Condition - AssessmentCondition: Empty
Pset_EnvironmentalImpactIndicators - Reference: BB_03.09.24#03_Wand uit metselwerk, 190 mm; sets with these values: 2
Pset_WallCommon - Reference: BB_03.09.24#03_Wand uit metselwerk, 190 mm; ThermalTransmittance: 6.26316; IsExternal: yes; ExtendToStructure: no
Name (Basic Wall:BB_03.09.24#03_Wand uit metselwerk, 190 mm:...) | In | Base Offset | Top Offset | Base Constraint | Top Constraint | GVH_artnr 01 | GVH_artnr 02 = GVH_artnr 03 = GVH_artnr 04 = GVH_artnr 05 = GVH_artnr 06 | BB_Element_Lokaalnummer01 | Length | NetVolume | LoadBearing | Height | GrossFootprintArea | GrossVolume | GrossSideArea | NetSideArea
16151983 | K10 | -100 | 2340 | K10 | Up to level: K10 | 03.09.24#03 | geen waarde gevonden | K.-1.301 | 5894.45 | 2.72069 | no
19988818 | K10 | -200 | 2710 | K10 | Up to level: K10 | 03.09.24#03 | geen waarde gevonden | K.-1.303 | 5978.13 | 3.29755 | no | 2910 | 1.13284 | 3.30531 | 17.3964 | 17.3964
19989400 | K10 | 0 | 2780 | K10 | Up to level: K10 | 03.09.24#03 | geen waarde gevonden | K.-1.301 | 5975 | 3.11932 | no | 2780 | 1.13525 | 3.11932 | 16.4175 | 16.4175
19989509 | K10 | 0 | 2780 | K10 | Up to level: K10 | 03.09.24#03 | geen waarde gevonden | K.-1.301 | 5845 | 1.13793 | no | 2780 | 1.11055 | 1.13793 | 5.9891 | 5.9891
27799907 | K10 | -200 | 2710 | K10 | Up to level: K10 | 03.09.24#03 | geen waarde gevonden |  | 6293.1 | 3.04327 | no | 2910 | 1.19569 | 3.44957 | 18.1556 | 16.0172
27800047 | K10 | -200 | 2710 | K10 | Up to level: K10 | 03.09.24#03 | geen waarde gevonden |  | 3423.05 | 1.89114 | no | 2910 | 0.65038 | 1.8926 | 9.96108 | 9.96108
29706282 | K10 | 100 | 2780 | K10 | Up to level: K10 | 03.09.24#03 | geen waarde gevonden | K.-1.103 | 4050 | 2.04793 | no | 2680 | 0.7695 | 2.04793 | 10.7786 | 10.7786
34055748 | K10 | 0 | -660 | K10 | Up to level: 000 |  |  |  | 699.796 | 0.284349 | yes | 2580 | 0.114911 | 0.330918 | 1.74167 | 1.74167 | Pset_WallCommon - FireRating: EI60
34055752 | K10 | 0 | -660 | K10 | Up to level: 000 |  |  |  | 689.648 | 0.279375 | yes | 2580 | 0.112983 | 0.325944 | 1.71549 | 1.71549 | Pset_WallCommon - FireRating: EI60
13042380 | 000 | -200 | -530 | 000 | Up to level: 010 | 03.09.24#03 | geen waarde gevonden | K.00.304 | 550 | 0.32186 | no | 3080 | 0.1045 | 0.32186 | 1.694 | 1.694
13217611 | 000 | -200 | -200 | 000 | Up to level: 010 | 03.09.24#03 | geen waarde gevonden | K.00.G18 | 640 | 0.357772 | no | 3600 | 0.1216 | 0.420947 | 2.21551 | 2.21551
13217612 | 000 | -200 | -200 | 000 | Up to level: 010 | 03.09.24#03 | geen waarde gevonden | K.00.G12 | 650 | 0.357962 | no | 3600 | 0.1235 | 0.421137 | 2.21651 | 2.21651
12997861 | 010 | -200 | -600 | 010 | Up to level: 020 | 03.09.24#03 | geen waarde gevonden | K.10.G11 | 590 | 0.271223 | no
12997921 | 010 | -200 | -600 | 010 | Up to level: 020 | 03.09.24#03 | geen waarde gevonden | K.10.G11 | 564.717 | 0.278767 | no | 3200 | 0.107296 | 0.342512 | 1.80269 | 1.80269
7215057 | 030 | -200 | 0 | 030 |  | 03.09.24#03 | geen waarde gevonden | NO gevel | 19805 | 3.53537 | no | 940 | 3.76295 | 3.53717 | 18.6167 | 18.6072
8684831 | 030 | -200 | 0 | 030 |  | 03.09.24#03 | geen waarde gevonden | NW gevel | 19870 | 3.54698 | no | 940 | 3.7753 | 3.54878 | 18.6778 | 18.6683
10510295 | 030 | -200 | 740 | 030 | Up to level: 030 | 03.09.24#03 | geen waarde gevonden | NW gevel | 710 | 0.126779 | no | 940 | 0.1349 | 0.126779 | 0.667256 | 0.667256
12517580 | 030 | -200 | 740 | 030 | Up to level: 030 | 03.09.24#03 | geen waarde gevonden | NO gevel | 710 | 0.126779 | no | 940 | 0.1349 | 0.126779 | 0.667256 | 0.667256
12555360 | 030 | -200 | 2680 | 030 | Up to level: 030 | 03.09.24#03 | geen waarde gevonden | N gevel | 1890 | 0.668106 | no | 2880 | 0.3591 | 0.668106 | 3.51635 | 3.51635
13286320 | 030 | -80 | 2990 | 030 | Up to level: 030 | 03.09.24#03 | geen waarde gevonden | K.30.108 | 990 | 0.211366 | no | 3070 | 0.1881 | 0.211366 | 1.11245 | 1.11245
34084350 | 040 | -200 | -1400 | 040 | Up to level: 050 |  |  |  | 13349.5 | 3.56659 | yes | Pset_WallCommon - FireRating: EI60
34202776 | 040 | 1250 | -250 | 040 | Up to level: 050 |  |  |  | 15196.1 | 2.98353 | yes
34205571 | 040 | 1250 | 0 | 040 |  |  |  |  | 3120.95 | 0.619275 | yes | 1150 | 0.57493 | 0.640032 | 3.36859 | 3.36859
34211672 | 040 | 1250 | -250 | 040 | Up to level: 050 |  |  |  | 3384.35 | 0.734291 | yes | 1150 | 0.643027 | 0.739481 | 3.892 | 3.892
10443680 | 050 | -50 | 0 | 050 |  | 03.09.24#03 | geen waarde gevonden | Z gevel | 3311.8 | 0.18947 | no | 310 | 0.629242 | 0.195065 | 1.02666 | 1.02666

# IfcWall: Basic Wall:BB_03.09.24#04_Wand uit metselwerk_vol, 190 mm, Basic Wall:BB_03.09.24#04_Wand uit metselwerk_vol, 190 mm:13047927
In: 000
PredefinedType: SOLIDWALL
Cpset_Wall - LevelOfAccuracy: in te vullen door Buildwise
IfcBuildingStorey - Base Offset: -200; Top Offset: -460; Base Constraint: 000; Top Constraint: Up to level: 010
IfcClassificationReference - Keynote: 03.09.24#04; GVH_artnr 01: 03.09.24#04; GVH_artnr 02: geen waarde gevonden; GVH_artnr 03: geen waarde gevonden; GVH_artnr 04: geen waarde gevonden; GVH_artnr 05: geen waarde gevonden; GVH_artnr 06: geen waarde gevonden; TDS_link: .\05 As Builtdossier\2. Bouwkunde\2.1 Architectuur\2.1.3 open ruwbouw\TF S 4.2.1.1.1 A-volle betonstenen.pdf
IfcElement - BB_Element_Lokaalnummer01: K.00.202
IfcRoot - Name: BB_03.09.24#04_Wand uit metselwerk_vol, 190 mm
Qto_WallBaseQuantities - Length: 4505; NetVolume: 1.97961; Height: 3340; Width: 190; GrossFootprintArea: 0.85595; GrossVolume: 1.97961; GrossSideArea: 10.419; NetSideArea: 10.419
Pset_Condition - AssessmentCondition: Empty
Pset_EnvironmentalImpactIndicators - Reference: BB_03.09.24#04_Wand uit metselwerk_vol, 190 mm; sets with these values: 2
Pset_WallCommon - Reference: BB_03.09.24#04_Wand uit metselwerk_vol, 190 mm; ThermalTransmittance: 6.26316; IsExternal: yes; LoadBearing: no; ExtendToStructure: no

# IfcWall: Basic Wall:BB_03.09.24#05_Wand uit metselwerk_EI60, 190 mm (54)
PredefinedType: SOLIDWALL
Cpset_Wall - LevelOfAccuracy: in te vullen door Buildwise
IfcClassificationReference - Keynote: 03.09.24#05; TDS_link: .\05 As Builtdossier\2. Bouwkunde\2.1 Architectuur\2.1.3 open ruwbouw\TF S 4.2.1.1.1 A-volle betonstenen.pdf
IfcRoot - Name: BB_03.09.24#05_Wand uit metselwerk_EI60, 190 mm
Qto_WallBaseQuantities - Width: 190
Pset_Condition - AssessmentCondition: Empty
Pset_EnvironmentalImpactIndicators - Reference: BB_03.09.24#05_Wand uit metselwerk_EI60, 190 mm; sets with these values: 2
Pset_WallCommon - Reference: BB_03.09.24#05_Wand uit metselwerk_EI60, 190 mm; ThermalTransmittance: 6.26316; IsExternal: yes; LoadBearing: no; ExtendToStructure: no
Name (Basic Wall:BB_03.09.24#05_Wand uit metselwerk_EI60, 190 mm:...) | In | Base Offset | Top Offset | Base Constraint | Top Constraint | GVH_artnr 01 | GVH_artnr 02 = GVH_artnr 03 = GVH_artnr 04 = GVH_artnr 05 = GVH_artnr 06 | BB_Element_Lokaalnummer01 | Length | NetVolume | Height | GrossFootprintArea | GrossVolume | GrossSideArea | NetSideArea | FireRating
19975178 | K20 | 0 | 2440 | K20 | Up to level: K20 | 03.09.24#05 | geen waarde gevonden | K.-2.404 | 7020 | 2.84362 | 2440 | 1.3338 | 2.84362 | 14.9664 | 14.9664 | EI60
19976372 | K20 | 0 | 2200 | K20 | Up to level: K20 | 03.09.24#05 | geen waarde gevonden | K.-2.401 | 2450 | 0.679364 | 2200 | 0.4655 | 0.679364 | 3.5756 | 3.5756 | EI60
19976517 | K20 | 0 | 2490 | K20 | Up to level: K20 | 03.09.24#05 | geen waarde gevonden | K.-2.405 | 9120 | 3.77462 | 2490 | 1.7328 | 3.77462 | 19.8664 | 19.8664 | EI60
19976541 | K20 | 0 | 2490 | K20 | Up to level: K20 | 03.09.24#05 | geen waarde gevonden | K.-2.305 | 5064.66 | 2.34987 |  |  |  |  |  | EI60
19976716 | K20 | 0 | 2500 | K20 | Up to level: K20 | 03.09.24#05 | geen waarde gevonden | K.-2.305 | 524.578 | 0.183883 | 2500 | 0.0816198 | 0.232953 | 1.22607 | 1.22607 | EI60
19977034 | K20 | 0 | 2490 | K20 | Up to level: K20 | 03.09.24#05 | geen waarde gevonden | K.-2.305 | 2305 | 0.663369 |  |  |  |  |  | EI60
19978503 | K20 | 0 | 2390 | K20 | Up to level: K20 | 03.09.24#05 | geen waarde gevonden | K.-2.301 | 5975 | 1.87935 | 2390 | 1.13525 | 1.87935 | 9.8913 | 9.8913 | EI60
19979003 | K20 | 0 | 2200 | K20 | Up to level: K20 | 03.09.24#05 | geen waarde gevonden | K.-2.G31 | 5200 | 1.38563 | 2200 | 0.988 | 1.38563 | 7.2928 | 7.2928 | EI60
19979071 | K20 | 0 | 2200 | K20 | Up to level: K20 | 03.09.24#05 | geen waarde gevonden | K.-2.G32 | 1900 | 0.387904 | 2200 | 0.361 | 0.387904 | 2.0416 | 2.0416 | EI60
19979576 | K20 | 0 | 2500 | K20 | Up to level: K20 | 03.09.24#05 | geen waarde gevonden | K.-2.H2 | 1567.23 | 0.655119 | 2500 | 0.279724 | 0.683457 | 3.59714 | 3.59714 | EI60
19979641 | K20 | 0 | 2500 | K20 | Up to level: K20 | 03.09.24#05 | geen waarde gevonden | K.-2.H2 | 1567.23 | 0.655119 | 2500 | 0.279724 | 0.683457 | 3.59714 | 3.59714 | EI60
19979973 | K20 | 0 | 2100 | K20 | Up to level: K20 | 03.09.24#05 | geen waarde gevonden | K.-2.K13 | 942.663 | 0.338217 | 2100 | 0.179106 | 0.376122 | 1.97959 | 1.97959 | EI60
19980182 | K20 | 0 | 2100 | K20 | Up to level: K20 | 03.09.24#05 | geen waarde gevonden | K.-2.H2 | 2531.46 | 0.622837 | 2100 | 0.480978 | 1.01005 | 5.31608 | 5.31608 | EI60
19980284 | K20 | 0 | 2100 | K20 | Up to level: K20 | 03.09.24#05 | geen waarde gevonden | K.-2.K14 | 930.886 | 0.335618 | 2100 | 0.176868 | 0.371424 | 1.95486 | 1.95486 | EI60
19980420 | K20 | 0 | 2100 | K20 | Up to level: K20 | 03.09.24#05 | geen waarde gevonden | K.-2.G22 | 910 | 0.36309 | 2100 | 0.1729 | 0.36309 | 1.911 | 1.911
19980487 | K20 | 0 | 2340 | K20 | Up to level: K20 | 03.09.24#05 | geen waarde gevonden | K.-2.G21 | 5200 | 1.51027 | 2340 | 0.988 | 1.51027 | 7.9488 | 7.9488
20047247 | K20 | 0 | 2200 | K20 | Up to level: K20 | 03.09.24#05 | geen waarde gevonden | K.-2.401 | 1565 | 0.321062 | 2200 | 0.29735 | 0.321062 | 1.6898 | 1.6898 | EI60
20388531 | K20 | 0 | 2200 | K20 | Up to level: K20 | 03.09.24#05 | geen waarde gevonden | K.-2.306 | 2130 | 0.484042 | 2200 | 0.404699 | 0.484042 | 2.54759 | 2.54759 | EI60
19986714 | K10 | 0 | 2780 | K10 | Up to level: K10 | 03.09.24#05 | geen waarde gevonden | K.-1.306 | 7020 | 2.97873 | 2780 | 1.3338 | 2.97873 | 15.6775 | 15.6775 | EI60
19986717 | K10 | 0 | 2510 | K10 | Up to level: K10 | 03.09.24#05 | geen waarde gevonden | K.-1.310 | 9120 | 4.41697 | 2780 | 1.7328 | 4.55377 | 23.9672 | 23.2472 | EI60
19986718 | K10 | 0 | 2580 | K10 | Up to level: K10 | 03.09.24#05 | geen waarde gevonden | K.-1.310 | 5064.66 | 2.41741 |  |  |  |  |  | EI60
19986719 | K10 | 0 | 2340 | K10 | Up to level: K10 | 03.09.24#05 | geen waarde gevonden | K.-1.310 | 524.578 | 0.18712 | 2340 | 0.0816198 | 0.22665 | 1.19289 | 1.19289 | EI60
19986720 | K10 | 0 | 2580 | K10 | Up to level: K10 | 03.09.24#05 | geen waarde gevonden | K.-1.309 | 2099.33 | 0.658279 | 2580 | 0.398872 | 0.658324 | 3.46486 | 3.46486 | EI60
19987116 | K10 | 0 | 2780 | K10 | Up to level: K10 | 03.09.24#05 | geen waarde gevonden | K.-1.307 | 1790 | 0.931798 | 2780 | 0.3401 | 0.931798 | 4.9042 | 4.9042 | EI60
19987209 | K10 | 0 | 2780 | K10 | Up to level: K10 | 03.09.24#05 | geen waarde gevonden | K.-1.307 | 1280 | 0.2698 | 2780 | 0.2432 | 0.2698 | 1.42 | 1.42 | EI60
19987579 | K10 | 0 | 2780 | K10 | Up to level: K10 | 03.09.24#05 | geen waarde gevonden | K.-1.306 | 4105 | 1.803 | 2780 | 0.77995 | 1.803 | 9.4895 | 9.4895 | EI60
19988433 | K10 | 0 | 2560 | K10 | Up to level: K10 | 03.09.24#05 | geen waarde gevonden | K.-1.G31 | 5200 | 1.74131 | 2560 | 0.988 | 1.74131 | 9.1648 | 9.1648 | EI60
19988434 | K10 | 0 | 2560 | K10 | Up to level: K10 | 03.09.24#05 | geen waarde gevonden | K.-1.G32 | 1900 | 0.517864 | 2560 | 0.361 | 0.517864 | 2.7256 | 2.7256 | EI60
19988548 | K10 | -200 | 2710 | K10 | Up to level: K10 | 03.09.24#05 | geen waarde gevonden | K.-1.303 | 11589.5 | 4.60808 |  |  |  |  |  | EI60
19989036 | K10 | 0 | 2240 | K10 | Up to level: K10 | 03.09.24#05 | geen waarde gevonden | K.-1.311 | 2130 | 0.48837 | 2340 | 0.4047 | 0.48837 | 2.57037 | 2.57037 | EI60
19989143 | K10 | 0 | 2240 | K10 | Up to level: K10 | 03.09.24#05 | geen waarde gevonden | K.-1.312 | 4000 | 1.64142 | 2340 | 0.76 | 1.68103 | 8.84751 | 8.84751 | EI60
19991931 | K10 | 0 | 2640 | K10 | Up to level: K10 | 03.09.24#05 | geen waarde gevonden | K.-1.311 | 2110.03 | 0.693133 | 2640 | 0.400905 | 0.693133 | 3.64807 | 3.64807 | EI60
19993525 | K10 | 0 | 2780 | K10 | Up to level: K10 | 03.09.24#05 | geen waarde gevonden | K.-1.G15 | 9490 | 4.56267 | 2780 | 1.8031 | 4.56267 | 24.0141 | 24.0141 | EI60
19994056 | K10 | 0 | 2580 | K10 | Up to level: K10 | 03.09.24#05 | geen waarde gevonden | K.-1.G13 | 1613.65 | 0.696344 |  |  |  |  |  | EI60
19994057 | K10 | 0 | 2580 | K10 | Up to level: K10 | 03.09.24#05 | geen waarde gevonden | K.-1.G13 | 1613.65 | 0.696344 |  |  |  |  |  | EI60
19994760 | K10 | 0 | 2780 | K10 | Up to level: K10 | 03.09.24#05 | geen waarde gevonden | K.-1.G19 | 6405 | 2.75414 | 2780 | 1.21695 | 2.75414 | 14.4955 | 14.4955 | EI60
19994913 | K10 | 0 | 2780 | K10 | Up to level: K10 | 03.09.24#05 | geen waarde gevonden | K.-1.P1 | 7617.5 | 2.39016
19995697 | K10 | 0 | 2780 | K10 | Up to level: K10 | 03.09.24#05 | geen waarde gevonden | K.-1.P1 | 7405 | 3.86116 | 2780 | 1.40695 | 3.86116 | 20.3219 | 20.3219 | EI60
19995724 | K10 | 0 | 2780 | K10 | Up to level: K10 | 03.09.24#05 | geen waarde gevonden | K.-1.P5 | 7700 | 3.03738 | 2780 | 1.463 | 3.03738 | 15.9862 | 15.9862
20013856 | K10 | -100 | 2780 | K10 | Up to level: K10 | 03.09.24#05 | geen waarde gevonden | K.-1.101 | 4737.5 | 2.45469 | 2880 | 0.900125 | 2.55501 | 13.4474 | 13.4474 | EI60
20052183 | K10 | 0 | 2290 | K10 | Up to level: K10 | 03.09.24#05 | geen waarde gevonden | K.-1.K15 | 1010 | 0.204402 | 2290 | 0.1919 | 0.204402 | 1.0758 | 1.0758 | EI60
29022790 | K10 | 0 | 2780 | K10 | Up to level: K10 | 03.09.24#05 | geen waarde gevonden |  | 2770 | 0.747167 |  |  |  |  |  | EI60
29706258 | K10 | 100 | 2780 | K10 | Up to level: K10 | 03.09.24#05 | geen waarde gevonden | K.-1.102 | 4460 | 1.89647 | 2680 | 0.8474 | 1.89647 | 9.9814 | 9.9814 | EI60
29706304 | K10 | 100 | 2780 | K10 | Up to level: K10 | 03.09.24#05 | geen waarde gevonden | K.-1.104 | 4460 | 1.89647 | 2680 | 0.8474 | 1.89647 | 9.9814 | 9.9814 | EI60
29706482 | K10 | 100 | 2780 | K10 | Up to level: K10 | 03.09.24#05 | geen waarde gevonden | K.-1.P1 | 13855 | 5.8896 | 2680 | 2.63245 | 6.22212 | 32.748 | 32.748 | EI60
36335271 | K10 | 0 | 2960 | K10 | Up to level: K10 | 03.09.24#05 | geen waarde gevonden | K.-1.G11 | 1900 | 0.673246 | 2960 | 0.361 | 0.673246 | 3.5434 | 3.5434 | EI60
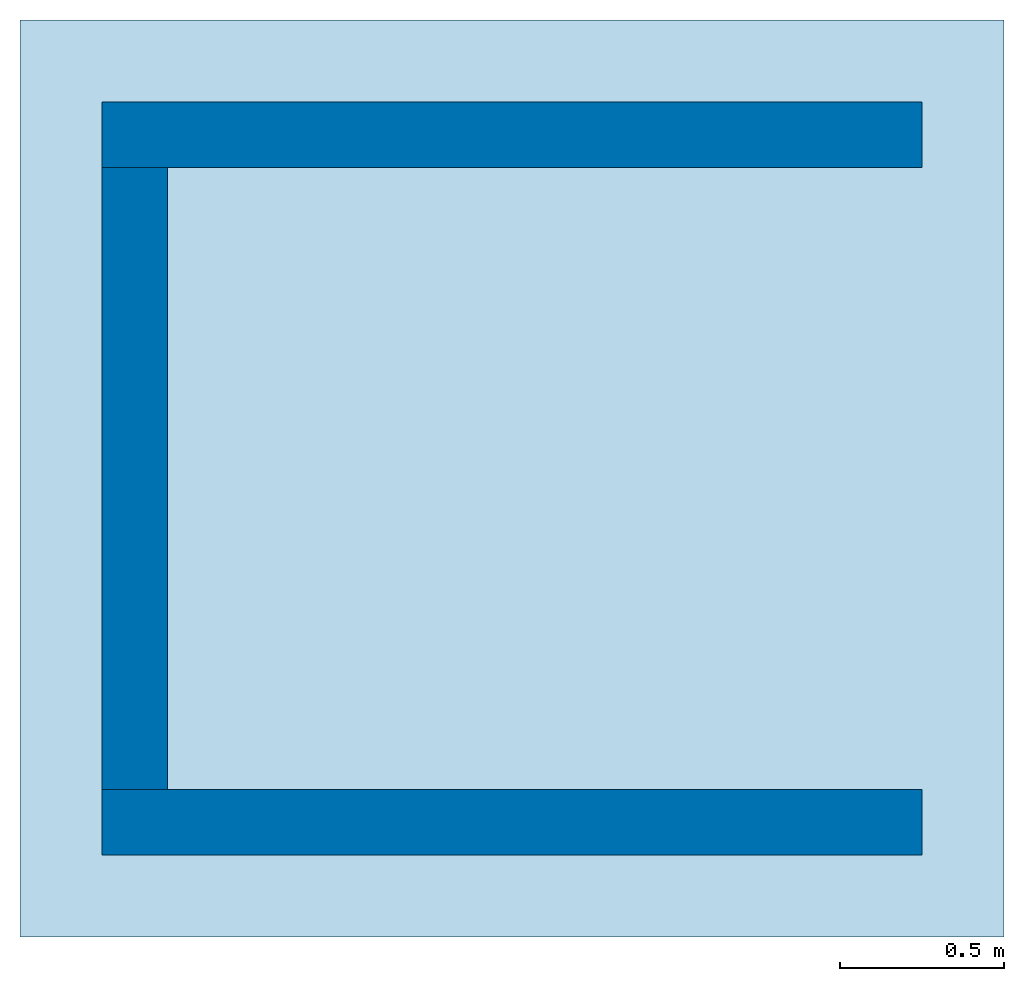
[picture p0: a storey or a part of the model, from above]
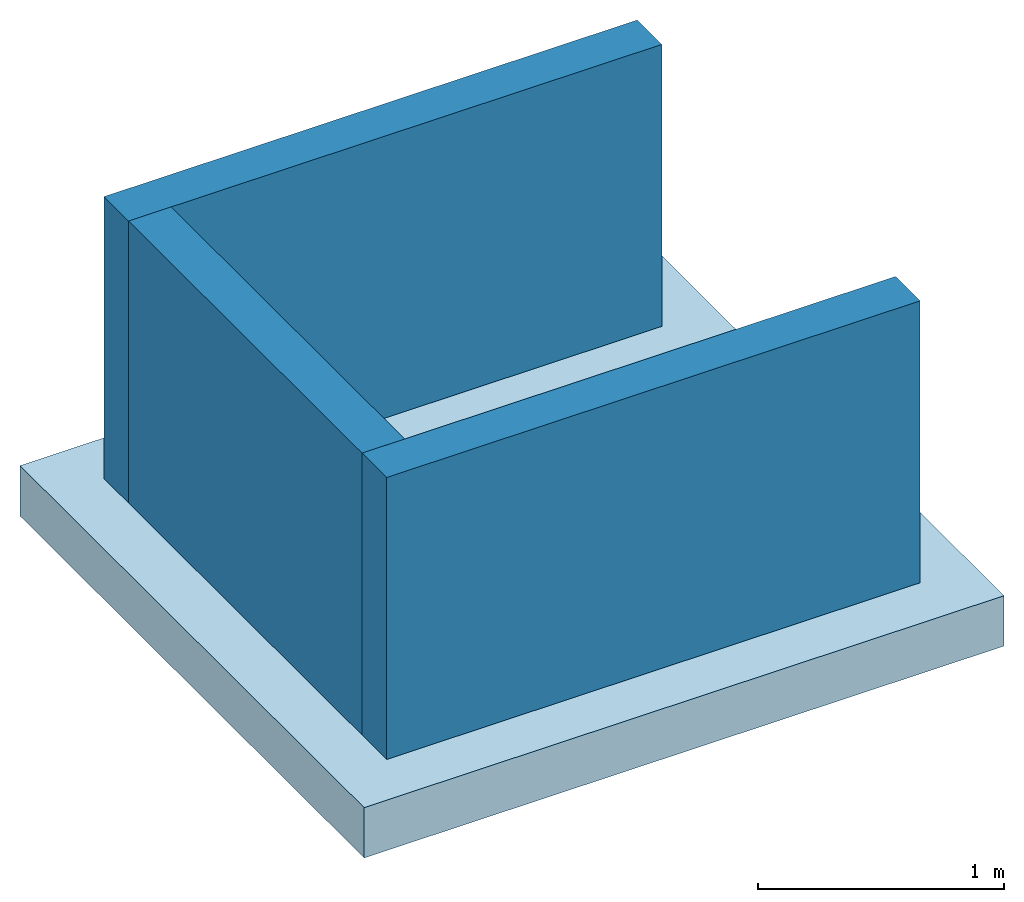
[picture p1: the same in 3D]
Properties of the parts of a building model (IFC4X3_ADD2), part 22 of 28

# IfcWall: Basic Wall:BB_03.09.24#05_Wand uit metselwerk_EI60, 190 mm (54)
Name (Basic Wall:BB_03.09.24#05_Wand uit metselwerk_EI60, 190 mm:...) | In | Base Offset | Top Offset | Base Constraint | Top Constraint | GVH_artnr 01 | GVH_artnr 02 = GVH_artnr 03 = GVH_artnr 04 = GVH_artnr 05 = GVH_artnr 06 | BB_Element_Lokaalnummer01 | Length | NetVolume | Height | GrossFootprintArea | GrossVolume | GrossSideArea | NetSideArea | FireRating
36337825 | K10 | 0 | -460 | K10 | Up to level: 000 | 03.09.24#05 | geen waarde gevonden | K.-1.T4 | 1855 | 0.350927 | 2780 | 0.35245 | 0.350927 | 1.84698 | 1.84698 | EI60
13041245 | 000 | -200 | -530 | 000 | Up to level: 010 | 03.09.24#05 | geen waarde gevonden | K.00.302 | 5169.23 | 3.02017 | 3080 | 0.980574 | 3.02503 | 15.9212 | 15.9212 | EI60
13042192 | 000 | -200 | -530 | 000 | Up to level: 010 | 03.09.24#05 | geen waarde gevonden | K.00.302 | 861.173 | 0.529883 | 3270 | 0.162044 | 0.535047 | 2.81603 | 2.81603 | EI60
13044066 | 000 | -200 | -1030 | 000 | Up to level: 010 | 03.09.24#05 | geen waarde gevonden | K.00.L31 | 1958 | 0.960245 | 2770 | 0.37202 | 0.960245 | 5.05392 | 5.05392
13049028 | 000 | -200 | -460 | 000 | Up to level: 010 | 03.09.24#05 | geen waarde gevonden | K.00.S13 | 2240 | 0.971698 | 3340 | 0.4256 | 1.37988 | 7.2625 | 5.1142 | EI60
34146271 | 000 | -400 | 2800 | 000 | Up to level: 000 |  |  | K.00.A1 | 186.551 | 0.0661404 | 3200 | 0.0354447 | 0.11552 | 0.608 | 0.608
12998609 | 010 | -80 | 2370 | 010 | Up to level: 010 | 03.09.24#05 | geen waarde gevonden | K.10.G16 | 920 | 0.416224 | 2450 | 0.1748 | 0.416224 | 2.19065 | 2.19065
34146053 | 010 | -200 | 2400 | 010 | Up to level: 010 |  |  | K.00.A1 | 189.693 | 0.0947855 | 2600 | 0.036456 | 0.09386 | 0.494 | 0.494

# IfcWall: Basic Wall:BB_03.09.24#06_Wand uit metselwerk_EI60_43dB, 190 mm (5)
PredefinedType: SOLIDWALL
Cpset_Wall - LevelOfAccuracy: in te vullen door Buildwise
IfcBuildingStorey - Base Offset: -200
IfcClassificationReference - Keynote: 03.09.24#06; GVH_artnr 01: 03.09.24#06; GVH_artnr 02: geen waarde gevonden; GVH_artnr 03: geen waarde gevonden; GVH_artnr 04: geen waarde gevonden; GVH_artnr 05: geen waarde gevonden; GVH_artnr 06: geen waarde gevonden; TDS_link: .\05 As Builtdossier\2. Bouwkunde\2.1 Architectuur\2.1.3 open ruwbouw\TF S 4.2.1.1.1 A-volle betonstenen.pdf
IfcRoot - Name: BB_03.09.24#06_Wand uit metselwerk_EI60_43dB, 190 mm
Qto_WallBaseQuantities - Width: 190
Pset_Condition - AssessmentCondition: Empty
Pset_EnvironmentalImpactIndicators - Reference: BB_03.09.24#06_Wand uit metselwerk_EI60_43dB, 190 mm; sets with these values: 2
Pset_WallCommon - Reference: BB_03.09.24#06_Wand uit metselwerk_EI60_43dB, 190 mm; FireRating: EI60; ThermalTransmittance: 6.26316; IsExternal: yes; LoadBearing: no; ExtendToStructure: no
Name (Basic Wall:BB_03.09.24#06_Wand uit metselwerk_EI60_43dB, 190 mm:...) | In | Top Offset | Base Constraint | Top Constraint | BB_Element_Lokaalnummer01 | Length | NetVolume
13040654 | 000 | -530 | 000 | Up to level: 010 | K.00.304 | 1581.03 | 0.869625 | Qto_WallBaseQuantities - Height: 3080; GrossFootprintArea: 0.282346; GrossVolume: 0.925219; GrossSideArea: 4.86957; NetSideArea: 4.86957
13040816 | 000 | -530 | 000 | Up to level: 010 | K.00.304 | 11661.6 | 5.24006
13040867 | 000 | -200 | 000 | Up to level: 010 | K.00.302 | 5973.63 | 3.96303
12566216 | 020 | -460 | 020 | Up to level: 030 | K.20.403 | 1580 | 0.528162
12555044 | 030 | 3190 | 030 | Up to level: 030 | K.30.401 | 1490 | 0.537937 | Qto_WallBaseQuantities - Height: 3390; GrossFootprintArea: 0.2831; GrossVolume: 0.945174; GrossSideArea: 4.9746; NetSideArea: 2.83125

# IfcWall: Basic Wall:BB_03.12.81#03_Wand uit cellenbeton, 140 mm, Basic Wall:BB_03.12.81#03_Wand uit cellenbeton, 140 mm:19999085
In: K10
PredefinedType: SOLIDWALL
Cpset_Wall - LevelOfAccuracy: in te vullen door Buildwise
IfcBuildingStorey - Base Offset: -100; Top Offset: 2780; Base Constraint: K10; Top Constraint: Up to level: K10
IfcClassificationReference - Keynote: 03.12.81#03; GVH_artnr 01: 03.12.81#03; GVH_artnr 02: geen waarde gevonden; GVH_artnr 03: geen waarde gevonden; GVH_artnr 04: geen waarde gevonden; GVH_artnr 05: geen waarde gevonden; GVH_artnr 06: geen waarde gevonden; TDS_link: .\05 As Builtdossier\2. Bouwkunde\2.1 Architectuur\2.1.3 open ruwbouw\TF A 03.12.81 A - Drukvast isolatie in cellenbeton.pdf
IfcElement - BB_Element_Lokaalnummer01: K.-1.102
IfcRoot - Name: BB_03.12.81#03_Wand uit cellenbeton, 140 mm
Qto_WallBaseQuantities - Length: 1510; NetVolume: 0.333648; Height: 2880; Width: 140; GrossFootprintArea: 0.2114; GrossVolume: 0.333648; GrossSideArea: 2.3832; NetSideArea: 2.3832
Pset_Condition - AssessmentCondition: Empty
Pset_EnvironmentalImpactIndicators - Reference: BB_03.12.81#03_Wand uit cellenbeton, 140 mm; sets with these values: 2
Pset_WallCommon - Reference: BB_03.12.81#03_Wand uit cellenbeton, 140 mm; ThermalTransmittance: 0.892857; IsExternal: yes; LoadBearing: no; ExtendToStructure: no

# IfcWall: Basic Wall:BB_XX_Wand uit beton, 170 mm (15)
PredefinedType: SOLIDWALL
Cpset_Wall - LevelOfAccuracy: in te vullen door Buildwise
IfcClassificationReference - GVH_artnr 01: geen waarde gevonden; GVH_artnr 02: geen waarde gevonden; GVH_artnr 03: geen waarde gevonden; GVH_artnr 04: geen waarde gevonden; GVH_artnr 05: geen waarde gevonden; GVH_artnr 06: geen waarde gevonden
IfcRoot - Name: BB_XX_Wand uit beton, 170 mm
Qto_WallBaseQuantities - Width: 170
Pset_Condition - AssessmentCondition: Empty
Pset_EnvironmentalImpactIndicators - Reference: BB_XX_Wand uit beton, 170 mm; sets with these values: 2
Pset_WallCommon - Reference: BB_XX_Wand uit beton, 170 mm; IsExternal: yes; LoadBearing: no
Name (Basic Wall:BB_XX_Wand uit beton, 170 mm:...) | In | Base Offset | Top Offset | Base Constraint | Length | NetVolume | Height | GrossFootprintArea | GrossVolume | GrossSideArea | NetSideArea | ExtendToStructure
971500 | K20 | 0 | 0 | K20 | 500 | 0.20196 | 2500 | 0.085 | 0.20196 | 1.188 | 1.188 | no
1009573 | K20 | -400 | 0 | K20 | 740 | 0.3519 | 3000 | 0.1258 | 0.3519 | 2.07 | 2.07 | no
806302 | K10 | -200 | 0 | K10 | 2160 | 1.4109 | 4330 | 0.3672 | 1.4109 | 8.2994 | 8.2994 | no
806391 | K10 | -200 | 0 | K10 | 500 | 0.26146 | 3240 | 0.085 | 0.26146 | 1.538 | 1.538 | no
930725 | K10 | -100 | 0 | K10 | 750 | 0.321538 | 3140 | 0.1275 | 0.321538 | 1.8914 | 1.8914 | no
486411 | 000 | -513.867 | -200 | 000 | 690 | 0.51336 |  |  |  |  |  | no | IfcBuildingStorey - Top Constraint: Up to level: 010
487918 | 000 | -700 | -200 | 000 | 750 | 0.4981 | 4100 | 0.1275 | 0.4981 | 2.93 | 2.93 | no | IfcBuildingStorey - Top Constraint: Up to level: 010
695358 | 020 | -200 | 0 | 020 | 750 | 0.459 | 3600 | 0.1275 | 0.459 | 2.7 | 2.7 | yes
695371 | 020 | -200 | 0 | 020 | 750 | 0.459 | 3600 | 0.1275 | 0.459 | 2.7 | 2.7 | yes
695854 | 020 | -200 | -200 | 020 | 850 | 0.4641 |  |  |  |  |  | no | IfcBuildingStorey - Top Constraint: Up to level: 030
741051 | 030 | -200 | 742.107 | 030 | 900 | 0.144092 | 942.107 | 0.153 | 0.144092 | 0.847601 | 0.847601 | no | IfcBuildingStorey - Top Constraint: Up to level: 030
2440637 | 030 | -200 | 740 | 030 | 900 | 0.142203 | 940 | 0.153 | 0.14382 | 0.846 | 0.83649 | no | IfcBuildingStorey - Top Constraint: Up to level: 030
2440979 | 030 | -200 | 742.692 | 030 | 710 | 0.112109 | 942.692 | 0.1207 | 0.113726 | 0.668974 | 0.659463 | no | IfcBuildingStorey - Top Constraint: Up to level: 030
2441645 | 030 | -200 | 740 | 030 | 745 | 0.11741 | 940 | 0.12665 | 0.119027 | 0.700156 | 0.690646 | no | IfcBuildingStorey - Top Constraint: Up to level: 030
2441819 | 030 | -200 | 0 | 030 | 745 | 0.11741 | 940 | 0.12665 | 0.119027 | 0.700156 | 0.690646 | no

# IfcWall: Basic Wall:BB_XX_Wand uit beton, 190 mm (32)
PredefinedType: SOLIDWALL
Cpset_Wall - LevelOfAccuracy: in te vullen door Buildwise
IfcClassificationReference - GVH_artnr 01: geen waarde gevonden; GVH_artnr 02: geen waarde gevonden; GVH_artnr 03: geen waarde gevonden; GVH_artnr 04: geen waarde gevonden; GVH_artnr 05: geen waarde gevonden; GVH_artnr 06: geen waarde gevonden
IfcRoot - Name: BB_XX_Wand uit beton, 190 mm
Qto_WallBaseQuantities - Width: 190
Pset_Condition - AssessmentCondition: Empty
Pset_EnvironmentalImpactIndicators - Reference: BB_XX_Wand uit beton, 190 mm; sets with these values: 2
Pset_WallCommon - Reference: BB_XX_Wand uit beton, 190 mm; IsExternal: yes; LoadBearing: no; ExtendToStructure: no
Name (Basic Wall:BB_XX_Wand uit beton, 190 mm:...) | In | Base Offset | Top Offset | Base Constraint | Length | NetVolume | Height | GrossFootprintArea | GrossVolume | GrossSideArea | NetSideArea
958179 | K20 | -400 | 0 | K20 | 6967.7 | 3.95903
968287 | K20 | 0 | 0 | K20 | 5942.34 | 2.33192 | Pset_WallCommon - FireRating: EI60
971436 | K20 | 0 | 0 | K20 | 2060 | 0.92972
1720987 | K20 | -400 | 0 | K20 | 6710 | 2.70845 | 2500 | 1.2749 | 2.70845 | 14.255 | 14.255
1721674 | K20 | -400 | 0 | K20 | 5290 | 1.21315 | 2500 | 1.0051 | 1.21315 | 6.385 | 6.385
930547 | K10 | -100 | 0 | K10 | 1090 | 0.433466 | 2440 | 0.2071 | 0.505324 | 2.6596 | 2.6596
1501351 | K10 | -1000 | 0 | K10 | 7795.6 | 1.24418 | 1240 | 1.48116 | 1.24418 | 6.54831 | 6.54831
2207046 | K10 | -1500 | 300 | K10 | 7780.6 | 2.03268 | 1800 | 1.47831 | 2.03268 | 10.6983 | 10.6983 | IfcBuildingStorey - Top Constraint: Up to level: K10
32128095 | K10 | 0 | 0 | K10 | 5360 | 0.945719 | 2320 | 1.0184 | 0.945719 | 4.97747 | 4.97747 | IfcClassificationReference - TDS_link: .\05 As Builtdossier\2. Bouwkunde\2.2. Stabiliteit\2.2.0 technische fiche's\TF S 4.3 A-beton.pdf; Pset_WallCommon - ThermalTransmittance: 8.42105
483293 | 000 | -200 | -200 | 000 | 925 | 0.667755 | IfcBuildingStorey - Top Constraint: Up to level: 010
504779 | 000 | -200 | -920 | 000 | 2655 | 1.22672 | 2880 | 0.50445 | 1.45282 | 7.6464 | 6.4564 | IfcBuildingStorey - Top Constraint: Up to level: 010
590217 | 000 | -200 | -930 | 000 | 2655 | 1.22167 | 2870 | 0.50445 | 1.44777 | 7.61985 | 6.42985 | Pset_WallCommon - FireRating: EI60; IfcBuildingStorey - Top Constraint: Up to level: 010
856528 | 010 | -200 | 0 | 010 | 2655 | 1.22672 | 2880 | 0.50445 | 1.45282 | 7.6464 | 6.4564 | Pset_WallCommon - FireRating: EI60
857996 | 010 | -200 | 0 | 010 | 2655 | 1.22672 | 2880 | 0.50445 | 1.45282 | 7.6464 | 6.4564 | Pset_WallCommon - FireRating: EI60
695708 | 020 | 840 | -200 | 020 | 1090 | 0.521608 | IfcBuildingStorey - Top Constraint: Up to level: 030
859789 | 020 | -200 | 0 | 020 | 2655 | 1.22672 | 2880 | 0.50445 | 1.45282 | 7.6464 | 6.4564 | Pset_WallCommon - FireRating: EI60
861179 | 020 | -200 | 0 | 020 | 2655 | 1.22605 | 2880 | 0.50445 | 1.45282 | 7.6464 | 6.4529 | Pset_WallCommon - FireRating: EI60
726494 | 030 | -200 | 0 | 030 | 5380 | 0.959061 | 940 | 1.0222 | 0.960868 | 5.0572 | 5.04769
728106 | 030 | -200 | 0 | 030 | 5975 | 1.06823 | 941 | 1.13525 | 1.06823 | 5.62226 | 5.62226
728216 | 030 | -200 | 0 | 030 | 3080.59 | 0.542701 | 940 | 0.57926 | 0.0358074 | 0.18846 | 2.89861
728227 | 030 | -200 | 0 | 030 | 9559.38 | 1.69979 | 940 | 1.81629 | 0.0358283 | 0.18857 | 9.01465 | Pset_WallCommon - FireRating: EI60
728232 | 030 | -200 | 0 | 030 | 6125 | 1.09505 | 941 | 1.16375 | 1.09505 | 5.76341 | 5.76341
728799 | 030 | -200 | 0 | 030 | 5559.87 | 0.991186 | 940 | 1.05638 | 0.992993 | 5.22628 | 5.21677
729534 | 030 | -200 | 840 | 030 | 8645 | 1.70825 | 1040 | 1.64255 | 1.70825 | 8.9908 | 8.9908 | IfcBuildingStorey - Top Constraint: Up to level: 030
735846 | 030 | -200 | 3400 | 030 | 7335 | 4.0658 | IfcBuildingStorey - Top Constraint: Up to level: 030
742550 | 030 | -200 | 3400 | 030 | 208.054 | 0.0884776 | 3600 | 0.0395302 | 0.142309 | 0.748993 | 0.748993 | IfcBuildingStorey - Top Constraint: Up to level: 030
743163 | 030 | -200 | 3400 | 030 | 207.696 | 0.0882325 | 3600 | 0.0394621 | 0.142064 | 0.747704 | 0.747704 | IfcBuildingStorey - Top Constraint: Up to level: 030
867841 | 030 | -200 | 0 | 030 | 2655 | 1.22672 | 2880 | 0.50445 | 1.45282 | 7.6464 | 6.4564 | Pset_WallCommon - FireRating: EI60
867846 | 030 | -200 | 0 | 030 | 2655 | 1.22672 | 2880 | 0.50445 | 1.45282 | 7.6464 | 6.4564 | Pset_WallCommon - FireRating: EI60
1536462 | 030 | -200 | 0 | 030 | 5535 | 0.986744 | 940 | 1.05165 | 0.988551 | 5.2029 | 5.19339
1553493 | 030 | -200 | 0 | 030 | 5569.87 | 0.992972 | 940 | 1.05828 | 0.994779 | 5.23568 | 5.22617
786253 | 040 | -200 | -250 | 040 | 2170.65 | 1.06652 | Pset_WallCommon - FireRating: EI60; IfcBuildingStorey - Top Constraint: Up to level: 050

# IfcWall: Basic Wall:BB_XX_Wand uit beton, 200 mm (142)
PredefinedType: SOLIDWALL
Cpset_Wall - LevelOfAccuracy: in te vullen door Buildwise
IfcRoot - Name: BB_XX_Wand uit beton, 200 mm
Qto_WallBaseQuantities - Width: 200
Pset_Condition - AssessmentCondition: Empty
Pset_EnvironmentalImpactIndicators - Reference: BB_XX_Wand uit beton, 200 mm; sets with these values: 2
Pset_WallCommon - Reference: BB_XX_Wand uit beton, 200 mm; IsExternal: yes
Name (Basic Wall:BB_XX_Wand uit beton, 200 mm:...) | In | Base Offset | Top Offset | Base Constraint | GVH_artnr 01 = GVH_artnr 02 = GVH_artnr 03 = GVH_artnr 04 = GVH_artnr 05 = GVH_artnr 06 | Length | NetVolume | LoadBearing | ExtendToStructure | Height | GrossFootprintArea | GrossVolume | GrossSideArea | NetSideArea | FireRating | Top Constraint
947785 | K20 | -400 | 0 | K20 | geen waarde gevonden | 8000 | 4.72816 | no | no
951022 | K20 | 0 | 0 | K20 | geen waarde gevonden | 5930 | 2.9503 | no | no | 2500 | 1.186 | 2.9503 | 14.7515 | 14.7515
954639 | K20 | 0 | 0 | K20 | geen waarde gevonden | 1805 | 0.787209 | no | no |  |  |  |  |  | EI60
954983 | K20 | 0 | 0 | K20 | geen waarde gevonden | 4900 | 2.4084 | no | no | 2700 | 0.980001 | 2.4084 | 12.042 | 12.042 | EI60 | Up to level: K10
955654 | K20 | 0 | 0 | K20 | geen waarde gevonden | 2100 | 0.52848 | no | no | 2200 | 0.42 | 0.52848 | 2.6424 | 2.6424 | EI60
955845 | K20 | 0 | 0 | K20 | geen waarde gevonden | 3105 | 1.5329 | no | no | 2500 | 0.621 | 1.5329 | 7.6645 | 7.6645 | EI60
956069 | K20 | 0 | 0 | K20 | geen waarde gevonden | 2300 | 1.12216 | no | no | 2500 | 0.46 | 1.12816 | 5.64082 | 5.64082 | EI60
956411 | K20 | 0 | 0 | K20 | geen waarde gevonden | 2400 | 1.11615 | no | no |  |  |  |  |  | EI60
956815 | K20 | 0 | 0 | K20 | geen waarde gevonden | 1161.04 | 0.43025 | no | no | 2245.82 | 0.212209 | 0.475106 | 2.37553 | 2.37553 | EI60
956890 | K20 | 0 | 0 | K20 | geen waarde gevonden | 1504.16 | 0.748324 | no | no | 2700 | 0.280833 | 0.790434 | 3.95217 | 3.95217 | EI60 | Up to level: K10
963286 | K20 | 0 | 0 | K20 | geen waarde gevonden | 2305 | 1.19593 | no | no | 2700 | 0.461 | 1.2214 | 6.10701 | 6.10701 | EI60 | Up to level: K10
964360 | K20 | 0 | 0 | K20 | geen waarde gevonden | 4500 | 2.289 | no | no | 2600 | 0.9 | 2.289 | 11.445 | 11.445
964541 | K20 | 0 | 0 | K20 | geen waarde gevonden | 5500 | 2.8444 | no | no | 2600 | 1.1 | 2.8444 | 14.222 | 14.222
964728 | K20 | 0 | -100 | K20 | geen waarde gevonden | 5700 | 2.934 | no | no | 2600 | 1.14 | 2.934 | 14.67 | 14.67 |  | Up to level: K10
965119 | K20 | 0 | 0 | K20 | geen waarde gevonden | 1400 | 0.68 | no | no | 2500 | 0.28 | 0.68 | 3.4 | 3.4 | EI60
965294 | K20 | 0 | 0 | K20 | geen waarde gevonden | 5500 | 2.924 | no | no |  |  |  |  |  | EI60 | Up to level: K10
965460 | K20 | 0 | 0 | K20 | geen waarde gevonden | 2500 | 1.30162 | no | no | 2700 | 0.5 | 1.32652 | 6.63262 | 6.63262 | EI60 | Up to level: K10
966063 | K20 | 0 | 0 | K20 | geen waarde gevonden | 5500 | 2.90763 | no | no |  |  |  |  |  | EI60 | Up to level: K10
966244 | K20 | 0 | 0 | K20 | geen waarde gevonden | 5215 | 2.18805 | no | no |  |  |  |  |  | EI60
966371 | K20 | 0 | 0 | K20 | geen waarde gevonden | 2300 | 1.242 | no | no | 2700 | 0.46 | 1.242 | 6.21 | 6.21 | EI60 | Up to level: K10
966654 | K20 | 0 | 0 | K20 | geen waarde gevonden | 5450 | 2.61 | no | no | 2700 | 1.09 | 2.898 | 14.49 | 13.05 | EI60 | Up to level: K10
967098 | K20 | 0 | 0 | K20 | geen waarde gevonden | 7500 | 3.82 | no | no | 2700 | 1.5 | 3.82 | 19.1 | 19.1 | EI60 | Up to level: K10
967327 | K20 | 0 | 0 | K20 | geen waarde gevonden | 5505 | 2.9422 | no | no | 2700 | 1.101 | 2.9422 | 14.711 | 14.711 |  | Up to level: K10
1065540 | K20 | -200 | 0 | K20 | geen waarde gevonden | 20633 | 8.77748 | no | no |  |  |  |  |  | EI60
1622426 | K20 | 0 | 0 | K20 | geen waarde gevonden | 10806.6 | 5.13413 | no | no | 2440 | 2.12132 | 5.15333 | 25.7666 | 25.7666 | EI60
806504 | K10 | -100 | 0 | K10 | geen waarde gevonden | 7005 | 3.37725 | no | no | 2730 | 1.401 | 3.37725 | 16.8863 | 16.8863 | EI60
806728 | K10 | -200 | 0 | K10 | geen waarde gevonden | 2800 | 1.68668 | no | no | 3240 | 0.56 | 1.68668 | 8.4334 | 8.4334 | EI60
808885 | K10 | 0 | 0 | K10 | geen waarde gevonden | 5365 | 3.04007 | no | no | 3040 | 1.073 | 3.26192 | 16.3096 | 15.2003
809555 | K10 | 0 | -550 | K10 | geen waarde gevonden | 36205 | 18.0537 | no | no | 2690 | 7.24101 | 18.0613 | 90.3067 | 90.3067 |  | Up to level: 000
814780 | K10 | -100 | -80 | K10 | geen waarde gevonden | 5800 | 3.6916 | no | no | 3260 | 1.16 | 3.6916 | 18.458 | 18.458 | EI60 | Up to level: 000
815041 | K10 | -100 | -80 | K10 | geen waarde gevonden | 4450 | 2.9054 | no | no |  |  |  |  |  | EI60 | Up to level: 000
815418 | K10 | -100 | -80 | K10 | geen waarde gevonden | 5700 | 3.6684 | no | no | 3260 | 1.14 | 3.6684 | 18.342 | 18.342 |  | Up to level: 000
815498 | K10 | -100 | -80 | K10 | geen waarde gevonden | 5200 | 3.3709 | no | no | 3260 | 1.04 | 3.3709 | 16.8545 | 16.8545 |  | Up to level: 000
817466 | K10 | 0 | -80 | K10 | geen waarde gevonden | 4055 | 2.56194 | no | no | 3160 | 0.811 | 2.56194 | 12.8097 | 12.8097 | EI60 | Up to level: 000
819915 | K10 | 0 | 0 | K10 | geen waarde gevonden | 5142.5 | 1.92777 | no | no | 2320 | 1.0285 | 1.92776 | 9.63882 | 9.63882 | EI60
823096 | K10 | 0 | -200 | K10 | geen waarde gevonden | 1545.58 | 0.992307 | no | no |  |  |  |  |  | EI60 | Up to level: 000
823443 | K10 | 0 | 0 | K10 | geen waarde gevonden | 6870 | 3.70463 | no | no | 3040 | 1.374 | 3.71462 | 18.5731 | 18.5731 | EI60
824893 | K10 | -200 | 0 | K10 | geen waarde gevonden | 254.29 | 0.0858214 | no | no | 2520 | 0.0508579 | 0.126636 | 0.633181 | 0.633181 | EI60
824987 | K10 | -200 | 0 | K10 | geen waarde gevonden | 2855.31 | 1.01139 | no | no | 2520 | 0.571061 | 1.43907 | 7.19537 | 5.05697 | EI60
825748 | K10 | -200 | 0 | K10 | geen waarde gevonden | 132.712 | 0.0668869 | no | no | 2520 | 0.0265424 | 0.1008 | 0.504 | 0.504 | EI60
826261 | K10 | 0 | -80 | K10 | geen waarde gevonden | 4700 | 2.5464 | no | no | 3160 | 0.940001 | 2.5464 | 12.732 | 12.732 | EI60 | Up to level: 000
826311 | K10 | -200 | 0 | K10 | geen waarde gevonden | 2300 | 1.31102 | no | no | 3240 | 0.46 | 1.32602 | 6.63012 | 6.63012 | EI60
827528 | K10 | 0 | -80 | K10 | geen waarde gevonden | 6595 | 4.16804 | no | no | 3160 | 1.319 | 4.16804 | 20.8402 | 20.8402 | EI60 | Up to level: 000
828406 | K10 | 0 | 0 | K10 | geen waarde gevonden | 5600 | 3.4968 | no | no | 3140 | 1.12 | 3.4968 | 17.484 | 17.484
831183 | K10 | 0 | -80 | K10 | geen waarde gevonden | 2500 | 1.41334 | no | no |  |  |  |  |  | EI60 | Up to level: 000
831453 | K10 | 0 | -80 | K10 | geen waarde gevonden | 8904.65 | 5.61916 | no | no | 3160 | 1.78093 | 5.62437 | 28.1219 | 28.1219 | EI60 | Up to level: 000
842150 | K10 | 0 | -80 | K10 | geen waarde gevonden | 5500 | 3.1 | no | no | 3160 | 1.1 | 3.428 | 17.14 | 15.5 | EI60 | Up to level: 000
929567 | K10 | 0 | 0 | K10 | geen waarde gevonden | 3899.9 | 2.30946 | no | no | 3040 | 0.779981 | 2.30946 | 11.5473 | 11.5473
929570 | K10 | 0 | 0 | K10 | geen waarde gevonden | 2994.93 | 1.65055 | no | yes | 2890 | 0.598986 | 1.65055 | 8.25274 | 8.25274
929571 | K10 | 0 | 0 | K10 | geen waarde gevonden | 25035 | 13.6277 | no | yes | 2723.74 | 5.007 | 13.6372 | 68.1858 | 68.1858
1797249 | K10 | 0 | 0 | K10 | geen waarde gevonden | 1115 | 0.61487 | no | no
33205063 | K10 | 0 | 450 | K10 | geen waarde gevonden | 2100.04 | 1.45963 | no | no |  |  |  |  |  |  | Up to level: 000
33205311 | K10 | 0 | 450 | K10 | geen waarde gevonden | 480 | 0.26688 | no | no | 2780 | 0.096 | 0.26688 | 1.3344 | 1.3344 | EI60 | Up to level: 000
33728107 | K10 | 1490 | 0 | K10 |  | 1650.02 | 0.495504 | yes | no |  |  |  |  |  |  | Up to level: 000 | IfcClassificationReference - TDS_link: .\05 As Builtdossier\2. Bouwkunde\2.2. Stabiliteit\2.2.0 technische fiche's\TF S 4.3 A-beton.pdf; Pset_WallCommon - ThermalTransmittance: 8
33728177 | K10 | 1490 | 0 | K10 |  | 1450.02 | 0.435504 | yes | no | 1750 | 0.290003 | 0.435504 | 2.17752 | 2.17752 |  | Up to level: 000 | IfcClassificationReference - TDS_link: .\05 As Builtdossier\2. Bouwkunde\2.2. Stabiliteit\2.2.0 technische fiche's\TF S 4.3 A-beton.pdf; Pset_WallCommon - ThermalTransmittance: 8
478941 | 000 | -200 | -200 | 000 | geen waarde gevonden | 2997.4 | 2.07327 | no | no |  |  |  |  |  |  | Up to level: 010
495783 | 000 | -80 | -80 | 000 | geen waarde gevonden | 5300 | 3.816 | no | no | 3600 | 1.06 | 3.816 | 19.08 | 19.08 | EI60 | Up to level: 010
495989 | 000 | -80 | -80 | 000 | geen waarde gevonden | 7700 | 5.5944 | no | no | 3720 | 1.54 | 5.5944 | 27.972 | 27.972 | EI60 | Up to level: 010
496654 | 000 | -80 | -80 | 000 | geen waarde gevonden | 2300 | 1.15104 | no | no | 3600 | 0.46 | 1.15104 | 5.7552 | 5.7552 | EI60 | Up to level: 010
500674 | 000 | -200 | 0 | 000 | geen waarde gevonden | 6820 | 2.83694 | no | no | 2880 | 1.364 | 2.83694 | 14.1847 | 14.1847 | EI60
500759 | 000 | -200 | 0 | 000 | geen waarde gevonden | 2100 | 0.6672 | no | no | 3600 | 0.42 | 1.512 | 7.56 | 3.336 | EI60
501723 | 000 | -80 | -80 | 000 | geen waarde gevonden | 4700 | 3.384 | no | no | 3600 | 0.940001 | 3.384 | 16.92 | 16.92 | EI60 | Up to level: 010
503520 | 000 | -80 | -200 | 000 | geen waarde gevonden | 5500 | 2.904 | no | no | 3480 | 1.1 | 3.828 | 19.14 | 14.52 |  | Up to level: 010
503695 | 000 | -80 | -80 | 000 | geen waarde gevonden | 7500 | 5.46228 | no | no | 3720 | 1.5 | 5.46228 | 27.3114 | 27.3114 |  | Up to level: 010
503980 | 000 | -80 | -80 | 000 | geen waarde gevonden | 2707.5 | 1.88244 | no | no |  |  |  |  |  | EI60 | Up to level: 010
504261 | 000 | -80 | -200 | 000 | geen waarde gevonden | 2300 | 1.12214 | no | no | 3480 | 0.46 | 1.12214 | 5.6107 | 5.6107 |  | Up to level: 010
505461 | 000 | -80 | -80 | 000 | geen waarde gevonden | 8915.25 | 6.4091 | no | no | 3600 | 1.78305 | 6.4091 | 32.0455 | 32.0455 | EI60 | Up to level: 010
505786 | 000 | -80 | -80 | 000 | geen waarde gevonden | 1400 | 0.99812 | no | no | 3600 | 0.28 | 0.99812 | 4.9906 | 4.9906 | EI60 | Up to level: 010
505889 | 000 | -80 | -80 | 000 | geen waarde gevonden | 2100 | 1.22064 | no | no |  |  |  |  |  | EI60 | Up to level: 010
506200 | 000 | -80 | -80 | 000 | geen waarde gevonden | 5015 | 2.50094 | no | no | 3600 | 1.003 | 2.50094 | 12.5047 | 12.5047 | EI60 | Up to level: 010
506563 | 000 | -80 | -80 | 000 | geen waarde gevonden | 2507.01 | 1.84821 | no | no |  |  |  |  |  |  | Up to level: 010
506807 | 000 | -80 | -80 | 000 | geen waarde gevonden | 2400 | 1.79154 | no | no |  |  |  |  |  | EI60 | Up to level: 010
506881 | 000 | -80 | -80 | 000 | geen waarde gevonden | 1900 | 1.368 | no | no | 3600 | 0.38 | 1.368 | 6.84 | 6.84 | EI60 | Up to level: 010
507164 | 000 | -80 | -80 | 000 | geen waarde gevonden | 6615 | 4.81368 | no | no | 3720 | 1.323 | 4.81368 | 24.0684 | 24.0684 | EI60 | Up to level: 010
507361 | 000 | -100 | -80 | 000 | geen waarde gevonden | 3616.01 | 2.68078 | no | no |  |  |  |  |  |  | Up to level: 010
863721 | 000 | -400 | 0 | 000 | geen waarde gevonden | 2472.48 | 1.4418 | no | no | 3080 | 0.376269 | 1.5034 | 7.51701 | 7.51701 | EI60
865642 | 000 | -400 | -200 | 000 | geen waarde gevonden | 2465.4 | 1.75303 | no | no | 3800 | 0.49308 | 1.82903 | 9.14517 | 9.14517 | EI60 | Up to level: 010
1984122 | 000 | -200 | -80 | 000 | geen waarde gevonden | 2500 | 1.35504 | no | no | 3720 | 0.5 | 1.86 | 9.3 | 6.7752 | EI60 | Up to level: 010
2216294 | 000 | -1000 | 450 | 000 | geen waarde gevonden | 2600 | 0.745 | no | no |  |  |  |  |  |  | Up to level: 000
33204624 | 000 | -1500 | 0 | 000 | geen waarde gevonden | 9120 | 2.6736 | no | no | 1500 | 1.824 | 2.6736 | 13.368 | 13.368 |  | Up to level: 000
646193 | 010 | -200 | -200 | 010 | geen waarde gevonden | 2990.06 | 2.06806 | no | no |  |  |  |  |  |  | Up to level: 020
648664 | 010 | -80 | -80 | 010 | geen waarde gevonden | 5300 | 3.816 | no | no | 3600 | 1.06 | 3.816 | 19.08 | 19.08 | EI60 | Up to level: 020
648667 | 010 | -80 | -80 | 010 | geen waarde gevonden | 2300 | 1.15104 | no | no | 3600 | 0.46 | 1.15104 | 5.7552 | 5.7552 | EI60 | Up to level: 020
649183 | 010 | -200 | -920 | 010 | geen waarde gevonden | 6670 | 2.79303 | no | no | 2880 | 1.334 | 2.79303 | 13.9651 | 13.9651 | EI60 | Up to level: 020
649184 | 010 | -200 | -200 | 010 | geen waarde gevonden | 2100 | 1.512 | no | no | 3600 | 0.42 | 1.512 | 7.56 | 7.56 | EI60 | Up to level: 020
649185 | 010 | -200 | -200 | 010 | geen waarde gevonden | 6670 | 4.8024 | no | no | 3600 | 1.334 | 4.8024 | 24.012 | 24.012 | EI60 | Up to level: 020
649380 | 010 | -80 | -80 | 010 | geen waarde gevonden | 4900 | 3.3888 | no | no | 3600 | 0.980001 | 3.3888 | 16.944 | 16.944 | EI60 | Up to level: 020
649382 | 010 | -80 | -80 | 010 | geen waarde gevonden | 2500 | 1.23504 | no | yes | 3480 | 0.5 | 1.23504 | 6.1752 | 6.1752 |  | Up to level: 020
650658 | 010 | -80 | -80 | 010 | geen waarde gevonden | 2300 | 1.656 | no | no | 3600 | 0.46 | 1.656 | 8.28 | 8.28 | EI60 | Up to level: 020
650664 | 010 | -80 | -80 | 010 | geen waarde gevonden | 5215 | 3.24984 | no | no | 3600 | 1.043 | 3.24984 | 16.2492 | 16.2492 | EI60 | Up to level: 020
650670 | 010 | -80 | -80 | 010 | geen waarde gevonden | 2300 | 1.656 | no | no | 3600 | 0.46 | 1.656 | 8.28 | 8.28 | EI60 | Up to level: 020
651376 | 010 | -80 | -80 | 010 | geen waarde gevonden | 3615 | 2.62651 | no | no |  |  |  |  |  |  | Up to level: 020
866428 | 010 | -200 | 0 | 010 | geen waarde gevonden | 320 | 0.18432 | no | no | 2880 | 0.064 | 0.18432 | 0.9216 | 0.9216
866429 | 010 | -200 | 0 | 010 | geen waarde gevonden | 2465.4 | 1.70549 | no | no | 3600 | 0.49308 | 1.77509 | 8.87545 | 8.87545 | EI60
2149424 | 010 | -200 | 840 | 010 | geen waarde gevonden | 3513.2 | 0.720955 | no | no |  |  |  |  |  |  | Up to level: 010
2149425 | 010 | -200 | -200 | 010 | geen waarde gevonden | 3127.63 | 2.17442 | no | no |  |  |  |  |  |  | Up to level: 020
695730 | 020 | -200 | -200 | 020 | geen waarde gevonden | 2990.6 | 2.18889 | no | no |  |  |  |  |  |  | Up to level: 030
695740 | 020 | -80 | -80 | 020 | geen waarde gevonden | 5300 | 3.816 | no | no | 3600 | 1.06 | 3.816 | 19.08 | 19.08 | EI60 | Up to level: 030
695743 | 020 | -80 | -80 | 020 | geen waarde gevonden | 2300 | 1.15104 | no | no | 3600 | 0.46 | 1.15104 | 5.7552 | 5.7552 | EI60 | Up to level: 030
695767 | 020 | -200 | -920 | 020 | geen waarde gevonden | 4724 | 2.71778 | no | no | 2880 | 0.9448 | 2.71778 | 13.5889 | 13.5889 | EI60 | Up to level: 030
695768 | 020 | -200 | -200 | 020 | geen waarde gevonden | 2100 | 1.512 | no | no | 3600 | 0.42 | 1.512 | 7.56 | 7.56 | EI60 | Up to level: 030
695772 | 020 | -200 | -200 | 020 | geen waarde gevonden | 5500 | 3.9552 | no | no |  |  |  |  |  | EI60 | Up to level: 030
695776 | 020 | -200 | -200 | 020 | geen waarde gevonden | 990 | 0.78 | no | no |  |  |  |  |  | EI60 | Up to level: 030
695781 | 020 | -80 | -80 | 020 | geen waarde gevonden | 4900 | 3.528 | no | no | 3600 | 0.980001 | 3.528 | 17.64 | 17.64 | EI60 | Up to level: 030
695783 | 020 | -80 | -80 | 020 | geen waarde gevonden | 2300 | 1.15104 | no | no | 3600 | 0.46 | 1.15104 | 5.7552 | 5.7552 | EI60 | Up to level: 030
695797 | 020 | -80 | -80 | 020 | geen waarde gevonden | 2300 | 1.656 | no | no | 3600 | 0.46 | 1.656 | 8.28 | 8.28 | EI60 | Up to level: 030
695801 | 020 | -80 | -80 | 020 | geen waarde gevonden | 2200 | 1.5792 | no | no |  |  |  |  |  |  | Up to level: 030
695803 | 020 | -80 | -80 | 020 | geen waarde gevonden | 5015 | 3.10584 | no | no | 3600 | 1.003 | 3.10584 | 15.5292 | 15.5292 | EI60 | Up to level: 030
695806 | 020 | -80 | -80 | 020 | geen waarde gevonden | 2496.01 | 1.74026 | no | no |  |  |  |  |  |  | Up to level: 030
695808 | 020 | -80 | -80 | 020 | geen waarde gevonden | 1900 | 1.368 | no | no | 3600 | 0.38 | 1.368 | 6.84 | 6.84 | EI60 | Up to level: 030
695841 | 020 | -80 | -80 | 020 | geen waarde gevonden | 3615 | 2.61988 | no | no |  |  |  |  |  |  | Up to level: 030
2042687 | 020 | -80 | -80 | 020 | geen waarde gevonden | 2200 | 1.07115 | no | no | 3600 | 0.44 | 1.07115 | 5.35575 | 5.35575 | EI60 | Up to level: 030
2149023 | 020 | -200 | -200 | 020 | geen waarde gevonden | 2824.63 | 1.95273 | no | no |  |  |  |  |  |  | Up to level: 030
705216 | 030 | -80 | 3400 | 030 | geen waarde gevonden | 2300 | 0.90724 | no | no | 3070 | 0.46 | 0.90724 | 4.5362 | 4.5362 | EI60 | Up to level: 030
705239 | 030 | -200 | 3400 | 030 | geen waarde gevonden | 2100 | 1.512 | no | no | 3600 | 0.42 | 1.512 | 7.56 | 7.56 | EI60 | Up to level: 030
705244 | 030 | -80 | 3190 | 030 | geen waarde gevonden | 5780 | 3.8952 | no | no | 3480 | 1.156 | 3.8952 | 19.476 | 19.476 | EI60 | Up to level: 030
705249 | 030 | -200 | 3400 | 030 | geen waarde gevonden | 275 | 0.17545 | no | no | 3190 | 0.055 | 0.17545 | 0.877251 | 0.877251 |  | Up to level: 030
705250 | 030 | -80 | 3190 | 030 | geen waarde gevonden | 4900 | 3.16992 | no | no | 3270 | 0.980001 | 3.16992 | 15.8496 | 15.8496 | EI60 | Up to level: 030
705252 | 030 | -80 | 3190 | 030 | geen waarde gevonden | 4900 | 3.18981 | no | no | 3270 | 0.980001 | 3.18981 | 15.9491 | 15.9491 | EI60 | Up to level: 030
705268 | 030 | -80 | 3400 | 030 | geen waarde gevonden | 2500 | 1.6963 | no | no | 3480 | 0.5 | 1.6963 | 8.4815 | 8.4815 | EI60 | Up to level: 030
705269 | 030 | -80 | 3400 | 030 | geen waarde gevonden | 8690 | 6.03914 | no | no | 3480 | 1.738 | 6.03914 | 30.1957 | 30.1957 | EI60 | Up to level: 030
705271 | 030 | -80 | 3400 | 030 | geen waarde gevonden | 1400 | 0.964747 | no | no |  |  |  |  |  | EI60 | Up to level: 030
705274 | 030 | -80 | 3400 | 030 | geen waarde gevonden | 5015 | 2.98548 | no | no | 3480 | 1.003 | 2.98548 | 14.9274 | 14.9274 | EI60 | Up to level: 030
705277 | 030 | -80 | 3400 | 030 | geen waarde gevonden | 2506.01 | 1.68271 | no | no |  |  |  |  |  |  | Up to level: 030
705278 | 030 | -80 | 3400 | 030 | geen waarde gevonden | 2400 | 1.59452 | no | no |  |  |  |  |  | EI60 | Up to level: 030
705280 | 030 | -80 | 3400 | 030 | geen waarde gevonden | 2300 | 1.5571 | no | no | 3480 | 0.46 | 1.5571 | 7.7855 | 7.7855 | EI60 | Up to level: 030
705281 | 030 | -80 | 3400 | 030 | geen waarde gevonden | 6715 | 4.73622 | no | no |  |  |  |  |  | EI60 | Up to level: 030
705312 | 030 | -80 | 3400 | 030 | geen waarde gevonden | 3616.01 | 2.54293 | no | no |  |  |  |  |  |  | Up to level: 030
705313 | 030 | -80 | 3400 | 030 | geen waarde gevonden | 2190 | 1.51826 | no | no | 3480 | 0.438 | 1.51826 | 7.5913 | 7.5913 | EI60 | Up to level: 030
867754 | 030 | -200 | 0 | 030 | geen waarde gevonden | 6780 | 2.85639 | no | no | 2880 | 1.356 | 2.85639 | 14.2819 | 14.2819 | EI60
867764 | 030 | -200 | 0 | 030 | geen waarde gevonden | 210 | 0.12096 | no | no | 2880 | 0.042 | 0.12096 | 0.6048 | 0.6048
867765 | 030 | -200 | 0 | 030 | geen waarde gevonden | 2465.4 | 1.67961 | no | no |  |  |  |  |  | EI60
2050532 | 030 | -80 | 3190 | 030 | geen waarde gevonden | 2300 | 0.99924 | no | no | 3270 | 0.46 | 0.99924 | 4.9962 | 4.9962 | EI60 | Up to level: 030
34148108 | 030 | 3400 | 3420 | 030 |  | 21080 | 10.788 | yes | no |  |  |  |  |  |  | Up to level: 040 | IfcClassificationReference - TDS_link: .\05 As Builtdossier\2. Bouwkunde\2.2. Stabiliteit\2.2.0 technische fiche's\TF S 4.3 A-beton.pdf; Pset_WallCommon - ThermalTransmittance: 8
786100 | 040 | -200 | -250 | 040 | geen waarde gevonden | 2031.3 | 0.957838 | no | no | 2500 | 0.383135 | 0.976124 | 4.88062 | 4.88062 | EI60 | Up to level: 050
1034721 | 040 | -200 | -250 | 040 | geen waarde gevonden | 3140 | 0.92762 | no | no | 2600 | 0.628 | 0.92762 | 4.6381 | 4.6381 |  | Up to level: 050
1043798 | 040 | -200 | -250 | 040 | geen waarde gevonden | 2300 | 1.15 | no | no | 2500 | 0.46 | 1.15 | 5.75 | 5.75 |  | Up to level: 050
1044836 | 040 | -200 | -250 | 040 | geen waarde gevonden | 3200 | 1.60512 | no | no | 2600 | 0.64 | 1.60512 | 8.0256 | 8.0256 | EI60 | Up to level: 050
1044959 | 040 | -200 | -350 | 040 | geen waarde gevonden | 5015 | 2.08856 | no | no | 2500 | 1.003 | 2.08856 | 10.4428 | 10.4428 | EI60 | Up to level: 050
34084856 | 040 | -200 | 2300 | 040 |  | 2171.83 | 0.964927 | yes | no |  |  |  |  |  | EI60 | Up to level: 040 | IfcClassificationReference - TDS_link: .\05 As Builtdossier\2. Bouwkunde\2.2. Stabiliteit\2.2.0 technische fiche's\TF S 4.3 A-beton.pdf; Pset_WallCommon - ThermalTransmittance: 8
34197676 | 040 | -200 | 0 | 040 |  | 5590 | 2.73376 | yes | no | 2600 | 1.118 | 2.73376 | 13.6688 | 13.6688 | IfcClassificationReference - TDS_link: .\05 As Builtdossier\2. Bouwkunde\2.2. Stabiliteit\2.2.0 technische fiche's\TF S 4.3 A-beton.pdf; Pset_WallCommon - ThermalTransmittance: 8; IfcElement - Tag: W 404; Mark: W 404
34199482 | 040 | -200 | 0 | 040 |  | 5799.89 | 1.68699 | yes | no | 2600 | 1.13998 | 3.01594 | 15.0797 | 8.69493 | IfcClassificationReference - TDS_link: .\05 As Builtdossier\2. Bouwkunde\2.2. Stabiliteit\2.2.0 technische fiche's\TF S 4.3 A-beton.pdf; Pset_WallCommon - ThermalTransmittance: 8; IfcElement - Tag: W 402; Mark: W 402

# IfcWall: Basic Wall:BB_XX_Wand uit beton, 240 mm, Basic Wall:BB_XX_Wand uit beton, 240 mm:34109475
In: K20
PredefinedType: SOLIDWALL
Cpset_Wall - LevelOfAccuracy: in te vullen door Buildwise
IfcBuildingStorey - Base Offset: -300; Top Offset: 0; Base Constraint: K20; Top Constraint: Up to level: K10
IfcClassificationReference - TDS_link: .\05 As Builtdossier\2. Bouwkunde\2.2. Stabiliteit\2.2.0 technische fiche's\TF S 4.3 A-beton.pdf
IfcRoot - Name: BB_XX_Wand uit beton, 240 mm
Qto_WallBaseQuantities - Length: 20951.6; NetVolume: 14.4021; Width: 240
Pset_Condition - AssessmentCondition: Empty
Pset_EnvironmentalImpactIndicators - Reference: BB_XX_Wand uit beton, 240 mm; sets with these values: 2
Pset_WallCommon - Reference: BB_XX_Wand uit beton, 240 mm; FireRating: EI60; ThermalTransmittance: 6.66667; IsExternal: yes; LoadBearing: yes; ExtendToStructure: no

# IfcWall: Basic Wall:BB_XX_Wand uit beton, 300 mm, Basic Wall:BB_XX_Wand uit beton, 300 mm:967610
In: K20
PredefinedType: SOLIDWALL
Cpset_Wall - LevelOfAccuracy: in te vullen door Buildwise
IfcBuildingStorey - Base Offset: 0; Top Offset: 0; Base Constraint: K20
IfcClassificationReference - GVH_artnr 01: geen waarde gevonden; GVH_artnr 02: geen waarde gevonden; GVH_artnr 03: geen waarde gevonden; GVH_artnr 04: geen waarde gevonden; GVH_artnr 05: geen waarde gevonden; GVH_artnr 06: geen waarde gevonden
IfcRoot - Name: BB_XX_Wand uit beton, 300 mm
Qto_WallBaseQuantities - Length: 1090; NetVolume: 0.808934; Height: 2500; Width: 300; GrossFootprintArea: 0.327; GrossVolume: 0.80895; GrossSideArea: 2.6965; NetSideArea: 2.6965
Pset_Condition - AssessmentCondition: Empty
Pset_EnvironmentalImpactIndicators - Reference: BB_XX_Wand uit beton, 300 mm; sets with these values: 2
Pset_WallCommon - Reference: BB_XX_Wand uit beton, 300 mm; FireRating: EI60; IsExternal: yes; LoadBearing: no; ExtendToStructure: no

# IfcWall: Basic Wall:BB_XX_Wand uit beton, 350 mm, Basic Wall:BB_XX_Wand uit beton, 350 mm:34113913
In: K10
PredefinedType: SOLIDWALL
Cpset_Wall - LevelOfAccuracy: in te vullen door Buildwise
IfcBuildingStorey - Base Offset: -979.987; Top Offset: 770; Base Constraint: K10; Top Constraint: Up to level: K10
IfcClassificationReference - TDS_link: .\05 As Builtdossier\2. Bouwkunde\2.2. Stabiliteit\2.2.0 technische fiche's\TF S 4.3 A-beton.pdf
IfcRoot - Name: BB_XX_Wand uit beton, 350 mm
Qto_WallBaseQuantities - Length: 5747.5; NetVolume: 2.66802; Height: 1749.99; Width: 350; GrossFootprintArea: 2.01163; GrossVolume: 2.66802; GrossSideArea: 7.62293; NetSideArea: 7.62293
Pset_Condition - AssessmentCondition: Empty
Pset_EnvironmentalImpactIndicators - Reference: BB_XX_Wand uit beton, 350 mm; sets with these values: 2
Pset_WallCommon - Reference: BB_XX_Wand uit beton, 350 mm; ThermalTransmittance: 4.57143; IsExternal: yes; LoadBearing: yes; ExtendToStructure: no

# IfcWall: Basic Wall:BB_XX_Wand uit beton, 400 mm (2)
In: K10
PredefinedType: SOLIDWALL
Cpset_Wall - LevelOfAccuracy: in te vullen door Buildwise
IfcBuildingStorey - Base Offset: 0; Top Offset: -460; Base Constraint: K10; Top Constraint: Up to level: 000
IfcClassificationReference - GVH_artnr 01: geen waarde gevonden; GVH_artnr 02: geen waarde gevonden; GVH_artnr 03: geen waarde gevonden; GVH_artnr 04: geen waarde gevonden; GVH_artnr 05: geen waarde gevonden; GVH_artnr 06: geen waarde gevonden
IfcRoot - Name: BB_XX_Wand uit beton, 400 mm
Qto_WallBaseQuantities - Length: 925; NetVolume: 0.983412; Height: 2780; Width: 400; GrossFootprintArea: 0.37; GrossVolume: 0.983412; GrossSideArea: 2.45853; NetSideArea: 2.45853
Pset_Condition - AssessmentCondition: Empty
Pset_EnvironmentalImpactIndicators - Reference: BB_XX_Wand uit beton, 400 mm; sets with these values: 2
Pset_WallCommon - Reference: BB_XX_Wand uit beton, 400 mm; IsExternal: yes; LoadBearing: no; ExtendToStructure: no
Name (Basic Wall:BB_XX_Wand uit beton, 400 mm:...)
996836
1923625

# IfcWall: Basic Wall:BB_XX_Wand uit metselwerk, 140 mm (51)
PredefinedType: SOLIDWALL
Cpset_Wall - LevelOfAccuracy: in te vullen door Buildwise
IfcClassificationReference - GVH_artnr 01: geen waarde gevonden; GVH_artnr 02: geen waarde gevonden; GVH_artnr 03: geen waarde gevonden; GVH_artnr 04: geen waarde gevonden; GVH_artnr 05: geen waarde gevonden; GVH_artnr 06: geen waarde gevonden
IfcRoot - Name: BB_XX_Wand uit metselwerk, 140 mm
Qto_WallBaseQuantities - Width: 140
Pset_Condition - AssessmentCondition: Empty
Pset_EnvironmentalImpactIndicators - Reference: BB_XX_Wand uit metselwerk, 140 mm; sets with these values: 2
Pset_WallCommon - Reference: BB_XX_Wand uit metselwerk, 140 mm; IsExternal: yes; LoadBearing: no; ExtendToStructure: no
Name (Basic Wall:BB_XX_Wand uit metselwerk, 140 mm:...) | In | Base Offset | Top Offset | Base Constraint | Top Constraint | Length | NetVolume | Height | GrossFootprintArea | GrossVolume | GrossSideArea = NetSideArea
1300325 | K20 | 0 | 0 | K20 | Up to level: K10 | 3800 | 1.32542 | 2700 | 0.532001 | 1.32542 | 9.46726
509435 | 000 | -80 | -280 | 000 | Up to level: 010 | 1965 | 0.599249 | 3400 | 0.2751 | 0.600278 | 4.2877
509787 | 000 | -200 | -200 | 000 | Up to level: 010 | 640 | 0.31976 | 3600 | 0.0896 | 0.31976 | 2.284 | Pset_WallCommon - FireRating: EI60
510402 | 000 | -200 | -200 | 000 | Up to level: 010 | 1123.16 | 0.512633 | 3600 | 0.157243 | 0.536937 | 3.83526 | Pset_WallCommon - FireRating: EI60
510436 | 000 | -200 | -200 | 000 | Up to level: 010 | 983.163 | 0.460234 | 3600 | 0.137643 | 0.495514 | 3.53939 | Pset_WallCommon - FireRating: EI60
512464 | 000 | -200 | -200 | 000 | Up to level: 010 | 589.97 | 0.29043 | 3600 | 0.0825957 | 0.29043 | 2.0745 | Pset_WallCommon - FireRating: EI60
588168 | 000 | -80 | -280 | 000 | Up to level: 010 | 2247.01 | 0.697631 | 3400 | 0.292902 | 0.730951 | 5.22108
1184347 | 000 | -80 | -280 | 000 | Up to level: 010 | 2400 | 0.869764 | 3400 | 0.336 | 0.869764 | 6.2126
1184483 | 000 | -80 | -280 | 000 | Up to level: 010 | 1010 | 0.223104 | 3400 | 0.1414 | 0.223104 | 1.5936
1184630 | 000 | -80 | -280 | 000 | Up to level: 010 | 3260 | 1.2941 | 3400 | 0.4564 | 1.2941 | 9.2436
1270143 | 000 | -80 | -280 | 000 | Up to level: 010 | 1030 | 0.232624 | 3400 | 0.1442 | 0.232624 | 1.6616
1270144 | 000 | -80 | -280 | 000 | Up to level: 010 | 3120 | 1.22746 | 3400 | 0.4368 | 1.22746 | 8.7676
1270145 | 000 | -80 | -280 | 000 | Up to level: 010 | 2340 | 0.841204 | 3400 | 0.3276 | 0.841204 | 6.0086
2001347 | 000 | -280 | 2000 | 000 | Up to level: 000 | 2206.67 | 0.255643 | 1655 | 0.308934 | 0.255643 | 1.82602
649119 | 010 | -200 | -200 | 010 | Up to level: 020 | 1130 | 0.515908 | 3600 | 0.1582 | 0.54191 | 3.87078 | Pset_WallCommon - FireRating: EI60
649120 | 010 | -200 | -200 | 010 | Up to level: 020 | 983.163 | 0.460234 | 3600 | 0.137643 | 0.495514 | 3.53939 | Pset_WallCommon - FireRating: EI60
650781 | 010 | -80 | -480 | 010 | Up to level: 020 | 838.614 | 0.312979 | 3200 | 0.097806 | 0.312979 | 2.23557 | Pset_WallCommon - FireRating: EI60
650919 | 010 | -80 | -280 | 010 | Up to level: 020 | 1965 | 0.600278 | 3400 | 0.2751 | 0.600278 | 4.2877
650923 | 010 | -80 | -280 | 010 | Up to level: 020 | 2747.01 | 0.939195 | 3400 | 0.374781 | 0.972515 | 6.94653
650924 | 010 | -80 | -480 | 010 | Up to level: 020 | 1462.29 | 0.592386 | 3200 | 0.185121 | 0.592386 | 4.23133
686853 | 010 | -200 | -200 | 010 | Up to level: 020 | 928.159 | 0.432512 | 3600 | 0.129942 | 0.467792 | 3.34137 | Pset_WallCommon - FireRating: EI60
1210433 | 010 | -80 | -280 | 010 | Up to level: 020 | 1150 | 0.289744 | 3400 | 0.161 | 0.289744 | 2.0696
1210488 | 010 | -80 | -280 | 010 | Up to level: 020 | 3120 | 1.22746 | 3400 | 0.4368 | 1.22746 | 8.7676
1210737 | 010 | -80 | -280 | 010 | Up to level: 020 | 2260 | 0.803124 | 3400 | 0.3164 | 0.803124 | 5.7366
1213677 | 010 | -80 | -280 | 010 | Up to level: 020 | 2260 | 0.801612 | 3400 | 0.3164 | 0.801612 | 5.7258
1213893 | 010 | -80 | -280 | 010 | Up to level: 020 | 1150 | 0.289744 | 3400 | 0.161 | 0.289744 | 2.0696
1214193 | 010 | -80 | -280 | 010 | Up to level: 020 | 3120 | 1.22746 | 3400 | 0.4368 | 1.22746 | 8.7676
695763 | 020 | -200 | -200 | 020 | Up to level: 030 | 1123.16 | 0.515097 | 3600 | 0.157243 | 0.539401 | 3.85286 | Pset_WallCommon - FireRating: EI60
695833 | 020 | -80 | -480 | 020 | Up to level: 030 | 909.325 | 0.344658 | 3200 | 0.107706 | 0.344658 | 2.46184 | Pset_WallCommon - FireRating: EI60
695835 | 020 | -80 | -280 | 020 | Up to level: 030 | 1965 | 0.600278 | 3400 | 0.2751 | 0.600278 | 4.2877
695839 | 020 | -80 | -280 | 020 | Up to level: 030 | 2747.01 | 0.936819 | 3400 | 0.362902 | 0.970139 | 6.92956
695840 | 020 | -80 | -480 | 020 | Up to level: 030 | 1462.29 | 0.592386 | 3200 | 0.185121 | 0.592386 | 4.23133
1254515 | 020 | -80 | -280 | 020 | Up to level: 030 | 2260 | 0.803124 | 3400 | 0.3164 | 0.803124 | 5.7366
1254516 | 020 | -80 | -280 | 020 | Up to level: 030 | 1150 | 0.289744 | 3400 | 0.161 | 0.289744 | 2.0696
1254517 | 020 | -80 | -280 | 020 | Up to level: 030 | 3120 | 1.22746 | 3400 | 0.4368 | 1.22746 | 8.7676
1261813 | 020 | -80 | -280 | 020 | Up to level: 030 | 1150 | 0.289744 | 3400 | 0.161 | 0.289744 | 2.0696
1261814 | 020 | -80 | -280 | 020 | Up to level: 030 | 3120 | 1.22746 | 3400 | 0.4368 | 1.22746 | 8.7676
1261815 | 020 | -80 | -280 | 020 | Up to level: 030 | 2260 | 0.803124 | 3400 | 0.3164 | 0.803124 | 5.7366
705234 | 030 | -200 | 2490 | 030 | Up to level: 030 | 1123.16 | 0.396621 | 2690 | 0.157243 | 0.422983 | 3.02131 | Pset_WallCommon - FireRating: EI60
705235 | 030 | -200 | 3250 | 030 | Up to level: 030 | 983.163 | 0.437068 | 3450 | 0.137643 | 0.470878 | 3.36341 | Pset_WallCommon - FireRating: EI60
705304 | 030 | -80 | 3020 | 030 | Up to level: 030 | 909.325 | 0.333887 | 3100 | 0.107706 | 0.333887 | 2.38491 | Pset_WallCommon - FireRating: EI60
705306 | 030 | -80 | 3200 | 030 | Up to level: 030 | 1965 | 0.567266 | 3280 | 0.2751 | 0.567266 | 4.0519
705308 | 030 | -200 | 3200 | 030 | Up to level: 030 | 640 | 0.30296 | 3400 | 0.0896 | 0.30296 | 2.164 | Pset_WallCommon - FireRating: EI60
705310 | 030 | -80 | 3200 | 030 | Up to level: 030 | 2747.01 | 0.894221 | 3280 | 0.374781 | 0.926365 | 6.61689
1273887 | 030 | -80 | 0 | 030 |  | 2700 | 0.95914 | 3270 | 0.378 | 0.95914 | 6.851
1274069 | 030 | -80 | 0 | 030 |  | 1570 | 0.471926 | 3270 | 0.2198 | 0.471926 | 3.3709
1274207 | 030 | -80 | 0 | 030 |  | 2643.54 | 0.978444 | 3270 | 0.370096 | 0.978444 | 6.98889
1275414 | 030 | -80 | 3190 | 030 | Up to level: 030 | 2700 | 0.95914 | 3270 | 0.378 | 0.95914 | 6.851
1275513 | 030 | -80 | 3190 | 030 | Up to level: 030 | 1570 | 0.471926 | 3270 | 0.2198 | 0.471926 | 3.3709
1275591 | 030 | -80 | 3190 | 030 | Up to level: 030 | 1951.04 | 0.887588 | 3270 | 0.273146 | 0.887588 | 6.33991
8709313 | 030 | -80 | 0 | 030 |  | 2387.01 | 0.879872 | Pset_WallCommon - FireRating: EI60

# IfcWall: Basic Wall:BB_XX_Wand uit metselwerk, 190 mm (27)
PredefinedType: SOLIDWALL
Cpset_Wall - LevelOfAccuracy: in te vullen door Buildwise
IfcClassificationReference - GVH_artnr 01: geen waarde gevonden; GVH_artnr 02: geen waarde gevonden; GVH_artnr 03: geen waarde gevonden; GVH_artnr 04: geen waarde gevonden; GVH_artnr 05: geen waarde gevonden; GVH_artnr 06: geen waarde gevonden
IfcRoot - Name: BB_XX_Wand uit metselwerk, 190 mm
Qto_WallBaseQuantities - Width: 190
Pset_Condition - AssessmentCondition: Empty
Pset_EnvironmentalImpactIndicators - Reference: BB_XX_Wand uit metselwerk, 190 mm; sets with these values: 2
Pset_WallCommon - Reference: BB_XX_Wand uit metselwerk, 190 mm; IsExternal: yes; LoadBearing: no; ExtendToStructure: no
Name (Basic Wall:BB_XX_Wand uit metselwerk, 190 mm:...) | In | Base Offset | Top Offset | Base Constraint | Length | NetVolume | Height | GrossFootprintArea | GrossVolume | GrossSideArea | NetSideArea | FireRating | Top Constraint
1596970 | K20 | 0 | 0 | K20 | 5000 | 0.787398 | 2200 | 0.95 | 0.787398 | 4.1442 | 4.1442 | EI60
1596971 | K20 | 0 | 0 | K20 | 2900 | 0.811034 | 2200 | 0.551 | 0.811034 | 4.2686 | 4.2686 | EI60
806834 | K10 | -200 | 0 | K10 | 7005 | 3.7726 | 3240 | 1.33095 | 3.7726 | 19.8558 | 19.8558 | EI60
829148 | K10 | 0 | 0 | K10 | 5175 | 2.3214 | 2780 | 0.98325 | 2.3214 | 12.2179 | 12.2179 | EI60
830024 | K10 | 0 | 0 | K10 | 4125 | 1.80014 | 2880 | 0.78375 | 1.80014 | 9.4744 | 9.4744 | EI60
830236 | K10 | 0 | 0 | K10 | 5000 | 1.87785 | 2640 | 0.95 | 1.87785 | 9.8834 | 9.8834 | EI60
847717 | K10 | -200 | 0 | K10 | 1240 | 0.591931 | 2520.6 | 0.2356 | 0.592483 | 3.11833 | 3.11833 | EI60
899211 | K10 | 0 | 0 | K10 | 2900 | 0.835506 | 2660 | 0.551 | 0.835506 | 4.3974 | 4.3974 | EI60
1414193 | K10 | 0 | 0 | K10 | 1805.04 | 0.858005 | 2511.43 | 0.342958 | 0.858005 | 4.51581 | 4.51581 | EI60
8710187 | K10 | 0 | 0 | K10 | 5300 | 1.88577 | 2290 | 1.007 | 1.88577 | 9.9251 | 9.9251 | EI60
8711203 | K10 | 0 | 0 | K10 | 1600 | 0.275899 | 2290 | 0.304 | 0.275899 | 1.4521 | 1.4521 | EI60
19992670 | K10 | -100 | 0 | K10 | 4495 | 2.45681 | 2880 | 0.85405 | 2.45681 | 12.9306 | 12.9306 | EI60
509715 | 000 | -100 | -200 | 000 | 1970.16 | 0.902324 | 3500 | 0.374331 | 0.902324 | 4.74907 | 4.74907 | EI60 | Up to level: 010
512346 | 000 | -200 | -460 | 000 | 1960 | 0.969608 | 3340 | 0.3724 | 0.969608 | 5.1032 | 5.1032 | EI60 | Up to level: 010
1183536 | 000 | -80 | -280 | 000 | 2600 | 1.44182 | 3400 | 0.494 | 1.6796 | 8.84 | 7.58855 | EI60 | Up to level: 010
1270146 | 000 | -80 | -280 | 000 | 2600 | 1.44182 | 3400 | 0.494 | 1.6796 | 8.84 | 7.58855 | EI60 | Up to level: 010
1599670 | 000 | -50 | -250 | 000 | 3177.5 | 1.39999 | 3400 | 0.603725 | 1.39999 | 7.36836 | 7.36836 |  | Up to level: 010
1211568 | 010 | -80 | -280 | 010 | 2600 | 1.44182 | 3400 | 0.494 | 1.6796 | 8.84 | 7.58855 | EI60 | Up to level: 020
1214372 | 010 | -80 | -280 | 010 | 2600 | 1.44182 | 3400 | 0.494 | 1.6796 | 8.84 | 7.58855 | EI60 | Up to level: 020
2126317 | 010 | -80 | -480 | 010 | 2512.01 | 0.721338 |  |  |  |  |  | EI60 | Up to level: 020
1254632 | 020 | -80 | -280 | 020 | 2600 | 1.44182 | 3400 | 0.494 | 1.6796 | 8.84 | 7.58855 | EI60 | Up to level: 030
1262022 | 020 | -80 | -280 | 020 | 2600 | 1.44182 | 3400 | 0.494 | 1.6796 | 8.84 | 7.58855 | EI60 | Up to level: 030
713093 | 030 | -80 | 3190 | 030 | 1390 | 0.856007 | 3270 | 0.2641 | 0.856007 | 4.5053 | 4.5053 | EI60 | Up to level: 030
753257 | 030 | -80 | 3190 | 030 | 2500 | 1.23778 | 3270 | 0.475 | 1.55325 | 8.175 | 6.51464 | EI60 | Up to level: 030
753407 | 030 | -80 | 3190 | 030 | 2700 | 1.67751 | 3270 | 0.513 | 1.67751 | 8.829 | 8.829 |  | Up to level: 030
762174 | 030 | -80 | 3190 | 030 | 2500 | 1.23778 | 3270 | 0.475 | 1.55325 | 8.175 | 6.51464 | EI60 | Up to level: 030
1575805 | 040 | 400 | -250 | 040 | 2848.72 | 0.806468 |  |  |  |  |  | EI60 | Up to level: 050

# IfcWall: Basic Wall:BB_XX_Wand uit metselwerk, 200 mm (6)
PredefinedType: SOLIDWALL
Cpset_Wall - LevelOfAccuracy: in te vullen door Buildwise
IfcClassificationReference - GVH_artnr 01: geen waarde gevonden; GVH_artnr 02: geen waarde gevonden; GVH_artnr 03: geen waarde gevonden; GVH_artnr 04: geen waarde gevonden; GVH_artnr 05: geen waarde gevonden; GVH_artnr 06: geen waarde gevonden
IfcRoot - Name: BB_XX_Wand uit metselwerk, 200 mm
Qto_WallBaseQuantities - Width: 200
Pset_Condition - AssessmentCondition: Empty
Pset_EnvironmentalImpactIndicators - Reference: BB_XX_Wand uit metselwerk, 200 mm; sets with these values: 2
Pset_WallCommon - Reference: BB_XX_Wand uit metselwerk, 200 mm; IsExternal: yes; LoadBearing: no; ExtendToStructure: no
Name (Basic Wall:BB_XX_Wand uit metselwerk, 200 mm:...) | In | Base Offset | Top Offset | Base Constraint | Length | NetVolume | Height | GrossFootprintArea | GrossVolume | GrossSideArea = NetSideArea
956504 | K20 | 0 | 0 | K20 | 4534 | 1.86801 | 2060 | 0.9068 | 1.86801 | 9.34004 | Pset_WallCommon - FireRating: EI60
829398 | K10 | 0 | 0 | K10 | 12532.6 | 5.39316 | Pset_WallCommon - FireRating: EI60
829661 | K10 | 0 | 0 | K10 | 7247.59 | 3.48773 | Pset_WallCommon - FireRating: EI60
1261399 | 010 | -200 | -970 | 010 | 910 | 0.01731 | 2830 | 0.182 | 0.1132 | 0.566 | IfcBuildingStorey - Top Constraint: Up to level: 020
1261047 | 020 | -200 | -970 | 020 | 910 | 0.01731 | 2830 | 0.182 | 0.1132 | 0.566 | IfcBuildingStorey - Top Constraint: Up to level: 030
705247 | 030 | -200 | 2990 | 030 | 960 | 0.11198 | 3190 | 0.192 | 0.1276 | 0.638 | IfcBuildingStorey - Top Constraint: Up to level: 030

# IfcWall: Basic Wall:BB_XX_Wand uit metselwerk, 90 mm (26)
PredefinedType: SOLIDWALL
Cpset_Wall - LevelOfAccuracy: in te vullen door Buildwise
IfcBuildingStorey - Base Offset: -80
IfcClassificationReference - GVH_artnr 01: geen waarde gevonden; GVH_artnr 02: geen waarde gevonden; GVH_artnr 03: geen waarde gevonden; GVH_artnr 04: geen waarde gevonden; GVH_artnr 05: geen waarde gevonden; GVH_artnr 06: geen waarde gevonden
IfcRoot - Name: BB_XX_Wand uit metselwerk, 90 mm
Qto_WallBaseQuantities - Width: 90
Pset_Condition - AssessmentCondition: Empty
Pset_EnvironmentalImpactIndicators - Reference: BB_XX_Wand uit metselwerk, 90 mm; sets with these values: 2
Pset_WallCommon - Reference: BB_XX_Wand uit metselwerk, 90 mm; IsExternal: yes; LoadBearing: no; ExtendToStructure: no
Name (Basic Wall:BB_XX_Wand uit metselwerk, 90 mm:...) | In | Top Offset | Base Constraint | Top Constraint | Length | NetVolume = GrossVolume | Height | GrossFootprintArea | GrossSideArea = NetSideArea
1185069 | 000 | -280 | 000 | Up to level: 010 | 1510 | 0.306824 | 3400 | 0.1359 | 3.40916
1185647 | 000 | -280 | 000 | Up to level: 010 | 3000 | 0.607529 | 3400 | 0.27 | 6.75032
1195918 | 000 | -280 | 000 | Up to level: 010 | 2050 | 0.316829 | 3400 | 0.1845 | 3.52032
1197114 | 000 | -280 | 000 | Up to level: 010 | 910 | 0.123224 | 3400 | 0.0819 | 1.36916
1197197 | 000 | -280 | 000 | Up to level: 010 | 2000.12 | 0.4568 | 3400 | 0.18001 | 5.07555
1270139 | 000 | -280 | 000 | Up to level: 010 | 2780 | 0.540209 | 3400 | 0.2502 | 6.00232
1270141 | 000 | -280 | 000 | Up to level: 010 | 1510 | 0.306824 | 3400 | 0.1359 | 3.40916
1205710 | 010 | -280 | 010 | Up to level: 020 | 910 | 0.123224 | 3400 | 0.0819 | 1.36916
1205972 | 010 | -280 | 010 | Up to level: 020 | 1910 | 0.273989 | 3400 | 0.1719 | 3.04432
1206310 | 010 | -280 | 010 | Up to level: 020 | 2000.12 | 0.4568 | 3400 | 0.18001 | 5.07555
1209576 | 010 | -280 | 010 | Up to level: 020 | 3000 | 0.607529 | 3400 | 0.27 | 6.75032
1210046 | 010 | -280 | 010 | Up to level: 020 | 1510 | 0.306824 | 3400 | 0.1359 | 3.40916
1214547 | 010 | -280 | 010 | Up to level: 020 | 1510 | 0.306824 | 3400 | 0.1359 | 3.40916
25601857 | 010 | -280 | 010 | Up to level: 020 | 2780 | 0.540209 | 3400 | 0.2502 | 6.00232
1254520 | 020 | -280 | 020 | Up to level: 030 | 1510 | 0.306824 | 3400 | 0.1359 | 3.40916
1255006 | 020 | -280 | 020 | Up to level: 030 | 910 | 0.123224 | 3400 | 0.0819 | 1.36916
1255010 | 020 | -280 | 020 | Up to level: 030 | 2000.12 | 0.4568 | 3400 | 0.18001 | 5.07555
1255148 | 020 | -280 | 020 | Up to level: 030 | 1910 | 0.273989 | 3400 | 0.1719 | 3.04432
1261809 | 020 | -280 | 020 | Up to level: 030 | 2780 | 0.540209 | 3400 | 0.2502 | 6.00232
1261811 | 020 | -280 | 020 | Up to level: 030 | 1510 | 0.306824 | 3400 | 0.1359 | 3.40916
25793110 | 020 | -280 | 020 | Up to level: 030 | 2780 | 0.540209 | 3400 | 0.2502 | 6.00232
1273615 | 030 | 0 | 030 |  | 2700 | 0.450659 | 3270 | 0.243 | 5.00732
1275315 | 030 | 3190 | 030 | Up to level: 030 | 2700 | 0.450659 | 3270 | 0.243 | 5.00732
1277125 | 030 | 3200 | 030 | Up to level: 030 | 2000.12 | 0.435199 | 3280 | 0.18001 | 4.83554
1277209 | 030 | 3200 | 030 | Up to level: 030 | 910 | 0.113396 | 3280 | 0.0819 | 1.25996
1277424 | 030 | 3200 | 030 | Up to level: 030 | 1910 | 0.253361 | 3280 | 0.1719 | 2.81512

# IfcWall: Basic Wall:BB_XX_Wand uit metselwerk, _EI60_43dB, 190 mm, Basic Wall:BB_XX_Wand uit metselwerk, _EI60_43dB, 190 mm:493165
In: 000
PredefinedType: SOLIDWALL
Cpset_Wall - LevelOfAccuracy: in te vullen door Buildwise
IfcBuildingStorey - Base Offset: -200; Top Offset: -530; Base Constraint: 000; Top Constraint: Up to level: 010
IfcClassificationReference - GVH_artnr 01: geen waarde gevonden; GVH_artnr 02: geen waarde gevonden; GVH_artnr 03: geen waarde gevonden; GVH_artnr 04: geen waarde gevonden; GVH_artnr 05: geen waarde gevonden; GVH_artnr 06: geen waarde gevonden
IfcRoot - Name: BB_XX_Wand uit metselwerk, _EI60_43dB, 190 mm
Qto_WallBaseQuantities - Length: 3285; NetVolume: 1.33508; Height: 3270; Width: 190; GrossFootprintArea: 0.62415; GrossVolume: 2.04097; GrossSideArea: 10.7419; NetSideArea: 7.02675
Pset_Condition - AssessmentCondition: Empty
Pset_EnvironmentalImpactIndicators - Reference: BB_XX_Wand uit metselwerk, _EI60_43dB, 190 mm; sets with these values: 2
Pset_WallCommon - Reference: BB_XX_Wand uit metselwerk, _EI60_43dB, 190 mm; IsExternal: yes; LoadBearing: no; ExtendToStructure: no

# IfcWall: Basic Wall:GVH_DUMMY WAND HOST, Basic Wall:GVH_DUMMY WAND HOST:33986643
In: 030
Cpset_Wall - LevelOfAccuracy: in te vullen door Buildwise
IfcBuildingStorey - Base Offset: 737; Top Offset: 820; Base Constraint: 030; Top Constraint: Up to level: 030
IfcClassificationReference - Keynote: 15.01.33
IfcRoot - Name: GVH_DUMMY WAND HOST
Qto_WallBaseQuantities - Length: 283.075; NetVolume: 0.000183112; Height: 83; Width: 10; GrossFootprintArea: 0.00283075; GrossVolume: 0.000234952; GrossSideArea: 0.0234952; NetSideArea: 0.0183112
Pset_Condition - AssessmentCondition: Empty
Pset_EnvironmentalImpactIndicators - Reference: GVH_DUMMY WAND HOST; sets with these values: 2
Pset_WallCommon - Reference: GVH_DUMMY WAND HOST; IsExternal: yes; LoadBearing: no; ExtendToStructure: no

# IfcWall: Basic Wall_BB_03.09.24#03_Wand uit metselwerk_ 190 mm, Basic Wall:BB_03.09.24#03_Wand uit metselwerk, 190 mm:34055750
In: K10
PredefinedType: SOLIDWALL; Material: BB_Metselwerk_Betonsteen
Cpset_Wall - LevelOfAccuracy: in te vullen door Buildwise
IfcBuildingStorey - Base Offset: 0; Top Offset: -660; Base Constraint: K10; Top Constraint: Up to level: 000
IfcClassificationReference - Keynote: 03.09.24#03; TDS_link: .\05 As Builtdossier\2. Bouwkunde\2.1 Architectuur\2.1.3 open ruwbouw\TF S 4.2.1.1.1 A-volle betonstenen.pdf
IfcRoot - Name: BB_03.09.24#03_Wand uit metselwerk, 190 mm
Qto_WallBaseQuantities - Length: 13349.5; NetVolume: 5.69081; Width: 190
Pset_Condition - AssessmentCondition: Empty
Pset_EnvironmentalImpactIndicators - Reference: BB_03.09.24#03_Wand uit metselwerk, 190 mm; sets with these values: 2
Pset_WallCommon - Reference: BB_03.09.24#03_Wand uit metselwerk, 190 mm; FireRating: EI60; ThermalTransmittance: 6.26316; IsExternal: yes; LoadBearing: yes; ExtendToStructure: no

# IfcWall: Basic Wall_BB_03.09.24#03_Wand uit metselwerk_ 190 mm1, Basic Wall:BB_03.09.24#03_Wand uit metselwerk, 190 mm:34055760
In: 000
PredefinedType: SOLIDWALL; Material: BB_Metselwerk_Betonsteen
Cpset_Wall - LevelOfAccuracy: in te vullen door Buildwise
IfcBuildingStorey - Base Offset: -400; Top Offset: -600; Base Constraint: 000; Top Constraint: Up to level: 010
IfcClassificationReference - Keynote: 03.09.24#03; TDS_link: .\05 As Builtdossier\2. Bouwkunde\2.1 Architectuur\2.1.3 open ruwbouw\TF S 4.2.1.1.1 A-volle betonstenen.pdf
IfcRoot - Name: BB_03.09.24#03_Wand uit metselwerk, 190 mm
Qto_WallBaseQuantities - Length: 13349.5; NetVolume: 6.84626; Width: 190
Pset_Condition - AssessmentCondition: Empty
Pset_EnvironmentalImpactIndicators - Reference: BB_03.09.24#03_Wand uit metselwerk, 190 mm; sets with these values: 2
Pset_WallCommon - Reference: BB_03.09.24#03_Wand uit metselwerk, 190 mm; FireRating: EI60; ThermalTransmittance: 6.26316; IsExternal: yes; LoadBearing: yes; ExtendToStructure: no

# IfcWall: Basic Wall_BB_03.09.24#03_Wand uit metselwerk_ 190 mm3, Basic Wall:BB_03.09.24#03_Wand uit metselwerk, 190 mm:34192641
In: 010
PredefinedType: SOLIDWALL; Material: BB_Metselwerk_Betonsteen
Cpset_Wall - LevelOfAccuracy: in te vullen door Buildwise
IfcBuildingStorey - Base Offset: -200; Top Offset: -600; Base Constraint: 010; Top Constraint: Up to level: 020
IfcClassificationReference - Keynote: 03.09.24#03; TDS_link: .\05 As Builtdossier\2. Bouwkunde\2.1 Architectuur\2.1.3 open ruwbouw\TF S 4.2.1.1.1 A-volle betonstenen.pdf
IfcRoot - Name: BB_03.09.24#03_Wand uit metselwerk, 190 mm
Qto_WallBaseQuantities - Length: 13349.5; NetVolume: 6.44933; Width: 190
Pset_Condition - AssessmentCondition: Empty
Pset_EnvironmentalImpactIndicators - Reference: BB_03.09.24#03_Wand uit metselwerk, 190 mm; sets with these values: 2
Pset_WallCommon - Reference: BB_03.09.24#03_Wand uit metselwerk, 190 mm; FireRating: EI60; ThermalTransmittance: 6.26316; IsExternal: yes; LoadBearing: yes; ExtendToStructure: no

# IfcWall: Basic Wall_BB_03.09.24#03_Wand uit metselwerk_ 190 mm5, Basic Wall:BB_03.09.24#03_Wand uit metselwerk, 190 mm:34193140
In: 020
PredefinedType: SOLIDWALL; Material: BB_Metselwerk_Betonsteen
Cpset_Wall - LevelOfAccuracy: in te vullen door Buildwise
IfcBuildingStorey - Base Offset: -200; Top Offset: -600; Base Constraint: 020; Top Constraint: Up to level: 030
IfcClassificationReference - Keynote: 03.09.24#03; TDS_link: .\05 As Builtdossier\2. Bouwkunde\2.1 Architectuur\2.1.3 open ruwbouw\TF S 4.2.1.1.1 A-volle betonstenen.pdf
IfcRoot - Name: BB_03.09.24#03_Wand uit metselwerk, 190 mm
Qto_WallBaseQuantities - Length: 13349.5; NetVolume: 6.21561; Width: 190
Pset_Condition - AssessmentCondition: Empty
Pset_EnvironmentalImpactIndicators - Reference: BB_03.09.24#03_Wand uit metselwerk, 190 mm; sets with these values: 2
Pset_WallCommon - Reference: BB_03.09.24#03_Wand uit metselwerk, 190 mm; FireRating: EI60; ThermalTransmittance: 6.26316; IsExternal: yes; LoadBearing: yes; ExtendToStructure: no

# IfcWall: Basic Wall_BB_03.09.24#03_Wand uit metselwerk_ 190 mm7, Basic Wall:BB_03.09.24#03_Wand uit metselwerk, 190 mm:34193874
In: 030
PredefinedType: SOLIDWALL; Material: BB_Metselwerk_Betonsteen
Cpset_Wall - LevelOfAccuracy: in te vullen door Buildwise
IfcBuildingStorey - Base Offset: -200; Top Offset: -600; Base Constraint: 030; Top Constraint: Up to level: 040
IfcClassificationReference - Keynote: 03.09.24#03; TDS_link: .\05 As Builtdossier\2. Bouwkunde\2.1 Architectuur\2.1.3 open ruwbouw\TF S 4.2.1.1.1 A-volle betonstenen.pdf
IfcRoot - Name: BB_03.09.24#03_Wand uit metselwerk, 190 mm
Qto_WallBaseQuantities - Length: 13349.5; NetVolume: 6.39625; Width: 190
Pset_Condition - AssessmentCondition: Empty
Pset_EnvironmentalImpactIndicators - Reference: BB_03.09.24#03_Wand uit metselwerk, 190 mm; sets with these values: 2
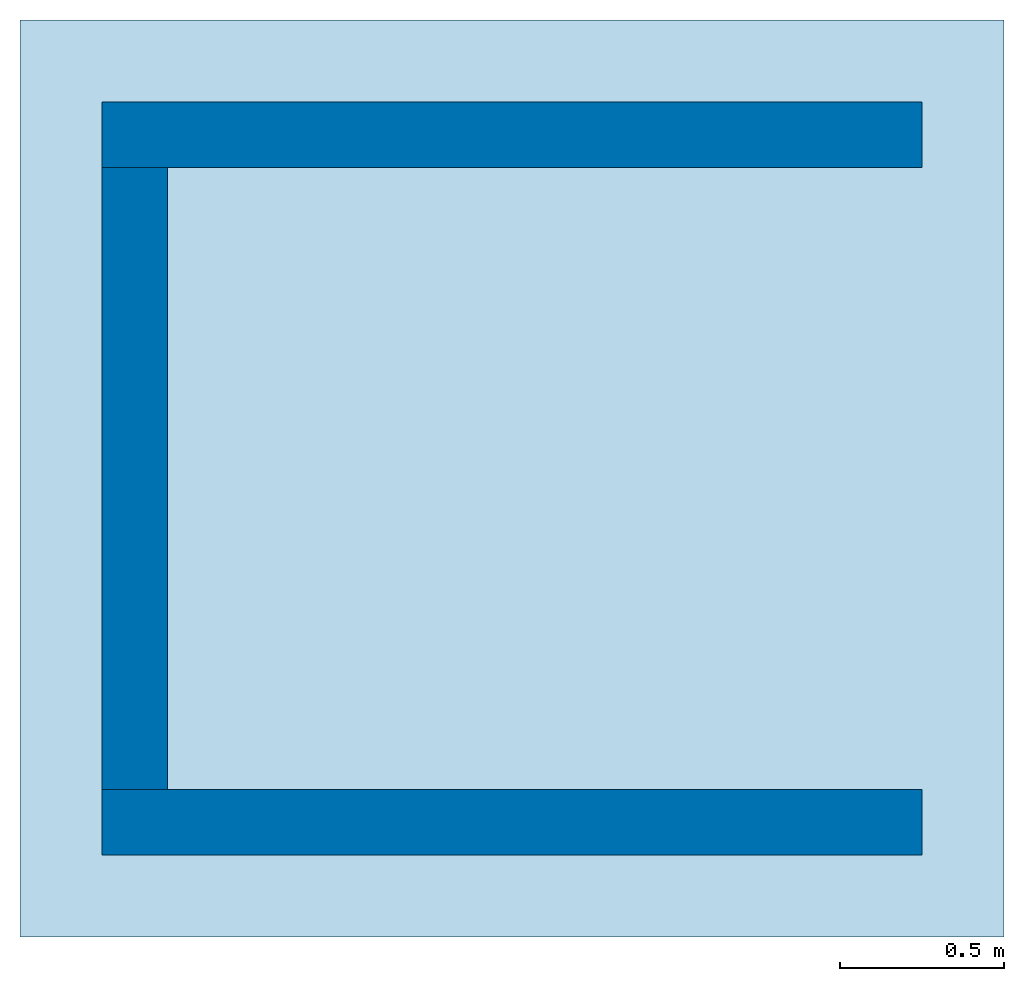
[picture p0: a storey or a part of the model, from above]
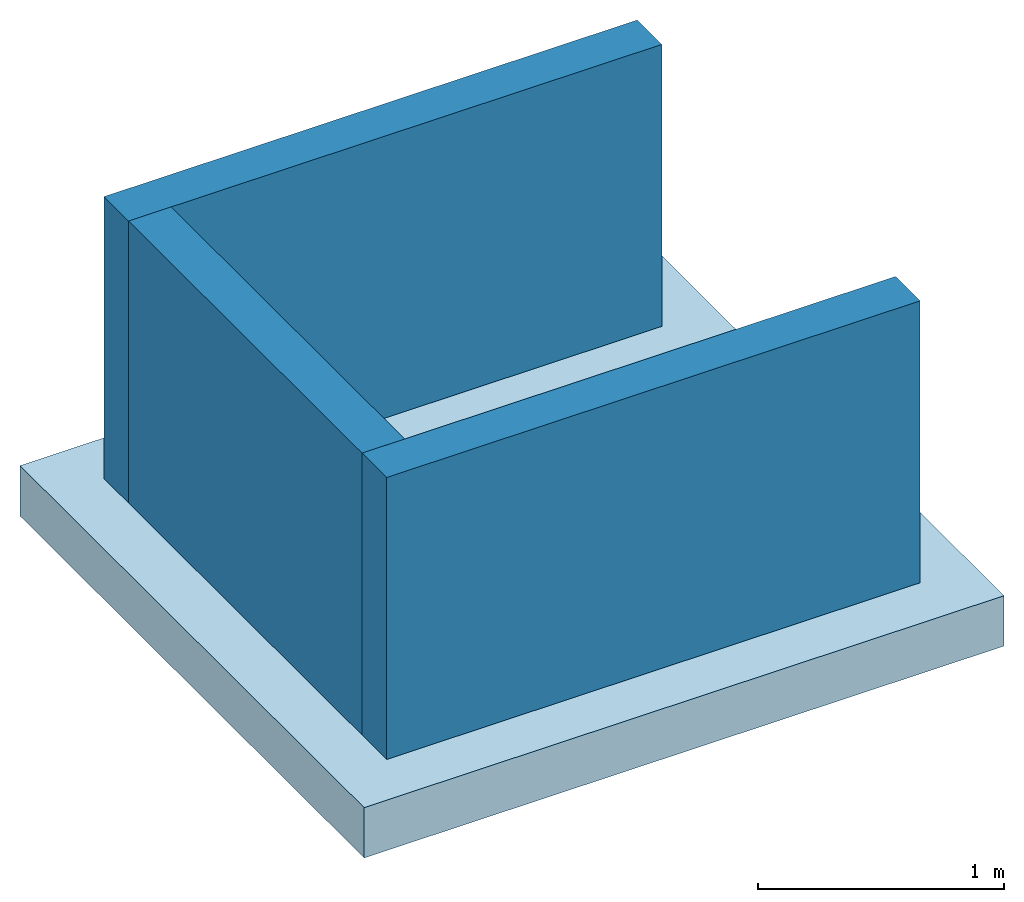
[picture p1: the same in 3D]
Properties of the parts of a building model (IFC4X3_ADD2), part 23 of 28

# IfcWall: Basic Wall_BB_03.09.24#03_Wand uit metselwerk_ 190 mm7, Basic Wall:BB_03.09.24#03_Wand uit metselwerk, 190 mm:34193874
Pset_WallCommon - Reference: BB_03.09.24#03_Wand uit metselwerk, 190 mm; FireRating: EI60; ThermalTransmittance: 6.26316; IsExternal: yes; LoadBearing: yes; ExtendToStructure: no

# IfcWall: Basic Wall_BB_03.09.24#05_Wand uit metselwerk_EI60_ 190 mm, Basic Wall:BB_03.09.24#05_Wand uit metselwerk_EI60, 190 mm:34140640
In: 010
PredefinedType: SOLIDWALL; Material: BB_Metselwerk_Betonsteen
Cpset_Wall - LevelOfAccuracy: in te vullen door Buildwise
IfcBuildingStorey - Base Offset: -200; Top Offset: 2400; Base Constraint: 010; Top Constraint: Up to level: 010
IfcClassificationReference - Keynote: 03.09.24#05; GVH_artnr 01: 03.09.24#05; GVH_artnr 02: geen waarde gevonden; GVH_artnr 03: geen waarde gevonden; GVH_artnr 04: geen waarde gevonden; GVH_artnr 05: geen waarde gevonden; GVH_artnr 06: geen waarde gevonden; TDS_link: .\05 As Builtdossier\2. Bouwkunde\2.1 Architectuur\2.1.3 open ruwbouw\TF S 4.2.1.1.1 A-volle betonstenen.pdf
IfcElement - BB_Element_Lokaalnummer01: K.-1.310
IfcRoot - Name: BB_03.09.24#05_Wand uit metselwerk_EI60, 190 mm
Qto_WallBaseQuantities - Length: 3844.86; NetVolume: 1.78004; Width: 190
Pset_Condition - AssessmentCondition: Empty
Pset_EnvironmentalImpactIndicators - Reference: BB_03.09.24#05_Wand uit metselwerk_EI60, 190 mm; sets with these values: 2
Pset_WallCommon - Reference: BB_03.09.24#05_Wand uit metselwerk_EI60, 190 mm; FireRating: EI60; ThermalTransmittance: 6.26316; IsExternal: yes; LoadBearing: no; ExtendToStructure: no

# IfcWall: Basic Wall_BB_03.09.24#06_Wand uit metselwerk_EI60_43dB_ 190 mm, Basic Wall:BB_03.09.24#06_Wand uit metselwerk_EI60_43dB, 190 mm:13000691
In: 010
PredefinedType: SOLIDWALL; Material: BB_Metselwerk_Betonsteen
Cpset_Wall - LevelOfAccuracy: in te vullen door Buildwise
IfcBuildingStorey - Base Offset: -200; Top Offset: -600; Base Constraint: 010; Top Constraint: Up to level: 020
IfcClassificationReference - Keynote: 03.09.24#06; GVH_artnr 01: 03.09.24#06; GVH_artnr 02: geen waarde gevonden; GVH_artnr 03: geen waarde gevonden; GVH_artnr 04: geen waarde gevonden; GVH_artnr 05: geen waarde gevonden; GVH_artnr 06: geen waarde gevonden; TDS_link: .\05 As Builtdossier\2. Bouwkunde\2.1 Architectuur\2.1.3 open ruwbouw\TF S 4.2.1.1.1 A-volle betonstenen.pdf
IfcElement - BB_Element_Lokaalnummer01: K.10.401
IfcRoot - Name: BB_03.09.24#06_Wand uit metselwerk_EI60_43dB, 190 mm
Qto_WallBaseQuantities - Length: 1590; NetVolume: 0.494622; Width: 190
Pset_Condition - AssessmentCondition: Empty
Pset_EnvironmentalImpactIndicators - Reference: BB_03.09.24#06_Wand uit metselwerk_EI60_43dB, 190 mm; sets with these values: 2
Pset_WallCommon - Reference: BB_03.09.24#06_Wand uit metselwerk_EI60_43dB, 190 mm; FireRating: EI60; ThermalTransmittance: 6.26316; IsExternal: yes; LoadBearing: no; ExtendToStructure: no

# IfcWall: Basic Wall_BB_10.01.41#01_Gipskartonwand_MS100 _ 25.50.25_ 100 mm, Basic Wall:BB_10.01.41#01_Gipskartonwand_MS100 / 25.50.25, 100 mm:13920865
In: 000
PredefinedType: PARTITIONING
Cpset_Wall - LevelOfAccuracy: in te vullen door Buildwise
IfcBuildingStorey - Base Offset: 2640; Top Offset: -460; Base Constraint: 000; Top Constraint: Up to level: 010
IfcClassificationReference - Keynote: 10.01.41#01; GVH_artnr 01: 10.01.41#01; GVH_artnr 02: geen waarde gevonden; GVH_artnr 03: geen waarde gevonden; GVH_artnr 04: geen waarde gevonden; GVH_artnr 05: geen waarde gevonden; GVH_artnr 06: geen waarde gevonden; TDS_link: .\05 As Builtdossier\2. Bouwkunde\2.1 Architectuur\2.1.10 wanden\TF A 10.01.41#1 A - lichte scheidingswand met gipsplaten.pdf
IfcElement - BB_Element_Lokaalnummer01: K.10.103
IfcRoot - Name: BB_10.01.41#01_Gipskartonwand_MS100 / 25.50.25, 100 mm
Qto_WallBaseQuantities - Length: 337.5; NetVolume: 0.01375; Height: 500; Width: 100; GrossVolume: 0.01375; GrossSideArea: 0.1375; NetSideArea: 0.1375
Pset_Condition - AssessmentCondition: Empty
Pset_EnvironmentalImpactIndicators - Reference: BB_10.01.41#01_Gipskartonwand_MS100 / 25.50.25, 100 mm; sets with these values: 2
Pset_WallCommon - Reference: BB_10.01.41#01_Gipskartonwand_MS100 / 25.50.25, 100 mm; FireRating: EI60; IsExternal: yes; LoadBearing: no; ExtendToStructure: no

# IfcWall: Basic Wall_BB_10.01.41#01_Gipskartonwand_MS100 _ 25.50.25_ 100 mm1, Basic Wall:BB_10.01.41#01_Gipskartonwand_MS100 / 25.50.25, 100 mm:13920866
In: 000
PredefinedType: PARTITIONING
Cpset_Wall - LevelOfAccuracy: in te vullen door Buildwise
IfcBuildingStorey - Base Offset: 2640; Top Offset: -460; Base Constraint: 000; Top Constraint: Up to level: 010
IfcClassificationReference - Keynote: 10.01.41#01; GVH_artnr 01: 10.01.41#01; GVH_artnr 02: geen waarde gevonden; GVH_artnr 03: geen waarde gevonden; GVH_artnr 04: geen waarde gevonden; GVH_artnr 05: geen waarde gevonden; GVH_artnr 06: geen waarde gevonden; TDS_link: .\05 As Builtdossier\2. Bouwkunde\2.1 Architectuur\2.1.10 wanden\TF A 10.01.41#1 A - lichte scheidingswand met gipsplaten.pdf
IfcElement - BB_Element_Lokaalnummer01: K.10.104
IfcRoot - Name: BB_10.01.41#01_Gipskartonwand_MS100 / 25.50.25, 100 mm
Qto_WallBaseQuantities - Length: 337.5; NetVolume: 0.01375; Height: 500; Width: 100; GrossVolume: 0.01375; GrossSideArea: 0.1375; NetSideArea: 0.1375
Pset_Condition - AssessmentCondition: Empty
Pset_EnvironmentalImpactIndicators - Reference: BB_10.01.41#01_Gipskartonwand_MS100 / 25.50.25, 100 mm; sets with these values: 2
Pset_WallCommon - Reference: BB_10.01.41#01_Gipskartonwand_MS100 / 25.50.25, 100 mm; FireRating: EI60; IsExternal: yes; LoadBearing: no; ExtendToStructure: no

# IfcWall: Basic Wall_BB_10.01.41#01_Gipskartonwand_MS100 _ 25.50.25_ 100 mm101, Basic Wall:BB_10.01.41#01_Gipskartonwand_MS100 / 25.50.25, 100 mm:13711360
In: 020
PredefinedType: PARTITIONING
Cpset_Wall - LevelOfAccuracy: in te vullen door Buildwise
IfcBuildingStorey - Base Offset: 2640; Top Offset: -600; Base Constraint: 020; Top Constraint: Up to level: 030
IfcClassificationReference - Keynote: 10.01.41#01; GVH_artnr 01: 10.01.41#01; GVH_artnr 02: geen waarde gevonden; GVH_artnr 03: geen waarde gevonden; GVH_artnr 04: geen waarde gevonden; GVH_artnr 05: geen waarde gevonden; GVH_artnr 06: geen waarde gevonden; TDS_link: .\05 As Builtdossier\2. Bouwkunde\2.1 Architectuur\2.1.10 wanden\TF A 10.01.41#1 A - lichte scheidingswand met gipsplaten.pdf
IfcElement - BB_Element_Lokaalnummer01: K.20.107
IfcRoot - Name: BB_10.01.41#01_Gipskartonwand_MS100 / 25.50.25, 100 mm
Qto_WallBaseQuantities - Length: 350; NetVolume: 0.0108; Height: 360; Width: 100; GrossVolume: 0.0108; GrossSideArea: 0.108; NetSideArea: 0.108
Pset_Condition - AssessmentCondition: Empty
Pset_EnvironmentalImpactIndicators - Reference: BB_10.01.41#01_Gipskartonwand_MS100 / 25.50.25, 100 mm; sets with these values: 2
Pset_WallCommon - Reference: BB_10.01.41#01_Gipskartonwand_MS100 / 25.50.25, 100 mm; FireRating: EI60; IsExternal: yes; LoadBearing: no; ExtendToStructure: no

# IfcWall: Basic Wall_BB_10.01.41#01_Gipskartonwand_MS100 _ 25.50.25_ 100 mm103, Basic Wall:BB_10.01.41#01_Gipskartonwand_MS100 / 25.50.25, 100 mm:13711371
In: 020
PredefinedType: PARTITIONING
Cpset_Wall - LevelOfAccuracy: in te vullen door Buildwise
IfcBuildingStorey - Base Offset: 2640; Top Offset: -600; Base Constraint: 020; Top Constraint: Up to level: 030
IfcClassificationReference - Keynote: 10.01.41#01; GVH_artnr 01: 10.01.41#01; GVH_artnr 02: geen waarde gevonden; GVH_artnr 03: geen waarde gevonden; GVH_artnr 04: geen waarde gevonden; GVH_artnr 05: geen waarde gevonden; GVH_artnr 06: geen waarde gevonden; TDS_link: .\05 As Builtdossier\2. Bouwkunde\2.1 Architectuur\2.1.10 wanden\TF A 10.01.41#1 A - lichte scheidingswand met gipsplaten.pdf
IfcElement - BB_Element_Lokaalnummer01: K.20.108
IfcRoot - Name: BB_10.01.41#01_Gipskartonwand_MS100 / 25.50.25, 100 mm
Qto_WallBaseQuantities - Length: 350; NetVolume: 0.0108; Height: 360; Width: 100; GrossVolume: 0.0108; GrossSideArea: 0.108; NetSideArea: 0.108
Pset_Condition - AssessmentCondition: Empty
Pset_EnvironmentalImpactIndicators - Reference: BB_10.01.41#01_Gipskartonwand_MS100 / 25.50.25, 100 mm; sets with these values: 2
Pset_WallCommon - Reference: BB_10.01.41#01_Gipskartonwand_MS100 / 25.50.25, 100 mm; FireRating: EI60; IsExternal: yes; LoadBearing: no; ExtendToStructure: no

# IfcWall: Basic Wall_BB_10.01.41#01_Gipskartonwand_MS100 _ 25.50.25_ 100 mm105, Basic Wall:BB_10.01.41#01_Gipskartonwand_MS100 / 25.50.25, 100 mm:13711378
In: 020
PredefinedType: PARTITIONING
Cpset_Wall - LevelOfAccuracy: in te vullen door Buildwise
IfcBuildingStorey - Base Offset: 2640; Top Offset: -460; Base Constraint: 020; Top Constraint: Up to level: 030
IfcClassificationReference - Keynote: 10.01.41#01; GVH_artnr 01: 10.01.41#01; GVH_artnr 02: geen waarde gevonden; GVH_artnr 03: geen waarde gevonden; GVH_artnr 04: geen waarde gevonden; GVH_artnr 05: geen waarde gevonden; GVH_artnr 06: geen waarde gevonden; TDS_link: .\05 As Builtdossier\2. Bouwkunde\2.1 Architectuur\2.1.10 wanden\TF A 10.01.41#1 A - lichte scheidingswand met gipsplaten.pdf
IfcElement - BB_Element_Lokaalnummer01: K.20.109
IfcRoot - Name: BB_10.01.41#01_Gipskartonwand_MS100 / 25.50.25, 100 mm
Qto_WallBaseQuantities - Length: 350; NetVolume: 0.015; Height: 500; Width: 100; GrossVolume: 0.015; GrossSideArea: 0.15; NetSideArea: 0.15
Pset_Condition - AssessmentCondition: Empty
Pset_EnvironmentalImpactIndicators - Reference: BB_10.01.41#01_Gipskartonwand_MS100 / 25.50.25, 100 mm; sets with these values: 2
Pset_WallCommon - Reference: BB_10.01.41#01_Gipskartonwand_MS100 / 25.50.25, 100 mm; FireRating: EI60; IsExternal: yes; LoadBearing: no; ExtendToStructure: no

# IfcWall: Basic Wall_BB_10.01.41#01_Gipskartonwand_MS100 _ 25.50.25_ 100 mm107, Basic Wall:BB_10.01.41#01_Gipskartonwand_MS100 / 25.50.25, 100 mm:13712097
In: 020
PredefinedType: PARTITIONING
Cpset_Wall - LevelOfAccuracy: in te vullen door Buildwise
IfcBuildingStorey - Base Offset: 2640; Top Offset: -600; Base Constraint: 020; Top Constraint: Up to level: 030
IfcClassificationReference - Keynote: 10.01.41#01; GVH_artnr 01: 10.01.41#01; GVH_artnr 02: geen waarde gevonden; GVH_artnr 03: geen waarde gevonden; GVH_artnr 04: geen waarde gevonden; GVH_artnr 05: geen waarde gevonden; GVH_artnr 06: geen waarde gevonden; TDS_link: .\05 As Builtdossier\2. Bouwkunde\2.1 Architectuur\2.1.10 wanden\TF A 10.01.41#1 A - lichte scheidingswand met gipsplaten.pdf
IfcElement - BB_Element_Lokaalnummer01: K.20.202
IfcRoot - Name: BB_10.01.41#01_Gipskartonwand_MS100 / 25.50.25, 100 mm
Qto_WallBaseQuantities - Length: 25172.5; NetVolume: 0.98706; Height: 500; Width: 100; GrossVolume: 0.98706; GrossSideArea: 9.8706; NetSideArea: 9.8706
Pset_Condition - AssessmentCondition: Empty
Pset_EnvironmentalImpactIndicators - Reference: BB_10.01.41#01_Gipskartonwand_MS100 / 25.50.25, 100 mm; sets with these values: 2
Pset_WallCommon - Reference: BB_10.01.41#01_Gipskartonwand_MS100 / 25.50.25, 100 mm; FireRating: EI60; IsExternal: yes; LoadBearing: no; ExtendToStructure: no

# IfcWall: Basic Wall_BB_10.01.41#01_Gipskartonwand_MS100 _ 25.50.25_ 100 mm109, Basic Wall:BB_10.01.41#01_Gipskartonwand_MS100 / 25.50.25, 100 mm:13712315
In: 020
PredefinedType: PARTITIONING
Cpset_Wall - LevelOfAccuracy: in te vullen door Buildwise
IfcBuildingStorey - Base Offset: 2640; Top Offset: -680; Base Constraint: 020; Top Constraint: Up to level: 030
IfcClassificationReference - Keynote: 10.01.41#01; GVH_artnr 01: 10.01.41#01; GVH_artnr 02: geen waarde gevonden; GVH_artnr 03: geen waarde gevonden; GVH_artnr 04: geen waarde gevonden; GVH_artnr 05: geen waarde gevonden; GVH_artnr 06: geen waarde gevonden; TDS_link: .\05 As Builtdossier\2. Bouwkunde\2.1 Architectuur\2.1.10 wanden\TF A 10.01.41#1 A - lichte scheidingswand met gipsplaten.pdf
IfcElement - BB_Element_Lokaalnummer01: K.20.204
IfcRoot - Name: BB_10.01.41#01_Gipskartonwand_MS100 / 25.50.25, 100 mm
Qto_WallBaseQuantities - Length: 5080; NetVolume: 0.14084; Height: 280; Width: 100; GrossVolume: 0.14084; GrossSideArea: 1.4084; NetSideArea: 1.4084
Pset_Condition - AssessmentCondition: Empty
Pset_EnvironmentalImpactIndicators - Reference: BB_10.01.41#01_Gipskartonwand_MS100 / 25.50.25, 100 mm; sets with these values: 2
Pset_WallCommon - Reference: BB_10.01.41#01_Gipskartonwand_MS100 / 25.50.25, 100 mm; FireRating: EI60; IsExternal: yes; LoadBearing: no; ExtendToStructure: no

# IfcWall: Basic Wall_BB_10.01.41#01_Gipskartonwand_MS100 _ 25.50.25_ 100 mm11, Basic Wall:BB_10.01.41#01_Gipskartonwand_MS100 / 25.50.25, 100 mm:25505993
In: 000
PredefinedType: PARTITIONING
Cpset_Wall - LevelOfAccuracy: in te vullen door Buildwise
IfcBuildingStorey - Base Offset: 0; Top Offset: -600; Base Constraint: 000; Top Constraint: Up to level: 010
IfcClassificationReference - Keynote: 10.01.41#01; GVH_artnr 01: 10.01.41#01; GVH_artnr 02: geen waarde gevonden; GVH_artnr 03: geen waarde gevonden; GVH_artnr 04: geen waarde gevonden; GVH_artnr 05: geen waarde gevonden; GVH_artnr 06: geen waarde gevonden; TDS_link: .\05 As Builtdossier\2. Bouwkunde\2.1 Architectuur\2.1.10 wanden\TF A 10.01.41#1 A - lichte scheidingswand met gipsplaten.pdf
IfcElement - BB_Element_Lokaalnummer01: K.00.513
IfcRoot - Name: BB_10.01.41#01_Gipskartonwand_MS100 / 25.50.25, 100 mm
Qto_WallBaseQuantities - Length: 5397.47; NetVolume: 1.36915; Height: 3000; Width: 100; GrossVolume: 1.36915; GrossSideArea: 13.6915; NetSideArea: 13.6915
Pset_Condition - AssessmentCondition: Empty
Pset_EnvironmentalImpactIndicators - Reference: BB_10.01.41#01_Gipskartonwand_MS100 / 25.50.25, 100 mm; sets with these values: 2
Pset_WallCommon - Reference: BB_10.01.41#01_Gipskartonwand_MS100 / 25.50.25, 100 mm; FireRating: EI60; IsExternal: yes; LoadBearing: no; ExtendToStructure: no

# IfcWall: Basic Wall_BB_10.01.41#01_Gipskartonwand_MS100 _ 25.50.25_ 100 mm111, Basic Wall:BB_10.01.41#01_Gipskartonwand_MS100 / 25.50.25, 100 mm:16197866
In: 020
PredefinedType: PARTITIONING
Cpset_Wall - LevelOfAccuracy: in te vullen door Buildwise
IfcBuildingStorey - Base Offset: 2640; Top Offset: -600; Base Constraint: 020; Top Constraint: Up to level: 030
IfcClassificationReference - Keynote: 10.01.41#01; GVH_artnr 01: 10.01.41#01; GVH_artnr 02: geen waarde gevonden; GVH_artnr 03: geen waarde gevonden; GVH_artnr 04: geen waarde gevonden; GVH_artnr 05: geen waarde gevonden; GVH_artnr 06: geen waarde gevonden; TDS_link: .\05 As Builtdossier\2. Bouwkunde\2.1 Architectuur\2.1.10 wanden\TF A 10.01.41#1 A - lichte scheidingswand met gipsplaten.pdf
IfcElement - BB_Element_Lokaalnummer01: K.20.509
IfcRoot - Name: BB_10.01.41#01_Gipskartonwand_MS100 / 25.50.25, 100 mm
Qto_WallBaseQuantities - Length: 13842.5; NetVolume: 0.49626; Height: 360; Width: 100; GrossVolume: 0.49626; GrossSideArea: 4.9626; NetSideArea: 4.9626
Pset_Condition - AssessmentCondition: Empty
Pset_EnvironmentalImpactIndicators - Reference: BB_10.01.41#01_Gipskartonwand_MS100 / 25.50.25, 100 mm; sets with these values: 2
Pset_WallCommon - Reference: BB_10.01.41#01_Gipskartonwand_MS100 / 25.50.25, 100 mm; FireRating: EI60; IsExternal: yes; LoadBearing: no; ExtendToStructure: no

# IfcWall: Basic Wall_BB_10.01.41#01_Gipskartonwand_MS100 _ 25.50.25_ 100 mm113, Basic Wall:BB_10.01.41#01_Gipskartonwand_MS100 / 25.50.25, 100 mm:16199569
In: 020
PredefinedType: PARTITIONING
Cpset_Wall - LevelOfAccuracy: in te vullen door Buildwise
IfcBuildingStorey - Base Offset: 2640; Top Offset: -600; Base Constraint: 020; Top Constraint: Up to level: 030
IfcClassificationReference - Keynote: 10.01.41#01; GVH_artnr 01: 10.01.41#01; GVH_artnr 02: geen waarde gevonden; GVH_artnr 03: geen waarde gevonden; GVH_artnr 04: geen waarde gevonden; GVH_artnr 05: geen waarde gevonden; GVH_artnr 06: geen waarde gevonden; TDS_link: .\05 As Builtdossier\2. Bouwkunde\2.1 Architectuur\2.1.10 wanden\TF A 10.01.41#1 A - lichte scheidingswand met gipsplaten.pdf
IfcElement - BB_Element_Lokaalnummer01: K.20.407
IfcRoot - Name: BB_10.01.41#01_Gipskartonwand_MS100 / 25.50.25, 100 mm
Qto_WallBaseQuantities - Length: 12492.5; NetVolume: 0.43682; Height: 360; Width: 100; GrossVolume: 0.43682; GrossSideArea: 4.3682; NetSideArea: 4.3682
Pset_Condition - AssessmentCondition: Empty
Pset_EnvironmentalImpactIndicators - Reference: BB_10.01.41#01_Gipskartonwand_MS100 / 25.50.25, 100 mm; sets with these values: 2
Pset_WallCommon - Reference: BB_10.01.41#01_Gipskartonwand_MS100 / 25.50.25, 100 mm; FireRating: EI60; IsExternal: yes; LoadBearing: no; ExtendToStructure: no

# IfcWall: Basic Wall_BB_10.01.41#01_Gipskartonwand_MS100 _ 25.50.25_ 100 mm115, Basic Wall:BB_10.01.41#01_Gipskartonwand_MS100 / 25.50.25, 100 mm:16199844
In: 020
PredefinedType: PARTITIONING
Cpset_Wall - LevelOfAccuracy: in te vullen door Buildwise
IfcBuildingStorey - Base Offset: 2640; Top Offset: -600; Base Constraint: 020; Top Constraint: Up to level: 030
IfcClassificationReference - Keynote: 10.01.41#01; GVH_artnr 01: 10.01.41#01; GVH_artnr 02: geen waarde gevonden; GVH_artnr 03: geen waarde gevonden; GVH_artnr 04: geen waarde gevonden; GVH_artnr 05: geen waarde gevonden; GVH_artnr 06: geen waarde gevonden; TDS_link: .\05 As Builtdossier\2. Bouwkunde\2.1 Architectuur\2.1.10 wanden\TF A 10.01.41#1 A - lichte scheidingswand met gipsplaten.pdf
IfcElement - BB_Element_Lokaalnummer01: K.20.116
IfcRoot - Name: BB_10.01.41#01_Gipskartonwand_MS100 / 25.50.25, 100 mm
Qto_WallBaseQuantities - Length: 13842.5; NetVolume: 0.49626; Height: 360; Width: 100; GrossVolume: 0.49626; GrossSideArea: 4.9626; NetSideArea: 4.9626
Pset_Condition - AssessmentCondition: Empty
Pset_EnvironmentalImpactIndicators - Reference: BB_10.01.41#01_Gipskartonwand_MS100 / 25.50.25, 100 mm; sets with these values: 2
Pset_WallCommon - Reference: BB_10.01.41#01_Gipskartonwand_MS100 / 25.50.25, 100 mm; FireRating: EI60; IsExternal: yes; LoadBearing: no; ExtendToStructure: no

# IfcWall: Basic Wall_BB_10.01.41#01_Gipskartonwand_MS100 _ 25.50.25_ 100 mm117, Basic Wall:BB_10.01.41#01_Gipskartonwand_MS100 / 25.50.25, 100 mm:16293164
In: 020
PredefinedType: PARTITIONING
Cpset_Wall - LevelOfAccuracy: in te vullen door Buildwise
IfcBuildingStorey - Base Offset: 2640; Top Offset: -460; Base Constraint: 020; Top Constraint: Up to level: 030
IfcClassificationReference - Keynote: 10.01.41#01; GVH_artnr 01: 10.01.41#01; GVH_artnr 02: geen waarde gevonden; GVH_artnr 03: geen waarde gevonden; GVH_artnr 04: geen waarde gevonden; GVH_artnr 05: geen waarde gevonden; GVH_artnr 06: geen waarde gevonden; TDS_link: .\05 As Builtdossier\2. Bouwkunde\2.1 Architectuur\2.1.10 wanden\TF A 10.01.41#1 A - lichte scheidingswand met gipsplaten.pdf
IfcElement - BB_Element_Lokaalnummer01: K.20.510
IfcRoot - Name: BB_10.01.41#01_Gipskartonwand_MS100 / 25.50.25, 100 mm
Qto_WallBaseQuantities - Length: 350; NetVolume: 0.015; Height: 500; Width: 100; GrossVolume: 0.015; GrossSideArea: 0.15; NetSideArea: 0.15
Pset_Condition - AssessmentCondition: Empty
Pset_EnvironmentalImpactIndicators - Reference: BB_10.01.41#01_Gipskartonwand_MS100 / 25.50.25, 100 mm; sets with these values: 2
Pset_WallCommon - Reference: BB_10.01.41#01_Gipskartonwand_MS100 / 25.50.25, 100 mm; FireRating: EI60; IsExternal: yes; LoadBearing: no; ExtendToStructure: no

# IfcWall: Basic Wall_BB_10.01.41#01_Gipskartonwand_MS100 _ 25.50.25_ 100 mm119, Basic Wall:BB_10.01.41#01_Gipskartonwand_MS100 / 25.50.25, 100 mm:16293401
In: 020
PredefinedType: PARTITIONING
Cpset_Wall - LevelOfAccuracy: in te vullen door Buildwise
IfcBuildingStorey - Base Offset: 2640; Top Offset: -600; Base Constraint: 020; Top Constraint: Up to level: 030
IfcClassificationReference - Keynote: 10.01.41#01; GVH_artnr 01: 10.01.41#01; GVH_artnr 02: geen waarde gevonden; GVH_artnr 03: geen waarde gevonden; GVH_artnr 04: geen waarde gevonden; GVH_artnr 05: geen waarde gevonden; GVH_artnr 06: geen waarde gevonden; TDS_link: .\05 As Builtdossier\2. Bouwkunde\2.1 Architectuur\2.1.10 wanden\TF A 10.01.41#1 A - lichte scheidingswand met gipsplaten.pdf
IfcElement - BB_Element_Lokaalnummer01: K.20.111
IfcRoot - Name: BB_10.01.41#01_Gipskartonwand_MS100 / 25.50.25, 100 mm
Qto_WallBaseQuantities - Length: 5092.5; NetVolume: 0.18108; Height: 360; Width: 100; GrossVolume: 0.18108; GrossSideArea: 1.8108; NetSideArea: 1.8108
Pset_Condition - AssessmentCondition: Empty
Pset_EnvironmentalImpactIndicators - Reference: BB_10.01.41#01_Gipskartonwand_MS100 / 25.50.25, 100 mm; sets with these values: 2
Pset_WallCommon - Reference: BB_10.01.41#01_Gipskartonwand_MS100 / 25.50.25, 100 mm; FireRating: EI60; IsExternal: yes; LoadBearing: no; ExtendToStructure: no

# IfcWall: Basic Wall_BB_10.01.41#01_Gipskartonwand_MS100 _ 25.50.25_ 100 mm121, Basic Wall:BB_10.01.41#01_Gipskartonwand_MS100 / 25.50.25, 100 mm:16293608
In: 020
PredefinedType: PARTITIONING
Cpset_Wall - LevelOfAccuracy: in te vullen door Buildwise
IfcBuildingStorey - Base Offset: 2640; Top Offset: -600; Base Constraint: 020; Top Constraint: Up to level: 030
IfcClassificationReference - Keynote: 10.01.41#01; GVH_artnr 01: 10.01.41#01; GVH_artnr 02: geen waarde gevonden; GVH_artnr 03: geen waarde gevonden; GVH_artnr 04: geen waarde gevonden; GVH_artnr 05: geen waarde gevonden; GVH_artnr 06: geen waarde gevonden; TDS_link: .\05 As Builtdossier\2. Bouwkunde\2.1 Architectuur\2.1.10 wanden\TF A 10.01.41#1 A - lichte scheidingswand met gipsplaten.pdf
IfcElement - BB_Element_Lokaalnummer01: K.20.202
IfcRoot - Name: BB_10.01.41#01_Gipskartonwand_MS100 / 25.50.25, 100 mm
Qto_WallBaseQuantities - Length: 16085; NetVolume: 0.56646; Height: 360; Width: 100; GrossVolume: 0.56646; GrossSideArea: 5.6646; NetSideArea: 5.6646
Pset_Condition - AssessmentCondition: Empty
Pset_EnvironmentalImpactIndicators - Reference: BB_10.01.41#01_Gipskartonwand_MS100 / 25.50.25, 100 mm; sets with these values: 2
Pset_WallCommon - Reference: BB_10.01.41#01_Gipskartonwand_MS100 / 25.50.25, 100 mm; FireRating: EI60; IsExternal: yes; LoadBearing: no; ExtendToStructure: no

# IfcWall: Basic Wall_BB_10.01.41#01_Gipskartonwand_MS100 _ 25.50.25_ 100 mm123, Basic Wall:BB_10.01.41#01_Gipskartonwand_MS100 / 25.50.25, 100 mm:16293676
In: 020
PredefinedType: PARTITIONING
Cpset_Wall - LevelOfAccuracy: in te vullen door Buildwise
IfcBuildingStorey - Base Offset: 2640; Top Offset: -530; Base Constraint: 020; Top Constraint: Up to level: 030
IfcClassificationReference - Keynote: 10.01.41#01; GVH_artnr 01: 10.01.41#01; GVH_artnr 02: geen waarde gevonden; GVH_artnr 03: geen waarde gevonden; GVH_artnr 04: geen waarde gevonden; GVH_artnr 05: geen waarde gevonden; GVH_artnr 06: geen waarde gevonden; TDS_link: .\05 As Builtdossier\2. Bouwkunde\2.1 Architectuur\2.1.10 wanden\TF A 10.01.41#1 A - lichte scheidingswand met gipsplaten.pdf
IfcElement - BB_Element_Lokaalnummer01: K.20.202
IfcRoot - Name: BB_10.01.41#01_Gipskartonwand_MS100 / 25.50.25, 100 mm
Qto_WallBaseQuantities - Length: 4882.5; NetVolume: 0.178526; Height: 430; Width: 100; GrossVolume: 0.178526; GrossSideArea: 1.78526; NetSideArea: 1.78526
Pset_Condition - AssessmentCondition: Empty
Pset_EnvironmentalImpactIndicators - Reference: BB_10.01.41#01_Gipskartonwand_MS100 / 25.50.25, 100 mm; sets with these values: 2
Pset_WallCommon - Reference: BB_10.01.41#01_Gipskartonwand_MS100 / 25.50.25, 100 mm; FireRating: EI60; IsExternal: yes; LoadBearing: no; ExtendToStructure: no

# IfcWall: Basic Wall_BB_10.01.41#01_Gipskartonwand_MS100 _ 25.50.25_ 100 mm125, Basic Wall:BB_10.01.41#01_Gipskartonwand_MS100 / 25.50.25, 100 mm:25605344
In: 020
PredefinedType: PARTITIONING
Cpset_Wall - LevelOfAccuracy: in te vullen door Buildwise
IfcBuildingStorey - Base Offset: 2640; Top Offset: -460; Base Constraint: 020; Top Constraint: Up to level: 030
IfcClassificationReference - Keynote: 10.01.41#01; GVH_artnr 01: 10.01.41#01; GVH_artnr 02: geen waarde gevonden; GVH_artnr 03: geen waarde gevonden; GVH_artnr 04: geen waarde gevonden; GVH_artnr 05: geen waarde gevonden; GVH_artnr 06: geen waarde gevonden; TDS_link: .\05 As Builtdossier\2. Bouwkunde\2.1 Architectuur\2.1.10 wanden\TF A 10.01.41#1 A - lichte scheidingswand met gipsplaten.pdf
IfcElement - BB_Element_Lokaalnummer01: K.20.109
IfcRoot - Name: BB_10.01.41#01_Gipskartonwand_MS100 / 25.50.25, 100 mm
Qto_WallBaseQuantities - Length: 350; NetVolume: 0.015; Height: 500; Width: 100; GrossVolume: 0.015; GrossSideArea: 0.15; NetSideArea: 0.15
Pset_Condition - AssessmentCondition: Empty
Pset_EnvironmentalImpactIndicators - Reference: BB_10.01.41#01_Gipskartonwand_MS100 / 25.50.25, 100 mm; sets with these values: 2
Pset_WallCommon - Reference: BB_10.01.41#01_Gipskartonwand_MS100 / 25.50.25, 100 mm; FireRating: EI60; IsExternal: yes; LoadBearing: no; ExtendToStructure: no

# IfcWall: Basic Wall_BB_10.01.41#01_Gipskartonwand_MS100 _ 25.50.25_ 100 mm127, Basic Wall:BB_10.01.41#01_Gipskartonwand_MS100 / 25.50.25, 100 mm:25605376
In: 020
PredefinedType: PARTITIONING
Cpset_Wall - LevelOfAccuracy: in te vullen door Buildwise
IfcBuildingStorey - Base Offset: 2640; Top Offset: -460; Base Constraint: 020; Top Constraint: Up to level: 030
IfcClassificationReference - Keynote: 10.01.41#01; GVH_artnr 01: 10.01.41#01; GVH_artnr 02: geen waarde gevonden; GVH_artnr 03: geen waarde gevonden; GVH_artnr 04: geen waarde gevonden; GVH_artnr 05: geen waarde gevonden; GVH_artnr 06: geen waarde gevonden; TDS_link: .\05 As Builtdossier\2. Bouwkunde\2.1 Architectuur\2.1.10 wanden\TF A 10.01.41#1 A - lichte scheidingswand met gipsplaten.pdf
IfcElement - BB_Element_Lokaalnummer01: K.20.109
IfcRoot - Name: BB_10.01.41#01_Gipskartonwand_MS100 / 25.50.25, 100 mm
Qto_WallBaseQuantities - Length: 350; NetVolume: 0.015; Height: 500; Width: 100; GrossVolume: 0.015; GrossSideArea: 0.15; NetSideArea: 0.15
Pset_Condition - AssessmentCondition: Empty
Pset_EnvironmentalImpactIndicators - Reference: BB_10.01.41#01_Gipskartonwand_MS100 / 25.50.25, 100 mm; sets with these values: 2
Pset_WallCommon - Reference: BB_10.01.41#01_Gipskartonwand_MS100 / 25.50.25, 100 mm; FireRating: EI60; IsExternal: yes; LoadBearing: no; ExtendToStructure: no

# IfcWall: Basic Wall_BB_10.01.41#01_Gipskartonwand_MS100 _ 25.50.25_ 100 mm129, Basic Wall:BB_10.01.41#01_Gipskartonwand_MS100 / 25.50.25, 100 mm:25609174
In: 020
PredefinedType: PARTITIONING
Cpset_Wall - LevelOfAccuracy: in te vullen door Buildwise
IfcBuildingStorey - Base Offset: 2640; Top Offset: -680; Base Constraint: 020; Top Constraint: Up to level: 030
IfcClassificationReference - Keynote: 10.01.41#01; GVH_artnr 01: 10.01.41#01; GVH_artnr 02: geen waarde gevonden; GVH_artnr 03: geen waarde gevonden; GVH_artnr 04: geen waarde gevonden; GVH_artnr 05: geen waarde gevonden; GVH_artnr 06: geen waarde gevonden; TDS_link: .\05 As Builtdossier\2. Bouwkunde\2.1 Architectuur\2.1.10 wanden\TF A 10.01.41#1 A - lichte scheidingswand met gipsplaten.pdf
IfcElement - BB_Element_Lokaalnummer01: K.20.202
IfcRoot - Name: BB_10.01.41#01_Gipskartonwand_MS100 / 25.50.25, 100 mm
Qto_WallBaseQuantities - Length: 4695; NetVolume: 0.13006; Height: 280; Width: 100; GrossVolume: 0.13006; GrossSideArea: 1.3006; NetSideArea: 1.3006
Pset_Condition - AssessmentCondition: Empty
Pset_EnvironmentalImpactIndicators - Reference: BB_10.01.41#01_Gipskartonwand_MS100 / 25.50.25, 100 mm; sets with these values: 2
Pset_WallCommon - Reference: BB_10.01.41#01_Gipskartonwand_MS100 / 25.50.25, 100 mm; FireRating: EI60; IsExternal: yes; LoadBearing: no; ExtendToStructure: no

# IfcWall: Basic Wall_BB_10.01.41#01_Gipskartonwand_MS100 _ 25.50.25_ 100 mm13, Basic Wall:BB_10.01.41#01_Gipskartonwand_MS100 / 25.50.25, 100 mm:27797482
In: 000
PredefinedType: PARTITIONING
Cpset_Wall - LevelOfAccuracy: in te vullen door Buildwise
IfcBuildingStorey - Base Offset: 2700; Top Offset: -600; Base Constraint: 000; Top Constraint: Up to level: 010
IfcClassificationReference - Keynote: 10.01.41#01; GVH_artnr 01: 10.01.41#01; GVH_artnr 02: geen waarde gevonden; GVH_artnr 03: geen waarde gevonden; GVH_artnr 04: geen waarde gevonden; GVH_artnr 05: geen waarde gevonden; GVH_artnr 06: geen waarde gevonden; TDS_link: .\05 As Builtdossier\2. Bouwkunde\2.1 Architectuur\2.1.10 wanden\TF A 10.01.41#1 A - lichte scheidingswand met gipsplaten.pdf
IfcElement - BB_Element_Lokaalnummer01: K.00.503
IfcRoot - Name: BB_10.01.41#01_Gipskartonwand_MS100 / 25.50.25, 100 mm
Qto_WallBaseQuantities - Length: 9760; NetVolume: 0.2928; Height: 300; Width: 100; GrossVolume: 0.2928; GrossSideArea: 2.928; NetSideArea: 2.928
Pset_Condition - AssessmentCondition: Empty
Pset_EnvironmentalImpactIndicators - Reference: BB_10.01.41#01_Gipskartonwand_MS100 / 25.50.25, 100 mm; sets with these values: 2
Pset_WallCommon - Reference: BB_10.01.41#01_Gipskartonwand_MS100 / 25.50.25, 100 mm; FireRating: EI60; IsExternal: yes; LoadBearing: no; ExtendToStructure: no

# IfcWall: Basic Wall_BB_10.01.41#01_Gipskartonwand_MS100 _ 25.50.25_ 100 mm131, Basic Wall:BB_10.01.41#01_Gipskartonwand_MS100 / 25.50.25, 100 mm:25610782
In: 020
PredefinedType: PARTITIONING
Cpset_Wall - LevelOfAccuracy: in te vullen door Buildwise
IfcBuildingStorey - Base Offset: 2640; Top Offset: -680; Base Constraint: 020; Top Constraint: Up to level: 030
IfcClassificationReference - Keynote: 10.01.41#01; GVH_artnr 01: 10.01.41#01; GVH_artnr 02: geen waarde gevonden; GVH_artnr 03: geen waarde gevonden; GVH_artnr 04: geen waarde gevonden; GVH_artnr 05: geen waarde gevonden; GVH_artnr 06: geen waarde gevonden; TDS_link: .\05 As Builtdossier\2. Bouwkunde\2.1 Architectuur\2.1.10 wanden\TF A 10.01.41#1 A - lichte scheidingswand met gipsplaten.pdf
IfcElement - BB_Element_Lokaalnummer01: K.20.403
IfcRoot - Name: BB_10.01.41#01_Gipskartonwand_MS100 / 25.50.25, 100 mm
Qto_WallBaseQuantities - Length: 5090; NetVolume: 0.14112; Height: 280; Width: 100; GrossVolume: 0.14112; GrossSideArea: 1.4112; NetSideArea: 1.4112
Pset_Condition - AssessmentCondition: Empty
Pset_EnvironmentalImpactIndicators - Reference: BB_10.01.41#01_Gipskartonwand_MS100 / 25.50.25, 100 mm; sets with these values: 2
Pset_WallCommon - Reference: BB_10.01.41#01_Gipskartonwand_MS100 / 25.50.25, 100 mm; FireRating: EI60; IsExternal: yes; LoadBearing: no; ExtendToStructure: no

# IfcWall: Basic Wall_BB_10.01.41#01_Gipskartonwand_MS100 _ 25.50.25_ 100 mm133, Basic Wall:BB_10.01.41#01_Gipskartonwand_MS100 / 25.50.25, 100 mm:25613977
In: 020
PredefinedType: PARTITIONING
Cpset_Wall - LevelOfAccuracy: in te vullen door Buildwise
IfcBuildingStorey - Base Offset: 2640; Top Offset: -460; Base Constraint: 020; Top Constraint: Up to level: 030
IfcClassificationReference - Keynote: 10.01.41#01; GVH_artnr 01: 10.01.41#01; GVH_artnr 02: geen waarde gevonden; GVH_artnr 03: geen waarde gevonden; GVH_artnr 04: geen waarde gevonden; GVH_artnr 05: geen waarde gevonden; GVH_artnr 06: geen waarde gevonden; TDS_link: .\05 As Builtdossier\2. Bouwkunde\2.1 Architectuur\2.1.10 wanden\TF A 10.01.41#1 A - lichte scheidingswand met gipsplaten.pdf
IfcElement - BB_Element_Lokaalnummer01: K.20.509
IfcRoot - Name: BB_10.01.41#01_Gipskartonwand_MS100 / 25.50.25, 100 mm
Qto_WallBaseQuantities - Length: 350; NetVolume: 0.015; Height: 500; Width: 100; GrossVolume: 0.015; GrossSideArea: 0.15; NetSideArea: 0.15
Pset_Condition - AssessmentCondition: Empty
Pset_EnvironmentalImpactIndicators - Reference: BB_10.01.41#01_Gipskartonwand_MS100 / 25.50.25, 100 mm; sets with these values: 2
Pset_WallCommon - Reference: BB_10.01.41#01_Gipskartonwand_MS100 / 25.50.25, 100 mm; FireRating: EI60; IsExternal: yes; LoadBearing: no; ExtendToStructure: no

# IfcWall: Basic Wall_BB_10.01.41#01_Gipskartonwand_MS100 _ 25.50.25_ 100 mm135, Basic Wall:BB_10.01.41#01_Gipskartonwand_MS100 / 25.50.25, 100 mm:25653794
In: 020
PredefinedType: PARTITIONING
Cpset_Wall - LevelOfAccuracy: in te vullen door Buildwise
IfcBuildingStorey - Base Offset: 2640; Top Offset: -590; Base Constraint: 020; Top Constraint: Up to level: 030
IfcClassificationReference - Keynote: 10.01.41#01; GVH_artnr 01: 10.01.41#01; GVH_artnr 02: geen waarde gevonden; GVH_artnr 03: geen waarde gevonden; GVH_artnr 04: geen waarde gevonden; GVH_artnr 05: geen waarde gevonden; GVH_artnr 06: geen waarde gevonden; TDS_link: .\05 As Builtdossier\2. Bouwkunde\2.1 Architectuur\2.1.10 wanden\TF A 10.01.41#1 A - lichte scheidingswand met gipsplaten.pdf
IfcElement - BB_Element_Lokaalnummer01: K.20.509
IfcRoot - Name: BB_10.01.41#01_Gipskartonwand_MS100 / 25.50.25, 100 mm
Qto_WallBaseQuantities - Length: 350; NetVolume: 0.0111; Height: 370; Width: 100; GrossVolume: 0.0111; GrossSideArea: 0.111; NetSideArea: 0.111
Pset_Condition - AssessmentCondition: Empty
Pset_EnvironmentalImpactIndicators - Reference: BB_10.01.41#01_Gipskartonwand_MS100 / 25.50.25, 100 mm; sets with these values: 2
Pset_WallCommon - Reference: BB_10.01.41#01_Gipskartonwand_MS100 / 25.50.25, 100 mm; FireRating: EI60; IsExternal: yes; LoadBearing: no; ExtendToStructure: no

# IfcWall: Basic Wall_BB_10.01.41#01_Gipskartonwand_MS100 _ 25.50.25_ 100 mm137, Basic Wall:BB_10.01.41#01_Gipskartonwand_MS100 / 25.50.25, 100 mm:12557311
In: 030
PredefinedType: PARTITIONING
Cpset_Wall - LevelOfAccuracy: in te vullen door Buildwise
IfcBuildingStorey - Base Offset: -5; Top Offset: 3190; Base Constraint: 030; Top Constraint: Up to level: 030
IfcClassificationReference - Keynote: 10.01.41#01; GVH_artnr 01: 10.01.41#01; GVH_artnr 02: geen waarde gevonden; GVH_artnr 03: geen waarde gevonden; GVH_artnr 04: geen waarde gevonden; GVH_artnr 05: geen waarde gevonden; GVH_artnr 06: geen waarde gevonden; TDS_link: .\05 As Builtdossier\2. Bouwkunde\2.1 Architectuur\2.1.10 wanden\TF A 10.01.41#1 A - lichte scheidingswand met gipsplaten.pdf
IfcElement - BB_Element_Lokaalnummer01: K.30.404
IfcRoot - Name: BB_10.01.41#01_Gipskartonwand_MS100 / 25.50.25, 100 mm
Qto_WallBaseQuantities - Length: 1200; NetVolume: 0.225959; Height: 3195; Width: 100; GrossVolume: 0.399375; GrossSideArea: 3.99375; NetSideArea: 3.99375
Pset_Condition - AssessmentCondition: Empty
Pset_EnvironmentalImpactIndicators - Reference: BB_10.01.41#01_Gipskartonwand_MS100 / 25.50.25, 100 mm; sets with these values: 2
Pset_WallCommon - Reference: BB_10.01.41#01_Gipskartonwand_MS100 / 25.50.25, 100 mm; FireRating: EI60; IsExternal: yes; LoadBearing: no; ExtendToStructure: no

# IfcWall: Basic Wall_BB_10.01.41#01_Gipskartonwand_MS100 _ 25.50.25_ 100 mm139, Basic Wall:BB_10.01.41#01_Gipskartonwand_MS100 / 25.50.25, 100 mm:12557351
In: 030
PredefinedType: PARTITIONING
Cpset_Wall - LevelOfAccuracy: in te vullen door Buildwise
IfcBuildingStorey - Base Offset: -200; Top Offset: 3190; Base Constraint: 030; Top Constraint: Up to level: 030
IfcClassificationReference - Keynote: 10.01.41#01; GVH_artnr 01: 10.01.41#01; GVH_artnr 02: geen waarde gevonden; GVH_artnr 03: geen waarde gevonden; GVH_artnr 04: geen waarde gevonden; GVH_artnr 05: geen waarde gevonden; GVH_artnr 06: geen waarde gevonden; TDS_link: .\05 As Builtdossier\2. Bouwkunde\2.1 Architectuur\2.1.10 wanden\TF A 10.01.41#1 A - lichte scheidingswand met gipsplaten.pdf
IfcElement - BB_Element_Lokaalnummer01: K.30.404
IfcRoot - Name: BB_10.01.41#01_Gipskartonwand_MS100 / 25.50.25, 100 mm
Qto_WallBaseQuantities - Length: 4860; NetVolume: 1.62143; Height: 3390; Width: 100; GrossVolume: 1.62143; GrossSideArea: 16.2143; NetSideArea: 16.2143
Pset_Condition - AssessmentCondition: Empty
Pset_EnvironmentalImpactIndicators - Reference: BB_10.01.41#01_Gipskartonwand_MS100 / 25.50.25, 100 mm; sets with these values: 2
Pset_WallCommon - Reference: BB_10.01.41#01_Gipskartonwand_MS100 / 25.50.25, 100 mm; IsExternal: yes; LoadBearing: no; ExtendToStructure: no

# IfcWall: Basic Wall_BB_10.01.41#01_Gipskartonwand_MS100 _ 25.50.25_ 100 mm141, Basic Wall:BB_10.01.41#01_Gipskartonwand_MS100 / 25.50.25, 100 mm:12926456
In: 030
PredefinedType: PARTITIONING
Cpset_Wall - LevelOfAccuracy: in te vullen door Buildwise
IfcBuildingStorey - Base Offset: 2640; Top Offset: -600; Base Constraint: 030; Top Constraint: Up to level: 040
IfcClassificationReference - Keynote: 10.01.41#01; GVH_artnr 01: 10.01.41#01; GVH_artnr 02: geen waarde gevonden; GVH_artnr 03: geen waarde gevonden; GVH_artnr 04: geen waarde gevonden; GVH_artnr 05: geen waarde gevonden; GVH_artnr 06: geen waarde gevonden; TDS_link: .\05 As Builtdossier\2. Bouwkunde\2.1 Architectuur\2.1.10 wanden\TF A 10.01.41#1 A - lichte scheidingswand met gipsplaten.pdf
IfcElement - BB_Element_Lokaalnummer01: K.30.112
IfcRoot - Name: BB_10.01.41#01_Gipskartonwand_MS100 / 25.50.25, 100 mm
Qto_WallBaseQuantities - Length: 13950; NetVolume: 0.4968; Height: 360; Width: 100; GrossVolume: 0.4968; GrossSideArea: 4.968; NetSideArea: 4.968
Pset_Condition - AssessmentCondition: Empty
Pset_EnvironmentalImpactIndicators - Reference: BB_10.01.41#01_Gipskartonwand_MS100 / 25.50.25, 100 mm; sets with these values: 2
Pset_WallCommon - Reference: BB_10.01.41#01_Gipskartonwand_MS100 / 25.50.25, 100 mm; FireRating: EI60; IsExternal: yes; LoadBearing: no; ExtendToStructure: no

# IfcWall: Basic Wall_BB_10.01.41#01_Gipskartonwand_MS100 _ 25.50.25_ 100 mm143, Basic Wall:BB_10.01.41#01_Gipskartonwand_MS100 / 25.50.25, 100 mm:13704922
In: 030
PredefinedType: PARTITIONING
Cpset_Wall - LevelOfAccuracy: in te vullen door Buildwise
IfcBuildingStorey - Base Offset: 2640; Top Offset: -600; Base Constraint: 030; Top Constraint: Up to level: 040
IfcClassificationReference - Keynote: 10.01.41#01; GVH_artnr 01: 10.01.41#01; GVH_artnr 02: geen waarde gevonden; GVH_artnr 03: geen waarde gevonden; GVH_artnr 04: geen waarde gevonden; GVH_artnr 05: geen waarde gevonden; GVH_artnr 06: geen waarde gevonden; TDS_link: .\05 As Builtdossier\2. Bouwkunde\2.1 Architectuur\2.1.10 wanden\TF A 10.01.41#1 A - lichte scheidingswand met gipsplaten.pdf
IfcElement - BB_Element_Lokaalnummer01: K.30.109
IfcRoot - Name: BB_10.01.41#01_Gipskartonwand_MS100 / 25.50.25, 100 mm
Qto_WallBaseQuantities - Length: 5295; NetVolume: 0.18882; Height: 360; Width: 100; GrossVolume: 0.18882; GrossSideArea: 1.8882; NetSideArea: 1.8882
Pset_Condition - AssessmentCondition: Empty
Pset_EnvironmentalImpactIndicators - Reference: BB_10.01.41#01_Gipskartonwand_MS100 / 25.50.25, 100 mm; sets with these values: 2
Pset_WallCommon - Reference: BB_10.01.41#01_Gipskartonwand_MS100 / 25.50.25, 100 mm; FireRating: EI60; IsExternal: yes; LoadBearing: no; ExtendToStructure: no

# IfcWall: Basic Wall_BB_10.01.41#01_Gipskartonwand_MS100 _ 25.50.25_ 100 mm145, Basic Wall:BB_10.01.41#01_Gipskartonwand_MS100 / 25.50.25, 100 mm:16295290
In: 030
PredefinedType: PARTITIONING
Cpset_Wall - LevelOfAccuracy: in te vullen door Buildwise
IfcBuildingStorey - Base Offset: 2670; Top Offset: 3190; Base Constraint: 030; Top Constraint: Up to level: 030
IfcClassificationReference - Keynote: 10.01.41#01; GVH_artnr 01: 10.01.41#01; GVH_artnr 02: geen waarde gevonden; GVH_artnr 03: geen waarde gevonden; GVH_artnr 04: geen waarde gevonden; GVH_artnr 05: geen waarde gevonden; GVH_artnr 06: geen waarde gevonden; TDS_link: .\05 As Builtdossier\2. Bouwkunde\2.1 Architectuur\2.1.10 wanden\TF A 10.01.41#1 A - lichte scheidingswand met gipsplaten.pdf
IfcElement - BB_Element_Lokaalnummer01: K.30.112
IfcRoot - Name: BB_10.01.41#01_Gipskartonwand_MS100 / 25.50.25, 100 mm
Qto_WallBaseQuantities - Length: 1335; NetVolume: 0.06942; Height: 520; Width: 100; GrossVolume: 0.06942; GrossSideArea: 0.6942; NetSideArea: 0.6942
Pset_Condition - AssessmentCondition: Empty
Pset_EnvironmentalImpactIndicators - Reference: BB_10.01.41#01_Gipskartonwand_MS100 / 25.50.25, 100 mm; sets with these values: 2
Pset_WallCommon - Reference: BB_10.01.41#01_Gipskartonwand_MS100 / 25.50.25, 100 mm; FireRating: EI60; IsExternal: yes; LoadBearing: no; ExtendToStructure: no

# IfcWall: Basic Wall_BB_10.01.41#01_Gipskartonwand_MS100 _ 25.50.25_ 100 mm147, Basic Wall:BB_10.01.41#01_Gipskartonwand_MS100 / 25.50.25, 100 mm:25655817
In: 030
PredefinedType: PARTITIONING
Cpset_Wall - LevelOfAccuracy: in te vullen door Buildwise
IfcBuildingStorey - Base Offset: 2640; Top Offset: -600; Base Constraint: 030; Top Constraint: Up to level: 040
IfcClassificationReference - Keynote: 10.01.41#01; GVH_artnr 01: 10.01.41#01; GVH_artnr 02: geen waarde gevonden; GVH_artnr 03: geen waarde gevonden; GVH_artnr 04: geen waarde gevonden; GVH_artnr 05: geen waarde gevonden; GVH_artnr 06: geen waarde gevonden; TDS_link: .\05 As Builtdossier\2. Bouwkunde\2.1 Architectuur\2.1.10 wanden\TF A 10.01.41#1 A - lichte scheidingswand met gipsplaten.pdf
IfcRoot - Name: BB_10.01.41#01_Gipskartonwand_MS100 / 25.50.25, 100 mm
Qto_WallBaseQuantities - Length: 7100; NetVolume: 0.2556; Height: 360; Width: 100; GrossVolume: 0.2556; GrossSideArea: 2.556; NetSideArea: 2.556
Pset_Condition - AssessmentCondition: Empty
Pset_EnvironmentalImpactIndicators - Reference: BB_10.01.41#01_Gipskartonwand_MS100 / 25.50.25, 100 mm; sets with these values: 2
Pset_WallCommon - Reference: BB_10.01.41#01_Gipskartonwand_MS100 / 25.50.25, 100 mm; FireRating: EI60; IsExternal: yes; LoadBearing: no; ExtendToStructure: no

# IfcWall: Basic Wall_BB_10.01.41#01_Gipskartonwand_MS100 _ 25.50.25_ 100 mm149, Basic Wall:BB_10.01.41#01_Gipskartonwand_MS100 / 25.50.25, 100 mm:32023377
In: 030
PredefinedType: PARTITIONING
Cpset_Wall - LevelOfAccuracy: in te vullen door Buildwise
IfcBuildingStorey - Base Offset: -10; Top Offset: 3190; Base Constraint: 030; Top Constraint: Up to level: 030
IfcClassificationReference - Keynote: 10.01.41#01; GVH_artnr 01: 10.01.41#01; GVH_artnr 02: geen waarde gevonden; GVH_artnr 03: geen waarde gevonden; GVH_artnr 04: geen waarde gevonden; GVH_artnr 05: geen waarde gevonden; GVH_artnr 06: geen waarde gevonden; TDS_link: .\05 As Builtdossier\2. Bouwkunde\2.1 Architectuur\2.1.10 wanden\TF A 10.01.41#1 A - lichte scheidingswand met gipsplaten.pdf
IfcRoot - Name: BB_10.01.41#01_Gipskartonwand_MS100 / 25.50.25, 100 mm
Qto_WallBaseQuantities - Length: 1460; NetVolume: 0.27496; Height: 3200; Width: 100; GrossVolume: 0.4672; GrossSideArea: 4.672; NetSideArea: 2.7496
Pset_Condition - AssessmentCondition: Empty
Pset_EnvironmentalImpactIndicators - Reference: BB_10.01.41#01_Gipskartonwand_MS100 / 25.50.25, 100 mm; sets with these values: 2
Pset_WallCommon - Reference: BB_10.01.41#01_Gipskartonwand_MS100 / 25.50.25, 100 mm; FireRating: EI60; IsExternal: yes; LoadBearing: no; ExtendToStructure: no

# IfcWall: Basic Wall_BB_10.01.41#01_Gipskartonwand_MS100 _ 25.50.25_ 100 mm15, Basic Wall:BB_10.01.41#01_Gipskartonwand_MS100 / 25.50.25, 100 mm:27804895
In: 000
PredefinedType: PARTITIONING
Cpset_Wall - LevelOfAccuracy: in te vullen door Buildwise
IfcBuildingStorey - Base Offset: 2700; Top Offset: -600; Base Constraint: 000; Top Constraint: Up to level: 010
IfcClassificationReference - Keynote: 10.01.41#01; GVH_artnr 01: 10.01.41#01; GVH_artnr 02: geen waarde gevonden; GVH_artnr 03: geen waarde gevonden; GVH_artnr 04: geen waarde gevonden; GVH_artnr 05: geen waarde gevonden; GVH_artnr 06: geen waarde gevonden; TDS_link: .\05 As Builtdossier\2. Bouwkunde\2.1 Architectuur\2.1.10 wanden\TF A 10.01.41#1 A - lichte scheidingswand met gipsplaten.pdf
IfcElement - BB_Element_Lokaalnummer01: K.00.201
IfcRoot - Name: BB_10.01.41#01_Gipskartonwand_MS100 / 25.50.25, 100 mm
Qto_WallBaseQuantities - Length: 11485; NetVolume: 0.34455; Height: 300; Width: 100; GrossVolume: 0.34455; GrossSideArea: 3.4455; NetSideArea: 3.4455
Pset_Condition - AssessmentCondition: Empty
Pset_EnvironmentalImpactIndicators - Reference: BB_10.01.41#01_Gipskartonwand_MS100 / 25.50.25, 100 mm; sets with these values: 2
Pset_WallCommon - Reference: BB_10.01.41#01_Gipskartonwand_MS100 / 25.50.25, 100 mm; FireRating: EI60; IsExternal: yes; LoadBearing: no; ExtendToStructure: no

# IfcWall: Basic Wall_BB_10.01.41#01_Gipskartonwand_MS100 _ 25.50.25_ 100 mm17, Basic Wall:BB_10.01.41#01_Gipskartonwand_MS100 / 25.50.25, 100 mm:29018962
In: 000
PredefinedType: PARTITIONING
Cpset_Wall - LevelOfAccuracy: in te vullen door Buildwise
IfcBuildingStorey - Base Offset: 2640; Top Offset: -460; Base Constraint: 000; Top Constraint: Up to level: 010
IfcClassificationReference - Keynote: 10.01.41#01; GVH_artnr 01: 10.01.41#01; GVH_artnr 02: geen waarde gevonden; GVH_artnr 03: geen waarde gevonden; GVH_artnr 04: geen waarde gevonden; GVH_artnr 05: geen waarde gevonden; GVH_artnr 06: geen waarde gevonden; TDS_link: .\05 As Builtdossier\2. Bouwkunde\2.1 Architectuur\2.1.10 wanden\TF A 10.01.41#1 A - lichte scheidingswand met gipsplaten.pdf
IfcElement - BB_Element_Lokaalnummer01: K.00.402
IfcRoot - Name: BB_10.01.41#01_Gipskartonwand_MS100 / 25.50.25, 100 mm
Qto_WallBaseQuantities - Length: 5213.07; NetVolume: 0.256904; Height: 500; Width: 100; GrossVolume: 0.256904; GrossSideArea: 2.56904; NetSideArea: 2.56904
Pset_Condition - AssessmentCondition: Empty
Pset_EnvironmentalImpactIndicators - Reference: BB_10.01.41#01_Gipskartonwand_MS100 / 25.50.25, 100 mm; sets with these values: 2
Pset_WallCommon - Reference: BB_10.01.41#01_Gipskartonwand_MS100 / 25.50.25, 100 mm; FireRating: EI60; IsExternal: yes; LoadBearing: no; ExtendToStructure: no

# IfcWall: Basic Wall_BB_10.01.41#01_Gipskartonwand_MS100 _ 25.50.25_ 100 mm19, Basic Wall:BB_10.01.41#01_Gipskartonwand_MS100 / 25.50.25, 100 mm:29018963
In: 000
PredefinedType: PARTITIONING
Cpset_Wall - LevelOfAccuracy: in te vullen door Buildwise
IfcBuildingStorey - Base Offset: 2640; Top Offset: -460; Base Constraint: 000; Top Constraint: Up to level: 010
IfcClassificationReference - Keynote: 10.01.41#01; GVH_artnr 01: 10.01.41#01; GVH_artnr 02: geen waarde gevonden; GVH_artnr 03: geen waarde gevonden; GVH_artnr 04: geen waarde gevonden; GVH_artnr 05: geen waarde gevonden; GVH_artnr 06: geen waarde gevonden; TDS_link: .\05 As Builtdossier\2. Bouwkunde\2.1 Architectuur\2.1.10 wanden\TF A 10.01.41#1 A - lichte scheidingswand met gipsplaten.pdf
IfcElement - BB_Element_Lokaalnummer01: K.00.402
IfcRoot - Name: BB_10.01.41#01_Gipskartonwand_MS100 / 25.50.25, 100 mm
Qto_WallBaseQuantities - Length: 5213.07; NetVolume: 0.256904; Height: 500; Width: 100; GrossVolume: 0.256904; GrossSideArea: 2.56904; NetSideArea: 2.56904
Pset_Condition - AssessmentCondition: Empty
Pset_EnvironmentalImpactIndicators - Reference: BB_10.01.41#01_Gipskartonwand_MS100 / 25.50.25, 100 mm; sets with these values: 2
Pset_WallCommon - Reference: BB_10.01.41#01_Gipskartonwand_MS100 / 25.50.25, 100 mm; FireRating: EI60; IsExternal: yes; LoadBearing: no; ExtendToStructure: no

# IfcWall: Basic Wall_BB_10.01.41#01_Gipskartonwand_MS100 _ 25.50.25_ 100 mm21, Basic Wall:BB_10.01.41#01_Gipskartonwand_MS100 / 25.50.25, 100 mm:12997161
In: 010
PredefinedType: PARTITIONING
Cpset_Wall - LevelOfAccuracy: in te vullen door Buildwise
IfcBuildingStorey - Base Offset: -5; Top Offset: -600; Base Constraint: 010; Top Constraint: Up to level: 020
IfcClassificationReference - Keynote: 10.01.41#01; GVH_artnr 01: 10.01.41#01; GVH_artnr 02: geen waarde gevonden; GVH_artnr 03: geen waarde gevonden; GVH_artnr 04: geen waarde gevonden; GVH_artnr 05: geen waarde gevonden; GVH_artnr 06: geen waarde gevonden; TDS_link: .\05 As Builtdossier\2. Bouwkunde\2.1 Architectuur\2.1.10 wanden\TF A 10.01.41#1 A - lichte scheidingswand met gipsplaten.pdf
IfcElement - BB_Element_Lokaalnummer01: K.10.113
IfcRoot - Name: BB_10.01.41#01_Gipskartonwand_MS100 / 25.50.25, 100 mm
Qto_WallBaseQuantities - Length: 5444.87; NetVolume: 1.42367; Height: 3005; Width: 100; GrossVolume: 1.42367; GrossSideArea: 14.2367; NetSideArea: 14.2367
Pset_Condition - AssessmentCondition: Empty
Pset_EnvironmentalImpactIndicators - Reference: BB_10.01.41#01_Gipskartonwand_MS100 / 25.50.25, 100 mm; sets with these values: 2
Pset_WallCommon - Reference: BB_10.01.41#01_Gipskartonwand_MS100 / 25.50.25, 100 mm; FireRating: EI60; IsExternal: yes; LoadBearing: no; ExtendToStructure: no

# IfcWall: Basic Wall_BB_10.01.41#01_Gipskartonwand_MS100 _ 25.50.25_ 100 mm23, Basic Wall:BB_10.01.41#01_Gipskartonwand_MS100 / 25.50.25, 100 mm:13000353
In: 010
PredefinedType: PARTITIONING
Cpset_Wall - LevelOfAccuracy: in te vullen door Buildwise
IfcBuildingStorey - Base Offset: -5; Top Offset: 3000; Base Constraint: 010; Top Constraint: Up to level: 010
IfcClassificationReference - Keynote: 10.01.41#01; GVH_artnr 01: 10.01.41#01; GVH_artnr 02: geen waarde gevonden; GVH_artnr 03: geen waarde gevonden; GVH_artnr 04: geen waarde gevonden; GVH_artnr 05: geen waarde gevonden; GVH_artnr 06: geen waarde gevonden; TDS_link: .\05 As Builtdossier\2. Bouwkunde\2.1 Architectuur\2.1.10 wanden\TF A 10.01.41#1 A - lichte scheidingswand met gipsplaten.pdf
IfcElement - BB_Element_Lokaalnummer01: K.10.409
IfcRoot - Name: BB_10.01.41#01_Gipskartonwand_MS100 / 25.50.25, 100 mm
Qto_WallBaseQuantities - Length: 1200; NetVolume: 0.18294; Height: 3005; Width: 100; GrossVolume: 0.18294; GrossSideArea: 1.8294; NetSideArea: 1.8294
Pset_Condition - AssessmentCondition: Empty
Pset_EnvironmentalImpactIndicators - Reference: BB_10.01.41#01_Gipskartonwand_MS100 / 25.50.25, 100 mm; sets with these values: 2
Pset_WallCommon - Reference: BB_10.01.41#01_Gipskartonwand_MS100 / 25.50.25, 100 mm; FireRating: EI60; IsExternal: yes; LoadBearing: no; ExtendToStructure: no

# IfcWall: Basic Wall_BB_10.01.41#01_Gipskartonwand_MS100 _ 25.50.25_ 100 mm25, Basic Wall:BB_10.01.41#01_Gipskartonwand_MS100 / 25.50.25, 100 mm:13000354
In: 010
PredefinedType: PARTITIONING
Cpset_Wall - LevelOfAccuracy: in te vullen door Buildwise
IfcBuildingStorey - Base Offset: -5; Top Offset: 3000; Base Constraint: 010; Top Constraint: Up to level: 010
IfcClassificationReference - Keynote: 10.01.41#01; GVH_artnr 01: 10.01.41#01; GVH_artnr 02: geen waarde gevonden; GVH_artnr 03: geen waarde gevonden; GVH_artnr 04: geen waarde gevonden; GVH_artnr 05: geen waarde gevonden; GVH_artnr 06: geen waarde gevonden; TDS_link: .\05 As Builtdossier\2. Bouwkunde\2.1 Architectuur\2.1.10 wanden\TF A 10.01.41#1 A - lichte scheidingswand met gipsplaten.pdf
IfcElement - BB_Element_Lokaalnummer01: K.10.409
IfcRoot - Name: BB_10.01.41#01_Gipskartonwand_MS100 / 25.50.25, 100 mm
Qto_WallBaseQuantities - Length: 4870; NetVolume: 1.43671; Height: 3005; Width: 100; GrossVolume: 1.43671; GrossSideArea: 14.3671; NetSideArea: 14.3671
Pset_Condition - AssessmentCondition: Empty
Pset_EnvironmentalImpactIndicators - Reference: BB_10.01.41#01_Gipskartonwand_MS100 / 25.50.25, 100 mm; sets with these values: 2
Pset_WallCommon - Reference: BB_10.01.41#01_Gipskartonwand_MS100 / 25.50.25, 100 mm; FireRating: EI60; IsExternal: yes; LoadBearing: no; ExtendToStructure: no

# IfcWall: Basic Wall_BB_10.01.41#01_Gipskartonwand_MS100 _ 25.50.25_ 100 mm27, Basic Wall:BB_10.01.41#01_Gipskartonwand_MS100 / 25.50.25, 100 mm:13276582
In: 010
PredefinedType: PARTITIONING
Cpset_Wall - LevelOfAccuracy: in te vullen door Buildwise
IfcBuildingStorey - Base Offset: -5; Top Offset: -600; Base Constraint: 010; Top Constraint: Up to level: 020
IfcClassificationReference - Keynote: 10.01.41#01; GVH_artnr 01: 10.01.41#01; GVH_artnr 02: geen waarde gevonden; GVH_artnr 03: geen waarde gevonden; GVH_artnr 04: geen waarde gevonden; GVH_artnr 05: geen waarde gevonden; GVH_artnr 06: geen waarde gevonden; TDS_link: .\05 As Builtdossier\2. Bouwkunde\2.1 Architectuur\2.1.10 wanden\TF A 10.01.41#1 A - lichte scheidingswand met gipsplaten.pdf
IfcElement - BB_Element_Lokaalnummer01: K.10.206
IfcRoot - Name: BB_10.01.41#01_Gipskartonwand_MS100 / 25.50.25, 100 mm
Qto_WallBaseQuantities - Length: 4545; NetVolume: 1.35731; Height: 3075; Width: 100; GrossVolume: 1.35731; GrossSideArea: 13.5731; NetSideArea: 13.5731
Pset_Condition - AssessmentCondition: Empty
Pset_EnvironmentalImpactIndicators - Reference: BB_10.01.41#01_Gipskartonwand_MS100 / 25.50.25, 100 mm; sets with these values: 2
Pset_WallCommon - Reference: BB_10.01.41#01_Gipskartonwand_MS100 / 25.50.25, 100 mm; FireRating: EI60; IsExternal: yes; LoadBearing: no; ExtendToStructure: no

# IfcWall: Basic Wall_BB_10.01.41#01_Gipskartonwand_MS100 _ 25.50.25_ 100 mm29, Basic Wall:BB_10.01.41#01_Gipskartonwand_MS100 / 25.50.25, 100 mm:13713660
In: 010
PredefinedType: PARTITIONING
Cpset_Wall - LevelOfAccuracy: in te vullen door Buildwise
IfcBuildingStorey - Base Offset: 2640; Top Offset: -460; Base Constraint: 010; Top Constraint: Up to level: 020
IfcClassificationReference - Keynote: 10.01.41#01; GVH_artnr 01: 10.01.41#01; GVH_artnr 02: geen waarde gevonden; GVH_artnr 03: geen waarde gevonden; GVH_artnr 04: geen waarde gevonden; GVH_artnr 05: geen waarde gevonden; GVH_artnr 06: geen waarde gevonden; TDS_link: .\05 As Builtdossier\2. Bouwkunde\2.1 Architectuur\2.1.10 wanden\TF A 10.01.41#1 A - lichte scheidingswand met gipsplaten.pdf
IfcElement - BB_Element_Lokaalnummer01: K.10.407
IfcRoot - Name: BB_10.01.41#01_Gipskartonwand_MS100 / 25.50.25, 100 mm
Qto_WallBaseQuantities - Length: 350; NetVolume: 0.02; Height: 500; Width: 100; GrossVolume: 0.02; GrossSideArea: 0.2; NetSideArea: 0.2
Pset_Condition - AssessmentCondition: Empty
Pset_EnvironmentalImpactIndicators - Reference: BB_10.01.41#01_Gipskartonwand_MS100 / 25.50.25, 100 mm; sets with these values: 2
Pset_WallCommon - Reference: BB_10.01.41#01_Gipskartonwand_MS100 / 25.50.25, 100 mm; FireRating: EI60; IsExternal: yes; LoadBearing: no; ExtendToStructure: no

# IfcWall: Basic Wall_BB_10.01.41#01_Gipskartonwand_MS100 _ 25.50.25_ 100 mm3, Basic Wall:BB_10.01.41#01_Gipskartonwand_MS100 / 25.50.25, 100 mm:16236333
In: 000
PredefinedType: PARTITIONING
Cpset_Wall - LevelOfAccuracy: in te vullen door Buildwise
IfcBuildingStorey - Base Offset: 2670; Top Offset: -530; Base Constraint: 000; Top Constraint: Up to level: 010
IfcClassificationReference - Keynote: 10.01.41#01; GVH_artnr 01: 10.01.41#01; GVH_artnr 02: geen waarde gevonden; GVH_artnr 03: geen waarde gevonden; GVH_artnr 04: geen waarde gevonden; GVH_artnr 05: geen waarde gevonden; GVH_artnr 06: geen waarde gevonden; TDS_link: .\05 As Builtdossier\2. Bouwkunde\2.1 Architectuur\2.1.10 wanden\TF A 10.01.41#1 A - lichte scheidingswand met gipsplaten.pdf
IfcElement - BB_Element_Lokaalnummer01: K.10.301
IfcRoot - Name: BB_10.01.41#01_Gipskartonwand_MS100 / 25.50.25, 100 mm
Qto_WallBaseQuantities - Length: 1840.87; NetVolume: 0.0736348; Height: 400; Width: 100; GrossVolume: 0.0736348; GrossSideArea: 0.736348; NetSideArea: 0.736348
Pset_Condition - AssessmentCondition: Empty
Pset_EnvironmentalImpactIndicators - Reference: BB_10.01.41#01_Gipskartonwand_MS100 / 25.50.25, 100 mm; sets with these values: 2
Pset_WallCommon - Reference: BB_10.01.41#01_Gipskartonwand_MS100 / 25.50.25, 100 mm; FireRating: EI60; IsExternal: yes; LoadBearing: no; ExtendToStructure: no

# IfcWall: Basic Wall_BB_10.01.41#01_Gipskartonwand_MS100 _ 25.50.25_ 100 mm31, Basic Wall:BB_10.01.41#01_Gipskartonwand_MS100 / 25.50.25, 100 mm:13713749
In: 010
PredefinedType: PARTITIONING
Cpset_Wall - LevelOfAccuracy: in te vullen door Buildwise
IfcBuildingStorey - Base Offset: 2640; Top Offset: -460; Base Constraint: 010; Top Constraint: Up to level: 020
IfcClassificationReference - Keynote: 10.01.41#01; GVH_artnr 01: 10.01.41#01; GVH_artnr 02: geen waarde gevonden; GVH_artnr 03: geen waarde gevonden; GVH_artnr 04: geen waarde gevonden; GVH_artnr 05: geen waarde gevonden; GVH_artnr 06: geen waarde gevonden; TDS_link: .\05 As Builtdossier\2. Bouwkunde\2.1 Architectuur\2.1.10 wanden\TF A 10.01.41#1 A - lichte scheidingswand met gipsplaten.pdf
IfcElement - BB_Element_Lokaalnummer01: K.20.403
IfcRoot - Name: BB_10.01.41#01_Gipskartonwand_MS100 / 25.50.25, 100 mm
Qto_WallBaseQuantities - Length: 22180; NetVolume: 0.89546; Height: 500; Width: 100; GrossVolume: 0.89546; GrossSideArea: 8.9546; NetSideArea: 8.9546
Pset_Condition - AssessmentCondition: Empty
Pset_EnvironmentalImpactIndicators - Reference: BB_10.01.41#01_Gipskartonwand_MS100 / 25.50.25, 100 mm; sets with these values: 2
Pset_WallCommon - Reference: BB_10.01.41#01_Gipskartonwand_MS100 / 25.50.25, 100 mm; FireRating: EI60; IsExternal: yes; LoadBearing: no; ExtendToStructure: no

# IfcWall: Basic Wall_BB_10.01.41#01_Gipskartonwand_MS100 _ 25.50.25_ 100 mm33, Basic Wall:BB_10.01.41#01_Gipskartonwand_MS100 / 25.50.25, 100 mm:13713802
In: 010
PredefinedType: PARTITIONING
Cpset_Wall - LevelOfAccuracy: in te vullen door Buildwise
IfcBuildingStorey - Base Offset: 2640; Top Offset: -460; Base Constraint: 010; Top Constraint: Up to level: 020
IfcClassificationReference - Keynote: 10.01.41#01; GVH_artnr 01: 10.01.41#01; GVH_artnr 02: geen waarde gevonden; GVH_artnr 03: geen waarde gevonden; GVH_artnr 04: geen waarde gevonden; GVH_artnr 05: geen waarde gevonden; GVH_artnr 06: geen waarde gevonden; TDS_link: .\05 As Builtdossier\2. Bouwkunde\2.1 Architectuur\2.1.10 wanden\TF A 10.01.41#1 A - lichte scheidingswand met gipsplaten.pdf
IfcElement - BB_Element_Lokaalnummer01: K.10.405
IfcRoot - Name: BB_10.01.41#01_Gipskartonwand_MS100 / 25.50.25, 100 mm
Qto_WallBaseQuantities - Length: 5080; NetVolume: 0.2515; Height: 500; Width: 100; GrossVolume: 0.2515; GrossSideArea: 2.515; NetSideArea: 2.515
Pset_Condition - AssessmentCondition: Empty
Pset_EnvironmentalImpactIndicators - Reference: BB_10.01.41#01_Gipskartonwand_MS100 / 25.50.25, 100 mm; sets with these values: 2
Pset_WallCommon - Reference: BB_10.01.41#01_Gipskartonwand_MS100 / 25.50.25, 100 mm; FireRating: EI60; IsExternal: yes; LoadBearing: no; ExtendToStructure: no

# IfcWall: Basic Wall_BB_10.01.41#01_Gipskartonwand_MS100 _ 25.50.25_ 100 mm35, Basic Wall:BB_10.01.41#01_Gipskartonwand_MS100 / 25.50.25, 100 mm:13713899
In: 010
PredefinedType: PARTITIONING
Cpset_Wall - LevelOfAccuracy: in te vullen door Buildwise
IfcBuildingStorey - Base Offset: 2640; Top Offset: -460; Base Constraint: 010; Top Constraint: Up to level: 020
IfcClassificationReference - Keynote: 10.01.41#01; GVH_artnr 01: 10.01.41#01; GVH_artnr 02: geen waarde gevonden; GVH_artnr 03: geen waarde gevonden; GVH_artnr 04: geen waarde gevonden; GVH_artnr 05: geen waarde gevonden; GVH_artnr 06: geen waarde gevonden; TDS_link: .\05 As Builtdossier\2. Bouwkunde\2.1 Architectuur\2.1.10 wanden\TF A 10.01.41#1 A - lichte scheidingswand met gipsplaten.pdf
IfcElement - BB_Element_Lokaalnummer01: K.10.406
IfcRoot - Name: BB_10.01.41#01_Gipskartonwand_MS100 / 25.50.25, 100 mm
Qto_WallBaseQuantities - Length: 350; NetVolume: 0.015; Height: 500; Width: 100; GrossVolume: 0.015; GrossSideArea: 0.15; NetSideArea: 0.15
Pset_Condition - AssessmentCondition: Empty
Pset_EnvironmentalImpactIndicators - Reference: BB_10.01.41#01_Gipskartonwand_MS100 / 25.50.25, 100 mm; sets with these values: 2
Pset_WallCommon - Reference: BB_10.01.41#01_Gipskartonwand_MS100 / 25.50.25, 100 mm; FireRating: EI60; IsExternal: yes; LoadBearing: no; ExtendToStructure: no

# IfcWall: Basic Wall_BB_10.01.41#01_Gipskartonwand_MS100 _ 25.50.25_ 100 mm37, Basic Wall:BB_10.01.41#01_Gipskartonwand_MS100 / 25.50.25, 100 mm:13715160
In: 010
PredefinedType: PARTITIONING
Cpset_Wall - LevelOfAccuracy: in te vullen door Buildwise
IfcBuildingStorey - Base Offset: 2640; Top Offset: -460; Base Constraint: 010; Top Constraint: Up to level: 020
IfcClassificationReference - Keynote: 10.01.41#01; GVH_artnr 01: 10.01.41#01; GVH_artnr 02: geen waarde gevonden; GVH_artnr 03: geen waarde gevonden; GVH_artnr 04: geen waarde gevonden; GVH_artnr 05: geen waarde gevonden; GVH_artnr 06: geen waarde gevonden; TDS_link: .\05 As Builtdossier\2. Bouwkunde\2.1 Architectuur\2.1.10 wanden\TF A 10.01.41#1 A - lichte scheidingswand met gipsplaten.pdf
IfcElement - BB_Element_Lokaalnummer01: K.10.501
IfcRoot - Name: BB_10.01.41#01_Gipskartonwand_MS100 / 25.50.25, 100 mm
Qto_WallBaseQuantities - Length: 28800; NetVolume: 1.2135; Height: 500; Width: 100; GrossVolume: 1.2135; GrossSideArea: 12.135; NetSideArea: 12.135
Pset_Condition - AssessmentCondition: Empty
Pset_EnvironmentalImpactIndicators - Reference: BB_10.01.41#01_Gipskartonwand_MS100 / 25.50.25, 100 mm; sets with these values: 2
Pset_WallCommon - Reference: BB_10.01.41#01_Gipskartonwand_MS100 / 25.50.25, 100 mm; FireRating: EI60; IsExternal: yes; LoadBearing: no; ExtendToStructure: no
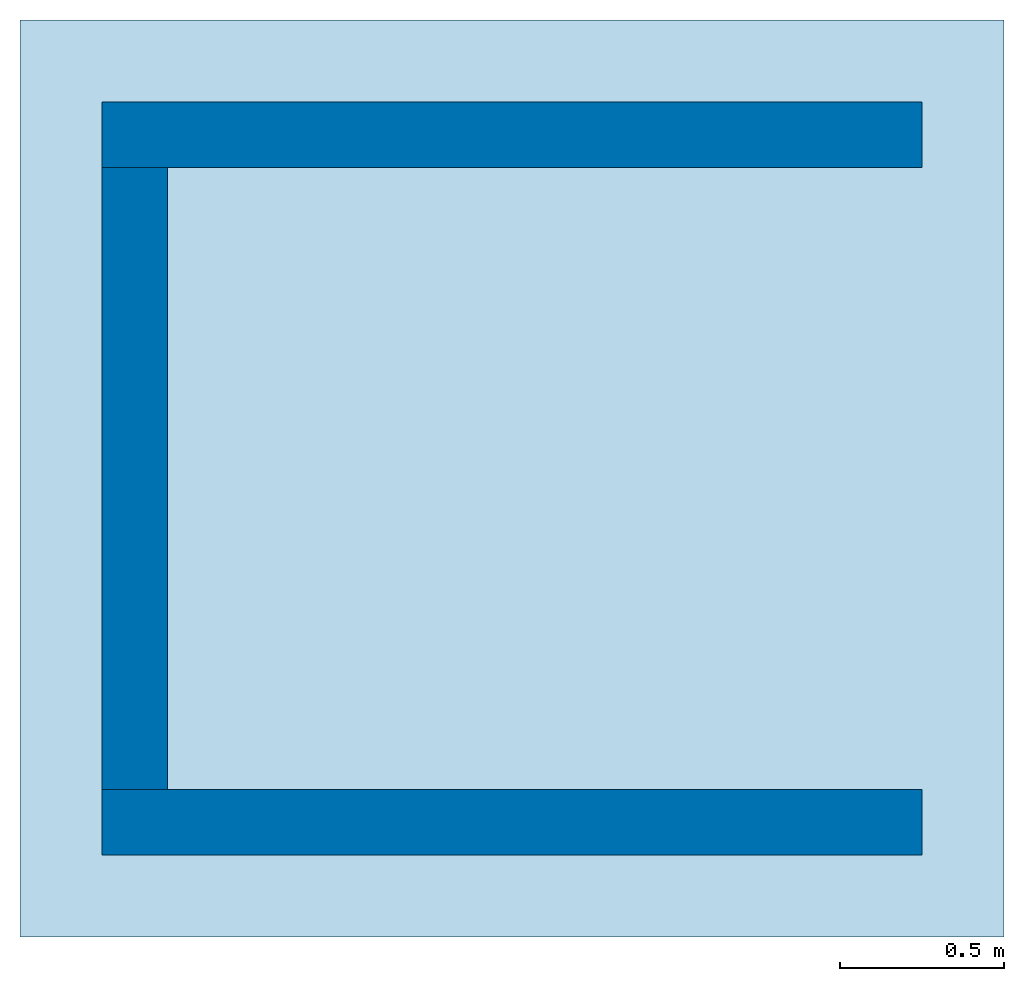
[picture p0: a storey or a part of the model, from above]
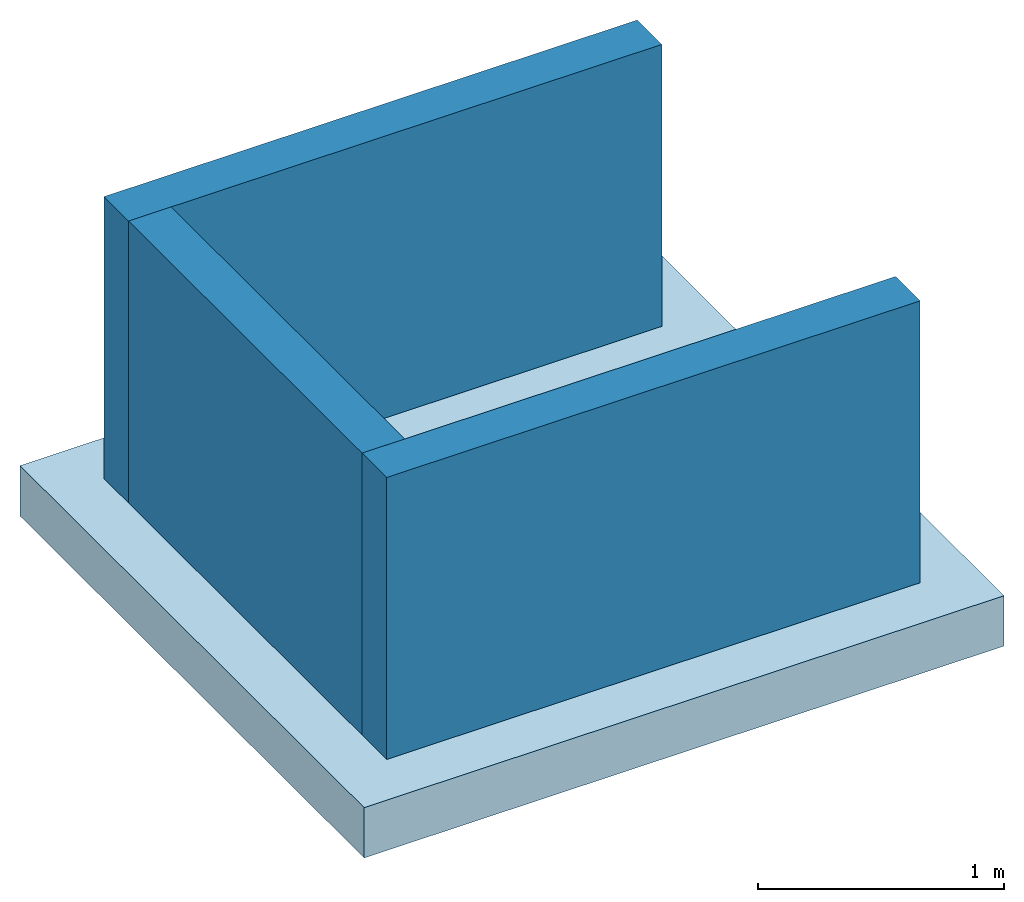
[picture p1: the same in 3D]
Properties of the parts of a building model (IFC4X3_ADD2), part 24 of 28

# IfcWall: Basic Wall_BB_10.01.41#01_Gipskartonwand_MS100 _ 25.50.25_ 100 mm39, Basic Wall:BB_10.01.41#01_Gipskartonwand_MS100 / 25.50.25, 100 mm:13715365
In: 010
PredefinedType: PARTITIONING
Cpset_Wall - LevelOfAccuracy: in te vullen door Buildwise
IfcBuildingStorey - Base Offset: 2640; Top Offset: -460; Base Constraint: 010; Top Constraint: Up to level: 020
IfcClassificationReference - Keynote: 10.01.41#01; GVH_artnr 01: 10.01.41#01; GVH_artnr 02: geen waarde gevonden; GVH_artnr 03: geen waarde gevonden; GVH_artnr 04: geen waarde gevonden; GVH_artnr 05: geen waarde gevonden; GVH_artnr 06: geen waarde gevonden; TDS_link: .\05 As Builtdossier\2. Bouwkunde\2.1 Architectuur\2.1.10 wanden\TF A 10.01.41#1 A - lichte scheidingswand met gipsplaten.pdf
IfcElement - BB_Element_Lokaalnummer01: K.10.406
IfcRoot - Name: BB_10.01.41#01_Gipskartonwand_MS100 / 25.50.25, 100 mm
Qto_WallBaseQuantities - Length: 350; NetVolume: 0.015; Height: 500; Width: 100; GrossVolume: 0.015; GrossSideArea: 0.15; NetSideArea: 0.15
Pset_Condition - AssessmentCondition: Empty
Pset_EnvironmentalImpactIndicators - Reference: BB_10.01.41#01_Gipskartonwand_MS100 / 25.50.25, 100 mm; sets with these values: 2
Pset_WallCommon - Reference: BB_10.01.41#01_Gipskartonwand_MS100 / 25.50.25, 100 mm; FireRating: EI60; IsExternal: yes; LoadBearing: no; ExtendToStructure: no

# IfcWall: Basic Wall_BB_10.01.41#01_Gipskartonwand_MS100 _ 25.50.25_ 100 mm41, Basic Wall:BB_10.01.41#01_Gipskartonwand_MS100 / 25.50.25, 100 mm:13715444
In: 010
PredefinedType: PARTITIONING
Cpset_Wall - LevelOfAccuracy: in te vullen door Buildwise
IfcBuildingStorey - Base Offset: 2640; Top Offset: -460; Base Constraint: 010; Top Constraint: Up to level: 020
IfcClassificationReference - Keynote: 10.01.41#01; GVH_artnr 01: 10.01.41#01; GVH_artnr 02: geen waarde gevonden; GVH_artnr 03: geen waarde gevonden; GVH_artnr 04: geen waarde gevonden; GVH_artnr 05: geen waarde gevonden; GVH_artnr 06: geen waarde gevonden; TDS_link: .\05 As Builtdossier\2. Bouwkunde\2.1 Architectuur\2.1.10 wanden\TF A 10.01.41#1 A - lichte scheidingswand met gipsplaten.pdf
IfcElement - BB_Element_Lokaalnummer01: K.10.511
IfcRoot - Name: BB_10.01.41#01_Gipskartonwand_MS100 / 25.50.25, 100 mm
Qto_WallBaseQuantities - Length: 5080; NetVolume: 0.2515; Height: 500; Width: 100; GrossVolume: 0.2515; GrossSideArea: 2.515; NetSideArea: 2.515
Pset_Condition - AssessmentCondition: Empty
Pset_EnvironmentalImpactIndicators - Reference: BB_10.01.41#01_Gipskartonwand_MS100 / 25.50.25, 100 mm; sets with these values: 2
Pset_WallCommon - Reference: BB_10.01.41#01_Gipskartonwand_MS100 / 25.50.25, 100 mm; FireRating: EI60; IsExternal: yes; LoadBearing: no; ExtendToStructure: no

# IfcWall: Basic Wall_BB_10.01.41#01_Gipskartonwand_MS100 _ 25.50.25_ 100 mm43, Basic Wall:BB_10.01.41#01_Gipskartonwand_MS100 / 25.50.25, 100 mm:13715913
In: 010
PredefinedType: PARTITIONING
Cpset_Wall - LevelOfAccuracy: in te vullen door Buildwise
IfcBuildingStorey - Base Offset: 2652.5; Top Offset: -460; Base Constraint: 010; Top Constraint: Up to level: 020
IfcClassificationReference - Keynote: 10.01.41#01; GVH_artnr 01: 10.01.41#01; GVH_artnr 02: geen waarde gevonden; GVH_artnr 03: geen waarde gevonden; GVH_artnr 04: geen waarde gevonden; GVH_artnr 05: geen waarde gevonden; GVH_artnr 06: geen waarde gevonden; TDS_link: .\05 As Builtdossier\2. Bouwkunde\2.1 Architectuur\2.1.10 wanden\TF A 10.01.41#1 A - lichte scheidingswand met gipsplaten.pdf
IfcElement - BB_Element_Lokaalnummer01: K.10.G17
IfcRoot - Name: BB_10.01.41#01_Gipskartonwand_MS100 / 25.50.25, 100 mm
Qto_WallBaseQuantities - Length: 1750; NetVolume: 0.0787; Height: 487.5; Width: 100; GrossVolume: 0.0787; GrossSideArea: 0.787; NetSideArea: 0.787
Pset_Condition - AssessmentCondition: Empty
Pset_EnvironmentalImpactIndicators - Reference: BB_10.01.41#01_Gipskartonwand_MS100 / 25.50.25, 100 mm; sets with these values: 2
Pset_WallCommon - Reference: BB_10.01.41#01_Gipskartonwand_MS100 / 25.50.25, 100 mm; FireRating: EI60; IsExternal: yes; LoadBearing: no; ExtendToStructure: no

# IfcWall: Basic Wall_BB_10.01.41#01_Gipskartonwand_MS100 _ 25.50.25_ 100 mm45, Basic Wall:BB_10.01.41#01_Gipskartonwand_MS100 / 25.50.25, 100 mm:13717220
In: 010
PredefinedType: PARTITIONING
Cpset_Wall - LevelOfAccuracy: in te vullen door Buildwise
IfcBuildingStorey - Base Offset: 2640; Top Offset: -600; Base Constraint: 010; Top Constraint: Up to level: 020
IfcClassificationReference - Keynote: 10.01.41#01; GVH_artnr 01: 10.01.41#01; GVH_artnr 02: geen waarde gevonden; GVH_artnr 03: geen waarde gevonden; GVH_artnr 04: geen waarde gevonden; GVH_artnr 05: geen waarde gevonden; GVH_artnr 06: geen waarde gevonden; TDS_link: .\05 As Builtdossier\2. Bouwkunde\2.1 Architectuur\2.1.10 wanden\TF A 10.01.41#1 A - lichte scheidingswand met gipsplaten.pdf
IfcElement - BB_Element_Lokaalnummer01: K.20.502
IfcRoot - Name: BB_10.01.41#01_Gipskartonwand_MS100 / 25.50.25, 100 mm
Qto_WallBaseQuantities - Length: 13950; NetVolume: 0.4968; Height: 360; Width: 100; GrossVolume: 0.4968; GrossSideArea: 4.968; NetSideArea: 4.968
Pset_Condition - AssessmentCondition: Empty
Pset_EnvironmentalImpactIndicators - Reference: BB_10.01.41#01_Gipskartonwand_MS100 / 25.50.25, 100 mm; sets with these values: 2
Pset_WallCommon - Reference: BB_10.01.41#01_Gipskartonwand_MS100 / 25.50.25, 100 mm; FireRating: EI60; IsExternal: yes; LoadBearing: no; ExtendToStructure: no

# IfcWall: Basic Wall_BB_10.01.41#01_Gipskartonwand_MS100 _ 25.50.25_ 100 mm47, Basic Wall:BB_10.01.41#01_Gipskartonwand_MS100 / 25.50.25, 100 mm:13717410
In: 010
PredefinedType: PARTITIONING
Cpset_Wall - LevelOfAccuracy: in te vullen door Buildwise
IfcBuildingStorey - Base Offset: 2640; Top Offset: -600; Base Constraint: 010; Top Constraint: Up to level: 020
IfcClassificationReference - Keynote: 10.01.41#01; GVH_artnr 01: 10.01.41#01; GVH_artnr 02: geen waarde gevonden; GVH_artnr 03: geen waarde gevonden; GVH_artnr 04: geen waarde gevonden; GVH_artnr 05: geen waarde gevonden; GVH_artnr 06: geen waarde gevonden; TDS_link: .\05 As Builtdossier\2. Bouwkunde\2.1 Architectuur\2.1.10 wanden\TF A 10.01.41#1 A - lichte scheidingswand met gipsplaten.pdf
IfcElement - BB_Element_Lokaalnummer01: K.10.505
IfcRoot - Name: BB_10.01.41#01_Gipskartonwand_MS100 / 25.50.25, 100 mm
Qto_WallBaseQuantities - Length: 12600; NetVolume: 0.4482; Height: 360; Width: 100; GrossVolume: 0.4482; GrossSideArea: 4.482; NetSideArea: 4.482
Pset_Condition - AssessmentCondition: Empty
Pset_EnvironmentalImpactIndicators - Reference: BB_10.01.41#01_Gipskartonwand_MS100 / 25.50.25, 100 mm; sets with these values: 2
Pset_WallCommon - Reference: BB_10.01.41#01_Gipskartonwand_MS100 / 25.50.25, 100 mm; FireRating: EI60; IsExternal: yes; LoadBearing: no; ExtendToStructure: no

# IfcWall: Basic Wall_BB_10.01.41#01_Gipskartonwand_MS100 _ 25.50.25_ 100 mm49, Basic Wall:BB_10.01.41#01_Gipskartonwand_MS100 / 25.50.25, 100 mm:13717520
In: 010
PredefinedType: PARTITIONING
Cpset_Wall - LevelOfAccuracy: in te vullen door Buildwise
IfcBuildingStorey - Base Offset: 2640; Top Offset: -600; Base Constraint: 010; Top Constraint: Up to level: 020
IfcClassificationReference - Keynote: 10.01.41#01; GVH_artnr 01: 10.01.41#01; GVH_artnr 02: geen waarde gevonden; GVH_artnr 03: geen waarde gevonden; GVH_artnr 04: geen waarde gevonden; GVH_artnr 05: geen waarde gevonden; GVH_artnr 06: geen waarde gevonden; TDS_link: .\05 As Builtdossier\2. Bouwkunde\2.1 Architectuur\2.1.10 wanden\TF A 10.01.41#1 A - lichte scheidingswand met gipsplaten.pdf
IfcElement - BB_Element_Lokaalnummer01: K.10.112
IfcRoot - Name: BB_10.01.41#01_Gipskartonwand_MS100 / 25.50.25, 100 mm
Qto_WallBaseQuantities - Length: 13850; NetVolume: 0.4968; Height: 360; Width: 100; GrossVolume: 0.4968; GrossSideArea: 4.968; NetSideArea: 4.968
Pset_Condition - AssessmentCondition: Empty
Pset_EnvironmentalImpactIndicators - Reference: BB_10.01.41#01_Gipskartonwand_MS100 / 25.50.25, 100 mm; sets with these values: 2
Pset_WallCommon - Reference: BB_10.01.41#01_Gipskartonwand_MS100 / 25.50.25, 100 mm; FireRating: EI60; IsExternal: yes; LoadBearing: no; ExtendToStructure: no

# IfcWall: Basic Wall_BB_10.01.41#01_Gipskartonwand_MS100 _ 25.50.25_ 100 mm5, Basic Wall:BB_10.01.41#01_Gipskartonwand_MS100 / 25.50.25, 100 mm:16288317
In: 000
PredefinedType: PARTITIONING
Cpset_Wall - LevelOfAccuracy: in te vullen door Buildwise
IfcBuildingStorey - Base Offset: 2670; Top Offset: -460; Base Constraint: 000; Top Constraint: Up to level: 010
IfcClassificationReference - Keynote: 10.01.41#01; GVH_artnr 01: 10.01.41#01; GVH_artnr 02: geen waarde gevonden; GVH_artnr 03: geen waarde gevonden; GVH_artnr 04: geen waarde gevonden; GVH_artnr 05: geen waarde gevonden; GVH_artnr 06: geen waarde gevonden; TDS_link: .\05 As Builtdossier\2. Bouwkunde\2.1 Architectuur\2.1.10 wanden\TF A 10.01.41#1 A - lichte scheidingswand met gipsplaten.pdf
IfcElement - BB_Element_Lokaalnummer01: K.10.109
IfcRoot - Name: BB_10.01.41#01_Gipskartonwand_MS100 / 25.50.25, 100 mm
Qto_WallBaseQuantities - Length: 2230; NetVolume: 0.10387; Height: 470; Width: 100; GrossVolume: 0.10387; GrossSideArea: 1.0387; NetSideArea: 1.0387
Pset_Condition - AssessmentCondition: Empty
Pset_EnvironmentalImpactIndicators - Reference: BB_10.01.41#01_Gipskartonwand_MS100 / 25.50.25, 100 mm; sets with these values: 2
Pset_WallCommon - Reference: BB_10.01.41#01_Gipskartonwand_MS100 / 25.50.25, 100 mm; FireRating: EI60; IsExternal: yes; LoadBearing: no; ExtendToStructure: no

# IfcWall: Basic Wall_BB_10.01.41#01_Gipskartonwand_MS100 _ 25.50.25_ 100 mm51, Basic Wall:BB_10.01.41#01_Gipskartonwand_MS100 / 25.50.25, 100 mm:13717759
In: 010
PredefinedType: PARTITIONING
Cpset_Wall - LevelOfAccuracy: in te vullen door Buildwise
IfcBuildingStorey - Base Offset: 2640; Top Offset: -460; Base Constraint: 010; Top Constraint: Up to level: 020
IfcClassificationReference - Keynote: 10.01.41#01; GVH_artnr 01: 10.01.41#01; GVH_artnr 02: geen waarde gevonden; GVH_artnr 03: geen waarde gevonden; GVH_artnr 04: geen waarde gevonden; GVH_artnr 05: geen waarde gevonden; GVH_artnr 06: geen waarde gevonden; TDS_link: .\05 As Builtdossier\2. Bouwkunde\2.1 Architectuur\2.1.10 wanden\TF A 10.01.41#1 A - lichte scheidingswand met gipsplaten.pdf
IfcElement - BB_Element_Lokaalnummer01: K.10.107
IfcRoot - Name: BB_10.01.41#01_Gipskartonwand_MS100 / 25.50.25, 100 mm
Qto_WallBaseQuantities - Length: 28550; NetVolume: 1.22822; Height: 500; Width: 100; GrossVolume: 1.22822; GrossSideArea: 12.2822; NetSideArea: 12.2822
Pset_Condition - AssessmentCondition: Empty
Pset_EnvironmentalImpactIndicators - Reference: BB_10.01.41#01_Gipskartonwand_MS100 / 25.50.25, 100 mm; sets with these values: 2
Pset_WallCommon - Reference: BB_10.01.41#01_Gipskartonwand_MS100 / 25.50.25, 100 mm; FireRating: EI60; IsExternal: yes; LoadBearing: no; ExtendToStructure: no

# IfcWall: Basic Wall_BB_10.01.41#01_Gipskartonwand_MS100 _ 25.50.25_ 100 mm53, Basic Wall:BB_10.01.41#01_Gipskartonwand_MS100 / 25.50.25, 100 mm:13717993
In: 010
PredefinedType: PARTITIONING
Cpset_Wall - LevelOfAccuracy: in te vullen door Buildwise
IfcBuildingStorey - Base Offset: 2640; Top Offset: -600; Base Constraint: 010; Top Constraint: Up to level: 020
IfcClassificationReference - Keynote: 10.01.41#01; GVH_artnr 01: 10.01.41#01; GVH_artnr 02: geen waarde gevonden; GVH_artnr 03: geen waarde gevonden; GVH_artnr 04: geen waarde gevonden; GVH_artnr 05: geen waarde gevonden; GVH_artnr 06: geen waarde gevonden; TDS_link: .\05 As Builtdossier\2. Bouwkunde\2.1 Architectuur\2.1.10 wanden\TF A 10.01.41#1 A - lichte scheidingswand met gipsplaten.pdf
IfcElement - BB_Element_Lokaalnummer01: K.10.104
IfcRoot - Name: BB_10.01.41#01_Gipskartonwand_MS100 / 25.50.25, 100 mm
Qto_WallBaseQuantities - Length: 350; NetVolume: 0.0108; Height: 360; Width: 100; GrossVolume: 0.0108; GrossSideArea: 0.108; NetSideArea: 0.108
Pset_Condition - AssessmentCondition: Empty
Pset_EnvironmentalImpactIndicators - Reference: BB_10.01.41#01_Gipskartonwand_MS100 / 25.50.25, 100 mm; sets with these values: 2
Pset_WallCommon - Reference: BB_10.01.41#01_Gipskartonwand_MS100 / 25.50.25, 100 mm; FireRating: EI60; IsExternal: yes; LoadBearing: no; ExtendToStructure: no

# IfcWall: Basic Wall_BB_10.01.41#01_Gipskartonwand_MS100 _ 25.50.25_ 100 mm55, Basic Wall:BB_10.01.41#01_Gipskartonwand_MS100 / 25.50.25, 100 mm:13718056
In: 010
PredefinedType: PARTITIONING
Cpset_Wall - LevelOfAccuracy: in te vullen door Buildwise
IfcBuildingStorey - Base Offset: 2700; Top Offset: -500; Base Constraint: 010; Top Constraint: Up to level: 020
IfcClassificationReference - Keynote: 10.01.41#01; GVH_artnr 01: 10.01.41#01; GVH_artnr 02: geen waarde gevonden; GVH_artnr 03: geen waarde gevonden; GVH_artnr 04: geen waarde gevonden; GVH_artnr 05: geen waarde gevonden; GVH_artnr 06: geen waarde gevonden; TDS_link: .\05 As Builtdossier\2. Bouwkunde\2.1 Architectuur\2.1.10 wanden\TF A 10.01.41#1 A - lichte scheidingswand met gipsplaten.pdf
IfcElement - BB_Element_Lokaalnummer01: K.10.106
IfcRoot - Name: BB_10.01.41#01_Gipskartonwand_MS100 / 25.50.25, 100 mm
Qto_WallBaseQuantities - Length: 5092.5; NetVolume: 0.2012; Height: 400; Width: 100; GrossVolume: 0.2012; GrossSideArea: 2.012; NetSideArea: 2.012
Pset_Condition - AssessmentCondition: Empty
Pset_EnvironmentalImpactIndicators - Reference: BB_10.01.41#01_Gipskartonwand_MS100 / 25.50.25, 100 mm; sets with these values: 2
Pset_WallCommon - Reference: BB_10.01.41#01_Gipskartonwand_MS100 / 25.50.25, 100 mm; FireRating: EI60; IsExternal: yes; LoadBearing: no; ExtendToStructure: no

# IfcWall: Basic Wall_BB_10.01.41#01_Gipskartonwand_MS100 _ 25.50.25_ 100 mm57, Basic Wall:BB_10.01.41#01_Gipskartonwand_MS100 / 25.50.25, 100 mm:13718172
In: 010
PredefinedType: PARTITIONING
Cpset_Wall - LevelOfAccuracy: in te vullen door Buildwise
IfcBuildingStorey - Base Offset: 2640; Top Offset: -600; Base Constraint: 010; Top Constraint: Up to level: 020
IfcClassificationReference - Keynote: 10.01.41#01; GVH_artnr 01: 10.01.41#01; GVH_artnr 02: geen waarde gevonden; GVH_artnr 03: geen waarde gevonden; GVH_artnr 04: geen waarde gevonden; GVH_artnr 05: geen waarde gevonden; GVH_artnr 06: geen waarde gevonden; TDS_link: .\05 As Builtdossier\2. Bouwkunde\2.1 Architectuur\2.1.10 wanden\TF A 10.01.41#1 A - lichte scheidingswand met gipsplaten.pdf
IfcElement - BB_Element_Lokaalnummer01: K.10.201
IfcRoot - Name: BB_10.01.41#01_Gipskartonwand_MS100 / 25.50.25, 100 mm
Qto_WallBaseQuantities - Length: 17922.5; NetVolume: 0.64116; Height: 360; Width: 100; GrossVolume: 0.64116; GrossSideArea: 6.4116; NetSideArea: 6.4116
Pset_Condition - AssessmentCondition: Empty
Pset_EnvironmentalImpactIndicators - Reference: BB_10.01.41#01_Gipskartonwand_MS100 / 25.50.25, 100 mm; sets with these values: 2
Pset_WallCommon - Reference: BB_10.01.41#01_Gipskartonwand_MS100 / 25.50.25, 100 mm; FireRating: EI60; IsExternal: yes; LoadBearing: no; ExtendToStructure: no

# IfcWall: Basic Wall_BB_10.01.41#01_Gipskartonwand_MS100 _ 25.50.25_ 100 mm59, Basic Wall:BB_10.01.41#01_Gipskartonwand_MS100 / 25.50.25, 100 mm:13718438
In: 010
PredefinedType: PARTITIONING
Cpset_Wall - LevelOfAccuracy: in te vullen door Buildwise
IfcBuildingStorey - Base Offset: 2640; Top Offset: -460; Base Constraint: 010; Top Constraint: Up to level: 020
IfcClassificationReference - Keynote: 10.01.41#01; GVH_artnr 01: 10.01.41#01; GVH_artnr 02: geen waarde gevonden; GVH_artnr 03: geen waarde gevonden; GVH_artnr 04: geen waarde gevonden; GVH_artnr 05: geen waarde gevonden; GVH_artnr 06: geen waarde gevonden; TDS_link: .\05 As Builtdossier\2. Bouwkunde\2.1 Architectuur\2.1.10 wanden\TF A 10.01.41#1 A - lichte scheidingswand met gipsplaten.pdf
IfcElement - BB_Element_Lokaalnummer01: K.10.108
IfcRoot - Name: BB_10.01.41#01_Gipskartonwand_MS100 / 25.50.25, 100 mm
Qto_WallBaseQuantities - Length: 25172.5; NetVolume: 1.00616; Height: 500; Width: 100; GrossVolume: 1.00616; GrossSideArea: 10.0616; NetSideArea: 10.0616
Pset_Condition - AssessmentCondition: Empty
Pset_EnvironmentalImpactIndicators - Reference: BB_10.01.41#01_Gipskartonwand_MS100 / 25.50.25, 100 mm; sets with these values: 2
Pset_WallCommon - Reference: BB_10.01.41#01_Gipskartonwand_MS100 / 25.50.25, 100 mm; FireRating: EI60; IsExternal: yes; LoadBearing: no; ExtendToStructure: no

# IfcWall: Basic Wall_BB_10.01.41#01_Gipskartonwand_MS100 _ 25.50.25_ 100 mm61, Basic Wall:BB_10.01.41#01_Gipskartonwand_MS100 / 25.50.25, 100 mm:13721011
In: 010
PredefinedType: PARTITIONING
Cpset_Wall - LevelOfAccuracy: in te vullen door Buildwise
IfcBuildingStorey - Base Offset: 2640; Top Offset: -460; Base Constraint: 010; Top Constraint: Up to level: 020
IfcClassificationReference - Keynote: 10.01.41#01; GVH_artnr 01: 10.01.41#01; GVH_artnr 02: geen waarde gevonden; GVH_artnr 03: geen waarde gevonden; GVH_artnr 04: geen waarde gevonden; GVH_artnr 05: geen waarde gevonden; GVH_artnr 06: geen waarde gevonden; TDS_link: .\05 As Builtdossier\2. Bouwkunde\2.1 Architectuur\2.1.10 wanden\TF A 10.01.41#1 A - lichte scheidingswand met gipsplaten.pdf
IfcElement - BB_Element_Lokaalnummer01: K.10.109
IfcRoot - Name: BB_10.01.41#01_Gipskartonwand_MS100 / 25.50.25, 100 mm
Qto_WallBaseQuantities - Length: 350; NetVolume: 0.015; Height: 500; Width: 100; GrossVolume: 0.015; GrossSideArea: 0.15; NetSideArea: 0.15
Pset_Condition - AssessmentCondition: Empty
Pset_EnvironmentalImpactIndicators - Reference: BB_10.01.41#01_Gipskartonwand_MS100 / 25.50.25, 100 mm; sets with these values: 2
Pset_WallCommon - Reference: BB_10.01.41#01_Gipskartonwand_MS100 / 25.50.25, 100 mm; FireRating: EI60; IsExternal: yes; LoadBearing: no; ExtendToStructure: no

# IfcWall: Basic Wall_BB_10.01.41#01_Gipskartonwand_MS100 _ 25.50.25_ 100 mm63, Basic Wall:BB_10.01.41#01_Gipskartonwand_MS100 / 25.50.25, 100 mm:13721048
In: 010
PredefinedType: PARTITIONING
Cpset_Wall - LevelOfAccuracy: in te vullen door Buildwise
IfcBuildingStorey - Base Offset: 2640; Top Offset: -600; Base Constraint: 010; Top Constraint: Up to level: 020
IfcClassificationReference - Keynote: 10.01.41#01; GVH_artnr 01: 10.01.41#01; GVH_artnr 02: geen waarde gevonden; GVH_artnr 03: geen waarde gevonden; GVH_artnr 04: geen waarde gevonden; GVH_artnr 05: geen waarde gevonden; GVH_artnr 06: geen waarde gevonden; TDS_link: .\05 As Builtdossier\2. Bouwkunde\2.1 Architectuur\2.1.10 wanden\TF A 10.01.41#1 A - lichte scheidingswand met gipsplaten.pdf
IfcElement - BB_Element_Lokaalnummer01: K.20.204
IfcRoot - Name: BB_10.01.41#01_Gipskartonwand_MS100 / 25.50.25, 100 mm
Qto_WallBaseQuantities - Length: 5080; NetVolume: 0.18108; Height: 360; Width: 100; GrossVolume: 0.18108; GrossSideArea: 1.8108; NetSideArea: 1.8108
Pset_Condition - AssessmentCondition: Empty
Pset_EnvironmentalImpactIndicators - Reference: BB_10.01.41#01_Gipskartonwand_MS100 / 25.50.25, 100 mm; sets with these values: 2
Pset_WallCommon - Reference: BB_10.01.41#01_Gipskartonwand_MS100 / 25.50.25, 100 mm; FireRating: EI60; IsExternal: yes; LoadBearing: no; ExtendToStructure: no

# IfcWall: Basic Wall_BB_10.01.41#01_Gipskartonwand_MS100 _ 25.50.25_ 100 mm65, Basic Wall:BB_10.01.41#01_Gipskartonwand_MS100 / 25.50.25, 100 mm:16200983
In: 010
PredefinedType: PARTITIONING
Cpset_Wall - LevelOfAccuracy: in te vullen door Buildwise
IfcBuildingStorey - Base Offset: 2640; Top Offset: -460; Base Constraint: 010; Top Constraint: Up to level: 020
IfcClassificationReference - Keynote: 10.01.41#01; GVH_artnr 01: 10.01.41#01; GVH_artnr 02: geen waarde gevonden; GVH_artnr 03: geen waarde gevonden; GVH_artnr 04: geen waarde gevonden; GVH_artnr 05: geen waarde gevonden; GVH_artnr 06: geen waarde gevonden; TDS_link: .\05 As Builtdossier\2. Bouwkunde\2.1 Architectuur\2.1.10 wanden\TF A 10.01.41#1 A - lichte scheidingswand met gipsplaten.pdf
IfcElement - BB_Element_Lokaalnummer01: K.20.112
IfcRoot - Name: BB_10.01.41#01_Gipskartonwand_MS100 / 25.50.25, 100 mm
Qto_WallBaseQuantities - Length: 1642.5; NetVolume: 0.07925; Height: 500; Width: 100; GrossVolume: 0.07925; GrossSideArea: 0.7925; NetSideArea: 0.7925
Pset_Condition - AssessmentCondition: Empty
Pset_EnvironmentalImpactIndicators - Reference: BB_10.01.41#01_Gipskartonwand_MS100 / 25.50.25, 100 mm; sets with these values: 2
Pset_WallCommon - Reference: BB_10.01.41#01_Gipskartonwand_MS100 / 25.50.25, 100 mm; FireRating: EI60; IsExternal: yes; LoadBearing: no; ExtendToStructure: no

# IfcWall: Basic Wall_BB_10.01.41#01_Gipskartonwand_MS100 _ 25.50.25_ 100 mm67, Basic Wall:BB_10.01.41#01_Gipskartonwand_MS100 / 25.50.25, 100 mm:16291628
In: 010
PredefinedType: PARTITIONING
Cpset_Wall - LevelOfAccuracy: in te vullen door Buildwise
IfcBuildingStorey - Base Offset: 2640; Top Offset: -600; Base Constraint: 010; Top Constraint: Up to level: 020
IfcClassificationReference - Keynote: 10.01.41#01; GVH_artnr 01: 10.01.41#01; GVH_artnr 02: geen waarde gevonden; GVH_artnr 03: geen waarde gevonden; GVH_artnr 04: geen waarde gevonden; GVH_artnr 05: geen waarde gevonden; GVH_artnr 06: geen waarde gevonden; TDS_link: .\05 As Builtdossier\2. Bouwkunde\2.1 Architectuur\2.1.10 wanden\TF A 10.01.41#1 A - lichte scheidingswand met gipsplaten.pdf
IfcElement - BB_Element_Lokaalnummer01: K.10.403
IfcRoot - Name: BB_10.01.41#01_Gipskartonwand_MS100 / 25.50.25, 100 mm
Qto_WallBaseQuantities - Length: 5242.5; NetVolume: 0.18108; Height: 360; Width: 100; GrossVolume: 0.18108; GrossSideArea: 1.8108; NetSideArea: 1.8108
Pset_Condition - AssessmentCondition: Empty
Pset_EnvironmentalImpactIndicators - Reference: BB_10.01.41#01_Gipskartonwand_MS100 / 25.50.25, 100 mm; sets with these values: 2
Pset_WallCommon - Reference: BB_10.01.41#01_Gipskartonwand_MS100 / 25.50.25, 100 mm; FireRating: EI60; IsExternal: yes; LoadBearing: no; ExtendToStructure: no

# IfcWall: Basic Wall_BB_10.01.41#01_Gipskartonwand_MS100 _ 25.50.25_ 100 mm69, Basic Wall:BB_10.01.41#01_Gipskartonwand_MS100 / 25.50.25, 100 mm:16292775
In: 010
PredefinedType: PARTITIONING
Cpset_Wall - LevelOfAccuracy: in te vullen door Buildwise
IfcBuildingStorey - Base Offset: 2640; Top Offset: -600; Base Constraint: 010; Top Constraint: Up to level: 020
IfcClassificationReference - Keynote: 10.01.41#01; GVH_artnr 01: 10.01.41#01; GVH_artnr 02: geen waarde gevonden; GVH_artnr 03: geen waarde gevonden; GVH_artnr 04: geen waarde gevonden; GVH_artnr 05: geen waarde gevonden; GVH_artnr 06: geen waarde gevonden; TDS_link: .\05 As Builtdossier\2. Bouwkunde\2.1 Architectuur\2.1.10 wanden\TF A 10.01.41#1 A - lichte scheidingswand met gipsplaten.pdf
IfcElement - BB_Element_Lokaalnummer01: K.10.206
IfcRoot - Name: BB_10.01.41#01_Gipskartonwand_MS100 / 25.50.25, 100 mm
Qto_WallBaseQuantities - Length: 300; NetVolume: 0.0108; Height: 360; Width: 100; GrossVolume: 0.0108; GrossSideArea: 0.108; NetSideArea: 0.108
Pset_Condition - AssessmentCondition: Empty
Pset_EnvironmentalImpactIndicators - Reference: BB_10.01.41#01_Gipskartonwand_MS100 / 25.50.25, 100 mm; sets with these values: 2
Pset_WallCommon - Reference: BB_10.01.41#01_Gipskartonwand_MS100 / 25.50.25, 100 mm; FireRating: EI60; IsExternal: yes; LoadBearing: no; ExtendToStructure: no

# IfcWall: Basic Wall_BB_10.01.41#01_Gipskartonwand_MS100 _ 25.50.25_ 100 mm7, Basic Wall:BB_10.01.41#01_Gipskartonwand_MS100 / 25.50.25, 100 mm:16291366
In: 000
PredefinedType: PARTITIONING
Cpset_Wall - LevelOfAccuracy: in te vullen door Buildwise
IfcBuildingStorey - Base Offset: 2640; Top Offset: -500; Base Constraint: 000; Top Constraint: Up to level: 010
IfcClassificationReference - Keynote: 10.01.41#01; GVH_artnr 01: 10.01.41#01; GVH_artnr 02: geen waarde gevonden; GVH_artnr 03: geen waarde gevonden; GVH_artnr 04: geen waarde gevonden; GVH_artnr 05: geen waarde gevonden; GVH_artnr 06: geen waarde gevonden; TDS_link: .\05 As Builtdossier\2. Bouwkunde\2.1 Architectuur\2.1.10 wanden\TF A 10.01.41#1 A - lichte scheidingswand met gipsplaten.pdf
IfcElement - BB_Element_Lokaalnummer01: K.10.105
IfcRoot - Name: BB_10.01.41#01_Gipskartonwand_MS100 / 25.50.25, 100 mm
Qto_WallBaseQuantities - Length: 337.5; NetVolume: 0.01265; Height: 460; Width: 100; GrossVolume: 0.01265; GrossSideArea: 0.1265; NetSideArea: 0.1265
Pset_Condition - AssessmentCondition: Empty
Pset_EnvironmentalImpactIndicators - Reference: BB_10.01.41#01_Gipskartonwand_MS100 / 25.50.25, 100 mm; sets with these values: 2
Pset_WallCommon - Reference: BB_10.01.41#01_Gipskartonwand_MS100 / 25.50.25, 100 mm; FireRating: EI60; IsExternal: yes; LoadBearing: no; ExtendToStructure: no

# IfcWall: Basic Wall_BB_10.01.41#01_Gipskartonwand_MS100 _ 25.50.25_ 100 mm71, Basic Wall:BB_10.01.41#01_Gipskartonwand_MS100 / 25.50.25, 100 mm:16292862
In: 010
PredefinedType: PARTITIONING
Cpset_Wall - LevelOfAccuracy: in te vullen door Buildwise
IfcBuildingStorey - Base Offset: 2640; Top Offset: -600; Base Constraint: 010; Top Constraint: Up to level: 020
IfcClassificationReference - Keynote: 10.01.41#01; GVH_artnr 01: 10.01.41#01; GVH_artnr 02: geen waarde gevonden; GVH_artnr 03: geen waarde gevonden; GVH_artnr 04: geen waarde gevonden; GVH_artnr 05: geen waarde gevonden; GVH_artnr 06: geen waarde gevonden; TDS_link: .\05 As Builtdossier\2. Bouwkunde\2.1 Architectuur\2.1.10 wanden\TF A 10.01.41#1 A - lichte scheidingswand met gipsplaten.pdf
IfcElement - BB_Element_Lokaalnummer01: K.10.206
IfcRoot - Name: BB_10.01.41#01_Gipskartonwand_MS100 / 25.50.25, 100 mm
Qto_WallBaseQuantities - Length: 300; NetVolume: 0.0108; Height: 360; Width: 100; GrossVolume: 0.0108; GrossSideArea: 0.108; NetSideArea: 0.108
Pset_Condition - AssessmentCondition: Empty
Pset_EnvironmentalImpactIndicators - Reference: BB_10.01.41#01_Gipskartonwand_MS100 / 25.50.25, 100 mm; sets with these values: 2
Pset_WallCommon - Reference: BB_10.01.41#01_Gipskartonwand_MS100 / 25.50.25, 100 mm; FireRating: EI60; IsExternal: yes; LoadBearing: no; ExtendToStructure: no

# IfcWall: Basic Wall_BB_10.01.41#01_Gipskartonwand_MS100 _ 25.50.25_ 100 mm73, Basic Wall:BB_10.01.41#01_Gipskartonwand_MS100 / 25.50.25, 100 mm:26458666
In: 010
PredefinedType: PARTITIONING
Cpset_Wall - LevelOfAccuracy: in te vullen door Buildwise
IfcBuildingStorey - Base Offset: 2640; Top Offset: -460; Base Constraint: 010; Top Constraint: Up to level: 020
IfcClassificationReference - Keynote: 10.01.41#01; GVH_artnr 01: 10.01.41#01; GVH_artnr 02: geen waarde gevonden; GVH_artnr 03: geen waarde gevonden; GVH_artnr 04: geen waarde gevonden; GVH_artnr 05: geen waarde gevonden; GVH_artnr 06: geen waarde gevonden; TDS_link: .\05 As Builtdossier\2. Bouwkunde\2.1 Architectuur\2.1.10 wanden\TF A 10.01.41#1 A - lichte scheidingswand met gipsplaten.pdf
IfcElement - BB_Element_Lokaalnummer01: K.10.104
IfcRoot - Name: BB_10.01.41#01_Gipskartonwand_MS100 / 25.50.25, 100 mm
Qto_WallBaseQuantities - Length: 350; NetVolume: 0.015; Height: 500; Width: 100; GrossVolume: 0.015; GrossSideArea: 0.15; NetSideArea: 0.15
Pset_Condition - AssessmentCondition: Empty
Pset_EnvironmentalImpactIndicators - Reference: BB_10.01.41#01_Gipskartonwand_MS100 / 25.50.25, 100 mm; sets with these values: 2
Pset_WallCommon - Reference: BB_10.01.41#01_Gipskartonwand_MS100 / 25.50.25, 100 mm; FireRating: EI60; IsExternal: yes; LoadBearing: no; ExtendToStructure: no

# IfcWall: Basic Wall_BB_10.01.41#01_Gipskartonwand_MS100 _ 25.50.25_ 100 mm75, Basic Wall:BB_10.01.41#01_Gipskartonwand_MS100 / 25.50.25, 100 mm:12564595
In: 020
PredefinedType: PARTITIONING
Cpset_Wall - LevelOfAccuracy: in te vullen door Buildwise
IfcBuildingStorey - Base Offset: -200; Top Offset: -600; Base Constraint: 020; Top Constraint: Up to level: 030
IfcClassificationReference - Keynote: 10.01.41#01; GVH_artnr 01: 10.01.41#01; GVH_artnr 02: geen waarde gevonden; GVH_artnr 03: geen waarde gevonden; GVH_artnr 04: geen waarde gevonden; GVH_artnr 05: geen waarde gevonden; GVH_artnr 06: geen waarde gevonden; TDS_link: .\05 As Builtdossier\2. Bouwkunde\2.1 Architectuur\2.1.10 wanden\TF A 10.01.41#1 A - lichte scheidingswand met gipsplaten.pdf
IfcElement - BB_Element_Lokaalnummer01: K.20.301
IfcRoot - Name: BB_10.01.41#01_Gipskartonwand_MS100 / 25.50.25, 100 mm
Qto_WallBaseQuantities - Length: 280; NetVolume: 0.1056; Height: 3200; Width: 100; GrossVolume: 0.1056; GrossSideArea: 1.056; NetSideArea: 1.056
Pset_Condition - AssessmentCondition: Empty
Pset_EnvironmentalImpactIndicators - Reference: BB_10.01.41#01_Gipskartonwand_MS100 / 25.50.25, 100 mm; sets with these values: 2
Pset_WallCommon - Reference: BB_10.01.41#01_Gipskartonwand_MS100 / 25.50.25, 100 mm; FireRating: EI60; IsExternal: yes; LoadBearing: no; ExtendToStructure: no

# IfcWall: Basic Wall_BB_10.01.41#01_Gipskartonwand_MS100 _ 25.50.25_ 100 mm77, Basic Wall:BB_10.01.41#01_Gipskartonwand_MS100 / 25.50.25, 100 mm:12564638
In: 020
PredefinedType: PARTITIONING
Cpset_Wall - LevelOfAccuracy: in te vullen door Buildwise
IfcBuildingStorey - Base Offset: -200; Top Offset: -600; Base Constraint: 020; Top Constraint: Up to level: 030
IfcClassificationReference - Keynote: 10.01.41#01; GVH_artnr 01: 10.01.41#01; GVH_artnr 02: geen waarde gevonden; GVH_artnr 03: geen waarde gevonden; GVH_artnr 04: geen waarde gevonden; GVH_artnr 05: geen waarde gevonden; GVH_artnr 06: geen waarde gevonden; TDS_link: .\05 As Builtdossier\2. Bouwkunde\2.1 Architectuur\2.1.10 wanden\TF A 10.01.41#1 A - lichte scheidingswand met gipsplaten.pdf
IfcElement - BB_Element_Lokaalnummer01: K.20.301
IfcRoot - Name: BB_10.01.41#01_Gipskartonwand_MS100 / 25.50.25, 100 mm
Qto_WallBaseQuantities - Length: 485; NetVolume: 0.1392; Height: 3200; Width: 100; GrossVolume: 0.1392; GrossSideArea: 1.392; NetSideArea: 1.392
Pset_Condition - AssessmentCondition: Empty
Pset_EnvironmentalImpactIndicators - Reference: BB_10.01.41#01_Gipskartonwand_MS100 / 25.50.25, 100 mm; sets with these values: 2
Pset_WallCommon - Reference: BB_10.01.41#01_Gipskartonwand_MS100 / 25.50.25, 100 mm; FireRating: EI60; IsExternal: yes; LoadBearing: no; ExtendToStructure: no

# IfcWall: Basic Wall_BB_10.01.41#01_Gipskartonwand_MS100 _ 25.50.25_ 100 mm79, Basic Wall:BB_10.01.41#01_Gipskartonwand_MS100 / 25.50.25, 100 mm:12566018
In: 020
PredefinedType: PARTITIONING
Cpset_Wall - LevelOfAccuracy: in te vullen door Buildwise
IfcBuildingStorey - Base Offset: -5; Top Offset: 3140; Base Constraint: 020; Top Constraint: Up to level: 020
IfcClassificationReference - Keynote: 10.01.41#01; GVH_artnr 01: 10.01.41#01; GVH_artnr 02: geen waarde gevonden; GVH_artnr 03: geen waarde gevonden; GVH_artnr 04: geen waarde gevonden; GVH_artnr 05: geen waarde gevonden; GVH_artnr 06: geen waarde gevonden; TDS_link: .\05 As Builtdossier\2. Bouwkunde\2.1 Architectuur\2.1.10 wanden\TF A 10.01.41#1 A - lichte scheidingswand met gipsplaten.pdf
IfcElement - BB_Element_Lokaalnummer01: K.20.408
IfcRoot - Name: BB_10.01.41#01_Gipskartonwand_MS100 / 25.50.25, 100 mm
Qto_WallBaseQuantities - Length: 1185; NetVolume: 0.195723; Height: 3145; Width: 100; GrossVolume: 0.195722; GrossSideArea: 1.95722; NetSideArea: 1.95722
Pset_Condition - AssessmentCondition: Empty
Pset_EnvironmentalImpactIndicators - Reference: BB_10.01.41#01_Gipskartonwand_MS100 / 25.50.25, 100 mm; sets with these values: 2
Pset_WallCommon - Reference: BB_10.01.41#01_Gipskartonwand_MS100 / 25.50.25, 100 mm; FireRating: EI60; IsExternal: yes; LoadBearing: no; ExtendToStructure: no

# IfcWall: Basic Wall_BB_10.01.41#01_Gipskartonwand_MS100 _ 25.50.25_ 100 mm81, Basic Wall:BB_10.01.41#01_Gipskartonwand_MS100 / 25.50.25, 100 mm:12566019
In: 020
PredefinedType: PARTITIONING
Cpset_Wall - LevelOfAccuracy: in te vullen door Buildwise
IfcBuildingStorey - Base Offset: -5; Top Offset: 2920; Base Constraint: 020; Top Constraint: Up to level: 020
IfcClassificationReference - Keynote: 10.01.41#01; GVH_artnr 01: 10.01.41#01; GVH_artnr 02: geen waarde gevonden; GVH_artnr 03: geen waarde gevonden; GVH_artnr 04: geen waarde gevonden; GVH_artnr 05: geen waarde gevonden; GVH_artnr 06: geen waarde gevonden; TDS_link: .\05 As Builtdossier\2. Bouwkunde\2.1 Architectuur\2.1.10 wanden\TF A 10.01.41#1 A - lichte scheidingswand met gipsplaten.pdf
IfcElement - BB_Element_Lokaalnummer01: K.20.408
IfcRoot - Name: BB_10.01.41#01_Gipskartonwand_MS100 / 25.50.25, 100 mm
Qto_WallBaseQuantities - Length: 4845; NetVolume: 1.39826; Height: 2925; Width: 100; GrossVolume: 1.39826; GrossSideArea: 13.9826; NetSideArea: 13.9826
Pset_Condition - AssessmentCondition: Empty
Pset_EnvironmentalImpactIndicators - Reference: BB_10.01.41#01_Gipskartonwand_MS100 / 25.50.25, 100 mm; sets with these values: 2
Pset_WallCommon - Reference: BB_10.01.41#01_Gipskartonwand_MS100 / 25.50.25, 100 mm; FireRating: EI60; IsExternal: yes; LoadBearing: no; ExtendToStructure: no

# IfcWall: Basic Wall_BB_10.01.41#01_Gipskartonwand_MS100 _ 25.50.25_ 100 mm83, Basic Wall:BB_10.01.41#01_Gipskartonwand_MS100 / 25.50.25, 100 mm:12948521
In: 020
PredefinedType: PARTITIONING
Cpset_Wall - LevelOfAccuracy: in te vullen door Buildwise
IfcBuildingStorey - Base Offset: 2640; Top Offset: -460; Base Constraint: 020; Top Constraint: Up to level: 030
IfcClassificationReference - Keynote: 10.01.41#01; GVH_artnr 01: 10.01.41#01; GVH_artnr 02: geen waarde gevonden; GVH_artnr 03: geen waarde gevonden; GVH_artnr 04: geen waarde gevonden; GVH_artnr 05: geen waarde gevonden; GVH_artnr 06: geen waarde gevonden; TDS_link: .\05 As Builtdossier\2. Bouwkunde\2.1 Architectuur\2.1.10 wanden\TF A 10.01.41#1 A - lichte scheidingswand met gipsplaten.pdf
IfcElement - BB_Element_Lokaalnummer01: K.20.114
IfcRoot - Name: BB_10.01.41#01_Gipskartonwand_MS100 / 25.50.25, 100 mm
Qto_WallBaseQuantities - Length: 33930; NetVolume: 1.4219; Height: 500; Width: 100; GrossVolume: 1.4219; GrossSideArea: 14.219; NetSideArea: 14.219
Pset_Condition - AssessmentCondition: Empty
Pset_EnvironmentalImpactIndicators - Reference: BB_10.01.41#01_Gipskartonwand_MS100 / 25.50.25, 100 mm; sets with these values: 2
Pset_WallCommon - Reference: BB_10.01.41#01_Gipskartonwand_MS100 / 25.50.25, 100 mm; FireRating: EI60; IsExternal: yes; LoadBearing: no; ExtendToStructure: no

# IfcWall: Basic Wall_BB_10.01.41#01_Gipskartonwand_MS100 _ 25.50.25_ 100 mm85, Basic Wall:BB_10.01.41#01_Gipskartonwand_MS100 / 25.50.25, 100 mm:12948852
In: 020
PredefinedType: PARTITIONING
Cpset_Wall - LevelOfAccuracy: in te vullen door Buildwise
IfcBuildingStorey - Base Offset: 2640; Top Offset: -460; Base Constraint: 020; Top Constraint: Up to level: 030
IfcClassificationReference - Keynote: 10.01.41#01; GVH_artnr 01: 10.01.41#01; GVH_artnr 02: geen waarde gevonden; GVH_artnr 03: geen waarde gevonden; GVH_artnr 04: geen waarde gevonden; GVH_artnr 05: geen waarde gevonden; GVH_artnr 06: geen waarde gevonden; TDS_link: .\05 As Builtdossier\2. Bouwkunde\2.1 Architectuur\2.1.10 wanden\TF A 10.01.41#1 A - lichte scheidingswand met gipsplaten.pdf
IfcElement - BB_Element_Lokaalnummer01: K.20.501
IfcRoot - Name: BB_10.01.41#01_Gipskartonwand_MS100 / 25.50.25, 100 mm
Qto_WallBaseQuantities - Length: 30990; NetVolume: 1.2474; Height: 500; Width: 100; GrossVolume: 1.2474; GrossSideArea: 12.474; NetSideArea: 12.474
Pset_Condition - AssessmentCondition: Empty
Pset_EnvironmentalImpactIndicators - Reference: BB_10.01.41#01_Gipskartonwand_MS100 / 25.50.25, 100 mm; sets with these values: 2
Pset_WallCommon - Reference: BB_10.01.41#01_Gipskartonwand_MS100 / 25.50.25, 100 mm; FireRating: EI60; IsExternal: yes; LoadBearing: no; ExtendToStructure: no

# IfcWall: Basic Wall_BB_10.01.41#01_Gipskartonwand_MS100 _ 25.50.25_ 100 mm87, Basic Wall:BB_10.01.41#01_Gipskartonwand_MS100 / 25.50.25, 100 mm:12948951
In: 020
PredefinedType: PARTITIONING
Cpset_Wall - LevelOfAccuracy: in te vullen door Buildwise
IfcBuildingStorey - Base Offset: 2640; Top Offset: -460; Base Constraint: 020; Top Constraint: Up to level: 030
IfcClassificationReference - Keynote: 10.01.41#01; GVH_artnr 01: 10.01.41#01; GVH_artnr 02: geen waarde gevonden; GVH_artnr 03: geen waarde gevonden; GVH_artnr 04: geen waarde gevonden; GVH_artnr 05: geen waarde gevonden; GVH_artnr 06: geen waarde gevonden; TDS_link: .\05 As Builtdossier\2. Bouwkunde\2.1 Architectuur\2.1.10 wanden\TF A 10.01.41#1 A - lichte scheidingswand met gipsplaten.pdf
IfcElement - BB_Element_Lokaalnummer01: K.20.402
IfcRoot - Name: BB_10.01.41#01_Gipskartonwand_MS100 / 25.50.25, 100 mm
Qto_WallBaseQuantities - Length: 22035; NetVolume: 0.89492; Height: 500; Width: 100; GrossVolume: 0.89492; GrossSideArea: 8.9492; NetSideArea: 8.9492
Pset_Condition - AssessmentCondition: Empty
Pset_EnvironmentalImpactIndicators - Reference: BB_10.01.41#01_Gipskartonwand_MS100 / 25.50.25, 100 mm; sets with these values: 2
Pset_WallCommon - Reference: BB_10.01.41#01_Gipskartonwand_MS100 / 25.50.25, 100 mm; FireRating: EI60; IsExternal: yes; LoadBearing: no; ExtendToStructure: no

# IfcWall: Basic Wall_BB_10.01.41#01_Gipskartonwand_MS100 _ 25.50.25_ 100 mm89, Basic Wall:BB_10.01.41#01_Gipskartonwand_MS100 / 25.50.25, 100 mm:13707549
In: 020
PredefinedType: PARTITIONING
Cpset_Wall - LevelOfAccuracy: in te vullen door Buildwise
IfcBuildingStorey - Base Offset: 2640; Top Offset: -600; Base Constraint: 020; Top Constraint: Up to level: 030
IfcClassificationReference - Keynote: 10.01.41#01; GVH_artnr 01: 10.01.41#01; GVH_artnr 02: geen waarde gevonden; GVH_artnr 03: geen waarde gevonden; GVH_artnr 04: geen waarde gevonden; GVH_artnr 05: geen waarde gevonden; GVH_artnr 06: geen waarde gevonden; TDS_link: .\05 As Builtdossier\2. Bouwkunde\2.1 Architectuur\2.1.10 wanden\TF A 10.01.41#1 A - lichte scheidingswand met gipsplaten.pdf
IfcElement - BB_Element_Lokaalnummer01: K.20.402
IfcRoot - Name: BB_10.01.41#01_Gipskartonwand_MS100 / 25.50.25, 100 mm
Qto_WallBaseQuantities - Length: 5090; NetVolume: 0.18144; Height: 360; Width: 100; GrossVolume: 0.18144; GrossSideArea: 1.8144; NetSideArea: 1.8144
Pset_Condition - AssessmentCondition: Empty
Pset_EnvironmentalImpactIndicators - Reference: BB_10.01.41#01_Gipskartonwand_MS100 / 25.50.25, 100 mm; sets with these values: 2
Pset_WallCommon - Reference: BB_10.01.41#01_Gipskartonwand_MS100 / 25.50.25, 100 mm; FireRating: EI60; IsExternal: yes; LoadBearing: no; ExtendToStructure: no

# IfcWall: Basic Wall_BB_10.01.41#01_Gipskartonwand_MS100 _ 25.50.25_ 100 mm9, Basic Wall:BB_10.01.41#01_Gipskartonwand_MS100 / 25.50.25, 100 mm:25484917
In: 000
PredefinedType: PARTITIONING
Cpset_Wall - LevelOfAccuracy: in te vullen door Buildwise
IfcBuildingStorey - Base Offset: 0; Top Offset: -460; Base Constraint: 000; Top Constraint: Up to level: 010
IfcClassificationReference - Keynote: 10.01.41#01; GVH_artnr 01: 10.01.41#01; GVH_artnr 02: geen waarde gevonden; GVH_artnr 03: geen waarde gevonden; GVH_artnr 04: geen waarde gevonden; GVH_artnr 05: geen waarde gevonden; GVH_artnr 06: geen waarde gevonden; TDS_link: .\05 As Builtdossier\2. Bouwkunde\2.1 Architectuur\2.1.10 wanden\TF A 10.01.41#1 A - lichte scheidingswand met gipsplaten.pdf
IfcElement - BB_Element_Lokaalnummer01: K.00.401
IfcRoot - Name: BB_10.01.41#01_Gipskartonwand_MS100 / 25.50.25, 100 mm
Qto_WallBaseQuantities - Length: 2360; NetVolume: 0.326135; Height: 3140; Width: 100; GrossVolume: 0.326135; GrossSideArea: 3.26135; NetSideArea: 3.26135
Pset_Condition - AssessmentCondition: Empty
Pset_EnvironmentalImpactIndicators - Reference: BB_10.01.41#01_Gipskartonwand_MS100 / 25.50.25, 100 mm; sets with these values: 2
Pset_WallCommon - Reference: BB_10.01.41#01_Gipskartonwand_MS100 / 25.50.25, 100 mm; FireRating: EI60; IsExternal: yes; LoadBearing: no; ExtendToStructure: no

# IfcWall: Basic Wall_BB_10.01.41#01_Gipskartonwand_MS100 _ 25.50.25_ 100 mm91, Basic Wall:BB_10.01.41#01_Gipskartonwand_MS100 / 25.50.25, 100 mm:13709128
In: 020
PredefinedType: PARTITIONING
Cpset_Wall - LevelOfAccuracy: in te vullen door Buildwise
IfcBuildingStorey - Base Offset: 2640; Top Offset: -460; Base Constraint: 020; Top Constraint: Up to level: 030
IfcClassificationReference - Keynote: 10.01.41#01; GVH_artnr 01: 10.01.41#01; GVH_artnr 02: geen waarde gevonden; GVH_artnr 03: geen waarde gevonden; GVH_artnr 04: geen waarde gevonden; GVH_artnr 05: geen waarde gevonden; GVH_artnr 06: geen waarde gevonden; TDS_link: .\05 As Builtdossier\2. Bouwkunde\2.1 Architectuur\2.1.10 wanden\TF A 10.01.41#1 A - lichte scheidingswand met gipsplaten.pdf
IfcElement - BB_Element_Lokaalnummer01: K.20.509
IfcRoot - Name: BB_10.01.41#01_Gipskartonwand_MS100 / 25.50.25, 100 mm
Qto_WallBaseQuantities - Length: 5080; NetVolume: 0.2515; Height: 500; Width: 100; GrossVolume: 0.2515; GrossSideArea: 2.515; NetSideArea: 2.515
Pset_Condition - AssessmentCondition: Empty
Pset_EnvironmentalImpactIndicators - Reference: BB_10.01.41#01_Gipskartonwand_MS100 / 25.50.25, 100 mm; sets with these values: 2
Pset_WallCommon - Reference: BB_10.01.41#01_Gipskartonwand_MS100 / 25.50.25, 100 mm; FireRating: EI60; IsExternal: yes; LoadBearing: no; ExtendToStructure: no

# IfcWall: Basic Wall_BB_10.01.41#01_Gipskartonwand_MS100 _ 25.50.25_ 100 mm93, Basic Wall:BB_10.01.41#01_Gipskartonwand_MS100 / 25.50.25, 100 mm:13709159
In: 020
PredefinedType: PARTITIONING
Cpset_Wall - LevelOfAccuracy: in te vullen door Buildwise
IfcBuildingStorey - Base Offset: 2640; Top Offset: -460; Base Constraint: 020; Top Constraint: Up to level: 030
IfcClassificationReference - Keynote: 10.01.41#01; GVH_artnr 01: 10.01.41#01; GVH_artnr 02: geen waarde gevonden; GVH_artnr 03: geen waarde gevonden; GVH_artnr 04: geen waarde gevonden; GVH_artnr 05: geen waarde gevonden; GVH_artnr 06: geen waarde gevonden; TDS_link: .\05 As Builtdossier\2. Bouwkunde\2.1 Architectuur\2.1.10 wanden\TF A 10.01.41#1 A - lichte scheidingswand met gipsplaten.pdf
IfcElement - BB_Element_Lokaalnummer01: K.20.510
IfcRoot - Name: BB_10.01.41#01_Gipskartonwand_MS100 / 25.50.25, 100 mm
Qto_WallBaseQuantities - Length: 350; NetVolume: 0.015; Height: 500; Width: 100; GrossVolume: 0.015; GrossSideArea: 0.15; NetSideArea: 0.15
Pset_Condition - AssessmentCondition: Empty
Pset_EnvironmentalImpactIndicators - Reference: BB_10.01.41#01_Gipskartonwand_MS100 / 25.50.25, 100 mm; sets with these values: 2
Pset_WallCommon - Reference: BB_10.01.41#01_Gipskartonwand_MS100 / 25.50.25, 100 mm; FireRating: EI60; IsExternal: yes; LoadBearing: no; ExtendToStructure: no

# IfcWall: Basic Wall_BB_10.01.41#01_Gipskartonwand_MS100 _ 25.50.25_ 100 mm95, Basic Wall:BB_10.01.41#01_Gipskartonwand_MS100 / 25.50.25, 100 mm:13711121
In: 020
PredefinedType: PARTITIONING
Cpset_Wall - LevelOfAccuracy: in te vullen door Buildwise
IfcBuildingStorey - Base Offset: 2640; Top Offset: -600; Base Constraint: 020; Top Constraint: Up to level: 030
IfcClassificationReference - Keynote: 10.01.41#01; GVH_artnr 01: 10.01.41#01; GVH_artnr 02: geen waarde gevonden; GVH_artnr 03: geen waarde gevonden; GVH_artnr 04: geen waarde gevonden; GVH_artnr 05: geen waarde gevonden; GVH_artnr 06: geen waarde gevonden; TDS_link: .\05 As Builtdossier\2. Bouwkunde\2.1 Architectuur\2.1.10 wanden\TF A 10.01.41#1 A - lichte scheidingswand met gipsplaten.pdf
IfcElement - BB_Element_Lokaalnummer01: K.20.104
IfcRoot - Name: BB_10.01.41#01_Gipskartonwand_MS100 / 25.50.25, 100 mm
Qto_WallBaseQuantities - Length: 350; NetVolume: 0.0108; Height: 360; Width: 100; GrossVolume: 0.0108; GrossSideArea: 0.108; NetSideArea: 0.108
Pset_Condition - AssessmentCondition: Empty
Pset_EnvironmentalImpactIndicators - Reference: BB_10.01.41#01_Gipskartonwand_MS100 / 25.50.25, 100 mm; sets with these values: 2
Pset_WallCommon - Reference: BB_10.01.41#01_Gipskartonwand_MS100 / 25.50.25, 100 mm; FireRating: EI60; IsExternal: yes; LoadBearing: no; ExtendToStructure: no

# IfcWall: Basic Wall_BB_10.01.41#01_Gipskartonwand_MS100 _ 25.50.25_ 100 mm97, Basic Wall:BB_10.01.41#01_Gipskartonwand_MS100 / 25.50.25, 100 mm:13711248
In: 020
PredefinedType: PARTITIONING
Cpset_Wall - LevelOfAccuracy: in te vullen door Buildwise
IfcBuildingStorey - Base Offset: 2640; Top Offset: -600; Base Constraint: 020; Top Constraint: Up to level: 030
IfcClassificationReference - Keynote: 10.01.41#01; GVH_artnr 01: 10.01.41#01; GVH_artnr 02: geen waarde gevonden; GVH_artnr 03: geen waarde gevonden; GVH_artnr 04: geen waarde gevonden; GVH_artnr 05: geen waarde gevonden; GVH_artnr 06: geen waarde gevonden; TDS_link: .\05 As Builtdossier\2. Bouwkunde\2.1 Architectuur\2.1.10 wanden\TF A 10.01.41#1 A - lichte scheidingswand met gipsplaten.pdf
IfcElement - BB_Element_Lokaalnummer01: K.20.105
IfcRoot - Name: BB_10.01.41#01_Gipskartonwand_MS100 / 25.50.25, 100 mm
Qto_WallBaseQuantities - Length: 350; NetVolume: 0.0108; Height: 360; Width: 100; GrossVolume: 0.0108; GrossSideArea: 0.108; NetSideArea: 0.108
Pset_Condition - AssessmentCondition: Empty
Pset_EnvironmentalImpactIndicators - Reference: BB_10.01.41#01_Gipskartonwand_MS100 / 25.50.25, 100 mm; sets with these values: 2
Pset_WallCommon - Reference: BB_10.01.41#01_Gipskartonwand_MS100 / 25.50.25, 100 mm; FireRating: EI60; IsExternal: yes; LoadBearing: no; ExtendToStructure: no

# IfcWall: Basic Wall_BB_10.01.41#01_Gipskartonwand_MS100 _ 25.50.25_ 100 mm99, Basic Wall:BB_10.01.41#01_Gipskartonwand_MS100 / 25.50.25, 100 mm:13711351
In: 020
PredefinedType: PARTITIONING
Cpset_Wall - LevelOfAccuracy: in te vullen door Buildwise
IfcBuildingStorey - Base Offset: 2640; Top Offset: -600; Base Constraint: 020; Top Constraint: Up to level: 030
IfcClassificationReference - Keynote: 10.01.41#01; GVH_artnr 01: 10.01.41#01; GVH_artnr 02: geen waarde gevonden; GVH_artnr 03: geen waarde gevonden; GVH_artnr 04: geen waarde gevonden; GVH_artnr 05: geen waarde gevonden; GVH_artnr 06: geen waarde gevonden; TDS_link: .\05 As Builtdossier\2. Bouwkunde\2.1 Architectuur\2.1.10 wanden\TF A 10.01.41#1 A - lichte scheidingswand met gipsplaten.pdf
IfcElement - BB_Element_Lokaalnummer01: K.20.106
IfcRoot - Name: BB_10.01.41#01_Gipskartonwand_MS100 / 25.50.25, 100 mm
Qto_WallBaseQuantities - Length: 350; NetVolume: 0.0108; Height: 360; Width: 100; GrossVolume: 0.0108; GrossSideArea: 0.108; NetSideArea: 0.108
Pset_Condition - AssessmentCondition: Empty
Pset_EnvironmentalImpactIndicators - Reference: BB_10.01.41#01_Gipskartonwand_MS100 / 25.50.25, 100 mm; sets with these values: 2
Pset_WallCommon - Reference: BB_10.01.41#01_Gipskartonwand_MS100 / 25.50.25, 100 mm; FireRating: EI60; IsExternal: yes; LoadBearing: no; ExtendToStructure: no

# IfcWall: Basic Wall_BB_10.01.41#02_Gipskartonwand_Vochtbestendig_MS100 _ 25.50.25_ 100 mm, Basic Wall:BB_10.01.41#02_Gipskartonwand_Vochtbestendig_MS100 / 25.50.25, 100 mm:12550132
In: 030
PredefinedType: PARTITIONING
Cpset_Wall - LevelOfAccuracy: in te vullen door Buildwise
IfcBuildingStorey - Base Offset: -10; Top Offset: 3190; Base Constraint: 030; Top Constraint: Up to level: 030
IfcClassificationReference - Keynote: 10.01.41#02; GVH_artnr 01: 10.01.41#02; GVH_artnr 02: geen waarde gevonden; GVH_artnr 03: geen waarde gevonden; GVH_artnr 04: geen waarde gevonden; GVH_artnr 05: geen waarde gevonden; GVH_artnr 06: geen waarde gevonden; TDS_link: .\05 As Builtdossier\2. Bouwkunde\2.1 Architectuur\2.1.10 wanden\TF A 10.01.41#2 A - lichte scheidingswand met watervaste gipsplaten.pdf
IfcElement - BB_Element_Lokaalnummer01: K.30.S22
IfcRoot - Name: BB_10.01.41#02_Gipskartonwand_Vochtbestendig_MS100 / 25.50.25, 100 mm
Qto_WallBaseQuantities - Length: 2465; NetVolume: 0.55797; Height: 3200; Width: 100; GrossVolume: 0.55797; GrossSideArea: 5.5797; NetSideArea: 5.5797
Pset_Condition - AssessmentCondition: Empty
Pset_EnvironmentalImpactIndicators - Reference: BB_10.01.41#02_Gipskartonwand_Vochtbestendig_MS100 / 25.50.25, 100 mm; sets with these values: 2
Pset_WallCommon - Reference: BB_10.01.41#02_Gipskartonwand_Vochtbestendig_MS100 / 25.50.25, 100 mm; IsExternal: yes; LoadBearing: no; ExtendToStructure: no

# IfcWall: Basic Wall_BB_10.01.41#02_Gipskartonwand_Vochtbestendig_MS100 _ 25.50.25_ 100 mm1, Basic Wall:BB_10.01.41#02_Gipskartonwand_Vochtbestendig_MS100 / 25.50.25, 100 mm:12550293
In: 030
PredefinedType: PARTITIONING
Cpset_Wall - LevelOfAccuracy: in te vullen door Buildwise
IfcBuildingStorey - Base Offset: -80; Top Offset: 3190; Base Constraint: 030; Top Constraint: Up to level: 030
IfcClassificationReference - Keynote: 10.01.41#02; GVH_artnr 01: 10.01.41#02; GVH_artnr 02: geen waarde gevonden; GVH_artnr 03: geen waarde gevonden; GVH_artnr 04: geen waarde gevonden; GVH_artnr 05: geen waarde gevonden; GVH_artnr 06: geen waarde gevonden; TDS_link: .\05 As Builtdossier\2. Bouwkunde\2.1 Architectuur\2.1.10 wanden\TF A 10.01.41#2 A - lichte scheidingswand met watervaste gipsplaten.pdf
IfcElement - BB_Element_Lokaalnummer01: K.30.107
IfcRoot - Name: BB_10.01.41#02_Gipskartonwand_Vochtbestendig_MS100 / 25.50.25, 100 mm
Qto_WallBaseQuantities - Length: 4120; NetVolume: 1.13241; Height: 3270; Width: 100; GrossVolume: 1.34724; GrossSideArea: 13.4724; NetSideArea: 11.3241
Pset_Condition - AssessmentCondition: Empty
Pset_EnvironmentalImpactIndicators - Reference: BB_10.01.41#02_Gipskartonwand_Vochtbestendig_MS100 / 25.50.25, 100 mm; sets with these values: 2
Pset_WallCommon - Reference: BB_10.01.41#02_Gipskartonwand_Vochtbestendig_MS100 / 25.50.25, 100 mm; IsExternal: yes; LoadBearing: no; ExtendToStructure: no

# IfcWall: Basic Wall_BB_10.01.41#02_Gipskartonwand_Vochtbestendig_MS100 _ 25.50.25_ 100 mm11, Basic Wall:BB_10.01.41#02_Gipskartonwand_Vochtbestendig_MS100 / 25.50.25, 100 mm:32022451
In: 030
PredefinedType: PARTITIONING
Cpset_Wall - LevelOfAccuracy: in te vullen door Buildwise
IfcBuildingStorey - Base Offset: -10; Top Offset: 3190; Base Constraint: 030; Top Constraint: Up to level: 030
IfcClassificationReference - Keynote: 10.01.41#02; GVH_artnr 01: 10.01.41#02; GVH_artnr 02: geen waarde gevonden; GVH_artnr 03: geen waarde gevonden; GVH_artnr 04: geen waarde gevonden; GVH_artnr 05: geen waarde gevonden; GVH_artnr 06: geen waarde gevonden; TDS_link: .\05 As Builtdossier\2. Bouwkunde\2.1 Architectuur\2.1.10 wanden\TF A 10.01.41#2 A - lichte scheidingswand met watervaste gipsplaten.pdf
IfcRoot - Name: BB_10.01.41#02_Gipskartonwand_Vochtbestendig_MS100 / 25.50.25, 100 mm
Qto_WallBaseQuantities - Length: 1300; NetVolume: 0.384; Height: 3200; Width: 100; GrossVolume: 0.384; GrossSideArea: 3.84; NetSideArea: 3.84
Pset_Condition - AssessmentCondition: Empty
Pset_EnvironmentalImpactIndicators - Reference: BB_10.01.41#02_Gipskartonwand_Vochtbestendig_MS100 / 25.50.25, 100 mm; sets with these values: 2
Pset_WallCommon - Reference: BB_10.01.41#02_Gipskartonwand_Vochtbestendig_MS100 / 25.50.25, 100 mm; IsExternal: yes; LoadBearing: no; ExtendToStructure: no

# IfcWall: Basic Wall_BB_10.01.41#02_Gipskartonwand_Vochtbestendig_MS100 _ 25.50.25_ 100 mm13, Basic Wall:BB_10.01.41#02_Gipskartonwand_Vochtbestendig_MS100 / 25.50.25, 100 mm:32022452
In: 030
PredefinedType: PARTITIONING
Cpset_Wall - LevelOfAccuracy: in te vullen door Buildwise
IfcBuildingStorey - Base Offset: -10; Top Offset: 3190; Base Constraint: 030; Top Constraint: Up to level: 030
IfcClassificationReference - Keynote: 10.01.41#02; GVH_artnr 01: 10.01.41#02; GVH_artnr 02: geen waarde gevonden; GVH_artnr 03: geen waarde gevonden; GVH_artnr 04: geen waarde gevonden; GVH_artnr 05: geen waarde gevonden; GVH_artnr 06: geen waarde gevonden; TDS_link: .\05 As Builtdossier\2. Bouwkunde\2.1 Architectuur\2.1.10 wanden\TF A 10.01.41#2 A - lichte scheidingswand met watervaste gipsplaten.pdf
IfcRoot - Name: BB_10.01.41#02_Gipskartonwand_Vochtbestendig_MS100 / 25.50.25, 100 mm
Qto_WallBaseQuantities - Length: 889.5; NetVolume: 0.28464; Height: 3200; Width: 100; GrossVolume: 0.28464; GrossSideArea: 2.8464; NetSideArea: 2.8464
Pset_Condition - AssessmentCondition: Empty
Pset_EnvironmentalImpactIndicators - Reference: BB_10.01.41#02_Gipskartonwand_Vochtbestendig_MS100 / 25.50.25, 100 mm; sets with these values: 2
Pset_WallCommon - Reference: BB_10.01.41#02_Gipskartonwand_Vochtbestendig_MS100 / 25.50.25, 100 mm; IsExternal: yes; LoadBearing: no; ExtendToStructure: no

# IfcWall: Basic Wall_BB_10.01.41#02_Gipskartonwand_Vochtbestendig_MS100 _ 25.50.25_ 100 mm15, Basic Wall:BB_10.01.41#02_Gipskartonwand_Vochtbestendig_MS100 / 25.50.25, 100 mm:32022454
In: 030
PredefinedType: PARTITIONING
Cpset_Wall - LevelOfAccuracy: in te vullen door Buildwise
IfcBuildingStorey - Base Offset: -10; Top Offset: 3190; Base Constraint: 030; Top Constraint: Up to level: 030
IfcClassificationReference - Keynote: 10.01.41#02; GVH_artnr 01: 10.01.41#02; GVH_artnr 02: geen waarde gevonden; GVH_artnr 03: geen waarde gevonden; GVH_artnr 04: geen waarde gevonden; GVH_artnr 05: geen waarde gevonden; GVH_artnr 06: geen waarde gevonden; TDS_link: .\05 As Builtdossier\2. Bouwkunde\2.1 Architectuur\2.1.10 wanden\TF A 10.01.41#2 A - lichte scheidingswand met watervaste gipsplaten.pdf
IfcRoot - Name: BB_10.01.41#02_Gipskartonwand_Vochtbestendig_MS100 / 25.50.25, 100 mm
Qto_WallBaseQuantities - Length: 605.5; NetVolume: 0.19376; Height: 3200; Width: 100; GrossVolume: 0.19376; GrossSideArea: 1.9376; NetSideArea: 1.9376
Pset_Condition - AssessmentCondition: Empty
Pset_EnvironmentalImpactIndicators - Reference: BB_10.01.41#02_Gipskartonwand_Vochtbestendig_MS100 / 25.50.25, 100 mm; sets with these values: 2
Pset_WallCommon - Reference: BB_10.01.41#02_Gipskartonwand_Vochtbestendig_MS100 / 25.50.25, 100 mm; IsExternal: yes; LoadBearing: no; ExtendToStructure: no

# IfcWall: Basic Wall_BB_10.01.41#02_Gipskartonwand_Vochtbestendig_MS100 _ 25.50.25_ 100 mm3, Basic Wall:BB_10.01.41#02_Gipskartonwand_Vochtbestendig_MS100 / 25.50.25, 100 mm:12556696
In: 030
PredefinedType: PARTITIONING
Cpset_Wall - LevelOfAccuracy: in te vullen door Buildwise
IfcBuildingStorey - Base Offset: -80; Top Offset: 3190; Base Constraint: 030; Top Constraint: Up to level: 030
IfcClassificationReference - Keynote: 10.01.41#02; GVH_artnr 01: 10.01.41#02; GVH_artnr 02: geen waarde gevonden; GVH_artnr 03: geen waarde gevonden; GVH_artnr 04: geen waarde gevonden; GVH_artnr 05: geen waarde gevonden; GVH_artnr 06: geen waarde gevonden; TDS_link: .\05 As Builtdossier\2. Bouwkunde\2.1 Architectuur\2.1.10 wanden\TF A 10.01.41#2 A - lichte scheidingswand met watervaste gipsplaten.pdf
IfcElement - BB_Element_Lokaalnummer01: K.30.507
IfcRoot - Name: BB_10.01.41#02_Gipskartonwand_Vochtbestendig_MS100 / 25.50.25, 100 mm
Qto_WallBaseQuantities - Length: 1675; NetVolume: 0.564075; Height: 3270; Width: 100; GrossVolume: 0.564075; GrossSideArea: 5.64075; NetSideArea: 5.64075
Pset_Condition - AssessmentCondition: Empty
Pset_EnvironmentalImpactIndicators - Reference: BB_10.01.41#02_Gipskartonwand_Vochtbestendig_MS100 / 25.50.25, 100 mm; sets with these values: 2
Pset_WallCommon - Reference: BB_10.01.41#02_Gipskartonwand_Vochtbestendig_MS100 / 25.50.25, 100 mm; IsExternal: yes; LoadBearing: no; ExtendToStructure: no

# IfcWall: Basic Wall_BB_10.01.41#02_Gipskartonwand_Vochtbestendig_MS100 _ 25.50.25_ 100 mm5, Basic Wall:BB_10.01.41#02_Gipskartonwand_Vochtbestendig_MS100 / 25.50.25, 100 mm:12556747
In: 030
PredefinedType: PARTITIONING
Cpset_Wall - LevelOfAccuracy: in te vullen door Buildwise
IfcBuildingStorey - Base Offset: -80; Top Offset: 3190; Base Constraint: 030; Top Constraint: Up to level: 030
IfcClassificationReference - Keynote: 10.01.41#02; GVH_artnr 01: 10.01.41#02; GVH_artnr 02: geen waarde gevonden; GVH_artnr 03: geen waarde gevonden; GVH_artnr 04: geen waarde gevonden; GVH_artnr 05: geen waarde gevonden; GVH_artnr 06: geen waarde gevonden; TDS_link: .\05 As Builtdossier\2. Bouwkunde\2.1 Architectuur\2.1.10 wanden\TF A 10.01.41#2 A - lichte scheidingswand met watervaste gipsplaten.pdf
IfcElement - BB_Element_Lokaalnummer01: K.30.507
IfcRoot - Name: BB_10.01.41#02_Gipskartonwand_Vochtbestendig_MS100 / 25.50.25, 100 mm
Qto_WallBaseQuantities - Length: 4275; NetVolume: 0.996206; Height: 3270; Width: 100; GrossVolume: 1.38158; GrossSideArea: 13.8158; NetSideArea: 9.96206
Pset_Condition - AssessmentCondition: Empty
Pset_EnvironmentalImpactIndicators - Reference: BB_10.01.41#02_Gipskartonwand_Vochtbestendig_MS100 / 25.50.25, 100 mm; sets with these values: 2
Pset_WallCommon - Reference: BB_10.01.41#02_Gipskartonwand_Vochtbestendig_MS100 / 25.50.25, 100 mm; IsExternal: yes; LoadBearing: no; ExtendToStructure: no

# IfcWall: Basic Wall_BB_10.01.41#02_Gipskartonwand_Vochtbestendig_MS100 _ 25.50.25_ 100 mm7, Basic Wall:BB_10.01.41#02_Gipskartonwand_Vochtbestendig_MS100 / 25.50.25, 100 mm:32022435
In: 030
PredefinedType: PARTITIONING
Cpset_Wall - LevelOfAccuracy: in te vullen door Buildwise
IfcBuildingStorey - Base Offset: -10; Top Offset: 3190; Base Constraint: 030; Top Constraint: Up to level: 030
IfcClassificationReference - Keynote: 10.01.41#02; GVH_artnr 01: 10.01.41#02; GVH_artnr 02: geen waarde gevonden; GVH_artnr 03: geen waarde gevonden; GVH_artnr 04: geen waarde gevonden; GVH_artnr 05: geen waarde gevonden; GVH_artnr 06: geen waarde gevonden; TDS_link: .\05 As Builtdossier\2. Bouwkunde\2.1 Architectuur\2.1.10 wanden\TF A 10.01.41#2 A - lichte scheidingswand met watervaste gipsplaten.pdf
IfcRoot - Name: BB_10.01.41#02_Gipskartonwand_Vochtbestendig_MS100 / 25.50.25, 100 mm
Qto_WallBaseQuantities - Length: 2400; NetVolume: 0.768; Height: 3200; Width: 100; GrossVolume: 0.768; GrossSideArea: 7.68; NetSideArea: 7.68
Pset_Condition - AssessmentCondition: Empty
Pset_EnvironmentalImpactIndicators - Reference: BB_10.01.41#02_Gipskartonwand_Vochtbestendig_MS100 / 25.50.25, 100 mm; sets with these values: 2
Pset_WallCommon - Reference: BB_10.01.41#02_Gipskartonwand_Vochtbestendig_MS100 / 25.50.25, 100 mm; IsExternal: yes; LoadBearing: no; ExtendToStructure: no

# IfcWall: Basic Wall_BB_10.01.41#02_Gipskartonwand_Vochtbestendig_MS100 _ 25.50.25_ 100 mm9, Basic Wall:BB_10.01.41#02_Gipskartonwand_Vochtbestendig_MS100 / 25.50.25, 100 mm:32022450
In: 030
PredefinedType: PARTITIONING
Cpset_Wall - LevelOfAccuracy: in te vullen door Buildwise
IfcBuildingStorey - Base Offset: -10; Top Offset: 3190; Base Constraint: 030; Top Constraint: Up to level: 030
IfcClassificationReference - Keynote: 10.01.41#02; GVH_artnr 01: 10.01.41#02; GVH_artnr 02: geen waarde gevonden; GVH_artnr 03: geen waarde gevonden; GVH_artnr 04: geen waarde gevonden; GVH_artnr 05: geen waarde gevonden; GVH_artnr 06: geen waarde gevonden; TDS_link: .\05 As Builtdossier\2. Bouwkunde\2.1 Architectuur\2.1.10 wanden\TF A 10.01.41#2 A - lichte scheidingswand met watervaste gipsplaten.pdf
IfcRoot - Name: BB_10.01.41#02_Gipskartonwand_Vochtbestendig_MS100 / 25.50.25, 100 mm
Qto_WallBaseQuantities - Length: 750; NetVolume: 0.224; Height: 3200; Width: 100; GrossVolume: 0.224; GrossSideArea: 2.24; NetSideArea: 2.24
Pset_Condition - AssessmentCondition: Empty
Pset_EnvironmentalImpactIndicators - Reference: BB_10.01.41#02_Gipskartonwand_Vochtbestendig_MS100 / 25.50.25, 100 mm; sets with these values: 2
Pset_WallCommon - Reference: BB_10.01.41#02_Gipskartonwand_Vochtbestendig_MS100 / 25.50.25, 100 mm; IsExternal: yes; LoadBearing: no; ExtendToStructure: no

# IfcWall: Basic Wall_BB_10.01.41#03_Gipskartonwand_43dB_MS100 _ 25.50.25_ 100 mm, Basic Wall:BB_10.01.41#03_Gipskartonwand_43dB_MS100 / 25.50.25, 100 mm:13045371
In: 000
PredefinedType: PARTITIONING
Cpset_Wall - LevelOfAccuracy: in te vullen door Buildwise
IfcBuildingStorey - Base Offset: -200; Top Offset: -915; Base Constraint: 000; Top Constraint: Up to level: 010
IfcClassificationReference - Keynote: 10.01.41#03; GVH_artnr 01: 10.01.41#03; GVH_artnr 02: geen waarde gevonden; GVH_artnr 03: geen waarde gevonden; GVH_artnr 04: geen waarde gevonden; GVH_artnr 05: geen waarde gevonden; GVH_artnr 06: geen waarde gevonden; TDS_link: .\05 As Builtdossier\2. Bouwkunde\2.1 Architectuur\2.1.10 wanden\TF A 10.01.41#3 A - lichte scheidingswand met gipsplaten Rw50dB.pdf
IfcElement - BB_Element_Lokaalnummer01: K.00.201
IfcRoot - Name: BB_10.01.41#03_Gipskartonwand_43dB_MS100 / 25.50.25, 100 mm
Qto_WallBaseQuantities - Length: 230; NetVolume: 0.061875; Height: 2885; Width: 100; GrossVolume: 0.061875; GrossSideArea: 0.61875; NetSideArea: 0.61875
Pset_Condition - AssessmentCondition: Empty
Pset_EnvironmentalImpactIndicators - Reference: BB_10.01.41#03_Gipskartonwand_43dB_MS100 / 25.50.25, 100 mm; sets with these values: 2
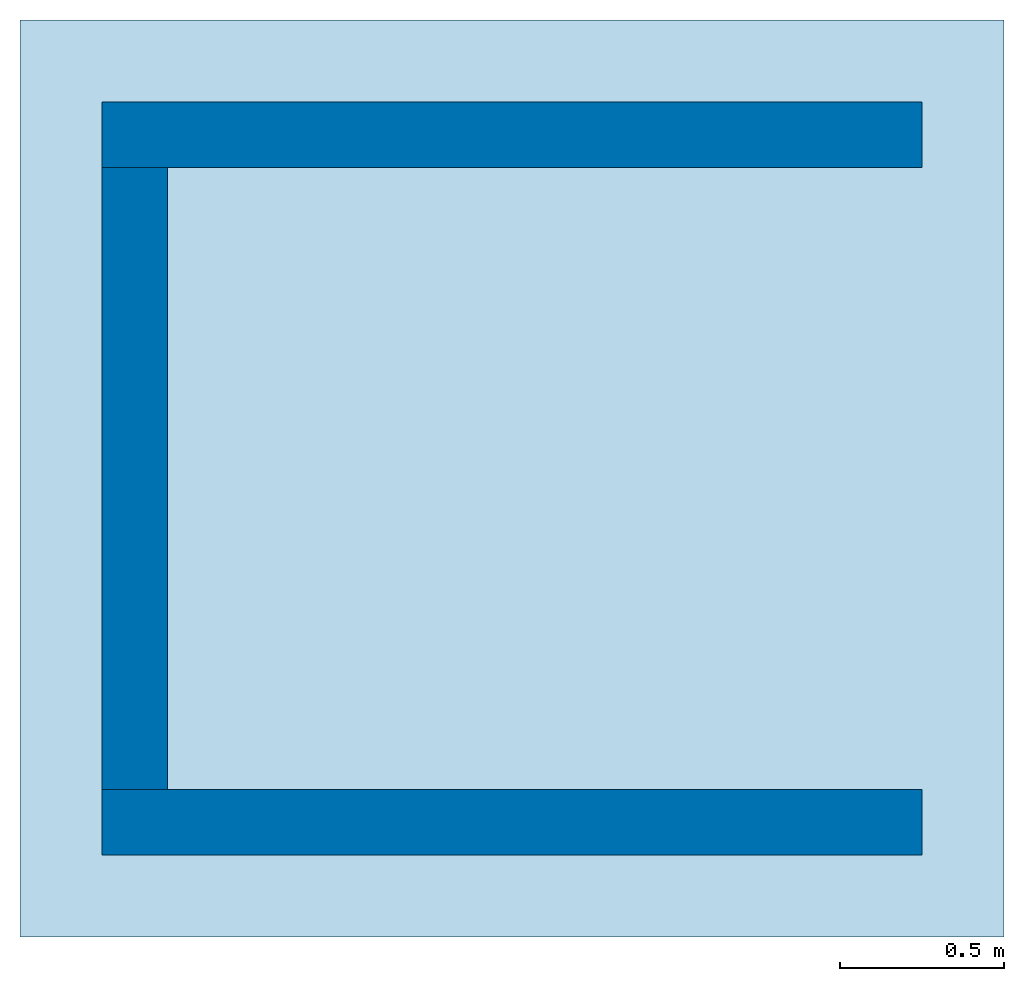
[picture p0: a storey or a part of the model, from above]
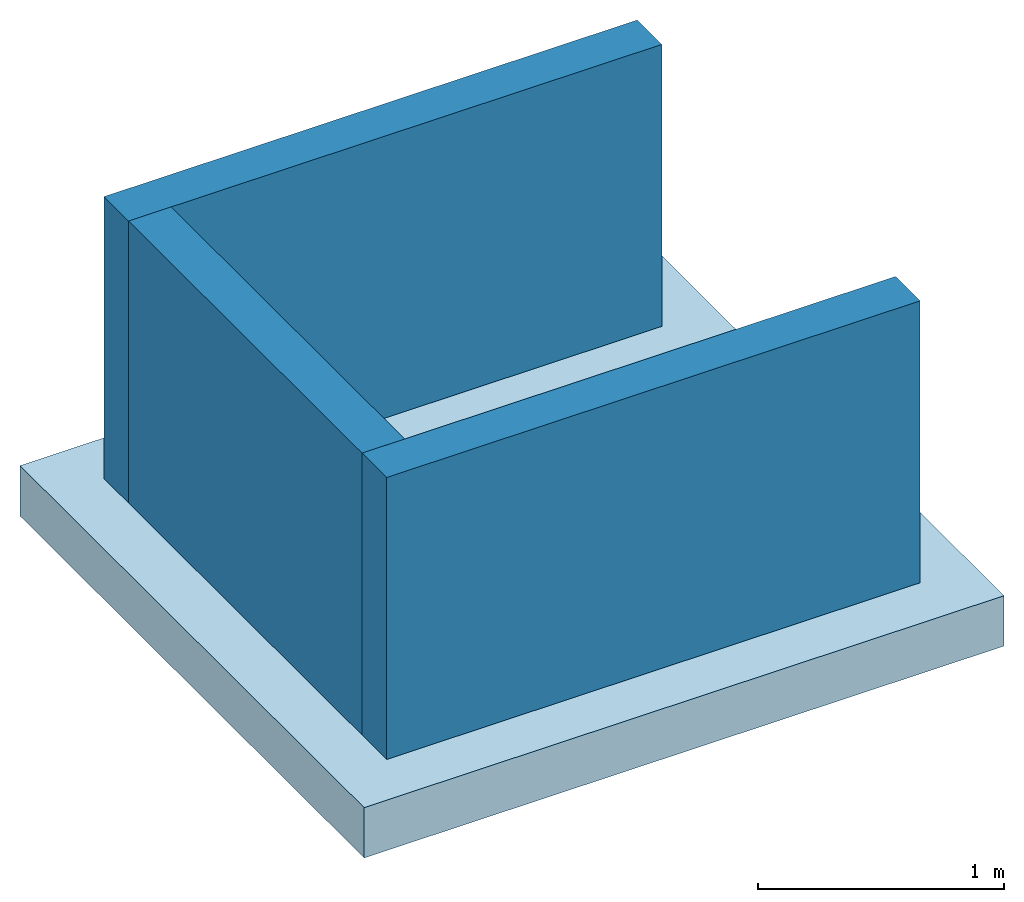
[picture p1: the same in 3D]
Properties of the parts of a building model (IFC4X3_ADD2), part 25 of 28

# IfcWall: Basic Wall_BB_10.01.41#03_Gipskartonwand_43dB_MS100 _ 25.50.25_ 100 mm, Basic Wall:BB_10.01.41#03_Gipskartonwand_43dB_MS100 / 25.50.25, 100 mm:13045371
Pset_WallCommon - Reference: BB_10.01.41#03_Gipskartonwand_43dB_MS100 / 25.50.25, 100 mm; FireRating: EI60; IsExternal: yes; LoadBearing: no; ExtendToStructure: no

# IfcWall: Basic Wall_BB_10.01.41#03_Gipskartonwand_43dB_MS100 _ 25.50.25_ 100 mm1, Basic Wall:BB_10.01.41#03_Gipskartonwand_43dB_MS100 / 25.50.25, 100 mm:13046482
In: 000
PredefinedType: PARTITIONING
Cpset_Wall - LevelOfAccuracy: in te vullen door Buildwise
IfcBuildingStorey - Base Offset: 0; Top Offset: 3070; Base Constraint: 000; Top Constraint: Up to level: 000
IfcClassificationReference - Keynote: 10.01.41#03; GVH_artnr 01: 10.01.41#03; GVH_artnr 02: geen waarde gevonden; GVH_artnr 03: geen waarde gevonden; GVH_artnr 04: geen waarde gevonden; GVH_artnr 05: geen waarde gevonden; GVH_artnr 06: geen waarde gevonden; TDS_link: .\05 As Builtdossier\2. Bouwkunde\2.1 Architectuur\2.1.10 wanden\TF A 10.01.41#3 A - lichte scheidingswand met gipsplaten Rw50dB.pdf
IfcElement - BB_Element_Lokaalnummer01: K.00.305
IfcRoot - Name: BB_10.01.41#03_Gipskartonwand_43dB_MS100 / 25.50.25, 100 mm
Qto_WallBaseQuantities - Length: 1650; NetVolume: 0.076105; Height: 3070; Width: 100; GrossVolume: 0.076105; GrossSideArea: 0.76105; NetSideArea: 0.76105
Pset_Condition - AssessmentCondition: Empty
Pset_EnvironmentalImpactIndicators - Reference: BB_10.01.41#03_Gipskartonwand_43dB_MS100 / 25.50.25, 100 mm; sets with these values: 2
Pset_WallCommon - Reference: BB_10.01.41#03_Gipskartonwand_43dB_MS100 / 25.50.25, 100 mm; FireRating: EI60; IsExternal: yes; LoadBearing: no; ExtendToStructure: no

# IfcWall: Basic Wall_BB_10.01.41#03_Gipskartonwand_43dB_MS100 _ 25.50.25_ 100 mm11, Basic Wall:BB_10.01.41#03_Gipskartonwand_43dB_MS100 / 25.50.25, 100 mm:13059309
In: 000
PredefinedType: PARTITIONING
Cpset_Wall - LevelOfAccuracy: in te vullen door Buildwise
IfcBuildingStorey - Base Offset: -200; Top Offset: -920; Base Constraint: 000; Top Constraint: Up to level: 010
IfcClassificationReference - Keynote: 10.01.41#03; GVH_artnr 01: 10.01.41#03; GVH_artnr 02: geen waarde gevonden; GVH_artnr 03: geen waarde gevonden; GVH_artnr 04: geen waarde gevonden; GVH_artnr 05: geen waarde gevonden; GVH_artnr 06: geen waarde gevonden; TDS_link: .\05 As Builtdossier\2. Bouwkunde\2.1 Architectuur\2.1.10 wanden\TF A 10.01.41#3 A - lichte scheidingswand met gipsplaten Rw50dB.pdf
IfcElement - BB_Element_Lokaalnummer01: K.00.112
IfcRoot - Name: BB_10.01.41#03_Gipskartonwand_43dB_MS100 / 25.50.25, 100 mm
Qto_WallBaseQuantities - Length: 240; NetVolume: 0.06912; Height: 2880; Width: 100; GrossVolume: 0.06912; GrossSideArea: 0.6912; NetSideArea: 0.6912
Pset_Condition - AssessmentCondition: Empty
Pset_EnvironmentalImpactIndicators - Reference: BB_10.01.41#03_Gipskartonwand_43dB_MS100 / 25.50.25, 100 mm; sets with these values: 2
Pset_WallCommon - Reference: BB_10.01.41#03_Gipskartonwand_43dB_MS100 / 25.50.25, 100 mm; FireRating: EI60; IsExternal: yes; LoadBearing: no; ExtendToStructure: no

# IfcWall: Basic Wall_BB_10.01.41#03_Gipskartonwand_43dB_MS100 _ 25.50.25_ 100 mm13, Basic Wall:BB_10.01.41#03_Gipskartonwand_43dB_MS100 / 25.50.25, 100 mm:13059310
In: 000
PredefinedType: PARTITIONING
Cpset_Wall - LevelOfAccuracy: in te vullen door Buildwise
IfcBuildingStorey - Base Offset: -200; Top Offset: -920; Base Constraint: 000; Top Constraint: Up to level: 010
IfcClassificationReference - Keynote: 10.01.41#03; GVH_artnr 01: 10.01.41#03; GVH_artnr 02: geen waarde gevonden; GVH_artnr 03: geen waarde gevonden; GVH_artnr 04: geen waarde gevonden; GVH_artnr 05: geen waarde gevonden; GVH_artnr 06: geen waarde gevonden; TDS_link: .\05 As Builtdossier\2. Bouwkunde\2.1 Architectuur\2.1.10 wanden\TF A 10.01.41#3 A - lichte scheidingswand met gipsplaten Rw50dB.pdf
IfcElement - BB_Element_Lokaalnummer01: K.00.112
IfcRoot - Name: BB_10.01.41#03_Gipskartonwand_43dB_MS100 / 25.50.25, 100 mm
Qto_WallBaseQuantities - Length: 240; NetVolume: 0.06912; Height: 2880; Width: 100; GrossVolume: 0.06912; GrossSideArea: 0.6912; NetSideArea: 0.6912
Pset_Condition - AssessmentCondition: Empty
Pset_EnvironmentalImpactIndicators - Reference: BB_10.01.41#03_Gipskartonwand_43dB_MS100 / 25.50.25, 100 mm; sets with these values: 2
Pset_WallCommon - Reference: BB_10.01.41#03_Gipskartonwand_43dB_MS100 / 25.50.25, 100 mm; FireRating: EI60; IsExternal: yes; LoadBearing: no; ExtendToStructure: no

# IfcWall: Basic Wall_BB_10.01.41#03_Gipskartonwand_43dB_MS100 _ 25.50.25_ 100 mm15, Basic Wall:BB_10.01.41#03_Gipskartonwand_43dB_MS100 / 25.50.25, 100 mm:13059311
In: 000
PredefinedType: PARTITIONING
Cpset_Wall - LevelOfAccuracy: in te vullen door Buildwise
IfcBuildingStorey - Base Offset: -200; Top Offset: -920; Base Constraint: 000; Top Constraint: Up to level: 010
IfcClassificationReference - Keynote: 10.01.41#03; GVH_artnr 01: 10.01.41#03; GVH_artnr 02: geen waarde gevonden; GVH_artnr 03: geen waarde gevonden; GVH_artnr 04: geen waarde gevonden; GVH_artnr 05: geen waarde gevonden; GVH_artnr 06: geen waarde gevonden; TDS_link: .\05 As Builtdossier\2. Bouwkunde\2.1 Architectuur\2.1.10 wanden\TF A 10.01.41#3 A - lichte scheidingswand met gipsplaten Rw50dB.pdf
IfcElement - BB_Element_Lokaalnummer01: K.00.503
IfcRoot - Name: BB_10.01.41#03_Gipskartonwand_43dB_MS100 / 25.50.25, 100 mm
Qto_WallBaseQuantities - Length: 240; NetVolume: 0.06912; Height: 2880; Width: 100; GrossVolume: 0.06912; GrossSideArea: 0.6912; NetSideArea: 0.6912
Pset_Condition - AssessmentCondition: Empty
Pset_EnvironmentalImpactIndicators - Reference: BB_10.01.41#03_Gipskartonwand_43dB_MS100 / 25.50.25, 100 mm; sets with these values: 2
Pset_WallCommon - Reference: BB_10.01.41#03_Gipskartonwand_43dB_MS100 / 25.50.25, 100 mm; FireRating: EI60; IsExternal: yes; LoadBearing: no; ExtendToStructure: no

# IfcWall: Basic Wall_BB_10.01.41#03_Gipskartonwand_43dB_MS100 _ 25.50.25_ 100 mm17, Basic Wall:BB_10.01.41#03_Gipskartonwand_43dB_MS100 / 25.50.25, 100 mm:13059312
In: 000
PredefinedType: PARTITIONING
Cpset_Wall - LevelOfAccuracy: in te vullen door Buildwise
IfcBuildingStorey - Base Offset: -200; Top Offset: -920; Base Constraint: 000; Top Constraint: Up to level: 010
IfcClassificationReference - Keynote: 10.01.41#03; GVH_artnr 01: 10.01.41#03; GVH_artnr 02: geen waarde gevonden; GVH_artnr 03: geen waarde gevonden; GVH_artnr 04: geen waarde gevonden; GVH_artnr 05: geen waarde gevonden; GVH_artnr 06: geen waarde gevonden; TDS_link: .\05 As Builtdossier\2. Bouwkunde\2.1 Architectuur\2.1.10 wanden\TF A 10.01.41#3 A - lichte scheidingswand met gipsplaten Rw50dB.pdf
IfcElement - BB_Element_Lokaalnummer01: K.00.503
IfcRoot - Name: BB_10.01.41#03_Gipskartonwand_43dB_MS100 / 25.50.25, 100 mm
Qto_WallBaseQuantities - Length: 240; NetVolume: 0.06912; Height: 2880; Width: 100; GrossVolume: 0.06912; GrossSideArea: 0.6912; NetSideArea: 0.6912
Pset_Condition - AssessmentCondition: Empty
Pset_EnvironmentalImpactIndicators - Reference: BB_10.01.41#03_Gipskartonwand_43dB_MS100 / 25.50.25, 100 mm; sets with these values: 2
Pset_WallCommon - Reference: BB_10.01.41#03_Gipskartonwand_43dB_MS100 / 25.50.25, 100 mm; FireRating: EI60; IsExternal: yes; LoadBearing: no; ExtendToStructure: no

# IfcWall: Basic Wall_BB_10.01.41#03_Gipskartonwand_43dB_MS100 _ 25.50.25_ 100 mm19, Basic Wall:BB_10.01.41#03_Gipskartonwand_43dB_MS100 / 25.50.25, 100 mm:13059313
In: 000
PredefinedType: PARTITIONING
Cpset_Wall - LevelOfAccuracy: in te vullen door Buildwise
IfcBuildingStorey - Base Offset: -200; Top Offset: -920; Base Constraint: 000; Top Constraint: Up to level: 010
IfcClassificationReference - Keynote: 10.01.41#03; GVH_artnr 01: 10.01.41#03; GVH_artnr 02: geen waarde gevonden; GVH_artnr 03: geen waarde gevonden; GVH_artnr 04: geen waarde gevonden; GVH_artnr 05: geen waarde gevonden; GVH_artnr 06: geen waarde gevonden; TDS_link: .\05 As Builtdossier\2. Bouwkunde\2.1 Architectuur\2.1.10 wanden\TF A 10.01.41#3 A - lichte scheidingswand met gipsplaten Rw50dB.pdf
IfcElement - BB_Element_Lokaalnummer01: K.00.504
IfcRoot - Name: BB_10.01.41#03_Gipskartonwand_43dB_MS100 / 25.50.25, 100 mm
Qto_WallBaseQuantities - Length: 240; NetVolume: 0.06912; Height: 2880; Width: 100; GrossVolume: 0.06912; GrossSideArea: 0.6912; NetSideArea: 0.6912
Pset_Condition - AssessmentCondition: Empty
Pset_EnvironmentalImpactIndicators - Reference: BB_10.01.41#03_Gipskartonwand_43dB_MS100 / 25.50.25, 100 mm; sets with these values: 2
Pset_WallCommon - Reference: BB_10.01.41#03_Gipskartonwand_43dB_MS100 / 25.50.25, 100 mm; FireRating: EI60; IsExternal: yes; LoadBearing: no; ExtendToStructure: no

# IfcWall: Basic Wall_BB_10.01.41#03_Gipskartonwand_43dB_MS100 _ 25.50.25_ 100 mm21, Basic Wall:BB_10.01.41#03_Gipskartonwand_43dB_MS100 / 25.50.25, 100 mm:13059314
In: 000
PredefinedType: PARTITIONING
Cpset_Wall - LevelOfAccuracy: in te vullen door Buildwise
IfcBuildingStorey - Base Offset: -200; Top Offset: -920; Base Constraint: 000; Top Constraint: Up to level: 010
IfcClassificationReference - Keynote: 10.01.41#03; GVH_artnr 01: 10.01.41#03; GVH_artnr 02: geen waarde gevonden; GVH_artnr 03: geen waarde gevonden; GVH_artnr 04: geen waarde gevonden; GVH_artnr 05: geen waarde gevonden; GVH_artnr 06: geen waarde gevonden; TDS_link: .\05 As Builtdossier\2. Bouwkunde\2.1 Architectuur\2.1.10 wanden\TF A 10.01.41#3 A - lichte scheidingswand met gipsplaten Rw50dB.pdf
IfcElement - BB_Element_Lokaalnummer01: K.00.504
IfcRoot - Name: BB_10.01.41#03_Gipskartonwand_43dB_MS100 / 25.50.25, 100 mm
Qto_WallBaseQuantities - Length: 240; NetVolume: 0.06912; Height: 2880; Width: 100; GrossVolume: 0.06912; GrossSideArea: 0.6912; NetSideArea: 0.6912
Pset_Condition - AssessmentCondition: Empty
Pset_EnvironmentalImpactIndicators - Reference: BB_10.01.41#03_Gipskartonwand_43dB_MS100 / 25.50.25, 100 mm; sets with these values: 2
Pset_WallCommon - Reference: BB_10.01.41#03_Gipskartonwand_43dB_MS100 / 25.50.25, 100 mm; FireRating: EI60; IsExternal: yes; LoadBearing: no; ExtendToStructure: no

# IfcWall: Basic Wall_BB_10.01.41#03_Gipskartonwand_43dB_MS100 _ 25.50.25_ 100 mm23, Basic Wall:BB_10.01.41#03_Gipskartonwand_43dB_MS100 / 25.50.25, 100 mm:13059315
In: 000
PredefinedType: PARTITIONING
Cpset_Wall - LevelOfAccuracy: in te vullen door Buildwise
IfcBuildingStorey - Base Offset: -200; Top Offset: -920; Base Constraint: 000; Top Constraint: Up to level: 010
IfcClassificationReference - Keynote: 10.01.41#03; GVH_artnr 01: 10.01.41#03; GVH_artnr 02: geen waarde gevonden; GVH_artnr 03: geen waarde gevonden; GVH_artnr 04: geen waarde gevonden; GVH_artnr 05: geen waarde gevonden; GVH_artnr 06: geen waarde gevonden; TDS_link: .\05 As Builtdossier\2. Bouwkunde\2.1 Architectuur\2.1.10 wanden\TF A 10.01.41#3 A - lichte scheidingswand met gipsplaten Rw50dB.pdf
IfcElement - BB_Element_Lokaalnummer01: K.00.404
IfcRoot - Name: BB_10.01.41#03_Gipskartonwand_43dB_MS100 / 25.50.25, 100 mm
Qto_WallBaseQuantities - Length: 240; NetVolume: 0.06912; Height: 2880; Width: 100; GrossVolume: 0.06912; GrossSideArea: 0.6912; NetSideArea: 0.6912
Pset_Condition - AssessmentCondition: Empty
Pset_EnvironmentalImpactIndicators - Reference: BB_10.01.41#03_Gipskartonwand_43dB_MS100 / 25.50.25, 100 mm; sets with these values: 2
Pset_WallCommon - Reference: BB_10.01.41#03_Gipskartonwand_43dB_MS100 / 25.50.25, 100 mm; FireRating: EI60; IsExternal: yes; LoadBearing: no; ExtendToStructure: no

# IfcWall: Basic Wall_BB_10.01.41#03_Gipskartonwand_43dB_MS100 _ 25.50.25_ 100 mm25, Basic Wall:BB_10.01.41#03_Gipskartonwand_43dB_MS100 / 25.50.25, 100 mm:13059316
In: 000
PredefinedType: PARTITIONING
Cpset_Wall - LevelOfAccuracy: in te vullen door Buildwise
IfcBuildingStorey - Base Offset: -200; Top Offset: -920; Base Constraint: 000; Top Constraint: Up to level: 010
IfcClassificationReference - Keynote: 10.01.41#03; GVH_artnr 01: 10.01.41#03; GVH_artnr 02: geen waarde gevonden; GVH_artnr 03: geen waarde gevonden; GVH_artnr 04: geen waarde gevonden; GVH_artnr 05: geen waarde gevonden; GVH_artnr 06: geen waarde gevonden; TDS_link: .\05 As Builtdossier\2. Bouwkunde\2.1 Architectuur\2.1.10 wanden\TF A 10.01.41#3 A - lichte scheidingswand met gipsplaten Rw50dB.pdf
IfcElement - BB_Element_Lokaalnummer01: K.00.404
IfcRoot - Name: BB_10.01.41#03_Gipskartonwand_43dB_MS100 / 25.50.25, 100 mm
Qto_WallBaseQuantities - Length: 240; NetVolume: 0.06912; Height: 2880; Width: 100; GrossVolume: 0.06912; GrossSideArea: 0.6912; NetSideArea: 0.6912
Pset_Condition - AssessmentCondition: Empty
Pset_EnvironmentalImpactIndicators - Reference: BB_10.01.41#03_Gipskartonwand_43dB_MS100 / 25.50.25, 100 mm; sets with these values: 2
Pset_WallCommon - Reference: BB_10.01.41#03_Gipskartonwand_43dB_MS100 / 25.50.25, 100 mm; FireRating: EI60; IsExternal: yes; LoadBearing: no; ExtendToStructure: no

# IfcWall: Basic Wall_BB_10.01.41#03_Gipskartonwand_43dB_MS100 _ 25.50.25_ 100 mm27, Basic Wall:BB_10.01.41#03_Gipskartonwand_43dB_MS100 / 25.50.25, 100 mm:13059317
In: 000
PredefinedType: PARTITIONING
Cpset_Wall - LevelOfAccuracy: in te vullen door Buildwise
IfcBuildingStorey - Base Offset: -200; Top Offset: -920; Base Constraint: 000; Top Constraint: Up to level: 010
IfcClassificationReference - Keynote: 10.01.41#03; GVH_artnr 01: 10.01.41#03; GVH_artnr 02: geen waarde gevonden; GVH_artnr 03: geen waarde gevonden; GVH_artnr 04: geen waarde gevonden; GVH_artnr 05: geen waarde gevonden; GVH_artnr 06: geen waarde gevonden; TDS_link: .\05 As Builtdossier\2. Bouwkunde\2.1 Architectuur\2.1.10 wanden\TF A 10.01.41#3 A - lichte scheidingswand met gipsplaten Rw50dB.pdf
IfcElement - BB_Element_Lokaalnummer01: K.00.404
IfcRoot - Name: BB_10.01.41#03_Gipskartonwand_43dB_MS100 / 25.50.25, 100 mm
Qto_WallBaseQuantities - Length: 240; NetVolume: 0.06912; Height: 2880; Width: 100; GrossVolume: 0.06912; GrossSideArea: 0.6912; NetSideArea: 0.6912
Pset_Condition - AssessmentCondition: Empty
Pset_EnvironmentalImpactIndicators - Reference: BB_10.01.41#03_Gipskartonwand_43dB_MS100 / 25.50.25, 100 mm; sets with these values: 2
Pset_WallCommon - Reference: BB_10.01.41#03_Gipskartonwand_43dB_MS100 / 25.50.25, 100 mm; FireRating: EI60; IsExternal: yes; LoadBearing: no; ExtendToStructure: no

# IfcWall: Basic Wall_BB_10.01.41#03_Gipskartonwand_43dB_MS100 _ 25.50.25_ 100 mm29, Basic Wall:BB_10.01.41#03_Gipskartonwand_43dB_MS100 / 25.50.25, 100 mm:13059318
In: 000
PredefinedType: PARTITIONING
Cpset_Wall - LevelOfAccuracy: in te vullen door Buildwise
IfcBuildingStorey - Base Offset: -200; Top Offset: -920; Base Constraint: 000; Top Constraint: Up to level: 010
IfcClassificationReference - Keynote: 10.01.41#03; GVH_artnr 01: 10.01.41#03; GVH_artnr 02: geen waarde gevonden; GVH_artnr 03: geen waarde gevonden; GVH_artnr 04: geen waarde gevonden; GVH_artnr 05: geen waarde gevonden; GVH_artnr 06: geen waarde gevonden; TDS_link: .\05 As Builtdossier\2. Bouwkunde\2.1 Architectuur\2.1.10 wanden\TF A 10.01.41#3 A - lichte scheidingswand met gipsplaten Rw50dB.pdf
IfcElement - BB_Element_Lokaalnummer01: K.00.404
IfcRoot - Name: BB_10.01.41#03_Gipskartonwand_43dB_MS100 / 25.50.25, 100 mm
Qto_WallBaseQuantities - Length: 240; NetVolume: 0.06912; Height: 2880; Width: 100; GrossVolume: 0.06912; GrossSideArea: 0.6912; NetSideArea: 0.6912
Pset_Condition - AssessmentCondition: Empty
Pset_EnvironmentalImpactIndicators - Reference: BB_10.01.41#03_Gipskartonwand_43dB_MS100 / 25.50.25, 100 mm; sets with these values: 2
Pset_WallCommon - Reference: BB_10.01.41#03_Gipskartonwand_43dB_MS100 / 25.50.25, 100 mm; FireRating: EI60; IsExternal: yes; LoadBearing: no; ExtendToStructure: no

# IfcWall: Basic Wall_BB_10.01.41#03_Gipskartonwand_43dB_MS100 _ 25.50.25_ 100 mm3, Basic Wall:BB_10.01.41#03_Gipskartonwand_43dB_MS100 / 25.50.25, 100 mm:13048373
In: 000
PredefinedType: PARTITIONING
Cpset_Wall - LevelOfAccuracy: in te vullen door Buildwise
IfcBuildingStorey - Base Offset: -200; Top Offset: -600; Base Constraint: 000; Top Constraint: Up to level: 010
IfcClassificationReference - Keynote: 10.01.41#03; GVH_artnr 01: 10.01.41#03; GVH_artnr 02: geen waarde gevonden; GVH_artnr 03: geen waarde gevonden; GVH_artnr 04: geen waarde gevonden; GVH_artnr 05: geen waarde gevonden; GVH_artnr 06: geen waarde gevonden; TDS_link: .\05 As Builtdossier\2. Bouwkunde\2.1 Architectuur\2.1.10 wanden\TF A 10.01.41#3 A - lichte scheidingswand met gipsplaten Rw50dB.pdf
IfcElement - BB_Element_Lokaalnummer01: K.00.113
IfcRoot - Name: BB_10.01.41#03_Gipskartonwand_43dB_MS100 / 25.50.25, 100 mm
Qto_WallBaseQuantities - Length: 2035; NetVolume: 0.474515; Height: 3200; Width: 100; GrossVolume: 0.6672; GrossSideArea: 6.672; NetSideArea: 4.74515
Pset_Condition - AssessmentCondition: Empty
Pset_EnvironmentalImpactIndicators - Reference: BB_10.01.41#03_Gipskartonwand_43dB_MS100 / 25.50.25, 100 mm; sets with these values: 2
Pset_WallCommon - Reference: BB_10.01.41#03_Gipskartonwand_43dB_MS100 / 25.50.25, 100 mm; FireRating: EI60; IsExternal: yes; LoadBearing: no; ExtendToStructure: no

# IfcWall: Basic Wall_BB_10.01.41#03_Gipskartonwand_43dB_MS100 _ 25.50.25_ 100 mm31, Basic Wall:BB_10.01.41#03_Gipskartonwand_43dB_MS100 / 25.50.25, 100 mm:13059319
In: 000
PredefinedType: PARTITIONING
Cpset_Wall - LevelOfAccuracy: in te vullen door Buildwise
IfcBuildingStorey - Base Offset: -200; Top Offset: -915; Base Constraint: 000; Top Constraint: Up to level: 010
IfcClassificationReference - Keynote: 10.01.41#03; GVH_artnr 01: 10.01.41#03; GVH_artnr 02: geen waarde gevonden; GVH_artnr 03: geen waarde gevonden; GVH_artnr 04: geen waarde gevonden; GVH_artnr 05: geen waarde gevonden; GVH_artnr 06: geen waarde gevonden; TDS_link: .\05 As Builtdossier\2. Bouwkunde\2.1 Architectuur\2.1.10 wanden\TF A 10.01.41#3 A - lichte scheidingswand met gipsplaten Rw50dB.pdf
IfcElement - BB_Element_Lokaalnummer01: K.00.201
IfcRoot - Name: BB_10.01.41#03_Gipskartonwand_43dB_MS100 / 25.50.25, 100 mm
Qto_WallBaseQuantities - Length: 240; NetVolume: 0.06924; Height: 2885; Width: 100; GrossVolume: 0.06924; GrossSideArea: 0.6924; NetSideArea: 0.6924
Pset_Condition - AssessmentCondition: Empty
Pset_EnvironmentalImpactIndicators - Reference: BB_10.01.41#03_Gipskartonwand_43dB_MS100 / 25.50.25, 100 mm; sets with these values: 2
Pset_WallCommon - Reference: BB_10.01.41#03_Gipskartonwand_43dB_MS100 / 25.50.25, 100 mm; FireRating: EI60; IsExternal: yes; LoadBearing: no; ExtendToStructure: no

# IfcWall: Basic Wall_BB_10.01.41#03_Gipskartonwand_43dB_MS100 _ 25.50.25_ 100 mm33, Basic Wall:BB_10.01.41#03_Gipskartonwand_43dB_MS100 / 25.50.25, 100 mm:13059321
In: 000
PredefinedType: PARTITIONING
Cpset_Wall - LevelOfAccuracy: in te vullen door Buildwise
IfcBuildingStorey - Base Offset: -200; Top Offset: -915; Base Constraint: 000; Top Constraint: Up to level: 010
IfcClassificationReference - Keynote: 10.01.41#03; GVH_artnr 01: 10.01.41#03; GVH_artnr 02: geen waarde gevonden; GVH_artnr 03: geen waarde gevonden; GVH_artnr 04: geen waarde gevonden; GVH_artnr 05: geen waarde gevonden; GVH_artnr 06: geen waarde gevonden; TDS_link: .\05 As Builtdossier\2. Bouwkunde\2.1 Architectuur\2.1.10 wanden\TF A 10.01.41#3 A - lichte scheidingswand met gipsplaten Rw50dB.pdf
IfcElement - BB_Element_Lokaalnummer01: K.00.201
IfcRoot - Name: BB_10.01.41#03_Gipskartonwand_43dB_MS100 / 25.50.25, 100 mm
Qto_WallBaseQuantities - Length: 240; NetVolume: 0.06924; Height: 2885; Width: 100; GrossVolume: 0.06924; GrossSideArea: 0.6924; NetSideArea: 0.6924
Pset_Condition - AssessmentCondition: Empty
Pset_EnvironmentalImpactIndicators - Reference: BB_10.01.41#03_Gipskartonwand_43dB_MS100 / 25.50.25, 100 mm; sets with these values: 2
Pset_WallCommon - Reference: BB_10.01.41#03_Gipskartonwand_43dB_MS100 / 25.50.25, 100 mm; FireRating: EI60; IsExternal: yes; LoadBearing: no; ExtendToStructure: no

# IfcWall: Basic Wall_BB_10.01.41#03_Gipskartonwand_43dB_MS100 _ 25.50.25_ 100 mm35, Basic Wall:BB_10.01.41#03_Gipskartonwand_43dB_MS100 / 25.50.25, 100 mm:13059322
In: 000
PredefinedType: PARTITIONING
Cpset_Wall - LevelOfAccuracy: in te vullen door Buildwise
IfcBuildingStorey - Base Offset: -200; Top Offset: -915; Base Constraint: 000; Top Constraint: Up to level: 010
IfcClassificationReference - Keynote: 10.01.41#03; GVH_artnr 01: 10.01.41#03; GVH_artnr 02: geen waarde gevonden; GVH_artnr 03: geen waarde gevonden; GVH_artnr 04: geen waarde gevonden; GVH_artnr 05: geen waarde gevonden; GVH_artnr 06: geen waarde gevonden; TDS_link: .\05 As Builtdossier\2. Bouwkunde\2.1 Architectuur\2.1.10 wanden\TF A 10.01.41#3 A - lichte scheidingswand met gipsplaten Rw50dB.pdf
IfcElement - BB_Element_Lokaalnummer01: K.00.201
IfcRoot - Name: BB_10.01.41#03_Gipskartonwand_43dB_MS100 / 25.50.25, 100 mm
Qto_WallBaseQuantities - Length: 240; NetVolume: 0.06924; Height: 2885; Width: 100; GrossVolume: 0.06924; GrossSideArea: 0.6924; NetSideArea: 0.6924
Pset_Condition - AssessmentCondition: Empty
Pset_EnvironmentalImpactIndicators - Reference: BB_10.01.41#03_Gipskartonwand_43dB_MS100 / 25.50.25, 100 mm; sets with these values: 2
Pset_WallCommon - Reference: BB_10.01.41#03_Gipskartonwand_43dB_MS100 / 25.50.25, 100 mm; FireRating: EI60; IsExternal: yes; LoadBearing: no; ExtendToStructure: no

# IfcWall: Basic Wall_BB_10.01.41#03_Gipskartonwand_43dB_MS100 _ 25.50.25_ 100 mm37, Basic Wall:BB_10.01.41#03_Gipskartonwand_43dB_MS100 / 25.50.25, 100 mm:30128955
In: 000
PredefinedType: PARTITIONING
Cpset_Wall - LevelOfAccuracy: in te vullen door Buildwise
IfcBuildingStorey - Base Offset: 0; Top Offset: -930; Base Constraint: 000; Top Constraint: Up to level: 010
IfcClassificationReference - Keynote: 10.01.41#03; GVH_artnr 01: 10.01.41#03; GVH_artnr 02: geen waarde gevonden; GVH_artnr 03: geen waarde gevonden; GVH_artnr 04: geen waarde gevonden; GVH_artnr 05: geen waarde gevonden; GVH_artnr 06: geen waarde gevonden; TDS_link: .\05 As Builtdossier\2. Bouwkunde\2.1 Architectuur\2.1.10 wanden\TF A 10.01.41#3 A - lichte scheidingswand met gipsplaten Rw50dB.pdf
IfcRoot - Name: BB_10.01.41#03_Gipskartonwand_43dB_MS100 / 25.50.25, 100 mm
Qto_WallBaseQuantities - Length: 175; NetVolume: 0.046725; Height: 2670; Width: 100; GrossVolume: 0.046725; GrossSideArea: 0.46725; NetSideArea: 0.46725
Pset_Condition - AssessmentCondition: Empty
Pset_EnvironmentalImpactIndicators - Reference: BB_10.01.41#03_Gipskartonwand_43dB_MS100 / 25.50.25, 100 mm; sets with these values: 2
Pset_WallCommon - Reference: BB_10.01.41#03_Gipskartonwand_43dB_MS100 / 25.50.25, 100 mm; FireRating: EI60; IsExternal: yes; LoadBearing: no; ExtendToStructure: no

# IfcWall: Basic Wall_BB_10.01.41#03_Gipskartonwand_43dB_MS100 _ 25.50.25_ 100 mm39, Basic Wall:BB_10.01.41#03_Gipskartonwand_43dB_MS100 / 25.50.25, 100 mm:30133402
In: 000
PredefinedType: PARTITIONING
Cpset_Wall - LevelOfAccuracy: in te vullen door Buildwise
IfcBuildingStorey - Base Offset: 0; Top Offset: -960; Base Constraint: 000; Top Constraint: Up to level: 010
IfcClassificationReference - Keynote: 10.01.41#03; GVH_artnr 01: 10.01.41#03; GVH_artnr 02: geen waarde gevonden; GVH_artnr 03: geen waarde gevonden; GVH_artnr 04: geen waarde gevonden; GVH_artnr 05: geen waarde gevonden; GVH_artnr 06: geen waarde gevonden; TDS_link: .\05 As Builtdossier\2. Bouwkunde\2.1 Architectuur\2.1.10 wanden\TF A 10.01.41#3 A - lichte scheidingswand met gipsplaten Rw50dB.pdf
IfcRoot - Name: BB_10.01.41#03_Gipskartonwand_43dB_MS100 / 25.50.25, 100 mm
Qto_WallBaseQuantities - Length: 175; NetVolume: 0.0462; Height: 2640; Width: 100; GrossVolume: 0.0462; GrossSideArea: 0.462; NetSideArea: 0.462
Pset_Condition - AssessmentCondition: Empty
Pset_EnvironmentalImpactIndicators - Reference: BB_10.01.41#03_Gipskartonwand_43dB_MS100 / 25.50.25, 100 mm; sets with these values: 2
Pset_WallCommon - Reference: BB_10.01.41#03_Gipskartonwand_43dB_MS100 / 25.50.25, 100 mm; FireRating: EI60; IsExternal: yes; LoadBearing: no; ExtendToStructure: no

# IfcWall: Basic Wall_BB_10.01.41#03_Gipskartonwand_43dB_MS100 _ 25.50.25_ 100 mm41, Basic Wall:BB_10.01.41#03_Gipskartonwand_43dB_MS100 / 25.50.25, 100 mm:30775571
In: 000
PredefinedType: PARTITIONING
Cpset_Wall - LevelOfAccuracy: in te vullen door Buildwise
IfcBuildingStorey - Base Offset: 0; Top Offset: -930; Base Constraint: 000; Top Constraint: Up to level: 010
IfcClassificationReference - Keynote: 10.01.41#03; GVH_artnr 01: 10.01.41#03; GVH_artnr 02: geen waarde gevonden; GVH_artnr 03: geen waarde gevonden; GVH_artnr 04: geen waarde gevonden; GVH_artnr 05: geen waarde gevonden; GVH_artnr 06: geen waarde gevonden; TDS_link: .\05 As Builtdossier\2. Bouwkunde\2.1 Architectuur\2.1.10 wanden\TF A 10.01.41#3 A - lichte scheidingswand met gipsplaten Rw50dB.pdf
IfcRoot - Name: BB_10.01.41#03_Gipskartonwand_43dB_MS100 / 25.50.25, 100 mm
Qto_WallBaseQuantities - Length: 175; NetVolume: 0.046725; Height: 2670; Width: 100; GrossVolume: 0.046725; GrossSideArea: 0.46725; NetSideArea: 0.46725
Pset_Condition - AssessmentCondition: Empty
Pset_EnvironmentalImpactIndicators - Reference: BB_10.01.41#03_Gipskartonwand_43dB_MS100 / 25.50.25, 100 mm; sets with these values: 2
Pset_WallCommon - Reference: BB_10.01.41#03_Gipskartonwand_43dB_MS100 / 25.50.25, 100 mm; FireRating: EI60; IsExternal: yes; LoadBearing: no; ExtendToStructure: no

# IfcWall: Basic Wall_BB_10.01.41#03_Gipskartonwand_43dB_MS100 _ 25.50.25_ 100 mm43, Basic Wall:BB_10.01.41#03_Gipskartonwand_43dB_MS100 / 25.50.25, 100 mm:32128170
In: 000
PredefinedType: PARTITIONING
Cpset_Wall - LevelOfAccuracy: in te vullen door Buildwise
IfcBuildingStorey - Base Offset: 0; Top Offset: -960; Base Constraint: 000; Top Constraint: Up to level: 010
IfcClassificationReference - Keynote: 10.01.41#03; GVH_artnr 01: 10.01.41#03; GVH_artnr 02: geen waarde gevonden; GVH_artnr 03: geen waarde gevonden; GVH_artnr 04: geen waarde gevonden; GVH_artnr 05: geen waarde gevonden; GVH_artnr 06: geen waarde gevonden; TDS_link: .\05 As Builtdossier\2. Bouwkunde\2.1 Architectuur\2.1.10 wanden\TF A 10.01.41#3 A - lichte scheidingswand met gipsplaten Rw50dB.pdf
IfcRoot - Name: BB_10.01.41#03_Gipskartonwand_43dB_MS100 / 25.50.25, 100 mm
Qto_WallBaseQuantities - Length: 150; NetVolume: 0.0396; Height: 2640; Width: 100; GrossVolume: 0.0396; GrossSideArea: 0.396; NetSideArea: 0.396
Pset_Condition - AssessmentCondition: Empty
Pset_EnvironmentalImpactIndicators - Reference: BB_10.01.41#03_Gipskartonwand_43dB_MS100 / 25.50.25, 100 mm; sets with these values: 2
Pset_WallCommon - Reference: BB_10.01.41#03_Gipskartonwand_43dB_MS100 / 25.50.25, 100 mm; FireRating: EI60; IsExternal: yes; LoadBearing: no; ExtendToStructure: no

# IfcWall: Basic Wall_BB_10.01.41#03_Gipskartonwand_43dB_MS100 _ 25.50.25_ 100 mm45, Basic Wall:BB_10.01.41#03_Gipskartonwand_43dB_MS100 / 25.50.25, 100 mm:32128180
In: 000
PredefinedType: PARTITIONING
Cpset_Wall - LevelOfAccuracy: in te vullen door Buildwise
IfcBuildingStorey - Base Offset: 0; Top Offset: -960; Base Constraint: 000; Top Constraint: Up to level: 010
IfcClassificationReference - Keynote: 10.01.41#03; GVH_artnr 01: 10.01.41#03; GVH_artnr 02: geen waarde gevonden; GVH_artnr 03: geen waarde gevonden; GVH_artnr 04: geen waarde gevonden; GVH_artnr 05: geen waarde gevonden; GVH_artnr 06: geen waarde gevonden; TDS_link: .\05 As Builtdossier\2. Bouwkunde\2.1 Architectuur\2.1.10 wanden\TF A 10.01.41#3 A - lichte scheidingswand met gipsplaten Rw50dB.pdf
IfcRoot - Name: BB_10.01.41#03_Gipskartonwand_43dB_MS100 / 25.50.25, 100 mm
Qto_WallBaseQuantities - Length: 180; NetVolume: 0.04752; Height: 2640; Width: 100; GrossVolume: 0.04752; GrossSideArea: 0.4752; NetSideArea: 0.4752
Pset_Condition - AssessmentCondition: Empty
Pset_EnvironmentalImpactIndicators - Reference: BB_10.01.41#03_Gipskartonwand_43dB_MS100 / 25.50.25, 100 mm; sets with these values: 2
Pset_WallCommon - Reference: BB_10.01.41#03_Gipskartonwand_43dB_MS100 / 25.50.25, 100 mm; FireRating: EI60; IsExternal: yes; LoadBearing: no; ExtendToStructure: no

# IfcWall: Basic Wall_BB_10.01.41#03_Gipskartonwand_43dB_MS100 _ 25.50.25_ 100 mm47, Basic Wall:BB_10.01.41#03_Gipskartonwand_43dB_MS100 / 25.50.25, 100 mm:32128192
In: 000
PredefinedType: PARTITIONING
Cpset_Wall - LevelOfAccuracy: in te vullen door Buildwise
IfcBuildingStorey - Base Offset: 0; Top Offset: -960; Base Constraint: 000; Top Constraint: Up to level: 010
IfcClassificationReference - Keynote: 10.01.41#03; GVH_artnr 01: 10.01.41#03; GVH_artnr 02: geen waarde gevonden; GVH_artnr 03: geen waarde gevonden; GVH_artnr 04: geen waarde gevonden; GVH_artnr 05: geen waarde gevonden; GVH_artnr 06: geen waarde gevonden; TDS_link: .\05 As Builtdossier\2. Bouwkunde\2.1 Architectuur\2.1.10 wanden\TF A 10.01.41#3 A - lichte scheidingswand met gipsplaten Rw50dB.pdf
IfcRoot - Name: BB_10.01.41#03_Gipskartonwand_43dB_MS100 / 25.50.25, 100 mm
Qto_WallBaseQuantities - Length: 180; NetVolume: 0.04752; Height: 2640; Width: 100; GrossVolume: 0.04752; GrossSideArea: 0.4752; NetSideArea: 0.4752
Pset_Condition - AssessmentCondition: Empty
Pset_EnvironmentalImpactIndicators - Reference: BB_10.01.41#03_Gipskartonwand_43dB_MS100 / 25.50.25, 100 mm; sets with these values: 2
Pset_WallCommon - Reference: BB_10.01.41#03_Gipskartonwand_43dB_MS100 / 25.50.25, 100 mm; FireRating: EI60; IsExternal: yes; LoadBearing: no; ExtendToStructure: no

# IfcWall: Basic Wall_BB_10.01.41#03_Gipskartonwand_43dB_MS100 _ 25.50.25_ 100 mm49, Basic Wall:BB_10.01.41#03_Gipskartonwand_43dB_MS100 / 25.50.25, 100 mm:32128196
In: 000
PredefinedType: PARTITIONING
Cpset_Wall - LevelOfAccuracy: in te vullen door Buildwise
IfcBuildingStorey - Base Offset: 0; Top Offset: -960; Base Constraint: 000; Top Constraint: Up to level: 010
IfcClassificationReference - Keynote: 10.01.41#03; GVH_artnr 01: 10.01.41#03; GVH_artnr 02: geen waarde gevonden; GVH_artnr 03: geen waarde gevonden; GVH_artnr 04: geen waarde gevonden; GVH_artnr 05: geen waarde gevonden; GVH_artnr 06: geen waarde gevonden; TDS_link: .\05 As Builtdossier\2. Bouwkunde\2.1 Architectuur\2.1.10 wanden\TF A 10.01.41#3 A - lichte scheidingswand met gipsplaten Rw50dB.pdf
IfcRoot - Name: BB_10.01.41#03_Gipskartonwand_43dB_MS100 / 25.50.25, 100 mm
Qto_WallBaseQuantities - Length: 180; NetVolume: 0.04752; Height: 2640; Width: 100; GrossVolume: 0.04752; GrossSideArea: 0.4752; NetSideArea: 0.4752
Pset_Condition - AssessmentCondition: Empty
Pset_EnvironmentalImpactIndicators - Reference: BB_10.01.41#03_Gipskartonwand_43dB_MS100 / 25.50.25, 100 mm; sets with these values: 2
Pset_WallCommon - Reference: BB_10.01.41#03_Gipskartonwand_43dB_MS100 / 25.50.25, 100 mm; FireRating: EI60; IsExternal: yes; LoadBearing: no; ExtendToStructure: no

# IfcWall: Basic Wall_BB_10.01.41#03_Gipskartonwand_43dB_MS100 _ 25.50.25_ 100 mm5, Basic Wall:BB_10.01.41#03_Gipskartonwand_43dB_MS100 / 25.50.25, 100 mm:13048374
In: 000
PredefinedType: PARTITIONING
Cpset_Wall - LevelOfAccuracy: in te vullen door Buildwise
IfcBuildingStorey - Base Offset: -200; Top Offset: -600; Base Constraint: 000; Top Constraint: Up to level: 010
IfcClassificationReference - Keynote: 10.01.41#03; GVH_artnr 01: 10.01.41#03; GVH_artnr 02: geen waarde gevonden; GVH_artnr 03: geen waarde gevonden; GVH_artnr 04: geen waarde gevonden; GVH_artnr 05: geen waarde gevonden; GVH_artnr 06: geen waarde gevonden; TDS_link: .\05 As Builtdossier\2. Bouwkunde\2.1 Architectuur\2.1.10 wanden\TF A 10.01.41#3 A - lichte scheidingswand met gipsplaten Rw50dB.pdf
IfcElement - BB_Element_Lokaalnummer01: K.00.113
IfcRoot - Name: BB_10.01.41#03_Gipskartonwand_43dB_MS100 / 25.50.25, 100 mm
Qto_WallBaseQuantities - Length: 5444.87; NetVolume: 1.72236; Height: 3200; Width: 100; GrossVolume: 1.72236; GrossSideArea: 17.2236; NetSideArea: 17.2236
Pset_Condition - AssessmentCondition: Empty
Pset_EnvironmentalImpactIndicators - Reference: BB_10.01.41#03_Gipskartonwand_43dB_MS100 / 25.50.25, 100 mm; sets with these values: 2
Pset_WallCommon - Reference: BB_10.01.41#03_Gipskartonwand_43dB_MS100 / 25.50.25, 100 mm; FireRating: EI60; IsExternal: yes; LoadBearing: no; ExtendToStructure: no

# IfcWall: Basic Wall_BB_10.01.41#03_Gipskartonwand_43dB_MS100 _ 25.50.25_ 100 mm51, Basic Wall:BB_10.01.41#03_Gipskartonwand_43dB_MS100 / 25.50.25, 100 mm:32129696
In: 000
PredefinedType: PARTITIONING
Cpset_Wall - LevelOfAccuracy: in te vullen door Buildwise
IfcBuildingStorey - Base Offset: 0; Top Offset: -930; Base Constraint: 000; Top Constraint: Up to level: 010
IfcClassificationReference - Keynote: 10.01.41#03; GVH_artnr 01: 10.01.41#03; GVH_artnr 02: geen waarde gevonden; GVH_artnr 03: geen waarde gevonden; GVH_artnr 04: geen waarde gevonden; GVH_artnr 05: geen waarde gevonden; GVH_artnr 06: geen waarde gevonden; TDS_link: .\05 As Builtdossier\2. Bouwkunde\2.1 Architectuur\2.1.10 wanden\TF A 10.01.41#3 A - lichte scheidingswand met gipsplaten Rw50dB.pdf
IfcRoot - Name: BB_10.01.41#03_Gipskartonwand_43dB_MS100 / 25.50.25, 100 mm
Qto_WallBaseQuantities - Length: 175; NetVolume: 0.046725; Height: 2670; Width: 100; GrossVolume: 0.046725; GrossSideArea: 0.46725; NetSideArea: 0.46725
Pset_Condition - AssessmentCondition: Empty
Pset_EnvironmentalImpactIndicators - Reference: BB_10.01.41#03_Gipskartonwand_43dB_MS100 / 25.50.25, 100 mm; sets with these values: 2
Pset_WallCommon - Reference: BB_10.01.41#03_Gipskartonwand_43dB_MS100 / 25.50.25, 100 mm; FireRating: EI60; IsExternal: yes; LoadBearing: no; ExtendToStructure: no

# IfcWall: Basic Wall_BB_10.01.41#03_Gipskartonwand_43dB_MS100 _ 25.50.25_ 100 mm53, Basic Wall:BB_10.01.41#03_Gipskartonwand_43dB_MS100 / 25.50.25, 100 mm:13000863
In: 010
PredefinedType: PARTITIONING
Cpset_Wall - LevelOfAccuracy: in te vullen door Buildwise
IfcBuildingStorey - Base Offset: 2640; Top Offset: 3010; Base Constraint: 010; Top Constraint: Up to level: 010
IfcClassificationReference - Keynote: 10.01.41#03; GVH_artnr 01: 10.01.41#03; GVH_artnr 02: geen waarde gevonden; GVH_artnr 03: geen waarde gevonden; GVH_artnr 04: geen waarde gevonden; GVH_artnr 05: geen waarde gevonden; GVH_artnr 06: geen waarde gevonden; TDS_link: .\05 As Builtdossier\2. Bouwkunde\2.1 Architectuur\2.1.10 wanden\TF A 10.01.41#3 A - lichte scheidingswand met gipsplaten Rw50dB.pdf
IfcElement - BB_Element_Lokaalnummer01: K.10.511
IfcRoot - Name: BB_10.01.41#03_Gipskartonwand_43dB_MS100 / 25.50.25, 100 mm
Qto_WallBaseQuantities - Length: 300; NetVolume: 0.0111; Height: 370; Width: 100; GrossVolume: 0.0111; GrossSideArea: 0.111; NetSideArea: 0.111
Pset_Condition - AssessmentCondition: Empty
Pset_EnvironmentalImpactIndicators - Reference: BB_10.01.41#03_Gipskartonwand_43dB_MS100 / 25.50.25, 100 mm; sets with these values: 2
Pset_WallCommon - Reference: BB_10.01.41#03_Gipskartonwand_43dB_MS100 / 25.50.25, 100 mm; FireRating: EI60; IsExternal: yes; LoadBearing: no; ExtendToStructure: no

# IfcWall: Basic Wall_BB_10.01.41#03_Gipskartonwand_43dB_MS100 _ 25.50.25_ 100 mm55, Basic Wall:BB_10.01.41#03_Gipskartonwand_43dB_MS100 / 25.50.25, 100 mm:16195302
In: 010
PredefinedType: PARTITIONING
Cpset_Wall - LevelOfAccuracy: in te vullen door Buildwise
IfcBuildingStorey - Base Offset: -5; Top Offset: -600; Base Constraint: 010; Top Constraint: Up to level: 020
IfcClassificationReference - Keynote: 10.01.41#03; GVH_artnr 01: 10.01.41#03; GVH_artnr 02: geen waarde gevonden; GVH_artnr 03: geen waarde gevonden; GVH_artnr 04: geen waarde gevonden; GVH_artnr 05: geen waarde gevonden; GVH_artnr 06: geen waarde gevonden; TDS_link: .\05 As Builtdossier\2. Bouwkunde\2.1 Architectuur\2.1.10 wanden\TF A 10.01.41#3 A - lichte scheidingswand met gipsplaten Rw50dB.pdf
IfcElement - BB_Element_Lokaalnummer01: K.10.206
IfcRoot - Name: BB_10.01.41#03_Gipskartonwand_43dB_MS100 / 25.50.25, 100 mm
Qto_WallBaseQuantities - Length: 161; NetVolume: 0.0634055; Height: 3005; Width: 100; GrossVolume: 0.0634055; GrossSideArea: 0.634055; NetSideArea: 0.634055
Pset_Condition - AssessmentCondition: Empty
Pset_EnvironmentalImpactIndicators - Reference: BB_10.01.41#03_Gipskartonwand_43dB_MS100 / 25.50.25, 100 mm; sets with these values: 2
Pset_WallCommon - Reference: BB_10.01.41#03_Gipskartonwand_43dB_MS100 / 25.50.25, 100 mm; FireRating: EI60; IsExternal: yes; LoadBearing: no; ExtendToStructure: no

# IfcWall: Basic Wall_BB_10.01.41#03_Gipskartonwand_43dB_MS100 _ 25.50.25_ 100 mm57, Basic Wall:BB_10.01.41#03_Gipskartonwand_43dB_MS100 / 25.50.25, 100 mm:25595272
In: 010
PredefinedType: PARTITIONING
Cpset_Wall - LevelOfAccuracy: in te vullen door Buildwise
IfcBuildingStorey - Base Offset: 2640; Top Offset: 3010; Base Constraint: 010; Top Constraint: Up to level: 010
IfcClassificationReference - Keynote: 10.01.41#03; GVH_artnr 01: 10.01.41#03; GVH_artnr 02: geen waarde gevonden; GVH_artnr 03: geen waarde gevonden; GVH_artnr 04: geen waarde gevonden; GVH_artnr 05: geen waarde gevonden; GVH_artnr 06: geen waarde gevonden; TDS_link: .\05 As Builtdossier\2. Bouwkunde\2.1 Architectuur\2.1.10 wanden\TF A 10.01.41#3 A - lichte scheidingswand met gipsplaten Rw50dB.pdf
IfcElement - BB_Element_Lokaalnummer01: K.10.511
IfcRoot - Name: BB_10.01.41#03_Gipskartonwand_43dB_MS100 / 25.50.25, 100 mm
Qto_WallBaseQuantities - Length: 5080; NetVolume: 0.18611; Height: 370; Width: 100; GrossVolume: 0.18611; GrossSideArea: 1.8611; NetSideArea: 1.8611
Pset_Condition - AssessmentCondition: Empty
Pset_EnvironmentalImpactIndicators - Reference: BB_10.01.41#03_Gipskartonwand_43dB_MS100 / 25.50.25, 100 mm; sets with these values: 2
Pset_WallCommon - Reference: BB_10.01.41#03_Gipskartonwand_43dB_MS100 / 25.50.25, 100 mm; FireRating: EI60; IsExternal: yes; LoadBearing: no; ExtendToStructure: no

# IfcWall: Basic Wall_BB_10.01.41#03_Gipskartonwand_43dB_MS100 _ 25.50.25_ 100 mm59, Basic Wall:BB_10.01.41#03_Gipskartonwand_43dB_MS100 / 25.50.25, 100 mm:12557879
In: 020
PredefinedType: PARTITIONING
Cpset_Wall - LevelOfAccuracy: in te vullen door Buildwise
IfcBuildingStorey - Base Offset: 0; Top Offset: -600; Base Constraint: 020; Top Constraint: Up to level: 030
IfcClassificationReference - Keynote: 10.01.41#03; GVH_artnr 01: 10.01.41#03; GVH_artnr 02: geen waarde gevonden; GVH_artnr 03: geen waarde gevonden; GVH_artnr 04: geen waarde gevonden; GVH_artnr 05: geen waarde gevonden; GVH_artnr 06: geen waarde gevonden; TDS_link: .\05 As Builtdossier\2. Bouwkunde\2.1 Architectuur\2.1.10 wanden\TF A 10.01.41#3 A - lichte scheidingswand met gipsplaten Rw50dB.pdf
IfcElement - BB_Element_Lokaalnummer01: K.20.511
IfcRoot - Name: BB_10.01.41#03_Gipskartonwand_43dB_MS100 / 25.50.25, 100 mm
Qto_WallBaseQuantities - Length: 5210; NetVolume: 1.35576; Height: 3000; Width: 100; GrossVolume: 1.35576; GrossSideArea: 13.5576; NetSideArea: 13.5576
Pset_Condition - AssessmentCondition: Empty
Pset_EnvironmentalImpactIndicators - Reference: BB_10.01.41#03_Gipskartonwand_43dB_MS100 / 25.50.25, 100 mm; sets with these values: 2
Pset_WallCommon - Reference: BB_10.01.41#03_Gipskartonwand_43dB_MS100 / 25.50.25, 100 mm; FireRating: EI60; IsExternal: yes; LoadBearing: no; ExtendToStructure: no

# IfcWall: Basic Wall_BB_10.01.41#03_Gipskartonwand_43dB_MS100 _ 25.50.25_ 100 mm61, Basic Wall:BB_10.01.41#03_Gipskartonwand_43dB_MS100 / 25.50.25, 100 mm:12558186
In: 020
PredefinedType: PARTITIONING
Cpset_Wall - LevelOfAccuracy: in te vullen door Buildwise
IfcBuildingStorey - Base Offset: -5; Top Offset: -600; Base Constraint: 020; Top Constraint: Up to level: 030
IfcClassificationReference - Keynote: 10.01.41#03; GVH_artnr 01: 10.01.41#03; GVH_artnr 02: geen waarde gevonden; GVH_artnr 03: geen waarde gevonden; GVH_artnr 04: geen waarde gevonden; GVH_artnr 05: geen waarde gevonden; GVH_artnr 06: geen waarde gevonden; TDS_link: .\05 As Builtdossier\2. Bouwkunde\2.1 Architectuur\2.1.10 wanden\TF A 10.01.41#3 A - lichte scheidingswand met gipsplaten Rw50dB.pdf
IfcElement - BB_Element_Lokaalnummer01: K.20.102
IfcRoot - Name: BB_10.01.41#03_Gipskartonwand_43dB_MS100 / 25.50.25, 100 mm
Qto_WallBaseQuantities - Length: 5210; NetVolume: 1.37292; Height: 3005; Width: 100; GrossVolume: 1.37292; GrossSideArea: 13.7292; NetSideArea: 13.7292
Pset_Condition - AssessmentCondition: Empty
Pset_EnvironmentalImpactIndicators - Reference: BB_10.01.41#03_Gipskartonwand_43dB_MS100 / 25.50.25, 100 mm; sets with these values: 2
Pset_WallCommon - Reference: BB_10.01.41#03_Gipskartonwand_43dB_MS100 / 25.50.25, 100 mm; IsExternal: yes; LoadBearing: no; ExtendToStructure: no

# IfcWall: Basic Wall_BB_10.01.41#03_Gipskartonwand_43dB_MS100 _ 25.50.25_ 100 mm63, Basic Wall:BB_10.01.41#03_Gipskartonwand_43dB_MS100 / 25.50.25, 100 mm:25615250
In: 020
PredefinedType: PARTITIONING
Cpset_Wall - LevelOfAccuracy: in te vullen door Buildwise
IfcBuildingStorey - Base Offset: 0; Top Offset: -600; Base Constraint: 020; Top Constraint: Up to level: 030
IfcClassificationReference - Keynote: 10.01.41#03; GVH_artnr 01: 10.01.41#03; GVH_artnr 02: geen waarde gevonden; GVH_artnr 03: geen waarde gevonden; GVH_artnr 04: geen waarde gevonden; GVH_artnr 05: geen waarde gevonden; GVH_artnr 06: geen waarde gevonden; TDS_link: .\05 As Builtdossier\2. Bouwkunde\2.1 Architectuur\2.1.10 wanden\TF A 10.01.41#3 A - lichte scheidingswand met gipsplaten Rw50dB.pdf
IfcElement - BB_Element_Lokaalnummer01: K.20.513
IfcRoot - Name: BB_10.01.41#03_Gipskartonwand_43dB_MS100 / 25.50.25, 100 mm
Qto_WallBaseQuantities - Length: 5230; NetVolume: 1.5786; Height: 3000; Width: 100; GrossVolume: 1.5786; GrossSideArea: 15.786; NetSideArea: 15.786
Pset_Condition - AssessmentCondition: Empty
Pset_EnvironmentalImpactIndicators - Reference: BB_10.01.41#03_Gipskartonwand_43dB_MS100 / 25.50.25, 100 mm; sets with these values: 2
Pset_WallCommon - Reference: BB_10.01.41#03_Gipskartonwand_43dB_MS100 / 25.50.25, 100 mm; FireRating: EI60; IsExternal: yes; LoadBearing: no; ExtendToStructure: no

# IfcWall: Basic Wall_BB_10.01.41#03_Gipskartonwand_43dB_MS100 _ 25.50.25_ 100 mm65, Basic Wall:BB_10.01.41#03_Gipskartonwand_43dB_MS100 / 25.50.25, 100 mm:12554260
In: 030
PredefinedType: PARTITIONING
Cpset_Wall - LevelOfAccuracy: in te vullen door Buildwise
IfcBuildingStorey - Base Offset: -200; Top Offset: 3000; Base Constraint: 030; Top Constraint: Up to level: 030
IfcClassificationReference - Keynote: 10.01.41#03; GVH_artnr 01: 10.01.41#03; GVH_artnr 02: geen waarde gevonden; GVH_artnr 03: geen waarde gevonden; GVH_artnr 04: geen waarde gevonden; GVH_artnr 05: geen waarde gevonden; GVH_artnr 06: geen waarde gevonden; TDS_link: .\05 As Builtdossier\2. Bouwkunde\2.1 Architectuur\2.1.10 wanden\TF A 10.01.41#3 A - lichte scheidingswand met gipsplaten Rw50dB.pdf
IfcElement - BB_Element_Lokaalnummer01: K.30.511
IfcRoot - Name: BB_10.01.41#03_Gipskartonwand_43dB_MS100 / 25.50.25, 100 mm
Qto_WallBaseQuantities - Length: 2565.77; NetVolume: 0.798418; Height: 3200; Width: 100; GrossVolume: 0.814418; GrossSideArea: 8.14418; NetSideArea: 8.14418
Pset_Condition - AssessmentCondition: Empty
Pset_EnvironmentalImpactIndicators - Reference: BB_10.01.41#03_Gipskartonwand_43dB_MS100 / 25.50.25, 100 mm; sets with these values: 2
Pset_WallCommon - Reference: BB_10.01.41#03_Gipskartonwand_43dB_MS100 / 25.50.25, 100 mm; FireRating: EI60; IsExternal: yes; LoadBearing: no; ExtendToStructure: no

# IfcWall: Basic Wall_BB_10.01.41#03_Gipskartonwand_43dB_MS100 _ 25.50.25_ 100 mm67, Basic Wall:BB_10.01.41#03_Gipskartonwand_43dB_MS100 / 25.50.25, 100 mm:12554303
In: 030
PredefinedType: PARTITIONING
Cpset_Wall - LevelOfAccuracy: in te vullen door Buildwise
IfcBuildingStorey - Base Offset: -200; Top Offset: 3140; Base Constraint: 030; Top Constraint: Up to level: 030
IfcClassificationReference - Keynote: 10.01.41#03; GVH_artnr 01: 10.01.41#03; GVH_artnr 02: geen waarde gevonden; GVH_artnr 03: geen waarde gevonden; GVH_artnr 04: geen waarde gevonden; GVH_artnr 05: geen waarde gevonden; GVH_artnr 06: geen waarde gevonden; TDS_link: .\05 As Builtdossier\2. Bouwkunde\2.1 Architectuur\2.1.10 wanden\TF A 10.01.41#3 A - lichte scheidingswand met gipsplaten Rw50dB.pdf
IfcElement - BB_Element_Lokaalnummer01: K.30.511
IfcRoot - Name: BB_10.01.41#03_Gipskartonwand_43dB_MS100 / 25.50.25, 100 mm
Qto_WallBaseQuantities - Length: 10688.4; NetVolume: 3.16589; Height: 3340; Width: 100; GrossVolume: 3.56707; GrossSideArea: 35.6707; NetSideArea: 31.8259
Pset_Condition - AssessmentCondition: Empty
Pset_EnvironmentalImpactIndicators - Reference: BB_10.01.41#03_Gipskartonwand_43dB_MS100 / 25.50.25, 100 mm; sets with these values: 2
Pset_WallCommon - Reference: BB_10.01.41#03_Gipskartonwand_43dB_MS100 / 25.50.25, 100 mm; FireRating: EI60; IsExternal: yes; LoadBearing: no; ExtendToStructure: no

# IfcWall: Basic Wall_BB_10.01.41#03_Gipskartonwand_43dB_MS100 _ 25.50.25_ 100 mm69, Basic Wall:BB_10.01.41#03_Gipskartonwand_43dB_MS100 / 25.50.25, 100 mm:12557085
In: 030
PredefinedType: PARTITIONING
Cpset_Wall - LevelOfAccuracy: in te vullen door Buildwise
IfcBuildingStorey - Base Offset: 0; Top Offset: 2490; Base Constraint: 030; Top Constraint: Up to level: 030
IfcClassificationReference - Keynote: 10.01.41#03; GVH_artnr 01: 10.01.41#03; GVH_artnr 02: geen waarde gevonden; GVH_artnr 03: geen waarde gevonden; GVH_artnr 04: geen waarde gevonden; GVH_artnr 05: geen waarde gevonden; GVH_artnr 06: geen waarde gevonden; TDS_link: .\05 As Builtdossier\2. Bouwkunde\2.1 Architectuur\2.1.10 wanden\TF A 10.01.41#3 A - lichte scheidingswand met gipsplaten Rw50dB.pdf
IfcElement - BB_Element_Lokaalnummer01: K.30.202
IfcRoot - Name: BB_10.01.41#03_Gipskartonwand_43dB_MS100 / 25.50.25, 100 mm
Qto_WallBaseQuantities - Length: 1886; NetVolume: 0.140534; Height: 2490; Width: 100; GrossVolume: 0.140534; GrossSideArea: 1.40534; NetSideArea: 1.40534
Pset_Condition - AssessmentCondition: Empty
Pset_EnvironmentalImpactIndicators - Reference: BB_10.01.41#03_Gipskartonwand_43dB_MS100 / 25.50.25, 100 mm; sets with these values: 2
Pset_WallCommon - Reference: BB_10.01.41#03_Gipskartonwand_43dB_MS100 / 25.50.25, 100 mm; FireRating: EI60; IsExternal: yes; LoadBearing: no; ExtendToStructure: no

# IfcWall: Basic Wall_BB_10.01.41#03_Gipskartonwand_43dB_MS100 _ 25.50.25_ 100 mm7, Basic Wall:BB_10.01.41#03_Gipskartonwand_43dB_MS100 / 25.50.25, 100 mm:13059307
In: 000
PredefinedType: PARTITIONING
Cpset_Wall - LevelOfAccuracy: in te vullen door Buildwise
IfcBuildingStorey - Base Offset: -200; Top Offset: -920; Base Constraint: 000; Top Constraint: Up to level: 010
IfcClassificationReference - Keynote: 10.01.41#03; GVH_artnr 01: 10.01.41#03; GVH_artnr 02: geen waarde gevonden; GVH_artnr 03: geen waarde gevonden; GVH_artnr 04: geen waarde gevonden; GVH_artnr 05: geen waarde gevonden; GVH_artnr 06: geen waarde gevonden; TDS_link: .\05 As Builtdossier\2. Bouwkunde\2.1 Architectuur\2.1.10 wanden\TF A 10.01.41#3 A - lichte scheidingswand met gipsplaten Rw50dB.pdf
IfcElement - BB_Element_Lokaalnummer01: K.00.112
IfcRoot - Name: BB_10.01.41#03_Gipskartonwand_43dB_MS100 / 25.50.25, 100 mm
Qto_WallBaseQuantities - Length: 240; NetVolume: 0.06912; Height: 2880; Width: 100; GrossVolume: 0.06912; GrossSideArea: 0.6912; NetSideArea: 0.6912
Pset_Condition - AssessmentCondition: Empty
Pset_EnvironmentalImpactIndicators - Reference: BB_10.01.41#03_Gipskartonwand_43dB_MS100 / 25.50.25, 100 mm; sets with these values: 2
Pset_WallCommon - Reference: BB_10.01.41#03_Gipskartonwand_43dB_MS100 / 25.50.25, 100 mm; FireRating: EI60; IsExternal: yes; LoadBearing: no; ExtendToStructure: no

# IfcWall: Basic Wall_BB_10.01.41#03_Gipskartonwand_43dB_MS100 _ 25.50.25_ 100 mm71, Basic Wall:BB_10.01.41#03_Gipskartonwand_43dB_MS100 / 25.50.25, 100 mm:12606900
In: 030
PredefinedType: PARTITIONING
Cpset_Wall - LevelOfAccuracy: in te vullen door Buildwise
IfcBuildingStorey - Base Offset: 0; Top Offset: -460; Base Constraint: 030; Top Constraint: Up to level: 040
IfcClassificationReference - Keynote: 10.01.41#03; GVH_artnr 01: 10.01.41#03; GVH_artnr 02: geen waarde gevonden; GVH_artnr 03: geen waarde gevonden; GVH_artnr 04: geen waarde gevonden; GVH_artnr 05: geen waarde gevonden; GVH_artnr 06: geen waarde gevonden; TDS_link: .\05 As Builtdossier\2. Bouwkunde\2.1 Architectuur\2.1.10 wanden\TF A 10.01.41#3 A - lichte scheidingswand met gipsplaten Rw50dB.pdf
IfcRoot - Name: BB_10.01.41#03_Gipskartonwand_43dB_MS100 / 25.50.25, 100 mm
Qto_WallBaseQuantities - Length: 5400; NetVolume: 1.1328; Height: 3140; Width: 100; GrossVolume: 1.1328; GrossSideArea: 11.328; NetSideArea: 11.328
Pset_Condition - AssessmentCondition: Empty
Pset_EnvironmentalImpactIndicators - Reference: BB_10.01.41#03_Gipskartonwand_43dB_MS100 / 25.50.25, 100 mm; sets with these values: 2
Pset_WallCommon - Reference: BB_10.01.41#03_Gipskartonwand_43dB_MS100 / 25.50.25, 100 mm; FireRating: EI60; IsExternal: yes; LoadBearing: no; ExtendToStructure: no

# IfcWall: Basic Wall_BB_10.01.41#03_Gipskartonwand_43dB_MS100 _ 25.50.25_ 100 mm73, Basic Wall:BB_10.01.41#03_Gipskartonwand_43dB_MS100 / 25.50.25, 100 mm:12709500
In: 030
PredefinedType: PARTITIONING
Cpset_Wall - LevelOfAccuracy: in te vullen door Buildwise
IfcBuildingStorey - Base Offset: 0; Top Offset: -600; Base Constraint: 030; Top Constraint: Up to level: 040
IfcClassificationReference - Keynote: 10.01.41#03; GVH_artnr 01: 10.01.41#03; GVH_artnr 02: geen waarde gevonden; GVH_artnr 03: geen waarde gevonden; GVH_artnr 04: geen waarde gevonden; GVH_artnr 05: geen waarde gevonden; GVH_artnr 06: geen waarde gevonden; TDS_link: .\05 As Builtdossier\2. Bouwkunde\2.1 Architectuur\2.1.10 wanden\TF A 10.01.41#3 A - lichte scheidingswand met gipsplaten Rw50dB.pdf
IfcRoot - Name: BB_10.01.41#03_Gipskartonwand_43dB_MS100 / 25.50.25, 100 mm
Qto_WallBaseQuantities - Length: 5230; NetVolume: 1.57827; Height: 3000; Width: 100; GrossVolume: 1.57827; GrossSideArea: 15.7827; NetSideArea: 15.7827
Pset_Condition - AssessmentCondition: Empty
Pset_EnvironmentalImpactIndicators - Reference: BB_10.01.41#03_Gipskartonwand_43dB_MS100 / 25.50.25, 100 mm; sets with these values: 2
Pset_WallCommon - Reference: BB_10.01.41#03_Gipskartonwand_43dB_MS100 / 25.50.25, 100 mm; FireRating: EI60; IsExternal: yes; LoadBearing: no; ExtendToStructure: no

# IfcWall: Basic Wall_BB_10.01.41#03_Gipskartonwand_43dB_MS100 _ 25.50.25_ 100 mm75, Basic Wall:BB_10.01.41#03_Gipskartonwand_43dB_MS100 / 25.50.25, 100 mm:12711428
In: 030
PredefinedType: PARTITIONING
Cpset_Wall - LevelOfAccuracy: in te vullen door Buildwise
IfcBuildingStorey - Base Offset: 0; Top Offset: 0; Base Constraint: 030
IfcClassificationReference - Keynote: 10.01.41#03; GVH_artnr 01: 10.01.41#03; GVH_artnr 02: geen waarde gevonden; GVH_artnr 03: geen waarde gevonden; GVH_artnr 04: geen waarde gevonden; GVH_artnr 05: geen waarde gevonden; GVH_artnr 06: geen waarde gevonden; TDS_link: .\05 As Builtdossier\2. Bouwkunde\2.1 Architectuur\2.1.10 wanden\TF A 10.01.41#3 A - lichte scheidingswand met gipsplaten Rw50dB.pdf
IfcRoot - Name: BB_10.01.41#03_Gipskartonwand_43dB_MS100 / 25.50.25, 100 mm
Qto_WallBaseQuantities - Length: 5575; NetVolume: 1.67768; Height: 3140; Width: 100; GrossVolume: 1.67768; GrossSideArea: 16.7768; NetSideArea: 16.7768
Pset_Condition - AssessmentCondition: Empty
Pset_EnvironmentalImpactIndicators - Reference: BB_10.01.41#03_Gipskartonwand_43dB_MS100 / 25.50.25, 100 mm; sets with these values: 2
Pset_WallCommon - Reference: BB_10.01.41#03_Gipskartonwand_43dB_MS100 / 25.50.25, 100 mm; FireRating: EI60; IsExternal: yes; LoadBearing: no; ExtendToStructure: no

# IfcWall: Basic Wall_BB_10.01.41#03_Gipskartonwand_43dB_MS100 _ 25.50.25_ 100 mm77, Basic Wall:BB_10.01.41#03_Gipskartonwand_43dB_MS100 / 25.50.25, 100 mm:12711437
In: 030
PredefinedType: PARTITIONING
Cpset_Wall - LevelOfAccuracy: in te vullen door Buildwise
IfcBuildingStorey - Base Offset: 0; Top Offset: 0; Base Constraint: 030
IfcClassificationReference - Keynote: 10.01.41#03; GVH_artnr 01: 10.01.41#03; GVH_artnr 02: geen waarde gevonden; GVH_artnr 03: geen waarde gevonden; GVH_artnr 04: geen waarde gevonden; GVH_artnr 05: geen waarde gevonden; GVH_artnr 06: geen waarde gevonden; TDS_link: .\05 As Builtdossier\2. Bouwkunde\2.1 Architectuur\2.1.10 wanden\TF A 10.01.41#3 A - lichte scheidingswand met gipsplaten Rw50dB.pdf
IfcRoot - Name: BB_10.01.41#03_Gipskartonwand_43dB_MS100 / 25.50.25, 100 mm
Qto_WallBaseQuantities - Length: 6915; NetVolume: 1.65031; Height: 3000; Width: 100; GrossVolume: 1.65031; GrossSideArea: 16.5031; NetSideArea: 16.5031
Pset_Condition - AssessmentCondition: Empty
Pset_EnvironmentalImpactIndicators - Reference: BB_10.01.41#03_Gipskartonwand_43dB_MS100 / 25.50.25, 100 mm; sets with these values: 2
Pset_WallCommon - Reference: BB_10.01.41#03_Gipskartonwand_43dB_MS100 / 25.50.25, 100 mm; FireRating: EI60; IsExternal: yes; LoadBearing: no; ExtendToStructure: no

# IfcWall: Basic Wall_BB_10.01.41#03_Gipskartonwand_43dB_MS100 _ 25.50.25_ 100 mm79, Basic Wall:BB_10.01.41#03_Gipskartonwand_43dB_MS100 / 25.50.25, 100 mm:12919951
In: 030
PredefinedType: PARTITIONING
Cpset_Wall - LevelOfAccuracy: in te vullen door Buildwise
IfcBuildingStorey - Base Offset: 0; Top Offset: -600; Base Constraint: 030; Top Constraint: Up to level: 040
IfcClassificationReference - Keynote: 10.01.41#03; GVH_artnr 01: 10.01.41#03; GVH_artnr 02: geen waarde gevonden; GVH_artnr 03: geen waarde gevonden; GVH_artnr 04: geen waarde gevonden; GVH_artnr 05: geen waarde gevonden; GVH_artnr 06: geen waarde gevonden; TDS_link: .\05 As Builtdossier\2. Bouwkunde\2.1 Architectuur\2.1.10 wanden\TF A 10.01.41#3 A - lichte scheidingswand met gipsplaten Rw50dB.pdf
IfcElement - BB_Element_Lokaalnummer01: K.30.112
IfcRoot - Name: BB_10.01.41#03_Gipskartonwand_43dB_MS100 / 25.50.25, 100 mm
Qto_WallBaseQuantities - Length: 16077.5; NetVolume: 4.39681; Height: 3140; Width: 100; GrossVolume: 4.39681; GrossSideArea: 43.9681; NetSideArea: 43.9681
Pset_Condition - AssessmentCondition: Empty
Pset_EnvironmentalImpactIndicators - Reference: BB_10.01.41#03_Gipskartonwand_43dB_MS100 / 25.50.25, 100 mm; sets with these values: 2
Pset_WallCommon - Reference: BB_10.01.41#03_Gipskartonwand_43dB_MS100 / 25.50.25, 100 mm; FireRating: EI60; IsExternal: yes; LoadBearing: no; ExtendToStructure: no

# IfcWall: Basic Wall_BB_10.01.41#03_Gipskartonwand_43dB_MS100 _ 25.50.25_ 100 mm81, Basic Wall:BB_10.01.41#03_Gipskartonwand_43dB_MS100 / 25.50.25, 100 mm:13300478
In: 030
PredefinedType: PARTITIONING
Cpset_Wall - LevelOfAccuracy: in te vullen door Buildwise
IfcBuildingStorey - Base Offset: 0; Top Offset: 0; Base Constraint: 030
IfcClassificationReference - Keynote: 10.01.41#03; GVH_artnr 01: 10.01.41#03; GVH_artnr 02: geen waarde gevonden; GVH_artnr 03: geen waarde gevonden; GVH_artnr 04: geen waarde gevonden; GVH_artnr 05: geen waarde gevonden; GVH_artnr 06: geen waarde gevonden; TDS_link: .\05 As Builtdossier\2. Bouwkunde\2.1 Architectuur\2.1.10 wanden\TF A 10.01.41#3 A - lichte scheidingswand met gipsplaten Rw50dB.pdf
IfcRoot - Name: BB_10.01.41#03_Gipskartonwand_43dB_MS100 / 25.50.25, 100 mm
Qto_WallBaseQuantities - Length: 5230; NetVolume: 1.61862; Height: 3140; Width: 100; GrossVolume: 1.61862; GrossSideArea: 16.1862; NetSideArea: 16.1862
Pset_Condition - AssessmentCondition: Empty
Pset_EnvironmentalImpactIndicators - Reference: BB_10.01.41#03_Gipskartonwand_43dB_MS100 / 25.50.25, 100 mm; sets with these values: 2
Pset_WallCommon - Reference: BB_10.01.41#03_Gipskartonwand_43dB_MS100 / 25.50.25, 100 mm; FireRating: EI60; IsExternal: yes; LoadBearing: no; ExtendToStructure: no

# IfcWall: Basic Wall_BB_10.01.41#03_Gipskartonwand_43dB_MS100 _ 25.50.25_ 100 mm83, Basic Wall:BB_10.01.41#03_Gipskartonwand_43dB_MS100 / 25.50.25, 100 mm:13691004
In: 030
PredefinedType: PARTITIONING
Cpset_Wall - LevelOfAccuracy: in te vullen door Buildwise
IfcBuildingStorey - Base Offset: 0; Top Offset: -600; Base Constraint: 030; Top Constraint: Up to level: 040
IfcClassificationReference - Keynote: 10.01.41#03; GVH_artnr 01: 10.01.41#03; GVH_artnr 02: geen waarde gevonden; GVH_artnr 03: geen waarde gevonden; GVH_artnr 04: geen waarde gevonden; GVH_artnr 05: geen waarde gevonden; GVH_artnr 06: geen waarde gevonden; TDS_link: .\05 As Builtdossier\2. Bouwkunde\2.1 Architectuur\2.1.10 wanden\TF A 10.01.41#3 A - lichte scheidingswand met gipsplaten Rw50dB.pdf
IfcElement - BB_Element_Lokaalnummer01: K.30.105
IfcRoot - Name: BB_10.01.41#03_Gipskartonwand_43dB_MS100 / 25.50.25, 100 mm
Qto_WallBaseQuantities - Length: 5230; NetVolume: 1.5786; Height: 3000; Width: 100; GrossVolume: 1.5786; GrossSideArea: 15.786; NetSideArea: 15.786
Pset_Condition - AssessmentCondition: Empty
Pset_EnvironmentalImpactIndicators - Reference: BB_10.01.41#03_Gipskartonwand_43dB_MS100 / 25.50.25, 100 mm; sets with these values: 2
Pset_WallCommon - Reference: BB_10.01.41#03_Gipskartonwand_43dB_MS100 / 25.50.25, 100 mm; FireRating: EI60; IsExternal: yes; LoadBearing: no; ExtendToStructure: no

# IfcWall: Basic Wall_BB_10.01.41#03_Gipskartonwand_43dB_MS100 _ 25.50.25_ 100 mm85, Basic Wall:BB_10.01.41#03_Gipskartonwand_43dB_MS100 / 25.50.25, 100 mm:13691056
In: 030
PredefinedType: PARTITIONING
Cpset_Wall - LevelOfAccuracy: in te vullen door Buildwise
IfcBuildingStorey - Base Offset: 0; Top Offset: -460; Base Constraint: 030; Top Constraint: Up to level: 040
IfcClassificationReference - Keynote: 10.01.41#03; GVH_artnr 01: 10.01.41#03; GVH_artnr 02: geen waarde gevonden; GVH_artnr 03: geen waarde gevonden; GVH_artnr 04: geen waarde gevonden; GVH_artnr 05: geen waarde gevonden; GVH_artnr 06: geen waarde gevonden; TDS_link: .\05 As Builtdossier\2. Bouwkunde\2.1 Architectuur\2.1.10 wanden\TF A 10.01.41#3 A - lichte scheidingswand met gipsplaten Rw50dB.pdf
IfcElement - BB_Element_Lokaalnummer01: K.30.106
IfcRoot - Name: BB_10.01.41#03_Gipskartonwand_43dB_MS100 / 25.50.25, 100 mm
Qto_WallBaseQuantities - Length: 5230; NetVolume: 1.61902; Height: 3140; Width: 100; GrossVolume: 1.61902; GrossSideArea: 16.1902; NetSideArea: 16.1902
Pset_Condition - AssessmentCondition: Empty
Pset_EnvironmentalImpactIndicators - Reference: BB_10.01.41#03_Gipskartonwand_43dB_MS100 / 25.50.25, 100 mm; sets with these values: 2
Pset_WallCommon - Reference: BB_10.01.41#03_Gipskartonwand_43dB_MS100 / 25.50.25, 100 mm; FireRating: EI60; IsExternal: yes; LoadBearing: no; ExtendToStructure: no

# IfcWall: Basic Wall_BB_10.01.41#03_Gipskartonwand_43dB_MS100 _ 25.50.25_ 100 mm9, Basic Wall:BB_10.01.41#03_Gipskartonwand_43dB_MS100 / 25.50.25, 100 mm:13059308
In: 000
PredefinedType: PARTITIONING
Cpset_Wall - LevelOfAccuracy: in te vullen door Buildwise
IfcBuildingStorey - Base Offset: -200; Top Offset: -920; Base Constraint: 000; Top Constraint: Up to level: 010
IfcClassificationReference - Keynote: 10.01.41#03; GVH_artnr 01: 10.01.41#03; GVH_artnr 02: geen waarde gevonden; GVH_artnr 03: geen waarde gevonden; GVH_artnr 04: geen waarde gevonden; GVH_artnr 05: geen waarde gevonden; GVH_artnr 06: geen waarde gevonden; TDS_link: .\05 As Builtdossier\2. Bouwkunde\2.1 Architectuur\2.1.10 wanden\TF A 10.01.41#3 A - lichte scheidingswand met gipsplaten Rw50dB.pdf
IfcElement - BB_Element_Lokaalnummer01: K.00.112
IfcRoot - Name: BB_10.01.41#03_Gipskartonwand_43dB_MS100 / 25.50.25, 100 mm
Qto_WallBaseQuantities - Length: 240; NetVolume: 0.06912; Height: 2880; Width: 100; GrossVolume: 0.06912; GrossSideArea: 0.6912; NetSideArea: 0.6912
Pset_Condition - AssessmentCondition: Empty
Pset_EnvironmentalImpactIndicators - Reference: BB_10.01.41#03_Gipskartonwand_43dB_MS100 / 25.50.25, 100 mm; sets with these values: 2
Pset_WallCommon - Reference: BB_10.01.41#03_Gipskartonwand_43dB_MS100 / 25.50.25, 100 mm; FireRating: EI60; IsExternal: yes; LoadBearing: no; ExtendToStructure: no

# IfcWall: Basic Wall_BB_10.01.41#03_Gipskartonwand_43dB_MS125 _ 25.75.25_ 125 mm, Basic Wall:BB_10.01.41#03_Gipskartonwand_43dB_MS125 / 25.75.25, 125 mm:13920864
In: 000
PredefinedType: PARTITIONING
Cpset_Wall - LevelOfAccuracy: in te vullen door Buildwise
IfcBuildingStorey - Base Offset: 2640; Top Offset: -460; Base Constraint: 000; Top Constraint: Up to level: 010
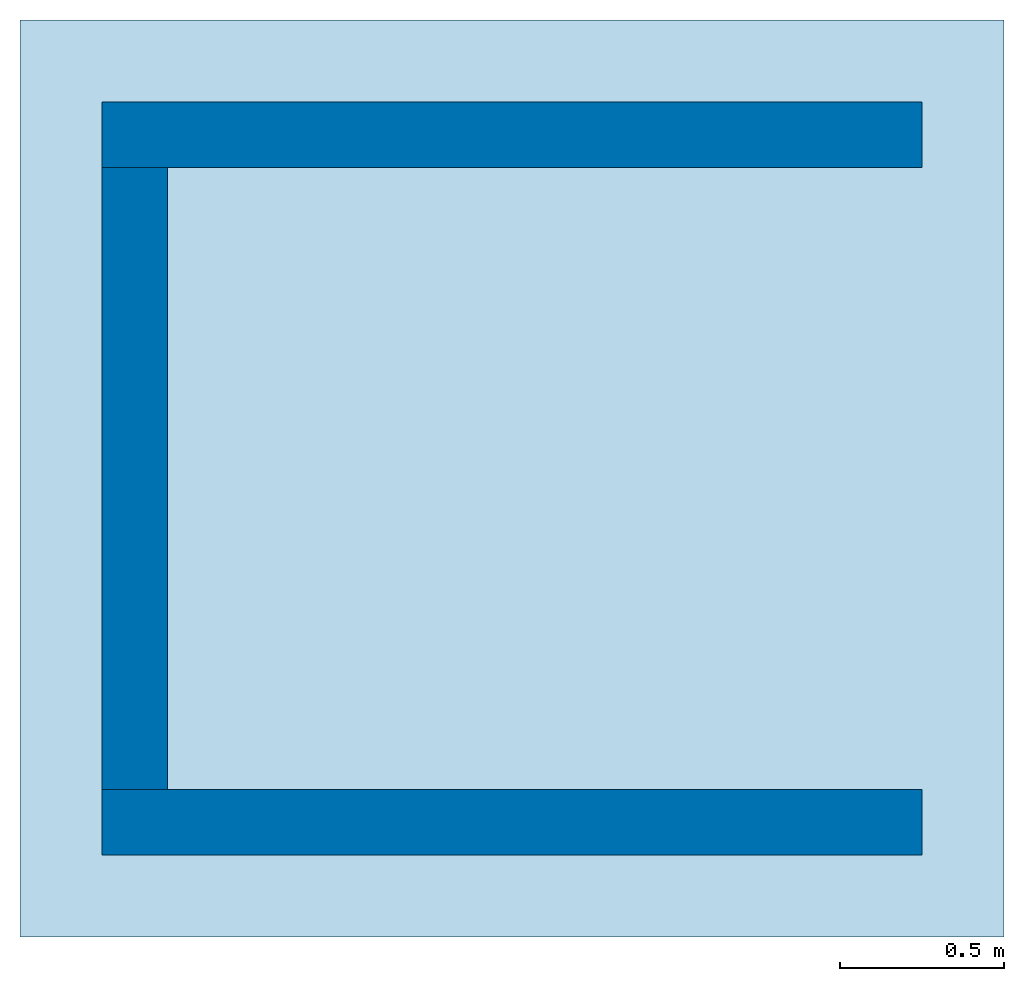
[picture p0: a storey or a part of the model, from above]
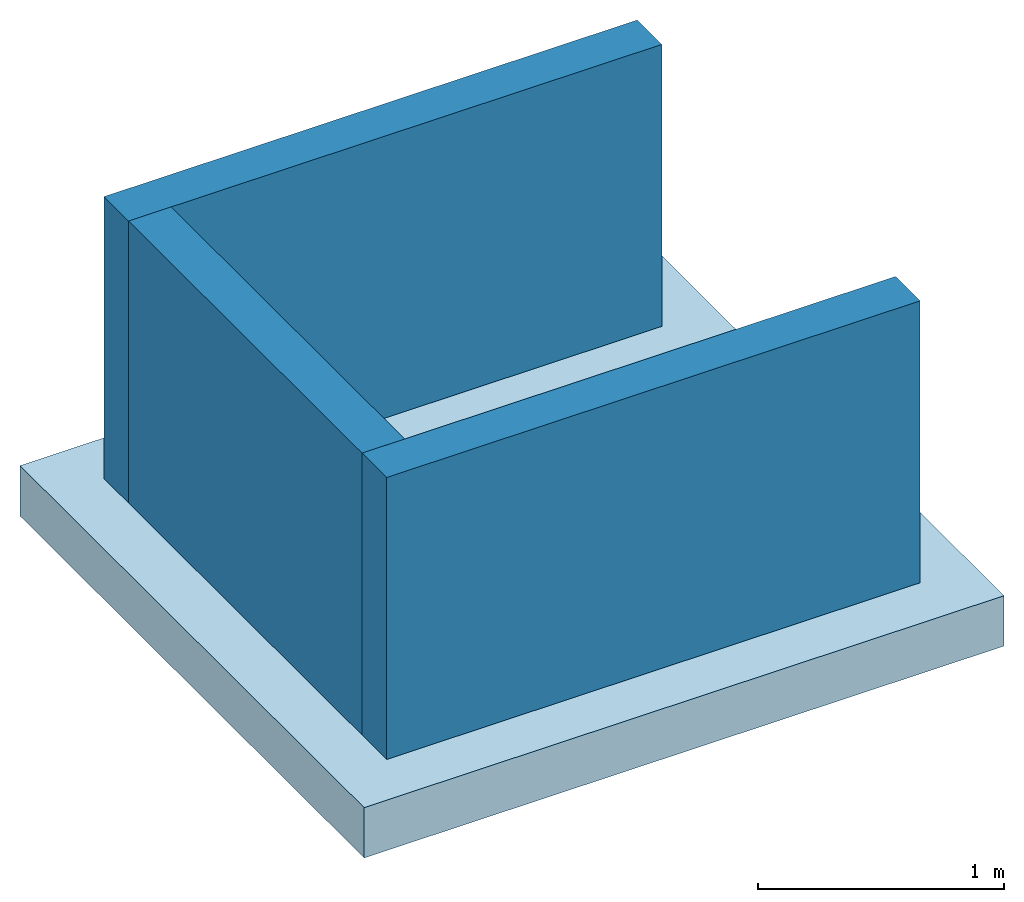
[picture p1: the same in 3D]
Properties of the parts of a building model (IFC4X3_ADD2), part 26 of 28

# IfcWall: Basic Wall_BB_10.01.41#03_Gipskartonwand_43dB_MS125 _ 25.75.25_ 125 mm, Basic Wall:BB_10.01.41#03_Gipskartonwand_43dB_MS125 / 25.75.25, 125 mm:13920864
IfcClassificationReference - Keynote: 10.01.41#03; GVH_artnr 01: 10.01.41#01; GVH_artnr 02: geen waarde gevonden; GVH_artnr 03: geen waarde gevonden; GVH_artnr 04: geen waarde gevonden; GVH_artnr 05: geen waarde gevonden; GVH_artnr 06: geen waarde gevonden; TDS_link: .\05 As Builtdossier\2. Bouwkunde\2.1 Architectuur\2.1.10 wanden\TF A 10.01.41#3 A - lichte scheidingswand met gipsplaten Rw50dB.pdf
IfcElement - BB_Element_Lokaalnummer01: K.10.102
IfcRoot - Name: BB_10.01.41#03_Gipskartonwand_43dB_MS125 / 25.75.25, 125 mm
Qto_WallBaseQuantities - Length: 33947.5; NetVolume: 1.84069; Height: 500; Width: 125; GrossVolume: 1.84069; GrossSideArea: 14.7255; NetSideArea: 14.7255
Pset_Condition - AssessmentCondition: Empty
Pset_EnvironmentalImpactIndicators - Reference: BB_10.01.41#03_Gipskartonwand_43dB_MS125 / 25.75.25, 125 mm; sets with these values: 2
Pset_WallCommon - Reference: BB_10.01.41#03_Gipskartonwand_43dB_MS125 / 25.75.25, 125 mm; FireRating: EI60; ThermalTransmittance: 0.64; IsExternal: yes; LoadBearing: no; ExtendToStructure: no

# IfcWall: Basic Wall_BB_10.01.41#03_Gipskartonwand_43dB_MS125 _ 25.75.25_ 125 mm1, Basic Wall:BB_10.01.41#03_Gipskartonwand_43dB_MS125 / 25.75.25, 125 mm:16203430
In: 000
PredefinedType: PARTITIONING
Cpset_Wall - LevelOfAccuracy: in te vullen door Buildwise
IfcBuildingStorey - Base Offset: 2640; Top Offset: -460; Base Constraint: 000; Top Constraint: Up to level: 010
IfcClassificationReference - Keynote: 10.01.41#03; GVH_artnr 01: 10.01.41#01; GVH_artnr 02: geen waarde gevonden; GVH_artnr 03: geen waarde gevonden; GVH_artnr 04: geen waarde gevonden; GVH_artnr 05: geen waarde gevonden; GVH_artnr 06: geen waarde gevonden; TDS_link: .\05 As Builtdossier\2. Bouwkunde\2.1 Architectuur\2.1.10 wanden\TF A 10.01.41#3 A - lichte scheidingswand met gipsplaten Rw50dB.pdf
IfcElement - BB_Element_Lokaalnummer01: K.10.404
IfcRoot - Name: BB_10.01.41#03_Gipskartonwand_43dB_MS125 / 25.75.25, 125 mm
Qto_WallBaseQuantities - Length: 31282.5; NetVolume: 1.64366; Height: 500; Width: 125; GrossVolume: 1.64366; GrossSideArea: 13.1493; NetSideArea: 13.1493
Pset_Condition - AssessmentCondition: Empty
Pset_EnvironmentalImpactIndicators - Reference: BB_10.01.41#03_Gipskartonwand_43dB_MS125 / 25.75.25, 125 mm; sets with these values: 2
Pset_WallCommon - Reference: BB_10.01.41#03_Gipskartonwand_43dB_MS125 / 25.75.25, 125 mm; FireRating: EI60; ThermalTransmittance: 0.64; IsExternal: yes; LoadBearing: no; ExtendToStructure: no

# IfcWall: Basic Wall_BB_10.01.41#03_Gipskartonwand_43dB_MS125 _ 25.75.25_ 125 mm3, Basic Wall:BB_10.01.41#03_Gipskartonwand_43dB_MS125 / 25.75.25, 125 mm:16203431
In: 000
PredefinedType: PARTITIONING
Cpset_Wall - LevelOfAccuracy: in te vullen door Buildwise
IfcBuildingStorey - Base Offset: 2640; Top Offset: -600; Base Constraint: 000; Top Constraint: Up to level: 010
IfcClassificationReference - Keynote: 10.01.41#03; GVH_artnr 01: 10.01.41#01; GVH_artnr 02: geen waarde gevonden; GVH_artnr 03: geen waarde gevonden; GVH_artnr 04: geen waarde gevonden; GVH_artnr 05: geen waarde gevonden; GVH_artnr 06: geen waarde gevonden; TDS_link: .\05 As Builtdossier\2. Bouwkunde\2.1 Architectuur\2.1.10 wanden\TF A 10.01.41#3 A - lichte scheidingswand met gipsplaten Rw50dB.pdf
IfcElement - BB_Element_Lokaalnummer01: K.10.408
IfcRoot - Name: BB_10.01.41#03_Gipskartonwand_43dB_MS125 / 25.75.25, 125 mm
Qto_WallBaseQuantities - Length: 13677.3; NetVolume: 0.615143; Height: 360; Width: 125; GrossVolume: 0.615143; GrossSideArea: 4.92114; NetSideArea: 4.92114
Pset_Condition - AssessmentCondition: Empty
Pset_EnvironmentalImpactIndicators - Reference: BB_10.01.41#03_Gipskartonwand_43dB_MS125 / 25.75.25, 125 mm; sets with these values: 2
Pset_WallCommon - Reference: BB_10.01.41#03_Gipskartonwand_43dB_MS125 / 25.75.25, 125 mm; FireRating: EI60; ThermalTransmittance: 0.64; IsExternal: yes; LoadBearing: no; ExtendToStructure: no

# IfcWall: Basic Wall_BB_10.01.41#03_Gipskartonwand_43dB_MS125 _ 25.75.25_ 125 mm5, Basic Wall:BB_10.01.41#03_Gipskartonwand_43dB_MS125 / 25.75.25, 125 mm:16218963
In: 000
PredefinedType: PARTITIONING
Cpset_Wall - LevelOfAccuracy: in te vullen door Buildwise
IfcBuildingStorey - Base Offset: 2640; Top Offset: -600; Base Constraint: 000; Top Constraint: Up to level: 010
IfcClassificationReference - Keynote: 10.01.41#03; GVH_artnr 01: 10.01.41#01; GVH_artnr 02: geen waarde gevonden; GVH_artnr 03: geen waarde gevonden; GVH_artnr 04: geen waarde gevonden; GVH_artnr 05: geen waarde gevonden; GVH_artnr 06: geen waarde gevonden; TDS_link: .\05 As Builtdossier\2. Bouwkunde\2.1 Architectuur\2.1.10 wanden\TF A 10.01.41#3 A - lichte scheidingswand met gipsplaten Rw50dB.pdf
IfcElement - BB_Element_Lokaalnummer01: K.10.112
IfcRoot - Name: BB_10.01.41#03_Gipskartonwand_43dB_MS125 / 25.75.25, 125 mm
Qto_WallBaseQuantities - Length: 13800; NetVolume: 0.621; Height: 360; Width: 125; GrossVolume: 0.621; GrossSideArea: 4.968; NetSideArea: 4.968
Pset_Condition - AssessmentCondition: Empty
Pset_EnvironmentalImpactIndicators - Reference: BB_10.01.41#03_Gipskartonwand_43dB_MS125 / 25.75.25, 125 mm; sets with these values: 2
Pset_WallCommon - Reference: BB_10.01.41#03_Gipskartonwand_43dB_MS125 / 25.75.25, 125 mm; FireRating: EI60; ThermalTransmittance: 0.64; IsExternal: yes; LoadBearing: no; ExtendToStructure: no

# IfcWall: Basic Wall_BB_10.01.41#03_Gipskartonwand_43dB_MS125 _ 25.75.25_ 125 mm7, Basic Wall:BB_10.01.41#03_Gipskartonwand_43dB_MS125 / 25.75.25, 125 mm:29572510
In: 000
PredefinedType: PARTITIONING
Cpset_Wall - LevelOfAccuracy: in te vullen door Buildwise
IfcBuildingStorey - Base Offset: 2640; Top Offset: -600; Base Constraint: 000; Top Constraint: Up to level: 010
IfcClassificationReference - Keynote: 10.01.41#03; GVH_artnr 01: 10.01.41#03; GVH_artnr 02: geen waarde gevonden; GVH_artnr 03: geen waarde gevonden; GVH_artnr 04: geen waarde gevonden; GVH_artnr 05: geen waarde gevonden; GVH_artnr 06: geen waarde gevonden; TDS_link: .\05 As Builtdossier\2. Bouwkunde\2.1 Architectuur\2.1.10 wanden\TF A 10.01.41#3 A - lichte scheidingswand met gipsplaten Rw50dB.pdf
IfcRoot - Name: BB_10.01.41#03_Gipskartonwand_43dB_MS125 / 25.75.25, 125 mm
Qto_WallBaseQuantities - Length: 14145; NetVolume: 0.635625; Height: 360; Width: 125; GrossVolume: 0.635625; GrossSideArea: 5.085; NetSideArea: 5.085
Pset_Condition - AssessmentCondition: Empty
Pset_EnvironmentalImpactIndicators - Reference: BB_10.01.41#03_Gipskartonwand_43dB_MS125 / 25.75.25, 125 mm; sets with these values: 2
Pset_WallCommon - Reference: BB_10.01.41#03_Gipskartonwand_43dB_MS125 / 25.75.25, 125 mm; FireRating: EI60; ThermalTransmittance: 0.64; IsExternal: yes; LoadBearing: no; ExtendToStructure: no

# IfcWall: Basic Wall_BB_10.01.41#21_Gipskartonwand_EI60_43dB_MS100 _ 25.50.25_ 100 mm, Basic Wall:BB_10.01.41#21_Gipskartonwand_EI60_43dB_MS100 / 25.50.25, 100 mm:13048547
In: 000
PredefinedType: PARTITIONING
Cpset_Wall - LevelOfAccuracy: in te vullen door Buildwise
IfcBuildingStorey - Base Offset: -10; Top Offset: -460; Base Constraint: 000; Top Constraint: Up to level: 010
IfcClassificationReference - Keynote: 10.01.41#21; GVH_artnr 01: 10.01.41#21; GVH_artnr 02: geen waarde gevonden; GVH_artnr 03: geen waarde gevonden; GVH_artnr 04: geen waarde gevonden; GVH_artnr 05: geen waarde gevonden; GVH_artnr 06: geen waarde gevonden; TDS_link: .\05 As Builtdossier\2. Bouwkunde\2.1 Architectuur\2.1.10 wanden\TF A 10.01.41#21 A - lichte scheidingswand met gipsplaten Rw50dB + EI60.pdf
IfcElement - BB_Element_Lokaalnummer01: K.00.101
IfcRoot - Name: BB_10.01.41#21_Gipskartonwand_EI60_43dB_MS100 / 25.50.25, 100 mm
Qto_WallBaseQuantities - Length: 2215; NetVolume: 0.666225; Height: 3150; Width: 100; GrossVolume: 0.666225; GrossSideArea: 6.66225; NetSideArea: 6.66225
Pset_Condition - AssessmentCondition: Empty
Pset_EnvironmentalImpactIndicators - Reference: BB_10.01.41#21_Gipskartonwand_EI60_43dB_MS100 / 25.50.25, 100 mm; sets with these values: 2
Pset_WallCommon - Reference: BB_10.01.41#21_Gipskartonwand_EI60_43dB_MS100 / 25.50.25, 100 mm; FireRating: EI60; IsExternal: yes; LoadBearing: no; ExtendToStructure: no

# IfcWall: Basic Wall_BB_10.01.41#21_Gipskartonwand_EI60_43dB_MS100 _ 25.50.25_ 100 mm1, Basic Wall:BB_10.01.41#21_Gipskartonwand_EI60_43dB_MS100 / 25.50.25, 100 mm:13674456
In: 000
PredefinedType: PARTITIONING
Cpset_Wall - LevelOfAccuracy: in te vullen door Buildwise
IfcBuildingStorey - Base Offset: -10; Top Offset: -460; Base Constraint: 000; Top Constraint: Up to level: 010
IfcClassificationReference - Keynote: 10.01.41#21; GVH_artnr 01: 10.01.41#21; GVH_artnr 02: geen waarde gevonden; GVH_artnr 03: geen waarde gevonden; GVH_artnr 04: geen waarde gevonden; GVH_artnr 05: geen waarde gevonden; GVH_artnr 06: geen waarde gevonden; TDS_link: .\05 As Builtdossier\2. Bouwkunde\2.1 Architectuur\2.1.10 wanden\TF A 10.01.41#21 A - lichte scheidingswand met gipsplaten Rw50dB + EI60.pdf
IfcElement - BB_Element_Lokaalnummer01: K.00.101
IfcRoot - Name: BB_10.01.41#21_Gipskartonwand_EI60_43dB_MS100 / 25.50.25, 100 mm
Qto_WallBaseQuantities - Length: 1647.5; NetVolume: 0.096475; Height: 3150; Width: 100; GrossVolume: 0.096475; GrossSideArea: 0.96475; NetSideArea: 0.96475
Pset_Condition - AssessmentCondition: Empty
Pset_EnvironmentalImpactIndicators - Reference: BB_10.01.41#21_Gipskartonwand_EI60_43dB_MS100 / 25.50.25, 100 mm; sets with these values: 2
Pset_WallCommon - Reference: BB_10.01.41#21_Gipskartonwand_EI60_43dB_MS100 / 25.50.25, 100 mm; FireRating: EI60; IsExternal: yes; LoadBearing: no; ExtendToStructure: no

# IfcWall: Basic Wall_BB_10.01.41#21_Gipskartonwand_EI60_43dB_MS100 _ 25.50.25_ 100 mm11, Basic Wall:BB_10.01.41#21_Gipskartonwand_EI60_43dB_MS100 / 25.50.25, 100 mm:25515314
In: 000
PredefinedType: PARTITIONING
Cpset_Wall - LevelOfAccuracy: in te vullen door Buildwise
IfcBuildingStorey - Base Offset: 0; Top Offset: -600; Base Constraint: 000; Top Constraint: Up to level: 010
IfcClassificationReference - Keynote: 10.01.41#21; GVH_artnr 01: 10.01.41#21; GVH_artnr 02: geen waarde gevonden; GVH_artnr 03: geen waarde gevonden; GVH_artnr 04: geen waarde gevonden; GVH_artnr 05: geen waarde gevonden; GVH_artnr 06: geen waarde gevonden; TDS_link: .\05 As Builtdossier\2. Bouwkunde\2.1 Architectuur\2.1.10 wanden\TF A 10.01.41#21 A - lichte scheidingswand met gipsplaten Rw50dB + EI60.pdf
IfcElement - BB_Element_Lokaalnummer01: K.00.502
IfcRoot - Name: BB_10.01.41#21_Gipskartonwand_EI60_43dB_MS100 / 25.50.25, 100 mm
Qto_WallBaseQuantities - Length: 830; NetVolume: 0.234; Height: 3000; Width: 100; GrossVolume: 0.234; GrossSideArea: 2.34; NetSideArea: 2.34
Pset_Condition - AssessmentCondition: Empty
Pset_EnvironmentalImpactIndicators - Reference: BB_10.01.41#21_Gipskartonwand_EI60_43dB_MS100 / 25.50.25, 100 mm; sets with these values: 2
Pset_WallCommon - Reference: BB_10.01.41#21_Gipskartonwand_EI60_43dB_MS100 / 25.50.25, 100 mm; FireRating: EI60; IsExternal: yes; LoadBearing: no; ExtendToStructure: no

# IfcWall: Basic Wall_BB_10.01.41#21_Gipskartonwand_EI60_43dB_MS100 _ 25.50.25_ 100 mm13, Basic Wall:BB_10.01.41#21_Gipskartonwand_EI60_43dB_MS100 / 25.50.25, 100 mm:25520285
In: 000
PredefinedType: PARTITIONING
Cpset_Wall - LevelOfAccuracy: in te vullen door Buildwise
IfcBuildingStorey - Base Offset: 0; Top Offset: -460; Base Constraint: 000; Top Constraint: Up to level: 010
IfcClassificationReference - Keynote: 10.01.41#21; GVH_artnr 01: 10.01.41#21; GVH_artnr 02: geen waarde gevonden; GVH_artnr 03: geen waarde gevonden; GVH_artnr 04: geen waarde gevonden; GVH_artnr 05: geen waarde gevonden; GVH_artnr 06: geen waarde gevonden; TDS_link: .\05 As Builtdossier\2. Bouwkunde\2.1 Architectuur\2.1.10 wanden\TF A 10.01.41#21 A - lichte scheidingswand met gipsplaten Rw50dB + EI60.pdf
IfcElement - BB_Element_Lokaalnummer01: K.00.502
IfcRoot - Name: BB_10.01.41#21_Gipskartonwand_EI60_43dB_MS100 / 25.50.25, 100 mm
Qto_WallBaseQuantities - Length: 640; NetVolume: 0.18191; Height: 3140; Width: 100; GrossVolume: 0.18191; GrossSideArea: 1.8191; NetSideArea: 1.8191
Pset_Condition - AssessmentCondition: Empty
Pset_EnvironmentalImpactIndicators - Reference: BB_10.01.41#21_Gipskartonwand_EI60_43dB_MS100 / 25.50.25, 100 mm; sets with these values: 2
Pset_WallCommon - Reference: BB_10.01.41#21_Gipskartonwand_EI60_43dB_MS100 / 25.50.25, 100 mm; FireRating: EI60; IsExternal: yes; LoadBearing: no; ExtendToStructure: no

# IfcWall: Basic Wall_BB_10.01.41#21_Gipskartonwand_EI60_43dB_MS100 _ 25.50.25_ 100 mm15, Basic Wall:BB_10.01.41#21_Gipskartonwand_EI60_43dB_MS100 / 25.50.25, 100 mm:25599008
In: 000
PredefinedType: PARTITIONING
Cpset_Wall - LevelOfAccuracy: in te vullen door Buildwise
IfcBuildingStorey - Base Offset: -10; Top Offset: -460; Base Constraint: 000; Top Constraint: Up to level: 010
IfcClassificationReference - Keynote: 10.01.41#21; GVH_artnr 01: 10.01.41#21; GVH_artnr 02: geen waarde gevonden; GVH_artnr 03: geen waarde gevonden; GVH_artnr 04: geen waarde gevonden; GVH_artnr 05: geen waarde gevonden; GVH_artnr 06: geen waarde gevonden; TDS_link: .\05 As Builtdossier\2. Bouwkunde\2.1 Architectuur\2.1.10 wanden\TF A 10.01.41#21 A - lichte scheidingswand met gipsplaten Rw50dB + EI60.pdf
IfcRoot - Name: BB_10.01.41#21_Gipskartonwand_EI60_43dB_MS100 / 25.50.25, 100 mm
Qto_WallBaseQuantities - Length: 1642.5; NetVolume: 0.096475; Height: 3150; Width: 100; GrossVolume: 0.096475; GrossSideArea: 0.96475; NetSideArea: 0.96475
Pset_Condition - AssessmentCondition: Empty
Pset_EnvironmentalImpactIndicators - Reference: BB_10.01.41#21_Gipskartonwand_EI60_43dB_MS100 / 25.50.25, 100 mm; sets with these values: 2
Pset_WallCommon - Reference: BB_10.01.41#21_Gipskartonwand_EI60_43dB_MS100 / 25.50.25, 100 mm; FireRating: EI60; IsExternal: yes; LoadBearing: no; ExtendToStructure: no

# IfcWall: Basic Wall_BB_10.01.41#21_Gipskartonwand_EI60_43dB_MS100 _ 25.50.25_ 100 mm17, Basic Wall:BB_10.01.41#21_Gipskartonwand_EI60_43dB_MS100 / 25.50.25, 100 mm:33049611
In: 000
PredefinedType: PARTITIONING
Cpset_Wall - LevelOfAccuracy: in te vullen door Buildwise
IfcBuildingStorey - Base Offset: -10; Top Offset: -460; Base Constraint: 000; Top Constraint: Up to level: 010
IfcClassificationReference - Keynote: 10.01.41#21; GVH_artnr 01: 10.01.41#21; GVH_artnr 02: geen waarde gevonden; GVH_artnr 03: geen waarde gevonden; GVH_artnr 04: geen waarde gevonden; GVH_artnr 05: geen waarde gevonden; GVH_artnr 06: geen waarde gevonden; TDS_link: .\05 As Builtdossier\2. Bouwkunde\2.1 Architectuur\2.1.10 wanden\TF A 10.01.41#21 A - lichte scheidingswand met gipsplaten Rw50dB + EI60.pdf
IfcRoot - Name: BB_10.01.41#21_Gipskartonwand_EI60_43dB_MS100 / 25.50.25, 100 mm
Qto_WallBaseQuantities - Length: 5305; NetVolume: 1.66429; Height: 3150; Width: 100; GrossVolume: 1.66429; GrossSideArea: 16.6429; NetSideArea: 16.6429
Pset_Condition - AssessmentCondition: Empty
Pset_EnvironmentalImpactIndicators - Reference: BB_10.01.41#21_Gipskartonwand_EI60_43dB_MS100 / 25.50.25, 100 mm; sets with these values: 2
Pset_WallCommon - Reference: BB_10.01.41#21_Gipskartonwand_EI60_43dB_MS100 / 25.50.25, 100 mm; FireRating: EI60; IsExternal: yes; LoadBearing: no; ExtendToStructure: no

# IfcWall: Basic Wall_BB_10.01.41#21_Gipskartonwand_EI60_43dB_MS100 _ 25.50.25_ 100 mm19, Basic Wall:BB_10.01.41#21_Gipskartonwand_EI60_43dB_MS100 / 25.50.25, 100 mm:34827580
In: 000
PredefinedType: PARTITIONING
Cpset_Wall - LevelOfAccuracy: in te vullen door Buildwise
IfcBuildingStorey - Base Offset: -200; Top Offset: 3000; Base Constraint: 000; Top Constraint: Up to level: 000
IfcClassificationReference - Keynote: 10.01.41#21; GVH_artnr 01: 10.01.62#01; GVH_artnr 02: geen waarde gevonden; GVH_artnr 03: geen waarde gevonden; GVH_artnr 04: geen waarde gevonden; GVH_artnr 05: geen waarde gevonden; GVH_artnr 06: geen waarde gevonden; TDS_link: .\05 As Builtdossier\2. Bouwkunde\2.1 Architectuur\2.1.10 wanden\TF A 10.01.41#21 A - lichte scheidingswand met gipsplaten Rw50dB + EI60.pdf
IfcElement - BB_Element_Lokaalnummer01: K.00.404
IfcRoot - Name: BB_10.01.41#21_Gipskartonwand_EI60_43dB_MS100 / 25.50.25, 100 mm
Qto_WallBaseQuantities - Length: 337.5; NetVolume: 0.0915; Height: 3200; Width: 100; GrossVolume: 0.0915; GrossSideArea: 0.915; NetSideArea: 0.915
Pset_Condition - AssessmentCondition: Empty
Pset_EnvironmentalImpactIndicators - Reference: BB_10.01.41#21_Gipskartonwand_EI60_43dB_MS100 / 25.50.25, 100 mm; sets with these values: 2
Pset_WallCommon - Reference: BB_10.01.41#21_Gipskartonwand_EI60_43dB_MS100 / 25.50.25, 100 mm; FireRating: EI60; IsExternal: yes; LoadBearing: no; ExtendToStructure: no

# IfcWall: Basic Wall_BB_10.01.41#21_Gipskartonwand_EI60_43dB_MS100 _ 25.50.25_ 100 mm21, Basic Wall:BB_10.01.41#21_Gipskartonwand_EI60_43dB_MS100 / 25.50.25, 100 mm:12997160
In: 010
PredefinedType: PARTITIONING
Cpset_Wall - LevelOfAccuracy: in te vullen door Buildwise
IfcBuildingStorey - Base Offset: -200; Top Offset: -600; Base Constraint: 010; Top Constraint: Up to level: 020
IfcClassificationReference - Keynote: 10.01.41#21; GVH_artnr 01: 10.01.41#21; GVH_artnr 02: geen waarde gevonden; GVH_artnr 03: geen waarde gevonden; GVH_artnr 04: geen waarde gevonden; GVH_artnr 05: geen waarde gevonden; GVH_artnr 06: geen waarde gevonden; TDS_link: .\05 As Builtdossier\2. Bouwkunde\2.1 Architectuur\2.1.10 wanden\TF A 10.01.41#21 A - lichte scheidingswand met gipsplaten Rw50dB + EI60.pdf
IfcElement - BB_Element_Lokaalnummer01: K.10.113
IfcRoot - Name: BB_10.01.41#21_Gipskartonwand_EI60_43dB_MS100 / 25.50.25, 100 mm
Qto_WallBaseQuantities - Length: 2035; NetVolume: 0.6672; Height: 3200; Width: 100; GrossVolume: 0.6672; GrossSideArea: 6.672; NetSideArea: 6.672
Pset_Condition - AssessmentCondition: Empty
Pset_EnvironmentalImpactIndicators - Reference: BB_10.01.41#21_Gipskartonwand_EI60_43dB_MS100 / 25.50.25, 100 mm; sets with these values: 2
Pset_WallCommon - Reference: BB_10.01.41#21_Gipskartonwand_EI60_43dB_MS100 / 25.50.25, 100 mm; FireRating: EI60; IsExternal: yes; LoadBearing: no; ExtendToStructure: no

# IfcWall: Basic Wall_BB_10.01.41#21_Gipskartonwand_EI60_43dB_MS100 _ 25.50.25_ 100 mm23, Basic Wall:BB_10.01.41#21_Gipskartonwand_EI60_43dB_MS100 / 25.50.25, 100 mm:12997302
In: 010
PredefinedType: PARTITIONING
Cpset_Wall - LevelOfAccuracy: in te vullen door Buildwise
IfcBuildingStorey - Base Offset: -200; Top Offset: -592.936; Base Constraint: 010; Top Constraint: Up to level: 020
IfcClassificationReference - Keynote: 10.01.41#21; GVH_artnr 01: 10.01.41#21; GVH_artnr 02: geen waarde gevonden; GVH_artnr 03: geen waarde gevonden; GVH_artnr 04: geen waarde gevonden; GVH_artnr 05: geen waarde gevonden; GVH_artnr 06: geen waarde gevonden; TDS_link: .\05 As Builtdossier\2. Bouwkunde\2.1 Architectuur\2.1.10 wanden\TF A 10.01.41#21 A - lichte scheidingswand met gipsplaten Rw50dB + EI60.pdf
IfcElement - BB_Element_Lokaalnummer01: K.10.101
IfcRoot - Name: BB_10.01.41#21_Gipskartonwand_EI60_43dB_MS100 / 25.50.25, 100 mm
Qto_WallBaseQuantities - Length: 1945; NetVolume: 0.607739; Height: 3207.06; Width: 100; GrossVolume: 0.607739; GrossSideArea: 6.07739; NetSideArea: 6.07739
Pset_Condition - AssessmentCondition: Empty
Pset_EnvironmentalImpactIndicators - Reference: BB_10.01.41#21_Gipskartonwand_EI60_43dB_MS100 / 25.50.25, 100 mm; sets with these values: 2
Pset_WallCommon - Reference: BB_10.01.41#21_Gipskartonwand_EI60_43dB_MS100 / 25.50.25, 100 mm; FireRating: EI60; IsExternal: yes; LoadBearing: no; ExtendToStructure: no

# IfcWall: Basic Wall_BB_10.01.41#21_Gipskartonwand_EI60_43dB_MS100 _ 25.50.25_ 100 mm25, Basic Wall:BB_10.01.41#21_Gipskartonwand_EI60_43dB_MS100 / 25.50.25, 100 mm:12999230
In: 010
PredefinedType: PARTITIONING
Cpset_Wall - LevelOfAccuracy: in te vullen door Buildwise
IfcBuildingStorey - Base Offset: -200; Top Offset: -600; Base Constraint: 010; Top Constraint: Up to level: 020
IfcClassificationReference - Keynote: 10.01.41#21; GVH_artnr 01: 10.01.41#21; GVH_artnr 02: geen waarde gevonden; GVH_artnr 03: geen waarde gevonden; GVH_artnr 04: geen waarde gevonden; GVH_artnr 05: geen waarde gevonden; GVH_artnr 06: geen waarde gevonden; TDS_link: .\05 As Builtdossier\2. Bouwkunde\2.1 Architectuur\2.1.10 wanden\TF A 10.01.41#21 A - lichte scheidingswand met gipsplaten Rw50dB + EI60.pdf
IfcElement - BB_Element_Lokaalnummer01: K.10.503
IfcRoot - Name: BB_10.01.41#21_Gipskartonwand_EI60_43dB_MS100 / 25.50.25, 100 mm
Qto_WallBaseQuantities - Length: 5445; NetVolume: 1.73926; Height: 3200; Width: 100; GrossVolume: 1.73926; GrossSideArea: 17.3926; NetSideArea: 17.3926
Pset_Condition - AssessmentCondition: Empty
Pset_EnvironmentalImpactIndicators - Reference: BB_10.01.41#21_Gipskartonwand_EI60_43dB_MS100 / 25.50.25, 100 mm; sets with these values: 2
Pset_WallCommon - Reference: BB_10.01.41#21_Gipskartonwand_EI60_43dB_MS100 / 25.50.25, 100 mm; FireRating: EI60; IsExternal: yes; LoadBearing: no; ExtendToStructure: no

# IfcWall: Basic Wall_BB_10.01.41#21_Gipskartonwand_EI60_43dB_MS100 _ 25.50.25_ 100 mm27, Basic Wall:BB_10.01.41#21_Gipskartonwand_EI60_43dB_MS100 / 25.50.25, 100 mm:12999231
In: 010
PredefinedType: PARTITIONING
Cpset_Wall - LevelOfAccuracy: in te vullen door Buildwise
IfcBuildingStorey - Base Offset: -200; Top Offset: -600; Base Constraint: 010; Top Constraint: Up to level: 020
IfcClassificationReference - Keynote: 10.01.41#21; GVH_artnr 01: 10.01.41#21; GVH_artnr 02: geen waarde gevonden; GVH_artnr 03: geen waarde gevonden; GVH_artnr 04: geen waarde gevonden; GVH_artnr 05: geen waarde gevonden; GVH_artnr 06: geen waarde gevonden; TDS_link: .\05 As Builtdossier\2. Bouwkunde\2.1 Architectuur\2.1.10 wanden\TF A 10.01.41#21 A - lichte scheidingswand met gipsplaten Rw50dB + EI60.pdf
IfcElement - BB_Element_Lokaalnummer01: K.10.503
IfcRoot - Name: BB_10.01.41#21_Gipskartonwand_EI60_43dB_MS100 / 25.50.25, 100 mm
Qto_WallBaseQuantities - Length: 2035; NetVolume: 0.437553; Height: 3200; Width: 100; GrossVolume: 0.437553; GrossSideArea: 4.37553; NetSideArea: 4.37553
Pset_Condition - AssessmentCondition: Empty
Pset_EnvironmentalImpactIndicators - Reference: BB_10.01.41#21_Gipskartonwand_EI60_43dB_MS100 / 25.50.25, 100 mm; sets with these values: 2
Pset_WallCommon - Reference: BB_10.01.41#21_Gipskartonwand_EI60_43dB_MS100 / 25.50.25, 100 mm; FireRating: EI60; IsExternal: yes; LoadBearing: no; ExtendToStructure: no

# IfcWall: Basic Wall_BB_10.01.41#21_Gipskartonwand_EI60_43dB_MS100 _ 25.50.25_ 100 mm29, Basic Wall:BB_10.01.41#21_Gipskartonwand_EI60_43dB_MS100 / 25.50.25, 100 mm:12999354
In: 010
PredefinedType: PARTITIONING
Cpset_Wall - LevelOfAccuracy: in te vullen door Buildwise
IfcBuildingStorey - Base Offset: -200; Top Offset: -460; Base Constraint: 010; Top Constraint: Up to level: 020
IfcClassificationReference - Keynote: 10.01.41#21; GVH_artnr 01: 10.01.41#21; GVH_artnr 02: geen waarde gevonden; GVH_artnr 03: geen waarde gevonden; GVH_artnr 04: geen waarde gevonden; GVH_artnr 05: geen waarde gevonden; GVH_artnr 06: geen waarde gevonden; TDS_link: .\05 As Builtdossier\2. Bouwkunde\2.1 Architectuur\2.1.10 wanden\TF A 10.01.41#21 A - lichte scheidingswand met gipsplaten Rw50dB + EI60.pdf
IfcElement - BB_Element_Lokaalnummer01: K.10.516
IfcRoot - Name: BB_10.01.41#21_Gipskartonwand_EI60_43dB_MS100 / 25.50.25, 100 mm
Qto_WallBaseQuantities - Length: 5230; NetVolume: 1.74322; Height: 3340; Width: 100; GrossVolume: 1.74322; GrossSideArea: 17.4322; NetSideArea: 17.4322
Pset_Condition - AssessmentCondition: Empty
Pset_EnvironmentalImpactIndicators - Reference: BB_10.01.41#21_Gipskartonwand_EI60_43dB_MS100 / 25.50.25, 100 mm; sets with these values: 2
Pset_WallCommon - Reference: BB_10.01.41#21_Gipskartonwand_EI60_43dB_MS100 / 25.50.25, 100 mm; FireRating: EI60; IsExternal: yes; LoadBearing: no; ExtendToStructure: no

# IfcWall: Basic Wall_BB_10.01.41#21_Gipskartonwand_EI60_43dB_MS100 _ 25.50.25_ 100 mm3, Basic Wall:BB_10.01.41#21_Gipskartonwand_EI60_43dB_MS100 / 25.50.25, 100 mm:25505478
In: 000
PredefinedType: PARTITIONING
Cpset_Wall - LevelOfAccuracy: in te vullen door Buildwise
IfcBuildingStorey - Base Offset: 0; Top Offset: -600; Base Constraint: 000; Top Constraint: Up to level: 010
IfcClassificationReference - Keynote: 10.01.41#21; GVH_artnr 01: 10.01.41#21; GVH_artnr 02: geen waarde gevonden; GVH_artnr 03: geen waarde gevonden; GVH_artnr 04: geen waarde gevonden; GVH_artnr 05: geen waarde gevonden; GVH_artnr 06: geen waarde gevonden; TDS_link: .\05 As Builtdossier\2. Bouwkunde\2.1 Architectuur\2.1.10 wanden\TF A 10.01.41#21 A - lichte scheidingswand met gipsplaten Rw50dB + EI60.pdf
IfcElement - BB_Element_Lokaalnummer01: K.00.502
IfcRoot - Name: BB_10.01.41#21_Gipskartonwand_EI60_43dB_MS100 / 25.50.25, 100 mm
Qto_WallBaseQuantities - Length: 2387.5; NetVolume: 0.30771; Height: 3000; Width: 100; GrossVolume: 0.310585; GrossSideArea: 3.10585; NetSideArea: 3.10585
Pset_Condition - AssessmentCondition: Empty
Pset_EnvironmentalImpactIndicators - Reference: BB_10.01.41#21_Gipskartonwand_EI60_43dB_MS100 / 25.50.25, 100 mm; sets with these values: 2
Pset_WallCommon - Reference: BB_10.01.41#21_Gipskartonwand_EI60_43dB_MS100 / 25.50.25, 100 mm; FireRating: EI60; IsExternal: yes; LoadBearing: no; ExtendToStructure: no

# IfcWall: Basic Wall_BB_10.01.41#21_Gipskartonwand_EI60_43dB_MS100 _ 25.50.25_ 100 mm31, Basic Wall:BB_10.01.41#21_Gipskartonwand_EI60_43dB_MS100 / 25.50.25, 100 mm:12999474
In: 010
PredefinedType: PARTITIONING
Cpset_Wall - LevelOfAccuracy: in te vullen door Buildwise
IfcBuildingStorey - Base Offset: -200; Top Offset: -600; Base Constraint: 010; Top Constraint: Up to level: 020
IfcClassificationReference - Keynote: 10.01.41#21; GVH_artnr 01: 10.01.41#21; GVH_artnr 02: geen waarde gevonden; GVH_artnr 03: geen waarde gevonden; GVH_artnr 04: geen waarde gevonden; GVH_artnr 05: geen waarde gevonden; GVH_artnr 06: geen waarde gevonden; TDS_link: .\05 As Builtdossier\2. Bouwkunde\2.1 Architectuur\2.1.10 wanden\TF A 10.01.41#21 A - lichte scheidingswand met gipsplaten Rw50dB + EI60.pdf
IfcElement - BB_Element_Lokaalnummer01: K.10.516
IfcRoot - Name: BB_10.01.41#21_Gipskartonwand_EI60_43dB_MS100 / 25.50.25, 100 mm
Qto_WallBaseQuantities - Length: 2215; NetVolume: 0.673263; Height: 3200; Width: 100; GrossVolume: 0.673263; GrossSideArea: 6.73263; NetSideArea: 6.73263
Pset_Condition - AssessmentCondition: Empty
Pset_EnvironmentalImpactIndicators - Reference: BB_10.01.41#21_Gipskartonwand_EI60_43dB_MS100 / 25.50.25, 100 mm; sets with these values: 2
Pset_WallCommon - Reference: BB_10.01.41#21_Gipskartonwand_EI60_43dB_MS100 / 25.50.25, 100 mm; FireRating: EI60; IsExternal: yes; LoadBearing: no; ExtendToStructure: no

# IfcWall: Basic Wall_BB_10.01.41#21_Gipskartonwand_EI60_43dB_MS100 _ 25.50.25_ 100 mm33, Basic Wall:BB_10.01.41#21_Gipskartonwand_EI60_43dB_MS100 / 25.50.25, 100 mm:13922306
In: 010
PredefinedType: PARTITIONING
Cpset_Wall - LevelOfAccuracy: in te vullen door Buildwise
IfcBuildingStorey - Base Offset: -200; Top Offset: -600; Base Constraint: 010; Top Constraint: Up to level: 020
IfcClassificationReference - Keynote: 10.01.41#21; GVH_artnr 01: 10.01.41#21; GVH_artnr 02: geen waarde gevonden; GVH_artnr 03: geen waarde gevonden; GVH_artnr 04: geen waarde gevonden; GVH_artnr 05: geen waarde gevonden; GVH_artnr 06: geen waarde gevonden; TDS_link: .\05 As Builtdossier\2. Bouwkunde\2.1 Architectuur\2.1.10 wanden\TF A 10.01.41#21 A - lichte scheidingswand met gipsplaten Rw50dB + EI60.pdf
IfcElement - BB_Element_Lokaalnummer01: K.10.103
IfcRoot - Name: BB_10.01.41#21_Gipskartonwand_EI60_43dB_MS100 / 25.50.25, 100 mm
Qto_WallBaseQuantities - Length: 6927.63; NetVolume: 1.76036; Height: 3200; Width: 100; GrossVolume: 1.76036; GrossSideArea: 17.6036; NetSideArea: 17.6036
Pset_Condition - AssessmentCondition: Empty
Pset_EnvironmentalImpactIndicators - Reference: BB_10.01.41#21_Gipskartonwand_EI60_43dB_MS100 / 25.50.25, 100 mm; sets with these values: 2
Pset_WallCommon - Reference: BB_10.01.41#21_Gipskartonwand_EI60_43dB_MS100 / 25.50.25, 100 mm; FireRating: EI60; IsExternal: yes; LoadBearing: no; ExtendToStructure: no

# IfcWall: Basic Wall_BB_10.01.41#21_Gipskartonwand_EI60_43dB_MS100 _ 25.50.25_ 100 mm35, Basic Wall:BB_10.01.41#21_Gipskartonwand_EI60_43dB_MS100 / 25.50.25, 100 mm:13922307
In: 010
PredefinedType: PARTITIONING
Cpset_Wall - LevelOfAccuracy: in te vullen door Buildwise
IfcBuildingStorey - Base Offset: -10; Top Offset: -600; Base Constraint: 010; Top Constraint: Up to level: 020
IfcClassificationReference - Keynote: 10.01.41#21; GVH_artnr 01: 10.01.41#21; GVH_artnr 02: geen waarde gevonden; GVH_artnr 03: geen waarde gevonden; GVH_artnr 04: geen waarde gevonden; GVH_artnr 05: geen waarde gevonden; GVH_artnr 06: geen waarde gevonden; TDS_link: .\05 As Builtdossier\2. Bouwkunde\2.1 Architectuur\2.1.10 wanden\2.1.10.3 Binnendeuren + brandwerend schrijnwerk (Beddeleem)\2.1.10.3.2 technische fiches\TF A 10-05-41-11 A - JB Door Fix 30 730x2115.pdf
IfcElement - BB_Element_Lokaalnummer01: K.10.101
IfcRoot - Name: BB_10.01.41#21_Gipskartonwand_EI60_43dB_MS100 / 25.50.25, 100 mm
Qto_WallBaseQuantities - Length: 1635; NetVolume: 0.074285; Height: 3010; Width: 100; GrossVolume: 0.074285; GrossSideArea: 0.74285; NetSideArea: 0.74285
Pset_Condition - AssessmentCondition: Empty
Pset_EnvironmentalImpactIndicators - Reference: BB_10.01.41#21_Gipskartonwand_EI60_43dB_MS100 / 25.50.25, 100 mm; sets with these values: 2
Pset_WallCommon - Reference: BB_10.01.41#21_Gipskartonwand_EI60_43dB_MS100 / 25.50.25, 100 mm; AcousticRating: 40; FireRating: EI30; IsExternal: yes; LoadBearing: no; ExtendToStructure: no

# IfcWall: Basic Wall_BB_10.01.41#21_Gipskartonwand_EI60_43dB_MS100 _ 25.50.25_ 100 mm37, Basic Wall:BB_10.01.41#21_Gipskartonwand_EI60_43dB_MS100 / 25.50.25, 100 mm:13922321
In: 010
PredefinedType: PARTITIONING
Cpset_Wall - LevelOfAccuracy: in te vullen door Buildwise
IfcBuildingStorey - Base Offset: -10; Top Offset: -460; Base Constraint: 010; Top Constraint: Up to level: 020
IfcClassificationReference - Keynote: 10.01.41#21; GVH_artnr 01: 10.01.41#21; GVH_artnr 02: geen waarde gevonden; GVH_artnr 03: geen waarde gevonden; GVH_artnr 04: geen waarde gevonden; GVH_artnr 05: geen waarde gevonden; GVH_artnr 06: geen waarde gevonden; TDS_link: .\05 As Builtdossier\2. Bouwkunde\2.1 Architectuur\2.1.10 wanden\TF A 10.01.41#21 A - lichte scheidingswand met gipsplaten Rw50dB + EI60.pdf
IfcElement - BB_Element_Lokaalnummer01: K.10.502
IfcRoot - Name: BB_10.01.41#21_Gipskartonwand_EI60_43dB_MS100 / 25.50.25, 100 mm
Qto_WallBaseQuantities - Length: 1635; NetVolume: 0.127975; Height: 3150; Width: 100; GrossVolume: 0.127975; GrossSideArea: 1.27975; NetSideArea: 1.27975
Pset_Condition - AssessmentCondition: Empty
Pset_EnvironmentalImpactIndicators - Reference: BB_10.01.41#21_Gipskartonwand_EI60_43dB_MS100 / 25.50.25, 100 mm; sets with these values: 2
Pset_WallCommon - Reference: BB_10.01.41#21_Gipskartonwand_EI60_43dB_MS100 / 25.50.25, 100 mm; FireRating: EI60; IsExternal: yes; LoadBearing: no; ExtendToStructure: no

# IfcWall: Basic Wall_BB_10.01.41#21_Gipskartonwand_EI60_43dB_MS100 _ 25.50.25_ 100 mm39, Basic Wall:BB_10.01.41#21_Gipskartonwand_EI60_43dB_MS100 / 25.50.25, 100 mm:13922322
In: 010
PredefinedType: PARTITIONING
Cpset_Wall - LevelOfAccuracy: in te vullen door Buildwise
IfcBuildingStorey - Base Offset: -10; Top Offset: -460; Base Constraint: 010; Top Constraint: Up to level: 020
IfcClassificationReference - Keynote: 10.01.41#21; GVH_artnr 01: 10.01.41#21; GVH_artnr 02: geen waarde gevonden; GVH_artnr 03: geen waarde gevonden; GVH_artnr 04: geen waarde gevonden; GVH_artnr 05: geen waarde gevonden; GVH_artnr 06: geen waarde gevonden; TDS_link: .\05 As Builtdossier\2. Bouwkunde\2.1 Architectuur\2.1.10 wanden\TF A 10.01.41#21 A - lichte scheidingswand met gipsplaten Rw50dB + EI60.pdf
IfcElement - BB_Element_Lokaalnummer01: K.10.502
IfcRoot - Name: BB_10.01.41#21_Gipskartonwand_EI60_43dB_MS100 / 25.50.25, 100 mm
Qto_WallBaseQuantities - Length: 1635; NetVolume: 0.096475; Height: 3150; Width: 100; GrossVolume: 0.096475; GrossSideArea: 0.96475; NetSideArea: 0.96475
Pset_Condition - AssessmentCondition: Empty
Pset_EnvironmentalImpactIndicators - Reference: BB_10.01.41#21_Gipskartonwand_EI60_43dB_MS100 / 25.50.25, 100 mm; sets with these values: 2
Pset_WallCommon - Reference: BB_10.01.41#21_Gipskartonwand_EI60_43dB_MS100 / 25.50.25, 100 mm; FireRating: EI60; IsExternal: yes; LoadBearing: no; ExtendToStructure: no

# IfcWall: Basic Wall_BB_10.01.41#21_Gipskartonwand_EI60_43dB_MS100 _ 25.50.25_ 100 mm41, Basic Wall:BB_10.01.41#21_Gipskartonwand_EI60_43dB_MS100 / 25.50.25, 100 mm:25636366
In: 010
PredefinedType: PARTITIONING
Cpset_Wall - LevelOfAccuracy: in te vullen door Buildwise
IfcBuildingStorey - Base Offset: 2670; Top Offset: -290; Base Constraint: 010; Top Constraint: Up to level: 020
IfcClassificationReference - Keynote: 10.01.41#21; GVH_artnr 01: 10.01.41#21; GVH_artnr 02: geen waarde gevonden; GVH_artnr 03: geen waarde gevonden; GVH_artnr 04: geen waarde gevonden; GVH_artnr 05: geen waarde gevonden; GVH_artnr 06: geen waarde gevonden; TDS_link: .\05 As Builtdossier\2. Bouwkunde\2.1 Architectuur\2.1.10 wanden\TF A 10.01.41#21 A - lichte scheidingswand met gipsplaten Rw50dB + EI60.pdf
IfcElement - BB_Element_Lokaalnummer01: K.10.G14
IfcRoot - Name: BB_10.01.41#21_Gipskartonwand_EI60_43dB_MS100 / 25.50.25, 100 mm
Qto_WallBaseQuantities - Length: 2680; NetVolume: 0.17152; Height: 640; Width: 100; GrossVolume: 0.17152; GrossSideArea: 1.7152; NetSideArea: 1.7152
Pset_Condition - AssessmentCondition: Empty
Pset_EnvironmentalImpactIndicators - Reference: BB_10.01.41#21_Gipskartonwand_EI60_43dB_MS100 / 25.50.25, 100 mm; sets with these values: 2
Pset_WallCommon - Reference: BB_10.01.41#21_Gipskartonwand_EI60_43dB_MS100 / 25.50.25, 100 mm; FireRating: EI60; IsExternal: yes; LoadBearing: no; ExtendToStructure: no

# IfcWall: Basic Wall_BB_10.01.41#21_Gipskartonwand_EI60_43dB_MS100 _ 25.50.25_ 100 mm43, Basic Wall:BB_10.01.41#21_Gipskartonwand_EI60_43dB_MS100 / 25.50.25, 100 mm:12558842
In: 020
PredefinedType: PARTITIONING
Cpset_Wall - LevelOfAccuracy: in te vullen door Buildwise
IfcBuildingStorey - Base Offset: -200; Top Offset: -600; Base Constraint: 020; Top Constraint: Up to level: 030
IfcClassificationReference - Keynote: 10.01.41#21; GVH_artnr 01: 10.01.41#21; GVH_artnr 02: geen waarde gevonden; GVH_artnr 03: geen waarde gevonden; GVH_artnr 04: geen waarde gevonden; GVH_artnr 05: geen waarde gevonden; GVH_artnr 06: geen waarde gevonden; TDS_link: .\05 As Builtdossier\2. Bouwkunde\2.1 Architectuur\2.1.10 wanden\TF A 10.01.41#21 A - lichte scheidingswand met gipsplaten Rw50dB + EI60.pdf
IfcElement - BB_Element_Lokaalnummer01: K.20.118
IfcRoot - Name: BB_10.01.41#21_Gipskartonwand_EI60_43dB_MS100 / 25.50.25, 100 mm
Qto_WallBaseQuantities - Length: 2050; NetVolume: 0.479315; Height: 3200; Width: 100; GrossVolume: 0.672; GrossSideArea: 6.72; NetSideArea: 4.79315
Pset_Condition - AssessmentCondition: Empty
Pset_EnvironmentalImpactIndicators - Reference: BB_10.01.41#21_Gipskartonwand_EI60_43dB_MS100 / 25.50.25, 100 mm; sets with these values: 2
Pset_WallCommon - Reference: BB_10.01.41#21_Gipskartonwand_EI60_43dB_MS100 / 25.50.25, 100 mm; FireRating: EI60; IsExternal: yes; LoadBearing: no; ExtendToStructure: no

# IfcWall: Basic Wall_BB_10.01.41#21_Gipskartonwand_EI60_43dB_MS100 _ 25.50.25_ 100 mm45, Basic Wall:BB_10.01.41#21_Gipskartonwand_EI60_43dB_MS100 / 25.50.25, 100 mm:12558893
In: 020
PredefinedType: PARTITIONING
Cpset_Wall - LevelOfAccuracy: in te vullen door Buildwise
IfcBuildingStorey - Base Offset: -200; Top Offset: -600; Base Constraint: 020; Top Constraint: Up to level: 030
IfcClassificationReference - Keynote: 10.01.41#21; GVH_artnr 01: 10.01.41#21; GVH_artnr 02: geen waarde gevonden; GVH_artnr 03: geen waarde gevonden; GVH_artnr 04: geen waarde gevonden; GVH_artnr 05: geen waarde gevonden; GVH_artnr 06: geen waarde gevonden; TDS_link: .\05 As Builtdossier\2. Bouwkunde\2.1 Architectuur\2.1.10 wanden\TF A 10.01.41#21 A - lichte scheidingswand met gipsplaten Rw50dB + EI60.pdf
IfcElement - BB_Element_Lokaalnummer01: K.20.118
IfcRoot - Name: BB_10.01.41#21_Gipskartonwand_EI60_43dB_MS100 / 25.50.25, 100 mm
Qto_WallBaseQuantities - Length: 5444.87; NetVolume: 1.72208; Height: 3200; Width: 100; GrossVolume: 1.72208; GrossSideArea: 17.2208; NetSideArea: 17.2208
Pset_Condition - AssessmentCondition: Empty
Pset_EnvironmentalImpactIndicators - Reference: BB_10.01.41#21_Gipskartonwand_EI60_43dB_MS100 / 25.50.25, 100 mm; sets with these values: 2
Pset_WallCommon - Reference: BB_10.01.41#21_Gipskartonwand_EI60_43dB_MS100 / 25.50.25, 100 mm; FireRating: EI60; IsExternal: yes; LoadBearing: no; ExtendToStructure: no

# IfcWall: Basic Wall_BB_10.01.41#21_Gipskartonwand_EI60_43dB_MS100 _ 25.50.25_ 100 mm47, Basic Wall:BB_10.01.41#21_Gipskartonwand_EI60_43dB_MS100 / 25.50.25, 100 mm:12559449
In: 020
PredefinedType: PARTITIONING
Cpset_Wall - LevelOfAccuracy: in te vullen door Buildwise
IfcBuildingStorey - Base Offset: -200; Top Offset: -600; Base Constraint: 020; Top Constraint: Up to level: 030
IfcClassificationReference - Keynote: 10.01.41#21; GVH_artnr 01: 10.01.41#21; GVH_artnr 02: geen waarde gevonden; GVH_artnr 03: geen waarde gevonden; GVH_artnr 04: geen waarde gevonden; GVH_artnr 05: geen waarde gevonden; GVH_artnr 06: geen waarde gevonden; TDS_link: .\05 As Builtdossier\2. Bouwkunde\2.1 Architectuur\2.1.10 wanden\TF A 10.01.41#21 A - lichte scheidingswand met gipsplaten Rw50dB + EI60.pdf
IfcElement - BB_Element_Lokaalnummer01: K.20.103
IfcRoot - Name: BB_10.01.41#21_Gipskartonwand_EI60_43dB_MS100 / 25.50.25, 100 mm
Qto_WallBaseQuantities - Length: 1770; NetVolume: 0.59005; Height: 3200; Width: 100; GrossVolume: 0.59005; GrossSideArea: 5.9005; NetSideArea: 5.9005
Pset_Condition - AssessmentCondition: Empty
Pset_EnvironmentalImpactIndicators - Reference: BB_10.01.41#21_Gipskartonwand_EI60_43dB_MS100 / 25.50.25, 100 mm; sets with these values: 2
Pset_WallCommon - Reference: BB_10.01.41#21_Gipskartonwand_EI60_43dB_MS100 / 25.50.25, 100 mm; FireRating: EI60; IsExternal: yes; LoadBearing: no; ExtendToStructure: no

# IfcWall: Basic Wall_BB_10.01.41#21_Gipskartonwand_EI60_43dB_MS100 _ 25.50.25_ 100 mm49, Basic Wall:BB_10.01.41#21_Gipskartonwand_EI60_43dB_MS100 / 25.50.25, 100 mm:12559479
In: 020
PredefinedType: PARTITIONING
Cpset_Wall - LevelOfAccuracy: in te vullen door Buildwise
IfcBuildingStorey - Base Offset: -200; Top Offset: -600; Base Constraint: 020; Top Constraint: Up to level: 030
IfcClassificationReference - Keynote: 10.01.41#21; GVH_artnr 01: 10.01.41#21; GVH_artnr 02: geen waarde gevonden; GVH_artnr 03: geen waarde gevonden; GVH_artnr 04: geen waarde gevonden; GVH_artnr 05: geen waarde gevonden; GVH_artnr 06: geen waarde gevonden; TDS_link: .\05 As Builtdossier\2. Bouwkunde\2.1 Architectuur\2.1.10 wanden\TF A 10.01.41#21 A - lichte scheidingswand met gipsplaten Rw50dB + EI60.pdf
IfcElement - BB_Element_Lokaalnummer01: K.20.102
IfcRoot - Name: BB_10.01.41#21_Gipskartonwand_EI60_43dB_MS100 / 25.50.25, 100 mm
Qto_WallBaseQuantities - Length: 5230; NetVolume: 1.6522; Height: 3200; Width: 100; GrossVolume: 1.6522; GrossSideArea: 16.522; NetSideArea: 16.522
Pset_Condition - AssessmentCondition: Empty
Pset_EnvironmentalImpactIndicators - Reference: BB_10.01.41#21_Gipskartonwand_EI60_43dB_MS100 / 25.50.25, 100 mm; sets with these values: 2
Pset_WallCommon - Reference: BB_10.01.41#21_Gipskartonwand_EI60_43dB_MS100 / 25.50.25, 100 mm; FireRating: EI60; IsExternal: yes; LoadBearing: no; ExtendToStructure: no

# IfcWall: Basic Wall_BB_10.01.41#21_Gipskartonwand_EI60_43dB_MS100 _ 25.50.25_ 100 mm5, Basic Wall:BB_10.01.41#21_Gipskartonwand_EI60_43dB_MS100 / 25.50.25, 100 mm:25515140
In: 000
PredefinedType: PARTITIONING
Cpset_Wall - LevelOfAccuracy: in te vullen door Buildwise
IfcBuildingStorey - Base Offset: 0; Top Offset: -460; Base Constraint: 000; Top Constraint: Up to level: 010
IfcClassificationReference - Keynote: 10.01.41#21; GVH_artnr 01: 10.01.41#21; GVH_artnr 02: geen waarde gevonden; GVH_artnr 03: geen waarde gevonden; GVH_artnr 04: geen waarde gevonden; GVH_artnr 05: geen waarde gevonden; GVH_artnr 06: geen waarde gevonden; TDS_link: .\05 As Builtdossier\2. Bouwkunde\2.1 Architectuur\2.1.10 wanden\TF A 10.01.41#21 A - lichte scheidingswand met gipsplaten Rw50dB + EI60.pdf
IfcElement - BB_Element_Lokaalnummer01: K.00.502
IfcRoot - Name: BB_10.01.41#21_Gipskartonwand_EI60_43dB_MS100 / 25.50.25, 100 mm
Qto_WallBaseQuantities - Length: 2380; NetVolume: 0.29071; Height: 3140; Width: 100; GrossVolume: 0.29071; GrossSideArea: 2.9071; NetSideArea: 2.9071
Pset_Condition - AssessmentCondition: Empty
Pset_EnvironmentalImpactIndicators - Reference: BB_10.01.41#21_Gipskartonwand_EI60_43dB_MS100 / 25.50.25, 100 mm; sets with these values: 2
Pset_WallCommon - Reference: BB_10.01.41#21_Gipskartonwand_EI60_43dB_MS100 / 25.50.25, 100 mm; FireRating: EI60; IsExternal: yes; LoadBearing: no; ExtendToStructure: no

# IfcWall: Basic Wall_BB_10.01.41#21_Gipskartonwand_EI60_43dB_MS100 _ 25.50.25_ 100 mm51, Basic Wall:BB_10.01.41#21_Gipskartonwand_EI60_43dB_MS100 / 25.50.25, 100 mm:12560227
In: 020
PredefinedType: PARTITIONING
Cpset_Wall - LevelOfAccuracy: in te vullen door Buildwise
IfcBuildingStorey - Base Offset: -200; Top Offset: -600; Base Constraint: 020; Top Constraint: Up to level: 030
IfcClassificationReference - Keynote: 10.01.41#21; GVH_artnr 01: 10.01.41#21; GVH_artnr 02: geen waarde gevonden; GVH_artnr 03: geen waarde gevonden; GVH_artnr 04: geen waarde gevonden; GVH_artnr 05: geen waarde gevonden; GVH_artnr 06: geen waarde gevonden; TDS_link: .\05 As Builtdossier\2. Bouwkunde\2.1 Architectuur\2.1.10 wanden\TF A 10.01.41#21 A - lichte scheidingswand met gipsplaten Rw50dB + EI60.pdf
IfcElement - BB_Element_Lokaalnummer01: K.20.502
IfcRoot - Name: BB_10.01.41#21_Gipskartonwand_EI60_43dB_MS100 / 25.50.25, 100 mm
Qto_WallBaseQuantities - Length: 5465; NetVolume: 1.75868; Height: 3200; Width: 100; GrossVolume: 1.75868; GrossSideArea: 17.5868; NetSideArea: 17.5868
Pset_Condition - AssessmentCondition: Empty
Pset_EnvironmentalImpactIndicators - Reference: BB_10.01.41#21_Gipskartonwand_EI60_43dB_MS100 / 25.50.25, 100 mm; sets with these values: 2
Pset_WallCommon - Reference: BB_10.01.41#21_Gipskartonwand_EI60_43dB_MS100 / 25.50.25, 100 mm; FireRating: EI60; IsExternal: yes; LoadBearing: no; ExtendToStructure: no

# IfcWall: Basic Wall_BB_10.01.41#21_Gipskartonwand_EI60_43dB_MS100 _ 25.50.25_ 100 mm53, Basic Wall:BB_10.01.41#21_Gipskartonwand_EI60_43dB_MS100 / 25.50.25, 100 mm:12560269
In: 020
PredefinedType: PARTITIONING
Cpset_Wall - LevelOfAccuracy: in te vullen door Buildwise
IfcBuildingStorey - Base Offset: -200; Top Offset: -600; Base Constraint: 020; Top Constraint: Up to level: 030
IfcClassificationReference - Keynote: 10.01.41#21; GVH_artnr 01: 10.01.41#21; GVH_artnr 02: geen waarde gevonden; GVH_artnr 03: geen waarde gevonden; GVH_artnr 04: geen waarde gevonden; GVH_artnr 05: geen waarde gevonden; GVH_artnr 06: geen waarde gevonden; TDS_link: .\05 As Builtdossier\2. Bouwkunde\2.1 Architectuur\2.1.10 wanden\TF A 10.01.41#21 A - lichte scheidingswand met gipsplaten Rw50dB + EI60.pdf
IfcElement - BB_Element_Lokaalnummer01: K.20.502
IfcRoot - Name: BB_10.01.41#21_Gipskartonwand_EI60_43dB_MS100 / 25.50.25, 100 mm
Qto_WallBaseQuantities - Length: 2050; NetVolume: 0.447315; Height: 3200; Width: 100; GrossVolume: 0.64; GrossSideArea: 6.4; NetSideArea: 4.47315
Pset_Condition - AssessmentCondition: Empty
Pset_EnvironmentalImpactIndicators - Reference: BB_10.01.41#21_Gipskartonwand_EI60_43dB_MS100 / 25.50.25, 100 mm; sets with these values: 2
Pset_WallCommon - Reference: BB_10.01.41#21_Gipskartonwand_EI60_43dB_MS100 / 25.50.25, 100 mm; FireRating: EI60; IsExternal: yes; LoadBearing: no; ExtendToStructure: no

# IfcWall: Basic Wall_BB_10.01.41#21_Gipskartonwand_EI60_43dB_MS100 _ 25.50.25_ 100 mm55, Basic Wall:BB_10.01.41#21_Gipskartonwand_EI60_43dB_MS100 / 25.50.25, 100 mm:12565142
In: 020
PredefinedType: PARTITIONING
Cpset_Wall - LevelOfAccuracy: in te vullen door Buildwise
IfcBuildingStorey - Base Offset: -200; Top Offset: -600; Base Constraint: 020; Top Constraint: Up to level: 030
IfcClassificationReference - Keynote: 10.01.41#21; GVH_artnr 01: 10.01.41#21; GVH_artnr 02: geen waarde gevonden; GVH_artnr 03: geen waarde gevonden; GVH_artnr 04: geen waarde gevonden; GVH_artnr 05: geen waarde gevonden; GVH_artnr 06: geen waarde gevonden; TDS_link: .\05 As Builtdossier\2. Bouwkunde\2.1 Architectuur\2.1.10 wanden\TF A 10.01.41#21 A - lichte scheidingswand met gipsplaten Rw50dB + EI60.pdf
IfcElement - BB_Element_Lokaalnummer01: K.20.301
IfcRoot - Name: BB_10.01.41#21_Gipskartonwand_EI60_43dB_MS100 / 25.50.25, 100 mm
Qto_WallBaseQuantities - Length: 385; NetVolume: 0.1392; Height: 3200; Width: 100; GrossVolume: 0.1392; GrossSideArea: 1.392; NetSideArea: 1.392
Pset_Condition - AssessmentCondition: Empty
Pset_EnvironmentalImpactIndicators - Reference: BB_10.01.41#21_Gipskartonwand_EI60_43dB_MS100 / 25.50.25, 100 mm; sets with these values: 2
Pset_WallCommon - Reference: BB_10.01.41#21_Gipskartonwand_EI60_43dB_MS100 / 25.50.25, 100 mm; FireRating: EI60; IsExternal: yes; LoadBearing: no; ExtendToStructure: no

# IfcWall: Basic Wall_BB_10.01.41#21_Gipskartonwand_EI60_43dB_MS100 _ 25.50.25_ 100 mm57, Basic Wall:BB_10.01.41#21_Gipskartonwand_EI60_43dB_MS100 / 25.50.25, 100 mm:12565179
In: 020
PredefinedType: PARTITIONING
Cpset_Wall - LevelOfAccuracy: in te vullen door Buildwise
IfcBuildingStorey - Base Offset: -200; Top Offset: -600; Base Constraint: 020; Top Constraint: Up to level: 030
IfcClassificationReference - Keynote: 10.01.41#21; GVH_artnr 01: 10.01.41#21; GVH_artnr 02: geen waarde gevonden; GVH_artnr 03: geen waarde gevonden; GVH_artnr 04: geen waarde gevonden; GVH_artnr 05: geen waarde gevonden; GVH_artnr 06: geen waarde gevonden; TDS_link: .\05 As Builtdossier\2. Bouwkunde\2.1 Architectuur\2.1.10 wanden\TF A 10.01.41#21 A - lichte scheidingswand met gipsplaten Rw50dB + EI60.pdf
IfcElement - BB_Element_Lokaalnummer01: K.20.301
IfcRoot - Name: BB_10.01.41#21_Gipskartonwand_EI60_43dB_MS100 / 25.50.25, 100 mm
Qto_WallBaseQuantities - Length: 2581; NetVolume: 0.4224; Height: 3200; Width: 100; GrossVolume: 0.79392; GrossSideArea: 7.9392; NetSideArea: 4.224
Pset_Condition - AssessmentCondition: Empty
Pset_EnvironmentalImpactIndicators - Reference: BB_10.01.41#21_Gipskartonwand_EI60_43dB_MS100 / 25.50.25, 100 mm; sets with these values: 2
Pset_WallCommon - Reference: BB_10.01.41#21_Gipskartonwand_EI60_43dB_MS100 / 25.50.25, 100 mm; FireRating: EI60; IsExternal: yes; LoadBearing: no; ExtendToStructure: no

# IfcWall: Basic Wall_BB_10.01.41#21_Gipskartonwand_EI60_43dB_MS100 _ 25.50.25_ 100 mm59, Basic Wall:BB_10.01.41#21_Gipskartonwand_EI60_43dB_MS100 / 25.50.25, 100 mm:12565224
In: 020
PredefinedType: PARTITIONING
Cpset_Wall - LevelOfAccuracy: in te vullen door Buildwise
IfcBuildingStorey - Base Offset: -200; Top Offset: -600; Base Constraint: 020; Top Constraint: Up to level: 030
IfcClassificationReference - Keynote: 10.01.41#21; GVH_artnr 01: 10.01.41#21; GVH_artnr 02: geen waarde gevonden; GVH_artnr 03: geen waarde gevonden; GVH_artnr 04: geen waarde gevonden; GVH_artnr 05: geen waarde gevonden; GVH_artnr 06: geen waarde gevonden; TDS_link: .\05 As Builtdossier\2. Bouwkunde\2.1 Architectuur\2.1.10 wanden\TF A 10.01.41#21 A - lichte scheidingswand met gipsplaten Rw50dB + EI60.pdf
IfcElement - BB_Element_Lokaalnummer01: K.20.301
IfcRoot - Name: BB_10.01.41#21_Gipskartonwand_EI60_43dB_MS100 / 25.50.25, 100 mm
Qto_WallBaseQuantities - Length: 385; NetVolume: 0.1072; Height: 3200; Width: 100; GrossVolume: 0.1072; GrossSideArea: 1.072; NetSideArea: 1.072
Pset_Condition - AssessmentCondition: Empty
Pset_EnvironmentalImpactIndicators - Reference: BB_10.01.41#21_Gipskartonwand_EI60_43dB_MS100 / 25.50.25, 100 mm; sets with these values: 2
Pset_WallCommon - Reference: BB_10.01.41#21_Gipskartonwand_EI60_43dB_MS100 / 25.50.25, 100 mm; FireRating: EI60; IsExternal: yes; LoadBearing: no; ExtendToStructure: no

# IfcWall: Basic Wall_BB_10.01.41#21_Gipskartonwand_EI60_43dB_MS100 _ 25.50.25_ 100 mm61, Basic Wall:BB_10.01.41#21_Gipskartonwand_EI60_43dB_MS100 / 25.50.25, 100 mm:12565459
In: 020
PredefinedType: PARTITIONING
Cpset_Wall - LevelOfAccuracy: in te vullen door Buildwise
IfcBuildingStorey - Base Offset: -200; Top Offset: -600; Base Constraint: 020; Top Constraint: Up to level: 030
IfcClassificationReference - Keynote: 10.01.41#21; GVH_artnr 01: 10.01.41#21; GVH_artnr 02: geen waarde gevonden; GVH_artnr 03: geen waarde gevonden; GVH_artnr 04: geen waarde gevonden; GVH_artnr 05: geen waarde gevonden; GVH_artnr 06: geen waarde gevonden; TDS_link: .\05 As Builtdossier\2. Bouwkunde\2.1 Architectuur\2.1.10 wanden\TF A 10.01.41#21 A - lichte scheidingswand met gipsplaten Rw50dB + EI60.pdf
IfcElement - BB_Element_Lokaalnummer01: K.20.301
IfcRoot - Name: BB_10.01.41#21_Gipskartonwand_EI60_43dB_MS100 / 25.50.25, 100 mm
Qto_WallBaseQuantities - Length: 565; NetVolume: 0.2128; Height: 3200; Width: 100; GrossVolume: 0.2128; GrossSideArea: 2.128; NetSideArea: 2.128
Pset_Condition - AssessmentCondition: Empty
Pset_EnvironmentalImpactIndicators - Reference: BB_10.01.41#21_Gipskartonwand_EI60_43dB_MS100 / 25.50.25, 100 mm; sets with these values: 2
Pset_WallCommon - Reference: BB_10.01.41#21_Gipskartonwand_EI60_43dB_MS100 / 25.50.25, 100 mm; FireRating: EI60; IsExternal: yes; LoadBearing: no; ExtendToStructure: no

# IfcWall: Basic Wall_BB_10.01.41#21_Gipskartonwand_EI60_43dB_MS100 _ 25.50.25_ 100 mm63, Basic Wall:BB_10.01.41#21_Gipskartonwand_EI60_43dB_MS100 / 25.50.25, 100 mm:12565590
In: 020
PredefinedType: PARTITIONING
Cpset_Wall - LevelOfAccuracy: in te vullen door Buildwise
IfcBuildingStorey - Base Offset: -200; Top Offset: -600; Base Constraint: 020; Top Constraint: Up to level: 030
IfcClassificationReference - Keynote: 10.01.41#21; GVH_artnr 01: 10.01.41#21; GVH_artnr 02: geen waarde gevonden; GVH_artnr 03: geen waarde gevonden; GVH_artnr 04: geen waarde gevonden; GVH_artnr 05: geen waarde gevonden; GVH_artnr 06: geen waarde gevonden; TDS_link: .\05 As Builtdossier\2. Bouwkunde\2.1 Architectuur\2.1.10 wanden\TF A 10.01.41#21 A - lichte scheidingswand met gipsplaten Rw50dB + EI60.pdf
IfcElement - BB_Element_Lokaalnummer01: K.20.301
IfcRoot - Name: BB_10.01.41#21_Gipskartonwand_EI60_43dB_MS100 / 25.50.25, 100 mm
Qto_WallBaseQuantities - Length: 280; NetVolume: 0.0736; Height: 3200; Width: 100; GrossVolume: 0.0736; GrossSideArea: 0.736; NetSideArea: 0.736
Pset_Condition - AssessmentCondition: Empty
Pset_EnvironmentalImpactIndicators - Reference: BB_10.01.41#21_Gipskartonwand_EI60_43dB_MS100 / 25.50.25, 100 mm; sets with these values: 2
Pset_WallCommon - Reference: BB_10.01.41#21_Gipskartonwand_EI60_43dB_MS100 / 25.50.25, 100 mm; FireRating: EI60; IsExternal: yes; LoadBearing: no; ExtendToStructure: no

# IfcWall: Basic Wall_BB_10.01.41#21_Gipskartonwand_EI60_43dB_MS100 _ 25.50.25_ 100 mm65, Basic Wall:BB_10.01.41#21_Gipskartonwand_EI60_43dB_MS100 / 25.50.25, 100 mm:25600007
In: 020
PredefinedType: PARTITIONING
Cpset_Wall - LevelOfAccuracy: in te vullen door Buildwise
IfcBuildingStorey - Base Offset: -10; Top Offset: -600; Base Constraint: 020; Top Constraint: Up to level: 030
IfcClassificationReference - Keynote: 10.01.41#21; GVH_artnr 01: 10.01.41#21; GVH_artnr 02: geen waarde gevonden; GVH_artnr 03: geen waarde gevonden; GVH_artnr 04: geen waarde gevonden; GVH_artnr 05: geen waarde gevonden; GVH_artnr 06: geen waarde gevonden; TDS_link: .\05 As Builtdossier\2. Bouwkunde\2.1 Architectuur\2.1.10 wanden\TF A 10.01.41#21 A - lichte scheidingswand met gipsplaten Rw50dB + EI60.pdf
IfcElement - BB_Element_Lokaalnummer01: K.20.101
IfcRoot - Name: BB_10.01.41#21_Gipskartonwand_EI60_43dB_MS100 / 25.50.25, 100 mm
Qto_WallBaseQuantities - Length: 1635; NetVolume: 0.074825; Height: 3010; Width: 100; GrossVolume: 0.077885; GrossSideArea: 0.77885; NetSideArea: 0.77885
Pset_Condition - AssessmentCondition: Empty
Pset_EnvironmentalImpactIndicators - Reference: BB_10.01.41#21_Gipskartonwand_EI60_43dB_MS100 / 25.50.25, 100 mm; sets with these values: 2
Pset_WallCommon - Reference: BB_10.01.41#21_Gipskartonwand_EI60_43dB_MS100 / 25.50.25, 100 mm; FireRating: EI60; IsExternal: yes; LoadBearing: no; ExtendToStructure: no

# IfcWall: Basic Wall_BB_10.01.41#21_Gipskartonwand_EI60_43dB_MS100 _ 25.50.25_ 100 mm67, Basic Wall:BB_10.01.41#21_Gipskartonwand_EI60_43dB_MS100 / 25.50.25, 100 mm:25600020
In: 020
PredefinedType: PARTITIONING
Cpset_Wall - LevelOfAccuracy: in te vullen door Buildwise
IfcBuildingStorey - Base Offset: -10; Top Offset: -600; Base Constraint: 020; Top Constraint: Up to level: 030
IfcClassificationReference - Keynote: 10.01.41#21; GVH_artnr 01: 10.01.41#21; GVH_artnr 02: geen waarde gevonden; GVH_artnr 03: geen waarde gevonden; GVH_artnr 04: geen waarde gevonden; GVH_artnr 05: geen waarde gevonden; GVH_artnr 06: geen waarde gevonden; TDS_link: .\05 As Builtdossier\2. Bouwkunde\2.1 Architectuur\2.1.10 wanden\TF A 10.01.41#21 A - lichte scheidingswand met gipsplaten Rw50dB + EI60.pdf
IfcElement - BB_Element_Lokaalnummer01: K.20.101
IfcRoot - Name: BB_10.01.41#21_Gipskartonwand_EI60_43dB_MS100 / 25.50.25, 100 mm
Qto_WallBaseQuantities - Length: 1642.5; NetVolume: 0.074285; Height: 3010; Width: 100; GrossVolume: 0.074285; GrossSideArea: 0.74285; NetSideArea: 0.74285
Pset_Condition - AssessmentCondition: Empty
Pset_EnvironmentalImpactIndicators - Reference: BB_10.01.41#21_Gipskartonwand_EI60_43dB_MS100 / 25.50.25, 100 mm; sets with these values: 2
Pset_WallCommon - Reference: BB_10.01.41#21_Gipskartonwand_EI60_43dB_MS100 / 25.50.25, 100 mm; FireRating: EI60; IsExternal: yes; LoadBearing: no; ExtendToStructure: no

# IfcWall: Basic Wall_BB_10.01.41#21_Gipskartonwand_EI60_43dB_MS100 _ 25.50.25_ 100 mm69, Basic Wall:BB_10.01.41#21_Gipskartonwand_EI60_43dB_MS100 / 25.50.25, 100 mm:25651509
In: 020
PredefinedType: PARTITIONING
Cpset_Wall - LevelOfAccuracy: in te vullen door Buildwise
IfcBuildingStorey - Base Offset: 2670; Top Offset: -290; Base Constraint: 020; Top Constraint: Up to level: 030
IfcClassificationReference - Keynote: 10.01.41#21; GVH_artnr 01: 10.01.41#21; GVH_artnr 02: geen waarde gevonden; GVH_artnr 03: geen waarde gevonden; GVH_artnr 04: geen waarde gevonden; GVH_artnr 05: geen waarde gevonden; GVH_artnr 06: geen waarde gevonden; TDS_link: .\05 As Builtdossier\2. Bouwkunde\2.1 Architectuur\2.1.10 wanden\TF A 10.01.41#21 A - lichte scheidingswand met gipsplaten Rw50dB + EI60.pdf
IfcElement - BB_Element_Lokaalnummer01: K.20.G14
IfcRoot - Name: BB_10.01.41#21_Gipskartonwand_EI60_43dB_MS100 / 25.50.25, 100 mm
Qto_WallBaseQuantities - Length: 2680; NetVolume: 0.17152; Height: 640; Width: 100; GrossVolume: 0.17152; GrossSideArea: 1.7152; NetSideArea: 1.7152
Pset_Condition - AssessmentCondition: Empty
Pset_EnvironmentalImpactIndicators - Reference: BB_10.01.41#21_Gipskartonwand_EI60_43dB_MS100 / 25.50.25, 100 mm; sets with these values: 2
Pset_WallCommon - Reference: BB_10.01.41#21_Gipskartonwand_EI60_43dB_MS100 / 25.50.25, 100 mm; FireRating: EI60; IsExternal: yes; LoadBearing: no; ExtendToStructure: no

# IfcWall: Basic Wall_BB_10.01.41#21_Gipskartonwand_EI60_43dB_MS100 _ 25.50.25_ 100 mm7, Basic Wall:BB_10.01.41#21_Gipskartonwand_EI60_43dB_MS100 / 25.50.25, 100 mm:25515199
In: 000
PredefinedType: PARTITIONING
Cpset_Wall - LevelOfAccuracy: in te vullen door Buildwise
IfcBuildingStorey - Base Offset: 0; Top Offset: -460; Base Constraint: 000; Top Constraint: Up to level: 010
IfcClassificationReference - Keynote: 10.01.41#21; GVH_artnr 01: 10.01.41#21; GVH_artnr 02: geen waarde gevonden; GVH_artnr 03: geen waarde gevonden; GVH_artnr 04: geen waarde gevonden; GVH_artnr 05: geen waarde gevonden; GVH_artnr 06: geen waarde gevonden; TDS_link: .\05 As Builtdossier\2. Bouwkunde\2.1 Architectuur\2.1.10 wanden\TF A 10.01.41#21 A - lichte scheidingswand met gipsplaten Rw50dB + EI60.pdf
IfcElement - BB_Element_Lokaalnummer01: K.00.502
IfcRoot - Name: BB_10.01.41#21_Gipskartonwand_EI60_43dB_MS100 / 25.50.25, 100 mm
Qto_WallBaseQuantities - Length: 820; NetVolume: 0.25748; Height: 3140; Width: 100; GrossVolume: 0.25748; GrossSideArea: 2.5748; NetSideArea: 2.5748
Pset_Condition - AssessmentCondition: Empty
Pset_EnvironmentalImpactIndicators - Reference: BB_10.01.41#21_Gipskartonwand_EI60_43dB_MS100 / 25.50.25, 100 mm; sets with these values: 2
Pset_WallCommon - Reference: BB_10.01.41#21_Gipskartonwand_EI60_43dB_MS100 / 25.50.25, 100 mm; FireRating: EI60; IsExternal: yes; LoadBearing: no; ExtendToStructure: no

# IfcWall: Basic Wall_BB_10.01.41#21_Gipskartonwand_EI60_43dB_MS100 _ 25.50.25_ 100 mm71, Basic Wall:BB_10.01.41#21_Gipskartonwand_EI60_43dB_MS100 / 25.50.25, 100 mm:12550633
In: 030
PredefinedType: PARTITIONING
Cpset_Wall - LevelOfAccuracy: in te vullen door Buildwise
IfcBuildingStorey - Base Offset: -5; Top Offset: 3000; Base Constraint: 030; Top Constraint: Up to level: 030
IfcClassificationReference - Keynote: 10.01.41#21; GVH_artnr 01: 10.01.41#21; GVH_artnr 02: geen waarde gevonden; GVH_artnr 03: geen waarde gevonden; GVH_artnr 04: geen waarde gevonden; GVH_artnr 05: geen waarde gevonden; GVH_artnr 06: geen waarde gevonden; TDS_link: .\05 As Builtdossier\2. Bouwkunde\2.1 Architectuur\2.1.10 wanden\TF A 10.01.41#21 A - lichte scheidingswand met gipsplaten Rw50dB + EI60.pdf
IfcElement - BB_Element_Lokaalnummer01: K.30.503
IfcRoot - Name: BB_10.01.41#21_Gipskartonwand_EI60_43dB_MS100 / 25.50.25, 100 mm
Qto_WallBaseQuantities - Length: 5445; NetVolume: 1.64585; Height: 3005; Width: 100; GrossVolume: 1.64585; GrossSideArea: 16.4585; NetSideArea: 16.4585
Pset_Condition - AssessmentCondition: Empty
Pset_EnvironmentalImpactIndicators - Reference: BB_10.01.41#21_Gipskartonwand_EI60_43dB_MS100 / 25.50.25, 100 mm; sets with these values: 2
Pset_WallCommon - Reference: BB_10.01.41#21_Gipskartonwand_EI60_43dB_MS100 / 25.50.25, 100 mm; FireRating: EI60; IsExternal: yes; LoadBearing: no; ExtendToStructure: no

# IfcWall: Basic Wall_BB_10.01.41#21_Gipskartonwand_EI60_43dB_MS100 _ 25.50.25_ 100 mm73, Basic Wall:BB_10.01.41#21_Gipskartonwand_EI60_43dB_MS100 / 25.50.25, 100 mm:12550662
In: 030
PredefinedType: PARTITIONING
Cpset_Wall - LevelOfAccuracy: in te vullen door Buildwise
IfcBuildingStorey - Base Offset: -5; Top Offset: 3000; Base Constraint: 030; Top Constraint: Up to level: 030
IfcClassificationReference - Keynote: 10.01.41#21; GVH_artnr 01: 10.01.41#21; GVH_artnr 02: geen waarde gevonden; GVH_artnr 03: geen waarde gevonden; GVH_artnr 04: geen waarde gevonden; GVH_artnr 05: geen waarde gevonden; GVH_artnr 06: geen waarde gevonden; TDS_link: .\05 As Builtdossier\2. Bouwkunde\2.1 Architectuur\2.1.10 wanden\TF A 10.01.41#21 A - lichte scheidingswand met gipsplaten Rw50dB + EI60.pdf
IfcElement - BB_Element_Lokaalnummer01: K.30.501
IfcRoot - Name: BB_10.01.41#21_Gipskartonwand_EI60_43dB_MS100 / 25.50.25, 100 mm
Qto_WallBaseQuantities - Length: 2050; NetVolume: 0.408315; Height: 3005; Width: 100; GrossVolume: 0.408315; GrossSideArea: 4.08315; NetSideArea: 4.08315
Pset_Condition - AssessmentCondition: Empty
Pset_EnvironmentalImpactIndicators - Reference: BB_10.01.41#21_Gipskartonwand_EI60_43dB_MS100 / 25.50.25, 100 mm; sets with these values: 2
Pset_WallCommon - Reference: BB_10.01.41#21_Gipskartonwand_EI60_43dB_MS100 / 25.50.25, 100 mm; FireRating: EI60; IsExternal: yes; LoadBearing: no; ExtendToStructure: no

# IfcWall: Basic Wall_BB_10.01.41#21_Gipskartonwand_EI60_43dB_MS100 _ 25.50.25_ 100 mm75, Basic Wall:BB_10.01.41#21_Gipskartonwand_EI60_43dB_MS100 / 25.50.25, 100 mm:12553009
In: 030
PredefinedType: PARTITIONING
Cpset_Wall - LevelOfAccuracy: in te vullen door Buildwise
IfcBuildingStorey - Base Offset: -134.055; Top Offset: 3000; Base Constraint: 030; Top Constraint: Up to level: 030
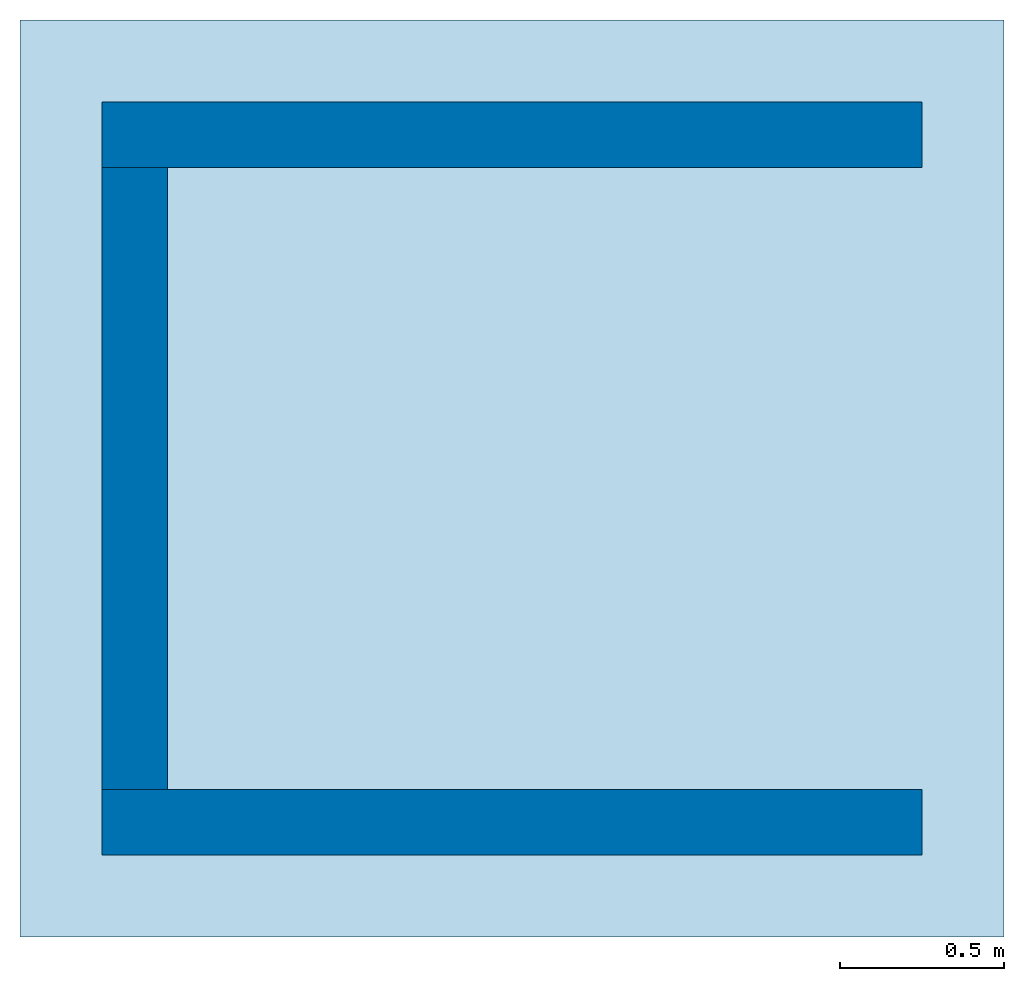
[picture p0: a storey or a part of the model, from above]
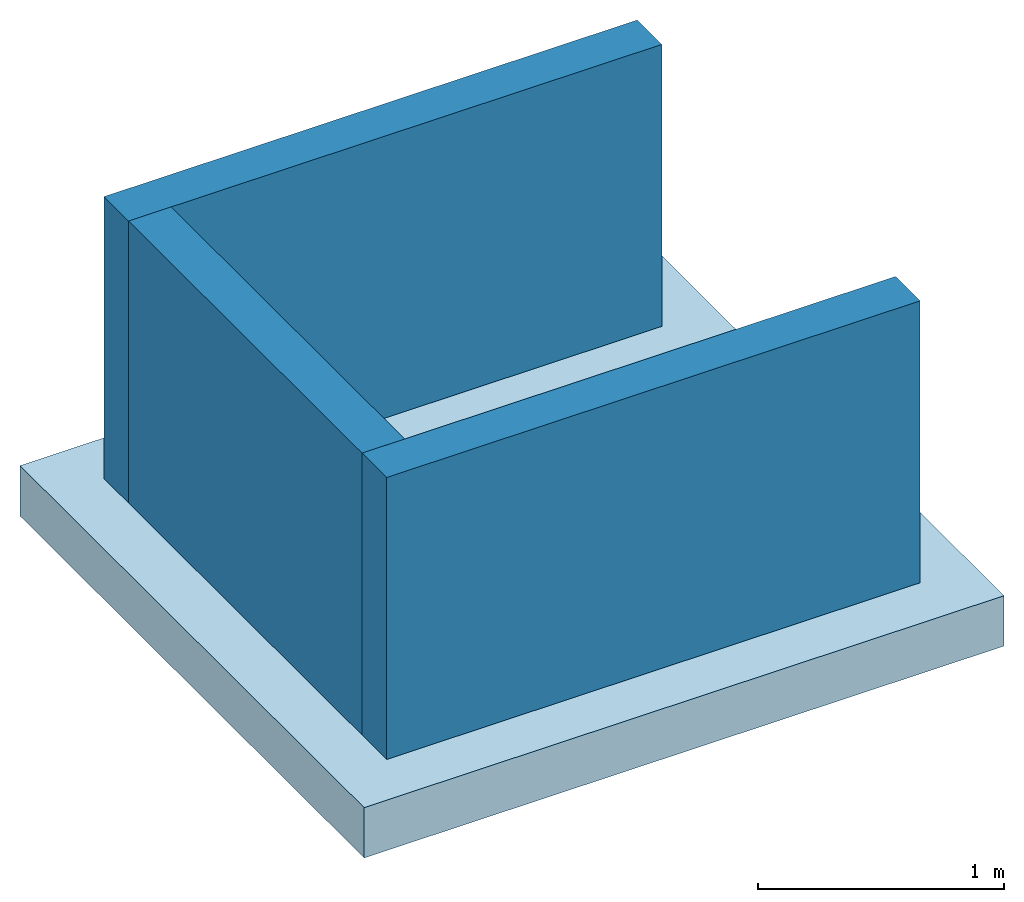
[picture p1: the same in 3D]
Properties of the parts of a building model (IFC4X3_ADD2), part 27 of 28

# IfcWall: Basic Wall_BB_10.01.41#21_Gipskartonwand_EI60_43dB_MS100 _ 25.50.25_ 100 mm75, Basic Wall:BB_10.01.41#21_Gipskartonwand_EI60_43dB_MS100 / 25.50.25, 100 mm:12553009
IfcClassificationReference - Keynote: 10.01.41#21; GVH_artnr 01: 10.01.41#21; GVH_artnr 02: geen waarde gevonden; GVH_artnr 03: geen waarde gevonden; GVH_artnr 04: geen waarde gevonden; GVH_artnr 05: geen waarde gevonden; GVH_artnr 06: geen waarde gevonden; TDS_link: .\05 As Builtdossier\2. Bouwkunde\2.1 Architectuur\2.1.10 wanden\TF A 10.01.41#21 A - lichte scheidingswand met gipsplaten Rw50dB + EI60.pdf
IfcElement - BB_Element_Lokaalnummer01: K.30.111
IfcRoot - Name: BB_10.01.41#21_Gipskartonwand_EI60_43dB_MS100 / 25.50.25, 100 mm
Qto_WallBaseQuantities - Length: 2035; NetVolume: 0.460765; Height: 3134.05; Width: 100; GrossVolume: 0.65345; GrossSideArea: 6.5345; NetSideArea: 4.60765
Pset_Condition - AssessmentCondition: Empty
Pset_EnvironmentalImpactIndicators - Reference: BB_10.01.41#21_Gipskartonwand_EI60_43dB_MS100 / 25.50.25, 100 mm; sets with these values: 2
Pset_WallCommon - Reference: BB_10.01.41#21_Gipskartonwand_EI60_43dB_MS100 / 25.50.25, 100 mm; FireRating: EI60; IsExternal: yes; LoadBearing: no; ExtendToStructure: no

# IfcWall: Basic Wall_BB_10.01.41#21_Gipskartonwand_EI60_43dB_MS100 _ 25.50.25_ 100 mm77, Basic Wall:BB_10.01.41#21_Gipskartonwand_EI60_43dB_MS100 / 25.50.25, 100 mm:12553093
In: 030
PredefinedType: PARTITIONING
Cpset_Wall - LevelOfAccuracy: in te vullen door Buildwise
IfcBuildingStorey - Base Offset: -200; Top Offset: 3000; Base Constraint: 030; Top Constraint: Up to level: 030
IfcClassificationReference - Keynote: 10.01.41#21; GVH_artnr 01: 10.01.41#21; GVH_artnr 02: geen waarde gevonden; GVH_artnr 03: geen waarde gevonden; GVH_artnr 04: geen waarde gevonden; GVH_artnr 05: geen waarde gevonden; GVH_artnr 06: geen waarde gevonden; TDS_link: .\05 As Builtdossier\2. Bouwkunde\2.1 Architectuur\2.1.10 wanden\TF A 10.01.41#21 A - lichte scheidingswand met gipsplaten Rw50dB + EI60.pdf
IfcElement - BB_Element_Lokaalnummer01: K.30.111
IfcRoot - Name: BB_10.01.41#21_Gipskartonwand_EI60_43dB_MS100 / 25.50.25, 100 mm
Qto_WallBaseQuantities - Length: 5445; NetVolume: 1.72093; Height: 3200; Width: 100; GrossVolume: 1.72093; GrossSideArea: 17.2093; NetSideArea: 17.2093
Pset_Condition - AssessmentCondition: Empty
Pset_EnvironmentalImpactIndicators - Reference: BB_10.01.41#21_Gipskartonwand_EI60_43dB_MS100 / 25.50.25, 100 mm; sets with these values: 2
Pset_WallCommon - Reference: BB_10.01.41#21_Gipskartonwand_EI60_43dB_MS100 / 25.50.25, 100 mm; FireRating: EI60; IsExternal: yes; LoadBearing: no; ExtendToStructure: no

# IfcWall: Basic Wall_BB_10.01.41#21_Gipskartonwand_EI60_43dB_MS100 _ 25.50.25_ 100 mm79, Basic Wall:BB_10.01.41#21_Gipskartonwand_EI60_43dB_MS100 / 25.50.25, 100 mm:12553601
In: 030
PredefinedType: PARTITIONING
Cpset_Wall - LevelOfAccuracy: in te vullen door Buildwise
IfcBuildingStorey - Base Offset: -5; Top Offset: 3140; Base Constraint: 030; Top Constraint: Up to level: 030
IfcClassificationReference - Keynote: 10.01.41#21; GVH_artnr 01: 10.01.41#21; GVH_artnr 02: geen waarde gevonden; GVH_artnr 03: geen waarde gevonden; GVH_artnr 04: geen waarde gevonden; GVH_artnr 05: geen waarde gevonden; GVH_artnr 06: geen waarde gevonden; TDS_link: .\05 As Builtdossier\2. Bouwkunde\2.1 Architectuur\2.1.10 wanden\TF A 10.01.41#21 A - lichte scheidingswand met gipsplaten Rw50dB + EI60.pdf
IfcElement - BB_Element_Lokaalnummer01: K.30.102
IfcRoot - Name: BB_10.01.41#21_Gipskartonwand_EI60_43dB_MS100 / 25.50.25, 100 mm
Qto_WallBaseQuantities - Length: 5288.41; NetVolume: 1.67204; Height: 3145; Width: 100; GrossVolume: 1.68777; GrossSideArea: 16.8777; NetSideArea: 16.8777
Pset_Condition - AssessmentCondition: Empty
Pset_EnvironmentalImpactIndicators - Reference: BB_10.01.41#21_Gipskartonwand_EI60_43dB_MS100 / 25.50.25, 100 mm; sets with these values: 2
Pset_WallCommon - Reference: BB_10.01.41#21_Gipskartonwand_EI60_43dB_MS100 / 25.50.25, 100 mm; FireRating: EI60; IsExternal: yes; LoadBearing: no; ExtendToStructure: no

# IfcWall: Basic Wall_BB_10.01.41#21_Gipskartonwand_EI60_43dB_MS100 _ 25.50.25_ 100 mm81, Basic Wall:BB_10.01.41#21_Gipskartonwand_EI60_43dB_MS100 / 25.50.25, 100 mm:12553663
In: 030
PredefinedType: PARTITIONING
Cpset_Wall - LevelOfAccuracy: in te vullen door Buildwise
IfcBuildingStorey - Base Offset: -5; Top Offset: 3000; Base Constraint: 030; Top Constraint: Up to level: 030
IfcClassificationReference - Keynote: 10.01.41#21; GVH_artnr 01: 10.01.41#21; GVH_artnr 02: geen waarde gevonden; GVH_artnr 03: geen waarde gevonden; GVH_artnr 04: geen waarde gevonden; GVH_artnr 05: geen waarde gevonden; GVH_artnr 06: geen waarde gevonden; TDS_link: .\05 As Builtdossier\2. Bouwkunde\2.1 Architectuur\2.1.10 wanden\TF A 10.01.41#21 A - lichte scheidingswand met gipsplaten Rw50dB + EI60.pdf
IfcElement - BB_Element_Lokaalnummer01: K.30.102
IfcRoot - Name: BB_10.01.41#21_Gipskartonwand_EI60_43dB_MS100 / 25.50.25, 100 mm
Qto_WallBaseQuantities - Length: 2565.77; NetVolume: 0.749765; Height: 3005; Width: 100; GrossVolume: 0.76479; GrossSideArea: 7.6479; NetSideArea: 7.6479
Pset_Condition - AssessmentCondition: Empty
Pset_EnvironmentalImpactIndicators - Reference: BB_10.01.41#21_Gipskartonwand_EI60_43dB_MS100 / 25.50.25, 100 mm; sets with these values: 2
Pset_WallCommon - Reference: BB_10.01.41#21_Gipskartonwand_EI60_43dB_MS100 / 25.50.25, 100 mm; FireRating: EI60; IsExternal: yes; LoadBearing: no; ExtendToStructure: no

# IfcWall: Basic Wall_BB_10.01.41#21_Gipskartonwand_EI60_43dB_MS100 _ 25.50.25_ 100 mm83, Basic Wall:BB_10.01.41#21_Gipskartonwand_EI60_43dB_MS100 / 25.50.25, 100 mm:16294762
In: 030
PredefinedType: PARTITIONING
Cpset_Wall - LevelOfAccuracy: in te vullen door Buildwise
IfcBuildingStorey - Base Offset: 2640; Top Offset: 3000; Base Constraint: 030; Top Constraint: Up to level: 030
IfcClassificationReference - Keynote: 10.01.41#21; GVH_artnr 01: 10.01.41#21; GVH_artnr 02: geen waarde gevonden; GVH_artnr 03: geen waarde gevonden; GVH_artnr 04: geen waarde gevonden; GVH_artnr 05: geen waarde gevonden; GVH_artnr 06: geen waarde gevonden; TDS_link: .\05 As Builtdossier\2. Bouwkunde\2.1 Architectuur\2.1.10 wanden\TF A 10.01.41#21 A - lichte scheidingswand met gipsplaten Rw50dB + EI60.pdf
IfcElement - BB_Element_Lokaalnummer01: K.30.509
IfcRoot - Name: BB_10.01.41#21_Gipskartonwand_EI60_43dB_MS100 / 25.50.25, 100 mm
Qto_WallBaseQuantities - Length: 13800; NetVolume: 0.4968; Height: 360; Width: 100; GrossVolume: 0.4968; GrossSideArea: 4.968; NetSideArea: 4.968
Pset_Condition - AssessmentCondition: Empty
Pset_EnvironmentalImpactIndicators - Reference: BB_10.01.41#21_Gipskartonwand_EI60_43dB_MS100 / 25.50.25, 100 mm; sets with these values: 2
Pset_WallCommon - Reference: BB_10.01.41#21_Gipskartonwand_EI60_43dB_MS100 / 25.50.25, 100 mm; FireRating: EI60; IsExternal: yes; LoadBearing: no; ExtendToStructure: no

# IfcWall: Basic Wall_BB_10.01.41#21_Gipskartonwand_EI60_43dB_MS100 _ 25.50.25_ 100 mm85, Basic Wall:BB_10.01.41#21_Gipskartonwand_EI60_43dB_MS100 / 25.50.25, 100 mm:25617102
In: 030
PredefinedType: PARTITIONING
Cpset_Wall - LevelOfAccuracy: in te vullen door Buildwise
IfcBuildingStorey - Base Offset: -10; Top Offset: -460; Base Constraint: 030; Top Constraint: Up to level: 040
IfcClassificationReference - Keynote: 10.01.41#21; GVH_artnr 01: 10.01.41#21; GVH_artnr 02: geen waarde gevonden; GVH_artnr 03: geen waarde gevonden; GVH_artnr 04: geen waarde gevonden; GVH_artnr 05: geen waarde gevonden; GVH_artnr 06: geen waarde gevonden; TDS_link: .\05 As Builtdossier\2. Bouwkunde\2.1 Architectuur\2.1.10 wanden\TF A 10.01.41#21 A - lichte scheidingswand met gipsplaten Rw50dB + EI60.pdf
IfcElement - BB_Element_Lokaalnummer01: K.30.101
IfcRoot - Name: BB_10.01.41#21_Gipskartonwand_EI60_43dB_MS100 / 25.50.25, 100 mm
Qto_WallBaseQuantities - Length: 1635; NetVolume: 0.096475; Height: 3150; Width: 100; GrossVolume: 0.096475; GrossSideArea: 0.96475; NetSideArea: 0.96475
Pset_Condition - AssessmentCondition: Empty
Pset_EnvironmentalImpactIndicators - Reference: BB_10.01.41#21_Gipskartonwand_EI60_43dB_MS100 / 25.50.25, 100 mm; sets with these values: 2
Pset_WallCommon - Reference: BB_10.01.41#21_Gipskartonwand_EI60_43dB_MS100 / 25.50.25, 100 mm; FireRating: EI60; IsExternal: yes; LoadBearing: no; ExtendToStructure: no

# IfcWall: Basic Wall_BB_10.01.41#21_Gipskartonwand_EI60_43dB_MS100 _ 25.50.25_ 100 mm87, Basic Wall:BB_10.01.41#21_Gipskartonwand_EI60_43dB_MS100 / 25.50.25, 100 mm:25617115
In: 030
PredefinedType: PARTITIONING
Cpset_Wall - LevelOfAccuracy: in te vullen door Buildwise
IfcBuildingStorey - Base Offset: -10; Top Offset: -460; Base Constraint: 030; Top Constraint: Up to level: 040
IfcClassificationReference - Keynote: 10.01.41#21; GVH_artnr 01: 10.01.41#21; GVH_artnr 02: geen waarde gevonden; GVH_artnr 03: geen waarde gevonden; GVH_artnr 04: geen waarde gevonden; GVH_artnr 05: geen waarde gevonden; GVH_artnr 06: geen waarde gevonden; TDS_link: .\05 As Builtdossier\2. Bouwkunde\2.1 Architectuur\2.1.10 wanden\TF A 10.01.41#21 A - lichte scheidingswand met gipsplaten Rw50dB + EI60.pdf
IfcElement - BB_Element_Lokaalnummer01: K.30.101
IfcRoot - Name: BB_10.01.41#21_Gipskartonwand_EI60_43dB_MS100 / 25.50.25, 100 mm
Qto_WallBaseQuantities - Length: 1642.5; NetVolume: 0.096475; Height: 3150; Width: 100; GrossVolume: 0.096475; GrossSideArea: 0.96475; NetSideArea: 0.96475
Pset_Condition - AssessmentCondition: Empty
Pset_EnvironmentalImpactIndicators - Reference: BB_10.01.41#21_Gipskartonwand_EI60_43dB_MS100 / 25.50.25, 100 mm; sets with these values: 2
Pset_WallCommon - Reference: BB_10.01.41#21_Gipskartonwand_EI60_43dB_MS100 / 25.50.25, 100 mm; FireRating: EI60; IsExternal: yes; LoadBearing: no; ExtendToStructure: no

# IfcWall: Basic Wall_BB_10.01.41#21_Gipskartonwand_EI60_43dB_MS100 _ 25.50.25_ 100 mm89, Basic Wall:BB_10.01.41#21_Gipskartonwand_EI60_43dB_MS100 / 25.50.25, 100 mm:25651512
In: 030
PredefinedType: PARTITIONING
Cpset_Wall - LevelOfAccuracy: in te vullen door Buildwise
IfcBuildingStorey - Base Offset: 2670; Top Offset: -400; Base Constraint: 030; Top Constraint: Up to level: 040
IfcClassificationReference - Keynote: 10.01.41#21; GVH_artnr 01: 10.01.41#21; GVH_artnr 02: geen waarde gevonden; GVH_artnr 03: geen waarde gevonden; GVH_artnr 04: geen waarde gevonden; GVH_artnr 05: geen waarde gevonden; GVH_artnr 06: geen waarde gevonden; TDS_link: .\05 As Builtdossier\2. Bouwkunde\2.1 Architectuur\2.1.10 wanden\TF A 10.01.41#21 A - lichte scheidingswand met gipsplaten Rw50dB + EI60.pdf
IfcElement - BB_Element_Lokaalnummer01: K.30.G14
IfcRoot - Name: BB_10.01.41#21_Gipskartonwand_EI60_43dB_MS100 / 25.50.25, 100 mm
Qto_WallBaseQuantities - Length: 2680; NetVolume: 0.14204; Height: 530; Width: 100; GrossVolume: 0.14204; GrossSideArea: 1.4204; NetSideArea: 1.4204
Pset_Condition - AssessmentCondition: Empty
Pset_EnvironmentalImpactIndicators - Reference: BB_10.01.41#21_Gipskartonwand_EI60_43dB_MS100 / 25.50.25, 100 mm; sets with these values: 2
Pset_WallCommon - Reference: BB_10.01.41#21_Gipskartonwand_EI60_43dB_MS100 / 25.50.25, 100 mm; FireRating: EI60; IsExternal: yes; LoadBearing: no; ExtendToStructure: no

# IfcWall: Basic Wall_BB_10.01.41#21_Gipskartonwand_EI60_43dB_MS100 _ 25.50.25_ 100 mm9, Basic Wall:BB_10.01.41#21_Gipskartonwand_EI60_43dB_MS100 / 25.50.25, 100 mm:25515227
In: 000
PredefinedType: PARTITIONING
Cpset_Wall - LevelOfAccuracy: in te vullen door Buildwise
IfcBuildingStorey - Base Offset: 0; Top Offset: -460; Base Constraint: 000; Top Constraint: Up to level: 010
IfcClassificationReference - Keynote: 10.01.41#21; GVH_artnr 01: 10.01.41#21; GVH_artnr 02: geen waarde gevonden; GVH_artnr 03: geen waarde gevonden; GVH_artnr 04: geen waarde gevonden; GVH_artnr 05: geen waarde gevonden; GVH_artnr 06: geen waarde gevonden; TDS_link: .\05 As Builtdossier\2. Bouwkunde\2.1 Architectuur\2.1.10 wanden\TF A 10.01.41#21 A - lichte scheidingswand met gipsplaten Rw50dB + EI60.pdf
IfcElement - BB_Element_Lokaalnummer01: K.00.502
IfcRoot - Name: BB_10.01.41#21_Gipskartonwand_EI60_43dB_MS100 / 25.50.25, 100 mm
Qto_WallBaseQuantities - Length: 1740; NetVolume: 0.127025; Height: 3140; Width: 100; GrossVolume: 0.127025; GrossSideArea: 1.27025; NetSideArea: 1.27025
Pset_Condition - AssessmentCondition: Empty
Pset_EnvironmentalImpactIndicators - Reference: BB_10.01.41#21_Gipskartonwand_EI60_43dB_MS100 / 25.50.25, 100 mm; sets with these values: 2
Pset_WallCommon - Reference: BB_10.01.41#21_Gipskartonwand_EI60_43dB_MS100 / 25.50.25, 100 mm; FireRating: EI60; IsExternal: yes; LoadBearing: no; ExtendToStructure: no

# IfcWall: Basic Wall_BB_10.01.41#21_Gipskartonwand_EI60_43dB_MS100 _ 25.50.25_ 100 mm91, Basic Wall:BB_10.01.41#21_Gipskartonwand_EI60_43dB_MS100 / 25.50.25, 100 mm:33209715
In: 030
PredefinedType: PARTITIONING
Cpset_Wall - LevelOfAccuracy: in te vullen door Buildwise
IfcBuildingStorey - Base Offset: 2640; Top Offset: 3000; Base Constraint: 030; Top Constraint: Up to level: 030
IfcClassificationReference - Keynote: 10.01.41#21; GVH_artnr 01: 10.01.41#21; GVH_artnr 02: geen waarde gevonden; GVH_artnr 03: geen waarde gevonden; GVH_artnr 04: geen waarde gevonden; GVH_artnr 05: geen waarde gevonden; GVH_artnr 06: geen waarde gevonden; TDS_link: .\05 As Builtdossier\2. Bouwkunde\2.1 Architectuur\2.1.10 wanden\TF A 10.01.41#21 A - lichte scheidingswand met gipsplaten Rw50dB + EI60.pdf
IfcElement - BB_Element_Lokaalnummer01: K.30.509
IfcRoot - Name: BB_10.01.41#21_Gipskartonwand_EI60_43dB_MS100 / 25.50.25, 100 mm
Qto_WallBaseQuantities - Length: 23215; NetVolume: 0.83574; Height: 360; Width: 100; GrossVolume: 0.83574; GrossSideArea: 8.3574; NetSideArea: 8.3574
Pset_Condition - AssessmentCondition: Empty
Pset_EnvironmentalImpactIndicators - Reference: BB_10.01.41#21_Gipskartonwand_EI60_43dB_MS100 / 25.50.25, 100 mm; sets with these values: 2
Pset_WallCommon - Reference: BB_10.01.41#21_Gipskartonwand_EI60_43dB_MS100 / 25.50.25, 100 mm; FireRating: EI60; IsExternal: yes; LoadBearing: no; ExtendToStructure: no

# IfcWall: Basic Wall_BB_10.01.41#21_Gipskartonwand_EI60_43dB_MS100 _ 25.50.25_ 100 mm93, Basic Wall:BB_10.01.41#21_Gipskartonwand_EI60_43dB_MS100 / 25.50.25, 100 mm:34782846
In: 030
PredefinedType: PARTITIONING
Cpset_Wall - LevelOfAccuracy: in te vullen door Buildwise
IfcBuildingStorey - Base Offset: 2640; Top Offset: 3000; Base Constraint: 030; Top Constraint: Up to level: 030
IfcClassificationReference - Keynote: 10.01.41#21; GVH_artnr 01: 10.01.41#21; GVH_artnr 02: geen waarde gevonden; GVH_artnr 03: geen waarde gevonden; GVH_artnr 04: geen waarde gevonden; GVH_artnr 05: geen waarde gevonden; GVH_artnr 06: geen waarde gevonden; TDS_link: .\05 As Builtdossier\2. Bouwkunde\2.1 Architectuur\2.1.10 wanden\TF A 10.01.41#21 A - lichte scheidingswand met gipsplaten Rw50dB + EI60.pdf
IfcElement - BB_Element_Lokaalnummer01: K.30.509
IfcRoot - Name: BB_10.01.41#21_Gipskartonwand_EI60_43dB_MS100 / 25.50.25, 100 mm
Qto_WallBaseQuantities - Length: 12440; NetVolume: 0.44784; Height: 360; Width: 100; GrossVolume: 0.44784; GrossSideArea: 4.4784; NetSideArea: 4.4784
Pset_Condition - AssessmentCondition: Empty
Pset_EnvironmentalImpactIndicators - Reference: BB_10.01.41#21_Gipskartonwand_EI60_43dB_MS100 / 25.50.25, 100 mm; sets with these values: 2
Pset_WallCommon - Reference: BB_10.01.41#21_Gipskartonwand_EI60_43dB_MS100 / 25.50.25, 100 mm; FireRating: EI60; IsExternal: yes; LoadBearing: no; ExtendToStructure: no

# IfcWall: Basic Wall_BB_10.01.41#xx_Brandscheidende wand_EI60_Hout 100 _ 10.100.15_ 125 mm, Basic Wall:BB_10.01.41#xx_Brandscheidende wand_EI60_Hout 100 / 10.100.15, 125 mm:27804442
In: K10
PredefinedType: PARTITIONING
Cpset_Wall - LevelOfAccuracy: in te vullen door Buildwise
IfcBuildingStorey - Base Offset: 860; Top Offset: -950; Base Constraint: K10; Top Constraint: Up to level: 000
IfcClassificationReference - Keynote: 10.01.57#01; GVH_artnr 01: 10.01.57#01; GVH_artnr 02: geen waarde gevonden; GVH_artnr 03: geen waarde gevonden; GVH_artnr 04: geen waarde gevonden; GVH_artnr 05: geen waarde gevonden; GVH_artnr 06: geen waarde gevonden; TDS_link: .\05 As Builtdossier\2. Bouwkunde\2.1 Architectuur\2.1.10 wanden\TF A 10.01.41#21 A - lichte scheidingswand met gipsplaten Rw50dB + EI60.pdf
IfcElement - BB_Element_Lokaalnummer01: K.00.303
IfcRoot - Name: BB_10.01.41#xx_Brandscheidende wand_EI60_Hout 100 / 10.100.15, 125 mm
Qto_WallBaseQuantities - Length: 137.209; NetVolume: 0.0245261; Height: 1430; Width: 125; GrossVolume: 0.0245261; GrossSideArea: 0.196209; NetSideArea: 0.196209
Pset_Condition - AssessmentCondition: Empty
Pset_EnvironmentalImpactIndicators - Reference: BB_10.01.41#xx_Brandscheidende wand_EI60_Hout 100 / 10.100.15, 125 mm; sets with these values: 2
Pset_WallCommon - Reference: BB_10.01.41#xx_Brandscheidende wand_EI60_Hout 100 / 10.100.15, 125 mm; FireRating: EI60; ThermalTransmittance: 0.64; IsExternal: yes; LoadBearing: no; ExtendToStructure: no

# IfcWall: Basic Wall_BB_10.01.41#xx_Brandscheidende wand_EI60_Hout 100 _ 10.100.15_ 125 mm1, Basic Wall:BB_10.01.41#xx_Brandscheidende wand_EI60_Hout 100 / 10.100.15, 125 mm:27804636
In: K10
PredefinedType: PARTITIONING
Cpset_Wall - LevelOfAccuracy: in te vullen door Buildwise
IfcBuildingStorey - Base Offset: 860; Top Offset: 2290; Base Constraint: K10; Top Constraint: Up to level: K10
IfcClassificationReference - Keynote: 10.01.57#01; GVH_artnr 01: 10.01.57#01; GVH_artnr 02: geen waarde gevonden; GVH_artnr 03: geen waarde gevonden; GVH_artnr 04: geen waarde gevonden; GVH_artnr 05: geen waarde gevonden; GVH_artnr 06: geen waarde gevonden; TDS_link: .\05 As Builtdossier\2. Bouwkunde\2.1 Architectuur\2.1.10 wanden\TF A 10.01.41#21 A - lichte scheidingswand met gipsplaten Rw50dB + EI60.pdf
IfcRoot - Name: BB_10.01.41#xx_Brandscheidende wand_EI60_Hout 100 / 10.100.15, 125 mm
Qto_WallBaseQuantities - Length: 135; NetVolume: 0.0241313; Height: 1430; Width: 125; GrossVolume: 0.0241312; GrossSideArea: 0.19305; NetSideArea: 0.19305
Pset_Condition - AssessmentCondition: Empty
Pset_EnvironmentalImpactIndicators - Reference: BB_10.01.41#xx_Brandscheidende wand_EI60_Hout 100 / 10.100.15, 125 mm; sets with these values: 2
Pset_WallCommon - Reference: BB_10.01.41#xx_Brandscheidende wand_EI60_Hout 100 / 10.100.15, 125 mm; FireRating: EI60; ThermalTransmittance: 0.64; IsExternal: yes; LoadBearing: no; ExtendToStructure: no

# IfcWall: Basic Wall_BB_10.01.41#xx_Brandscheidende wand_EI60_Hout 100 _ 10.100.15_ 125 mm3, Basic Wall:BB_10.01.41#xx_Brandscheidende wand_EI60_Hout 100 / 10.100.15, 125 mm:19937525
In: 000
PredefinedType: PARTITIONING
Cpset_Wall - LevelOfAccuracy: in te vullen door Buildwise
IfcBuildingStorey - Base Offset: 860; Top Offset: -920; Base Constraint: 000; Top Constraint: Up to level: 010
IfcClassificationReference - Keynote: 10.01.57#01; GVH_artnr 01: 10.01.57#01; GVH_artnr 02: geen waarde gevonden; GVH_artnr 03: geen waarde gevonden; GVH_artnr 04: geen waarde gevonden; GVH_artnr 05: geen waarde gevonden; GVH_artnr 06: geen waarde gevonden; TDS_link: .\05 As Builtdossier\2. Bouwkunde\2.1 Architectuur\2.1.10 wanden\TF A 10.01.41#21 A - lichte scheidingswand met gipsplaten Rw50dB + EI60.pdf
IfcElement - BB_Element_Lokaalnummer01: K.00.303
IfcRoot - Name: BB_10.01.41#xx_Brandscheidende wand_EI60_Hout 100 / 10.100.15, 125 mm
Qto_WallBaseQuantities - Length: 98.2529; NetVolume: 0.0223525; Height: 1820; Width: 125; GrossVolume: 0.0284375; GrossSideArea: 0.2275; NetSideArea: 0.2275
Pset_Condition - AssessmentCondition: Empty
Pset_EnvironmentalImpactIndicators - Reference: BB_10.01.41#xx_Brandscheidende wand_EI60_Hout 100 / 10.100.15, 125 mm; sets with these values: 2
Pset_WallCommon - Reference: BB_10.01.41#xx_Brandscheidende wand_EI60_Hout 100 / 10.100.15, 125 mm; FireRating: EI60; ThermalTransmittance: 0.64; IsExternal: yes; LoadBearing: no; ExtendToStructure: no

# IfcWall: Basic Wall_BB_10.01.62#01_Voorzetwand gipskarton_MS75 _ 50.25_ 75 mm, Basic Wall:BB_10.01.62#01_Voorzetwand gipskarton_MS75 / 50.25, 75 mm:23685106
In: K10
PredefinedType: PARTITIONING
Cpset_Wall - LevelOfAccuracy: in te vullen door Buildwise
IfcBuildingStorey - Base Offset: -200; Top Offset: -530; Base Constraint: K10; Top Constraint: Up to level: 000
IfcClassificationReference - Keynote: 10.01.62#01; GVH_artnr 01: 10.01.62#01; GVH_artnr 02: geen waarde gevonden; GVH_artnr 03: geen waarde gevonden; GVH_artnr 04: geen waarde gevonden; GVH_artnr 05: geen waarde gevonden; GVH_artnr 06: geen waarde gevonden; TDS_link: .\05 As Builtdossier\2. Bouwkunde\2.1 Architectuur\2.1.10 wanden\TF A 10.01.62#01 A - Schachtenwanden met gipsplaten op metalen skelet - EI60.pdf
IfcElement - BB_Element_Lokaalnummer01: K.-1.302
IfcRoot - Name: BB_10.01.62#01_Voorzetwand gipskarton_MS75 / 50.25, 75 mm
Qto_WallBaseQuantities - Length: 2447.69; NetVolume: 0.477767; Height: 2910; Width: 75; GrossVolume: 0.495374; GrossSideArea: 6.60498; NetSideArea: 6.60498
Pset_Condition - AssessmentCondition: Empty
Pset_EnvironmentalImpactIndicators - Reference: BB_10.01.62#01_Voorzetwand gipskarton_MS75 / 50.25, 75 mm; sets with these values: 2
Pset_WallCommon - Reference: BB_10.01.62#01_Voorzetwand gipskarton_MS75 / 50.25, 75 mm; FireRating: EI60; IsExternal: yes; LoadBearing: no; ExtendToStructure: no

# IfcWall: Basic Wall_BB_10.01.62#01_Voorzetwand gipskarton_MS75 _ 50.25_ 75 mm1, Basic Wall:BB_10.01.62#01_Voorzetwand gipskarton_MS75 / 50.25, 75 mm:13046146
In: 000
PredefinedType: PARTITIONING
Cpset_Wall - LevelOfAccuracy: in te vullen door Buildwise
IfcBuildingStorey - Base Offset: -200; Top Offset: 3000; Base Constraint: 000; Top Constraint: Up to level: 000
IfcClassificationReference - Keynote: 10.01.62#01; GVH_artnr 01: 10.01.41#01; GVH_artnr 02: geen waarde gevonden; GVH_artnr 03: geen waarde gevonden; GVH_artnr 04: geen waarde gevonden; GVH_artnr 05: geen waarde gevonden; GVH_artnr 06: geen waarde gevonden; TDS_link: .\05 As Builtdossier\2. Bouwkunde\2.1 Architectuur\2.1.10 wanden\TF A 10.01.62#01 A - Schachtenwanden met gipsplaten op metalen skelet - EI60.pdf
IfcElement - BB_Element_Lokaalnummer01: K.00.404
IfcRoot - Name: BB_10.01.62#01_Voorzetwand gipskarton_MS75 / 50.25, 75 mm
Qto_WallBaseQuantities - Length: 1150; NetVolume: 0.27; Height: 3000; Width: 75; GrossVolume: 0.27; GrossSideArea: 3.6; NetSideArea: 3.6
Pset_Condition - AssessmentCondition: Empty
Pset_EnvironmentalImpactIndicators - Reference: BB_10.01.62#01_Voorzetwand gipskarton_MS75 / 50.25, 75 mm; sets with these values: 2
Pset_WallCommon - Reference: BB_10.01.62#01_Voorzetwand gipskarton_MS75 / 50.25, 75 mm; FireRating: EI60; IsExternal: yes; LoadBearing: no; ExtendToStructure: no

# IfcWall: Basic Wall_BB_10.01.62#01_Voorzetwand gipskarton_MS75 _ 50.25_ 75 mm11, Basic Wall:BB_10.01.62#01_Voorzetwand gipskarton_MS75 / 50.25, 75 mm:34785332
In: 000
PredefinedType: PARTITIONING
Cpset_Wall - LevelOfAccuracy: in te vullen door Buildwise
IfcBuildingStorey - Base Offset: 0; Top Offset: 2200; Base Constraint: 000; Top Constraint: Up to level: 000
IfcClassificationReference - Keynote: 10.01.62#01; GVH_artnr 01: 10.01.62#01; GVH_artnr 02: geen waarde gevonden; GVH_artnr 03: geen waarde gevonden; GVH_artnr 04: geen waarde gevonden; GVH_artnr 05: geen waarde gevonden; GVH_artnr 06: geen waarde gevonden; TDS_link: .\05 As Builtdossier\2. Bouwkunde\2.1 Architectuur\2.1.10 wanden\TF A 10.01.62#01 A - Schachtenwanden met gipsplaten op metalen skelet - EI60.pdf
IfcElement - BB_Element_Lokaalnummer01: K.00.404
IfcRoot - Name: BB_10.01.62#01_Voorzetwand gipskarton_MS75 / 50.25, 75 mm
Qto_WallBaseQuantities - Length: 2550.5; NetVolume: 0.414645; Height: 2200; Width: 75; GrossVolume: 0.414645; GrossSideArea: 5.5286; NetSideArea: 5.5286
Pset_Condition - AssessmentCondition: Empty
Pset_EnvironmentalImpactIndicators - Reference: BB_10.01.62#01_Voorzetwand gipskarton_MS75 / 50.25, 75 mm; sets with these values: 2
Pset_WallCommon - Reference: BB_10.01.62#01_Voorzetwand gipskarton_MS75 / 50.25, 75 mm; FireRating: EI60; IsExternal: yes; LoadBearing: no; ExtendToStructure: no

# IfcWall: Basic Wall_BB_10.01.62#01_Voorzetwand gipskarton_MS75 _ 50.25_ 75 mm13, Basic Wall:BB_10.01.62#01_Voorzetwand gipskarton_MS75 / 50.25, 75 mm:34824072
In: 000
PredefinedType: PARTITIONING
Cpset_Wall - LevelOfAccuracy: in te vullen door Buildwise
IfcBuildingStorey - Base Offset: 0; Top Offset: 2200; Base Constraint: 000; Top Constraint: Up to level: 000
IfcClassificationReference - Keynote: 10.01.62#01; TDS_link: .\05 As Builtdossier\2. Bouwkunde\2.1 Architectuur\2.1.10 wanden\TF A 10.01.62#01 A - Schachtenwanden met gipsplaten op metalen skelet - EI60.pdf
IfcRoot - Name: BB_10.01.62#01_Voorzetwand gipskarton_MS75 / 50.25, 75 mm
Qto_WallBaseQuantities - Length: 609.5; NetVolume: 0.100568; Height: 2200; Width: 75; GrossVolume: 0.100568; GrossSideArea: 1.3409; NetSideArea: 1.3409
Pset_Condition - AssessmentCondition: Empty
Pset_EnvironmentalImpactIndicators - Reference: BB_10.01.62#01_Voorzetwand gipskarton_MS75 / 50.25, 75 mm; sets with these values: 2
Pset_WallCommon - Reference: BB_10.01.62#01_Voorzetwand gipskarton_MS75 / 50.25, 75 mm; FireRating: EI60; IsExternal: yes; LoadBearing: no; ExtendToStructure: no

# IfcWall: Basic Wall_BB_10.01.62#01_Voorzetwand gipskarton_MS75 _ 50.25_ 75 mm15, Basic Wall:BB_10.01.62#01_Voorzetwand gipskarton_MS75 / 50.25, 75 mm:23684418
In: 010
PredefinedType: PARTITIONING
Cpset_Wall - LevelOfAccuracy: in te vullen door Buildwise
IfcBuildingStorey - Base Offset: -200; Top Offset: -200; Base Constraint: 010; Top Constraint: Up to level: 020
IfcClassificationReference - Keynote: 10.01.62#01; GVH_artnr 01: 10.01.62#01; GVH_artnr 02: geen waarde gevonden; GVH_artnr 03: geen waarde gevonden; GVH_artnr 04: geen waarde gevonden; GVH_artnr 05: geen waarde gevonden; GVH_artnr 06: geen waarde gevonden; TDS_link: .\05 As Builtdossier\2. Bouwkunde\2.1 Architectuur\2.1.10 wanden\TF A 10.01.62#01 A - Schachtenwanden met gipsplaten op metalen skelet - EI60.pdf
IfcElement - BB_Element_Lokaalnummer01: K.10.K45
IfcRoot - Name: BB_10.01.62#01_Voorzetwand gipskarton_MS75 / 50.25, 75 mm
Qto_WallBaseQuantities - Length: 2495.49; NetVolume: 0.672087; Height: 3600; Width: 75; GrossVolume: 0.68699; GrossSideArea: 9.15986; NetSideArea: 9.15986
Pset_Condition - AssessmentCondition: Empty
Pset_EnvironmentalImpactIndicators - Reference: BB_10.01.62#01_Voorzetwand gipskarton_MS75 / 50.25, 75 mm; sets with these values: 2
Pset_WallCommon - Reference: BB_10.01.62#01_Voorzetwand gipskarton_MS75 / 50.25, 75 mm; FireRating: EI60; IsExternal: yes; LoadBearing: no; ExtendToStructure: no

# IfcWall: Basic Wall_BB_10.01.62#01_Voorzetwand gipskarton_MS75 _ 50.25_ 75 mm17, Basic Wall:BB_10.01.62#01_Voorzetwand gipskarton_MS75 / 50.25, 75 mm:23686883
In: 010
PredefinedType: PARTITIONING
Cpset_Wall - LevelOfAccuracy: in te vullen door Buildwise
IfcBuildingStorey - Base Offset: -200; Top Offset: -530; Base Constraint: 010; Top Constraint: Up to level: 020
IfcClassificationReference - Keynote: 10.01.62#01; GVH_artnr 01: 10.01.62#01; GVH_artnr 02: geen waarde gevonden; GVH_artnr 03: geen waarde gevonden; GVH_artnr 04: geen waarde gevonden; GVH_artnr 05: geen waarde gevonden; GVH_artnr 06: geen waarde gevonden; TDS_link: .\05 As Builtdossier\2. Bouwkunde\2.1 Architectuur\2.1.10 wanden\TF A 10.01.62#01 A - Schachtenwanden met gipsplaten op metalen skelet - EI60.pdf
IfcElement - BB_Element_Lokaalnummer01: K.10.K46
IfcRoot - Name: BB_10.01.62#01_Voorzetwand gipskarton_MS75 / 50.25, 75 mm
Qto_WallBaseQuantities - Length: 2592.99; NetVolume: 0.628465; Height: 3270; Width: 75; GrossVolume: 0.635931; GrossSideArea: 8.47909; NetSideArea: 8.47909
Pset_Condition - AssessmentCondition: Empty
Pset_EnvironmentalImpactIndicators - Reference: BB_10.01.62#01_Voorzetwand gipskarton_MS75 / 50.25, 75 mm; sets with these values: 2
Pset_WallCommon - Reference: BB_10.01.62#01_Voorzetwand gipskarton_MS75 / 50.25, 75 mm; FireRating: EI60; IsExternal: yes; LoadBearing: no; ExtendToStructure: no

# IfcWall: Basic Wall_BB_10.01.62#01_Voorzetwand gipskarton_MS75 _ 50.25_ 75 mm19, Basic Wall:BB_10.01.62#01_Voorzetwand gipskarton_MS75 / 50.25, 75 mm:27877601
In: 010
PredefinedType: PARTITIONING
Cpset_Wall - LevelOfAccuracy: in te vullen door Buildwise
IfcBuildingStorey - Base Offset: -5; Top Offset: -530; Base Constraint: 010; Top Constraint: Up to level: 020
IfcClassificationReference - Keynote: 10.01.62#01; GVH_artnr 01: 10.01.62#01; GVH_artnr 02: geen waarde gevonden; GVH_artnr 03: geen waarde gevonden; GVH_artnr 04: geen waarde gevonden; GVH_artnr 05: geen waarde gevonden; GVH_artnr 06: geen waarde gevonden; TDS_link: .\05 As Builtdossier\2. Bouwkunde\2.1 Architectuur\2.1.10 wanden\TF A 10.01.62#01 A - Schachtenwanden met gipsplaten op metalen skelet - EI60.pdf
IfcRoot - Name: BB_10.01.62#01_Voorzetwand gipskarton_MS75 / 50.25, 75 mm
Qto_WallBaseQuantities - Length: 1428.08; NetVolume: 0.285468; Height: 3075; Width: 75; GrossVolume: 0.294116; GrossSideArea: 3.92155; NetSideArea: 3.92155
Pset_Condition - AssessmentCondition: Empty
Pset_EnvironmentalImpactIndicators - Reference: BB_10.01.62#01_Voorzetwand gipskarton_MS75 / 50.25, 75 mm; sets with these values: 2
Pset_WallCommon - Reference: BB_10.01.62#01_Voorzetwand gipskarton_MS75 / 50.25, 75 mm; FireRating: EI60; IsExternal: yes; LoadBearing: no; ExtendToStructure: no

# IfcWall: Basic Wall_BB_10.01.62#01_Voorzetwand gipskarton_MS75 _ 50.25_ 75 mm21, Basic Wall:BB_10.01.62#01_Voorzetwand gipskarton_MS75 / 50.25, 75 mm:23685103
In: 020
PredefinedType: PARTITIONING
Cpset_Wall - LevelOfAccuracy: in te vullen door Buildwise
IfcBuildingStorey - Base Offset: -200; Top Offset: -530; Base Constraint: 020; Top Constraint: Up to level: 030
IfcClassificationReference - Keynote: 10.01.62#01; GVH_artnr 01: 10.01.62#01; GVH_artnr 02: geen waarde gevonden; GVH_artnr 03: geen waarde gevonden; GVH_artnr 04: geen waarde gevonden; GVH_artnr 05: geen waarde gevonden; GVH_artnr 06: geen waarde gevonden; TDS_link: .\05 As Builtdossier\2. Bouwkunde\2.1 Architectuur\2.1.10 wanden\TF A 10.01.62#01 A - Schachtenwanden met gipsplaten op metalen skelet - EI60.pdf
IfcElement - BB_Element_Lokaalnummer01: K.20.301
IfcRoot - Name: BB_10.01.62#01_Voorzetwand gipskarton_MS75 / 50.25, 75 mm
Qto_WallBaseQuantities - Length: 2632.56; NetVolume: 0.587852; Height: 3270; Width: 75; GrossVolume: 0.607636; GrossSideArea: 8.10182; NetSideArea: 8.10182
Pset_Condition - AssessmentCondition: Empty
Pset_EnvironmentalImpactIndicators - Reference: BB_10.01.62#01_Voorzetwand gipskarton_MS75 / 50.25, 75 mm; sets with these values: 2
Pset_WallCommon - Reference: BB_10.01.62#01_Voorzetwand gipskarton_MS75 / 50.25, 75 mm; FireRating: EI60; IsExternal: yes; LoadBearing: no; ExtendToStructure: no

# IfcWall: Basic Wall_BB_10.01.62#01_Voorzetwand gipskarton_MS75 _ 50.25_ 75 mm23, Basic Wall:BB_10.01.62#01_Voorzetwand gipskarton_MS75 / 50.25, 75 mm:23686999
In: 020
PredefinedType: PARTITIONING
Cpset_Wall - LevelOfAccuracy: in te vullen door Buildwise
IfcBuildingStorey - Base Offset: -200; Top Offset: -630; Base Constraint: 020; Top Constraint: Up to level: 030
IfcClassificationReference - Keynote: 10.01.62#01; GVH_artnr 01: 10.01.62#01; GVH_artnr 02: geen waarde gevonden; GVH_artnr 03: geen waarde gevonden; GVH_artnr 04: geen waarde gevonden; GVH_artnr 05: geen waarde gevonden; GVH_artnr 06: geen waarde gevonden; TDS_link: .\05 As Builtdossier\2. Bouwkunde\2.1 Architectuur\2.1.10 wanden\TF A 10.01.62#01 A - Schachtenwanden met gipsplaten op metalen skelet - EI60.pdf
IfcElement - BB_Element_Lokaalnummer01: K.20.301
IfcRoot - Name: BB_10.01.62#01_Voorzetwand gipskarton_MS75 / 50.25, 75 mm
Qto_WallBaseQuantities - Length: 2580; NetVolume: 0.613395; Height: 3170; Width: 75; GrossVolume: 0.613395; GrossSideArea: 8.1786; NetSideArea: 8.1786
Pset_Condition - AssessmentCondition: Empty
Pset_EnvironmentalImpactIndicators - Reference: BB_10.01.62#01_Voorzetwand gipskarton_MS75 / 50.25, 75 mm; sets with these values: 2
Pset_WallCommon - Reference: BB_10.01.62#01_Voorzetwand gipskarton_MS75 / 50.25, 75 mm; FireRating: EI60; IsExternal: yes; LoadBearing: no; ExtendToStructure: no

# IfcWall: Basic Wall_BB_10.01.62#01_Voorzetwand gipskarton_MS75 _ 50.25_ 75 mm25, Basic Wall:BB_10.01.62#01_Voorzetwand gipskarton_MS75 / 50.25, 75 mm:25607600
In: 020
PredefinedType: PARTITIONING
Cpset_Wall - LevelOfAccuracy: in te vullen door Buildwise
IfcBuildingStorey - Base Offset: -200; Top Offset: -530; Base Constraint: 020; Top Constraint: Up to level: 030
IfcClassificationReference - Keynote: 10.01.62#01; GVH_artnr 01: 10.01.62#01; GVH_artnr 02: geen waarde gevonden; GVH_artnr 03: geen waarde gevonden; GVH_artnr 04: geen waarde gevonden; GVH_artnr 05: geen waarde gevonden; GVH_artnr 06: geen waarde gevonden; TDS_link: .\05 As Builtdossier\2. Bouwkunde\2.1 Architectuur\2.1.10 wanden\TF A 10.01.62#01 A - Schachtenwanden met gipsplaten op metalen skelet - EI60.pdf
IfcRoot - Name: BB_10.01.62#01_Voorzetwand gipskarton_MS75 / 50.25, 75 mm
Qto_WallBaseQuantities - Length: 148.5; NetVolume: 0.0437771; Height: 3270; Width: 75; GrossVolume: 0.0437771; GrossSideArea: 0.583695; NetSideArea: 0.583695
Pset_Condition - AssessmentCondition: Empty
Pset_EnvironmentalImpactIndicators - Reference: BB_10.01.62#01_Voorzetwand gipskarton_MS75 / 50.25, 75 mm; sets with these values: 2
Pset_WallCommon - Reference: BB_10.01.62#01_Voorzetwand gipskarton_MS75 / 50.25, 75 mm; FireRating: EI60; IsExternal: yes; LoadBearing: no; ExtendToStructure: no

# IfcWall: Basic Wall_BB_10.01.62#01_Voorzetwand gipskarton_MS75 _ 50.25_ 75 mm27, Basic Wall:BB_10.01.62#01_Voorzetwand gipskarton_MS75 / 50.25, 75 mm:25607641
In: 020
PredefinedType: PARTITIONING
Cpset_Wall - LevelOfAccuracy: in te vullen door Buildwise
IfcBuildingStorey - Base Offset: -200; Top Offset: -530; Base Constraint: 020; Top Constraint: Up to level: 030
IfcClassificationReference - Keynote: 10.01.62#01; GVH_artnr 01: 10.01.62#01; GVH_artnr 02: geen waarde gevonden; GVH_artnr 03: geen waarde gevonden; GVH_artnr 04: geen waarde gevonden; GVH_artnr 05: geen waarde gevonden; GVH_artnr 06: geen waarde gevonden; TDS_link: .\05 As Builtdossier\2. Bouwkunde\2.1 Architectuur\2.1.10 wanden\TF A 10.01.62#01 A - Schachtenwanden met gipsplaten op metalen skelet - EI60.pdf
IfcRoot - Name: BB_10.01.62#01_Voorzetwand gipskarton_MS75 / 50.25, 75 mm
Qto_WallBaseQuantities - Length: 1408.08; NetVolume: 0.301452; Height: 3270; Width: 75; GrossVolume: 0.310649; GrossSideArea: 4.14199; NetSideArea: 4.14199
Pset_Condition - AssessmentCondition: Empty
Pset_EnvironmentalImpactIndicators - Reference: BB_10.01.62#01_Voorzetwand gipskarton_MS75 / 50.25, 75 mm; sets with these values: 2
Pset_WallCommon - Reference: BB_10.01.62#01_Voorzetwand gipskarton_MS75 / 50.25, 75 mm; FireRating: EI60; IsExternal: yes; LoadBearing: no; ExtendToStructure: no

# IfcWall: Basic Wall_BB_10.01.62#01_Voorzetwand gipskarton_MS75 _ 50.25_ 75 mm29, Basic Wall:BB_10.01.62#01_Voorzetwand gipskarton_MS75 / 50.25, 75 mm:25333830
In: 030
PredefinedType: PARTITIONING
Cpset_Wall - LevelOfAccuracy: in te vullen door Buildwise
IfcBuildingStorey - Base Offset: -200; Top Offset: -410; Base Constraint: 030; Top Constraint: Up to level: 040
IfcClassificationReference - Keynote: 10.01.62#01; GVH_artnr 01: 10.01.62#01; GVH_artnr 02: geen waarde gevonden; GVH_artnr 03: geen waarde gevonden; GVH_artnr 04: geen waarde gevonden; GVH_artnr 05: geen waarde gevonden; GVH_artnr 06: geen waarde gevonden; TDS_link: .\05 As Builtdossier\2. Bouwkunde\2.1 Architectuur\2.1.10 wanden\TF A 10.01.62#01 A - Schachtenwanden met gipsplaten op metalen skelet - EI60.pdf
IfcRoot - Name: BB_10.01.62#01_Voorzetwand gipskarton_MS75 / 50.25, 75 mm
Qto_WallBaseQuantities - Length: 4885; NetVolume: 1.24201; Height: 3390; Width: 75; GrossVolume: 1.24201; GrossSideArea: 16.5601; NetSideArea: 16.5601
Pset_Condition - AssessmentCondition: Empty
Pset_EnvironmentalImpactIndicators - Reference: BB_10.01.62#01_Voorzetwand gipskarton_MS75 / 50.25, 75 mm; sets with these values: 2
Pset_WallCommon - Reference: BB_10.01.62#01_Voorzetwand gipskarton_MS75 / 50.25, 75 mm; FireRating: EI60; IsExternal: yes; LoadBearing: no; ExtendToStructure: no

# IfcWall: Basic Wall_BB_10.01.62#01_Voorzetwand gipskarton_MS75 _ 50.25_ 75 mm3, Basic Wall:BB_10.01.62#01_Voorzetwand gipskarton_MS75 / 50.25, 75 mm:19974042
In: 000
PredefinedType: PARTITIONING
Cpset_Wall - LevelOfAccuracy: in te vullen door Buildwise
IfcBuildingStorey - Base Offset: 0; Top Offset: 2910; Base Constraint: 000; Top Constraint: Up to level: 000
IfcClassificationReference - Keynote: 10.01.62#01; GVH_artnr 01: 10.01.62#01; GVH_artnr 02: geen waarde gevonden; GVH_artnr 03: geen waarde gevonden; GVH_artnr 04: geen waarde gevonden; GVH_artnr 05: geen waarde gevonden; GVH_artnr 06: geen waarde gevonden; TDS_link: .\05 As Builtdossier\2. Bouwkunde\2.1 Architectuur\2.1.10 wanden\TF A 10.01.62#01 A - Schachtenwanden met gipsplaten op metalen skelet - EI60.pdf
IfcElement - BB_Element_Lokaalnummer01: K.00.404
IfcRoot - Name: BB_10.01.62#01_Voorzetwand gipskarton_MS75 / 50.25, 75 mm
Qto_WallBaseQuantities - Length: 4557.5; NetVolume: 0.517415; Height: 2910; Width: 75; GrossVolume: 0.571846; GrossSideArea: 7.62461; NetSideArea: 6.90461
Pset_Condition - AssessmentCondition: Empty
Pset_EnvironmentalImpactIndicators - Reference: BB_10.01.62#01_Voorzetwand gipskarton_MS75 / 50.25, 75 mm; sets with these values: 2
Pset_WallCommon - Reference: BB_10.01.62#01_Voorzetwand gipskarton_MS75 / 50.25, 75 mm; FireRating: EI60; IsExternal: yes; LoadBearing: no; ExtendToStructure: no

# IfcWall: Basic Wall_BB_10.01.62#01_Voorzetwand gipskarton_MS75 _ 50.25_ 75 mm5, Basic Wall:BB_10.01.62#01_Voorzetwand gipskarton_MS75 / 50.25, 75 mm:19974204
In: 000
PredefinedType: PARTITIONING
Cpset_Wall - LevelOfAccuracy: in te vullen door Buildwise
IfcBuildingStorey - Base Offset: 0; Top Offset: 2200; Base Constraint: 000; Top Constraint: Up to level: 000
IfcClassificationReference - Keynote: 10.01.62#01; GVH_artnr 01: 10.01.62#01; GVH_artnr 02: geen waarde gevonden; GVH_artnr 03: geen waarde gevonden; GVH_artnr 04: geen waarde gevonden; GVH_artnr 05: geen waarde gevonden; GVH_artnr 06: geen waarde gevonden; TDS_link: .\05 As Builtdossier\2. Bouwkunde\2.1 Architectuur\2.1.10 wanden\TF A 10.01.62#01 A - Schachtenwanden met gipsplaten op metalen skelet - EI60.pdf
IfcElement - BB_Element_Lokaalnummer01: K.00.404
IfcRoot - Name: BB_10.01.62#01_Voorzetwand gipskarton_MS75 / 50.25, 75 mm
Qto_WallBaseQuantities - Length: 609.5; NetVolume: 0.100568; Height: 2200; Width: 75; GrossVolume: 0.100568; GrossSideArea: 1.3409; NetSideArea: 1.3409
Pset_Condition - AssessmentCondition: Empty
Pset_EnvironmentalImpactIndicators - Reference: BB_10.01.62#01_Voorzetwand gipskarton_MS75 / 50.25, 75 mm; sets with these values: 2
Pset_WallCommon - Reference: BB_10.01.62#01_Voorzetwand gipskarton_MS75 / 50.25, 75 mm; FireRating: EI60; IsExternal: yes; LoadBearing: no; ExtendToStructure: no

# IfcWall: Basic Wall_BB_10.01.62#01_Voorzetwand gipskarton_MS75 _ 50.25_ 75 mm7, Basic Wall:BB_10.01.62#01_Voorzetwand gipskarton_MS75 / 50.25, 75 mm:23686996
In: 000
PredefinedType: PARTITIONING
Cpset_Wall - LevelOfAccuracy: in te vullen door Buildwise
IfcBuildingStorey - Base Offset: -5; Top Offset: 2540; Base Constraint: 000; Top Constraint: Up to level: 000
IfcClassificationReference - Keynote: 10.01.62#01; GVH_artnr 01: 10.01.62#01; GVH_artnr 02: geen waarde gevonden; GVH_artnr 03: geen waarde gevonden; GVH_artnr 04: geen waarde gevonden; GVH_artnr 05: geen waarde gevonden; GVH_artnr 06: geen waarde gevonden; TDS_link: .\05 As Builtdossier\2. Bouwkunde\2.1 Architectuur\2.1.10 wanden\TF A 10.01.62#01 A - Schachtenwanden met gipsplaten op metalen skelet - EI60.pdf
IfcElement - BB_Element_Lokaalnummer01: K.00.K46
IfcRoot - Name: BB_10.01.62#01_Voorzetwand gipskarton_MS75 / 50.25, 75 mm
Qto_WallBaseQuantities - Length: 2577.99; NetVolume: 0.486282; Height: 2545; Width: 75; GrossVolume: 0.492074; GrossSideArea: 6.56099; NetSideArea: 6.56099
Pset_Condition - AssessmentCondition: Empty
Pset_EnvironmentalImpactIndicators - Reference: BB_10.01.62#01_Voorzetwand gipskarton_MS75 / 50.25, 75 mm; sets with these values: 2
Pset_WallCommon - Reference: BB_10.01.62#01_Voorzetwand gipskarton_MS75 / 50.25, 75 mm; FireRating: EI60; IsExternal: yes; LoadBearing: no; ExtendToStructure: no

# IfcWall: Basic Wall_BB_10.01.62#01_Voorzetwand gipskarton_MS75 _ 50.25_ 75 mm9, Basic Wall:BB_10.01.62#01_Voorzetwand gipskarton_MS75 / 50.25, 75 mm:32133535
In: 000
PredefinedType: PARTITIONING
Cpset_Wall - LevelOfAccuracy: in te vullen door Buildwise
IfcBuildingStorey - Base Offset: 0; Top Offset: -200; Base Constraint: 000; Top Constraint: Up to level: 010
IfcClassificationReference - Keynote: 10.01.62#01; GVH_artnr 01: 10.01.62#01; GVH_artnr 02: geen waarde gevonden; GVH_artnr 03: geen waarde gevonden; GVH_artnr 04: geen waarde gevonden; GVH_artnr 05: geen waarde gevonden; GVH_artnr 06: geen waarde gevonden; TDS_link: .\05 As Builtdossier\2. Bouwkunde\2.1 Architectuur\2.1.10 wanden\TF A 10.01.62#01 A - Schachtenwanden met gipsplaten op metalen skelet - EI60.pdf
IfcElement - BB_Element_Lokaalnummer01: K.-1.302
IfcRoot - Name: BB_10.01.62#01_Voorzetwand gipskarton_MS75 / 50.25, 75 mm
Qto_WallBaseQuantities - Length: 2592.77; NetVolume: 0.626578; Height: 3400; Width: 75; GrossVolume: 0.644186; GrossSideArea: 8.58915; NetSideArea: 8.58915
Pset_Condition - AssessmentCondition: Empty
Pset_EnvironmentalImpactIndicators - Reference: BB_10.01.62#01_Voorzetwand gipskarton_MS75 / 50.25, 75 mm; sets with these values: 2
Pset_WallCommon - Reference: BB_10.01.62#01_Voorzetwand gipskarton_MS75 / 50.25, 75 mm; FireRating: EI60; IsExternal: yes; LoadBearing: no; ExtendToStructure: no

# IfcWall: Basic Wall_BB_10.01.62#02_Voorzetwand gipskarton_ sanitair_MS75 _ 50.25_ 75 mm11, Basic Wall:BB_10.01.62#02_Voorzetwand gipskarton, sanitair_MS75 / 50.25, 75 mm:26538921
In: 000
PredefinedType: PARTITIONING
Cpset_Wall - LevelOfAccuracy: in te vullen door Buildwise
IfcBuildingStorey - Base Offset: -10; Top Offset: 2740; Base Constraint: 000; Top Constraint: Up to level: 000
IfcClassificationReference - Keynote: 10.01.62#02; GVH_artnr 01: 10.01.62#02; GVH_artnr 02: geen waarde gevonden; GVH_artnr 03: geen waarde gevonden; GVH_artnr 04: geen waarde gevonden; GVH_artnr 05: geen waarde gevonden; GVH_artnr 06: geen waarde gevonden; TDS_link: .\05 As Builtdossier\2. Bouwkunde\2.1 Architectuur\2.1.10 wanden\TF A 10.01.62#02 A - Schachtenwanden met gipsplaten op metalen skelet - vochtwerend.pdf
IfcRoot - Name: BB_10.01.62#02_Voorzetwand gipskarton, sanitair_MS75 / 50.25, 75 mm
Qto_WallBaseQuantities - Length: 1620; NetVolume: 0.334125; Height: 2750; Width: 75; GrossVolume: 0.334125; GrossSideArea: 4.455; NetSideArea: 4.455
Pset_Condition - AssessmentCondition: Empty
Pset_EnvironmentalImpactIndicators - Reference: BB_10.01.62#02_Voorzetwand gipskarton, sanitair_MS75 / 50.25, 75 mm; sets with these values: 2
Pset_WallCommon - Reference: BB_10.01.62#02_Voorzetwand gipskarton, sanitair_MS75 / 50.25, 75 mm; IsExternal: yes; LoadBearing: no; ExtendToStructure: no

# IfcWall: Basic Wall_BB_10.01.62#02_Voorzetwand gipskarton_ sanitair_MS75 _ 50.25_ 75 mm13, Basic Wall:BB_10.01.62#02_Voorzetwand gipskarton, sanitair_MS75 / 50.25, 75 mm:15414162
In: 030
PredefinedType: PARTITIONING
Cpset_Wall - LevelOfAccuracy: in te vullen door Buildwise
IfcBuildingStorey - Base Offset: -10; Top Offset: 2740; Base Constraint: 030; Top Constraint: Up to level: 030
IfcClassificationReference - Keynote: 10.01.62#02; GVH_artnr 01: 10.01.62#02; GVH_artnr 02: geen waarde gevonden; GVH_artnr 03: geen waarde gevonden; GVH_artnr 04: geen waarde gevonden; GVH_artnr 05: geen waarde gevonden; GVH_artnr 06: geen waarde gevonden
IfcRoot - Name: BB_10.01.62#02_Voorzetwand gipskarton, sanitair_MS75 / 50.25, 75 mm
Qto_WallBaseQuantities - Length: 2046.46; NetVolume: 0.423629; Height: 2750; Width: 75; GrossVolume: 0.423629; GrossSideArea: 5.64839; NetSideArea: 5.64839
Pset_Condition - AssessmentCondition: Empty
Pset_EnvironmentalImpactIndicators - Reference: BB_10.01.62#02_Voorzetwand gipskarton, sanitair_MS75 / 50.25, 75 mm; sets with these values: 2
Pset_WallCommon - Reference: BB_10.01.62#02_Voorzetwand gipskarton, sanitair_MS75 / 50.25, 75 mm; IsExternal: yes; LoadBearing: no; ExtendToStructure: no

# IfcWall: Basic Wall_BB_10.01.62#02_Voorzetwand gipskarton_ sanitair_MS75 _ 50.25_ 75 mm3, Basic Wall:BB_10.01.62#02_Voorzetwand gipskarton, sanitair_MS75 / 50.25, 75 mm:26740154
In: K10
PredefinedType: PARTITIONING
Cpset_Wall - LevelOfAccuracy: in te vullen door Buildwise
IfcBuildingStorey - Base Offset: 75; Top Offset: 2780; Base Constraint: K10; Top Constraint: Up to level: K10
IfcClassificationReference - Keynote: 10.01.62#02; GVH_artnr 01: 10.01.62#02; GVH_artnr 02: geen waarde gevonden; GVH_artnr 03: geen waarde gevonden; GVH_artnr 04: geen waarde gevonden; GVH_artnr 05: geen waarde gevonden; GVH_artnr 06: geen waarde gevonden; TDS_link: .\05 As Builtdossier\2. Bouwkunde\2.1 Architectuur\2.1.10 wanden\TF A 10.01.62#02 A - Schachtenwanden met gipsplaten op metalen skelet - vochtwerend.pdf
IfcRoot - Name: BB_10.01.62#02_Voorzetwand gipskarton, sanitair_MS75 / 50.25, 75 mm
Qto_WallBaseQuantities - Length: 900; NetVolume: 0.178912; Height: 2705; Width: 75; GrossVolume: 0.178912; GrossSideArea: 2.3855; NetSideArea: 2.3855
Pset_Condition - AssessmentCondition: Empty
Pset_EnvironmentalImpactIndicators - Reference: BB_10.01.62#02_Voorzetwand gipskarton, sanitair_MS75 / 50.25, 75 mm; sets with these values: 2
Pset_WallCommon - Reference: BB_10.01.62#02_Voorzetwand gipskarton, sanitair_MS75 / 50.25, 75 mm; IsExternal: yes; LoadBearing: no; ExtendToStructure: no

# IfcWall: Basic Wall_BB_10.01.62#02_Voorzetwand gipskarton_ sanitair_MS75 _ 50.25_ 75 mm5, Basic Wall:BB_10.01.62#02_Voorzetwand gipskarton, sanitair_MS75 / 50.25, 75 mm:26740474
In: K10
PredefinedType: PARTITIONING
Cpset_Wall - LevelOfAccuracy: in te vullen door Buildwise
IfcBuildingStorey - Base Offset: 75; Top Offset: 2780; Base Constraint: K10; Top Constraint: Up to level: K10
IfcClassificationReference - Keynote: 10.01.62#02; GVH_artnr 01: 10.01.62#02; GVH_artnr 02: geen waarde gevonden; GVH_artnr 03: geen waarde gevonden; GVH_artnr 04: geen waarde gevonden; GVH_artnr 05: geen waarde gevonden; GVH_artnr 06: geen waarde gevonden; TDS_link: .\05 As Builtdossier\2. Bouwkunde\2.1 Architectuur\2.1.10 wanden\TF A 10.01.62#02 A - Schachtenwanden met gipsplaten op metalen skelet - vochtwerend.pdf
IfcRoot - Name: BB_10.01.62#02_Voorzetwand gipskarton, sanitair_MS75 / 50.25, 75 mm
Qto_WallBaseQuantities - Length: 900; NetVolume: 0.178913; Height: 2705; Width: 75; GrossVolume: 0.178912; GrossSideArea: 2.3855; NetSideArea: 2.3855
Pset_Condition - AssessmentCondition: Empty
Pset_EnvironmentalImpactIndicators - Reference: BB_10.01.62#02_Voorzetwand gipskarton, sanitair_MS75 / 50.25, 75 mm; sets with these values: 2
Pset_WallCommon - Reference: BB_10.01.62#02_Voorzetwand gipskarton, sanitair_MS75 / 50.25, 75 mm; IsExternal: yes; LoadBearing: no; ExtendToStructure: no

# IfcWall: Basic Wall_BB_10.01.62#02_Voorzetwand gipskarton_ sanitair_MS75 _ 50.25_ 75 mm7, Basic Wall:BB_10.01.62#02_Voorzetwand gipskarton, sanitair_MS75 / 50.25, 75 mm:26741295
In: K10
PredefinedType: PARTITIONING
Cpset_Wall - LevelOfAccuracy: in te vullen door Buildwise
IfcBuildingStorey - Base Offset: 75; Top Offset: 2780; Base Constraint: K10; Top Constraint: Up to level: K10
IfcClassificationReference - Keynote: 10.01.62#02; GVH_artnr 01: 10.01.62#02; GVH_artnr 02: geen waarde gevonden; GVH_artnr 03: geen waarde gevonden; GVH_artnr 04: geen waarde gevonden; GVH_artnr 05: geen waarde gevonden; GVH_artnr 06: geen waarde gevonden; TDS_link: .\05 As Builtdossier\2. Bouwkunde\2.1 Architectuur\2.1.10 wanden\TF A 10.01.62#02 A - Schachtenwanden met gipsplaten op metalen skelet - vochtwerend.pdf
IfcRoot - Name: BB_10.01.62#02_Voorzetwand gipskarton, sanitair_MS75 / 50.25, 75 mm
Qto_WallBaseQuantities - Length: 900; NetVolume: 0.173227; Height: 2705; Width: 75; GrossVolume: 0.173227; GrossSideArea: 2.3097; NetSideArea: 2.3097
Pset_Condition - AssessmentCondition: Empty
Pset_EnvironmentalImpactIndicators - Reference: BB_10.01.62#02_Voorzetwand gipskarton, sanitair_MS75 / 50.25, 75 mm; sets with these values: 2
Pset_WallCommon - Reference: BB_10.01.62#02_Voorzetwand gipskarton, sanitair_MS75 / 50.25, 75 mm; IsExternal: yes; LoadBearing: no; ExtendToStructure: no

# IfcWall: Basic Wall_BB_10.01.62#02_Voorzetwand gipskarton_ sanitair_MS75 _ 50.25_ 75 mm9, Basic Wall:BB_10.01.62#02_Voorzetwand gipskarton, sanitair_MS75 / 50.25, 75 mm:26538567
In: 000
PredefinedType: PARTITIONING
Cpset_Wall - LevelOfAccuracy: in te vullen door Buildwise
IfcBuildingStorey - Base Offset: -10; Top Offset: 2740; Base Constraint: 000; Top Constraint: Up to level: 000
IfcClassificationReference - Keynote: 10.01.62#02; GVH_artnr 01: 10.01.62#02; GVH_artnr 02: geen waarde gevonden; GVH_artnr 03: geen waarde gevonden; GVH_artnr 04: geen waarde gevonden; GVH_artnr 05: geen waarde gevonden; GVH_artnr 06: geen waarde gevonden; TDS_link: .\05 As Builtdossier\2. Bouwkunde\2.1 Architectuur\2.1.10 wanden\TF A 10.01.62#02 A - Schachtenwanden met gipsplaten op metalen skelet - vochtwerend.pdf
IfcRoot - Name: BB_10.01.62#02_Voorzetwand gipskarton, sanitair_MS75 / 50.25, 75 mm
Qto_WallBaseQuantities - Length: 1620; NetVolume: 0.334125; Height: 2750; Width: 75; GrossVolume: 0.334125; GrossSideArea: 4.455; NetSideArea: 4.455
Pset_Condition - AssessmentCondition: Empty
Pset_EnvironmentalImpactIndicators - Reference: BB_10.01.62#02_Voorzetwand gipskarton, sanitair_MS75 / 50.25, 75 mm; sets with these values: 2
Pset_WallCommon - Reference: BB_10.01.62#02_Voorzetwand gipskarton, sanitair_MS75 / 50.25, 75 mm; IsExternal: yes; LoadBearing: no; ExtendToStructure: no

# IfcWall: Basic Wall_BB_10.01_Akoestische voorzetwand atrium_ 75 mm, Basic Wall:BB_10.01_Akoestische voorzetwand atrium, 75 mm:12880755
In: 010
PredefinedType: PARTITIONING
Cpset_Wall - LevelOfAccuracy: in te vullen door Buildwise
IfcBuildingStorey - Base Offset: 230; Top Offset: 230; Base Constraint: 010; Top Constraint: Up to level: 020
IfcClassificationReference - Keynote: 10.01.61#01; GVH_artnr 01: 10.01.61#01; GVH_artnr 02: geen waarde gevonden; GVH_artnr 03: geen waarde gevonden; GVH_artnr 04: geen waarde gevonden; GVH_artnr 05: geen waarde gevonden; GVH_artnr 06: geen waarde gevonden; TDS_link: .\05 As Builtdossier\2. Bouwkunde\2.1 Architectuur\2.1.10 wanden\TF A 10.01.61 A - Voorzetwanden met geperforeerde gipsplaten.pdf
IfcElement - BB_Element_Lokaalnummer01: K.10.A1
IfcRoot - Name: BB_10.01_Akoestische voorzetwand atrium, 75 mm
Qto_WallBaseQuantities - Length: 13335.8; NetVolume: 3.17912; Height: 3600; Width: 75; GrossVolume: 3.17912; GrossSideArea: 42.3883; NetSideArea: 42.3883
Pset_Condition - AssessmentCondition: Empty
Pset_EnvironmentalImpactIndicators - Reference: BB_10.01_Akoestische voorzetwand atrium, 75 mm; sets with these values: 2
Pset_WallCommon - Reference: BB_10.01_Akoestische voorzetwand atrium, 75 mm; FireRating: EI60; IsExternal: yes; LoadBearing: no; ExtendToStructure: no

# IfcWall: Basic Wall_BB_10.01_Akoestische voorzetwand atrium_ 75 mm1, Basic Wall:BB_10.01_Akoestische voorzetwand atrium, 75 mm:12913075
In: 010
PredefinedType: PARTITIONING
Cpset_Wall - LevelOfAccuracy: in te vullen door Buildwise
IfcBuildingStorey - Base Offset: 230; Top Offset: 230; Base Constraint: 010; Top Constraint: Up to level: 020
IfcClassificationReference - Keynote: 10.01.61#01; GVH_artnr 01: 10.01.61#01; GVH_artnr 02: geen waarde gevonden; GVH_artnr 03: geen waarde gevonden; GVH_artnr 04: geen waarde gevonden; GVH_artnr 05: geen waarde gevonden; GVH_artnr 06: geen waarde gevonden; TDS_link: .\05 As Builtdossier\2. Bouwkunde\2.1 Architectuur\2.1.10 wanden\TF A 10.01.61 A - Voorzetwanden met geperforeerde gipsplaten.pdf
IfcElement - BB_Element_Lokaalnummer01: K.10.A1
IfcRoot - Name: BB_10.01_Akoestische voorzetwand atrium, 75 mm
Qto_WallBaseQuantities - Length: 18900; NetVolume: 4.42417; Height: 3600; Width: 75; GrossVolume: 4.42417; GrossSideArea: 58.989; NetSideArea: 58.989
Pset_Condition - AssessmentCondition: Empty
Pset_EnvironmentalImpactIndicators - Reference: BB_10.01_Akoestische voorzetwand atrium, 75 mm; sets with these values: 2
Pset_WallCommon - Reference: BB_10.01_Akoestische voorzetwand atrium, 75 mm; FireRating: EI60; IsExternal: yes; LoadBearing: no; ExtendToStructure: no

# IfcWall: Basic Wall_BB_10.01_Akoestische voorzetwand atrium_ 75 mm11, Basic Wall:BB_10.01_Akoestische voorzetwand atrium, 75 mm:12901724
In: 040
PredefinedType: PARTITIONING
Cpset_Wall - LevelOfAccuracy: in te vullen door Buildwise
IfcBuildingStorey - Base Offset: 230; Top Offset: 280; Base Constraint: 040; Top Constraint: Up to level: 050
IfcClassificationReference - Keynote: 10.01.61#01; GVH_artnr 01: 10.01.61#01; GVH_artnr 02: geen waarde gevonden; GVH_artnr 03: geen waarde gevonden; GVH_artnr 04: geen waarde gevonden; GVH_artnr 05: geen waarde gevonden; GVH_artnr 06: geen waarde gevonden; TDS_link: .\05 As Builtdossier\2. Bouwkunde\2.1 Architectuur\2.1.10 wanden\TF A 10.01.61 A - Voorzetwanden met geperforeerde gipsplaten.pdf
IfcElement - BB_Element_Lokaalnummer01: K.40.A1
IfcRoot - Name: BB_10.01_Akoestische voorzetwand atrium, 75 mm
Qto_WallBaseQuantities - Length: 13500; NetVolume: 2.60173; Height: 2700; Width: 75; GrossVolume: 2.73375; GrossSideArea: 36.45; NetSideArea: 34.6897
Pset_Condition - AssessmentCondition: Empty
Pset_EnvironmentalImpactIndicators - Reference: BB_10.01_Akoestische voorzetwand atrium, 75 mm; sets with these values: 2
Pset_WallCommon - Reference: BB_10.01_Akoestische voorzetwand atrium, 75 mm; FireRating: EI60; IsExternal: yes; LoadBearing: no; ExtendToStructure: no

# IfcWall: Basic Wall_BB_10.01_Akoestische voorzetwand atrium_ 75 mm13, Basic Wall:BB_10.01_Akoestische voorzetwand atrium, 75 mm:12913083
In: 040
PredefinedType: PARTITIONING
Cpset_Wall - LevelOfAccuracy: in te vullen door Buildwise
IfcBuildingStorey - Base Offset: 230; Top Offset: 280; Base Constraint: 040; Top Constraint: Up to level: 050
IfcClassificationReference - Keynote: 10.01.61#01; GVH_artnr 01: 10.01.61#01; GVH_artnr 02: geen waarde gevonden; GVH_artnr 03: geen waarde gevonden; GVH_artnr 04: geen waarde gevonden; GVH_artnr 05: geen waarde gevonden; GVH_artnr 06: geen waarde gevonden; TDS_link: .\05 As Builtdossier\2. Bouwkunde\2.1 Architectuur\2.1.10 wanden\TF A 10.01.61 A - Voorzetwanden met geperforeerde gipsplaten.pdf
IfcElement - BB_Element_Lokaalnummer01: K.40.A1
IfcRoot - Name: BB_10.01_Akoestische voorzetwand atrium, 75 mm
Qto_WallBaseQuantities - Length: 18900; NetVolume: 3.82725; Height: 2700; Width: 75; GrossVolume: 3.82725; GrossSideArea: 51.03; NetSideArea: 51.03
Pset_Condition - AssessmentCondition: Empty
Pset_EnvironmentalImpactIndicators - Reference: BB_10.01_Akoestische voorzetwand atrium, 75 mm; sets with these values: 2
Pset_WallCommon - Reference: BB_10.01_Akoestische voorzetwand atrium, 75 mm; IsExternal: yes; LoadBearing: no; ExtendToStructure: no

# IfcWall: Basic Wall_BB_10.01_Akoestische voorzetwand atrium_ 75 mm3, Basic Wall:BB_10.01_Akoestische voorzetwand atrium, 75 mm:12913078
In: 020
PredefinedType: PARTITIONING
Cpset_Wall - LevelOfAccuracy: in te vullen door Buildwise
IfcBuildingStorey - Base Offset: 230; Top Offset: 230; Base Constraint: 020; Top Constraint: Up to level: 030
IfcClassificationReference - Keynote: 10.01.61#01; GVH_artnr 01: 10.01.61#01; GVH_artnr 02: geen waarde gevonden; GVH_artnr 03: geen waarde gevonden; GVH_artnr 04: geen waarde gevonden; GVH_artnr 05: geen waarde gevonden; GVH_artnr 06: geen waarde gevonden; TDS_link: .\05 As Builtdossier\2. Bouwkunde\2.1 Architectuur\2.1.10 wanden\TF A 10.01.61 A - Voorzetwanden met geperforeerde gipsplaten.pdf
IfcElement - BB_Element_Lokaalnummer01: K.20.A1
IfcRoot - Name: BB_10.01_Akoestische voorzetwand atrium, 75 mm
Qto_WallBaseQuantities - Length: 18900; NetVolume: 5.103; Height: 3600; Width: 75; GrossVolume: 5.103; GrossSideArea: 68.04; NetSideArea: 68.04
Pset_Condition - AssessmentCondition: Empty
Pset_EnvironmentalImpactIndicators - Reference: BB_10.01_Akoestische voorzetwand atrium, 75 mm; sets with these values: 2
Pset_WallCommon - Reference: BB_10.01_Akoestische voorzetwand atrium, 75 mm; FireRating: EI60; IsExternal: yes; LoadBearing: no; ExtendToStructure: no

# IfcWall: Basic Wall_BB_10.01_Akoestische voorzetwand atrium_ 75 mm5, Basic Wall:BB_10.01_Akoestische voorzetwand atrium, 75 mm:14007189
In: 020
PredefinedType: PARTITIONING
Cpset_Wall - LevelOfAccuracy: in te vullen door Buildwise
IfcBuildingStorey - Base Offset: 230; Top Offset: 230; Base Constraint: 020; Top Constraint: Up to level: 030
IfcClassificationReference - Keynote: 10.01.61#01; GVH_artnr 01: 10.01.61#01; GVH_artnr 02: geen waarde gevonden; GVH_artnr 03: geen waarde gevonden; GVH_artnr 04: geen waarde gevonden; GVH_artnr 05: geen waarde gevonden; GVH_artnr 06: geen waarde gevonden; TDS_link: .\05 As Builtdossier\2. Bouwkunde\2.1 Architectuur\2.1.10 wanden\TF A 10.01.61 A - Voorzetwanden met geperforeerde gipsplaten.pdf
IfcElement - BB_Element_Lokaalnummer01: K.20.A1
IfcRoot - Name: BB_10.01_Akoestische voorzetwand atrium, 75 mm
Qto_WallBaseQuantities - Length: 13388.8; NetVolume: 3.19056; Height: 3600; Width: 75; GrossVolume: 3.20069; GrossSideArea: 42.6759; NetSideArea: 42.6759
Pset_Condition - AssessmentCondition: Empty
Pset_EnvironmentalImpactIndicators - Reference: BB_10.01_Akoestische voorzetwand atrium, 75 mm; sets with these values: 2
Pset_WallCommon - Reference: BB_10.01_Akoestische voorzetwand atrium, 75 mm; FireRating: EI60; IsExternal: yes; LoadBearing: no; ExtendToStructure: no

# IfcWall: Basic Wall_BB_10.01_Akoestische voorzetwand atrium_ 75 mm7, Basic Wall:BB_10.01_Akoestische voorzetwand atrium, 75 mm:12913081
In: 030
PredefinedType: PARTITIONING
Cpset_Wall - LevelOfAccuracy: in te vullen door Buildwise
IfcBuildingStorey - Base Offset: 230; Top Offset: 230; Base Constraint: 030; Top Constraint: Up to level: 040
IfcClassificationReference - Keynote: 10.01.61#01; GVH_artnr 01: 10.01.61#01; GVH_artnr 02: geen waarde gevonden; GVH_artnr 03: geen waarde gevonden; GVH_artnr 04: geen waarde gevonden; GVH_artnr 05: geen waarde gevonden; GVH_artnr 06: geen waarde gevonden; TDS_link: .\05 As Builtdossier\2. Bouwkunde\2.1 Architectuur\2.1.10 wanden\TF A 10.01.61 A - Voorzetwanden met geperforeerde gipsplaten.pdf
IfcElement - BB_Element_Lokaalnummer01: K.30.A1
IfcRoot - Name: BB_10.01_Akoestische voorzetwand atrium, 75 mm
Qto_WallBaseQuantities - Length: 18900; NetVolume: 5.103; Height: 3600; Width: 75; GrossVolume: 5.103; GrossSideArea: 68.04; NetSideArea: 68.04
Pset_Condition - AssessmentCondition: Empty
Pset_EnvironmentalImpactIndicators - Reference: BB_10.01_Akoestische voorzetwand atrium, 75 mm; sets with these values: 2
Pset_WallCommon - Reference: BB_10.01_Akoestische voorzetwand atrium, 75 mm; FireRating: EI60; IsExternal: yes; LoadBearing: no; ExtendToStructure: no

# IfcWall: Basic Wall_BB_10.01_Akoestische voorzetwand atrium_ 75 mm9, Basic Wall:BB_10.01_Akoestische voorzetwand atrium, 75 mm:14007218
In: 030
PredefinedType: PARTITIONING
Cpset_Wall - LevelOfAccuracy: in te vullen door Buildwise
IfcBuildingStorey - Base Offset: 230; Top Offset: 230; Base Constraint: 030; Top Constraint: Up to level: 040
IfcClassificationReference - Keynote: 10.01.61#01; GVH_artnr 01: 10.01.61#01; GVH_artnr 02: geen waarde gevonden; GVH_artnr 03: geen waarde gevonden; GVH_artnr 04: geen waarde gevonden; GVH_artnr 05: geen waarde gevonden; GVH_artnr 06: geen waarde gevonden; TDS_link: .\05 As Builtdossier\2. Bouwkunde\2.1 Architectuur\2.1.10 wanden\TF A 10.01.61 A - Voorzetwanden met geperforeerde gipsplaten.pdf
IfcElement - BB_Element_Lokaalnummer01: K.30.A1
IfcRoot - Name: BB_10.01_Akoestische voorzetwand atrium, 75 mm
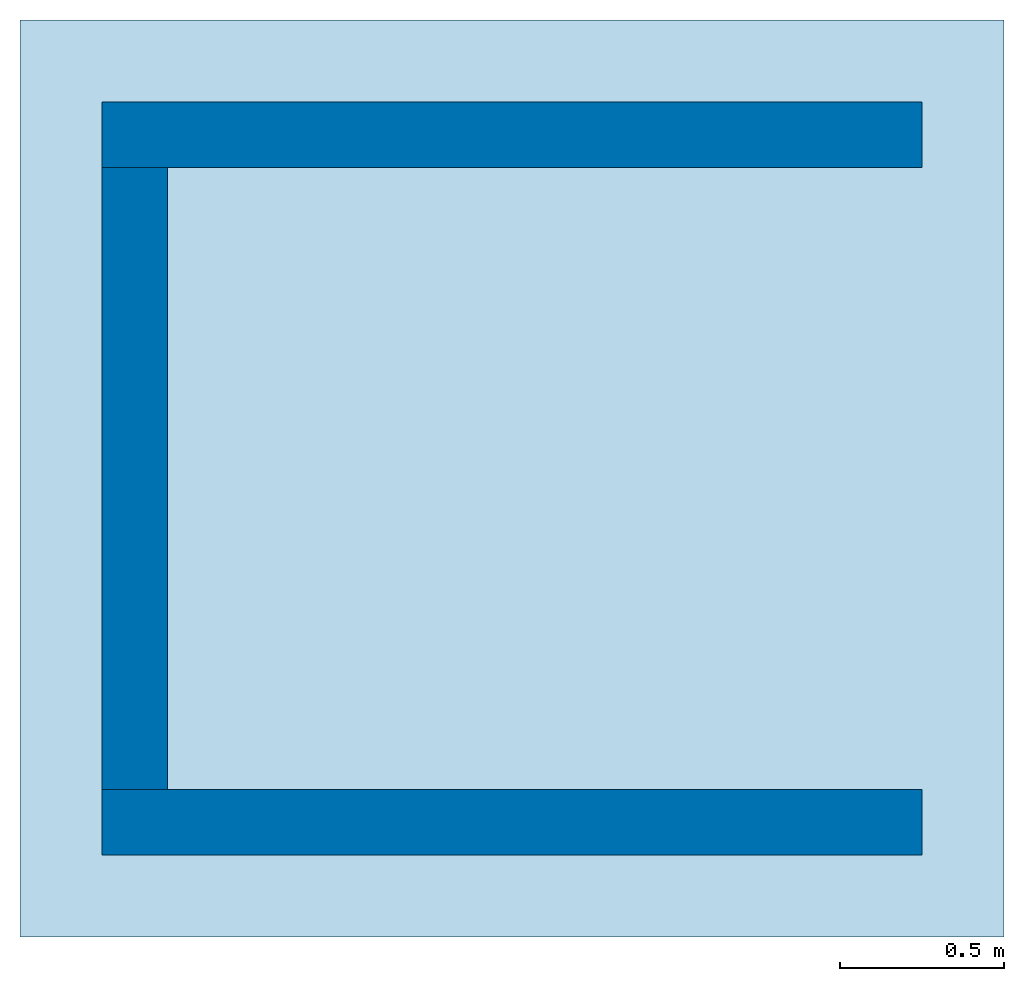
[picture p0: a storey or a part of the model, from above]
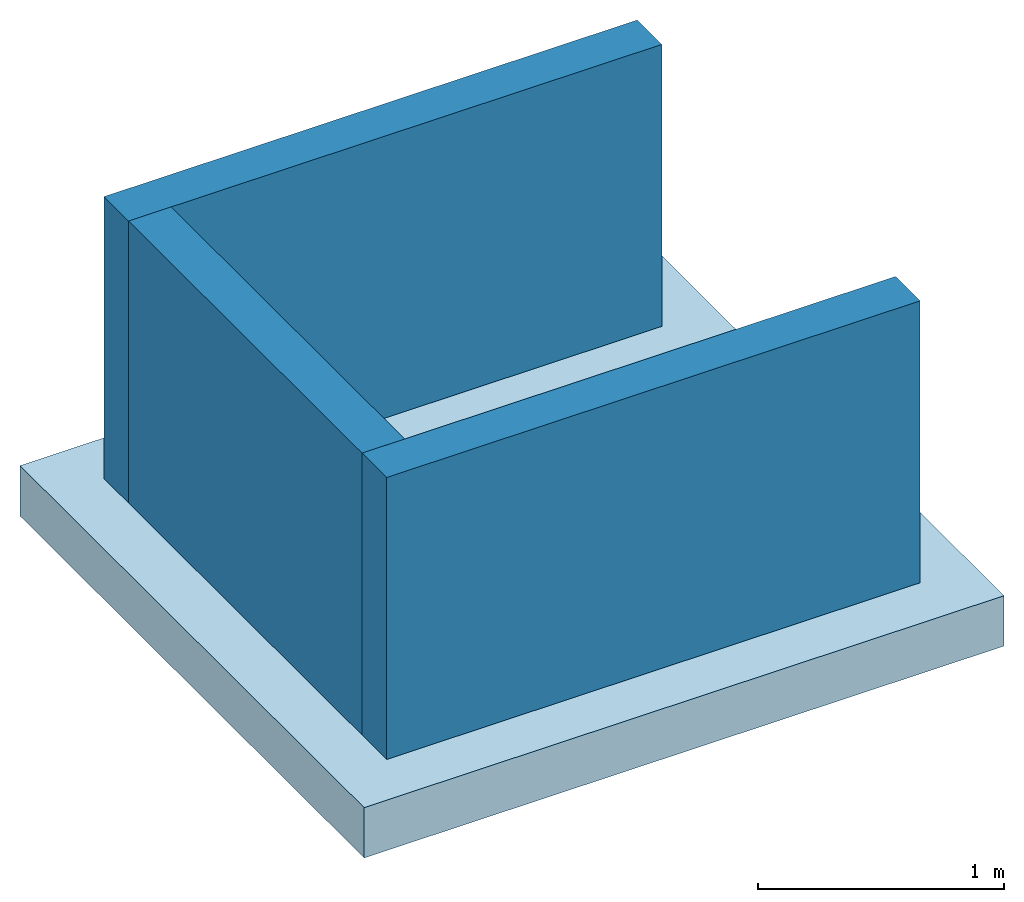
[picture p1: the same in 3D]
Properties of the parts of a building model (IFC4X3_ADD2), part 28 of 28

# IfcWall: Basic Wall_BB_10.01_Akoestische voorzetwand atrium_ 75 mm9, Basic Wall:BB_10.01_Akoestische voorzetwand atrium, 75 mm:14007218
Qto_WallBaseQuantities - Length: 13439.2; NetVolume: 3.20703; Height: 3600; Width: 75; GrossVolume: 3.20703; GrossSideArea: 42.7604; NetSideArea: 42.7604
Pset_Condition - AssessmentCondition: Empty
Pset_EnvironmentalImpactIndicators - Reference: BB_10.01_Akoestische voorzetwand atrium, 75 mm; sets with these values: 2
Pset_WallCommon - Reference: BB_10.01_Akoestische voorzetwand atrium, 75 mm; FireRating: EI60; IsExternal: yes; LoadBearing: no; ExtendToStructure: no

# IfcWall: Basic Wall_BB_XX_Wand uit beton_ 200 mm, Basic Wall:BB_XX_Wand uit beton, 200 mm:825964
In: K10
PredefinedType: SOLIDWALL; Material: BB_Beton_Bestaand
Cpset_Wall - LevelOfAccuracy: in te vullen door Buildwise
IfcBuildingStorey - Base Offset: 0; Top Offset: 0; Base Constraint: K10
IfcClassificationReference - GVH_artnr 01: geen waarde gevonden; GVH_artnr 02: geen waarde gevonden; GVH_artnr 03: geen waarde gevonden; GVH_artnr 04: geen waarde gevonden; GVH_artnr 05: geen waarde gevonden; GVH_artnr 06: geen waarde gevonden
IfcRoot - Name: BB_XX_Wand uit beton, 200 mm
Qto_WallBaseQuantities - Length: 1140; NetVolume: 0.072512; Height: 2060; Width: 200; GrossFootprintArea: 0.228; GrossVolume: 0.1648; GrossSideArea: 0.824; NetSideArea: 0.824
Pset_Condition - AssessmentCondition: Empty
Pset_EnvironmentalImpactIndicators - Reference: BB_XX_Wand uit beton, 200 mm; sets with these values: 2
Pset_WallCommon - Reference: BB_XX_Wand uit beton, 200 mm; FireRating: EI60; IsExternal: yes; LoadBearing: no; ExtendToStructure: no

# IfcWall: Basic Wall_BB_XX_Wand uit beton_ 200 mm1, Basic Wall:BB_XX_Wand uit beton, 200 mm:864896
In: 000
PredefinedType: SOLIDWALL; Material: BB_Beton_Bestaand
Cpset_Wall - LevelOfAccuracy: in te vullen door Buildwise
IfcBuildingStorey - Base Offset: -200; Top Offset: 0; Base Constraint: 000
IfcClassificationReference - GVH_artnr 01: geen waarde gevonden; GVH_artnr 02: geen waarde gevonden; GVH_artnr 03: geen waarde gevonden; GVH_artnr 04: geen waarde gevonden; GVH_artnr 05: geen waarde gevonden; GVH_artnr 06: geen waarde gevonden
IfcRoot - Name: BB_XX_Wand uit beton, 200 mm
Qto_WallBaseQuantities - Length: 320; NetVolume: 0.104568; Width: 200
Pset_Condition - AssessmentCondition: Empty
Pset_EnvironmentalImpactIndicators - Reference: BB_XX_Wand uit beton, 200 mm; sets with these values: 2
Pset_WallCommon - Reference: BB_XX_Wand uit beton, 200 mm; IsExternal: yes; LoadBearing: no; ExtendToStructure: no

# IfcWall: Basic Wall_BB_XX_Wand uit beton_ 200 mm3, Basic Wall:BB_XX_Wand uit beton, 200 mm:786530
In: 040
PredefinedType: SOLIDWALL; Material: BB_Beton_Bestaand
Cpset_Wall - LevelOfAccuracy: in te vullen door Buildwise
IfcBuildingStorey - Base Offset: -200; Top Offset: 0; Base Constraint: 040
IfcClassificationReference - GVH_artnr 01: geen waarde gevonden; GVH_artnr 02: geen waarde gevonden; GVH_artnr 03: geen waarde gevonden; GVH_artnr 04: geen waarde gevonden; GVH_artnr 05: geen waarde gevonden; GVH_artnr 06: geen waarde gevonden
IfcRoot - Name: BB_XX_Wand uit beton, 200 mm
Qto_WallBaseQuantities - Length: 11887.6; NetVolume: 1.40889; Width: 200
Pset_Condition - AssessmentCondition: Empty
Pset_EnvironmentalImpactIndicators - Reference: BB_XX_Wand uit beton, 200 mm; sets with these values: 2
Pset_WallCommon - Reference: BB_XX_Wand uit beton, 200 mm; IsExternal: yes; LoadBearing: no; ExtendToStructure: no

# IfcWall: Basic Wall_BB_XX_Wand uit beton_ 200 mm5, Basic Wall:BB_XX_Wand uit beton, 200 mm:34084848
In: 040
PredefinedType: SOLIDWALL; Material: BB_Beton_Bestaand
Cpset_Wall - LevelOfAccuracy: in te vullen door Buildwise
IfcBuildingStorey - Base Offset: -200; Top Offset: 2300; Base Constraint: 040; Top Constraint: Up to level: 040
IfcClassificationReference - TDS_link: .\05 As Builtdossier\2. Bouwkunde\2.2. Stabiliteit\2.2.0 technische fiche's\TF S 4.3 A-beton.pdf
IfcElement - Tag: W7; Mark: W7
IfcRoot - Name: BB_XX_Wand uit beton, 200 mm
Qto_WallBaseQuantities - Length: 2155.17; NetVolume: 0.96061; Width: 200
Pset_Condition - AssessmentCondition: Empty
Pset_EnvironmentalImpactIndicators - Reference: BB_XX_Wand uit beton, 200 mm; sets with these values: 2
Pset_WallCommon - Reference: BB_XX_Wand uit beton, 200 mm; FireRating: EI60; ThermalTransmittance: 8; IsExternal: yes; LoadBearing: yes; ExtendToStructure: no

# IfcWall: Basic Wall_GVH_DUMMY WAND HOST, Basic Wall:GVH_DUMMY WAND HOST:33991749
In: 030
Material: GVH - DUMMY WALL HOST
Cpset_Wall - LevelOfAccuracy: in te vullen door Buildwise
IfcBuildingStorey - Base Offset: 740; Top Offset: 800; Base Constraint: 030; Top Constraint: Up to level: 030
IfcClassificationReference - Keynote: 15.01.33
IfcRoot - Name: GVH_DUMMY WAND HOST
Qto_WallBaseQuantities - Length: 240; NetVolume: 0.0001008; Height: 60; Width: 10; GrossFootprintArea: 0.0024; GrossVolume: 0.0001008; GrossSideArea: 0.01008; NetSideArea: 0.01008
Pset_Condition - AssessmentCondition: Empty
Pset_EnvironmentalImpactIndicators - Reference: GVH_DUMMY WAND HOST; sets with these values: 2
Pset_WallCommon - Reference: GVH_DUMMY WAND HOST; IsExternal: yes; LoadBearing: no; ExtendToStructure: no
